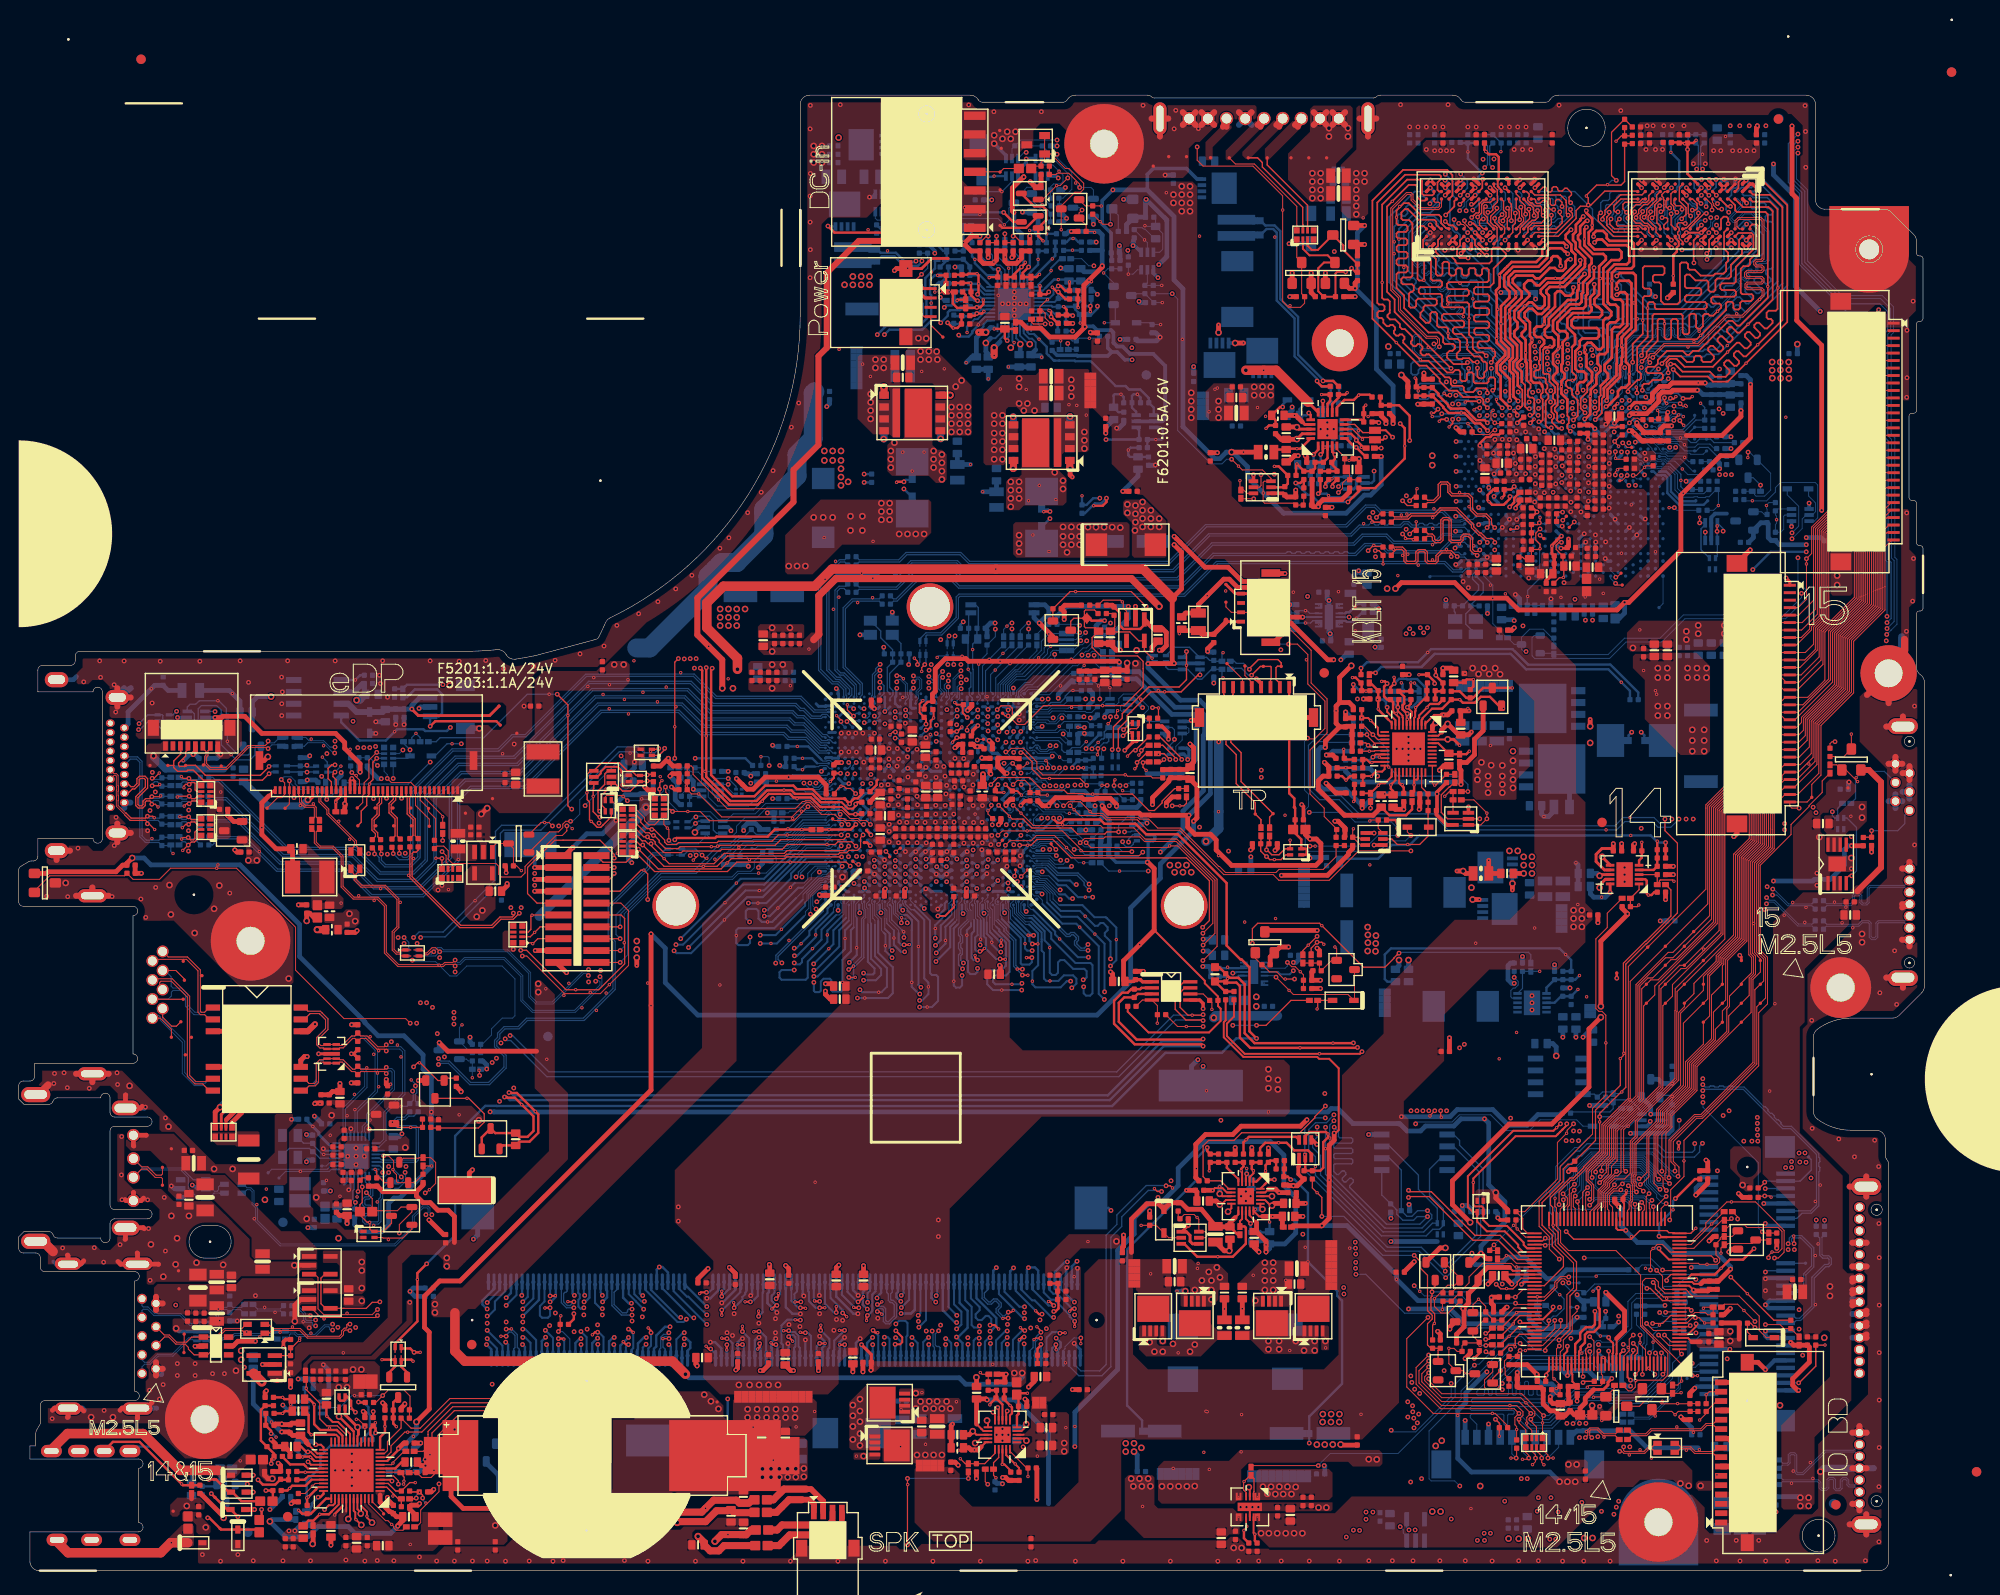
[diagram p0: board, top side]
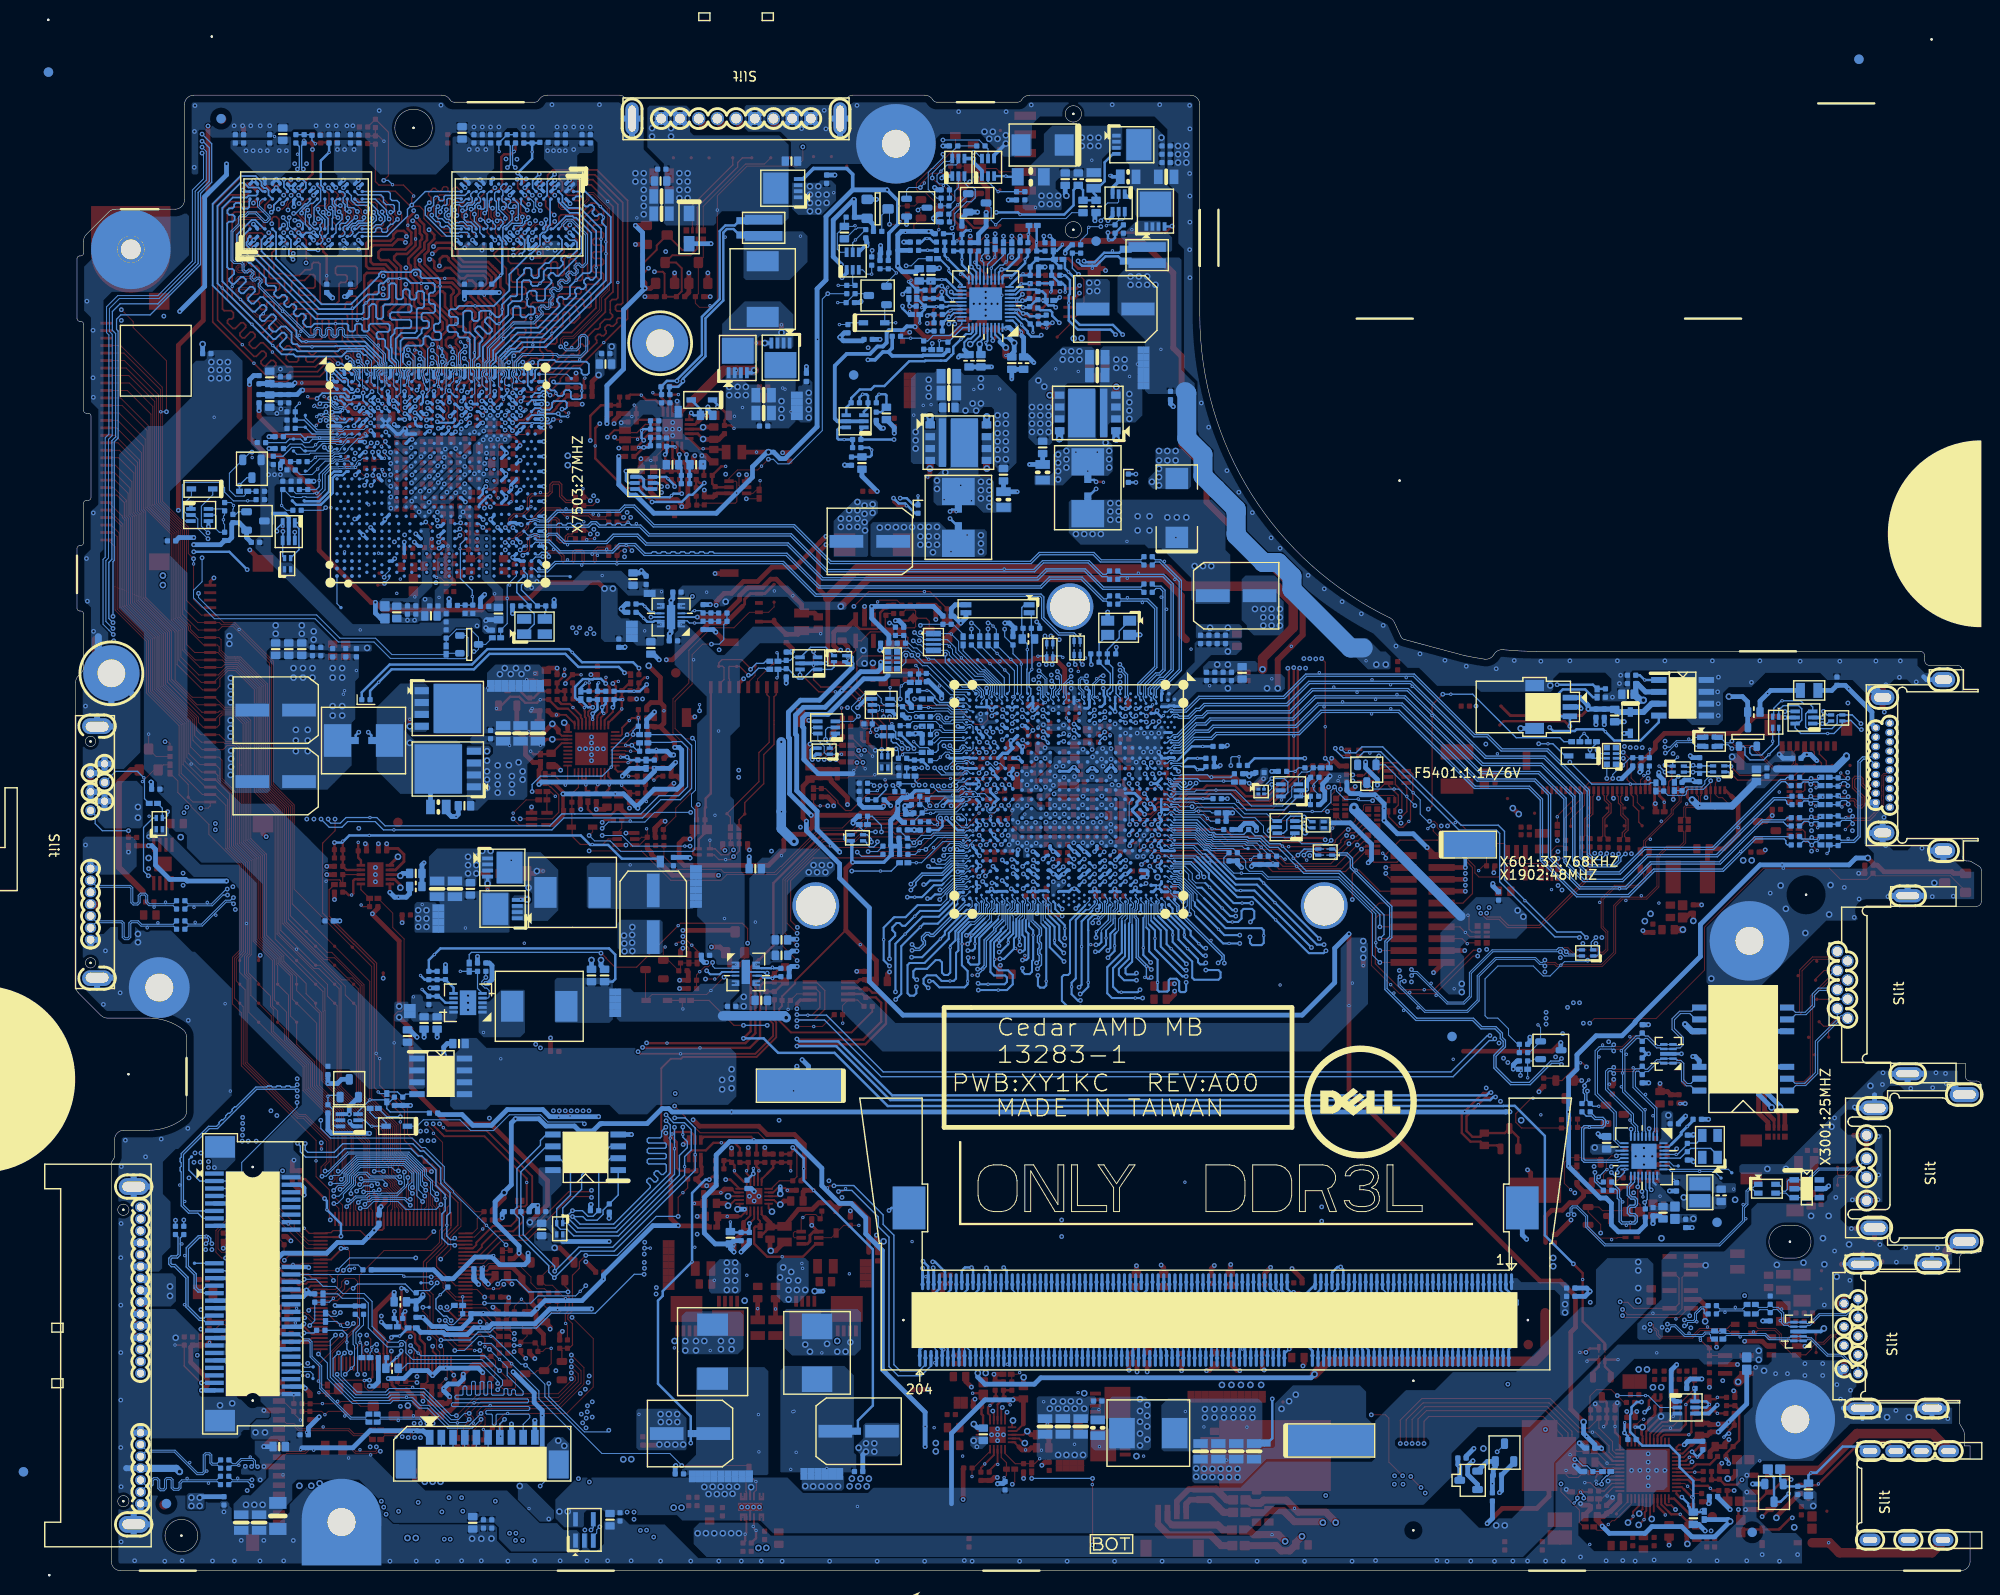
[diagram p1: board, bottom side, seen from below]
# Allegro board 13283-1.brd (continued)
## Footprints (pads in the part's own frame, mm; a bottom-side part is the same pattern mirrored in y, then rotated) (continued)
AFTE14P-75
  round 0.356 smd: 1(0,0)
ARES2H16
  rect 0.356x0.66 smd: 1(-0.325,-0.599) 2(0.325,-0.599) 3(0.325,0.599) 4(-0.325,0.599)
ARES2H18
  rect 0.356x0.66 smd: 1(-0.325,-0.599) 2(0.325,-0.599) 3(0.325,0.599) 4(-0.325,0.599)
ARES8-CN24-MUH20
  rect 0.61x0.66 smd: 1(-0.9,-0.486) 4(0.9,-0.486) 5(0.9,0.486) 8(-0.9,0.486)
  rect 0.305x0.66 smd: 2(-0.25,-0.486) 3(0.25,-0.486) 6(0.25,0.486) 7(-0.25,0.486)
ARES8-CN24H20
  rect 0.61x0.66 smd: 1(-0.9,-0.486) 4(0.9,-0.486) 5(0.9,0.486) 8(-0.9,0.486)
  rect 0.305x0.66 smd: 2(-0.25,-0.486) 3(0.25,-0.486) 6(0.25,0.486) 7(-0.25,0.486)
ARES8-CN24H22
  rect 0.61x0.66 smd: 1(-0.9,-0.486) 4(0.9,-0.486) 5(0.9,0.486) 8(-0.9,0.486)
  rect 0.305x0.66 smd: 2(-0.25,-0.486) 3(0.25,-0.486) 6(0.25,0.486) 7(-0.25,0.486)
BGA96D0914H48
  round 0.356 smd: A1(-3.2,6) A2(-2.4,6) A3(-1.6,6) A7(1.6,6) A8(2.4,6) A9(3.2,6) B1(-3.2,5.2) B2(-2.4,5.2) B3(-1.6,5.2) B7(1.6,5.2) B8(2.4,5.2) B9(3.2,5.2) C1(-3.2,4.4) C2(-2.4,4.4) C3(-1.6,4.4) C7(1.6,4.4) C8(2.4,4.4) C9(3.2,4.4) D1(-3.2,3.6) D2(-2.4,3.6) D3(-1.6,3.6) D7(1.6,3.6) D8(2.4,3.6) D9(3.2,3.6) E1(-3.2,2.8) E2(-2.4,2.8) E3(-1.6,2.8) E7(1.6,2.8) E8(2.4,2.8) E9(3.2,2.8) F1(-3.2,2) F2(-2.4,2) F3(-1.6,2) F7(1.6,2) F8(2.4,2) F9(3.2,2) G1(-3.2,1.2) G2(-2.4,1.2) G3(-1.6,1.2) G7(1.6,1.2) G8(2.4,1.2) G9(3.2,1.2) H1(-3.2,0.4) H2(-2.4,0.4) H3(-1.6,0.4) H7(1.6,0.4) H8(2.4,0.4) H9(3.2,0.4) J1(-3.2,-0.4) J2(-2.4,-0.4) J3(-1.6,-0.4) J7(1.6,-0.4) J8(2.4,-0.4) J9(3.2,-0.4) K1(-3.2,-1.2) K2(-2.4,-1.2) K3(-1.6,-1.2) K7(1.6,-1.2) K8(2.4,-1.2) K9(3.2,-1.2) L1(-3.2,-2) L2(-2.4,-2) L3(-1.6,-2) L7(1.6,-2) L8(2.4,-2) L9(3.2,-2) M1(-3.2,-2.8) M2(-2.4,-2.8) M3(-1.6,-2.8) M7(1.6,-2.8) M8(2.4,-2.8) M9(3.2,-2.8) N1(-3.2,-3.6) N2(-2.4,-3.6) N3(-1.6,-3.6) N7(1.6,-3.6) N8(2.4,-3.6) N9(3.2,-3.6) P1(-3.2,-4.4) P2(-2.4,-4.4) P3(-1.6,-4.4) P7(1.6,-4.4) P8(2.4,-4.4) P9(3.2,-4.4) R1(-3.2,-5.2) R2(-2.4,-5.2) R3(-1.6,-5.2) R7(1.6,-5.2) R8(2.4,-5.2) R9(3.2,-5.2) T1(-3.2,-6) T2(-2.4,-6) T3(-1.6,-6) T7(1.6,-6) T8(2.4,-6) T9(3.2,-6)
BGA631M23H82
  round 0.406 smd: A3(-10,10.8) A5(-9.2,10.8) A28(9.2,10.8) A30(10,10.8) A32(10.8,10.8) AH1(-10.8,-9.2) AH3(-10,-9.2) AH5(-9.2,-9.2) AH28(9.2,-9.2) AH30(10,-9.2) AH32(10.8,-9.2) AK1(-10.8,-10) AK3(-10,-10) AK5(-9.2,-10) AK28(9.2,-10) AK30(10,-10) AK32(10.8,-10) AM1(-10.8,-10.8) AM3(-10,-10.8) AM5(-9.2,-10.8) AM28(9.2,-10.8) AM30(10,-10.8) AM32(10.8,-10.8) C1(-10.8,10) C3(-10,10) C5(-9.2,10) C28(9.2,10) C30(10,10) C32(10.8,10) E1(-10.8,9.2) E3(-10,9.2) E5(-9.2,9.2) E28(9.2,9.2) E30(10,9.2) E32(10.8,9.2)
  round 0.356 smd: A7(-7.6,10.8) A9(-6,10.8) A11(-4.4,10.8) A13(-2.8,10.8) A15(-1.2,10.8) A17(0.4,10.8) A19(2,10.8) A21(3.6,10.8) A23(5.2,10.8) A25(6.8,10.8) A27(8.4,10.8) AA1(-10.8,-3.6) AA3(-10,-3.6) AA5(-9.2,-3.6) AA6(-8.4,-3.6) AA11(-4.4,-3.4) AA12(-3.4,-3.4) AA13(-2.4,-3.4) AA15(-1.4,-3.4) AA16(-0.4,-3.4) AA17(0.4,-3.4) AA18(1.4,-3.4) AA20(2.4,-3.4) AA21(3.4,-3.4) AA22(4.4,-3.4) AA27(8.4,-3.6) AA29(9.6,-3.6) AA31(10.4,-3.6) AB2(-10.4,-4.4) AB4(-9.6,-4.4) AB6(-8.4,-4.4) AB7(-7.6,-4.2) AB8(-6.8,-4.2) AB9(-6,-4.2) AB10(-5.2,-4.2) AB11(-4.4,-4.4) AB12(-3.4,-4.4) AB13(-2.4,-4.4) AB15(-1.4,-4.4) AB16(-0.4,-4.4) AB17(0.4,-4.4) AB18(1.4,-4.4) AB20(2.4,-4.4) AB21(3.4,-4.4) AB22(4.4,-4.4) AB23(5.2,-4.2) AB24(6,-4.2) AB25(6.8,-4.2) AB26(7.6,-4.2) AB27(8.4,-4.4) AB28(9.2,-4.4) AB30(10,-4.4) AB32(10.8,-4.4) AC1(-10.8,-5.2) AC3(-10,-5.2) AC5(-9.2,-5.2) AC6(-8.4,-5.2) AC7(-7.6,-5.2) AC8(-6.8,-5.2) AC9(-6,-5.2) AC10(-5.2,-5.2) AC11(-4.2,-5.2) AC13(-3,-5.2) AC14(-1.8,-5.2) AC16(-0.6,-5.2) AC17(0.6,-5.2) AC19(1.8,-5.2) AC20(3,-5.2) AC22(4.2,-5.2) AC23(5.2,-5.2) AC24(6,-5.2) AC25(6.8,-5.2) AC26(7.6,-5.2) AC27(8.4,-5.2) AC29(9.6,-5.2) AC31(10.4,-5.2) AD2(-10.4,-6) AD4(-9.6,-6) AD6(-8.4,-6) AD7(-7.6,-6) AD8(-6.8,-6) AD9(-6,-6) AD10(-5.2,-6) AD11(-4.2,-6) AD13(-3,-6) AD14(-1.8,-6) AD16(-0.6,-6) AD17(0.6,-6) AD19(1.8,-6) AD20(3,-6) AD22(4.2,-6) AD23(5.2,-6) AD24(6,-6) AD25(6.8,-6) AD26(7.6,-6) AD27(8.4,-6) AD28(9.2,-6) AD30(10,-6) AD32(10.8,-6) AE1(-10.8,-6.8) AE3(-10,-6.8) AE5(-9.2,-6.8) AE6(-8.4,-6.8) AE7(-7.6,-6.8) AE8(-6.8,-6.8) AE9(-6,-6.8) AE10(-5.2,-6.8) AE11(-4.2,-6.8) AE13(-3,-6.8) AE14(-1.8,-6.8) AE16(-0.6,-6.8) AE17(0.6,-6.8) AE19(1.8,-6.8) AE20(3,-6.8) AE22(4.2,-6.8) AE23(5.2,-6.8) AE24(6,-6.8) AE25(6.8,-6.8) AE26(7.6,-6.8) AE27(8.4,-6.8) AE29(9.6,-6.8) AE31(10.4,-6.8) AF2(-10.4,-7.6) AF4(-9.6,-7.6) AF6(-8.4,-7.6) AF7(-7.6,-7.6) AF8(-6.8,-7.6) AF9(-6,-7.6) AF10(-5.2,-7.6) AF11(-4.2,-7.6) AF13(-3,-7.6) AF14(-1.8,-7.6) AF16(-0.6,-7.6) AF17(0.6,-7.6) AF19(1.8,-7.6) AF20(3,-7.6) AF22(4.2,-7.6) AF23(5.2,-7.6) AF24(6,-7.6) AF25(6.8,-7.6) AF26(7.6,-7.6) AF27(8.4,-7.6) AF28(9.2,-7.6) AF30(10,-7.6) AF32(10.8,-7.6) AG1(-10.8,-8.4) AG3(-10,-8.4) AG5(-9.2,-8.4) AG6(-8.4,-8.4) AG7(-7.6,-8.4) AG8(-6.8,-8.4) AG9(-6,-8.4) AG10(-5.2,-8.4) AG11(-4.4,-8.4) AG12(-3.6,-8.4) AG13(-2.8,-8.4) AG14(-2,-8.4) AG15(-1.2,-8.4) AG16(-0.4,-8.4) AG17(0.4,-8.4) AG18(1.2,-8.4) AG19(2,-8.4) AG20(2.8,-8.4) AG21(3.6,-8.4) AG22(4.4,-8.4) AG23(5.2,-8.4) AG24(6,-8.4) AG25(6.8,-8.4) AG26(7.6,-8.4) AG27(8.4,-8.4) AG29(9.6,-8.4) AG31(10.4,-8.4) AH6(-8.4,-9.2) AH8(-6.8,-9.2) AH10(-5.2,-9.2) AH12(-3.6,-9.2) AH14(-2,-9.2) AH16(-0.4,-9.2) AH18(1.2,-9.2) AH20(2.8,-9.2) AH22(4.4,-9.2) AH24(6,-9.2) AH26(7.6,-9.2) AJ7(-7.6,-9.6) AJ9(-6,-9.6) AJ11(-4.4,-9.6) AJ13(-2.8,-9.6) AJ15(-1.2,-9.6) AJ17(0.4,-9.6) AJ19(2,-9.6) AJ21(3.6,-9.6) AJ23(5.2,-9.6) AJ25(6.8,-9.6) AJ27(8.4,-9.6) AK6(-8.4,-10) AK8(-6.8,-10) AK10(-5.2,-10) AK12(-3.6,-10) AK14(-2,-10) AK16(-0.4,-10) AK18(1.2,-10) AK20(2.8,-10) AK22(4.4,-10) AK24(6,-10) AK26(7.6,-10) AL7(-7.6,-10.4) AL9(-6,-10.4) AL11(-4.4,-10.4) AL13(-2.8,-10.4) AL15(-1.2,-10.4) AL17(0.4,-10.4) AL19(2,-10.4) AL21(3.6,-10.4) AL23(5.2,-10.4) AL25(6.8,-10.4) AL27(8.4,-10.4) AM6(-8.4,-10.8) AM8(-6.8,-10.8) AM10(-5.2,-10.8) AM12(-3.6,-10.8) AM14(-2,-10.8) AM16(-0.4,-10.8) AM18(1.2,-10.8) AM20(2.8,-10.8) AM22(4.4,-10.8) AM24(6,-10.8) AM26(7.6,-10.8) B6(-8.4,10.4) B8(-6.8,10.4) B10(-5.2,10.4) B12(-3.6,10.4) B14(-2,10.4) B16(-0.4,10.4) B18(1.2,10.4) B20(2.8,10.4) B22(4.4,10.4) B24(6,10.4) B26(7.6,10.4) C7(-7.6,10) C9(-6,10) C11(-4.4,10) C13(-2.8,10) C15(-1.2,10) C17(0.4,10) C19(2,10) C21(3.6,10) C23(5.2,10) C25(6.8,10) C27(8.4,10) D6(-8.4,9.6) D8(-6.8,9.6) D10(-5.2,9.6) D12(-3.6,9.6) D14(-2,9.6) D16(-0.4,9.6) D18(1.2,9.6) D20(2.8,9.6) D22(4.4,9.6) D24(6,9.6) D26(7.6,9.6) E7(-7.6,9.2) E9(-6,9.2) E11(-4.4,9.2) E13(-2.8,9.2) E15(-1.2,9.2) E17(0.4,9.2) E19(2,9.2) E21(3.6,9.2) E23(5.2,9.2) E25(6.8,9.2) E27(8.4,9.2) F2(-10.4,8.4) F4(-9.6,8.4) F6(-8.4,8.4) F7(-7.6,8.4) F8(-6.8,8.4) F9(-6,8.4) F10(-5.2,8.4) F11(-4.4,8.4) F12(-3.6,8.4) F13(-2.8,8.4) F14(-2,8.4) F15(-1.2,8.4) F16(-0.4,8.4) F17(0.4,8.4) F18(1.2,8.4) F19(2,8.4) F20(2.8,8.4) F21(3.6,8.4) F22(4.4,8.4) F23(5.2,8.4) F24(6,8.4) F25(6.8,8.4) F26(7.6,8.4) F27(8.4,8.4) F28(9.2,8.4) F30(10,8.4) F32(10.8,8.4) G1(-10.8,7.6) G3(-10,7.6) G5(-9.2,7.6) G6(-8.4,7.6) G7(-7.6,7.6) G8(-6.8,7.6) G9(-6,7.6) G10(-5.2,7.6) G11(-4.2,7.6) G13(-3,7.6) G14(-1.8,7.6) G16(-0.6,7.6) G17(0.6,7.6) G19(1.8,7.6) G20(3,7.6) G22(4.2,7.6) G23(5.2,7.6) G24(6,7.6) G25(6.8,7.6) G26(7.6,7.6) G27(8.4,7.6) G29(9.6,7.6) G31(10.4,7.6) H2(-10.4,6.8) H4(-9.6,6.8) H6(-8.4,6.8) H7(-7.6,6.8) H8(-6.8,6.8) H9(-6,6.8) H10(-5.2,6.8) H11(-4.2,6.8) H13(-3,6.8) H14(-1.8,6.8) H16(-0.6,6.8) H17(0.6,6.8) H19(1.8,6.8) H20(3,6.8) H22(4.2,6.8) H23(5.2,6.8) H24(6,6.8) H25(6.8,6.8) H26(7.6,6.8) H27(8.4,6.8) H28(9.2,6.8) H30(10,6.8) H32(10.8,6.8) J1(-10.8,6) J3(-10,6) J5(-9.2,6) J6(-8.4,6) J7(-7.6,6) J8(-6.8,6) J9(-6,6) J10(-5.2,6) J11(-4.2,6) J13(-3,6) J14(-1.8,6) J16(-0.6,6) J17(0.6,6) J19(1.8,6) J20(3,6) J22(4.2,6) J23(5.2,6) J24(6,6) J25(6.8,6) J26(7.6,6) J27(8.4,6) J29(9.6,6) J31(10.4,6) K2(-10.4,5.2) K4(-9.6,5.2) K6(-8.4,5.2) K7(-7.6,5.2) K8(-6.8,5.2) K9(-6,5.2) K10(-5.2,5.2) K11(-4.2,5.2) K13(-3,5.2) K14(-1.8,5.2) K16(-0.6,5.2) K17(0.6,5.2) K19(1.8,5.2) K20(3,5.2) K22(4.2,5.2) K23(5.2,5.2) K24(6,5.2) K25(6.8,5.2) K26(7.6,5.2) K27(8.4,5.2) K28(9.2,5.2) K30(10,5.2) K32(10.8,5.2) L1(-10.8,4.4) L3(-10,4.4) L5(-9.2,4.4) L6(-8.4,4.4) L7(-7.6,4.2) L8(-6.8,4.2) L9(-6,4.2) L10(-5.2,4.2) L11(-4.4,4.4) L12(-3.4,4.4) L13(-2.4,4.4) L15(-1.4,4.4) L16(-0.4,4.4) L17(0.4,4.4) L18(1.4,4.4) L20(2.4,4.4) L21(3.4,4.4) L22(4.4,4.4) L23(5.2,4.2) L24(6,4.2) L25(6.8,4.2) L26(7.6,4.2) L27(8.4,4.4) L29(9.6,4.4) L31(10.4,4.4) M2(-10.4,3.6) M4(-9.6,3.6) M6(-8.4,3.6) M11(-4.4,3.4) M12(-3.4,3.4) M13(-2.4,3.4) M15(-1.4,3.4) M16(-0.4,3.4) M17(0.4,3.4) M18(1.4,3.4) M20(2.4,3.4) M21(3.4,3.4) M22(4.4,3.4) M27(8.4,3.6) M28(9.2,3.6) M30(10,3.6) M32(10.8,3.6) N1(-10.8,2.8) N3(-10,2.8) N5(-9.2,2.8) N6(-8.4,2.8) N7(-7.6,3) N8(-6.8,3) N9(-6,3) N10(-5.2,3) N11(-4.4,2.4) N12(-3.4,2.4) N13(-2.4,2.4) N15(-1.4,2.4) N16(-0.4,2.4) N17(0.4,2.4) N18(1.4,2.4) N20(2.4,2.4) N21(3.4,2.4) N22(4.4,2.4) N23(5.2,3) N24(6,3) N25(6.8,3) N26(7.6,3) N27(8.4,2.8) N29(9.6,2.8) N31(10.4,2.8) P2(-10.4,2) P4(-9.6,2) P6(-8.4,2) P7(-7.6,1.8) P8(-6.8,1.8) P9(-6,1.8) P10(-5.2,1.8) P23(5.2,1.8) P24(6,1.8) P25(6.8,1.8) P26(7.6,1.8) P27(8.4,2) P28(9.2,2) P30(10,2) P32(10.8,2) R1(-10.8,1.2) R3(-10,1.2) R5(-9.2,1.2) R6(-8.4,1.2) R11(-4.4,1.4) R12(-3.4,1.4) R13(-2.4,1.4) R15(-1.4,1.4) R16(-0.4,1.4) R17(0.4,1.4) R18(1.4,1.4) R20(2.4,1.4) R21(3.4,1.4) R22(4.4,1.4) R27(8.4,1.2) R29(9.6,1.2) R31(10.4,1.2) T2(-10.4,0.4) T4(-9.6,0.4) T6(-8.4,0.4) T7(-7.6,0.6) T8(-6.8,0.6) T9(-6,0.6) T10(-5.2,0.6) T11(-4.4,0.4) T12(-3.4,0.4) T13(-2.4,0.4) T15(-1.4,0.4) T16(-0.4,0.4) T17(0.4,0.4) T18(1.4,0.4) T20(2.4,0.4) T21(3.4,0.4) T22(4.4,0.4) T23(5.2,0.6) T24(6,0.6) T25(6.8,0.6) T26(7.6,0.6) T27(8.4,0.4) T28(9.2,0.4) T30(10,0.4) T32(10.8,0.4) U1(-10.8,-0.4) U3(-10,-0.4) U5(-9.2,-0.4) U6(-8.4,-0.4) U7(-7.6,-0.6) U8(-6.8,-0.6) U9(-6,-0.6) U10(-5.2,-0.6) U11(-4.4,-0.4) U12(-3.4,-0.4) U13(-2.4,-0.4) U15(-1.4,-0.4) U16(-0.4,-0.4) U17(0.4,-0.4) U18(1.4,-0.4) U20(2.4,-0.4) U21(3.4,-0.4) U22(4.4,-0.4) U23(5.2,-0.6) U24(6,-0.6) U25(6.8,-0.6) U26(7.6,-0.6) U27(8.4,-0.4) U29(9.6,-0.4) U31(10.4,-0.4) V2(-10.4,-1.2) V4(-9.6,-1.2) V6(-8.4,-1.2) V11(-4.4,-1.4) V12(-3.4,-1.4) V13(-2.4,-1.4) V15(-1.4,-1.4) V16(-0.4,-1.4) V17(0.4,-1.4) V18(1.4,-1.4) V20(2.4,-1.4) V21(3.4,-1.4) V22(4.4,-1.4) V27(8.4,-1.2) V28(9.2,-1.2) V30(10,-1.2) V32(10.8,-1.2) W1(-10.8,-2) W3(-10,-2) W5(-9.2,-2) W6(-8.4,-2) W7(-7.6,-1.8) W8(-6.8,-1.8) W9(-6,-1.8) W10(-5.2,-1.8) W23(5.2,-1.8) W24(6,-1.8) W25(6.8,-1.8) W26(7.6,-1.8) W27(8.4,-2) W29(9.6,-2) W31(10.4,-2) Y2(-10.4,-2.8) Y4(-9.6,-2.8) Y6(-8.4,-2.8) Y7(-7.6,-3) Y8(-6.8,-3) Y9(-6,-3) Y10(-5.2,-3) Y11(-4.4,-2.4) Y12(-3.4,-2.4) Y13(-2.4,-2.4) Y15(-1.4,-2.4) Y16(-0.4,-2.4) Y17(0.4,-2.4) Y18(1.4,-2.4) Y20(2.4,-2.4) Y21(3.4,-2.4) Y22(4.4,-2.4) Y23(5.2,-3) Y24(6,-3) Y25(6.8,-3) Y26(7.6,-3) Y27(8.4,-2.8) Y28(9.2,-2.8) Y30(10,-2.8) Y32(10.8,-2.8)
BGA769M24D5H78
  round 0.4 smd: A2(-10.7,11.3) A3(-9.95,11.3) A39(9.95,11.3) A40(10.7,11.3) AA4(-9.2,0) AA5(-8.4,0) AA7(-7.6,0) AA8(-6.8,0) AA10(-6,0) AA11(-5,0) AA13(-4,0) AA15(-3,0) AA17(-2,0) AA19(-1,0) AA21(0,0) AA23(1,0) AA25(2,0) AA27(3,0) AA29(4,0) AA31(5,0) AA32(6,0) AA34(6.8,0) AA35(7.6,0) AA37(8.4,0) AA38(9.2,0) AC4(-9.2,-1.1) AC5(-8.4,-1.1) AC7(-7.6,-1.1) AC8(-6.8,-1.1) AC10(-6,-1.1) AC11(-5,-1) AC13(-4,-1) AC15(-3,-1) AC17(-2,-1) AC19(-1,-1) AC21(0,-1) AC23(1,-1) AC25(2,-1) AC27(3,-1) AC29(4,-1) AC31(5,-1) AC32(6,-1.1) AC34(6.8,-1.1) AC35(7.6,-1.1) AC37(8.4,-1.1) AC38(9.2,-1.1) AE4(-9.2,-2.2) AE5(-8.4,-2.2) AE7(-7.6,-2.2) AE8(-6.8,-2.2) AE10(-6,-2.2) AE11(-5,-2) AE13(-4,-2) AE15(-3,-2) AE17(-2,-2) AE19(-1,-2) AE21(0,-2) AE23(1,-2) AE25(2,-2) AE27(3,-2) AE29(4,-2) AE31(5,-2) AE32(6,-2.2) AE34(6.8,-2.2) AE35(7.6,-2.2) AE37(8.4,-2.2) AE38(9.2,-2.2) AG4(-9.2,-3.3) AG5(-8.4,-3.3) AG7(-7.6,-3.3) AG8(-6.8,-3.3) AG10(-6,-3.3) AG11(-5,-3) AG13(-4,-3) AG15(-3,-3) AG17(-2,-3) AG19(-1,-3) AG21(0,-3) AG23(1,-3) AG25(2,-3) AG27(3,-3) AG29(4,-3) AG31(5,-3) AG32(6,-3.3) AG34(6.8,-3.3) AG35(7.6,-3.3) AG37(8.4,-3.3) AG38(9.2,-3.3) AJ4(-9.2,-4.4) AJ5(-8.4,-4.4) AJ7(-7.6,-4.4) AJ8(-6.8,-4.4) AJ10(-6,-4.4) AJ11(-5,-4) AJ13(-4,-4) AJ15(-3,-4) AJ17(-2,-4) AJ19(-1,-4) AJ21(0,-4) AJ23(1,-4) AJ25(2,-4) AJ27(3,-4) AJ29(4,-4) AJ31(5,-4) AJ32(6,-4.4) AJ34(6.8,-4.4) AJ35(7.6,-4.4) AJ37(8.4,-4.4) AJ38(9.2,-4.4) AL4(-9.2,-5.5) AL5(-8.4,-5.5) AL7(-7.6,-5.5) AL8(-6.8,-5.5) AL10(-6,-5.5) AL11(-5,-5) AL13(-4,-5) AL15(-3,-5) AL17(-2,-5) AL19(-1,-5) AL21(0,-5) AL23(1,-5) AL25(2,-5) AL27(3,-5) AL29(4,-5) AL31(5,-5) AL32(6,-5.5) AL34(6.8,-5.5) AL35(7.6,-5.5) AL37(8.4,-5.5) AL38(9.2,-5.5) AM11(-5.5,-6) AM13(-4.4,-6) AM15(-3.3,-6) AM17(-2.2,-6) AM19(-1.1,-6) AM21(0,-6) AM23(1.1,-6) AM25(2.2,-6) AM27(3.3,-6) AM29(4.4,-6) AM31(5.5,-6) AN4(-9.2,-6.6) AN5(-8.4,-6.6) AN7(-7.6,-6.6) AN8(-6.8,-6.6) AN34(6.8,-6.6) AN35(7.6,-6.6) AN37(8.4,-6.6) AN38(9.2,-6.6) AP11(-5.5,-6.8) AP13(-4.4,-6.8) AP15(-3.3,-6.8) AP17(-2.2,-6.8) AP19(-1.1,-6.8) AP21(0,-6.8) AP23(1.1,-6.8) AP25(2.2,-6.8) AP27(3.3,-6.8) AP29(4.4,-6.8) AP31(5.5,-6.8) AR4(-9.2,-7.7) AR5(-8.4,-7.7) AR7(-7.6,-7.7) AR11(-5.5,-7.6) AR13(-4.4,-7.6) AR15(-3.3,-7.6) AR17(-2.2,-7.6) AR19(-1.1,-7.6) AR21(0,-7.6) AR23(1.1,-7.6) AR25(2.2,-7.6) AR27(3.3,-7.6) AR29(4.4,-7.6) AR31(5.5,-7.6) AR35(7.6,-7.7) AR37(8.4,-7.7) AR38(9.2,-7.7) AU4(-9.2,-8.8) AU7(-7.7,-8.4) AU9(-6.6,-8.4) AU11(-5.5,-8.4) AU13(-4.4,-8.4) AU15(-3.3,-8.4) AU17(-2.2,-8.4) AU19(-1.1,-8.4) AU21(0,-8.4) AU23(1.1,-8.4) AU25(2.2,-8.4) AU27(3.3,-8.4) AU29(4.4,-8.4) AU31(5.5,-8.4) AU33(6.6,-8.4) AU35(7.7,-8.4) AU38(9.2,-8.8) AV7(-7.7,-9.2) AV9(-6.6,-9.2) AV11(-5.5,-9.2) AV13(-4.4,-9.2) AV15(-3.3,-9.2) AV17(-2.2,-9.2) AV19(-1.1,-9.2) AV21(0,-9.2) AV23(1.1,-9.2) AV25(2.2,-9.2) AV27(3.3,-9.2) AV29(4.4,-9.2) AV31(5.5,-9.2) AV33(6.6,-9.2) AV35(7.7,-9.2) AW1(-11.3,-9.95) AW41(11.3,-9.95) AY1(-11.3,-10.7) AY2(-10.6,-10.6) AY40(10.6,-10.6) AY41(11.3,-10.7) B1(-11.3,10.7) B2(-10.6,10.6) B40(10.6,10.6) B41(11.3,10.7) BA2(-10.7,-11.3) BA3(-9.95,-11.3) BA39(9.95,-11.3) BA40(10.7,-11.3) C1(-11.3,9.95) C41(11.3,9.95) D7(-7.7,9.2) D9(-6.6,9.2) D11(-5.5,9.2) D13(-4.4,9.2) D15(-3.3,9.2) D17(-2.2,9.2) D19(-1.1,9.2) D21(0,9.2) D23(1.1,9.2) D25(2.2,9.2) D27(3.3,9.2) D29(4.4,9.2) D31(5.5,9.2) D33(6.6,9.2) D35(7.7,9.2) E4(-9.2,8.8) E7(-7.7,8.4) E9(-6.6,8.4) E11(-5.5,8.4) E13(-4.4,8.4) E15(-3.3,8.4) E17(-2.2,8.4) E19(-1.1,8.4) E21(0,8.4) E23(1.1,8.4) E25(2.2,8.4) E27(3.3,8.4) E29(4.4,8.4) E31(5.5,8.4) E33(6.6,8.4) E35(7.7,8.4) E38(9.2,8.8) G4(-9.2,7.7) G5(-8.4,7.7) G7(-7.6,7.7) G11(-5.5,7.6) G13(-4.4,7.6) G15(-3.3,7.6) G17(-2.2,7.6) G19(-1.1,7.6) G21(0,7.6) G23(1.1,7.6) G25(2.2,7.6) G27(3.3,7.6) G29(4.4,7.6) G31(5.5,7.6) G35(7.6,7.7) G37(8.4,7.7) G38(9.2,7.7) H11(-5.5,6.8) H13(-4.4,6.8) H15(-3.3,6.8) H17(-2.2,6.8) H19(-1.1,6.8) H21(0,6.8) H23(1.1,6.8) H25(2.2,6.8) H27(3.3,6.8) H29(4.4,6.8) H31(5.5,6.8) J4(-9.2,6.6) J5(-8.4,6.6) J7(-7.6,6.6) J8(-6.8,6.6) J34(6.8,6.6) J35(7.6,6.6) J37(8.4,6.6) J38(9.2,6.6) K11(-5.5,6) K13(-4.4,6) K15(-3.3,6) K17(-2.2,6) K19(-1.1,6) K21(0,6) K23(1.1,6) K25(2.2,6) K27(3.3,6) K29(4.4,6) K31(5.5,6) L4(-9.2,5.5) L5(-8.4,5.5) L7(-7.6,5.5) L8(-6.8,5.5) L10(-6,5.5) L11(-5,5) L13(-4,5) L15(-3,5) L17(-2,5) L19(-1,5) L21(0,5) L23(1,5) L25(2,5) L27(3,5) L29(4,5) L31(5,5) L32(6,5.5) L34(6.8,5.5) L35(7.6,5.5) L37(8.4,5.5) L38(9.2,5.5) N4(-9.2,4.4) N5(-8.4,4.4) N7(-7.6,4.4) N8(-6.8,4.4) N10(-6,4.4) N11(-5,4) N13(-4,4) N15(-3,4) N17(-2,4) N19(-1,4) N21(0,4) N23(1,4) N25(2,4) N27(3,4) N29(4,4) N31(5,4) N32(6,4.4) N34(6.8,4.4) N35(7.6,4.4) N37(8.4,4.4) N38(9.2,4.4) R4(-9.2,3.3) R5(-8.4,3.3) R7(-7.6,3.3) R8(-6.8,3.3) R10(-6,3.3) R11(-5,3) R13(-4,3) R15(-3,3) R17(-2,3) R19(-1,3) R21(0,3) R23(1,3) R25(2,3) R27(3,3) R29(4,3) R31(5,3) R32(6,3.3) R34(6.8,3.3) R35(7.6,3.3) R37(8.4,3.3) R38(9.2,3.3) U4(-9.2,2.2) U5(-8.4,2.2) U7(-7.6,2.2) U8(-6.8,2.2) U10(-6,2.2) U11(-5,2) U13(-4,2) U15(-3,2) U17(-2,2) U19(-1,2) U21(0,2) U23(1,2) U25(2,2) U27(3,2) U29(4,2) U31(5,2) U32(6,2.2) U34(6.8,2.2) U35(7.6,2.2) U37(8.4,2.2) U38(9.2,2.2) W4(-9.2,1.1) W5(-8.4,1.1) W7(-7.6,1.1) W8(-6.8,1.1) W10(-6,1.1) W11(-5,1) W13(-4,1) W15(-3,1) W17(-2,1) W19(-1,1) W21(0,1) W23(1,1) W25(2,1) W27(3,1) W29(4,1) W31(5,1) W32(6,1.1) W34(6.8,1.1) W35(7.6,1.1) W37(8.4,1.1) W38(9.2,1.1)
  round 0.3 smd: A4(-9.35,10.95) A5(-8.8,11.3) A6(-8.25,10.95) A7(-7.7,11.3) A8(-7.15,10.95) A9(-6.6,11.3) A10(-6.05,10.95) A11(-5.5,11.3) A12(-4.95,10.95) A13(-4.4,11.3) A14(-3.85,10.95) A15(-3.3,11.3) A16(-2.75,10.95) A17(-2.2,11.3) A18(-1.65,10.95) A19(-1.1,11.3) A20(-0.55,10.95) A21(0,11.3) A22(0.55,10.95) A23(1.1,11.3) A24(1.65,10.95) A25(2.2,11.3) A26(2.75,10.95) A27(3.3,11.3) A28(3.85,10.95) A29(4.4,11.3) A30(4.95,10.95) A31(5.5,11.3) A32(6.05,10.95) A33(6.6,11.3) A34(7.15,10.95) A35(7.7,11.3) A36(8.25,10.95) A37(8.8,11.3) A38(9.35,10.95) AA1(-11.3,0) AA2(-10.6,0) AA3(-9.9,0) AA39(9.9,0) AA40(10.6,0) AA41(11.3,0) AB1(-10.95,-0.55) AB2(-10.25,-0.55) AB40(10.25,-0.55) AB41(10.95,-0.55) AC1(-11.3,-1.1) AC2(-10.6,-1.1) AC3(-9.9,-1.1) AC39(9.9,-1.1) AC40(10.6,-1.1) AC41(11.3,-1.1) AD1(-10.95,-1.65) AD2(-10.25,-1.65) AD40(10.25,-1.65) AD41(10.95,-1.65) AE1(-11.3,-2.2) AE2(-10.6,-2.2) AE3(-9.9,-2.2) AE39(9.9,-2.2) AE40(10.6,-2.2) AE41(11.3,-2.2) AF1(-10.95,-2.75) AF2(-10.25,-2.75) AF40(10.25,-2.75) AF41(10.95,-2.75) AG1(-11.3,-3.3) AG2(-10.6,-3.3) AG3(-9.9,-3.3) AG39(9.9,-3.3) AG40(10.6,-3.3) AG41(11.3,-3.3) AH1(-10.95,-3.85) AH2(-10.25,-3.85) AH40(10.25,-3.85) AH41(10.95,-3.85) AJ1(-11.3,-4.4) AJ2(-10.6,-4.4) AJ3(-9.9,-4.4) AJ39(9.9,-4.4) AJ40(10.6,-4.4) AJ41(11.3,-4.4) AK1(-10.95,-4.95) AK2(-10.25,-4.95) AK40(10.25,-4.95) AK41(10.95,-4.95) AL1(-11.3,-5.5) AL2(-10.6,-5.5) AL3(-9.9,-5.5) AL39(9.9,-5.5) AL40(10.6,-5.5) AL41(11.3,-5.5) AM1(-10.95,-6.05) AM2(-10.25,-6.05) AM40(10.25,-6.05) AM41(10.95,-6.05) AN1(-11.3,-6.6) AN2(-10.6,-6.6) AN3(-9.9,-6.6) AN39(9.9,-6.6) AN40(10.6,-6.6) AN41(11.3,-6.6) AP1(-10.95,-7.15) AP2(-10.25,-7.15) AP40(10.25,-7.15) AP41(10.95,-7.15) AR1(-11.3,-7.7) AR2(-10.6,-7.7) AR3(-9.9,-7.7) AR39(9.9,-7.7) AR40(10.6,-7.7) AR41(11.3,-7.7) AT1(-10.95,-8.25) AT2(-10.25,-8.25) AT40(10.25,-8.25) AT41(10.95,-8.25) AU1(-11.3,-8.8) AU2(-10.6,-8.8) AU3(-9.9,-8.8) AU39(9.9,-8.8) AU40(10.6,-8.8) AU41(11.3,-8.8) AV1(-10.95,-9.35) AV2(-10.25,-9.35) AV40(10.25,-9.35) AV41(10.95,-9.35) AW2(-10.6,-9.9) AW3(-9.9,-9.9) AW5(-8.8,-9.9) AW7(-7.7,-9.9) AW9(-6.6,-9.9) AW11(-5.5,-9.9) AW13(-4.4,-9.9) AW15(-3.3,-9.9) AW17(-2.2,-9.9) AW19(-1.1,-9.9) AW21(0,-9.9) AW23(1.1,-9.9) AW25(2.2,-9.9) AW27(3.3,-9.9) AW29(4.4,-9.9) AW31(5.5,-9.9) AW33(6.6,-9.9) AW35(7.7,-9.9) AW37(8.8,-9.9) AW39(9.9,-9.9) AW40(10.6,-9.9) AY3(-9.9,-10.6) AY4(-9.35,-10.25) AY5(-8.8,-10.6) AY6(-8.25,-10.25) AY7(-7.7,-10.6) AY8(-7.15,-10.25) AY9(-6.6,-10.6) AY10(-6.05,-10.25) AY11(-5.5,-10.6) AY12(-4.95,-10.25) AY13(-4.4,-10.6) AY14(-3.85,-10.25) AY15(-3.3,-10.6) AY16(-2.75,-10.25) AY17(-2.2,-10.6) AY18(-1.65,-10.25) AY19(-1.1,-10.6) AY20(-0.55,-10.25) AY21(0,-10.6) AY22(0.55,-10.25) AY23(1.1,-10.6) AY24(1.65,-10.25) AY25(2.2,-10.6) AY26(2.75,-10.25) AY27(3.3,-10.6) AY28(3.85,-10.25) AY29(4.4,-10.6) AY30(4.95,-10.25) AY31(5.5,-10.6) AY32(6.05,-10.25) AY33(6.6,-10.6) AY34(7.15,-10.25) AY35(7.7,-10.6) AY36(8.25,-10.25) AY37(8.8,-10.6) AY38(9.35,-10.25) AY39(9.9,-10.6) B3(-9.9,10.6) B4(-9.35,10.25) B5(-8.8,10.6) B6(-8.25,10.25) B7(-7.7,10.6) B8(-7.15,10.25) B9(-6.6,10.6) B10(-6.05,10.25) B11(-5.5,10.6) B12(-4.95,10.25) B13(-4.4,10.6) B14(-3.85,10.25) B15(-3.3,10.6) B16(-2.75,10.25) B17(-2.2,10.6) B18(-1.65,10.25) B19(-1.1,10.6) B20(-0.55,10.25) B21(0,10.6) B22(0.55,10.25) B23(1.1,10.6) B24(1.65,10.25) B25(2.2,10.6) B26(2.75,10.25) B27(3.3,10.6) B28(3.85,10.25) B29(4.4,10.6) B30(4.95,10.25) B31(5.5,10.6) B32(6.05,10.25) B33(6.6,10.6) B34(7.15,10.25) B35(7.7,10.6) B36(8.25,10.25) B37(8.8,10.6) B38(9.35,10.25) B39(9.9,10.6) BA4(-9.35,-10.95) BA5(-8.8,-11.3) BA6(-8.25,-10.95) BA7(-7.7,-11.3) BA8(-7.15,-10.95) BA9(-6.6,-11.3) BA10(-6.05,-10.95) BA11(-5.5,-11.3) BA12(-4.95,-10.95) BA13(-4.4,-11.3) BA14(-3.85,-10.95) BA15(-3.3,-11.3) BA16(-2.75,-10.95) BA17(-2.2,-11.3) BA18(-1.65,-10.95) BA19(-1.1,-11.3) BA20(-0.55,-10.95) BA21(0,-11.3) BA22(0.55,-10.95) BA23(1.1,-11.3) BA24(1.65,-10.95) BA25(2.2,-11.3) BA26(2.75,-10.95) BA27(3.3,-11.3) BA28(3.85,-10.95) BA29(4.4,-11.3) BA30(4.95,-10.95) BA31(5.5,-11.3) BA32(6.05,-10.95) BA33(6.6,-11.3) BA34(7.15,-10.95) BA35(7.7,-11.3) BA36(8.25,-10.95) BA37(8.8,-11.3) BA38(9.35,-10.95) C2(-10.6,9.9) C3(-9.9,9.9) C5(-8.8,9.9) C7(-7.7,9.9) C9(-6.6,9.9) C11(-5.5,9.9) C13(-4.4,9.9) C15(-3.3,9.9) C17(-2.2,9.9) C19(-1.1,9.9) C21(0,9.9) C23(1.1,9.9) C25(2.2,9.9) C27(3.3,9.9) C29(4.4,9.9) C31(5.5,9.9) C33(6.6,9.9) C35(7.7,9.9) C37(8.8,9.9) C39(9.9,9.9) C40(10.6,9.9) D1(-10.95,9.35) D2(-10.25,9.35) D40(10.25,9.35) D41(10.95,9.35) E1(-11.3,8.8) E2(-10.6,8.8) E3(-9.9,8.8) E39(9.9,8.8) E40(10.6,8.8) E41(11.3,8.8) F1(-10.95,8.25) F2(-10.25,8.25) F40(10.25,8.25) F41(10.95,8.25) G1(-11.3,7.7) G2(-10.6,7.7) G3(-9.9,7.7) G39(9.9,7.7) G40(10.6,7.7) G41(11.3,7.7) H1(-10.95,7.15) H2(-10.25,7.15) H40(10.25,7.15) H41(10.95,7.15) J1(-11.3,6.6) J2(-10.6,6.6) J3(-9.9,6.6) J39(9.9,6.6) J40(10.6,6.6) J41(11.3,6.6) K1(-10.95,6.05) K2(-10.25,6.05) K40(10.25,6.05) K41(10.95,6.05) L1(-11.3,5.5) L2(-10.6,5.5) L3(-9.9,5.5) L39(9.9,5.5) L40(10.6,5.5) L41(11.3,5.5) M1(-10.95,4.95) M2(-10.25,4.95) M40(10.25,4.95) M41(10.95,4.95) N1(-11.3,4.4) N2(-10.6,4.4) N3(-9.9,4.4) N39(9.9,4.4) N40(10.6,4.4) N41(11.3,4.4) P1(-10.95,3.85) P2(-10.25,3.85) P40(10.25,3.85) P41(10.95,3.85) R1(-11.3,3.3) R2(-10.6,3.3) R3(-9.9,3.3) R39(9.9,3.3) R40(10.6,3.3) R41(11.3,3.3) T1(-10.95,2.75) T2(-10.25,2.75) T40(10.25,2.75) T41(10.95,2.75) U1(-11.3,2.2) U2(-10.6,2.2) U3(-9.9,2.2) U39(9.9,2.2) U40(10.6,2.2) U41(11.3,2.2) V1(-10.95,1.65) V2(-10.25,1.65) V40(10.25,1.65) V41(10.95,1.65) W1(-11.3,1.1) W2(-10.6,1.1) W3(-9.9,1.1) W39(9.9,1.1) W40(10.6,1.1) W41(11.3,1.1) Y1(-10.95,0.55) Y2(-10.25,0.55) Y40(10.25,0.55) Y41(10.95,0.55)
C100HR-10805-L
  round 1.27 hole 0.914: 1(-3.57,6.42) 2(-2.55,7.52) 3(-1.53,6.42) 4(-0.51,7.52) 5(0.51,6.42) 6(1.53,7.52) 7(2.55,6.42) 8(3.57,7.52)
  oval 1.422x3.124 hole 0.711x2.413: 9(-9.525,0) 10(9.525,0)
C144LC-109A7-L-U
  round 1.422 hole 1.016: 1(8,0) 2(6,0) 3(4,0) 4(2,0) 5(0,0) 6(-2,0) 7(-4,0) 8(-6,0) 9(-8,0)
  oval 1.422x3.48 hole 0.711x2.769: 10(11.125,0) 11(-11.125,0)
C185A1-11305-L-U
  round 0.254 hole 1.168 unplated: (-11.84,-0.7) (11.86,-0.7)
  round 1.118 hole 0.762: 1(-4.45,-0.7) 2(-5.45,0.8) 3(-6.45,-0.7) 4(-7.45,0.8) 5(-8.45,-0.7) 6(-9.45,0.8)
  oval 1.702x3.2 hole 1.016x2.413: 14(-13.43,0)
  oval 1.676x3.2 hole 1.016x2.413: 15(13.43,0)
  oval 1.067x1.219 hole 0.813: S1(9.38,-0.7) S2(8.11,-0.7) S3(6.84,-0.7) S4(5.57,-0.7) S5(4.3,-0.7) S6(3.03,-0.7) S7(1.76,-0.7)
C402H20
  custom 0.14x0.14 smd: 1(0,0.445) 2(0,-0.445)
C402H22
  custom 0.14x0.14 smd: 1(0,0.445) 2(0,-0.445)
C603
  custom 0.197x0.197 smd: 1(0,0.66) 2(0,-0.66)
C603H32
  custom 0.197x0.197 smd: 1(0,0.66) 2(0,-0.66)
C603H36
  custom 0.197x0.197 smd: 1(0,0.66) 2(0,-0.66)
C603H38
  custom 0.197x0.197 smd: 1(0,0.66) 2(0,-0.66)
C603H40
  custom 0.197x0.197 smd: 1(0,0.66) 2(0,-0.66)
C805H54
  rect 1.549x0.94 smd: 1(0,0.838) 2(0,-0.838)
C805H56
  rect 1.549x0.94 smd: 1(0,0.838) 2(0,-0.838)
C805H58
  rect 1.549x0.94 smd: 1(0,0.838) 2(0,-0.838)
C1206H71
  rect 1.854x1.27 smd: 1(0,1.397) 2(0,-1.397)
C1808H56
  rect 2.286x1.27 smd: 1(0,2.032) 2(0,-2.032)
CON2O-U
  custom 0.159x0.159 smd: 1(0,0.254) 2(0,-0.254)
CT7343H83
  rect 2.413x2.286 smd: 1(0,3.15) 2(0,-3.15)
D5436AKH97
  rect 2.286x2.032 smd: A(0,2.438) K(0,-2.438)
DFN10G3-G265175H32
  rect 0.305x0.914 smd: 1(1,1.549) 2(0.5,1.549) 3(0,1.549) 4(-0.5,1.549) 5(-1,1.549) 6(-1,-1.549) 7(-0.5,-1.549) 8(0,-1.549) 9(0.5,-1.549) 10(1,-1.549)
  rect 2.642x1.753 smd: 11(0,0)
DFN10G2510H26
  rect 0.305x0.787 smd: 1(1,0.494) 5(-1,0.494) 6(-1,-0.494) 10(1,-0.494)
  rect 0.254x0.787 smd: 2(0.521,0.494) 4(-0.521,0.494) 7(-0.521,-0.494) 9(0.521,-0.494)
  rect 0.025x0.025 smd: 3(0,0.494)
  rect 0.406x1.753 smd: 8(0,-0.494)
FILTER2013-4P-1H44
  rect 0.914x0.559 smd: 1(-0.924,0.473) 2(0.924,0.473) 3(0.924,-0.473) 4(-0.924,-0.473)
FL4S030HT6R300-DT
  rect 0.305x1.295 smd: 1(-11.6,5.65) 2(-10.8,5.65) 3(-10,5.65) 4(-9.2,5.65) 5(-8.4,5.65) 6(-7.6,5.65) 7(-6.8,5.65) 8(-6,5.65) 9(-5.2,5.65) 10(-4.4,5.65) 11(-3.6,5.65) 12(-2.8,5.65) 13(-2,5.65) 14(-1.2,5.65) 15(-0.4,5.65) 16(0.4,5.65) 17(1.2,5.65) 18(2,5.65) 19(2.8,5.65) 20(3.6,5.65) 21(4.4,5.65) 22(5.2,5.65) 23(6,5.65) 24(6.8,5.65) 25(7.6,5.65) 26(8.4,5.65) 27(9.2,5.65) 28(10,5.65) 29(10.8,5.65) 30(11.6,5.65)
  rect 1.803x2.21 smd: 31(-13.94,0) 32(13.94,0)
GAP-CLOSE-PWR-3
  rect 0.66x0.762 smd: 1(-0.305,0) 2(0.305,0)
HOLE197R166
  round 5.004 hole 4.216: 1(0,0)
HOLE256R115
  round 6.502 hole 2.921: 1(0,0)
HOLE335R115
  round 8.509 hole 2.921: 1(0,0)
HT85BE85R29-U-5
  round 8.509 hole 2.921: 1(0,0)
L402H22
  custom 0.14x0.14 smd: 1(0,0.445) 2(0,-0.445)
L402H24
  custom 0.14x0.14 smd: 1(0,0.445) 2(0,-0.445)
L2520-D820H41
  rect 2.261x1.422 smd: 1(0,0.907) 2(0,-0.907)
L7066-1830-UH158
  rect 3.505x2.921 smd: 1(0,2.78) 2(0,-2.78)
L686647H119
  rect 2.159x3.429 smd: 1(-3.111,0) 2(3.111,0)
L736630-MH119
  rect 3.302x2.388 smd: 1(0,2.894) 2(0,-2.894)
L736630H119
  rect 3.251x2.743 smd: 1(0,2.819) 2(0,-2.819)
LQFP128H63
  rect 0.203x1.524 smd: 1(6.2,7.747) 2(5.8,7.747) 3(5.4,7.747) 4(5,7.747) 5(4.6,7.747) 6(4.2,7.747) 7(3.8,7.747) 8(3.4,7.747) 9(3,7.747) 10(2.6,7.747) 11(2.2,7.747) 12(1.8,7.747) 13(1.4,7.747) 14(0.999,7.747) 15(0.599,7.747) 16(0.199,7.747) 17(-0.199,7.747) 18(-0.599,7.747) 19(-0.999,7.747) 20(-1.4,7.747) 21(-1.8,7.747) 22(-2.2,7.747) 23(-2.6,7.747) 24(-3,7.747) 25(-3.4,7.747) 26(-3.8,7.747) 27(-4.2,7.747) 28(-4.6,7.747) 29(-5,7.747) 30(-5.4,7.747) 31(-5.8,7.747) 32(-6.2,7.747) 65(-6.2,-7.747) 66(-5.8,-7.747) 67(-5.4,-7.747) 68(-5,-7.747) 69(-4.6,-7.747) 70(-4.2,-7.747) 71(-3.8,-7.747) 72(-3.4,-7.747) 73(-3,-7.747) 74(-2.6,-7.747) 75(-2.2,-7.747) 76(-1.8,-7.747) 77(-1.4,-7.747) 78(-0.999,-7.747) 79(-0.599,-7.747) 80(-0.199,-7.747) 81(0.199,-7.747) 82(0.599,-7.747) 83(0.999,-7.747) 84(1.4,-7.747) 85(1.8,-7.747) 86(2.2,-7.747) 87(2.6,-7.747) 88(3,-7.747) 89(3.4,-7.747) 90(3.8,-7.747) 91(4.2,-7.747) 92(4.6,-7.747) 93(5,-7.747) 94(5.4,-7.747) 95(5.8,-7.747) 96(6.2,-7.747)
  rect 1.524x0.203 smd: 33(-7.747,6.2) 34(-7.747,5.8) 35(-7.747,5.4) 36(-7.747,5) 37(-7.747,4.6) 38(-7.747,4.2) 39(-7.747,3.8) 40(-7.747,3.4) 41(-7.747,3) 42(-7.747,2.6) 43(-7.747,2.2) 44(-7.747,1.8) 45(-7.747,1.4) 46(-7.747,0.999) 47(-7.747,0.599) 48(-7.747,0.199) 49(-7.747,-0.199) 50(-7.747,-0.599) 51(-7.747,-0.999) 52(-7.747,-1.4) 53(-7.747,-1.8) 54(-7.747,-2.2) 55(-7.747,-2.6) 56(-7.747,-3) 57(-7.747,-3.4) 58(-7.747,-3.8) 59(-7.747,-4.2) 60(-7.747,-4.6) 61(-7.747,-5) 62(-7.747,-5.4) 63(-7.747,-5.8) 64(-7.747,-6.2) 97(7.747,-6.2) 98(7.747,-5.8) 99(7.747,-5.4) 100(7.747,-5) 101(7.747,-4.6) 102(7.747,-4.2) 103(7.747,-3.8) 104(7.747,-3.4) 105(7.747,-3) 106(7.747,-2.6) 107(7.747,-2.2) 108(7.747,-1.8) 109(7.747,-1.4) 110(7.747,-0.999) 111(7.747,-0.599) 112(7.747,-0.199) 113(7.747,0.199) 114(7.747,0.599) 115(7.747,0.999) 116(7.747,1.4) 117(7.747,1.8) 118(7.747,2.2) 119(7.747,2.6) 120(7.747,3) 121(7.747,3.4) 122(7.747,3.8) 123(7.747,4.2) 124(7.747,4.6) 125(7.747,5) 126(7.747,5.4) 127(7.747,5.8) 128(7.747,6.2)
MM60-52B1-KT-R550-DT
  round 0.254 hole 1.6 unplated: (-12.5,0)
  round 0.254 hole 1.016 unplated: (12.5,0)
  rect 0.457x2.007 smd: 1(-11.8,-4.1) 2(-11.4,4.1) 3(-11,-4.1) 4(-10.6,4.1) 5(-10.2,-4.1) 6(-9.8,4.1) 7(-9.4,-4.1) 8(-9,4.1) 9(-8.6,-4.1) 10(-8.2,4.1) 11(-7.8,-4.1) 12(-7.4,4.1) 13(-7,-4.1) 14(-6.6,4.1) 15(-6.2,-4.1) 16(-5.8,4.1) 17(-2.2,-4.1) 18(-1.8,4.1) 19(-1.4,-4.1) 20(-1,4.1) 21(-0.6,-4.1) 22(-0.2,4.1) 23(0.2,-4.1) 24(0.6,4.1) 25(1,-4.1) 26(1.4,4.1) 27(1.8,-4.1) 28(2.2,4.1) 29(2.6,-4.1) 30(3,4.1) 31(3.4,-4.1) 32(3.8,4.1) 33(4.2,-4.1) 34(4.6,4.1) 35(5,-4.1) 36(5.4,4.1) 37(5.8,-4.1) 38(6.2,4.1) 39(6.6,-4.1) 40(7,4.1) 41(7.4,-4.1) 42(7.8,4.1) 43(8.2,-4.1) 44(8.6,4.1) 45(9,-4.1) 46(9.4,4.1) 47(9.8,-4.1) 48(10.2,4.1) 49(10.6,-4.1) 50(11,4.1) 51(11.4,-4.1) 52(11.8,4.1)
  rect 2.311x3.2 smd: 53(-14.65,-3.5) 54(14.65,-3.5)
MSOP8-1G189157H43
  rect 0.356x1.524 smd: 1(-0.975,-2.059) 2(-0.325,-2.059) 3(0.325,-2.059) 4(0.975,-2.059) 5(0.975,2.059) 6(0.325,2.059) 7(-0.325,2.059) 8(-0.975,2.059)
  rect 1.88x1.575 smd: 9(0,0)
MSOP8-1H44
  rect 0.356x1.524 smd: 1(-0.975,-2.055) 2(-0.325,-2.055) 3(0.325,-2.055) 4(0.975,-2.055) 5(0.975,2.055) 6(0.325,2.055) 7(-0.325,2.055) 8(-0.975,2.055)
NTC-402H22-U
  custom 0.14x0.14 smd: 1(0,0.445) 2(0,-0.445)
NTC-603H38
  custom 0.216x0.216 smd: 1(0,0.762) 2(0,-0.762)
OSC-3225-4P-3H36
  rect 1.397x0.914 smd: 1(-1.171,-0.825) 2(1.171,-0.825) 3(1.171,0.825) 4(-1.171,0.825)
OSC-3225-4P-4H36
  rect 1.397x1.067 smd: 1(-1.171,-0.756) 2(1.171,-0.756) 3(1.171,0.756) 4(-1.171,0.756)
PAD-10P-177042
  rect 0.813x1.6 smd: 1(-5.625,2.899) 2(-4.375,2.899) 3(-3.125,2.899) 4(-1.875,2.899) 5(-0.625,2.899) 6(0.625,2.899) 7(1.875,2.899) 8(3.125,2.899) 9(4.375,2.899) 10(5.625,2.899)
  rect 2.134x2.997 smd: 11(-8.175,0) 12(8.175,0)
PAD-20P-127058
  rect 0.737x2.794 smd: 1(-5.715,-2.035) 2(-5.715,2.035) 3(-4.445,-2.035) 4(-4.445,2.035) 5(-3.175,-2.035) 6(-3.175,2.035) 7(-1.905,-2.035) 8(-1.905,2.035) 9(-0.635,-2.035) 10(-0.635,2.035) 11(0.635,-2.035) 12(0.635,2.035) 13(1.905,-2.035) 14(1.905,2.035) 15(3.175,-2.035) 16(3.175,2.035) 17(4.445,-2.035) 18(4.445,2.035) 19(5.715,-2.035) 20(5.715,2.035)
POLYSW-2114H30
  rect 1.6x0.965 smd: 1(0,0.94) 2(0,-0.94)
POLYSW-2114H50
  rect 1.6x0.965 smd: 1(0,0.94) 2(0,-0.94)
POLYSW-4633-UH43
  rect 3.505x1.626 smd: 1(0,1.834) 2(0,-1.834)
POLYSW-4633-UH63
  rect 3.505x1.626 smd: 1(0,1.834) 2(0,-1.834)
PPAK-5PH45
  rect 0.762x1.524 smd: 1(-1.905,-3.81) 2(-0.635,-3.81) 3(0.635,-3.81) 4(1.905,-3.81)
  rect 5.283x5.08 smd: 5(0,0)
  rect 0.025x0.025 smd: 6(0.635,2.032) 7(-0.635,2.032) 8(-1.905,2.032)
PPAK-8P-2H45
  rect 0.406x1.168 smd: 1(-0.975,-2.351) 2(-0.325,-2.351) 3(0.325,-2.351) 4(0.975,-2.351)
  rect 3.404x2.769 smd: 5(0,0)
  rect 0.025x0.025 smd: 6(1.029,0.902) 7(0.013,0.902) 8(-0.991,0.902)
PPAK-8P-3232H36
  rect 0.406x0.914 smd: 1(-0.975,-2.396) 2(-0.325,-2.396) 3(0.325,-2.396) 4(0.975,-2.396)
  rect 3.353x2.692 smd: 5(0,0)
  rect 0.025x0.025 smd: 6(0.65,0.838) 7(0,0.838) 8(-0.65,0.838)
PPAK-8P-G5324H44-COLAY
  rect 0.762x1.016 smd: 1(-1.905,-3.01) 2(-0.635,-3.01) 3(0.635,-3.01) 4(1.905,-3.01) 5(1.905,3.01) 6(0.635,3.01) 7(-0.635,3.01) 8(-1.905,3.01)
  rect 5.207x2.896 smd: 9(0,0.65)
  rect 5.207x0.787 smd: 10(0,-1.7)
QFN20-G1D75H32
  rect 0.203x0.914 smd: 1(0.8,1.551) 2(0.4,1.551) 3(0,1.551) 4(-0.4,1.551) 5(-0.8,1.551) 11(-0.8,-1.551) 12(-0.4,-1.551) 13(0,-1.551) 14(0.4,-1.551) 15(0.8,-1.551)
  rect 0.914x0.203 smd: 6(-1.551,0.8) 7(-1.551,0.4) 8(-1.551,0) 9(-1.551,-0.4) 10(-1.551,-0.8) 16(1.551,-0.8) 17(1.551,-0.4) 18(1.551,0) 19(1.551,0.4) 20(1.551,0.8)
  rect 1.753x1.753 smd: 21(0,0)
QFN20G3D5-G2D15H40
  rect 0.305x0.914 smd: 1(1,1.801) 5(-1,1.801) 11(-1,-1.801) 15(1,-1.801)
  rect 0.305x0.965 smd: 2(0.5,1.775) 3(0,1.775) 4(-0.5,1.775) 12(-0.5,-1.775) 13(0,-1.775) 14(0.5,-1.775)
  rect 0.914x0.305 smd: 6(-1.801,1) 10(-1.801,-1) 16(1.801,-1) 20(1.801,1)
  rect 0.965x0.305 smd: 7(-1.775,0.5) 8(-1.775,0) 9(-1.775,-0.5) 17(1.775,-0.5) 18(1.775,0) 19(1.775,0.5)
  rect 2.159x2.159 smd: 21(0,0)
QFN32J4-G2D9-U1H36
  rect 0.203x0.864 smd: 1(1.4,2.085) 2(1,2.085) 3(0.6,2.085) 4(0.2,2.085) 5(-0.2,2.085) 6(-0.6,2.085) 7(-1,2.085) 8(-1.4,2.085) 17(-1.4,-2.085) 18(-1,-2.085) 19(-0.6,-2.085) 20(-0.2,-2.085) 21(0.2,-2.085) 22(0.6,-2.085) 23(1,-2.085) 24(1.4,-2.085)
  rect 0.864x0.203 smd: 9(-2.085,1.4) 10(-2.085,1) 11(-2.085,0.6) 12(-2.085,0.2) 13(-2.085,-0.2) 14(-2.085,-0.6) 15(-2.085,-1) 16(-2.085,-1.4) 25(2.085,-1.4) 26(2.085,-1) 27(2.085,-0.6) 28(2.085,-0.2) 29(2.085,0.2) 30(2.085,0.6) 31(2.085,1) 32(2.085,1.4)
  rect 2.692x2.692 smd: 33(0,0)
QFN40-G3D5H32
  rect 0.203x0.914 smd: 1(1.8,2.553) 10(-1.8,2.553) 21(-1.8,-2.553) 30(1.8,-2.553)
  rect 0.203x0.965 smd: 2(1.4,2.527) 3(1,2.527) 4(0.6,2.527) 5(0.2,2.527) 6(-0.2,2.527) 7(-0.6,2.527) 8(-1,2.527) 9(-1.4,2.527) 22(-1.4,-2.527) 23(-1,-2.527) 24(-0.6,-2.527) 25(-0.2,-2.527) 26(0.2,-2.527) 27(0.6,-2.527) 28(1,-2.527) 29(1.4,-2.527)
  rect 0.914x0.203 smd: 11(-2.553,1.8) 20(-2.553,-1.8) 31(2.553,-1.8) 40(2.553,1.8)
  rect 0.965x0.203 smd: 12(-2.527,1.4) 13(-2.527,1) 14(-2.527,0.6) 15(-2.527,0.2) 16(-2.527,-0.2) 17(-2.527,-0.6) 18(-2.527,-1) 19(-2.527,-1.4) 32(2.527,-1.4) 33(2.527,-1) 34(2.527,-0.6) 35(2.527,-0.2) 36(2.527,0.2) 37(2.527,0.6) 38(2.527,1) 39(2.527,1.4)
  rect 3.505x3.505 smd: 41(0,0)
QFN48J6-G465H40
  rect 0.203x0.965 smd: 1(2.2,3.025) 2(1.8,3.025) 3(1.4,3.025) 4(1,3.025) 5(0.6,3.025) 6(0.2,3.025) 7(-0.2,3.025) 8(-0.6,3.025) 9(-1,3.025) 10(-1.4,3.025) 11(-1.8,3.025) 12(-2.2,3.025) 25(-2.2,-3.025) 26(-1.8,-3.025) 27(-1.4,-3.025) 28(-1,-3.025) 29(-0.6,-3.025) 30(-0.2,-3.025) 31(0.2,-3.025) 32(0.6,-3.025) 33(1,-3.025) 34(1.4,-3.025) 35(1.8,-3.025) 36(2.2,-3.025)
  rect 0.965x0.203 smd: 13(-3.025,2.2) 14(-3.025,1.8) 15(-3.025,1.4) 16(-3.025,1) 17(-3.025,0.6) 18(-3.025,0.2) 19(-3.025,-0.2) 20(-3.025,-0.6) 21(-3.025,-1) 22(-3.025,-1.4) 23(-3.025,-1.8) 24(-3.025,-2.2) 37(3.025,-2.2) 38(3.025,-1.8) 39(3.025,-1.4) 40(3.025,-1) 41(3.025,-0.6) 42(3.025,-0.2) 43(3.025,0.2) 44(3.025,0.6) 45(3.025,1) 46(3.025,1.4) 47(3.025,1.8) 48(3.025,2.2)
  rect 4.648x4.648 smd: 49(0,0)
R402H14
  custom 0.14x0.14 smd: 1(0,0.445) 2(0,-0.445)
R402H15
  custom 0.14x0.14 smd: 1(0,0.445) 2(0,-0.445)
R402H16
  custom 0.14x0.14 smd: 1(0,0.445) 2(0,-0.445)
R603H22
  custom 0.197x0.197 smd: 1(0,0.66) 2(0,-0.66)
R805H24
  rect 1.549x0.94 smd: 1(0,0.838) 2(0,-0.838)
R1206H28
  rect 1.854x1.27 smd: 1(0,1.397) 2(0,-1.397)
R3720H40
  rect 4.013x1.041 smd: 1(0,0.867) 2(0,-0.867)
SC70-5H44
  rect 0.406x1.219 smd: 1(0.65,0.826) 2(0,0.826) 3(-0.65,0.826) 4(-0.65,-0.826) 5(0.65,-0.826)
SC70-6H44
  rect 0.406x1.016 smd: 1(-0.65,-0.94) 2(0,-0.94) 3(0.65,-0.94) 4(0.65,0.94) 5(0,0.94) 6(-0.65,0.94)
SE341413H241
  rect 1.372x3.556 smd: 1(0,2.424) 2(0,-2.424)
SE361414H178
  rect 1.372x3.607 smd: 1(0,2.499) 2(0,-2.499)
SKT-HDMI23-188137
  oval 0.787x0.94 hole 0.533: 1(-4.5,5.75) 2(-4,7.25) 3(-3.5,5.75) 4(-3,7.25) 5(-2.5,5.75) 6(-2,7.25) 7(-1.5,5.75) 8(-1,7.25) 9(-0.5,5.75) 10(0,7.25) 11(0.5,5.75) 12(1,7.25) 13(1.5,5.75) 14(2,7.25) 15(2.5,5.75) 16(3,7.25) 17(3.5,5.75) 18(4,7.25) 19(4.5,5.75)
  oval 1.626x2.515 hole 0.914x1.803: 20(-7.25,6.5) 21(7.25,6.5) 22(-9.15,0) 23(9.15,0)
SKT-USB8-166140-2
  round 1.346 hole 0.94: 1(3.5,10.45) 2(1,10.45) 3(-1,10.45) 4(-3.5,10.45)
  oval 1.575x2.972 hole 0.914x2.311: 5(-6.4,9.6) 6(6.4,9.6)
  oval 1.626x3.124 hole 0.914x2.413: 7(-7.85,0) 8(7.85,0)
SKT-USB13-157164
  round 1.067 hole 0.711: 1(3.5,9.41) 2(1,9.41) 3(-1,9.41) 4(-3.5,9.41) 5(-4,7.91) 6(-2,7.91) 7(0,7.91) 8(2,7.91) 9(4,7.91)
  oval 1.321x3.2 hole 0.711x2.489: 10(7.7,7.43) 11(-7.7,7.43)
  oval 1.321x2.819 hole 0.711x2.108: 12(7.7,0) 13(-7.7,0)
SMD49-6914-0403H56
  rect 1.168x0.559 smd: 1(-3.38,-0.427) 2(3.38,-0.427) 3(3.38,0.427) 4(-3.38,0.427)
SMD-ARES4
  rect 0.356x0.66 smd: 1(-0.325,-0.599) 2(0.325,-0.599) 3(0.325,0.599) 4(-0.325,0.599)
SMD-ARES4-2H18-U
  rect 0.305x0.406 smd: 1(-0.25,-0.305) 2(0.25,-0.305) 3(0.25,0.305) 4(-0.25,0.305)
SMD-ARES4H18
  rect 0.356x0.66 smd: 1(-0.325,-0.599) 2(0.325,-0.599) 3(0.325,0.599) 4(-0.325,0.599)
SMD-ARES4H20
  rect 0.356x0.66 smd: 1(-0.325,-0.599) 2(0.325,-0.599) 3(0.325,0.599) 4(-0.325,0.599)
SMD-OSC12H36
  rect 1.524x1.016 smd: 1(-1.105,-0.81) 2(1.105,-0.81) 3(1.105,0.81) 4(-1.105,0.81)
SOD123FLAKH40
  rect 1.143x1.651 smd: A(0,1.622) K(0,-1.622)
SOD323AKH38
  rect 0.559x1.016 smd: A(0,1.143) K(0,-1.143)
SOD323AKH42
  rect 0.559x1.016 smd: A(0,1.143) K(0,-1.143)
SOD323AKH44
  rect 0.559x1.016 smd: A(0,1.143) K(0,-1.143)
SOD-323-1UH40
  rect 0.559x1.016 smd: 1(0,1.27) 2(0,-1.27)
SOD-523-4H28
  rect 0.559x0.864 smd: 1(0,0.778) 2(0,-0.778)
SOIC8-1H86
  rect 0.635x1.651 smd: 1(-1.905,-3.493) 2(-0.635,-3.493) 3(0.635,-3.493) 4(1.905,-3.493) 5(1.905,3.493) 6(0.635,3.493) 7(-0.635,3.493) 8(-1.905,3.493)
SOIC8H69
  rect 0.635x1.651 smd: 1(-1.905,-2.54) 2(-0.635,-2.54) 3(0.635,-2.54) 4(1.905,-2.54) 5(1.905,2.54) 6(0.635,2.54) 7(-0.635,2.54) 8(-1.905,2.54)
SON14J3020-G2610H34
  rect 0.025x0.025 smd: 1(1.2,1.105) 6(-0.8,1.105) 9(-0.8,-1.105) 14(1.2,-1.105)
  custom 0.151x0.151 smd: 2(0.8,1.105) 7(-1.2,1.105) 8(-1.2,-1.105) 13(0.8,-1.105)
  rect 0.203x0.813 smd: 3(0.4,1.105) 4(0,1.105) 5(-0.4,1.105) 10(-0.4,-1.105) 11(0,-1.105) 12(0.4,-1.105)
  rect 2.591x0.889 smd: 15(0,0)
SOT23-2D4-312H44
  custom 0.191x0.191 smd: 1(-0.984,-0.953) 2(0.984,-0.953) 3(0,0.953)
SOT23-2D4-312H48
  custom 0.191x0.191 smd: 1(-0.984,-0.953) 2(0.984,-0.953) 3(0,0.953)
SOT23-2D6-312H46
  custom 0.165x0.165 smd: 1(-0.95,-1.092) 2(0.95,-1.092) 3(0,1.092)
SOT23-2D8-123H52
  custom 0.254x0.254 smd: 1(0,1.118) 2(-1.016,-1.118) 3(1.016,-1.118)
SOT23-2D8-312H56
  custom 0.254x0.254 smd: 1(-1.016,-1.118) 2(1.016,-1.118) 3(0,1.118)
SOT23-2D8-321H56
  custom 0.254x0.254 smd: 1(1.016,-1.118) 2(-1.016,-1.118) 3(0,1.118)
SOT23CBE2D4H44
  custom 0.191x0.191 smd: B(-0.984,-0.953) C(0,0.953) E(0.984,-0.953)
SOT23CBE2D6H46
  custom 0.165x0.165 smd: B(-0.95,-1.092) C(0,1.092) E(0.95,-1.092)
SOT23DGS2D4H44
  custom 0.191x0.191 smd: D(0,0.953) G(-0.984,-0.953) S(0.984,-0.953)
SOT23DGS2D4H48
  custom 0.191x0.191 smd: D(0,0.953) G(-0.984,-0.953) S(0.984,-0.953)
SOT23DGS2D8H56
  custom 0.254x0.254 smd: D(0,1.118) G(-1.016,-1.118) S(1.016,-1.118)
SOT323CBE2D2H44
  custom 0.152x0.152 smd: B(-0.65,-0.902) C(0,0.902) E(0.65,-0.902)
SOT-6H58
  rect 0.584x1.016 smd: 1(-0.953,-1.346) 2(0,-1.346) 3(0.953,-1.346) 4(0.953,1.346) 5(0,1.346) 6(-0.953,1.346)
SOT-23-5H51
  rect 0.508x1.524 smd: 1(-0.95,-1.143) 2(0,-1.143) 3(0.95,-1.143) 4(0.95,1.143) 5(-0.95,1.143)
SOT-23-5H58
  rect 0.508x1.524 smd: 1(-0.95,-1.143) 2(0,-1.143) 3(0.95,-1.143) 4(0.95,1.143) 5(-0.95,1.143)
SOT-23-9H44
  custom 0.178x0.178 smd: 1(-0.95,-0.999) 2(0.95,-0.999) 3(0,0.999)
SOT-23-10H44
  rect 0.762x1.143 smd: 1(-0.984,-0.953) 2(0.984,-0.953) 3(0,0.953)
SOT-363H44
  rect 0.406x1.016 smd: 1(-0.65,-0.94) 2(0,-0.94) 3(0.65,-0.94) 4(0.65,0.94) 5(0,0.94) 6(-0.65,0.94)
SPR4527H308
  rect 8.992x3.404 smd: 1(-2.248,0)
SPR5930H154
  rect 5.588x2.692 smd: 1(-1.702,0)
SPR9537H308
  rect 9.195x3.404 smd: 1(-2.197,0)
STF237R117H83
  round 6.02 hole 2.972: 1(0,0)
TPAD14-OP
  round 0.356 smd: 1(0,0)
unnamed#2
  round 1.016 smd: (0,0)
XFORM12A127097H91
  rect 0.635x1.524 smd: 1(-4.445,-4.699) 2(-3.175,-4.699) 3(-1.905,-4.699) 4(1.905,-4.699) 5(3.175,-4.699) 6(4.445,-4.699) 7(4.445,4.699) 8(3.175,4.699) 9(1.905,4.699) 10(-1.905,4.699) 11(-3.175,4.699) 12(-4.445,4.699)

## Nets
0.95VGA_EN: C8314.2 R8301.1 R8309.2 U8302.3
1.8VGA_EN: C8313.2 R8301.2 R8310.2 U8302.5
3.3V_RUN_VGA_1: PQ8319.3 PR8350.1
3V5V_CT1: C3602.1 U3601.12
3V5V_CT2: C3601.1 U3601.10
3V5V_CT_105VC_2: C8302.1 U8302.12
3V5V_S0_ON: R3609.1 U3601.3 U3601.5
3V_5V_EN: D3602.1 PR4501.1 R3602.1 R3603.1
3V_5V_POK: PR4509.2 PR5010.1 PU4501.6 Q601.2 RN602.2(A)
5V_HDMI_S0: F5401.1 R5409.2
5V_HDMI_S0_R: C5401.1 F5401.2 HDMI1.18
5V_PWR: PC4525.1 PG4511.2 PG4512.2 PG4514.2 PG4524.2 PG4527.2 PG4528.2 PG4529.2 PG4531.2 PG4532.1 PG4535.2 PL4502.2 PT4502.1
5V_PWR_2: PC4515.1 PC4520.2 PR4514.2 PU4501.14 R2915.1
5V_S0: C2605.1 C2611.1 C3605.1 C5605.1 C5606.1 C5609.1 D5401.3 EC9718.1 EC9719.1 EC9720.1 EC9721.1 EC9722.1 EC9723.1 EC9724.1 F6201.1 FAN261.2 HDD1.P7 HDD1.P8 HDD1.P9 Q5403.G Q6201.1 R2702.1 R2703.2 R2704.1 R5230.1 R5409.1 R5413.1 R5801.1 R5807.1 R6205.1 U3601.13 U3601.14 U5601.2 U5601.3 U8302.4
5V_S5: C3504.1 C3505.1 C3510.1 EC9732.1 EC9733.1 EC9734.1 PC4829.1 PC4901.1 PG4511.1 PG4512.1 PG4514.1 PG4524.1 PG4527.1 PG4528.1 PG4529.1 PG4531.1 PG4535.1 PQ4601.2 PQ4601.5 PQ8201.G PR4203.1 PR4603.2 PR4604.2 PR4629.2 PR4636.2 PR4670.1 PR4672.1 PR8202.2 PR8203.2 PR8227.2 PR8230.2 PR8232.1 PR8238.1 PU4806.7 PU4901.12 Q6103.1 Q6104.1 U3503.5 U3504.5 U3505.5 U3601.1 U3601.2 U3601.4 U3603.4
+3V_1D5V_AVDD: C2715.1 HDA27.40 R2705.2
+3V_AVDD: C2701.1 HDA27.36 R2701.2 R2722.1 R2918.1
+5V_AVDD: C2710.1 C2711.1 HDA27.26 R2703.1
+5V_KB_BL: AFTP6248.1 C6204.1 F6201.2 KBLIT1.1 R6205.2
+5V_MINI_DEBUG: R5801.2 R5805.2 WLAN1.51
+5V_PVDD: C2706.1 C2707.1 C2708.1 C2709.1 HDA27.41 HDA27.46 R2702.2 R2704.2
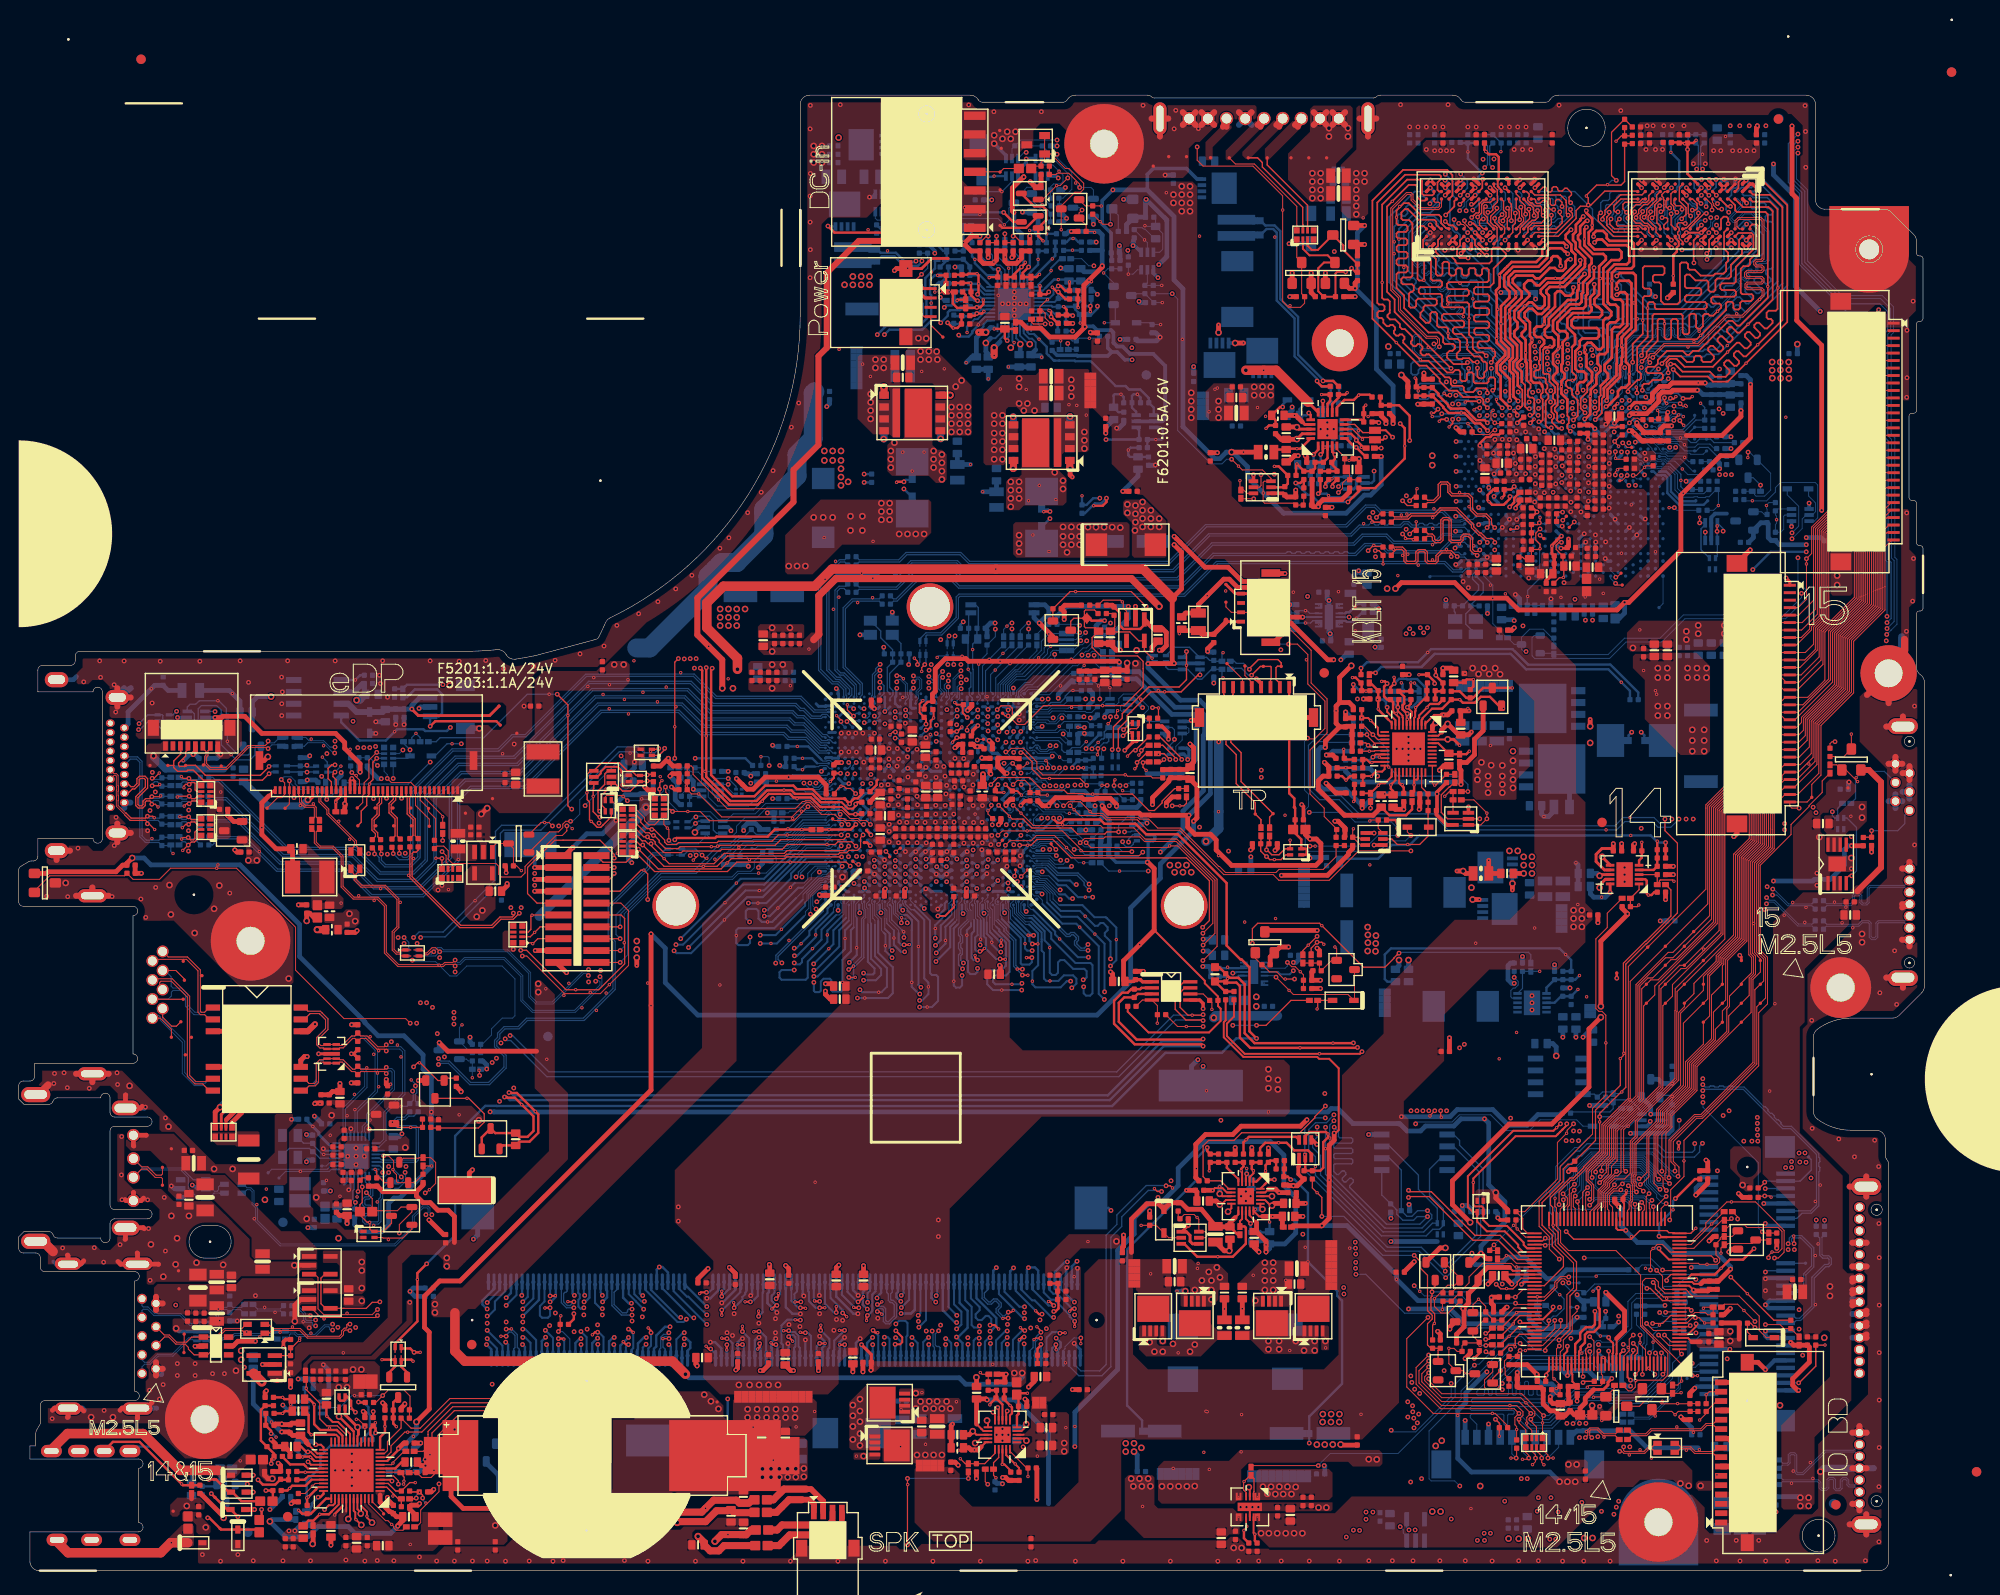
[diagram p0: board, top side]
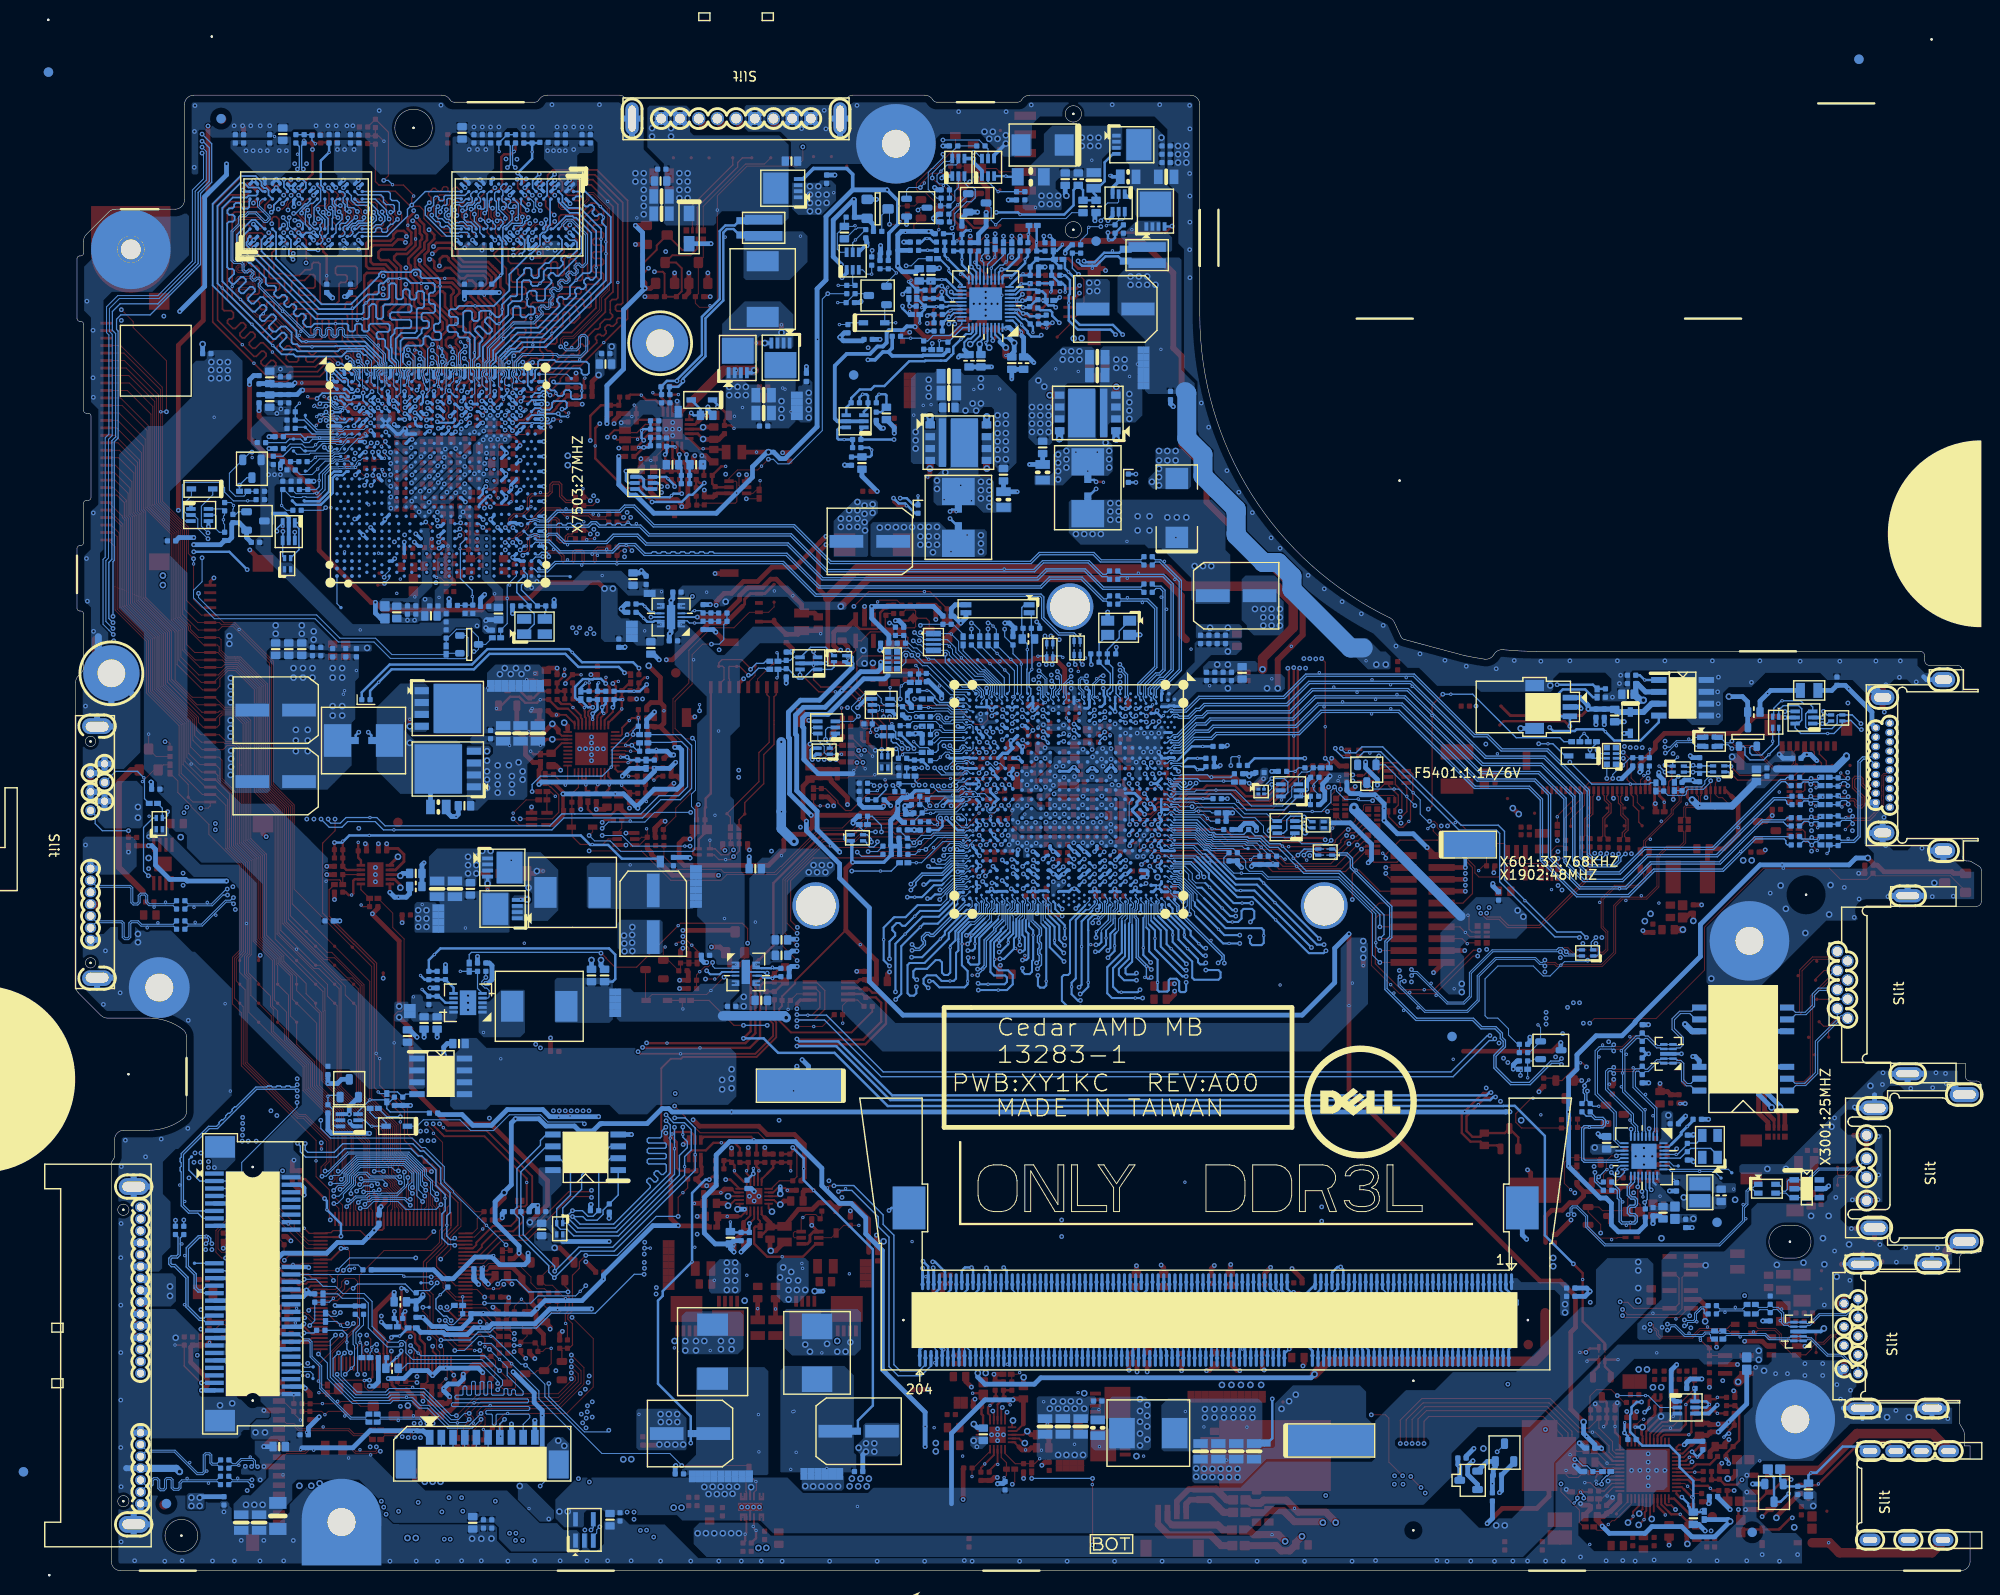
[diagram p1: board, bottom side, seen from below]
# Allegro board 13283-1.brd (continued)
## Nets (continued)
GND: AFTP2501.1 AFTP2803.1 AFTP3803.1 AFTP3806.1 AFTP3906.1 AFTP3909.1 AFTP3910.1 AFTP6201.1 AFTP6217.1 AFTP6235.1 AFTP6245.1 AFTP6802.1 BAT1.6 BAT1.8 BAT1.9 BAT1.10 BAT1.11 C1.1 C2.1 C3.1 C401.2 C402.2 C443.1 C501.2 C502.2 C601.1 C603.2 C604.2 C605.2 C701.2 C702.2 C703.2 C704.2 C705.2 C762.2 C1001.2 C1002.2 C1003.2 C1004.2 C1005.2 C1006.2 C1007.2 C1008.2 C1009.2 C1010.2 C1011.2 C1012.2 C1013.2 C1014.2 C1015.2 C1016.2 C1022.2 C1023.2 C1024.2 C1025.2 C1026.2 C1027.2 C1028.2 C1029.2 C1030.2 C1031.2 C1032.2 C1033.2 C1034.2 C1035.2 C1036.2 C1037.2 C1038.2 C1039.2 C1040.2 C1041.2 C1042.2 C1043.2 C1044.2 C1045.2 C1046.2 C1047.2 C1049.2 C1050.2 C1051.1 C1053.2 C1054.2 C1055.2 C1056.1 C1057.1 C1058.1 C1059.1 C1060.2 C1061.1 C1062.1 C1063.1 C1064.2 C1065.2 C1066.2 C1067.2 C1068.2 C1069.2 C1070.2 C1071.2 C1072.2 C1073.2 C1074.2 C1075.2 C1076.2 C1077.2 C1078.2 C1079.2 C1080.2 C1081.2 C1082.2 C1083.2 C1084.2 C1085.2 C1086.2 C1087.2 C1088.2 C1089.2 C1090.2 C1091.2 C1092.1 C1093.2 C1094.2 C1095.2 C1096.2 C1201.2 C1202.2 C1203.2 C1204.2 C1205.2 C1208.2 C1209.2 C1210.2 C1211.2 C1212.2 C1213.2 C1214.2 C1215.2 C1216.2 C1217.2 C1218.2 C1219.2 C1220.2 C1221.2 C1222.2 C1223.2 C1224.2 C1225.2 C1904.1 C1905.1 C2406.2 C2407.2 C2408.2 C2409.2 C2410.2 C2411.2 C2412.2 C2413.2 C2415.1 C2416.2 C2418.2 C2421.2 C2501.2 C2502.2 C2503.1 C2601.2 C2602.2 C2603.2 C2604.2 C2605.2 C2608.2 C2609.2 C2610.2 C2611.2 C2704.1 C2706.2 C2707.2 C2708.2 C2709.2 C2716.2 C2717.2 C2718.2 C2719.2 C2723.1 C2901.2 C3001.2 C3002.2 C3003.2 C3004.2 C3005.2 C3007.2 C3008.2 C3009.2 C3010.2 C3011.2 C3012.2 C3013.2 C3017.2 C3018.2 C3019.2 C3021.2 C3022.2 C3023.2 C3024.2 C3025.2 C3101.2 C3106.2 C3401.2 C3402.2 C3405.2 C3406.2 C3503.2 C3504.2 C3505.2 C3506.2 C3507.2 C3508.2 C3509.2 C3510.2 C3512.2 C3513.2 C3514.2 C3515.2 C3516.2 C3517.2 C3518.2 C3601.2 C3602.2 C3603.2 C3605.2 C3607.2 C3612.2 C3613.2 C3617.2 C3618.2 C3619.2 C3620.1 C3621.1 C3625.2 C3626.2 C5201.2 C5202.2 C5204.2 C5205.1 C5206.1 C5207.2 C5208.2 C5214.2 C5401.2 C5605.2 C5606.2 C5609.2 C5610.2 C5802.2 C5803.2 C5804.2 C5807.2 C6202.2 C6203.2 C6204.2 C6401.2 C6402.2 C7333.2 C7401.1 C7402.2 C7403.2 C7515.2 C7516.1 C7517.1 C7518.1 C7519.1 C7521.2 C7582.2 C7602.1 C7604.1 C7605.1 C7607.1 C7608.1 C7609.1 C7610.1 C7611.1 C7612.1 C7613.1 C7615.1 C7616.1 C7617.1 C7618.1 C7619.1 C7620.1 C7621.1 C7622.1 C7623.1 C7624.1 C7625.1 C7631.1 C7633.1 C7634.1 C7635.1 C7636.1 C7637.1 C7638.1 C7639.1 C7640.1 C7644.1 C7645.1 C7646.1 C7647.1 C7648.1 C7649.1 C7650.1 C7651.1 C7652.1 C7653.1 C7654.1 C7658.1 C7659.1 C7660.1 C7661.1 C7662.1 C7663.1 C7664.1 C7665.1 C7666.1 C7667.1 C7668.1 C7669.1 C7670.1 C7671.1 C7672.1 C7673.1 C7674.1 C7675.1 C7676.1 C7677.1 C7678.1 C7679.1 C7680.1 C7681.1 C7682.1 C7683.1 C7684.1 C7685.1 C7686.1 C7687.1 C7688.1 C7689.1 C7729.2 C7730.2 C7779.1 C7780.1 C7781.1 C7787.1 C7788.1 C7790.1 C7791.1 C7792.1 C7793.1 C7801.2 C7802.2 C7803.2 C7808.2 C7810.2 C7811.2 C7812.2 C7813.2 C7814.2 C7816.2 C7817.2 C7818.2 C7819.2 C8301.2 C8302.2 C8303.2 C8304.2 C8308.1 C8309.1 C8313.1 C8314.1 C8316.2 C8320.2 C8901.2 C8903.2 C8905.2 C8908.2 C8910.2 C8911.2 C8912.2 C8913.2 C8914.2 C8915.2 C8920.2 C8922.2 C8923.2 CCD1.8 CCD1.9 CCD1.10 CPU1.A8 CPU1.A13 CPU1.A15 CPU1.A31 CPU1.A35 CPU1.A39 CPU1.AA3 CPU1.AA7 CPU1.AA8 CPU1.AA11 CPU1.AA15 CPU1.AA19 CPU1.AA25 CPU1.AA29 CPU1.AA39 CPU1.AC3 CPU1.AC7 CPU1.AC11 CPU1.AC15 CPU1.AC19 CPU1.AC25 CPU1.AC29 CPU1.AC31 CPU1.AC39 CPU1.AC41 CPU1.AE3 CPU1.AE7 CPU1.AE25 CPU1.AE29 CPU1.AE32 CPU1.AE39 CPU1.AG3 CPU1.AG5 CPU1.AG10 CPU1.AG11 CPU1.AG13 CPU1.AG15 CPU1.AG19 CPU1.AG25 CPU1.AG29 CPU1.AG31 CPU1.AG39 CPU1.AG41 CPU1.AH1 CPU1.AH2 CPU1.AJ3 CPU1.AJ7 CPU1.AJ15 CPU1.AJ17 CPU1.AJ19 CPU1.AJ23 CPU1.AJ25 CPU1.AJ29 CPU1.AJ31 CPU1.AJ32 CPU1.AJ39 CPU1.AL3 CPU1.AL8 CPU1.AL15 CPU1.AL17 CPU1.AL19 CPU1.AL25 CPU1.AL29 CPU1.AL31 CPU1.AL39 CPU1.AL41 CPU1.AM11 CPU1.AM27 CPU1.AM29 CPU1.AM31 CPU1.AN3 CPU1.AN7 CPU1.AN39 CPU1.AP31 CPU1.AR3 CPU1.AR13 CPU1.AR17 CPU1.AR21 CPU1.AR25 CPU1.AR29 CPU1.AR39 CPU1.AR41 CPU1.AU1 CPU1.AU2 CPU1.AU3 CPU1.AU15 CPU1.AU19 CPU1.AU23 CPU1.AU27 CPU1.AU39 CPU1.AV9 CPU1.AW3 CPU1.AW7 CPU1.AW13 CPU1.AW15 CPU1.AW17 CPU1.AW19 CPU1.AW21 CPU1.AW23 CPU1.AW25 CPU1.AW27 CPU1.AW31 CPU1.AW33 CPU1.AW35 CPU1.AW37 CPU1.AW39 CPU1.AW41 CPU1.AY13 CPU1.AY15 CPU1.AY18 CPU1.AY30 CPU1.B8 CPU1.B13 CPU1.B23 CPU1.B31 CPU1.B39 CPU1.BA2 CPU1.BA7 CPU1.BA13 CPU1.BA15 CPU1.BA18 CPU1.BA21 CPU1.BA25 CPU1.BA31 CPU1.BA35 CPU1.BA39 CPU1.C1 CPU1.C2 CPU1.C5 CPU1.C7 CPU1.C9 CPU1.C11 CPU1.C13 CPU1.C15 CPU1.C17 CPU1.C19 CPU1.C21 CPU1.C23 CPU1.C25 CPU1.C27 CPU1.C29 CPU1.C31 CPU1.C33 CPU1.C35 CPU1.C37 CPU1.C39 CPU1.C41 CPU1.D9 CPU1.D11 CPU1.D13 CPU1.E3 CPU1.E4 CPU1.E9 CPU1.E11 CPU1.E13 CPU1.E27 CPU1.E31 CPU1.E35 CPU1.E38 CPU1.E39 CPU1.G3 CPU1.G7 CPU1.G11 CPU1.G13 CPU1.G15 CPU1.G17 CPU1.G21 CPU1.G25 CPU1.G29 CPU1.G35 CPU1.G37 CPU1.G39 CPU1.G41 CPU1.H11 CPU1.H13 CPU1.H23 CPU1.H31 CPU1.J3 CPU1.J7 CPU1.J8 CPU1.J39 CPU1.K11 CPU1.K13 CPU1.K17 CPU1.K19 CPU1.K21 CPU1.K23 CPU1.K25 CPU1.K27 CPU1.K29 CPU1.K31 CPU1.L3 CPU1.L7 CPU1.L8 CPU1.L10 CPU1.L11 CPU1.L15 CPU1.L19 CPU1.L31 CPU1.L39 CPU1.L41 CPU1.M1 CPU1.M2 CPU1.N3 CPU1.N7 CPU1.N15 CPU1.N19 CPU1.N25 CPU1.N29 CPU1.N31 CPU1.N39 CPU1.P1 CPU1.P2 CPU1.R3 CPU1.R7 CPU1.R15 CPU1.R19 CPU1.R25 CPU1.R29 CPU1.R39 CPU1.R41 CPU1.U1 CPU1.U2 CPU1.U3 CPU1.U7 CPU1.U8 CPU1.U11 CPU1.U15 CPU1.U19 CPU1.U25 CPU1.U29 CPU1.U31 CPU1.U39 CPU1.W3 CPU1.W5 CPU1.W11 CPU1.W15 CPU1.W19 CPU1.W25 CPU1.W29 CPU1.W39 CPU1.W41 CPU1.Y1 CPU1.Y2 D2601.A D4301.1 D4302.1 D4303.1 DB1.8 DB1.10 DB1.11 DB1.12 DCIN1.5 DCIN1.6 DCIN1.7 DM1.2 DM1.3 DM1.8 DM1.9 DM1.13 DM1.14 DM1.19 DM1.20 DM1.25 DM1.26 DM1.31 DM1.32 DM1.37 DM1.38 DM1.43 DM1.44 DM1.48 DM1.49 DM1.54 DM1.55 DM1.60 DM1.61 DM1.65 DM1.66 DM1.71 DM1.72 DM1.127 DM1.128 DM1.133 DM1.134 DM1.138 DM1.139 DM1.144 DM1.145 DM1.150 DM1.151 DM1.155 DM1.156 DM1.161 DM1.162 DM1.167 DM1.168 DM1.172 DM1.173 DM1.178 DM1.179 DM1.184 DM1.185 DM1.189 DM1.190 DM1.195 DM1.196 DM1.197 DM1.201 DM1.205 DM1.206 EC2501.2 EC2502.2 EC2503.2 EC2601.2 EC2602.2 EC2701.2 EC2703.2 EC2704.2 EC2705.2 EC2706.2 EC2707.2 EC2708.2 EC2709.2 EC2901.2 EC2902.2 EC2903.2 EC2904.2 EC3101.1 EC3102.1 EC3103.1 EC3104.1 EC3105.1 EC3106.1 EC3107.1 EC3108.1 EC4301.2 EC4302.2 EC4303.2 EC4304.2 EC4305.1 EC4401.2 EC4402.2 EC4601.2 EC5205.2 EC5206.2 EC5210.2 EC6103.2 EC6104.2 EC6105.2 EC6205.2 EC6206.2 EC6207.2 EC6208.2 EC9701.2 EC9703.2 EC9704.2 EC9705.2 EC9707.2 EC9708.2 EC9709.2 EC9710.2 EC9711.2 EC9712.2 EC9713.2 EC9714.2 EC9715.2 EC9716.2 EC9717.2 EC9718.2 EC9719.2 EC9720.2 EC9721.2 EC9722.2 EC9723.2 EC9724.2 EC9725.2 EC9726.2 EC9727.2 EC9728.2 EC9729.2 EC9730.2 EC9731.2 EC9732.2 EC9733.2 EC9734.2 EC9735.2 EC9736.2 EC9737.2 EC9738.2 EC9739.2 EC9740.2 EC9741.2 EC9742.2 EC9743.2 EC9744.2 EC9745.2 EC9747.2 EC9748.2 EC9749.2 ED2901.2 ED2902.2 ED2903.2 ED2904.2 ED2905.2 FAN1.2 FAN1.4 FAN1.5 FAN261.5 FAN261.6 FAN261.7 FAN261.8 G701.2 GPU1.A3 GPU1.A30 GPU1.AA11 GPU1.AA13 GPU1.AA16 GPU1.AA27 GPU1.AB6 GPU1.AB10 GPU1.AB15 GPU1.AB22 GPU1.AB24 GPU1.AB32 GPU1.AC9 GPU1.AC17 GPU1.AC24 GPU1.AC26 GPU1.AC27 GPU1.AD6 GPU1.AD8 GPU1.AD25 GPU1.AD32 GPU1.AE7 GPU1.AE14 GPU1.AE27 GPU1.AF32 GPU1.AG12 GPU1.AG27 GPU1.AH10 GPU1.AH28 GPU1.AH32 GPU1.B6 GPU1.B8 GPU1.B10 GPU1.B12 GPU1.B14 GPU1.B16 GPU1.B18 GPU1.B20 GPU1.B22 GPU1.B24 GPU1.B26 GPU1.C1 GPU1.C32 GPU1.E28 GPU1.F2 GPU1.F6 GPU1.F8 GPU1.F10 GPU1.F12 GPU1.F14 GPU1.F16 GPU1.F18 GPU1.F20 GPU1.F22 GPU1.F24 GPU1.F26 GPU1.G8 GPU1.G10 GPU1.G27 GPU1.G31 GPU1.H2 GPU1.H6 GPU1.H14 GPU1.H17 GPU1.H20 GPU1.J7 GPU1.J27 GPU1.J31 GPU1.K2 GPU1.K6 GPU1.K11 GPU1.K22 GPU1.K28 GPU1.K32 GPU1.L27 GPU1.M6 GPU1.M12 GPU1.M32 GPU1.N11 GPU1.N13 GPU1.N16 GPU1.N18 GPU1.N21 GPU1.N25 GPU1.N27 GPU1.P6 GPU1.P9 GPU1.P25 GPU1.P32 GPU1.R11 GPU1.R12 GPU1.R15 GPU1.R17 GPU1.R20 GPU1.R27 GPU1.T6 GPU1.T11 GPU1.T13 GPU1.T16 GPU1.T18 GPU1.T21 GPU1.T25 GPU1.T32 GPU1.U9 GPU1.U15 GPU1.U17 GPU1.U20 GPU1.U25 GPU1.U27 GPU1.V11 GPU1.V13 GPU1.V16 GPU1.V18 GPU1.V32 GPU1.W25 GPU1.W26 GPU1.W27 GPU1.Y10 GPU1.Y15 GPU1.Y17 GPU1.Y20 GPU1.Y25 GPU1.Y32 H1.1 H2.1 H3.1 H4.1 H5.1 H6.1 HDA27.4 HDA27.49 HDD1.23 HDD1.24 HDD1.P4 HDD1.P5 HDD1.P6 HDD1.P10 HDD1.P12 HDD1.S1 HDD1.S4 HDD1.S7 HDMI1.2 HDMI1.5 HDMI1.8 HDMI1.11 HDMI1.17 HDMI1.20 HDMI1.21 HDMI1.22 HDMI1.23 HDT1.3 HDT1.5 HDT1.7 HDT1.17 IOBD1.7 IOBD1.10 IOBD1.13 IOBD1.16 IOBD1.17 IOBD1.18 KB1.1 KB1.31 KB1.32 KB2.1 KB2.31 KB2.32 KBC24.5 KBC24.12 KBC24.18 KBC24.45 KBC24.78 KBC24.89 KBC24.116 KBLIT1.5 KBLIT1.6 LCD1.13 LCD1.16 LCD1.19 LCD1.23 LCD1.24 LCD1.25 LCD1.29 LCD1.36 LCD1.41 LCD1.42 LIDSW1.1 LOM30.33 ODD1.5 ODD1.6 ODD1.14 ODD1.15 ODD1.S1 ODD1.S4 ODD1.S7 PC4202.2 PC4203.2 PC4204.2 PC4205.2 PC4206.2 PC4209.2 PC4401.2 PC4406.2 PC4407.2 PC4408.2 PC4409.2 PC4415.2 PC4416.2 PC4417.2 PC4418.2 PC4419.2 PC4425.2 PC4426.2 PC4501.2 PC4502.2 PC4510.2 PC4511.2 PC4512.2 PC4514.2 PC4515.2 PC4516.2 PC4517.2 PC4518.2 PC4521.2 PC4523.2 PC4524.2 PC4525.2 PC4528.2 PC4601.2 PC4603.2 PC4604.2 PC4613.2 PC4617.2 PC4618.2 PC4620.2 PC4621.2 PC4622.2 PC4623.2 PC4625.2 PC4703.1 PC4704.1 PC4713.2 PC4715.2 PC4716.2 PC4717.2 PC4718.2 PC4719.2 PC4720.2 PC4721.2 PC4722.2 PC4742.2 PC4743.2 PC4827.2 PC4828.2 PC4829.2 PC4830.2 PC4831.2 PC4834.2 PC4838.2 PC4901.2 PC4902.2 PC4903.2 PC4904.2 PC4906.2 PC4909.2 PC4911.2 PC4912.2 PC4913.1 PC4914.2 PC4915.2 PC4916.2 PC4917.2 PC4918.2 PC4920.2 PC4921.2 PC4922.2 PC4923.2 PC4924.2 PC4925.2 PC4926.2 PC5005.2 PC5010.2 PC5011.2 PC5012.2 PC5013.2 PC5015.2 PC8202.2 PC8203.2 PC8205.2 PC8213.2 PC8214.2 PC8216.2 PC8217.2 PC8218.2 PC8219.2 PC8220.2 PC8221.2 PC8222.2 PC8224.2 PC8232.2 PC8236.1 PC8321.2 PC8322.2 PC8323.2 PD4201.A PD4203.1 PD4204.3 PD4302.A PG4411.2 PQ4202.E PQ4203.1 PQ4203.4 PQ4204.E PQ4206.1 PQ4206.4 PQ4208.S PQ4402.1 PQ4402.4 PQ4408.1 PQ4408.4 PQ4410.1 PQ4410.4 PQ4501.1 PQ4501.4 PQ4502.1 PQ4502.4 PQ8305.1 PQ8305.4 PQ8314.1 PQ8314.4 PQ8317.S PQ8319.1 PQ8319.4 PR4202.2 PR4208.2 PR4213.2 PR4216.2 PR4218.2 PR4405.2 PR4432.2 PR4433.2 PR4436.2 PR4464.2 PR4467.2 PR4470.1 PR4502.2 PR4507.2 PR4515.2 PR4516.2 PR4519.2 PR4521.2 PR4522.2 PR4631.1 PR4633.2 PR4638.1 PR4663.2 PR4669.2 PR4674.1 PR4675.2 PR4681.2 PR4817.1 PR4823.2 PR4824.2 PR4902.2 PR4906.2 PR4908.2 PR5013.2 PR8222.1 PR8228.2 PR8231.1 PR8234.2 PR8241.2 PR8256.2 PR8257.2 PR8347.1 PT4501.2 PT4502.2 PT4701.2 PT4702.2 PT4703.2 PT4704.2 PT4705.2 PT4803.2 PT8204.2 PT8205.2 PU4404.14 PU4406.1 PU4406.2 PU4406.3 PU4501.21 PU4503.1 PU4503.2 PU4503.3 PU4505.1 PU4505.2 PU4505.3 PU4601.41 PU4701.5 PU4701.6 PU4701.7 PU4702.5 PU4702.6 PU4702.7 PU4703.5 PU4703.6 PU4703.7 PU4704.5 PU4704.6 PU4704.7 PU4805.1 PU4805.2 PU4805.3 PU4806.11 PU4901.4 PU4901.7 PU4901.10 PU4901.21 PU4903.1 PU4903.2 PU4903.3 PU5002.11 PU8202.41 PU8205.1 PU8205.2 PU8205.3 Q601.1 Q601.4 Q603.1 Q603.4 Q701.S Q2401.S Q2403.S Q2404.C Q2505.S Q3001.S Q5403.S Q6203.S R401.2 R402.2 R405.2 R406.2 R407.2 R408.2 R410.2 R411.2 R412.1 R413.2 R415.2 R416.2 R419.2 R423.2 R425.2 R607.2 R620.2 R621.2 R629.2 R632.2 R633.2 R640.1 R641.1 R643.2 R644.2 R645.1 R646.1 R647.1 R702.2 R706.2 R1902.1 R1903.1 R1909.2 R1912.2 R1914.2 R1916.2 R1917.2 R1919.2 R1926.2 R1928.2 R2435.2 R2437.2 R2442.2 R2445.2 R2447.1 R2504.2 R2605.1 R2612.2 R2706.2 R2717.2 R3015.2 R3023.2 R3032.1 R3501.2 R3502.2 R3602.2 R3626.2 R5201.2 R5202.1 R5207.2 R5209.2 R5410.2 R5412.2 R5413.2 R5418.1 R5604.2 R6207.2 R6208.2 R7317.1 R7323.2 R7332.1 R7404.1 R7408.1 R7414.2 R7415.2 R7418.2 R7419.2 R7425.1 R7501.1 R7520.2 R7522.2 R7524.2 R7526.2 R7710.2 R7801.1 R7802.1 R7806.2 R8902.2 R8903.1 R8904.1 RJ45.9 RJ45.10 RN5203.1(A) RN5203.2(A) RN5203.3(A) RN6502.6(B) RN6502.7(B) RN6502.8(B) RTC1.2 S1.1 S2.1 SPI25.4 SPK1.5 SPK1.6 SPR2.1 SPR4.1 SPR5.1 SPR6.1 SW1.1 SW1.2 SW1.5 SW1.6 TC3501.2 TC3502.2 TC6301.2 THM26.5 TPAD1.4 TPAD1.9 TPAD1.10 U402.2 U701.2 U2901.1 U3101.3 U3101.8 U3102.3 U3102.8 U3401.2 U3402.3 U3402.8 U3403.2 U3503.2 U3504.2 U3505.2 U3601.11 U3601.15 U3602.2 U3603.11 U3603.15 U5201.2 U5601.1 U5601.9 U8201.3 U8302.11 U8302.15 USB1.4 USB1.7 USB1.10 USB1.11 USB1.12 USB1.13 USB2.4 USB2.5 USB2.6 USB2.7 USB2.8 VRAM1.A9 VRAM1.B1 VRAM1.B3 VRAM1.B9 VRAM1.D1 VRAM1.D8 VRAM1.E1 VRAM1.E2 VRAM1.E8 VRAM1.F9 VRAM1.G1 VRAM1.G8 VRAM1.G9 VRAM1.J2 VRAM1.J8 VRAM1.M1 VRAM1.M9 VRAM1.P1 VRAM1.P9 VRAM1.T1 VRAM1.T9 VRAM2.A9 VRAM2.B1 VRAM2.B3 VRAM2.B9 VRAM2.D1 VRAM2.D8 VRAM2.E1 VRAM2.E2 VRAM2.E8 VRAM2.F9 VRAM2.G1 VRAM2.G8 VRAM2.G9 VRAM2.J2 VRAM2.J8 VRAM2.M1 VRAM2.M9 VRAM2.P1 VRAM2.P9 VRAM2.T1 VRAM2.T9 VRAM3.A9 VRAM3.B1 VRAM3.B3 VRAM3.B9 VRAM3.D1 VRAM3.D8 VRAM3.E1 VRAM3.E2 VRAM3.E8 VRAM3.F9 VRAM3.G1 VRAM3.G8 VRAM3.G9 VRAM3.J2 VRAM3.J8 VRAM3.M1 VRAM3.M9 VRAM3.P1 VRAM3.P9 VRAM3.T1 VRAM3.T9 VRAM4.A9 VRAM4.B1 VRAM4.B3 VRAM4.B9 VRAM4.D1 VRAM4.D8 VRAM4.E1 VRAM4.E2 VRAM4.E8 VRAM4.F9 VRAM4.G1 VRAM4.G8 VRAM4.G9 VRAM4.J2 VRAM4.J8 VRAM4.M1 VRAM4.M9 VRAM4.P1 VRAM4.P9 VRAM4.T1 VRAM4.T9 WLAN1.4 WLAN1.9 WLAN1.15 WLAN1.18 WLAN1.21 WLAN1.26 WLAN1.27 WLAN1.29 WLAN1.34 WLAN1.35 WLAN1.37 WLAN1.40 WLAN1.43 WLAN1.50 WLAN1.53 WLAN1.54 X601.2 X601.3 X1902.2 X1902.4
V3D3_STB: HDA27.20 R2712.1
VBAT: C2404.1 C2405.1 KBC24.102 R2402.2 R2404.1 R2405.1 R2446.1
VDD10: C3012.1 C3018.1 C3019.1 C3021.1 C3022.1 C3023.1 C3024.1 C3025.1 L3001.2 LOM30.3 LOM30.8 LOM30.22 LOM30.30 R3001.2
VDD_095_FB_H: CPU1.AV33
VDD_095_FB_L: CPU1.AU33
VDD_CT: C7679.2 C7680.2 C7681.2 GPU1.AA20 GPU1.AA21 GPU1.AB20 GPU1.AB21 L7601.2
VDDIO_MEM_SENSE: CPU1.E25 R417.2
VDDR3: C7652.2 C7653.2 C7654.2 C7683.2 GPU1.AA17 GPU1.AA18 GPU1.AB17 GPU1.AB18 L7603.2
VDDREG: C3009.1 C3010.1 LOM30.23 R3006.2
VSS_MECH1: GPU1.A32 TP7703.1
VSS_MECH2: GPU1.AM1 TP7704.1
VSS_MECH3: GPU1.AM32 TP7705.1
0D95_S5_EN: KBC24.79 PR4819.1 R2437.1
0D95V_GFX_S0: C703.1 C704.1 C762.1 CPU1.AA10 CPU1.U10 CPU1.W10 R703.1
0D95V_PWR: PC4834.1 PG4824.2 PG4825.2 PG4826.2 PG4828.2 PG4830.2 PG4831.2 PG4832.2 PL4802.2 PT4803.1
0D95V_PWRGD: C3625.1 D3603.1 PR3622.2 R3604.1 R3605.1
0D95V_S0: C1039.1 C1040.1 C1041.1 C1042.1 C1043.1 C1044.1 C1045.1 C1046.1 C1047.1 C3620.2 CPU1.AG23 CPU1.AG27 CPU1.AJ21 CPU1.AJ27 CPU1.AL21 CPU1.AL23 CPU1.AL27 CPU1.AM23 CPU1.AM25 R301.1 R302.1 R703.2 R1904.1 U3603.13 U3603.14
0D95V_S0_EN: C3626.1 R3624.2 U3603.3
0D95V_S5: C1012.1 C1013.1 C1014.1 C1015.1 C1016.1 C1092.2 C1093.1 C1094.1 C1095.1 C1096.1 C3613.1 C8316.1 CPU1.AE11 CPU1.AE13 CPU1.AJ11 CPU1.AJ13 CPU1.AR5 CPU1.AU4 CPU1.AV7 CPU1.AW5 PG4824.1 PG4825.1 PG4826.1 PG4828.1 PG4830.1 PG4831.1 R1910.2 U3603.1 U3603.2 U8302.1 U8302.2
0D95V_S5_PWRGD: KBC24.106 PR4821.2
0D95V_VGA_OUT2: C8303.1 PG8317.1 PG8318.1 PG8319.1 U8302.13 U8302.14
0D95V_VGA_S0: C7604.2 C7605.2 C7615.2 C7616.2 C7617.2 C7633.2 C7634.2 C7639.2 C7640.2 C7682.2 C8309.2 GPU1.L23 GPU1.L24 GPU1.L25 GPU1.L26 GPU1.M22 GPU1.N22 GPU1.N23 GPU1.N24 GPU1.R21 GPU1.R22 GPU1.T22 GPU1.U21 GPU1.U22 GPU1.V22 L7705.1 L7706.1 PG8317.2 PG8318.2 PG8319.2 R7318.2 R7321.2
0D675V_S0: C1208.1 C1209.1 C1210.1 C1211.1 C1212.1 DM1.203 DM1.204 PG4901.1 PG4902.1
1D5V_S0: C1034.1 C1035.1 C1036.1 C1037.1 C1038.1 C2719.1 C3607.1 CPU1.AL10 CPU1.AL11 HDA27.9 R2705.1 U3602.5
1D5V_S0_EN: R3625.2 R3626.1 U3602.3
1D8V_PWR: PC5010.1 PC5012.1 PC5014.1 PG5010.1 PG5011.1 PG5012.1 PG5013.1 PL5002.2 PR5009.1
1D8V_S0: C443.2 C1025.1 C1026.1 C1027.1 C1028.1 C1029.1 C1030.1 C1031.1 C1032.1 C1033.1 C3621.2 CPU1.A2 CPU1.A3 CPU1.B3 CPU1.C3 HDT1.1 HDT1.19 PC4622.1 PR4648.1 PR4653.1 PR4654.1 PR4655.1 PR4656.1 R403.1 R420.2 R421.1 R422.2 R424.2 R434.1 RN404.5(B) RN404.6(B) RN404.7(B) RN404.8(B) RN407.2(A) RN407.3(A) RN407.4(A) RN408.1(A) RN408.2(A) U402.5 U3603.8 U3603.9
1D8V_S5: C1003.1 C1004.1 C1005.1 C1006.1 C1007.1 C1008.1 C1009.1 C1010.1 C1011.1 C3617.1 C8320.1 CPU1.B1 CPU1.B2 PG5010.2 PG5011.2 PG5012.2 PG5013.2 R627.2 R649.1 U3603.6 U3603.7 U8302.6 U8302.7
1D8V_S5_PWRGD: PR5011.2 PU5002.4
1D8V_VGA_S0: C7611.2 C7612.2 C7613.2 C7631.2 C8304.1 C8308.2 GPU1.AM30 L7504.1 L7601.1 L7703.1 L7704.1 L7707.1 PG8316.2 R7517.2 R7521.2 R7523.2 R7527.2
1D35V_ENABLE: PQ8314.3 PR8328.2 PR8347.2 PR8348.2
1D35V_ENABLE_RC: PC8322.1 PQ8318.4 PR8328.1
1D35V_PGOOD: PR4904.2 PU4901.20
1D35V_PWR: EC4601.1 PC4904.1 PC4920.1 PC4921.1 PC4923.1 PC4924.1 PC4925.1 PC4926.1 PG4907.2 PG4908.2 PG4909.2 PG4910.2 PG4911.2 PG4913.2 PG4914.2 PG4915.2 PG4916.2 PG4917.2 PG4918.2 PG4919.2 PL4902.2 PU4901.2
1D35V_S3: C1049.1 C1050.1 C1051.2 C1053.1 C1054.1 C1055.1 C1056.2 C1057.2 C1058.2 C1059.2 C1060.1 C1061.2 C1062.2 C1063.2 C1213.1 C1214.1 C1215.1 C1216.1 C1217.1 C1218.1 C1219.1 C1220.1 C1222.1 C1223.1 C1224.1 C1225.1 CPU1.AA31 CPU1.AA35 CPU1.AC32 CPU1.AC37 CPU1.AE31 CPU1.AE35 CPU1.AG32 CPU1.AG37 CPU1.AJ35 CPU1.AL32 CPU1.AL37 CPU1.AR35 CPU1.J35 CPU1.L32 CPU1.L37 CPU1.N35 CPU1.R31 CPU1.R37 CPU1.U32 CPU1.U35 CPU1.W31 CPU1.W32 CPU1.W37 DM1.75 DM1.76 DM1.81 DM1.82 DM1.87 DM1.88 DM1.93 DM1.94 DM1.99 DM1.100 DM1.105 DM1.106 DM1.111 DM1.112 DM1.117 DM1.118 DM1.123 DM1.124 PC8323.1 PG4908.1 PG4909.1 PG4910.1 PG4911.1 PG4913.1 PG4914.1 PG4915.1 PG4916.1 PG4917.1 PG4918.1 PG4919.1 PQ8318.5 PQ8318.6 PQ8318.7 PQ8318.8 R503.1 R504.1
1D35V_VGA_EN: PD8307.A PQ8314.2 PR8345.2
1D35V_VGA_EN#: PQ8314.5 PQ8314.6 PQ8317.G PR8341.2
1D35V_VGA_S0: C7602.2 C7607.2 C7608.2 C7609.2 C7610.2 C7623.2 C7624.2 C7625.2 C7801.1 C7808.1 C7810.1 C7811.1 C7812.1 C7813.1 C7814.1 C7816.1 C7817.1 C7818.1 C7819.1 C8905.1 C8908.1 C8910.1 C8911.1 C8912.1 C8913.1 C8914.1 C8915.1 C8920.1 C8922.1 C8923.1 EC9725.1 EC9726.1 EC9727.1 EC9728.1 EC9729.1 EC9730.1 EC9731.1 GPU1.H13 GPU1.H16 GPU1.H19 GPU1.J9 GPU1.J10 GPU1.J23 GPU1.J24 GPU1.K9 GPU1.K10 GPU1.K23 GPU1.K24 GPU1.L11 GPU1.L12 GPU1.L13 GPU1.L20 GPU1.L21 GPU1.L22 PC8321.1 PQ8318.1 PQ8318.2 PQ8318.3 PR8344.1 R7401.1 R7409.1 R7410.1 R7411.1 R7805.1 R8901.1 VRAM1.A1 VRAM1.A8 VRAM1.B2 VRAM1.C1 VRAM1.C9 VRAM1.D2 VRAM1.D9 VRAM1.E9 VRAM1.F1 VRAM1.G7 VRAM1.H2 VRAM1.H9 VRAM1.K2 VRAM1.K8 VRAM1.N1 VRAM1.N9 VRAM1.R1 VRAM1.R9 VRAM2.A1 VRAM2.A8 VRAM2.B2 VRAM2.C1 VRAM2.C9 VRAM2.D2 VRAM2.D9 VRAM2.E9 VRAM2.F1 VRAM2.G7 VRAM2.H2 VRAM2.H9 VRAM2.K2 VRAM2.K8 VRAM2.N1 VRAM2.N9 VRAM2.R1 VRAM2.R9 VRAM3.A1 VRAM3.A8 VRAM3.B2 VRAM3.C1 VRAM3.C9 VRAM3.D2 VRAM3.D9 VRAM3.E9 VRAM3.F1 VRAM3.G7 VRAM3.H2 VRAM3.H9 VRAM3.K2 VRAM3.K8 VRAM3.N1 VRAM3.N9 VRAM3.R1 VRAM3.R9 VRAM4.A1 VRAM4.A8 VRAM4.B2 VRAM4.C1 VRAM4.C9 VRAM4.D2 VRAM4.D9 VRAM4.E9 VRAM4.F1 VRAM4.G7 VRAM4.H2 VRAM4.H9 VRAM4.K2 VRAM4.K8 VRAM4.N1 VRAM4.N9 VRAM4.R1 VRAM4.R9
3D3V_AUX_KBC: D4301.2 D4302.2 D4303.2 PR4412.1 PR4415.1 PR4439.1 Q2402.D R2402.1 R2403.2 R2413.2 R2414.2 R2418.2 R2426.2 R2434.1 R2436.1 R2622.1 RN401.3(B) RN401.4(B) RN2401.1(A) RN2401.2(A)
3D3V_AUX_KBC_VCC: C2406.1 C2407.1 C2408.1 C2409.1 C2410.1 C2411.1 KBC24.19 KBC24.46 KBC24.76 KBC24.88 KBC24.115 R2403.1
3D3V_AUX_S5: C2417.2 D2501.1 KBC24.75 PR4417.1 PR4419.1 PR4434.1 PR4435.1 PR4438.2 PR4510.2 PR8313.1 PR8341.1 Q2402.S R2425.2 R2431.2 R2434.2 R2439.1 R2611.1 RN602.3(B) RN602.4(B)
3D3V_CAMERA_S0: AFTP5227.1 C5207.1 CCD1.1 EC5210.1 LCD1.32 R5229.2
3D3V_LAN_S5: C3003.1 C3004.1 C3005.1 C3007.1 C3008.1 C3017.1 LOM30.11 LOM30.32 Q3004.D R3006.1 RN3001.1(A) RN3001.2(A)
3D3V_PWR: PC4510.1 PG4153.1 PG4513.1 PG4522.1 PG4523.1 PG4525.1 PG4526.1 PG4530.1 PL4501.1 PT4501.1
3D3V_PWR_2: PC4516.1 PR4510.1 PU4501.15
3D3V_S0: C1022.1 C1023.1 C1024.1 C1201.1 C1202.1 C2412.1 C2413.1 C2601.1 C2602.1 C2716.1 C2717.1 C3603.1 C3612.1 C5204.1 C5802.1 C5803.1 C5804.1 CPU1.AM15 CPU1.AM17 DB1.1 DM1.199 EC9735.1 EC9736.1 EC9737.1 EC9738.1 HDA27.1 IOBD1.5 KBC24.4 PC8324.1 PQ8320.S PR3622.1 PR4651.1 PR4652.1 PR8351.1 PR8352.2 Q403.2 Q403.5 Q2601.2 Q2601.5 Q5401.C Q5402.2 Q5402.5 Q6202.2 Q6202.5 R428.2 R601.2 R603.2 R604.2 R635.2 R636.2 R637.2 R638.2 R639.2 R642.1 R2401.2 R2412.2 R2415.2 R2441.2 R2443.2 R2603.1 R2604.1 R2624.1 R2701.1 R2925.1 R3003.1 R3004.1 R3014.1 R3624.1 R3625.1 R5208.1 R5229.1 R5231.1 R5808.1 R6209.1 RN402.3(B) RN402.4(B) RN405.1(A) RN405.2(A) RN405.3(A) RN405.4(A) RN601.1(A) RN601.2(A) RN2602.1(A) RN2602.2(A) RN5601.1(A) RN5601.2(A) RN6201.3(B) RN6201.4(B) THM26.1 U3601.8 U3601.9 U3602.1 U5201.4 U5201.5 WLAN1.2 WLAN1.24 WLAN1.39 WLAN1.41 WLAN1.52
3D3V_S5: C1001.1 C1002.1 C2501.1 C2502.1 C3013.1 C3015.1 C6402.1 CPU1.AL13 CPU1.AM13 LIDSW1.2 PD4203.2 PG4513.2 PG4522.2 PG4523.2 PG4525.2 PG4526.2 PG4530.2 PG5009.1 PG5014.1 PR4204.1 PR4211.2 PR4473.2 PR4509.1 PR4835.1 PR4904.1 PR5011.1 Q3004.S R608.2 R617.2 R626.2 R630.2 R634.2 R648.1 R1911.1 R1913.1 R1915.1 R1918.2 R1920.1 R1927.2 R1929.2 R2421.2 R2429.2 R2501.2 R2712.2 R3021.1 R3033.2 R5610.2 RN603.3(B) RN603.4(B) RN604.1(A) RN604.2(A) RN604.3(A) RN604.4(A) RN1904.3(B) RN1904.4(B) RN2501.3(B) RN2501.4(B) SPI25.8 U3601.6 U3601.7
3D3V_VGA_OUT1: PG8316.1 U8302.8 U8302.9
3D3V_VGA_S0: L7603.1 PC8217.1 PQ8320.D PR8237.1 PR8246.1 PR8248.1 PR8250.1 PR8251.1 PR8252.1 PR8253.1 PR8254.1 PR8350.2 PR8351.2 Q7503.2 Q7503.5 Q7504.G R7301.2 R7304.2 R7305.2 R7311.2 R7314.2 R7315.2 R7322.2 R7324.2 R7325.2 R7327.1 R7424.2 R7510.2 R7533.1 RN7501.1(A) RN7501.2(A) U8201.5
32K_X1: C603.1 CPU1.AJ2 R623.1 X601.4
32K_X2: C604.1 CPU1.AJ1 R623.2 X601.1
48M_X1: C1904.2 CPU1.N2 R1905.1 X1902.3
48M_X2: C1905.2 CPU1.N1 R1905.2 X1902.1
8179A_EN/DEM_VGA: PC8213.1 PC8219.1 PD8201.A PQ8305.2 PR8246.2 PU8202.29
51123_PGOOD_2: Q601.5 Q601.6 RN602.1(A)
+0D675V_DDR_P: PC4915.1 PC4916.1 PC4917.1 PG4901.2 PG4902.2 PU4901.1 PU4901.3
+DC_IN: AFTP3801.1 AFTP3805.1 DCIN1.1 DCIN1.2 DCIN1.3 PC4201.1 PC4202.1 PD4201.K PQ4205.E PR4207.1 PR4212.1 PR4214.1 PU4201.1 PU4201.2 PU4201.3
+PWR_SRC_1D35V: PC4909.1 PC4911.1 PC4912.1 PC4913.2 PC4914.1 PG4903.1 PG4904.1 PG4905.1 PG4906.1 PU4902.5 PU4902.6 PU4902.7 PU4902.8
+RTC_VCC: AFTP2502.1 R2502.2 RTC1.1
A_BA0: GPU1.J16 VRAM1.M2 VRAM2.M2 VRAM3.M2 VRAM4.M2
A_BA1: GPU1.L15 VRAM1.N8 VRAM2.N8 VRAM3.N8 VRAM4.N8
A_BA2: GPU1.G11 VRAM1.M3 VRAM2.M3 VRAM3.M3 VRAM4.M3
AC_IN#: PC4401.1 PQ4408.5 PR4425.2 PR4433.1 PR4434.2 PU4404.5 R2413.1 R2430.1
AC_IN#_G: PQ4206.2 PR4212.2 PR4213.1
AC_IN_KBC#: KBC24.65 PQ4206.6 R2426.1
AC_PRESENT: CPU1.AP15 KBC24.84 R617.1
AD+: PC4203.1 PC4204.1 PC4205.1 PC4206.1 PR4404.1 PR4405.1 PR4407.1 PR4408.1 PR4469.1 PU4201.5 PU4201.6 PU4201.7 PU4201.8 PU4402.5 PU4402.6 PU4402.7 PU4402.8 PU4403.4
AD+_G_1: PQ4402.5 PQ4402.6 PR4401.1
AD+_G_2: PR4401.2 PR4403.2 PU4402.4
AD+_TO_SYS: PG4402.1 PR4402.1 PR4403.1 PU4402.1 PU4402.2 PU4402.3
AD_IA: C2414.2 KBC24.97 PR4422.2
AD_IA_HW: KBC24.105 PQ4407.5
AD_IA_HW2: KBC24.25 PQ4407.2
AD_OFF_L: PQ4204.C PQ4205.B
AD_OFF_R: PC4201.2 PC4208.1 PQ4205.C PR4207.2 PR4208.1 PU4201.4
ALERT#: R2603.2 THM26.6
ALL_SYS_PWRGD: KBC24.10 R3604.2
AMBER_LED_BAT: EC6105.1 Q6104.3 R6103.2
AMP_MUTE#: KBC24.30 R2708.1
APU_ALERT#: CPU1.B18 RN405.8(B)
APU_DBRDY: CPU1.B25 HDT1.14
APU_DBREQ#: CPU1.A25 HDT1.16 R434.2
APU_DIGON: CPU1.A17 R404.1
APU_LPC_AD0: CPU1.AT2 RN1901.5(B)
APU_LPC_AD1: CPU1.AT1 RN1901.6(B)
APU_LPC_AD2: CPU1.AR2 RN1901.7(B)
APU_LPC_AD3: CPU1.AR1 RN1901.8(B)
APU_PWROK: CPU1.B19 R414.2 R418.2 U402.3
APU_PWROK_C: C402.1 R414.1
APU_PWROK_HDT: HDT1.10 RN408.3(B) U402.4
APU_RST#: CPU1.B20 R409.2 R421.2 U402.1
APU_RST#_C: C401.1 R409.1
APU_RST_L_BUF: HDT1.12 RN408.4(B) U402.6
APU_SIC: CPU1.B22 Q403.1 RN405.5(B) RN2601.1(A)
APU_SID: CPU1.B21 Q403.4 RN405.7(B) RN2601.2(A)
APU_SPI_CLK: CPU1.AU7 R1925.1
APU_SPI_CS0#: CPU1.AW9 R1908.1
APU_SPI_HOLD#: CPU1.AU11 R1923.1
APU_SPI_SI_R: CPU1.AR11 R1921.1
APU_SPI_SO_R: CPU1.AR7 R1922.1
APU_SPI_WP#: CPU1.AU9 R1924.1
APU_SVC: CPU1.D27 PR4625.1 PR4655.2 PR4681.1 RN407.7(B)
APU_SVD: CPU1.E29 PR4628.1 PR4654.2 PR4663.1 RN407.6(B)
APU_SVT: CPU1.G31 PR4630.1 PR4653.2 RN407.5(B)
APU_TCK: CPU1.D35 HDT1.2 RN404.1(A)
APU_TDI: CPU1.D29 HDT1.6 RN404.4(A)
APU_TDO: CPU1.D31 HDT1.8
APU_TEST0: CPU1.AU13 R647.2
APU_TEST1: CPU1.AY10 R646.2
APU_TEST2: CPU1.AY6 R645.2
APU_TEST6_DIRECRACKMON: CPU1.D25 TP403.1
APU_TEST14_BP0: CPU1.A27 R410.1
APU_TEST15_BP1: CPU1.B27 TP404.1
APU_TEST16_BP2: CPU1.A26 R411.1
APU_TEST17_BP3: CPU1.B26 R413.1
APU_TEST18_PLLTEST1: CPU1.B28 HDT1.20 R415.1
APU_TEST19_PLLTEST0: CPU1.A28 HDT1.18 R416.1
APU_TEST28_H_PLLCHRZ: CPU1.AV35 TP410.1
APU_TEST28_L_PLLCHRZ: CPU1.AU35 TP411.1
APU_TEST31_M_TEST: CPU1.E33 TP409.1
APU_TEST36_FREE_2: CPU1.H21 R422.1 R423.1
APU_TEST37_FREE_2: CPU1.H25 R424.1 R425.1
APU_THERMDA: CPU1.H27 TP401.1
APU_THERMDC: CPU1.H29 TP402.1
APU_TMS: CPU1.D33 HDT1.4 RN404.2(A)
APU_TRST#: CPU1.G27 HDT1.9 RN404.3(A)
APU_VDD: C1077.1 C1078.1 C1079.1 C1080.1 C1081.1 C1082.1 C1083.1 C1084.1 C1085.1 C1086.1 C1087.1 C1088.1 C1089.1 C1090.1 C1091.1 CPU1.AA21 CPU1.AA23 CPU1.AA27 CPU1.AC21 CPU1.AC23 CPU1.AC27 CPU1.AE21 CPU1.AE23 CPU1.AE27 CPU1.L21 CPU1.L23 CPU1.L25 CPU1.L27 CPU1.L29 CPU1.N21 CPU1.N23 CPU1.N27 CPU1.R21 CPU1.R23 CPU1.R27 CPU1.U21 CPU1.U23 CPU1.U27 CPU1.W21 CPU1.W23 CPU1.W27 PG4702.2 PL4701.2 PR4627.2 PT4701.1 PT4702.1
APU_VDD_RUN_FB_H: CPU1.G23 PR4626.2 PR4627.1 TP434.1
APU_VDD_RUN_FB_L: CPU1.E23 PR4615.2 PR4632.2 PR4633.1
APU_VDDNB: C1064.1 C1065.1 C1066.1 C1067.1 C1068.1 C1069.1 C1070.1 C1071.1 C1072.1 C1073.1 C1074.1 C1075.1 C1076.1 CPU1.AA13 CPU1.AA17 CPU1.AC13 CPU1.AC17 CPU1.AE15 CPU1.AE17 CPU1.AE19 CPU1.AG17 CPU1.AG21 CPU1.L13 CPU1.L17 CPU1.N11 CPU1.N13 CPU1.N17 CPU1.R11 CPU1.R13 CPU1.R17 CPU1.U13 CPU1.U17 CPU1.W13 CPU1.W17 PG4719.2 PL4702.2 PR4612.1 PT4703.1 PT4704.1
APU_VDDNB_RUN_FB_H: CPU1.D23 PR4612.2 PR4613.2 TP433.1
ATI_RST#: D7301.3 PR8275.2 R7320.2 R7326.1 R7327.2 U8201.1
ATI_RST#_R: C7333.1 GPU1.AL27 R7320.1
AUD_AGND: AFTP2908.1 C2701.2 C2702.1 C2705.1 C2710.2 C2711.2 C2712.1 C2713.2 C2715.2 C2902.2 EC2703.1 EC2704.1 EC2705.1 EC2706.1 EC2707.1 EC2905.2 EC2906.2 EC2907.2 EC2908.2 EC9739.1 EC9743.1 EC9744.1 EC9745.1 HDA27.25 HDA27.38 HPMIC1.MS Q2901.S R2706.1 R2707.2 R2711.1 R2905.2 R2919.2 R2920.2 R2924.2 U2901.4
AUD_HP1_JACK_L: HDA27.32 R2908.1
AUD_HP1_JACK_L1: EC2907.1 R2907.2 R2908.2 R2912.2 R2919.1 R2922.2
AUD_HP1_JACK_R: HDA27.33 R2910.1
AUD_HP1_JACK_R1: EC2908.1 R2909.2 R2910.2 R2913.2 R2920.1 R2921.2
AUD_PC_BEEP: C2720.2 HDA27.12
AUD_PC_BEEP_C: C2720.1 D2701.3 R2717.1
AUD_PORTA_L_R_B: AFTP2906.1 ED2902.1 HPMIC1.1 R2907.1
AUD_PORTA_R_R_B: AFTP2907.1 ED2901.1 HPMIC1.2 R2909.1
AUD_SENSE: AFTP2909.1 ED2904.1 Q2901.D R2709.2 R2914.2
AUD_SENSE_A: HDA27.13 R2709.1 R2722.2
AUD_SPK_L+: EC2902.1 HDA27.42 R2902.2
AUD_SPK_L+_C: AFTP2902.1 R2902.1 SPK1.3
AUD_SPK_L-: EC2901.1 HDA27.43 R2901.2
AUD_SPK_L-_C: AFTP2901.1 R2901.1 SPK1.4
AUD_SPK_R+: EC2904.1 HDA27.45 R2904.2
AUD_SPK_R+_C: AFTP2904.1 R2904.1 SPK1.1
AUD_SPK_R-: EC2903.1 HDA27.44 R2903.2
AUD_SPK_R-_C: AFTP2903.1 R2903.1 SPK1.2
AUD_VREF: C2705.2 HDA27.28
BAT_ALERT: AFTP3901.1 BAT1.7
BAT_AMBER: IOBD1.14 R6103.1
BAT_IN#: D4302.3 EC4305.2 KBC24.80 PC4210.2 PQ4203.2 PR4215.2 PR4216.1 R2414.1 RN4301.1(A)
BAT_SCL: D4301.3 EC4301.1 KBC24.70 PG4407.2 PR4415.2 RN2401.3(B) RN4301.3(A)
BAT_SDA: D4303.3 EC4302.1 KBC24.69 PG4408.2 PR4412.2 RN2401.4(B) RN4301.2(A)
BAT_WHITE: IOBD1.15 R6101.1
BATT_WHITE_LED#: KBC24.62 R6105.2
BATT_WHITE_LED_R#: Q6103.2 R6105.1
BKLT_CTRL: D5202.K R5222.1 RN5201.7(B) RN5203.8(B)
BLINK: CPU1.AU17 R1928.1 R1929.1
BLON_OUT: KBC24.27 RN5201.6(B)
BLON_OUT_C: AFTP5205.1 LCD1.21 RN5201.3(A) RN5203.7(B)
BLUETOOTH_EN: CPU1.AP27 R635.1 R5805.1 R5806.2
BOOST_MODE#: KBC24.20 PR4418.1 PR4435.2 PR4439.2
BT+: AFTP3905.1 AFTP3907.1 AFTP3908.1 BAT1.1 BAT1.2 EC4303.1 EC4304.1 PC4415.1 PC4416.1 PC4417.1 PC4418.1 PC4419.1 PD4302.K PG4410.2 PR4416.2 PU4403.5 PU4403.6 PU4403.7 PU4403.8
BT+_R: PG4409.2 PL4401.2 PR4416.1
BT_ACT: R5806.1 WLAN1.5
BYPASSCLK_H: CPU1.B24 R419.1
BYPASSCLK_L: CPU1.A24 R420.1
CAM1_MIC_GND: CCD1.5 R5207.1
CAP_LED: KB1.4 KB2.4 R6201.2
CAP_LED#: KBC24.109 R6202.1
CAP_LED_Q: Q6201.3 R6201.1
CAP_LED_R#: Q6201.2 R6202.2
CARD_WLAN_OUT#: KBC24.83 TP2401.1
CARD_WPAN_OUT#: KBC24.100 TP2402.1
CASA0#: GPU1.G19 VRAM1.K3 VRAM2.K3
CASA1#: GPU1.G16 VRAM3.K3 VRAM4.K3
CBN: C2703.1 HDA27.35
CBP: C2703.2 HDA27.37
CEDAR_JANUS_ID: CPU1.AY21 R639.1 R640.2
CHARGER_SRC: EC4401.1 EC4402.1 PC4406.1 PC4408.1 PC4409.1 PC4426.1 PG4412.2 PG4413.2 PG4414.2 PG4415.2 PU4405.5 PU4405.6 PU4405.7 PU4405.8
CHG_AGND: PC4010.2 PC4403.2 PC4404.2 PC4412.2 PC4420.2 PC4422.2 PC4423.2 PG4411.1 PQ4407.1 PQ4407.4 PR4413.2 PR4423.2 PR4424.2 PR4431.2 PU4404.21
CHG_AMBER_LED#: KBC24.16 R6104.2
CHG_AMBER_LED_R#: Q6104.2 R6104.1
CKEA0: GPU1.K20 VRAM1.K9 VRAM2.K9
CKEA1: GPU1.J17 VRAM3.K9 VRAM4.K9
CLK_LAN_REQ0#_R: LOM30.12 Q3002.E R3004.2 R3005.2
CLK_LAN_REQ#_EN: Q3002.B R3003.2
CLK_MINI1#_R: CPU1.AE5 RN1902.4
CLK_MINI1_R: CPU1.AE4 RN1902.3
CLK_PCI_KBC: KBC24.2 R1906.2
CLK_PCI_LPC: DB1.9 R1907.2
CLK_PCIE_LAN_N0: LOM30.16 RN1903.1
CLK_PCIE_LAN_N0_R: CPU1.AC10 RN1903.4
CLK_PCIE_LAN_P0: LOM30.15 RN1903.2
CLK_PCIE_LAN_P0_R: CPU1.AC8 RN1903.3
CLK_PCIE_LAN_REQ0#: CPU1.AU29 Q3002.C R3005.1
CLK_PCIE_VGA: GPU1.AK30 RN1905.2
CLK_PCIE_VGA#: GPU1.AK32 RN1905.1
CLK_PCIE_WLAN_N1: RN1902.1 WLAN1.11
CLK_PCIE_WLAN_P1: RN1902.2 WLAN1.13
CLK_PCIE_WLAN_REQ1#: CPU1.AW29 R5808.2 WLAN1.7
CLKA0: GPU1.H26 R7803.1 VRAM1.J7 VRAM2.J7
CLKA0#: GPU1.H25 R7804.1 VRAM1.K7 VRAM2.K7
CLKA1: GPU1.G9 R8908.1 VRAM3.J7 VRAM4.J7
CLKA1#: GPU1.H9 R8907.1 VRAM3.K7 VRAM4.K7
CLKREQG#: CPU1.AY29 R610.2
CLKTESTA: C7406.1 GPU1.K8
CLKTESTA_C: C7406.2 R7419.1
CLKTESTB: C7407.1 GPU1.L7
CLKTESTB_C: C7407.2 R7418.1
CODEC_BITCLK_R: HDA27.6 R2720.2
CODEC_SDOUT_R: HDA27.5 R2719.2
COMBO-GPI: HDA27.48 TP2702.1
CPVEE: C2704.2 HDA27.34
CSA0#_0: GPU1.H22 VRAM1.L2 VRAM2.L2
CSA1#_0: GPU1.G13 VRAM3.L2 VRAM4.L2
DAC_BLUE: CPU1.B15 R408.1
DAC_GREEN: CPU1.A14 R406.1
DAC_HSYNC: CPU1.G19 R428.1
DAC_RED: CPU1.B14 R405.1
DAC_ZVSS: CPU1.A16 R407.1
DBC_EN: CPU1.AY28 R601.1 R2449.2
DBC_EN_R: LCD1.8 R2449.1
DBRDY1: HDT1.15 RN6502.1(A)
DBRDY2: HDT1.13 RN6502.2(A)
DBRDY3: HDT1.11 RN6502.3(A)
DC_IN_D: PQ4402.3 PR4404.2
DCBATOUT: EC9701.1 EC9703.1 EC9704.1 EC9705.1 EC9707.1 EC9708.1 EC9709.1 EC9710.1 EC9711.1 EC9712.1 EC9713.1 EC9714.1 EC9715.1 EC9716.1 EC9717.1 EC9740.1 EC9741.1 EC9742.1 EC9747.1 EC9748.1 EC9749.1 F5201.1 PC4517.1 PC4518.1 PD4505.2 PG4403.1 PG4412.1 PG4413.1 PG4414.1 PG4415.1 PG4502.2 PG4503.2 PG4504.2 PG4505.2 PG4515.2 PG4516.2 PG4517.2 PG4518.2 PG4519.2 PG4520.2 PG4521.2 PG4703.2 PG4704.2 PG4707.2 PG4708.2 PG4709.2 PG4710.2 PG4711.2 PG4712.2 PG4716.2 PG4717.2 PG4718.2 PG4827.2 PG4834.2 PG4837.2 PG4838.2 PG4903.2 PG4904.2 PG4905.2 PG4906.2 PG8203.2 PG8204.2 PG8205.2 PG8206.2 PG8207.2 PG8208.2 PG8209.2 PG8210.2 PR4402.2 PR4468.1 PR4511.1 PR4520.1 PR4666.2 PR4667.1 PR8205.2 PR8348.1 PT4705.1 PU4403.1 PU4403.2 PU4403.3 PU4501.11
DCBATOUT_LCD: AFTP5204.1 C5202.1 C5205.2 F5201.2 LCD1.1 LCD1.2
DDC_CLK_HDMI: HDMI1.15 Q5402.3 RN5401.2(A) RN5404.4(B)
DDC_CLK_PH1: D5401.2 RN5401.3(B)
DDC_DATA_HDMI: HDMI1.16 Q5402.6 RN5401.1(A) RN5404.3(B)
DDC_DATA_PH2: D5401.1 RN5401.4(B)
DDR3_DRAMRST#: C1221.1 CPU1.G38 DM1.30
DDR_VREF_S3: C501.1 C502.1 C1203.1 C1204.1 C1205.1 CPU1.AC38 CPU1.AD40 DM1.1 DM1.126 PR4911.2
DDR_VTT_PG_CTRL_R: PR4910.1 PU4901.17
DEBUG: R5807.2 WLAN1.49
DGPU_PRESENT#: CPU1.BA26 R642.2 R643.1
DGPU_PWR_EN#: PQ8305.5 PQ8305.6 PR8313.2
DGPU_PWROK: KBC24.63 PR8273.2 PR8345.1 R631.2 U8201.2
DGPU_PWROK_R: C605.1 CPU1.AP23 R631.1
DIS_1D35V_VGA_S0: PQ8317.D PR8344.2
DMIC_CLK: C2723.2 EC5206.1 R2716.1 RN5202.4(B) RN5204.3(B)
DMIC_CLK_C: AFTP5222.1 CCD1.3 RN5202.1(A)
DMIC_CLK_EDP: LCD1.27 RN5204.2(A)
DMIC_CLK_R: HDA27.3 R2716.2
DMIC_DATA: EC5205.1 R2714.1 RN5202.3(B) RN5204.4(B)
DMIC_DATA_C: AFTP5228.1 CCD1.4 RN5202.2(A)
DMIC_DATA_EDP: LCD1.28 RN5204.1(A)
DMIC_DATA_R: EC2701.1 HDA27.2 R2714.2
DP_2K_ZVSS: CPU1.A21 R402.1
DP_150_ZVSS: CPU1.B16 R401.1
DPEF_CALR: GPU1.AF17 R7710.1
DPLL_PVDD: C7787.2 C7788.2 C7792.2 GPU1.AF14 L7707.2
DPLL_VDDC: C7790.2 C7791.2 C7793.2 GPU1.AD14 L7706.2
DQMA0: GPU1.E32 VRAM1.E7
DQMA1: GPU1.E30 VRAM1.D3
DQMA2: GPU1.A21 VRAM2.D3
DQMA3: GPU1.C21 VRAM2.E7
DQMA4: GPU1.E13 VRAM3.E7
DQMA5: GPU1.D12 VRAM4.D3
DQMA6: GPU1.E3 VRAM3.D3
DQMA7: GPU1.F4 VRAM4.E7
DRAM_RST: GPU1.L10 R7404.2 R7420.1
DRAM_RST_R: C7401.2 R7402.1 R7420.2
E51_RX: TP5802.1 WLAN1.17
E51_TX: R5804.2 WLAN1.19
E51_TXD: KBC24.111 R5804.1
EAPD#: HDA27.47 R2708.2
EC_AGND: C2402.1 C2403.1 C2404.2 C2405.2 C2414.1 KBC24.103 R2406.2 R2407.2 R2435.1
EC_BRIGHTNESS: D5202.A KBC24.32
EC_SCI#: CPU1.AN5 R2408.1
EC_SMI#: CPU1.AL7 R2409.1
EC_SPI_CLK_C: KBC24.92 R2420.2
EC_SPI_CS#_C: KBC24.90 R2419.2
EC_SPI_DI_C: KBC24.87 R2422.2
EC_SPI_DO_C: KBC24.86 R2423.2
EC_SWI#: CPU1.BA9 R608.1 R2410.1
EC_VBKUP: KBC24.114 R2428.1
ECRST#: C2418.1 KBC24.85 Q2404.E R2418.1 R2424.2
ECSCI#_KBC: KBC24.29 R2408.2
ECSMI#_KBC: KBC24.6 R2409.2
ECSWI#_KBC: KBC24.123 R2410.2
EDP_AUX: AFTP5206.1 C5212.2 LCD1.11
EDP_AUX#: AFTP5208.1 C5209.2 LCD1.12
EDP_AUX_DN: C5209.1 CPU1.E15
EDP_AUX_DP: C5212.1 CPU1.D15
EDP_BKLT_CTRL: R5206.2 R5222.2
EDP_HPD: CPU1.H17 R5233.2 RN5203.6(B)
EDP_HPD_CONN: AFTP5201.1 LCD1.9 R5233.1
EDP_TX0: AFTP5210.1 C5210.2 LCD1.15
EDP_TX0#: AFTP5213.1 C5203.2 LCD1.14
EDP_TX0_DN: C5203.1 CPU1.B4
EDP_TX0_DP: C5210.1 CPU1.A4
EDP_TX1: AFTP5212.1 C5213.2 LCD1.18
EDP_TX1#: AFTP5211.1 C5211.2 LCD1.17
EDP_TX1_DN: C5211.1 CPU1.B5
EDP_TX1_DP: C5213.1 CPU1.A5
EDP_VDD_EN: D401.1 D5201.1 R404.2
FAN1_DAC_1: FAN261.4 KBC24.101
FAN_TACH1: EC2602.1 KBC24.31 R2415.1 R2606.1
FAN_TACH1_C: AFTP2802.1 FAN1.3 R2606.2
FAN_VCC1: AFTP2801.1 C2603.1 C2604.1 D2601.K EC2601.1 FAN1.1 FAN261.3
FCHGFX_CLKN_R: CPU1.U5 RN1905.4
FCHGFX_CLKP_R: CPU1.U4 RN1905.3
FON#: FAN261.1 R2605.2
GEVENT4#: CPU1.BA4 R620.1
GEVENT7#: CPU1.AR15 R621.1
GPIO5_AC_BATT: GPU1.T9 R7314.1
GPIO8_ROMSO: GPU1.P10 R7304.1
GPIO10_ROMSCK: GPU1.P2 TP7509.1
GPIO16_SSIN: GPU1.M4 TP7502.1
GPIO21_BB_EN: GPU1.P7 R7315.1
GPIO71: CPU1.AM21 R632.1
GPIO_17_THERMAL_INT: GPU1.R6 R7510.1 R7519.2
GPIO_19_CTF: GPU1.M2 R7501.2
GPIO_22_ROMCS#: GPU1.N8 TP7507.1
GPIO_VGA_03_DATA: GPU1.U8 Q7503.4 RN7501.4(B)
GPIO_VGA_04_CLK: GPU1.U7 Q7503.1 RN7501.3(B)
GPU_CLKA0_T: C7802.1 R7803.2 R7804.2
GPU_CLKA1_T: C8903.1 R8907.2 R8908.2
GPU_VGA_SVC: GPU1.P8 PR8270.2
GPU_VGA_SVD: GPU1.N1 PR8271.2
GPUTHER_ALERT#: KBC24.95 PR8274.2 R7519.1
GTXN0: C445.1 CPU1.G1
GTXN1: C457.1 CPU1.F1
GTXN2: C478.1 CPU1.E1
GTXN3: C448.1 CPU1.D1
GTXP0: C477.1 CPU1.G2
GTXP1: C447.1 CPU1.F2
GTXP2: C452.1 CPU1.E2
GTXP3: C441.1 CPU1.D2
H_A20GATE: CPU1.AR31 KBC24.121 R603.1
H_CPUPWRGD_REG: PR4624.1 PR4656.2 R418.1
H_PROCHOT#: C2421.1 CPU1.A22 PQ4203.3 PR4426.2 PR4466.2 PR4637.1 R2440.2 RN405.6(B)
H_PROCHOT#_EC: Q2401.D R2438.2 R2440.1
H_RCIN#: CPU1.AR23 KBC24.122 R2412.1
HDA_CODEC_BITCLK: EC2709.1 R616.2 R2720.1
HDA_CODEC_BITCLK_R: CPU1.AN2 R616.1
HDA_CODEC_RST#: HDA27.11 R614.1 R2917.2
HDA_CODEC_RST#_R: CPU1.AL1 R614.2
HDA_CODEC_SDIN0: HDA27.8 R2718.2
HDA_CODEC_SDOUT: EC2708.1 R612.1 R2719.1
HDA_CODEC_SDOUT_R: CPU1.AN1 R612.2
HDA_CODEC_SYNC: HDA27.10 R613.1
HDA_CODEC_SYNC_R: CPU1.AM2 R613.2
HDA_SDIN0: CPU1.AK2 R633.1 R2718.1
HDA_SPKR: CPU1.BA27 RN2701.2
HDA_SPKR_R: D2701.2 RN2701.3
HDMI_CLK: C5403.1 CPU1.A12
HDMI_CLK#: C5402.1 CPU1.B12
HDMI_CLK#_R: C5402.2 R5401.1 RN5403.7(B)
HDMI_CLK#_R_C: HDMI1.12 R5401.2 R5414.1
HDMI_CLK_R: C5403.2 R5402.1 RN5403.8(B)
HDMI_CLK_R_C: HDMI1.10 R5402.2 R5414.2
HDMI_DATA0: C5405.1 CPU1.A11
HDMI_DATA0#: C5404.1 CPU1.B11
HDMI_DATA0#_R: C5404.2 R5403.1 RN5403.5(B)
HDMI_DATA0#_R_C: HDMI1.9 R5403.2 R5416.1
HDMI_DATA0_R: C5405.2 R5404.1 RN5403.6(B)
HDMI_DATA0_R_C: HDMI1.7 R5404.2 R5416.2
HDMI_DATA1: C5406.1 CPU1.A10
HDMI_DATA1#: C5409.1 CPU1.B10
HDMI_DATA1#_R: C5409.2 R5407.1 RN5402.7(B)
HDMI_DATA1#_R_C: HDMI1.6 R5407.2 R5417.1
HDMI_DATA1_R: C5406.2 R5408.1 RN5402.8(B)
HDMI_DATA1_R_C: HDMI1.4 R5408.2 R5417.2
HDMI_DATA2: C5408.1 CPU1.A9
HDMI_DATA2#: C5407.1 CPU1.B9
HDMI_DATA2#_R: C5407.2 R5405.1 RN5402.5(B)
HDMI_DATA2#_R_C: HDMI1.3 R5405.2 R5415.1
HDMI_DATA2_R: C5408.2 R5406.1 RN5402.6(B)
HDMI_DATA2_R_C: HDMI1.1 R5406.2 R5415.2
HDMI_EN: CPU1.E21 R403.2
HDMI_HPD_B: Q5401.B R5411.2
HDMI_HPD_DET: GPU1.AC14 TP7501.1
HDMI_HPD_E: Q5401.E R5412.1 R5419.2
HDMI_PCH_DET: CPU1.H19 R5419.1
HDMI_PLL_GND: Q5403.D R5418.2 RN5402.1(A) RN5402.2(A) RN5402.3(A) RN5402.4(A) RN5403.1(A) RN5403.2(A) RN5403.3(A) RN5403.4(A)
HPD_HDMI_CON: HDMI1.19 R5410.1 R5411.1
IMVP_PWRGD: KBC24.107 PR4679.2 PR4680.2 Q2602.G
INT_SERIRQ: CPU1.AV29 KBC24.125 R2441.1
INT_TP#: AFTP6241.1 TPAD1.5
ISOLATE#: LOM30.20 R3014.2 R3015.1
JACK_PLUG: C2902.1 HPMIC1.5 Q2901.G R2905.1 R2914.1
JACK_PLUG_DET: HPMIC1.6 R2924.1 R2925.2
JDREF: HDA27.15 R2707.1
JTAG_TCK_VGA: GPU1.L3 R7323.1 TP7506.1
JTAG_TDI_VGA: GPU1.L5 R7325.1 TP7505.1
JTAG_TDO: GPU1.K4 TP7504.1
JTAG_TMS_VGA: GPU1.L1 R7324.1 TP7508.1
JTAG_TRST#_VGA: GPU1.L6 R7322.1 TP7503.1
KB_BL_CTRL: KBC24.22 Q6203.G R6208.1
KB_BL_CTRL#: AFTP6247.1 KBLIT1.4 Q6203.D
KB_DET#: AFTP6202.1 CPU1.BA28 KB1.30 KB2.30 R604.1
KB_LED_BL_DET: CPU1.AV21 R6206.1 R6207.1
KB_LED_DET_C: AFTP6246.1 C6203.1 KBLIT1.2 R6206.2
KBC_BEEP: KBC24.118 RN2701.1
KBC_BEEP_R: D2701.1 RN2701.4
KBC_ON#_GATE: C2417.1 Q2402.G Q2403.G R2433.2
KBC_ON#_GATE_L: R2431.1 R2432.2 R2433.1
KBC_PWRBTN#: R2427.1 R6102.1
KBC_PWRBTN#_C: AFTP6801.1 EC6104.1 R6102.2 SW1.4
KBC_VCORF: C2416.1 KBC24.44
KCOL0: AFTP6207.1 KB1.13 KB2.13 KBC24.53
KCOL1: AFTP6206.1 KB1.15 KB2.15 KBC24.52
KCOL2: AFTP6226.1 KB1.14 KB2.14 KBC24.51
KCOL3: AFTP6208.1 KB1.16 KB2.16 KBC24.50
KCOL4: AFTP6224.1 KB1.20 KB2.20 KBC24.49
KCOL5: AFTP6215.1 KB1.21 KB2.21 KBC24.48
KCOL6: AFTP6223.1 KB1.18 KB2.18 KBC24.47
KCOL7: AFTP6213.1 KB1.19 KB2.19 KBC24.43
KCOL8: AFTP6231.1 KB1.17 KB2.17 KBC24.42
KCOL9: AFTP6219.1 KB1.7 KB2.7 KBC24.41
KCOL10: AFTP6232.1 KB1.5 KB2.5 KBC24.40
KCOL11: AFTP6220.1 KB1.6 KB2.6 KBC24.39
KCOL12: AFTP6233.1 KB1.12 KB2.12 KBC24.38
KCOL13: AFTP6203.1 KB1.9 KB2.9 KBC24.37
KCOL14: AFTP6216.1 KB1.8 KB2.8 KBC24.36
KCOL15: AFTP6229.1 KB1.10 KB2.10 KBC24.35
KCOL16: AFTP6225.1 KB1.11 KB2.11 KBC24.34
KROW0: AFTP6228.1 KB1.22 KB2.22 KBC24.54
KROW1: AFTP6227.1 KB1.24 KB2.24 KBC24.55
KROW2: AFTP6218.1 KB1.26 KB2.26 KBC24.56
KROW3: AFTP6234.1 KB1.23 KB2.23 KBC24.57
KROW4: AFTP6230.1 KB1.27 KB2.27 KBC24.58
KROW5: AFTP6214.1 KB1.25 KB2.25 KBC24.59
KROW6: AFTP6222.1 KB1.28 KB2.28 KBC24.60
KROW7: AFTP6221.1 KB1.29 KB2.29 KBC24.61
L_BKLT_CTRL: CPU1.A18 R5206.1
L_BKLT_EN: CPU1.B17 R2444.1
L_BKLT_EN_EC: KBC24.9 R2444.2 R2445.1
LAN_ENABLE_R_C: Q3001.D R3021.2 R3022.1
LAN_MDI0N: EC3102.2 LOM30.2 U3101.2 U3101.9 XF3101.11
LAN_MDI0P: EC3101.2 LOM30.1 U3101.1 U3101.10 XF3101.12
LAN_MDI1N: EC3104.2 LOM30.5 U3101.5 U3101.6 XF3101.7
LAN_MDI1P: EC3103.2 LOM30.4 U3101.4 U3101.7 XF3101.8
LAN_MDI2N: EC3107.2 LOM30.7 U3102.2 U3102.9 XF3102.8
LAN_MDI2P: EC3108.2 LOM30.6 U3102.1 U3102.10 XF3102.7
LAN_MDI3N: EC3105.2 LOM30.10 U3102.5 U3102.6 XF3102.12
LAN_MDI3P: EC3106.2 LOM30.9 U3102.4 U3102.7 XF3102.11
LAN_TXN_C_PCH_RXN0: C3016.1 LOM30.18
LAN_TXP_C_PCH_RXP0: C3014.1 LOM30.17
LANXIN: C3001.1 LOM30.28 X3001.1
LANXOUT: C3011.1 LOM30.29 X3001.3
LCD_BRIGHTNESS: AFTP5203.1 LCD1.20 RN5201.2(A)
LCD_TST: R2417.2 RN5201.8(B)
LCD_TST_C: AFTP5207.1 LCD1.10 RN5201.1(A)
LCD_TST_EN: D5201.2 KBC24.28 R2417.1
LCDVDD: R5211.2 U5201.3
LCDVDD_EN: D5201.3 R5202.2 U5201.1
LCDVDD_LCD: AFTP5202.1 C5201.1 C5206.2 LCD1.4 LCD1.5 LCD1.6 LCD1.7 R5211.1
LDO1_CAP: C2702.2 HDA27.27 R2711.2
LDO2_CAP: C2712.2 HDA27.39
LDO3_CAP: C2718.1 HDA27.7
LDRQ0#: CPU1.AP1 TP1903.1
LED0: LOM30.27 TP3003.1
LED1: LOM30.26 TP3002.1
LED2: LOM30.25 TP3001.1
LID_CLOSE#: C6401.1 D2401.K KBC24.17 LIDSW1.3 R2421.1
LINE1-L_C: C2907.2 R2922.1
LINE1-L_R: C2908.2 R2921.1
LINE1_L: C2907.1 HDA27.22
LINE1_R: C2908.1 HDA27.21
LINE1_VREFO_L: HDA27.31 R2912.1
LINE1_VREFO_R: HDA27.30 R2913.1
LOM_TCT: C3106.1 XF3101.9 XF3101.10 XF3102.9 XF3102.10
LPC_AD0: KBC24.126 RN1901.4(A) RN6501.1(A)
LPC_AD1: KBC24.127 RN1901.3(A) RN6501.2(A)
LPC_AD2: KBC24.128 RN1901.2(A) RN6501.3(A)
LPC_AD3: KBC24.1 RN1901.1(A) RN6501.4(A)
LPC_FRAME#: KBC24.3 R1901.1 R1913.2 R1914.1 R6501.1
LPC_FRAME#_DEBUG: DB1.6 R6501.2
LPC_FRAME#_R: CPU1.AP2 R1901.2
LPC_LAD0_R: DB1.2 RN6501.8(B)
LPC_LAD1_R: DB1.3 RN6501.7(B)
LPC_LAD2_R: DB1.4 RN6501.6(B)
LPC_LAD3_R: DB1.5 RN6501.5(B)
LPC_PD#: CPU1.AV2 TP1901.1
LPC_RST#: R602.1 R2416.2 R6502.1
LPC_RST#_C: CPU1.AY4 R602.2
LPCCLK0: CPU1.AY2 R1906.1 R1911.2 R1919.1
LPCCLK1: CPU1.AW2 R1907.1 R1912.1 R1920.2
M_A_A0: CPU1.AG38 DM1.98
M_A_A1: CPU1.W35 DM1.97
M_A_A2: CPU1.W38 DM1.96
M_A_A3: CPU1.W34 DM1.95
M_A_A4: CPU1.U38 DM1.92
M_A_A5: CPU1.U37 DM1.91
M_A_A6: CPU1.U34 DM1.90
M_A_A7: CPU1.R35 DM1.86
M_A_A8: CPU1.R38 DM1.89
M_A_A9: CPU1.N38 DM1.85
M_A_A10: CPU1.AG34 DM1.107
M_A_A11: CPU1.R34 DM1.84
M_A_A12: CPU1.N37 DM1.83
M_A_A13: CPU1.AN34 DM1.119
M_A_A14: CPU1.L38 DM1.80
M_A_A15: CPU1.L35 DM1.78
M_A_BS0: CPU1.AJ38 DM1.109
M_A_BS1: CPU1.AG35 DM1.108
M_A_BS2: CPU1.N34 DM1.79
M_A_CAS#: CPU1.AL34 DM1.115
M_A_DM0: CPU1.B32 DM1.11
M_A_DM1: CPU1.B38 DM1.28
M_A_DM2: CPU1.G40 DM1.46
M_A_DM3: CPU1.N41 DM1.63
M_A_DM4: CPU1.AG40 DM1.136
M_A_DM5: CPU1.AN41 DM1.153
M_A_DM6: CPU1.AY40 DM1.170
M_A_DM7: CPU1.AY34 DM1.187
M_A_DQ<0>: CPU1.B30 DM1.5
M_A_DQ<1>: CPU1.A32 DM1.7
M_A_DQ<2>: CPU1.B35 DM1.15
M_A_DQ<3>: CPU1.A36 DM1.17
M_A_DQ<4>: CPU1.B29 DM1.4
M_A_DQ<5>: CPU1.A30 DM1.6
M_A_DQ<6>: CPU1.A34 DM1.16
M_A_DQ<7>: CPU1.B34 DM1.18
M_A_DQ<8>: CPU1.B37 DM1.21
M_A_DQ<9>: CPU1.A38 DM1.23
M_A_DQ<10>: CPU1.D40 DM1.33
M_A_DQ<11>: CPU1.D41 DM1.35
M_A_DQ<12>: CPU1.B36 DM1.22
M_A_DQ<13>: CPU1.A37 DM1.24
M_A_DQ<14>: CPU1.B41 DM1.34
M_A_DQ<15>: CPU1.C40 DM1.36
M_A_DQ<16>: CPU1.F40 DM1.39
M_A_DQ<17>: CPU1.F41 DM1.41
M_A_DQ<18>: CPU1.K40 DM1.51
M_A_DQ<19>: CPU1.K41 DM1.53
M_A_DQ<20>: CPU1.E40 DM1.40
M_A_DQ<21>: CPU1.E41 DM1.42
M_A_DQ<22>: CPU1.J40 DM1.50
M_A_DQ<23>: CPU1.J41 DM1.52
M_A_DQ<24>: CPU1.M41 DM1.57
M_A_DQ<25>: CPU1.N40 DM1.59
M_A_DQ<26>: CPU1.T41 DM1.67
M_A_DQ<27>: CPU1.U40 DM1.69
M_A_DQ<28>: CPU1.L40 DM1.56
M_A_DQ<29>: CPU1.M40 DM1.58
M_A_DQ<30>: CPU1.R40 DM1.68
M_A_DQ<31>: CPU1.T40 DM1.70
M_A_DQ<32>: CPU1.AF40 DM1.129
M_A_DQ<33>: CPU1.AF41 DM1.131
M_A_DQ<34>: CPU1.AK40 DM1.141
M_A_DQ<35>: CPU1.AK41 DM1.143
M_A_DQ<36>: CPU1.AE40 DM1.130
M_A_DQ<37>: CPU1.AE41 DM1.132
M_A_DQ<38>: CPU1.AJ40 DM1.140
M_A_DQ<39>: CPU1.AJ41 DM1.142
M_A_DQ<40>: CPU1.AM41 DM1.147
M_A_DQ<41>: CPU1.AN40 DM1.149
M_A_DQ<42>: CPU1.AT41 DM1.157
M_A_DQ<43>: CPU1.AU40 DM1.159
M_A_DQ<44>: CPU1.AL40 DM1.146
M_A_DQ<45>: CPU1.AM40 DM1.148
M_A_DQ<46>: CPU1.AR40 DM1.158
M_A_DQ<47>: CPU1.AT40 DM1.160
M_A_DQ<48>: CPU1.AV41 DM1.163
M_A_DQ<49>: CPU1.AW40 DM1.165
M_A_DQ<50>: CPU1.BA38 DM1.175
M_A_DQ<51>: CPU1.AY37 DM1.177
M_A_DQ<52>: CPU1.AU41 DM1.164
M_A_DQ<53>: CPU1.AV40 DM1.166
M_A_DQ<54>: CPU1.AY39 DM1.174
M_A_DQ<55>: CPU1.AY38 DM1.176
M_A_DQ<56>: CPU1.BA36 DM1.181
M_A_DQ<57>: CPU1.AY35 DM1.183
M_A_DQ<58>: CPU1.BA32 DM1.191
M_A_DQ<59>: CPU1.AY31 DM1.193
M_A_DQ<60>: CPU1.BA37 DM1.180
M_A_DQ<61>: CPU1.AY36 DM1.182
M_A_DQ<62>: CPU1.BA33 DM1.192
M_A_DQ<63>: CPU1.AY32 DM1.194
M_A_DQS_DN<0>: CPU1.A33 DM1.10
M_A_DQS_DN<1>: CPU1.A40 DM1.27
M_A_DQS_DN<2>: CPU1.H40 DM1.45
M_A_DQS_DN<3>: CPU1.P40 DM1.62
M_A_DQS_DN<4>: CPU1.AH40 DM1.135
M_A_DQS_DN<5>: CPU1.AP40 DM1.152
M_A_DQS_DN<6>: CPU1.AY41 DM1.169
M_A_DQS_DN<7>: CPU1.BA34 DM1.186
M_A_DQS_DP<0>: CPU1.B33 DM1.12
M_A_DQS_DP<1>: CPU1.B40 DM1.29
M_A_DQS_DP<2>: CPU1.H41 DM1.47
M_A_DQS_DP<3>: CPU1.P41 DM1.64
M_A_DQS_DP<4>: CPU1.AH41 DM1.137
M_A_DQS_DP<5>: CPU1.AP41 DM1.154
M_A_DQS_DP<6>: CPU1.BA40 DM1.171
M_A_DQS_DP<7>: CPU1.AY33 DM1.188
M_A_EVENT#: CPU1.AE34 DM1.198 R504.2
M_A_RAS#: CPU1.AJ37 DM1.110
M_A_WE#: CPU1.AL35 DM1.113
M_ANALOGIN: CPU1.R32 TP418.1
M_ANALOGOUT: CPU1.N32 TP420.1
M_B_DIM0_CKE0: CPU1.L34 DM1.73
M_B_DIM0_CKE1: CPU1.J38 DM1.74
M_B_DIM0_CLK_DDR0: CPU1.AC35 DM1.101
M_B_DIM0_CLK_DDR1: CPU1.AA34 DM1.102
M_B_DIM0_CLK_DDR#0: CPU1.AC34 DM1.103
M_B_DIM0_CLK_DDR#1: CPU1.AA32 DM1.104
M_B_DIM0_CS#0: CPU1.AJ34 DM1.114
M_B_DIM0_CS#1: CPU1.AR38 DM1.121
M_B_DIM0_ODT0: CPU1.AN38 DM1.116
M_B_DIM0_ODT1: CPU1.AU38 DM1.120
M_ZVDDIO: CPU1.AD41 R503.2
MAA0: GPU1.K17 VRAM1.N3 VRAM2.N3 VRAM3.N3 VRAM4.N3
MAA1: GPU1.J20 VRAM1.P7 VRAM2.P7 VRAM3.P7 VRAM4.P7
MAA2: GPU1.H23 VRAM1.P3 VRAM2.P3 VRAM3.P3 VRAM4.P3
MAA3: GPU1.G23 VRAM1.N2 VRAM2.N2 VRAM3.N2 VRAM4.N2
MAA4: GPU1.G24 VRAM1.P8 VRAM2.P8 VRAM3.P8 VRAM4.P8
MAA5: GPU1.H24 VRAM1.P2 VRAM2.P2 VRAM3.P2 VRAM4.P2
MAA6: GPU1.J19 VRAM1.R8 VRAM2.R8 VRAM3.R8 VRAM4.R8
MAA7: GPU1.K19 VRAM1.R2 VRAM2.R2 VRAM3.R2 VRAM4.R2
MAA8: GPU1.J14 VRAM1.T8 VRAM2.T8 VRAM3.T8 VRAM4.T8
MAA9: GPU1.K14 VRAM1.R3 VRAM2.R3 VRAM3.R3 VRAM4.R3
MAA10: GPU1.J11 VRAM1.L7 VRAM2.L7 VRAM3.L7 VRAM4.L7
MAA11: GPU1.J13 VRAM1.R7 VRAM2.R7 VRAM3.R7 VRAM4.R7
MAA12: GPU1.H11 VRAM1.N7 VRAM2.N7 VRAM3.N7 VRAM4.N7
MAA13: GPU1.G20 VRAM1.T3 VRAM2.T3 VRAM3.T3 VRAM4.T3
MAA14: GPU1.G14 VRAM1.T7 VRAM2.T7 VRAM3.T7 VRAM4.T7
MAA15: GPU1.L17 VRAM1.M7 VRAM2.M7 VRAM3.M7 VRAM4.M7
MCT: C3101.1 RN3101.5(B) RN3101.6(B) RN3101.7(B) RN3101.8(B)
MCT0: RN3101.1(A) XF3102.3
MCT1: RN3101.2(A) XF3102.4
MCT2: RN3101.3(A) XF3101.4
MCT3: RN3101.4(A) XF3101.3
MDA0: GPU1.K27 VRAM1.F8
MDA1: GPU1.J29 VRAM1.H8
MDA2: GPU1.H30 VRAM1.F7
MDA3: GPU1.H32 VRAM1.H7
MDA4: GPU1.G29 VRAM1.H3
MDA5: GPU1.F28 VRAM1.G2
MDA6: GPU1.F32 VRAM1.F2
MDA7: GPU1.F30 VRAM1.E3
MDA8: GPU1.C30 VRAM1.A7
MDA9: GPU1.F27 VRAM1.C8
MDA10: GPU1.A28 VRAM1.A3
MDA11: GPU1.C28 VRAM1.C3
MDA12: GPU1.E27 VRAM1.A2
MDA13: GPU1.G26 VRAM1.D7
MDA14: GPU1.D26 VRAM1.C2
MDA15: GPU1.F25 VRAM1.B8
MDA16: GPU1.A25 VRAM2.A3
MDA17: GPU1.C25 VRAM2.A2
MDA18: GPU1.E25 VRAM2.C2
MDA19: GPU1.D24 VRAM2.C3
MDA20: GPU1.E23 VRAM2.A7
MDA21: GPU1.F23 VRAM2.D7
MDA22: GPU1.D22 VRAM2.B8
MDA23: GPU1.F21 VRAM2.C8
MDA24: GPU1.E21 VRAM2.G2
MDA25: GPU1.D20 VRAM2.F2
MDA26: GPU1.F19 VRAM2.E3
MDA27: GPU1.A19 VRAM2.F7
MDA28: GPU1.D18 VRAM2.F8
MDA29: GPU1.F17 VRAM2.H3
MDA30: GPU1.A17 VRAM2.H8
MDA31: GPU1.C17 VRAM2.H7
MDA32: GPU1.E17 VRAM3.F8
MDA33: GPU1.D16 VRAM3.H7
MDA34: GPU1.F15 VRAM3.F7
MDA35: GPU1.A15 VRAM3.H8
MDA36: GPU1.D14 VRAM3.G2
MDA37: GPU1.F13 VRAM3.H3
MDA38: GPU1.A13 VRAM3.F2
MDA39: GPU1.C13 VRAM3.E3
MDA40: GPU1.E11 VRAM4.C3
MDA41: GPU1.A11 VRAM4.A3
MDA42: GPU1.C11 VRAM4.A2
MDA43: GPU1.F11 VRAM4.C2
MDA44: GPU1.A9 VRAM4.A7
MDA45: GPU1.C9 VRAM4.B8
MDA46: GPU1.F9 VRAM4.C8
MDA47: GPU1.D8 VRAM4.D7
MDA48: GPU1.E7 VRAM3.A7
MDA49: GPU1.A7 VRAM3.C8
MDA50: GPU1.C7 VRAM3.D7
MDA51: GPU1.F7 VRAM3.B8
MDA52: GPU1.A5 VRAM3.C3
MDA53: GPU1.E5 VRAM3.A2
MDA54: GPU1.C3 VRAM3.A3
MDA55: GPU1.E1 VRAM3.C2
MDA56: GPU1.G7 VRAM4.H3
MDA57: GPU1.G6 VRAM4.E3
MDA58: GPU1.G1 VRAM4.G2
MDA59: GPU1.G3 VRAM4.F2
MDA60: GPU1.J6 VRAM4.H8
MDA61: GPU1.J1 VRAM4.F8
MDA62: GPU1.J3 VRAM4.F7
MDA63: GPU1.J5 VRAM4.H7
MDO0+: AFTP3107.1 RJ45.1 XF3101.1
MDO0-: AFTP3102.1 RJ45.2 XF3101.2
MDO1+: AFTP3101.1 RJ45.3 XF3101.5
MDO1-: AFTP3106.1 RJ45.6 XF3101.6
MDO2+: AFTP3103.1 RJ45.4 XF3102.6
MDO2-: AFTP3104.1 RJ45.5 XF3102.5
MDO3+: AFTP3105.1 RJ45.7 XF3102.2
MDO3-: AFTP3108.1 RJ45.8 XF3102.1
MEM_1V5: CPU1.BA3 R644.1
MEM_CALRN0: GPU1.J25 R7409.2
MEM_CALRP0: GPU1.K25 R7408.2
MEM_RST: R7401.2 R7402.2 VRAM1.T2 VRAM2.T2 VRAM3.T2 VRAM4.T2
MIC2_VREFO: HDA27.29 RN2901.1(A) RN2901.2(A)
MIC_CAP: C2713.1 HDA27.19
MIC_GND: LCD1.26 R5201.1
MLPS_EN#: GPU1.R5 R7424.1 R7425.2
MODEL_ID_DET: C2403.2 KBC24.108 R2405.2 R2407.1 R2446.2
MPV18: C7779.2 C7780.2 C7781.2 GPU1.L8 L7704.2
MUTE_CTRL: C2901.1 R2917.1 R2918.2 U2901.2
MVREFDA: C7402.1 GPU1.K26 R7410.2 R7414.1
MVREFSA: C7403.1 GPU1.J26 R7411.2 R7415.1
NCT7718_DXN: C2606.2 C2607.2 Q2603.E THM26.3
NCT7718_DXP: C2606.1 C2607.1 Q2603.B Q2603.C THM26.2
ODD_PWR_5V: C5610.1 ODD1.2 ODD1.3 U5601.6 U5601.7 U5601.8
ODTA0: GPU1.L18 VRAM1.K1 VRAM2.K1
ODTA1: GPU1.K16 VRAM3.K1 VRAM4.K1
P2800_VGA_DXN: GPU1.T2 TP7518.1
P2800_VGA_DXP: GPU1.T4 TP7517.1
P_RX_ZVDD_095: CPU1.W7 R301.2
P_TX_ZVDD_095: CPU1.W8 R302.2
PANEL_SIZE_ID: CPU1.AY26 R5208.2 R5209.1 R5210.2
PANEL_SIZE_ID_CONN: LCD1.22 R5210.1
PBAT_PRES1#: AFTP3902.1 BAT1.5 RN4301.8(B)
PBAT_SMBCLK1: AFTP3904.1 BAT1.3 RN4301.6(B)
PBAT_SMBDAT1: AFTP3903.1 BAT1.4 RN4301.7(B)
PCB_VER_AD: C2402.2 KBC24.98 R2404.2 R2406.1
PCH_HDMI_CLK: CPU1.D17 Q5402.4 RN402.1(A) RN5404.1(A)
PCH_HDMI_DATA: CPU1.E17 Q5402.1 RN402.2(A) RN5404.2(A)
PCH_SUSCLK_KBC: KBC24.77 R609.2
PCIE_CALRN: GPU1.AA22 R7318.1
PCIE_CALRP: GPU1.Y22 R7321.1
PCIE_PRX_LANTX_N0: C3016.2 CPU1.R8
PCIE_PRX_LANTX_P0: C3014.2 CPU1.R10
PCIE_PRX_WLANTX_N1: CPU1.R4 WLAN1.23
PCIE_PRX_WLANTX_P1: CPU1.R5 WLAN1.25
PCIE_PTX_LANRX_N0: C306.1 CPU1.L1
PCIE_PTX_LANRX_N0_C: C306.2 LOM30.14
PCIE_PTX_LANRX_P0: C305.1 CPU1.L2
PCIE_PTX_LANRX_P0_C: C305.2 LOM30.13
PCIE_PTX_WLANRX_N1_C: C304.2 WLAN1.31
PCIE_PTX_WLANRX_P1_C: C303.2 WLAN1.33
PCIE_RST#_C: CPU1.AY9 R618.2
PCIE_TXN1_C: C304.1 CPU1.K1
PCIE_TXP1_C: C303.1 CPU1.K2
PCIE_WAKE#: KBC24.113 LOM30.21 R622.1 R3033.1
PCIE_WAKE#_R: CPU1.AW11 R622.2 R626.1
PD4403_A: PD4404.A PQ4409.B
PD4403_K: PD4404.K PR4468.2
PE_GPIO0: CPU1.AY27 D7301.2 R607.1 R637.1 R7326.2
PE_GPIO1: CPU1.AU21 PD8201.K PD8307.K PD8308.A PQ8319.2 R636.1 R8309.1 R8310.1
PEG_C_RXN0: C7302.1 GPU1.AG31
PEG_C_RXN1: C7304.1 GPU1.AF28
PEG_C_RXN2: C7306.1 GPU1.AF26
PEG_C_RXN3: C7308.1 GPU1.AD26
PEG_C_RXP0: C7301.1 GPU1.AH30
PEG_C_RXP1: C7303.1 GPU1.AG29
PEG_C_RXP2: C7305.1 GPU1.AF27
PEG_C_RXP3: C7307.1 GPU1.AD27
PEG_CLKREQ#: Q7504.D R610.1 R7518.1
PEG_RXN0: C7302.2 CPU1.L4
PEG_RXN1: C7304.2 CPU1.J4
PEG_RXN2: C7306.2 CPU1.G4
PEG_RXN3: C7308.2 CPU1.E7
PEG_RXP0: C7301.2 CPU1.L5
PEG_RXP1: C7303.2 CPU1.J5
PEG_RXP2: C7305.2 CPU1.G5
PEG_RXP3: C7307.2 CPU1.D7
PEG_TXN0: C445.2 GPU1.AE31
PEG_TXN1: C457.2 GPU1.AD28
PEG_TXN2: C478.2 GPU1.AC31
PEG_TXN3: C448.2 GPU1.AB28
PEG_TXP0: C477.2 GPU1.AF30
PEG_TXP1: C447.2 GPU1.AE29
PEG_TXP2: C452.2 GPU1.AD30
PEG_TXP3: C441.2 GPU1.AC29
PH_APU_VDD: PG4701.1 PR4705.1
PH_VDDNB: PG4720.1 PR4712.1
PLT_RST#: C601.2 D401.3 D7301.1 Q3003.E R618.1 R2448.2 R3016.1 WLAN1.22
PLT_RST#_DEBUG: DB1.7 R6502.2
PLT_RST#_EC: C2415.2 KBC24.7 R2416.1
PLT_RST#_LAN: LOM30.19 Q3003.C R3016.2 RN3001.4(B)
PM_CLKRUN#_EC: CPU1.AP25 KBC24.8 R2401.1
PM_LAN_ENABLE: KBC24.119 Q3001.G R3023.1
PM_LAN_ENABLE_R: C3015.2 Q3004.G R3022.2
PM_PWRBTN#: KBC24.117 R625.1
PM_PWRBTN#_R: CPU1.BA8 R625.2 R630.1
PM_RSMRST#: Q601.3 Q603.5 R628.1 R629.1
PM_RSMRST#_R: CPU1.AY5 Q603.6 R649.2
PM_SLP_S3#: CPU1.AY3 D3603.3 D3606.K KBC24.64 PD8308.K PR4910.2 R3609.2 U3603.5
PM_SLP_S5#: CPU1.BA5 KBC24.21 PR4907.1
PQ3802_1: PQ4202.B PR4202.1 PR4209.2
PQ3808D: PC4208.2 PQ4208.D
PQ3808G: PC4209.1 PQ4208.G PR4215.1
PQ3809_D: PQ4206.3 PR4214.2
PQ4008_2: PC4425.1 PQ4408.2 PR4437.2
PQ4008_6: PQ4408.6 PR4426.1
PQ4203_5: PC4210.1 PQ4203.5 PR4218.1
PQ4405_2: PQ4410.2 PR4475.2 PR4476.2
PQ4405_3: PQ4410.3 PR4466.1
PQ4405_5: PC4434.1 PQ4410.5 PR4470.2
PQ4405_6: PC4434.2 PQ4410.6 PR4473.1
PQ4408_C: PQ4409.C PR4464.1 PR4475.1
PQ4408_E: PQ4409.E PR4467.1 PR4469.2
PQ4502_2: PD4505.1 PQ4502.2 PR4522.1
PQ4502_5: PQ4502.5 PQ4502.6 PR4520.2 PR4521.1
PQ9302_G: PC8324.2 PQ8320.G PR8349.2
PR4601_1: PR4901.2 PR4906.1
PR4605_2: PC4919.1 PR4905.2
PR9319_1: PQ8319.5 PQ8319.6 PR8349.1 PR8352.1
PROCHOT_EC: KBC24.24 Q2401.G R2438.1 R2442.1
PS_0: C7517.2 GPU1.AC19 R7521.1 R7522.1
PS_1: C7519.2 GPU1.AD19 R7517.1 R7524.1
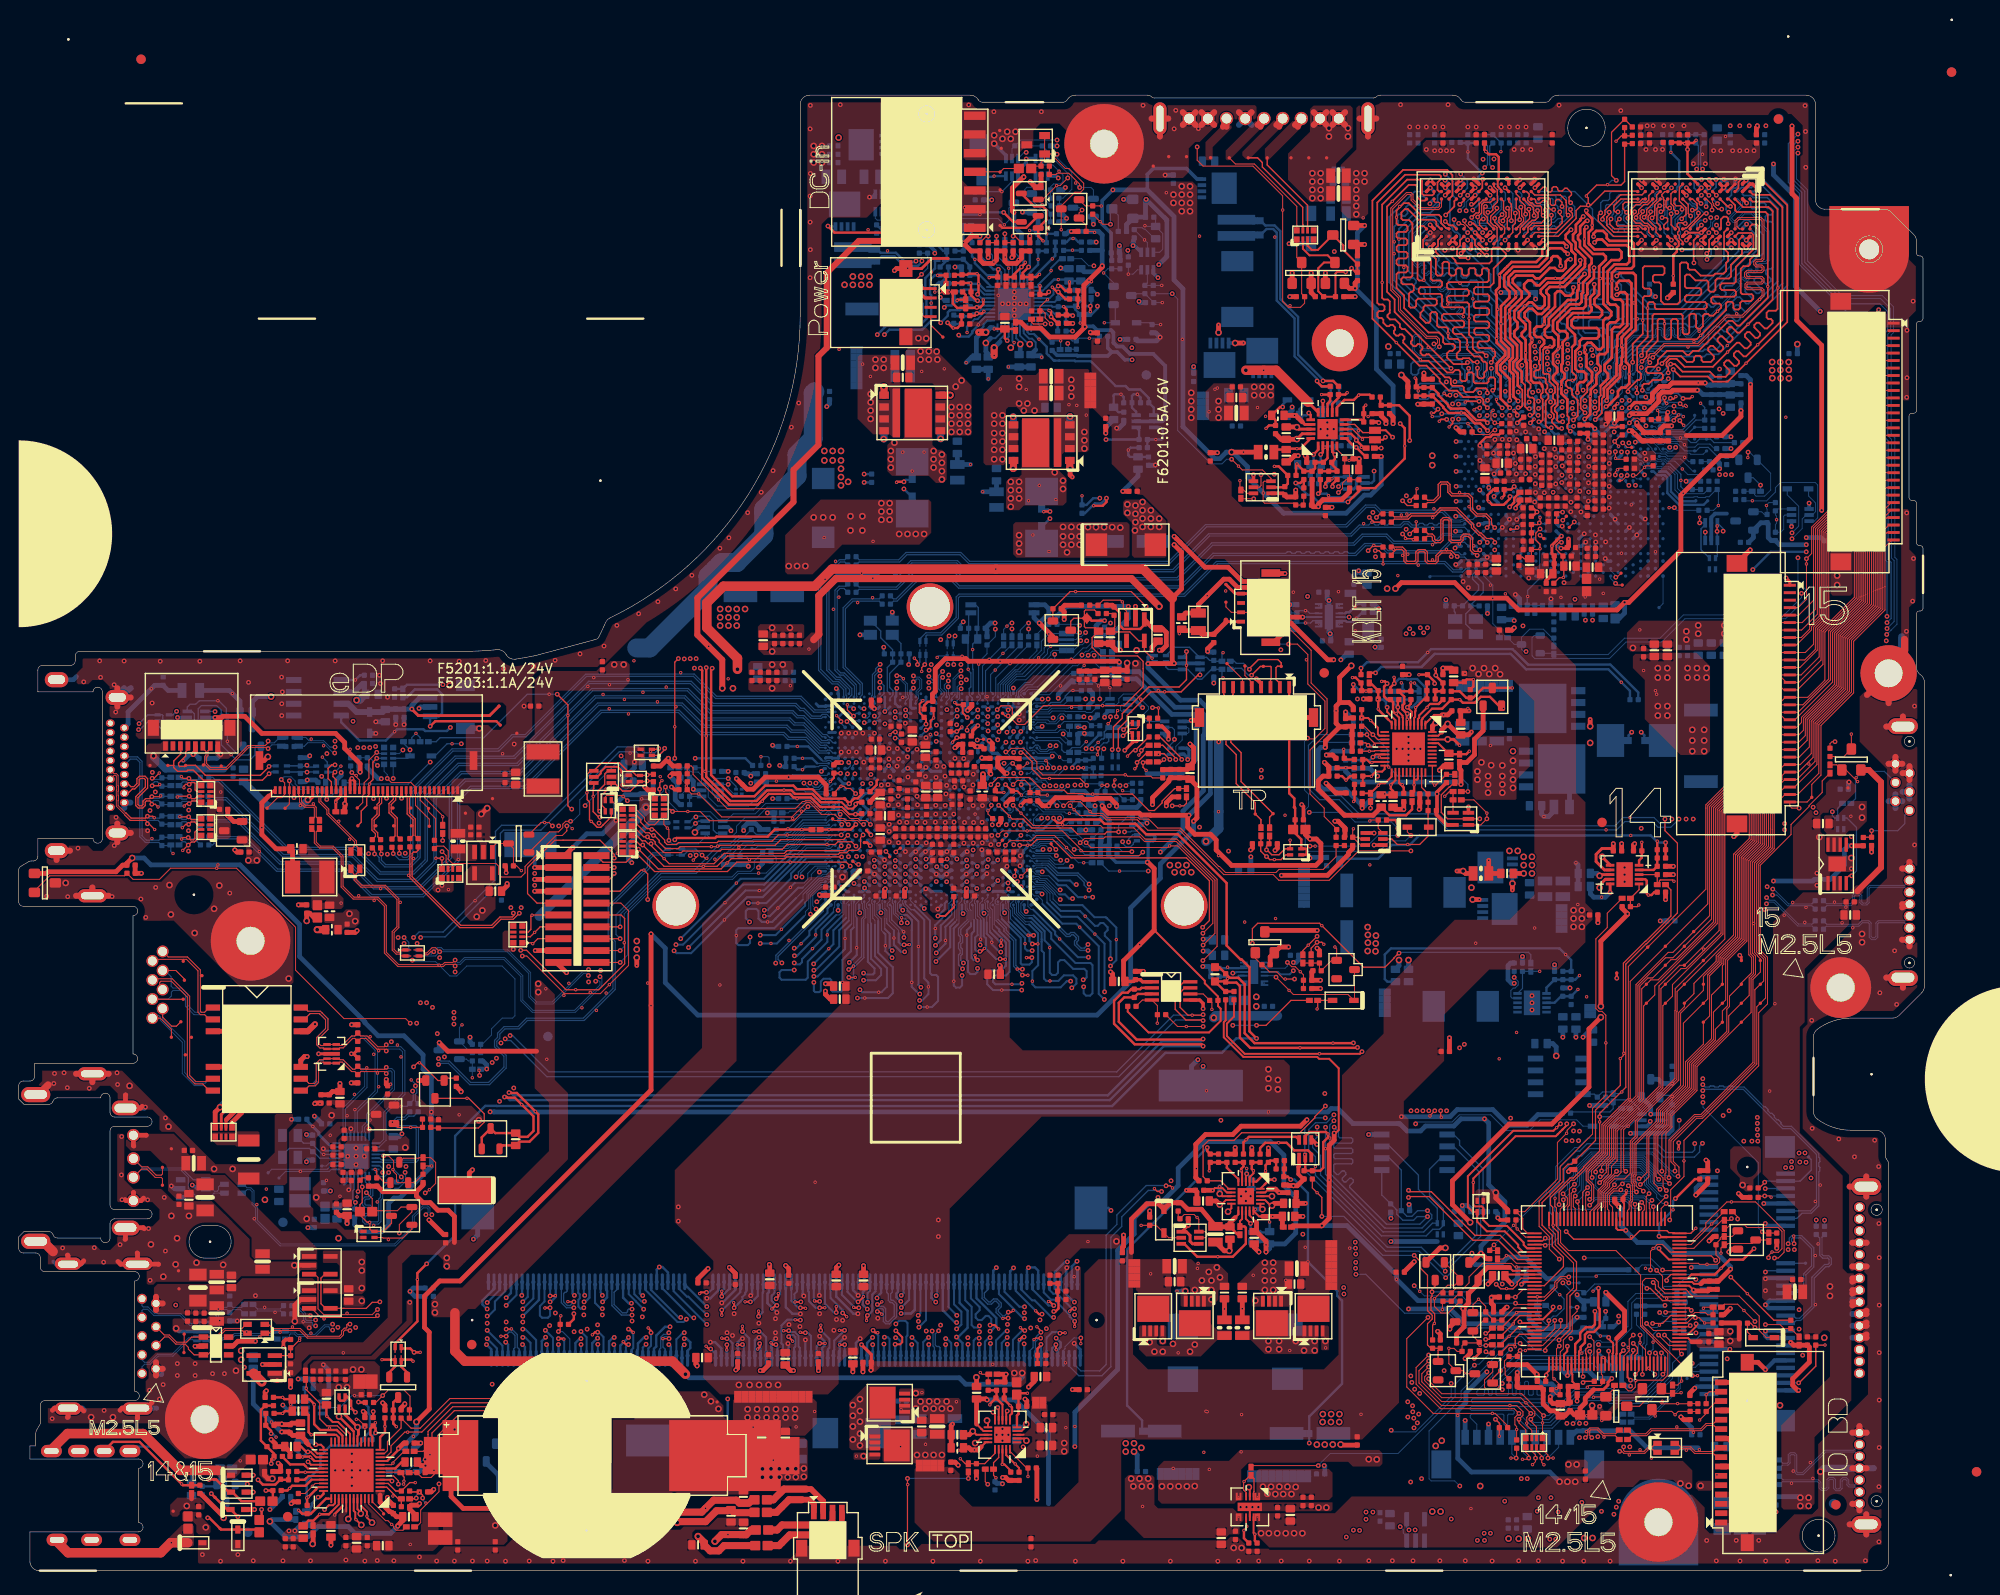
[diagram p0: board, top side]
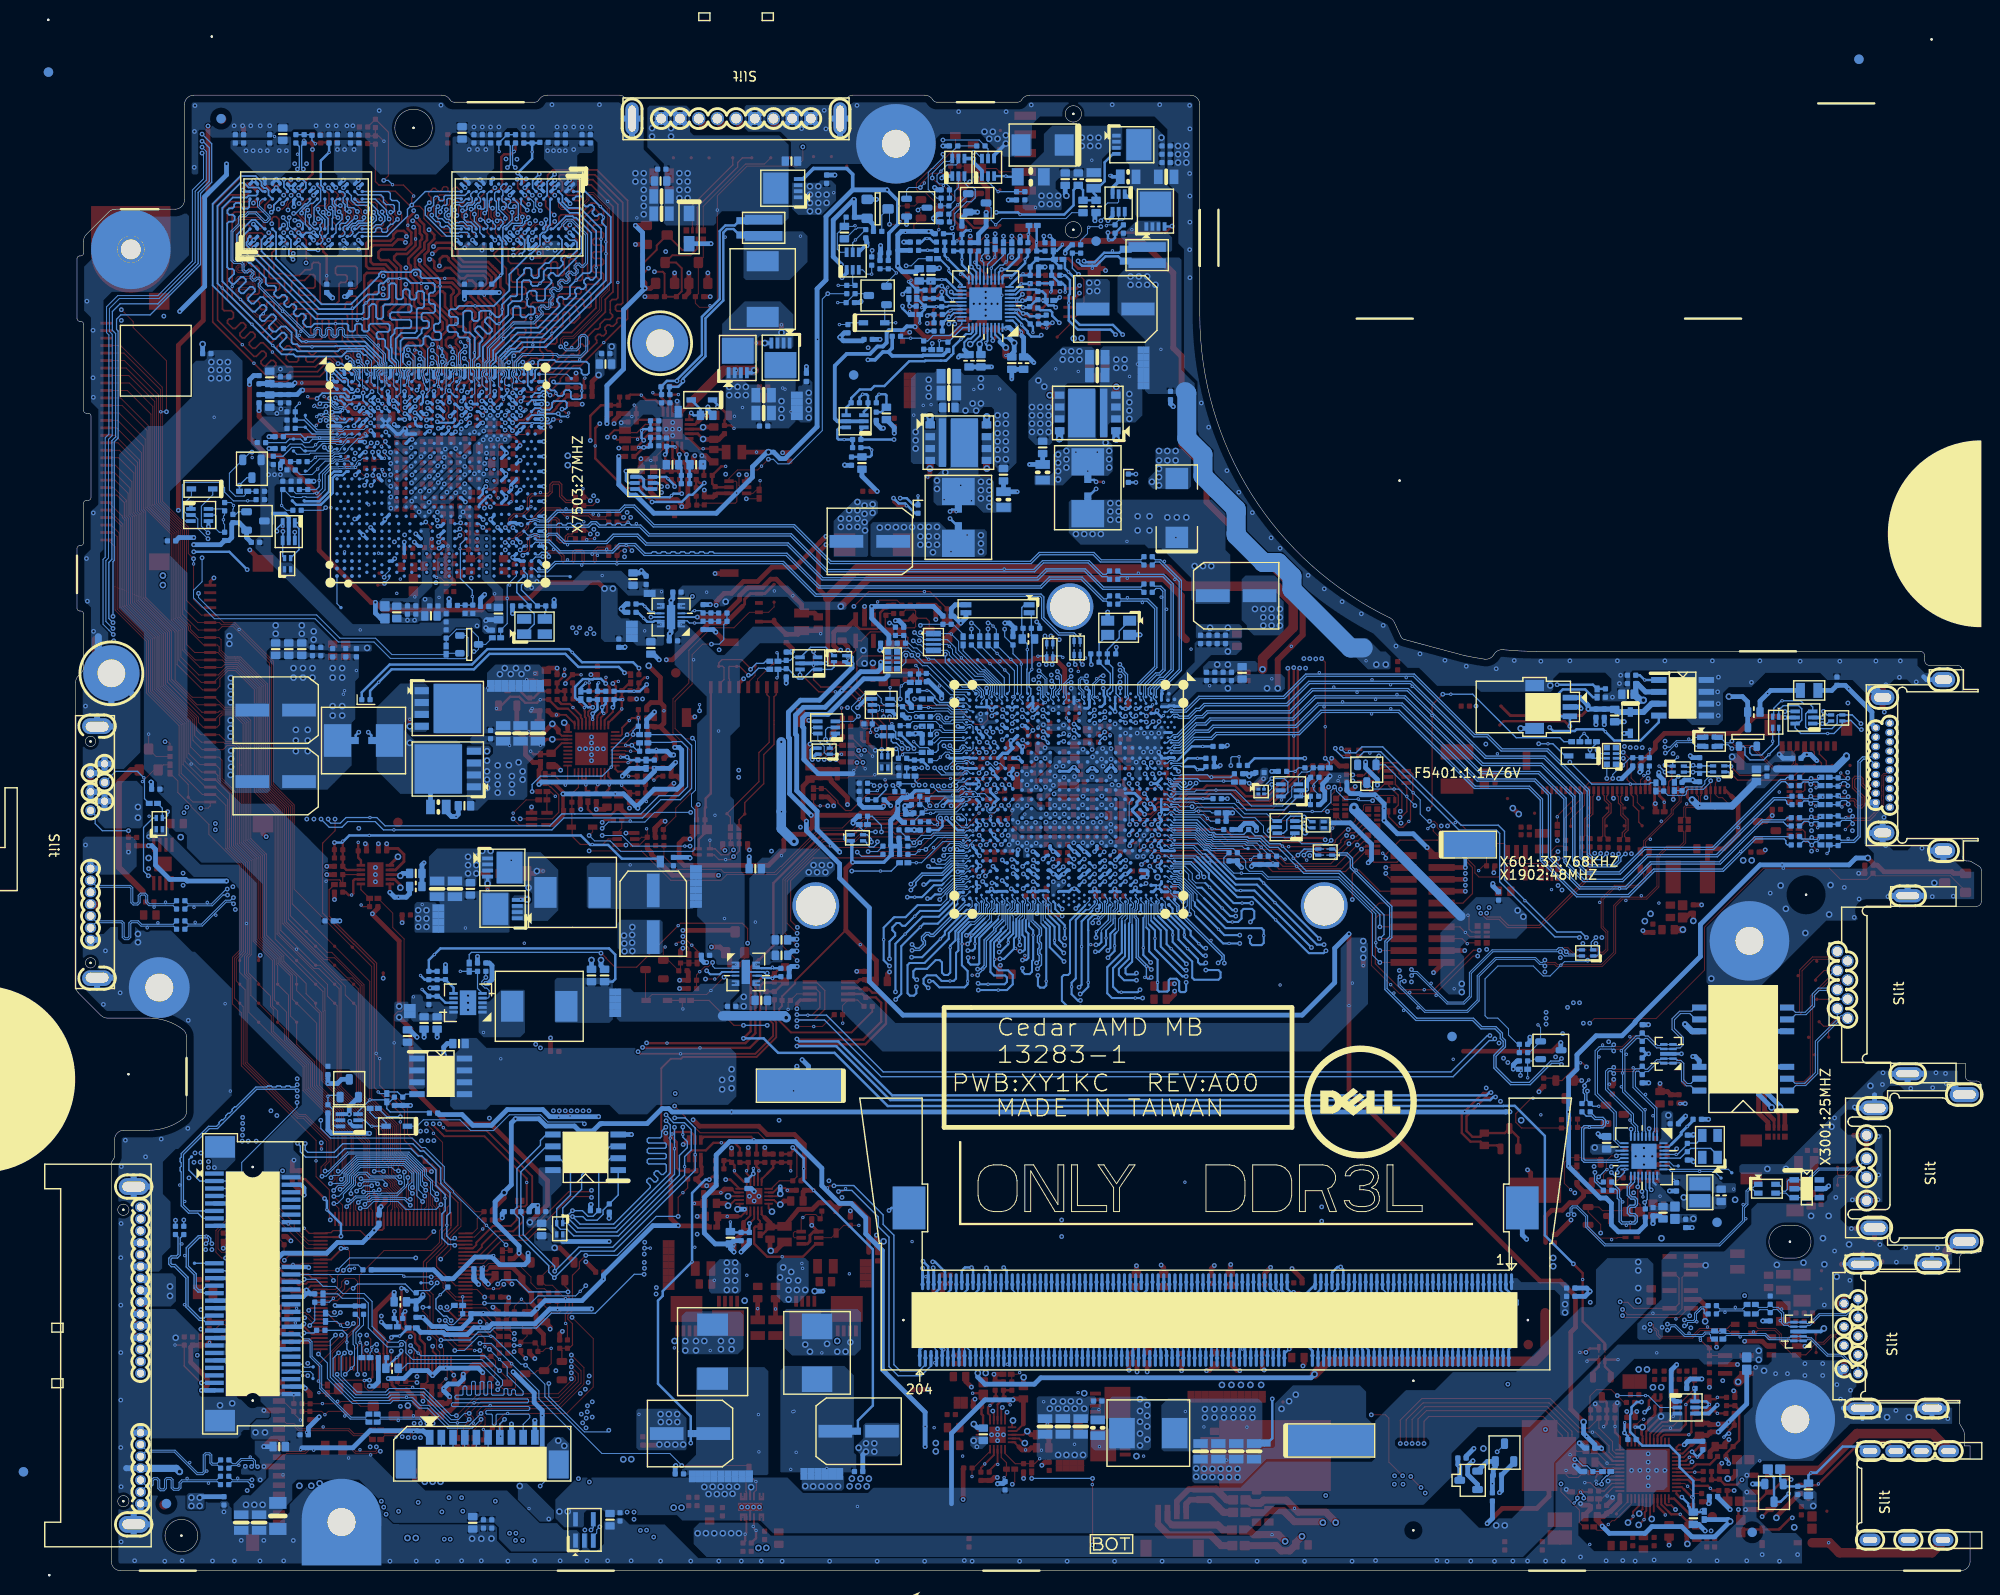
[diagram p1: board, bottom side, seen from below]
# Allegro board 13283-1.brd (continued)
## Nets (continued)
PS_2: C7518.2 GPU1.AE17 R7523.1 R7526.1
PS_3: C7516.2 GPU1.AE20 R7520.1 R7527.1
PS_ID: PQ4201.S PR4205.1
PS_ID_R: AFTP3802.1 DCIN1.4 PR4217.1
PS_ID_R2: PD4204.1 PD4204.2 PQ4201.D PR4209.1 PR4217.2
PSID_DISABLE#_R_C: PQ4201.G PQ4202.C PR4203.2
PSID_EC: KBC24.99 PD4203.3 PR4204.2 PR4205.2
PSL_IN1#: KBC24.73 R2430.2
PSL_IN2#: KBC24.93 R2425.1 R2427.2
PSL_OUT#: KBC24.74 R2432.1
PURE_HW_SHUTDOWN#: C2610.1 D3602.3 Q2404.B Q2602.D R2424.1 R2439.2 R2602.2
PWR_0D95V_BOOT: PR4820.1 PU4806.10
PWR_0D95V_BOOT_R: PC4833.2 PR4820.2
PWR_0D95V_CCM: PR4824.1 PU4806.5
PWR_0D95V_EN: PC4831.1 PR4819.2 PU4806.3
PWR_0D95V_FB: PC4832.2 PR4822.2 PR4823.1 PU4806.4
PWR_0D95V_LGATE: PU4805.4 PU4806.6
PWR_0D95V_PHASE: PC4833.1 PL4802.1 PR4837.1 PU4805.5 PU4805.6 PU4805.7 PU4805.8 PU4806.8 PU4808.1 PU4808.2 PU4808.3
PWR_0D95V_PWR: PC4832.1 PG4832.1 PR4822.1
PWR_0D95V_PWRGD: PR4821.1 PR4835.2 PU4806.1
PWR_0D95V_TRIP: PR4817.2 PU4806.2
PWR_0D95V_UGATE: PU4806.9 PU4808.4
PWR_1D05V_SNUB: PC4838.1 PR4837.2
PWR_1D8V_EN: PC5005.1 PR5010.2 PU5002.5
PWR_1D8V_FB: PC5014.2 PR5009.2 PR5013.1 PU5002.6
PWR_1D8V_PHASE: PL5002.1 PU5002.1 PU5002.2 PU5002.3
PWR_1D8V_PVDD: PC5011.1 PC5015.1 PG5009.2 PG5014.2 PR5012.1 PU5002.9 PU5002.10
PWR_1D8V_SVIN: PC5013.1 PR5012.2 PU5002.8
PWR_1D35V_DRVH: PU4901.14 PU4902.4
PWR_1D35V_DRVL: PU4901.11 PU4903.4
PWR_1D35V_EN: PC4906.1 PR4907.2 PU4901.16
PWR_1D35V_MODE: PR4908.1 PU4901.19
PWR_1D35V_REFIN: PC4902.1 PR4901.1 PR4903.2 PU4901.8
PWR_1D35V_SW: PC4919.2 PL4902.1 PR4912.1 PU4901.13 PU4902.1 PU4902.2 PU4902.3 PU4903.5 PU4903.6 PU4903.7 PU4903.8
PWR_1D35V_TRIP: PR4902.1 PU4901.18
PWR_1D35V_VBST: PR4905.1 PU4901.15
PWR_1D35V_VREF: PC4903.1 PR4903.1 PU4901.6
PWR_1D35V_VTTREF: PC4918.1 PR4911.1 PU4901.5
PWR_3D3V5V_ENTRIP: PQ4501.2 PQ4501.5 PR4501.2 PR4502.1
PWR_3D3V_BOOT2: PR4508.2 PU4501.7
PWR_3D3V_BOOT2_1: PC4513.2 PR4508.1
PWR_3D3V_ENTRIP2: PC4501.1 PR4503.1 PU4501.4
PWR_3D3V_ENTRIP2_L: PQ4501.6 PR4503.2
PWR_3D3V_FB2: PC4526.2 PR4506.2 PR4507.1 PU4501.5
PWR_3D3V_LGATE2: PU4501.10 PU4503.4
PWR_3D3V_PHASE2: PC4513.1 PL4501.2 PR4505.1 PU4501.9 PU4502.1 PU4502.2 PU4502.3 PU4503.5 PU4503.6 PU4503.7 PU4503.8
PWR_3D3V_SNUB: PC4514.1 PR4505.2
PWR_3D3V_UGATE2: PU4501.8 PU4502.4
PWR_3D3V_VOUT: PC4526.1 PG4153.2 PR4506.1
PWR_5V3D3V_ENLDO: PQ4502.3 PR4511.2 PU4501.12
PWR_5V3D3V_ENM/SECFB: PC4520.1 PR4514.1 PR4516.1 PU4501.13
PWR_5V3D3V_TON: PR4515.1 PU4501.3
PWR_5V_BOOT1: PR4513.1 PU4501.19
PWR_5V_BOOT1_1: PC4519.1 PR4513.2
PWR_5V_ENTRIP1: PC4502.1 PR4504.2 PU4501.2
PWR_5V_ENTRIP1_L: PQ4501.3 PR4504.1
PWR_5V_FB1: PC4527.2 PR4518.2 PR4519.1 PU4501.1
PWR_5V_LGATE1: PU4501.16 PU4505.4
PWR_5V_PHASE1: PC4519.2 PL4502.1 PR4517.1 PU4501.17 PU4504.1 PU4504.2 PU4504.3 PU4505.5 PU4505.6 PU4505.7 PU4505.8
PWR_5V_SNUB: PC4521.1 PR4517.2
PWR_5V_UGATE1: PU4501.18 PU4504.4
PWR_5V_VOUT: PC4527.1 PC4528.1 PG4532.2 PR4518.1 PU4501.20
PWR_APU_VDD_BOOT: PR4701.1 PU4601.1
PWR_APU_VDD_BOOT_1: PC4736.1 PR4701.2
PWR_APU_VDD_DCBATOUT: PC4713.1 PC4715.1 PC4719.1 PC4720.1 PG4703.1 PG4704.1 PG4707.1 PG4708.1 PG4709.1 PG4710.1 PU4701.2 PU4701.3 PU4701.4 PU4701.10 PU4702.2 PU4702.3 PU4702.4 PU4702.10
PWR_APU_VDD_ISEN1N: PR4707.1 PU4601.3
PWR_APU_VDD_ISEN1P: PC4701.1 PR4705.2 PR4706.1 PU4601.4
PWR_APU_VDD_LGATE: PU4601.38 PU4701.8 PU4702.8
PWR_APU_VDD_PGOOD: PR4651.2 PR4679.1 PU4601.31
PWR_APU_VDD_PHASE: PC4736.2 PG4701.2 PL4701.1 PR4709.1 PU4601.39 PU4701.9 PU4702.9
PWR_APU_VDD_SNUB: PC4742.1 PR4709.2
PWR_APU_VDD_UGATE: PU4601.40 PU4701.1 PU4702.1
PWR_APU_VDDNB_DCBATOUT: PC4716.1 PC4717.1 PC4718.1 PC4721.1 PC4722.1 PG4711.1 PG4712.1 PG4716.1 PG4717.1 PG4718.1 PU4703.2 PU4703.3 PU4703.4 PU4703.10 PU4704.2 PU4704.3 PU4704.4 PU4704.10
PWR_CHG_ACDET: PC4412.1 PR4407.2 PR4431.1 PU4404.6
PWR_CHG_ACN: PC4402.2 PC4403.1 PG4403.2 PR4406.1 PU4404.1
PWR_CHG_ACOK: PQ4402.2 PQ4408.3 PR4419.2 PR4428.2 PR4436.1 PR4476.1
PWR_CHG_ACP: PC4402.1 PC4404.1 PG4402.2 PR4406.2 PU4404.2
PWR_CHG_AD_OFF: KBC24.11 PQ4206.5 PR4210.1
PWR_CHG_AD_OFF_R: PQ4203.6 PQ4204.B PR4210.2 PR4211.1
PWR_CHG_BAT_SCL: PG4407.1 PU4404.9
PWR_CHG_BAT_SDA: PG4408.1 PU4404.8
PWR_CHG_BTST: PR4409.1 PU4404.17
PWR_CHG_BTST_R: PC4411.1 PD4401.K PR4409.2
PWR_CHG_CMPIN: PR4411.2 PR4413.1 PR4414.2 PR4427.2 PR4429.1 PU4404.4
PWR_CHG_CMPIN_R: PQ4407.3 PR4429.2
PWR_CHG_CMPIN_RR: PQ4407.6 PR4427.1
PWR_CHG_CMPOUT: PR4414.1 PR4430.2 PR4432.1 PR4437.1 PR4438.1 PU4404.3
PWR_CHG_CSON_1: PC4421.2 PC4423.1 PG4410.1 PR4420.2
PWR_CHG_CSOP_1: PC4420.1 PC4421.1 PG4409.1 PR4421.2
PWR_CHG_HIDRV: PC4413.2 PU4404.18 PU4405.4
PWR_CHG_IFAULT: PR4418.2 PU4404.11
PWR_CHG_ILIM: PR4417.2 PR4423.1 PU4404.10
PWR_CHG_IOUT: PC4422.1 PR4411.1 PR4422.1 PR4424.1 PU4404.7
PWR_CHG_LODRV: PU4404.15 PU4406.4
PWR_CHG_PHASE: PC4411.2 PC4413.1 PL4401.1 PU4404.19 PU4405.1 PU4405.2 PU4405.3 PU4406.5 PU4406.6 PU4406.7 PU4406.8
PWR_CHG_REGN: PC4407.1 PD4401.A PR4425.1 PR4428.1 PR4430.1 PU4404.16
PWR_CHG_SRN: PR4420.1 PU4404.12
PWR_CHG_SRP: PR4421.1 PU4404.13
PWR_CHG_VCC: PC4010.1 PR4408.2 PU4404.20
PWR_COMP: PC4609.1 PR4620.1 PU4601.7
PWR_COMP_1: PR4620.2 PR4621.1
PWR_COMPA: PC4606.2 PR4609.1 PU4601.24
PWR_COMPA_1: PR4609.2 PR4610.2
PWR_DCBATOUT_0D95V: PC4827.1 PC4828.1 PC4830.1 PG4827.1 PG4834.1 PG4837.1 PG4838.1 PU4808.5 PU4808.6 PU4808.7 PU4808.8
PWR_DCBATOUT_3D3V: PC4511.1 PC4512.1 PG4502.1 PG4503.1 PG4504.1 PG4505.1 PU4502.5 PU4502.6 PU4502.7 PU4502.8
PWR_DCBATOUT_5V: PC4523.1 PC4524.1 PG4515.1 PG4516.1 PG4517.1 PG4518.1 PG4519.1 PG4520.1 PG4521.1 PU4504.5 PU4504.6 PU4504.7 PU4504.8
PWR_FB: PC4609.2 PC4611.2 PR4621.2 PR4622.1 PU4601.6
PWR_FB_1: PR4622.2 PR4623.1
PWR_FBA: PC4605.1 PC4606.1 PR4608.2 PR4610.1 PU4601.25
PWR_FBA_1: PR4607.1 PR4608.1
PWR_IBIAS: PR4674.2 PU4601.23
PWR_IMON: PR4645.1 PU4601.9
PWR_IMON_1: PR4645.2 PR4664.1
PWR_IMON_2: PR4657.1 PR4659.1 PR4664.2
PWR_IMON_3: PR4657.2 PR4677.1
PWR_IMON_4: PR4661.2 PR4677.2
PWR_IMONA: PR4646.1 PU4601.11
PWR_IMONA_1: PR4646.2 PR4649.1
PWR_IMONA_2: PR4649.2 PR4658.1 PR4660.1
PWR_IMONA_3: PR4658.2 PR4678.1
PWR_IMONA_4: PR4662.2 PR4678.2
PWR_ISENA: PR8230.1 PU8202.27 PU8202.28
PWR_OCP_L: PR4637.2 PU4601.21
PWR_OFS: PC4617.1 PR4636.1 PR4638.2 PU4601.17
PWR_OFSA: PC4613.1 PR4629.1 PR4631.2 PU4601.18
PWR_PVCC: PC4603.1 PR4603.1 PU4601.37
PWR_RGND: PC4610.2 PC4612.2 PR4615.1 PR4632.1 PU4601.8
PWR_SET1: PR4634.1 PR4671.2 PU4601.19
PWR_SET1_1: PR4670.2 PR4671.1
PWR_SET1_2: PR4634.2 PR4669.1
PWR_SET2: PR4673.2 PR4676.1 PU4601.20
PWR_SET2_1: PR4672.2 PR4673.1
PWR_SET2_2: PR4675.1 PR4676.2
PWR_TONSET: PQ4601.1 PR4683.2 PU4601.2
PWR_TONSET_1: PC4625.1 PR4665.2 PR4666.1
PWR_TONSET_D: PQ4601.6 PR4665.1 PR4683.1
PWR_TONSETA: PQ4601.4 PR4682.1 PU4601.32
PWR_TONSETA_1: PC4623.1 PR4667.2 PR4668.1
PWR_TONSETA_D: PQ4601.3 PR4668.2 PR4682.2
PWR_VCC: PC4604.1 PR4604.1 PU4601.22
PWR_VCCCORE_ENABLE: PC4601.1 PR4639.1 PU4601.29
PWR_VCCCORE_SVC: PR4625.2 PU4601.14
PWR_VCCCORE_SVD: PR4628.2 PU4601.15
PWR_VCCCORE_SVT: PR4630.2 PU4601.16
PWR_VDDIO: PC4618.1 PR4648.2 PU4601.12
PWR_VDDNB_BOOTA: PR4702.1 PU4601.33
PWR_VDDNB_BOOTA_1: PC4734.1 PR4702.2
PWR_VDDNB_ISENA1N: PR4708.1 PU4601.27
PWR_VDDNB_ISENA1P: PC4702.1 PR4711.1 PR4712.2 PU4601.28
PWR_VDDNB_LGATEA: PU4601.36 PU4703.8 PU4704.8
PWR_VDDNB_PGOOD: PR4652.2 PR4680.1 PU4601.30
PWR_VDDNB_PHASEA: PC4734.2 PG4720.2 PL4702.1 PR4710.1 PU4601.35 PU4703.9 PU4704.9
PWR_VDDNB_SNUB: PC4743.1 PR4710.2
PWR_VDDNB_UGATEA: PU4601.34 PU4703.1 PU4704.1
PWR_VDDQ_SENSE_APU: PG4907.1 PU4901.9 R417.1
PWR_VGA_COMP: PC8208.1 PR8214.1 PU8202.7
PWR_VGA_COMP_1: PR8214.2 PR8215.1
PWR_VGA_CORE_BOOT1: PR8259.2 PU8202.1
PWR_VGA_CORE_BOOT1_1: PC8230.1 PR8259.1
PWR_VGA_CORE_DCBATOUT: PC8220.1 PC8221.1 PC8222.1 PC8224.1 PG8203.1 PG8204.1 PG8205.1 PG8206.1 PG8207.1 PG8208.1 PG8209.1 PG8210.1 PU8203.5 PU8203.6 PU8203.7 PU8203.8
PWR_VGA_CORE_ISEN1N: PR8265.1 PU8202.3
PWR_VGA_CORE_ISEN1P: PC8234.1 PR8201.1 PR8263.2 PU8202.4
PWR_VGA_CORE_LGATE1: PU8202.38 PU8205.4
PWR_VGA_CORE_PHASE1: PC8230.2 PG8219.2 PL8201.1 PR8260.1 PU8202.39 PU8203.1 PU8203.2 PU8203.3 PU8205.5 PU8205.6 PU8205.7 PU8205.8
PWR_VGA_CORE_UGATE1: PU8202.40 PU8203.4
PWR_VGA_FB: PC8208.2 PC8209.1 PR8215.2 PR8216.1 PU8202.6
PWR_VGA_FB_1: PR8216.2 PR8217.2
PWR_VGA_IBIAS: PR8231.2 PU8202.23
PWR_VGA_IMON: PR8229.1 PU8202.9
PWR_VGA_IMON1: PR8229.2 PR8235.1
PWR_VGA_IMON2: PR8235.2 PR8242.1 PR8245.1
PWR_VGA_IMON4: PR8242.2 PR8244.1
PWR_VGA_IMON5: PR8244.2 PR8255.2
PWR_VGA_OCP_L: PR8248.2 PR8274.1 PU8202.21
PWR_VGA_OFS: PC8214.1 PR8227.1 PR8228.1 PU8202.17
PWR_VGA_PGOOD: PR8250.2 PR8273.1 PU8202.31
PWR_VGA_PH1: PG8219.1 PR8263.1
PWR_VGA_PVCC: PC8202.1 PR8202.1 PU8202.37
PWR_VGA_PWROK: PR8254.2 PR8269.1 PU8202.13
PWR_VGA_RGND: PC8211.2 PR8222.2 PU8202.8
PWR_VGA_SET1: PC8215.1 PR8233.2 PU8202.19
PWR_VGA_SET1_1: PR8232.2 PR8233.1
PWR_VGA_SET1_2: PC8215.2 PR8234.1
PWR_VGA_SET2: PR8239.2 PR8240.1 PU8202.20
PWR_VGA_SET2_1: PR8238.2 PR8239.1
PWR_VGA_SET2_2: PR8240.2 PR8241.1
PWR_VGA_SNUB: PC8232.1 PR8260.2
PWR_VGA_SVC: PR8253.2 PR8256.1 PR8270.1 PU8202.14
PWR_VGA_SVD: PR8252.2 PR8257.1 PR8271.1 PU8202.15
PWR_VGA_SVT: PR8251.2 PU8202.16
PWR_VGA_TONSET: PQ8201.S PR8206.1 PU8202.2
PWR_VGA_TONSET_1: PC8205.1 PR8204.2 PR8205.1
PWR_VGA_TONSET_D: PQ8201.D PR8204.1 PR8206.2
PWR_VGA_VCC: PC8203.1 PR8203.1 PU8202.22
PWR_VGA_VDDIO: PC8216.1 PR8237.2 PU8202.12
PWR_VGA_VO1: PC8234.2 PC8236.2 PG8220.1 PR8201.2 PR8265.2
PWR_VGA_VREF: PC8218.1 PR8245.2 PR8255.1 PU8202.10
PWR_VGA_VSEN: PC8209.2 PC8211.1 PR8217.1 PR8220.2 PU8202.5
PWR_VREF: PC4620.1 PC4621.1 PR4659.2 PR4660.2 PR4661.1 PR4662.1 PU4601.10
PWR_VSEN: PC4611.1 PC4612.1 PR4623.2 PR4626.1 PU4601.5
PWR_VSENA: PC4605.2 PC4610.1 PR4607.2 PR4613.1 PU4601.26
PWRCNTL_2: GPU1.AK10 TP7514.1
PWRCNTL_3: GPU1.AM10 TP7515.1
PWRCNTL_4: GPU1.T8 TP7511.1
PWRGOOD: GPU1.N10 R7317.2
PWROK: PR4624.2 PU4601.13
PX_EN: GPU1.AB16 TP7510.1
Q402_1: Q3003.B RN3001.3(B)
Q603_2: Q603.2 Q603.3 R648.2
QSAN_0: GPU1.H27 VRAM1.G3
QSAN_1: GPU1.A27 VRAM1.B7
QSAN_2: GPU1.C23 VRAM2.B7
QSAN_3: GPU1.C19 VRAM2.G3
QSAN_4: GPU1.C15 VRAM3.G3
QSAN_5: GPU1.E9 VRAM4.B7
QSAN_6: GPU1.C5 VRAM3.B7
QSAN_7: GPU1.H4 VRAM4.G3
QSAP_0: GPU1.H28 VRAM1.F3
QSAP_1: GPU1.C27 VRAM1.C7
QSAP_2: GPU1.A23 VRAM2.C7
QSAP_3: GPU1.E19 VRAM2.F3
QSAP_4: GPU1.E15 VRAM3.F3
QSAP_5: GPU1.D10 VRAM4.C7
QSAP_6: GPU1.D6 VRAM3.C7
QSAP_7: GPU1.G5 VRAM4.F3
RASA0#: GPU1.G22 VRAM1.J3 VRAM2.J3
RASA1#: GPU1.G17 VRAM3.J3 VRAM4.J3
REGOUT: C3002.1 L3001.1 LOM30.24 R3001.1
RING2: EC2905.1 HDA27.17 R2906.2 RN2901.4(B)
RING2_R: ED2903.1 HPMIC1.3 R2906.1
RSET: LOM30.31 R3032.2
RSMRST#_KBC: KBC24.15 R628.2
RTC_1D5V_EN: R705.1 R706.1 U701.3
RTC_1D5V_PWR: C702.1 R701.1 R704.2 U701.5
RTC_1D5V_S5: C701.1 CPU1.AN4 G701.1 Q701.D R701.2
RTC_AUX_S5: C705.1 C2503.2 D2501.3 R704.1 R705.2 R2428.2 U701.1
RTC_CLK: CPU1.AV11 R609.1 R1917.1 R1918.1
RTC_DET#: CPU1.AV15 Q2505.D R634.1
RTC_PWR: D2501.2 Q2505.G R2502.1 R2504.1
RTCRST_ON: KBC24.120 Q701.G R702.1
RUNPWROK_D: D3606.A R3627.1
S0_PWR_GOOD_R: CPU1.AM19 R611.2 R627.1
S5_ENABLE: KBC24.14 Q2403.D R2436.2 R3603.2
SATA_LED#: CPU1.BA30 TP1902.1
SATA_ODD_DA#: CPU1.AN8 R5602.2 RN5601.3(B)
SATA_ODD_DA#_C: ODD1.4 R5602.1
SATA_ODD_PRSNT#: CPU1.AV1 ODD1.1 R5604.1 R5610.1
SATA_ODD_PWRGT: CPU1.AV31 RN5601.4(B) U5601.4
SATA_PRX_HDDTX_N0: C5616.1 CPU1.BA16
SATA_PRX_HDDTX_P0: C5615.1 CPU1.AY16
SATA_PRX_ODDTX_N1: C5607.2 CPU1.AY17
SATA_PRX_ODDTX_P1: C5608.2 CPU1.BA17
SATA_PTX_HDDRX_N0: C5603.2 CPU1.AY14
SATA_PTX_HDDRX_P0: C5602.2 CPU1.BA14
SATA_PTX_ODDRX_N1: C5611.2 CPU1.BA19
SATA_PTX_ODDRX_P1: C5612.2 CPU1.AY19
SATA_RXN0_R: C5616.2 HDD1.S5
SATA_RXN2_R: C5607.1 ODD1.S5
SATA_RXP0_R: C5615.2 HDD1.S6
SATA_RXP2_R: C5608.1 ODD1.S6
SATA_TXN0_R: C5603.1 HDD1.S3
SATA_TXN2_R: C5611.1 ODD1.S3
SATA_TXP0_R: C5602.1 HDD1.S2
SATA_TXP2_R: C5612.1 ODD1.S2
SATA_ZVDD_095: CPU1.AP19 R1904.2
SATA_ZVSS: CPU1.AR19 R1903.2
SLEEVE: EC2906.1 HDA27.18 R2911.2 RN2901.3(B) U2901.3
SLEEVE_CTRL: R2915.2 U2901.5 U2901.6
SLEEVE_R: ED2905.1 HPMIC1.4 R2911.1
SMB0_CLK: CPU1.AU25 DM1.202 RN601.4(B)
SMB0_DATA: CPU1.AV25 DM1.200 RN601.3(B)
SMB1_CLK: CPU1.AY11 Q6202.6 RN603.2(A)
SMB1_DATA: CPU1.BA11 Q6202.3 RN603.1(A)
SML1_CLK: KBC24.67 Q403.6 Q2601.3 Q7503.6 RN401.1(A)
SML1_DATA: KBC24.68 Q403.3 Q2601.6 Q7503.3 RN401.2(A)
SPI_CLK_R: EC2503.1 R1925.2 R2420.1 SPI25.6
SPI_CS0#_R: R1908.2 R2419.1 R2501.1 SPI25.1
SPI_CS2#: CPU1.AR4 TP1904.1
SPI_HOLD#: R1923.2 RN1904.1(A) RN2501.2(A) SPI25.7
SPI_SI_R: EC2501.1 R1921.2 R2422.1 SPI25.5
SPI_SO_R: EC2502.1 R1922.2 R2423.1 SPI25.2
SPI_SW: CPU1.AV17 R1915.2 R1916.1
SPI_WP#: R1924.2 RN1904.2(A) RN2501.1(A) SPI25.3
SPV10: C7687.2 C7688.2 C7689.2 GPU1.H8 L7705.2
SPV18: C7684.2 C7685.2 C7686.2 GPU1.H7 L7703.2
SYS_PWRGD: KBC24.26 R611.1 R3627.2
SYS_RESET#: CPU1.AY7 R1926.1 R1927.1
T_CRIT#: R2601.1 R2604.2 THM26.4
TEMPINRETURN: CPU1.A23 R412.2
TESTEN: GPU1.K7 R7311.1 R7332.2
THERM_SYS_SHDN#: Q2602.S R2601.2 R2607.2
THM_SML1_CLK: C2608.1 Q2601.4 RN2601.4(B) RN2602.4(B) THM26.8
THM_SML1_DATA: C2609.1 Q2601.1 RN2601.3(B) RN2602.3(B) THM26.7
TOUCH_PANEL_INTR#: D2401.A R2411.1 R2443.1 R5205.2
TOUCH_PANEL_INTR_KBC#: KBC24.124 R2411.2
TP41: CPU1.AP29 TP421.1
TP_RESET: AFTP5214.1 C5214.1 LCD1.38 R2448.1
TP_RS: AFTP5209.1 C5208.1 LCD1.37 R5205.1
TP_SMB1_CLK: EC6207.1 Q6202.1 R6212.1 RN6201.2(A)
TP_SMB1_CLK_R: AFTP6237.1 R6212.2 TPAD1.3
TP_SMB1_DATA: EC6206.1 Q6202.4 R6213.1 RN6201.1(A)
TP_SMB1_DATA_R: AFTP6240.1 R6213.2 TPAD1.2
TP_VDD: AFTP6239.1 C6202.1 R6209.2 RN6203.1(A) RN6203.2(A) TPAD1.1
TP_WAKE: AFTP6242.1 TPAD1.6
TPAN_VDD: F5203.2 LCD1.40 R5232.1
TPAN_VDD_F: F5203.1 R5230.2 R5231.2 R5232.2
TPCLK: EC6205.1 KBC24.72 R6210.1 RN6203.4(B)
TPCLK_C: AFTP6238.1 R6210.2 TPAD1.8
TPDATA: EC6208.1 KBC24.71 R6211.1 RN6203.3(B)
TPDATA_C: AFTP6236.1 R6211.2 TPAD1.7
TPS51216_PHS_SET: PC4922.1 PR4912.2
TS_A: GPU1.AE19 TP7522.1
TSVDD: C7515.1 C7521.1 C7582.1 GPU1.AD17 L7504.2
TX_PWRS_ENB: GPU1.U6 R7301.1
USB3_PRX_CTX_N0: CPU1.V1 R3411.2
USB3_PRX_CTX_N0_C: R3411.1 U3402.1 U3402.10 USB1.5
USB3_PRX_CTX_P0: CPU1.V2 R3410.2
USB3_PRX_CTX_P0_C: R3410.1 U3402.2 U3402.9 USB1.6
USB3_PTX_CRX_N0: C3403.1 CPU1.T1
USB3_PTX_CRX_N0_C: C3402.1 R3409.1 U3402.4 U3402.7 USB1.8
USB3_PTX_CRX_N0_R: C3403.2 R3409.2
USB3_PTX_CRX_P0: C3404.1 CPU1.T2
USB3_PTX_CRX_P0_C: C3401.1 R3408.1 U3402.5 U3402.6 USB1.9
USB3_PTX_CRX_P0_R: C3404.2 R3408.2
USB20_VCCA: AFTP6205.1 C3406.1 C3503.1 C3506.1 C3509.1 C3514.1 TC3502.1 U3401.5 U3503.1 USB2.1
USB20_VCCB: C3515.1 C3516.1 C3517.1 C3518.1 IOBD1.1 IOBD1.2 IOBD1.3 IOBD1.4 R3502.1 TC6301.1 U3505.1
USB30_VCCC: AFTP6210.1 C3405.1 C3507.1 C3508.1 C3512.1 C3513.1 R3501.1 TC3501.1 U3403.5 U3504.1 USB1.1
USB_ATEST0: CPU1.AJ10 TP416.1
USB_ATEST1: CPU1.AJ8 TP417.1
USB_CAMERA: AFTP5226.1 CCD1.7 R5221.1 TR5208.2
USB_CAMERA#: AFTP5225.1 CCD1.6 R5219.1 TR5208.3
USB_CAMERA_EDP: LCD1.31 TR5209.2
USB_CAMERA_EDP#: LCD1.30 TR5209.3
USB_OC#0: CPU1.AY8 RN604.5(B) U3503.3
USB_OC#1: CPU1.AW1 RN604.8(B) U3504.3
USB_OC#3: CPU1.AY1 RN604.6(B) U3505.3
USB_PN0: CPU1.AL5 TR3401.1
USB_PN0_R: AFTP6204.1 TR3401.2 U3401.1 USB2.2
USB_PN1: CPU1.AJ5 TR6301.4
USB_PN1_IOBD1: IOBD1.8 TR6301.3
USB_PN4: CPU1.AF2 R6303.2
USB_PN4_IOBD1: IOBD1.11 R6303.1
USB_PN5: CPU1.AE2 R5802.2
USB_PN5_R: R5802.1 WLAN1.36
USB_PN6: CPU1.AD2 R5203.2
USB_PN6_TPNL: LCD1.34 R5203.1
USB_PN7: CPU1.AC2 RN5205.4(B) RN5206.4
USB_PN7_CAM#: R5219.2 RN5205.1(A) TR5208.4
USB_PN7_EDP: RN5206.1 TR5209.4
USB_PN8: CPU1.AB2 TR3404.4
USB_PN8_C: AFTP6211.1 TR3404.3 U3403.1 USB1.2
USB_PP0: CPU1.AL4 TR3401.4
USB_PP0_R: AFTP6209.1 TR3401.3 U3401.3 USB2.3
USB_PP1: CPU1.AJ4 TR6301.1
USB_PP1_IOBD1: IOBD1.9 TR6301.2
USB_PP4: CPU1.AF1 R6304.1
USB_PP4_IOBD1: IOBD1.12 R6304.2
USB_PP5: CPU1.AE1 R5803.1
USB_PP5_R: R5803.2 WLAN1.38
USB_PP6: CPU1.AD1 R5204.2
USB_PP6_TPNL: LCD1.35 R5204.1
USB_PP7: CPU1.AC1 RN5205.3(B) RN5206.3
USB_PP7_CAM: R5221.2 RN5205.2(A) TR5208.1
USB_PP7_EDP: RN5206.2 TR5209.1
USB_PP8: CPU1.AB1 TR3404.1
USB_PP8_C: AFTP6212.1 TR3404.2 U3403.3 USB1.3
USB_PWR_EN#: KBC24.91 R2429.1 U3503.4 U3504.4 U3505.4
USB_RCOMP: CPU1.AG4 R1902.2
USB_SS_ZVDD_095: CPU1.AE8 R1910.1
USB_SS_ZVSS: CPU1.AE10 R1909.1
VCORE_EN: PR4639.2 R3605.2
VD1_EN#: KBC24.66 R2447.2
VD_IN1: C2615.1 C2616.1 KBC24.104 R2610.1 R2611.2 R2622.2
VD_IN1_C: C2615.2 C2616.2 R2610.2 R2612.1
VD_OUT1#: KBC24.110 R2602.1 R2607.1 R2624.2
VGA_CORE: C7618.2 C7619.2 C7620.2 C7621.2 C7622.2 C7635.2 C7636.2 C7637.2 C7638.2 C7644.2 C7645.2 C7646.2 C7647.2 C7648.2 C7649.2 C7650.2 C7651.2 C7658.2 C7659.2 C7660.2 C7661.2 C7662.2 C7663.2 C7664.2 C7665.2 C7666.2 C7667.2 C7668.2 C7669.2 C7670.2 C7671.2 C7672.2 C7673.2 C7674.2 C7675.2 C7676.2 C7677.2 C7678.2 GPU1.AA12 GPU1.AA15 GPU1.M11 GPU1.M13 GPU1.M15 GPU1.M16 GPU1.M17 GPU1.M18 GPU1.M20 GPU1.M21 GPU1.N12 GPU1.N15 GPU1.N17 GPU1.N20 GPU1.R13 GPU1.R16 GPU1.R18 GPU1.T12 GPU1.T15 GPU1.T17 GPU1.T20 GPU1.U11 GPU1.U13 GPU1.U16 GPU1.U18 GPU1.V15 GPU1.V17 GPU1.V20 GPU1.V21 GPU1.Y13 GPU1.Y16 GPU1.Y18 GPU1.Y21 PG8220.2 PL8201.2 PR8220.1 PR8316.1 PT8204.1 PT8205.1
VGA_CORE_DISCHG: PQ8305.3 PR8316.2
VGA_DIS: GPU1.P4 R7305.1
VGA_PEG_CLKREQ#: GPU1.N7 Q7504.S R7518.2 R7533.2
VGA_PWROK: PR8269.2 PR8275.1 U8201.4
VO_APU_VDD: PC4701.2 PC4704.2 PG4702.1 PR4706.2 PR4707.2
VO_VDDNB: PC4702.2 PC4703.2 PG4719.1 PR4708.2 PR4711.2
VRAM1_2_VREF: C7803.1 R7805.2 R7806.1 VRAM1.H1 VRAM1.M8 VRAM2.H1 VRAM2.M8
VRAM3_4_VREF: C8901.1 R8901.2 R8902.1 VRAM3.H1 VRAM3.M8 VRAM4.H1 VRAM4.M8
VRAM_SIZE1: CPU1.BA22 R638.1 R641.2
VRAM_ZQ1: R7801.2 VRAM2.L8
VRAM_ZQ2: R7802.2 VRAM1.L8
VRAM_ZQ3: R8903.2 VRAM4.L8
VRAM_ZQ4: R8904.2 VRAM3.L8
VTT_CT_0.95V: C3619.1 U3603.12
VTT_CT_1.8V: C3618.1 U3603.10
VTT_CT_3VC_1: C8301.1 U8302.10
WEA0#: GPU1.G25 VRAM1.L3 VRAM2.L3
WEA1#: GPU1.H10 VRAM3.L3 VRAM4.L3
WHITE_LED_BAT: EC6103.1 Q6103.3 R6101.2
WIFI_RF_EN: KBC24.82 WLAN1.20
WLAN_ACT: C5807.1 TP5801.1 WLAN1.3
XO_IN: GPU1.AC22 TP7516.1
XTALIN: C7730.1 GPU1.AM28 R7727.1 X7503.1
XTALOUT: C7729.1 GPU1.AK28 R7727.2 X7503.3
N209551934: TP5804.1 WLAN1.46
N209551965: TP5803.1 WLAN1.44

Pads without a net: CCD1 2; CPU1 A6 A7 A19 A20 A29 AA1 AA2 AA4 AA5 AA37 AA38 AA40 AA41 AB40 AB41 AC4 AC5 AC40 AE37 AE38 AG1 AG2 AG7 AG8 AK1 AL2 AL38 AM1 AN35 AN37 AP11 AP13 AP17 AP21 AR27 AR37 AU31 AV13 AV19 AV23 AV27 AY12 AY20 AY22 AY23 AY24 AY25 B6 B7 BA6 BA10 BA12 BA20 BA23 BA24 BA29 D19 D21 E19 H1 H2 H15 J1 J2 J34 J37 K15 N4 N5 N8 N10 R1 R2 U41 V40 V41 W1 W2 W4 W40 Y40 Y41; D401 2; D3602 2; D3603 2; DM1 77 122 125; GPU1 AA1 AA3 AA5 AA6 AA29 AA31 AB2 AB4 AB7 AB8 AB9 AB11 AB12 AB13 AB23 AB25 AB26 AB27 AB30 AC1 AC3 AC5 AC6 AC7 AC8 AC10 AC11 AC13 AC16 AC20 AC23 AC25 AD2 AD4 AD7 AD9 AD10 AD11 AD13 AD16 AD20 AD22 AD23 AD24 AE1 AE3 AE5 AE6 AE8 AE9 AE10 AE11 AE13 AE16 AE22 AE23 AE24 AE25 AE26 AF2 AF4 AF6 AF7 AF8 AF9 AF10 AF11 AF13 AF16 AF19 AF20 AF22 AF23 AF24 AF25 AG1 AG3 AG5 AG6 AG7 AG8 AG9 AG10 AG11 AG13 AG14 AG15 AG16 AG17 AG18 AG19 AG20 AG21 AG22 AG23 AG24 AG25 AG26 AH1 AH3 AH5 AH6 AH8 AH12 AH14 AH16 AH18 AH20 AH22 AH24 AH26 AJ7 AJ9 AJ11 AJ13 AJ15 AJ17 AJ19 AJ21 AJ23 AJ25 AJ27 AK1 AK3 AK5 AK6 AK8 AK12 AK14 AK16 AK18 AK20 AK22 AK24 AK26 AL7 AL9 AL11 AL13 AL15 AL17 AL19 AL21 AL23 AL25 AM3 AM5 AM6 AM8 AM12 AM14 AM16 AM18 AM20 AM22 AM24 AM26 J8 J22 K13 K30 L9 L16 L29 L31 M27 M28 M30 N3 N5 N6 N9 N26 N29 N31 P23 P24 P26 P27 P28 P30 R1 R3 R29 R31 T7 T10 T23 T24 T26 T27 T28 T30 U1 U3 U5 U10 U12 U23 U24 U26 U29 U31 V2 V4 V6 V12 V27 V28 V30 W1 W3 W5 W6 W7 W8 W9 W10 W23 W24 W29 W31 Y2 Y4 Y6 Y7 Y8 Y9 Y11 Y12 Y23 Y24 Y26 Y27 Y28 Y30; HDA27 14 16 23 24; HDD1 P1 P2 P3 P11 P13 P14 P15; HDMI1 13 14; IOBD1 6; KB1 2 3; KB2 2 3; KBC24 13 23 33 81 94 96 112; KBLIT1 3; LCD1 3 33 39; PU5002 7; PU8202 11 18 24 25 26 30 32 33 34 35 36; RN407 1 8; RN604 7; RN4301 4 5; RN5201 4 5; RN5203 4 5; RN6502 4 5; SW1 3; U701 4; U3401 4 6; U3403 4 6; U3602 4; U5601 5; VRAM1 J1 J9 L1 L9; VRAM2 J1 J9 L1 L9; VRAM3 J1 J9 L1 L9; VRAM4 J1 J9 L1 L9; WLAN1 1 6 8 10 12 14 16 28 30 32 42 45 47 48; X3001 2 4; X7503 2 4

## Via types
v1: diameter 0.356, hole 0.178, TOP to BOTTOM, 1169 vias
v2: diameter 0.508, hole 0.254, TOP to BOTTOM, 2837 vias
v3: diameter 0.711, hole 0.406, TOP to BOTTOM, 699 vias

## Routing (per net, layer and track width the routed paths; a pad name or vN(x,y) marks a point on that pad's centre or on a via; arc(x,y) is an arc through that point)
0.95VGA_EN: length 4.2
  BOTTOM w0.127: U8302.3 138.42,101.65 138.19,101.41 v1(137.64,101.41) 136.92,101.41 C8314.2 R8301.1 135.07,101.6 R8309.2
1.8VGA_EN: length 4.2
  BOTTOM w0.127: U8302.5 138.1,102.45 137.82,102.73 v1(137.64,102.73) 136.97,102.73 C8313.2 R8301.2 135.07,102.49 R8310.2
3.3V_RUN_VGA_1: length 13.7
  BOTTOM w0.102: PQ8319.3 192.08,112.32 192.43,112.67 192.43,116.2 192.17,116.45 188.47,116.45 187.91,115.89 187.91,115.64 187.91,115.43 186.96,114.48 185.46,114.48 v1(185.44,114.5) 185.37,114.5 185.35,114.48 184.68,114.48 PR8350.1
3V5V_CT1: length 2.9
  TOP w0.203: v1(132.23,3.9) 132.09,4.04 U3601.12
  TOP w0.254: v1(132.23,3.9) 132.23,3.2 C3602.1
3V5V_CT2: length 3.1
  TOP w0.203: U3601.10 131.29,4.54 v1(131.06,4.31)
  TOP w0.254: v1(131.06,4.31) 131.06,3.48 C3601.1
3V5V_CT_105VC_2: length 3.1
  BOTTOM w0.203: U8302.12 141.93,101.65 142.04,101.54
  BOTTOM w0.254: 142.04,101.54 142.69,101.54 v1(143.08,101.92) 143.71,102.56 C8302.1
3V5V_S0_ON: length 5.2
  TOP w0.127: U3601.5 131.29,8.37 131.02,8.64 131.02,9.48 v1(131.08,9.54) 131.73,10.19 R3609.1 132.13,9.88 132.13,8.46 132.09,8.42 U3601.3
3V_5V_EN: length 29.7
  TOP w0.127: PR4501.1 138.38,40.96 v1(138.88,40.46) 139.39,39.95 v2(139.39,37.91) ; v2(149.27,33.74) 149.96,33.05 149.96,32.35 150.7,31.61 150.7,27.83 151.2,27.32 151.2,26.93 150.7,26.43 150.7,24.16 151.05,23.8 R3603.1 R3602.1 151.83,23.56 D3602.1
  BOTTOM w0.127: v2(149.27,33.74) 145.9,33.74 141.73,37.91 v2(139.39,37.91)
3V_5V_POK: length 110.7
  TOP w0.127: v2(139.77,49.73) 138.63,48.58 138.63,48.46 137.04,46.87 130.82,46.87 129.99,46.04 127.27,46.04 126.69,45.46 126.69,42.17 PR4509.2 128.57,41.72 129.42,40.87 PU4501.6 ; v2(147.65,66.08) 147.46,65.89 147.42,65.89 147.1,65.57 147.1,65.54 146.15,64.58 143.84,64.58 v1(139.39,69.03) 139.14,69.28 132.53,69.28 131.96,68.71 v2(131.96,67.15)
  L3 w0.127: v2(139.77,49.73) 139.52,49.73 133.04,56.2 133.04,61.79 132.28,62.55 132.28,66.83 v2(131.96,67.15) 131.96,75.59 131.33,76.22 131.33,83.32 v2(132.92,84.9)
  L4 w0.127: v2(123.63,88.96) 126.95,88.96 131.01,84.9 v2(132.92,84.9)
  BOTTOM w0.127: RN602.2 123.17,88.36 123.52,88.71 123.52,88.86 v2(123.63,88.96) 123.63,89.98 123.37,90.24 Q601.2 ; PR5010.1 161.74,65.93 161.5,66.17 147.74,66.17 v2(147.65,66.08)
5V_HDMI_S0: length 6
  BOTTOM w0.508: F5401.1 22.53,94.2 v1(22.86,93.87) 23.67,93.06 R5409.2
5V_HDMI_S0_R: length 9
  BOTTOM w0.508: F5401.2 15.99,94.2 C5401.1 14.55,94.75 v1(14.18,94.37) 11.7,91.89 11.7,90.6 HDMI1.18
5V_PWR:
  vias: v1(130.81,16.71) v1(130.76,12.72)
5V_PWR_2: length 167.5
  TOP w0.203: PU4501.14 131.66,38.02 132.41,37.28
  TOP w0.508: v2(133.42,34.1) v1(133.42,34.87) 133.42,35.25 132.38,36.29 PC4515.1 132.41,36.54 132.41,37.28
  L3 w0.508: v2(29.89,20.52) 38.15,20.52 40.17,18.49 41.64,18.49 44.22,15.92 44.22,14.82 47.57,11.47 52.47,11.47 53.26,12.26 v3(53.26,13.07)
  L4 w0.508: v2(112.98,13.28) 112.98,12.64 111.72,11.38 105.02,11.38 105.01,11.37 103.8,11.37 102.94,10.51 86.66,10.51 82.04,15.13 75.61,15.13 71.71,19.04 62.41,19.04 61.86,18.48 57.15,18.48 53.26,14.6 v3(53.26,13.07)
  BOTTOM w0.508: PC4520.2 133.46,35.31 PR4514.2 ; PC4520.2 135.43,34.97 136.6,36.14 136.6,39.95 135.33,41.22 135.33,44.48 133.89,45.92 126.87,45.92 124.03,43.07 124.03,41.21 122.13,39.31 120.89,39.31 119.33,37.75 119.33,36.04 117.55,34.27 117.55,21.53 112.98,16.96 v1(112.98,15.44) v2(112.98,13.28) ; PC4520.2 133.8,34.49 v2(133.42,34.1) ; R2915.1 31.51,20.13 31.13,20.52 v2(29.89,20.52)
5V_S0: length 177.1
  TOP w0.508: R6205.1 124.81,102.48 F6201.1 126.18,103.39 v1(127.13,104.33) 128.9,106.11 129.49,106.11 130.38,105.22 131.93,105.22 132.06,105.09 132.09,105.09 132.81,104.36 132.81,103.9 134.66,102.05 v2(137.34,102.05) ; v3(30.81,69.54) EC9724.1 31.13,70.36 31.6,69.89 R5230.1
  TOP w0.635: 196.67,72.71 199.21,75.25 199.21,84.4 197.91,85.69 197.05,85.69 ; 196.14,30.02 HDD1.P8 196.14,29.67 ; 196.14,31.29 HDD1.P9 196.14,30.94 ; 196.14,28.4 HDD1.P7 196.14,28.75
  L3 w0.508: v2(137.34,102.05) 137.34,101.51 135.64,99.81 135.17,99.81 134.31,98.95 134.31,86.43 138.69,82.05 138.69,80.89 137.75,79.95 137.44,79.95 136.47,78.98 136.47,72.97 134.77,71.26 134.77,64.25 135.53,63.49 135.53,58.34 143.71,50.16 143.71,46.04 148.03,41.72 148.98,41.72 149.68,41.02 149.68,37.16 149.98,36.85 149.98,35.33 150.87,34.44 150.87,31.65 151.25,31.27 151.25,30.76 151.81,30.2 151.81,28.03 155.6,24.24 155.6,23.87 155.61,23.87 157.05,22.44 v2(157.05,21.28)
  BOTTOM w0.203: U8302.4 v2(137.34,102.05)
  BOTTOM w0.508: D5401.3 24.99,90.37 R5409.1 24.99,92.98 25.55,93.54 v3(27,93.54) ; v3(164.82,9.52) 163.78,10.56 155.39,10.56 153.94,12.02 v1(153.94,16.6) 153.94,17.14 154.8,18 154.8,19.03 v2(157.05,21.28) ; v3(190.57,7.82) 190.47,7.91 EC9721.1
  BOTTOM w0.559: 34.49,94.05 35.91,94.05 36.8,94.94 C2605.1 36.97,93.96 C2611.1
  BOTTOM w0.635: 196.14,30.02 HDD1.P8 196.14,29.67 ; 196.14,30.94 HDD1.P9 196.14,31.29 ; 196.14,28.75 HDD1.P7 196.14,29.09
  BOTTOM w0.762: C2611.1 36.5,93.16 v3(36.14,93.16)
  vias: v1(25.73,76.95) v1(34.72,23.31) v1(131.37,4.74) v1(155.34,6.65) v1(187.3,51.33) v3(23.8,23.54) v3(23.8,22.57) v3(24.56,76.01) v3(25.47,76.01) v3(50.98,4.84) v3(51.89,4.84) v3(132.89,4.01) v3(133.73,4.01) v3(134.62,4.01) v3(135.53,4.01) v3(136.42,4.01) v3(137.31,4.01) v3(165.66,9.52) v3(166.49,9.52) v3(177.75,9.34) v3(178.64,9.09) v3(190.57,6.93) v3(191.46,7.82) v3(191.46,6.93) v3(193.75,30.42) v3(193.75,29.41)
5V_S5: length 467.4
  TOP w0.203: v3(131.59,8.94) 131.69,8.84 U3601.4 ; PU4901.12 103.2,14.95 102.99,15.15 102.99,15.16 102.46,15.69
  TOP w0.254: PR8230.2 149.04,81.48 148.41,80.84 146.62,80.84 145.75,81.7 PR8203.2
  TOP w0.305: PC4829.1 170.32,77.28 169.36,77.28 168.73,76.66 168.73,75.89 169.63,74.99 PU4806.7
  TOP w0.508: v2(115.9,139.64) 115.9,139.51 v1(114.48,138.1) 113.94,137.56 113.94,133.21 v2(114.04,133.11) 114.04,133.08 112.99,132.02 110.28,132.02 109.33,132.97 107.83,132.97 107.2,133.61 PR4603.2 ; v2(192.86,113.48) 192.86,131.13 190.19,133.8 190.19,146.86 189.68,147.36 v2(189.68,154.6) ; v2(170.57,77.79) PC4829.1 ; v2(139.67,86.5) 140.14,86.03 PR8232.1 PR8238.1 139.52,85.03 139.01,84.52 139.01,83.63 141.81,80.84 144.88,80.84 PR8203.2 ; PR4203.1 v2(112.6,143.32) ; PQ8201.G 156.65,89.89 155.73,88.97 155.73,87.32 154.9,86.49 PR8202.2 154.12,85.8 154.28,85.65 v2(154.28,84.14) ; v2(107.52,149.14) 107.52,149.17 107.49,149.17 106.28,147.96 106.28,145.52 v2(106.45,145.36) ; v2(103.58,18.28) 103.48,18.38 PC4901.1 102.46,15.69
  L3 w0.508: v2(192.86,113.48) 192.86,108.23 192.5,107.88 192.19,107.56 192.19,83.43 192.71,82.91 192.71,81.56 192.89,81.38 192.89,80.13 191.41,78.66 188.06,78.66 187.53,79.19 180.67,79.19 180.21,78.73 175.79,78.73 174.44,80.08 172.67,80.08 170.57,77.98 v2(170.57,77.79) 168.79,79.57 158.95,79.57 157.3,81.22 155.9,81.22 155.69,81.01 154.59,81.01 154.28,81.32 v2(154.28,84.14) ; v2(139.67,86.5) 139.75,86.43 139.75,84.9 139.59,84.9 139.22,84.53 139.22,83.34 139.7,82.86 139.7,80.47 138.17,78.94 137.86,78.94 137.49,78.56 137.49,65.34 136.35,64.2 v2(136.34,64.2)
  L4 w0.508: v2(189.68,154.6) 188.19,156.1 173.01,156.1 169.73,152.82 169.69,152.76 169.34,152.41 169.28,152.37 168.74,151.83 166.32,151.83 162.33,155.82 147.82,155.82 144.75,152.75 138.61,152.75 137.87,153.48 126.61,153.48 126.4,153.28 120.55,153.28 117.63,156.19 112.89,156.19 112.09,155.39 110.48,155.39 107.13,152.05 107.13,149.93 107.52,149.55 v2(107.52,149.14) ; v3(151.21,6.33) v3(152.1,6.33) 154.22,6.33 155.77,7.88 156.59,7.88 158.63,9.92 158.63,12.65 160.3,14.32 162.69,14.32 165.07,16.71 168.38,16.71 169.11,17.43 v2(169.11,17.58) ; v3(136.6,8.96) 140.23,8.96 144.04,12.77 144.04,36.54 143.3,37.28 143.3,44.7 142.9,45.1 142.9,49.42 135.84,56.48 135.84,63.7 v2(136.34,64.2) ; v2(106.45,145.36) 106.45,145.41 107.16,146.12 109.79,146.12 111.82,144.09 111.83,144.09 v2(112.6,143.32)
  BOTTOM w0.203: v2(136.34,64.2) 135.96,63.82 134.95,63.82 134.69,64.08 U3603.4
  BOTTOM w0.406: PQ4601.2 PQ4601.5 122.35,123 122.64,123.29 122.64,128.94 121.36,130.22 118.87,130.22 118.08,131.01 117.5,131.01 117.09,131.41 117.09,132.51 116.85,132.76 115.34,132.76 114.93,133.16 114.09,133.16 v2(114.04,133.11)
  BOTTOM w0.508: v2(154.28,84.14) 154.02,84.4 143.08,84.4 141.93,85.54 PR8227.2 140.32,85.86 v2(139.67,86.5) ; PR4629.2 PR4636.2 107.26,143.04 106.45,143.85 v2(106.45,145.36) ; 110.16,7.16 110.16,14.7 106.58,18.28 v2(103.58,18.28) ; 115.9,141.29 v2(115.9,139.64) 115.9,139.51 115.39,139.01 113.94,139.01 PR4604.2 ; 115.9,141.29 PR4672.1 ; 115.9,141.29 115.9,142.94 115.52,143.32 v2(112.6,143.32) 112.34,143.32 112.09,143.07 PR4670.1
  vias: v3(36.7,33.04) v3(36.7,32.12) v3(36.7,30.24) v3(133.09,8.98) v3(133.58,8.22) v3(133.96,8.98) v3(134.41,8.2) v3(134.85,8.98) v3(135.25,8.2) v3(135.71,8.98) v3(136.14,8.2)
+3V_1D5V_AVDD: length 2.1
  TOP w0.203: 34.52,6.77 34.63,6.89 HDA27.40
  TOP w0.254: v1(33.81,5.96) 33.81,6.06 34.52,6.77
+3V_AVDD: length 22.2
  TOP w0.203: 32.61,8.22 HDA27.36
  TOP w0.254: 32.61,8.22 32.26,7.87 v2(32.03,7.87) ; R2918.1 36.4,18 v2(36.35,18.05)
  BOTTOM w0.254: R2701.2 29.72,6.27 C2701.1 ; C2701.1 31.19,6.66 31.19,6.76 31.35,6.92 31.35,7.19 v2(32.03,7.87) ; C2701.1 v1(30.8,7.79) 30.8,9.61 32.28,11.09 32.28,12.31 33.35,13.38 36.26,13.38 R2722.1 36.92,14.21 37.56,14.85 37.56,16.68 37.41,16.82 37.41,17.49 36.85,18.05 v2(36.35,18.05)
+5V_AVDD: length 13.5
  TOP w0.203: HDA27.26 31.93,12.54 30.99,13.48 30.99,13.5
  TOP w0.508: 30.99,13.5 30.76,13.73 30.76,13.87 C2711.1 29.3,14.48 C2710.1 28.92,14.85 v2(28.14,14.85)
  BOTTOM w0.508: v2(28.14,14.85) 28.09,14.85 v1(27.03,15.91) 25.09,17.85 R2703.1
+5V_KB_BL: length 7.4
  TOP w0.305: AFTP6248.1 129.31,101.56 KBLIT1.1
  TOP w0.508: AFTP6248.1 129.13,101.51 C6204.1 126.58,100.21 F6201.2 124.56,100.6 R6205.2
+5V_MINI_DEBUG: length 9.3
  TOP w0.508: v2(190.4,19.3) 190.3,19.3 189.76,19.84 189.76,20.54 191.54,22.32 191.54,23.93 R5801.2 R5805.2 189.85,24.13 189.56,24.43 v1(189.53,24.43)
  BOTTOM w0.457: WLAN1.51 v2(190.4,19.3)
+5V_PVDD: length 1.4
  TOP w0.203: 35.03,6.33 HDA27.41
  vias: v1(41.88,2.81)
GND: length 1413.1
  TOP w0.203: v2(171.65,23.56) 171.29,23.21 KBC24.116 ; v3(107.77,15.69) 107.77,15.45 107.26,14.95 PU4901.4 ; v2(105.74,17.09) 105.63,16.98 PU4901.7 ; U3601.11 U3601.15 ; KBC24.89 160.7,26.5 v2(160.58,26.62) ; KBC24.18 178.69,30.5 v2(179.15,30.03) ; v2(104.21,16.96) 104.43,16.74 PU4901.10 ; v2(39.93,9.59) 39.78,9.74 HDA27.4 ; v2(93.83,25.67) 94.51,24.99 94.51,24.45 94.28,24.22 v2(93.75,24.22) ; KBC24.5 178.58,25.3 179.42,26.14 v2(179.42,26.42) ; KBC24.12 178.67,28.1 v2(178.91,27.86) ; KBC24.78 161,30.9 v2(160.74,30.64) ; KBC24.45 171.29,38.76 171.18,38.87 v2(171.18,38.95) ; R7317.1 170.98,122.43 170.88,122.34 170.18,122.34
  TOP w0.254: v2(156.31,120.41) 156.31,120.67 156.96,121.31 157.4,121.31 157.67,121.58 158.35,121.58 C7624.1 ; v2(160.3,122.83) 160.92,123.45 C7609.1 ; AFTP6235.1 v2(170.94,63.4) ; v2(59.38,27.5) 59.38,26.93 C1221.2 ; C1211.2 C1210.2 108.98,23.75 109.35,24.13 v2(109.35,24.22) ; AFTP6201.1 184.27,65.68 v2(184.1,65.85) ; v2(110.72,27.74) 110.91,27.74 111.22,28.06 111.22,28.94 C1212.2 C1209.2 111.17,29.95 C1201.2 C1202.2 ; G701.2 114.75,101.67 v2(116.15,101.67)
  TOP w0.305: v2(40.95,82.66) LCD1.13 ; LCD1.19 37.95,82.62 v2(37.95,82.62) ; v2(96.47,137.53) 96.8,137.2 SW1.1 ; KB1.1 189.45,105.84 v2(189.05,106.24) ; 124.42,36.28 124.9,36.28 125.3,35.88 125.3,35.25 125.57,34.98 PQ4502.4 ; 124.42,36.28 PQ4502.1 ; 124.42,36.28 v2(125.11,36.96) ; LCD1.25 34.95,82.17 v2(34.87,82.08) ; AFTP6802.1 97.66,140.43 96.58,139.35 SW1.5 ; LCD1.29 v2(32.95,82.54) ; v2(96.47,136.72) 96.47,136.67 96.94,136.2 SW1.2 ; v2(39.35,82.66) 39.45,82.76 LCD1.16 ; LCD1.23 35.95,84.46 v2(35.63,84.78) 35.45,84.59 LCD1.24 ; 35.82,55.31 EC3106.1 ; 35.82,55.31 v2(35.58,55.31) ; 35.82,55.31 EC3107.1 ; v2(159.29,141.39) 159.39,141.49 VRAM1.M1 ; U3102.8 v2(32.08,55.31) ; PU4404.14 v2(139.5,125.16) ; LCD1.36 v2(29.45,82.73)
  TOP w0.356: v2(159.21,148.95) 159.39,148.76 VRAM1.M9 ; v2(160.59,148) 160.98,148.39 VRAM1.P9 ; VRAM3.F9 181.19,141.99 v2(181.59,142.4) 181.99,142.79 VRAM3.E8 ; v2(155.28,141.44) 155.39,141.55 VRAM1.G1 ; VRAM3.B3 184.4,146.79 v2(184.83,146.36) ; VRAM1.J2 156.99,142.79 v2(157.39,143.2) ; v2(175.17,142.37) 175.15,142.35 175.15,142.35 VRAM3.P9 ; v2(153.39,142.39) 152.99,141.99 VRAM1.D1 ; v2(153.39,142.39) 153.39,142.39 VRAM1.E1 ; v2(153.39,142.39) 153.79,142.79 VRAM1.E2 ; VRAM1.T1 162.69,141.99 v2(163.08,142.39) ; VRAM1.F9 154.59,148.39 v2(154.19,148) 153.79,147.59 VRAM1.E8 ; v2(182.39,148) 182.78,148.39 VRAM3.D1 ; v2(182.39,148) 181.99,148.39 VRAM3.E1 ; v2(182.39,148) 181.99,147.6 VRAM3.E2 ; v2(150.98,144.02) 151.39,143.61 VRAM1.B3 ; VRAM3.B1 184.39,148.41 v2(184.78,148.8) ; v2(152.59,147.2) 152.98,147.59 VRAM1.D8 ; v2(176.01,148.01) 176.39,148.38 VRAM3.M1 ; v2(173.59,142.39) 173.19,141.99 VRAM3.T9 ; VRAM3.G8 180.39,142.79 v2(179.99,142.39) 180.39,141.99 VRAM3.G9 ; VRAM3.P1 174.8,148.39 v2(175.2,147.99) ; THM26.5 126.33,61.07 126.69,60.7 v2(126.69,60.14) ; VRAM1.A9 150.7,148.5 150.7,148.52 v2(151,148.83) 151.39,148.44 VRAM1.B9 ; v2(162.19,148) 162.2,148 VRAM1.T9 ; VRAM3.M9 176.76,141.62 176.76,141.61 v2(176.8,141.58) ; v2(183.19,143.19) 182.79,142.79 VRAM3.D8 ; v2(151,141.59) 151.39,141.97 VRAM1.B1 ; v2(178.39,147.99) 178.79,147.59 VRAM3.J2 ; v2(180.79,147.99) 180.39,148.39 VRAM3.G1 ; v2(169.77,122.67) 170.03,122.93 C7610.1 ; VRAM3.T1 173.59,147.99 v2(173.59,147.99) ; VRAM1.G8 155.39,147.59 v2(155.79,148) 155.4,148.39 VRAM1.G9 ; R7419.2 176.31,123.88 v2(176.4,123.97) ; R1909.2 102.03,89.47 102.03,89.88 v2(102.59,90.43) ; VRAM1.J8 156.99,147.59 v2(157.39,147.2) ; v2(161.39,142.39) VRAM1.P1 ; v2(167.86,121.06) 167.86,121.68 C7608.1 C7607.1 ; VRAM3.B9 184.39,141.95 v2(184.78,141.56) 185.19,141.97 VRAM3.A9 ; VRAM3.J8 178.79,142.79 v2(178.39,142.39)
  TOP w0.381: PQ4408.4 v2(132.08,117.29) ; v2(137.23,81.98) 137.42,81.79 C6202.2 ; PC4425.2 135.26,115.29 PQ4408.1 ; v2(166.69,18.15) 166.71,18.16 R2435.2 ; v2(28.32,23.92) 28.32,24.5 28.56,24.74 R3626.2 ; R1928.2 107.66,82.38 v2(107.19,81.91) ; PQ8305.1 v2(144.98,77.65) ; R425.2 70.16,83.58 69.88,83.86 v2(69.82,83.86) ; R5202.1 52.14,75.32 v2(52.14,74.69) ; U8201.3 v2(155.08,81.73) ; v2(144.98,78.94) 144.97,78.95 PQ8305.4 ; v2(158.21,37.76) 158.44,37.53 R2447.1
  TOP w0.406: 137.48,41.91 137.4,41.91 136.88,42.43 136.88,43.21 136.96,43.29 PQ4501.1 ; TPAD1.4 132.9,94.94 v2(132.39,95.45) ; R621.2 106.65,86.9 106.56,86.99 105.16,86.99 105.11,86.94 C1001.2 ; R629.2 122.3,90.37 122.99,89.67 v2(122.99,88.98) ; PQ4501.4 138.38,46.09 v2(138.86,45.61)
  TOP w0.508: v2(180.82,35.3) 181.29,35.77 R2442.2 ; EC9749.2 141.47,13.44 v3(141.4,13.5) ; C1224.2 76.65,31.82 v2(76.02,32.45) ; EC6105.2 178.09,16.16 v2(177.8,16.45) ; v2(39.44,7.84) 39.44,7.62 C2717.2 ; v2(173.09,122.85) 173.09,122.63 173.81,121.91 C7779.1 C7781.1 C7780.1 175.59,122.12 175.98,122.51 v2(176.8,122.51) ; PR4824.2 172.73,77.67 v2(172.86,77.79) ; PR8241.2 140.89,83.23 v2(139.85,84.27) ; 3.6,17.16 3.84,17.4 USB1.13 ; v2(153.74,122.32) 154.2,121.86 R7408.1 ; R423.2 70.61,86.11 69.99,86.11 69.49,86.61 v2(69.49,86.94) 68.66,86.11 C2608.2 ; PC4425.2 135.65,114.9 136.56,114.9 PR4436.2 v2(136.6,115.64) ; R3023.2 47.32,51.31 v2(47.32,51.25) ; v2(176.35,136.21) 176.41,136.21 R8904.1 ; C2901.2 40.9,17.4 41.3,17.8 v2(41.3,17.86) ; C1213.2 72.44,22.09 72.57,21.96 v2(72.57,21.91) ; PC8219.2 PC8213.2 149.87,81.54 v2(149.81,81.48) ; v2(127.18,98.38) 127.18,98.66 C6204.2 ; v2(80.29,32.76) 80.34,32.71 C1219.2 ; v2(135.44,106.71) 133.98,106.71 KBLIT1.6 ; v2(151.97,85.67) 152.45,86.15 PC8202.2 ; PC4918.2 107.83,18.17 v2(107.64,18.36) ; C3625.2 139.14,66.36 v2(138.88,66.62) ; 14.27,18 13.67,17.4 USB1.11 ; ED2904.2 v2(25.22,6.55) ; C1062.1 92.59,72.87 v2(92.69,72.97) ; PC8205.2 153.26,96.59 v2(152.35,96.59) PC8236.1 ; EC3105.1 v2(35.61,58.42) ; SW1.5 93.89,139.35 v2(93.67,139.13) ; EC6208.2 134.63,77.32 v2(134.39,77.08) ; 11.38,35.45 11.42,35.49 USB2.5 13.33,36.7 13.43,36.59 ; EC9703.2 100.16,11.62 v2(100.49,11.28) ; CCD1.8 21.3,87.66 v2(21.61,87.34) ; v2(116.79,64.08) 117.02,63.85 C2601.2 ; v2(101.5,92.07) 101.7,92.27 101.94,92.51 R1902.1 ; C1053.2 105,64.71 v2(104.93,64.79) ; PR4633.2 91.07,82.3 92.05,83.28 C1077.2 ; C2609.2 67.3,83.55 66.98,83.86 v2(66.98,83.91) ; v2(125.3,88.46) 125.68,88.08 125.68,86.55 125.3,86.16 C1038.2 125.02,85.75 C1036.2 C1037.2 123.21,85.73 R647.1 ; HDT1.3 v2(55.19,75.25) ; v2(48.54,42.89) 48.2,42.55 SPR2.1 ; v2(88.01,86.48) 87.44,86.48 R401.2 ; v2(125.42,91) 126,91 TPAD1.10 ; EC9740.2 114.69,132.47 v2(114.63,132.53) ; 10.61,33.09 10.9,32.8 USB1.10 ; EC9724.2 v2(29.92,71.25) ; C1216.2 82.6,21.4 v2(82.88,21.4) ; C1225.2 76.91,21.68 v2(76.71,21.48) ; PR4823.2 v2(176.98,75.38) ; v2(39.32,52.57) 39.32,52.05 C3013.2 ; C1055.2 86.92,62.81 v2(86.31,62.81) ; v2(179.28,19.52) 178.76,19.01 EC6103.2 ; R6207.2 141.87,78.55 C6203.2 141.87,79.48 141.14,80.21 v2(140.79,80.21) ; v2(157.17,30.68) 157.66,31.16 C2411.2 ; v2(34.87,82.08) 34.94,82.02 R5201.2 ; U3602.2 v2(26.08,22.06) ; v2(38.94,17.96) 39.18,17.72 R2717.2 ; PR4519.2 v2(133.68,45.23) ; v3(152.61,34.54) 152.03,34.54 150.53,33.04 Q2403.S ; EC3108.1 v2(35.57,52.2) ; v2(154.72,22.7) 155.28,23.26 C2610.2 ; C2408.2 C2410.2 180.68,29.94 179.25,29.94 v2(179.15,30.03) ; v2(165.78,42.71) 166,42.93 R2437.2 ; LCD1.42 26.26,86.7 v3(26.66,87.1) ; PC4622.2 v2(108.15,142.82) ; EC9715.2 v2(148.73,95.89) ; 6.96,33.16 6.59,32.8 USB1.12 5.28,33.7 5.2,33.77 ; v2(104.82,79.82) 104.82,79.86 105.04,80.08 R632.2 ; v2(44.4,8.7) 44.12,8.43 C2723.1 ; PC8203.2 147.24,81.48 v2(148.16,81.48) PR8231.1 ; PR4202.2 109.36,148.34 PQ4204.E 108.79,148.04 v2(108.2,148.63) ; USB1.10 12.71,33.96 12.67,34 ; USB1.10 14.94,32.8 14.96,32.78 ; 12.67,16.32 12.71,16.36 USB1.11 ; v2(112.72,19.38) 113.41,19.38 EC9709.2 ; Q3001.S v2(42.75,52.46) ; 5.2,16.4 5.28,16.48 USB1.13 ; C1054.2 86.81,61.16 86.29,61.68 v2(86.29,62.02) ; v2(18.87,24.01) 19.73,24.01 U3403.2 ; v2(130.12,45.28) PC4501.2 PR4507.2 ; v2(52.25,73.52) 52.25,73.31 C5204.2 ; ED2901.2 v2(25.08,8.41) ; v2(105.26,9.97) 105.57,9.97 105.89,9.66 PR4902.2 PR4908.2 ; R6208.2 133.87,65.69 134.92,66.74 v2(135.84,66.74) ; Q701.S 110.63,99.95 v2(109.17,101.41) ; IOBD1.16 v2(183.17,20.15) ; EC9701.2 v2(116.28,121.73) ; C705.2 121.23,98.85 v2(121.23,98.49) ; v2(149.65,124.83) 150.3,124.83 C7402.2 R7414.2 ; PC4902.2 PC4903.2 105.48,20.9 v2(105.61,21.02) PR4906.2 ; USB1.11 11.08,17.4 10.84,17.16 ; PC4516.2 v2(137.36,37.91) ; C1222.2 v2(85.54,21.4) ; EC9735.2 36,68.31 v2(36.19,68.5) ; C701.2 C702.2 116.79,99.13 117.4,98.52 v2(117.83,98.52) ; v2(183.46,78.55) 183.8,78.89 KB1.32 ; EC2709.2 43.48,11.21 v2(43.51,11.24) 43.03,11.24 C2718.2 ; EC9710.2 118.06,34.58 118.18,34.71 118.18,35.91 v2(118.18,35.91) ; EC9711.2 v2(153.05,57.01) ; C1076.2 91.2,92.57 v2(91.53,92.24) ; U3503.2 v3(29.49,32.68) ; EC4301.2 143.2,141.52 D4301.1 v2(143.96,141.93) ; USB1.13 6.64,17.4 6.96,17.09 ; EC6205.2 131.96,77.32 v2(131.77,77.13) ; v2(150.31,128.16) R7415.2 C7403.2 ; v2(188.05,34.5) C2421.2 ; 12.29,40.48 12.27,40.46 USB2.4 ; C1214.2 72.65,31.25 v2(73.73,32.33) ; C6402.2 12.46,74.65 C6401.2 v2(13.12,74.63) ; C1215.2 v2(89.23,21.28) ; C1096.2 C1092.1 C1095.2 116.09,96.27 C1016.2 C1015.2 118.48,96.36 C1093.2 v3(118.56,97.14) ; v2(105.61,81.91) 105.61,82.08 106.08,82.55 R1903.1 ; PC4502.2 v2(131.9,45.28) ; v2(159.97,100.91) 159.71,100.65 EC9741.2 ; HDT1.17 v2(55.26,66.36) ; PR4522.2 v2(120.98,38.5) ; R5418.1 v2(22.36,80.81) 23,80.17 Q5403.S ; HDT1.7 v2(55.19,72.71) ; C1001.2 104.72,86.87 104.72,86.11 C1022.2 105.5,85.34 v2(105.71,85.34) ; v2(182.93,34.1) 183.23,34.4 Q2401.S ; v2(171.18,38.95) 171.13,39 171.13,39.05 170.72,39.45 C2416.2 ; EC9747.2 v2(128.22,119.64) ; v2(183.08,28.06) 182.4,27.38 R2445.2 ; C5804.2 180.67,41.47 v2(179.4,40.2) ; U3504.2 30.15,29.02 29.54,28.41 v3(29.54,26.69) ; C3019.2 34.33,38.02 C3012.2 v2(35.13,37.15) ; C1218.2 87.45,32.43 v2(87.73,32.71) ; PC8216.2 142,91.25 PC8217.2 v2(141.93,91.89) ; R5604.2 v2(198.19,76.9) ; v3(102.44,20.69) 102.46,20.67 PC4901.2 ; v2(108.02,19.65) 108.63,20.26 C1208.2 ; EC9742.2 v2(140.47,113.8) ; C2719.2 v2(43,13.66) ; C1059.1 101.36,72.94 v2(101.4,72.98) ; PC4517.2 128.95,34.23 v3(129.49,34.23) 129.56,34.31 PC4518.2 ; 13.21,49.7 13.01,49.5 USB2.6 11.42,50.89 11.45,50.92 ; D4302.1 v2(136.22,138.88) ; v2(132.66,34.1) 132.15,34.61 PC4515.2 ; IOBD1.10 182.84,14.15 v2(183.71,13.28) ; EC4305.1 v2(135.96,136.34) ; v2(90.31,21.28) C1205.2 ; C2716.2 42.4,6 41.82,6.58 EC2701.2 41.98,7.02 42.71,7.02 v2(42.87,7.18) ; v2(149.27,33.06) 148.22,32.01 EC9704.2 ; PC4703.1 v2(112.75,133.48) ; PR4432.2 137.78,119.16 v2(137.61,119.32) ; v2(106.25,140.53) 106.37,140.66 PR4663.2 ; D4303.1 v2(139.77,138.88) ; v2(139.88,87.29) 140.55,87.29 PR8234.2 ; v2(82.04,32.66) 82.37,32.33 C1223.2 ; EC9712.2 v2(168.92,69.35) ; v2(85.65,72.33) 85.71,72.27 C502.2 C501.2 ; PR4433.2 v2(143.38,118.99) 143.38,117.9 PC4401.2 ; v2(34.36,52.14) C3004.2 33.56,51.27 C3017.2 C3106.2 ; Q2404.C 153.09,26.07 v2(153.09,25.86) ; C3612.2 v2(29.08,19.63) ; USB2.4 13.09,39.6 13.36,39.87 ; USB2.4 11.49,39.6 11.38,39.72 ; PC8218.2 v2(143.84,93.29) ; R5413.2 23.34,76.9 v2(23.11,77.13) ; v2(29.16,7.18) 29.35,7.37 C2704.1 ; C1217.2 80.21,22.01 79.6,21.4 v2(79.32,21.4) ; R3602.2 152.06,25.33 v2(151.78,25.61) ; U701.2 v2(119.45,103.19) ; PC4829.2 v2(171.46,77.79) ; v2(100.15,88.07) 100.18,88.07 100.54,88.43 C1035.2 C1012.2 ; KB1.31 183.8,107.82 v2(185.21,109.24) ; EC4302.2 v2(142.95,136.34) ; v2(186.83,21.52) 186.05,22.3 IOBD1.18 ; v2(135.37,100.44) 134.34,99.41 133.93,99.41 KBLIT1.5 ; C1050.2 v2(89.28,74.23) ; v2(103.81,88.83) 104.15,88.49 C1034.2 ; PR4817.1 v2(176.16,71.82) ; PC4906.2 v2(102.44,9.87) ; v2(43.89,37.53) 45.45,35.97 EC9737.2 ; C1220.2 v2(90.37,32.63) ; v2(137.61,91.38) 137.7,91.3 TPAD1.9 ; v3(50.11,81.6) v3(49.48,80.97) ; v2(185.98,154.63) 185.98,154.52 185.87,154.42 C8912.2 ; C3626.2 v2(139.24,62.3) ; v2(94.85,72.97) 94.75,72.88 C1061.1 ; PC4528.2 135.74,41.28 135.8,41.22 136.32,41.22 v2(136.34,41.19) 136.76,41.19 PR4502.2 137.48,41.91 ; PC4838.2 v3(160.98,74.62) ; v2(111.83,101.8) 111.83,102.62 R702.2 111.9,103.32 R706.2 ; C2602.2 v2(120.29,64.14) ; EC9714.2 v2(118.11,115.51) ; HDT1.5 v2(55.19,73.98) ; PC4831.2 v2(176.98,74.49) ; PR4521.2 v2(125.11,36.96) ; v2(103.71,140.53) PR4681.2 ; ED2905.2 v2(25.08,10.22) ; v2(159.2,28.19) 159.14,28.19 C2418.2
  TOP w0.61: IOBD1.13 v2(183.7,17.15) ; IOBD1.7 v2(183.7,11.15)
  TOP w0.635: 196.14,35.1 HDD1.P12 197.66,35.1 ; HDD1.S7 197.66,14.78 ; HDD1.S7 196.14,14.78 ; HDD1.S7 196.9,15.47 ; 14.69,20.89 USB1.4 ; USB1.4 14.69,22.31 ; USB1.4 15.4,21.6 ; ODD1.6 201.49,86.35 ; ODD1.6 200.01,86.35 ; ODD1.6 200.75,85.61 ; ODD1.6 200.75,87.09 ; 201.46,71.33 ODD1.S4 201.46,70.97 ; 197.71,93.72 S1.1 200.02,92.84 ; 121.19,155.4 BAT1.11 ; BAT1.11 122.96,155.4 ; BAT1.11 122.07,153.48 ; 143.44,155.4 BAT1.10 ; BAT1.10 144.32,153.48 ; BAT1.10 145.21,155.4 ; RJ45.9 9.62,53.18 ; RJ45.9 6.14,53.18 ; RJ45.9 7.88,52.29 ; HDD1.24 197.63,42.19 ; HDD1.24 197.63,40.03 ; HDD1.24 195.85,41.11 ; 202.25,84.61 ODD1.5 ; ODD1.5 201.51,85.35 ; ODD1.5 202.25,86.09 ; RJ45.10 7.88,73.11 ; RJ45.10 6.14,72.23 ; RJ45.10 9.62,72.23 ; 124.52,154.72 BAT1.9 ; BAT1.9 125.88,154.72 ; BAT1.9 125.88,156.08 ; BAT1.9 124.52,156.08 ; 201.46,75.14 ODD1.S7 202.25,75.85 ; 196.14,7.16 HDD1.S1 196.9,6.46 ; 126.52,154.72 BAT1.8 ; BAT1.8 126.52,156.08 ; BAT1.8 127.88,156.08 ; BAT1.8 127.88,154.72 ; 197.66,26.55 HDD1.P5 197.66,26.21 ; 202.25,66.81 ODD1.S1 201.46,67.52 ; HDMI1.21 10.55,94.44 ; HDMI1.21 11.99,93.45 ; HDMI1.21 10.55,92.46 ; 201.55,62.39 ODD1.15 199.77,63.47 ; 195.85,4.96 HDD1.23 ; HDD1.23 197.63,6.04 ; HDD1.23 197.63,3.88 ; 10.55,77.96 HDMI1.20 ; HDMI1.20 10.55,79.94 ; HDMI1.20 11.99,78.95 ; 4.05,76.06 HDMI1.22 5.49,77.05 ; 196.14,32.56 HDD1.P10 197.66,32.56 ; 131.88,156.08 BAT1.6 130.52,156.08 ; 197.66,27.48 HDD1.P6 197.66,27.82 ; 197.66,25.28 HDD1.P4 197.66,24.94 ; 201.55,91.41 ODD1.14 199.77,90.33 ; 197.66,10.97 HDD1.S4 196.14,10.97
  TOP w0.762: 3.15,51.99 2.11,50.95 USB2.8 ; S1.1 201.72,97.73 201.72,99.66
  TOP w1.016: 3.68,34.15 2.59,35.25 USB2.7
  L3 w0.381: 11.4,50.66 11.42,50.65 USB2.6 13.23,49.5 13.23,49.5 ; 3.63,17.29 3.74,17.4 USB1.13 ; 13.23,36.7 USB2.5 11.42,35.54 11.4,35.53 ; USB1.7 13.19,25.63 13.49,25.93 ; USB1.7 14.08,25.1 ; USB1.7 13.19,24.59 13.38,24.4 ; 12.71,33.84 USB1.10 ; USB1.10 11.18,32.8 10.89,33.09 ; USB1.10 14.52,32.8 ; 13.22,39.6 USB2.4 ; USB2.4 11.15,39.6 v2(11.05,39.7) ; USB2.4 12.27,40.65 12.27,40.66 ; USB1.13 6.72,17.4 6.88,17.24 ; USB1.13 5.28,16.45 ; 3.68,32.99 3.87,32.8 USB1.12 ; 6.9,32.8 USB1.12 ; USB1.12 5.28,33.77
  L3 w0.508: v2(28.32,23.92) 29.08,23.16 v2(29.08,19.63) ; USB2.7 2.48,35.25 3.22,34.51 ; USB2.8 2.09,50.95 3.02,51.88
  L3 w0.635: 199.81,90.33 ODD1.14 201.55,91.41 ; 196.9,6.46 HDD1.S1 196.14,7.16 ; HDD1.23 197.63,6 ; HDD1.23 195.89,4.96 ; HDD1.23 197.63,3.91 ; 202.25,66.81 ODD1.S1 201.46,67.52 ; ODD1.6 200.75,87.09 ; ODD1.6 200.75,85.61 ; ODD1.6 200.01,86.35 ; ODD1.6 201.49,86.35 ; BAT1.8 127.88,154.72 ; BAT1.8 126.52,154.72 ; BAT1.8 126.52,156.08 ; BAT1.8 127.88,156.08 ; 14.69,20.89 USB1.4 ; USB1.4 15.4,21.6 ; USB1.4 14.69,22.31 ; 196.14,32.56 HDD1.P10 197.66,32.56 ; 5.49,77.05 HDMI1.22 4.05,76.06 ; 202.25,75.85 ODD1.S7 201.46,75.14 ; HDD1.S7 196.9,15.47 ; HDD1.S7 197.66,14.78 ; HDD1.S7 196.14,14.78 ; RJ45.10 9.62,72.23 ; RJ45.10 6.14,72.23 ; RJ45.10 7.88,73.11 ; HDD1.24 197.63,42.15 ; HDD1.24 195.89,41.11 ; HDD1.24 197.63,40.06 ; BAT1.6 131.88,156.08 ; BAT1.6 131.88,154.72 ; BAT1.6 130.52,156.08 ; BAT1.6 130.52,154.72 ; 143.44,155.4 BAT1.10 145.21,155.4 ; BAT1.9 125.88,154.72 ; BAT1.9 124.52,154.72 ; BAT1.9 125.88,156.08 ; BAT1.9 124.52,156.08 ; 197.66,26.21 HDD1.P5 196.14,26.21 ; HDMI1.20 10.55,79.94 ; HDMI1.20 11.99,78.95 ; HDMI1.20 10.55,77.96 ; HDMI1.21 11.99,93.45 ; HDMI1.21 10.55,94.44 ; HDMI1.21 10.55,92.46 ; 121.19,155.4 BAT1.11 ; BAT1.11 122.07,153.48 ; BAT1.11 122.96,155.4 ; 201.46,71.33 ODD1.S4 201.46,70.97 ; 201.55,62.39 ODD1.15 199.81,63.47 ; 7.88,52.29 RJ45.9 ; RJ45.9 9.62,53.18 ; RJ45.9 6.14,53.18 ; 196.14,10.97 HDD1.S4 197.66,10.97 ; S1.1 200.02,97.9 ; S1.1 201.89,96.03 ; S1.1 198.15,96.03 ; S1.1 200.02,94.16 ; 196.14,24.94 HDD1.P4 197.66,24.94 ; 197.66,27.48 HDD1.P6 196.14,27.48 ; ODD1.5 202.25,86.09 ; ODD1.5 201.51,85.35 ; ODD1.5 202.25,84.61 ; 196.14,35.1 HDD1.P12 197.66,35.1
  L3 w1.016: HDMI1.23 6,95.35 6.02,95.37
  L4 w0.508: USB1.12 5.28,33.87 5.31,33.9 ; USB1.12 6.75,32.8 6.93,32.99 ; USB1.12 4.02,32.8 3.68,33.14 ; 10.84,33.14 11.18,32.8 USB1.10 ; 5.26,16.32 5.28,16.35 USB1.13 ; USB1.11 12.71,16.34 12.72,16.32 ; USB1.11 11.06,17.4 10.84,17.19 ; USB1.11 14.71,17.4 14.76,17.44 ; 13.28,36.59 13.18,36.7 USB2.5 11.42,35.54 11.4,35.53 ; USB1.13 3.84,17.4 3.63,17.19 ; USB1.13 6.67,17.4 6.93,17.14 ; USB2.4 12.27,40.55 12.27,40.56 ; USB2.4 11.39,39.6 11.3,39.69 ; USB2.4 13.29,39.6 13.33,39.64 ; v2(13.55,49.61) 13.44,49.5 USB2.6 11.42,50.78 11.45,50.82 ; 12.67,34 12.71,33.96 USB1.10 ; 13.33,25.87 13.19,25.73 USB1.7 ; USB1.10 14.48,32.8 14.55,32.73 ; USB1.7 14.03,25.1 14.04,25.11 ; USB1.7 13.19,24.54 13.43,24.3
  L4 w0.635: BAT1.8 127.88,154.72 ; BAT1.8 126.52,156.08 ; BAT1.8 126.52,154.72 ; BAT1.8 127.88,156.08 ; 201.89,96.03 S1.1 200.02,94.16 ; 122.96,155.4 BAT1.11 121.19,155.4 ; HDMI1.20 10.55,79.94 ; HDMI1.20 10.55,77.96 ; HDMI1.20 11.99,78.95 ; USB1.4 14.69,22.31 ; USB1.4 15.4,21.6 ; USB1.4 14.69,20.89 ; HDMI1.21 11.99,93.45 ; HDMI1.21 10.55,92.46 ; HDMI1.21 10.55,94.44 ; 201.46,67.52 ODD1.S1 202.25,66.81 ; RJ45.9 9.62,53.18 ; RJ45.9 7.88,52.29 ; RJ45.9 6.14,53.18 ; BAT1.9 125.88,154.72 ; BAT1.9 124.52,154.72 ; BAT1.9 125.88,156.08 ; BAT1.9 124.52,156.08 ; 201.55,62.39 ODD1.15 199.81,63.47 ; 200.75,85.61 ODD1.6 ; ODD1.6 200.01,86.35 ; ODD1.6 201.49,86.35 ; ODD1.6 200.75,87.09 ; 130.52,154.72 BAT1.6 ; BAT1.6 131.88,156.08 ; BAT1.6 131.88,154.72 ; BAT1.6 130.52,156.08 ; 201.55,91.41 ODD1.14 199.81,90.33 ; 143.44,155.4 BAT1.10 145.21,155.4 ; 5.49,77.05 HDMI1.22 4.05,76.06 ; RJ45.10 7.88,73.11 ; RJ45.10 9.62,72.23 ; RJ45.10 6.14,72.23 ; 202.25,86.09 ODD1.5 201.51,85.35
  L4 w0.762: 3.07,51.88 2.14,50.95 USB2.8 ; USB2.7 2.53,35.25 3.38,34.41
  L4 w1.016: 6.07,95.47 5.95,95.35 HDMI1.23
  BOTTOM w0.203: v2(174.04,125.59) 174.37,125.26 174.85,125.26 175.23,125.64 GPU1.F2 ; GPU1.B8 171.89,128.64 v2(171.79,128.75) ; v2(160.79,129) 160.69,128.9 GPU1.B22 ; GPU1.B26 157.49,128.64 v2(157.52,128.67) ; v2(173.57,128.76) 173.48,128.67 173.48,127.65 GPU1.B6 ; U8302.11 v2(142.31,102.05) ; U3603.15 U3603.11 130.25,64.08 130.12,63.95 v2(129.87,63.95) ; GPU1.B12 v2(168.69,128.59)
  BOTTOM w0.229: GPU1.H2 175.56,123.97 v2(176.4,123.97)
  BOTTOM w0.254: C603.2 100.72,101.22 v2(101.04,101.54) ; v2(65.54,28.62) 65.25,28.62 64.65,29.22 DM1.49 ; v2(52.1,24.45) 52.35,24.2 DM1.8 ; v2(50.04,24.2) 50.55,23.69 DM1.2 ; DM1.155 98.85,27.86 100.15,26.56 v2(100.33,26.56) ; CPU1.L3 91.89,92.24 v2(91.53,92.24) 91.21,92.24 CPU1.J3 ; DM1.195 110.85,31.98 111.92,33.05 v2(112.17,33.05) ; CPU1.C23 87.73,81.48 87.73,82.52 CPU1.C21 ; C1905.1 92.53,98.18 v2(92.53,98.82) ; v2(110.97,24.88) 110.98,24.88 111.45,24.41 111.45,23.95 111.15,23.65 DM1.196 ; CPU1.G3 90.11,92.24 v2(90.42,92.24) ; DM1.20 55.95,24.58 56.36,24.98 v2(56.36,24.98) ; v2(88.08,73.15) 88.28,73.35 CPU1.E38 ; CPU1.L41 92.1,70.53 v2(92.23,70.4) ; v2(107.77,70.55) 107.55,70.77 CPU1.AW41 ; CPU1.E3 89.11,92.45 v2(89.31,92.24) ; VRAM1.G1 155.47,142.07 155.47,142.71 VRAM2.G8 ; DM1.150 v2(97.35,24.2) ; v2(61.92,24.88) 61.89,24.88 61.35,24.34 DM1.38 ; DM1.156 v2(99.15,24.2) ; v2(69.67,26.1) 69.14,26.1 68.2,25.16 68.2,23.99 67.95,23.75 DM1.60 ; DM1.44 63.15,24.54 63.57,24.96 v2(63.7,24.96) ; v2(53.92,27.25) 55.65,28.97 DM1.19 ; CPU1.M1 CPU1.M2 v2(92.65,91.94) 92.69,91.94 CPU1.N3 ; DM1.138 v2(93.75,24.22) ; CPU1.BA15 108.87,85.88 108.24,85.88 108.2,85.85 CPU1.AY15 ; DM1.13 53.85,29.49 53.82,29.49 v2(53.82,29.46) ; v2(59.44,29.46) 59.25,29.65 DM1.31 ; CPU1.B31 86.97,77.02 86.33,77.02 CPU1.A31 ; R1926.2 114.17,88.07 v2(114.17,87.98) ; DM1.48 64.35,24.09 v2(65.22,24.96) ; DM1.145 95.85,27.92 95.45,27.53 v2(94.38,27.53) ; v2(52.14,29.21) 52.65,29.71 DM1.9 ; DM1.72 71.55,23.54 71.84,23.83 71.84,24.44 71.45,24.83 v2(71.19,24.83) ; DM1.167 102.45,29.16 104.57,27.04 104.57,26.22 103.97,25.63 v2(103.9,25.63) ; v2(85.65,74.76) 85.74,74.85 CPU1.A35 ; v2(116.84,38.55) 116.57,38.82 DM1.206 ; CPU1.C41 v2(87.65,70.67) ; v2(85.65,72.33) 85.92,72.6 86.17,72.6 ; DM1.139 94.05,29.82 93.9,29.67 93.9,29.25 94.33,28.82 v2(94.36,28.82) ; DM1.178 v2(105.75,24.24) ; v2(50.11,28.01) 50.08,28.01 49.6,28.49 49.6,28.91 50.84,30.14 50.85,30.14 DM1.3 ; DM1.144 95.55,24.17 v2(95.53,24.2) ; DM1.151 97.65,29.66 97.63,29.64 97.63,29.22 97.65,29.2 97.65,29.19 v2(98.09,28.74) ; v2(106.41,32.4) 106.05,32.04 DM1.179 ; v2(109.46,72.41) 109.28,72.6 109.28,72.6 CPU1.BA39 ; v2(103.26,70.35) 103.1,70.51 CPU1.AL41 ; CPU1.R3 94.1,92.45 CPU1.P2 CPU1.P1 93.87,93.62 93.87,94.37 v2(93.93,94.43) ; CPU1.BA31 108.9,77.05 109.44,77.05 v2(109.57,77.18) ; DM1.128 90.75,24.37 v2(91.34,24.96) ; v2(73.61,28.26) 71.25,30.62 DM1.71 ; v2(105.45,70.39) 105.3,70.55 CPU1.AR41 ; C1904.1 95.26,97.03 v2(95.2,96.97) ; DM1.184 v2(107.55,24.27) ; C601.1 114.75,86.75 R1917.2 113.36,86.75 R646.1 112.7,86.09 v2(112.7,85.92) ; DM1.37 61.05,29.22 60.6,28.77 v2(60.48,28.77) ; v2(98.31,70.8) 98.31,70.84 98.7,71.23 CPU1.AC41 ; DM1.32 59.55,24.36 60.02,24.83 v2(60.14,24.83) ; v2(96.86,70.86) 96.85,70.86 96.5,71.21 CPU1.W41 ; v2(91.81,29.18) 91.83,29.2 91.83,29.32 92.25,29.74 DM1.133 ; R402.2 v2(80.64,82.62) ; v2(113.21,33.11) 112.65,32.56 DM1.201 ; CPU1.AU1 v2(106.4,94.45) ; v2(94.56,70.68) 94.32,70.93 94.32,71.2 94.31,71.21 94.31,71.24 CPU1.R41 ; DM1.55 66.45,29.68 66.69,29.44 v2(66.75,29.44) ; v2(69.54,24.2) 69.75,23.99 DM1.66 ; DM1.161 100.65,28.65 101.5,27.8 101.5,26 100.5,25 v2(100.31,25) 100.95,24.36 DM1.162 ; DM1.54 66.15,23.61 66.24,23.7 66.24,24.33 66.88,24.96 v2(67.13,24.96) ; DM1.43 62.85,30.03 62.94,29.94 62.94,29.25 62.64,28.95 62.63,28.95 v2(62.46,28.77) ; DM1.189 109.05,32.11 108.71,32.45 108.04,32.45 v2(108.02,32.43) 107.85,32.26 DM1.185 ; CPU1.E4 88.45,91.75 v2(88.15,92.04) 88.15,91.8 CPU1.C5 ; v2(112.93,28.74) 112.88,28.74 111.45,30.17 DM1.197 ; CPU1.G41 89.9,70.49 89.97,70.42 v2(89.97,70.39) ; DM1.172 v2(103.95,24.31) ; DM1.190 v2(109.35,24.22) ; DM1.14 54.15,23.94 v2(53.9,24.2) ; DM1.168 v2(102.75,24.25) ; CPU1.AG41 100.9,70.43 v2(101.02,70.32) ; DM1.61 68.25,32.22 v2(68.53,32.5) 68.86,32.5 69.45,31.91 DM1.65 ; CPU1.AU2 CPU1.AU3 106.43,92.42 107.47,92.42 CPU1.AW3 ; DM1.26 57.75,24.2 v2(57.73,24.2) ; v2(56.84,28.77) 56.93,28.77 57.45,29.29 DM1.25 ; v2(90.77,27.99) 90.29,28.47 90.29,29.24 90.3,29.25 90.3,29.83 90.45,29.98 DM1.127 ; v2(104.57,32.43) 104.25,32.11 DM1.173 ; DM1.134 v2(92.55,24.25)
  BOTTOM w0.305: CPU1.AW15 CPU1.AY15 ; GPU1.AB24 159.09,112.88 v2(159.46,112.51) ; CPU1.A13 86.37,87.02 86.93,87.02 CPU1.B13 CPU1.C13 87.7,87.14 87.98,87.42 v2(87.98,87.6) ; v2(104.82,79.82) 105.2,80.2 CPU1.AR25 ; 90.48,72.98 90.48,72.89 90.23,72.65 CPU1.G39 ; 90.48,72.98 90.81,72.65 CPU1.J39 ; 90.48,72.98 v2(90.48,73.06) ; CPU1.AU27 106,79.12 v2(105.61,78.73) 105.61,78.56 CPU1.AR29 ; CPU1.AL3 103.4,92.45 v2(103.68,92.17) 103.97,92.45 CPU1.AN3 ; CPU1.AU23 105.61,81.84 v2(105.61,81.91) 105.61,82.14 CPU1.AR21 106,83.35 CPU1.AU19 ; v2(172.84,119.7) 173.03,119.7 GPU1.P6 ; v2(107.15,76.5) 107.5,76.85 CPU1.AW31 107.85,77.4 CPU1.AY30 ; CPU1.AE39 99.9,72.75 100.8,72.75 CPU1.AG39 101.16,72.65 101.4,72.89 101.4,72.97 ; CPU1.BA18 CPU1.AY18 107.32,84.2 v2(107.24,84.12) ; 88.22,84.23 CPU1.C17 ; 88.22,84.23 v2(88.8,84.23) ; 88.22,84.23 87.7,83.7 CPU1.C19 ; CPU1.AW21 107.19,82.24 v2(107.19,81.91) 107.5,81.59 CPU1.AW23 ; v2(109.49,74.79) 109.43,74.85 CPU1.BA35 ; CPU1.AW27 107.5,79.44 v2(107.14,79.79) 107.5,80.15 CPU1.AW25 ; 86.17,72.6 CPU1.A39 ; CPU1.BA25 109.24,80.35 v2(109.42,80.54) ; CPU1.AW33 107.5,75.81 v2(107.11,75.42) 107.5,75.03 CPU1.AW35 ; 35.82,55.31 EC3107.1 ; 35.82,55.31 v2(35.58,55.31) ; 35.82,55.31 EC3106.1 ; 101.4,72.97 v2(101.4,72.98) ; 101.4,72.97 101.71,72.65 CPU1.AJ39 ; CPU1.BA7 109.36,90.25 v2(109.47,90.36) ; v2(88.08,73.15) 87.7,73.52 CPU1.C37 ; v2(88.08,73.15) 87.7,72.77 CPU1.C39 CPU1.B39 ; v2(88.08,73.15) 88.57,72.65 CPU1.E39 ; CPU1.AW7 107.5,90.11 v2(107.2,89.81) ; CPU1.W39 96.82,72.97 v2(97.02,72.97) 97.28,72.97 CPU1.AA39 97.65,72.7 98.65,72.7 CPU1.AC39 ; v2(109.48,93.28) 109.45,93.25 CPU1.BA2 ; CPU1.AG3 101.28,92.07 v2(101.5,92.07) 101.45,92.11 CPU1.AH2 ; 91.58,83.2 90.57,83.2 90,82.63 CPU1.G21 90.32,82.23 90.32,81.93 CPU1.H23 90.8,81.29 90,80.49 CPU1.G25 ; CPU1.AH2 CPU1.AH1 ; CPU1.AH2 101.6,92.8 101.95,92.45 CPU1.AJ3 ; v2(94.85,72.97) 94.85,72.94 ; 94.85,72.94 94.56,72.65 CPU1.R39 ; 94.85,72.94 94.85,72.92 95.11,72.65 CPU1.U39 ; CPU1.AC15 CPU1.AA15 ; v2(107.24,84.12) 107.24,84.49 CPU1.AW17 ; v2(107.24,84.12) 107.24,83.91 CPU1.AW19 ; v2(85.86,85.55) 86.17,85.85 CPU1.A15 ; v2(103.76,72.97) 103.67,72.97 103.36,72.65 CPU1.AL39 ; v2(95.7,94.45) 95.4,94.15 CPU1.U1 95.46,93.79 95.46,93.21 CPU1.U2 CPU1.U3 95.55,92.3 95.93,92.3 ; v2(87.46,94.4) 87.65,94.21 CPU1.C1 87.7,93.8 CPU1.C2 ; CPU1.L39 92.43,72.65 92.69,72.91 v2(92.69,72.97) 93.01,72.65 CPU1.N39 ; CPU1.BA15 108.96,85.91 v2(109.43,85.91) ; CPU1.B31 CPU1.C31 87.7,77.3 87.97,77.56 v2(87.98,77.56) 87.98,77.87 CPU1.C29 ; CPU1.B23 CPU1.C23 87.7,81.13 87.88,80.95 v2(87.88,80.95) 87.88,80.94 87.88,80.53 CPU1.C25 87.7,80.23 88.03,79.9 v2(88.03,79.85) 88.03,79.58 CPU1.C27 ; CPU1.AW13 CPU1.AY13 108.26,87.01 108.84,87.01 CPU1.BA13 110.35,86.95 v2(110.56,87.16) ; CPU1.AE32 99.96,76.55 v2(100.36,76.16) ; CPU1.C33 87.7,75.76 v2(88.08,75.38) 87.7,74.99 CPU1.C35 ; CPU1.AU39 106.11,72.65 105.89,72.87 v2(105.89,72.95) 105.86,72.95 105.56,72.65 CPU1.AR39 105.25,72.7 104.25,72.7 CPU1.AN39 ; CPU1.A8 CPU1.B8 ; CPU1.BA21 109.06,82.39 110.54,82.39 v2(111.07,81.86) ; CPU1.AU3 106.18,92.45 v2(105.84,92.11) 105.5,92.45 CPU1.AR3 ; GPU1.AE27 156.67,110.44 v2(156.28,110.05) ; CPU1.Y2 CPU1.Y1 ; U3102.8 v2(32.08,55.31) ; v2(160.25,112.49) 160.6,112.84 GPU1.AB22 ; CPU1.AW37 107.5,73.46 v2(107.22,73.18) 107.5,72.91 CPU1.AW39
  BOTTOM w0.356: VRAM3.M1 176.01,148.01 v2(176.01,148.01) ; GPU1.N25 157.76,119.71 v2(157.76,119.6) 157.76,119.57 GPU1.P25 ; v2(174.04,125.59) 173.99,125.64 GPU1.F6 ; v2(153.74,122.32) 154.17,122.32 GPU1.K32 ; GPU1.AB6 173.79,112.54 v2(173.99,112.54) ; v2(156.31,118.81) 156.32,118.81 GPU1.R27 ; GPU1.AA27 156.3,113.64 v2(156.16,113.78) ; v2(169.71,108.31) 169.98,108.04 GPU1.AH10 ; VRAM4.G8 180.52,147.72 180.52,147.72 v2(180.79,147.99) ; GPU1.W27 156.29,115.64 v2(156.29,115.65) ; GPU1.F20 162.29,125.42 v2(162.56,125.15) ; VRAM2.B3 150.95,146.35 v2(150.95,146.29) ; VRAM3.B1 184.78,148.78 v2(184.78,148.8) VRAM4.A9 ; VRAM1.G1 155.39,141.55 v2(155.28,141.44) 155.14,141.44 VRAM2.F9 ; v2(176.8,122.51) 176.8,122.5 175.55,122.5 GPU1.K2 ; GPU1.H20 162.49,123.64 v2(162.53,123.64) ; v2(159.01,126.21) 159.01,125.72 GPU1.F24 ; Q601.4 125.31,90.89 v2(125.42,91) ; VRAM3.P1 174.8,148.39 v2(175.2,147.99) ; GPU1.M32 v2(153.76,120.84) ; GPU1.AG27 156.69,108.83 v2(157.08,108.44) 156.84,108.2 156.45,108.2 156.29,108.04 GPU1.AH28 ; v2(116.66,81.86) 117.29,82.49 R1916.2 ; GPU1.T6 173.54,117.64 v2(173.91,117.26) ; v2(170.15,128.78) 170.15,127.78 GPU1.B10 ; GPU1.N27 156.32,120.41 v2(156.31,120.41) ; GPU1.U25 157.82,117.11 v2(157.82,117.37) 157.82,117.37 GPU1.T25 ; GPU1.B18 163.75,127.78 163.75,128.45 v2(163.68,128.52) ; v2(159.46,112.51) 159.46,112.41 GPU1.AC24 ; v2(175.4,128.6) 175.09,128.29 GPU1.A3 ; GPU1.P9 171.45,119.4 v2(171.45,119.73) ; CPU1.AA15 97.18,85.97 v2(97.03,85.97) ; VRAM3.B9 184.78,141.6 v2(184.78,141.56) ; VRAM3.M9 176.39,141.99 v2(176.8,141.58) ; GPU1.G10 170.29,124.89 170.39,124.99 170.39,125.43 170.29,125.53 GPU1.F10 170.45,125.8 v2(170.45,126.18) ; v2(158.7,111.65) 158.29,111.24 GPU1.AD25 ; v2(153.72,107.67) 153.92,107.67 GPU1.AH32 ; v2(167.53,125.21) 167.53,125.21 167.52,125.21 GPU1.F14 ; v2(159.29,141.39) 159.38,141.48 159.38,141.98 VRAM1.M1 ; v2(172.29,111.64) GPU1.AD8 ; VRAM3.E8 181.76,142.56 181.76,142.56 v2(181.59,142.4) 181.99,142 VRAM4.E1 ; GPU1.Y25 157.81,114.72 157.81,114.96 v2(157.81,114.96) GPU1.W25 ; v2(162.19,148) 162.34,148.15 162.35,148.15 VRAM1.T9 ; v2(166.33,123.77) 166.62,123.77 GPU1.H14 ; CPU1.U15 95.28,85.87 v2(95.1,85.87) 94.92,85.87 CPU1.R15 ; v2(165.1,111.78) 164.75,111.78 GPU1.AC17 ; VRAM3.E2 182.39,147.99 v2(182.39,148) 182.73,147.66 182.73,147.65 VRAM4.D8 ; v2(156.17,111.94) 156.27,112.04 GPU1.AC27 156.81,112.16 157.37,112.16 GPU1.AC26 ; VRAM1.B1 151,141.6 v2(151,141.59) 150.99,141.59 VRAM2.A9 ; GPU1.K6 173.09,122.84 v2(173.09,122.85) 172.93,123 172.93,123 GPU1.J7 ; GPU1.U27 156.69,116.76 157.25,116.2 v2(157.25,115.92) 157.25,115.68 GPU1.W26 ; GPU1.C1 176.13,127.24 v2(176.45,127.56) ; GPU1.AC9 170.76,112.37 v2(170.76,112.52) 170.29,113 GPU1.AB10 ; v2(153.74,119.24) GPU1.P32 ; GPU1.H17 164.93,124.48 v2(165.1,124.48) ; GPU1.B24 158.98,127.75 v2(158.98,128.73) ; v2(153.64,109.44) 153.84,109.64 GPU1.AF32 ; v2(151,148.83) 151.39,148.44 VRAM1.B9 ; v2(165.56,128.58) 165.56,127.71 GPU1.B16 ; VRAM1.J8 157.14,147.44 157.15,147.44 v2(157.39,147.2) ; GPU1.AG12 v2(168.69,110.08) ; GPU1.Y20 162.62,114.84 v2(162.15,114.37) ; GPU1.K22 160.5,122.83 v2(160.3,122.83) ; VRAM1.T1 162.69,141.99 v2(163.08,142.39) ; v2(172.92,120.77) 172.99,120.84 GPU1.M6 ; GPU1.B20 162.21,127.72 v2(162.21,128.9) ; GPU1.AD6 v2(173.09,110.84) GPU1.AE7 ; GPU1.L27 156.29,122.04 v2(156.29,122.05) 156.28,122.05 GPU1.K28 ; VRAM3.J8 178.79,142.79 v2(178.39,142.39) ; v2(153.76,116.04) GPU1.V32 ; v2(171.42,117.21) 171.42,116.97 GPU1.U9 ; v2(155.79,148) 155.4,148.39 VRAM1.G9 ; VRAM4.B3 184.45,143.65 184.45,143.73 v2(184.83,144.1) ; v2(160.4,126.14) 160.4,126.09 160.69,125.8 GPU1.F22 ; VRAM3.T1 173.59,147.99 v2(173.59,147.99) ; v2(156.29,126.04) GPU1.E28 ; GPU1.F16 165.52,125.67 v2(165.52,126.2) ; CPU1.AU15 105.71,85.56 v2(105.71,85.34) 105.2,84.82 CPU1.AR17 ; VRAM4.D1 182.79,141.98 v2(183.2,141.56) ; v2(168.66,126.2) 168.66,125.67 GPU1.F12 ; v2(153.76,117.64) GPU1.T32 ; CPU1.AJ7 102.28,90.43 v2(102.59,90.43) ; VRAM3.T9 173.19,141.99 v2(173.59,142.39) ; GPU1.F18 163.89,125.1 v2(163.85,125.06) ; R645.1 v2(113.94,91.38) ; v2(167.46,110.96) 166.94,110.44 GPU1.AE14 ; VRAM3.J2 178.39,147.99 v2(178.39,147.99) ; GPU1.M12 168.07,121.06 v2(167.86,121.06) ; GPU1.F26 157.49,125.63 v2(157.11,125.25) 157.1,125.24 157.09,125.24 GPU1.G27 ; CPU1.AV9 106.8,89.3 107.2,89.7 v2(107.2,89.81) ; VRAM3.G9 180.3,142.08 180.3,142.08 v2(179.99,142.39) ; GPU1.K11 169.54,122.44 v2(169.77,122.67) ; v2(180.79,147.99) 181.1,148.3 181.1,148.3 VRAM4.F9 ; v2(180.79,147.99) 180.52,148.26 180.52,148.26 VRAM3.G1 ; GPU1.F8 172.29,125.24 v2(172.29,125.24) GPU1.G8 ; v2(157.08,123.63) GPU1.J27 ; CPU1.AR13 104.68,87.47 104.18,87.47 CPU1.AM11 103.81,88.26 v2(103.81,88.83) ; v2(155.09,128.68) GPU1.A30 ; VRAM1.E2 153.79,142.79 v2(153.39,142.39) 153.39,142.39 VRAM2.D8 ; v2(161.39,142.39) VRAM1.P1 ; GPU1.B14 167.15,127.7 167.15,128.92 v2(167.09,128.98) ; v2(157.39,143.2) 157.39,143.19 VRAM1.J2 ; v2(159.21,148.95) 159.39,148.76 VRAM1.M9 ; GPU1.H6 173.49,124.04 v2(173.08,124.44) ; VRAM1.P9 160.75,148.15 160.74,148.15 v2(160.59,148) ; v2(153.7,111.24) GPU1.AD32 ; GPU1.C32 153.63,127.24 v2(153.63,127.24) ; VRAM3.P9 174.8,141.99 v2(175.17,142.37) ; VRAM2.E1 153.8,148.39 v2(154.19,148) 153.79,147.59 VRAM1.E8 ; v2(154.01,124.85) 154.02,124.85 154.03,124.84 GPU1.G31 ; v2(153.76,114.44) GPU1.Y32 ; VRAM2.D1 v2(152.58,148.8) ; v2(153.72,112.84) GPU1.AB32 ; CPU1.L15 92.6,85.69 v2(93.06,86.15) 93.6,85.61 CPU1.N15 ; v2(154.02,123.24) 154.02,123.24 GPU1.J31
  BOTTOM w0.381: v3(16.84,25.93) 17.17,25.6 U3402.3 U3402.8 ; PQ4402.4 92.93,144.96 v2(93.42,144.47) ; 12.67,33.85 12.71,33.81 USB1.10 ; v2(121.87,138.37) 121.37,138.86 PQ4410.1 ; v2(171.14,26.61) 170.63,26.1 R2612.2 ; 14.7,32.83 14.67,32.8 USB1.10 ; v2(55.19,75.25) 55.19,77.69 SPR5.1 ; v2(103.81,88.83) 103.62,88.83 CPU1.AL8 ; PQ4402.1 91.31,146.99 v2(91.01,146.99) ; CPU1.G35 89.3,74.95 CPU1.E35 89.18,74.83 89.18,74.33 v2(89.28,74.23) 89.82,74.23 CPU1.G37 ; v2(111.2,149.04) 111,149.24 PQ4203.1 ; PQ4203.4 107.82,151.12 v2(107.77,151.07) 107.77,150.69 106.9,149.82 PQ4206.1 ; 10.84,33.04 11.08,32.8 USB1.10 ; v2(97.03,85.97) 96.95,85.89 96.94,85.89 CPU1.W15 ; PQ4410.4 119.36,141.8 v2(119.2,141.8) ; 3.68,33.09 3.97,32.8 USB1.12 ; USB1.12 6.75,32.8 6.98,33.04 ; USB1.12 5.28,33.83 5.26,33.85 ; v2(81.4,86.17) 81.53,86.05 R408.2 R406.2 ; v2(18.57,41.27) 18.9,41.08 19.1,40.87 U3401.2 ; v3(104.34,152.72) 105.6,151.47 PQ4206.4 ; v2(104.72,90.52) 104.35,90.15 CPU1.AN7
  BOTTOM w0.406: v2(186.84,31.24) 186.9,31.3 WLAN1.21 ; v2(174.57,48.85) PQ8314.4 ; Q603.4 116.58,92 116.15,91.57 v2(116.15,91.33) ; PQ8314.1 174.16,47.55 174.52,47.91 v2(174.52,48.09) ; Q603.1 119.28,93.3 v2(120.22,92.36) ; v2(72.16,83.63) 72.29,83.51 U402.2 ; R405.2 80.77,88.21 v2(80.64,88.33) ; PQ8319.4 v2(189.63,111.74) ; v2(97.99,140.99) 97.99,141.24 97.34,141.89 EC6104.2 ; PQ8319.1 v2(191.51,114.24) ; Q601.1 122.58,89.4 122.99,88.99 v2(122.99,88.98)
  BOTTOM w0.457: WLAN1.37 187.05,24.9 186.84,25.11 v2(186.84,25.65) 186.89,25.7 WLAN1.35 ; v2(178.91,32.44) 178.96,32.5 WLAN1.18 ; v2(179.15,30.03) 179.15,29.64 179.49,29.3 WLAN1.26 ; WLAN1.50 179.48,19.7 179.3,19.52 v2(179.28,19.52) ; WLAN1.43 187.82,22.5 v2(186.83,21.52) ; WLAN1.4 179.74,41.3 179.4,40.96 v2(179.4,40.2) ; WLAN1.27 187.3,28.9 v2(186.84,28.45) 187.19,28.1 WLAN1.29 ; v2(186.67,39.29) 186.68,39.3 WLAN1.9 ; v2(183.04,23.7) 183.04,23.7 WLAN1.40 ; WLAN1.15 187.09,36.9 186.84,37.15 v2(186.83,37.15) ; WLAN1.34 179.75,26.1 v2(179.42,26.42)
  BOTTOM w0.508: v2(141.42,97.48) 142.03,98.09 C8303.2 ; v2(179.15,30.03) 178.75,29.62 C2415.1 ; v2(159.97,100.91) 159.71,100.65 EC9741.2 ; v2(116.15,101.67) 115.77,101.67 115.26,101.16 R1912.2 ; R643.2 114.12,79.25 v2(114.15,79.28) R607.2 ; EC9727.2 192.79,110.56 v2(191.21,110.56) ; PC4904.2 107.41,15.33 v3(107.77,15.69) ; v2(126.69,53.98) 126.69,53.15 SPR4.1 125.45,53.99 v2(126.13,54.68) ; PR4669.2 109.04,144.71 PQ4208.S v2(107.37,145.39) ; USB1.13 6.82,17.4 7.03,17.19 ; USB1.13 5.28,16.4 5.26,16.37 ; USB1.13 3.84,17.4 3.63,17.19 ; X1902.2 v2(93.45,102.58) ; EC9748.2 v2(125.68,128.85) ; 12.72,16.27 12.71,16.29 USB1.11 ; C7730.2 v2(157.11,102.44) ; v2(181.94,117.92) 181.94,118.5 R7418.2 ; v2(145.36,85.03) 144.54,85.86 PC8214.2 PR8228.2 ; v2(86.43,124.58) 86.73,124.88 EC9717.2 ; R5412.2 49.64,54.55 50.06,54.13 v2(50.06,53.69) ; EC9731.2 v2(175.59,69.54) ; PC8323.2 164.11,56.41 164.47,56.05 v3(164.47,55.09) ; v3(147.65,65.35) 147.65,64.74 PC5012.2 ; v2(31.13,87.2) 30.94,87.01 EC5205.2 ; R5209.2 37.28,85.92 38.45,84.75 v2(38.78,84.75) ; v2(132.66,34.1) 131.77,34.99 PR4516.2 ; PC4834.2 138.19,76.33 v2(138.12,76.27) ; v2(119.2,141.8) 119.2,142.12 PR4470.1 ; v2(21.61,87.34) 21.21,86.94 R5207.2 ; C1046.2 v2(131.8,76.4) ; v2(54.28,13.07) 55.1,12.25 C2503.1 ; v2(135.88,142.01) PD4302.A ; v2(131.26,40.58) 131.58,40.9 PR4515.2 ; v2(148.72,39.19) 148.72,39.18 148.78,39.12 EC2502.2 ; 11.4,50.92 11.42,50.9 USB2.6 13.44,49.5 v2(13.55,49.61) ; R1919.2 112.66,95.25 111.2,93.79 v2(111.2,93.36) ; v2(127.18,98.38) 127.23,98.38 127.3,98.3 EC6206.2 ; C5802.2 178.95,15.3 v2(177.8,16.45) ; DM1.205 49.1,35.94 v2(48.64,35.48) ; v2(72.16,83.63) 72.16,84.48 C401.2 ; v2(154.72,16.08) 154.72,16.07 DB1.10 ; v2(171.18,38.95) 171.35,38.78 171.35,38.28 171.39,38.24 C2409.2 ; v2(75.89,85.54) C402.2 ; v2(160.74,30.64) 161.24,31.14 C2406.2 C2407.2 ; C3001.2 30.97,43.95 v2(30.78,43.76) ; C8302.2 145.11,102.56 v2(145.49,102.94) 144.98,103.45 C8301.2 ; v2(158.54,136.78) R7801.1 C7810.2 C7818.2 v2(162.25,136.09) ; R641.1 114.31,80.97 C1024.2 115.07,81.35 115.14,81.41 v2(115.14,81.86) 114.56,81.86 R640.1 ; U2901.1 32.75,18.12 33.17,18.53 33.17,21.45 v2(32.59,22.04) ; EC3108.1 v2(35.57,52.2) ; v2(116.28,121.73) 116.28,122.34 PC4623.2 ; C2604.2 v2(38.2,90.85) ; PR4213.2 v2(104.09,146.69) ; v2(111.45,139.41) 111.53,139.34 PC4604.2 ; C3618.2 C3619.2 127.32,64.66 v2(126.67,64.66) ; C3005.2 40.69,46.45 v2(40.99,46.75) ; PC4620.2 PC4621.2 v2(100.15,139.51) ; USB2.7 2.64,35.25 3.38,34.51 ; v2(43.51,11.24) 42.87,10.61 EC2708.2 ; C1204.2 42.39,29.35 v2(41.86,29.89) 42.21,30.24 C1203.2 ; X601.2 109.76,103.37 110.18,102.94 R1914.2 109.92,102.17 v2(109.17,101.41) 108.61,101.97 X601.3 ; C3607.2 42.47,13.12 v2(43,13.66) ; R7323.2 v2(183.16,121.35) ; C3613.2 136.92,65.38 136.62,65.09 v2(136.34,65.09) ; EC9733.2 104.62,9.34 105.18,9.34 v2(105.23,9.29) ; R644.2 114.82,93.92 114.88,93.92 v2(114.88,93.29) 114.88,93.08 114.44,92.63 R620.2 ; C1047.2 127.73,67.58 v2(126.7,67.58) ; v2(118.11,115.51) 119.73,117.14 PC4625.2 ; C8309.1 145.12,98.81 v2(145.08,98.85) ; v2(34.49,85.41) 34.49,85.11 33.98,84.6 C5208.2 ; C5803.2 183.7,13.28 v2(183.71,13.28) ; EC9705.2 v2(122.63,149.36) ; C8320.2 139.96,104.02 v2(140.15,103.83) U8302.15 140.15,100.4 v2(140.28,100.27) 140.35,100.21 C8316.2 ; C605.2 120.16,80.74 120.67,80.23 120.67,80.01 v2(120.68,80) ; PC8321.2 168.12,57.88 v2(167.33,57.09) ; v2(51.53,8.35) 51.32,8.56 R2504.2 50.02,11.53 Q2505.S ; C8314.1 135.65,100.72 v2(135.37,100.44) ; SPI25.4 144.45,46.68 144.45,46.68 v2(144.4,46.68) ; PR4218.2 111.71,147.77 v2(111.96,148.02) ; PQ8317.S 174.57,49.69 v2(174.57,48.85) ; v2(52.25,73.52) 52.25,73.26 EC9736.2 ; v2(30.78,46.68) 30.85,46.61 C3011.2 ; EC9745.2 29.09,7.24 v2(29.16,7.18) ; EC5206.2 30.69,84.43 v2(30.87,84.61) 31.77,84.61 C5214.2 ; v2(117.74,141.8) PR4405.2 117.8,140.97 PR4467.2 ; v2(139.65,11.24) 139.71,11.18 PC4525.2 ; C3002.2 v2(33.35,40.63) ; HDMI1.23 5.85,95.35 6.17,95.67 ; v2(80.08,81.09) R412.1 R419.2 ; FAN1.5 v3(49.27,90.13) ; C8914.2 174.89,136.34 v2(175.08,136.34) ; v2(168.03,49.79) PC8322.2 PR8347.1 ; v3(97.86,147.13) 97.99,147.26 PC4202.2 ; USB1.11 14.75,17.4 14.76,17.39 ; USB1.11 11.06,17.4 10.84,17.19 ; C3003.2 v2(30.93,36.71) ; R7425.1 v2(178.36,116.59) ; EC3105.1 v2(35.61,58.42) ; EC9713.2 v2(117.8,131.77) ; R415.2 R416.2 79.58,75.7 v2(79.13,75.25) ; v2(42.82,92.27) 42.98,92.43 FAN1.2 ; R5410.2 48.28,56.58 v2(48.28,57.09) ; PD4203.1 v2(118.18,146.75) ; PR4208.2 94.82,145.2 v2(94.82,144.47) ; EC2501.2 158.21,38.21 v2(158.21,37.76) ; R633.2 103.58,100.66 C604.2 103.95,101.41 v2(104.44,101.41) ; v2(176.35,136.21) 176.41,136.21 R8904.1 ; C8308.1 142.82,106.49 v2(143.33,107) 143.56,106.77 C8304.2 ; v2(159.97,101.67) 159.87,101.77 C7679.1 ; D2601.A v2(38.2,89.6) ; v2(35.13,37.15) 35.11,37.17 C3009.2 34.37,37.97 C3010.2 ; v3(119.3,12.74) 119.64,12.4 PC4510.2 ; C1002.2 117.74,98.61 v2(117.83,98.52) ; C2603.2 v2(40.33,90.54) ; X1902.4 v2(89.99,100.15) ; C2502.2 154.44,39.04 154.42,39.06 v2(154.42,39.08) 154.96,39.08 155.33,38.71 EC2503.2 ; v2(141.93,91.89) 142.76,91.06 PR8256.2 ; R407.2 78.56,85.29 v2(78.31,85.03) 78.05,85.29 77.73,85.29 C443.1 ; C3620.1 127.23,66.31 v2(126.69,66.31) ; PC5010.2 v3(148.66,65.35) ; PC5013.2 v2(165.94,62.36) ; v2(136.22,124.53) 136.22,124.17 PC4407.2 ; PC4209.2 111.71,144.34 v2(112.09,144.72) 111.64,145.17 PR4216.2 ; PR4464.2 119.96,135.7 v2(119.83,135.83) ; R3032.1 v2(29.18,48.31) ; v2(195.78,84.4) 195.72,84.33 EC9725.2 ; EC9730.2 v3(190.26,131.26) ; C8313.1 v2(135.96,103.38) ; R411.2 R413.2 R410.2 77.86,75.57 v2(78.05,75.38) ; PC5005.2 v2(160.86,65.73) ; v2(31.63,48.65) 32.4,47.88 C3008.2 ; v2(139.88,87.29) 140.18,87.29 140.59,87.7 PR8257.2 ; PC5011.2 v2(165.17,57.09) ; C7729.2 v2(152.66,103.9) ; DB1.8 v2(157.22,15.69) ; C3402.2 v2(23.38,26.73) ; EC2601.2 v2(41.22,90.54) ; PQ4202.E v2(114.96,144.09) ; PC5015.2 v2(166.57,57.09) ; PR4675.2 v2(115.26,142.18) ; PR5013.2 v2(164.28,64.84) ; v2(183.16,120.08) R7501.1 ; EC6207.2 v2(127.84,94.99)
  BOTTOM w0.635: 201.55,91.41 ODD1.14 199.77,90.33 ; RJ45.9 9.62,53.18 ; RJ45.9 7.88,52.29 ; RJ45.9 6.14,53.18 ; 6.14,72.23 RJ45.10 ; RJ45.10 9.62,72.23 ; RJ45.10 7.88,73.11 ; 130.52,156.08 BAT1.6 ; BAT1.6 130.52,154.72 ; BAT1.6 131.88,156.08 ; BAT1.6 131.88,154.72 ; 196.14,35.1 HDD1.P12 197.66,35.1 ; 196.14,26.21 HDD1.P5 197.66,26.21 ; 124.52,156.08 BAT1.9 ; BAT1.9 125.88,154.72 ; BAT1.9 125.88,156.08 ; BAT1.9 124.52,154.72 ; BAT1.11 122.96,155.4 ; BAT1.11 122.07,153.48 ; BAT1.11 121.19,155.4 ; HDD1.S7 197.66,14.78 ; HDD1.S7 196.14,14.78 ; HDD1.S7 196.9,15.47 ; 202.25,86.09 ODD1.5 201.51,85.35 ; BAT1.8 127.88,156.08 ; BAT1.8 126.52,154.72 ; BAT1.8 126.52,156.08 ; BAT1.8 127.88,154.72 ; 200.75,85.61 ODD1.6 ; ODD1.6 200.01,86.35 ; ODD1.6 200.75,87.09 ; ODD1.6 201.49,86.35 ; 10.55,77.96 HDMI1.20 ; HDMI1.20 11.99,78.95 ; HDMI1.20 10.55,79.94 ; 143.44,155.4 BAT1.10 ; BAT1.10 144.32,153.48 ; BAT1.10 145.21,155.4 ; 202.25,75.85 ODD1.S7 201.46,75.14 ; 15.24,21.05 USB1.4 15.4,21.6 ; 11.95,82.2 HDMI1.2 11.3,81.63 ; HDD1.S4 198.42,10.97 198.42,10.96 ; 195.85,4.96 HDD1.23 ; HDD1.23 197.63,3.88 ; HDD1.23 197.63,6.04 ; 196.14,7.16 HDD1.S1 196.9,6.46 ; 4.05,76.06 HDMI1.22 5.49,77.05 ; 200.02,92.84 S1.1 197.71,93.72 ; 199.77,63.47 ODD1.15 201.55,62.39 ; 197.66,27.48 HDD1.P6 196.14,27.48 ; 197.66,32.56 HDD1.P10 196.14,32.56 ; 196.14,24.94 HDD1.P4 197.66,24.94 ; 197.63,40.03 HDD1.24 ; HDD1.24 195.85,41.11 ; HDD1.24 197.63,42.19 ; 201.46,67.52 ODD1.S1 202.25,66.81 ; 11.27,94.44 HDMI1.21 11.99,94.44
  BOTTOM w0.762: USB2.8 2.14,50.95 3.02,51.83 ; 201.42,99.94 201.42,97.43 S1.1 ; v3(192.72,10.59) 193.08,10.95 196.88,10.95 HDD1.S4
  vias: v1(45.97,72.89) v1(51.76,87.42) v1(80.72,11.83) v1(96.59,128.34) v1(99.01,128.62) v1(100.3,18.08) v1(104.77,136.49) v1(105,126.46) v1(107.77,126.41) v1(112.01,15.31) v1(126.08,32.35) v1(126.16,32.88) v1(132.05,31.61) v1(132.51,124.48) v1(133.37,123.54) v1(135.53,31.08) v1(143.58,16.73) v1(143.81,144.77) v1(157.43,88.31) v1(171.45,108.88) v1(172.49,114.06) v1(173.4,100.68) v1(186.36,100.73) v1(187.86,60.67) v2(2.99,72.18) v2(3.58,16.27) v2(3.83,53.22) v2(3.76,52.14) v2(4.7,34.54) v2(4.85,53.28) v2(5.24,72.13) v2(5.2,51.69) v2(6.34,77.32) v2(6.96,95.11) v2(7.55,51.62) v2(8.08,34.56) v2(8.66,97.36) v2(8.76,95.6) v2(9.08,33.02) v2(9.14,17.14) v2(9.99,72.14) v2(10.21,94.81) v2(10.22,77.6) v2(10.38,91.89) v2(10.41,80.62) v2(10.51,53.28) v2(10.58,52.03) v2(10.84,34.89) v2(11.01,46.46) v2(10.99,42.35) v2(11.28,97.35) v2(13.07,71.88) v2(13.59,69.91) v2(13.79,79.19) v2(13.79,39.69) v2(13.89,36.61) v2(14.04,81.35) v2(13.99,19.31) v2(14.05,31.07) v2(14.27,92.85) v2(14.3,85.43) v2(14.61,83.34) v2(14.65,73.12) v2(15.14,97.32) v2(15.06,18.36) v2(15.45,19.91) v2(15.57,39.95) v2(15.69,48.46) v2(15.69,34.21) v2(16.79,28.42) v2(16.97,22.16) v2(16.97,20.89) v2(18.18,81.4) v2(18.16,79.19) v2(18.16,77) v2(18.26,83.52) v2(18.87,22.16) v2(18.87,20.89) v2(19.38,97.32) v2(19.65,1.72) v2(20.73,21.08) v2(21.59,1.02) v2(22,21.08) v2(22.58,72.51) v2(23.44,1.72) v2(23.69,97.37) v2(24.14,21.76) v2(24.58,95.06) v2(25.09,1.06) v2(28.12,95.62) v2(28.14,92.78) v2(28.14,91.51) v2(28.2,94.05) v2(28.27,1.06) v2(28.77,97.37) v2(31.07,25.99) v2(31.19,27.28) v2(31.21,1.06) v2(32.97,87.44) v2(33.85,97.37) v2(33.83,88.77) v2(33.86,10.74) v2(34.14,26.04) v2(34.74,10.74) v2(35,1.14) v2(35.2,44.35) v2(35.63,12.51) v2(35.63,11.63) v2(35.63,10.74) v2(35.63,9.97) v2(35.63,9.09) v2(36.04,26.03) v2(36.08,45.23) v2(36.08,44.35) v2(36.08,43.46) v2(36.27,88.08) v2(36.52,10.74) v2(36.97,44.35) v2(37.03,1.03) v2(37.43,76.73) v2(37.41,10.74) v2(38.17,88.21) v2(38.35,1.08) v2(38.58,95.83) v2(38.71,94.94) v2(38.93,97.37) v2(39.43,76.67) v2(39.46,93.48) v2(39.57,43.25) v2(39.86,56.61) v2(40.13,1.06) v2(40.59,67.76) v2(41.35,76.78) v2(41.43,43.25) v2(42.62,67.12) v2(42.57,58.59) v2(42.87,1.47) v2(44.01,97.37) v2(44.71,1.03) v2(44.85,72.84) v2(45.03,65.6) v2(45.27,73.33) v2(45.54,54.98) v2(46.63,15.11) v2(46.61,1.03) v2(46.68,64.08) v2(47.11,97.32) v2(48.54,1.03) v2(49.96,97.4) v2(50.11,26.48) v2(50.11,1.03) v2(50.65,19.96) v2(51.44,50.23) v2(51.59,56.47) v2(51.89,96.52) v2(52.14,26.61) v2(52.07,1.02) v2(52.65,70.96) v2(52.91,66.49) v2(53,88.46) v2(52.96,51.66) v2(53.75,70.96) v2(53.92,26.61) v2(54.05,92.52) v2(54.61,1.03) v2(55.09,96.79) v2(55.19,74.62) v2(55.19,73.35) v2(56.79,26.23) v2(57.15,1.02) v2(57.38,97.43) v2(57.4,27.58) v2(58.24,1.08) v2(59.41,25.57) v2(60.04,98.11) v2(60.45,27.37) v2(60.81,25.85) v2(60.96,63.01) v2(61.92,26.31) v2(62.08,80) v2(62.25,64.23) v2(62.43,27.37) v2(62.61,98.95) v2(63.98,101.16) v2(64.79,1.08) v2(65.61,26.72) v2(66.32,102.4) v2(66.71,27.16) v2(67.31,1.02) v2(68.37,103.7) v2(70.28,105.07) v2(71.83,76.53) v2(72.01,106.52) v2(72.39,1.02) v2(75,109.42) v2(75.97,110.53) v2(77.47,1.02) v2(77.98,113.23) v2(79.42,115.41) v2(80.69,117.72) v2(82.65,122.37) v2(82.55,1.02) v2(83.44,124.96) v2(84.68,156.81) v2(84.66,154.3) v2(84.68,149.52) v2(84.66,147.11) v2(84.66,144.31) v2(84.68,141.37) v2(84.66,138.37) v2(87.63,1.02) v2(87.88,156.88) v2(87.98,89.63) v2(88.77,89.63) v2(88.8,87.62) v2(89.53,89.63) v2(89.61,87.6) v2(89.56,78.68) v2(89.62,76.44) v2(90.29,89.63) v2(90.27,76.42) v2(90.4,86.52) v2(91.54,89.63) v2(92.28,84.07) v2(92.66,90.62) v2(92.71,1.02) v2(92.96,156.88) v2(92.99,84.12) v2(93.12,77.99) v2(94.08,82.9) v2(94.11,80.87) v2(94.11,77.91) v2(94.84,90.7) v2(95.11,77.91) v2(96.09,87.9) v2(96.09,82.87) v2(96.11,80.87) v2(96.09,77.9) v2(96.24,26.69) v2(97.08,77.89) v2(97.08,25.65) v2(97.36,94.43) v2(97.79,1.02) v2(98.09,80.97) v2(98.17,90.49) v2(98.63,99.64) v2(98.61,26.28) v2(99.08,80.97) v2(99.18,83.13) v2(99.29,92.14) v2(100.02,80.97) v2(100.33,90.53) v2(101.1,83.86) v2(101.11,77.86) v2(101.52,24.94) v2(101.62,156.86) v2(102.11,85.23) v2(102.08,84.09) v2(102.11,77.87) v2(102.09,77.12) v2(102.77,25.56) v2(102.87,1.02) v2(103.07,77.89) v2(103.99,77.69) v2(104.09,78.68) v2(104.31,156.13) v2(104.59,14.55) v2(105.23,135.58) v2(105.23,15.18) v2(105.23,14.55) v2(105.23,13.91) v2(105.76,26.36) v2(105.86,135.58) v2(105.86,14.55) v2(106.5,136.85) v2(106.5,136.21) v2(106.5,135.58) v2(106.5,134.94) v2(106.5,134.31) v2(107.13,135.58) v2(107.57,27.6) v2(107.77,135.58) v2(107.95,1.02) v2(108.25,25.98) v2(108.79,1.08) v2(109.24,26.84) v2(109.39,156.13) v2(109.93,25.9) v2(110.94,83.99) v2(112.98,84.08) v2(112.95,27.37) v2(113.03,1.02) v2(118.11,1.02) v2(120.27,156.81) v2(121.87,39.95) v2(123.19,1.02) v2(123.26,41.72) v2(123.59,154.3) v2(123.77,156.28) v2(126.18,154.32) v2(126.31,79.57) v2(128.27,1.02) v2(128.6,48.2) v2(129.41,77) v2(130.5,1.03) v2(130.7,6.8) v2(130.76,40.07) v2(131.26,39.57) v2(131.33,6.8) v2(131.77,40.07) v2(131.97,6.8) v2(132.6,6.8) v2(132.64,1.03) v2(134.31,117.34) v2(135.05,1.03) v2(137.36,36.01) v2(138.05,1.03) v2(140.73,141.17) v2(141.27,1.03) v2(144.42,1.06) v2(144.85,113.25) v2(145.13,108.5) v2(146.94,1.06) v2(147.39,87.95) v2(147.81,156.88) v2(148.03,87.95) v2(148.44,115.03) v2(148.41,111.45) v2(148.58,18.07) v2(148.59,16.44) v2(148.66,89.22) v2(148.66,88.59) v2(148.66,87.95) v2(148.66,87.32) v2(148.66,86.68) v2(148.79,154.5) v2(148.79,100.8) v2(148.93,49.22) v2(148.91,20.84) v2(149.15,1.06) v2(149.25,15.28) v2(149.3,87.95) v2(149.68,154.5) v2(149.76,16.76) v2(149.93,87.95) v2(149.86,18.97) v2(150.29,100.37) v2(150.57,154.5) v2(150.84,49.22) v2(151.46,154.5) v2(152.02,1.06) v2(152.35,154.5) v2(152.74,49.22) v2(152.89,156.88) v2(153.24,5.53) v2(154.73,1.06) v2(155.01,154.5) v2(155.9,154.5) v2(156.64,151.05) v2(157.6,1.03) v2(157.81,151.07) v2(157.88,109.24) v2(158.57,154.5) v2(159.46,154.5) v2(159.59,48.43) v2(160.35,154.5) v2(160.45,1.06) v2(161.24,154.5) v2(161.53,106.23) v2(161.87,61.54) v2(161.87,60.77) v2(161.87,60.01) v2(162.24,119.22) v2(162.22,118.17) v2(162.22,117.31) v2(162.56,1.06) v2(164.13,115.41) v2(164.77,156.84) v2(165.11,118.23) v2(165.05,116.45) v2(165.15,1.02) v2(165.3,105.73) v2(165.61,15.77) v2(165.91,119.22) v2(166.01,117.1) v2(166.01,115.55) v2(166.02,113.32) v2(166.47,103.95) v2(166.95,14.24) v2(167.11,113.3) v2(167.41,1.03) v2(167.59,101.72) v2(167.64,15.77) v2(167.93,119.2) v2(167.87,117.26) v2(167.92,115.43) v2(168.35,101.72) v2(168.65,110.84) v2(168.91,14.34) v2(169.75,110.1) v2(170.14,118.49) v2(170.13,117.29) v2(170.13,116.05) v2(170.14,114.9) v2(170.13,113.71) v2(170.15,119.68) v2(170.23,1.02) v2(171.37,156.25) v2(171.78,75.25) v2(171.78,74.49) v2(171.78,73.73) v2(172.34,13.25) v2(174.19,154.63) v2(174.83,154.63) v2(175.97,154.63) v2(176.6,120.22) v2(176.86,154.63) v2(178.13,154.63) v2(179.14,150.56) v2(180.14,52.65) v2(180.14,50.74) v2(180.41,150.56) v2(180.56,3.23) v2(181.59,1.05) v2(181.94,128.59) v2(181.89,124.32) v2(182.32,123.84) v2(183.08,154.63) v2(183.72,3.24) v2(184.1,154.63) v2(184.1,9.72) v2(184.12,1.04) v2(185.11,154.63) v2(185.49,8.58) v2(185.7,11.17) v2(186.13,3.24) v2(186.76,70.76) v2(186.84,29.97) v2(186.89,154.63) v2(186.86,1.04) v2(187.03,73.2) v2(187.98,6.29) v2(189,43.13) v2(189.2,1.04) v2(189.27,34.36) v2(189.94,34.36) v2(190.45,27.93) v2(190.45,25.85) v2(191.08,156.79) v2(191.13,154.02) v2(191.16,150.18) v2(191.79,58.89) v2(191.84,47.34) v2(192.35,74.65) v2(192.35,73.35) v2(192.45,1.07) v2(194.31,1.02) v2(194.41,134.26) v2(194.69,46.19) v2(196.03,75.13) v2(196.37,44.29) v2(197.53,1.07) v2(198.52,46.07) v2(198.96,133.8) v2(198.96,43.25) v2(198.98,37.15) v2(199.01,33.5) v2(199.01,28.42) v2(199.01,23.34) v2(199.01,18.26) v2(199.01,13.18) v2(198.98,8.98) v2(198.98,3.09) v2(199.08,61.84) v2(200.66,66.34) v2(200.88,60.6) v2(201.93,100.53) v2(201.98,132.74) v2(201.98,127.66) v2(201.95,125.57) v2(201.95,113.2) v2(202.64,135.86) v2(202.59,103.75) v2(202.68,108.32) v2(202.79,92.52) v2(202.79,77.67) v3(5.03,73.6) v3(7.74,16.43) v3(10.08,16.43) v3(11.86,51.88) v3(14.15,34.92) v3(15.47,31.46) v3(16.03,47.52) v3(16.13,73.37) v3(16.28,70.22) v3(16.33,37.96) v3(16.79,32.78) v3(16.94,35.58) v3(18.21,37.96) v3(18.82,68.24) v3(19.02,32.96) v3(20.9,70.83) v3(20.9,42.99) v3(21.46,73.32) v3(21.87,32.73) v3(22.88,42.99) v3(23.24,21.4) v3(26.34,39.69) v3(28.88,63.36) v3(34.21,35.58) v3(35.76,21.53) v3(36.7,28.87) v3(36.65,21.53) v3(46.11,94.73) v3(73.33,18.84) v3(74.04,18.13) v3(74.85,17.31) v3(75.03,102.91) v3(75.03,102.02) v3(75.03,101.13) v3(75.92,102.91) v3(75.92,102.02) v3(75.92,101.13) v3(76.81,102.91) v3(76.81,102.02) v3(76.81,101.13) v3(77.7,102.91) v3(79.56,10.89) v3(79.56,10) v3(80.47,10.9) v3(80.47,10.01) v3(80.59,100.91) v3(80.59,96.97) v3(81.36,10.9) v3(81.36,10.01) v3(81.73,96.97) v3(82.25,10.9) v3(82.25,10.01) v3(82.5,100.91) v3(83.12,10.91) v3(83.12,10.02) v3(83.99,10.94) v3(83.99,10.05) v3(85.04,152.47) v3(85.04,151.58) v3(85.04,150.69) v3(85.93,152.47) v3(85.93,151.58) v3(85.93,150.69) v3(86.18,119.83) v3(86.18,118.81) v3(87.07,119.83) v3(87.07,118.81) v3(87.96,119.83) v3(87.96,118.81) v3(87.96,117.92) v3(87.96,117.04) v3(87.96,116.15) v3(88.72,116.53) v3(94.56,137.84) v3(94.56,136.95) v3(95.43,137.81) v3(95.4,136.92) v3(95.96,17.34) v3(96.24,131.89) v3(96.47,130.5) v3(96.47,129.61) v3(96.47,18.1) v3(96.97,17.34) v3(97.08,131.87) v3(97.36,130.5) v3(97.36,129.61) v3(97.39,18.13) v3(97.86,17.34) v3(98.19,130.47) v3(98.24,18.11) v3(98.27,129.61) v3(98.75,17.34) v3(99.26,18.11) v3(99.64,17.34) v3(99.77,124.53) v3(99.77,123.64) v3(99.77,122.75) v3(99.77,121.86) v3(100.23,126.71) v3(100.66,124.53) v3(100.66,123.64) v3(100.66,122.75) v3(100.66,121.86) v3(100.86,127.37) v3(101.55,124.53) v3(101.55,123.64) v3(101.55,122.75) v3(101.55,121.86) v3(104.34,153.61) v3(104.34,123.64) v3(104.34,122.75) v3(104.34,121.73) v3(104.34,120.85) v3(104.34,119.96) v3(104.34,118.94) v3(105.23,153.23) v3(105.23,123.64) v3(105.23,122.75) v3(105.23,121.73) v3(105.23,120.85) v3(105.23,119.96) v3(105.23,118.94) v3(105.74,153.99) v3(106.12,153.23) v3(106.63,153.99) v3(107.01,127.58) v3(107.01,126.69) v3(107.01,124.91) v3(107.52,124.15) v3(107.9,124.91) v3(108.66,124.15) v3(111.83,13.66) v3(111.83,12.77) v3(118.41,13.63) v3(118.41,12.74) v3(118.59,114.11) v3(118.59,113.2) v3(119.3,13.63) v3(119.4,111.32) v3(119.45,113.99) v3(119.45,113.1) v3(119.45,112.21) v3(120.09,13.15) v3(120.22,114.37) v3(120.22,113.48) v3(120.22,112.59) v3(120.22,111.7) v3(121.1,113.48) v3(121.1,112.59) v3(121.1,111.7) v3(121.99,112.59) v3(121.99,111.7) v3(125.8,30.04) v3(126.57,31.06) v3(126.69,30.04) v3(127.3,31.97) v3(127.58,31.06) v3(127.58,30.04) v3(127.58,29.02) v3(128.17,32.45) v3(128.5,31.39) v3(129.96,2.44) v3(130.81,2.43) v3(132.15,126.69) v3(132.15,125.8) v3(132.38,61.41) v3(132.38,60.39) v3(133.04,126.69) v3(133.04,125.8) v3(133.3,32.96) v3(133.3,32.07) v3(133.3,31.06) v3(133.3,30.04) v3(133.93,126.69) v3(133.93,125.8) v3(134.19,32.96) v3(134.19,32.07) v3(134.19,31.06) v3(134.19,30.04) v3(138.86,13.5) v3(139.04,6.75) v3(139.5,16.76) v3(139.48,15.91) v3(139.7,13.5) v3(139.88,6.75) v3(140.39,16.76) v3(140.36,15.91) v3(140.57,13.5) v3(141.28,16.76) v3(141.25,15.91) v3(143.08,149.55) v3(143.08,148.66) v3(143.08,147.77) v3(143.08,146.88) v3(143.08,146.04) v3(143.08,145.15) v3(143.96,149.55) v3(143.96,148.66) v3(144.3,68.88) v3(144.32,68.04) v3(144.32,67.2) v3(144.3,66.31) v3(145.13,66.29) v3(145.18,67.96) v3(145.16,67.12) v3(146.5,131.01) v3(151.57,13.35) v3(152.22,13.91) v3(156.03,85.54) v3(156.03,84.65) v3(156.33,9.06) v3(156.46,86.5) v3(157.17,85.03) v3(157.17,84.14) v3(157.17,83.25) v3(157.5,86.2) v3(158.7,86.17) v3(158.7,85.03) v3(158.7,84.14) v3(158.7,83.25) v3(159.37,3.43) v3(159.46,77.03) v3(159.84,86.68) v3(159.84,85.54) v3(159.84,84.65) v3(159.84,83.76) v3(160.35,77.03) v3(160.45,3.42) v3(160.98,76.4) v3(160.98,75.51) v3(161.44,3.43) v3(161.87,76.4) v3(161.87,75.51) v3(161.87,74.62) v3(165.77,11.37) v3(166.65,11.37) v3(172.67,98.75) v3(178.38,100.53) v3(178.38,99.64) v3(179.65,101.16) v3(179.65,100.27) v3(182.45,101.16) v3(182.45,100.27) v3(183.07,25.62) v3(184.4,41.27) v3(187.1,17.91) v3(187.25,95.52) v3(187.25,94.63) v3(187.25,93.79) v3(187.22,87.75) v3(187.22,86.89) v3(187.22,86.02) v3(187.27,92.93) v3(187.27,91) v3(187.27,90.14) v3(187.27,89.27) v3(187.27,85.16) v3(187.4,100.02) v3(187.4,99.18) v3(188.4,17.7) v3(192.61,78.5) v3(193.14,24.93) v3(194.51,106.49) v3(194.51,105.48) v3(196.03,76.27) v3(197.18,68.14) v3(197.18,67.25)
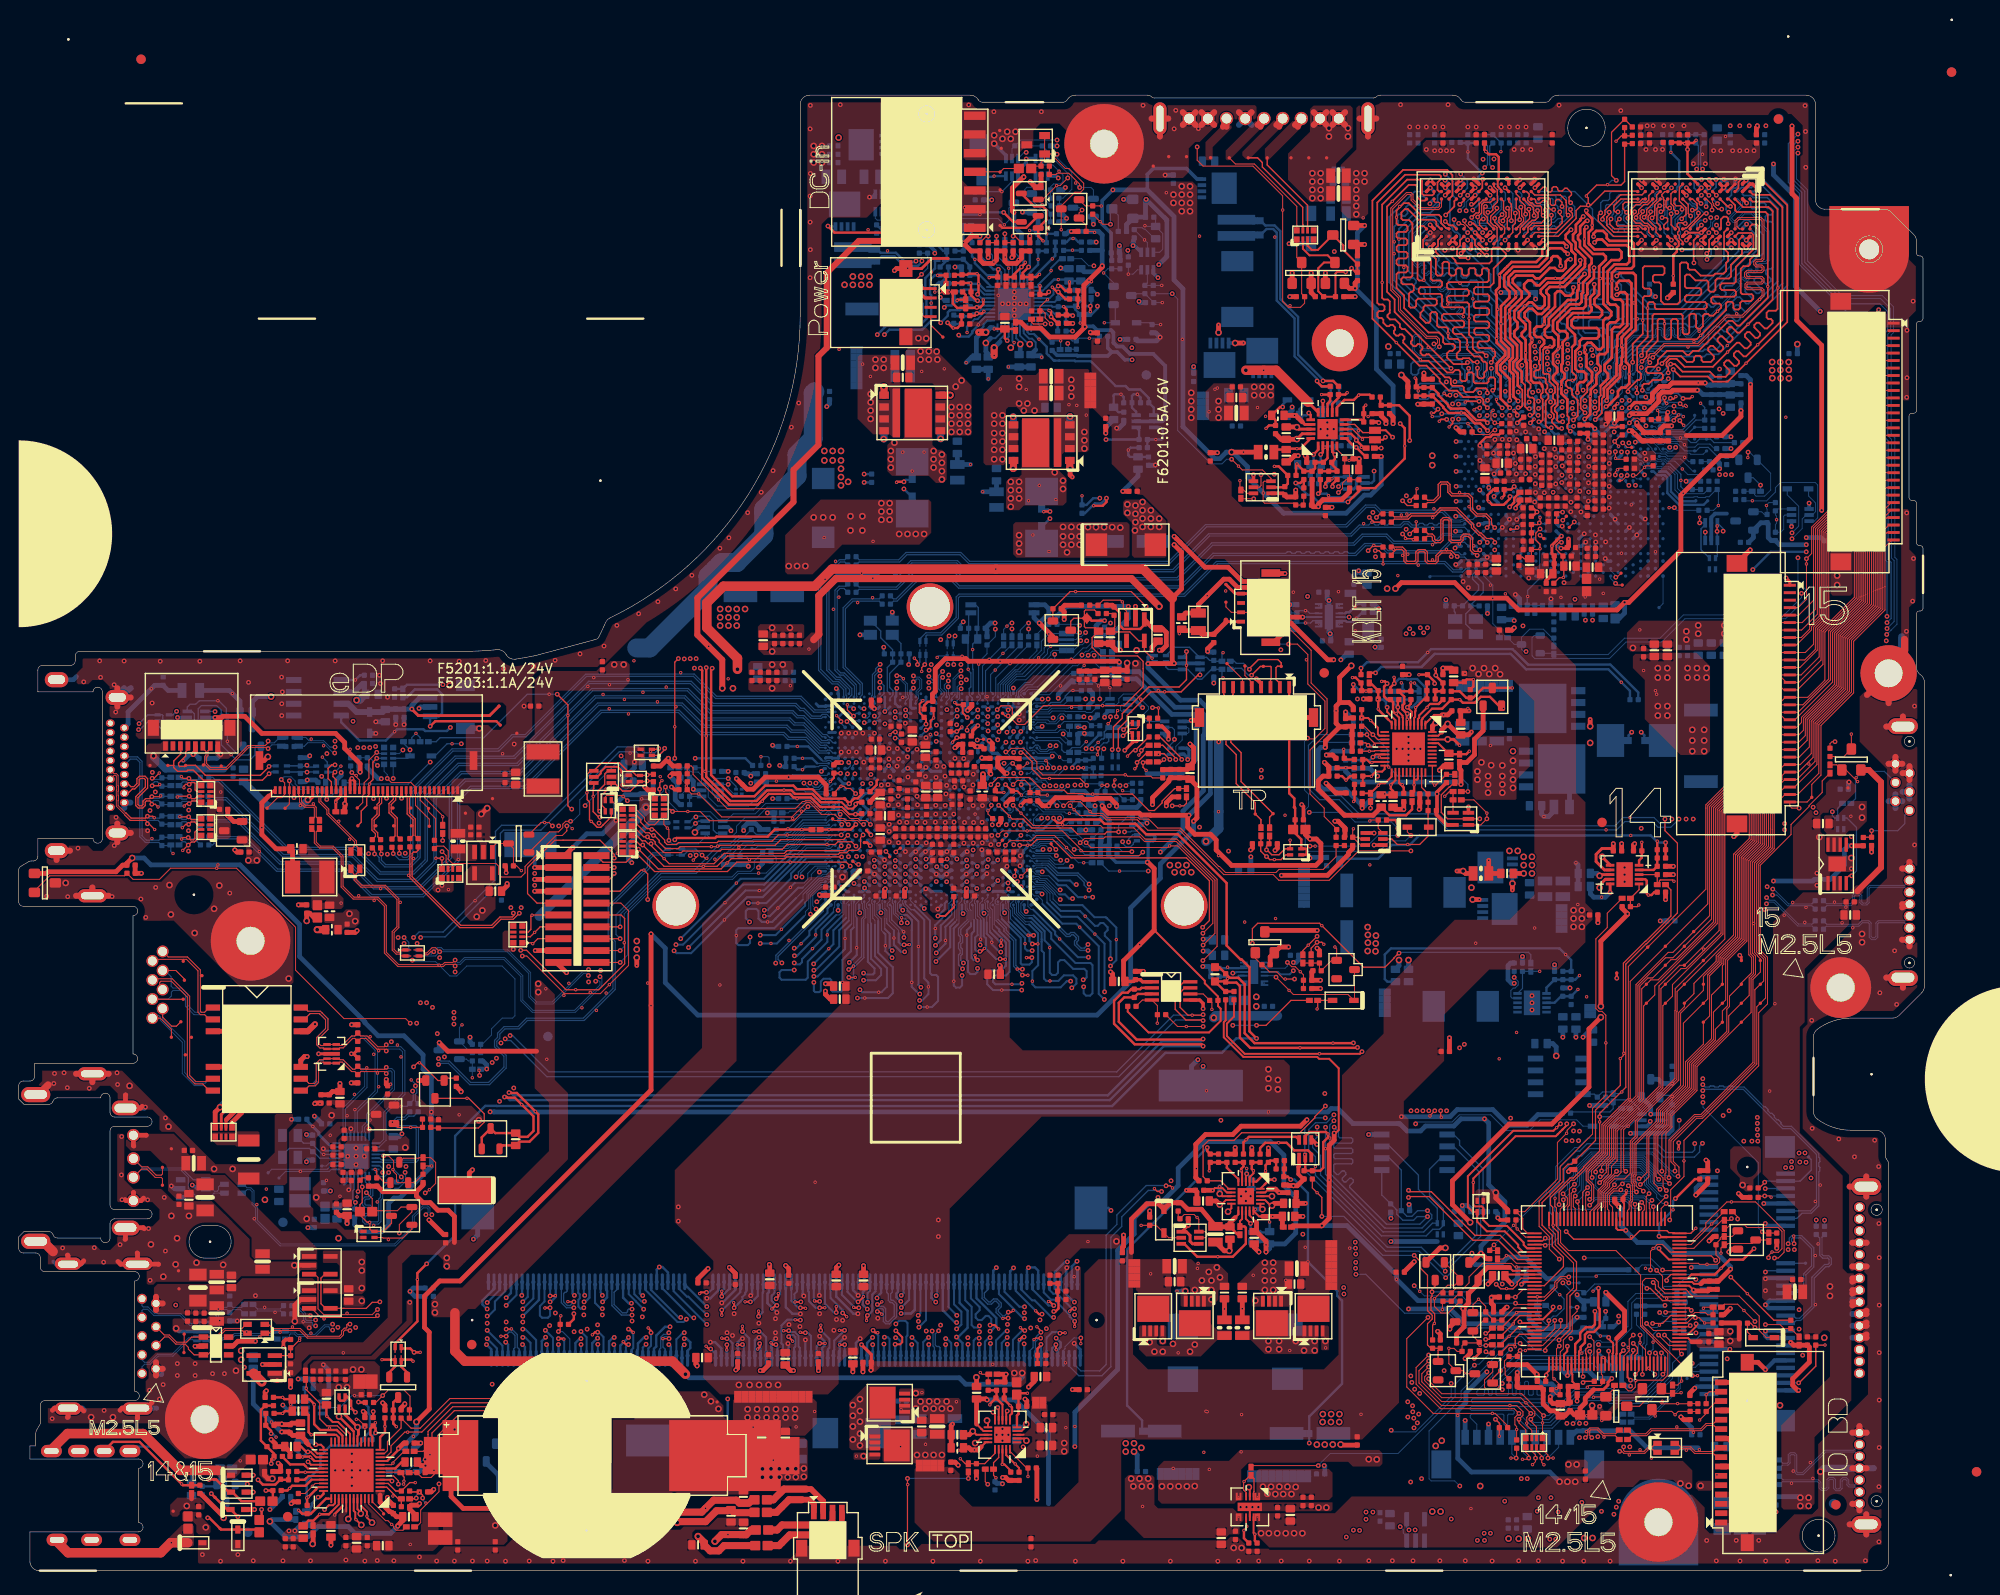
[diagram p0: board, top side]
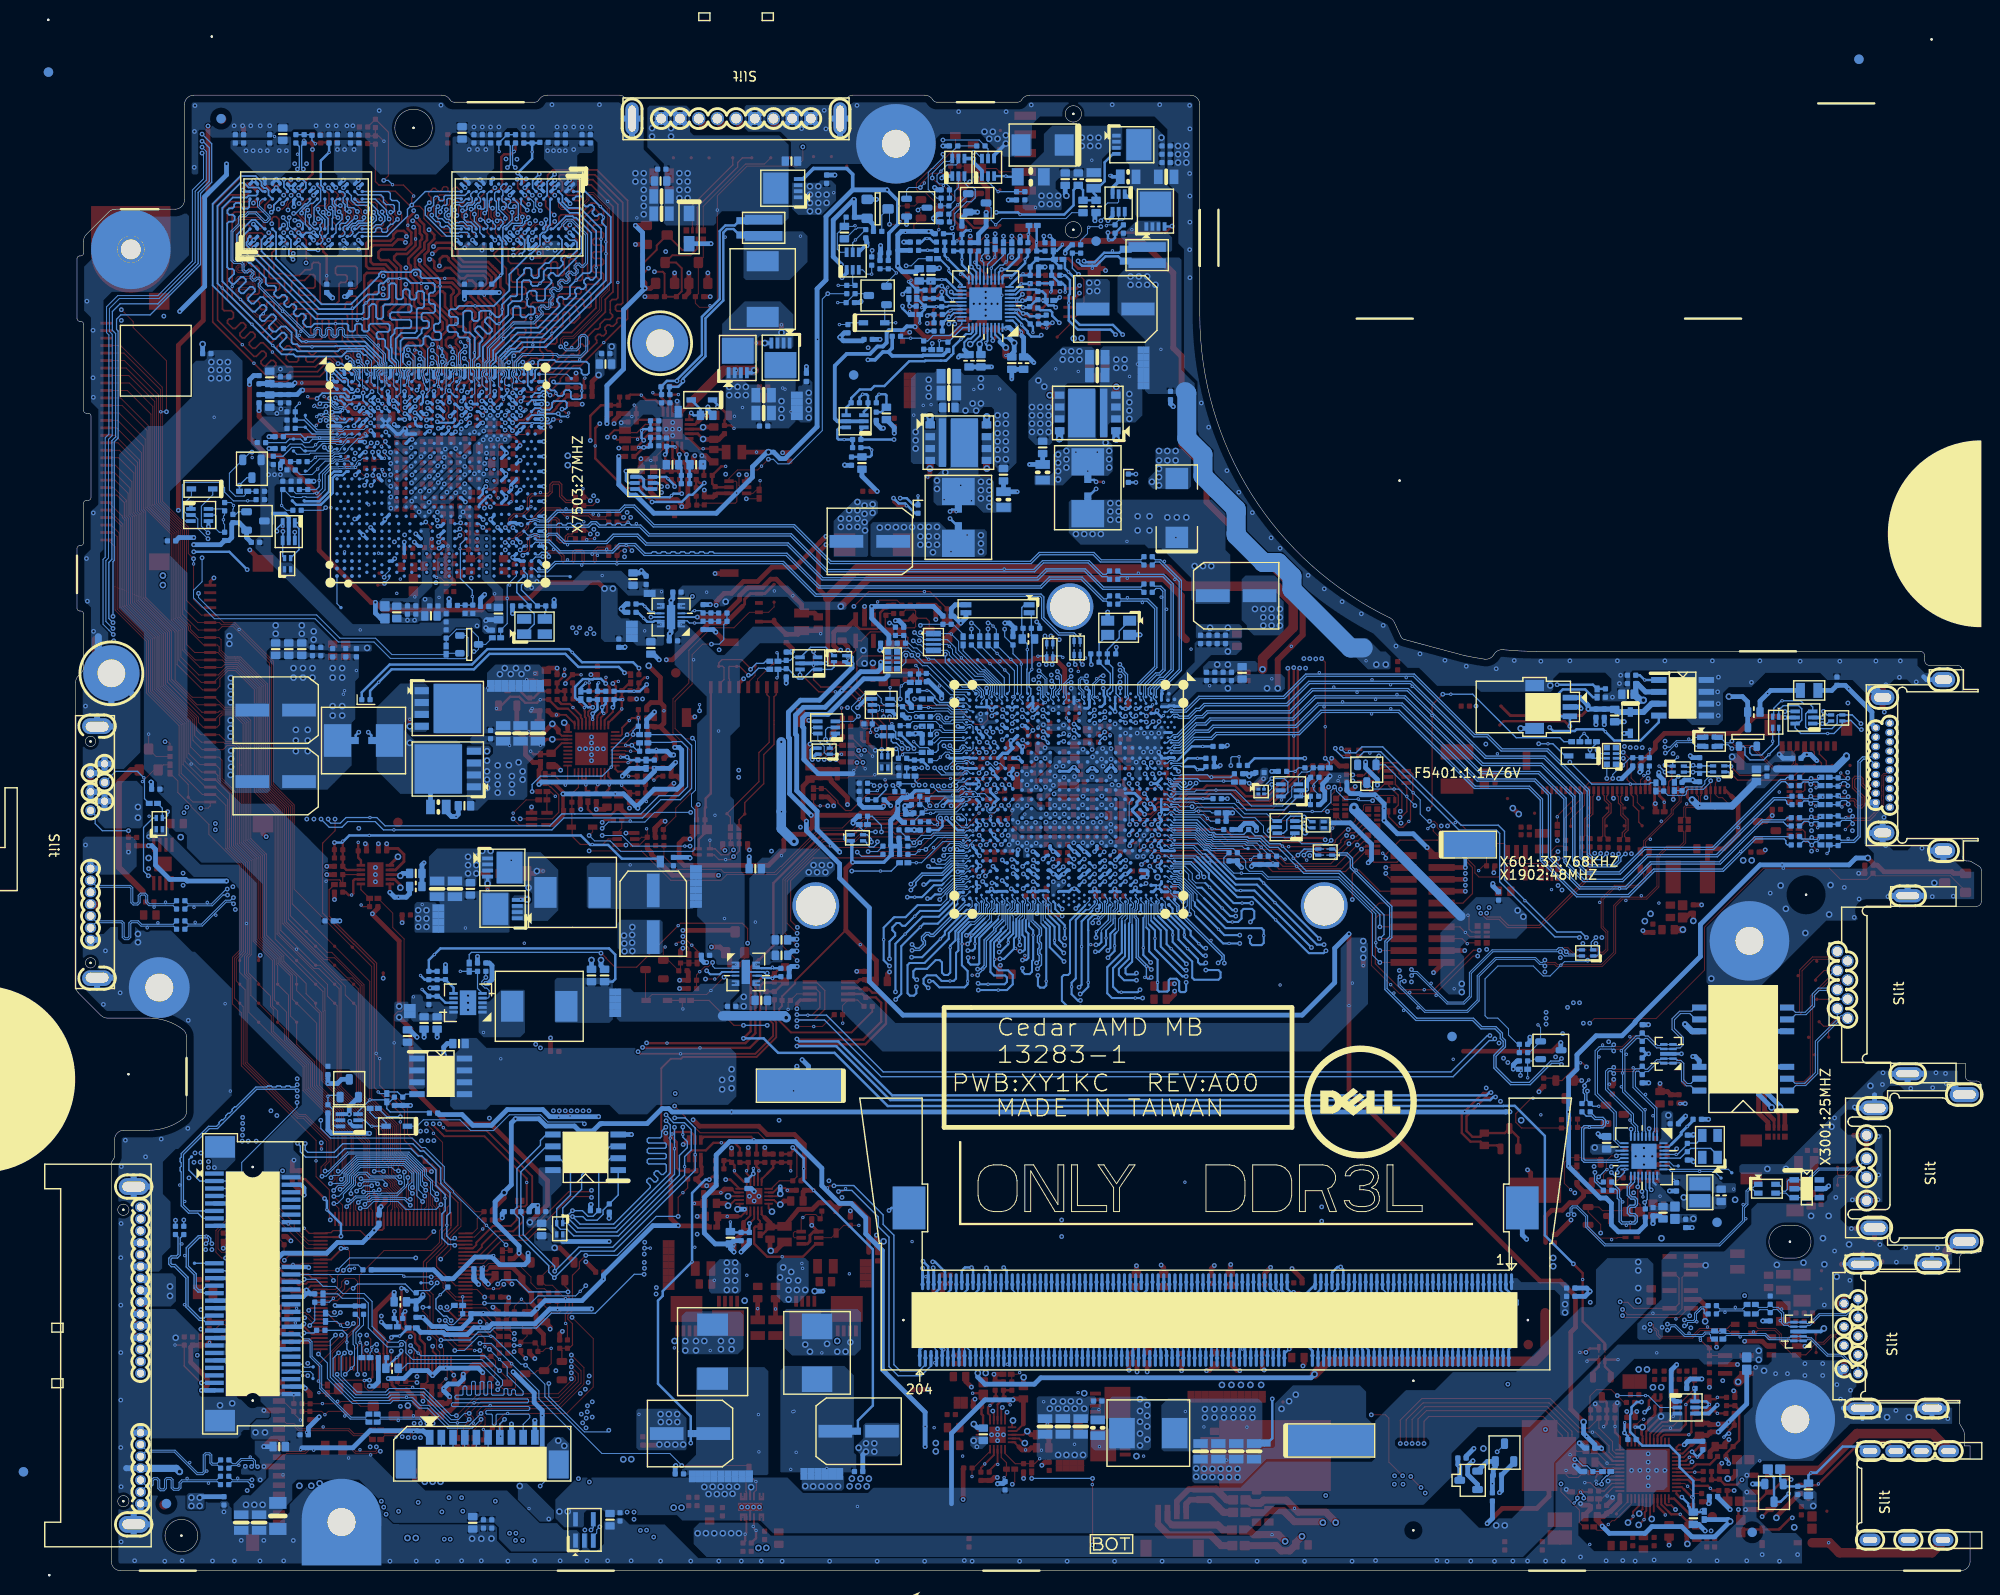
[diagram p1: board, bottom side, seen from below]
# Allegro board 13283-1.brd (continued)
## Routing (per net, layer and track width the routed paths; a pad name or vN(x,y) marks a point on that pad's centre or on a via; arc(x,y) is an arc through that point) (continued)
V3D3_STB: length 9.2
  TOP w0.127: R2712.1 30.76,20.39 v1(30.76,19.52) 30.76,19.37 32.2,17.92 32.2,16.25 32.95,15.5 34.08,15.5 35.03,14.54 HDA27.20
VBAT: length 29.2
  TOP w0.203: KBC24.102 165.69,20.92 v2(165.66,20.89)
  TOP w0.305: v2(170.41,20.57) 170,20.16 170,19.88 169.52,19.4 169.05,19.4 169.02,19.37 168.48,19.37
  TOP w0.508: 168.48,19.37 168.22,19.12 168.22,19.12 167.89,18.79 167.89,18.79 167.57,18.46 167.57,17.95 167.01,17.39 R2402.2 166.41,16.68 C2404.1 165.39,16.56 C2405.1 164.36,17.11 163.81,17.11 163.07,17.85 163.07,19.36 R2404.1 162.86,19.59 160.43,19.59 R2446.1 R2405.1 v2(160.29,21.21)
  BOTTOM w0.508: v2(160.29,21.21) 160.77,21.68 v1(164.26,21.68) 164.87,21.68 v2(165.66,20.89) 165.67,20.89 166.19,21.41 167.89,21.41 168.73,20.57 v2(170.41,20.57)
VDD10: length 4.8
  BOTTOM w0.203: LOM30.3 35.48,47.16 35.53,47.21 v2(35.53,47.3) ; LOM30.22 35.48,40.94 v2(35.3,40.76) ; LOM30.8 37.48,47.13 37.47,47.15 v2(37.47,47.25) ; LOM30.30 32.79,44.95 v2(32.59,45.15)
  vias: v1(32.92,41.77) v1(33.32,46.6) v3(31.82,39.95)
VDD_CT: length 1.6
  TOP w0.254: C7680.2 161.97,113.73 v2(162.41,113.3) 161.95,112.84 C7681.2
  vias: v1(159.03,104.54)
VDDIO_MEM_SENSE: length 4.7
  TOP w0.254: v2(89.55,79.85) 89.01,79.32 86.7,79.32 v1(86.68,79.3) 86.67,79.32 R417.2
  BOTTOM w0.254: v2(89.55,79.85) 89.55,80 CPU1.E25
VDDR3: length 1.5
  TOP w0.127: C7653.2 C7683.2 164.68,113.28 v2(165.15,113.28)
  vias: v1(164.97,104.16)
VDDREG: length 1.1
  BOTTOM w0.203: LOM30.23 35.08,41.57 34.81,41.3
  vias: v1(34.36,40.07)
VSS_MECH1: length 3.7
  BOTTOM w0.102: GPU1.A32 151.29,128.04 TP7703.1
VSS_MECH2: length 3.6
  BOTTOM w0.102: TP7704.1 175.89,103.49 GPU1.AM1
VSS_MECH3: length 3.4
  BOTTOM w0.102: TP7705.1 151.02,106.44 GPU1.AM32
0D95_S5_EN: length 52
  TOP w0.127: PR4819.1 176.73,72.85 176.73,70.05 174.03,67.35 173.99,67.35 171.65,65.01 171.65,55.14 v1(171.32,54.81) 171.32,51.93 168.67,49.28 168.67,46.04 R2437.1 166.13,43.5 165.73,43.5 165.21,42.99 165.21,41.65 162.95,39.39 162.95,36.98 164.04,35.89 164.04,34.74 165.24,33.55 165.24,32.54 163.19,30.5 KBC24.79
0D95V_GFX_S0: length 9.1
  TOP w0.635: R703.1 103.15,84.12 v2(103.15,85.23)
  L3 w0.635: v2(103.15,85.23) 102.33,86.05 99.95,86.05 98.89,87.11 98.8,87.11 97.05,88.86 v2(97.05,89.15)
  vias: v1(97.52,89.49) v2(95.11,87.88)
0D95V_PWR:
  vias: v1(144.52,75.53)
0D95V_PWRGD: length 6.3
  TOP w0.102: v1(140.79,66.74) 140.98,66.55 D3603.1 140.44,65.31 PR3622.2 139.14,64.39 C3625.1 R3605.1 R3604.1
0D95V_S0: length 53.9
  TOP w0.254: R301.1 96.85,92.59 97.23,92.97 R302.1
  TOP w0.508: R302.1 97.74,93.02 97.74,93.79 98.04,94.1 98.04,96.5 98.24,96.71 98.24,96.72 99.12,97.6 101.32,97.6 101.6,97.32 v1(104.98,97.32) 117.63,97.32 v2(117.73,97.22)
  BOTTOM w0.508: v2(117.73,97.22) 117.73,96.54 118.06,96.21 119.86,96.21 v1(121.89,94.18) 123.67,92.4 126,92.4 126.85,91.55 126.85,89.51 126.71,89.38 126.71,83.46 124.53,81.28 124.53,79.32 v2(122.12,76.9)
  vias: v1(102.31,80.97) v1(128.34,76.52) v1(131.14,69.41) v2(101.17,80.08) v2(102.09,81.87) v2(102.14,80.07) v2(103.09,81.87) v2(103.06,80.09) v3(123.14,75.51) v3(123.64,74.74) v3(124.03,75.51) v3(124.53,74.74) v3(124.91,75.51) v3(125.42,74.74)
0D95V_S0_EN: length 6.7
  TOP w0.102: v2(135.71,65.09) 136.17,64.63 136.55,64.63 v1(137.08,64.1) 137.42,63.76 R3624.2 C3626.1
  BOTTOM w0.102: U3603.3 135.47,64.48 135.71,64.71 v2(135.71,65.09)
0D95V_S5: length 1.4
  L3 w0.762: v3(119.58,98.49) 119.58,97.22 v3(119.45,97.1)
  vias: v1(103.58,93.54) v1(111.45,94.68) v1(124.15,100.27) v1(134.44,69.79) v1(135.07,89.86) v1(135.46,80.84) v1(137.74,97.48) v2(100.15,86.94) v2(101.09,86.91) v2(107.03,91.69) v2(107.03,91.03)
0D95V_S5_PWRGD: length 59.7
  TOP w0.102: v2(167.33,20.77) 167.29,20.81 KBC24.106 ; v2(164.79,33.34) 163.72,34.41 163.72,35.76 162.63,36.85 162.63,39.52 164.89,41.78 164.89,43.27 168.35,46.73 168.35,49.47 169.77,50.89 v1(169.77,56.48) 169.77,59.45 169.36,59.86 169.02,59.86 168.7,60.17 168.7,67.61 169.92,68.83 169.92,70.36 PR4821.2
  L4 w0.102: v2(167.33,20.77) 167.33,21.48 166.19,22.62 166.19,24.1 165.61,24.68 165.61,26.41 165.68,26.49 165.68,27.1 165.33,27.46 165.33,29 164.36,29.96 164.36,32.91 v2(164.79,33.34)
0D95V_VGA_OUT2:
  vias: v1(142.97,100.58)
0D95V_VGA_S0: length 60.4
  TOP w0.508: v2(185.24,126.94) 185.24,121.23 183.33,119.32 182.02,119.32 177.8,115.1 177.8,109.18 172.24,103.62 v2(171.78,103.62) 170.97,102.81 160.43,102.81 159.16,104.08 155.27,104.08 153.62,105.73 147.9,105.73 v3(147.27,105.1)
  BOTTOM w0.508: v2(171.78,103.62) 171.78,102.48 171.19,101.9 L7706.1 ; v2(185.24,126.94) 185.24,127.45 184.8,127.89 L7705.1
  vias: v1(159.84,116.58) v2(157.91,121.05) v2(158.7,121.07) v2(159.46,121.05) v2(159.89,119.6) v2(160.09,118.48) v2(160.25,121.02) v2(160.2,117.37) v2(161.19,117.39) v3(146.38,105.1) v3(151.2,119.32) v3(151.2,118.31)
0D675V_S0: length 3.3
  BOTTOM w0.305: v2(112.9,24.33) 113.55,23.68 DM1.204 ; DM1.203 v2(113.25,32.37)
  vias: v1(111.96,22.24) v1(112.9,31.46)
1D5V_S0: length 230.8
  TOP w0.203: HDA27.9 39.42,11.74 39.43,11.75
  TOP w0.254: v2(40.61,13.07) 40.61,12.93 39.43,11.75
  TOP w0.508: v2(125.68,80.21) 126.03,80.56 126.03,83.96 C1038.1 125.14,84.86 C1036.1 C1037.1 123.04,84.66 123.04,84.48 121.28,82.72 v2(121.28,81.98) ; v3(31.44,2.86) 31.49,2.91 R2705.1 ; v2(67.64,68.14) v1(67.64,60.47) 67.64,51.43 47.22,31.01 45.03,31.01 43.41,29.38 43.41,26.03 43.91,25.52 43.91,17.29 v3(42.54,15.92) ; C2719.1 41.2,13.66 v2(40.61,13.07) ; C1035.1 102.1,88.43 102.35,88.18 v2(102.54,88.18) 103.03,88.18 C1034.1
  TOP w1.016: v3(26.01,20.2) 25.12,21.1 U3602.5
  L4 w0.254: v2(102.54,88.18) 102.54,88.18 103.71,87.02 103.71,86.62 105.71,84.62 108.15,84.62 109.37,83.41 113.56,83.41 114.09,82.87 120.77,82.87 121.28,82.36 v2(121.28,81.98)
  L4 w1.016: v3(26.01,20.2) 28.74,22.93 36.65,22.93 37.92,21.66 37.92,21.01 39.82,19.11 39.82,13.86 v2(40.61,13.07) 40.61,11.9 38.81,10.1 38.81,8.83 37.79,7.82 35.74,7.82 33.58,5.65 33.58,3.81 34.36,3.03 34.36,2.23 33.86,1.72 32.1,1.72 31.44,2.38 v3(31.44,2.86)
  BOTTOM w0.381: CPU1.AL10 102.73,88.18 v2(102.54,88.18) 102.6,88.12 CPU1.AL11
  BOTTOM w0.508: v3(42.54,15.92) 42.54,14.7 v1(42.22,14.37) 41.34,13.49 C3607.1 40.66,13.12 v2(40.61,13.07) ; v2(67.64,68.14) 69.16,66.62 69.16,62.93 72.64,59.45 115.35,59.45 118.95,63.05 118.95,70.93 122.12,74.11 122.12,75.63 125.68,79.19 v2(125.68,80.21)
1D5V_S0_EN: length 3.8
  TOP w0.127: v1(30.05,24.66) 30,24.66 29.2,23.86 R3626.1 R3625.2 29.08,23.01 U3602.3
1D8V_PWR: length 26.7
  BOTTOM w0.254: PC5014.1 PR5009.1 166.06,65.35 v1(165.47,65.94) 164.82,66.59 146.78,66.59 146.12,65.93 146.12,63.31 146.4,63.03 PC5012.1
1D8V_S0: length 154.5
  TOP w0.508: R424.2 R422.2 69.92,85.29 v2(69.67,85.03) ; HDT1.1 58.4,76.52 59.26,77.38 v2(59.28,77.38) ; v2(76.78,84.75) 77.39,84.14 77.41,84.14 77.92,83.63 78.57,83.63 79.85,84.92 v1(82.34,84.92) 85.53,84.92 86.37,84.08 R403.1 ; v2(102.82,142.82) 101.93,142.82 101.11,142 101.89,141.23 PR4656.1 102.82,140.28 103.2,139.9 104.21,139.9 104.59,140.28 PR4655.1 PR4654.1 105.48,140.15 105.74,139.9 106.71,139.9 107.26,140.45 PR4653.1 PC4622.1 ; HDT1.19 57.73,64.87 v2(58.6,64) ; v1(66.11,64.76) v3(66.11,65.6)
  TOP w0.635: 101.11,142 96.4,142 96.1,142.31 89.86,142.31 86.43,138.88 86.43,130.86 85.54,129.97 85.54,120.46 82.88,117.8 82.88,114.37 72.59,104.08 72.59,100.14 v1(73.81,98.92) 75.26,97.48 v3(75.26,94.43)
  L3 w0.508: v3(66.11,65.6) 64.97,64.46 63.45,64.46 62.94,64.97 59.56,64.97 v2(58.6,64) ; v2(77.54,79.2) 76.92,79.2
  L4 w0.508: v2(59.28,77.38) 58.6,76.7 v2(58.6,64) ; v2(76.78,84.75) 76.78,84.13 76.16,83.51 75.51,83.51 73.99,85.03 v2(69.67,85.03)
  BOTTOM w0.305: CPU1.C3 CPU1.B3 86.9,92.55 86.35,92.55 CPU1.A3 85.57,92.5 85.29,92.78
  BOTTOM w0.508: 67.86,84.38 67.86,83.5 67.51,83.15 66.46,83.15 66.34,83.04 64.85,83.04 63.88,82.07 v1(63.88,81.58) v2(63.88,80.29) 62.45,78.86 60.76,78.86 v2(59.28,77.38) ; R420.2 R434.1 79.26,79.51 78.79,79.98 77.95,79.98 77.54,79.57 v2(77.54,79.2) ; PR4648.1 v2(102.82,142.82) ; v2(69.67,85.03) 70.02,84.68 70.02,84.63 70.45,84.2 70.45,83.6 70.23,83.37 70.23,82.49 70.74,81.98 R421.1
  vias: v1(67.28,62.88) v1(68.63,84.98) v1(75.89,95.45) v1(82.55,94.71) v3(66.11,67.38) v3(66.11,66.49) v3(76.4,94.43) v3(80.59,94.43)
1D8V_S5: length 123
  TOP w0.508: v2(122.76,81.85) 122.76,82.18 123.38,82.81 R627.2
  TOP w0.762: 85.04,99.64 85.58,100.18 85.58,104.34 87.42,106.17 119.02,106.17 v3(121.99,103.19)
  L3 w1.016: v3(134.31,103.7) 133.68,103.7 128.72,98.75 128.72,91.63 128.36,91.27 v2(128.36,88.7) ; v3(127,78.05) 127,76.09 128.09,75 128.09,59.43 v3(127.84,59.17)
  L4 w0.508: v2(128.36,88.7) 127.33,89.73 120.4,89.73 118.12,92.02 115.39,92.02 v2(114.63,91.25) ; v2(122.76,81.85) 122.76,81.48 126.18,78.05 v3(127,78.05)
  BOTTOM w0.508: R649.1 115.07,91.25 v2(114.63,91.25)
  BOTTOM w1.016: v2(128.36,88.7) 128.36,81.24 ; 128.36,81.24 v1(128.34,81.22) ; 128.36,81.24 128.36,79.41 v3(127,78.05) ; v3(127.84,59.17) 128.04,59.38 134.64,59.38
  vias: v1(84.53,98.62) v1(129.11,104.84) v1(136.34,104.72) v3(80.59,98.37)
1D8V_S5_PWRGD: length 70
  TOP w0.102: v1(138.68,77.54) v2(138.12,77.54)
  L3 w0.102: v2(159.97,63.49) 160.42,63.95 169.24,63.95 171.52,66.24 171.52,70.68 171.78,70.93 173.68,70.93 175.08,72.33 175.08,77.92 v2(173.56,79.44)
  L4 w0.102: v2(147.52,78.68) 148.03,79.19 173.3,79.19 v2(173.56,79.44)
  BOTTOM w0.102: v2(147.52,78.68) 145.4,78.68 144.26,77.54 v2(138.12,77.54) ; PR5011.2 v2(159.97,63.49) 160.4,63.06 160.4,62.68 160.07,62.35 159.87,62.35 159.61,62.09 159.61,61.41 159.75,61.27 PU5002.4
1D8V_VGA_S0: length 10.3
  TOP w0.508: v2(184.22,124.15) 184.22,123.51 182.19,121.48 178.38,121.48
  BOTTOM w0.508: v2(163.9,104) 163.89,103.99 R7527.2 ; v2(160.09,104.46) 160.54,104.02 L7601.1 ; L7703.1 v2(184.22,124.15)
  vias: v1(147.52,106.49) v1(157.43,105.48) v1(169.49,104.59) v1(175.08,109.03) v1(177.75,121.23) v2(154.51,105.86) v2(155.06,105.2)
1D35V_ENABLE: length 10.5
  BOTTOM w0.127: PQ8314.3 173.63,49.12 v1(172.36,50.39) 170.77,50.39 PR8328.2 ; PR8328.2 170.25,50.17 PR8347.2 ; PR8328.2 170.56,49.45 170.2,49.09 166.13,49.09 PR8348.2
1D35V_ENABLE_RC: length 4.7
  BOTTOM w0.127: v1(171.48,51.23) 171.31,51.06 PR8328.1 170.38,51.23 169.41,51.23 PC8322.1 168.54,51 PQ8318.4
1D35V_PGOOD: length 3.8
  TOP w0.102: PU4901.20 106.03,12.78 107.82,10.99 PR4904.2 v1(107.96,10.08)
1D35V_PWR: length 1.1
  TOP w0.203: PU4901.2 107.55,14.15 v3(107.79,13.91)
  vias: v1(78.56,15.36) v1(83.16,15.38) v1(85.14,17.04) v2(107.44,13.25) v3(77.97,17.28) v3(77.97,16.39) v3(78.98,17.28) v3(78.98,16.39) v3(80,17.28) v3(80,16.39) v3(81.01,17.28) v3(81.01,16.39) v3(82.03,17.28) v3(82.03,16.39) v3(83.05,17.28) v3(83.05,16.39)
1D35V_S3: length 62.9
  BOTTOM w0.254: v2(90.01,24.83) 89.55,24.37 DM1.124 ; v2(75.21,28.66) 75.28,28.66 76.65,30.04 DM1.81 ; DM1.88 78.75,24.67 79.04,24.96 v2(79.19,24.96) ; v2(77.42,24.83) 77.29,24.83 76.91,24.45 76.91,23.82 76.95,23.78 DM1.82 ; v2(80.97,24.83) 80.92,24.83 80.49,24.4 80.49,23.9 80.55,23.84 DM1.94 ; DM1.118 87.75,23.38 87.81,23.44 87.81,24.43 v2(88.34,24.96) ; v2(81.1,27.63) 80.1,28.63 80.1,29.65 80.25,29.8 DM1.93 ; v2(85.67,25.09) 86.18,24.58 86.18,24.07 85.95,23.84 DM1.112 ; v2(85.64,29.46) 85.64,29.53 85.65,29.54 DM1.111 ; DM1.100 82.35,24.24 v2(82.29,24.31) ; DM1.123 89.25,30.02 89.79,29.48 v2(89.79,29.46) ; DM1.87 78.45,29.58 v2(78.3,29.43) ; DM1.105 83.85,29.58 84.02,29.41 84.02,29.39 83.98,29.39 v2(83.98,29.4) ; v2(89.77,27.5) 89.28,27.5 87.45,29.33 DM1.117 ; DM1.99 82.05,28.2 82.75,27.5 83.6,27.5 v2(83.62,27.48) ; DM1.106 v2(84.15,24.7) ; DM1.75 74.85,30.01 73.99,29.15 v2(73.61,29.15) ; v2(73.99,24.45) 74.5,24.45 75.15,23.8 DM1.76
  BOTTOM w0.305: CPU1.AR35 105.3,74.97 v2(105.71,75.38)
  BOTTOM w0.356: CPU1.R31 94.6,77.2 v2(94.85,76.95) ; CPU1.AA31 97.6,77.5 97.05,76.95 v2(97,76.95)
  BOTTOM w0.381: CPU1.U35 95.44,74.95 95.84,74.55 v2(95.95,74.55) 96.05,74.55 96.45,74.15 CPU1.W37 ; CPU1.W32 96.9,76.95 v2(97,76.95) ; CPU1.R37 94.26,74.15 93.86,74.55 v2(93.75,74.55) 93.58,74.55 93.2,74.93 CPU1.N35 ; CPU1.AL32 103.1,77.07 v2(103.02,77.15) ; CPU1.W31 96.55,77.55 v2(95.95,76.95) 95.8,76.95 CPU1.U32 ; CPU1.L32 92.12,76.55 v2(92.61,76.06) ; CPU1.AJ35 101.85,74.95 101.45,74.55 v2(101.37,74.55) 101.3,74.55 CPU1.AG37 ; v2(101.45,76.95) 101.3,76.95 CPU1.AG32 ; CPU1.AA35 97.75,74.95 v2(98.15,74.55) 98.19,74.51 98.34,74.51 CPU1.AC37 98.7,74.15 99.1,74.55 v2(99.25,74.55) 99.65,74.95 CPU1.AE35 ; CPU1.AE31 99.6,77.33 99.29,77.02 v2(99.29,76.95) 99.1,76.95 CPU1.AC32 ; CPU1.J35 91.4,74.55 v2(91.55,74.55) 91.68,74.55 92.08,74.15 CPU1.L37 ; CPU1.AL37 103.1,74.23 103.45,74.58 v2(103.56,74.58)
  vias: v1(85.19,41.57) v1(127.05,51.35) v1(158.37,54.78) v2(70.56,38.93) v2(70.56,37.41) v2(75.77,25.47) v2(76.35,25.16) v2(76.53,27.5) v2(79.17,26.48) v2(80.95,26.97) v2(80.95,25.47) v2(82.4,26.33) v2(83.56,26.13) v2(85.67,27.5) v2(87.2,25.72) v2(87.48,26.89) v2(88.14,26.79) v2(91.89,27.02) v2(98.37,37.53) v2(98.37,35.76) v3(77.04,19.88) v3(78.18,19.88) v3(79.19,19.88) v3(80.21,19.88) v3(81.23,19.88) v3(133.68,53.66) v3(133.68,52.65) v3(133.68,51.63) v3(134.69,52.52) v3(134.69,51.5)
1D35V_VGA_EN: length 6.2
  BOTTOM w0.127: PQ8314.2 172.92,48.2 172.29,47.57 v1(172.16,47.57) PD8307.A 170.63,47.95 171.14,48.46 171.78,48.46 172.35,49.03 PR8345.2
1D35V_VGA_EN#: length 6.3
  BOTTOM w0.127: 176.3,48.2 176.3,47.74 176.11,47.55 PQ8314.6 ; 176.3,48.2 176.3,49.31 PR8341.2 v1(176.86,50.77) 176.76,50.87 175.75,50.87 PQ8317.G ; 176.3,48.2 PQ8314.5
1D35V_VGA_S0: length 52.5
  TOP w0.203: v2(178.39,143.19) v2(179.99,143.19)
  TOP w0.254: VRAM3.D2 VRAM3.C1
  TOP w0.356: VRAM3.G7 180.39,143.59 v2(179.99,143.19) ; VRAM3.K8 177.99,142.79 v2(178.39,143.19) ; VRAM1.R1 161.8,141.99 v2(162.23,141.56) ; v2(184.79,142.39) 185.19,142.78 VRAM3.A8 ; v2(156.59,142.4) 156.58,142.4 VRAM1.H2 155.79,143.19 v2(155.79,143.2) ; VRAM1.H9 156.19,148.4 v2(155.65,148.94) ; VRAM3.B2 VRAM3.A1 185.47,148.39 185.93,147.93 v2(185.93,147.74) ; v2(157.39,142.4) 157.79,142.79 VRAM1.K2 ; VRAM1.N1 160.19,141.51 v2(160.39,141.32) ; v2(170.69,122.79) 171.35,123.45 C7610.2 ; v2(162.15,148.93) 162.15,148.75 VRAM1.R9 ; v2(157.39,148) 157.79,147.59 VRAM1.K8 ; v2(154.28,140.97) 154.59,141.28 VRAM1.F1 ; v2(154.23,148.83) 153.79,148.39 VRAM1.E9 ; v2(179.99,147.99) 179.59,147.59 VRAM3.H2 ; v2(175.21,148.82) 175.59,148.44 VRAM3.N1 ; VRAM3.D9 182.79,141.99 v2(183.19,142.39) 183.58,141.99 VRAM3.C9 ; v2(151,147.99) 150.98,147.99 150.59,147.6 VRAM1.A8 ; VRAM3.F1 180.82,148.76 v2(180.82,148.89) ; v2(155.79,147.2) 155.39,146.79 VRAM1.G7 ; VRAM3.K2 177.99,147.59 v2(178.39,147.19) ; v2(173.61,148.79) 173.99,148.4 VRAM3.R1 ; VRAM1.N9 160.19,148.48 v2(160.58,148.87) ; VRAM1.C9 152.2,148.39 v2(152.6,147.99) 152.6,148.01 152.98,148.39 VRAM1.D9 ; C7607.2 C7608.2 168.21,122.61 v2(168.6,122.22)
  TOP w0.508: v3(147.9,127.96) 148.6,127.26 R7411.1 R7410.1
  BOTTOM w0.203: v2(178.39,143.19) 179.19,143.19 VRAM4.H2
  BOTTOM w0.254: v2(185.93,147.74) 185.77,147.59 VRAM4.A8
  BOTTOM w0.356: v2(173.61,148.79) 173.99,148.4 VRAM3.R1 ; v2(157.39,148) 157.79,147.59 VRAM1.K8 ; v2(155.79,143.2) 155.4,143.59 VRAM2.G7 ; VRAM3.N1 175.59,148.44 v2(175.21,148.82) ; v2(157.39,142.4) 157.79,142.79 VRAM1.K2 ; v2(170.69,122.79) 170.69,122.84 GPU1.J9 ; v2(170.69,122.79) 170.34,122.44 GPU1.K10 GPU1.L11 169.18,121.64 v2(168.6,122.22) 168.49,122.1 GPU1.L12 GPU1.L13 ; v2(170.69,122.79) 170.29,123.19 GPU1.J10 ; v2(170.69,122.79) 171.04,122.44 GPU1.K9 ; VRAM1.N9 160.19,148.48 v2(160.58,148.87) ; VRAM4.D9 182.79,148.52 v2(182.4,148.91) 181.99,148.51 VRAM4.E9 ; v2(179.99,143.19) 179.59,142.79 VRAM4.H2 ; VRAM2.H2 156.19,147.59 v2(155.79,147.2) ; v2(180.5,145.98) 180.52,146 180.52,146.66 VRAM4.G7 ; v2(156.59,142.4) 156.19,142 VRAM2.H9 ; VRAM4.B2 184.39,142.79 v2(184.79,142.39) 185.19,141.99 VRAM4.A1 ; GPU1.H16 166.04,124.4 v2(166.18,124.4) ; VRAM3.K2 177.99,147.59 v2(178.39,147.19) ; VRAM2.B2 151.39,147.59 v2(151,147.99) 150.59,148.39 VRAM2.A1 ; v2(183.65,148.94) 183.59,148.88 VRAM3.C1 ; GPU1.H19 163.29,124.04 v2(163.78,123.55) ; VRAM2.F1 154.59,148.46 v2(154.23,148.83) ; VRAM1.C9 152.2,148.39 v2(152.6,147.99) 152.99,147.6 VRAM2.D2 ; v2(162.15,148.93) 161.79,148.56 VRAM1.R9 ; v2(179.99,147.99) 179.59,148.39 VRAM4.H9 ; v2(167.52,124.58) 167.67,124.58 168.09,124.15 GPU1.H13 ; v2(178.39,143.19) 177.99,142.79 VRAM3.K8 ; VRAM4.D2 182.79,142.78 v2(183.19,142.39) 183.58,141.99 VRAM3.C9 ; VRAM2.A8 v2(150.99,143.19)
  vias: v1(171.7,55.36) v1(180.21,66.51) v1(182.57,153.48) v1(189.02,123.44) v1(191.49,86.33) v2(150.57,152.09) v2(151.46,151.96) v2(152.09,151.96) v2(152.55,141.3) v2(152.73,151.96) v2(153.36,151.96) v2(153.37,141.51) v2(159.5,123.64) v2(159.97,152.09) v2(160.2,121.96) v2(160.86,152.09) v2(161.19,121.86) v2(161.74,152.09) v2(162.58,122.18) v2(173.55,141.41) v2(174.06,152.09) v2(175.08,152.09) v2(175.08,141.5) v2(175.84,152.09) v2(179.98,141.58) v2(181.3,151.96) v2(181.55,141.56) v2(182.06,151.96) v2(183.33,151.96) v2(184.1,151.96) v2(184.86,151.96) v2(185.62,151.96) v3(187.56,129.34) v3(187.56,128.46) v3(187.58,127.62) v3(188.42,129.33) v3(188.44,128.49) v3(188.47,127.61) v3(189.33,129.34) v3(189.34,128.5) v3(189.35,127.6)
3D3V_AUX_KBC: length 470.5
  TOP w0.203: R2622.1 129.99,59.3 129.23,58.54 129.23,57.22 131.14,55.31 v1(139.14,55.31) 143.46,55.31 v2(143.69,55.54)
  TOP w0.508: R2414.2 157.57,29.28 v2(157.52,29.22) 157.52,28.63 157.76,28.39 R2418.2 ; R2426.2 159.27,38.61 158,39.88 v3(158,40.46) ; v2(147.01,122.75) 147.01,123.45 PR4439.1 ; R2413.2 157.01,33.38 v2(156.41,33.98) 155.42,32.99 Q2402.D ; v2(138.25,138.88) D4302.2 138.25,136.78 PR4412.1 ; v3(168.3,17.67) 168.3,16.7 R2402.1 ; D4301.2 v2(143.96,143.96) ; D4303.2 142.34,137.23 v2(142.95,137.23) 142.95,137.8 PR4415.1
  L3 w0.508: v2(143.69,55.54) 143.69,55.52 149.22,49.98 155.17,49.98 v2(156.79,48.35) 157.5,49.06 164.93,49.06 168.04,52.18 176.64,52.18 177.31,51.51 179.58,49.24 180.36,49.24 181.23,50.11 183.16,50.11 183.64,50.59 183.64,59.5 193.75,69.61 193.75,79.85 194.64,80.74 194.64,81.88 192.82,83.7 192.82,107.29 193.49,107.97 193.49,114.06 192.71,114.85 v2(192.71,134.76) ; v2(166.7,29.53) 166.7,31.45 166.07,32.07 165.16,32.07 163.26,33.98 v2(156.41,33.98) 156.41,30.33 v2(157.52,29.22) ; v2(65.58,75.76) 65.58,75.6 56.77,66.79 56.77,61.54 54.81,59.58 54.81,55.26 50.45,50.9 50.45,49.13 v2(50.43,49.11) ; v2(143.96,143.96) 143.96,147.31 147.98,151.33 155.91,151.33 156.29,151.71 159.45,151.71 159.7,151.45 163.27,151.45 165.56,149.17 169.75,149.17 173.53,152.95 186.03,152.95 186.99,151.99 186.99,151.25 v2(187.7,150.54)
  L4 w0.508: v2(142.95,137.23) 139.9,137.23 v2(138.25,138.88) ; v2(166.7,29.53) 166.7,29.08 167.38,28.4 167.38,23.24 168.3,22.32 v3(168.3,17.67)
  BOTTOM w0.508: 69.49,80.03 67.5,80.03 65.22,77.75 65.22,76.12 v2(65.58,75.76) ; v2(187.7,150.54) 187.7,149.38 190.04,147.04 190.04,137.43 v2(192.71,134.76) ; R2436.1 167.43,28.84 R2434.1 ; R2436.1 167.19,28.85 166.7,29.35 v2(166.7,29.53) ; R2436.1 168.37,28.85 R2403.2 ; v2(156.41,33.98) 156.41,34.74 158.98,37.3 158.98,39.49 v3(158,40.46) 158,40.53 157.24,41.29 157.24,47.9 v2(156.79,48.35) 154.28,48.35 153.51,47.59 150.49,47.59 149.96,47.06 148.51,47.06 147.75,47.82 147.59,47.82 147.56,47.85 142.72,47.85 141.11,49.45 140.4,49.45 140.04,49.09 v1(133.68,49.09) 50.86,49.09 50.85,49.11 v2(50.43,49.11) ; v2(143.96,143.96) 143.2,143.2 143.2,137.48 v2(142.95,137.23) 142.96,137.23 145.23,134.95 145.23,128.59 147.01,126.81 v2(147.01,122.75)
3D3V_AUX_KBC_VCC: length 60.6
  TOP w0.203: KBC24.88 163.05,26.9 164.13,27.98 v2(164.13,28.22) ; C2411.1 159.11,31.7 KBC24.76 ; 179.94,30.7 179.2,30.7 179,30.9 KBC24.19 ; 170.93,24.85 170.93,23.22 170.89,23.18 KBC24.115 ; v2(171.9,36.42) 171.87,36.45 171.07,36.45 170.89,36.63 KBC24.46
  TOP w0.508: v2(183.11,32.28) 181.82,30.99 C2408.1 C2410.1 180.23,30.99 179.94,30.7 ; C2411.1 158.98,31.41 v2(159.71,30.68) ; v2(169.77,29.79) 171.78,27.78 171.78,25.7 170.93,24.85
  L3 w0.508: v2(159.71,30.68) 162.17,28.22 v2(164.13,28.22) 164.13,28.4 164.63,28.9 168.88,28.9 v2(169.77,29.79)
  L4 w0.508: v2(171.9,36.42) 171.9,35.81 170.76,34.66 170.76,32.71 169.77,31.72 v2(169.77,29.79)
  BOTTOM w0.508: v2(159.71,30.68) 159.98,30.94 159.98,30.96 160.35,31.33 C2406.1 C2407.1 ; C2409.1 171.39,36.93 v2(171.9,36.42) 171.9,36.36 v1(172.51,35.76) 173.15,35.12 175.84,35.12 176.98,33.98 181.66,33.98 183.11,32.53 v2(183.11,32.28) ; v2(169.77,29.79) R2403.1
3D3V_AUX_S5: length 392.9
  TOP w0.203: v2(140.71,46.83) 140.87,46.83 141.2,47.16 141.2,53.76 140.18,54.78 139.1,54.78 138.89,54.98 131,54.98 128.9,57.08 128.9,58.69 129.11,58.89 R2611.1 ; KBC24.75 160.29,32.1 160.29,32.09 159.82,32.09 159.46,32.45
  TOP w0.508: 159.46,32.45 157.1,32.45 156.1,31.45 Q2402.S 156.1,30.69 R2431.2 C2417.2 155.08,28.63 v2(154.49,28.04) 154.6,27.93 154.6,26.1 153.81,25.3 R2439.1 ; v2(135.33,103.32) 135.33,103.7 135.05,103.98 135.05,104.01 134.47,104.59 133.68,104.59 132.41,105.86 130.88,105.86 129.36,107.38 126.9,107.38 124.23,110.05 124.23,110.06 123.86,110.43 123.85,110.43 v2(123.59,110.69) ; PR4438.2 138.35,114.1 PR4419.1 138.47,113.86 v2(139.01,113.86) 139.01,114.11 139.11,114.21 139.11,114.22 139.51,114.62 141.53,114.62 142.36,115.46 PR4434.1 ; PR4510.2 136.28,36.9 139.37,36.9 v2(139.39,36.92) 140.18,37.71 v1(140.18,41.8) 140.18,45.53 140.71,46.07 v2(140.71,46.83) ; PR4417.1 145.73,123.82 PR4435.1 145.74,123.58 146.25,123.07 v2(146.25,122.75) ; v2(135.07,74.41) 140,74.41 142.25,76.66 142.25,76.84 142.69,77.28 PR8313.1
  L3 w0.508: v2(125.04,86.81) 127.73,86.81 129.49,88.56 129.49,91.14 130.05,91.69 130.05,98.31 134.47,102.73 134.74,102.73 v2(135.33,103.32) ; v2(140.71,46.83) 140.98,46.83 141.45,47.31 141.45,48.95 140.04,50.36 139.51,50.36 133.55,56.32 133.55,62.3 132.81,63.04 132.81,77.37 133.21,77.77 134.6,77.77 135.07,77.29 v2(135.07,74.41)
  L4 w0.508: v2(125.04,86.81) 126.18,86.81 135.07,77.92 v2(135.07,74.41) ; v2(146.25,122.75) 146.25,123 145.62,123.64 144.47,123.64 141.68,120.85 141.68,119.19 138.38,115.89 138.38,114.99 139.01,114.36 v2(139.01,113.86) 136.73,113.86 135.23,115.36 130.86,115.36 126.18,110.69 v2(123.59,110.69) ; v2(54.38,11.75) 54.38,11.84 56.26,13.72 56.26,14.53 59.45,17.72 62.17,17.72 62.72,18.27 71.39,18.27 75.3,14.37 81.72,14.37 86.85,9.24 102.75,9.24 104.12,10.61 116.85,10.61 117.29,11.05 137.92,11.05 138.75,11.88 140.82,11.88 142.39,13.45 142.39,30.6 139.39,33.6 v2(139.39,36.92) ; v2(166.7,27.12) 166.7,27.22 166.06,27.86 166.06,29.8 166.8,30.53 166.8,31.8 168.09,33.1 168.09,37.66 167.36,38.39 167.36,39.76 167.18,39.95 167.18,42.06 171.92,46.8 v2(172.41,46.8)
  BOTTOM w0.356: RN602.4 124.64,87.37 125.04,86.97 v2(125.04,86.81) 125.17,86.94 125.17,87.83 125.09,87.9 125.06,87.9 124.94,88.02 RN602.3
  BOTTOM w0.508: v2(172.41,46.8) 176.48,46.8 176.86,47.19 PR8341.1 ; R2434.2 166.7,27.11 v2(166.7,27.12) 165.71,26.13 164.27,26.13 164.04,25.9 162.58,25.9 161.55,26.93 R2425.2 157.95,27.47 155.1,27.44 v2(154.49,28.04) 153.64,28.9 149.68,28.9 v1(147.39,31.19) 147.39,31.63 142.09,36.92 v2(139.39,36.92) ; v2(54.38,11.75) 54.94,11.19 54.94,10.28 53.88,9.22 D2501.1
3D3V_CAMERA_S0: length 33
  TOP w0.305: v3(30.93,82.49) 31.14,82.49 31.45,82.8 LCD1.32
  TOP w0.762: R5229.2 v3(31.93,68.6)
  L4 w0.762: v3(31.93,68.6) 31.9,68.63 31.9,81.2 30.93,82.16 v3(30.93,82.49)
  BOTTOM w0.762: v3(14.42,87.19) 14.42,87.06 15.69,85.79 21.92,85.79 ; v3(30.93,82.49) 30.28,81.84 26.66,81.84 C5207.1
3D3V_LAN_S5: length 0.9
  BOTTOM w0.203: LOM30.11 39.06,44.95
  vias: v1(30.12,42.74) v1(35.96,49.34) v3(30.81,37.66) v3(33.47,48.73) v3(41.35,45.28)
3D3V_PWR:
  vias: v1(126.77,12.67) v1(127.12,17.01)
3D3V_PWR_2: length 4.5
  TOP w0.203: PU4501.15 132.67,37.91 133.04,37.91
  TOP w0.508: 133.04,37.91 v1(134.15,37.91) PC4516.1 135.18,36.86 PR4510.1
3D3V_S0: length 624.3
  TOP w0.203: Q2601.5 61.9,84.95 62.26,85.31 62.26,85.5 62.79,86.03 64.08,86.03 64.46,85.65 64.46,85.41 ; 121.46,68.55 126.87,63.13 126.87,62.86 128.28,61.45 R2603.1 128.29,61.02 128.29,60.42 128.57,60.14 128.57,58.84 127.33,57.6 120.85,57.6 118.63,59.82 R2604.1 ; 178.97,24.5 178.57,24.9 KBC24.4
  TOP w0.356: THM26.1 120.22,63.02 119.98,63.25 C2602.1 119.26,63.06 C2601.1
  TOP w0.508: v2(183.97,40.35) 184.38,39.95 R5808.1 ; 55.4,55.59 45.9,55.59 v2(44.98,56.51) ; PR3622.1 138.31,64.08 R3624.1 v2(139.24,63.19) ; v2(40.55,4.76) 40.55,4.83 40.8,5.08 40.81,5.08 41.08,5.35 C2716.1 40.41,5.77 C2717.1 39.96,6.21 39.71,6.32 39.67,6.32 38.66,7.33 38.66,8.09 ; R2401.2 184.01,26.51 R2443.2 184.03,24.77 ; 42.54,40.56 38.96,40.56 38.37,41.15 R3003.1 R3014.1 ; 42.54,40.56 42.54,40.1 43.25,39.39 44.02,39.39 44.83,38.57 45.95,38.57 46.61,37.91 46.61,35.12 ; 42.54,40.56 43.25,41.27 R3004.1 ; v2(115.9,81.86) 116.02,81.73 116.02,81.59 116.55,81.07 119.87,81.07 120.07,80.87 121.06,80.87 121.08,80.84 v2(125.17,80.84) 125.04,80.71 125.04,79.57 125.8,78.81 127.48,78.81 128.09,78.2 128.09,77.13 129.74,75.48 138.76,75.48 139.29,76.01 139.29,77.82 138.81,78.3 v2(138.12,78.3) 137.64,78.78 R6209.1 ; C2601.1 118.18,63.21 118.18,65.27 v1(119.92,67) 121.46,68.55 121.46,75.13 120.78,75.81 v2(120.72,75.81) ; C1023.1 C1022.1 103.9,85.35 v2(103.99,85.26) ; v2(123.59,109.8) 123.59,109.79 124.38,109 124.38,105.07 123.39,104.08 123.39,97.3 v2(123.59,97.1) 123.57,97.07 v2(120.8,97.07) ; v2(21,91.3) 21.71,91.3 21.84,91.43 24.18,91.43 26.01,89.6 33.9,89.6 34.87,88.63 34.87,88 36.52,86.35 v2(36.52,85.46) ; v2(180.49,43.93) 180.67,43.75 C5804.1 179.83,42.81 R2415.2 ; v3(21.92,5.66) 21.92,5.78 19.44,8.26 R2925.1 ; 179.89,24.5 178.97,24.5
  TOP w1.016: 123.39,104.08 120.29,107.19 v1(104.52,107.19) 87,107.19 85.16,105.35 75.38,105.35 73.61,103.57 73.61,100.91 76.88,97.63 v3(76.88,96.46)
  L3 w0.254: 73.35,86.89 73.3,86.94 v2(72.36,86.94)
  L3 w0.508: v2(64.6,84.08) 64.7,84.08 v3(67.1,81.68) ; v2(172.41,19.75) 173.28,18.89 183.61,18.89 v3(184.22,19.5) ; v2(176.1,28.39) 176.32,28.39 176.8,27.91 176.8,27.16 179.38,24.58 v3(183.07,24.58) ; v2(139.24,63.19) 139.24,64.36 138.25,65.35 138.25,70.17 138.76,70.68 138.76,77.8 138.26,78.3 v2(138.12,78.3) ; v2(27.66,20.34) 27.66,18.97 25.22,16.53 25.22,14.04 21.92,10.74 v3(21.92,5.66) 22.55,5.02 26.62,5.02 v3(26.87,5.28)
  L3 w1.016: v3(117.42,35.25) 117.42,10.61 ; v3(76.88,96.46) 75.51,96.46 73.35,94.3 73.35,79.67 72.7,79.02 v3(72.34,79.02)
  L3 w1.524: 165.39,4.55 162.34,4.55 161.74,5.15 154.63,5.15 153.87,4.39 151.36,4.39 149.9,5.85 147.33,5.85 145.23,7.94 142.57,7.94 141.17,9.34 139.14,9.34 137.49,10.99 122.76,10.99
  L4 w0.254: v2(103.99,85.26) 103.48,84.75 103.48,83.91 104,83.38 107.9,83.38 108.25,83.02 113.18,83.02 113.84,82.36 115.39,82.36 v2(115.9,81.86)
  L4 w0.381: v2(115.9,81.86) 115.9,81.81 115.37,81.28 112.08,81.28 v2(111.33,80.54)
  L4 w0.406: v3(72.34,79.02) 76.03,79.02 v2(76.19,79.19)
  L4 w0.508: v2(191.21,109.8) 192.79,109.8 195.63,106.96 195.63,104.56 195.03,103.96 195.03,89.59 195.3,89.32 195.3,84.81 195.15,84.66 195.15,80.86 196.03,79.97 v2(196.03,78.55) ; v2(119.1,129.58) 119.67,129.58 122.37,126.88 122.37,122.01 122.88,121.51 122.88,110.42 123.51,109.8 v2(123.59,109.8) ; v3(35.38,70.3) 36.52,71.44 v2(36.52,85.46) ; v2(21,91.3) v2(16.99,91.3)
  BOTTOM w0.254: R642.1 111.54,79.25 111.12,79.67 111.12,80.25 111.2,80.32 111.2,80.41 v2(111.33,80.54) ; v2(72.36,86.94) 77.73,86.94 R428.2
  BOTTOM w0.305: v2(112.11,32.42) 112.05,32.35 DM1.199
  BOTTOM w0.356: RN6201.4 120.97,97.93 120.8,97.76 v2(120.8,97.07) 121.31,97.07 RN6201.3 ; R603.2 116.6,76.59 117.38,75.81 v2(120.72,75.81) 120.72,75.84 120.82,75.93 RN601.2 121.35,78.11 121.54,78.3 121.54,78.57 121.35,78.76 RN601.1 ; v2(123.59,97.1) Q6202.2
  BOTTOM w0.381: CPU1.AM15 103.6,85.64 v2(103.99,85.26) 103.6,84.87 CPU1.AM17 ; 116.91,130.42 117.5,130.42 118.34,129.58 v2(119.1,129.58) ; 116.91,130.42 116.49,130.84 PR4652.1 ; 116.91,130.42 116.49,130 113.26,130 113.19,130.07 111.06,130.07 PR4651.1 ; Q5402.5 v2(21,91.3) ; v2(176.1,28.39) 176.03,28.33 R2441.2 R2412.2 ; Q5402.2 v2(16.99,91.3) ; R639.2 114.44,83.06 114.03,83.47 112.8,83.47 R636.2
  BOTTOM w0.406: Q403.5 75.89,79.57 76.15,79.32 76.15,79.23 v2(76.19,79.19) ; v3(72.34,79.02) 72.34,79.09 72.82,79.57 Q403.2 ; Q6202.2 Q6202.5
  BOTTOM w0.508: v2(40.55,4.76) 39.78,4 35.96,4 35.24,4.72 32.04,4.72 30.95,3.62 28.52,3.62 v3(26.87,5.28) 27.06,5.47 R2701.1 ; v2(65.86,86.54) 65.86,85.92 64.6,84.66 v2(64.6,84.08) ; DB1.1 166.65,14.95 167.29,14.95 167.31,14.98 172.36,14.98 174.19,13.15 179.65,13.15 ; R637.2 115.77,78.01 115.71,77.94 R604.2 ; v2(191.21,109.8) 188.35,109.8 PR8352.2 187.46,110.24 187.14,110.56 187.14,112.02 PC8324.1 186.35,112.15 PQ8320.S 185.56,110.56 PR8351.1 ; R603.2 R635.2 ; R635.2 R604.2 ; R635.2 116.66,77.6 116.66,80.27 C1024.1 ; C1024.1 115.96,80.65 115.39,80.08 R638.2 ; C1024.1 115.96,81.18 115.9,81.25 v2(115.9,81.86) 115.9,82.24 115.42,82.72 114.9,82.72 114.75,82.87 R639.2 ; R604.2 R601.2 ; R2624.1 171.46,20.2 171.9,19.75 v2(172.41,19.75) ; v2(36.52,85.46) 36.4,85.59 R5208.1 ; Q5401.C 44.98,55.72 v2(44.98,56.51) ; v2(120.8,97.07) 120.8,96.64 124.28,93.16 126.32,93.16 127.61,91.87 127.61,89.2 127.47,89.06 127.47,83.14 v2(125.17,80.84)
  BOTTOM w1.016: 55.68,70.05 67.1,81.46 v3(67.1,81.68)
  vias: v1(48.82,71.7) v1(56.39,62.27) v1(56.49,54.73) v1(66.65,82.59) v1(114.37,35.22) v1(120.22,6.88) v1(185.57,69.26) v3(35.99,69.51) v3(45.79,33.47) v3(45.79,32.58) v3(48.99,69.98) v3(49.6,70.65) v3(55.57,62.81) v3(55.57,61.92) v3(119,9.85) v3(119.23,9.03) v3(119.89,9.85) v3(120.14,9.03) v3(120.81,9.85) v3(121.05,9.03) v3(167.46,3.5) v3(168.35,3.5) v3(179.91,9.09) v3(183.59,14.8) v3(184.6,14.8)
3D3V_S5: length 617.9
  TOP w0.305: RN1904.4 119.78,88.91 119.58,88.71 119.23,88.71 119.13,88.61 ; 119.13,88.61 RN1904.3 ; 119.13,88.61 v2(118.31,87.79)
  TOP w0.508: v2(103.02,86.99) 103.07,86.94 C1001.1 ; v3(155.26,37.28) 153.36,39.17 153.36,41.72 159.43,47.79 164,47.79 164.66,48.46 164.67,48.46 167.97,51.76 167.97,57.98 167.99,57.98 v3(169.24,59.22) ; v3(12.14,76.27) 11.57,75.7 C6402.1 11.12,75.51 10.41,74.79 3.13,74.79 2.95,74.62 LIDSW1.2 ; PR4509.1 125.91,42.07 125.91,45.63 126.95,46.68 129.87,46.68 130.76,47.57 137.11,47.57 v2(137.79,48.25) ; PR4904.1 108.91,10.93 v2(108.91,7.62) ; R5610.2 v2(196.04,77.58) ; R1929.2 109.54,81.86 110.11,81.86 110.14,81.89 v2(110.18,81.86) 110.18,81.98 110.92,82.72 113.74,82.72 113.92,82.54 115.11,82.54 115.23,82.66 116.76,82.66 117.43,81.98 v2(117.43,81.81) ; PR4835.1 171.51,70.88 v2(172.1,70.3) 172.1,70.24 169.24,67.38 v3(169.24,60.39)
  L3 w0.381: 42.75,28.77 41.9,28.77 41.85,28.72 v2(41.83,28.72)
  L3 w0.508: v2(137.87,104.26) 137.54,104.59 131.01,104.59 126.18,99.76 126.18,97.39 122.88,94.09 122.88,92.27 118.41,87.79 v2(118.31,87.79) 118.31,88.07 116.78,89.6 v2(113.99,89.6) ; v3(169.24,60.39) 166.63,63 161.25,63 161.11,62.86 v2(159.97,62.86) ; v2(143.2,93.29) 142.76,92.84 142.76,80.57 142.31,80.13 142.31,79.57 141.3,78.56 141.3,56.2 146.94,50.56 146.94,48.12 155.26,39.81 v3(155.26,37.28) ; v2(172.1,70.3) 176.98,70.3 180.67,73.98 187.53,73.98 v2(187.7,73.8) ; v2(137.79,48.25) 137.79,47.36 138.54,46.61 139.03,46.61 141.22,44.42 141.22,43.27 v2(146.78,37.71) ; v2(118.69,103.19) 118.69,103.33 124.66,109.3 124.66,117.54 121.23,120.97 121.23,139.04 v2(121.96,139.77)
  L3 w1.016: 122.44,7.62 v2(108.91,7.62) 89.42,7.62 84.86,12.18 74.21,12.18 67.78,18.61 49.71,18.61 42.75,25.57 42.75,33.2 45.97,36.43 45.97,44.95 v3(49.22,48.2)
  L4 w0.254: v2(103.02,86.99) 103.02,86 102.64,85.62 102.64,84.07 103.71,83 107.13,83 107.54,82.59
  L4 w0.381: v2(110.18,81.86) 108.28,81.86 107.54,82.59
  L4 w0.508: v3(155.26,37.28) 155.45,37.09 v2(155.45,33.98) ; v3(144.41,11.93) 144.43,11.91 v3(145.27,11.91) 147.67,14.32 149.26,14.32 150.44,15.5 150.44,17.47 149.31,18.61 148.96,18.61 148.67,18.9 148.04,18.9 146.78,20.16 v2(146.78,35.23) v2(146.78,37.71) ; v2(120.6,146.75) 118.06,149.29 114.63,149.29 111.45,152.47 v2(111.07,152.47) ; v2(137.87,104.26) 138.46,103.66 138.46,98.08 143.2,93.34 v2(143.2,93.29)
  BOTTOM w0.356: CPU1.AL13 102.6,86.57 v2(103.02,86.99) 103.06,86.95 CPU1.AM13
  BOTTOM w0.508: 116.91,95.83 117.29,95.45 119.55,95.45 123.36,91.64 125.69,91.64 126.08,91.24 126.08,90.31 125.95,90.18 125.95,86.82 124.42,85.29 120.7,85.29 ; R608.2 R630.2 113.42,89.6 v2(113.99,89.6) 114.06,89.54 R1927.2 ; v2(187.7,73.8) 191.91,73.8 192.09,73.98 193.77,73.98 195.3,75.51 195.3,77.18 195.69,77.58 v2(196.04,77.58) ; R2501.2 146.76,37.74 v2(146.78,37.71) ; R1913.1 112.07,103.17 112.1,103.17 112.12,103.19 v2(118.69,103.19) 118.69,101.92 116.85,100.08 C1002.1 ; PR4211.2 v2(111.07,152.47) ; v2(117.43,81.81) 117.56,81.68 119.61,81.68 119.99,82.06 119.99,82.48 ; R2421.2 165.55,32.2 164.6,31.25 R2429.2 163.46,31.25 161.14,33.57 159.3,33.57 158.48,32.75 155.82,32.75 155.45,33.12 v2(155.45,33.98) ; PR5011.1 159.59,65.03 159.31,64.75 159.31,63.25 159.7,62.86 v2(159.97,62.86) ; PR4204.1 118.5,144.05 119.3,144.85 PR4473.2 120.53,146.69 v2(120.6,146.75) 122.81,144.54 122.81,140.62 v2(121.96,139.77) ; 151.74,35.23 v2(146.78,35.23) ; v3(12.14,76.27) 13.41,76.27 14.15,75.53 v1(21.31,75.53) 23.67,75.53 30.05,69.16 30.05,65.73 37.03,58.74 37.03,58.65 38.44,57.24 41.21,57.24 43.25,55.2 43.25,53.66 44.14,52.77 v2(44.14,49.09) 44.14,43.26 40.76,39.88 40.14,39.88 39.57,39.32 39.57,37.01 38.82,36.26 36.68,36.26 35.94,37.01 R3033.2
  vias: v1(47.11,48.79) v1(123.49,10.94) v1(127.35,10.84) v3(122.29,9.03) v3(123.18,9.03) v3(124.07,9.03) v3(124.96,9.03) v3(125.8,9.05)
3D3V_VGA_OUT1:
  vias: v1(141.17,104.77)
3D3V_VGA_S0: length 71.2
  TOP w0.381: U8201.5 152.74,79.81 151.65,80.9 PR8246.1 151.71,81.41 v2(151.71,83.13) 151.71,83.32 PR8250.1
  TOP w0.508: 141.3,92.91 140.92,92.52 v1(140.92,92.02) 140.92,90.68 141.3,90.3 ; 141.3,92.91 141.3,95.6 v3(142.54,96.84) ; 141.3,92.91 142.31,92.91 142.76,92.46 PR8237.1 ; PR8248.1 v2(143.71,81.6) ; PR8251.1 PR8252.1 PR8253.1 142.63,90.24 PR8254.1 142,90.37 PC8217.1 141.3,90.3 ; 141.3,90.3 139.77,88.78 139.77,88.13 v2(139.75,88.1)
  L3 w0.508: v3(142.54,96.84) 143.91,98.21 149.53,98.21 151.71,100.4 151.71,102.43 152.47,103.19 161.24,103.19 v2(160.91,101.11)
  BOTTOM w0.406: 182.73,113.12 181.46,113.12 181.05,112.72 Q7503.2 Q7503.5
  BOTTOM w0.508: v2(151.71,83.13) v1(146.12,83.13) 145.23,83.13 143.96,81.87 143.96,81.86 v2(143.71,81.6) 143.71,81.87 141.94,83.63 139.52,83.63 139.01,84.14 139.01,87.83 139.29,88.1 v2(139.75,88.1)
  vias: v2(173.94,119.6) v2(174.06,118.95) v2(181.94,117.29) v2(182.57,117.29) v2(183.21,117.29)
32K_X1: length 10
  BOTTOM w0.14: CPU1.AJ2 102,93.4 101.74,93.65 arc(101.69,93.73) 101.67,93.82 101.67,94.4 101.85,94.58 101.85,96.07 101.56,96.36 v1(101.56,96.46) 101.55,96.48 101.55,99.43 R623.1 101.61,100.05 C603.1 101.61,102.27 X601.4
32K_X2: length 10.5
  BOTTOM w0.14: X601.1 102.34,103.37 102.64,103.07 102.64,100.99 C604.1 102.5,99.8 R623.2 102.04,99.16 v1(102.04,98.57) 102.04,96.51 102.09,96.46 102.09,93.94 CPU1.AJ1
48M_X1: length 8.2
  BOTTOM w0.14: X1902.3 94.37,99.23 C1904.2 R1905.1 93.16,96.02 93.16,94.51 93.52,94.16 93.52,93.79 arc(93.51,93.72) 93.47,93.66 93.2,93.4 CPU1.N2
48M_X2: length 9.2
  BOTTOM w0.14: CPU1.N1 92.91,94.14 92.91,96.65 R1905.2 C1905.2 93.48,98.56 92.21,99.83 92.21,100.56 X1902.1
8179A_EN/DEM_VGA: length 12.6
  TOP w0.127: PQ8305.2 146.89,78.3 147.47,77.72 v1(148.59,77.72) 149.86,77.72 150.73,78.59 150.73,79.48 PD8201.A 150.76,79.63 PR8246.2 PC8213.1 PC8219.1 150.06,83.82 PU8202.29
51123_PGOOD_2: length 6.2
  BOTTOM w0.102: Q601.5 125.04,90.24 125.17,90.11 125.17,89.73 125.03,89.59 Q601.6 124.46,88.89 123.77,88.21 123.77,87.57 123.57,87.37 RN602.1 v1(121.92,87.37)
+0D675V_DDR_P: length 0.7
  TOP w0.203: PU4901.3 107.49,14.55
  vias: v1(108.96,12.26)
+DC_IN: length 4.7
  TOP w0.254: PQ4205.E 107.77,143.71 105.23,143.71 AFTP3805.1
  vias: v1(95.15,150.94) v1(101.17,145.89) v3(94.43,153.36) v3(94.43,152.47) v3(95.32,153.36) v3(95.32,152.47) v3(96.21,153.36) v3(96.21,152.47) v3(98.75,147.13) v3(98.8,146.25) v3(99.64,147.13) v3(99.64,146.25) v3(100.53,147.13) v3(100.53,146.25)
+PWR_SRC_1D35V:
  vias: v1(97,13.53) v1(100.53,12.9) v3(96.09,12.39) v3(96.97,12.39) v3(97.86,12.39) v3(98.75,12.39)
+RTC_VCC: length 14.8
  TOP w0.508: v2(52.86,5.05) 51.24,6.66 AFTP2502.1 46.25,7.95 RTC1.1
  BOTTOM w0.508: v2(52.86,5.05) 52.3,5.61 R2502.2
A_BA0: length 59.8
  TOP w0.14: v2(160.09,145.28) 160.09,144.19 159.81,143.91 159.81,143.21 VRAM1.M2 ; VRAM3.M2 176.38,147.58 176.07,147.58 175.77,147.27 175.77,147.11 175.94,146.93 175.94,146.75 175.97,146.72 175.97,145.57 175.83,145.43 v2(175.66,145.43)
  TOP w0.178: 166.16,130.95 166.16,128.29 166.57,127.88 166.57,127.58 166.39,127.4 v1(166.19,127.4) 165.68,127.4 165.5,127.22 165.5,126.84 165.78,126.56 165.98,126.56 166.16,126.38 166.16,125.85 166.77,125.24 166.77,123.59 166.5,123.31 166.48,123.31 v2(166.3,123.14)
  TOP w0.279: 166.16,130.95 166.47,131.26 166.47,132.26 165.66,133.08 165.66,133.99 166.25,134.59 167.97,134.59 168.25,134.87 168.25,135.18 168.09,135.34 168.09,136.26 168.53,136.7 v2(168.53,137.66)
  L3 w0.127: v2(175.66,145.43) 175.37,145.14 175.37,144.62 175.46,144.53 175.46,143.83 174.33,142.7 174.33,140.44 173.68,139.79 173.37,139.79 173.24,139.92 173.09,140.07 172.91,140.07 172.71,139.86 172.71,139.68 172.95,139.44 172.97,139.41 172.97,139.06 172.47,138.56 172.14,138.56 171.98,138.72 171.74,138.72 171,137.98 170.48,137.98 170.36,138.1 169.87,138.1 169.75,137.98 169.29,137.98 169.16,138.1 168.66,138.1 168.53,137.98 v2(168.53,137.66) 168.02,137.66 167.69,137.99 162.99,137.99 160.81,140.18 160.81,141.88 160.63,142.05 160.63,142.79 160.32,143.1 160.32,144.14 160.09,144.37 v2(160.09,145.28)
  BOTTOM w0.14: v2(175.66,145.43) 175.34,145.11 175.34,144.64 176,143.98 176,143.18 VRAM4.M2 ; VRAM2.M2 159.6,147.59 159.83,147.36 159.83,145.55 v2(160.09,145.28)
  BOTTOM w0.279: GPU1.J16 166.2,123.24 v2(166.3,123.14)
A_BA1: length 59.4
  TOP w0.14: v2(174.57,145.43) 174.57,145.22 174.29,144.95 174.29,144.6 175.14,143.75 175.14,143.24 VRAM3.N8 ; VRAM1.N8 160.19,147.32 160.56,146.95 160.56,146.65 161.11,146.1 161.11,145.25 v2(161.19,145.17)
  TOP w0.178: v2(165.98,121.94) 165.66,122.27 165.66,122.65 165.81,122.8 165.81,123.44 165.66,123.59 165.66,124.35
  TOP w0.279: v2(168.51,139.43) 168.49,139.42 168.49,138.36 167.79,137.66 167.79,137.15 167.79,136.77 167.79,136.77 167.79,136.6 167.64,136.45 167.64,135.35 167.36,135.07 166.09,135.07 164.58,133.57 164.58,132.89 164.82,132.66 165.38,132.66 165.66,132.38 165.66,131.97 165.15,131.46 165.15,129.19 165.02,129.05 165.02,128.43 165.36,128.09 165.36,127.63 165.02,127.29 v1(165.02,126.71) 165.02,125.98 165.66,125.34 165.66,124.35
  L3 w0.127: v2(174.57,145.43) 174.57,145.21 174.3,144.95 174.3,144.2 172.74,142.65 172.74,142.15 170.74,140.14 170.74,139.55 170.55,139.36 170.36,139.36 170.23,139.49 170.23,139.92 170.1,140.05 169.85,140.05 169.72,139.92 169.72,139.23 169.59,139.11 169.34,139.11 169.21,139.23 169.21,139.95 169.11,140.05 168.61,140.05 168.51,139.95 v2(168.51,139.43) 167.33,139.43 167,139.1 163.28,139.1 161.81,140.58 161.81,141.74 162.14,142.07 162.14,142.8 161.31,143.63 161.31,145.05 v2(161.19,145.17)
  BOTTOM w0.14: VRAM2.N8 160.61,143.21 160.61,143.81 161.19,144.4 v2(161.19,145.17) ; v2(174.57,145.43) 174.89,145.43 175.03,145.57 175.03,145.89 175.03,145.89 175.03,146.19 175.23,146.4 175.23,146.9 175.03,147.11 175.03,147.34 175.26,147.57 175.37,147.57 175.4,147.59 VRAM4.N8
  BOTTOM w0.279: GPU1.L15 166.19,121.94 v2(165.98,121.94)
A_BA2: length 61.6
  TOP w0.14: VRAM3.M3 176.21,146.61 176.21,145.96 176.35,145.82 v2(176.6,145.82) ; VRAM1.M3 159.23,143.75 159.23,144.7 159.41,144.88 159.41,145.66 v2(159.26,145.81)
  TOP w0.279: v2(169.86,125.21) 169.86,125.39 169.95,125.49 169.95,126.4 171.29,127.74 171.29,128.95 171.46,129.13 171.46,129.79 171.54,129.86 171.54,130.87 171.46,130.94 171.46,132 172.51,133.05 172.51,137.76 172.24,138.04 171.22,138.04 170.94,137.76 v2(170.94,137.2)
  L3 w0.127: v2(176.6,145.82) 176.23,145.82 176.08,145.67 176.08,145.12 176.3,144.9 176.3,143.5 175.71,142.92 175.71,141.21 175.59,141.08 175.11,141.08 174.99,140.97 174.99,140.67 175.11,140.56 175.56,140.56 175.69,140.43 175.69,140.15 175.56,140.02 174.87,140.02 173.76,138.91 173.76,137 173.63,136.87 173.38,136.87 173.25,137 173.25,137.94 173.12,138.07 172.92,138.07 172.74,137.89 172.74,137 172.62,136.87 172.36,136.87 172.24,137 172.24,137.79 172.12,137.9 171.86,137.9 171.68,137.72 171.68,137.02 171.55,136.9 171.25,136.9 v2(170.94,137.2) 170.63,136.89 163.16,136.89 159.71,140.34 159.71,141.85 159.81,141.95 159.81,142.64 159.1,143.35 159.1,144.06 159.25,144.21 159.25,145.81 v2(159.26,145.81)
  BOTTOM w0.14: v2(159.26,145.81) 159.45,145.81 159.59,145.95 159.59,146.59 VRAM2.M3 ; VRAM4.M3 176.39,144.71 176.33,144.77 176.33,145.55 v2(176.6,145.82)
  BOTTOM w0.279: GPU1.G11 169.66,125.21 v2(169.86,125.21)
AC_IN#: length 161.6
  TOP w0.102: v2(132.89,117.29) 132.89,116.12 132.71,115.94 PQ4408.5 ; v2(141.17,115.38) 141.6,115.82 141.6,116.37 141.97,116.74 PR4434.2 ; v2(157.81,34.87) 157.35,34.41 R2413.1 158.16,34.27 R2430.1 ; PU4404.5 141,120 141.84,119.16 PR4433.1 141.84,118.01 PC4401.1 142.36,117.49 PR4434.2 ; PR4425.2 PR4434.2
  L3 w0.102: v2(132.89,117.29) 133.27,116.91 138.27,116.91 139.8,115.38 v2(141.17,115.38)
  L4 w0.102: v2(141.17,115.38) 145.95,115.38 146.53,115.97 148.76,115.97 149.81,114.91 149.81,110.47 153.79,106.49 159.97,106.49 161.06,105.4 165.02,105.4 165.2,105.22 174.38,105.22 175.12,104.49 184.21,104.49 186.21,102.49 186.21,78.29 188.54,75.96 188.54,71.35 186.48,69.28 185.28,69.28 181.84,65.84 181.84,51.17 179.96,49.29 178.71,49.29 v2(177.62,48.2)
  BOTTOM w0.102: v2(177.62,48.2) 177.62,47.34 176.58,46.3 167.84,46.3 166.82,45.28 166.44,45.28 164.41,43.25 164.41,41.6 163.42,40.61 163.42,40.48 v1(159.9,36.96) v2(157.81,34.87)
AC_IN#_G: length 5
  BOTTOM w0.127: PQ4206.2 106.25,148.66 v1(105.17,147.58) PR4213.1 PR4212.2
AC_IN_KBC#: length 254.9
  TOP w0.102: v2(166.32,47.82) 165.63,47.13 165.63,46.87 v1(165.57,46.81) 164.59,45.82 164.59,41.91 161.1,38.42 R2426.1 160.89,37.69 160.89,36.61 161.4,36.1 KBC24.65
  L3 w0.102: v2(166.32,47.82) 166.44,47.95 170.46,47.95 171.79,49.28 175.9,49.28 177.92,47.26 180.38,47.26 182.11,45.53 189.6,45.53 v2(190.44,44.69)
  L4 w0.102: v2(107.77,151.78) 108.23,151.78 111.4,154.96 112.52,154.96 113.32,155.76 117.3,155.76 120.22,152.85 137.89,152.85 138.43,152.32 144.93,152.32 148,155.39 162.15,155.39 166.14,151.4 169.07,151.4 173.34,155.67 187.75,155.67 189.62,153.8 189.62,150.69 191.36,148.95 191.36,144.21 200.12,135.45 200.12,110.26 197.58,107.72 197.58,99.67 196.65,98.74 196.65,94.64 197.04,94.25 197.04,85.45 198.51,83.97 198.51,80.65 199.31,79.85 199.31,71.63 189.25,61.58 189.25,50.64 189.43,50.46 189.43,45.7 v2(190.44,44.69)
  BOTTOM w0.102: v2(107.77,151.78) 107.56,151.78 PQ4206.6
AC_PRESENT: length 100.1
  TOP w0.102: KBC24.84 160.24,28.5 v2(160.11,28.63)
  L3 w0.102: v2(118.44,84.02) 124.84,84.02 130.6,78.25 130.6,66.78 131.34,66.04 131.34,56.71 133.86,54.2 133.9,54.2 135.23,52.87 135.23,52.82 138.46,49.59 138.46,47.3 138.72,47.04 139.21,47.04 147.39,38.86 147.39,36.74 148.31,35.82 148.31,32.87 149.2,31.98 149.2,30.57 v2(149.27,30.5)
  L4 w0.102: v2(118.44,84.02) 117.26,85.2 108.82,85.2 108.15,85.87 105.94,85.87 v2(105.4,86.4)
  BOTTOM w0.102: R617.1 118.69,84.27 v2(118.44,84.02) ; v2(160.11,28.63) 155.16,28.63 154.38,29.41 150.37,29.41 v1(149.87,29.9) v2(149.27,30.5) ; CPU1.AP15 104.95,86.4 v2(105.4,86.4)
AD+: length 114.5
  TOP w0.508: PR4408.1 v1(131.01,119.7) v3(129.74,119.7) ; PR4407.1 v2(145.74,119.24)
  L4 w0.508: v2(117.04,147.77) 114.88,147.77 112.98,149.67 110.56,149.67 108.84,147.95 105.18,147.95 103.45,149.67 91.39,149.67 v3(87.7,153.36)
  BOTTOM w0.381: PR4469.1 116.91,140.97 PR4405.1 116.85,143.13 115.9,144.09 115.9,146.63 v2(117.04,147.77) ; 120.72,147.77 120.72,149.43 121.35,150.06 124.91,150.06 126.05,148.92 PU4403.4
  BOTTOM w0.508: v2(145.74,119.24) 145.74,116.23 144.62,115.1 143.94,115.1 142,113.16 135.31,113.16 v1(133.14,115.33) 131.44,117.03 131.44,118.14 129.88,119.7 v3(129.74,119.7) 129.18,119.7 128.48,119 127.95,119 124.53,122.42 124.53,137.18 123.58,138.13 123.58,144.91 120.72,147.77 v2(117.04,147.77)
AD+_G_1: length 4
  BOTTOM w0.102: PQ4402.5 92.28,144.53 ; 92.28,144.53 92.66,144.15 PR4401.1 93.5,144.02 v1(93.59,143.93) ; 92.28,144.53 91.83,144.53 91.63,144.74 PQ4402.6
AD+_G_2: length 11.3
  TOP w0.254: v2(86.56,143.89) 87.26,143.2 v2(93.42,143.2)
  BOTTOM w0.254: PR4403.2 PR4401.2 92.66,142.66 92.91,142.4 v1(93.31,142.4) 93.41,142.5 93.42,142.54 v2(93.42,143.2) ; v2(86.56,143.89) 86.61,143.85 PU4402.4
AD+_TO_SYS:
  vias: v1(90.86,143.5)
AD_IA: length 160.3
  TOP w0.203: v2(163.4,20.92) 163.4,21.11 163.69,21.4 KBC24.97
  TOP w0.254: C2414.2 163.33,20.86 v2(163.4,20.92) ; v2(177.57,45.79) 177.57,45.15 v1(177.54,45.13) ; PR4422.2 v2(145.74,120.13)
  L3 w0.254: v2(177.57,45.79) 168.25,45.79 167.51,46.52 165.95,46.52 165.52,46.1 v2(165.52,46.02)
  L4 w0.254: v2(163.4,20.92) 163.4,22.74 162.78,23.35 162.78,23.77 163.29,24.29 163.29,25.11 162.71,25.69 162.71,32.65 166.27,36.2 166.27,37.99 165.69,38.57 164.66,38.57 164.26,38.97 164.26,40.11 165.28,41.12 165.28,45.77 v2(165.52,46.02) ; v2(177.57,45.79) 177.57,46.05 178.62,47.1 179.24,47.72 179.89,47.72 182.9,50.73 182.9,65.4 185.72,68.22 186.93,68.22 189.61,70.9 189.61,76.4 187.3,78.72 187.3,83.6 188.39,84.69 188.39,101.82 184.65,105.55 177.32,105.55 175.24,107.64 156.35,107.64 154.48,109.51 154.48,109.79 153.99,110.28 153.98,110.28 150.88,113.38 150.88,115.35 146.1,120.13 v2(145.74,120.13)
AD_IA_HW: length 149.1
  TOP w0.203: 167.08,23.64 166.89,23.45 KBC24.105
  TOP w0.254: 167.08,23.64 167.08,23.94 167.54,24.4 167.54,25.25 167.83,25.54 168.51,25.54 169.11,26.15 169.11,28.01 168.98,28.14 v2(168.98,30.23)
  L4 w0.254: v2(168.98,30.23) 168.98,31.65 170.25,32.92 170.25,35.21 171.27,36.22 171.27,36.5 172.18,37.41 174.03,37.41 175.06,38.45 175.36,38.74 175.36,39.7 175.11,39.95 174.93,40.13 174.93,44.48 179.28,48.84 179.93,48.84 182.14,51.05 182.14,65.71 185.41,68.98 186.6,68.98 188.85,71.22 188.85,76.09 186.52,78.42 186.52,102.61 184.34,104.79 176.65,104.79 174.65,106.8 153.91,106.8 150.12,110.59 150.12,115.04 148.88,116.27 144.9,116.27 144.65,116.02 v2(141.17,116.02)
  BOTTOM w0.254: v1(168.4,29.91) 168.72,30.23 v2(168.98,30.23) ; v2(141.17,116.02) 141.55,116.4 PQ4407.5
AD_IA_HW2: length 132.6
  TOP w0.203: v2(175.46,34.49) 175.46,34.36 176.52,33.3 KBC24.25
  L4 w0.254: v2(175.46,34.49) 178,37.03 178,39.55 177.95,39.6 177.95,40.8 178,40.85 178,42.65 177.06,43.59 177.06,46.08 178.24,47.26 179.08,48.1 179.4,48.1 179.73,48.1 182.52,50.89 182.52,65.55 185.57,68.6 186.77,68.6 189.23,71.06 189.23,76.25 186.92,78.56 186.92,83.76 188.01,84.85 188.01,101.66 184.5,105.17 177.08,105.17 175.06,107.19 156.3,107.19 154.12,109.36 154.12,109.64 153.84,109.92 153.8,109.92 150.5,113.22 150.5,115.2 148.03,117.67 v2(144.98,117.67)
  BOTTOM w0.254: v2(144.98,117.67) 144.98,116.65 144.73,116.4 PQ4407.2 ; v2(175.46,34.49) v1(174.83,34.49)
AD_OFF_L: length 7.3
  TOP w0.254: v1(109.57,142.31) 109.05,142.83 PQ4205.B 109.93,144.57 109.93,145.61 109.55,145.99 108.65,145.99 PQ4204.C
AD_OFF_R: length 23.2
  TOP w0.254: PQ4205.C 106.37,144.34 v2(105.36,145.36)
  BOTTOM w0.254: PU4201.4 92.87,151.62 93.77,150.72 93.77,148.68 94.51,147.95 PC4201.2 94.94,147.41 94.69,147.16 PR4208.1 PC4208.1 96.09,147.74 PR4207.2 97.1,147.74 97.1,146.12 98.09,145.13 v1(102.82,145.13) 103.05,145.36 v2(105.36,145.36)
ALERT#: length 3.4
  TOP w0.102: THM26.6 126.7,61.72 R2603.2 127.63,60.79 v1(127.63,60.06)
ALL_SYS_PWRGD: length 72
  TOP w0.127: KBC24.10 176.68,27.3 175.84,26.46 v2(174.78,26.46) ; v2(138.88,67.89) v1(137.94,66.94) 137.36,66.36 R3604.2
  L3 w0.127: v2(174.78,26.46) 174.23,25.91 164.75,25.91 164.69,25.85 164.05,25.85 164.03,25.84 163.27,25.84 163.25,25.85 159.43,25.85 154.7,30.59 154.7,32.79 154.58,32.91 154.58,36.82 154.46,36.95 154.46,37.61 152.14,39.92 152.14,41.59 146.14,47.59 146.14,49.87 140.03,55.98 140.03,66.74 v2(138.88,67.89)
AMBER_LED_BAT: length 5.3
  TOP w0.102: Q6104.3 174.89,17.05 176.82,17.05 v1(177.18,16.69) 177.18,16.71 177.52,17.05 EC6105.1 178.8,17.04 R6103.2
AMP_MUTE#: length 191
  TOP w0.102: v2(187.81,33.46) 188.22,33.46 188.84,34.08 188.84,36.41 185.78,39.46 v1(183.21,39.46) 182.73,39.46 180.46,37.2 180.46,36.8 178.97,35.3 KBC24.30 ; v2(44.96,9.29) 44.96,8.45 43,6.49 43,5.15 42.54,4.69 R2708.1
  L3 w0.102: v2(59.48,8.31) 59.47,8.3 67.03,8.3 69.35,5.99 75.7,5.99 80.17,1.52 129.11,1.52 129.19,1.59 146.55,1.59 146.77,1.81 162.85,1.81 v2(164.41,3.37)
  L4 w0.102: v2(59.48,8.31) 59.07,7.89 46.35,7.89 v2(44.96,9.29) ; v2(187.81,33.46) 187.58,33.23 187.58,24.6 183.66,20.68 183.09,20.68 181.3,18.9 181.3,14.8 171.07,4.56 165.61,4.56 v2(164.41,3.37)
APU_ALERT#: length 23.4
  TOP w0.127: RN405.8 68.58,83.06 68.58,83.53 68.55,83.55 v2(68.55,83.63) 68.55,83.64 68.55,83.94 68.58,83.97 68.58,84.32 v1(68.81,84.55)
  L4 w0.127: v2(84,84.28) 79.46,84.28 78.06,82.88 75.25,82.88 73.81,84.33 68.69,84.33 68.55,84.19 v2(68.55,83.63)
  BOTTOM w0.127: CPU1.B18 87.1,84.2 86.78,83.88 86.52,83.88 86.44,83.97 86,83.97 85.64,83.6 84.68,83.6 v2(84,84.28)
APU_DBRDY: length 30.8
  TOP w0.127: HDT1.14 v2(64.34,68.9)
  BOTTOM w0.127: CPU1.B25 86.75,80.35 86.42,80.02 83.94,80.02 82.65,78.73 82.18,78.73 81.97,78.52 78.47,78.52 78.32,78.36 77.1,78.36 76.14,77.41 75.22,77.41 74.1,76.29 74.1,76.25 v1(73.23,75.37) 73.22,75.37 72.46,74.62 68.72,74.62 64.34,70.24 v2(64.34,68.9)
APU_DBREQ#: length 32.4
  TOP w0.127: HDT1.16 v2(64.34,67.63)
  BOTTOM w0.127: CPU1.A25 83.87,80.35 82.53,79.01 82.07,79.01 81.85,78.8 78.89,78.8 R434.2 77.7,78.64 76.98,78.64 76.13,77.79 75,77.79 v1(74.75,77.54) 73.67,76.46 73.67,76.34 72.22,74.9 68.6,74.9 63.89,70.19 63.89,68.08 v2(64.34,67.63)
APU_DIGON: length 6.6
  BOTTOM w0.127: R404.1 80,84.5 v1(81.05,84.5) 83.58,84.5 83.83,84.75 CPU1.A17
APU_LPC_AD0: length 9.4
  BOTTOM w0.102: CPU1.AT2 105.85,93.07 106.15,93.37 106.15,93.67 106.07,93.75 106.07,94.14 105.97,94.24 105.97,94.63 106.67,95.34 107.74,95.34 110.39,97.99 110.39,98.25 110.64,98.5 111,98.5 111.02,98.48 RN1901.5
APU_LPC_AD1: length 9.2
  BOTTOM w0.102: RN1901.6 110.59,99.13 v1(110.39,98.92) 110.05,98.59 110.05,98.14 107.62,95.71 106.76,95.71 105.77,94.72 105.77,94.13 105.85,94.04 CPU1.AT1
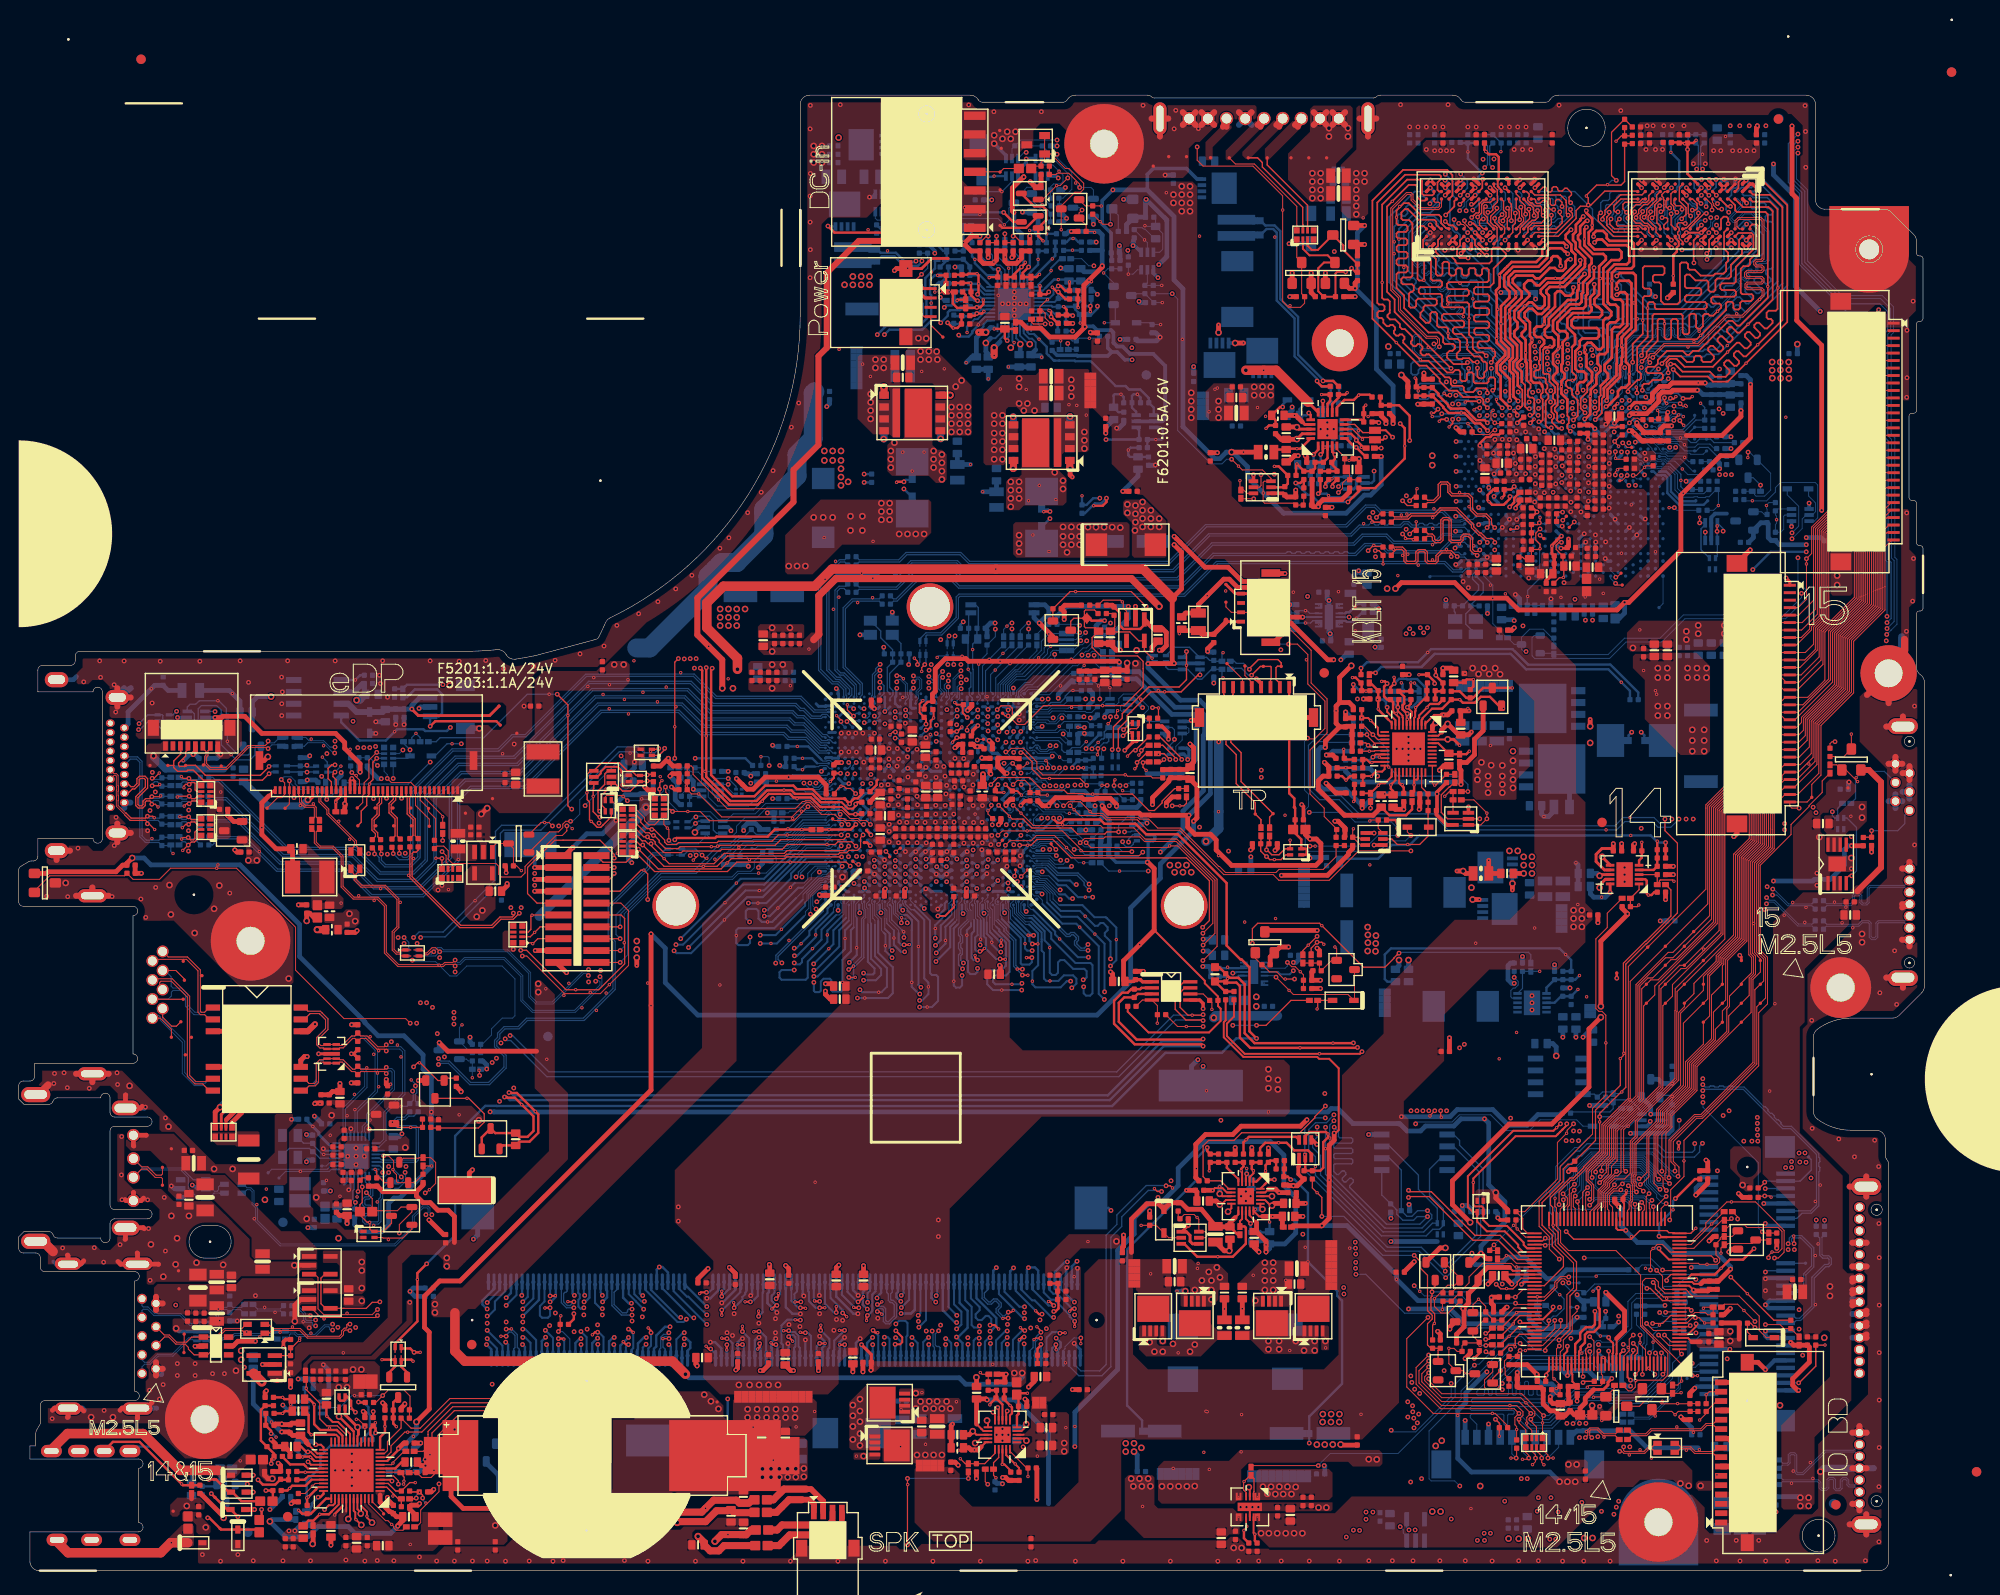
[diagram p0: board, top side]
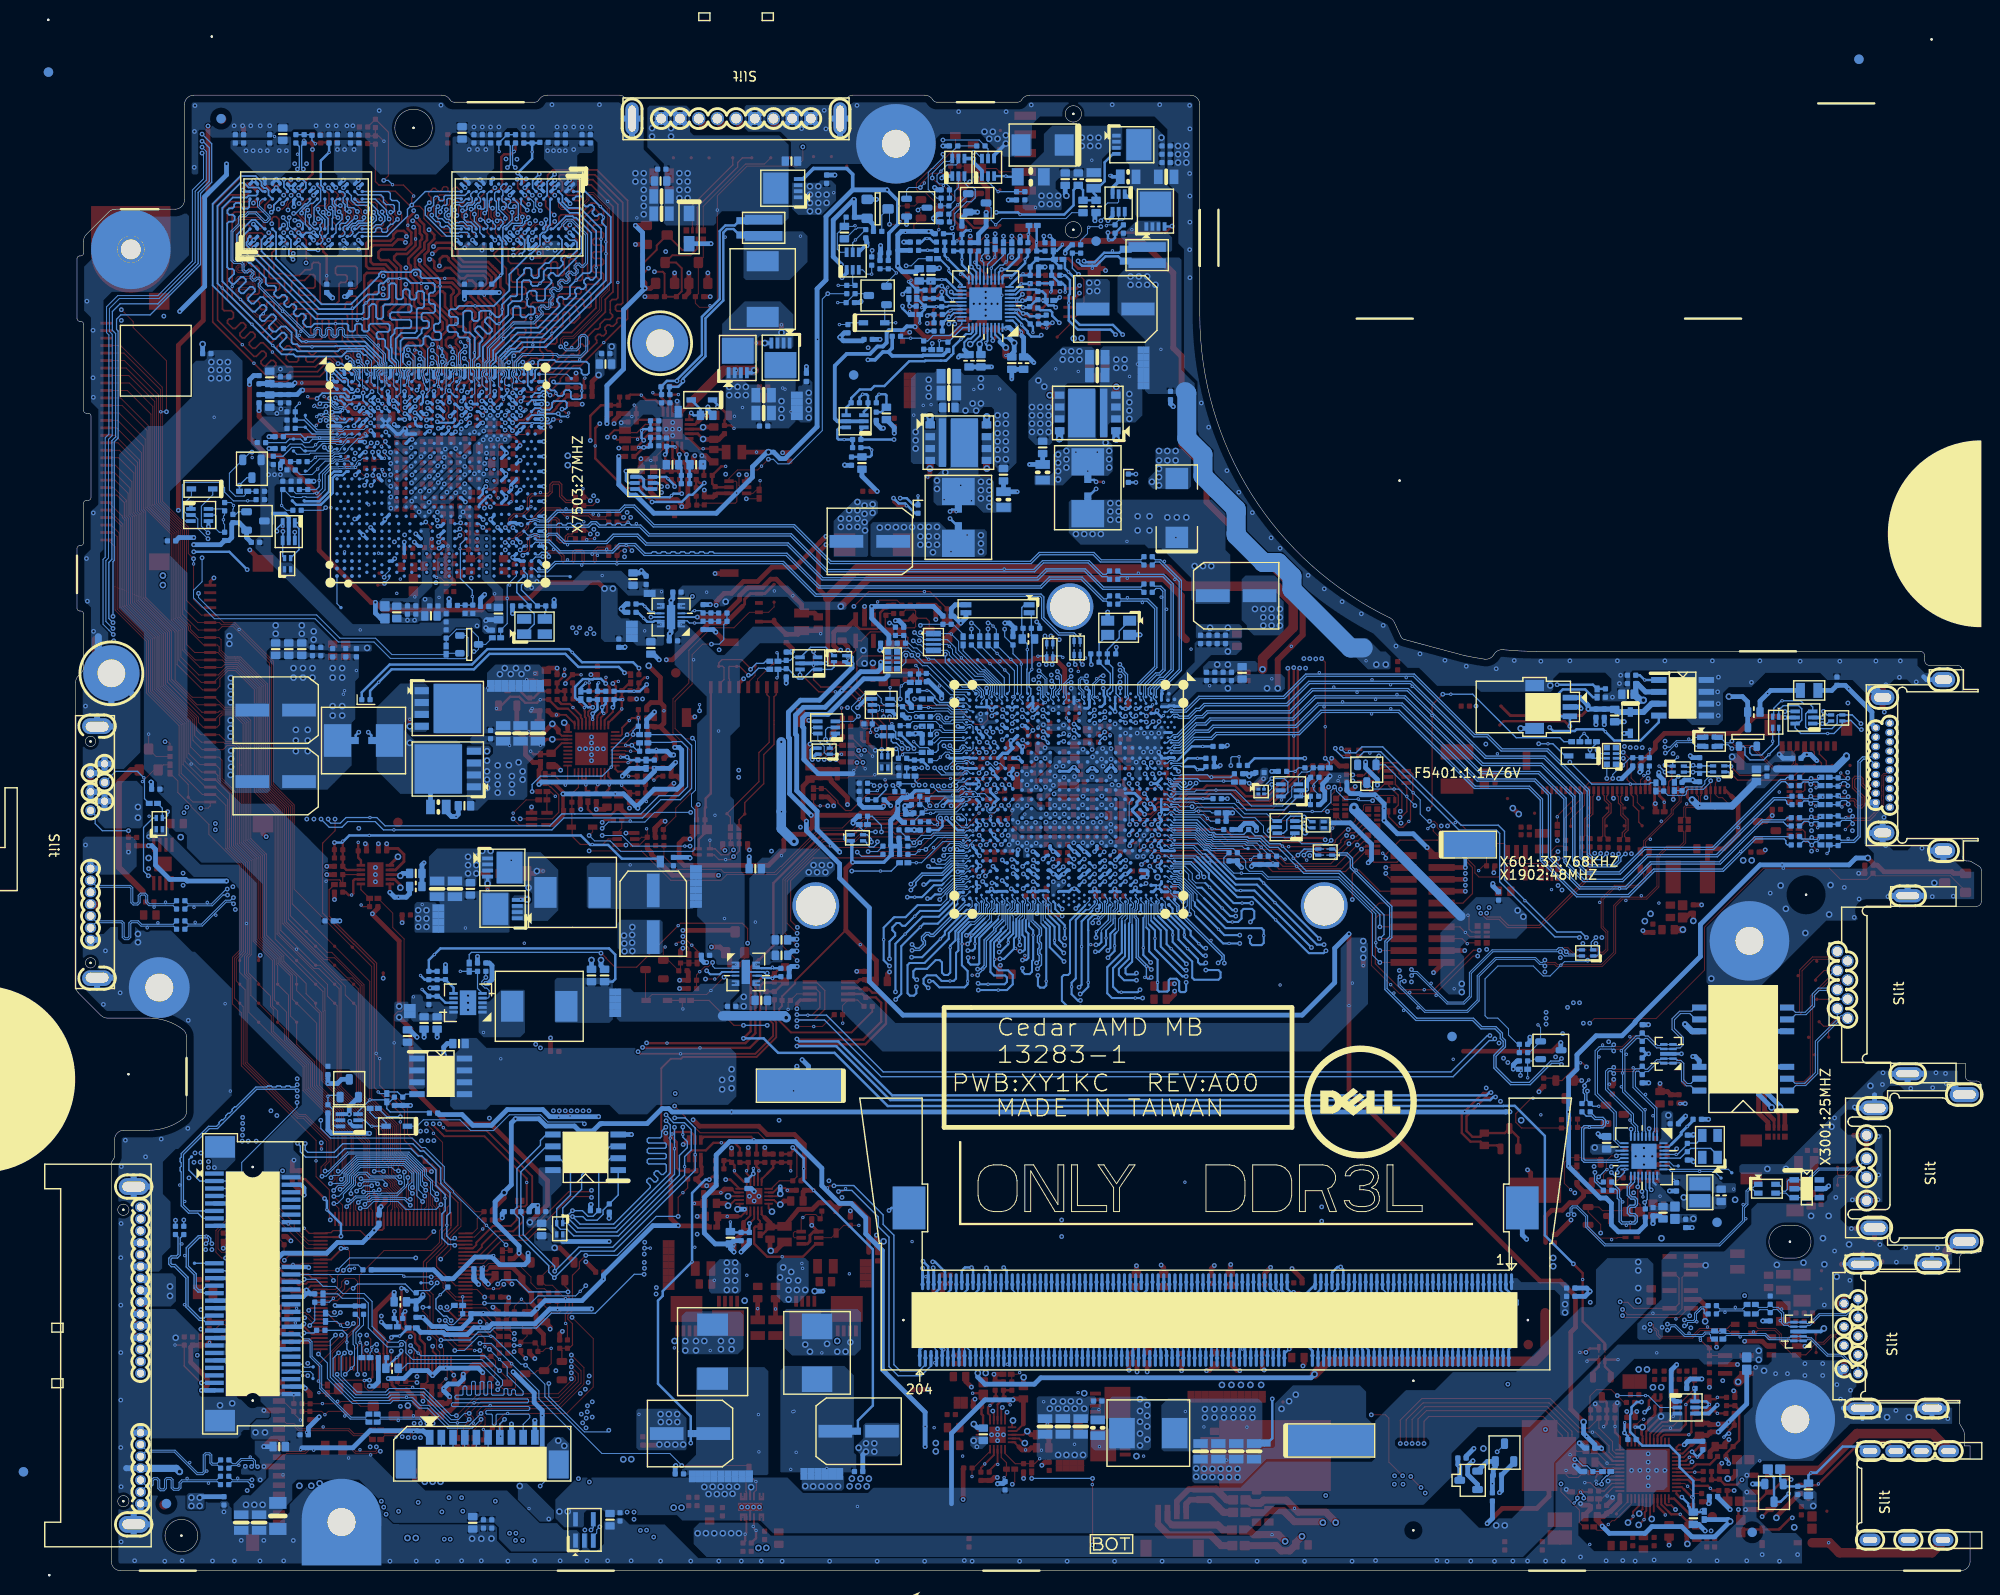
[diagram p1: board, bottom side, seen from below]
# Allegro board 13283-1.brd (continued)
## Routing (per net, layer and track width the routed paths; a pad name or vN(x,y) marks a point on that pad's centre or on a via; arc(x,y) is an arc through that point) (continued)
APU_LPC_AD2: length 10.1
  BOTTOM w0.102: CPU1.AR2 105.3,93.42 105.6,93.72 105.6,93.98 105.56,94.02 105.56,94.8 106.71,95.95 107.36,95.95 v1(109.09,97.69) 109.69,98.28 109.69,98.74 110.59,99.63 RN1901.7
APU_LPC_AD3: length 10.1
  BOTTOM w0.102: CPU1.AR1 105.3,94.83 106.67,96.19 107.1,96.19 109.39,98.48 109.39,99.45 v1(110.18,100.25) 110.22,100.28 RN1901.8
APU_PWROK: length 20.2
  BOTTOM w0.102: CPU1.B19 86.86,83.51 86.6,83.51 86.44,83.35 84.16,83.35 83.97,83.53 v1(81.86,83.53) 79.77,83.53 78.07,81.83 74.74,81.83 73.76,82.81 73.76,83.86 73.46,84.16 U402.3 73.05,85.11 72.69,85.46 72.69,85.46 72.04,85.46 71.99,85.51 71.88,85.51 71.47,85.92 R414.2 R418.2
APU_PWROK_C: length 2.1
  BOTTOM w0.127: R414.1 73.02,85.92 v1(73.4,85.54) C402.1
APU_PWROK_HDT: length 64.7
  TOP w0.102: HDT1.10 64.41,71.44 65.24,70.62 65.24,65.12 65.24,64.77 v1(63.18,62.72) 62.22,61.75 58.38,61.75 54.35,65.78 v2(53.87,65.78)
  L4 w0.102: v2(53.87,65.78) 54.71,66.62 54.71,79.3 61.05,85.64 74.39,85.64 v2(75.89,84.14)
  BOTTOM w0.102: RN408.3 76.48,83.13 75.89,83.72 v2(75.89,84.14) 74.94,84.14 U402.4
APU_RST#: length 18.1
  BOTTOM w0.127: CPU1.B20 87.1,83.1 86.78,82.78 86.51,82.78 86.18,83.11 80.31,83.11 v1(79.54,82.34) 78.61,81.41 74.56,81.41 73.12,82.86 U402.1 71.78,82.86 R409.2 R421.2
APU_RST#_C: length 2.5
  BOTTOM w0.102: C401.1 70.85,84.74 71.42,84.17 v1(71.42,83.96) 71.42,83.58 70.88,83.04 R409.1
APU_RST_L_BUF: length 65.6
  TOP w0.127: HDT1.12 64.44,70.17 64.82,69.79 64.82,64.95 62.04,62.17 v1(59.59,62.17) 58.55,62.17 54.33,66.39 v2(53.7,66.39)
  L4 w0.127: v2(75.89,84.78) 74.61,86.06 61.23,86.06 60.88,86.06 54.29,79.47 54.29,66.98 v2(53.7,66.39)
  BOTTOM w0.127: RN408.4 76.73,83.94 v2(75.89,84.78) 74.57,84.78 74.18,84.39 74.18,83.28 74.6,82.86 U402.6
APU_SIC: length 31.5
  TOP w0.102: RN2601.1 63.88,81.97 65.99,81.97 66.09,81.86 66.09,81.43 66.96,80.56 66.96,80.26 67.39,79.82 68.02,79.82 68.32,80.13 68.32,80.14 RN405.5 69.01,79.85 69.39,79.47 v1(69.39,79.47) 69.55,79.31 v2(69.55,78.15)
  BOTTOM w0.102: CPU1.B22 87.1,82 86.79,81.7 86.52,81.7 86.47,81.75 86.17,81.75 85.75,81.33 84.25,81.33 83.88,81.7 80.07,81.7 78.95,80.59 77.7,80.59 76.78,79.67 76.78,79.04 76.22,78.48 73.87,78.48 Q403.1 73.43,78.53 72.69,77.79 69.91,77.79 v2(69.55,78.15)
APU_SID: length 31.3
  TOP w0.102: v2(65.11,82.4) v1(64.65,82.86) 64.55,82.96 62.9,82.96 62.74,82.81 RN2601.2 ; v2(69.18,83.87) 69.18,83.84 69.22,83.81 69.22,83.31 69.52,83.01 69.52,82.11 69.39,81.98 RN405.7
  BOTTOM w0.102: CPU1.B21 86.81,82.36 86.56,82.36 86.44,82.25 84.24,82.25 84.1,82.11 79.9,82.11 78.78,80.99 76.43,80.99 75.65,80.22 Q403.4 74.99,80.22 73.99,81.22 70.58,81.22 69.57,82.23 69.57,83.48 v2(69.18,83.87) 68.98,83.67 68.98,83.46 68.07,82.54 66.71,82.54 66.57,82.4 v2(65.11,82.4)
APU_SPI_CLK: length 18.8
  TOP w0.14: v1(118.6,87.17) 119.23,87.8 v2(119.45,87.8) 120.88,89.22 R1925.1
  L4 w0.127: v2(105.71,89.73) 106.23,90.25 108.02,90.25 109.04,89.23 110.96,89.23 111.65,88.54 114.25,88.54 114.37,88.42 118.83,88.42 v2(119.45,87.8)
  BOTTOM w0.14: CPU1.AU7 106,90.02 v2(105.71,89.73)
APU_SPI_CS0#: length 16.4
  TOP w0.14: R1908.1 120.34,86.56 v2(120.27,86.48) 120.27,85.97 v1(120.6,85.64)
  L4 w0.127: v2(107.16,88.66) 107.93,88.66 108.99,87.61 110.75,87.61 111.01,87.35 111.22,87.14 113.28,87.14 113.65,86.77 118.71,86.77 118.88,86.94 119.72,86.94 119.74,86.92 119.83,86.92 120.08,86.67 120.08,86.67 v2(120.27,86.48)
  BOTTOM w0.14: CPU1.AW9 107.5,89 v2(107.16,88.66)
APU_SPI_HOLD#: length 13.9
  TOP w0.14: v2(115.44,87.98) 115.44,87.37 v1(115.39,87.32)
  L4 w0.127: v2(106.35,88.64) 106.82,89.11 108.02,89.11 109.29,87.84 110.84,87.84 111.16,87.52 113.44,87.52 113.81,87.15 114.63,87.15 115.44,87.96 115.44,87.98 v2(115.44,87.98)
  BOTTOM w0.14: v2(115.44,87.98) 116.05,88.59 116.41,88.59 116.6,88.78 R1923.1 ; CPU1.AU11 106,88.29 v2(106.35,88.64)
APU_SPI_SI_R: length 18.3
  TOP w0.14: R1921.1 120.57,87.44 119.63,86.5 119.63,86.49 v2(119.63,86.49) 119.63,86.06 v1(119.39,85.82)
  L4 w0.127: v2(119.63,86.49) 119.62,86.49 119.52,86.39 113.49,86.39 113.12,86.76 111.55,86.76 111.51,86.72 109.26,86.72 107.99,87.99 106.67,87.99 106.47,88.19 106.06,88.19 v2(105.6,88.66)
  BOTTOM w0.14: v2(105.6,88.66) 105.2,88.26 CPU1.AR11
APU_SPI_SO_R: length 18.9
  TOP w0.14: R1922.1 120.65,88.33 v2(120.09,87.77) 120.09,87.56 v1(119.82,87.29)
  L4 w0.127: v2(120.09,87.77) 120.09,87.79 119.08,88.8 114.69,88.8 114.57,88.92 111.72,88.92 111.05,89.59 109.17,89.59 108.28,90.48 105.83,90.48 105.13,89.77 v2(104.86,89.77)
  BOTTOM w0.14: CPU1.AR7 104.92,89.77 v2(104.86,89.77)
APU_SPI_WP#: length 13.5
  L4 w0.127: v2(106.42,89.81) 106.87,89.36 108.37,89.36 108.79,88.95 110.92,88.95 111.97,87.9 113.6,87.9 113.97,87.53 114.39,87.53 v2(114.81,87.95)
  BOTTOM w0.14: v2(114.81,87.95) 114.81,87.98 v1(115.46,88.64) 115.83,89.01 116.02,89.01 116.12,89.1 116.12,89.76 R1924.1 ; v2(106.42,89.81) 106.42,89.57 CPU1.AU9
APU_SVC: length 119.5
  TOP w0.127: RN407.7 66.09,80.84 66.54,80.39 66.54,80.08 67.21,79.4 67.63,79.4 67.71,79.32 v2(67.72,79.32) 67.72,79.32 67.97,79.32 69.1,78.18 69.1,77.97 69.36,77.71 70.37,77.71 70.57,77.91 74.7,77.91 74.85,78.06 80.58,78.06 81.25,78.73 v1(82.22,78.73) v2(87.98,78.73) ; v2(104.59,142.82) PR4655.2 PR4681.1
  L3 w0.127: v2(71.19,97.57) 71.19,97.56 63.12,89.48 63.12,82.55 66.27,79.39 67.64,79.39 67.71,79.32 v2(67.72,79.32)
  L4 w0.127: v2(71.19,97.57) 71.2,97.57 71.2,97.63 71.73,98.17 71.73,103.97 78.41,110.65 78.41,111.74 83.14,116.48 83.14,121.05 83.93,121.84 85.01,122.92 85.01,129.07 85.41,129.47 85.41,137.23 86.04,137.86 86.04,138.37 86.04,139.21 88.73,141.9 94.26,141.9 94.61,142.26 104.03,142.26 v2(104.59,142.82)
  BOTTOM w0.127: v2(87.98,78.73) 87.98,78.75 88.4,79.16 CPU1.D27 ; PR4655.2 v2(104.59,142.82)
APU_SVD: length 122.1
  TOP w0.127: v2(105.48,143.07) PR4654.2 PR4663.1 ; RN407.6 65.98,80.34 66.11,80.21 66.11,79.9 67.04,78.97 67.44,78.97 67.73,78.68 v2(67.89,78.68) 67.9,78.67 68,78.67 68.51,78.16 68.51,77.95 69.18,77.28 70.55,77.28 70.75,77.48 v1(74.09,77.48) 74.88,77.48 75.03,77.63 80.91,77.63 81.52,78.24 88.22,78.24 v2(88.69,78.71)
  L3 w0.127: v2(71.83,97.6) 71.83,97.38 63.55,89.1 63.55,82.72 66.45,79.82 67.87,79.82 68.16,79.53 68.16,78.95 v2(67.89,78.68)
  L4 w0.127: v2(71.83,97.6) 71.83,97.61 71.83,97.66 72.16,97.99 72.16,103.79 78.84,110.47 78.84,111.56 83.58,116.3 83.58,120.87 84.36,121.66 84.36,121.66 85.49,122.78 85.49,128.93 85.84,129.29 85.84,137.05 86.47,137.68 86.47,138.55 86.47,139.03 88.91,141.47 94.44,141.47 94.79,141.82 104.49,141.82 105.48,142.82 v2(105.48,143.07)
  BOTTOM w0.127: PR4628.1 v2(105.48,143.07) ; v2(88.69,78.71) 88.75,78.66 88.75,78.6 CPU1.E29
APU_SVT: length 124.3
  TOP w0.127: v2(106.37,142.82) 106.56,142.82 PR4653.2 ; RN407.5 65.71,79.69 66.86,78.54 67.25,78.54 v2(67.26,78.53) 67.55,78.24 67.82,78.24 68.08,77.98 68.08,77.77 69,76.85 70.88,76.85 71.05,77.02 75.03,77.02 75.21,77.2 81.67,77.2 82.19,77.72 v1(86.46,77.72) 87.34,77.72 87.63,78.01 89.09,78.01 v2(89.56,77.54)
  L3 w0.127: v2(67.26,78.53) 67.55,78.24 68.08,78.24 68.59,78.76 68.59,79.71 68.05,80.26 66.63,80.26 63.98,82.9 63.98,88.92 72.46,97.4 v2(72.46,97.6)
  L4 w0.127: v2(72.46,97.6) 72.46,97.68 72.59,97.81 72.59,103.61 79.27,110.29 79.27,111.38 84.01,116.12 84.01,120.69 84.8,121.48 84.8,121.48 85.92,122.6 85.92,128.75 86.27,129.11 86.27,136.87 86.9,137.5 86.9,138.85 89.09,141.04 94.62,141.04 94.97,141.39 96.37,141.39 97.21,140.54 98.18,140.54 99.02,141.39 104.95,141.39 v2(106.37,142.82)
  BOTTOM w0.127: PR4630.1 v2(106.37,142.82) ; v2(89.56,77.54) 90,77.1 CPU1.G31
APU_TCK: length 30.4
  TOP w0.127: v2(88.95,75.4) 88.52,75.82 v1(82.52,75.82) 76.82,75.82 75.81,74.82 68.02,74.82 65.95,76.89 RN404.1 65.58,76.44 64.96,75.81 62.51,75.81 HDT1.2
  BOTTOM w0.127: CPU1.D35 88.9,75.35 88.9,75.35 v2(88.95,75.4)
APU_TDI: length 33.6
  TOP w0.127: v2(63.7,74.62) 63.7,74.49 63.19,73.98 HDT1.6 ; v2(88.78,77.53) 88.31,77.06 82.19,77.06 82.1,76.97 81.89,76.76 75.47,76.76 74.37,75.66 69.58,75.66 v1(69.04,76.2) 67.64,77.6 v2(67.64,77.79) 67.63,77.81 67.31,77.81 67.01,78.1 66.71,78.1 66.71,78.11 66.68,78.11 66.09,78.69 RN404.4
  L4 w0.127: v2(67.64,77.79) 66.48,76.64 65.72,76.64 v2(63.7,74.62)
  BOTTOM w0.127: v2(88.78,77.53) 88.78,77.77 CPU1.D29
APU_TDO: length 33.7
  TOP w0.127: v2(67.28,71.82) 67.28,74.57 v1(66.88,74.97) 66.57,74.97 64.31,72.71 HDT1.8
  L4 w0.127: v2(88.76,76.41) 88.23,75.89 82.8,75.89 80.74,73.83 68.96,73.83 67.28,72.15 v2(67.28,71.82)
  BOTTOM w0.127: CPU1.D31 88.76,76.69 v2(88.76,76.41)
APU_TEST0: length 19.6
  TOP w0.102: R647.2 121.28,84.84 121.1,85.02 118.6,85.02 118.45,85.17 v1(118.36,85.17) 118.34,85.16 109.55,85.16 108.91,85.79 108.91,86.56 107.47,88 106.17,88 105.79,87.62 v2(105.59,87.62)
  BOTTOM w0.102: v2(105.59,87.62) 106,87.21 CPU1.AU13
APU_TEST1: length 5.9
  BOTTOM w0.102: R646.2 111.72,86.68 v1(111.34,87.06) 110.81,87.6 110.38,87.6 110.24,87.45 109.02,87.45 108.68,87.8 108.42,87.8 108.37,87.75 108.07,87.75 107.85,87.97 CPU1.AY10
APU_TEST2: length 5.4
  BOTTOM w0.102: CPU1.AY6 107.95,90.9 108.21,90.9 108.42,91.1 108.69,91.1 108.74,91.05 110.1,91.05 110.31,90.84 110.83,90.84 111.16,91.16 111.16,91.43 111.41,91.69 111.78,91.69 112.09,91.38 R645.2
APU_TEST6_DIRECRACKMON: length 2.6
  TOP w0.102: v2(88.75,79.85) 88.64,79.85 88.21,80.29 87.24,80.29 TP403.1
  BOTTOM w0.102: CPU1.D25 88.4,80.19 88.74,79.85 v2(88.75,79.85)
APU_TEST14_BP0: length 11.7
  BOTTOM w0.102: v1(78.17,76.09) 77.8,76.46 R410.1 77.16,76.9 77.9,77.64 78.62,77.64 78.77,77.79 82.23,77.79 82.47,78.03 82.83,78.03 84.05,79.25 CPU1.A27
APU_TEST15_BP1: length 9.4
  BOTTOM w0.102: CPU1.B27 86.73,79.25 86.43,78.95 84.03,78.95 82.92,77.83 82.56,77.83 82.26,77.54 79.07,77.54 78.81,77.28 TP404.1
APU_TEST16_BP2: length 13.7
  BOTTOM w0.102: v1(74.47,76.14) 74.6,76.14 74.92,76.46 R411.1 75.96,77.03 76.14,77.03 77.21,78.1 78.43,78.1 78.58,78.25 82.08,78.25 82.29,78.46 82.69,78.46 83.98,79.76 86.61,79.76 CPU1.A26
APU_TEST17_BP3: length 12.6
  BOTTOM w0.102: CPU1.B26 87.11,79.8 86.81,79.5 86.52,79.5 86.47,79.55 84.06,79.55 82.75,78.24 82.39,78.24 82.17,78.02 78.68,78.02 78.53,77.87 77.48,77.87 77.04,77.42 v1(77.04,77.41) 77.02,77.41 76.27,76.66 R413.1
APU_TEST18_PLLTEST1: length 35.3
  TOP w0.102: HDT1.20 v2(64.34,65.09)
  BOTTOM w0.102: CPU1.B28 87.08,78.7 86.78,78.4 86.48,78.4 86.43,78.45 84.13,78.45 83.1,77.42 82.72,77.42 82.36,77.06 80.68,77.06 R415.1 81.02,76.28 81.02,75.72 79.95,74.65 v1(79.14,74.65) 79.11,74.61 76.99,74.61 76.36,73.98 68.78,73.98 65.12,70.32 65.12,65.88 v2(64.34,65.09)
APU_TEST19_PLLTEST0: length 32.4
  TOP w0.102: HDT1.18 v2(64.34,66.36)
  BOTTOM w0.102: CPU1.A28 84.09,78.7 83.02,77.63 82.64,77.63 82.3,77.28 80.02,77.28 R416.1 78.69,75.95 78.69,75.22 78.3,74.84 76.9,74.84 76.29,74.24 68.71,74.24 64.77,70.29 v1(64.77,67.2) 64.77,66.79 v2(64.34,66.36)
APU_TEST28_H_PLLCHRZ: length 1.7
  TOP w0.102: v2(107.24,74.28) 107.9,74.94 TP410.1
  BOTTOM w0.102: CPU1.AV35 106.8,74.72 v2(107.24,74.28)
APU_TEST28_L_PLLCHRZ: length 1.4
  TOP w0.102: v2(106.53,74.33) 106.63,74.44 TP411.1
  BOTTOM w0.102: CPU1.AU35 106.01,74.85 v2(106.53,74.33)
APU_TEST31_M_TEST: length 1.5
  TOP w0.102: v2(89.83,75.57) 89.56,75.57 TP409.1
  BOTTOM w0.102: CPU1.E33 89.46,75.95 v2(89.83,75.57)
APU_TEST36_FREE_2: length 27
  TOP w0.102: R422.1 R423.1 71.93,86.12 72.13,85.92 72.13,85.21 v1(74.86,82.49) 75.8,81.55 83.08,81.55 83.84,82.31 84.07,82.31 84.16,82.4 84.7,82.4 85.75,81.35 87.67,81.35 87.7,81.38 88.06,81.38 88.95,80.49 89.81,80.49 90.01,80.29 90.67,80.29 91.1,79.85 v2(91.11,79.85)
  BOTTOM w0.102: v2(91.11,79.85) 91.15,79.9 91.15,82.2 CPU1.H21
APU_TEST37_FREE_2: length 23.2
  TOP w0.102: v2(90.37,79.85) 90.16,79.85 89.72,80.29 88.5,80.29 88.3,80.49 87.75,80.49 87.72,80.52 87.7,80.52 87.27,80.94 85.86,80.94 84.61,82.2 84.25,82.2 82.72,80.66 75.21,80.66 v1(72.74,83.13) 71.97,83.13 R425.1 R424.1
  BOTTOM w0.102: CPU1.H25 90.8,80.28 v2(90.37,79.85)
APU_THERMDA: length 1.4
  TOP w0.254: TP401.1 90.7,79.19 v2(91.16,78.73)
  BOTTOM w0.254: CPU1.H27 91.16,78.89 v2(91.16,78.73)
APU_THERMDC: length 1.5
  TOP w0.254: v2(91.09,77.58) 90.75,77.92 TP402.1
  BOTTOM w0.254: v2(91.09,77.58) 91.09,77.86 CPU1.H29
APU_TMS: length 29.9
  TOP w0.127: RN404.2 65.76,77.54 65.85,77.45 66.07,77.45 66.3,77.22 v2(66.3,77.21) 68.41,75.1 75.13,75.1 v1(75.77,75.74) 76.24,76.2 81.98,76.2 82.17,76.39 v2(88.02,76.39) ; HDT1.4 v2(63.7,75.25)
  L4 w0.127: v2(66.3,77.21) 65.66,77.21 v2(63.7,75.25)
  BOTTOM w0.127: v2(88.02,76.39) 88.4,76.01 CPU1.D33
APU_TRST#: length 50.8
  TOP w0.127: v2(63.7,76.26) 63.7,76.65 62.18,78.17 58.24,78.17 58.23,78.17 57.34,78.17 54.43,75.26 54.43,72.46 55.45,71.44 HDT1.9 ; v2(90.32,78.73) 90.05,78.47 90.05,77.4 89.73,77.08 88.8,77.08 88.55,76.83 87.83,76.83 87.67,76.67 82.12,76.67 81.94,76.48 75.8,76.48 74.7,75.38 69.03,75.38 v2(66.75,77.66) 66.46,77.66 66.08,78.04 RN404.3
  L4 w0.127: v2(66.75,77.66) 65.11,77.66 v2(63.7,76.26)
  BOTTOM w0.127: v1(64.03,76.78) 63.7,76.45 v2(63.7,76.26) ; v2(90.32,78.73) 90.32,78.93 CPU1.G27
APU_VDD:
  vias: v1(86.15,110.56) v1(91.39,110.15) v2(93.04,81.93) v2(93.11,79.87) v2(93.11,79.11) v2(94.09,81.97) v2(94.22,80.11) v2(94.99,80.08) v2(96.14,81.96) v2(96.09,80.1) v2(96.95,80.08) v2(98.09,81.91) v2(98.06,80.1) v2(99.11,81.91) v2(99.11,80.08) v2(100.06,80.1) v3(82.37,107.51) v3(83.26,107.51) v3(84.15,107.51) v3(85.04,112.72) v3(86.05,112.72) v3(87.07,112.72) v3(88.97,112.84) v3(88.97,111.32) v3(90.24,112.84) v3(90.24,111.32) v3(92.28,114.24) v3(92.28,113.35) v3(92.28,112.46) v3(93.16,114.24) v3(93.16,113.35) v3(93.16,112.46) v3(94.18,110.94) v3(95.07,110.94) v3(95.96,110.94) v3(96.85,110.94)
APU_VDD_RUN_FB_H: length 88.2
  TOP w0.203: TP434.1 88.07,81.73 88.85,80.95 v2(89.51,80.95)
  TOP w0.254: v2(89.51,80.95) 90.11,80.95 PR4627.1 ; TP434.1 85.76,81.73 84.75,82.75 82.88,82.75 82.5,83.13 80.22,83.13 79.07,81.98 75.97,81.98 73.11,84.85 73.11,96.34 72.91,96.54 v2(72.91,96.59) ; PR4626.2 99.14,136.9 v2(98.55,136.9)
  L4 w0.254: v2(72.91,96.59) 72.91,96.78 73.16,97.03 73.16,103.48 79.77,110.09 79.77,111.13 84.5,115.87 84.5,120.49 85.29,121.27 85.29,121.28 86.94,122.93 86.94,132.83 89.81,135.7 91.94,135.7 92.27,136.03 92.28,136.03 92.45,136.21 97.81,136.21 98.37,136.78 98.42,136.78 v2(98.55,136.9)
  BOTTOM w0.254: v2(89.51,80.95) 89.61,81.05 89.61,81.06 CPU1.G23
APU_VDD_RUN_FB_L: length 106.4
  TOP w0.203: v2(89.53,82.04) 89.53,81.86 89.23,81.55 88.71,81.55 88.03,82.23 87.57,82.23
  TOP w0.254: v2(73.55,96.64) 73.54,96.63 v1(73.54,89.32) 73.54,84.95 76.13,82.36 78.92,82.36 80.06,83.51 82.65,83.51 83.04,83.13 84.9,83.13 85.8,82.23 87.57,82.23 ; PR4633.1 89.73,82.24 v2(89.53,82.04)
  L4 w0.254: v2(73.55,96.64) 73.54,96.64 73.54,103.32 80.15,109.93 80.15,110.97 84.88,115.71 84.88,120.33 85.67,121.12 85.67,121.12 87.32,122.77 87.32,132.67 89.97,135.32 92.1,135.32 92.61,135.83 98.14,135.83 v2(98.58,136.27) 98.64,136.27 100.87,138.5 111.96,138.5 113.42,137.04 114.94,137.04 v2(115.38,136.59)
  BOTTOM w0.254: v2(115.38,136.59) 114.94,137.04 PR4615.2 ; v2(98.58,136.27) 98.92,135.93 PR4632.2 ; v2(89.53,82.04) 89.53,81.86 89.2,81.52 CPU1.E23
APU_VDDNB: length 1.6
  TOP w0.254: PR4612.1 91.77,84.08 91.77,84.52 91.89,84.65
  vias: v1(94.56,93.46) v1(108.48,110.84) v1(110.21,109.06) v2(92.12,95.72) v2(93.09,87.98) v2(93.09,86.86) v2(93.2,84.98) v2(93.99,87.98) v2(93.96,86.09) v2(94.1,86.86) v2(95.07,87.09) v2(95.12,84.93) v2(97,84.98) v2(97.38,96.36) v2(97.61,96.97) v2(98.12,84.9) v2(98.22,86.1) v2(98.96,86.05) v2(99.09,85.02) v2(99.26,84.04) v2(99.48,95.85) v2(100.1,83.86) v2(100.78,96.97) v2(101.37,95.34) v3(107.01,110.81) v3(107.01,109.92) v3(107.01,109.03) v3(111.71,111.7) v3(111.71,110.69) v3(111.71,109.8) v3(112.14,108.98) v3(112.6,111.7) v3(112.6,110.69) v3(112.6,109.8) v3(113.48,111.7) v3(113.48,110.69) v3(113.48,109.8) v3(114.37,111.68) v3(115.24,111.68) v3(116.1,111.68) v3(116.96,111.68) v3(117.83,111.62)
APU_VDDNB_RUN_FB_H: length 105.5
  TOP w0.254: v2(74.18,96.58) 74.06,96.46 74.06,85.15 76.34,82.87 78.71,82.87 79.85,84.02 82.87,84.02 83.25,83.63 84.9,83.63 85.92,82.62 TP433.1 88.65,82.31 88.65,82.29 v2(88.88,82.06) 88.88,82.15 89.39,82.65 89.74,82.65 90.18,83.1 PR4612.2
  L4 w0.254: v2(115.39,135.32) 114.88,135.83 113.91,135.83 113.13,136.61 111.75,137.99 101.08,137.99 98.42,135.32 92.82,135.32 92.31,134.82 90.18,134.82 87.83,132.46 87.83,122.56 86.18,120.91 85.39,120.12 85.39,115.5 80.73,110.84 80.73,109.79 74.05,103.11 74.05,96.85 74.05,96.85 74.05,96.7 v2(74.18,96.58)
  BOTTOM w0.254: v2(88.88,82.06) 88.8,82.06 88.8,82.06 88.77,82.06 88.4,81.69 CPU1.D23 ; v2(115.39,135.32) 115.39,135.07 114.75,134.43 PR4613.2
ATI_RST#: length 55.1
  TOP w0.102: U8201.1 156.4,79.81 v2(157.05,80.46) v1(157.05,81.07) 157.05,81.09 155.65,82.49 PR8275.2
  L3 w0.102: v2(157.05,80.46) 156.61,80.03 156.1,80.03 155.8,80.33 153.41,80.33 152.85,80.89 147.72,80.89 146.51,82.11 146.51,85.75 146.12,86.13 146.12,92.04 145.95,92.22 145.95,93.11 146.63,93.79 148.28,93.79 152.22,97.73 160.6,97.73 v2(161.24,98.37)
  BOTTOM w0.102: v2(161.24,98.37) 161,98.37 160.75,98.62 D7301.3 ; R7326.1 R7327.2 164.04,99.8 163.09,100.75 161.62,100.75 160.75,99.88 D7301.3 ; R7320.2 159.98,99.13 D7301.3
ATI_RST#_R: length 7.7
  BOTTOM w0.102: GPU1.AL27 156.69,106.47 157.68,105.48 v1(157.68,104.06) 157.68,101.35 C7333.1 R7320.1
AUD_AGND: length 23.7
  TOP w0.203: HDA27.38 33.83,7.2 33.63,7 33.17,7 v2(32.71,6.55) ; v2(31.77,13.48) 32.33,13.48 32.61,13.2 HDA27.25
  TOP w0.508: EC2906.2 27.95,10.61 EC2907.2 28.01,11.24 v2(27.76,11.5) ; C2715.2 v2(33.4,2.74) ; v2(26.49,19.25) 26.36,19.12 R2920.2 ; C2711.2 30.13,15.79 29.2,15.79 C2710.2 28.21,15.63 v2(28.15,15.69) 27.45,15.69 R2919.2 ; v2(36.85,17.04) 37.03,16.86 R2707.2 ; v2(27,14.04) 27.44,13.59 EC2908.2 28.45,13.28 C2702.1 29.02,12.72 C2705.1 ; R2924.2 18.49,7.69
  BOTTOM w0.406: v2(28.25,17.72) 29.16,16.82 U2901.4
  BOTTOM w0.508: EC9745.1 28.2,7.88 v2(26.87,6.55) ; C2701.2 30.23,4.95 v2(29.54,4.26) ; v2(31.77,13.48) 31.4,13.85 R2711.1 ; Q2901.S v2(24.46,9.28)
  vias: v2(28.9,4.26) v3(17.98,6.93) v3(34.24,19.63) v3(35.13,19.63)
AUD_HP1_JACK_L: length 3
  TOP w0.203: HDA27.32 31,10.14 30.76,9.9
  TOP w0.254: R2908.1 30.59,9.73 30.76,9.9
AUD_HP1_JACK_L1: length 17.8
  TOP w0.254: v2(25.6,9.72) 26.11,9.21 27.44,9.21 EC2907.1 28.07,9.73 R2908.2 R2912.2 ; R2922.2 R2919.1 26.43,15.54 27,14.97 v2(27,14.67) ; v2(25.98,6.55) 25.98,5.68 R2907.2
  L3 w0.254: v2(27,14.67) 26.91,14.67 26.47,14.23 26.47,12.24 25.6,11.37 v2(25.6,9.72) 25.6,6.93 v2(25.98,6.55)
  BOTTOM w0.254: v1(27.53,14.29) 27.15,14.67 v2(27,14.67)
AUD_HP1_JACK_R: length 5
  TOP w0.203: 31.33,9.74 HDA27.33
  TOP w0.254: 31.33,9.74 30.68,9.09 29.25,9.09 v1(28.98,8.81) 28.74,8.58 R2910.1
AUD_HP1_JACK_R1: length 13.8
  TOP w0.254: v2(26.44,8.58) R2910.2 27.19,7.47 R2909.2 ; R2921.2 R2920.1 25.91,17.2 25.91,13.92 EC2908.1 27.32,12.51 R2913.2 27.01,11.91 v2(27.01,11.46)
  L3 w0.254: v2(27.01,11.46) 26.24,10.69 26.24,8.78 v2(26.44,8.58)
  BOTTOM w0.254: v1(27.3,11.96) 27.01,11.66 v2(27.01,11.46)
AUD_PC_BEEP: length 3.6
  TOP w0.203: HDA27.12 38.66,13.23
  TOP w0.254: C2720.2 v1(39.18,15.44) 39.18,14.81 38.66,14.29 38.66,13.23
AUD_PC_BEEP_C: length 3.5
  TOP w0.254: D2701.3 40.07,18.01 R2717.1 C2720.1 40.07,15.74 v1(40.4,15.41)
AUD_PORTA_L_R_B: length 15.9
  TOP w0.254: v2(20.22,5.66) 20.39,5.66 AFTP2906.1 21.65,4.4 ED2902.1 25.43,4.4 R2907.1
  L3 w0.254: v2(20.22,5.66) 20.21,5.65 19.02,5.65 16.32,2.94 12.01,2.94 11.9,3.06 HPMIC1.1
AUD_PORTA_R_R_B: length 23
  TOP w0.254: v2(20.34,9.76) AFTP2907.1 21.12,9.76 22.47,8.41 ED2901.1 22.85,8.41 23.82,7.43 R2909.1
  L3 w0.254: HPMIC1.2 6.4,13.1 7.49,14.19 13.23,14.19 17.66,9.76 v2(20.34,9.76)
AUD_SENSE: length 33.4
  TOP w0.254: v2(23.44,5.78) 22.68,6.55 ED2904.1 22.29,6.55 AFTP2909.1 20.65,8.19 20.65,8.2 v2(20.6,8.24) ; v2(37.92,17.04) R2709.2
  L3 w0.254: v2(37.92,17.04) 37.41,17.54 29.07,17.54 25.96,14.44 25.96,12.5 23.44,9.97 v2(23.44,5.78)
  BOTTOM w0.254: R2914.2 22.83,10.61 22.17,9.95 Q2901.D 21.47,7.37 v2(20.6,8.24)
AUD_SENSE_A: length 4.8
  TOP w0.203: HDA27.13 37.83,14.33 37.62,14.55
  TOP w0.254: 37.62,14.55 37.62,15.19 R2709.1 38.17,15.24 v2(38.17,14.75)
  BOTTOM w0.254: v1(38.15,15.84) 38.15,14.77 v2(38.17,14.75) 37.81,14.38 R2722.2
AUD_SPK_L+: length 50.2
  TOP w0.203: HDA27.42 35.43,5.71 v3(35.25,5.53)
  TOP w0.762: v3(74.47,3.14) 75.19,3.86 v1(75.87,3.86) EC2902.1 77.83,3.86 78.32,4.35 R2902.2
  L4 w1.016: v3(74.47,3.14) 73.3,1.97 64.39,1.97 64.06,1.64 64.06,1.63 64,1.57 59.01,1.57 58.43,2.15 50.16,2.15 48.66,3.65 46.26,3.65 45.22,2.61 37.02,2.61 35.25,4.37 v3(35.25,5.53)
AUD_SPK_L+_C: length 8.2
  TOP w0.61: 86.57,4.89 87.05,5.37 SPK1.3
  TOP w0.762: 86.57,4.89 AFTP2902.1 81.12,4.35 R2902.1
AUD_SPK_L-: length 48.5
  TOP w0.203: v3(36.65,4.89) v1(36.08,5.46) 36.01,5.54 36.01,6.24 35.83,6.41 HDA27.43
  TOP w0.762: v3(72.67,3.67) 73.33,3.01 EC2901.1 73.96,2.13 74.89,2.13 75.45,2.68 R2901.2
  L4 w1.016: v3(36.65,4.89) 36.65,4.77 37.54,3.88 44.69,3.88 45.74,4.92 49.19,4.92 50.69,3.42 58.96,3.42 59.54,2.84 63.45,2.84 63.86,3.24 72.24,3.24 v3(72.67,3.67)
AUD_SPK_L-_C: length 10.2
  TOP w0.61: SPK1.4 88.05,4.94
  TOP w0.762: R2901.1 81.33,2.68 AFTP2901.1 82.47,3.83 86.94,3.83 88.05,4.94
AUD_SPK_R+: length 47.2
  TOP w0.203: v3(37.79,5.15) 37.25,5.69 v1(37.25,5.83) 37.25,6.32 36.63,6.93 HDA27.45
  TOP w0.762: v3(70.43,5.15) 70.53,5.25 73.48,5.25 74.65,6.42 75.83,6.42 75.94,6.53 EC2904.1 76.52,6.21 78.68,6.21 R2904.2
  L3 w1.016: v3(37.79,5.15) 39.34,5.15 39.84,5.65 41.05,5.65 41.68,5.02 44.12,5.02 45.11,6.01 66.37,6.01 68.51,3.88 69.59,3.88 70.43,4.72 v3(70.43,5.15)
AUD_SPK_R+_C: length 6.7
  TOP w0.61: 83.76,7.6 84.62,7.6 85.05,7.17 85.05,6.82 SPK1.1
  TOP w0.762: R2904.1 81.05,6.24 AFTP2904.1 82.41,7.6 83.76,7.6
AUD_SPK_R-: length 47.1
  TOP w0.203: HDA27.44 36.23,6.58 36.59,6.22 v3(36.59,6.11)
  TOP w0.762: v3(69.06,5.15) 69.06,5.21 70.11,6.27 73.06,6.27 v1(73.47,6.68) 74.34,7.55 76.77,7.55 77.09,7.23 EC2903.1 78.1,7.23 78.46,7.59 R2903.2
  L3 w1.016: v3(69.06,5.15) 69.04,5.17 69.01,5.17 66.9,7.28 44.59,7.28 43.6,6.29 42.21,6.29 41.57,6.92 39.31,6.92 38.81,6.42 36.9,6.42 v3(36.59,6.11)
AUD_SPK_R-_C: length 8.2
  TOP w0.61: 84.22,8.73 84.76,8.73 86.05,7.44 SPK1.2
  TOP w0.762: 84.22,8.73 AFTP2903.1 80.72,7.59 R2903.1
AUD_VREF: length 2.9
  TOP w0.203: 31.58,11.78 31.63,11.74 HDA27.28
  TOP w0.254: 31.58,11.78 v1(31.23,12.13) 31.16,12.21 29.93,12.21 C2705.2
BAT_ALERT: length 1.9
  TOP w0.635: 128.82,154.52 BAT1.7 129.2,154.51
BAT_AMBER: length 3.3
  TOP w0.102: IOBD1.14 181.62,18.15 R6103.1 180.51,16.83 v1(179.8,16.12)
BAT_IN#: length 306.3
  TOP w0.102: R2414.1 v2(160.09,29.28) 160.91,30.1 KBC24.80 ; RN4301.1 136.71,140.52 D4302.3 137.23,136.66 EC4305.2 137.55,135.64 137.11,135.2 135.84,135.2 135.2,135.83 v1(135.2,145.61) 135.2,147.13 132.03,150.31 126.69,150.31 126.06,150.94 v2(126.06,152.37)
  L3 w0.102: v2(166.32,47.06) 166.72,47.46 170.86,47.46 171.52,48.12 173.53,48.12 174.85,46.8 180.52,46.8 182.01,45.31 189.22,45.31 190.52,44 v2(190.52,43.73)
  L4 w0.102: v2(166.32,47.06) 166.22,46.96 165.41,46.96 164.59,46.13 164.59,42.13 159.28,36.82 159.28,30.09 v2(160.09,29.28) ; v2(190.52,43.73) 189.2,45.05 189.2,50.36 189.02,50.54 189.02,61.67 199.08,71.73 199.08,79.76 198.28,80.56 198.28,83.88 196.81,85.35 196.81,94.16 196.43,94.54 196.43,98.83 197.36,99.76 197.36,107.82 199.9,110.36 199.9,134.99 191.13,143.76 191.13,148.76 189.39,150.5 189.39,153.71 187.68,155.41 173.41,155.41 169.17,151.17 166.04,151.17 162.16,155.06 148.13,155.06 145.16,152.09 138.33,152.09 138.05,152.37 v2(126.06,152.37) 120.19,152.37 117.02,155.53 113.42,155.53 112.62,154.73 112.09,154.73 110.64,153.28 110.64,152.01 v2(111.07,151.58)
  BOTTOM w0.102: PQ4203.2 109.42,148.02 109.8,147.64 109.8,146.65 110.4,146.05 PR4215.2 PR4216.1 111.33,146.82 PC4210.2 111.71,146.88 112.65,147.82 112.65,149.62 111.07,151.2 v2(111.07,151.58)
BAT_SCL: length 190.7
  TOP w0.203: v2(164.92,47.82) 164.88,47.79 164.88,47.79 164.51,47.42 ; PG4407.2 146.23,122.04 v2(146.96,121.3) ; v2(142.57,139.39) 142.95,139.01 143.19,139.01 143.25,138.94 PR4415.2 EC4301.1 141.69,141.34 141.69,141.81 D4301.3 138.97,141.35 138.31,141.35 137.87,141.8 RN4301.3 ; KBC24.70 160.92,34.1 160.4,34.62 160.4,34.88 158.96,36.31 157.05,36.31 156.01,37.35 RN2401.3 155.99,38.4 155.53,38.4 155.01,38.92 155.01,42.22 159.87,47.08 164.17,47.08 164.51,47.42 ; 164.51,47.42 v1(164.51,47.41)
  L3 w0.203: v2(182.95,49.22) 182.75,49.42 182.01,49.42 181.28,48.68 179.34,48.68 176.75,51.28 176.41,51.62 168.27,51.62 164.92,48.27 v2(164.92,47.82)
  L4 w0.203: v2(142.57,139.39) 144.17,137.79 144.17,130.99 146.89,128.28 146.89,125.54 148.84,123.59 148.84,122.31 148.14,121.61 147.27,121.61 v2(146.96,121.3) 146.96,120.72 151.9,115.78 151.9,114.02 153.63,112.28 154.13,112.28 155.25,111.17 159.04,111.17 161.32,108.89 168.82,108.89 169.28,109.35 175.02,109.35 177.67,106.7 184.95,106.7 189.41,102.24 189.41,84.27 188.31,83.18 188.31,79.14 189.21,78.24 190.67,76.78 190.67,70.52 183.92,63.77 183.92,50.25 182.95,49.28 v2(182.95,49.22)
BAT_SDA: length 192.7
  TOP w0.203: v2(141.93,139.01) 141.04,139.01 140.85,138.82 EC4302.1 PR4412.2 139.01,136.91 139.01,139.39 139.62,140 D4303.3 140.02,140.76 138.07,140.76 137.36,141.47 RN4301.2 ; v2(165.59,47.82) 165.59,47.67 165.13,47.2 165.12,47.2 164.88,46.96 164.88,46.96 164.62,46.69 164.61,46.69 164.41,46.49 160.11,46.49 155.59,41.97 v1(155.59,41.55) 155.59,39.16 155.77,38.98 156.51,38.98 156.66,38.83 RN2401.4 156.66,37.52 157.29,36.9 159.2,36.9 160.98,35.12 160.98,34.86 161.34,34.5 KBC24.69 ; v2(146.2,121.3) 145.92,121.02 PG4408.2
  L3 w0.203: v2(182.32,48.71) 182.13,48.71 181.52,48.1 179.1,48.1 178.76,48.44 176.17,51.04 168.52,51.04 165.59,48.11 v2(165.59,47.82)
  L4 w0.203: v2(141.93,139.01) 142.12,139.01 143.58,137.54 143.58,130.75 146.3,128.03 146.3,125.3 148.26,123.35 148.26,122.55 147.9,122.19 147.02,122.19 146.2,121.37 v2(146.2,121.3) 146.2,120.65 151.31,115.54 151.31,113.77 153.39,111.7 153.89,111.7 155,110.58 158.8,110.58 161.08,108.3 169.06,108.3 169.52,108.76 174.78,108.76 177.43,106.11 184.71,106.11 188.82,102 188.82,84.51 187.73,83.42 187.73,78.89 190.08,76.54 190.08,70.76 183.33,64.01 183.33,50.49 182.32,49.47 v2(182.32,48.71)
BAT_WHITE: length 2.7
  TOP w0.102: IOBD1.15 180.83,19.15 v1(180.5,18.83) R6101.1
BATT_WHITE_LED#: length 32.9
  TOP w0.102: R6105.2 172.17,19.25 172.52,19.25 172.92,19.65 172.92,20.13 173.17,20.39 175.86,20.39 176.4,20.93 176.4,23.26 173.49,26.17 173.49,31.61 170.85,34.26 165.78,34.26 164.93,35.11 164.93,36.39 164.49,36.83 KBC24.62 164.49,38.82 164.31,39.01 164.31,39.82 v1(164.34,39.84)
BATT_WHITE_LED_R#: length 2.9
  TOP w0.102: v1(168.45,18.56) 168.5,18.61 Q6103.2 170.7,19.54 R6105.1
BKLT_CTRL: length 18.5
  TOP w0.14: RN5203.8 45.27,76.22 v2(45.27,76.22) 45.25,76.24 v1(44.63,76.24)
  L4 w0.127: v2(45.27,76.22) 45.27,76.34 44.5,77.11 44.5,82.73 41.86,85.37 v2(41.86,87.85)
  BOTTOM w0.14: RN5201.7 41.61,86.94 D5202.K v2(41.86,87.85) 41.16,88.55 R5222.1
BLINK: length 5.7
  TOP w0.102: v2(106.37,84.12) 106.83,84.57 107.64,84.57 108.18,84.04 R1928.1 R1929.1 109.28,83 v1(110.03,83)
  BOTTOM w0.102: v2(106.37,84.12) 106,84.49 CPU1.AU17
BLON_OUT: length 246.7
  TOP w0.102: KBC24.27 176.64,34.1 175.82,34.92 175.28,34.92 174.55,34.18 v2(174.55,32.18)
  L3 w0.102: v2(62.79,9.25) 62.79,9.52 62.33,9.97 62.33,10.43 60.6,12.16 59.37,12.16 57.13,14.39 46.41,14.39 45.46,15.34 45.46,16.48 45.04,16.91 42.21,19.74 40.68,19.74 37.92,22.5 37.92,25.57 37.16,26.33 37.16,28.49 37.39,28.72 37.39,37.2 41.32,41.14 41.32,41.34 42.11,42.13 42.11,48.73 44.8,51.43 44.8,53.34 44.22,53.92 44.22,57.1 44.12,57.2 44.12,57.75 44.22,57.85 44.22,60.24 v2(44.26,60.28)
  L4 w0.102: v2(41.09,87.83) 41.09,85.54 43.97,82.67 43.97,61.05 44.07,60.95 44.07,60.48 v2(44.26,60.28) ; v2(174.55,32.18) 174.42,32.18 173.21,30.97 173.21,26.04 173.86,25.39 173.86,24.91 173.14,24.18 173.14,23.14 171.39,21.4 171.39,14.89 171.39,14.49 168.94,12.03 165.53,12.03 164.64,11.14 163.7,11.14 158.7,6.14 156.45,6.14 153.74,3.42 153.1,2.79 131.89,2.79 131.22,3.45 129.54,3.45 129.32,3.23 95.92,3.23 95.72,3.42 94.71,3.42 94.16,2.86 77.35,2.86 69.92,10.29 63.98,10.29 62.94,9.25 v2(62.79,9.25)
  BOTTOM w0.102: v1(174.01,32.36) 174.36,32.36 v2(174.55,32.18) ; v2(41.09,87.83) 40.71,87.44 RN5201.6
BLON_OUT_C: length 26.5
  TOP w0.102: AFTP5205.1 36.8,82.21 36.8,82.98 36.95,83.13 LCD1.21 36.95,84.32 37.46,84.83 37.46,86.74 v2(38.3,87.57) ; RN5203.7 45.92,75.6 45.72,75.81 45.72,76.52 v2(45.29,76.95)
  L4 w0.102: v2(38.3,87.57) 39.01,88.28 42.04,88.28 43.25,87.06 43.25,85.79 44.92,84.13 44.92,77.32 v2(45.29,76.95)
  BOTTOM w0.102: v2(38.3,87.57) 38.43,87.44 38.55,87.44 38.56,87.44 RN5201.3
BLUETOOTH_EN: length 157.7
  TOP w0.102: v2(186.84,26.33) 188.41,26.33 188.83,25.91 R5806.2 R5805.1 ; v2(104.75,78.7) 105.21,79.16 v1(107.87,79.16) 111.65,79.16 113.86,76.95 v2(119.07,76.95)
  L3 w0.102: v2(164.67,6.29) 164.09,6.29 164.08,6.28 163.22,6.28 162.7,6.8 160.2,6.8 159.13,7.87 158.77,7.87 157.93,7.03 153.05,7.03 152.65,7.42 148.04,7.42 145.89,9.57 144.22,9.57 142.58,11.21 142.58,29.84 142.16,30.25 142.16,30.47 141.3,31.34 141.3,36.83 136.78,41.35 136.78,41.75 136.24,42.28 135.3,42.28 133.29,44.29 132.53,45.04 132.53,45.26 123.95,53.84 123.95,65.78 119.07,70.65 v2(119.07,76.95)
  L4 w0.102: v2(164.67,6.29) 165.58,5.38 171.24,5.38 180.82,14.96 180.82,19.06 182.9,21.14 183.47,21.14 184.69,22.36 184.69,24.19 v2(186.84,26.33)
  BOTTOM w0.102: CPU1.AP27 104.75,78.9 v2(104.75,78.7) ; v2(119.07,76.95) 118.07,76.95 R635.1
BOOST_MODE#: length 149.9
  TOP w0.203: 178.93,31.69 178.53,31.3 KBC24.20
  TOP w0.254: 178.93,31.69 181.43,31.69 v1(182.1,32.36) 183.03,33.29 184.46,33.29 v2(185.62,34.46) ; PR4418.1 145.63,124.83 PR4435.2 PR4439.2 147.66,124.72 148.79,123.59 v2(148.79,120.95)
  L4 w0.254: v2(185.62,34.46) 187.34,36.17 187.34,41.72 187.27,41.78 187.17,41.88 187.17,49.52 186.99,49.7 186.99,62.53 194.84,70.38 194.84,78.2 193.49,79.54 193.49,81.56 194.64,82.7 194.64,88.35 194.79,88.5 194.79,88.92 194.52,89.19 194.52,104.27 195.12,104.87 195.12,106.75 192.83,109.03 v2(191.21,109.03) ; v2(185.49,107.13) 178.13,107.13 174.95,110.3 170.89,110.3 169.75,111.45 167.08,111.45 166.9,111.27 164.51,111.27 163.5,110.25 162.02,110.25 161.12,111.15 159.87,111.15 155.84,115.19 153.08,115.19 152.33,115.93 152.33,115.96 148.84,119.45 148.84,120.9 v2(148.79,120.95)
  BOTTOM w0.254: v2(191.21,109.03) 187.4,109.03 v2(185.49,107.13)
BT+: length 15.4
  TOP w0.635: 138.52,156.08 BAT1.2 ; BAT1.2 139.88,154.72 ; BAT1.2 138.52,154.72 ; BAT1.2 139.88,156.08 ; 140.52,154.72 BAT1.1 ; BAT1.1 141.88,154.72 ; BAT1.1 140.52,156.08 ; BAT1.1 141.88,156.08
  BOTTOM w0.635: 138.52,156.08 BAT1.2 ; BAT1.2 138.52,154.72 ; BAT1.2 139.88,154.72 ; BAT1.2 139.88,156.08 ; BAT1.1 141.88,154.72 ; BAT1.1 140.52,156.08 ; BAT1.1 141.88,156.08 ; BAT1.1 140.52,154.72
  vias: v3(138.38,149.55) v3(138.38,148.66) v3(138.38,147.77) v3(138.38,146.88) v3(139.27,149.55) v3(139.27,148.66) v3(139.27,147.77) v3(139.27,146.88) v3(140.15,154.37) v3(140.15,153.48) v3(142.19,154.37) v3(142.19,153.48)
BT+_R:
  vias: v1(126.31,142.82)
BT_ACT: length 21.5
  TOP w0.14: R5806.1 187.75,26.8 v1(184.9,29.65) v2(183.14,31.41)
  L4 w0.127: v2(186.82,40.88) 186.79,40.88 185.72,39.8 185.72,36.91 184.54,35.73 184.54,34.39 183.67,33.51 183.67,31.94 v2(183.14,31.41)
  BOTTOM w0.14: v2(186.82,40.88) 186.84,40.9 WLAN1.5
BYPASSCLK_H: length 6.2
  BOTTOM w0.102: CPU1.B24 87.08,80.9 86.78,81.2 86.48,81.2 86.18,80.9 83.19,80.9 82.8,80.51 v1(82.78,80.51) 82.75,80.51 82.45,80.21 R419.1
BYPASSCLK_L: length 6.3
  BOTTOM w0.102: R420.1 81.86,79.32 81.94,79.39 v1(82.28,79.39) 82.29,79.4 82.33,79.4 83.58,80.65 86.4,80.65 CPU1.A24
CAM1_MIC_GND: length 3.1
  TOP w0.508: CCD1.5 18.9,87.63 18.65,87.38 v2(18.67,87.34)
  BOTTOM w0.508: R5207.1 18.88,87.34 v2(18.67,87.34) 18.26,87.34 v1(17.6,86.68)
CAP_LED: length 56.6
  TOP w0.102: KB1.4 190.34,103.06 191.23,103.95 v2(191.23,108.29) 191.79,108.85 191.79,111.68 194.57,114.46 194.57,126.65 199.02,131.1 KB2.4 ; v2(194.28,88.71) 193.96,88.71 193.75,88.5 R6201.2
  L4 w0.102: v2(191.23,108.29) 191.23,108.01 194.08,105.16 194.08,88.92 v2(194.28,88.71)
  BOTTOM w0.102: v2(191.23,108.29) v1(191.23,107.73)
CAP_LED#: length 75
  TOP w0.102: v2(168.04,25.04) 168.49,24.59 KBC24.109 ; v2(176.6,37.53) 176.71,37.63 176.71,40.76 178.13,42.18 v1(178.13,43.86) 178.13,46.04 186.12,54.03 186.12,59.7 187.06,60.65 187.06,65.64 186.28,66.42 186.28,75.48 189.58,78.78 189.58,79.85 191.51,81.78 191.51,81.88 192.91,83.28 192.91,84.51 R6202.1
  L4 w0.102: v2(168.04,25.04) 170.2,27.2 170.2,31.54 171.19,32.53 171.19,32.67 176.06,37.53 v2(176.6,37.53)
CAP_LED_Q: length 4.2
  TOP w0.102: v1(196.03,89.53) Q6201.3 195.23,87.13 R6201.1
CAP_LED_R#: length 3.7
  TOP w0.102: R6202.2 194.47,86.24 Q6201.2 195.45,85.69 v1(196.7,84.45)
CARD_WLAN_OUT#: length 6.2
  TOP w0.102: v2(165.81,30.8) 165.38,31.23 164.99,31.23 164.54,30.78 164.54,30.29 163.14,28.9 KBC24.83
  BOTTOM w0.102: v2(165.81,30.8) TP2401.1
CARD_WPAN_OUT#: length 7.4
  TOP w0.102: KBC24.100 164.89,23.41 165.22,23.74 165.22,24.68 166.18,25.63 166.18,27.23 166.7,27.75 v2(166.7,28.19)
  BOTTOM w0.102: v2(166.7,28.19) TP2402.1
CASA0#: length 35.1
  TOP w0.14: VRAM1.K3 157.09,144.29 157.09,144.82 156.73,145.19 156.73,145.8 v2(156.9,145.98)
  L4 w0.165: 161.93,144.48 161.66,144.75 161.66,145.21 161.98,145.52 161.98,145.88 161.08,146.78 157.71,146.78 157.08,146.15 v2(156.9,145.98)
  L4 w0.267: 161.93,144.48 164.01,142.41 164.01,141.43 164.22,141.21 164.22,132.28 164.13,132.2 164.13,129.16 164.17,129.12 164.17,127.7 163.05,126.59 163.05,124.86 v2(162.57,124.38)
  BOTTOM w0.14: v2(156.9,145.98) 157.09,145.79 157.44,145.79 157.55,145.9 157.55,146.17 157.33,146.4 157.33,146.65 157.45,146.77 157.56,146.77 157.58,146.79 VRAM2.K3
  BOTTOM w0.279: v2(162.57,124.38) 162.74,124.38 163.2,124.84 GPU1.G19
CASA1#: length 39.2
  TOP w0.14: v2(178.84,144.97) 178.59,145.23 178.59,146.19 VRAM3.K3
  L4 w0.267: v2(166.22,125.03) 166.24,125.05 166.24,126.51 166.85,127.12 166.85,128.16 166.24,128.77 166.24,131.69 165.76,132.17 165.76,132.94 166.04,133.21 166.62,133.21 166.9,133.49 166.9,134.21 166.62,134.48 166.06,134.48 165.78,134.76 165.78,135.46 166.06,135.74 169.52,135.74 169.8,136.02 169.8,138.7 172.01,140.91 173.77,140.91 174.08,141.22 174.08,142.4 176.27,144.59 176.27,144.99 176.27,145 176.27,145.46 176.11,145.62 176.11,146.03 176.4,146.31 177.99,146.31 178.5,145.8 178.5,145.32 v2(178.84,144.97)
  BOTTOM w0.14: VRAM4.K3 178.19,143.59 178.21,143.61 178.32,143.61 178.84,144.14 v2(178.84,144.97)
  BOTTOM w0.279: v2(166.22,125.03) 165.88,125.03 GPU1.G16
CBN: length 3
  TOP w0.203: 31.81,8.72 32.03,8.94 HDA27.35
  TOP w0.254: 31.81,8.72 31.8,8.7 v1(30.98,7.89) 30.86,7.77 C2703.1
CBP: length 4.3
  TOP w0.203: HDA27.37 33.12,7.71
  TOP w0.254: 33.12,7.71 32.86,7.71 31.25,6.1 C2703.2 30.31,6.1 v1(29.94,6.47)
CEDAR_JANUS_ID: length 6.9
  BOTTOM w0.102: CPU1.AY21 108.41,82.34 108.64,82.34 108.92,82.06 109.22,82.06 109.85,81.42 112.8,81.42 113.36,81.98 R640.2 R639.1
CHARGER_SRC:
  vias: v1(127.33,124.02) v1(127.96,126.43) v1(128.22,126.56) v3(128.34,125.16) v3(128.34,124.27) v3(128.34,123.39)
CHG_AGND: length 5.2
  TOP w0.381: PR4423.2 145.41,122.93 v2(145.49,122.85)
  TOP w0.508: v2(136.85,119.32) 136.47,119.32 135.81,118.66 PC4010.2
  BOTTOM w0.305: PQ4407.1 143.35,117.05 143.08,116.78 143.08,116.02 142.81,115.75 PQ4407.4
  vias: v1(142.31,118.81) v1(144.35,123.51) v2(139.27,122.17) v2(139.98,122.88) v2(140,122.17) v2(139.98,121.48) v2(140.66,122.17)
CHG_AMBER_LED#: length 18.6
  TOP w0.102: KBC24.16 176.08,29.7 175.38,30.4 175.38,30.9 175.01,31.28 174.02,31.28 173.7,30.96 173.7,26.25 177.88,22.07 v1(177.88,20.29) 177.45,19.87 R6104.2
CHG_AMBER_LED_R#: length 2.3
  TOP w0.102: v1(177.82,19.05) 177.75,18.98 R6104.1 176.21,18.98 Q6104.2
CKEA0: length 38.8
  TOP w0.14: v2(157.15,145.36) 157.43,145.36 157.69,145.62 157.69,145.99 158.17,146.47 158.17,147.76 157.81,148.11 157.81,148.17 157.79,148.2 VRAM1.K9
  TOP w0.279: v1(162.1,123.23) v2(161.69,122.83)
  L4 w0.165: 161.06,144.68 160.53,145.21 160.53,145.46 160.25,145.74 160.25,145.82 159.55,146.52 157.82,146.52 157.34,146.04 157.34,145.55 v2(157.15,145.36) ; 161.66,126.52 161.51,126.38 161.51,125.92 162.09,125.34 162.09,123.22 v2(161.69,122.83)
  L4 w0.267: 161.06,144.68 162.54,143.2 162.54,142.23 163.75,141.02 163.75,132.48 163.01,131.74 163.01,128.4 161.66,127.04 161.66,126.52
  BOTTOM w0.14: VRAM2.K9 157.79,142.19 157.91,142.31 157.91,142.32 158.14,142.55 158.14,143.73 157.93,143.94 157.78,143.94 157.15,144.57 v2(157.15,145.36)
  BOTTOM w0.279: GPU1.K20 162.09,122.45 161.71,122.83 v2(161.69,122.83)
CKEA1: length 41.3
  TOP w0.14: VRAM3.K9 177.99,142.22 177.64,142.57 177.64,142.83 177.45,143.02 177.45,143.24 177.64,143.42 177.64,143.63 177.45,143.82 177.39,143.88 177.39,144.11 177.53,144.25 177.92,144.25 178,144.17 v2(178.27,144.17)
  L4 w0.165: 169.37,125.01 169.35,124.99 169.35,122.86 169.06,122.57 169.06,122.05 168.78,121.78 166.72,121.78 166.44,121.5 165.8,121.5 165.54,121.76 165.54,122.12 165.59,122.17 165.59,123.14 165.33,123.39 165.33,123.39 v2(165.13,123.59)
  L4 w0.267: v2(178.27,144.17) 177.29,143.18 177.29,140.93 175.27,138.92 175.09,138.92 170.74,134.57 170.74,130.5 169.55,129.31 169.55,128.54 170.1,127.98 170.1,127.55 169.55,126.99 169.55,125.6 169.37,125.42 169.37,125.01
  BOTTOM w0.14: v2(178.27,144.17) 178.34,144.24 178.34,145.86 177.64,146.57 177.64,147.84 177.99,148.19 VRAM4.K9
  BOTTOM w0.279: GPU1.J17 164.84,123.59 v2(165.13,123.59)
CLK_LAN_REQ0#_R: length 9.6
  TOP w0.102: v1(44.17,43.31) R3005.2 R3004.2 42.35,41.52 Q3002.E 40.54,41.52 40.41,41.65 40.41,42.38 40.1,42.69 40.1,43.86 39.57,44.39 v2(39.04,44.39)
  BOTTOM w0.102: LOM30.12 38.88,44.55 v2(39.04,44.39)
CLK_LAN_REQ#_EN: length 2.7
  TOP w0.127: Q3002.B 39.14,41.52 38.62,42.04 R3003.2 38.3,42.77 v1(38.12,42.94)
CLK_MINI1#_R: length 8.8
  L4 w0.114: v2(99.39,96.97) 99.57,96.79 99.57,96.39 99.92,96.03 99.92,91.89 v2(100.38,91.43)
  BOTTOM w0.127: v2(99.39,96.97) 99.32,97.04 RN1902.4 98.41,97.89 v1(98.24,97.73) ; CPU1.AE5 100.28,91.43 v2(100.38,91.43)
CLK_MINI1_R: length 7.8
  L4 w0.114: v2(100.02,96.97) 99.79,96.74 99.79,96.48 100.15,96.13 100.15,92.35 v2(100.38,92.13)
  BOTTOM w0.127: CPU1.AE4 100,91.75 v2(100.38,92.13) ; v2(100.02,96.97) 99.97,97.02 RN1902.3 100.88,97.89 v1(100.91,97.86)
CLK_PCI_KBC: length 281.9
  TOP w0.102: KBC24.2 176.52,24.1 175.59,25.03 175.59,25.03 v2(175.41,25.21)
  L3 w0.102: v2(186,46.6) 186,46.6 185.24,47.36 185.24,48.81 185.8,49.37 185.8,59.91 194.97,69.08 194.97,79.34 195.86,80.23 195.86,82.39 194.36,83.89 194.36,87.75 195.3,88.69 195.3,134.41 190.55,139.16 190.55,147.39 189.27,148.67 189.27,150.94 188.44,151.76 188.44,152.35 186.62,154.17 173.02,154.17 169.24,150.39 166.06,150.39 163.14,153.31 148.18,153.31 145.75,150.87 142.53,150.87 141.76,150.09 141.76,142.14 143.3,140.59 143.3,138.73 142.52,137.94 142.52,133.77 144.47,131.82 144.47,130.93 145.57,129.84 145.57,126.15 149.22,122.49 149.22,114.32 146,111.09 143.76,111.09 141.17,108.5 132.56,108.5 123.49,99.43 117.93,99.43 117.47,98.98 117.29,98.98 116.79,98.47 116.79,97.35 115.64,96.21 v2(115.64,93.29)
  L4 w0.102: v2(175.41,25.21) 175.41,26.43 174.79,27.05 174.79,28.45 178.47,32.13 178.47,33.56 183.21,38.3 183.21,44.03 184.96,45.79 184.96,46.14 185.42,46.6 v2(186,46.6)
  BOTTOM w0.102: R1906.2 115.14,95.06 v1(115.52,94.68) 115.64,94.56 v2(115.64,93.29)
CLK_PCI_LPC: length 282.7
  L3 w0.102: v2(135.01,98.55) 135.22,98.55 135.38,98.39 135.38,97.48 135.01,97.11 135.01,90.03 135.11,89.93 136.1,89.93 136.22,89.81 136.22,89.64 136.1,89.52 135.11,89.52 135.01,89.42 135.01,89.22 135.11,89.12 136.23,89.12 136.34,89 136.34,88.83 136.23,88.71 135.11,88.71 135.01,88.61 135.01,88.41 135.11,88.3 135.74,88.3 135.84,88.2 135.84,88 135.74,87.9 135.11,87.9 135.01,87.8 135.01,86.83 135.23,86.62 135.37,86.62 137.15,88.4 137.3,88.4 137.44,88.25 137.44,88.11 135.66,86.33 135.66,86.18 135.8,86.04 135.94,86.04 137.73,87.82 137.87,87.82 138.01,87.68 138.01,87.54 136.23,85.75 136.23,85.61 136.38,85.47 136.52,85.47 138.3,87.25 138.45,87.25 138.59,87.1 138.59,86.96 136.81,85.18 136.81,85.03 136.95,84.89 137.09,84.89 138.88,86.67 139.02,86.67 139.16,86.53 139.16,86.39 137.38,84.6 137.38,84.46 139.2,82.64 139.2,80.68 137.96,79.44 137.65,79.44 136.98,78.77 136.98,72.76 135.28,71.05 135.28,70.75 135.38,70.65 136.88,70.65 136.98,70.55 136.98,70.34 136.88,70.24 135.38,70.24 135.28,70.14 135.28,69.94 135.38,69.83 136.88,69.83 136.98,69.73 136.98,69.53 136.88,69.43 135.38,69.43 135.28,69.33 135.28,69.12 135.38,69.02 136.88,69.02 136.98,68.92 136.98,68.72 136.88,68.62 135.38,68.62 135.28,68.51 135.28,68.31 135.38,68.21 136.88,68.21 136.98,68.11 136.98,67.9 136.88,67.8 135.38,67.8 135.28,67.7 135.28,64.55 136.04,63.79 136.04,62.25 136.14,62.15 137.01,62.15 137.11,62.04 137.11,61.84 137.01,61.74 136.14,61.74 136.04,61.64 136.04,61.43 136.14,61.33 137.24,61.33 137.36,61.21 137.36,61.05 137.24,60.93 136.14,60.93 136.04,60.83 136.04,60.62 136.14,60.52 137.24,60.52 137.36,60.4 137.36,60.23 137.24,60.11 136.14,60.11 136.04,60.01 136.04,59.81 136.14,59.71 137.24,59.71 137.36,59.59 137.36,59.42 137.24,59.3 136.14,59.3 136.04,59.2 136.04,58.55 136.57,58.02 136.71,58.02 137.01,58.32 137.15,58.32 137.29,58.17 137.29,58.03 137.13,57.87 137.13,57.68 145.34,49.47 145.34,48.95 145.24,48.84 144.32,48.84 144.22,48.74 144.22,48.54 144.32,48.44 145.24,48.44 145.34,48.34 145.34,48.13 145.24,48.03 144.32,48.03 144.22,47.93 144.22,47.73 144.32,47.63 145.24,47.63 145.34,47.52 145.34,46.72 145.55,46.5 145.55,46.36 144.99,45.8 144.99,45.65 145.13,45.51 145.28,45.51 145.84,46.07 145.99,46.07 146.13,45.93 146.13,45.79 145.56,45.22 145.56,45.08 145.71,44.93 145.85,44.93 146.42,45.5 146.56,45.5 146.7,45.35 146.7,45.21 146.14,44.65 146.14,44.5 146.28,44.36 146.43,44.36 146.99,44.92 147.14,44.92 147.28,44.78 147.28,44.64 146.71,44.07 146.71,43.93 146.86,43.78 147,43.78 147.57,44.35 147.71,44.35 147.85,44.2 147.85,44.06 147.29,43.5 147.29,43.35 147.43,43.21 147.58,43.21 148.14,43.77 148.29,43.77 148.43,43.63 148.43,43.49 147.86,42.92 147.86,42.78 148.01,42.63 148.15,42.63 148.72,43.2 148.86,43.2 150.82,41.24 150.82,39.43 151.52,38.73 151.52,38.59 151.14,38.21 151.14,38.06 151.28,37.92 151.42,37.92 151.81,38.3 151.95,38.3 152.09,38.16 152.09,38.01 151.71,37.63 151.71,37.49 151.86,37.35 152,37.35 152.38,37.73 152.52,37.73 153.25,37 153.25,36.7 153.15,36.6 152.44,36.6 152.33,36.49 152.33,36.29 152.44,36.19 153.15,36.19 153.25,36.09 153.25,35.88 153.15,35.78 152.44,35.78 152.33,35.68 152.33,35.48 152.44,35.38 153.15,35.38 153.25,35.27 153.25,33.11 153.9,32.46 153.9,29.88 158.3,25.48 158.3,25.33 157.76,24.79 157.76,24.63 157.88,24.51 158.05,24.51 158.58,25.04 158.75,25.04 158.87,24.92 158.87,24.75 157.38,23.27 157.38,23.1 157.6,22.88 157.74,22.88 158.48,23.62 158.64,23.62 158.76,23.5 158.76,23.33 158.03,22.59 158.03,22.45 158.32,22.16 158.93,22.16 159.03,22.06 159.03,21.25 159.13,21.15 159.33,21.15 159.43,21.25 159.43,22.06 159.54,22.16 160.16,22.16 160.26,22.06 160.26,21.76 160.36,21.66 160.56,21.66 160.67,21.76 160.67,22.06 160.77,22.16 160.97,22.16 161.07,22.06 161.07,21.27 161.19,21.15 161.36,21.15 161.48,21.27 161.48,22.06 161.58,22.16 161.78,22.16 161.89,22.06 161.89,21.65 162,21.53 162.17,21.53 162.29,21.65 162.29,22.06 162.39,22.16 162.6,22.16 162.7,22.06 162.7,21.52 162.82,21.4 162.99,21.4 163.1,21.52 163.1,22.06 163.21,22.16 163.51,22.16 163.61,22.06 163.61,21.4 163.73,21.28 163.9,21.28 164.02,21.4 164.02,22.93 163.89,23.06 163.27,23.06 163.17,22.95 163.17,22.67 163.07,22.57 162.76,22.57 162.66,22.67 162.66,24.48 162.56,24.58 162.35,24.58 162.25,24.48 162.25,22.67 162.15,22.57 161.95,22.57 161.85,22.67 161.85,24.48 161.74,24.58 161.54,24.58 161.44,24.48 161.44,22.67 161.34,22.57 160.6,22.57 160.5,22.67 160.5,22.95 160.4,23.06 160.2,23.06 160.09,22.95 160.09,22.67 159.99,22.57 159.69,22.57 159.59,22.67 v2(159.59,23.69)
  L4 w0.102: v2(135.01,98.55) 135.01,97.86 134.88,97.73 134.51,97.73 133.89,98.35 133.89,98.49 133.98,98.58 133.98,98.72 133.84,98.87 133.69,98.87 133.61,98.78 133.46,98.78 133.32,98.92 133.32,99.07 133.41,99.16 133.41,99.3 133.26,99.44 133.12,99.44 133.03,99.36 132.89,99.36 132.74,99.5 132.74,99.64 132.83,99.73 132.83,99.87 132.69,100.02 132.54,100.02 132.46,99.93 132.31,99.93 132.17,100.07 132.17,100.22 132.26,100.31 132.26,100.45 132.11,100.59 131.97,100.59 131.88,100.51 131.74,100.51 131.59,100.65 131.59,100.79 131.68,100.88 131.68,101.02 131.54,101.17 131.39,101.17 131.31,101.08 131.16,101.08 130.94,101.3 116.9,101.3 v2(116.79,101.41)
  BOTTOM w0.102: DB1.9 155.97,14.27 155.97,15.66 155.27,16.37 155.27,16.62 155.39,16.75 158.76,16.75 158.87,16.65 158.87,15.68 158.99,15.56 159.15,15.56 159.27,15.68 159.27,16.65 159.37,16.75 159.87,16.75 159.97,16.85 159.97,17.05 159.87,17.16 155.39,17.16 155.27,17.28 155.27,17.44 155.39,17.56 163.53,17.56 163.65,17.68 163.65,17.85 163.53,17.97 155.51,17.97 155.39,18.09 155.39,18.26 155.51,18.38 163.15,18.38 163.27,18.49 163.27,18.66 163.15,18.78 162.51,18.78 162.41,18.88 162.41,19.63 162.29,19.75 162.12,19.75 162,19.63 162,18.88 161.9,18.78 161.6,18.78 161.49,18.88 161.49,20.16 161.39,20.26 161.19,20.26 161.09,20.16 161.09,18.88 160.99,18.78 160.68,18.78 160.58,18.88 160.58,20.16 160.48,20.26 160.28,20.26 160.17,20.16 160.17,18.88 160.07,18.78 159.87,18.78 159.77,18.88 159.77,20.16 159.67,20.26 159.46,20.26 159.36,20.16 159.36,18.88 159.26,18.78 158.12,18.78 158.02,18.88 158.02,19.38 157.9,19.5 157.73,19.5 157.61,19.38 157.61,18.88 157.51,18.78 157.31,18.78 157.21,18.88 157.21,19.27 157.11,19.37 156.9,19.37 156.8,19.27 156.8,18.88 156.7,18.78 156.07,18.78 155.97,18.88 155.97,19.19 157.68,20.9 157.68,21.79 v1(158.5,22.61) v2(159.59,23.69) ; R1907.2 116.6,101.41 v2(116.79,101.41)
CLK_PCIE_LAN_N0: length 63.6
  L4 w0.114: v2(39.57,42.61) 38.55,43.63 38.55,49.34 42.23,53.01 42.73,53.01 44.14,54.42 44.65,54.42 v2(44.9,54.17)
  BOTTOM w0.127: LOM30.16 38.17,42.61 38.61,42.17 39.13,42.17 v2(39.57,42.61) ; v1(61.8,59.96) 61.68,60.08 ; 61.68,60.08 60.49,58.88 54.42,58.88 53.52,57.98 52.02,57.98 51.46,57.42 51.46,56.97 51.14,56.65 51.14,56.16 52.14,55.15 52.14,53.79 50.37,52.01 48.25,52.01 45.96,54.3 45.03,54.3 v2(44.9,54.17) ; 61.68,60.08 63.8,62.2 63.8,67.36 63.29,67.87 63.29,71 67.5,75.2 67.5,76.14 67.94,76.58 RN1903.1
CLK_PCIE_LAN_N0_R: length 36.8
  TOP w0.127: v2(72.46,76.57) 72.46,76.34 v1(72.16,76.04)
  L4 w0.114: v2(72.46,76.57) 72.9,76.13 77,76.13 77.52,76.66 80.67,76.66 83.2,79.19 91.69,79.19 92.24,79.74 92.24,80.24 93.31,81.3 94.37,81.3 94.99,81.93 94.99,82.9 95.83,83.74 95.83,86.01 98.15,88.32 v2(98.15,88.75)
  BOTTOM w0.127: RN1903.4 71.15,76.58 71.55,76.98 72.05,76.98 v2(72.46,76.57) ; v2(98.15,88.75) 98.5,88.75 CPU1.AC10
CLK_PCIE_LAN_P0: length 63.3
  L4 w0.114: v2(44.9,54.81) 44.75,54.65 44.05,54.65 42.64,53.24 42.14,53.24 38.33,49.43 38.33,43.53 38.94,42.92 v2(38.94,42.61)
  BOTTOM w0.127: v2(44.9,54.81) 45.17,54.54 46.06,54.54 48.35,52.25 50.27,52.25 51.9,53.89 51.9,55.05 50.9,56.06 50.9,56.75 51.22,57.07 51.22,57.52 51.92,58.22 53.42,58.22 54.32,59.12 60.39,59.12 62.96,61.69 ; 62.96,61.69 v1(62.84,61.82) ; 62.96,61.69 63.56,62.3 63.56,67.26 63.05,67.77 63.05,71.1 67.26,75.3 67.26,76.24 67.84,76.82 68.87,76.82 69,76.95 69,77.02 69.21,77.23 RN1903.2 ; v2(38.94,42.61) 38.94,43.01 38.6,43.35 LOM30.15
CLK_PCIE_LAN_P0_R: length 37.2
  TOP w0.127: v1(73.61,76.24) 73.43,76.24 v2(73.1,76.57)
  L4 w0.114: v2(73.1,76.57) 73.31,76.36 76.91,76.36 77.43,76.88 80.57,76.88 83.11,79.42 91.6,79.42 92.02,79.84 92.02,80.33 93.22,81.53 94.27,81.53 94.77,82.02 94.77,82.99 95.6,83.83 95.6,86.1 97.71,88.21 97.71,89.14 v2(98.14,89.58)
  BOTTOM w0.127: v2(98.14,89.58) 98.37,89.35 CPU1.AC8 ; v2(73.1,76.57) 73.09,76.57 72.44,77.23 70.78,77.23 RN1903.3
CLK_PCIE_LAN_REQ0#: length 234.3
  TOP w0.102: v2(43.48,40.43) 43.59,40.43 v1(43.93,40.77) 44.6,41.44 44.6,43.68 44.08,44.2 R3005.1 42.84,44.2 42.78,44.14 41.15,44.14 Q3002.C
  L4 w0.102: v2(43.48,40.43) 42.47,39.41 42.47,25.17 43.69,23.95 43.69,21.26 51.57,13.38 51.85,13.38 52.3,12.93 52.3,12.72 53.92,11.09 54.63,11.09 56.97,13.43 56.97,14.23 59.75,17.01 62.47,17.01 63.02,17.56 71.05,17.56 80.08,8.53 104.67,8.53 104.84,8.35 105.62,8.35 106.57,9.3 113.69,9.3 114.5,8.49 129.14,8.49 130.67,10.02 139.97,10.02 143.1,13.15 143.1,30.89 140.12,33.88 140.12,40.93 137.88,43.17 128.88,52.18 128.88,61.32 128.42,61.78 128.42,73.94 124.95,77.41 116.02,77.41 114.75,78.68 107.83,78.68 107.38,79.13 107.02,79.13 106.77,78.88 106.77,78.01 v2(106.44,77.68)
  BOTTOM w0.102: CPU1.AU29 106.44,77.71 v2(106.44,77.68)
CLK_PCIE_VGA: length 63.9
  BOTTOM w0.127: RN1905.2 97.05,100.03 97.14,100.13 98.72,100.13 100.52,101.92 100.52,104.11 100.68,104.27 124.72,104.27 128.22,107.76 149.71,107.76 ; 149.71,107.76 152.47,107.76 153.37,106.87 154.44,106.87 154.81,107.24 GPU1.AK30 ; 149.71,107.76 v1(149.71,107.61)
CLK_PCIE_VGA#: length 63.6
  BOTTOM w0.127: v1(151.23,108.17) 151.23,108.01 ; 151.23,108.01 128.12,108.01 124.62,104.51 100.58,104.51 100.28,104.21 100.28,102.02 98.62,100.37 97.04,100.37 96.4,99.72 RN1905.1 ; 151.23,108.01 152.57,108.01 153.47,107.11 154.16,107.11 GPU1.AK32
CLK_PCIE_WLAN_N1: length 176.3
  L4 w0.114: v2(99.52,100.03) 99.69,100.2 99.69,101.84 100.07,102.22 100.07,104.29 100.4,104.62 114.64,104.62 115.37,105.34 115.53,105.5 132.83,105.5 133.14,105.2 144.37,105.2 147.27,102.3 147.27,100.14 148.38,99.03 150.8,99.03 152.04,100.27 152.04,102.76 152.39,103.11 157.47,103.11 159.2,101.38 159.2,100.91 160.83,99.28 162.58,99.28 163.38,98.48 170.5,98.48 174.01,101.99 182.95,101.99 183.72,101.23 183.72,79.82 182.97,79.08 182.97,69.51 180.81,67.35 180.81,52.04 v2(180.14,51.38)
  BOTTOM w0.127: 192.31,39.51 192.31,44.54 189.53,47.31 188.67,47.31 184.47,51.52 180.28,51.52 v2(180.14,51.38) ; 192.31,39.51 v1(192.17,39.51) ; 192.31,39.51 192.31,39.14 191.67,38.5 WLAN1.11 ; v2(99.52,100.03) 99.32,99.83 RN1902.1
CLK_PCIE_WLAN_P1: length 177.2
  L4 w0.114: v2(180.14,52.01) 180.17,51.99 180.43,51.99 180.58,52.14 180.58,53.88 180.47,54 180.47,54.34 180.58,54.45 180.58,54.79 180.47,54.91 180.47,55.25 180.58,55.36 180.58,60.44 180.47,60.55 180.47,60.9 180.58,61.01 180.58,61.35 180.47,61.46 180.47,61.8 180.58,61.92 180.58,67.45 182.74,69.61 182.74,79.18 183.49,79.92 183.49,101.14 182.86,101.76 174.1,101.76 170.59,98.25 163.29,98.25 162.49,99.05 160.74,99.05 158.98,100.81 158.98,101.28 157.38,102.88 152.49,102.88 152.27,102.67 152.27,100.18 150.89,98.8 148.29,98.8 147.04,100.05 147.04,102.21 144.28,104.97 133.04,104.97 132.74,105.27 115.62,105.27 114.74,104.39 100.5,104.39 100.3,104.19 100.3,102.12 99.92,101.74 99.92,100.26 v2(100.16,100.03)
  BOTTOM w0.127: WLAN1.13 190.2,37.7 190.76,38.26 191.77,38.26 192.55,39.04 192.55,41.27 ; v2(100.16,100.03) 99.97,99.84 RN1902.2 ; v2(180.14,52.01) 180.4,51.76 180.83,51.76 180.94,51.87 181.32,51.87 181.43,51.76 181.81,51.76 181.93,51.87 182.31,51.87 182.42,51.76 182.8,51.76 182.91,51.87 183.29,51.87 183.4,51.76 184.57,51.76 186.68,49.64 186.84,49.64 187.11,49.37 187.11,49.22 187.38,48.95 187.53,48.95 187.8,48.68 187.8,48.52 188.07,48.25 188.23,48.25 188.5,47.98 188.5,47.82 188.77,47.55 189.63,47.55 192.55,44.64 192.55,44.25 192.66,44.14 192.66,43.76 192.55,43.65 192.55,43.27 192.66,43.16 192.66,42.78 192.55,42.66 192.55,41.27 ; 192.55,41.27 v1(192.71,41.27)
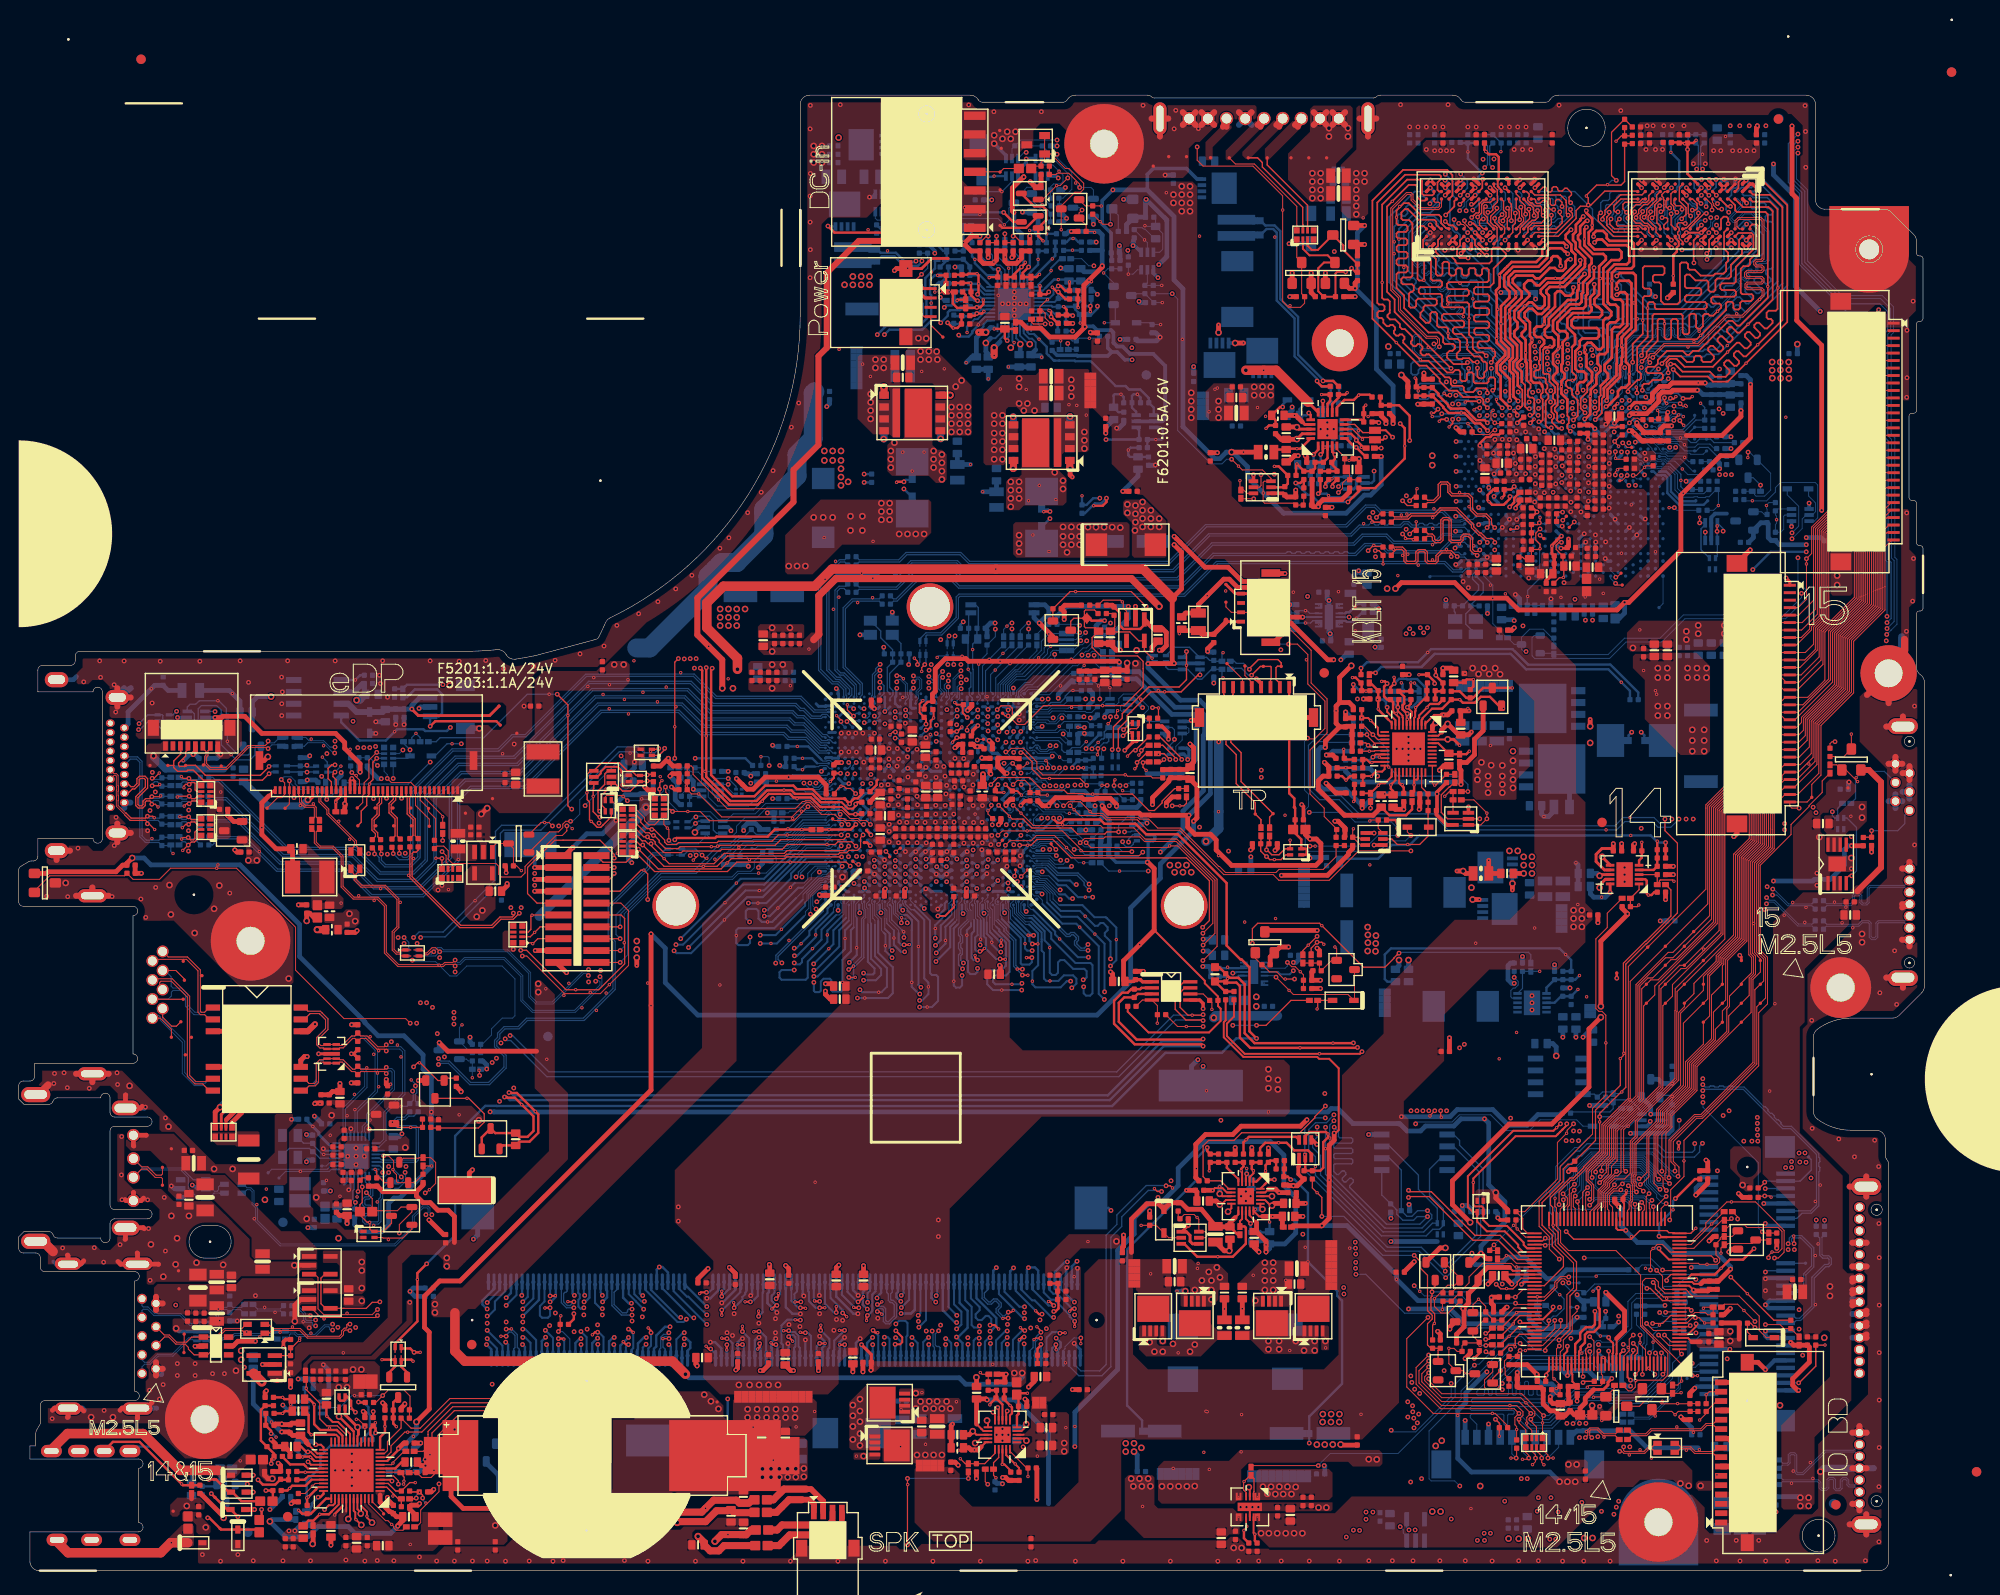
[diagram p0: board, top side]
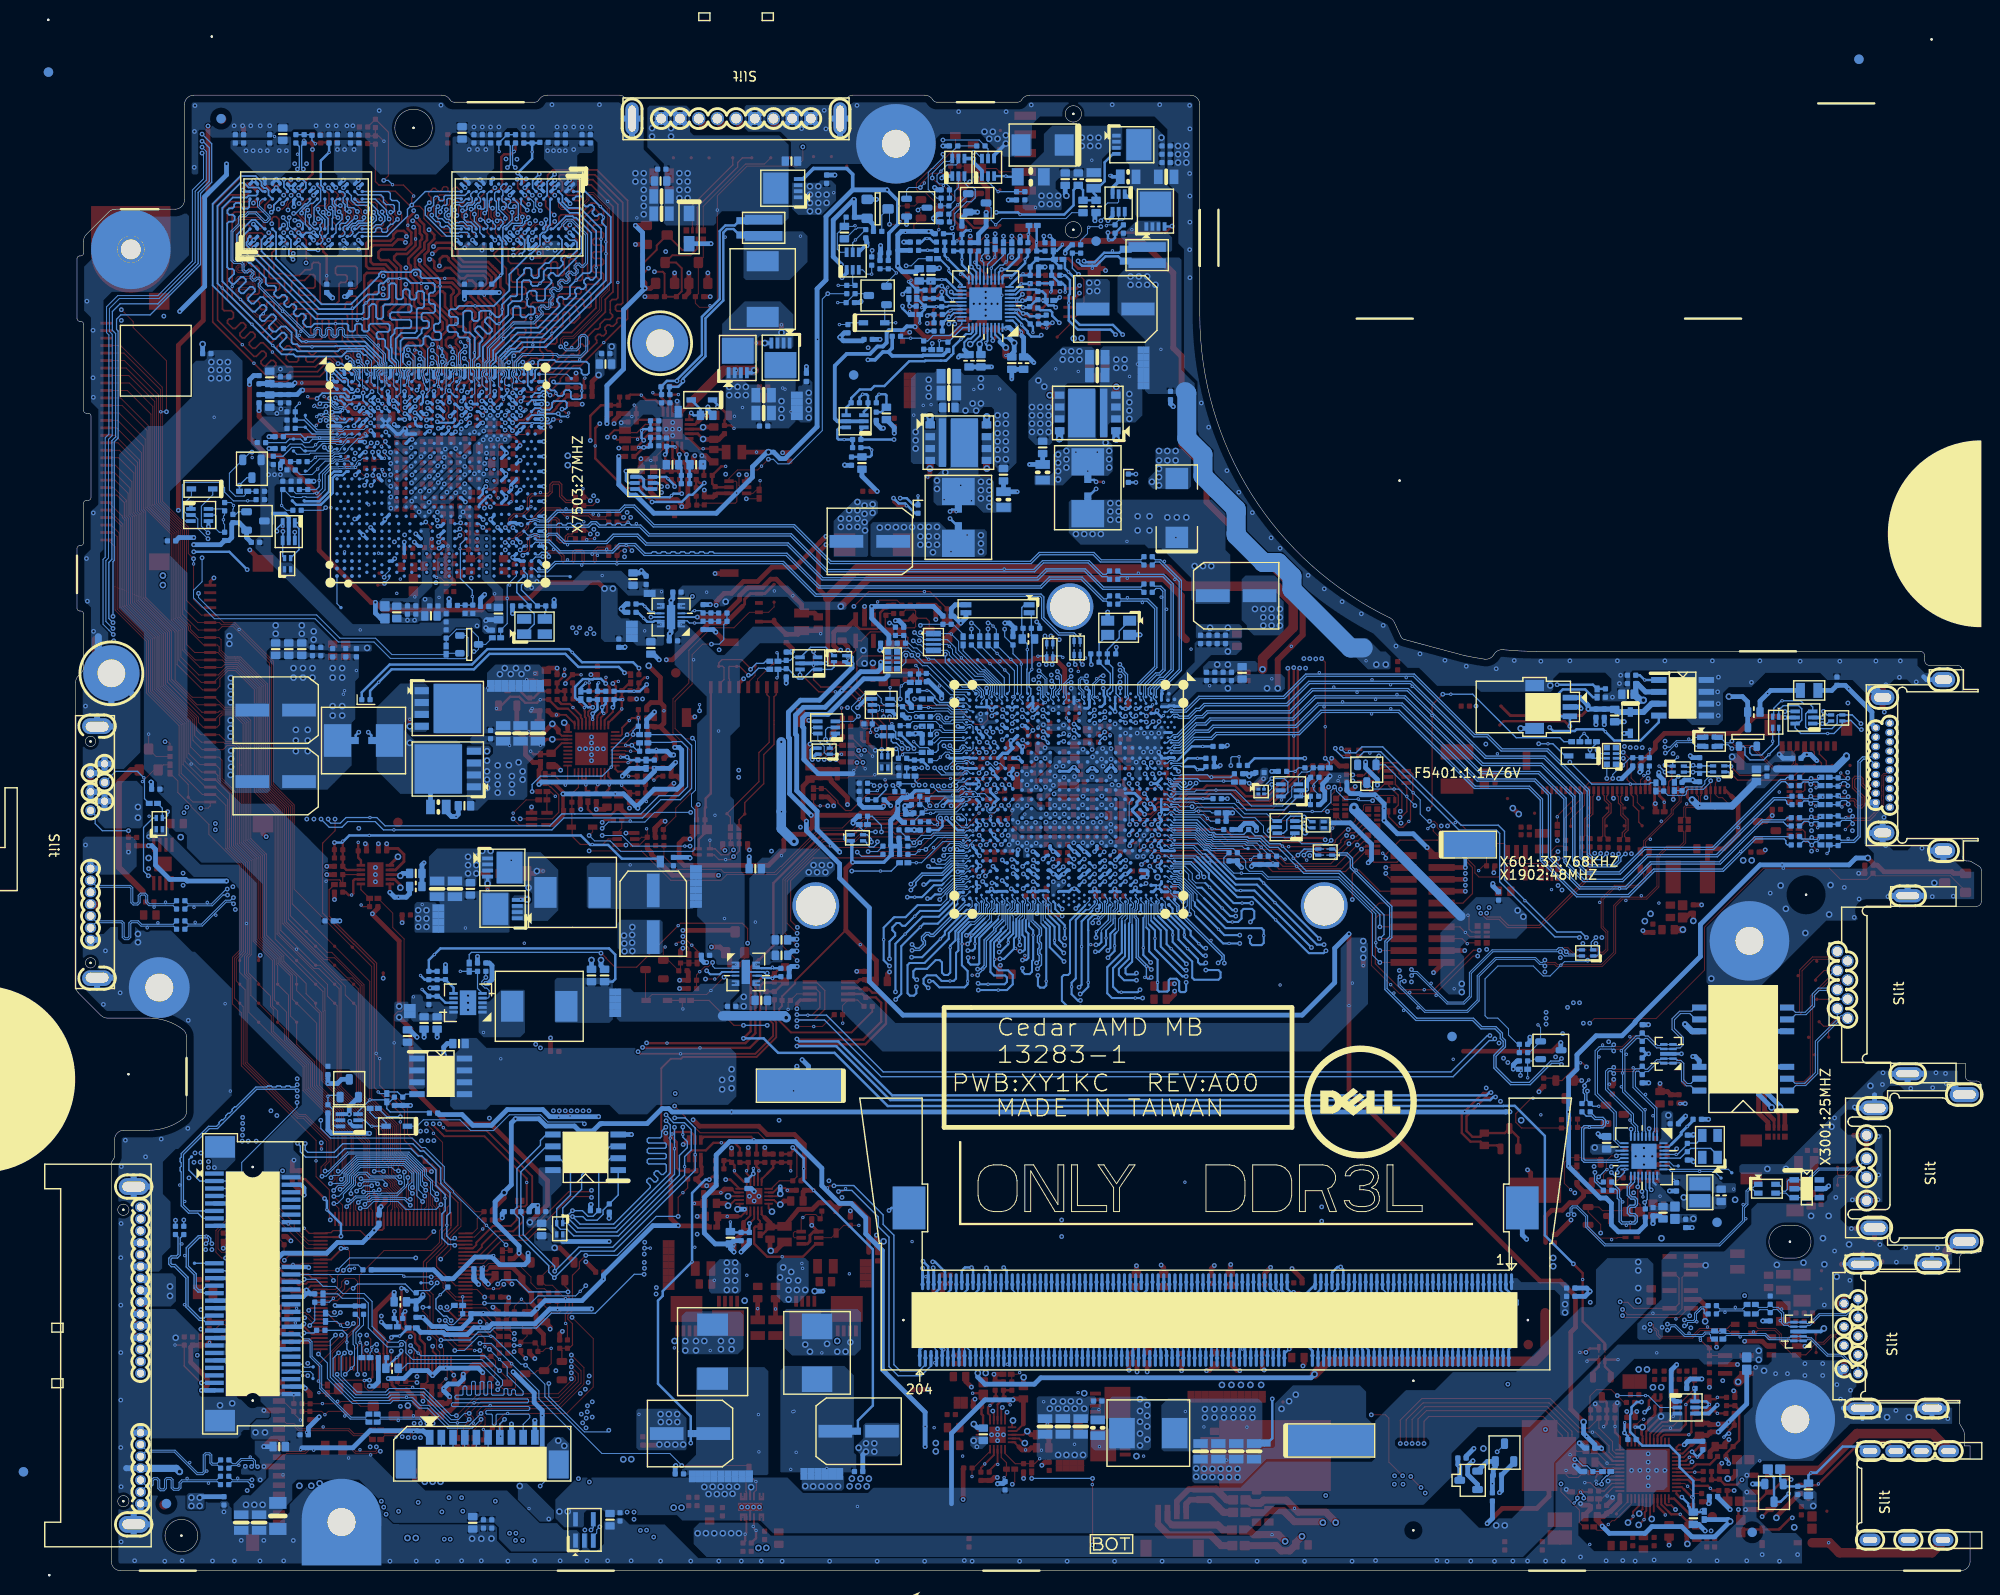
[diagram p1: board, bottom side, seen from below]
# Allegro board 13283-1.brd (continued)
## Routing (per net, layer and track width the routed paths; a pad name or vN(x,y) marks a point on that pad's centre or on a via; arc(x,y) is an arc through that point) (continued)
CLK_PCIE_WLAN_REQ1#: length 166.6
  TOP w0.102: R5808.2 186.19,40.07 186.74,40.07 v2(186.76,40.1) 187.32,40.1 v1(187.45,39.97)
  L3 w0.102: v2(110.28,77.18) 110.72,77.61 113.19,77.61 113.33,77.47 116.54,77.47 117.52,78.45 118.83,78.45 118.88,78.41 118.89,78.41 119.15,78.16 119.15,78.14 119.73,77.56 119.73,70.86 124.61,65.98 124.61,53.9 133.04,45.47 133.04,45.25 135.51,42.79 136.45,42.79 137.28,41.96 137.28,41.57 141.81,37.04 141.81,31.55 142.67,30.68 142.67,30.46 143.08,30.05 143.08,11.42 144.43,10.08 146.11,10.08 148.25,7.93 152.87,7.93 153.26,7.54 157.45,7.54 158.28,8.37 159.36,8.37 160.43,7.31 162.91,7.31 163.42,6.8 164.82,6.8 165.85,5.77 170.37,5.77 v2(170.63,6.04)
  L4 w0.102: v2(186.76,40.1) 186.75,40.1 186.24,39.59 186.24,36.69 185.06,35.52 185.06,34.17 184.62,33.73 184.62,30.59 180.41,26.38 180.41,25.83 178.51,23.93 178.01,23.93 177.44,23.36 177.44,22.45 177.55,22.34 177.55,16.91 176.74,16.11 176.74,12.83 172.22,8.31 171.41,8.31 170.46,7.36 170.46,6.21 v2(170.63,6.04)
  BOTTOM w0.102: CPU1.AW29 107.73,78.15 108.23,77.65 108.23,77.5 108.42,77.3 108.7,77.3 108.84,77.44 109.19,77.44 109.37,77.61 109.85,77.61 v2(110.28,77.18) ; WLAN1.7 v2(186.76,40.1)
CLKA0: length 46.8
  TOP w0.14: VRAM1.J7 156.88,146.68 156.64,146.68 156.25,146.28 156.25,146.26 156.24,146.26 156.24,145.39 156.14,145.3 155.88,145.3 155.63,145.05 155.63,145.03 v2(155.43,144.82)
  L4 w0.127: v2(156.82,150.16) 157.1,149.88 157.1,148.71 156.49,148.1 156.49,146.64 155.96,146.11 155.96,145.41 155.64,145.09 155.64,145.03 v2(155.43,144.82) 155.73,144.52 155.73,144.06 156.08,143.7 157.48,143.7 157.86,143.32 157.86,140.7 157.46,140.3 157.46,139.76 157.89,139.34 157.89,139.06 157.74,138.9 157.59,138.9 157.33,138.64 157.33,138.04 157.58,137.79 157.99,137.79 158.11,137.66 158.11,137.3 157.96,137.15 157.69,137.15 157.43,136.89 157.43,136.3 157.69,136.03 159.13,136.03 159.26,135.91 159.26,135.51 159.13,135.39 157.79,135.39 157.53,135.12 157.53,134.55 157.79,134.29 159.1,134.29 159.23,134.17 159.23,133.79 159.1,133.66 157.59,133.66 157.33,133.4 157.33,130.32 158.22,129.43 158.22,126.27 157.76,125.8 157.76,125.37 158.04,125.09 158.04,123.79 v2(157.89,123.64)
  BOTTOM w0.14: R7803.1 157.11,152.47 157.11,151.88 ; v2(157.89,123.64) 157.5,124.04 GPU1.H26 ; v2(156.82,150.16) 157.11,150.45 157.11,151.88 ; 157.11,151.88 v1(156.92,151.88) ; v2(155.43,144.82) 155.43,144.62 155.55,144.49 155.67,144.49 155.8,144.37 155.8,144.19 156.04,143.95 156.9,143.95 156.99,143.86 VRAM2.J7
CLKA0#: length 46.8
  TOP w0.14: VRAM1.K7 157.44,146.44 156.74,146.44 156.49,146.18 156.49,146.16 156.48,146.16 156.48,145.29 v2(156.06,144.87)
  L4 w0.127: v2(157.66,150.16) 157.33,149.83 157.33,148.62 156.72,148.01 156.72,146.54 156.18,146.01 156.18,145.31 156.06,145.19 v2(156.06,144.87) 155.95,144.76 155.95,144.16 156.18,143.93 157.58,143.93 158.09,143.42 158.09,140.6 157.69,140.21 157.69,139.86 158.12,139.43 158.12,138.96 157.83,138.68 157.68,138.68 157.55,138.55 157.55,138.14 157.67,138.02 158.08,138.02 158.34,137.75 158.34,137.21 158.06,136.92 157.78,136.92 157.66,136.8 157.66,136.39 157.78,136.26 159.22,136.26 159.48,136 159.48,135.42 159.22,135.16 157.88,135.16 157.76,135.03 157.76,134.65 157.88,134.52 159.2,134.52 159.46,134.26 159.46,133.69 159.2,133.43 157.68,133.43 157.55,133.3 157.55,130.42 158.31,129.66 158.45,129.53 158.45,126.17 157.99,125.71 157.99,125.46 158.27,125.18 158.27,124.06 v2(158.68,123.64)
  BOTTOM w0.14: R7804.1 157.35,152.46 157.35,150.47 v2(157.66,150.16) ; GPU1.H25 158.29,124.03 v2(158.68,123.64) ; VRAM2.K7 157.68,143.7 157.68,143.7 157.19,144.19 156.14,144.19 156.06,144.27 v2(156.06,144.87)
CLKA1: length 47.8
  TOP w0.14: v2(180.53,145.25) 180.3,145.25 178.79,143.74 VRAM3.J7
  L4 w0.127: v2(171.5,125.24) 171.27,125.24 171.02,125.49 171.02,125.8 171.31,126.09 171.31,129.02 172.14,129.86 172.14,132.49 172.39,132.74 172.57,132.74 172.99,132.32 173.45,132.32 173.85,132.72 173.85,133.09 172.64,134.3 172.64,134.48 172.91,134.75 173.09,134.75 174.3,133.54 174.67,133.54 175.07,133.94 175.07,134.31 173.86,135.53 173.86,135.71 174.13,135.97 174.31,135.97 175.52,134.76 175.89,134.76 178.61,137.48 178.61,140 179.11,140.5 179.11,143.39 179.27,143.55 179.27,144.47 179.64,144.84 180.12,144.84 v2(180.53,145.25) 180.39,145.25 179.53,146.11 179.53,146.54 179.22,146.85 179.22,148.73 179.91,149.42 179.91,149.79 180.09,149.97 180.09,149.97 v2(180.12,149.99)
  BOTTOM w0.14: VRAM4.J7 178.79,146.58 179.11,146.27 179.29,146.27 179.68,145.88 179.68,145.88 180.31,145.25 v2(180.53,145.25) ; GPU1.G9 171.49,125.24 v2(171.5,125.24) ; v1(180.11,151.58) 179.91,151.58 ; 179.91,151.58 179.91,150.2 v2(180.12,149.99) ; 179.91,151.58 179.91,152.41 R8908.1
CLKA1#: length 47.5
  TOP w0.14: VRAM3.K7 178.16,143.59 178.28,143.71 178.41,143.71 179.67,144.97 v2(179.67,145.29)
  L4 w0.127: v2(179.49,149.99) 179.68,149.8 179.68,149.51 178.99,148.83 178.99,146.76 179.3,146.45 179.3,146.02 179.67,145.65 v2(179.67,145.29) 179.67,145.2 179.04,144.57 179.04,143.65 178.88,143.48 178.88,140.6 178.38,140.1 178.38,137.58 175.8,134.99 175.62,134.99 174.41,136.2 174.04,136.2 173.63,135.8 173.63,135.43 174.84,134.22 174.84,134.04 174.57,133.77 174.4,133.77 173.18,134.98 172.81,134.98 172.41,134.58 172.41,134.21 173.62,133 173.62,132.82 173.35,132.55 173.08,132.55 172.67,132.97 172.3,132.97 171.92,132.58 171.92,129.95 171.08,129.12 171.08,126.19 170.79,125.89 170.79,125.4 171.07,125.12 171.07,124.87 v2(171.49,124.44)
  BOTTOM w0.14: v2(179.67,145.29) 179.67,145.55 179.44,145.78 179.44,145.78 179.19,146.03 179.01,146.03 178.71,146.32 178.46,146.32 VRAM4.K7 ; R8907.1 179.67,152.51 179.67,150.18 v2(179.49,149.99) ; v2(171.49,124.44) GPU1.H9
CLKREQG#: length 7.8
  BOTTOM w0.102: CPU1.AY29 108.47,78.15 108.77,77.85 109.03,77.85 109.2,78.02 111.1,78.02 113.36,75.76 v1(113.92,75.76) R610.2
CLKTESTA: length 2.3
  TOP w0.102: C7406.1 173.36,123.18 173.2,123.33 172.79,123.33 v2(172.29,122.83)
  BOTTOM w0.102: v2(172.29,122.83) 172.28,122.83 GPU1.K8
CLKTESTA_C: length 1.8
  TOP w0.102: v1(175.31,124.17) 175.31,124.07 175.42,123.96 R7419.1 175.35,123.18 C7406.2
CLKTESTB: length 7.6
  BOTTOM w0.102: C7407.1 178.66,118.69 v1(178.2,119.14) 178.07,119.28 176.37,119.28 176.14,119.5 175.69,119.5 175.61,119.59 175.08,119.59 174.71,119.96 174.71,120.09 173.63,121.17 173.34,121.17 173.19,121.32 172.81,121.32 GPU1.L7
CLKTESTB_C: length 0.9
  BOTTOM w0.102: C7407.2 R7418.1
CODEC_BITCLK_R: length 3.3
  TOP w0.114: v1(41.21,9.57) 41.23,9.6 41.23,10.01 41.11,10.13 41.11,10.25 R2720.2 40.83,10.54 HDA27.6
CODEC_SDOUT_R: length 4.9
  TOP w0.114: v2(40.61,9.26) 40.61,9.62 40.09,10.14 HDA27.5
  BOTTOM w0.114: R2719.2 39.63,10.49 39.98,10.15 40.1,10.15 40.61,9.63 v2(40.61,9.26) v1(41.17,9.26)
COMBO-GPI: length 2.1
  TOP w0.102: TP2702.1 39.03,6.17 37.83,7.37 HDA27.48
CPVEE: length 3.1
  TOP w0.102: C2704.2 30.64,8.26 30.64,8.26 v1(31.41,9.03) 31.72,9.34 HDA27.34
CSA0#_0: length 36.5
  TOP w0.14: VRAM1.L2 158.94,143.14 158.94,143.73 158.65,144.02 158.58,144.02 158.33,144.27 158.33,144.79 v2(158.67,145.13)
  TOP w0.279: v1(159.95,124.14) 160.3,123.8 v2(160.3,123.64)
  L4 w0.165: v2(158.67,145.13) 158.32,144.78 158.32,144.18 158.81,143.69 ; 159.93,125.72 159.93,124.01 v2(160.3,123.64)
  L4 w0.267: 159.93,125.72 159.91,125.74 159.91,130.73 159.63,131.01 159.04,131.01 158.76,131.28 158.76,131.82 159.04,132.1 159.94,132.1 161.16,133.32 161.82,133.32 162.1,133.6 162.1,134.33 161.82,134.61 160.94,134.61 160.66,134.89 160.66,135.35 161.49,136.19 161.49,138.52 162.18,139.21 162.18,139.69 161.9,139.97 160.18,139.97 159.9,140.25 159.9,142.61 158.81,143.69
  BOTTOM w0.14: v2(158.67,145.13) 158.83,145.29 158.83,145.91 158.83,145.91 158.83,146.48 159.03,146.68 159.03,147.41 158.85,147.59 VRAM2.L2
  BOTTOM w0.279: GPU1.H22 160.7,124.04 v2(160.3,123.64)
CSA1#_0: length 39.2
  TOP w0.14: v2(177.37,145.37) 177.03,145.71 177.03,146 176.74,146.29 176.74,147.35 176.98,147.59 VRAM3.L2
  L4 w0.267: v2(168.6,124.45) 168.55,124.45 168.02,124.98 168.02,128.15 167.7,128.47 167.7,130.73 167.22,131.21 167.18,131.21 166.9,131.49 166.9,132.69 167.18,132.97 168.97,132.97 169.47,133.47 169.47,133.75 169.19,134.03 167.66,134.03 167.38,134.31 167.38,134.84 167.66,135.12 169.82,135.12 170.3,135.59 170.3,137.74 170.58,138.02 171.02,138.02 171.03,138.03 171.16,138.03 171.46,138.34 171.46,139.5 172.29,140.33 174.82,140.33 175.66,141.17 175.66,143.17 177.35,144.86 177.35,145.34 177.37,145.36 v2(177.37,145.37)
  BOTTOM w0.14: VRAM4.L2 176.84,143.14 176.84,144.69 177.18,145.03 177.18,145.18 v2(177.37,145.37)
  BOTTOM w0.279: v2(168.6,124.45) 168.52,124.45 168.14,124.84 GPU1.G13
DAC_BLUE: length 4.5
  BOTTOM w0.114: 85.16,86.05 85.27,86.05 85.27,86.04 85.56,86.04 85.68,86.16 86.43,86.16 86.74,85.85 CPU1.B15
  BOTTOM w0.254: R408.1 83.25,85.74 83.82,85.74 v1(83.84,85.72) 84.17,86.05 85.16,86.05
DAC_GREEN: length 3.9
  BOTTOM w0.114: CPU1.A14 85.42,86.4
  BOTTOM w0.254: 85.42,86.4 84.88,86.94 v1(83.84,86.94) R406.1
DAC_HSYNC: length 14.8
  L4 w0.102: v2(80.27,86.16) 80.69,85.74 84.06,85.74 84.16,85.64 85.16,85.64 86.84,83.96 88.05,83.96 88.42,83.59 89.77,83.59 90.27,84.09 v2(90.27,84.22)
  BOTTOM w0.114: CPU1.G19 90,83.82 90.27,84.09 v2(90.27,84.22) ; v2(80.27,86.16) 80.27,86.97 80.13,87.11 v1(79.4,87.11) 79.39,87.1 R428.1
DAC_RED: length 6
  BOTTOM w0.114: CPU1.B14 87.09,86.4 86.78,86.71 86.5,86.71 86.43,86.64 86.02,86.64 85.88,86.78
  BOTTOM w0.254: R405.1 v1(83.28,88.21) 84.45,88.21 85.88,86.78
DAC_ZVSS: length 7.1
  BOTTOM w0.114: CPU1.A16 86.46,85.11 85.68,85.11 85.62,85.18 82.77,85.18 82.52,84.92 v1(82.37,84.92) 80.26,84.92 R407.1
DBC_EN: length 206.7
  TOP w0.102: R2449.2 v2(45.35,78.12)
  L3 w0.102: v2(45.35,78.12) 48.28,78.12 51.05,80.89 58.98,80.89 59.55,80.32 59.55,79.96 58.72,79.14 58.47,79.14 56.18,76.85 56.18,64.81 54.76,63.39 54.76,60.27 54.3,59.81 54.3,55.49 49.91,51.1 49.91,45.71 48.11,43.91 48.11,36.26 48.46,35.91 49.32,35.91 49.73,35.5 49.73,30.22 49.35,29.84 49.35,27.68 49.66,27.37 49.66,25.9 49.33,25.57 49.33,24.3 49.94,23.69 70.3,23.69 70.7,23.29 112.61,23.29 114.26,24.95 114.26,27.89 114.48,28.11 114.48,36.68 115.29,37.49 115.29,40.5 114.35,41.44 114.35,61.59 114.72,61.96 114.72,64.32 113.79,65.24 113.79,76.29 v2(112.9,77.18)
  BOTTOM w0.102: R601.1 114.03,76.65 v1(113.63,77.06) 113.5,77.18 v2(112.9,77.18) 111.63,78.45 108.73,78.45 108.68,78.4 108.38,78.4 108.08,78.7 CPU1.AY28
DBC_EN_R: length 4.5
  TOP w0.102: R2449.1 v1(45.35,80.68) 45.35,80.77 43.45,82.68 LCD1.8
DBRDY1: length 4.1
  TOP w0.127: RN6502.1 54.9,67.19 v1(54.99,67.1) 55.52,67.63 HDT1.15
DBRDY2: length 4.3
  TOP w0.127: RN6502.2 54.72,67.84 v1(55.18,68.3) 55.78,68.9 HDT1.13
DBRDY3: length 5.4
  TOP w0.127: HDT1.11 54.94,70.17 v1(54.91,70.15) 54.79,70.02 54.79,68.62 54.5,68.34 RN6502.3
DC_IN_D: length 3.4
  BOTTOM w0.381: PQ4402.3 92.93,148.01 92.1,148.84 PR4404.2 92.95,149.17 93.08,149.29 v1(93.2,149.29)
DCBATOUT: length 81.7
  TOP w0.203: 130.12,37.79 130.46,38.13 PU4501.11
  TOP w0.254: PR4511.1 130.41,35.95 130.25,36.11 130.25,36.11 130.1,36.26 130.1,36.26 PC4518.1
  TOP w0.508: 119.02,34.05 119.02,37.62 120.66,39.26 121.92,39.26 PD4505.2 123.2,39.37 PR4520.1 124.34,39.37 125.04,38.68 126.52,38.68 PC4517.1 128.06,36.8 PC4518.1 129.56,37.23 130.12,37.79
  BOTTOM w0.508: EC9713.1 119.67,131.61 121.71,131.61 v2(122.1,132) 121.63,132.47 PR4468.1 ; PR8348.1 164.96,48.81 162.51,48.81 161.35,47.65 159.37,47.65 157.68,49.34 153.87,49.34 153.11,48.58 v2(147.9,48.58) ; v2(121.59,118.33) 121.55,118.29 PR4666.2 ; PR4667.1 118.21,122.78 117.7,122.27 v2(117.45,122.27)
  BOTTOM w2.032: 66.11,98.75 67.48,98.75 73.73,105.01 73.73,106.42 75.21,107.89 76.81,107.89 76.92,108.02 79.7,110.8 79.7,111.03 79.7,111.04 79.7,113.22 79.7,113.23 79.7,113.61 81.86,115.76 81.86,115.77 83.26,117.16 83.26,119.45 84.99,121.18 84.99,126 85.16,126.18
  vias: v1(60.88,94.63) v1(65.81,97.38) v1(87.75,130.7) v1(122.76,147.46) v1(124.48,131.77) v1(127,17.06) v1(154.71,96.03) v1(155.85,67.15) v1(166.77,71.29) v3(63.7,96.97) v3(64.72,96.97) v3(88.34,137.61) v3(89.23,138.5) v3(89.23,137.61) v3(90.12,138.5) v3(90.12,137.61) v3(91.01,138.5) v3(91.01,137.61) v3(123.52,147.26) v3(123.52,146.37) v3(124.41,148.15) v3(124.41,147.26) v3(124.41,146.37) v3(124.41,145.48) v3(125.3,148.15) v3(125.3,147.26) v3(125.3,146.37) v3(125.3,145.48) v3(125.42,126.05) v3(125.42,125.16) v3(125.42,124.27) v3(125.42,123.39) v3(155.52,96.59) v3(156.16,95.95) v3(156.74,96.59) v3(157.3,95.95) v3(157.93,96.59) v3(158.46,95.93) v3(166.32,70.68) v3(166.32,69.79) v3(166.32,68.9) v3(167.21,70.68) v3(167.21,69.79) v3(167.21,68.9)
DDC_CLK_HDMI: length 20.7
  L3 w0.127: v2(12.88,90.64) 12.34,90.64 12.05,90.94 10.98,90.94 10.56,90.52 10.56,89.46 HDMI1.15
  BOTTOM w0.14: RN5401.2 22.21,91.5 22.21,92.28 21.39,93.1 v1(21.31,93.1) 19.31,93.1 18.95,92.73 18.34,92.73 18.03,92.42 Q5402.3 18.52,91.96 18.79,91.69 18.79,90.29 18.62,90.11 15.97,90.11 15.42,90.67 15.42,91.51 15.32,91.61 14.89,91.61 RN5404.4 13.81,91.58 v2(12.88,90.64)
DDC_CLK_PH1: length 6.1
  BOTTOM w0.14: RN5401.3 v1(22.32,88.76) 22.32,88.47 23.49,87.29 24.53,87.29 24.76,87.52 24.76,88.08 24.61,88.23 24.02,88.23 D5401.2
DDC_DATA_HDMI: length 16.5
  L3 w0.127: v2(12.82,90.01) 12.02,89.2 HDMI1.16
  BOTTOM w0.14: v2(12.82,90.01) 12.98,90.01 13.96,90.99 14.24,90.99 14.31,90.93 RN5404.3 14.87,90.48 15.76,89.59 v1(16.43,89.59) 19.31,89.59 19.91,90.19 Q5402.6 19.78,90.79 19.44,90.79 19.21,91.02 19.21,92.24 19.54,92.57 21.17,92.57 21.67,92.08 RN5401.1
DDC_DATA_PH2: length 7.8
  BOTTOM w0.14: D5401.1 25.43,88.22 25.28,88.08 25.28,87.3 24.75,86.77 23.28,86.77 v1(22.72,87.33) 21.67,88.38 RN5401.4
DDR3_DRAMRST#: length 69
  TOP w0.114: v1(57.99,27.27) 57.92,27.21 C1221.1 57.92,25.79 v2(57.73,25.6)
  L3 w0.102: v2(57.73,25.6) 57.86,25.78 57.86,34.1 82.37,58.62 82.37,69.67 86.38,73.68 89.22,73.68 v2(89.35,73.55)
  BOTTOM w0.114: v2(57.73,25.6) 58.16,25.6 58.95,24.8 DM1.30 ; CPU1.G38 89.55,73.35 v2(89.35,73.55)
DDR_VREF_S3: length 71.7
  TOP w0.33: C1205.1 91.2,23.14 v2(90.15,24.19)
  TOP w0.508: C1205.1 91.2,21.49 v2(91.16,21.45)
  TOP w1.016: v3(71.32,21.02) 69.92,22.42 47.72,22.42 46.66,23.49 46.66,27.6
  BOTTOM w0.33: DM1.126 v2(90.15,24.19)
  BOTTOM w0.508: v3(71.32,21.02) 71.7,20.64 100.61,20.64 101.29,19.96 106.58,19.96 107.34,20.72 v3(107.34,21.15)
  vias: v1(75,62.68) v1(104.19,22.09) v2(98.15,73.75) v2(99.26,73.73) v3(44.52,28.52) v3(44.52,27.63) v3(88.12,74.23) v3(106.5,21.15)
DDR_VTT_PG_CTRL_R: length 3.4
  TOP w0.127: v1(104.53,9.95) 104.28,10.2 PR4910.1 104.28,11.56 104.83,12.11 PU4901.17
DEBUG: length 7.2
  TOP w0.14: v1(193.22,24.15) 193.2,24.13 R5807.2 192.22,21.89 190.44,20.1 v2(190.4,20.1)
  BOTTOM w0.14: v2(190.4,20.1) 189.86,20.1 WLAN1.49
DGPU_PRESENT#: length 7.1
  BOTTOM w0.102: CPU1.BA26 108.55,80.43 109.09,80.97 111.5,80.97 111.76,80.71 111.76,80.36 111.56,80.15 111.56,79.94 v1(111.67,79.82) 112.04,79.82 112.35,80.14 R642.2 R643.1
DGPU_PWR_EN#: length 4.1
  TOP w0.102: PQ8305.6 143.54,77.65 PR8313.2 ; PR8313.2 143.33,78.49 143.52,78.3 PQ8305.5 ; PR8313.2 142.69,79.32 v1(142.77,79.39)
DGPU_PWROK: length 183.2
  TOP w0.127: PR8273.2 153.54,84.33 153.09,83.88 153.02,83.88 152.17,83.02 152.17,81.14 152.85,80.46 U8201.2 v2(156.28,80.46) ; v2(176.1,80.43) 176.1,79.19 177.43,77.86 177.43,70.39 174.13,67.09 174.09,67.09 171.9,64.91 171.9,51.73 169.11,48.94 v2(169.11,48.58) v1(169.11,48.02) 169.11,44.91 167.4,43.2 167.4,43.13 166.29,42.02 165.94,42.02 163.85,39.93 163.85,39.13 164.09,38.89 KBC24.63 164.09,36.78 164.67,36.2 164.67,35.01 166.63,33.05 166.63,30.1 165.94,29.41 165.94,25.85 v2(164.77,24.68)
  L4 w0.127: v2(176.1,80.43) 173.15,80.43 172.53,79.81 156.93,79.81 v2(156.28,80.46) ; v2(143.04,31.72) 143.01,31.72 140.64,34.09 140.64,41.15 129.4,52.39 129.4,61.53 128.94,61.99 128.94,74.16 124.24,78.86 120.16,78.86 119.96,79.06 v2(118.29,79.06)
  BOTTOM w0.127: v2(164.77,24.68) 161.64,24.68 160.78,25.54 159.51,25.54 159.08,25.98 154.53,25.98 152.96,27.55 148.26,27.55 144.09,31.72 v2(143.04,31.72) ; PR8345.1 170.57,48.58 v2(169.11,48.58) ; R631.2 120.03,79.63 119.54,79.15 119.02,79.15 118.93,79.06 v2(118.29,79.06)
DGPU_PWROK_R: length 18.3
  TOP w0.127: v2(117.65,79.06) 116.41,79.06 116.18,78.83 113.25,78.83 112.6,79.48 108.37,79.48 107.41,80.43 106.27,80.43 v1(105.97,80.74) 105.97,80.76 v2(104.82,81.91)
  BOTTOM w0.127: R631.1 C605.1 118.64,80.74 117.65,79.75 v2(117.65,79.06) ; CPU1.AP23 104.82,81.87 v2(104.82,81.91)
DIS_1D35V_VGA_S0: length 3.4
  BOTTOM w0.508: PR8344.2 v1(176.86,52.14) 175.84,52.14 175.4,52.58 PQ8317.D
DMIC_CLK: length 102
  TOP w0.14: v2(43.21,7.77) 43.21,8.07 C2723.2 41.92,8.43 R2716.1
  L4 w0.127: v2(30.84,85.45) 30.42,85.04 30.42,84.27 30.81,83.89 31.42,83.89 32.27,83.04 32.27,82.54 33.23,81.57 33.23,67.88 38.5,62.61 38.5,51.68 33.75,46.93 33.75,44.04 30.2,40.48 30.2,35.34 28.65,33.79 28.65,26.27 30.66,24.26 37.56,24.26 39.25,22.57 39.25,21.56 42.36,18.45 42.36,17.09 41.79,16.51 41.79,15.5 41.91,15.38 42.39,14.9 42.39,10.46 43.03,9.81 43.03,7.95 v2(43.21,7.77)
  BOTTOM w0.14: RN5204.3 31.79,85.48 30.86,85.48 v2(30.84,85.45) 30.79,85.5 30.31,85.5 EC5206.1 29.97,85.48 RN5202.4 ; v2(43.21,7.77) 43.21,7.58 v1(43.56,7.23)
DMIC_CLK_C: length 15.2
  TOP w0.14: 16.58,86.17 16.58,86.64 17.33,87.4 17.33,87.69 17.3,87.73 CCD1.3 ; 16.58,86.17 16.58,85.96 17,85.54 17.96,85.54 18.08,85.67 18.68,85.67 19.75,84.6 26.07,84.6 26.76,85.29 v2(26.78,85.29) ; 16.58,86.17 AFTP5222.1
  BOTTOM w0.14: RN5202.1 27.04,85.48 26.85,85.29 v2(26.78,85.29)
DMIC_CLK_EDP: length 3.9
  TOP w0.14: LCD1.27 33.95,84.65 33.62,84.98 33.62,85.24 v2(33.83,85.46)
  BOTTOM w0.14: RN5204.2 v2(33.83,85.46) 33.83,85.46 v1(34.47,86.1)
DMIC_CLK_R: length 4.5
  TOP w0.14: HDA27.3 39.52,9.34 40.33,8.53 R2716.2 41.83,9.42 v1(42.42,9.42)
DMIC_DATA: length 101.9
  TOP w0.14: R2714.1 42.45,7.69 v2(42.52,7.77)
  L4 w0.127: v2(42.52,7.77) 42.52,9.6 41.88,10.25 41.88,14.69 41.29,15.29 41.29,16.73 41.86,17.3 41.86,18.24 38.75,21.35 38.75,22.36 37.35,23.75 30.45,23.75 28.14,26.06 28.14,34 29.69,35.55 29.69,40.69 33.25,44.25 33.25,47.14 38,51.89 38,62.4 32.72,67.67 32.72,81.36 31.76,82.33 31.76,82.83 31.21,83.38 30.6,83.38 29.92,84.06 29.92,85.25 30.4,85.73 30.4,85.77 v2(30.83,86.19)
  BOTTOM w0.14: RN5204.4 31.7,86 31.02,86 v2(30.83,86.19) 30.7,86.07 30.17,86.07 EC5205.1 30.12,86.13 RN5202.3 ; v2(42.52,7.77) 42.52,8.05 v1(42.87,8.4)
DMIC_DATA_C: length 13.9
  TOP w0.14: CCD1.4 18.1,87.88 17.85,87.63 17.85,87.18 17.1,86.43 17.1,86.17 17.21,86.06 17.74,86.06 AFTP5228.1 17.87,86.19 18.9,86.19 19.96,85.12 25.86,85.12 26.78,86.04 v2(26.78,86.07)
  BOTTOM w0.14: v2(26.78,86.07) 26.8,86.07 26.85,86.13 RN5202.2
DMIC_DATA_EDP: length 5.4
  TOP w0.14: v2(33.83,86.23) 33.48,86.23 33.1,85.85 33.1,84.77 33.45,84.41 LCD1.28
  BOTTOM w0.14: v2(33.83,86.23) 33.71,86.11 RN5204.1 33.01,86.54 v1(32.48,87.06)
DMIC_DATA_R: length 3.8
  TOP w0.14: HDA27.2 39.36,8.94 40.17,8.13 ; 40.17,8.13 40.61,7.69 R2714.2 EC2701.1 ; 40.17,8.13 v1(40.03,7.99)
DP_2K_ZVSS: length 4.1
  BOTTOM w0.203: R402.1 v1(83.26,82.62) 86.23,82.62 CPU1.A21
DP_150_ZVSS: length 2.3
  TOP w0.203: v2(87.91,85.34) 87.21,85.34 R401.1 87.2,84.84 v1(86.82,84.46)
  BOTTOM w0.203: CPU1.B16 87.87,85.3 v2(87.91,85.34)
DPEF_CALR: length 2.2
  TOP w0.305: v2(164.97,109.41) 165.54,109.41 R7710.1
  TOP w0.508: v1(165.78,110.41) 165.78,109.63 R7710.1
  BOTTOM w0.356: GPU1.AF17 164.64,109.64 164.86,109.41 v2(164.97,109.41)
DPLL_PVDD: length 0.9
  BOTTOM w0.356: GPU1.AF14 167.18,109.64 v2(167.61,110.08)
  vias: v1(169.11,106.11)
DPLL_VDDC:
  vias: v1(167.56,104.21)
DQMA0: length 44.7
  TOP w0.178: VRAM1.E7 153.56,146.56 153.56,145.99 v2(152.65,145.08)
  L4 w0.165: v2(152.65,145.08) 152.3,145.08 152.12,144.9 152.12,144.26 151.94,144.09 151.61,144.09 151.43,144.26 151.43,144.67 151.2,144.9 150.47,144.9 150.29,145.08 150.29,145.4 150.06,145.64 149.78,145.64 149.6,145.46 149.6,144.31 149.78,144.14 150.34,144.14 150.52,143.96 150.52,143.63 150.34,143.45 149.78,143.45 149.6,143.27 149.6,142.92 149.78,142.74 150.62,142.74 150.8,142.56 150.8,142.28 150.62,142.1 149.78,142.1 149.6,141.93 149.6,135.65 150.11,135.15 151.15,135.15 151.33,134.97 151.33,134.59 151.15,134.41 150.6,134.41 150.42,134.23 150.42,133.76 150.59,133.6 151.18,133.6 151.34,133.43 151.34,133.1 151.18,132.94 150.59,132.94 150.42,132.77 150.42,130.73 150.95,130.2 151.27,130.2 152.44,129.04 152.44,128.54 152.61,128.36 152.83,128.36 153.01,128.19 153.01,127.88 152.72,127.6 v2(152.72,127.22)
  BOTTOM w0.178: v2(152.72,127.22) 152.54,127.04 149.88,127.04 149.71,126.86 v1(149.71,126.26) 149.71,125.54 149.88,125.37 150.7,125.37 150.87,125.54 150.87,126.15 151.05,126.33 151.43,126.33 151.61,126.15 151.61,125.9 151.79,125.72 152.25,125.72 152.42,125.9 152.42,126.13 152.6,126.31 152.98,126.31 153.34,126.66 154.07,126.66 GPU1.E32
DQMA1: length 41.2
  TOP w0.178: VRAM1.D3 152.9,143.68 152.68,143.68 152.16,144.21 152.16,144.86 151.92,145.1 149.93,145.1 148.69,146.35 148.17,146.35 147.38,145.56 v1(147.38,144.85) 147.38,144.19 147.56,144.01 148.38,144.01 148.56,143.83 148.56,143.45 148.38,143.27 147.56,143.27 147.38,143.1 147.38,142.74 147.56,142.56 148.36,142.56 148.54,142.38 148.54,142.03 148.36,141.85 147.57,141.85 147.39,141.67 147.39,141.32 147.57,141.14 148.38,141.14 148.56,140.96 148.56,140.61 148.38,140.43 147.56,140.43 147.38,140.25 147.38,139.87 147.56,139.69 148.38,139.69 148.56,139.51 148.56,139.11 148.38,138.93 147.56,138.93 147.38,138.75 147.38,137.28 148.19,136.47 148.19,135.12 150.81,132.5 151.92,132.5 152.37,132.05 152.37,131.46 152.55,131.28 153.44,131.28 153.62,131.11 153.62,130.8 153.36,130.55 153.06,130.55 152.78,130.26 152.78,129.84 153.49,129.13 154.79,129.13 v2(154.97,129.3)
  BOTTOM w0.178: v2(154.97,129.3) 155.36,129.3 155.53,129.13 155.53,128.34 155.48,128.29 155.48,126.83 GPU1.E30
DQMA2: length 29.7
  BOTTOM w0.102: 161.69,129.77 161.6,129.68 161.6,128.15 GPU1.A21
  BOTTOM w0.178: 161.69,129.77 161.69,131.77 161.89,131.97 162.76,131.97 162.94,132.15 162.94,132.38 163.12,132.55 163.88,132.55 164.06,132.73 164.06,133.11 163.88,133.29 163.12,133.29 162.94,133.47 162.94,134 163.12,134.18 163.73,134.18 163.9,134.36 163.9,134.82 163.73,134.99 163.17,134.99 162.81,135.35 v1(161.11,135.35) 159.1,135.35 157.45,137 157.45,138.73 155.23,140.95 155.11,140.95 154.18,141.88 154.18,142.92 153.89,143.21 153.65,143.21 153.37,143.49 153.37,143.75 153.09,144.03 153.09,146.69 VRAM2.D3
DQMA3: length 42.7
  L3 w0.165: v2(162.28,129.74) 162.65,130.12 162.65,131.15 162.33,131.47 160.93,131.47 160.47,131.01 159.37,131.01 158.22,132.15 157.06,132.15 156.82,132.4 156.82,134.05 156.33,134.54 154.56,134.54 154.38,134.72 154.38,134.99 154.2,135.17 153.69,135.17 153.51,134.99 153.51,134.03 153.28,133.79 151.74,133.79 150.09,135.44 150.09,140.16 150.26,140.32 151.33,140.32 151.51,140.5 151.51,140.81 151.33,140.98 150.26,140.98 150.09,141.15 150.09,141.85 150.27,142.02 151.33,142.02 151.51,142.2 151.51,142.54 151.33,142.71 150.27,142.71 150.09,142.89 150.09,143.31 150.47,143.69 150.47,144.14 150.09,144.52 150.09,144.77 150.27,144.95 151.92,144.95 152.09,144.77 152.09,143.98 152.27,143.81 153.37,143.81 153.54,143.98 v2(153.54,144.59)
  BOTTOM w0.102: v2(162.28,129.74) 161.8,129.27 161.8,128.19 161.82,128.18 161.82,127.57 GPU1.C21
  BOTTOM w0.178: v2(153.54,144.59) 153.54,144.03 153.79,143.79 VRAM2.E7
DQMA4: length 45.5
  TOP w0.178: v2(182.86,144.15) 182.86,144.71 182.67,144.9 182.38,144.9 182.09,144.61 182.09,143.69 VRAM3.E7
  L3 w0.165: v2(168.19,129.24) 167.82,129.62 167.82,130.93 167.99,131.11 170.05,131.11 170.23,130.93 170.23,129.43 170.41,129.25 171.95,129.25 172.36,129.66 172.36,130.93 172.54,131.11 178.28,131.11 180.15,132.98 181.4,132.98 185.67,137.25 185.67,142.66 185.49,142.84 183.82,142.84 183.64,143.02 183.64,143.4 183.82,143.58 185.49,143.58 185.67,143.76 185.67,144.19 185.32,144.54 184.61,144.54 184.17,144.98 183.13,144.98 182.86,144.7 v2(182.86,144.15)
  BOTTOM w0.102: GPU1.E13 168.22,126.77 168.22,127.3 168.21,127.37 168.2,127.39 arc(168.17,127.43) 168.16,127.49 168.16,127.75 arc(168.16,127.8) 168.18,127.84 168.19,127.87 168.22,127.95 168.22,128.19 168.08,128.33 168.08,129.13 v2(168.19,129.24)
DQMA5: length 42.2
  BOTTOM w0.102: 168.83,129.4 168.83,129.3 168.28,128.75 168.28,128.42 168.42,128.28 168.42,127.91 168.38,127.79 168.37,127.78 168.36,127.73 168.36,127.53 168.38,127.49 168.38,127.48 168.4,127.46 arc(168.42,127.42) 168.43,127.37 168.43,127.1 GPU1.D12
  BOTTOM w0.178: VRAM4.D3 182.41,143.21 182.41,140.39 177.54,135.53 174.39,135.53 171.41,138.51 171.41,138.74 171.14,139.02 170.75,139.02 170.69,138.96 167.97,138.96 167.69,139.24 167.13,139.24 166.95,139.06 166.95,138.5 166.77,138.32 165.05,138.32 164.87,138.14 v1(164.87,137.48) 164.87,133.62 165.05,133.44 165.34,133.44 165.52,133.27 165.52,132.73 165.34,132.55 164.92,132.55 164.74,132.38 164.74,131.9 164.92,131.73 165.71,131.73 166.08,132.1 166.44,132.1 166.65,131.89 166.65,131.28 166.82,131.1 168.44,131.1 168.7,130.84 168.7,130.35 168.83,130.22 168.83,129.41 168.83,129.4
DQMA6: length 38.7
  TOP w0.178: v2(173.68,126.32) 173.68,126.84 173.86,127.02 174.37,127.02 174.78,127.42 175.69,127.42 175.87,127.6 175.87,127.98 175.69,128.16 174.27,128.16 174.09,128.33 174.09,128.66 174.27,128.84 175.01,128.84 175.33,129.16 175.33,129.55 176.31,130.54 177.99,130.54 178.41,130.12 178.67,130.12 179.09,130.54 179.69,130.54 182.9,133.75 183.31,133.75 183.82,133.24 184.1,133.24 187.09,136.24 v1(187.09,137.43) 187.09,145.15 186.84,145.41 183.79,145.41 183.61,145.58 183.61,146.11 182.93,146.79 VRAM3.D3
  BOTTOM w0.178: v2(173.68,126.32) 173.84,126.32 174.11,126.05 174.47,126.05 174.86,126.44 GPU1.E3
DQMA7: length 46.1
  TOP w0.178: v2(178.03,125.44) 178.79,125.44 178.99,125.65 v1(179.02,125.65)
  L4 w0.165: v2(178.03,125.44) 178.03,125.67 183.78,131.42 183.78,133.11 183.95,133.28 185.27,133.28 185.45,133.46 185.45,135.65 185.63,135.83 186.74,135.83 186.92,136.01 186.92,136.36 186.74,136.54 184.81,136.54 184.64,136.71 184.64,137.06 184.81,137.23 186.74,137.23 186.92,137.41 186.92,137.72 186.74,137.9 184.81,137.9 184.64,138.07 184.64,138.41 184.81,138.58 186.62,138.58 186.92,138.88 186.92,142.51 186.74,142.69 186.26,142.69 186.08,142.51 186.08,141.85 185.9,141.67 185.49,141.67 185.32,141.85 185.32,142.64 185.14,142.82 184.98,142.82 184.97,142.82 184.86,142.82 184.68,143 184.68,143.49 184.86,143.66 185.16,143.66 185.34,143.84 185.34,144.54 185.16,144.72 184.63,144.72 184.45,144.9 184.45,145.2 184.27,145.37 v2(182.91,145.37)
  BOTTOM w0.178: VRAM4.E7 182.64,146.14 182.64,145.65 v2(182.91,145.37) ; v2(178.03,125.44) 177.46,126.01 175.06,126.01 GPU1.F4
DRAM_RST: length 68.7
  TOP w0.127: R7404.2 R7420.1 170.38,153.93 170.38,149.29 v2(170.89,148.79)
  L4 w0.127: v2(170.89,148.79) 173.23,151.12 184.24,151.12 189.25,146.12 189.25,132.44 178.82,122.02 178.54,122.02 178.32,121.8 178.32,121.8 174.18,121.8 173.58,122.41 171.21,122.41 v2(170.66,121.86)
  BOTTOM w0.127: v2(170.66,121.86) 170.29,121.49 GPU1.L10 ; v2(170.89,148.79) 170.41,148.79 v1(169.95,148.33)
DRAM_RST_R: length 2.9
  TOP w0.127: R7402.1 R7420.2 ; R7402.1 172.54,153.55 C7401.2 ; R7402.1 171.44,153.55 v1(170.86,152.98)
E51_RX: length 2.1
  BOTTOM w0.14: WLAN1.17 191.13,32.9 TP5802.1
E51_TX: length 32.8
  TOP w0.14: v2(167.33,20.13) 167.46,20.26 R5804.2 ; v1(179.58,20.87) v2(179.02,20.87)
  L3 w0.127: v2(179.02,20.87) 178.43,21.46 170.5,21.46 169.81,20.77 167.97,20.77 v2(167.33,20.13)
  L4 w0.127: v2(186.84,31.96) 186.33,31.45 186.33,28.06 184.05,25.77 184.05,22.63 183.2,21.79 179.93,21.79 v2(179.02,20.87)
  BOTTOM w0.14: WLAN1.19 186.98,32.1 v2(186.84,31.96)
E51_TXD: length 4
  TOP w0.102: KBC24.111 169.29,21.03 169.43,20.9 R5804.1 169.43,20.02 169.21,19.8 167.97,19.8 v1(167.79,19.63)
EAPD#: length 6
  TOP w0.102: HDA27.47 37.43,7.16 39.24,5.35 39.49,5.35 v1(39.9,4.94) 40.1,4.74 40.1,4.6 40.37,4.33 41.1,4.33 R2708.2
EC_AGND: length 16.5
  TOP w0.203: KBC24.103 166.09,21.11 166.19,21.01 166.19,20.24 R2435.1
  TOP w0.508: v2(163.83,18.61) 163.83,18.17 164.12,17.88 C2405.2 165.15,17.88 165.16,17.89 165.83,17.89 C2404.2 165.81,18.16 165.81,18.78 C2402.1 R2406.2 166.7,19.72 R2435.1 ; R2407.2 C2403.1 161.36,22.04 v2(162.38,21.02) 162.44,20.96 C2414.1
  BOTTOM w0.508: v2(163.83,18.61) 164.46,19.24 v1(164.46,19.5) 163.98,19.98 162.91,19.98 162.38,20.52 v2(162.38,21.02)
EC_BRIGHTNESS: length 242.7
  TOP w0.14: v2(165.53,36.29) 166.34,35.48 172.49,35.48 173.4,36.39 176.3,36.39 176.52,36.17 177.06,36.17 177.13,36.1 KBC24.32 178.85,36.1 v1(179.4,36.64)
  L3 w0.127: v2(46.56,58.49) 47.76,57.28 47.76,51.06 47.51,50.81 47.51,48.91 44.26,45.66 44.26,39.74 43.11,38.6 43.11,36.28 40.4,33.56 40.4,24.6 42.11,22.88 43.01,22.88 49.08,16.81 63.55,16.81 64.83,15.52 67.38,15.52 72.65,10.25 76.62,10.25 78.83,8.04 81.09,5.78 96.47,5.78 96.67,5.58 128.2,5.58 128.53,5.91 129.34,5.91 129.62,6.19 141.04,6.19 141.36,5.87 143.75,5.87 v2(144.12,5.5)
  L4 w0.127: v2(47.34,88.49) 47.34,67.63 47.69,67.29 47.69,63.43 47,62.74 47,58.93 v2(46.56,58.49) ; v2(144.12,5.5) 144.24,5.38 145.22,5.38 146.24,6.39 148.63,6.39 150.82,8.59 152.38,8.59 159.99,16.2 159.99,17.11 162.82,19.94 162.82,22.61 162.29,23.15 162.29,23.98 162.8,24.49 162.8,24.91 162.21,25.49 162.21,33.11 163.09,33.99 163.09,33.99 165.39,36.29 v2(165.53,36.29)
  BOTTOM w0.14: v2(47.34,88.49) v1(46.35,88.49) 45.83,88.49 44.52,87.19 D5202.A
EC_SCI#: length 272.4
  TOP w0.102: v2(117.42,91.38) 117.42,91.91 v1(117.55,92.04) ; v2(183.87,37.63) 183.87,37.87 R2408.1
  L3 w0.102: v2(185.39,45.97) 184.71,46.65 184.71,49.03 185.19,49.52 185.19,60.06 194.43,69.31 194.43,79.57 195.32,80.45 195.32,82.17 193.75,83.74 193.75,107.25 194.18,107.68 194.18,114.35 193.57,114.96 193.57,135.38 190.02,138.94 190.02,147.17 188.73,148.45 188.73,150.72 187.91,151.54 187.91,152.13 186.4,153.64 173.24,153.64 169.46,149.85 165.84,149.85 162.92,152.77 148.41,152.77 145.97,150.33 142.75,150.33 142.29,149.87 142.29,142.36 143.84,140.81 143.84,133.23 145.06,132.01 145.06,131.1 146.1,130.06 146.1,129.36 146.1,126.37 149.76,122.71 149.76,114.09 145.51,109.85 144.06,109.85 141.85,107.64 132.79,107.64 117.42,92.27 v2(117.42,91.38)
  L4 w0.102: v2(185.39,45.97) 185.39,45.79 183.52,43.91 183.52,37.99 v2(183.87,37.63) ; v2(104.72,91.41) 105.09,91.04 106.02,91.04 106.27,91.29 106.27,91.54 106.85,92.12 107.21,92.12 107.77,91.56 107.77,91.45 109.29,89.93 111.2,89.93 111.94,90.67 114.17,90.67 114.25,90.59 116.63,90.59 v2(117.42,91.38)
  BOTTOM w0.102: CPU1.AN5 104.66,91.41 v2(104.72,91.41)
EC_SMI#: length 291.6
  TOP w0.102: v1(116.53,90.64) 116.79,90.9 v2(116.79,91.38)
  L3 w0.102: v2(116.79,91.38) 116.79,91.89 117.19,92.3 117.19,92.36 132.69,107.87 140.97,107.87 143.89,110.79 146.12,110.79 149.53,114.19 149.53,122.62 145.87,126.28 145.87,129.46 145.87,129.96 144.83,131 144.83,131.92 143.61,133.14 143.61,140.72 142.06,142.27 142.06,149.97 142.65,150.56 145.87,150.56 148.31,153 163.02,153 165.94,150.08 169.36,150.08 173.15,153.87 186.49,153.87 188.14,152.22 188.14,151.64 188.96,150.81 188.96,148.54 190.24,147.26 190.24,139.03 194.84,134.44 194.84,108.02 193.98,107.16 193.98,105.26 194.71,104.52 194.71,88.54 194.05,87.87 194.05,83.76 195.55,82.26 195.55,80.36 194.66,79.47 194.66,69.21 185.49,60.04 185.49,49.5 184.94,48.94 184.94,47.06 186.03,45.97 v2(186.03,45.97)
  L4 w0.102: v2(175.53,27.62) 175.53,28.43 176.5,29.41 176.8,29.41 180.24,32.84 180.24,33.81 180.97,34.54 181.54,34.54 184.49,37.48 184.49,40.48 184.94,40.93 184.94,41.53 183.74,42.72 183.74,43.68 186.03,45.96 v2(186.03,45.97) ; v2(103.7,89.86) 104.24,90.41 104.24,92.32 104.49,92.57 108.35,92.57 110.11,90.82 111.77,90.82 111.84,90.9 114.37,90.9 114.45,90.82 116.25,90.82 116.79,91.35 v2(116.79,91.38)
  BOTTOM w0.102: v2(103.7,89.86) 103.41,90.15 CPU1.AL7 ; v2(175.53,27.62) 175.93,27.22 176.58,27.22 176.92,27.56 R2409.1
EC_SPI_CLK_C: length 5.1
  TOP w0.14: R2420.2 159.37,24.14 159.9,24.14 v1(160.08,23.96) 160.08,24.85 160.52,25.3 KBC24.92
EC_SPI_CS#_C: length 4.4
  TOP w0.14: KBC24.90 160.44,26.1 v1(159.43,25.09) R2419.2
EC_SPI_DI_C: length 4.7
  TOP w0.14: KBC24.87 160.55,27.3 159.98,26.73 159.98,26.53 v1(159.85,26.4) R2422.2
EC_SPI_DO_C: length 4.4
  TOP w0.14: KBC24.86 161.43,27.7 161.41,27.72 160.34,27.72 v1(160.24,27.62) 158.58,25.96 R2423.2
EC_SWI#: length 293.3
  L3 w0.102: v2(185.98,48.51) 186.46,48.99 186.46,59.58 195.5,68.62 195.5,79.12 196.52,80.14 196.52,84.8 195.88,85.44 195.88,107.08 196.03,107.23 196.03,134.61 191.08,139.56 191.08,148.96 189.8,150.25 189.8,151.16 188.97,151.99 188.97,152.57 187.63,153.92 187.63,154.82 187.16,155.29 173.33,155.29 169.18,151.14 168.96,150.92 166.34,150.92 166.13,151.14 166.12,151.14 163.42,153.84 147.96,153.84 145.52,151.4 142.31,151.4 141.22,150.32 141.22,141.92 141.46,141.68 141.46,138.66 139.32,136.52 139.32,130.45 144.34,125.43 145.06,124.71 145.06,122.57 145.64,121.99 147.8,121.99 147.93,121.86 147.93,117.01 140.31,109.39 131.82,109.39 122.6,100.17 117.91,100.17 117.38,99.64 117.2,99.64 116.25,98.69 116.25,98.5 114.91,97.15 114.91,95.03 113.28,93.41 113.28,92.33 111.73,90.78 v2(111.73,89.55)
  L4 w0.102: v2(185.98,48.51) 185.71,48.51 179.99,42.79 179.99,37.08 176.01,33.09 174.17,33.09 173.63,32.56 173,31.92 173,31.78 172.34,31.12 172.34,26.08 171.64,25.39 v2(171.64,24.22)
  BOTTOM w0.102: v2(111.73,89.55) 111.73,89.54 111.73,89.37 112.41,88.7 R608.1 111.96,88.59 111.4,89.15 CPU1.BA9 ; R2410.1 172.35,23.33 172.16,23.52 v1(172.16,23.89) 172.16,23.94 171.88,24.22 v2(171.64,24.22)
EC_VBKUP: length 5.2
  TOP w0.203: v2(170.07,24.96) 170.12,24.91 170.12,24.77 170.55,24.33 170.55,23.3 170.49,23.24 KBC24.114
  BOTTOM w0.254: v2(170.07,24.96) 169.92,25.11 v1(169.19,25.11) 169.15,25.11 R2428.1
ECRST#: length 9.5
  TOP w0.102: KBC24.85 161.6,28.1 161.58,28.12 159.96,28.12 C2418.1 R2418.1 156.92,27.65 R2424.2 156.92,28.29 v1(156.16,29.05) 155.55,28.45 Q2404.E
ECSCI#_KBC: length 6.2
  TOP w0.102: R2408.2 v1(181.1,37.1) 178.9,34.9 KBC24.29
ECSMI#_KBC: length 7.3
  TOP w0.102: KBC24.6 174.89,25.7 v2(174.13,26.46)
  BOTTOM w0.102: R2409.2 175.91,26.67 v1(175.51,26.28) 175.26,26.03 174.56,26.03 v2(174.13,26.46)
ECSWI#_KBC: length 5.8
  TOP w0.102: KBC24.123 174.09,22.93 174.01,23.01 174.01,23.64 173.43,24.22 v2(173.43,25.21)
  BOTTOM w0.102: R2410.2 173.24,24.24 v1(173.43,24.43) v2(173.43,25.21)
EDP_AUX: length 5.8
  TOP w0.127: LCD1.11 41.95,82.95 41.79,82.8 41.79,81.62 ; AFTP5206.1 41.79,81.62 ; 41.79,81.62 41.79,81.08 42.42,80.45 42.42,78.66 C5212.2
EDP_AUX#: length 5.8
  TOP w0.127: 42.18,79.71 42.18,80.35 41.55,80.98 41.55,82.85 41.45,82.95 LCD1.12 ; 42.18,79.71 AFTP5208.1 ; 42.18,79.71 42.18,78.68 C5209.2
EDP_AUX_DN: length 70.6
  TOP w0.127: C5209.1 41.84,74.41 ; 41.84,74.41 41.84,74.17 47.19,68.82 50.69,68.82 51.59,69.71 52.91,69.71 v2(53.55,70.36) ; 41.84,74.41 v1(41.7,74.41)
  L4 w0.114: v2(89.59,86.5) 89.34,86.25 89.34,86.03 89.12,85.81 87.73,85.81 87.6,85.95 84.42,89.13 84.42,89.37 83.98,89.81 63.89,89.81 53.76,79.69 53.76,71.66 53.31,71.21 53.31,70.59 v2(53.55,70.36)
  BOTTOM w0.127: CPU1.E15 89.2,86.11 v2(89.59,86.5)
EDP_AUX_DP: length 70.6
  TOP w0.127: 42.08,76.22 42.08,76.75 42.24,76.9 42.52,76.9 42.73,77.11 C5212.1 ; 42.08,76.22 v1(42.24,76.22) ; 42.08,76.22 42.08,74.27 47.29,69.06 50.59,69.06 51.49,69.96 52.81,69.96 52.96,70.11 52.96,70.32 v2(52.91,70.37)
  L4 w0.114: v2(52.91,70.37) 53.08,70.54 53.08,71.31 53.53,71.76 53.53,79.78 63.79,90.04 84.07,90.04 84.65,89.46 84.65,89.22 87.76,86.11 87.83,86.04 89.03,86.04 89.11,86.13 89.11,86.29 88.9,86.5 v2(88.79,86.5)
  BOTTOM w0.127: CPU1.D15 88.68,85.85 88.96,86.13 88.96,86.32 v2(88.79,86.5)
EDP_BKLT_CTRL: length 2.1
  BOTTOM w0.14: R5206.2 42.94,89.16 v1(42.49,89.6) 42.05,89.16 R5222.2
EDP_HPD: length 57.8
  TOP w0.102: 46.43,75.65 45.95,76.13 45.95,77.06 45.46,77.54 44.74,77.54 R5233.2 ; 46.43,75.65 RN5203.6 ; 46.43,75.65 46.45,75.68 51.05,75.68 51.34,75.39 51.34,74.53 51.64,74.24 53.73,74.24 54.16,74.67 54.16,75.37 57.48,78.68 58.16,78.68 58.62,79.15 58.62,79.19 58.63,79.2 v2(58.63,79.7)
  L4 w0.102: v2(58.63,79.7) 59.44,79.7 61.66,81.93 66.27,81.93 66.79,82.44 67.48,82.44 68.01,81.91 74.17,81.91 74.65,81.42 79.02,81.42 79.78,82.19 80.82,82.19 81.36,82.72 89.7,82.72 90.7,83.72 90.7,84.75 v2(91.16,85.21)
  BOTTOM w0.102: v1(59.21,79.42) 58.92,79.7 v2(58.63,79.7) ; v2(91.16,85.21) 91.16,85.11 CPU1.H17
EDP_HPD_CONN: length 6.1
  TOP w0.102: R5233.1 44.6,78.28 44.6,80.49 43.84,81.24 AFTP5201.1 42.95,82.46 LCD1.9
EDP_TX0: length 6
  TOP w0.127: 40.26,79.71 40.26,80.45 39.61,81.1 39.61,82.09 40.08,82.56 40.08,82.89 39.95,83.02 LCD1.15 ; 40.26,79.71 40.26,78.62 C5210.2 ; 40.26,79.71 AFTP5210.1
EDP_TX0#: length 6.1
  TOP w0.127: 39.85,81.62 39.85,81.99 40.32,82.46 40.32,82.91 40.45,83.04 LCD1.14 ; 39.85,81.62 AFTP5213.1 ; 39.85,81.62 39.85,81.2 40.5,80.55 40.5,78.61 C5203.2
EDP_TX0_DN: length 61.5
  TOP w0.127: v2(40.71,76.76) 40.71,77.3 C5203.1
  BOTTOM w0.102: 86.4,92.12 86.44,92.12 86.52,92.2 86.78,92.2 87.08,91.9 CPU1.B4
  BOTTOM w0.127: 70.81,95.95 72.26,95.95 74.64,93.58 83.7,93.58 85.16,92.12 86.4,92.12 ; 70.81,95.95 v1(70.81,96.11) ; 70.81,95.95 60.65,95.95 54.18,89.48 52.78,89.48 51.25,87.95 46.35,87.95 41.92,83.52 41.92,76.72 41.53,76.33 41.14,76.33 v2(40.71,76.76)
EDP_TX0_DP: length 61.4
  TOP w0.127: C5210.1 40.07,77.27 v2(40.07,76.74)
  BOTTOM w0.127: v1(61.52,95.57) 61.52,95.71 ; 61.52,95.71 60.75,95.71 54.28,89.23 52.88,89.23 51.35,87.71 46.45,87.71 42.16,83.42 42.16,76.62 41.63,76.09 40.71,76.09 v2(40.07,76.74) ; 61.52,95.71 72.16,95.71 74.54,93.34 83.6,93.34 85.06,91.87 86.5,91.87 86.53,91.9 CPU1.A4
EDP_TX1: length 6.2
  TOP w0.127: 38.33,81.62 AFTP5212.1 ; 38.33,81.62 38.33,82 38.58,82.25 38.58,82.82 38.45,82.95 LCD1.18 ; 38.33,81.62 38.33,80.97 37.78,80.42 37.78,79.25 38.16,78.87 38.16,78.57 C5213.2
EDP_TX1#: length 6.1
  TOP w0.127: 38.02,79.71 38.02,79.35 38.4,78.97 38.4,78.55 C5211.2 ; 38.02,79.71 38.02,80.32 38.57,80.87 38.57,81.9 38.82,82.15 38.82,82.82 38.95,82.95 LCD1.17 ; 38.02,79.71 AFTP5211.1
EDP_TX1_DN: length 63.8
  TOP w0.127: C5211.1 38.71,76.79 v2(38.8,76.7)
  BOTTOM w0.102: CPU1.B5 86.73,91.35 86.43,91.65 85.98,91.65 85.92,91.59
  BOTTOM w0.127: 65.17,95.18 60.97,95.18 52.97,87.18 46.67,87.18 42.7,83.2 42.7,76.4 41.85,75.56 39.27,75.56 38.8,76.03 v2(38.8,76.7) ; 65.17,95.18 71.94,95.18 74.32,92.8 83.15,92.8 83.67,92.28 84.02,92.28 84.86,91.45 85.77,91.45 85.92,91.59 ; 65.17,95.18 v1(65.17,95.34)
EDP_TX1_DP: length 63.6
  TOP w0.127: C5213.1 38.06,77.11 v2(38.06,76.7)
  BOTTOM w0.127: 63.19,94.94 61.07,94.94 53.07,86.94 46.77,86.94 42.94,83.1 42.94,76.3 41.95,75.32 39.17,75.32 38.55,75.93 38.55,76.31 38.17,76.7 v2(38.06,76.7) ; 63.19,94.94 v1(63.19,94.81) ; 63.19,94.94 71.84,94.94 74.22,92.56 83.05,92.56 83.57,92.04 83.92,92.04 84.75,91.21 85.87,91.21 86.02,91.35 CPU1.A5
EDP_VDD_EN: length 32.1
  TOP w0.102: D5201.1 56.77,79.06 57.74,79.06 58.2,79.52 58.2,79.88 58.51,80.2 v2(59.03,80.2)
  L4 w0.102: v2(64.44,87.19) 65.83,87.19 66.54,86.48 76.1,86.48 v2(78.31,84.27)
  BOTTOM w0.102: R404.2 78.43,84.4 v2(78.31,84.27) ; v2(59.03,80.2) 59.25,80.2 60.02,80.97 60.02,82.49 v1(60.78,83.25) 63.76,86.24 D401.1 64.75,86.88 v2(64.44,87.19)
FAN1_DAC_1: length 234.2
  TOP w0.203: KBC24.101 165.29,23.12 165.64,23.47 165.64,24.01 v2(165.66,24.02)
  L3 w0.254: v2(149.38,4.36) 149.38,4.28 148.93,3.83 144.75,3.83 143.2,5.38 141.16,5.38 140.84,5.69 129.82,5.69 129.54,5.41 128.73,5.41 128.41,5.08 96.47,5.08 96.27,5.29 80.88,5.29 76.41,9.76 72.3,9.76 67.03,15.03 62.74,15.03 61.45,16.31 48.88,16.31 42.8,22.39 41.91,22.39 39.9,24.39 39.9,33.77 42.62,36.48 42.62,39.06 42.97,39.41 42.97,40.66 43.76,41.44 43.76,45.92 46.67,48.82 46.67,52.07 47.17,52.57 47.17,57.05 46.05,58.17 46.05,58.7 46.35,59 46.43,59 v2(46.56,59.12)
  L4 w0.254: v2(46.56,59.12) 46.42,59.12 46,59.55 46,71.54 46.17,71.72 v2(46.17,90.24) ; v2(149.38,4.36) 149.38,5.36 150.96,6.94 153.93,6.94 155.56,8.57 155.56,9.24 157.87,11.55 157.87,12.97 159.76,14.86 159.99,15.09 162.33,15.09 164.41,17.17 164.41,22.78 v2(165.66,24.02)
  BOTTOM w0.254: v2(46.17,90.24) 45.79,89.86 43.48,89.86 43.3,90.03 40.46,90.03 v1(40.21,89.78) 39.27,88.84 36.45,88.84 34.49,90.8 34.49,91.51
FAN_TACH1: length 260
  TOP w0.203: 176.28,35.7 KBC24.31
  TOP w0.254: v2(175.46,35.79) 175.55,35.7 176.28,35.7 ; v2(177.21,39.82) 179.3,41.91 R2415.1
  L3 w0.254: v2(46.56,59.76) 46.39,59.76 45.54,58.91 45.54,57.96 46.66,56.84 46.66,53.2 46.16,52.71 46.16,49.08 43.25,46.17 43.25,41.66 42.47,40.87 42.47,39.62 42.11,39.27 42.11,36.69 39.39,33.98 39.39,24.6 39.39,24.18 41.7,21.88 42.59,21.88 48.67,15.8 61.24,15.8 62.53,14.52 66.82,14.52 72.09,9.25 76.2,9.25 80.67,4.78 96.05,4.78 96.26,4.58 128.62,4.58 128.94,4.9 129.75,4.9 130.04,5.19 140.63,5.19 140.95,4.87 142.96,4.87 143.43,4.39 v2(143.43,4.31)
  L4 w0.254: v2(45.38,94.81) 45.38,94.6 46.68,93.29 46.68,67.59 47.19,67.08 47.19,63.87 46.51,63.18 46.51,59.76 v2(46.56,59.76) ; v2(143.43,4.31) 143.43,4.12 143.74,3.81 147.41,3.81 152.8,3.81 156.23,7.24 156.85,7.24 159.27,9.66 159.27,12.39 160.56,13.68 162.94,13.68 164.32,15.05 167.65,15.05 169.74,17.15 169.74,17.85 169.03,18.56 169.03,21.7 169.56,22.23 169.56,25.92 170.63,26.99 170.63,31.36 171.63,32.35 171.63,32.49 174.92,35.79 v2(175.46,35.79)
  BOTTOM w0.254: v2(45.38,94.81) 45.37,94.81 41.54,94.81 R2606.1 EC2602.1 ; v2(177.21,39.82) 176.96,39.57 v1(176.96,38.62) 175.46,37.12 v2(175.46,35.79)
FAN_TACH1_C: length 17.2
  TOP w0.254: AFTP2802.1 51.1,90.91 44.56,90.91 v2(44.02,90.37)
  BOTTOM w0.254: R2606.2 41.54,93.48 42.36,94.3 44.78,94.3 45.29,93.79 45.29,91.76 44.95,91.43 FAN1.3 44,90.38 v2(44.02,90.37)
FAN_VCC1: length 20.8
  TOP w0.305: AFTP2801.1 50.37,91.51 42.75,91.51 v2(42.05,92.21)
  BOTTOM w0.508: FAN1.1 42.89,93.43 42.17,92.71 42.17,92.7 42.06,92.59 42.06,92.22 v2(42.05,92.21) EC2601.1
  BOTTOM w0.559: C2604.1 39.25,92.21 C2603.1 EC2601.1
  BOTTOM w0.635: 34.49,92.78 35.25,92.78 36.14,91.89 D2601.K 38.94,91.89 C2604.1
FCHGFX_CLKN_R: length 9.4
  TOP w0.127: v2(96.14,96.97) 96.14,97.32 v1(95.81,97.65)
  L4 w0.114: v2(96.14,96.97) 95.61,96.44 95.36,96.44 94.97,96.05 94.97,93.39 94.43,92.85 94.43,91.92 v2(94.87,91.48)
  BOTTOM w0.127: v2(94.87,91.48) CPU1.U5 ; v2(96.14,96.97) 96.4,97.22 RN1905.4
FCHGFX_CLKP_R: length 9.1
  TOP w0.127: v2(96.92,96.97) 96.59,96.64 v1(96.59,96.23)
  L4 w0.114: v2(94.87,92.12) 94.66,92.33 94.66,92.75 95.2,93.29 95.2,95.95 95.45,96.21 95.7,96.21 96.03,96.53 96.48,96.53 v2(96.92,96.97)
  BOTTOM w0.127: v2(94.87,92.12) 95.23,91.75 CPU1.U4 ; v2(96.92,96.97) 97.05,97.1 RN1905.3
FON#: length 2.7
  BOTTOM w0.254: R2605.2 36.52,95.83 v1(36.01,95.32) 34.49,95.32
GEVENT4#: length 5.2
  BOTTOM w0.102: CPU1.BA4 110.13,91.9 110.52,92.3 112.27,92.3 112.34,92.37 v1(112.62,92.37) 113.52,92.37 R620.1
GEVENT7#: length 3.3
  TOP w0.102: v1(107.9,86.43) 107.48,86.01 R621.1 106.72,86.01 v2(106.32,86.4)
  BOTTOM w0.102: v2(106.32,86.4) 106.01,86.4 105.46,85.85 CPU1.AR15
GPIO5_AC_BATT: length 2.3
  TOP w0.102: v2(170.79,117.26) 170.79,117.59 v1(171.02,117.82) 171.17,117.97 R7314.1
  BOTTOM w0.102: v2(170.79,117.26) 171.09,117.57 GPU1.T9
GPIO8_ROMSO: length 2.8
  TOP w0.102: R7304.1 170.91,118.94 v1(170.81,119.04) 170.79,119.07 v2(170.79,119.75)
  BOTTOM w0.102: GPU1.P10 170.29,119.08 170.79,119.58 v2(170.79,119.75)
GPIO10_ROMSCK: length 4.4
  BOTTOM w0.102: GPU1.P2 176.12,119.24 176.38,118.98 176.56,118.98 176.57,118.97 177.77,118.97 179.07,117.67 TP7509.1
GPIO16_SSIN: length 6.6
  BOTTOM w0.089: 178.76,119.58 178.74,119.59 176.33,119.59 176.21,119.72 175.76,119.72 175.48,119.99 175.48,120.11 174.75,120.84 GPU1.M4
  BOTTOM w0.102: TP7502.1 180.19,119.47 178.86,119.47 178.76,119.58
GPIO21_BB_EN: length 10.9
  BOTTOM w0.089: GPU1.P7 173.14,119.04 173.36,118.83 173.56,118.83 173.82,118.57 173.82,118.45 174.16,118.12 174.42,118.12 174.46,118.15 174.92,118.15 174.96,118.12 175.24,118.12 175.28,118.15 175.72,118.15 175.76,118.12 176.49,118.12
  BOTTOM w0.102: R7315.1 180.7,115.7 180.26,115.26 178.38,115.26 178.33,115.31 v1(178.05,115.31) 177.95,115.31 177.44,115.82 177.44,117.34 176.66,118.12 176.49,118.12
GPIO71: length 2.6
  TOP w0.102: R632.1 103.68,80.98 v1(103.68,81.32) 104.04,81.68 v2(104.04,81.91)
  BOTTOM w0.102: CPU1.AM21 104.04,82.11 v2(104.04,81.91)
GPIO_17_THERMAL_INT: length 14.3
  BOTTOM w0.089: 176.44,117.91 175.69,117.91 175.63,117.96 175.36,117.96 175.32,117.93 174.87,117.93 174.84,117.96 174.54,117.96 174.5,117.93 174,117.93 GPU1.R6
  BOTTOM w0.102: R7519.2 181.3,113.48 v1(181.81,113.99) 181.81,115.57 R7510.1 181.59,115.7 180.82,114.93 180.49,114.93 180.41,114.85 179.65,114.85 179.58,114.93 179.22,114.93 179.17,114.88 177.95,114.88 177.16,115.66 177.16,117.29 176.54,117.91 176.44,117.91
GPIO_19_CTF: length 6.7
  BOTTOM w0.102: R7501.2 181.38,120.08 180.9,120.57 179.63,120.57 179.3,120.24 178.43,120.24 v1(178.18,120.49) 177.82,120.85 175.5,120.85 GPU1.M2
GPIO_22_ROMCS#: length 1.8
  TOP w0.102: v2(171.57,120.69) 172.06,120.21 TP7507.1
  BOTTOM w0.102: GPU1.N8 171.89,120.4 171.59,120.69 v2(171.57,120.69)
GPIO_VGA_03_DATA: length 16
  TOP w0.14: v2(181.67,111.22) 181.67,111.79 v1(181.68,111.8)
  L3 w0.127: v2(181.67,111.22) 181.27,111.62 176.09,111.62 172.34,115.37 172.34,115.9 172.34,116.04 v2(172.24,116.15)
  BOTTOM w0.14: RN7501.4 181.7,108.56 Q7503.4 181.67,110.28 v2(181.67,111.22) ; v2(172.24,116.15) 171.89,116.49 GPU1.U8
GPIO_VGA_04_CLK: length 15.1
  TOP w0.14: v2(179.8,112.13) v1(179.8,112.74)
  L3 w0.127: v2(172.94,116.15) 172.85,116.06 172.85,115.58 176.3,112.13 v2(179.8,112.13)
  BOTTOM w0.14: v2(172.94,116.15) 172.94,116.16 172.69,116.41 GPU1.U7 ; v2(179.8,112.13) Q7503.1 180.4,111.94 179.96,111.5 179.96,109.26 RN7501.3
GPU_CLKA0_T: length 3.1
  BOTTOM w0.14: v1(158.54,151.86) 158.57,151.88 C7802.1 R7804.2 R7803.2
GPU_CLKA1_T: length 2.8
  BOTTOM w0.14: v1(178.2,152.7) 178.57,153.06 C8903.1 178.64,153.67 R8907.2 R8908.2
GPU_VGA_SVC: length 114.9
  L3 w0.127: v2(177.59,80.43) 178.04,79.99 179.98,79.99 180.23,80.24 188.61,80.24 v2(188.9,79.95)
  L4 w0.127: v2(172.08,119.7) 176.2,115.59 176.2,113.18 181.75,107.62 185.63,107.62 186.95,106.3 186.95,106.05 190.15,102.84 190.15,84.45 189.29,83.59 189.29,83.58 188.68,82.97 188.68,82.82 188.68,80.17 v2(188.9,79.95)
  BOTTOM w0.127: PR8270.2 139.11,89.48 137.96,88.32 137.96,83.71 139.16,82.51 141.25,82.51 143.2,80.56 151.61,80.56 152.89,79.28 v1(169.8,79.28) 170.92,79.28 171.81,80.17 174.74,80.17 175.35,79.56 176.72,79.56 v2(177.59,80.43) ; GPU1.P8 172.08,119.23 v2(172.08,119.7)
GPU_VGA_SVD: length 114.3
  L3 w0.127: v2(176.83,80.43) 177.71,79.56 180.16,79.56 180.41,79.81 188.38,79.81 v2(188.9,79.29)
  L4 w0.127: v2(188.9,79.29) 189.34,79.74 189.34,80.22 189.11,80.45 189.11,82.79 189.72,83.4 189.72,83.41 190.59,84.27 190.59,103.02 187.38,106.23 187.38,106.48 185.76,108.1 181.89,108.1 176.65,113.33 176.65,119.63 v2(177.24,120.21)
  BOTTOM w0.127: v2(176.83,80.43) 176.83,80.28 176.54,79.99 175.53,79.99 174.92,80.6 v1(172.36,80.6) 171.63,80.6 170.74,79.71 153.12,79.71 151.84,80.99 150.8,80.99 150.8,80.99 150.44,80.99 150.44,80.99 143.38,80.99 141.43,82.94 139.33,82.94 138.39,83.88 138.39,88.08 139.03,88.73 140.01,88.73 140.09,88.64 142.63,88.64 PR8271.2 ; v2(177.24,120.21) 176.83,119.8 176.43,119.8 176.19,120.04 GPU1.N1
GPUTHER_ALERT#: length 190.6
  TOP w0.102: KBC24.95 163.02,24.1 164.95,26.03 v2(164.95,26.8) ; PR8274.2 v2(144.6,81.6) ; v2(177.1,113.76) v1(176.54,113.76)
  L3 w0.102: v2(171.14,27.25) 170.58,26.69 165.05,26.69 v2(164.95,26.8) 164.94,26.8 164.49,26.35 163.85,26.35 163.83,26.33 163.47,26.33 163.45,26.35 161.52,26.35 160.61,27.26 158.73,27.26 155.98,30.01 155.98,39.62 155.69,39.91 155.69,39.99 147.37,48.3 147.37,50.79 142.09,56.07 142.09,78.73 142.75,79.39 142.75,79.75 v2(144.6,81.6)
  L4 w0.102: v2(177.1,113.76) 177.1,113.48 182.06,108.52 185.94,108.52 187.98,106.47 187.98,106.25 191.01,103.22 191.01,84.1 190.14,83.23 190.14,83.22 189.53,82.62 189.53,80.62 189.79,80.36 189.79,78.16 191.02,76.93 191.02,70.35 184.27,63.6 184.27,49.93 181.76,47.41 179.37,47.41 178.14,46.19 178.14,42.98 178.31,42.82 178.31,40.72 178.25,40.67 178.25,39.73 178.31,39.68 178.31,36.72 175.62,34.03 173.78,34.03 172.06,32.31 172.06,32.17 171.4,31.51 171.4,27.5 v2(171.14,27.25)
  BOTTOM w0.102: R7519.1 177.38,113.48 v2(177.1,113.76)
GTXN0: length 14.8
  BOTTOM w0.127: 91.34,104 89.14,104 88.19,103.04 88.19,96.65 90,94.84 90,93.95 CPU1.G1 ; 91.34,104 92.04,104 C445.1 ; 91.34,104 v1(91.34,104.13)
GTXN1: length 14.3
  BOTTOM w0.102: 89.31,94.74 89.39,94.66 89.39,93.54 CPU1.F1
  BOTTOM w0.127: 87.31,102.89 87.31,104.92 87.75,105.36 88.45,105.36 C457.1 ; 87.31,102.89 87.31,96.35 87.82,95.84 88.21,95.84 89.31,94.74 ; 87.31,102.89 v1(87.15,102.89)
GTXN2: length 19.7
  BOTTOM w0.127: C478.1 92,106.62 90.17,106.62 ; 90.17,106.62 v1(90.17,106.75) ; 90.17,106.62 87.46,106.62 86.43,105.6 86.43,96.35 87.42,95.37 87.81,95.37 88.87,94.3 88.87,93.92 CPU1.E1
GTXN3: length 18.3
  BOTTOM w0.127: v1(87.37,108.02) 87.5,107.9 ; 87.5,107.9 85.56,105.96 85.56,96.35 87.01,94.9 87.62,94.9 88.24,94.27 88.24,93.51 CPU1.D1 ; 87.5,107.9 87.79,108.19 88.36,108.19 C448.1
GTXP0: length 15.2
  BOTTOM w0.127: 89.74,103.76 92.04,103.76 C477.1 ; 89.74,103.76 89.24,103.76 88.43,102.94 88.43,96.75 90.24,94.94 90.24,93.74 90.01,93.52 90.01,93.26 CPU1.G2 ; 89.74,103.76 v1(89.74,103.6)
GTXP1: length 14.8
  BOTTOM w0.102: CPU1.F2 89.64,93.39 arc(89.66,93.47) 89.67,93.54 arc(89.66,93.61) 89.63,93.66 arc(89.6,93.74) 89.6,93.81 89.6,94.8 89.48,94.91
  BOTTOM w0.127: 87.55,104.18 87.55,96.45 87.92,96.08 88.31,96.08 89.48,94.91 ; 87.55,104.18 v1(87.73,104.18) ; 87.55,104.18 87.55,104.82 87.85,105.12 88.27,105.12 C447.1
GTXP2: length 20.1
  BOTTOM w0.127: 91.36,106.38 92.08,106.38 C452.1 ; 91.36,106.38 v1(91.36,106.21) ; 91.36,106.38 87.56,106.38 86.68,105.5 86.68,96.45 87.52,95.61 87.91,95.61 89.12,94.4 89.12,93.72 88.8,93.4 CPU1.E2
GTXP3: length 18.7
  BOTTOM w0.127: v1(86.26,106.09) 86.14,106.2 ; 86.14,106.2 87.89,107.95 88.36,107.95 C441.1 ; 86.14,106.2 85.8,105.86 85.8,96.45 87.11,95.14 87.72,95.14 88.48,94.37 88.48,93.71 88.57,93.63 88.57,93.37 88.25,93.05 CPU1.D2
H_A20GATE: length 138.9
  TOP w0.102: v2(120.24,76.9) 119.87,76.52 112.95,76.52 v1(112.08,77.39) 110.79,78.68 108.86,78.68 108.3,78.12 106.04,78.12 v2(105.55,77.63) ; KBC24.121 173.29,21.37 v2(172.92,21)
  L3 w0.102: v2(120.24,76.9) 120.24,71.14 125.22,66.16 125.22,54.35 136.27,43.3 136.67,43.3 137.79,42.17 137.79,41.78 142.31,37.25 142.31,31.76 143.18,30.89 143.18,30.83 143.59,30.41 143.59,11.63 144.64,10.58 146.32,10.58 148.46,8.44 153.08,8.44 153.47,8.04 157.23,8.04 158.07,8.88 159.57,8.88 160.64,7.82 v2(162.56,7.82)
  L4 w0.102: v2(162.56,7.82) 162.86,8.12 162.86,8.25 163.57,8.96 168.41,8.96 170.88,11.43 171.85,11.43 173.35,12.94 173.35,20.57 v2(172.92,21)
  BOTTOM w0.102: v2(105.55,77.63) 105.55,77.4 CPU1.AR31 ; R603.1 117.69,76.45 119.79,76.45 v2(120.24,76.9)
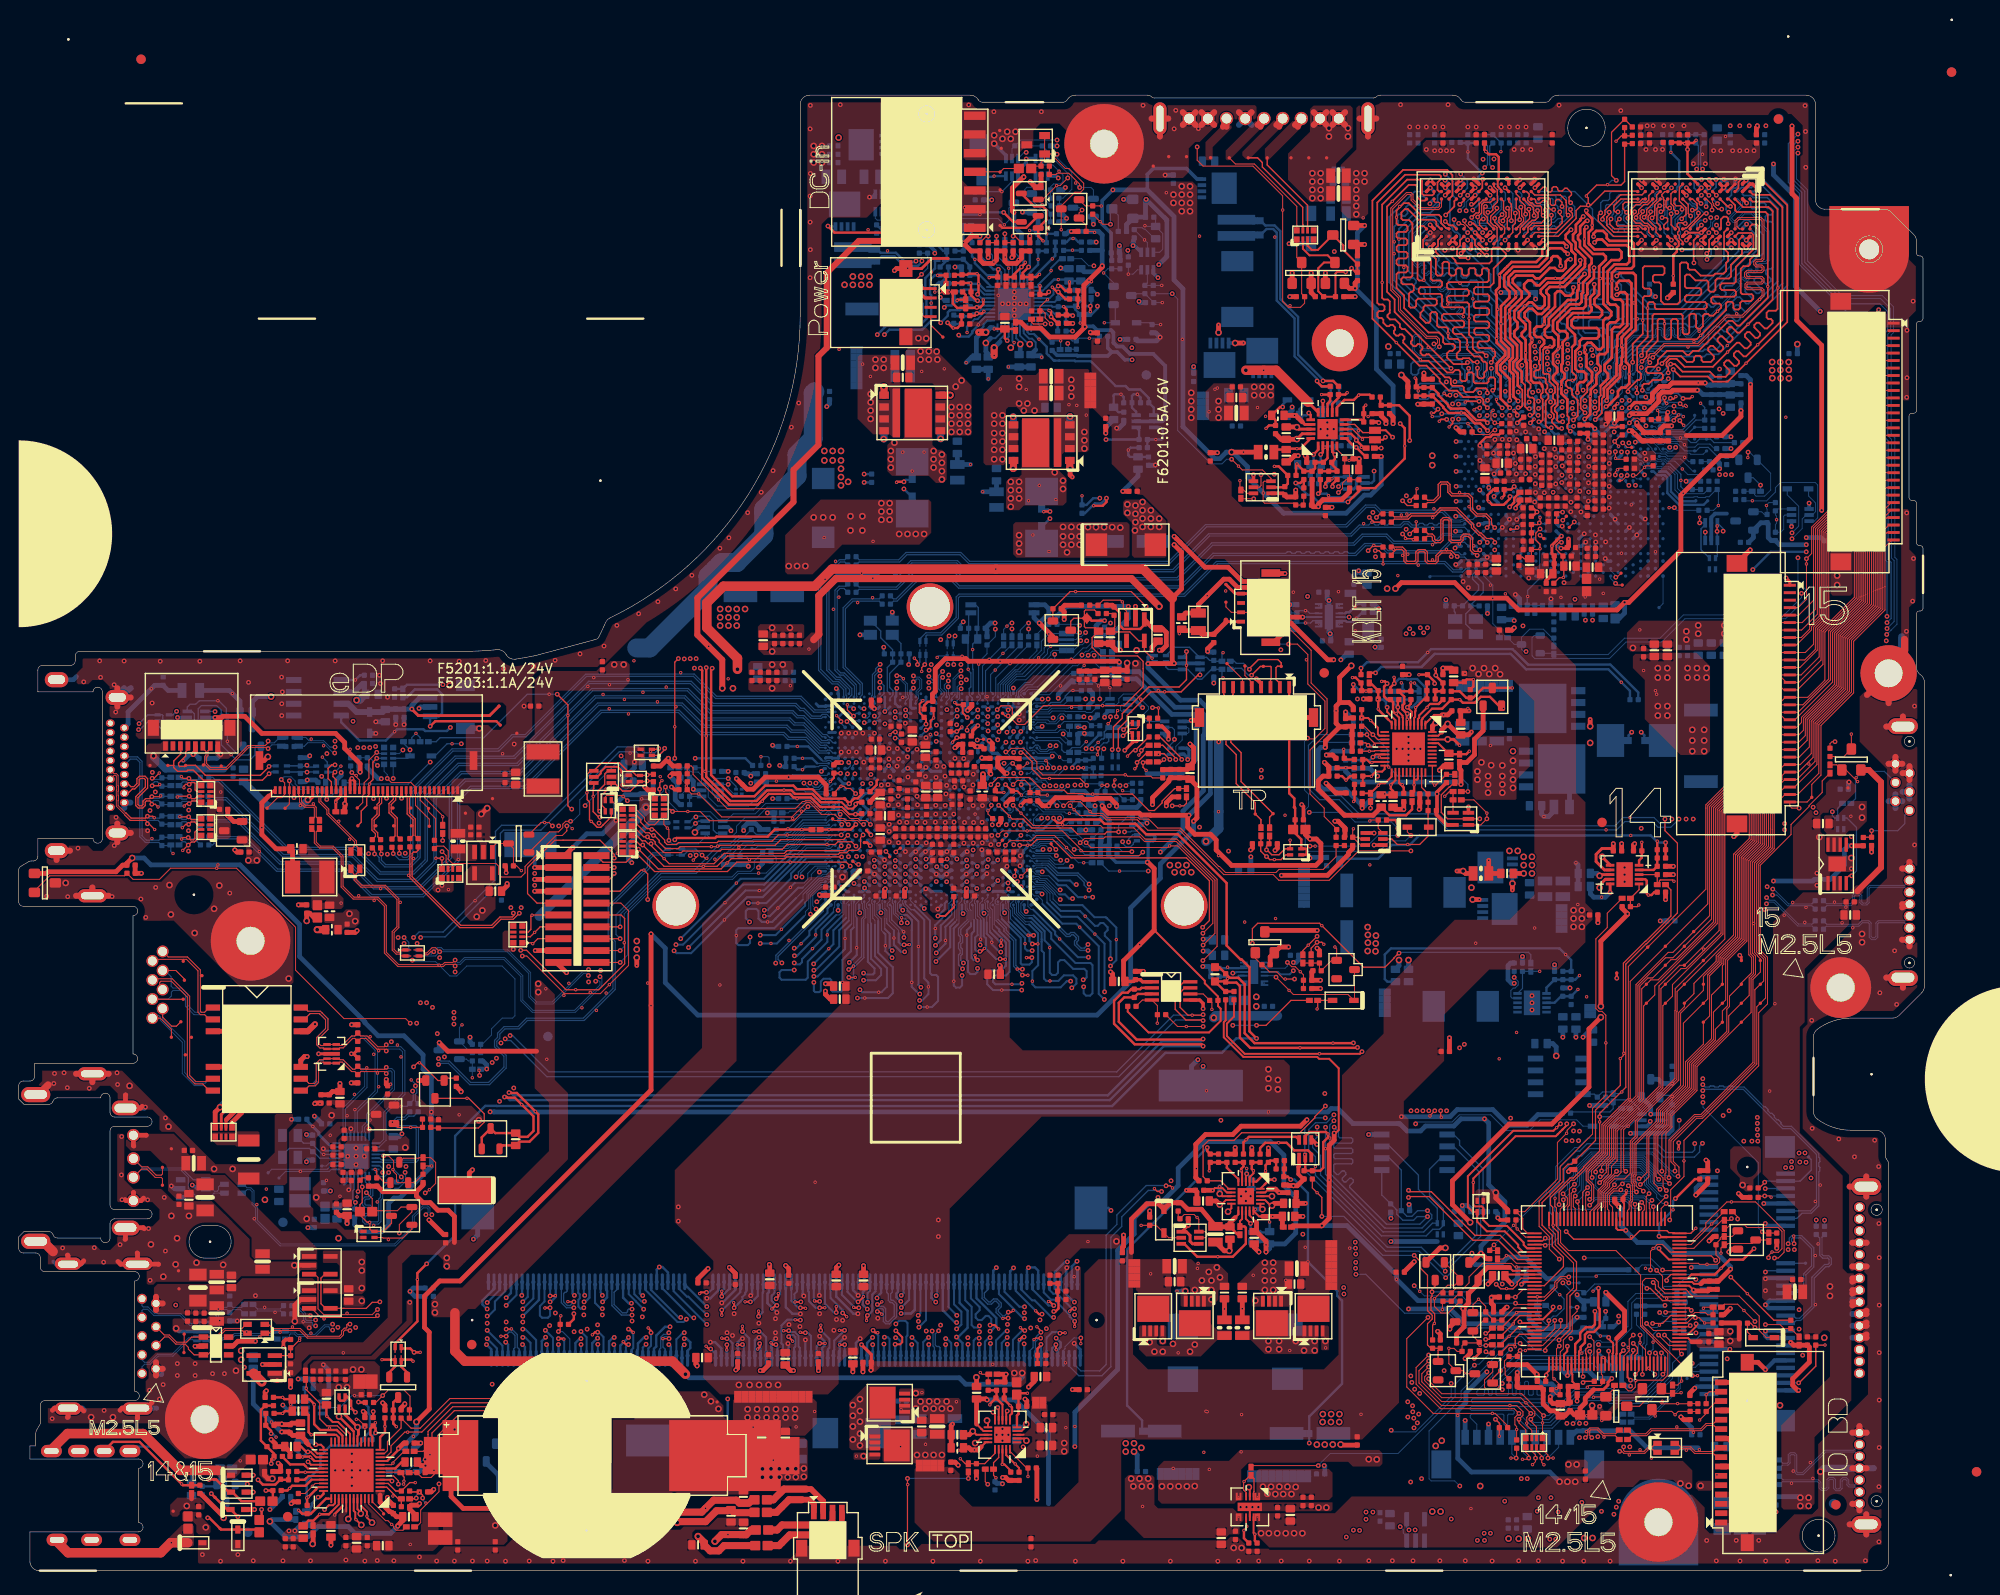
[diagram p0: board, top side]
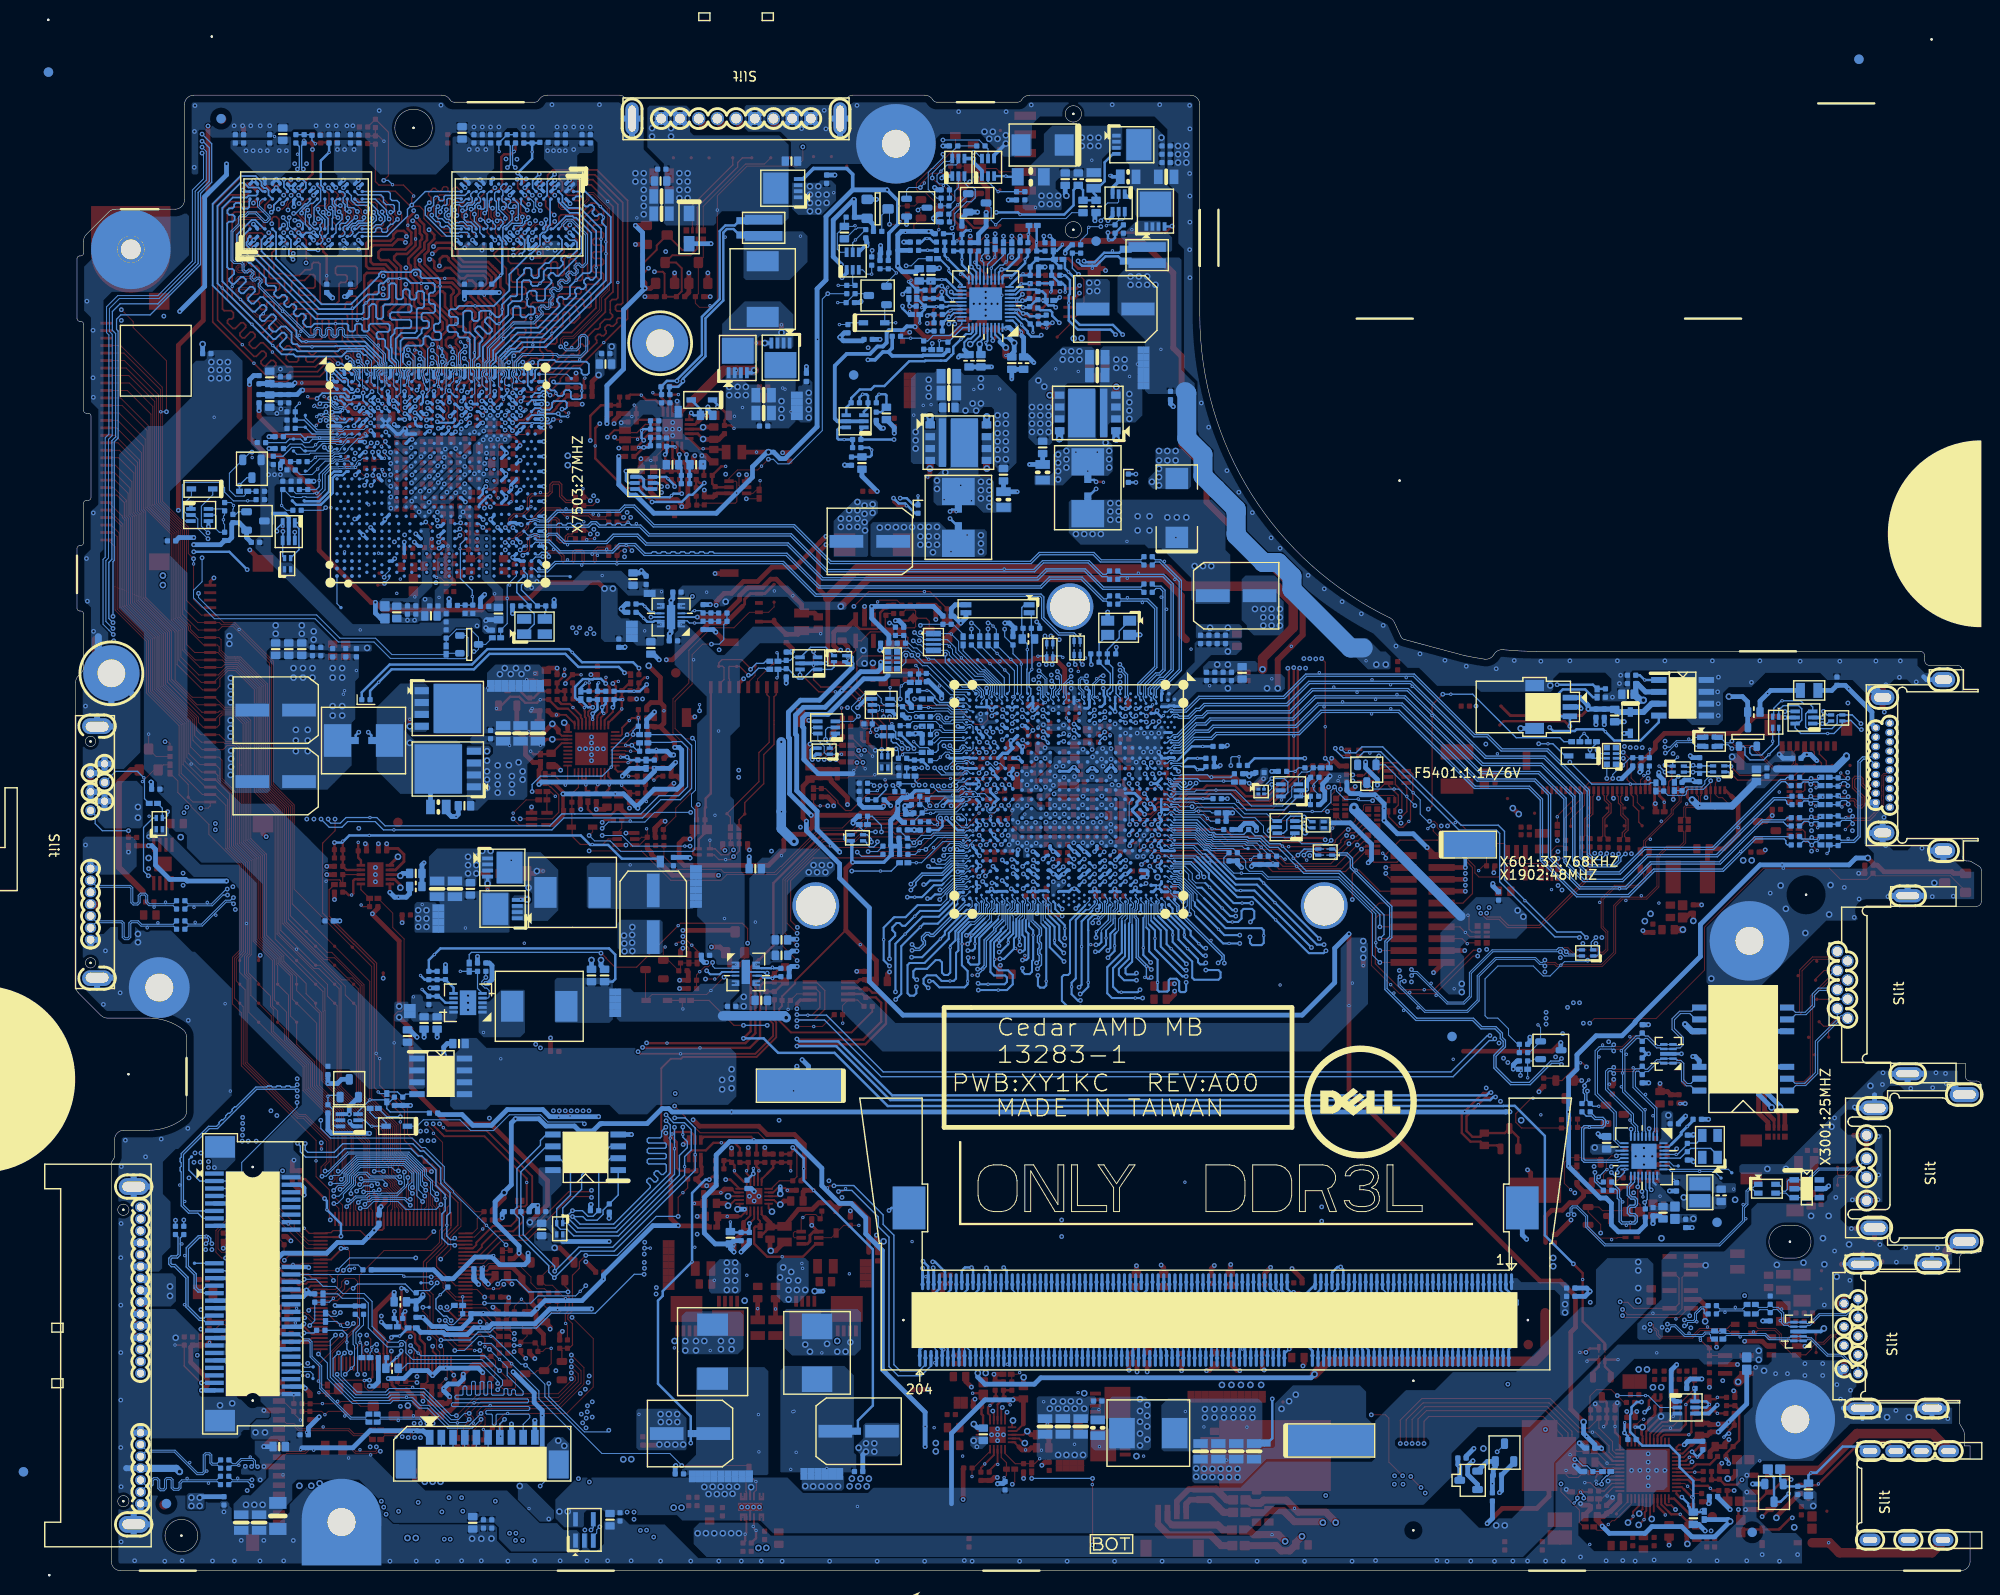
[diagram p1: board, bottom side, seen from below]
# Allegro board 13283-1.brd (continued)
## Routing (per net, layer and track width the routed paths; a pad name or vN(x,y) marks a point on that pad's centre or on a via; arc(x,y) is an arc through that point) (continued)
H_CPUPWRGD_REG: length 83.1
  TOP w0.127: v2(70.18,86.94) v1(70.18,90.31) 70.18,97.23 v2(70.56,97.61) ; v2(103.71,142.82) 103.52,142.82 PR4656.2
  L4 w0.127: v2(70.56,97.61) 71.3,98.34 71.3,104.15 77.98,110.83 77.98,111.92 82.71,116.66 82.71,121.23 83.5,122.02 83.5,122.02 84.58,123.1 84.58,129.25 84.98,129.65 84.98,137.41 85.58,138.01 85.58,139.36 88.55,142.33 94.08,142.33 96.59,144.85 101.67,144.85 v2(103.71,142.82)
  BOTTOM w0.127: R418.1 69.73,86.49 v2(70.18,86.94) ; PR4624.1 v2(103.71,142.82)
H_PROCHOT#: length 313.3
  TOP w0.102: v2(186.51,36.26) 186.64,36.13 R2440.2 C2421.1 ; RN405.6 69.71,81.48 v2(69.94,81.25) v1(71.57,81.25) 72.9,81.25 73.89,80.26 82.92,80.26 v2(84.43,81.76) ; v2(132.1,114.71) 130.78,114.71 PR4426.2
  L3 w0.102: v2(72.28,96.59) 66.75,91.06 66.75,87.58 67.87,86.47 67.87,83.32 v2(69.94,81.25) ; v2(118.64,141.29) 119.02,140.91 121.42,140.91 122.88,139.45 122.88,122.9 131.08,114.71 v2(132.1,114.71)
  L4 w0.102: v2(72.28,96.59) 70.4,96.59 70.05,96.94 70.05,97.73 70.81,98.49 70.81,104.26 77.56,111 77.56,112.09 82.29,116.83 82.29,121.4 83.08,122.19 83.08,122.19 84.16,123.27 84.16,129.42 84.56,129.82 84.56,137.58 85.16,138.19 85.16,139.54 88.38,142.75 93.91,142.75 96.42,145.27 101.85,145.27 102.52,144.59 109.19,144.59 v2(110.11,143.68) 114.15,139.64 v2(115.01,139.64) 116.69,141.32 118.62,141.32 v2(118.64,141.29) ; v2(180.16,50.11) 181.43,51.38 181.43,66.01 185.11,69.69 186.31,69.69 188.14,71.52 188.14,75.79 185.81,78.12 185.81,102.32 184.04,104.08 174.95,104.08 174.22,104.82 164.58,104.82 164.4,105 160.89,105 159.59,106.29 153.41,106.29 149.41,110.3 149.41,114.74 148.59,115.56 148.03,115.56 147.34,114.88 142.08,114.88 141.42,114.22 141.42,114.14 140.54,113.25 133.56,113.25 v2(132.1,114.71)
  BOTTOM w0.102: CPU1.A22 85.92,82 85.68,81.76 v2(84.43,81.76) ; v2(115.01,139.64) 114.46,139.64 113.7,140.4 PR4637.1 ; PR4466.2 118.69,141.24 v2(118.64,141.29) ; v2(186.51,36.26) 186.08,36.69 186.08,43.68 180.16,49.6 v2(180.16,50.11) ; PQ4203.3 108.77,148.52 108.3,148.05 107.86,148.05 107.62,147.81 107.62,146.9 108.02,146.5 108.53,146.5 109.8,145.23 109.8,144.01 110.11,143.71 v2(110.11,143.68)
H_PROCHOT#_EC: length 6.1
  TOP w0.102: v1(182.09,33.98) 182.09,34.53 R2438.2 182.7,34.88 182.84,35.01 185.42,35.01 Q2401.D 187.06,35.39 R2440.1
H_RCIN#: length 144.5
  TOP w0.102: KBC24.122 173.69,21.44 173.68,21.43 173.68,21 v2(173.68,21) ; v2(126.67,65.3) 128.19,66.81 128.19,73.99 123.88,78.3 120.48,78.3 119.29,79.49 117.21,79.49 115.97,79.49 115.71,79.75 108.53,79.75 v1(107.21,81.07) v2(106.37,81.91)
  L3 w0.102: v2(126.67,65.3) 126.24,64.86 126.24,57.96 127.89,56.31 127.89,53.41 138.73,42.56 138.73,42.17 145.3,35.6 145.3,35.02 145.3,34.27 146.02,33.55 146.02,31.92 146.37,31.57 146.37,14.85 150.2,11.03 153.84,11.03 154.31,10.56 161.54,10.56 162.86,9.24 163.15,9.24 163.55,8.83 164.64,8.83 166.17,7.31 v2(167.21,7.31)
  L4 w0.102: v2(167.21,7.31) 171.1,11.21 172.01,11.21 172.5,11.21 173.68,12.39 v2(173.68,21)
  BOTTOM w0.102: CPU1.AR23 105.55,81.1 106.15,81.1 106.37,81.32 v2(106.37,81.91) ; v2(173.68,21) 173.68,24.18 173.86,24.36 173.86,25.49 173.05,26.31 R2412.1
HDA_CODEC_BITCLK: length 253.9
  TOP w0.114: v2(59.61,13.61) 59.61,15.99 59.1,16.5 46.86,16.5 44.83,14.47 44.83,12.06 44.42,11.65 v1(44.42,10.74) 44.42,10.28 44.12,9.98 43.11,9.98 EC2709.1 41.78,10.5 R2720.1
  L4 w0.102: v2(108.02,100.78) 108.43,100.37 112.29,100.37 112.88,100.96 112.88,101.41 113.35,101.89 115.7,101.89 115.91,102.1 120.67,102.1 120.85,101.92 131.65,101.92 134.21,99.36 135.01,99.36 135.89,98.48 135.89,96.79 140.89,91.78 140.89,91.46 142.57,89.78 142.57,84.24 144.14,82.67 144.14,81.35 143.76,80.97 143.76,66.06 144.17,65.65 144.17,59.4 149.19,54.38 152.14,54.38 155.71,50.81 155.71,47.88 152.35,44.52 152.35,36.57 152.08,36.3 152.08,31.3 152.7,30.68 152.7,27.06 152.66,27.02 152.66,25.68 152.91,25.43 152.91,20.97 152.55,20.62 152.55,15.23 149.96,12.64 148.77,12.64 146.26,10.13 144.14,10.13 140.22,6.21 138.82,6.21 138.66,6.37 97.1,6.37 96.93,6.55 86.94,6.55 86.56,6.16 78.54,6.16 70.69,14.01 63.83,14.01 62.76,15.08 60.81,15.08 59.61,13.89 v2(59.61,13.61)
  BOTTOM w0.114: R616.2 v2(108.02,100.78)
HDA_CODEC_BITCLK_R: length 7.5
  BOTTOM w0.114: CPU1.AN2 104.2,93.41 104.51,93.72 104.51,95.54 v1(106.04,97.07) 106.35,97.38 106.35,97.39 R616.1
HDA_CODEC_RST#: length 267.2
  TOP w0.114: v2(62.15,13.61) 62.15,16.11 59.84,18.42 46.12,18.42 42.95,15.25 41.98,15.25 R2917.2 40.9,15.27 39.44,13.81 39.44,12.86 39.12,12.54 HDA27.11
  L4 w0.102: v2(62.15,13.61) 63.17,12.59 70.1,12.59 78.08,4.61 93.76,4.61 94.27,5.12 96.34,5.12 96.51,4.95 138.07,4.95 138.23,4.79 140.81,4.79 144.73,8.71 146.85,8.71 149.28,11.14 151.35,11.14 155.15,14.94 155.15,22.94 155.33,23.12 155.33,32.66 153.97,34.01 153.97,43.16 157.83,47.02 157.83,50.7 152.73,55.8 149.78,55.8 146.58,59 146.58,68.49 145.18,69.89 145.18,76.48 146.45,77.75 146.45,88.6 137.45,97.61 137.45,99.9 135.5,101.85 134.17,101.85 131.88,104.13 115.93,104.13 115.16,103.37 108.19,103.37 v2(106.25,101.42)
  BOTTOM w0.114: v2(106.25,101.42) 106.19,101.37 106,101.37 v1(105.71,101.08) 105.36,100.73 R614.1
HDA_CODEC_RST#_R: length 6.2
  BOTTOM w0.114: CPU1.AL1 103.1,96.82 v1(103.81,97.53) 104.08,97.8 104.08,97.81 105.33,99.06 R614.2
HDA_CODEC_SDIN0: length 3.4
  TOP w0.114: R2718.2 41.22,12.77 40.04,11.59 v1(40.04,11.51) 39.86,11.34 HDA27.8
HDA_CODEC_SDOUT: length 258.1
  TOP w0.114: v2(60.25,13.61) 60.25,16.23 59.35,17.12 46.6,17.12 44.21,14.73 44.21,12.63 v1(43.99,12.41) v2(43.48,11.9)
  L4 w0.102: v2(108.02,101.41) 108.28,101.41 108.71,100.98 112.04,100.98 112.27,101.21 112.27,101.67 113.1,102.5 115.44,102.5 115.66,102.71 120.93,102.71 121.1,102.53 131.9,102.53 132.13,102.3 132.15,102.3 134.47,99.99 136.2,99.99 136.63,99.56 136.63,96.9 141.5,92.03 141.5,91.71 143.28,89.93 143.28,84.4 145.03,82.64 145.03,81.37 144.37,80.71 144.37,69.55 145.77,68.16 145.77,59 145.77,59 145.77,58.66 149.44,54.99 152.39,54.99 156.32,51.06 156.32,47.63 153.16,44.46 153.16,33.68 153.78,33.06 153.78,14.72 151.09,12.03 149.02,12.03 146.51,9.52 144.39,9.52 140.48,5.61 138.56,5.61 138.41,5.76 96.85,5.76 96.67,5.94 87.19,5.94 86.81,5.55 78.29,5.55 70.44,13.4 63.58,13.4 62.51,14.47 61.11,14.47 v2(60.25,13.61)
  BOTTOM w0.114: v2(108.02,101.41) 107.9,101.41 107.13,100.65 R612.1 ; v2(43.48,11.9) 43.3,11.9 42.62,11.23 42.17,11.23 41.56,10.61 EC2708.1 R2719.1
HDA_CODEC_SDOUT_R: length 6.6
  BOTTOM w0.114: CPU1.AN1 103.96,94.09 103.96,95.89 v1(104.46,96.39) R612.2
HDA_CODEC_SYNC: length 263
  TOP w0.114: v2(61.52,13.61) 61.52,16.15 59.7,17.96 46.25,17.96 43.12,14.83 41.61,14.83 v1(41.6,14.83) 41.29,14.83 39.82,13.36 39.82,12.69 39.27,12.14 HDA27.10
  L4 w0.102: v2(61.52,13.61) 61.97,14.06 62.34,14.06 62.51,13.89 63.41,13 70.27,13 78.12,5.15 86.98,5.15 87.36,5.53 96.5,5.53 96.68,5.35 138.24,5.35 138.4,5.2 140.64,5.2 144.56,9.11 146.68,9.11 149.11,11.54 151.18,11.54 154.19,14.55 154.19,22.8 154.92,23.53 154.92,32.49 153.57,33.84 153.57,43.32 157.43,47.19 157.43,50.53 152.56,55.4 149.61,55.4 146.17,58.83 146.17,68.33 144.78,69.72 144.78,76.65 146.05,77.92 146.05,82.6 143.69,84.96 143.69,90.79 137.04,97.44 137.04,99.73 135.33,101.44 133.8,101.44 131.52,103.73 116.1,103.73 115.27,102.9 108.37,102.9 v2(106.25,100.79)
  BOTTOM w0.114: R613.1 106.25,99.96 v2(106.25,100.79)
HDA_CODEC_SYNC_R: length 7.6
  BOTTOM w0.114: CPU1.AM2 103.65,93.06 103.34,93.37 103.34,93.63 103.42,93.71 103.42,96.3 104.8,97.68 v1(105.28,98.16) 105.64,98.52 106.18,99.06 R613.2
HDA_SDIN0: length 272.7
  TOP w0.114: R2718.1 43.25,12.77 43.79,13.3 43.79,14.56 43.79,14.91 46.43,17.54 59.53,17.54 60.88,16.19 v2(60.88,13.61)
  L4 w0.102: v2(104.47,100.76) 104.94,100.76 107.95,103.77 114.99,103.77 115.76,104.54 132.05,104.54 134.34,102.25 135.67,102.25 137.85,100.07 137.85,97.77 146.86,88.77 146.86,77.58 145.59,76.31 145.59,70.06 146.99,68.66 146.99,59.17 149.95,56.21 152.9,56.21 158.24,50.87 158.24,46.85 154.85,43.46 154.85,38.13 154.38,37.66 154.38,34.18 156.22,32.34 156.22,20.73 155.56,20.08 155.56,14.77 151.52,10.73 149.44,10.73 147.01,8.3 144.89,8.3 140.98,4.39 138.06,4.39 137.9,4.54 96.34,4.54 96.17,4.72 94.43,4.72 93.93,4.21 77.77,4.21 69.8,12.18 62.3,12.18 60.88,13.6 v2(60.88,13.61)
  BOTTOM w0.114: CPU1.AK2 102.55,93.04 102.86,93.35 102.86,93.64 102.68,93.81 102.68,97.01 v1(102.69,97.02) 102.69,97.24 103.58,98.13 R633.1 104.47,99.95 v2(104.47,100.76)
HDA_SPKR: length 157.6
  TOP w0.254: v2(110.69,80.54) 110.69,80.45 111.12,80.03 111.54,80.03 111.89,80.38 115.69,80.38 116.15,79.93 117.03,79.93 119.47,79.93 119.6,79.8 119.61,79.8 120.6,78.81 123.98,78.81 129.21,73.58 129.21,66.9 130.68,65.42 130.8,65.42 131.65,64.57 131.65,57.73 v2(132.41,56.96) ; v2(43.63,32.83) 42.64,31.84 v1(42.64,31.16) 42.64,26.68 40.26,24.3 RN2701.2
  BOTTOM w0.254: v2(132.41,56.96) 130.25,56.96 128.7,55.41 122.66,55.41 116.97,49.73 51.13,49.73 51.11,49.74 49.9,49.74 46.68,46.52 46.68,35.88 v2(43.63,32.83) ; v2(110.69,80.54) 110.69,80.45 109.49,79.25 CPU1.BA27
HDA_SPKR_R: length 3.5
  TOP w0.254: D2701.2 39.64,21.22 40.26,21.84 RN2701.3 v1(38.86,22.58)
HDMI_CLK: length 83.2
  BOTTOM w0.127: CPU1.A12 86.64,87.49 85.6,87.49 84.15,88.94 82.29,88.94 81.77,89.46 72.93,89.46 70.56,91.84 65.22,91.84 ; 65.22,91.84 v1(65.22,91.69) ; 65.22,91.84 62.36,91.84 54.23,83.71 48.42,83.71 47.18,82.47 47.18,76 43.29,72.12 37.68,72.12 34.95,74.85 27.59,74.85 24.12,78.31 21.09,78.31 20.9,78.12 20.9,77.82 20.75,77.67 C5403.1
HDMI_CLK#: length 83.7
  BOTTOM w0.127: 63.17,92.08 62.26,92.08 54.13,83.95 48.32,83.95 46.94,82.57 46.94,76.1 43.19,72.36 37.78,72.36 35.05,75.09 27.69,75.09 24.22,78.55 C5402.1 ; 63.17,92.08 v1(63.17,92.24) ; 63.17,92.08 70.66,92.08 73.03,89.7 81.87,89.7 82.39,89.18 84.25,89.18 85.7,87.73 86.43,87.73 86.51,87.82 86.78,87.82 87.1,87.5 CPU1.B12
HDMI_CLK#_R: length 5.8
  TOP w0.127: v1(17.43,78.29) 17.59,78.46 v2(18.14,78.46) 18.37,78.22 18.7,78.22 18.84,78.36 18.84,79.04 19.13,79.32 RN5403.7
  BOTTOM w0.127: C5402.2 19.19,78.3 18.29,78.3 v2(18.14,78.46) 17.93,78.25 17.46,78.25 R5401.1
HDMI_CLK#_R_C: length 13.7
  BOTTOM w0.127: 14.25,78.17 v1(14.25,78.35) ; 14.25,78.17 13.66,78.17 13.2,78.64 13.2,86.6 12.71,87.09 11.41,87.09 HDMI1.12 ; 14.25,78.17 15,78.17 R5414.1 16.2,78.49 R5401.2
HDMI_CLK_R: length 5.5
  TOP w0.127: v1(17.55,77.08) 18.12,77.65 v2(18.14,77.65) 18.46,77.98 18.8,77.98 19.49,78.67 RN5403.8
  BOTTOM w0.127: C5403.2 19.05,78.06 18.55,78.06 v2(18.14,77.65) 17.78,78.01 17.5,78.01 R5402.1
HDMI_CLK_R_C: length 14.8
  BOTTOM w0.127: HDMI1.10 11.95,86.85 12.61,86.85 12.96,86.5 12.96,78.54 13.56,77.93 14.98,77.93 R5414.2 16.2,77.6 R5402.2 16.27,76.99 v1(16.51,76.75)
HDMI_DATA0: length 83.2
  BOTTOM w0.127: C5405.1 20.75,79.7 21.17,80.12 23.41,80.12 27.91,75.62 35.31,75.62 37.97,72.95 42.99,72.95 46.31,76.27 46.31,82.99 47.8,84.48 53.91,84.48 62.04,92.61 70.3,92.61 ; v1(70.3,92.45) 70.3,92.61 ; 70.3,92.61 70.88,92.61 73.25,90.24 82.09,90.24 82.61,89.72 84.04,89.72 85.68,88.08 86.27,88.08 CPU1.A11
HDMI_DATA0#: length 84
  BOTTOM w0.102: 86.75,88.05 86.73,88.05 86.43,88.35 86.17,88.35 86.14,88.32 86.12,88.32
  BOTTOM w0.127: 68.32,92.85 70.98,92.85 73.35,90.48 82.19,90.48 82.71,89.96 84.14,89.96 85.78,88.32 86.12,88.32 ; 68.32,92.85 61.94,92.85 53.81,84.73 47.7,84.73 46.07,83.09 46.07,76.37 42.89,73.19 38.07,73.19 35.41,75.86 28.01,75.86 23.51,80.36 20.98,80.36 20.75,80.59 C5404.1 ; 68.32,92.85 v1(68.32,92.98) ; 86.75,88.05 CPU1.B11
HDMI_DATA0#_R: length 5.2
  TOP w0.127: v1(17.24,80.7) 17.27,80.67 v2(18.18,80.67) 18.48,80.37 19.43,80.37 RN5403.5
  BOTTOM w0.127: C5404.2 19.29,80.43 18.42,80.43 v2(18.18,80.67) 17.9,80.39 17.48,80.39 R5403.1
HDMI_DATA0#_R_C: length 11.6
  TOP w0.089: 11.5,81.06 11.48,81.08 11.45,81.08 10.63,81.89 10.63,82.41 10.67,82.45 10.67,82.94 10.63,82.98 10.63,83.43 10.68,83.47 10.68,83.95 10.63,84 10.63,85.12 10.43,85.32 10.18,85.32 HDMI1.9
  TOP w0.127: 11.5,81.06 12.03,80.54 13.57,80.54 v2(13.77,80.73) 14.34,80.73 v1(14.5,80.58)
  BOTTOM w0.127: R5403.2 16.2,80.78 R5416.1 15.07,80.54 13.97,80.54 v2(13.77,80.73)
HDMI_DATA0_R: length 5.3
  TOP w0.127: RN5403.6 19.13,79.82 18.82,80.13 18.44,80.13 v2(18.18,79.87) 17.86,79.87 v1(17.51,79.51)
  BOTTOM w0.127: C5405.2 18.95,80.19 18.51,80.19 v2(18.18,79.87) 17.9,80.15 17.48,80.15 R5404.1
HDMI_DATA0_R_C: length 12.3
  TOP w0.089: HDMI1.7 10.23,85.13 10.35,85.13 10.44,85.04 10.44,83.92 10.49,83.87 10.49,83.55 10.44,83.51 10.44,82.9 10.48,82.86 10.48,82.53 10.44,82.49 10.44,81.81 11.31,80.94 11.31,80.91 11.33,80.89
  TOP w0.127: v1(14.54,79.32) 13.93,79.93 v2(13.77,79.93) 13.77,80.1 13.57,80.29 11.93,80.29 11.33,80.89
  BOTTOM w0.127: v2(13.77,79.93) 13.77,80.08 13.98,80.29 14.91,80.29 R5416.2 16.2,79.89 R5404.2
HDMI_DATA1: length 84.6
  BOTTOM w0.127: CPU1.A10 86.64,88.59 85.83,88.59 83.93,90.49 82.93,90.49 82.41,91.01 73.58,91.01 71.2,93.39 64.79,93.39 ; 64.79,93.39 61.72,93.39 53.61,85.29 47.37,85.29 44.65,82.57 44.65,75.81 42.58,73.74 38.33,73.74 35.68,76.4 28.23,76.4 22.13,82.49 20.98,82.49 20.83,82.34 20.83,82.14 20.67,81.98 C5406.1 ; 64.79,93.39 v1(64.79,93.24)
HDMI_DATA1#: length 85.2
  BOTTOM w0.127: 62.51,93.63 71.3,93.63 73.68,91.25 82.51,91.25 83.03,90.73 84.03,90.73 85.93,88.83 86.43,88.83 86.51,88.92 86.78,88.92 87.1,88.6 CPU1.B10 ; 62.51,93.63 61.62,93.63 53.51,85.53 47.27,85.53 44.41,82.67 44.41,75.91 42.48,73.98 38.43,73.98 35.78,76.64 28.33,76.64 22.23,82.73 20.39,82.73 C5409.1 ; 62.51,93.63 v1(62.51,93.77)
HDMI_DATA1#_R: length 5.5
  TOP w0.127: RN5402.7 19.1,82.88 18.86,82.63 18.84,82.62 18.5,82.62 v2(18.24,82.88) 17.05,82.88 v1(16.97,82.8)
  BOTTOM w0.127: R5407.1 17.46,82.57 17.92,82.57 v2(18.24,82.88) 18.5,82.62 19.11,82.62 C5409.2
HDMI_DATA1#_R_C: length 12.1
  TOP w0.127: HDMI1.6 11.7,84.2 12,83.9 12.32,83.9 12.65,84.23 12.65,84.75 12.92,85.02 13.52,85.02 13.79,84.75 13.79,83.76 12.76,82.73 12.76,81.98 12.89,81.86 13.17,81.86 13.29,81.98 13.29,82.35 13.56,82.62 14.03,82.62 v2(14.24,82.83) 15.09,82.83 v1(15.18,82.92)
  BOTTOM w0.127: v2(14.24,82.83) 14.41,82.66 15.03,82.66 R5417.1 15.38,82.87 R5407.2
HDMI_DATA1_R: length 4.8
  TOP w0.127: v1(17.71,81.83) 17.96,82.08 v2(18.24,82.08) 18.54,82.38 18.97,82.38 19.12,82.23 RN5402.8
  BOTTOM w0.127: C5406.2 18.97,82.38 18.54,82.38 v2(18.24,82.08) 17.99,82.33 17.5,82.33 R5408.1
HDMI_DATA1_R_C: length 12.3
  TOP w0.127: HDMI1.4 11.7,83.2 12.16,83.66 12.42,83.66 12.89,84.13 12.89,84.65 13.02,84.78 13.42,84.78 13.55,84.65 13.55,83.86 12.52,82.83 12.52,81.88 12.79,81.61 13.27,81.61 13.54,81.88 13.54,82.25 13.66,82.38 14.03,82.38 14.24,82.17 v2(14.24,82.02) 14.62,82.02 v1(14.91,81.73)
  BOTTOM w0.127: R5408.2 15.38,81.98 R5417.2 14.95,82.41 14.45,82.41 14.24,82.2 v2(14.24,82.02)
HDMI_DATA2: length 84.6
  BOTTOM w0.127: 66.77,94.16 71.52,94.16 73.9,91.79 82.73,91.79 83.25,91.27 83.92,91.27 85.95,89.24 86.21,89.24 CPU1.A9 ; 66.77,94.16 v1(66.77,94) ; 66.77,94.16 61.4,94.16 53.39,86.16 47.09,86.16 43.71,82.78 43.71,75.98 43.13,75.4 42.27,74.54 38.63,74.54 36,77.17 28.65,77.17 21.39,84.43 20.97,84.43 20.55,84.02 C5408.1
HDMI_DATA2#: length 85.3
  BOTTOM w0.127: 69.26,94.4 71.62,94.4 74,92.03 82.83,92.03 83.35,91.51 84.02,91.51 86.05,89.48 86.42,89.48 86.75,89.15 CPU1.B9 ; 69.26,94.4 61.3,94.4 53.29,86.4 46.99,86.4 43.47,82.88 43.47,76.08 43.03,75.64 42.17,74.78 38.73,74.78 36.1,77.41 28.75,77.41 21.49,84.68 20.98,84.68 20.75,84.9 C5407.1 ; 69.26,94.4 v1(69.26,94.56)
HDMI_DATA2#_R: length 5.1
  TOP w0.127: RN5402.5 18.98,84.57 18.42,84.57 v2(18.21,84.79) 17.6,84.79 v1(17.41,84.98)
  BOTTOM w0.127: C5407.2 19.19,84.65 18.34,84.65 v2(18.21,84.79) 18.07,84.65 17.41,84.65 R5405.1
HDMI_DATA2#_R_C: length 11.8
  TOP w0.127: v1(15.03,85.36) 14.47,84.8 v2(14.27,84.8)
  L4 w0.114: HDMI1.3 10.27,82.23 10.72,81.78 10.72,81.37 11.23,80.85 11.96,80.85 12.65,81.54 12.65,84.27 13.05,84.68 14.15,84.68 v2(14.27,84.8)
  BOTTOM w0.127: v2(14.27,84.8) 14.4,84.68 15.15,84.68 R5415.1 16.2,84.84 R5405.2
HDMI_DATA2_R: length 5.8
  TOP w0.127: v1(17.68,83.79) 17.68,83.97 17.85,84.15 v2(18.24,84.15) 18.42,84.33 18.79,84.33 18.87,84.26 18.87,83.56 19.05,83.38 RN5402.6
  BOTTOM w0.127: R5406.1 17.55,84.41 17.96,84.41 18.22,84.15 v2(18.24,84.15) 18.26,84.15 18.51,84.41 19.05,84.41 C5408.2
HDMI_DATA2_R_C: length 12.2
  TOP w0.127: v1(15.09,84.14) 14.94,83.99 v2(14.27,83.99)
  L4 w0.114: v2(14.27,83.99) 14.27,84.18 14.01,84.45 13.15,84.45 12.88,84.17 12.88,81.45 12.05,80.62 11.14,80.62 10.62,81.14 10.49,81.27 10.49,81.69 10.27,81.9 10,81.9 HDMI1.1
  BOTTOM w0.127: v2(14.27,83.99) 14.27,84.17 14.54,84.43 14.83,84.43 R5415.2 16.2,83.95 R5406.2
HDMI_EN: length 3.8
  TOP w0.127: v2(89.52,83.16) 88.97,83.71 88.52,83.71 88.28,83.95 v1(87.96,83.95) 87.91,83.95 87.26,83.29 R403.2
  BOTTOM w0.127: CPU1.E21 89.2,82.83 v2(89.52,83.16)
HDMI_HPD_B: length 3.8
  BOTTOM w0.102: R5411.2 48.34,55.44 Q5401.B 47.14,58.13 v1(47.42,58.41)
HDMI_HPD_DET: length 1.4
  TOP w0.127: v2(166.39,112.23) 165.86,111.7 TP7501.1
  BOTTOM w0.127: GPU1.AC14 166.63,112.04 166.44,112.23 v2(166.39,112.23)
HDMI_HPD_E: length 3.3
  BOTTOM w0.102: Q5401.E 47.9,54.74 48.1,54.55 R5412.1 R5419.2 v1(48.52,52.75)
HDMI_PCH_DET: length 68.1
  TOP w0.102: v2(49.3,53) 49.3,53.5 v1(49.24,53.56)
  L4 w0.102: v2(49.3,53) 49.35,53.05 49.35,53.7 51.65,56 51.91,56 57.05,61.14 57.05,77.2 58.68,78.83 58.89,78.83 61.75,81.7 66.37,81.7 66.88,82.21 67.38,82.21 67.92,81.68 72.03,81.68 73.05,80.66 80.82,80.66 82.63,82.47 83.99,82.47 84.04,82.52 89.78,82.52 91.16,83.89 v2(91.16,84.24)
  BOTTOM w0.102: v2(49.3,53) 49.3,53.55 R5419.1 ; CPU1.H19 91.16,84.01 v2(91.16,84.24)
HDMI_PLL_GND:
  vias: v1(21.61,83.33)
HPD_HDMI_CON: length 78.3
  L3 w0.102: HDMI1.19 10.44,91.34 12.33,91.34 13.38,92.4 23.7,92.4 25.02,91.08 35.58,91.08 v2(35.76,90.9)
  L4 w0.102: v2(35.76,90.9) 35.76,87.06 36.98,85.84 36.98,72.76 41.81,67.94 41.81,67.4 42.11,67.1 v2(42.11,65.34)
  BOTTOM w0.102: R5411.1 R5410.1 49.58,56.33 50.57,57.32 50.57,57.98 51.72,59.13 52.83,59.13 53.08,59.39 53.08,63.33 51.7,64.71 47.93,64.71 46.86,63.64 46.12,63.64 v1(44.97,64.8) 44.6,65.17 42.39,65.17 42.22,65.34 v2(42.11,65.34)
IMVP_PWRGD: length 266.9
  TOP w0.127: KBC24.107 167.69,23.16 167.61,23.24 167.61,23.69 v2(168.02,24.1) ; Q2602.G 157.67,20.58 v2(158.49,21.4)
  L3 w0.127: v2(168.02,24.1) 169.33,25.4 171.89,25.4 172.52,24.77 174.94,24.77 177.52,22.19 v2(179.02,22.19) ; v2(119.07,130.88) 112.67,130.88 v2(112.21,131.34)
  L4 w0.127: v2(179.02,22.19) 179.02,22.7 182.77,26.45 182.82,26.45 185.65,29.28 185.65,33.14 188.16,35.65 188.16,42.06 188,42.23 188,49.86 187.82,50.04 187.82,62.18 196.58,70.94 196.58,80.05 196.38,80.25 196.38,84.44 195.76,85.06 195.76,93.86 195.47,94.15 195.47,99.23 196.07,99.83 196.07,107.14 195.88,107.33 195.88,135.09 189.94,141.04 189.94,148.21 188.21,149.94 188.21,150.72 185.67,153.26 172.92,153.26 169.66,149.99 165.49,149.99 162.61,152.87 147.98,152.87 145.84,150.74 126.23,150.74 122.97,147.49 122.97,142.83 124.09,141.71 124.09,134.76 120.21,130.88 v2(119.07,130.88)
  BOTTOM w0.127: v2(112.21,131.34) 112.28,131.27 PR4679.2 112.32,130.71 PR4680.2 ; v2(168.02,24.1) v1(167.21,23.28) 166.93,23.01 160.1,23.01 v2(158.49,21.4)
INT_SERIRQ: length 148.7
  TOP w0.102: v2(175.01,21.01) 174.89,21.12 KBC24.125
  L3 w0.102: v2(141.73,30.29) 141.32,29.89 141.32,29.41 142.02,28.71 142.02,10.98 143.85,9.14 144.04,8.96 145.71,8.96 147.81,6.86 152.42,6.86 152.92,6.37 v2(162.43,6.37)
  L4 w0.102: v2(162.43,6.37) 163.17,7.1 163.17,8.12 163.7,8.65 164.97,8.65 166.85,6.77 167.28,6.77 171.41,10.9 172.62,10.9 174.25,12.52 174.25,18.03 175.01,18.79 v2(175.01,21.01) ; v2(141.73,30.29) 141.73,30.47 138.88,33.32 138.88,41.44 128.27,52.05 128.27,56.74 128.37,56.84 128.37,61.11 127.91,61.56 127.91,73.73 125.25,76.4 116.63,76.4 116.43,76.6 114.24,76.6 112.66,78.17 107.73,78.17 v2(107.2,78.7)
  BOTTOM w0.102: v2(175.01,21.01) v1(174.35,21.67) 174.01,22 174.01,24.08 174.17,24.23 174.17,25.62 173.48,26.31 173.48,26.98 R2441.1 ; CPU1.AV29 106.8,78.3 v2(107.2,78.7)
INT_TP#: length 2.6
  TOP w0.102: AFTP6241.1 131.16,95.8 131.75,95.22 131.75,94.71 131.9,94.56 TPAD1.5
ISOLATE#: length 4.6
  TOP w0.102: R3014.2 36.78,42.04 R3015.1 36.3,41.57 v2(36.3,40.58)
  BOTTOM w0.102: LOM30.20 36.28,40.6 v2(36.3,40.58) 36.19,40.47 v1(36.19,40)
JACK_PLUG: length 13.7
  BOTTOM w0.254: HPMIC1.5 11.9,13.11 12.06,13.28 14.83,13.28 17.63,10.48 18.21,10.48 v1(18.23,10.46) 18.49,10.2 C2902.1 18.83,9.02 R2905.1 20.93,9.02 Q2901.G 21.51,9.6 R2914.1
JACK_PLUG_DET: length 12.6
  TOP w0.254: R2925.2 R2924.1 17.56,9.15 v1(17.42,9.29) 12.93,13.78 10.08,13.78 9.15,12.85 HPMIC1.6
JDREF: length 2.9
  TOP w0.102: v1(36.12,16.2) 36.33,16.2 R2707.1 37.03,15.5 HDA27.15
JTAG_TCK_VGA: length 7.1
  BOTTOM w0.089: GPU1.L3 175.43,121.64 175.76,121.32 176.17,121.32
  BOTTOM w0.127: 176.17,121.32 179.05,121.32 TP7506.1 179.78,121.61 181.37,121.61 R7323.1
JTAG_TDI_VGA: length 9.9
  BOTTOM w0.089: GPU1.L5 174.63,121.64 174.98,121.29 175.5,121.29 175.72,121.07 176.22,121.07
  BOTTOM w0.127: R7325.1 181.35,120.72 180.97,121.1 TP7505.1 179.79,121.1 179.42,120.73 178.86,120.73 178.51,121.09 176.24,121.09 176.22,121.07
JTAG_TDO: length 5.5
  BOTTOM w0.089: GPU1.K4 175.03,122.44 175.36,122.12 175.62,122.12 175.66,122.15 176.59,122.15 176.65,122.09 177.97,122.09 178.04,122.15
  BOTTOM w0.127: TP7504.1 179.27,123.39 178.04,122.15
JTAG_TMS_VGA: length 4.8
  BOTTOM w0.127: R7324.1 180.22,122.37 TP7508.1 178.53,121.63 175.9,121.63 GPU1.L1
JTAG_TRST#_VGA: length 10.7
  BOTTOM w0.089: 177.2,120.63 176.05,120.63 175.94,120.52 175.36,120.52 175.17,120.71 175.17,120.82 174.76,121.23 174.13,121.23 173.72,121.64 GPU1.L6
  BOTTOM w0.127: R7322.1 181.67,119.26 180.72,120.21 179.81,120.21 179.43,119.83 TP7503.1 178.23,119.83 177.43,120.63 177.2,120.63
KB_BL_CTRL: length 81.6
  TOP w0.102: Q6203.G 132.28,65.54 R6208.1 133.04,64.84 133.8,64.08 134.57,64.08 135.33,63.31 v1(135.48,63.31) v2(136.47,63.31) ; v2(175.84,32.18) 175.92,32.1 KBC24.22
  L3 w0.102: v2(136.47,63.31) 137.74,62.04 137.74,57.56 145.64,49.66 145.64,47.39 151.31,41.72 151.31,39.54 153.79,37.05 153.79,32.99 154.2,32.59 154.2,30.38 159.37,25.21 165.68,25.21 v2(166.04,24.86)
  L4 w0.102: v2(166.04,24.86) 165.99,24.91 165.99,27.23 165.63,27.58 165.63,29.46 164.67,30.42 164.67,31.44 166.7,33.47 v2(167.46,33.47)
  BOTTOM w0.102: v2(167.46,33.47) 174.54,33.47 v2(175.84,32.18)
KB_BL_CTRL#: length 55.1
  TOP w0.305: AFTP6247.1 130.12,104.56 KBLIT1.4 131.67,104.56 132.28,103.95 132.28,103.45 132.53,103.19
  TOP w0.508: v2(138.88,68.52) 133.45,68.52 Q6203.D ; 132.53,103.19 134.31,101.41 136.09,101.41 140.03,97.48 v2(140.66,97.48)
  L3 w0.508: v2(138.88,68.52) 139.65,69.28 139.65,78.16 141.42,79.94 141.42,87.57 139.01,89.99 138.11,89.99 136.47,91.63 136.47,93.29 v2(140.66,97.48)
KB_DET#: length 236.4
  TOP w0.102: v2(113.55,77.9) 114,78.36 116.05,78.36 116.21,78.53 119.93,78.53 120.43,78.03 123.82,78.03 127.96,73.9 127.96,68.21 v2(126.69,66.95) ; KB2.30 200.37,110.3 199.63,109.56 199.63,105.31 199.63,102.81 196.28,99.46 196.28,93.94 192.78,90.45 192.78,85.13 191.8,84.15 AFTP6202.1 191.3,82.26 KB1.30 189.45,81.84 189.68,81.6 v2(190.45,81.6)
  L3 w0.102: v2(161.36,9.85) 160.88,10.33 154.21,10.33 153.74,10.8 150.1,10.8 146.14,14.76 146.14,31.47 145.79,31.82 145.79,33.45 145.07,34.18 145.07,35.51 138.5,42.07 138.5,42.47 127.66,53.31 127.66,54.56 126.01,56.21 126.01,66.26 v2(126.69,66.95)
  L4 w0.102: v2(161.36,9.85) 161.1,10.11 161.1,12.23 161.37,12.5 163.48,12.5 163.55,12.56 168.79,12.56 170.91,14.69 170.91,18.33 170.84,18.41 170.84,21.53 171.21,21.89 171.21,25.28 172.11,26.18 172.11,31.22 172.77,31.88 172.77,32.02 174.07,33.32 175.91,33.32 179.02,36.42 179.02,39.97 178.97,40.02 178.97,40.38 179.02,40.43 179.02,43.19 178.85,43.36 178.85,45.89 179.64,46.68 182.05,46.68 184.99,49.61 184.99,63.3 191.74,70.05 191.74,77.22 190.57,78.39 190.57,81.48 v2(190.45,81.6)
  BOTTOM w0.102: R604.1 114.74,77.46 113.99,77.46 v2(113.55,77.9) 113.1,78.35 112.35,78.35 112,78.7 CPU1.BA28
KB_LED_BL_DET: length 40.8
  TOP w0.102: R6207.1 R6206.1 140.92,76.42 139.55,75.05 134.81,75.05 134.48,74.72 129.08,74.72 128.45,75.35 128.37,75.35 124.26,79.47 121.84,79.47 120.88,80.43 119.89,80.43 119.74,80.59 116.42,80.59 115.96,81.04 114.81,81.04 v1(114.6,81.25) 113.56,82.29 112.29,82.29 111.86,81.86 v2(111.75,81.86)
  BOTTOM w0.102: CPU1.AV21 107.1,82.85 107.67,82.85 107.72,82.8 108.02,82.8 108.07,82.85 108.33,82.85 108.38,82.8 108.72,82.8 108.77,82.86 109.03,82.86 109.19,82.69 110.92,82.69 v2(111.75,81.86)
KB_LED_DET_C: length 34.2
  TOP w0.102: R6206.2 140.92,79.25 C6203.1 140.98,79.38 139.65,80.71 139.65,81.6 138.12,83.13 138.12,87.83 139.95,89.65 139.95,93.29 138.25,95 138.25,98.49 135.84,100.91 133.42,100.91 131.77,102.56 KBLIT1.2 129.71,102.56 129.13,103.14 AFTP6246.1
KBC_BEEP: length 163.3
  TOP w0.203: KBC24.118 172.09,20.71 v2(172.41,20.39)
  TOP w0.254: v1(42.94,23.37) v2(42.3,23.37) 41.88,23.78 RN2701.1
  L3 w0.254: v2(62.76,10.15) 66.11,10.15 69.62,6.65 75.97,6.65 80.44,2.18 128.84,2.18 129.71,3.05 131.05,3.05 131.85,2.25 146.28,2.25 146.5,2.48 156.75,2.48 157.43,3.16 v2(157.43,4.01)
  L4 w0.254: v2(62.76,10.15) 62.76,10.25 62.15,10.86 59.21,10.86 57.78,9.44 53.31,9.44 52.6,10.15 47.29,10.15 45.57,11.88 45.57,17.93 42.3,21.2 v2(42.3,23.37) ; v2(172.41,20.39) 172.5,20.39 172.92,19.96 172.92,13.12 171.67,11.87 170.7,11.87 168.99,10.15 168.35,10.15 164.02,10.15 157.87,4.01 v2(157.43,4.01)
  BOTTOM w0.254: v1(172.97,20.36) 172.95,20.36 172.92,20.39 v2(172.41,20.39)
KBC_BEEP_R: length 3.5
  TOP w0.254: v1(42.18,22.41) 42.01,22.58 RN2701.4 40.91,21.84 41.54,21.22 D2701.1
KBC_ON#_GATE: length 10.7
  TOP w0.102: C2417.1 152.92,27.58 152.14,27.58 151.43,28.29 v1(151.43,29.1) 152.05,29.72 R2433.2 152.35,30.04 152.85,30.55 153.6,30.55 Q2402.G 154.14,31.36 Q2403.G
KBC_ON#_GATE_L: length 3.1
  TOP w0.102: R2431.1 154.06,29.66 R2432.2 R2433.1 152.29,28.78 v1(152.29,27.93)
KBC_PWRBTN#: length 275
  L3 w0.102: v2(166.85,46.02) 167.59,45.28 179.82,45.28 180.4,44.7 188.72,44.7 v2(189.63,43.78)
  L4 w0.102: v2(164.82,28.19) 164.82,29.08 164.06,29.84 164.06,33.24 166.8,35.98 166.8,38.27 165.96,39.11 165.96,41.87 166.85,42.77 v2(166.85,46.02) ; v2(94.18,143.83) 93.44,143.83 92.99,144.29 92.99,145.12 96.14,148.28 102.25,148.28 103.14,147.39 113.74,147.39 114.81,146.32 120.78,146.32 121.46,147.01 121.46,149.12 123.89,151.55 145.46,151.55 147.65,153.74 162.83,153.74 165.85,150.72 169.36,150.72 172.66,154.02 187.74,154.02 188.94,152.82 188.94,150.24 190.68,148.5 190.68,142.97 196.8,136.85 196.8,99.53 196.2,98.93 196.2,94.45 196.58,94.06 196.58,85.26 198.05,83.78 198.05,80.47 198.85,79.67 198.85,71.82 189.39,62.36 188.8,61.77 188.8,50.45 188.97,50.27 188.97,44.44 v2(189.63,43.78)
  BOTTOM w0.102: R2427.1 163.95,27.77 164.4,27.77 v2(164.82,28.19) ; R6102.1 96.34,142.36 95.6,143.09 95.6,143.63 v1(95.48,143.76) 95.4,143.83 v2(94.18,143.83)
KBC_PWRBTN#_C: length 12
  TOP w0.127: v2(96.57,138.73) 96,138.16 96,135.06 96.85,134.2 SW1.4 97.55,133.32 AFTP6801.1
  BOTTOM w0.127: v2(96.57,138.73) 97.23,139.39 EC6104.1 R6102.2
KBC_VCORF: length 3.2
  TOP w0.203: KBC24.44 171.69,38.77 171.73,38.8 171.73,39.31 171.61,39.43 C2416.1
  TOP w0.254: C2416.1 171.61,40 171.96,40.35 v1(171.96,40.66)
KCOL0: length 104.4
  TOP w0.102: KB2.13 200.55,123.9 199.22,123.9 196.4,121.09 196.4,113.7 193.62,110.92 193.62,101.72 192.59,100.7 192.59,97.79 190.66,95.86 KB1.13 188.57,95.86 187.69,96.74 186.93,96.74 186.6,96.74 184.33,94.47 184.33,83.51 182.09,81.28 182.09,68.21 178.32,64.43 177.82,64.43 AFTP6207.1 175.66,62.28 175.66,51.75 170.98,47.06 170.98,43.87 170.38,43.27 170.38,42.47 169.57,41.66 169.57,41.34 168.94,40.72 168.94,39.27 168.09,38.42 KBC24.53
KCOL1: length 104.8
  TOP w0.102: KB2.15 200.55,122.3 199.46,122.3 196.81,119.65 196.81,113.53 196.56,113.28 196.56,104.09 193,100.53 193,96.99 190.27,94.26 KB1.15 188.8,94.26 188.41,94.65 188.41,95.45 187.53,96.33 186.76,96.33 184.73,94.3 184.73,83.34 182.5,81.11 182.5,67.59 AFTP6206.1 177.19,62.28 177.19,59.94 177.16,59.91 177.16,52.67 171.68,47.19 171.68,42.97 v2(171.9,42.74) ; v2(170.91,42.74) 170.91,42.72 169.77,41.57 169.77,41.26 169.14,40.63 169.14,39.18 168.49,38.53 KBC24.52
  BOTTOM w0.102: v2(171.9,42.74) v2(170.91,42.74)
KCOL2: length 103.7
  TOP w0.102: KB2.14 200.55,123.1 199.34,123.1 196.61,120.37 196.61,113.62 196.35,113.37 196.35,104.17 192.79,100.61 192.79,97.45 190.4,95.06 KB1.14 189.09,95.06 187.61,96.54 186.68,96.54 184.53,94.39 184.53,83.42 182.3,81.19 182.3,68.12 176.89,62.72 176.89,61.48 AFTP6226.1 175.87,60.45 175.87,51.67 171.4,47.19 171.4,42.61 171.04,42.26 170.74,42.26 169.97,41.49 169.97,41.17 169.35,40.55 169.35,39.1 168.89,38.65 KBC24.51
KCOL3: length 100.2
  TOP w0.102: KB2.16 200.55,121.5 199.64,121.5 197.01,118.88 197.01,113.45 196.76,113.2 196.76,104 193.2,100.44 193.2,95.3 191.36,93.46 KB1.16 188.97,93.46 187.91,92.4 186.51,92.4 185.11,91 185.11,78.34 183.46,76.69 183.46,76.69 183.44,76.66 183.44,68.02 AFTP6208.1 177.39,61.98 177.39,59.86 177.36,59.83 177.36,52.59 172.92,48.14 172.92,46.5 172.39,45.96 172.39,42.54 171.78,41.93 170.7,41.93 170.18,41.4 170.18,41.09 169.55,40.46 169.55,39.45 169.55,39.02 169.29,38.76 KBC24.50
KCOL4: length 99.6
  TOP w0.102: v2(173.33,41.95) 173.5,41.95 174.17,42.61 174.17,46.51 175.62,47.96 175.62,49.2 178.3,51.88 178.3,54.45 180.2,56.36 AFTP6224.1 180.87,59.36 180.87,63.67 182.19,64.98 182.19,65.57 184.25,67.63 184.25,76.32 184.27,76.35 184.27,76.36 185.93,78.01 185.93,90.6 186.91,91.58 188.16,91.58 188.44,91.3 188.44,90.54 188.72,90.26 KB1.20 190.19,90.26 190.7,90.77 190.7,91.32 194.22,94.83 194.22,100.31 197.57,103.66 197.57,104.46 197.57,112.86 197.83,113.11 197.83,116.54 199.59,118.3 200.55,118.3 KB2.20 ; KBC24.49 169.69,38.87 169.75,38.93 169.75,39.36 169.75,40.33 170.66,41.23 170.66,41.26 v2(170.69,41.3)
  BOTTOM w0.102: v2(173.33,41.95) 173.2,41.83 170.99,41.83 170.69,41.53 v2(170.69,41.3)
KCOL5: length 96.6
  TOP w0.102: v2(171.55,41.39) 171.4,41.39 170.87,40.86 170.59,40.86 169.96,40.23 169.96,38.69 170.09,38.56 KBC24.48 ; KB2.21 200.55,117.5 199.68,117.5 198.03,115.85 198.03,113.03 197.77,112.77 197.77,104.54 197.78,104.54 197.78,103.58 194.42,100.23 194.42,94.75 190.9,91.23 190.9,89.93 190.43,89.46 KB1.21 188.48,89.46 187.73,88.71 186.61,88.71 186.13,88.23 186.13,86.23 186.13,86.22 186.13,77.93 184.48,76.27 184.48,76.27 184.45,76.24 184.45,67.55 182.39,65.48 182.39,64.9 182.24,64.74 AFTP6215.1 181.07,61.6 181.07,56.94 178.5,54.37 178.5,51.8 175.82,49.12 175.82,47.88 174.37,46.42 174.37,42.14 173.59,41.37 173.5,41.37 v2(173.46,41.33)
  BOTTOM w0.102: v2(173.46,41.33) 173.45,41.33 173.42,41.37 173.3,41.37 173.05,41.62 171.75,41.62 171.55,41.42 v2(171.55,41.39)
KCOL6: length 100
  TOP w0.102: KBC24.47 170.49,38.89 170.16,39.22 170.16,40.15 170.64,40.63 171.25,40.63 v2(171.38,40.75) ; KB2.18 200.55,119.9 199.16,119.9 197.42,118.17 197.42,113.28 197.17,113.03 197.17,104.29 197.17,103.83 193.81,100.48 193.81,95.34 190.33,91.86 KB1.18 188.59,91.86 188.46,91.99 186.74,91.99 185.52,90.77 185.52,78.18 183.87,76.52 183.87,76.52 183.84,76.49 183.84,67.8 181.78,65.74 181.78,65.15 180.2,63.57 AFTP6223.1 180.2,62.09 177.77,59.66 177.77,51.93 175.21,49.37 175.21,48.13 172.79,45.71 172.79,42.37 172.69,42.27 172.69,41.57 172.81,41.45 172.81,40.77 v2(173.05,40.53)
  BOTTOM w0.102: v2(171.38,40.75) 171.42,40.71 171.54,40.71 171.67,40.58 172.97,40.58 173.02,40.53 v2(173.05,40.53)
KCOL7: length 99.7
  TOP w0.102: v2(173.78,40.62) 173.5,40.9 173.28,40.9 173.01,41.17 173.01,41.54 172.9,41.66 172.9,42.18 173,42.28 173,45.63 175.42,48.05 175.42,49.29 178.06,51.93 178.06,58.58 AFTP6213.1 180.67,61.19 180.67,63.75 181.98,65.07 181.98,65.65 184.05,67.72 184.05,76.41 184.07,76.43 184.07,76.44 185.72,78.09 185.72,90.69 186.82,91.79 188.26,91.79 188.99,91.06 KB1.19 189.99,91.06 194.01,95.09 194.01,100.4 197.37,103.75 197.37,104.37 197.37,112.94 197.62,113.2 197.62,117.48 199.25,119.1 200.55,119.1 KB2.19 ; v2(172.18,41.19) 172.41,40.96 172.41,39.62 172.26,39.47 172.26,38.72 172.09,38.55 KBC24.43
  BOTTOM w0.102: v2(173.78,40.62) 173.5,40.9 173.28,40.9 172.99,41.19 v2(172.18,41.19)
KCOL8: length 97.7
  TOP w0.102: KB2.17 200.55,120.7 199.32,120.7 197.22,118.6 197.22,113.37 196.96,113.11 196.96,104.21 196.96,103.92 193.61,100.56 193.61,95.42 190.85,92.66 KB1.17 188.46,92.66 187.99,92.19 186.65,92.19 185.32,90.86 185.32,78.26 183.67,76.61 183.67,76.6 183.64,76.58 183.64,67.88 181.58,65.82 181.58,65.23 179.19,62.85 179.19,61.75 AFTP6231.1 178.17,60.35 177.57,59.74 177.57,52.5 173.12,48.06 173.12,46.41 172.59,45.88 172.59,42.45 172.49,42.35 172.49,41.49 172.61,41.37 172.61,39.53 172.46,39.39 172.46,39.03 172.49,39 KBC24.42
KCOL9: length 114.7
  TOP w0.102: KB2.7 200.55,128.7 198.43,128.7 195.18,125.46 195.18,114.21 192.4,111.42 192.4,102.35 190.71,100.66 KB1.7 188.54,100.66 188.17,101.03 187.01,101.03 183.11,97.13 183.11,84.02 180.88,81.78 180.88,70.1 AFTP6219.1 176.95,66.17 176.44,66.17 173,62.73 173,50.81 169.76,47.57 169.76,44.64 168.04,42.93 168.04,42.86 167.87,42.69 167.87,41.88 168.48,41.27 168.48,39.54 v2(168.04,39.11) ; v2(172.9,39.21) 172.9,38.53 172.89,38.53 KBC24.41
  BOTTOM w0.102: v2(168.04,39.11) 168.25,39.31 168.28,39.31 168.68,39.71 172.1,39.71 172.33,39.49 172.62,39.49 v2(172.9,39.21)
KCOL10: length 119.6
  TOP w0.102: v2(173.4,38.79) 173.4,38.78 173.29,38.67 KBC24.40 ; KB2.5 199.16,130.3 199.16,130.3 198.67,130.3 194.78,126.41 194.78,114.38 191.99,111.59 191.99,103.85 190.4,102.26 KB1.5 188.8,102.26 187.98,101.44 186.8,101.44 182.7,97.34 182.7,84.18 180.47,81.95 180.47,81.62 180.47,72.93 174.39,66.85 174.37,66.85 AFTP6232.1 172.18,64.66 172.18,50.56 169.35,47.74 169.35,44.81 167.64,43.1 167.64,43.03 166.39,41.78 166.04,41.78 164.77,40.51 v2(164.77,39.18)
  BOTTOM w0.102: v2(173.4,38.79) 173.39,38.78 172.69,38.78 171.96,39.51 169.36,39.51 168.52,38.67 165.28,38.67 v2(164.77,39.18)
KCOL11: length 114.8
  TOP w0.102: v2(173.61,39.41) 173.61,39.37 173.89,39.09 173.89,38.63 173.69,38.43 KBC24.39 ; KB2.6 199.14,129.5 199.13,129.5 198.64,129.5 194.98,125.85 194.98,114.29 192.19,111.51 192.19,102.88 190.77,101.46 KB1.6 188.46,101.46 188.24,101.24 186.89,101.24 182.9,97.25 182.9,84.1 180.67,81.87 180.67,71.35 AFTP6220.1 172.38,63.06 172.38,50.48 169.56,47.65 169.56,44.73 167.84,43.01 167.84,42.94 167.67,42.77 167.67,41.79 168.25,41.21 168.25,39.95 v2(168.04,39.74)
  BOTTOM w0.102: v2(168.04,39.74) 168.43,39.74 168.6,39.92 172.19,39.92 172.41,39.69 173.29,39.69 173.57,39.41 v2(173.61,39.41)
KCOL12: length 110.3
  TOP w0.102: KB2.12 200.55,124.7 198.88,124.7 196.2,122.03 196.2,113.79 193.41,111 193.41,101.81 192.39,100.78 192.39,98.51 190.54,96.66 KB1.12 188.22,96.66 187.91,96.97 186.54,96.97 184.12,94.56 184.12,83.59 181.89,81.36 181.89,68.51 AFTP6233.1 177.67,64.79 175.46,62.58 175.46,51.83 170.77,47.15 170.77,44.15 170.03,43.4 170.03,42.4 169.35,41.72 169.31,41.72 v2(169.11,41.52) ; KBC24.38 174.09,40.05 v2(174.39,40.35)
  BOTTOM w0.102: v2(174.39,40.35) 174.39,40.8 173.92,41.28 173.92,42.03 173.52,42.44 172.82,42.44 172.41,42.03 169.65,42.03 169.35,41.72 169.31,41.72 v2(169.11,41.52)
KCOL13: length 111.7
  TOP w0.102: v2(174.7,39.64) 174.42,39.36 174.42,38.78 174.49,38.7 KBC24.37 ; v2(168.68,42.67) 168.68,42.92 170.17,44.4 170.17,47.4 173.41,50.64 173.41,62.56 174.28,63.43 174.78,63.43 AFTP6203.1 176.74,65.39 177.24,65.39 181.28,69.43 181.28,81.62 183.51,83.85 183.51,94.81 186.28,97.58 186.79,97.58 187.66,97.58 188.49,98.41 188.49,98.87 188.68,99.06 KB1.9 190.16,99.06 191.78,100.68 191.78,101.03 192.8,102.06 192.8,111.25 195.59,114.04 195.59,124.59 198.1,127.1 200.55,127.1 KB2.9
  BOTTOM w0.102: v2(174.7,39.64) 174.38,39.64 173.92,40.1 172.82,40.1 172.54,40.38 171.61,40.38 171.56,40.32 171.2,40.32 171.12,40.4 169.46,40.4 168.68,41.18 168.68,41.84 168.74,41.9 168.74,42.61 v2(168.68,42.67)
KCOL14: length 112.8
  TOP w0.102: KB2.8 200.55,127.9 198.17,127.9 195.39,125.12 195.39,114.12 192.6,111.34 192.6,102.14 191.57,101.12 191.57,100.76 190.67,99.86 KB1.8 188.51,99.86 188.29,99.64 188.29,98.49 187.58,97.78 186.87,97.78 186.54,97.78 186.2,97.78 183.31,94.89 183.31,83.93 181.08,81.7 181.08,69.73 AFTP6216.1 176.94,65.59 176.15,65.59 173.2,62.64 173.2,50.73 169.96,47.49 169.96,44.56 168.25,42.85 168.25,42.21 168.3,42.15 v2(168.3,42.08) ; KBC24.36 174.89,38.91 v2(174.85,38.96)
  BOTTOM w0.102: v2(174.85,38.96) 174.6,39.21 174.52,39.21 173.83,39.9 172.67,39.9 172.44,40.12 169.45,40.12 168.45,41.12 168.45,41.27 168.3,41.42 v2(168.3,42.08)
KCOL15: length 112.1
  TOP w0.102: v2(169.31,42.78) 169.31,43.27 170.37,44.32 170.37,47.32 173.61,50.56 173.61,62.26 AFTP6229.1 174.58,63.23 175.37,63.23 181.48,69.34 181.48,81.53 183.72,83.76 183.72,94.72 186.37,97.38 186.7,97.38 186.7,97.38 187.75,97.38 188.63,98.26 KB1.10 191.1,98.26 191.98,99.14 191.98,100.95 193.01,101.98 193.01,111.17 195.79,113.96 195.79,123.78 198.32,126.3 200.55,126.3 KB2.10 ; KBC24.35 175.29,39.12 v2(176.22,40.05)
  BOTTOM w0.102: v2(169.31,42.78) 169.37,42.84 169.72,42.84 170.05,43.17 173.36,43.17 174.33,42.2 174.33,41.45 174.88,40.9 174.88,40.89 175.69,40.07 176.2,40.07 v2(176.22,40.05)
KCOL16: length 111
  TOP w0.102: v2(169.17,42.16) 169.34,42.16 169.82,42.64 169.82,43.49 170.57,44.24 170.57,47.23 173.81,50.47 173.81,60.43 AFTP6225.1 175,61.62 175,62.56 181.69,69.24 181.69,81.45 183.92,83.68 183.92,94.64 186.45,97.17 187.87,97.17 188.16,97.46 KB1.11 191.05,97.46 192.18,98.59 192.18,100.86 193.21,101.89 193.21,111.09 196,113.87 196,122.46 199.04,125.5 200.55,125.5 KB2.11 ; v2(176.22,39.29) 175.69,38.76 KBC24.34
  BOTTOM w0.102: v2(169.17,42.16) 169.24,42.23 172.26,42.23 172.67,42.64 173.6,42.64 174.12,42.12 174.12,41.36 174.67,40.81 174.67,40.8 175.21,40.27 175.21,39.92 175.84,39.29 v2(176.22,39.29)
KROW0: length 104.2
  TOP w0.102: KB2.22 199.64,116.7 199.64,116.7 198.23,115.3 198.23,112.94 197.98,112.69 197.98,104.63 197.98,104.63 197.98,103.5 194.62,100.14 194.62,94.67 191.11,91.15 191.11,89.37 190.4,88.66 KB1.22 188.03,88.66 187.88,88.51 186.71,88.51 186.33,88.13 186.33,86.39 186.34,86.38 186.34,77.84 184.66,76.16 184.66,67.46 182.59,65.4 182.59,61.08 AFTP6228.1 181.28,59.77 181.28,56.85 178.71,54.28 178.71,51.71 176.03,49.03 176.03,47.79 174.93,46.7 174.93,41.45 v2(175.56,40.81) ; KBC24.54 167.69,38.52 167.61,38.6 167.61,40.17 v2(167.82,40.37)
  BOTTOM w0.102: v2(175.56,40.81) 175.46,40.91 175.22,40.91 174.53,41.6 174.53,42.29 173.44,43.38 168.78,43.38 167.87,42.47 167.87,41.56 168.24,41.19 168.24,40.81 167.82,40.39 v2(167.82,40.37)
KROW1: length 103.1
  TOP w0.102: KB2.24 200.55,115.1 199.44,115.1 198.64,114.3 198.64,112.78 198.38,112.52 198.38,104.8 198.38,103.33 195.03,99.97 195.03,94.5 191.54,91.01 191.54,88.16 190.44,87.06 KB1.24 188.51,87.06 188.19,86.73 188.19,84.8 186.76,83.38 186.76,77.69 185.06,75.99 185.06,65.91 185.37,65.6 185.37,64 184.27,62.89 AFTP6227.1 183,61.49 183,60.38 182.71,60.09 182.71,57.71 179.11,54.11 179.11,51.54 176.43,48.87 176.43,47.63 175.33,46.53 175.33,42.57 175.6,42.31 175.62,42.31 175.89,42.03 175.89,41.09 175.99,40.99 175.99,40.94 v2(176.24,40.69) ; v2(167.81,41.01) 167.29,40.49 KBC24.55
  BOTTOM w0.102: v2(176.24,40.69) 176.05,40.89 176.05,40.94 175.74,41.24 175.17,41.24 174.73,41.68 174.73,42.37 173.52,43.58 168.69,43.58 167.67,42.55 167.67,41.15 v2(167.81,41.01)
KROW2: length 100
  TOP w0.102: KB2.26 200.55,113.5 200.3,113.5 198.79,111.99 198.79,104.96 198.79,104.96 198.79,103.16 195.44,99.8 195.44,94.33 191.95,90.84 191.95,87.04 190.37,85.46 KB1.26 189,85.46 188.62,85.09 188.62,84.66 187.17,83.21 187.17,77.52 185.47,75.82 185.47,66.08 185.78,65.77 185.78,63.83 185.31,63.36 185.31,59.73 AFTP6218.1 179.52,53.94 179.52,51.38 176.84,48.7 176.84,47.46 176.2,46.82 176.2,42.57 176.1,42.47 176.1,41.88 176.35,41.62 176.39,41.62 v2(176.59,41.42) ; KBC24.56 166.89,38.74 166.88,38.76 166.88,39.1 166.73,39.24 v2(166.73,39.5)
  BOTTOM w0.102: v2(176.59,41.42) 176.08,41.42 176.05,41.45 175.25,41.45 174.94,41.77 174.94,42.46 173.61,43.78 168.61,43.78 167.35,42.52 167.35,40.12 v2(166.73,39.5)
KROW3: length 103.1
  TOP w0.102: v2(175.43,41.88) 175.13,42.18 175.13,46.61 176.23,47.71 176.23,48.95 178.91,51.63 178.91,54.2 181.48,56.77 181.48,57.94 AFTP6234.1 182.24,59.91 182.8,60.46 182.8,65.31 184.86,67.38 184.86,76.07 186.56,77.77 186.56,88 186.87,88.31 187.63,88.31 188.08,87.86 KB1.23 190.29,87.86 191.31,88.88 191.31,91.06 194.83,94.58 194.83,100.06 198.18,103.41 198.18,104.71 198.18,112.61 198.44,112.86 198.44,114.39 198.44,114.39 198.44,114.56 199.78,115.9 200.55,115.9 KB2.23 ; v2(166.5,40.09) 166.29,39.88 166.29,38.96 166.49,38.75 KBC24.57
  BOTTOM w0.102: v2(166.5,40.09) 167.14,40.74 167.14,42.6 168.52,43.98 173.69,43.98 175.14,42.54 175.14,42.17 v2(175.43,41.88)
KROW4: length 99.2
  TOP w0.102: KB2.27 199.85,112.7 198.99,111.84 198.99,105.05 198.99,103.07 195.64,99.72 195.64,94.2 192.15,90.71 192.15,86.61 190.2,84.66 KB1.27 188.91,84.66 187.37,83.13 187.37,79.4 187.37,77.44 185.67,75.73 185.67,66.17 185.98,65.86 185.98,65.79 186.3,65.47 AFTP6230.1 186.3,64.06 185.51,63.27 185.51,54.39 179.95,48.82 179.26,48.82 176.53,46.09 v2(176.53,42.05) ; KBC24.58 166.09,38.67 166.06,38.7 166.06,40.39 v2(166.39,40.72)
  BOTTOM w0.102: v2(176.53,42.05) 176.27,42.31 175.6,42.31 175.34,42.56 175.34,42.62 173.78,44.19 168.44,44.19 166.94,42.69 166.94,41.26 166.44,40.76 166.43,40.76 v2(166.39,40.72)
KROW5: length 99.2
  TOP w0.102: KBC24.59 165.69,38.92 165.86,39.09 165.86,40.84 166.37,41.35 v2(166.42,41.35) ; v2(175.77,42.75) 175.77,46.67 176.64,47.54 176.64,48.78 179.32,51.46 179.32,54.03 182.92,57.63 182.92,59.37 AFTP6214.1 185.1,61.56 185.1,63.44 185.58,63.92 185.58,65.69 185.27,66 185.27,75.9 186.97,77.6 186.97,83.29 188.42,84.75 188.42,85.8 188.88,86.26 KB1.25 190.56,86.26 191.74,87.44 191.74,90.92 195.23,94.41 195.23,99.89 198.59,103.24 198.59,104.88 198.59,112.44 198.84,112.69 198.84,112.84 200.3,114.3 200.55,114.3 KB2.25
  BOTTOM w0.102: v2(166.42,41.35) 166.74,41.67 166.74,42.77 168.36,44.39 173.86,44.39 175.5,42.75 v2(175.77,42.75)
KROW6: length 99.7
  TOP w0.102: v2(165.2,40.33) 165.66,39.87 165.66,39.17 165.29,38.81 KBC24.60 ; KB2.28 200.04,111.9 199.2,111.05 199.2,105.13 199.2,105.13 199.2,102.99 195.84,99.64 195.84,94.12 192.35,90.63 192.35,86.26 189.95,83.86 KB1.28 188.92,83.86 187.58,82.52 187.58,79.32 187.58,77.35 185.87,75.65 185.87,66.25 186.19,65.94 186.19,65.92 186.66,65.45 186.66,63.11 AFTP6222.1 185.71,62.17 185.71,54.3 180.03,48.62 179.34,48.62 176.73,46.01 176.73,43.77 177.16,43.33 v2(177.16,42.77)
  BOTTOM w0.102: v2(177.16,42.77) 176.79,42.77 174.76,44.8 168.19,44.8 166.33,42.94 166.33,42.36 165.68,41.71 165.68,40.81 v2(165.2,40.33)
KROW7: length 99.7
  TOP w0.102: v2(165.22,39.69) 165.22,39.03 164.89,38.7 KBC24.61 ; v2(177.49,42.21) 177.59,42.31 177.59,43.19 176.98,43.8 176.98,45.92 179.49,48.42 180.11,48.42 185.92,54.22 185.92,60.34 AFTP6221.1 186.86,61.28 186.86,65.53 186.39,66 186.39,66.02 186.08,66.34 186.08,75.56 187.78,77.27 187.78,81.91 188.93,83.06 KB1.29 190.28,83.06 192.56,85.34 192.56,90.54 196.05,94.03 196.05,99.55 199.4,102.91 199.4,105.22 199.4,110.65 199.85,111.1 KB2.29
  BOTTOM w0.102: v2(177.49,42.21) 177.06,42.21 174.67,44.59 168.27,44.59 166.54,42.86 166.54,42.27 165.89,41.62 165.89,40.35 v2(165.22,39.69)
L_BKLT_CTRL: length 59
  TOP w0.14: v2(59.15,81.5) 59.13,81.53 59.08,81.53 58.75,81.86 v1(58.75,91.51) 58.75,92.65 v2(57.6,93.79)
  L4 w0.127: v2(84.63,84.28) 84.63,84.02 84.26,83.65 81.08,83.65 81.07,83.66 79.72,83.66 78.32,82.26 75,82.26 74.26,83 68.11,83 67.83,83.28 65.71,83.28 65.54,83.44 61.1,83.44 v2(59.15,81.5)
  BOTTOM w0.14: R5206.1 44.65,88.71 45.08,89.15 49.76,89.15 54.4,93.79 v1(56.74,93.79) v2(57.6,93.79) ; CPU1.A18 86.54,84.2 85.91,84.2 85.54,83.83 85.08,83.83 84.71,84.21 84.71,84.21 v2(84.63,84.28)
L_BKLT_EN: length 283.1
  TOP w0.102: R2444.1 182.45,28.52 183.87,28.52 v1(184.54,27.84) v2(185.72,26.66)
  L3 w0.102: v2(57.77,79.7) 57.33,80.13 56.92,80.13 54.51,77.72 54.51,65.35 53.85,64.69 53.85,60.53 53.79,60.48 53.79,59.59 53.34,59.13 51.69,59.13 50.96,59.87 47.9,59.87 47.87,59.83 47.51,59.83 46.92,60.42 46.11,60.42 44.45,58.75 44.45,57.75 44.35,57.65 44.35,57.29 44.45,57.19 44.45,54.02 45.03,53.43 45.03,51.33 42.34,48.64 42.34,42.03 41.55,41.25 41.55,40 41.2,39.65 41.2,38.45 37.62,34.87 37.62,28.62 37.39,28.4 37.39,26.43 38.15,25.66 38.15,22.6 40.78,19.97 42.3,19.97 42.44,19.83 45.79,16.48 45.79,15.33 46.5,14.62 57.23,14.62 59.46,12.39 64.49,12.39 69.8,7.08 76.36,7.08 80.25,3.19 95.63,3.19 96.21,2.61 128.66,2.61 129.53,3.48 131.23,3.48 132.03,2.68 146.1,2.68 146.35,2.94 155.73,2.94 v2(156.03,3.24)
  L4 w0.102: v2(57.77,79.7) 58.7,80.64 59.97,80.64 62.17,82.83 65.29,82.83 65.45,82.67 67.57,82.67 67.85,82.39 74.01,82.39 74.74,81.65 78.58,81.65 79.97,83.05 80.82,83.05 80.83,83.04 84.22,83.04 85.27,84.08 v2(85.27,84.28) ; v2(185.72,26.66) 184.47,25.4 184.47,22.46 183.37,21.37 182.8,21.37 180.59,19.16 180.59,15.05 171.14,5.61 166.09,5.61 164.97,6.72 164.42,6.72 161.91,4.21 159.37,4.21 157.97,2.81 156.46,2.81 v2(156.03,3.24)
  BOTTOM w0.102: v2(85.27,84.28) 85.5,84.28 85.64,84.42 86.4,84.42 86.73,84.75 CPU1.B17
L_BKLT_EN_EC: length 5.9
  TOP w0.102: KBC24.9 178.39,26.9 178.92,27.43 179.09,27.43 179.29,27.63 180.41,27.63 180.66,27.38 R2445.1 R2444.2 180.33,28.2 v1(180.21,28.08)
LAN_ENABLE_R_C: length 12.9
  TOP w0.127: Q3001.D v1(47.95,50.55) 48.14,50.55 49.79,48.9 49.79,48 49.17,47.38 R3021.2 44.14,47.38 R3022.1
LAN_MDI0N: length 18.4
  BOTTOM w0.102: LOM30.2 35.08,46.93 34.96,47.05 34.96,48.68 ; 34.96,48.68 v1(35.13,48.68) ; 34.96,48.68 34.96,49.41 37.26,51.71 37.26,53.44 36.98,53.71 36.54,53.71 EC3102.2 35.95,53.66 35.74,53.66 34.72,54.68 34.36,54.68 34.25,54.79 U3101.9 U3101.2 32.71,54.79 32.56,54.64 32.51,54.64 32.47,54.6 32.12,54.6 31.82,54.3 31.82,52.52 31.44,52.14 31.06,52.14 30.55,52.65 30.17,52.65
LAN_MDI0P: length 18
  BOTTOM w0.102: v1(35.91,50.97) 36.03,50.85 ; 36.03,50.85 34.7,49.52 34.7,47.06 34.68,47.04 LOM30.1 ; 36.03,50.85 37,51.82 37,53.33 36.87,53.46 36.64,53.46 EC3101.2 35.95,53.41 35.64,53.41 34.62,54.43 34.36,54.43 34.25,54.31 U3101.10 U3101.1 32.66,54.31 32.63,54.35 32.23,54.35 32.08,54.2 32.08,52.42 31.54,51.88 31.06,51.88 30.55,51.38 30.17,51.38
LAN_MDI1N: length 24.6
  BOTTOM w0.102: 38.37,51.78 v1(38.5,51.78) ; 38.37,51.78 38.37,51.25 36.22,49.09 36.22,47 36.28,46.93 LOM30.5 ; 38.37,51.78 38.37,55.8 36.93,57.24 36.56,57.24 EC3104.2 35.95,57.22 35.64,57.22 34.62,56.2 34.36,56.2 34.25,56.31 U3101.6 U3101.5 32.71,56.31 32.59,56.19 32.32,56.19 32.13,56.38 32.13,56.97 33.08,57.91 33.08,59.06 32.27,59.87 30.95,59.87 30.55,60.27 30.17,60.27
LAN_MDI1P: length 24.3
  BOTTOM w0.102: 30.17,59 30.55,59 31.18,59.62 32.17,59.62 32.83,58.96 32.83,58.02 31.88,57.07 31.88,56.27 32.22,55.94 32.59,55.94 32.69,55.83 U3101.4 U3101.7 34.24,55.83 34.35,55.95 34.73,55.95 35.74,56.96 35.95,56.96 EC3103.2 36.61,56.99 36.83,56.99 38.12,55.69 38.12,55.26 ; v1(37.97,55.26) 38.12,55.26 ; 38.12,55.26 38.12,51.35 35.96,49.2 35.96,47.06 35.88,46.98 LOM30.4
LAN_MDI2N: length 22.1
  TOP w0.102: v2(39.32,53.87) 39.11,53.66 37.23,53.66 ; 30.17,52.65 30.55,52.65 31.06,52.14 31.62,52.14 31.82,52.34 31.82,54.3 32.2,54.68 32.6,54.68 32.71,54.79 U3102.9 U3102.2 34.25,54.79 34.36,54.68 34.7,54.68 35.72,53.66 35.95,53.66 EC3107.2 36.59,53.66 37.23,53.66 ; 37.23,53.66 v1(37.23,53.81)
  BOTTOM w0.102: 37.46,48.22 37.46,47.9 37,47.45 37,47.01 37.08,46.93 LOM30.7 ; 37.46,48.22 v1(37.58,48.22) ; 37.46,48.22 37.46,48.75 40.19,51.49 40.19,53.45 39.9,53.74 39.44,53.74 v2(39.32,53.87)
LAN_MDI2P: length 21.8
  TOP w0.102: v1(38.38,53.26) 38.38,53.41 ; 38.38,53.41 36.59,53.41 EC3108.2 35.95,53.41 35.61,53.41 34.59,54.43 34.36,54.43 34.25,54.31 U3102.1 U3102.10 32.71,54.31 32.6,54.42 32.31,54.42 32.08,54.2 32.08,52.23 31.73,51.88 31.06,51.88 30.55,51.38 30.17,51.38 ; 38.38,53.41 39.11,53.41 v2(39.32,53.2)
  BOTTOM w0.102: v2(39.32,53.2) 39.6,53.48 39.8,53.48 39.94,53.34 39.94,52.06 ; LOM30.6 36.68,46.97 36.75,47.03 36.75,47.55 37.2,48 37.2,48.85 39.94,51.59 39.94,52.06 ; 39.94,52.06 v1(39.77,52.06)
LAN_MDI3N: length 29.5
  TOP w0.102: 37.46,57.02 38.42,56.06 39.1,56.06 v2(39.32,56.28) ; 37.46,57.02 37.26,57.22 36.59,57.22 EC3105.2 35.95,57.22 35.61,57.22 34.6,56.2 34.36,56.2 34.25,56.31 U3102.5 U3102.6 32.71,56.31 32.59,56.19 32.32,56.19 32.13,56.38 32.13,56.97 33.08,57.91 33.08,59.06 32.46,59.68 32.27,59.87 30.95,59.87 30.55,60.27 30.17,60.27 ; 37.46,57.02 v1(37.59,57.14)
  BOTTOM w0.102: 40.51,56.08 40.87,56.08 41.31,55.63 41.31,50.98 39.3,48.97 39.3,46.05 38.59,45.35 LOM30.10 ; 40.51,56.08 39.52,56.08 v2(39.32,56.28) ; 40.51,56.08 v1(40.51,56.25)
LAN_MDI3P: length 28.7
  TOP w0.102: 30.17,59 30.55,59 31.18,59.62 31.23,59.62 32.17,59.62 32.2,59.58 32.83,58.96 32.83,58.02 31.88,57.07 31.88,56.27 32.22,55.94 32.59,55.94 32.69,55.83 U3102.7 U3102.4 34.24,55.83 34.35,55.95 34.7,55.95 35.72,56.96 35.95,56.96 EC3106.2 36.59,56.96 37.16,56.96 38.31,55.81 38.5,55.81 ; 38.5,55.81 39.12,55.81 v2(39.32,55.62) ; 38.5,55.81 v1(38.5,55.64)
  BOTTOM w0.102: LOM30.9 38.63,45.75 39.05,46.16 39.05,49.07 41.06,51.08 41.06,54.98 ; 41.06,54.98 41.06,55.53 40.76,55.82 39.52,55.82 v2(39.32,55.62) ; 41.06,54.98 v1(40.89,54.98)
LAN_TXN_C_PCH_RXN0: length 13.3
  BOTTOM w0.127: LOM30.18 37.08,41.6 37.63,41.06 37.63,40.26 37.37,40 37.05,40 36.78,39.74 36.78,39.15 37.05,38.88 37.49,38.88 37.62,38.75 37.62,38.35 37.49,38.22 37.06,38.22 36.79,37.95 36.79,37.36 37.06,37.09 37.97,37.09 ; v1(37.97,36.95) 37.97,37.09 ; 37.97,37.09 38.48,37.09 38.75,37.36 38.75,39.66 38.94,39.85 38.94,40.66 39.11,40.84 39.41,40.84 C3016.1
LAN_TXP_C_PCH_RXP0: length 13
  BOTTOM w0.127: 38.5,39.46 38.5,39.76 38.69,39.95 38.69,40.76 C3014.1 ; 38.5,39.46 v1(38.35,39.46) ; 38.5,39.46 38.5,37.46 38.38,37.33 37.16,37.33 37.03,37.46 37.03,37.85 37.16,37.98 37.59,37.98 37.86,38.25 37.86,38.85 37.59,39.12 37.15,39.12 37.02,39.25 37.02,39.64 37.15,39.76 37.47,39.76 37.88,40.16 37.88,41.16 37.48,41.55 LOM30.17
LANXIN: length 6.8
  BOTTOM w0.14: X3001.1 28.2,44.46 28.94,45.19 31.09,45.19 C3001.1 31.52,44.84 32.21,44.15 LOM30.28
LANXOUT: length 5.2
  BOTTOM w0.14: LOM30.29 v1(32.64,44.55) 32.51,44.55 31.44,45.61 C3011.1 31.41,45.76 30.46,45.76 29.85,46.36 X3001.3
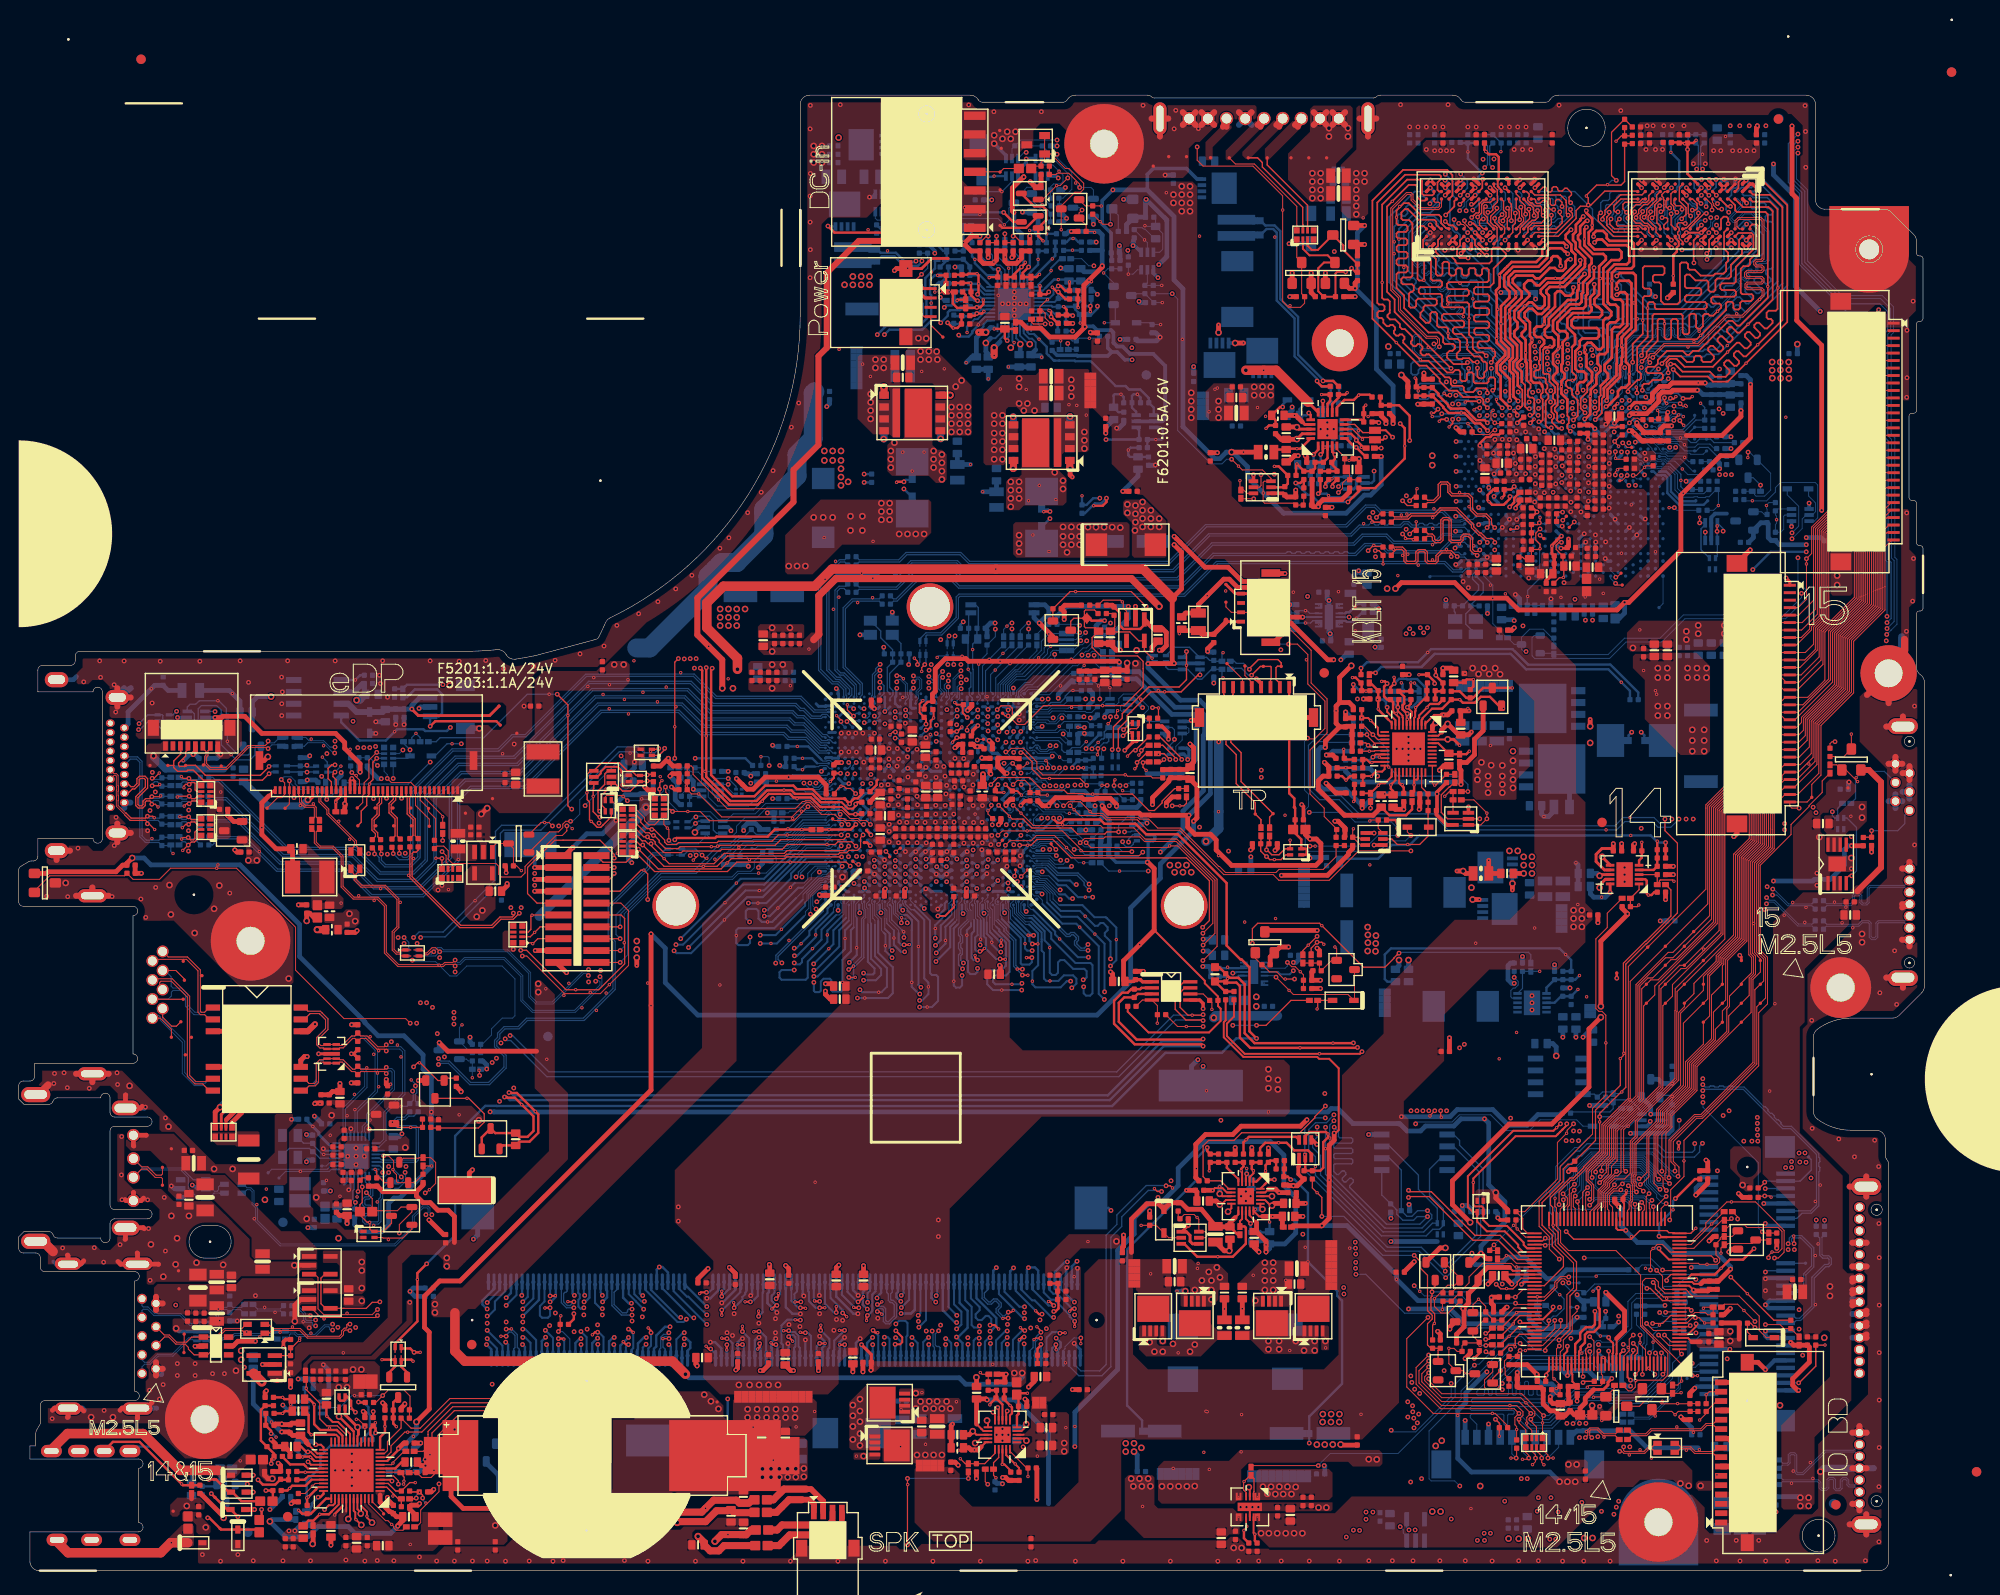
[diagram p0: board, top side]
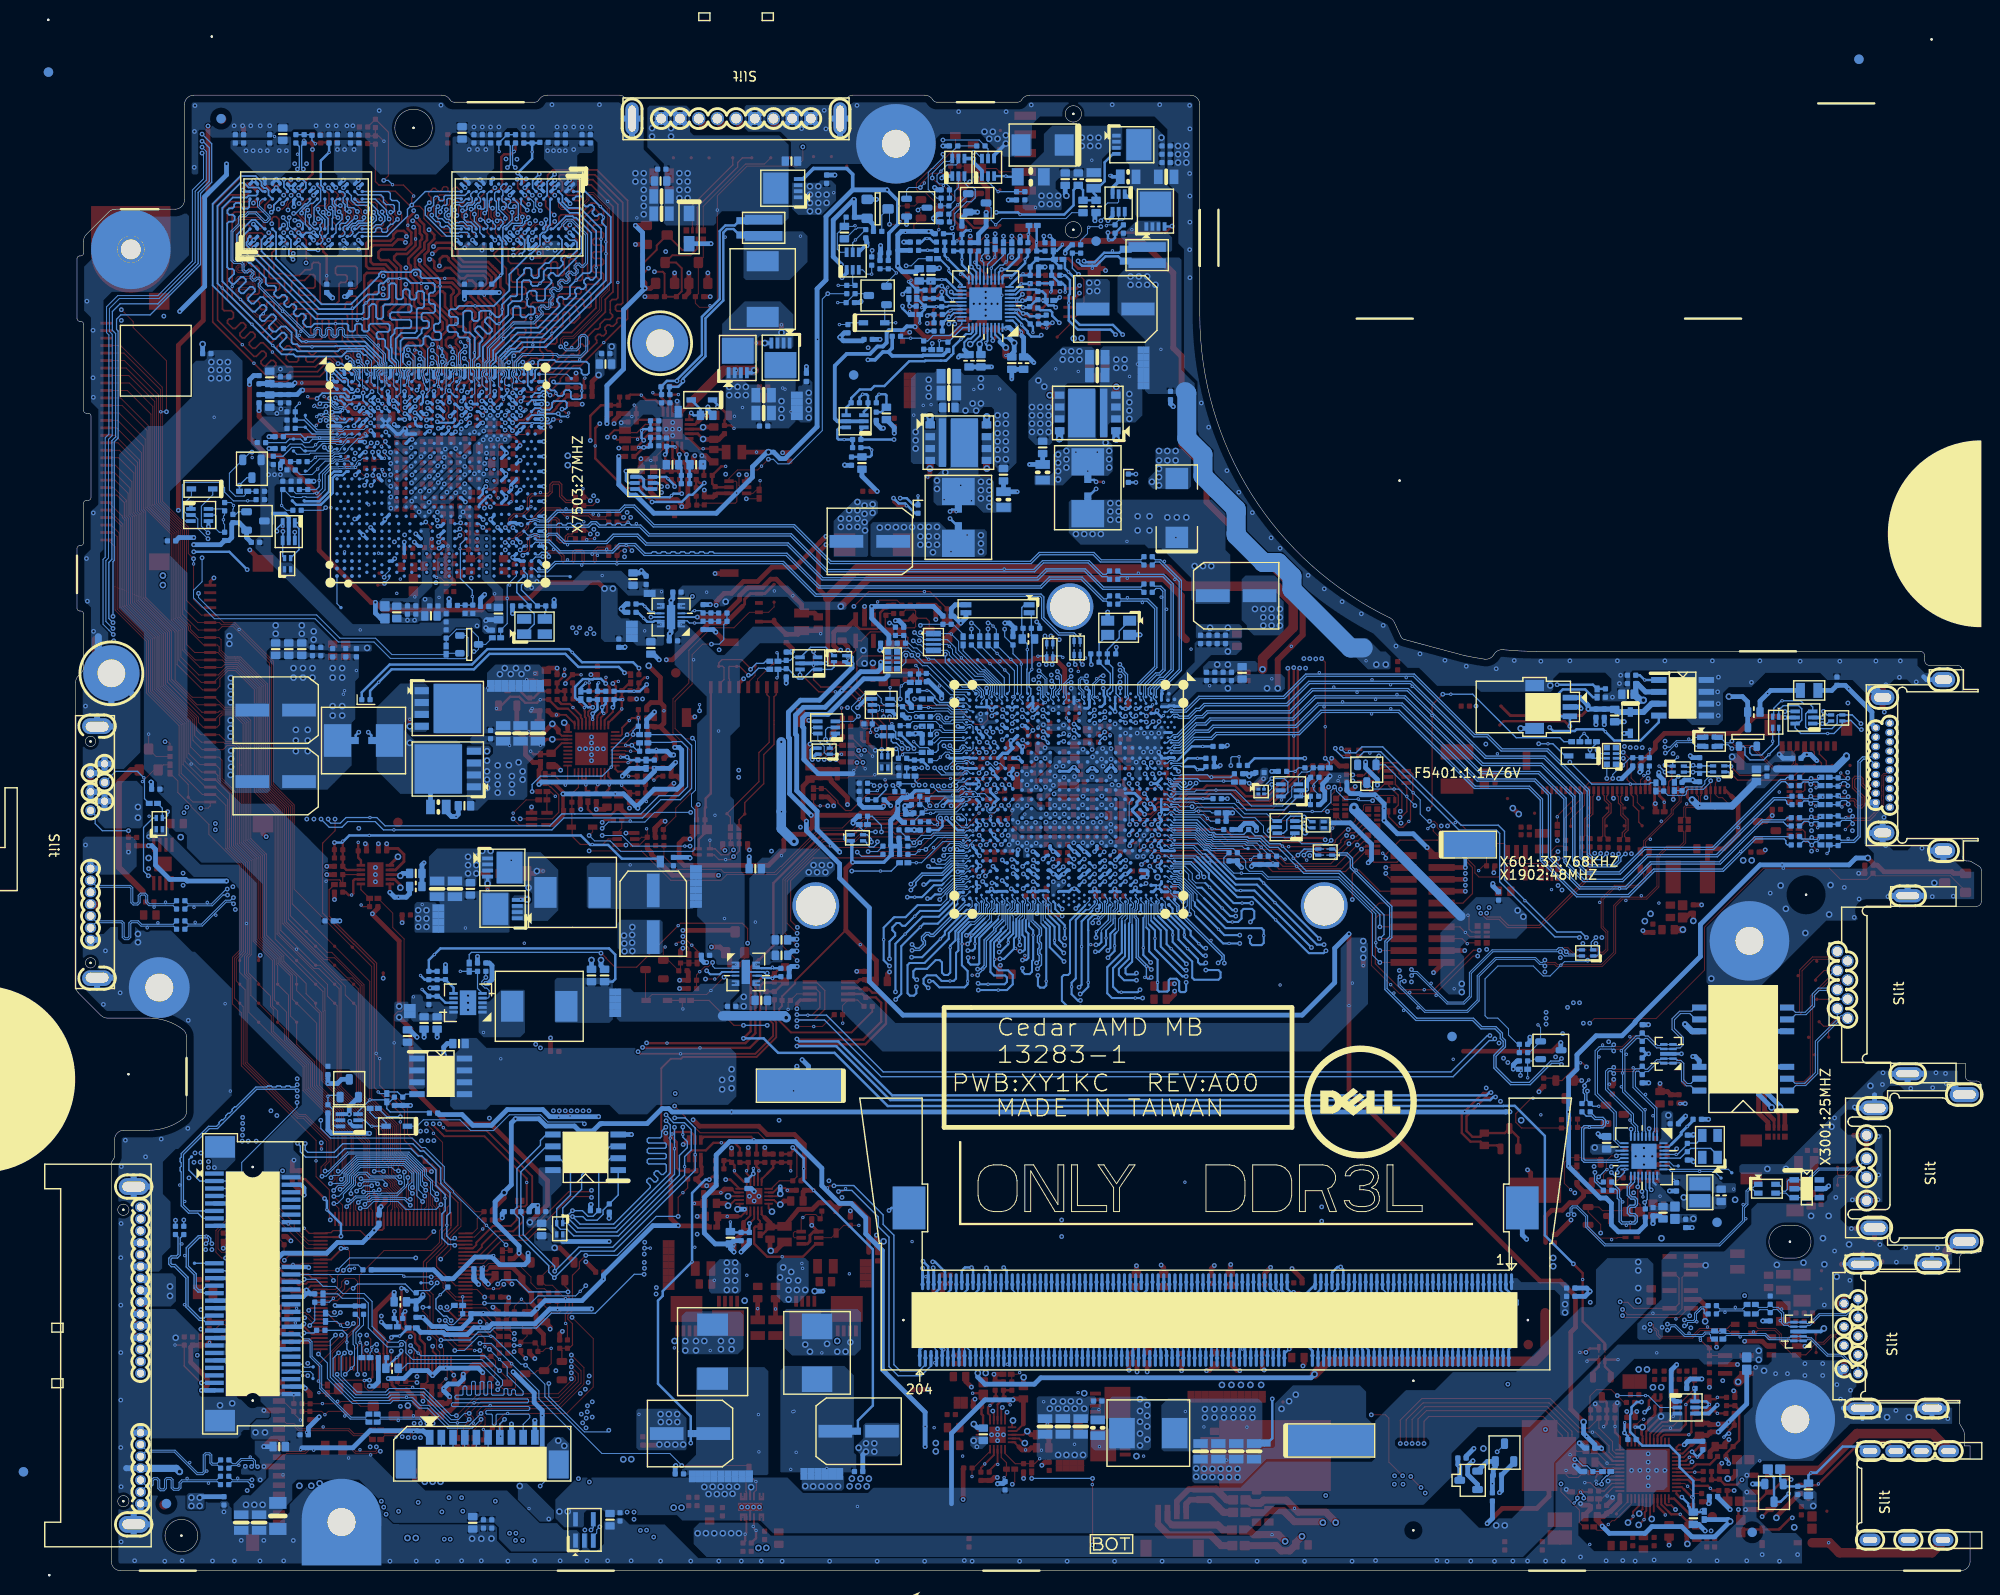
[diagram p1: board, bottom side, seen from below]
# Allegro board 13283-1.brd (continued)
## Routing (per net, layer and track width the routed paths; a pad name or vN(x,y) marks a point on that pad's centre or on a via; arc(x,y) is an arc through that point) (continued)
LCD_BRIGHTNESS: length 8.8
  TOP w0.14: AFTP5203.1 36.28,79.74 36.64,80.1 36.64,81.3 37.22,81.88 37.22,82.8 37.45,83.03 LCD1.20 37.45,84.21 37.89,84.65 37.89,86.53 v2(38.3,86.94)
  BOTTOM w0.14: RN5201.2 v2(38.3,86.94)
LCD_TST: length 261
  TOP w0.102: R2417.2 182.67,36.61 183.08,37.03 184.58,37.03 184.89,36.72 188.2,36.72 188.61,36.31 188.61,34.45 188.23,34.07 187.58,34.07 v1(187.55,34.1) 187.17,33.72 v2(187.17,33.49)
  L3 w0.102: v2(163.78,3.37) 162.45,2.04 146.68,2.04 146.46,1.82 129.09,1.82 129.02,1.74 80.26,1.74 75.79,6.21 69.44,6.21 66.84,8.82 62.61,8.82 62.35,9.07 62.35,9.42 62.05,9.72 61.72,9.72 61.47,9.97 61.47,10.65 60.41,11.7 59.14,11.7 56.9,13.94 46.22,13.94 45.51,14.65 45.01,15.15 45.01,16.29 42.02,19.28 40.5,19.28 36.7,23.08 36.7,26.68 36.21,27.17 35.56,27.82 35.56,33.99 36.9,35.33 36.9,37.36 40.49,40.95 40.49,48.17 43.69,51.38 43.69,56.98 43.66,57.01 43.66,57.94 43.69,57.96 43.69,59.92 43.6,60.01 43.6,60.15 v2(42.97,60.77)
  L4 w0.102: v2(40.06,84.78) 43.49,81.34 43.49,61.29 v2(42.97,60.77) ; v2(163.78,3.37) 165.24,4.83 171.01,4.83 181.05,14.87 181.05,18.97 182.99,20.91 183.56,20.91 187.27,24.62 187.27,33.39 v2(187.17,33.49)
  BOTTOM w0.102: RN5201.8 40.06,84.78 v2(40.06,84.78)
LCD_TST_C: length 9.9
  TOP w0.102: v2(39.42,84.78) 39.86,84.35 41.95,84.35 42.45,83.85 LCD1.10 42.45,81.89 43.91,80.43 AFTP5207.1
  BOTTOM w0.102: v2(39.42,84.78) 39.42,85.2 39.08,85.54 RN5201.1
LCD_TST_EN: length 263.6
  TOP w0.102: KBC24.28 179.18,34.5 182.19,37.5 R2417.1 183.02,37.5 v2(183.2,37.68) ; v2(57.1,79.7) 56.74,80.06 v1(56.27,80.06) 55.86,80.06 D5201.2
  L3 w0.102: v2(57.1,79.7) 55.7,78.3 55.7,65.98 54.33,64.61 54.33,60.69 54.05,60.41 54.05,59.52 53.43,58.9 51.6,58.9 50.86,59.64 47.99,59.64 47.96,59.61 47.41,59.61 46.83,60.19 46.21,60.19 45.11,59.09 45.11,57.78 46.23,56.66 46.23,53.75 45.73,53.26 45.73,49.25 42.82,46.35 42.82,41.83 42.41,41.42 42.03,41.05 42.03,39.8 41.68,39.45 41.68,38.17 38.1,34.59 38.1,28.42 37.87,28.2 37.87,26.63 38.63,25.86 38.63,22.8 40.98,20.45 42.5,20.45 47.85,15.1 57.43,15.1 59.66,12.87 64.69,12.87 69.7,7.87 69.7,7.86 69.87,7.69 70,7.56 76.56,7.56 80.45,3.67 95.83,3.67 96.16,3.34 128.71,3.34 129.33,3.96 131.43,3.96 132.23,3.17 145.9,3.17 146.17,3.44 154.34,3.44 154.9,4.01 v2(156.75,4.01)
  L4 w0.102: v2(156.75,4.01) 157.18,3.57 158.05,3.57 159.87,5.39 162.06,5.39 163.47,6.8 163.47,7.99 163.83,8.35 164.59,8.35 166.47,6.47 167.41,6.47 171.54,10.6 172.75,10.6 174.55,12.4 174.55,15.72 176.3,17.47 176.3,21.8 176.2,21.91 176.2,24.37 176.48,24.65 176.48,25.8 175.1,27.18 175.1,28.32 176.41,29.63 176.71,29.63 180.01,32.93 180.01,33.9 180.87,34.76 180.9,34.76 183.2,37.07 v2(183.2,37.68)
LCDVDD:
  vias: v1(47.01,76.12)
LCDVDD_EN: length 6.1
  TOP w0.102: U5201.1 50.66,77.41 51.08,77.82 D5201.3 52.92,77.29 R5202.2 53.26,75.43 v1(53.77,74.92)
LDO1_CAP: length 5.1
  TOP w0.203: HDA27.27 31.82,12.14 31.24,12.72 31.14,12.72
  TOP w0.254: 31.14,12.72 v2(30.93,12.72) 30.76,12.72 30.2,13.28 C2702.2
  BOTTOM w0.254: v2(30.93,12.72) v1(30.38,12.16) 29.79,12.74 R2711.2
LDO2_CAP: length 5.4
  TOP w0.203: HDA27.39 34.23,7.09 33.47,6.33
  TOP w0.254: 33.47,6.33 33.18,6.04 v1(32.2,6.04) 31.52,5.35 30.99,5.35 C2712.2
LDO3_CAP: length 2.9
  TOP w0.203: 39.32,10.94 HDA27.7
  TOP w0.254: C2718.1 40.97,11.63 40.28,10.94 39.32,10.94
LDRQ0#: length 5.1
  BOTTOM w0.102: CPU1.AP1 104.75,94.86 TP1903.1
LED0: length 1.8
  BOTTOM w0.102: TP3003.1 32.91,43.31 33.34,43.75 LOM30.27
LED1: length 7.6
  BOTTOM w0.102: TP3002.1 27.06,42.96 33.01,42.96 33.4,43.35 LOM30.26
LED2: length 6.5
  BOTTOM w0.102: LOM30.25 33.44,42.95 33.22,42.73 28.55,42.73 TP3001.1
LID_CLOSE#: length 282.4
  TOP w0.102: v2(175.2,32.14) 175.84,31.51 175.84,30.32 176.06,30.1 KBC24.17 178.36,30.1 178.59,29.86 178.59,29.8 179.01,29.38 184.04,29.38 186.18,27.24 186.18,25.71 186.95,24.93 187.8,24.93 D2401.K ; v2(41.88,58.59) 41.39,59.08 34.8,59.08 32.55,61.33 29.61,64.26 29.61,68.85 23.29,75.18 v1(21.18,75.18) 16.25,75.18 15.06,73.98 12.23,73.98 C6401.1 11.31,74.36 3.31,74.36 1.68,72.73 LIDSW1.3
  L3 w0.102: v2(41.88,58.59) 43.43,57.04 43.43,56.91 43.46,56.88 43.46,51.47 40.18,48.19 40.18,40.97 36.67,37.46 36.67,35.42 35.33,34.09 35.33,27.73 36.47,26.59 36.47,22.98 40.4,19.05 41.92,19.05 44.78,16.2 44.78,15.05 46.12,13.71 56.79,13.71 60.21,10.29 60.21,10.29 60.85,9.65 61.46,9.65 v2(61.86,9.25)
  L4 w0.102: v2(175.2,32.14) 175.12,32.14 174.73,31.75 174.32,31.75 173.44,30.87 173.44,26.16 174.09,25.51 174.09,24.81 173.37,24.09 173.37,23.05 171.62,21.3 171.62,14.98 171.62,14.98 171.62,14.39 168.07,10.84 163.73,10.84 158.81,5.91 156.55,5.91 153.97,3.33 153.09,2.46 131.9,2.46 131.13,3.23 129.64,3.23 129.41,3 95.82,3 95.63,3.19 94.87,3.19 94.31,2.63 77.25,2.63 69.82,10.06 64.18,10.06 63.22,9.1 63.22,9.07 62.97,8.82 62.29,8.82 v2(61.86,9.25)
  BOTTOM w0.102: v2(175.2,32.14) 174.63,32.72 173.63,32.72 R2421.1
LINE1-L_C: length 2
  TOP w0.254: C2907.2 28.48,17.08 v1(28.23,16.83) R2922.1
LINE1-L_R: length 2.1
  TOP w0.254: C2908.2 28.42,18.36 v1(28.23,18.55) R2921.1
LINE1_L: length 6.4
  TOP w0.203: 33.76,14.55 33.96,14.55 34.23,14.27 HDA27.22
  TOP w0.254: 33.76,14.55 v1(31.29,14.55) 31.01,14.82 31.01,16.65 C2907.1
LINE1_R: length 7.6
  TOP w0.203: HDA27.21 34.63,14.45
  TOP w0.254: C2908.1 31.09,18.36 31.6,17.84 v1(31.6,17.77) 31.6,15.68 32.23,15.05 34.03,15.05 34.63,14.45
LINE1_VREFO_L: length 2.9
  TOP w0.203: R2912.1 29.83,10.54 v1(30.65,10.54) HDA27.31
LINE1_VREFO_R: length 4.9
  TOP w0.203: HDA27.30 30.94,10.94 30.68,11.19
  TOP w0.254: 30.68,11.19 30.5,11.37 29.03,11.37 28.21,12.2 R2913.1
LOM_TCT: length 17.2
  TOP w0.508: C3106.1 31.74,50.04 v2(31.67,49.98) ; 30.17,53.92 30.17,54.63 30.56,55.02 v2(30.85,55.02)
  TOP w0.635: 30.17,57.73 30.93,57.73 v2(31.7,58.49)
  L4 w0.508: v2(31.67,49.98) 31.7,50 31.7,54.18 v2(30.85,55.02) 30.85,57.64 v2(31.7,58.49)
  BOTTOM w0.305: v1(32.23,49.98) v2(31.67,49.98)
  BOTTOM w0.508: v2(30.85,55.02) 30.61,55.02 30.17,54.58 30.17,53.92
  BOTTOM w0.635: v2(31.7,58.49) 30.93,57.73 30.17,57.73
LPC_AD0: length 146.2
  TOP w0.102: v2(175.08,23.29) 175.08,23.27 175.29,23.06 KBC24.126 ; v2(150.82,20.54) 150.82,20.34 152.23,18.94 160.77,18.94 v2(163.11,16.6) 163,16.48 v1(163,15.82) RN6501.1
  L4 w0.102: v2(114.25,99.51) 114.43,99.51 114.49,99.57 123.44,99.57 123.64,99.78 130.31,99.78 139.05,91.04 139.05,90.71 140.31,89.45 140.31,83.2 141.51,81.99 141.51,81.1 141.93,80.68 141.93,65.3 142.31,64.92 142.31,58.6 148.36,52.55 151.38,52.55 153.88,50.05 153.88,48.64 149.86,44.61 149.86,38.71 149.71,38.56 149.71,26.65 149.47,26.42 149.47,21.89 v2(150.82,20.54)
  BOTTOM w0.102: v2(163.11,16.6) 163.67,16.6 166.57,19.5 170.31,19.5 170.69,19.12 173.73,19.12 175.44,20.83 175.44,22.93 v2(175.08,23.29) ; RN1901.4 112.84,98.48 113.45,99.09 113.78,99.09 114.2,99.51 v2(114.25,99.51)
LPC_AD1: length 149.4
  TOP w0.102: v2(150.82,21.17) 150.39,20.74 150.39,20.34 152.21,18.52 160.67,18.52 v1(161.22,17.96) 162.18,17.01 162.18,16.63 v2(161.74,16.2) 161.74,15.99 162.35,15.38 RN6501.2 ; v2(175.71,23.31) 175.69,23.29 KBC24.127
  L4 w0.102: v2(150.82,21.17) 149.78,22.22 149.78,26.3 150.01,26.53 150.01,38.43 150.16,38.59 150.16,44.49 154.19,48.51 154.19,50.18 151.51,52.86 148.49,52.86 142.64,58.7 142.64,65.02 142.24,65.43 142.24,80.81 141.82,81.23 141.82,82.12 140.64,83.3 140.64,89.56 139.35,90.84 139.35,91.16 130.44,100.08 123.24,100.08 123.1,99.94 114.02,99.94 v2(113.6,99.53)
  BOTTOM w0.102: v2(175.71,23.31) 176.3,22.72 176.3,20.83 173.98,18.51 170.43,18.51 170.13,18.81 166.74,18.81 163.79,15.86 162.08,15.86 v2(161.74,16.2) ; RN1901.3 113.01,99.13 113.4,99.53 v2(113.6,99.53)
LPC_AD2: length 146.7
  TOP w0.102: KBC24.128 176.09,21.24 v2(175.87,21.02) ; RN6501.3 161.85,15.02 161.31,15.56 v1(161.31,15.79) 161.31,16.4 v2(161.74,16.83) 160.48,18.1 152.2,18.1 150.09,20.21 150.09,21.07 v2(150.82,21.81)
  L4 w0.102: v2(114.12,100.4) 114.4,100.4 114.43,100.37 117.22,100.37 117.23,100.39 130.56,100.39 139.66,91.29 139.66,90.96 140.94,89.68 140.94,83.43 141.93,82.43 142.12,82.25 142.12,81.35 142.54,80.93 142.54,65.55 142.95,65.15 142.95,58.89 148.68,53.16 151.64,53.16 154.49,50.3 154.49,48.39 151.13,45.02 151.13,38.07 151.13,38.07 151.13,37.71 150.31,36.9 150.31,26.4 150.08,26.17 150.08,22.55 v2(150.82,21.81)
  BOTTOM w0.102: v2(114.12,100.4) 114.11,100.4 113.66,99.96 113.4,99.96 113.08,99.63 RN1901.2 ; v2(175.87,21.02) 175.87,20.83 173.86,18.81 170.56,18.81 170.26,19.11 166.62,19.11 163.66,16.16 162.92,16.16 162.25,16.83 v2(161.74,16.83)
LPC_AD3: length 152.2
  TOP w0.102: v2(177.87,23.18) 177.64,23.42 KBC24.1 ; RN6501.4 161.2,15.09 160.47,15.82 v2(160.47,16.2) 160.91,16.63 160.91,17.01 160.24,17.68 v1(159.51,17.68) 152.19,17.68 149.78,20.09 149.78,21.4 v2(150.82,22.44)
  L4 w0.102: v2(113.48,100.39) 113.93,100.83 114.4,100.83 114.55,100.68 117.09,100.68 117.11,100.69 130.69,100.69 139.97,91.41 139.97,91.09 141.25,89.81 141.25,83.55 142.31,82.48 142.43,82.37 142.43,81.48 142.85,81.06 142.85,65.68 143.25,65.27 143.25,59.02 148.81,53.47 151.76,53.47 154.8,50.43 154.8,48.26 151.43,44.9 151.43,36.95 151.15,36.67 151.15,30.93 151.64,30.45 151.64,27.29 150.39,26.04 150.39,22.9 150.82,22.47 v2(150.82,22.44)
  BOTTOM w0.102: v2(177.87,23.18) 176.91,22.22 176.91,20.58 174.24,17.9 170.18,17.9 169.88,18.2 167.91,18.2 167.1,17.39 166.19,17.39 164.04,15.25 161.42,15.25 v2(160.47,16.2) ; v2(113.48,100.39) 113.38,100.28 RN1901.1
LPC_FRAME#: length 159.5
  TOP w0.102: KBC24.3 176.76,24.5 v2(176.05,25.21) ; R6501.1 v1(160.23,15.1) 160.23,15.43 160.04,15.61 160.04,16.4 v2(160.47,16.83) 159.96,17.34 159.68,17.34 159.66,17.32 159.36,17.32 159.34,17.34 152.1,17.34 149.48,19.96 149.48,21.74 v2(150.82,23.08)
  L4 w0.102: v2(113.48,101.16) 113.6,101.28 114.38,101.28 114.68,100.98 116.97,100.98 116.98,100.99 130.82,100.99 131.04,100.78 140.28,91.53 140.28,91.21 141.57,89.92 141.57,83.66 142.73,82.5 142.73,81.61 143.15,81.18 143.15,65.8 143.56,65.4 143.56,59.15 148.94,53.77 151.89,53.77 155.1,50.56 155.1,48.13 151.74,44.77 151.74,36.82 151.47,36.55 151.47,33.64 151.46,33.63 151.46,31.06 151.94,30.57 151.94,27.16 150.82,26.05 v2(150.82,23.08)
  BOTTOM w0.102: v2(176.05,25.21) 176.61,24.65 176.61,20.7 174.11,18.2 170.31,18.2 170.01,18.5 167.78,18.5 166.97,17.7 166.06,17.7 163.92,15.55 161.75,15.55 v2(160.47,16.83) ; R1901.1 108.91,100.22 109.97,101.28 R1914.1 R1913.2 113.37,101.28 v2(113.48,101.16)
LPC_FRAME#_DEBUG: length 4
  TOP w0.102: R6501.2 160.23,12.1 v2(160.18,12.05) v1(159.62,12.05)
  BOTTOM w0.102: v2(160.18,12.05) 159.72,12.51 159.72,14.27 DB1.6
LPC_FRAME#_R: length 8.2
  BOTTOM w0.102: CPU1.AP2 104.75,93.07 105.05,93.37 105.05,93.67 105,93.72 105,94.81 106.58,96.4 106.87,96.4 108.91,98.44 R1901.2
LPC_LAD0_R: length 4.6
  TOP w0.102: RN6501.8 163,12.96 163.58,12.38 v2(163.58,12.05) v1(164.14,12.05)
  BOTTOM w0.102: DB1.2 164.72,13.2 v2(163.58,12.05)
LPC_LAD1_R: length 4.7
  TOP w0.102: RN6501.7 162.35,12.85 162.46,12.74 162.46,12.73 162.48,12.7 162.49,12.7 162.7,12.5 162.91,12.29 v2(162.91,12.05) 162.91,11.57 v1(163.15,11.34)
  BOTTOM w0.102: DB1.3 163.47,14.27 163.47,12.61 v2(162.91,12.05)
LPC_LAD2_R: length 4.4
  TOP w0.102: v1(161.93,11.35) 162.25,11.67 v2(162.25,12.05) 162.25,12.39 161.85,12.79 RN6501.6
  BOTTOM w0.102: DB1.4 162.22,14.27 162.22,12.07 v2(162.25,12.05)
LPC_LAD3_R: length 4.5
  TOP w0.102: v1(160.85,11.92) 161.4,11.92 v2(161.53,12.05) 161.53,12.35 161.2,12.68 RN6501.5
  BOTTOM w0.102: v2(161.53,12.05) 160.97,12.6 160.97,14.27 DB1.5
LPC_PD#: length 6.7
  BOTTOM w0.102: CPU1.AV2 106.95,93.05 106.65,93.36 106.65,93.64 106.73,93.73 106.73,94.16 107.64,95.06 108.15,95.06 110.44,97.35 TP1901.1
LPC_RST#: length 153.3
  TOP w0.102: R6502.1 159.27,15.5 158.14,16.63 158.14,16.63 157.93,16.83 v1(157.63,16.83) 151.3,16.83 148.48,19.66 148.48,24.84 v2(150.75,27.11)
  L3 w0.102: v2(168.98,24.2) 169.45,23.73 169.45,23.34 168.15,22.04 165.99,22.04 163.12,19.17 159.1,19.17 158.88,18.94 158.52,18.94 158.29,19.17 152.7,19.17 152.52,19.35 152.52,20.31 153.16,20.95 153.16,23.59 151.92,24.83 151.84,24.83 150.75,25.93 v2(150.75,27.11) 150.44,27.41 150.44,30.93 150.06,31.31 150.06,34.1 149.17,34.99 149.17,36.52 148.66,37.03 148.66,38.61 141.96,45.32 141.96,49.34 140.24,51.06 v2(139.71,51.06)
  L4 w0.102: v2(139.71,51.06) 139.71,51.62 135.25,56.08 135.25,62.53 134.92,62.86 134.92,63.7 134.44,64.18 134.44,72 135.51,73.07 135.51,78.97 133.35,81.13 133.35,86.61 133.09,86.86 131.98,86.86 126.6,92.23 122.03,92.23 121.41,92.85 114.55,92.85 v2(114.12,93.29)
  BOTTOM w0.102: v2(168.98,24.2) 169.24,23.94 170.51,23.94 172.54,25.98 172.54,28.64 173.05,29.15 175.33,29.15 175.8,29.62 R2416.2 ; R602.1 v2(114.12,93.29)
LPC_RST#_C: length 5.2
  BOTTOM w0.102: R602.2 111.77,92.65 110.56,92.65 110.06,92.15 108.73,92.15 108.68,92.2 108.38,92.2 108.19,92.02 107.97,92.02 CPU1.AY4
LPCCLK0: length 8.6
  BOTTOM w0.102: v1(113.97,96.87) 113.68,96.58 R1911.2 ; CPU1.AY2 108.79,93.74 110.26,93.74 112.53,96.02 R1919.1 112.91,95.95 R1911.2 ; R1911.2 R1906.1
LPCCLK1: length 12.8
  BOTTOM w0.102: CPU1.AW2 107.5,93.38 107.21,93.67 107.2,93.68 107.2,94 107.43,94.23 107.57,94.23 107.9,94.56 108.99,94.56 111.97,97.54 v1(112.6,97.54) 112.66,97.54 113.86,98.75 114.22,98.75 114.73,99.26 R1920.2 115.07,99.89 R1912.1 R1907.1
M_A_A0: length 62.6
  TOP w0.216: v1(83.06,26.85) 83.09,26.81 v2(83.61,26.81)
  L3 w0.216: v2(83.61,26.81) 83.64,26.81 84.47,27.64 84.47,30.39 85.06,30.99 85.06,35.35 96.58,46.87 96.58,48.49 101.75,53.66 101.75,62.68 101.47,62.96 101.47,64.74 101.62,64.89 101.62,65.52 101,66.15 101,69.47 100.53,69.94 100.53,72.84 v2(101.42,73.73)
  BOTTOM w0.216: v2(101.42,73.73) 101.28,73.73 CPU1.AG38 ; v2(83.61,26.81) 83.56,26.87 82.22,26.87 81.59,26.23 81.59,24.33 81.75,24.17 DM1.98
M_A_A1: length 63.5
  TOP w0.216: v1(81.25,29.66) 81.25,29.33 v2(81.02,29.1)
  L3 w0.216: v2(81.02,29.1) 80.99,29.13 80.99,37.96 81.36,38.33 81.36,38.75 81.02,39.09 81.02,39.41 81.32,39.71 81.64,39.71 82.04,39.31 82.34,39.31 82.77,39.73 82.77,40.04 82.5,40.31 82.5,40.63 82.73,40.86 83.49,40.86 83.72,41.09 83.72,41.85 84.01,42.14 84.33,42.14 84.6,41.87 84.91,41.87 85.21,42.18 85.21,42.48 84.59,43.1 84.59,43.41 84.9,43.72 85.2,43.72 85.82,43.09 86.13,43.09 86.43,43.4 86.43,43.7 85.81,44.33 85.81,44.63 86.12,44.94 86.42,44.94 87.04,44.32 87.35,44.32 87.77,44.73 87.77,46.46 95.12,53.81 95.12,62.83 95.76,63.47 95.76,68.39 95.96,68.6 95.96,73.07 96.44,73.55 96.44,74.75 95.95,75.24 v2(95.95,75.35)
  BOTTOM w0.216: DM1.97 81.45,29.58 81.02,29.15 v2(81.02,29.1) ; CPU1.W35 96.1,75.35 v2(95.95,75.35)
M_A_A2: length 59.6
  TOP w0.216: v1(80.47,24.39) 80.67,24.19 v2(81,24.19)
  L3 w0.216: v2(95.95,73.75) 95.54,73.34 95.54,68.83 95.32,68.62 95.32,64.33 94.38,63.39 94.38,53.94 80.44,40 80.44,35.2 79.8,34.55 79.8,32.56 80.36,32 80.36,24.75 80.92,24.19 v2(81,24.19)
  BOTTOM w0.216: DM1.96 81.15,24.04 v2(81,24.19) ; CPU1.W38 96.1,73.75 v2(95.95,73.75)
M_A_A3: length 62.9
  TOP w0.216: v2(81.1,28.39) 80.95,28.39 v1(80.57,28.01)
  L3 w0.216: v2(95.95,76.15) 96.47,75.63 96.47,75.24 96.76,74.95 96.76,73.4 96.38,73.02 96.38,70.66 96.48,70.56 96.48,69.43 96.7,69.21 97.22,69.21 97.43,69 97.43,68.56 97.22,68.35 96.7,68.35 96.48,68.13 96.48,67.7 96.7,67.49 97.22,67.49 97.43,67.27 97.43,66.84 97.22,66.62 96.7,66.62 96.48,66.41 96.48,66.07 96.7,65.86 97.06,65.86 97.28,65.64 97.28,65.21 97.06,64.99 96.7,64.99 96.48,64.78 96.48,63.28 95.88,62.68 95.88,53.63 88.39,46.14 88.39,44.4 81.75,37.76 81.75,33.91 81.51,33.68 81.51,28.8 v2(81.1,28.39)
  BOTTOM w0.216: CPU1.W34 96.1,76.15 v2(95.95,76.15) ; DM1.95 80.85,29.74 80.53,29.42 80.53,28.9 81.04,28.39 v2(81.1,28.39)
M_A_A4: length 59.9
  TOP w0.216: v1(78.64,25.57) 78.67,25.6 v2(79.19,25.6)
  L3 w0.102: v2(94.85,73.75) 94.85,73.59 94.42,73.15 94.42,71.23 94.36,71.17
  L3 w0.216: 94.36,71.17 93.92,70.73 93.92,69.09 94.21,68.81 94.21,67.97 94.2,67.96 94.2,67.56 94.21,67.55 94.21,64.99 93.75,64.53 93.75,54.17 79.6,40.02 79.6,35.63 79.28,35.3 79.28,32.35 79.49,32.14 79.49,30.97 79.84,30.62 79.84,26.24 v2(79.19,25.6)
  BOTTOM w0.216: CPU1.U38 95,73.75 v2(94.85,73.75) ; v2(79.19,25.6) 79.32,25.6 79.95,24.97 DM1.92
M_A_A5: length 63
  TOP w0.216: v1(79.14,27.78) v2(79.14,27.22)
  L3 w0.102: v2(94.85,74.55) 94.39,74.08 94.39,73.41 94.21,73.24 94.21,71.69 93.78,71.26
  L3 w0.216: 93.78,71.26 93.55,71.03 93.55,68.04 92.93,67.42 92.93,65.3 93.14,65.09 93.14,54.47 92.77,54.11 92.47,54.11 92.28,54.3 91.97,54.3 91.66,53.99 91.66,53.68 91.85,53.49 91.85,53.19 91.55,52.88 91.24,52.88 91.05,53.07 90.75,53.07 90.44,52.77 90.44,52.46 90.63,52.27 90.63,51.97 90.33,51.66 90.02,51.66 89.83,51.85 89.53,51.85 89.22,51.55 89.22,51.24 89.41,51.05 89.41,50.75 83.06,44.39 82.62,44.39 78.76,40.52 78.76,39.93 79.04,39.64 79.04,38.5 78.76,38.21 78.76,37.67 79.02,37.41 79.02,36.26 78.76,36 78.76,32.13 78.97,31.92 78.97,30.19 79.32,29.84 79.32,27.39 v2(79.14,27.22)
  BOTTOM w0.216: v2(79.14,27.22) 79.58,27.65 79.58,29.79 79.65,29.86 DM1.91 ; v2(94.85,74.55) 95,74.55 CPU1.U37
M_A_A6: length 62
  TOP w0.216: v1(79.04,23.72) 79.26,23.93 v2(79.26,24.3)
  L3 w0.102: 93.72,71.72 94,72.01 94,73.39 94.18,73.57 94.18,74.68 v2(94.85,75.35)
  L3 w0.216: 93.72,71.72 93.16,71.17 93.16,68.8 92.5,68.14 92.5,55.95 88.5,51.95 88.5,50.8 82.95,45.25 82.55,45.25 78.24,40.94 78.24,31.89 78.32,31.8 78.32,31.77 78.33,31.77 78.33,30.09 78.79,29.63 78.79,28.11 78.32,27.65 78.32,25.14 79.17,24.3 v2(79.26,24.3)
  BOTTOM w0.216: DM1.90 79.35,24.2 v2(79.26,24.3) ; v2(94.85,75.35) 95,75.35 CPU1.U34
M_A_A7: length 61.4
  TOP w0.216: v1(77.42,26.15) v2(77.42,25.6)
  L3 w0.102: 93.32,72.38 93.32,73.56 93.32,73.57 93.32,74.92 v2(93.75,75.35)
  L3 w0.216: 93.32,72.38 93.32,72.24 91.74,70.65 91.74,68.85 91.38,68.49 91.38,62.65 91.23,62.5 91.23,57.47 83.08,49.32 83.08,47.49 77.07,41.48 77.07,31.55 77.29,31.34 77.29,28.85 77.54,28.6 77.54,25.72 v2(77.42,25.6)
  BOTTOM w0.216: CPU1.R35 93.9,75.35 v2(93.75,75.35) ; v2(77.42,25.6) 78.15,24.86 DM1.86
M_A_A8: length 62.6
  TOP w0.216: v1(77.7,28.77) v2(78.27,28.77)
  L3 w0.216: v2(93.75,73.75) 93.72,73.72 93.72,72.18 92.78,71.25 92.78,69.11 91.9,68.22 91.9,57.2 91.48,56.78 91.48,56.47 91.6,56.36 91.6,56.05 91.29,55.75 90.98,55.75 90.87,55.86 90.57,55.86 90.26,55.56 90.26,55.25 90.37,55.14 90.37,54.83 90.07,54.53 89.76,54.53 89.65,54.64 89.34,54.64 89.04,54.34 89.04,54.03 89.15,53.92 89.15,53.61 88.85,53.31 88.54,53.31 88.43,53.42 88.12,53.42 87.82,53.11 87.82,52.81 87.93,52.69 87.93,52.39 87.62,52.08 87.32,52.08 87.21,52.2 86.9,52.2 86.59,51.89 86.59,51.59 87.21,50.97 87.21,50.65 86.92,50.36 86.6,50.36 85.98,50.98 85.68,50.98 85.37,50.67 85.37,50.37 85.96,49.78 85.96,49.45 85.67,49.17 85.35,49.17 84.76,49.75 84.46,49.75 83.74,49.04 83.74,47.29 77.65,41.19 77.65,31.72 77.81,31.55 77.81,29.23 v2(78.27,28.77)
  BOTTOM w0.216: DM1.89 79.05,29.39 78.43,28.77 v2(78.27,28.77) ; CPU1.R38 93.9,73.75 v2(93.75,73.75)
M_A_A9: length 62.7
  TOP w0.216: v1(76.48,28.69) 76.53,28.64 v2(76.53,28.14)
  L3 w0.102: v2(92.65,73.75) 92.65,73.54 92.26,73.15 92.26,72.11 90.88,70.73 90.88,70.43
  L3 w0.216: 90.88,70.43 90.88,69.64 89.86,68.62 89.86,63.64 89.23,63.01 89.23,57.12 81.86,49.75 81.86,48.1 80.99,47.23 80.69,47.23 80.57,47.35 80.25,47.35 79.96,47.06 79.96,46.74 80.08,46.62 80.08,46.31 79.77,46.01 79.46,46.01 79.08,46.39 78.78,46.39 78.47,46.08 78.47,45.78 78.85,45.4 78.85,45.09 78.55,44.79 78.24,44.79 77.86,45.17 77.56,45.17 77.25,44.86 77.25,44.56 77.63,44.17 77.63,43.87 77.33,43.56 77.02,43.56 76.64,43.94 76.34,43.94 76.03,43.64 76.03,43.33 76.41,42.95 76.41,42.65 75.53,41.77 75.53,31.62 76.25,30.91 76.25,28.42 v2(76.53,28.14)
  BOTTOM w0.216: DM1.85 77.85,29.94 77.71,29.74 77.71,29.6 77.42,29.3 77.42,29.02 v2(76.53,28.14) ; CPU1.N38 92.8,73.75 v2(92.65,73.75)
M_A_A10: length 62.7
  TOP w0.216: v1(86.23,28.14) v2(85.67,28.14)
  L3 w0.102: v2(101.4,76.06) 101.45,76.12 101.9,76.12 102.03,75.99 102.03,74.13 102.92,73.24 102.92,72.64 102.49,72.2
  L3 w0.216: v2(85.67,28.14) 85.74,28.14 86.65,29.04 86.65,34.27 103.85,51.47 103.85,63.85 103.39,64.32 103.39,65.54 103.88,66.03 103.88,68.39 103.66,68.62 103.2,68.62 102.97,68.85 102.97,69.79 102.49,70.27 102.49,72.2
  BOTTOM w0.216: CPU1.AG34 101.09,75.75 v2(101.4,76.06) ; DM1.107 84.45,29.89 84.53,29.81 84.53,28.85 85.24,28.14 v2(85.67,28.14)
M_A_A11: length 62.2
  TOP w0.216: v1(76.86,24.17) 76.93,24.17 76.93,24.17 77.39,24.17 v2(77.42,24.2)
  L3 w0.102: 92.78,72.37 93.12,72.71 93.12,73.48 93.12,73.49 93.12,75.34 v2(93.77,76)
  L3 w0.216: 92.78,72.37 92.78,72.15 91.26,70.62 91.26,69.13 90.86,68.73 90.86,62.86 90.68,62.68 90.68,57.75 82.45,49.52 82.45,47.82 76.55,41.93 76.55,31.34 76.77,31.12 76.77,28.63 77.02,28.38 77.02,27.25 76.9,27.13 76.9,24.66 77.21,24.34 77.27,24.34 v2(77.42,24.2)
  BOTTOM w0.216: DM1.84 77.55,24.06 v2(77.42,24.2) ; CPU1.R34 94.05,76 v2(93.77,76)
M_A_A12: length 63.1
  TOP w0.216: v2(75.21,27.9) 75.21,27.51 75.21,27.47 v1(75.21,27.34)
  L3 w0.102: v2(92.65,74.55) 92.18,74.08 92.18,73.42 92.02,73.26 92.02,72.21 91.52,71.7 90.5,70.68
  L3 w0.216: v2(75.21,27.9) 75.21,27.97 75.73,28.49 75.73,30.69 75.01,31.41 75.01,43.81 83.26,52.06 83.26,52.37 83.08,52.55 83.08,52.85 83.39,53.16 83.7,53.16 83.87,52.98 84.18,52.98 84.48,53.29 84.48,53.59 84.31,53.77 84.31,54.07 84.61,54.38 84.92,54.38 85.09,54.2 85.4,54.2 85.7,54.51 85.7,54.81 85.53,54.99 85.53,55.3 85.83,55.6 86.14,55.6 86.32,55.42 86.62,55.42 86.93,55.73 86.93,56.03 86.75,56.21 86.75,56.52 87.05,56.82 87.36,56.82 87.54,56.65 87.84,56.65 88.29,57.09 88.29,67.86 90.5,70.07 90.5,70.68
  BOTTOM w0.216: CPU1.N37 92.8,74.55 v2(92.65,74.55) ; v2(75.21,27.9) 75.28,27.9 77.19,29.81 77.19,30.7 77.25,30.76 DM1.83
M_A_A13: length 67
  TOP w0.216: v1(89.31,28.19) 89.37,28.14 v2(89.87,28.14)
  L3 w0.216: v2(89.87,28.14) 90.26,27.75 90.26,27.15 90.58,26.83 90.99,26.83 91.29,27.13 91.29,29.41 92.53,30.65 92.53,33.52 110.41,51.4 110.41,69.79 107.95,72.25 107.39,72.25 106.33,73.31 106.33,73.79 104.72,75.39 v2(104.72,76.06)
  BOTTOM w0.216: v2(89.87,28.14) 89.44,28.14 88.05,29.53 DM1.119 ; CPU1.AN34 104.42,75.75 v2(104.72,76.06)
M_A_A14: length 61.4
  TOP w0.216: v1(75.21,24.89) 75.27,24.83 v2(75.77,24.83)
  L3 w0.102: 90.56,71.89 91.55,72.88 v2(91.55,73.75)
  L3 w0.216: 90.56,71.89 90.05,71.38 89.81,71.38 87.12,68.69 87.12,59.38 77.75,50 77.75,48.73 73.24,44.23 73.24,31.54 74.64,30.15 74.64,25.91 75.56,24.98 75.62,24.98 v2(75.77,24.83)
  BOTTOM w0.216: DM1.80 76.35,24.35 75.87,24.83 v2(75.77,24.83) ; v2(91.55,73.75) 91.7,73.75 CPU1.L38
M_A_A15: length 63.2
  TOP w0.216: v1(75.74,23.62) 75.74,24.1 75.75,24.11 v2(75.75,24.18)
  L3 w0.102: 90.08,71.86 90.48,72.26 90.57,72.26 91.11,72.8 91.11,74.91 v2(91.55,75.35)
  L3 w0.216: 90.08,71.86 89.84,71.86 85.8,67.82 85.8,58.84 77.12,50.17 77.12,48.92 72.72,44.52 72.72,31.32 74.11,29.93 74.11,25.69 75.63,24.18 v2(75.75,24.18)
  BOTTOM w0.216: CPU1.L35 91.7,75.35 v2(91.55,75.35) ; DM1.78 v2(75.75,24.18)
M_A_BS0: length 63.9
  TOP w0.216: v1(85.12,28.87) 85.17,28.82 v2(85.67,28.82)
  L3 w0.216: v2(102.49,73) 102.49,72.94 102,72.46 102,70.2 102.39,69.82 102.39,68.29 103.55,67.12 103.55,66.21 103.07,65.73 103.07,63.73 103.27,63.53 103.27,51.81 102.91,51.44 102.6,51.44 102.07,51.97 101.76,51.97 101.46,51.67 101.46,51.36 101.99,50.83 101.99,50.52 101.68,50.22 101.38,50.22 100.85,50.75 100.54,50.75 100.23,50.44 100.23,50.14 100.77,49.61 100.77,49.3 100.46,49 100.16,49 99.62,49.53 99.32,49.53 99.01,49.22 99.01,48.92 99.55,48.38 99.55,48.08 99.24,47.77 98.93,47.77 98.4,48.31 98.1,48.31 97.79,48 97.79,47.7 98.32,47.16 98.32,46.86 86.13,34.66 86.13,29.26 85.84,28.97 85.82,28.97 v2(85.67,28.82)
  BOTTOM w0.216: v2(85.67,28.82) 85.29,28.82 85.05,29.06 DM1.109 ; CPU1.AJ38 102.13,73.35 v2(102.49,73)
M_A_BS1: length 62.7
  TOP w0.216: v2(84.15,25.47) 83.67,25.47 83.61,25.52 v1(83.59,25.52)
  L3 w0.102: v2(101.45,75.39) 101.8,75.03 101.8,73.96 101.85,73.91 101.85,72.71 101.67,72.53
  L3 w0.216: v2(84.15,25.47) 84.15,26.05 85.15,27.06 85.15,30.34 85.58,30.77 85.58,34.93 97.1,46.45 97.1,48.28 102.51,53.69 102.51,63.09 102.07,63.53 102.07,65.69 101.78,65.98 101.78,69.54 101.5,69.81 101.5,72.37 101.67,72.53
  BOTTOM w0.216: v2(84.15,25.47) 84.4,25.47 84.75,25.12 DM1.108 ; v2(101.45,75.39) 101.01,74.95 CPU1.AG35
M_A_BS2: length 63.7
  TOP w0.216: v2(75.21,29.35) 75.21,29.79 75.21,29.81 v1(75.21,29.91)
  L3 w0.102: v2(92.65,75.35) 91.98,74.68 91.98,73.51 91.82,73.35 91.82,72.45 91.31,71.95 90.75,71.38
  L3 w0.216: v2(75.21,29.35) 75.21,30.31 74.49,31.03 74.49,44.49 78.66,48.66 78.66,50.18 79.03,50.55 79.34,50.55 79.94,49.94 80.25,49.94 80.56,50.25 80.56,50.55 79.95,51.16 79.95,51.47 80.25,51.77 80.56,51.77 81.17,51.16 81.47,51.16 81.78,51.47 81.78,51.77 81.17,52.38 81.17,52.69 81.61,53.13 81.92,53.13 82.06,52.99 82.36,52.99 82.67,53.3 82.67,53.6 82.53,53.74 82.53,54.05 82.83,54.35 83.14,54.35 83.28,54.21 83.58,54.21 83.89,54.52 83.89,54.83 83.75,54.96 83.75,55.27 84.05,55.58 84.36,55.58 84.5,55.44 84.8,55.44 85.11,55.74 85.11,56.05 84.97,56.19 84.97,56.49 87.73,59.25 87.73,68.85 89.94,71.06 90.43,71.06 90.75,71.38
  BOTTOM w0.216: v2(75.21,29.35) 75.35,29.5 75.35,29.52 76.05,30.22 DM1.79 ; CPU1.N34 93.05,75.75 v2(92.65,75.35)
M_A_CAS#: length 63.4
  TOP w0.216: v2(88.14,27.58) 88.16,27.58 v1(88.57,27.17)
  L3 w0.102: 104.47,72.46 104.47,73.22 104.03,73.66 104.03,75.78 v2(103.71,76.11)
  L3 w0.216: 104.47,72.46 107.16,69.77 107.16,65.52 106.86,65.22 106.86,64.48 106.37,64 106.37,50.06 91.01,34.69 90.45,34.69 89.79,34.03 89.79,31.54 88.78,30.53 88.78,28.19 88.16,27.58 v2(88.14,27.58)
  BOTTOM w0.216: v2(103.71,76.11) 103.46,76.11 CPU1.AL34 ; DM1.115 86.85,29.17 88.14,27.88 v2(88.14,27.58)
M_A_DM0: length 81.7
  L4 w0.216: v2(52.14,28.39) 52.04,28.29 51.78,28.29 51.55,28.52 51.55,29.72 51.77,29.94 51.87,29.94 52.08,30.16 52.08,30.59 51.87,30.8 51.77,30.8 51.55,31.02 51.55,31.45 51.77,31.67 51.87,31.67 52.08,31.88 52.08,32.31 51.87,32.53 51.77,32.53 51.55,32.75 51.55,33.18 51.77,33.39 51.87,33.39 52.08,33.61 52.08,34.04 51.87,34.26 51.77,34.26 51.55,34.47 51.55,34.91 51.77,35.12 51.87,35.12 52.08,35.34 52.08,35.77 51.87,35.98 51.77,35.98 51.55,36.2 51.55,36.63 51.77,36.85 51.87,36.85 52.08,37.06 52.08,37.5 51.87,37.71 51.77,37.71 51.55,37.93 51.55,38.36 51.77,38.58 51.87,38.58 52.08,38.79 52.08,39.22 51.87,39.44 51.77,39.44 51.55,39.66 51.55,40.09 51.77,40.3 51.87,40.3 52.08,40.52 52.08,40.95 51.87,41.17 51.77,41.17 51.55,41.38 51.55,41.81 51.77,42.03 51.87,42.03 52.08,42.25 52.08,42.68 51.87,42.89 51.77,42.89 51.55,43.11 51.55,44.65 52.09,45.19 52.4,45.19 52.42,45.17 52.73,45.17 53.03,45.47 53.03,45.78 53.01,45.8 53.01,46.11 53.31,46.41 53.62,46.41 53.65,46.39 53.95,46.39 54.26,46.69 54.26,47 54.23,47.03 54.23,47.33 56.86,49.96 57.17,49.96 57.27,49.86 57.57,49.86 57.88,50.17 57.88,50.47 57.78,50.57 57.78,50.88 58.08,51.19 58.39,51.19 58.49,51.09 58.8,51.09 59.1,51.39 59.1,51.7 59,51.8 59,52.1 59.31,52.41 59.61,52.41 59.71,52.31 60.02,52.31 60.32,52.61 60.32,52.92 60.22,53.02 60.22,53.32 60.53,53.63 60.83,53.63 60.93,53.53 61.24,53.53 61.54,53.83 61.54,54.14 61.44,54.24 61.44,54.55 61.75,54.85 62.05,54.85 62.16,54.75 62.46,54.75 62.77,55.06 62.77,55.36 62.67,55.46 62.67,55.77 62.97,56.07 63.28,56.07 63.38,55.97 63.68,55.97 63.99,56.28 63.99,56.58 63.89,56.68 63.89,56.99 64.19,57.29 64.5,57.29 64.6,57.19 64.9,57.19 65.21,57.5 65.21,57.8 65.11,57.91 65.11,58.21 65.41,58.52 65.72,58.52 65.82,58.42 66.13,58.42 66.43,58.72 66.43,59.03 66.33,59.13 66.33,59.43 66.64,59.74 66.94,59.74 67.04,59.64 67.35,59.64 67.65,59.94 67.65,60.25 67.55,60.35 67.55,60.65 67.86,60.96 68.16,60.96 68.26,60.86 68.57,60.86 68.87,61.16 68.87,61.47 68.77,61.57 68.77,61.88 73.04,66.14 73.04,67.43 77.05,71.44 v2(78.05,71.44)
  BOTTOM w0.102: 84.15,76.14 84.26,76.25 86.43,76.25 86.48,76.2 86.8,76.2 87.1,76.5 CPU1.B32
  BOTTOM w0.216: 84.15,76.14 82.62,74.62 82.62,74.09 79.97,71.44 v1(79.07,71.44) v2(78.05,71.44) ; v2(52.14,28.39) 53.25,29.49 DM1.11
M_A_DM1: length 66.3
  TOP w0.216: v2(57.73,24.84) 58.26,24.84 v1(58.32,24.78)
  L4 w0.216: v2(57.73,24.84) 57.24,25.33 57.24,25.94 58.09,26.79 58.09,40.68 73.78,56.38 73.78,58.15 80.35,64.72 80.35,65.38 80.69,65.73 81.28,65.73 82.79,67.24 84.38,67.24 85.82,68.68 85.82,71.13 v2(85.37,71.59)
  BOTTOM w0.102: v2(85.37,71.59) 85.4,71.62 85.57,71.62 86.15,72.2 86.4,72.2 86.7,72.5 86.7,72.78 87.12,73.2 CPU1.B38
  BOTTOM w0.216: DM1.28 58.35,24.6 58.11,24.84 v2(57.73,24.84)
M_A_DM2: length 62.9
  L4 w0.216: v2(88.85,65.09) 88.85,65.7 88.69,65.85 87.7,65.85 87.45,65.6 87.45,65.16 88.09,64.52 88.09,61.37 77.46,50.73 77.46,47.98 65.05,35.57 65.05,28.55 64.91,28.42 64.91,26.6 64.46,26.15 64.46,25 v2(63.66,24.2)
  BOTTOM w0.102: 89.64,69.86 89.53,69.96 89.53,71.34 89.9,71.7 CPU1.G40
  BOTTOM w0.216: DM1.46 63.75,24.11 v2(63.66,24.2) ; v2(88.85,65.09) 89.64,65.88 v1(89.64,66.67) 89.64,69.86
M_A_DM3: length 69.2
  L4 w0.216: v2(94.69,67.76) 95.53,66.92 95.53,65.07 94.7,64.23 94.7,58.69 84.02,48.01 84.02,40.55 83.58,40.11 83.27,40.11 82.89,40.49 82.59,40.49 82.28,40.19 82.28,39.88 82.66,39.5 82.66,39.19 82.36,38.89 82.05,38.89 81.67,39.27 81.37,39.27 81.06,38.97 81.06,38.66 81.44,38.28 81.44,37.97 81.14,37.67 80.83,37.67 80.45,38.05 80.14,38.05 79.84,37.74 79.84,37.44 80.22,37.06 80.22,36.75 79.92,36.45 79.61,36.45 79.23,36.83 78.92,36.83 78.62,36.52 78.62,36.22 79,35.83 79,35.53 78.69,35.22 78.39,35.22 78.28,35.34 77.99,35.34 77.67,35.01 77.67,34.73 77.78,34.61 77.78,34.31 76.56,33.09 75.77,33.09 75.49,32.81 75.49,32.61 75.28,32.4 74.62,32.4 74.42,32.61 74.42,32.88 74.22,33.09 73.53,33.09 72.22,31.77 v2(72.22,27.06)
  BOTTOM w0.14: 94.47,68.56 93.37,69.66 93.37,71.08 CPU1.N41
  BOTTOM w0.216: v2(72.22,27.06) 72.01,27.06 68.85,30.22 DM1.63 ; 94.47,68.56 94.66,68.37 v1(94.66,68.37) 94.66,68.36 94.69,68.34 v2(94.69,67.76)
M_A_DM4: length 60.3
  L4 w0.216: v2(92.61,24.99) 92.56,24.93 92.24,24.93 92.01,25.16 92.01,26.21 91.32,26.9 91.32,29.9 90.59,30.64 90.59,31.84 90.33,32.1 89.72,32.1 89.46,32.35 89.46,36.52 90.59,37.65 90.59,45.29 101.35,56.05 101.35,62.54 100.91,62.97 v2(100.91,63.7)
  BOTTOM w0.102: CPU1.AG40 100.86,71.91 100.86,71.67 100.58,71.4 100.58,69.29 100.43,69.13
  BOTTOM w0.216: DM1.136 93.15,24.8 92.96,24.99 v2(92.61,24.99) ; 100.43,69.13 100.02,68.73 v1(100.02,63.09) 100.02,62.63 100.25,62.4 100.68,62.4 100.91,62.63 v2(100.91,63.7)
M_A_DM5: length 60.4
  L4 w0.216: v2(107.31,62.86) 107.52,62.86 107.91,62.46 107.91,53.33 98.14,43.56 98.14,41.59 97.92,41.38 97.37,41.38 97.15,41.16 97.15,40.73 97.37,40.51 97.92,40.51 98.14,40.3 98.14,39.86 97.92,39.65 97.37,39.65 97.15,39.43 97.15,39 97.37,38.78 97.92,38.78 98.14,38.57 98.14,38.14 97.92,37.92 97.37,37.92 97.15,37.71 97.15,37.27 97.37,37.06 97.92,37.06 98.14,36.84 98.14,36.41 97.92,36.19 97.37,36.19 97.15,35.98 97.15,35.55 97.37,35.33 97.92,35.33 98.14,35.11 98.14,34.68 97.92,34.47 97.37,34.47 97.15,34.25 97.15,33.82 97.37,33.6 97.92,33.6 98.14,33.39 v2(98.14,29.43)
  BOTTOM w0.102: CPU1.AN41 104.34,71.11 104.34,69.15 104.59,68.9
  BOTTOM w0.216: 104.59,68.9 104.89,68.61 104.89,68.43 105.99,67.33 105.99,64.08 105.61,63.7 104.43,63.7 104.23,63.49 104.23,63.01 104.48,62.76 v1(106.25,62.76) 107.21,62.76 v2(107.31,62.86) ; v2(98.14,29.43) 98.25,29.54 DM1.153
M_A_DM6: length 60.3
  L4 w0.216: v2(103.91,24.94) 104.01,24.94 104.49,24.46 104.85,24.46 105.1,24.72 105.1,26.8 104.73,27.18 104.73,31.89 105.06,32.22 105.06,32.77 104.71,33.13 104.71,40.81 114.54,50.64 114.54,63.92 115.2,64.58 115.2,65.51 115.01,65.7 114.47,65.7 v2(114.42,65.65)
  BOTTOM w0.102: 108.51,70.76 108.3,70.76 107.95,71.1 107.95,71.7 CPU1.AY40
  BOTTOM w0.216: DM1.170 103.35,24.5 103.78,24.93 103.9,24.93 v2(103.91,24.94) ; 108.51,70.76 110.87,68.4 110.87,68.08 v1(111.35,67.6) 113.3,65.65 v2(114.42,65.65)
M_A_DM7: length 78
  TOP w0.216: v2(110.72,28.38) 110.3,28.8 v1(110.16,28.8)
  L4 w0.216: v2(113.13,73.42) 112.32,73.42 112.06,73.17 112.06,72.83 112.35,72.54 113.08,72.54 113.35,72.28 113.35,70.24 113.88,69.7 116.44,69.7 121.42,64.73 121.42,51.58 121.2,51.37 120.7,51.37 120.48,51.15 120.48,50.72 120.7,50.5 121.2,50.5 121.42,50.29 121.42,49.86 121.2,49.64 120.7,49.64 120.48,49.42 120.48,48.99 120.7,48.78 121.2,48.78 121.42,48.56 121.42,47.94 121.1,47.62 120.78,47.62 120.51,47.89 120.19,47.89 119.87,47.57 119.87,47.24 120.14,46.97 120.14,46.66 119.84,46.36 119.53,46.36 119.23,46.66 118.96,46.66 118.62,46.32 118.62,46.05 118.92,45.75 118.92,45.44 118.61,45.14 118.31,45.14 118.04,45.41 117.71,45.41 117.42,45.12 117.42,44.8 117.7,44.52 117.7,44.22 117.39,43.91 117.09,43.91 116.8,44.2 116.5,44.2 116.19,43.89 116.19,43.59 116.48,43.3 116.48,43 116.17,42.69 115.87,42.69 115.58,42.97 115.28,42.97 111.62,39.31 111.62,38.49 111.4,38.27 110.87,38.27 110.65,38.06 110.65,37.63 110.87,37.41 111.4,37.41 111.62,37.19 111.62,36.76 111.4,36.55 110.89,36.55 110.65,36.3 110.65,35.93 110.89,35.68 111.4,35.68 111.62,35.47 111.62,30.38 110.72,29.47 v2(110.72,28.38)
  BOTTOM w0.102: CPU1.AY34 108.08,75.4 108.38,75.1 108.72,75.1 108.85,75.23 109.83,75.23
  BOTTOM w0.216: v2(110.72,28.38) 110.16,28.38 108.45,30.09 DM1.187 ; 109.83,75.23 111.2,73.86 112.46,73.86 112.89,73.42 v2(113.13,73.42)
M_A_DQ<0>: length 81.5
  L4 w0.216: v2(50.11,28.7) 49.97,28.84 49.97,35.96 49.75,36.18 48.75,36.18 48.54,36.4 48.54,36.83 48.75,37.04 49.75,37.04 49.97,37.26 49.97,37.69 49.75,37.91 48.75,37.91 48.54,38.12 48.54,38.56 48.75,38.77 49.75,38.77 49.97,38.99 49.97,39.42 49.75,39.63 48.75,39.63 48.54,39.85 48.54,40.3 48.77,40.53 49.74,40.53 49.97,40.76 49.97,41.19 49.74,41.42 48.77,41.42 48.54,41.65 48.54,42.05 48.79,42.31 49.73,42.31 49.97,42.54 49.97,43.17 49.78,43.35 48.94,43.35 48.71,43.58 48.71,44.06 48.99,44.34 49.71,44.34 49.97,44.6 49.97,45.31 71.35,66.69 v2(71.65,66.69)
  BOTTOM w0.102: 83.34,76.4 84.29,77.35 86.43,77.35 86.48,77.3 86.81,77.3 87.12,77.6 CPU1.B30
  BOTTOM w0.216: v2(50.11,28.7) 51.45,30.04 DM1.5 ; 83.34,76.4 79.73,72.79 v1(79.22,72.79) 77.75,72.79 v2(71.65,66.69)
M_A_DQ<1>: length 82.5
  L4 w0.216: v2(70.1,66.34) 70.11,66.34 47.91,44.14 47.91,34.97 48.13,34.76 49.08,34.76 49.3,34.54 49.3,34.11 49.08,33.89 48.13,33.89 47.91,33.68 47.91,33.25 48.13,33.03 49.08,33.03 49.3,32.82 49.3,32.38 49.08,32.17 48.13,32.17 47.91,31.95 47.91,30.97 48.13,30.76 49.11,30.76 49.32,30.54 49.32,30.11 49.11,29.89 48.13,29.89 47.91,29.68 47.91,28.48 48.23,28.16 49.4,28.16 49.58,27.98 49.58,27.42 49.76,27.25 v2(50.11,27.25)
  BOTTOM w0.102: 83.87,76.37 84,76.5 CPU1.A32
  BOTTOM w0.216: v2(70.1,66.34) 70.36,66.08 71.92,66.08 v1(75.48,69.64) 77.92,72.08 79.58,72.08 83.87,76.37 ; DM1.7 52.05,29.91 50.94,28.8 50.94,27.94 50.24,27.25 v2(50.11,27.25)
M_A_DQ<2>: length 81.7
  L4 w0.216: v2(53.92,28.77) 54.31,29.15 54.31,29.94 53.95,30.29 53.95,30.91 54.31,31.27 54.31,31.78 53.95,32.13 53.95,32.64 54.31,33 54.31,33.5 53.95,33.86 53.95,34.37 54.31,34.72 54.31,35.23 53.95,35.59 53.95,36.1 54.31,36.45 54.31,36.96 53.95,37.31 53.95,37.82 54.31,38.18 54.31,38.69 53.95,39.04 53.95,39.55 54.31,39.91 54.31,40.41 53.95,40.77 53.95,41.28 54.31,41.63 54.31,42.14 53.95,42.5 53.95,43.6 54.39,44.04 54.7,44.04 55.25,43.49 55.56,43.49 55.86,43.79 55.86,44.1 55.31,44.65 55.31,44.96 55.61,45.26 55.92,45.26 56.47,44.71 56.78,44.71 57.08,45.01 57.08,45.32 56.53,45.87 56.53,46.18 56.83,46.48 57.14,46.48 57.69,45.93 58,45.93 58.3,46.23 58.3,46.54 57.75,47.09 57.75,47.4 58.06,47.7 58.36,47.7 58.92,47.15 59.22,47.15 59.53,47.46 59.53,47.76 58.97,48.32 58.97,48.62 59.28,48.93 59.58,48.93 60.14,48.37 60.44,48.37 60.75,48.68 60.75,48.98 60.19,49.54 60.19,49.84 74.91,64.56 74.91,66.66 75.22,66.97 75.56,66.97 75.77,66.77 75.77,66.24 76.02,65.98 76.33,65.98 76.6,66.25 76.6,68.36 77.67,69.42 v2(78.18,69.42)
  BOTTOM w0.102: 83.17,71.99 85.5,74.33 85.83,74.33 86.02,74.52 86.42,74.52 86.74,74.85 CPU1.B35
  BOTTOM w0.216: DM1.15 54.45,29.3 v2(53.92,28.77) ; 83.17,71.99 80.96,69.79 80.96,69.79 80.6,69.42 v1(80.11,69.42) 79.5,69.42 79.13,69.79 79.13,70.6 78.92,70.82 78,70.82 77.77,70.59 77.77,69.83 v2(78.18,69.42)
M_A_DQ<3>: length 81.8
  L4 w0.216: v2(53.92,28.01) 53.95,28.01 53.95,27.98 54.48,27.45 54.73,27.45 54.93,27.64 54.93,41.98 61.01,48.06 61.64,48.69 61.64,49.01 61.1,49.56 61.1,49.87 61.54,50.31 61.85,50.31 62.4,49.75 62.71,49.75 63.01,50.06 63.01,50.37 62.46,50.92 62.46,51.23 62.76,51.53 63.07,51.53 63.62,50.98 63.93,50.98 64.23,51.28 64.23,51.59 63.68,52.14 63.68,52.45 63.98,52.75 64.29,52.75 64.84,52.2 65.15,52.2 65.45,52.5 65.45,52.81 64.9,53.36 64.9,53.67 65.21,53.97 65.51,53.97 66.07,53.42 66.37,53.42 66.68,53.73 66.68,54.03 66.12,54.59 66.12,54.89 77.23,66 77.23,68.1 77.93,68.8 78.59,68.8 78.78,68.61 78.78,68.36 v2(78.23,67.81)
  BOTTOM w0.102: CPU1.A36 86.09,74.3 85.89,74.1 85.63,74.1 83.89,72.36 83.89,71.82 83.83,71.76
  BOTTOM w0.216: v2(53.92,28.01) 55.05,29.14 DM1.17 ; v2(78.23,67.81) 78.23,67.17 78,66.95 76.99,66.95 76.76,67.17 v1(76.76,67.96) 76.76,68.53 76.99,68.76 80.83,68.76 83.83,71.76
M_A_DQ<4>: length 79.3
  L4 w0.216: v2(50.11,24.83) 47.89,24.83 46.67,26.06 46.67,44.65 69.63,67.62 70.8,67.62 v2(70.81,67.63)
  BOTTOM w0.102: 83.13,77.16 83.82,77.85 86.43,77.85 86.74,78.15 CPU1.B29
  BOTTOM w0.216: DM1.4 51.15,23.8 v2(50.11,24.83) ; 83.13,77.16 82.83,77.16 79.72,74.05 77.23,74.05 v1(76.77,73.59) v2(70.81,67.63)
M_A_DQ<5>: length 78
  L4 w0.216: v2(70.3,67) 69.89,67 47.29,44.39 47.29,26.32 48,25.61 50,25.61 v2(50.11,25.72)
  BOTTOM w0.102: 83.03,76.7 83.29,76.7 84.19,77.6 CPU1.A30
  BOTTOM w0.216: DM1.6 51.75,24.08 v2(50.11,25.72) ; v2(70.3,67) 71.06,67 v1(75.55,71.49) 77.48,73.42 79.75,73.42 83.03,76.7
M_A_DQ<6>: length 77.3
  L4 w0.216: v2(79.75,70.68) 80.54,70.68 80.77,70.91 80.77,71.3 80.54,71.52 79,71.52 78.28,70.81 77.3,70.81 73.66,67.18 73.66,65.38 73.1,64.81 72.59,64.81 72.29,64.51 72.29,64.2 72.39,64.1 72.39,63.8 72.08,63.49 71.78,63.49 71.68,63.59 71.37,63.59 71.06,63.29 71.06,62.98 71.17,62.88 71.17,62.57 70.86,62.27 70.55,62.27 70.45,62.37 70.15,62.37 69.84,62.06 69.84,61.76 69.94,61.66 69.94,61.35 52.71,44.11 52.71,28.07 52.3,27.66 52.3,27.15 52.71,26.74 52.71,26.19 52.73,26.16 52.73,24.6 52.96,24.38 53.34,24.38 v2(53.92,24.96)
  BOTTOM w0.102: CPU1.A34 86.65,75.4 85.18,75.4 84.4,74.62 84.4,73.98 84.02,73.6 83.01,73.6
  BOTTOM w0.216: DM1.16 54.75,24.39 54.18,24.96 v2(53.92,24.96) ; v2(79.75,70.68) 80.09,70.68 v1(82.55,73.13) 83.01,73.6
M_A_DQ<7>: length 77.5
  L4 w0.216: v2(79.75,70.05) 80.85,70.05 81.48,70.68 81.81,70.68 82.12,70.37 82.12,70.05 81.3,69.23 79.04,69.23 78.81,69.46 78.81,69.96 78.59,70.18 77.55,70.18 74.29,66.92 74.29,64.82 53.33,43.86 53.33,26.44 53.35,26.42 53.35,26.12 53.62,25.85 v2(53.92,25.85)
  BOTTOM w0.102: CPU1.B34 87.09,75.4 86.79,75.1 86.5,75.1 86.42,75.17 86.4,75.19 85.47,75.19 84.78,74.51 84.78,74.01 83.87,73.09
  BOTTOM w0.216: v2(79.75,70.05) 80.34,70.05 v1(81.21,70.92) 83.39,73.09 83.87,73.09 ; v2(53.92,25.85) 54.18,25.85 55.35,24.68 DM1.18
M_A_DQ<8>: length 69.6
  TOP w0.216: v2(56.84,28.14) 56.31,28.14 v1(56.28,28.11)
  L4 w0.216: v2(56.84,28.14) 57.33,28.14 57.47,28.28 57.47,40.99 73.16,56.69 73.16,58.41 79.73,64.98 79.73,65.64 80.44,66.35 81.02,66.35 81.46,66.79 81.46,67.37 81.95,67.86 84.12,67.86 84.35,68.09 84.35,68.5 84.12,68.72 83.56,68.72 83.37,68.91 83.37,69.33 83.6,69.56 85.01,69.56 85.24,69.79 85.24,70.03 85.01,70.26 v2(84.7,70.26)
  BOTTOM w0.102: CPU1.B37 86.76,73.75 86.45,73.43 85.85,73.43 84.72,72.3 84.72,70.28 v2(84.7,70.26)
  BOTTOM w0.216: v2(56.84,28.14) 56.84,27.3 56.61,27.07 55.98,27.07 55.75,27.3 55.75,28.31 56.25,28.81 DM1.21
M_A_DQ<9>: length 69.7
  TOP w0.216: v2(56.84,29.41) 57.38,29.41 v1(57.4,29.43)
  L4 w0.216: v2(85.29,70.81) 85.2,70.9 84.65,70.9 84.1,70.35 83.82,70.35 83.59,70.58 83.59,71.42 83.36,71.65 82.57,71.65 82.34,71.42 82.34,71.03 82.75,70.62 82.75,68.71 82.52,68.48 81.69,68.48 81.47,68.26 81,68.26 80.65,68.61 80.3,68.61 80.03,68.34 80.03,68.02 80.39,67.66 80.39,67.3 79.11,66.02 79.11,65.23 72.54,58.67 72.54,57.9 72.31,57.68 71.55,57.68 71.23,57.36 71.23,57.06 71.79,56.5 71.79,56.2 71.48,55.89 71.18,55.89 70.62,56.44 70.32,56.44 70.01,56.14 70.01,55.83 70.57,55.28 70.57,54.97 70.26,54.67 69.95,54.67 69.4,55.22 69.09,55.22 68.65,54.78 68.65,54.42 69.11,53.97 69.11,53.52 56.79,41.2 56.79,29.45 v2(56.84,29.41)
  BOTTOM w0.102: CPU1.A38 85.9,73.2 84.94,72.23 84.94,71.16 v2(85.29,70.81)
  BOTTOM w0.216: DM1.23 56.85,29.41 v2(56.84,29.41)
M_A_DQ<10>: length 68.9
  L4 w0.216: v2(60.45,28.14) 60.32,28.14 59.98,28.48 59.98,30.05 59.68,30.36 59.68,30.92 59.98,31.22 59.98,31.78 59.68,32.08 59.68,32.64 59.98,32.95 59.98,33.51 59.68,33.81 59.68,34.37 59.98,34.68 59.98,35.23 59.68,35.54 59.68,36.1 59.98,36.4 59.98,36.96 59.68,37.27 59.68,37.83 59.98,38.13 59.98,38.69 59.68,38.99 59.68,39.55 59.98,39.86 59.98,40.3 60.42,40.74 60.73,40.74 61.17,40.3 61.47,40.3 61.78,40.61 61.78,40.91 61.34,41.35 61.34,41.66 61.64,41.96 61.95,41.96 62.39,41.52 62.69,41.52 63,41.83 63,42.13 62.56,42.57 62.56,42.88 62.86,43.19 63.17,43.19 63.61,42.74 63.92,42.74 64.22,43.05 64.22,43.36 63.78,43.8 63.78,44.1 64.09,44.41 64.39,44.41 64.83,43.97 65.14,43.97 65.44,44.27 65.44,44.58 65,45.02 65,45.32 82.33,62.65 82.33,63.48 82.03,63.78 82.03,64.48 82.6,65.04 v2(82.96,65.04)
  BOTTOM w0.102: CPU1.D40 88.25,72.03 87.95,71.73 87.95,71.47 88.08,71.34 88.08,70.49 87.76,70.17 87.45,70.17
  BOTTOM w0.216: 84.91,66.57 83.79,65.45 83.79,65.12 83.56,64.89 83.11,64.89 v2(82.96,65.04) ; 84.91,66.57 v1(84.91,66.57) ; 84.91,66.57 85.88,67.54 85.88,68.6 87.45,70.17 ; v2(60.45,28.14) 60.35,28.03 60.1,28.03 59.87,28.26 59.87,29 60.02,29.14 60.02,29.57 59.85,29.74 DM1.33
M_A_DQ<11>: length 69.2
  L4 w0.216: v2(60.54,29.46) 60.6,29.52 60.6,38.55 66.48,44.42 66.48,44.73 66.05,45.16 66.05,45.47 66.35,45.77 66.66,45.77 67.09,45.34 67.39,45.34 67.7,45.65 67.7,45.95 67.27,46.38 67.27,46.69 67.57,46.99 67.88,46.99 68.31,46.56 68.62,46.56 68.92,46.87 68.92,47.17 68.49,47.6 68.49,47.91 68.8,48.22 69.1,48.22 69.53,47.78 69.84,47.78 70.14,48.09 70.14,48.4 69.71,48.83 69.71,49.13 70.02,49.44 70.32,49.44 70.75,49.01 71.06,49.01 71.36,49.31 71.36,49.62 70.93,50.05 70.93,50.35 71.24,50.66 71.54,50.66 71.98,50.23 72.28,50.23 72.73,50.68 72.73,50.98 72.34,51.38 72.34,51.55 72.57,51.78 72.87,51.78 73.1,52.01 73.1,52.54 82.96,62.4 v2(82.96,64.28)
  BOTTOM w0.102: CPU1.D41 88.25,71.46 88.29,71.42 88.29,70.28 88.05,70.05
  BOTTOM w0.216: 88.05,70.05 86.5,68.49 v1(86.5,68.04) 86.5,67.28 84.41,65.19 84.41,63.47 84.18,63.24 81.61,63.24 81.38,63.47 81.38,64.05 81.61,64.28 v2(82.96,64.28) ; v2(60.54,29.46) 60.54,29.59 60.45,29.68 DM1.35
M_A_DQ<12>: length 66.9
  L4 w0.216: v2(79.32,68.01) 79.32,67.99 77.85,66.52 77.85,65.74 67.41,55.3 67.41,53.58 55.55,41.72 55.55,25.1 56.45,24.2 v2(56.46,24.2)
  BOTTOM w0.102: CPU1.B36 87.12,74.3 86.82,74 86.52,74 86.45,74.05 86.14,74.05 85.98,73.89 85.71,73.89 84.32,72.5 84.32,71.71 84.12,71.51
  BOTTOM w0.216: DM1.22 56.55,24.11 v2(56.46,24.2) ; v2(79.32,68.01) 80.96,68.01 v1(81.59,68.64) 84.12,71.17 84.12,71.51
M_A_DQ<13>: length 65.2
  L4 w0.216: v2(56.33,25.72) 56.17,25.88 56.17,41.46 68.03,53.32 68.03,55.04 78.48,65.49 78.48,66.28 79.32,67.11 v2(79.32,67.12)
  BOTTOM w0.102: CPU1.A37 86.2,73.65 85.78,73.65 84.52,72.39 84.52,70.89 84.15,70.51 84.15,70.17 84,70.02
  BOTTOM w0.216: v2(79.32,67.12) v1(80.46,67.12) 81.1,67.12 84,70.02 ; v2(56.33,25.72) 57.15,24.91 DM1.24
M_A_DQ<14>: length 66
  L4 w0.216: v2(60.15,24.2) 60.15,24.17 60.38,23.94 61.11,23.94 61.34,24.17 61.34,26.54 61.48,26.69 61.85,27.05 61.85,38 74.34,50.5 74.34,52.02 84.2,61.88 84.2,65.5 84.43,65.73 85.95,65.73 86.18,65.96 86.18,66.39 85.95,66.62 v2(82.95,66.62)
  BOTTOM w0.216: 83.69,67.11 84.58,68 84.58,68.47 86.51,70.4 86.51,70.86 CPU1.B41 ; 83.69,67.11 83.19,66.62 v2(82.95,66.62) ; 83.69,67.11 v1(83.69,67.1) ; DM1.34 v2(60.15,24.2)
M_A_DQ<15>: length 65.5
  L4 w0.216: v2(82.98,65.8) 83.34,65.8 83.58,65.56 83.58,62.14 73.72,52.28 73.72,50.75 61.22,38.26 61.22,27.31 60.6,26.69 59,26.69 58.77,26.46 58.77,25.16 59,24.93 59.55,24.93 60.14,25.52 v2(60.14,25.6)
  BOTTOM w0.102: CPU1.C40 87.29,71.54 87.29,71.02 87.15,70.89 87.15,70.49
  BOTTOM w0.216: 87.15,70.49 85.25,68.6 v1(85.25,68.04) 85.25,67.8 83.26,65.8 v2(82.98,65.8) ; DM1.36 60.75,24.99 v2(60.14,25.6)
M_A_DQ<16>: length 65.7
  L4 w0.216: v2(85.06,63.59) 85.42,63.59 85.68,63.33 85.68,61.59 75.59,51.5 75.59,48.75 74.72,47.89 74.42,47.89 74.12,48.19 73.82,48.18 73.51,47.88 73.51,47.57 73.81,47.28 73.81,46.97 73.5,46.67 73.2,46.67 72.9,46.96 72.6,46.96 72.29,46.66 72.29,46.35 72.59,46.06 72.59,45.75 72.28,45.45 71.98,45.45 71.68,45.74 71.38,45.74 71.07,45.44 71.07,45.13 71.36,44.84 71.36,44.53 71.06,44.23 70.75,44.23 70.46,44.52 70.15,44.52 69.85,44.21 69.85,43.91 70.14,43.61 70.14,43.31 69.84,43 69.53,43 69.24,43.3 68.93,43.3 68.63,42.99 68.63,42.69 68.92,42.39 68.92,42.09 63.18,36.35 63.18,29.33 62.95,29.09 62.95,28.55 v2(62.43,28.04)
  BOTTOM w0.102: CPU1.F40 89.35,72.03 89.05,71.73 89.05,71.43 89.1,71.38 89.1,69.23 89,69.13
  BOTTOM w0.216: v2(62.43,28.04) 62.28,28.04 61.65,28.66 DM1.39 ; v2(85.06,63.59) 85.45,63.59 88.39,66.53 v1(88.39,67.66) 88.39,68.52 89,69.13
M_A_DQ<17>: length 65.8
  L4 w0.216: v2(62.43,29.46) 62.56,29.58 62.56,37.83 63,38.27 63.3,38.27 63.61,37.96 63.92,37.96 64.22,38.27 64.22,38.57 63.91,38.88 63.91,39.19 64.22,39.49 64.53,39.49 64.83,39.19 65.14,39.19 65.44,39.49 65.44,39.8 65.14,40.1 65.14,40.41 65.44,40.71 65.75,40.71 66.05,40.41 66.36,40.41 66.67,40.71 66.67,41.02 66.36,41.33 66.36,41.63 66.66,41.94 66.97,41.94 67.28,41.63 67.58,41.63 67.89,41.93 67.89,42.24 67.58,42.55 67.58,42.85 74.97,50.24 74.97,51.77 85.06,61.86 v2(85.06,62.96)
  BOTTOM w0.102: CPU1.F41 89.35,71.44 89.33,71.42 89.33,68.85 89.32,68.84
  BOTTOM w0.216: 89.32,68.84 89.01,68.54 89.01,66.28 88.11,65.37 v1(88.11,62.96) 88.11,62.12 87.96,61.97 87.07,61.97 86.92,62.12 86.92,63.19 86.76,63.35 86.08,63.35 85.8,63.06 85.8,62.07 85.65,61.92 85.21,61.92 85.06,62.07 v2(85.06,62.96) ; DM1.41 62.25,29.77 62.43,29.59 v2(62.43,29.46)
M_A_DQ<18>: length 66
  L4 w0.216: v2(89.99,62.17) 90.34,61.82 90.34,60.49 79.66,49.82 79.66,47.07 79.02,46.42 79.02,45.97 79.4,45.58 79.4,45.23 78.38,44.21 78.07,44.21 77.6,44.68 77.28,44.68 76.99,44.39 76.99,44.07 77.46,43.6 77.46,43.29 77.16,42.99 76.85,42.99 76.38,43.46 76.06,43.46 75.77,43.17 75.77,42.85 76.24,42.38 76.24,42.07 75.94,41.77 75.4,41.77 75.02,41.38 75.02,40.85 67.42,33.25 67.42,30.35 67.86,29.9 67.86,28.9 66.95,27.98 v2(66.85,27.98)
  BOTTOM w0.102: 91.59,69.14 91.59,69.58 91.36,69.82 91.36,71.32 91.25,71.43 91.25,71.75 91.55,72.05 CPU1.K40
  BOTTOM w0.216: v2(89.99,62.17) 89.99,62.15 90.23,61.9 v1(92,61.9) 92.29,61.9 92.87,62.49 92.87,64.48 91.59,65.76 91.59,69.14 ; v2(66.85,27.98) 66.03,28.81 66.03,28.82 65.25,29.6 DM1.51
M_A_DQ<19>: length 66
  L4 w0.216: v2(66.93,28.82) 66.92,28.83 67.24,29.15 67.24,29.64 66.79,30.09 66.79,33.51 69.95,36.67 69.95,37.25 69.62,37.58 69.62,37.9 70.14,38.42 70.46,38.42 70.93,37.95 71.23,37.95 71.54,38.25 71.54,38.56 71.06,39.04 71.06,39.34 71.37,39.65 71.67,39.65 72.15,39.17 72.46,39.17 72.76,39.47 72.76,39.78 72.28,40.26 72.28,40.56 72.59,40.87 72.89,40.87 73.37,40.39 73.68,40.39 73.98,40.69 73.98,41 73.5,41.48 73.5,41.78 73.81,42.09 74.11,42.09 74.32,41.89 74.64,41.89 74.93,42.17 74.93,42.5 74.73,42.7 74.73,43.01 79.04,47.32 79.04,50.07 89.72,60.75 v2(89.72,61.28)
  BOTTOM w0.102: CPU1.K41 91.56,71.59 91.56,70.12 91.94,69.75 91.94,69.54
  BOTTOM w0.216: v2(66.93,28.82) 66.62,28.82 65.85,29.59 DM1.53 ; v2(89.72,61.28) v1(90.5,61.28) 92.99,61.28 93.5,61.79 93.5,64.58 91.94,66.14 91.94,69.54
M_A_DQ<20>: length 63.4
  L4 w0.216: v2(85.03,64.93) 86.8,64.93 87.47,64.26 87.47,61.62 76.83,50.99 76.83,48.24 64.42,35.83 64.42,28.81 64.29,28.68 64.29,27.84 63.82,27.36 63.82,26.08 62.07,24.34 62.07,24.34 v2(61.95,24.22)
  BOTTOM w0.102: 88.49,69.86 88.49,71.37 88.8,71.68 CPU1.E40
  BOTTOM w0.216: DM1.40 v2(61.95,24.22) ; 88.49,69.86 87.15,68.52 87.15,67.05 v1(86.65,66.56) v2(85.03,64.93)
M_A_DQ<21>: length 63
  TOP w0.216: v2(61.92,25.52) 61.64,25.52 v1(61.36,25.24)
  L4 w0.216: v2(85.06,64.26) 85.09,64.22 86.37,64.22 86.84,63.74 86.84,61.88 76.21,51.25 76.21,48.5 63.8,36.09 63.8,29.07 63.57,28.83 63.57,28.3 63.19,27.92 63.19,26.79 v2(61.92,25.52)
  BOTTOM w0.14: CPU1.E41 88.8,69.57 88.77,69.54
  BOTTOM w0.216: DM1.42 62.55,25.02 62.05,25.52 v2(61.92,25.52) ; 88.77,69.54 87.77,68.54 87.77,66.79 85.29,64.31 85.11,64.31 v2(85.06,64.26)
M_A_DQ<22>: length 63.4
  TOP w0.216: v1(64.67,24.5) 64.97,24.2 v2(65.22,24.2)
  L4 w0.216: v2(90.37,63.95) 90.53,63.95 91.58,62.9 91.58,59.97 80.91,49.3 80.91,44.89 69.1,33.08 69.1,28.38 68.49,27.76 68.49,27.37 65.31,24.2 v2(65.22,24.2)
  BOTTOM w0.102: 90.83,69.13 90.83,70.87 90.7,71 90.7,71.38 91,71.69 CPU1.J40
  BOTTOM w0.216: v2(65.22,24.2) 64.95,23.92 DM1.50 ; v2(90.37,63.95) 90.51,63.81 91.4,63.81 91.54,63.95 91.54,64.46 90.83,65.16 90.83,69.13
M_A_DQ<23>: length 63.3
  TOP w0.216: v1(65.73,25.49) 65.38,25.85 v2(65.22,25.85)
  L4 w0.216: v2(65.22,25.85) 66.08,25.85 67.87,27.63 67.87,28.02 68.48,28.64 68.48,30.16 68.04,30.6 68.04,32.89 80.29,45.14 80.29,49.56 90.96,60.23 90.96,62.6 v2(90.37,63.19)
  BOTTOM w0.14: CPU1.J41 91.08,71.17 91.08,69.36 91.18,69.27
  BOTTOM w0.216: v2(90.37,63.19) 91.69,63.19 92.25,63.75 92.25,64.41 91.18,65.48 91.18,69.27 ; v2(65.22,25.85) 65.73,25.34 65.73,23.82 65.55,23.64 DM1.52
M_A_DQ<24>: length 69
  L4 w0.216: v2(94.77,66.24) 94.55,66.02 94.55,64.88 94.07,64.4 94.07,58.94 83.4,48.27 83.4,41.61 82.96,41.18 81.97,41.18 81.76,41.39 81.45,41.39 81.15,41.09 81.15,40.78 81.36,40.57 81.36,40.26 81.06,39.95 80.75,39.95 80.54,40.17 80.23,40.17 79.93,39.86 79.93,39.56 80.14,39.34 80.14,39.04 79.84,38.73 79.53,38.73 79.31,38.95 79.01,38.95 78.7,38.64 78.7,38.34 78.99,38.05 78.99,37.76 78.67,37.44 78.38,37.44 78.09,37.73 77.79,37.73 77.48,37.42 77.48,37.12 77.91,36.69 77.91,36.4 77.59,36.08 77.04,36.08 76.81,35.85 76.81,34.22 76.44,33.85 73.43,33.85 73.29,33.71 73.27,33.71 71.59,32.03 71.59,27.09 v2(71.42,26.92)
  BOTTOM w0.102: 92.86,69.71 92.86,70.66 92.65,70.88 CPU1.M41
  BOTTOM w0.14: 93.62,68.51 92.86,69.27 92.86,69.71
  BOTTOM w0.216: 93.62,68.51 v1(93.62,67.71) 93.62,66.99 94.37,66.24 v2(94.77,66.24) ; v2(71.42,26.92) 71.12,26.61 70.47,26.61 67.05,30.03 DM1.57
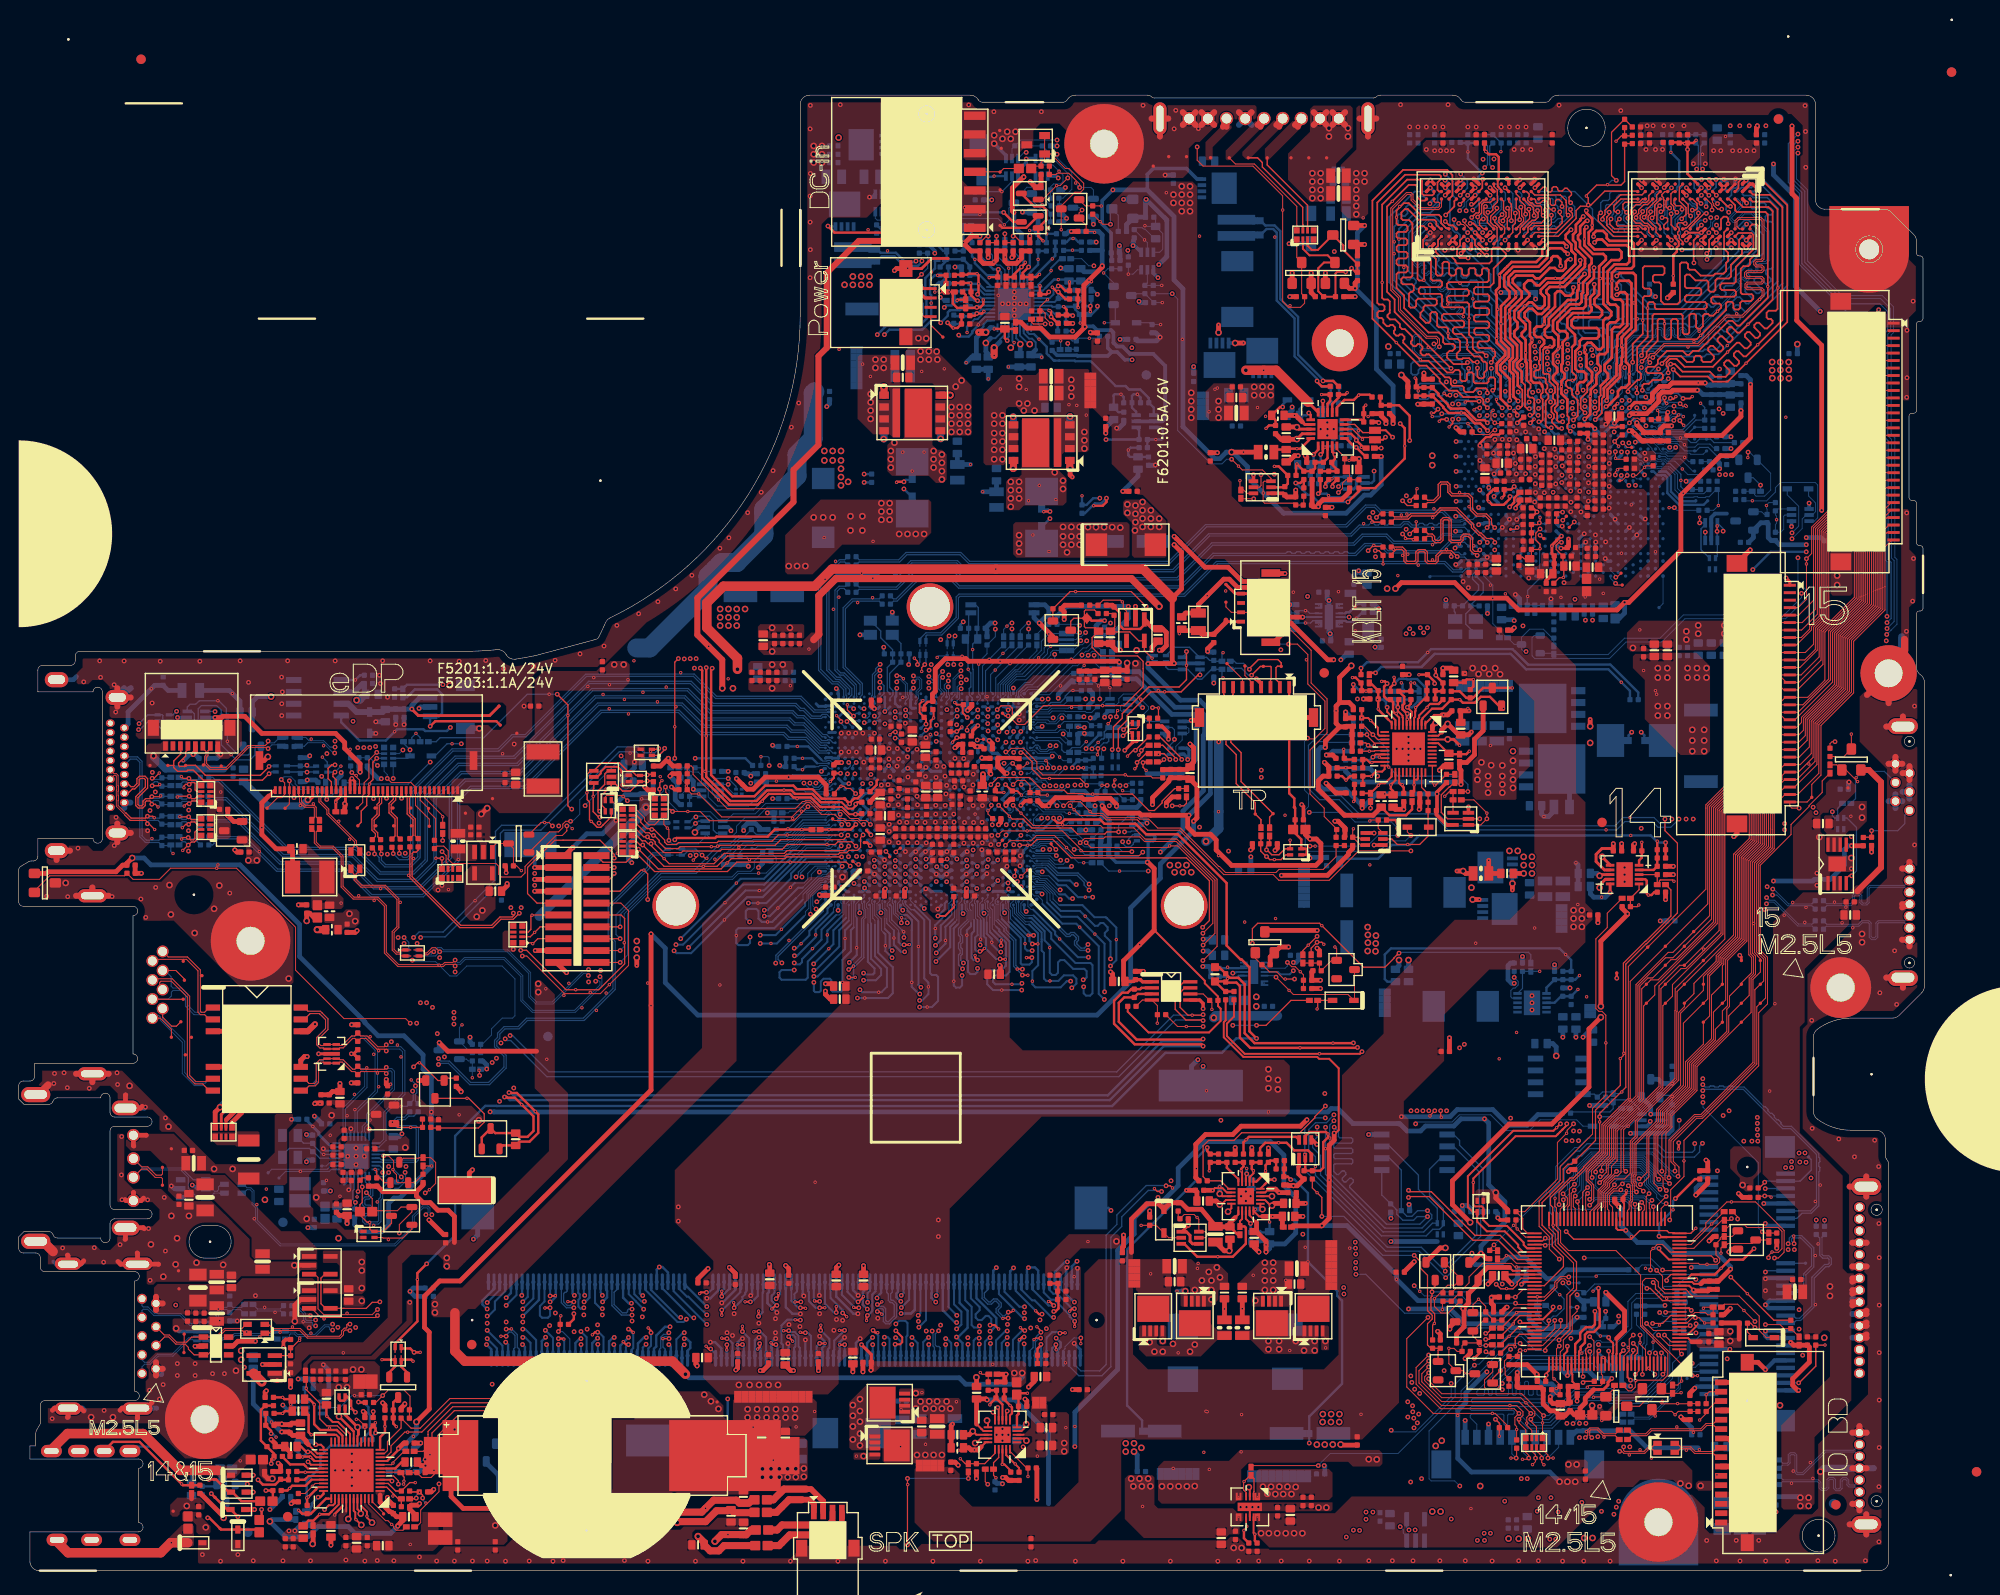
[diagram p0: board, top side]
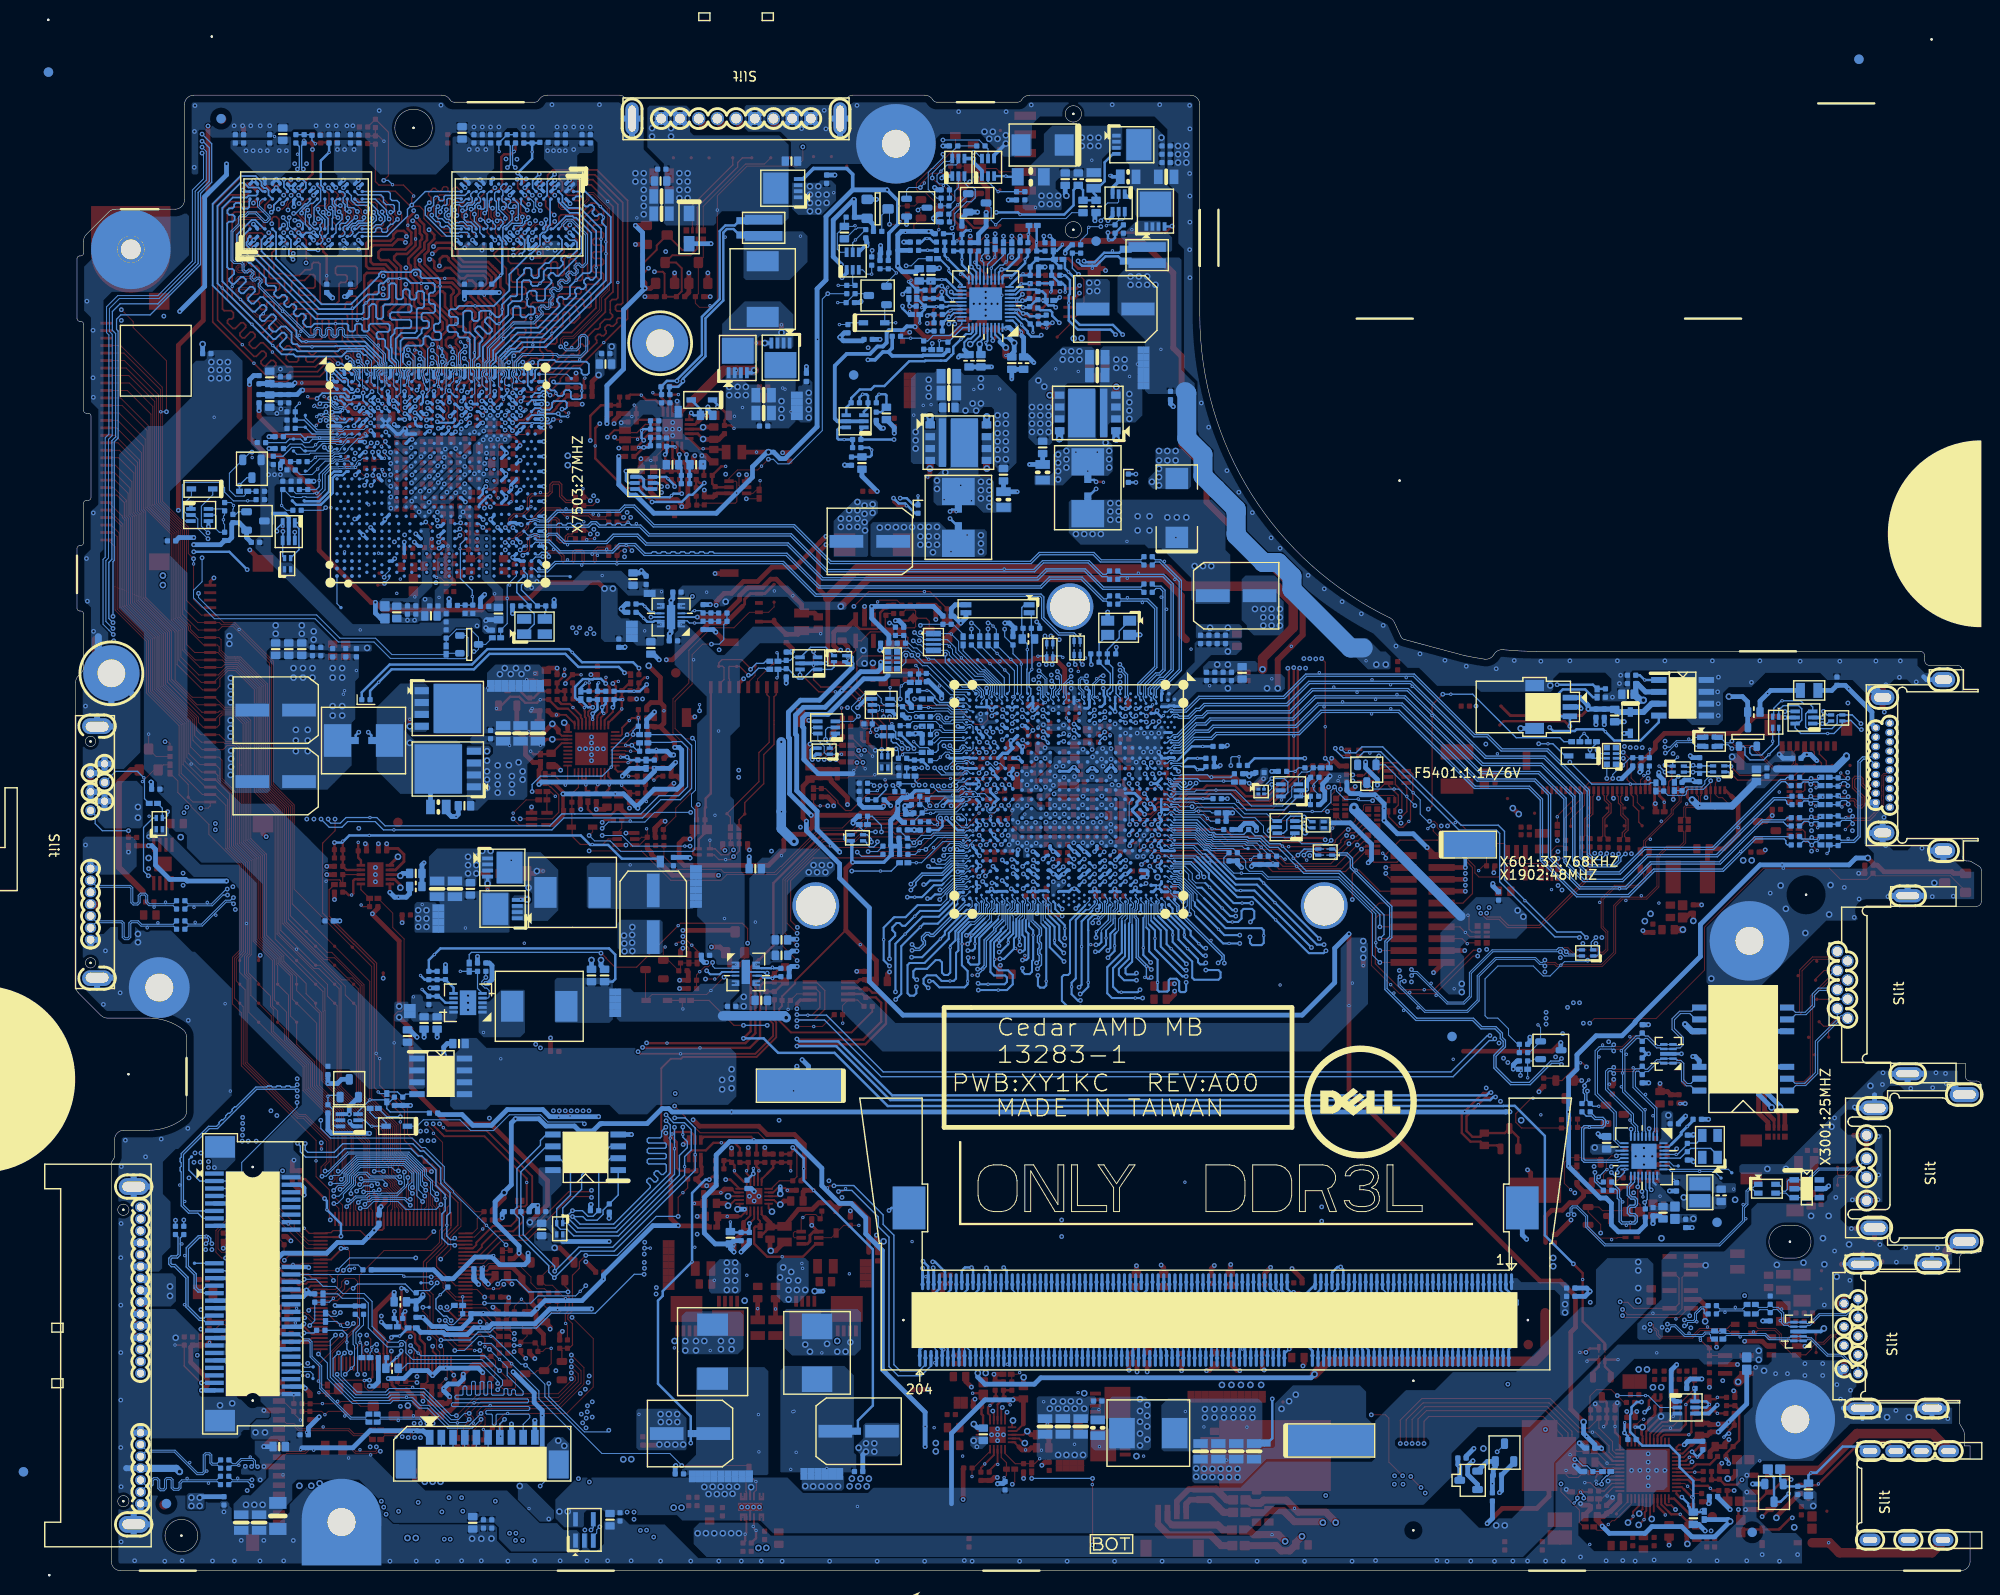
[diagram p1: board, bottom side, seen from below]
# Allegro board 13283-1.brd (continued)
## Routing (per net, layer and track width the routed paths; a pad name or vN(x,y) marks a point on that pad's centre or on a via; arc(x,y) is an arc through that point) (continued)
M_A_DQ<25>: length 69.4
  TOP w0.216: v2(94.7,66.98) 95.24,66.98 v1(95.26,67)
  L4 w0.216: v2(94.7,66.98) 94.7,67.02 94.5,67.23 94.13,67.23 93.93,67.02 93.93,65.19 93.45,64.72 93.45,59.2 82.78,48.53 82.78,44.11 82.29,43.63 82.29,43.15 82.77,42.67 82.77,42.35 82.48,42.06 82.16,42.06 81.66,42.56 81.23,42.56 80.9,42.23 80.9,41.72 80.55,41.37 80.03,41.37 79.78,41.12 79.78,40.6 79.55,40.37 79.03,40.37 78.65,39.99 78.65,39.47 78.26,39.08 77.75,39.08 77.33,38.67 77.33,38.15 76.89,37.71 76.38,37.71 76,37.33 76,37.03 76.4,36.63 76.4,36.32 76.1,36.02 75.79,36.02 75.39,36.42 75.08,36.42 74.78,36.11 74.78,35.81 75.56,35.02 75.56,34.74 75.3,34.47 74.89,34.47 74.17,35.2 73.86,35.2 70.97,32.31 70.97,27.61 70.82,27.45 v2(70.82,27.1)
  BOTTOM w0.102: 94.13,68.27 94.13,68.52 93.12,69.53 93.12,70.91 92.9,71.12 92.9,71.38 93.2,71.68 CPU1.N40
  BOTTOM w0.216: v2(94.7,66.98) 94.4,66.98 94.13,67.26 94.13,68.27 ; DM1.59 67.65,30.03 70.57,27.1 v2(70.82,27.1)
M_A_DQ<26>: length 69.3
  L4 w0.216: v2(96.37,61.03) 96.54,61.03 96.92,60.64 96.92,57.79 86.23,47.09 86.23,39.64 84.75,38.16 84.75,36.43 84.24,35.92 84.24,35.61 84.44,35.4 84.44,35.1 84.14,34.79 83.83,34.79 83.62,35 83.32,35 83.01,34.7 83.01,34.39 83.22,34.18 83.22,33.88 82.92,33.57 82.61,33.57 82.4,33.78 82.1,33.78 81.1,32.79 81.1,32.48 81.31,32.27 81.31,31.97 81.01,31.66 80.7,31.66 80.49,31.87 80.19,31.87 79.88,31.57 79.88,31.26 80.09,31.05 80.09,30.75 79.79,30.44 79.48,30.44 78.92,31.01 77.92,31.01 77.54,30.62 77.54,29.89 77.34,29.68 76.17,29.68 75.94,29.46 75.94,27.53 75.72,27.3 74.67,27.3 73.73,26.36 v2(73.61,26.36)
  BOTTOM w0.14: 95.77,70.74 95.46,70.74 94.85,71.35 CPU1.T41
  BOTTOM w0.216: v2(96.37,61.03) 96.37,61.02 96.64,61.02 97.31,61.69 v1(97.31,62.48) 97.31,62.93 96.86,63.38 96.86,69.65 95.77,70.74 ; DM1.67 70.05,29.91 v2(73.61,26.36)
M_A_DQ<27>: length 69
  L4 w0.216: v2(73.61,27.37) 74.37,28.14 74.37,30.37 74.75,30.75 76.68,30.75 78,32.07 78.43,32.07 78.75,31.75 79.15,31.75 79.46,32.06 79.46,32.36 79.04,32.78 79.04,33.06 80.12,34.14 80.4,34.14 80.77,33.77 81.07,33.77 81.38,34.08 81.38,34.38 80.98,34.79 80.98,35.07 81.3,35.4 81.59,35.4 81.99,34.99 82.3,34.99 82.6,35.3 82.6,35.61 82.12,36.08 82.12,36.37 82.45,36.69 82.73,36.69 83.21,36.22 83.52,36.22 83.82,36.52 83.82,36.83 83.62,37.03 83.62,37.9 85.61,39.89 85.61,47.35 96.28,58.03 96.28,60.23 v2(96.37,60.32)
  BOTTOM w0.102: 95.86,71.23 95.4,71.69 CPU1.U40
  BOTTOM w0.216: v2(73.61,27.37) 73.59,27.37 71.63,29.33 71.47,29.33 70.65,30.15 DM1.69 ; 95.86,71.23 95.86,71.18 97.48,69.55 97.48,63.95 97.69,63.75 98.14,63.75 98.35,63.54 98.35,60.98 97.69,60.32 v1(97.18,60.32) v2(96.37,60.32)
M_A_DQ<28>: length 66
  L4 w0.216: v2(93.42,65.6) 92.25,66.77 91.92,66.77 91.64,66.49 91.64,65.88 92.83,64.69 92.83,59.46 82.15,48.78 82.15,44.37 70.35,32.56 70.35,27.86 69.73,27.25 69.73,26.86 68.91,26.03 68.91,24.17 68.59,23.86 67.48,23.86 v2(67.11,24.23)
  BOTTOM w0.102: CPU1.L40 92.1,71.68 91.8,71.38 91.8,70.22 92.28,69.74 92.28,68.53 92.52,68.29
  BOTTOM w0.216: 92.52,68.29 92.71,68.1 v1(92.71,66.87) 92.71,66.31 v2(93.42,65.6) ; v2(67.11,24.23) 66.75,23.88 DM1.56
M_A_DQ<29>: length 66.3
  TOP w0.216: v1(67.33,25.98) 67.64,25.67 v2(67.64,25.47)
  L4 w0.216: v2(93.43,66.36) 93.43,67.04 92.56,67.91 91.79,67.91 91.11,67.23 91.11,65.45 92.21,64.35 92.21,59.72 81.53,49.04 81.53,44.63 69.73,32.82 69.73,28.12 69.11,27.51 69.11,27.12 68.29,26.29 68.29,25.66 68.1,25.47 v2(67.64,25.47)
  BOTTOM w0.102: CPU1.M40 92.65,72.03 92.35,71.73 92.35,71.43 92.4,71.38 92.4,70.84 92.66,70.58 92.66,69.82 92.64,69.8 92.64,68.69
  BOTTOM w0.216: DM1.58 67.35,23.78 67.64,24.07 v2(67.64,25.47) ; v2(93.43,66.36) 93.16,66.63 93.16,68.16 92.64,68.69
M_A_DQ<30>: length 65.4
  L4 w0.216: v2(71.19,25.47) 73.26,25.47 73.53,25.73 74.46,25.73 75.31,26.58 76.81,26.58 85.37,35.15 85.37,37.9 86.85,39.38 86.85,46.84 97.58,57.57 97.58,60.86 96.73,61.71 v2(96.39,61.71)
  BOTTOM w0.102: CPU1.R40 94.3,71.7 94,71.39 94,70.61 94.43,70.17 94.69,70.17
  BOTTOM w0.216: v2(96.39,61.71) 96.29,61.71 95.53,62.48 v1(95.53,62.96) 95.53,68.54 95.54,68.55 95.54,69.62 94.99,70.17 94.69,70.17 ; v2(71.19,25.47) 71.07,25.47 70.35,24.75 DM1.68
M_A_DQ<31>: length 65.1
  L4 w0.216: v2(71.19,24.18) 72.85,24.18 73.78,25.11 74.72,25.11 75.56,25.96 77.06,25.96 86,34.89 86,37.46 87.48,38.94 87.48,46.58 98.21,57.31 98.21,61.14 96.91,62.43 v2(96.51,62.43)
  BOTTOM w0.102: CPU1.T40 94.85,72.03 94.55,71.73 94.55,71.43 94.6,71.38 94.6,71.27 95.07,70.81 95.07,70.65
  BOTTOM w0.216: v2(96.51,62.43) 96.24,62.7 v1(96.24,66.79) 96.24,69.48 95.07,70.65 ; DM1.70 70.95,23.94 v2(71.19,24.18)
M_A_DQ<32>: length 61.9
  L4 w0.216: v2(98.14,66.11) 98.56,66.52 98.56,67.3 98.81,67.56 99.22,67.56 99.47,67.3 99.47,66.72 99.7,66.49 100.2,66.49 100.43,66.72 100.43,67.84 100.66,68.06 101.14,68.06 101.37,67.84 101.37,65.98 101.04,65.65 100.63,65.65 100.43,65.45 100.43,64.09 100.29,63.95 100.29,62.71 100.72,62.28 100.72,56.31 89.96,45.55 89.96,37.91 88.84,36.78 88.84,31.95 89.32,31.46 89.75,31.46 89.96,31.25 89.96,30.38 90.29,30.05 90.29,29.23 v2(90.8,28.72)
  BOTTOM w0.102: 99.9,69.66 100.1,69.87 100.1,71.38 100.05,71.43 100.05,71.73 100.35,72.03 CPU1.AF40
  BOTTOM w0.216: v2(90.8,28.72) 90.8,29.71 91.05,29.96 DM1.129 ; 99.9,69.66 99.13,68.9 v1(99.13,67.45) 99.13,67.1 v2(98.14,66.11)
M_A_DQ<33>: length 61.9
  TOP w0.216: v2(90.78,27.32) 90.69,27.23 v1(90.69,26.76)
  L4 w0.216: v2(98.12,65.19) 99.41,65.19 99.67,64.94 99.67,64.53 99.41,64.28 98.73,64.28 98.48,64.03 98.48,63.65 98.73,63.39 99.41,63.39 99.62,63.19 99.62,62.51 100.1,62.02 100.1,56.57 89.34,45.81 89.34,38.16 88.22,37.04 88.22,31.08 88.45,30.84 89.08,30.84 89.33,30.59 89.33,30.09 89.08,29.84 88.47,29.84 88.22,29.58 88.22,29.11 89.26,28.07 89.26,27.32 89.56,27.01 90.48,27.01 v2(90.78,27.32)
  BOTTOM w0.102: CPU1.AF41 100.35,69.61 100.15,69.41
  BOTTOM w0.216: DM1.131 91.65,29.9 91.31,29.56 91.31,27.78 90.85,27.32 v2(90.78,27.32) ; v2(98.12,65.19) 99.64,66.72 99.64,68.9 100.15,69.41
M_A_DQ<34>: length 61.9
  TOP w0.216: v2(102.82,66.28) 102.99,66.28 v1(103.3,66.59)
  L4 w0.216: v2(102.82,66.28) 103.14,66.28 103.33,66.47 103.33,67.29 103.22,67.4 103.22,68.95 104.16,69.89 105.51,69.89 105.76,69.64 105.76,69.23 105.51,68.98 104.37,68.98 104.14,68.75 104.14,68.5 104.39,68.24 104.39,68.01 104.14,67.76 104.14,65.9 103.91,65.68 103.91,64.36 104.18,64.09 104.18,54.88 93.42,44.12 93.42,31.84 94.41,30.85 v2(94.41,29.46)
  BOTTOM w0.102: CPU1.AK40 102.55,72.06 102.25,71.76 102.25,71.43 102.35,71.33 102.35,69.83 102.57,69.6
  BOTTOM w0.216: v2(94.41,29.46) 94.41,29.46 94.65,29.7 DM1.141 ; v2(102.82,66.28) 102.49,66.28 102.31,66.46 102.31,67.76 102.57,68.02 102.57,69.6
M_A_DQ<35>: length 62.6
  L4 w0.216: v2(94.41,28.16) 95.03,28.78 95.03,31.11 94.04,32.1 94.04,43.86 104.8,54.62 104.8,64.14 104.41,64.53 104.41,65.62 104.57,65.77 104.57,67.55 106.08,69.07 106.08,70.46 105.66,70.88 105.25,70.88 104.52,70.88 102.77,69.13 102.77,67.04 v2(102.84,66.96)
  BOTTOM w0.102: 102.9,69.59 102.89,69.59 102.89,69.74 102.55,70.08 CPU1.AK41
  BOTTOM w0.216: v2(102.84,66.96) 102.9,67.02 v1(102.9,67.58) 102.9,69.59 ; DM1.143 95.25,29 v2(94.41,28.16)
M_A_DQ<36>: length 59.5
  L4 w0.216: v2(91.35,24.19) 91.35,24.19 90.22,25.32 89.43,25.32 88.54,26.21 87.42,26.21 86.38,27.25 86.38,34.36 86.62,34.59 86.62,37.2 88.1,38.68 88.1,46.32 98.83,57.05 98.83,61.53 96.97,63.39 96.97,66.62 v2(98.04,67.68)
  BOTTOM w0.102: 99.5,70.65 99.5,71.39 99.8,71.69 CPU1.AE40
  BOTTOM w0.14: 98.75,69.79 99.5,70.54 99.5,70.65
  BOTTOM w0.216: DM1.130 v2(91.35,24.19) ; v2(98.04,67.68) v1(98.04,68.72) 98.04,69.08 98.75,69.79
M_A_DQ<37>: length 58.9
  TOP w0.216: v1(91.89,25.47) 91.64,25.47 v2(91.39,25.72)
  L4 w0.216: v2(98.07,66.92) 97.6,66.45 97.6,63.65 99.48,61.76 99.48,56.82 88.72,46.06 88.72,38.42 87.24,36.94 87.24,34.34 87.01,34.1 87.01,29.44 88.64,27.81 88.64,27.06 89.75,25.94 91.16,25.94 v2(91.39,25.72)
  BOTTOM w0.14: 99.64,70.05 99.8,70.2 CPU1.AE41
  BOTTOM w0.216: 99.64,70.05 98.63,69.03 98.63,67.48 v2(98.07,66.92) ; v2(91.39,25.72) 91.95,25.16 DM1.132
M_A_DQ<38>: length 58
  L4 w0.216: v2(102.56,64.46) 102.56,63.57 102.93,63.2 102.93,55.39 92.17,44.63 92.17,31.32 93.16,30.34 93.16,27.75 92.91,27.5 92.66,27.5 92.4,27.25 92.4,26.7 93.16,25.94 93.16,25.57 v2(93.8,24.93)
  BOTTOM w0.102: CPU1.AJ40 102,71.68 101.7,71.38 101.7,70.84 101.87,70.67 101.87,69.28
  BOTTOM w0.216: DM1.140 94.35,24.53 93.95,24.93 v2(93.8,24.93) ; 101.87,69.28 101.87,68.97 101.42,68.52 v1(101.42,68.01) 101.42,65.36 101.54,65.24 101.54,64.1 101.8,63.85 102.31,63.85 102.56,64.1 v2(102.56,64.46)
M_A_DQ<39>: length 58.6
  TOP w0.216: v1(102.3,65.84) 102.3,65.61 v2(102.56,65.35)
  L4 w0.216: v2(102.56,65.35) 102.56,65.6 102.72,65.75 103.32,65.75 103.56,65.52 103.56,55.13 92.8,44.37 92.8,31.58 93.78,30.6 93.78,27.43 94.36,26.86 94.36,26.59 94.17,26.41 v2(93.83,26.41)
  BOTTOM w0.102: 102.2,69.61 102.07,69.73 102.07,71.18 CPU1.AJ41
  BOTTOM w0.216: v2(93.83,26.41) 94.16,26.74 94.84,26.74 95.07,26.51 95.07,25.17 94.95,25.05 DM1.142 ; 102.2,69.61 102.2,68.44 101.93,68.17 101.93,65.57 102.16,65.35 v2(102.56,65.35)
M_A_DQ<40>: length 61.8
  TOP w0.216: v2(105.08,66.89) 105.1,66.91 v1(105.1,67.48)
  L4 w0.216: v2(96.21,27.32) 96.9,28 96.9,31.88 95.91,32.87 95.91,43.09 106.67,53.84 106.67,64.75 106.92,65 107.44,65 107.67,65.23 107.67,67.45 107.44,67.68 107.01,67.68 106.78,67.45 106.78,66.24 106.55,66.01 106.14,66.01 105.92,66.24 105.92,67.48 105.69,67.71 105.33,67.71 105.08,67.45 v2(105.08,66.89)
  BOTTOM w0.102: CPU1.AM41 103.65,70.91 103.9,70.67 103.9,69.95
  BOTTOM w0.14: 103.9,68.36 103.9,69.95
  BOTTOM w0.216: v2(96.21,27.32) 96.45,27.56 DM1.147 ; v2(105.08,66.89) 105.08,67.17 103.9,68.36
M_A_DQ<41>: length 62
  L4 w0.216: v2(96.29,26.05) 96.44,26.2 96.44,26.2 96.89,26.64 96.89,27.11 97.52,27.74 97.52,32.14 96.53,33.13 96.53,42.83 107.29,53.59 107.29,62.13 v2(107.29,62.13)
  BOTTOM w0.102: 104.33,68.51 104.14,68.7 104.14,70.73 103.9,70.97 103.9,71.38 104.2,71.68 CPU1.AN40
  BOTTOM w0.216: DM1.149 97.05,26.81 96.29,26.05 v2(96.29,26.05) ; v2(107.29,62.13) v1(105.15,62.13) 104.33,62.13 104.33,62.13 104.22,62.13 103.6,62.75 103.6,63.75 104.11,64.25 105.1,64.25 105.61,64.76 105.61,67.23 104.33,68.51
M_A_DQ<42>: length 60.9
  TOP w0.216: v1(109.01,67.07) 109.01,67.07 v2(108.43,67.07)
  L4 w0.216: v2(108.43,67.07) 109.55,67.07 109.8,66.81 109.8,65.22 110.05,64.97 110.49,64.97 110.72,65.19 110.72,66.36 110.94,66.59 111.55,66.59 111.81,66.34 111.81,64.59 111.55,64.33 111.05,64.33 110.74,64.03 110.74,52.16 100.97,42.38 100.97,30.94 100.97,28.73 100.97,28.73 100.97,27.95 100.35,27.33 v2(100.35,27.32)
  BOTTOM w0.102: CPU1.AT41 105.85,70.9 106.09,70.66 106.09,69.77 106.5,69.36
  BOTTOM w0.216: v2(108.43,67.07) 108.12,67.38 108.12,67.74 106.5,69.36 ; DM1.157 99.45,28.22 v2(100.35,27.32)
M_A_DQ<43>: length 61.8
  TOP w0.216: v1(107.97,68.01) 108,67.99 v2(108.56,67.99)
  L4 w0.216: v2(100.33,25.87) 100.35,25.87 100.35,25.89 100.84,26.38 100.84,26.93 101.59,27.69 101.59,28.47 101.59,42.13 111.37,51.9 111.37,63.07 112.44,64.14 112.44,66.96 112.19,67.21 110.68,67.21 109.9,67.99 v2(108.56,67.99)
  BOTTOM w0.102: CPU1.AU40 106.4,71.68 106.1,71.38 106.1,71.07 106.32,70.85 106.32,70.09 106.63,69.79
  BOTTOM w0.216: 106.63,69.79 108.43,67.99 v2(108.56,67.99) ; DM1.159 100.05,28.5 100.84,27.71 100.84,26.34 100.42,25.92 100.37,25.92 v2(100.33,25.87)
M_A_DQ<44>: length 56.8
  TOP w0.216: v2(104.98,65.47) 105.01,65.44 v1(105.53,65.44)
  L4 w0.216: v2(104.98,65.47) 104.98,65.43 105.42,64.99 105.42,54.36 94.66,43.6 94.66,32.36 95.65,31.37 95.65,28.52 95.1,27.97 95.1,25.41 v2(95.55,24.96)
  BOTTOM w0.102: CPU1.AL40 103.1,71.68 102.8,71.38 102.8,70.17 103.23,69.75
  BOTTOM w0.216: v2(104.98,65.47) 104.54,65.47 103.47,66.54 103.47,67.65 103.23,67.9 103.23,69.75 ; v2(95.55,24.96) 96.15,24.36 DM1.146
M_A_DQ<45>: length 57.4
  L4 w0.216: v2(105.05,66.2) 106.05,65.21 106.05,54.1 95.29,43.34 95.29,32.61 96.27,31.63 96.27,28.26 95.72,27.71 95.72,25.93 96.69,24.96 v2(97.33,24.96)
  BOTTOM w0.102: CPU1.AM40 103.65,72.03 103.35,71.73 103.35,71.47 103.4,71.42 103.4,70.82 103.69,70.53 103.69,70.17 103.55,70.03 103.55,69.4
  BOTTOM w0.216: 103.55,69.4 103.55,68.16 104.09,67.63 v1(104.09,67.25) 104.09,67.04 104.93,66.2 v2(105.05,66.2) ; v2(97.33,24.96) 97.25,24.96 96.75,24.46 DM1.148
M_A_DQ<46>: length 58.4
  TOP w0.216: v1(107.8,65.6) 108.36,65.6 v2(108.37,65.61)
  L4 w0.216: v2(108.37,65.61) 108.5,65.48 108.5,64.12 109.5,63.12 109.5,52.67 99.73,42.9 99.73,28.47 99.11,27.84 99.11,24.89 v2(99.16,24.83)
  BOTTOM w0.102: CPU1.AR40 105.3,71.71 105,71.41 105,70.18 105.15,70.02 105.15,69.74
  BOTTOM w0.216: 105.15,69.74 107.18,67.71 107.18,64.99 107.31,64.86 108.12,64.86 108.37,65.12 v2(108.37,65.61) ; DM1.158 99.75,24.37 99.29,24.83 v2(99.16,24.83)
M_A_DQ<47>: length 56.5
  L4 w0.216: v2(100.32,24.23) 99.73,24.82 99.73,27.59 100.35,28.21 100.35,42.64 110.12,52.41 110.12,63.38 109.12,64.38 109.12,65.64 v2(108.41,66.35)
  BOTTOM w0.102: 105.89,69.46 105.89,70.57 105.6,70.86 105.6,71.38 105.55,71.43 105.55,71.73 105.85,72.03 CPU1.AT40
  BOTTOM w0.216: v2(108.41,66.35) 107.88,66.35 107.65,66.59 v1(107.65,67.1) 107.65,67.71 105.89,69.46 ; v2(100.32,24.23) 100.35,24.23 DM1.160
M_A_DQ<48>: length 64.2
  L4 w0.216: v2(113.87,63.24) 113.52,63.24 113.27,62.98 113.27,51.13 103.46,41.32 103.46,32.89 103.46,31.97 103.46,31.97 103.46,26.91 102.77,26.22 v2(102.77,26.19)
  BOTTOM w0.102: CPU1.AV41 106.95,70.47 107.58,69.84 108.1,69.84
  BOTTOM w0.216: 108.1,69.84 108.33,69.84 109.74,68.43 109.74,67.45 110.29,66.9 v1(110.29,66.67) 110.29,64 110.54,63.75 110.92,63.75 111.17,64 111.17,65.09 111.43,65.35 111.84,65.35 112.78,64.41 113.98,64.41 114.23,64.15 114.23,63.49 113.98,63.24 v2(113.87,63.24) ; v2(102.77,26.19) 102.6,26.03 102.19,26.03 101.93,26.28 101.93,28.25 101.25,28.93 DM1.163
M_A_DQ<49>: length 65.5
  TOP w0.216: v2(103.91,26.28) 104.4,26.28 v1(104.82,25.86)
  L4 w0.216: v2(113.92,62.49) 113.92,50.9 104.08,41.07 104.08,32.63 104.08,32.22 104.11,32.2 104.11,26.48 v2(103.91,26.28)
  BOTTOM w0.102: CPU1.AW40 107.5,71.71 107.2,71.41 107.2,70.51 107.59,70.12 108.56,70.12
  BOTTOM w0.216: DM1.165 101.85,29.14 102.79,28.2 102.79,27.88 102.36,27.45 102.36,27.09 102.64,26.82 103,26.82 103.44,27.27 103.73,27.27 104.04,26.96 104.04,26.41 v2(103.91,26.28) ; 108.56,70.12 110.45,68.23 110.45,67.62 113.04,65.03 114.64,65.03 114.86,64.81 114.86,61.79 114.6,61.54 114.17,61.54 113.92,61.79 v2(113.92,62.49)
M_A_DQ<50>: length 64.4
  L4 w0.216: v2(107.59,26.97) 107.65,26.97 108.21,27.53 108.21,30.49 109.13,31.41 109.13,33.59 108.16,34.56 108.16,39.38 117.99,49.21 117.99,52.18 118.93,53.12 118.93,58.17 117.99,59.1 117.99,64.52 117.04,65.47 v2(116.79,65.47)
  BOTTOM w0.102: 110.53,71.53 110.31,71.75 110.31,72.47 109.58,73.2 CPU1.BA38
  BOTTOM w0.216: v2(116.79,65.47) 116.79,67.33 116.18,67.94 116.18,68.25 116.48,68.55 116.48,68.85 116.02,69.31 115.72,69.31 115.42,69.01 115.11,69.01 v1(114.08,70.04) 113.52,70.6 111.46,70.6 110.53,71.53 ; DM1.175 104.85,29.61 107.49,26.97 v2(107.59,26.97)
M_A_DQ<51>: length 64.2
  L4 w0.216: v2(107.59,28.24) 107.59,30.75 108.51,31.66 108.51,33.33 107.54,34.3 107.54,39.64 117.37,49.47 117.37,52.44 118.31,53.38 118.31,57.91 117.37,58.84 117.37,62.35 117.12,62.6 116.33,62.6 116.13,62.8 116.13,63.26 116.33,63.46 117.16,63.46 117.37,63.67 117.37,64.26 116.92,64.71 v2(116.79,64.71)
  BOTTOM w0.102: 111.41,71.23 111.29,71.23 110.64,71.87 110.64,72.43 109.66,73.4 108.79,73.4 108.44,73.75 CPU1.AY37
  BOTTOM w0.216: v2(116.79,64.71) 117.41,65.33 v1(117.41,67.53) 117.41,68.81 116.39,69.83 116.38,69.83 116.28,69.93 115.07,69.93 113.78,71.23 111.41,71.23 ; DM1.177 105.45,29.85 107.06,28.24 v2(107.59,28.24)
M_A_DQ<52>: length 60.1
  L4 w0.216: v2(101.55,24.22) 101.04,24.73 101.04,25.7 101.46,26.12 101.46,26.67 102.22,27.43 102.22,28.21 102.22,28.21 102.22,31.45 102.22,31.45 102.22,41.84 111.99,51.61 111.99,62.81 112.27,63.09 v2(112.52,63.09)
  BOTTOM w0.102: 108.07,69.14 107.71,69.14 106.53,70.32 106.53,70.93 106.4,71.06 CPU1.AU41
  BOTTOM w0.216: 108.07,69.14 108.09,69.14 109.05,68.19 109.05,64.79 108.43,64.18 v1(108.43,63.09) 108.43,62.76 108.76,62.43 111.45,62.43 112.12,63.09 v2(112.52,63.09) ; DM1.164 101.55,24.22 v2(101.55,24.22)
M_A_DQ<53>: length 60.5
  L4 w0.216: v2(112.65,62.37) 112.65,51.39 102.84,41.58 102.84,33.91 102.84,31.71 102.84,27.17 102.14,26.48 102.14,25.48 v2(102.74,24.88)
  BOTTOM w0.102: CPU1.AV40 106.95,72.05 106.65,71.75 106.65,71.47 106.73,71.39 106.73,70.41 107.7,69.44 108.28,69.44
  BOTTOM w0.216: DM1.166 102.15,24.63 102.4,24.88 v2(102.74,24.88) ; v2(112.65,62.37) 112.74,62.47 112.78,62.47 113.14,62.83 113.14,63.35 112.78,63.71 111.81,63.71 111.21,63.11 v1(110.31,63.11) 109.92,63.11 109.67,63.36 109.67,66.12 109.42,66.37 109.42,67.32 109.42,67.32 109.42,67.58 109.42,68.3 108.28,69.44
M_A_DQ<54>: length 60.5
  L4 w0.216: v2(105.74,25.65) 105.74,25.65 106.35,26.25 106.35,31.27 106.91,31.82 106.91,33.17 106.29,33.79 106.29,40.15 116.13,49.98 116.13,52.96 117.06,53.89 117.06,57.39 116.13,58.33 v2(116.13,61.13)
  BOTTOM w0.102: 109.5,71.37 109.5,71.75 109.03,72.21 108.64,72.21 CPU1.AY39
  BOTTOM w0.216: DM1.174 104.55,24.65 105.54,25.65 v2(105.74,25.65) ; v2(116.13,61.13) 115.53,61.73 115.53,66.83 v1(113.5,68.87) 113.12,69.24 111.62,69.24 109.5,71.37
M_A_DQ<55>: length 62.3
  L4 w0.216: v2(105.74,24.96) 105.8,25.02 106,25.02 106.97,25.99 106.97,31.01 107.53,31.57 107.53,32.92 107.53,32.92 107.53,33.43 106.92,34.05 106.92,39.89 116.75,49.73 116.75,52.7 117.68,53.63 117.68,57.65 116.75,58.59 116.75,61.35 v2(116.15,61.94)
  BOTTOM w0.102: 109.99,71.51 109.99,72.5 109.54,72.95 108.73,72.95 108.68,72.9 108.42,72.9 108.12,73.2 CPU1.AY38
  BOTTOM w0.216: v2(105.74,24.96) 105.15,24.37 DM1.176 ; v2(116.15,61.94) 116.15,67.09 v1(115.12,68.13) 113.26,69.98 111.52,69.98 109.99,71.51
M_A_DQ<56>: length 77.7
  TOP w0.216: v2(109.46,27.45) 109.14,27.45 v1(108.79,27.8)
  L4 w0.216: v2(111.4,72.86) 111.4,72.61 112.1,71.91 112.1,70.81 111.88,70.59 111.12,70.59 110.87,70.85 110.87,71.52 110.46,71.92 107.49,71.92 107.24,71.67 107.24,71.31 107.49,71.06 108,71.06 108.26,70.8 108.26,70.27 108.51,70.02 108.89,70.02 109.14,70.27 109.14,70.76 109.39,71.01 109.75,71.01 110.01,70.76 110.01,69.61 111.16,68.46 115.82,68.46 119.24,65.04 119.24,59.62 120.17,58.68 120.17,52.6 119.24,51.67 119.24,48.69 109.41,38.86 109.41,35.08 110.37,34.11 110.37,30.89 109.46,29.98 v2(109.46,27.45)
  BOTTOM w0.102: v2(111.4,72.86) 111.18,72.86 109.98,74.06 109.31,74.06 109.07,74.3 CPU1.BA36
  BOTTOM w0.216: DM1.181 106.65,29.94 109.14,27.45 v2(109.46,27.45)
M_A_DQ<57>: length 77.1
  L4 w0.216: v2(114.88,72.08) 114.22,72.08 113.97,71.82 113.97,70.58 114.22,70.33 114.75,70.33 115.01,70.58 115.01,70.88 115.26,71.14 115.64,71.14 115.9,70.88 115.9,70.58 116.15,70.33 116.7,70.33 122.04,64.99 122.04,47.68 116.02,41.66 115.71,41.66 115.43,41.94 115.12,41.94 114.82,41.64 114.82,41.33 115.1,41.05 115.1,40.74 114.8,40.44 114.49,40.44 114.21,40.72 113.9,40.72 113.6,40.41 113.6,40.11 114.64,39.07 114.64,38.75 114.35,38.46 114.03,38.46 112.99,39.5 112.68,39.5 112.24,39.06 112.24,38.4 112.49,38.14 113.1,38.14 113.36,37.89 113.36,37.51 113.1,37.25 112.49,37.25 112.24,37 112.24,33.68 112.66,33.26 112.66,32.21 112.24,31.79 112.24,30.12 111.34,29.22 111.34,27.58 110.87,27.11 v2(110.7,27.11)
  BOTTOM w0.102: 111.01,73.54 110.18,74.36 109.31,74.36 109.13,74.55 108.77,74.55 108.47,74.85 CPU1.AY35
  BOTTOM w0.216: v2(110.7,27.11) 110.49,27.11 108.68,28.92 108.4,28.92 107.25,30.08 DM1.183 ; v2(114.88,72.08) v1(114.09,72.08) 113.31,72.08 112.04,73.35 111.2,73.35 111.01,73.54
M_A_DQ<58>: length 77.6
  TOP w0.216: v1(112.95,26.13) v2(112.95,26.69)
  L4 w0.216: v2(112.95,26.69) 112.96,26.69 113.53,27.26 113.53,27.75 115.34,29.57 115.34,36.32 117.43,38.41 117.43,38.72 116.97,39.18 116.97,39.48 117.27,39.79 117.58,39.79 118.04,39.33 118.34,39.33 118.65,39.63 118.65,39.94 118.19,40.4 118.19,40.7 118.49,41.01 118.8,41.01 119.26,40.55 119.57,40.55 119.87,40.86 119.87,41.16 119.41,41.62 119.41,41.93 119.72,42.23 120.02,42.23 120.48,41.77 120.79,41.77 121.09,42.08 121.09,42.38 120.63,42.84 120.63,43.15 120.94,43.45 121.24,43.45 121.7,42.99 122.01,42.99 122.31,43.3 122.31,43.6 121.85,44.06 121.85,44.37 124.25,46.77 124.25,65.9 115.36,74.79 112.27,74.79 111.45,75.61 v2(111.45,76.03)
  BOTTOM w0.102: CPU1.BA32 110.33,76.5 110.8,76.03 v2(111.45,76.03)
  BOTTOM w0.216: DM1.191 109.65,29.77 110.42,29 110.79,29 112.43,27.36 112.43,27.21 112.92,26.71 112.93,26.71 v2(112.95,26.69)
M_A_DQ<59>: length 77.9
  TOP w0.216: v2(112.93,28.03) 112.68,28.03 v1(112.42,27.77)
  L4 w0.216: v2(112.93,28.03) 114.72,29.82 114.72,36.58 116.35,38.21 116.35,39.74 123.63,47.03 123.63,65.64 115.11,74.17 111.12,74.17 110.87,74.42 110.87,74.94 110.63,75.18 110.29,75.18 110.06,74.94 110.06,74.42 109.8,74.17 108.18,74.17 107.92,74.42 107.92,74.79 108.18,75.05 108.79,75.05 109.04,75.3 109.04,75.68 108.79,75.94 108.2,75.94 107.95,76.19 107.95,76.6 108.2,76.85 109.21,76.85 109.54,76.52 v2(110.99,76.52)
  BOTTOM w0.102: v2(110.99,76.52) 110.77,76.74 108.76,76.74 108.59,76.91 108.34,76.91 CPU1.AY31
  BOTTOM w0.216: DM1.193 110.25,30.05 110.67,29.63 111.08,29.63 112.68,28.03 v2(112.93,28.03)
M_A_DQ<60>: length 74.2
  TOP w0.216: v2(107.62,25.7) 107.46,25.7 v1(107.15,26.01)
  L4 w0.216: v2(111.41,71.82) 110.31,72.93 109,72.93 108.71,72.64 107.36,72.64 106.63,71.9 106.63,70.66 108.1,69.18 109.55,69.18 110.89,67.84 115.56,67.84 118.62,64.78 118.62,59.36 119.55,58.43 119.55,52.86 118.62,51.93 118.62,48.95 108.78,39.12 108.78,34.82 109.75,33.85 109.75,31.15 108.84,30.23 108.84,27.27 107.62,26.05 v2(107.62,25.7)
  BOTTOM w0.102: v2(111.41,71.82) 110.84,72.39 110.84,72.51 109.7,73.65 109,73.65 CPU1.BA37
  BOTTOM w0.216: v2(107.62,25.7) 107.34,25.7 106.35,24.71 DM1.180
M_A_DQ<61>: length 73.6
  TOP w0.216: v1(107.03,24.71) 107.34,25.01 v2(107.54,25.01)
  L4 w0.216: v2(107.54,25.01) 108.02,25.01 109.21,26.2 109.47,26.2 110.08,26.81 110.08,29.72 111,30.63 111,34.37 110.03,35.33 110.03,38.6 119.86,48.44 119.86,51.41 120.8,52.34 120.8,60.29 120.58,60.51 120.08,60.51 119.86,60.73 119.86,61.16 120.08,61.37 120.58,61.37 120.8,61.59 120.8,62.02 120.58,62.24 120.08,62.24 119.86,62.45 119.86,62.88 120.08,63.1 120.58,63.1 120.8,63.32 120.8,64.36 116.07,69.08 111.33,69.08 111.07,69.34 111.07,69.71 111.33,69.97 112.47,69.97 112.72,70.22 v2(112.72,71.92)
  BOTTOM w0.102: 111.34,72.37 111.28,72.37 109.8,73.85 109.22,73.85 109.03,74.05 108.77,74.05 108.72,74 108.39,74 108.09,74.3 CPU1.AY36
  BOTTOM w0.216: v2(107.54,25.01) 106.95,24.42 DM1.182 ; v2(112.72,71.92) 112.37,71.92 111.92,72.37 111.34,72.37
M_A_DQ<62>: length 73.8
  TOP w0.216: v2(111.38,25.42) 111.4,25.44 111.81,25.44 111.82,25.45 v1(111.93,25.45)
  L4 w0.216: v2(112.62,75.38) 112.65,75.41 115.62,75.41 124.88,66.16 124.88,46.51 124.11,45.74 124.11,45.44 124.57,44.98 124.57,44.67 124.27,44.37 123.96,44.37 123.5,44.83 123.19,44.83 122.89,44.52 122.89,44.22 123.35,43.76 123.35,43.45 115.96,36.06 115.96,29.31 114.15,27.5 114.15,27 113.2,26.05 112.77,26.05 112.14,25.42 v2(111.38,25.42)
  BOTTOM w0.102: CPU1.BA33 110.22,75.95 110.97,75.21 111.24,75.21
  BOTTOM w0.216: v2(112.62,75.38) 112.45,75.21 111.24,75.21 ; v2(111.38,25.42) 111.27,25.53 110.54,25.53 109.95,24.93 DM1.192
M_A_DQ<63>: length 74.5
  TOP w0.216: v2(110.94,24.2) 110.94,23.67 v1(110.97,23.64)
  L4 w0.216: v2(112.14,76.01) 112.16,76.03 115.88,76.03 125.5,66.41 125.5,44.72 116.58,35.81 116.58,26.66 115.35,25.43 113.31,25.43 112.08,24.2 v2(110.94,24.2)
  BOTTOM w0.102: CPU1.AY32 108.08,76.5 108.38,76.2 108.68,76.2 108.73,76.25 110.21,76.25 110.86,75.6 111.72,75.6 v2(112.14,76.01)
  BOTTOM w0.216: v2(110.94,24.2) 110.55,23.8 DM1.194
M_A_DQS_DN<0>: length 77.7
  TOP w0.14: v2(52.14,25.09) v1(51.59,25.09)
  L4 w0.127: v2(83.15,74.24) 83.46,73.92 83.46,73.58 83.8,73.25 84.23,73.25 84.43,73.05 84.43,72.63 84.23,72.43 76.76,72.43 72.13,67.81 72.13,66.52 50.65,45.03 50.65,26.03 51.16,25.52 51.71,25.52 v2(52.14,25.09)
  BOTTOM w0.14: v2(83.15,74.24) 83.4,74.49 83.4,74.76 84.51,75.87 86.22,75.87 CPU1.A33 ; v2(52.14,25.09) 52.14,25.21 52.46,25.53 52.73,25.53 53.09,25.17 53.09,23.87 52.95,23.73 DM1.10
M_A_DQS_DN<1>: length 68.8
  L4 w0.127: v2(80.97,65.02) 81.07,64.91 81.07,62.71 80.63,62.26 80.45,62.26 79.83,62.87 79.46,62.87 79.06,62.47 79.06,62.1 79.67,61.49 79.67,61.31 79.4,61.04 79.22,61.04 78.61,61.65 78.24,61.65 77.84,61.24 77.84,60.88 78.45,60.26 78.45,60.08 78.18,59.82 78,59.82 77.39,60.43 77.02,60.43 76.62,60.02 76.62,59.65 77.23,59.04 77.23,58.86 76.96,58.59 76.78,58.59 76.17,59.21 75.8,59.21 75.39,58.8 75.39,58.43 76.01,57.82 76.01,57.64 75.74,57.37 75.56,57.37 75.24,57.69 74.9,57.69 74.46,57.25 74.46,56.92 74.78,56.6 74.78,56.42 58.77,40.4 58.77,29.86 58.77,29.86 58.77,28.75 v2(59.38,28.14)
  BOTTOM w0.14: DM1.27 58.05,28.67 58.58,28.14 v2(59.38,28.14) ; v2(80.97,65.02) 80.99,65.03 80.99,65.85 82.49,67.35 ; CPU1.A40 86.3,71.65 85.81,71.16 85.81,70.67 82.49,67.35 ; 82.49,67.35 v1(82.4,67.45)
M_A_DQS_DN<2>: length 65.9
  TOP w0.14: v2(88.78,64.34) 88.94,64.34 v1(89.29,64.7)
  L4 w0.127: v2(88.78,64.34) 88.79,64.33 89.38,64.33 89.74,63.97 89.74,62.76 89.4,62.43 89.09,62.43 89,62.33 89,60.99 78.36,50.35 78.36,47.6 68.58,37.82 68.58,37.64 69.02,37.2 69.02,36.79 68.66,36.42 68.25,36.42 67.81,36.87 67.63,36.87 67.36,36.6 67.36,36.42 67.79,35.99 67.79,35.58 67.42,35.21 67.02,35.21 66.58,35.65 66.4,35.65 65.96,35.2 65.96,29.28 66.21,29.03 66.21,27.96 v2(65.61,27.35)
  BOTTOM w0.102: CPU1.H40 90.45,72.07 90.15,71.76 90.15,71.47 90.25,71.38 90.25,71.37 90.25,70.8 90.41,70.64 90.41,70 90.16,69.75 90.16,69.66
  BOTTOM w0.14: v2(65.61,27.35) 64.47,27.35 63.45,28.37 DM1.45 ; 90.16,69.66 90.16,65.72 v2(88.78,64.34)
M_A_DQS_DN<3>: length 65.1
  TOP w0.14: v2(94.41,69.33) 94.44,69.36 v1(94.44,69.88)
  L4 w0.127: v2(69.54,25.47) 69.91,25.47 70.82,26.38 72.51,26.38 72.9,26.76 72.9,30.19 74.43,31.72 76.15,31.72 84.7,40.27 84.7,47.73 95.37,58.4 95.37,63.77 95.98,64.38 95.98,67.3 94.61,68.67 94.61,69.13 v2(94.41,69.33)
  BOTTOM w0.102: CPU1.P40 93.45,71.73 93.45,71.47 93.59,71.33 93.59,70.3 94.41,69.48 v2(94.41,69.33)
  BOTTOM w0.14: v2(69.54,25.47) 69.37,25.29 68.98,25.29 68.68,24.99 68.68,23.82 68.55,23.69 DM1.62
M_A_DQS_DN<4>: length 63.2
  TOP w0.14: v1(92.33,28.77) 92.05,28.49 v2(91.84,28.49)
  L4 w0.127: v2(100.96,64.4) 101.12,64.56 101.55,64.56 101.65,64.46 101.65,63.19 102.03,62.82 102.03,55.77 91.27,45.01 91.27,36.25 91.14,36.12 90.38,36.12 90.14,35.89 90.14,35.27 90.38,35.03 91.18,35.03 91.27,34.95 91.27,34.48 91.18,34.4 90.35,34.4 90.14,34.19 90.14,33.51 90.35,33.3 91.18,33.3 91.27,33.22 91.27,30.95 92.25,29.96 92.25,28.62 92.12,28.49 v2(91.84,28.49)
  BOTTOM w0.102: CPU1.AH40 101.45,72.06 101.15,71.76 101.15,71.47 101.25,71.38 101.25,70.72 101.45,70.52 101.45,69.63 101.21,69.39 101.19,69.39
  BOTTOM w0.14: v2(91.84,28.49) 92.05,28.28 92.49,28.28 92.73,28.03 92.73,26.77 92.86,26.65 93.04,26.65 93.66,27.27 93.66,28.47 93.43,28.69 93.24,28.69 93.03,28.91 93.03,29.6 92.85,29.77 DM1.135 ; v2(100.96,64.4) 100.96,64.41 100.53,64.84 100.53,65.9 100.7,66.07 100.7,66.41 100.53,66.58 100.53,67.15 100.72,67.34 100.72,67.81 100.53,68 100.53,68.74 101.19,69.39
M_A_DQS_DN<5>: length 56.8
  TOP w0.14: v1(107.95,63.72) 107.38,63.72 v2(107.36,63.74)
  L4 w0.127: v2(97.71,25.65) 97.71,26.76 98.2,27.25 98.2,28.22 98.82,28.84 98.82,43.28 108.59,53.05 108.59,62.75 107.66,63.68 107.6,63.74 v2(107.36,63.74)
  BOTTOM w0.102: CPU1.AP40 104.75,72.03 104.45,71.73 104.45,71.43 104.55,71.33 104.55,69.56 104.57,69.54
  BOTTOM w0.14: v2(97.71,25.65) 97.8,25.56 97.8,24.05 97.95,23.9 DM1.152 ; v2(107.36,63.74) 107.36,63.74 106.42,64.67 106.42,67.4 105.4,68.43 105.4,68.71 104.9,69.21 104.57,69.54
M_A_DQS_DN<6>: length 64.6
  TOP w0.14: v1(105.28,26.99) 105.32,27.03 v2(105.84,27.03)
  L4 w0.127: v2(105.84,27.03) 105.41,27.46 105.41,31.61 105.74,31.94 105.74,33.06 105.39,33.41 105.39,40.53 115.22,50.36 115.22,54.21 115.48,54.47 116.03,54.47 116.15,54.59 116.15,54.99 116.03,55.11 115.48,55.11 115.22,55.37 115.22,55.94 115.48,56.2 116.03,56.2 116.15,56.32 116.15,56.71 116.03,56.83 115.48,56.83 115.22,57.1 115.22,63.64 115.88,64.3 115.88,66.13 115.62,66.38 v2(114.38,66.38)
  BOTTOM w0.14: v2(105.84,27.03) 105.15,27.03 104.55,27.63 104.55,28.03 104.87,28.34 104.87,28.52 104.55,28.84 104.37,28.84 104.05,28.52 103.66,28.52 103.05,29.13 DM1.169 ; CPU1.AY41 108.67,71.25 112.05,67.87 112.44,67.87 112.63,68.05 112.81,68.05 113.12,67.74 113.12,67.56 112.94,67.38 112.94,66.98 113.54,66.38 v2(114.38,66.38)
M_A_DQS_DN<7>: length 73
  TOP w0.14: v1(108.91,26.1) 109.34,25.67 v2(109.34,25.52)
  L4 w0.127: v2(114.5,72.84) 114.7,73.04 114.94,73.04 122.72,65.26 122.72,47.4 115.44,40.12 115.44,38.58 113.81,36.96 113.81,36.61 113.71,36.51 113.25,36.51 112.93,36.19 112.93,35.73 113.25,35.41 113.68,35.41 113.81,35.29 113.81,34.91 113.68,34.78 113.2,34.78 112.92,34.5 112.92,33.96 113.2,33.69 113.68,33.69 113.81,33.56 113.81,31.94 113.69,31.82 113.27,31.82 112.93,31.48 112.93,30.99 113.27,30.65 113.6,30.65 113.79,30.46 113.79,30.18 113.6,29.99 113.08,29.99 112.02,28.93 112.02,27.3 109.93,25.21 109.66,25.21 v2(109.34,25.52)
  BOTTOM w0.102: 110.12,75.38 109.99,75.51 109.55,75.51 109.48,75.43 108.58,75.43 CPU1.BA34
  BOTTOM w0.14: 110.12,75.38 111.08,74.41 113.22,74.41 113.97,73.67 113.97,73.37 114.5,72.84 v2(114.5,72.84) ; v2(109.34,25.52) 109.32,25.52 108.87,25.07 108.87,24.94 108.51,24.58 108.51,23.88 108.15,23.52 DM1.186
M_A_DQS_DP<0>: length 77.7
  TOP w0.14: v1(52.7,25.88) 52.68,25.85 v2(52.14,25.85)
  L4 w0.127: v2(83.78,74.24) 83.69,74.14 83.69,73.68 83.89,73.47 84.33,73.47 84.66,73.14 84.66,72.53 84.33,72.2 76.85,72.2 72.36,67.72 72.36,66.43 50.87,44.94 50.87,26.13 51.25,25.75 52.04,25.75 v2(52.14,25.85)
  BOTTOM w0.102: CPU1.B33 86.75,75.95 86.43,75.64
  BOTTOM w0.14: v2(52.14,25.85) 52.22,25.77 52.83,25.77 53.33,25.27 53.33,23.91 53.55,23.69 DM1.12 ; 86.43,75.64 86.42,75.63 84.61,75.63 83.64,74.66 83.64,74.38 v2(83.78,74.24)
M_A_DQS_DP<1>: length 69.4
  TOP w0.14: v1(58.75,28.8) 58.77,28.77 v2(59.38,28.77)
  L4 w0.127: v2(59.38,28.77) 59.07,28.77 59,28.85 59,29.84 59,40.31 75.01,56.32 75.01,56.69 74.69,57.02 74.69,57.16 75,57.46 75.14,57.46 75.46,57.14 75.83,57.14 76.24,57.55 76.24,57.92 75.62,58.53 75.62,58.71 75.89,58.98 76.07,58.98 76.68,58.36 77.05,58.36 77.46,58.77 77.46,59.14 76.85,59.75 76.85,59.93 77.12,60.2 77.29,60.2 77.91,59.59 78.28,59.59 78.68,59.99 78.68,60.36 78.07,60.97 78.07,61.15 78.34,61.42 78.52,61.42 79.13,60.81 79.5,60.81 79.9,61.21 79.9,61.58 79.29,62.19 79.29,62.37 79.56,62.64 79.74,62.64 80.35,62.03 80.72,62.03 81.3,62.61 81.3,64.71 v2(81.63,65.04)
  BOTTOM w0.14: v2(59.38,28.77) 59.2,28.59 59.2,28.59 58.99,28.38 58.68,28.38 58.29,28.77 58.29,29.66 58.42,29.79 58.53,29.79 58.66,29.91 58.66,30.91 DM1.29 ; v2(81.63,65.04) 81.61,65.04 81.23,65.42 81.23,65.75 86.06,70.57 86.06,71.06 86.94,71.95 CPU1.B40
M_A_DQS_DP<2>: length 66
  TOP w0.14: v1(89.48,63.49) v2(88.8,63.49)
  L4 w0.127: v2(65.61,27.99) 65.69,27.91 65.84,27.91 65.98,28.05 65.98,28.94 65.73,29.19 65.73,35.29 66.31,35.87 66.68,35.87 67.11,35.44 67.33,35.44 67.56,35.68 67.56,35.89 67.13,36.32 67.13,36.69 67.53,37.1 67.9,37.1 68.35,36.65 68.56,36.65 68.8,36.89 68.8,37.1 68.35,37.55 68.35,37.92 78.13,47.7 78.13,50.45 88.77,61.08 88.77,62.43 89,62.65 89.31,62.65 89.51,62.86 89.51,63.88 89.31,64.08 89.16,64.08 88.8,63.72 v2(88.8,63.49)
  BOTTOM w0.102: CPU1.H41 90.46,71.59 90.46,70.88 90.62,70.72 90.62,69.92 90.4,69.7 90.4,69.56
  BOTTOM w0.14: DM1.47 64.05,30.15 63.69,29.79 63.69,28.47 64.57,27.6 65,27.6 65.12,27.72 65.12,27.86 65.25,27.99 v2(65.61,27.99) ; 90.4,69.56 90.4,65.62 89.3,64.52 89.3,63.47 89.18,63.34 88.92,63.34 88.8,63.47 v2(88.8,63.49)
M_A_DQS_DP<3>: length 65.2
  TOP w0.14: v1(68.91,24.83) v2(69.57,24.83)
  L4 w0.127: v2(95.05,69.33) 94.84,69.12 94.84,68.77 96.21,67.4 96.21,64.29 95.6,63.68 95.6,58.31 84.93,47.63 84.93,40.18 76.24,31.49 74.52,31.49 73.12,30.09 73.12,26.67 72.61,26.15 70.91,26.15 70,25.24 70,24.96 69.88,24.83 v2(69.57,24.83)
  BOTTOM w0.102: v2(95.05,69.33) 95.05,69.59 94.87,69.77 94.41,69.77 93.79,70.38 93.79,71.56 CPU1.P41
  BOTTOM w0.14: DM1.64 69.15,23.7 68.92,23.93 68.92,24.89 69.08,25.05 69.35,25.05 v2(69.57,24.83)
M_A_DQS_DP<4>: length 63.1
  TOP w0.14: v2(91.84,27.73) 92.05,27.73 v1(92.33,27.45)
  L4 w0.127: v2(101.06,65.03) 101.3,64.79 101.65,64.79 101.88,64.55 101.88,63.28 102.25,62.91 102.25,55.67 91.49,44.91 91.49,36.16 91.23,35.89 90.47,35.89 90.37,35.79 90.37,35.36 90.47,35.26 91.28,35.26 91.49,35.04 91.49,34.38 91.28,34.17 90.45,34.17 90.37,34.09 90.37,33.61 90.45,33.53 91.27,33.53 91.49,33.31 91.49,31.04 92.48,30.06 92.48,28.37 v2(91.84,27.73)
  BOTTOM w0.102: 101.36,69.22 101.65,69.51 101.65,70.6 101.45,70.8 CPU1.AH41
  BOTTOM w0.14: DM1.137 93.45,29.82 93.27,29.63 93.27,29.01 93.34,28.94 93.53,28.94 93.9,28.57 93.9,27.17 93.14,26.41 92.76,26.41 92.49,26.67 92.49,27.93 92.39,28.04 91.95,28.04 91.84,27.93 v2(91.84,27.73) ; v2(101.06,65.03) 100.77,65.32 100.77,65.8 100.94,65.97 100.94,66.51 100.77,66.68 100.77,67.05 100.96,67.24 100.96,67.91 100.77,68.1 100.77,68.64 101.36,69.22
M_A_DQS_DP<5>: length 56.7
  TOP w0.14: v1(106.8,64.38) 107.35,64.38 v2(107.36,64.37)
  L4 w0.127: v2(107.36,64.37) 107.68,64.37 107.82,64.23 107.82,63.84 108.82,62.84 108.82,52.95 99.05,43.18 99.05,28.75 98.91,28.61 98.43,28.13 98.43,27.15 97.94,26.67 97.94,26.05 98.31,25.67 v2(98.4,25.67)
  BOTTOM w0.102: 104.77,69.7 104.75,69.72 104.75,71.33 CPU1.AP41
  BOTTOM w0.14: v2(98.4,25.67) 98.37,25.67 98.04,25.34 98.04,24.15 98.19,23.99 98.42,23.99 98.55,23.87 DM1.154 ; 104.77,69.7 104.77,69.68 105.64,68.81 105.64,68.53 106.67,67.5 106.67,64.78 107.08,64.36 107.35,64.36 v2(107.36,64.37)
M_A_DQS_DP<6>: length 64.6
  TOP w0.14: v2(105.85,27.66) 106.19,27.66 v1(106.38,27.85)
  L4 w0.127: v2(105.85,27.66) 105.64,27.88 105.64,31.52 105.97,31.85 105.97,33.15 105.61,33.51 105.61,40.43 115.45,50.27 115.45,54.12 115.57,54.24 116.13,54.24 116.38,54.5 116.38,55.08 116.13,55.34 115.57,55.34 115.45,55.46 115.45,55.84 115.57,55.97 116.13,55.97 116.38,56.23 116.38,56.81 116.13,57.06 115.57,57.06 115.45,57.19 115.45,63.54 116.11,64.2 116.11,66.22 115.72,66.61 114.86,66.61 114.73,66.74 114.73,66.92 114.64,67.02 v2(114.38,67.02)
  BOTTOM w0.14: CPU1.BA40 108.86,71.85 108.74,71.72 108.74,71.53 112.15,68.11 112.34,68.11 112.53,68.3 112.91,68.3 113.36,67.84 113.36,67.46 113.18,67.28 113.18,67.08 113.64,66.62 113.98,66.62 v2(114.38,67.02) ; v2(105.85,27.66) 105.83,27.66 105.44,27.27 105.25,27.27 104.79,27.73 104.79,27.93 105.11,28.24 105.11,28.62 104.65,29.08 104.27,29.08 103.95,28.76 103.76,28.76 103.29,29.23 103.29,29.71 103.65,30.07 DM1.171
M_A_DQS_DP<7>: length 73
  TOP w0.14: v1(108.61,24.73) 108.76,24.88 v2(109.32,24.88)
  L4 w0.127: v2(109.32,24.88) 109.42,24.98 110.02,24.98 112.25,27.2 112.25,28.83 113.17,29.76 113.69,29.76 114.02,30.09 114.02,30.55 113.69,30.88 113.36,30.88 113.15,31.09 113.15,31.38 113.36,31.59 113.78,31.59 114.04,31.84 114.04,33.65 113.78,33.91 113.29,33.91 113.15,34.06 113.15,34.41 113.29,34.55 113.78,34.55 114.04,34.81 114.04,35.38 113.78,35.64 113.34,35.64 113.15,35.83 113.15,36.09 113.34,36.28 113.8,36.28 114.04,36.51 114.04,36.86 115.67,38.49 115.67,40.02 122.95,47.31 122.95,65.36 115.04,73.27 114.7,73.27 v2(114.5,73.47)
  BOTTOM w0.102: CPU1.AY33 108.43,75.95 108.74,75.64 109.39,75.64 109.47,75.71 110.13,75.71 110.22,75.62
  BOTTOM w0.14: 110.22,75.62 111.18,74.66 113.32,74.66 v2(114.5,73.47) ; DM1.188 108.75,24.48 109.15,24.88 v2(109.32,24.88)
M_A_EVENT#: length 71.1
  TOP w0.114: R504.2 99.17,76.01 v2(99.31,76.16) ; v1(113.61,24.3) v2(113.61,24.91)
  L3 w0.102: v2(113.61,24.91) 114.03,25.33 114.03,27.99 114.25,28.2 114.25,36.77 114.91,37.43 114.91,40.53 114.12,41.32 114.12,61.76 114.35,61.99 114.35,64.3 113.56,65.09 113.56,73.7 113.36,73.91 112.44,73.91 110.82,75.53 108.05,75.53 107.67,75.91 106.86,75.91 106.23,76.54 101.67,76.54 101.65,76.52 101.25,76.52 101.19,76.59 99.75,76.59 v2(99.31,76.16)
  BOTTOM w0.114: v2(113.61,24.91) 112.87,24.91 111.92,23.96 111.92,23.75 111.75,23.58 DM1.198 ; v2(99.31,76.16) 99.72,75.75 CPU1.AE34
M_A_RAS#: length 62.4
  TOP w0.216: v1(86.26,24.33) v2(85.67,24.33)
  L3 w0.102: 103.2,71.57 103.12,71.64 103.12,73.33 102.46,73.99 v2(102.46,74.56)
  L3 w0.216: v2(85.67,24.33) 85.23,24.77 85.18,24.81 85.18,26.32 86.16,27.3 86.16,27.79 87.18,28.81 87.18,32.97 87.87,33.66 87.87,34.55 104.47,51.15 104.47,64.13 104.16,64.43 104.16,65.57 104.37,65.79 104.37,69.11 103.75,69.73 103.75,71.02 103.2,71.57
  BOTTOM w0.216: v2(102.46,74.56) 102.41,74.56 CPU1.AJ37 ; DM1.110 85.35,24 v2(85.67,24.33)
M_A_WE#: length 63.2
  TOP w0.216: v1(87.45,28.26) v2(87.45,27.63)
  L3 w0.102: 104.21,71.82 104.21,71.83 104.21,73.2 103.12,74.28 103.12,74.86 v2(103.6,75.33)
  L3 w0.216: v2(87.45,27.63) 87.45,27.61 88.24,28.39 88.24,30.85 89.13,31.74 89.13,34.1 105.74,50.72 105.74,64.13 106.27,64.66 106.27,67.61 106.55,67.89 106.55,69.23 106.3,69.49 105.19,69.49 104.97,69.71 104.97,71.07 104.21,71.82
  BOTTOM w0.216: CPU1.AL35 103.22,74.95 v2(103.6,75.33) ; v2(87.45,27.63) 87.2,27.63 86.25,28.57 DM1.113
M_ANALOGIN: length 1.3
  TOP w0.102: v2(93.82,76.92) 94.22,77.32 TP418.1
  BOTTOM w0.102: CPU1.R32 93.93,76.92 v2(93.82,76.92)
M_ANALOGOUT: length 1.4
  TOP w0.102: TP420.1 93.16,76.57 v2(92.76,76.97)
  BOTTOM w0.102: v2(92.76,76.97) 92.78,76.97 CPU1.N32
M_B_DIM0_CKE0: length 62.7
  TOP w0.216: v1(72.84,29.66) 72.97,29.79 v2(73.57,29.79)
  L3 w0.102: v2(91.52,76.03) 90.91,75.42 90.91,72.88 90.6,72.57 90.35,72.57
  L3 w0.216: v2(73.57,29.79) 73.52,29.79 71.91,31.4 71.91,43.81 72.18,44.09 72.18,45.97 72.57,46.35 72.88,46.35 73.11,46.13 73.41,46.13 73.72,46.43 73.72,46.74 73.49,46.96 73.49,47.27 73.79,47.58 74.1,47.58 74.33,47.35 74.63,47.35 74.94,47.65 74.94,47.96 74.71,48.19 74.71,48.49 85.28,59.06 85.28,60.26 85.06,60.47 84.91,60.47 84.68,60.7 84.68,61.11 84.91,61.34 85.06,61.34 85.28,61.55 85.28,61.99 85.06,62.2 84.72,62.2 84.5,62.42 84.5,67.34 86.92,69.75 86.92,70.63 88.86,72.57 90.35,72.57
  BOTTOM w0.216: v2(73.57,29.79) 73.84,29.79 74.25,30.2 DM1.73 ; v2(91.52,76.03) 91.82,76.03 CPU1.L34
M_B_DIM0_CKE1: length 62.2
  TOP w0.216: v2(74.02,23.73) 73.82,23.73 v1(73.53,24.02)
  L3 w0.216: v2(90.45,73.75) 89.67,72.97 88.72,72.97 83.87,68.11 83.87,58.56 71.66,46.36 71.66,44.38 71.3,44.01 71.3,30.95 72.71,29.54 72.71,25.04 73.99,23.76 73.99,23.76 v2(74.02,23.73)
  BOTTOM w0.216: DM1.74 74.55,23.2 v2(74.02,23.73) ; CPU1.J38 90.6,73.75 v2(90.45,73.75)
M_B_DIM0_CLK_DDR0: length 68.3
  TOP w0.203: v2(83.61,28.13) 84.12,28.13 v1(84.17,28.08)
  L3 w0.102: 98.57,72.97 98.58,72.98 98.58,74.79 98.44,74.93 98.44,75.1 v2(98.2,75.33)
  L3 w0.178: 98.57,72.97 98.57,72.88 98.89,72.56 98.89,70 99.9,68.99 99.9,62.94 99.72,62.76 99.24,62.76 98.91,62.43 98.91,61.6 99.24,61.27 99.51,61.27 99.67,61.11 99.67,60.17 99.51,60.02 98.73,60.02 98.4,59.69 98.4,58.85 98.73,58.52 99.72,58.52 100.25,57.99 100.25,54.68 95.37,49.79 95.37,47.58 94.74,46.96 94.49,46.96 93.75,47.7 93.24,47.7 92.69,47.14 92.69,46.64 93.43,45.9 93.43,45.64 93.05,45.27 92.8,45.27 92.06,46.01 91.55,46.01 91,45.45 91,44.95 91.74,44.21 91.74,43.95 83.85,36.07 83.85,31.49 83.19,30.83 83.19,28.56 83.61,28.14 v2(83.61,28.13)
  BOTTOM w0.203: v2(98.2,75.33) 98.58,74.95 CPU1.AC35 ; v2(83.61,28.13) 83.61,28.14 83.39,28.14 82.65,28.87 DM1.101
M_B_DIM0_CLK_DDR1: length 64.1
  TOP w0.203: v2(82.36,25.05) 82.36,25.01 82.78,24.59 82.78,24.57 v1(82.78,24.56)
  L3 w0.102: 97.37,74.62 97.37,74.67 97.56,74.86 97.56,75.51 97.44,75.63 97.18,75.63 97.05,75.51 v2(97.05,75.35)
  L3 w0.178: v2(82.36,25.05) 82.34,25.05 81.6,25.79 81.6,27.2 82.29,27.9 82.29,31.84 82.66,32.21 82.66,36.68 89.48,43.5 89.48,45.71 97.1,53.33 97.1,62.32 97.91,63.14 97.91,64.28 98.85,65.22 98.85,68.43 97.49,69.79 97.49,73.17 97.37,73.29 97.37,74.62
  BOTTOM w0.203: DM1.102 82.95,23.86 83.09,23.99 83.09,25.01 82.88,25.21 82.5,25.21 82.36,25.08 v2(82.36,25.05) ; v2(97.05,75.35) 97.05,75.47 97.33,75.75 CPU1.AA34
M_B_DIM0_CLK_DDR#0: length 68.4
  TOP w0.203: v1(83.04,28.75) 83.05,28.75 83.06,28.74 83.64,28.74 v2(83.66,28.77)
  L3 w0.102: v2(99.23,75.35) 99.23,75.56 99.1,75.68 98.77,75.68 98.64,75.56 98.64,75.01 98.79,74.87 98.79,73.18 98.87,73.09 98.87,73.02
  L3 w0.178: v2(83.66,28.77) 83.67,28.77 83.67,28.77 83.57,28.77 83.49,28.85 83.49,30.7 84.15,31.36 84.15,35.94 92.04,43.83 92.04,44.33 91.3,45.07 91.3,45.32 91.68,45.7 91.93,45.7 92.67,44.96 93.18,44.96 93.73,45.52 93.73,46.02 92.99,46.76 92.99,47.01 93.37,47.39 93.62,47.39 94.36,46.65 94.87,46.65 95.67,47.46 95.67,49.67 100.56,54.55 100.56,58.12 99.85,58.83 98.85,58.83 98.7,58.98 98.7,59.56 98.85,59.72 99.64,59.72 99.97,60.05 99.97,61.24 99.64,61.57 99.36,61.57 99.21,61.72 99.21,62.31 99.36,62.46 99.85,62.46 100.2,62.82 100.2,69.12 99.2,70.13 99.2,72.69 98.87,73.01 98.87,73.02
  BOTTOM w0.203: DM1.103 83.25,29.88 82.98,29.61 82.98,29.01 83.24,28.74 83.64,28.74 v2(83.66,28.77) ; v2(99.23,75.35) 98.95,75.35 98.7,75.6 CPU1.AC34
M_B_DIM0_CLK_DDR#1: length 64
  TOP w0.203: v1(81.81,25.67) 81.82,25.68 v2(82.37,25.68)
  L3 w0.102: 97.68,74.62 97.68,74.69 97.77,74.78 97.77,75.59 97.52,75.84 97.36,75.84 v2(97.05,76.15)
  L3 w0.178: 97.68,74.62 97.68,73.41 97.8,73.29 97.8,69.92 99.16,68.55 99.16,65.09 98.22,64.15 98.22,63.01 97.41,62.2 97.41,53.21 89.79,45.59 89.79,43.38 82.96,36.55 82.96,32.08 82.6,31.72 82.6,27.77 81.9,27.07 81.9,25.92 82.14,25.68 v2(82.37,25.68)
  BOTTOM w0.203: DM1.104 83.55,23.86 83.42,23.99 83.42,25.14 83.02,25.54 82.51,25.54 v2(82.37,25.68) ; CPU1.AA32 97.2,76.15 v2(97.05,76.15)
M_B_DIM0_CS#0: length 63.9
  TOP w0.216: v1(85.8,26.27) 85.78,26.25 v2(85.78,25.71)
  L3 w0.102: v2(102.54,75.37) 102.9,75.02 102.9,73.84 103.33,73.41 103.33,72.12 103.79,71.66
  L3 w0.216: v2(85.78,25.71) 86.84,26.77 86.84,27.73 87.7,28.6 87.7,31.92 88.52,32.73 88.52,34.46 105.1,51.05 105.1,64.2 105.61,64.71 105.61,68.5 104.47,69.64 104.47,70.98 103.79,71.66
  BOTTOM w0.216: DM1.114 86.55,23.68 86.72,23.85 86.72,24.8 85.9,25.63 85.87,25.63 v2(85.78,25.71) ; CPU1.AJ34 102.16,75.75 v2(102.54,75.37)
M_B_DIM0_CS#1: length 62.9
  TOP w0.216: v1(90.36,29.33) 90.36,29.29 89.84,28.77 v2(89.79,28.77)
  L3 w0.216: v2(89.79,28.77) 89.93,28.92 89.97,28.92 91.79,30.74 91.79,33.67 109.8,51.68 109.8,62.82 109.59,63.03 109.15,63.03 108.94,63.25 108.94,63.68 109.15,63.9 109.59,63.9 109.8,64.11 109.8,64.63 109.5,64.94 109.5,68.43 109.28,68.65 108.66,68.65 108.43,68.88 108.43,69.33 108.66,69.56 109.27,69.56 109.5,69.79 109.5,70.05 108.05,71.49 107.39,71.49 106.42,72.47 105.69,72.47 105.4,72.75 105.4,73.18 v2(105.83,73.6)
  BOTTOM w0.216: DM1.121 88.65,29.83 89.71,28.77 v2(89.79,28.77) ; CPU1.AR38 105.55,73.6 v2(105.83,73.6)
M_B_DIM0_ODT0: length 62.6
  TOP w0.216: v1(87.78,25.72) v2(88.34,25.72)
  L3 w0.216: v2(104.74,73.86) 104.74,72.89 107.88,69.74 107.88,64.83 108.25,64.46 108.25,50.97 90.88,33.6 90.88,31.23 89.3,29.65 89.3,27.95 88.92,27.58 88.92,26.31 v2(88.34,25.72)
  BOTTOM w0.216: DM1.116 87.15,23.54 87.24,23.63 87.24,24.63 88.12,25.5 88.12,25.5 v2(88.34,25.72) ; CPU1.AN38 104.45,73.6 104.48,73.6 v2(104.74,73.86)
M_B_DIM0_ODT1: length 64.7
  TOP w0.216: v2(88.35,24.19) 88.34,24.17 87.93,24.17 87.93,24.17 v1(87.79,24.17)
  L3 w0.216: v2(106.82,73.75) 106.83,73.74 107.42,73.74 111.02,70.15 111.02,51.1 93.14,33.22 93.14,30.4 92.78,30.04 92.78,26.79 92.25,26.26 90.5,26.26 88.43,24.19 v2(88.35,24.19)
  BOTTOM w0.216: DM1.120 v2(88.35,24.19) ; v2(106.82,73.75) 106.42,73.35 CPU1.AU38
M_ZVDDIO: length 5.2
  TOP w0.203: v2(98.32,70.06) 99.1,70.06 100.02,70.98 v1(100.02,71.24) R503.2
  BOTTOM w0.203: v2(98.32,70.06) 99.05,70.8 99.05,71.4 CPU1.AD41
MAA0: length 57.3
  TOP w0.14: VRAM3.N3 175.59,146.74 174.99,146.14 174.99,145.05 v2(174.72,144.77) ; v2(160.69,145.92) 160.69,145.91 160.77,145.82 160.77,144.99 160.97,144.79 160.97,144.4 160.72,144.15 160.71,144.15 160.37,143.81 160.37,143.77 VRAM1.N3
  TOP w0.178: 163.24,130.85 163.07,130.68 163.07,128.21 163.2,128.08 163.61,128.08 163.73,127.95 163.73,127.26 164.34,126.66 164.34,126.1 164.12,125.89 164.12,125.45 164.34,125.24 164.34,124.92 163.95,124.53 163.95,124.01 164.22,123.73 164.22,123.37 164.01,123.15 164.01,122.9 164.67,122.24 v2(165.05,122.24)
  TOP w0.279: v2(167.49,138.77) 166.88,138.15 v1(166.88,137.76) 166.88,137.14 166.72,136.99 166.72,136.16 166.55,135.98 166.09,135.98 165.71,135.98 163.67,133.95 163.67,133.26 163.24,132.83 163.24,132.25 163.52,131.97 163.96,131.97 164.24,131.69 164.24,131.13 164.03,130.92 163.32,130.92 163.25,130.85 163.24,130.85
  L3 w0.127: v2(160.69,145.92) 160.69,145.04 160.98,144.75 160.98,143.48 161.81,142.64 161.81,142.22 161.47,141.87 161.47,140.45 163.15,138.77 v2(167.49,138.77) 167.49,138.96 167.62,139.08 168.09,139.08 168.4,138.77 170.43,138.77 171.07,139.41 171.07,140 171.3,140.24 171.48,140.24 171.71,140 171.89,140 172.07,140.18 172.07,140.36 171.84,140.6 171.84,140.78 172.02,140.96 172.2,140.96 172.43,140.72 172.61,140.72 172.79,140.9 172.79,141.08 172.56,141.32 172.56,141.5 173.07,142.01 173.07,142.51 174.72,144.15 v2(174.72,144.77)
  BOTTOM w0.14: v2(174.72,144.77) 174.72,144.45 174.98,144.19 175.45,144.19 175.59,144.05 VRAM4.N3 ; v2(160.69,145.92) 160.47,145.71 160.21,145.71 160.07,145.85 160.07,146.67 VRAM2.N3
  BOTTOM w0.279: GPU1.K17 164.69,122.24 v2(165.05,122.24)
MAA1: length 54.4
  TOP w0.14: VRAM3.P7 174.61,143.77 174.61,143.81 174.23,144.18 173.93,144.18 173.44,144.67 173.44,145.02 173.71,145.28 v2(173.71,145.46) ; VRAM1.P7 161.17,146.61 161.17,146.57 161.62,146.13 161.75,146.13 162.04,145.84 162.04,145.37 162.1,145.31 v2(162.1,145.02)
  TOP w0.178: 161.32,127.38 161.72,126.98 161.72,126.56 161.44,126.28 161.44,125.72 161.62,125.54 161.94,125.54 162.12,125.37 162.12,124.97 162.13,124.95 162.13,123.9 161.9,123.66 v2(161.65,123.66)
  TOP w0.279: 161.32,127.38 161.32,129.23 161.19,129.36 v1(161.19,130.34) 161.19,130.35 161.19,131.71 160.78,132.12 160.78,132.45 161.19,132.87 161.19,133.36 160.45,134.1 160.45,134.63 161.56,135.74 161.87,135.74 162.51,135.09 162.87,135.09 163.23,135.44 163.23,136.28 163.06,136.45 162.81,136.7 162.81,137.06 163.48,137.73 163.48,137.73 163.59,137.84 165.18,137.84 167.07,139.74 167.07,140.18 v2(167.03,140.23)
  L3 w0.127: v2(162.1,145.02) 162.1,144.32 162,144.21 162,143.93 162.77,143.16 162.77,142.99 162.95,142.82 163.33,142.82 163.5,142.64 163.5,141.6 163.31,141.4 163.31,141.2 163.17,141.06 163.17,140.69 163.5,140.36 163.5,140.23 163.65,140.07 165.42,140.07 165.6,139.9 166.17,139.9 166.5,140.23 v2(167.03,140.23) 167.03,140.61 167.13,140.71 167.48,140.71 167.82,140.38 168.01,140.38 168.34,140.71 170.37,140.71 172.16,142.5 172.16,143 173.45,144.29 173.45,144.96 173.28,145.13 173.28,145.33 173.4,145.46 v2(173.71,145.46)
  BOTTOM w0.14: v2(173.71,145.46) 174.11,145.85 174.65,145.85 174.79,145.99 VRAM4.P7 ; v2(162.1,145.02) 162.28,144.85 162.28,144.59 162.01,144.33 161.55,144.33 160.99,143.76 VRAM2.P7
  BOTTOM w0.279: GPU1.J20 162.08,123.24 v2(161.65,123.66)
MAA2: length 53
  TOP w0.14: VRAM1.P3 161.2,143.8 161.2,143.83 161.88,144.52 162.2,144.52 162.53,144.85 162.53,145.2 162.46,145.26 v2(162.46,145.55) ; VRAM3.P3 174.79,146.75 174.23,146.19 173.84,146.19 173.28,145.63 173.28,145.26 173.28,145.25 173.28,145.25 173.01,144.98 v2(173.01,144.81)
  TOP w0.178: v2(160.4,124.48) 160.65,124.48 160.84,124.66 160.84,126.35 160.55,126.64
  TOP w0.279: 160.55,126.64 160.35,126.84 160.35,128.08 159.86,128.57 159.86,129.31 160.28,129.73 160.28,131.16 159.54,131.91 159.54,133.99 159.47,134.05 v1(159.47,134.48) 159.47,134.94 160.77,136.24 160.77,136.87 159.82,137.82 159.82,138.22 160.2,138.6 161.96,138.6 162.26,138.3 162.67,138.3 163.78,139.41 164.31,139.41 164.62,139.11 165.15,139.11 165.48,139.44 165.48,140.1 165.72,140.34 v2(165.99,140.34)
  L3 w0.127: v2(173.01,144.81) 173.01,144.31 171.83,143.13 171.83,142.63 170.24,141.04 166.69,141.04 v2(165.99,140.34) 165.62,140.34 165.4,140.56 165.17,140.56 165.02,140.4 163.93,140.4 163.64,140.7 163.64,141.27 163.86,141.49 163.86,142.81 163.45,143.22 163.18,143.22 162.46,143.95 162.46,144.62 162.65,144.81 162.65,145.37 v2(162.46,145.55)
  BOTTOM w0.14: v2(173.01,144.81) 173.01,144.57 173.12,144.45 173.67,144.45 173.94,144.18 174.23,144.18 174.58,143.83 174.58,143.8 VRAM4.P3 ; v2(162.46,145.55) 162.11,145.55 161.97,145.69 161.97,146 161.83,146.14 161.41,146.14 161.17,146.38 161.17,146.61 VRAM2.P3
  BOTTOM w0.279: GPU1.H23 159.89,124.15 160.22,124.48 v2(160.4,124.48)
MAA3: length 58.7
  TOP w0.14: v2(173.87,144.84) 174.05,145.03 174.05,145.05 174.14,145.14 174.14,145.65 175.2,146.71 175.2,147.2 VRAM3.N2 ; VRAM1.N2 160.62,143.22 160.62,143.71 160.85,143.94 160.86,143.94 161.62,144.7 161.62,145.34 161.54,145.42 v2(161.54,145.7)
  TOP w0.279: v2(164.93,139.63) 164.89,139.67 164.89,140.35 164.58,140.67 164.15,140.67 163.95,140.47 163.95,140.24 162.76,139.06 160.01,139.06 159.63,138.68 159.36,138.41 159.36,137.64 160.14,136.85 v1(160.14,136.49) 160.14,136.26 159.01,135.13 159.01,131.79 159.82,130.97 159.82,129.81 159.48,129.47 159.48,128.41 159.89,128 159.89,125.67 v2(160.39,125.17)
  L3 w0.127: v2(161.54,145.7) 161.68,145.56 161.68,144.85 161.77,144.76 161.77,144.39 161.64,144.26 161.64,143.81 162.48,142.97 162.48,142.1 162.61,141.98 162.99,141.98 163.12,141.85 163.12,141.7 162.96,141.55 162.96,141.27 162.84,141.14 162.33,141.14 162.2,141.02 162.2,140.73 162.35,140.58 162.81,140.58 163.17,140.23 163.17,139.69 163.42,139.43 163.65,139.43 163.95,139.74 164.18,139.74 164.49,139.43 164.74,139.43 v2(164.93,139.63) 165.4,139.63 165.46,139.56 167,139.56 167.23,139.8 167.89,139.8 168.48,140.38 170.51,140.38 172.46,142.33 172.46,142.83 173.87,144.24 v2(173.87,144.84)
  BOTTOM w0.14: v2(173.87,144.84) 173.87,144.84 173.92,144.8 173.94,144.8 174.31,144.42 174.33,144.42 174.82,143.94 175.05,143.94 175.23,143.76 175.23,143.44 175.05,143.27 175.05,143.02 175.28,142.79 175.35,142.79 VRAM4.N2 ; v2(161.54,145.7) 161.28,145.7 161.14,145.84 161.14,146.08 160.84,146.38 160.67,146.38 160.54,146.51 160.54,146.83 160.78,147.07 160.78,147.31 160.52,147.57 160.41,147.57 160.39,147.59 VRAM2.N2
  BOTTOM w0.279: GPU1.G23 160.22,125.17 v2(160.39,125.17)
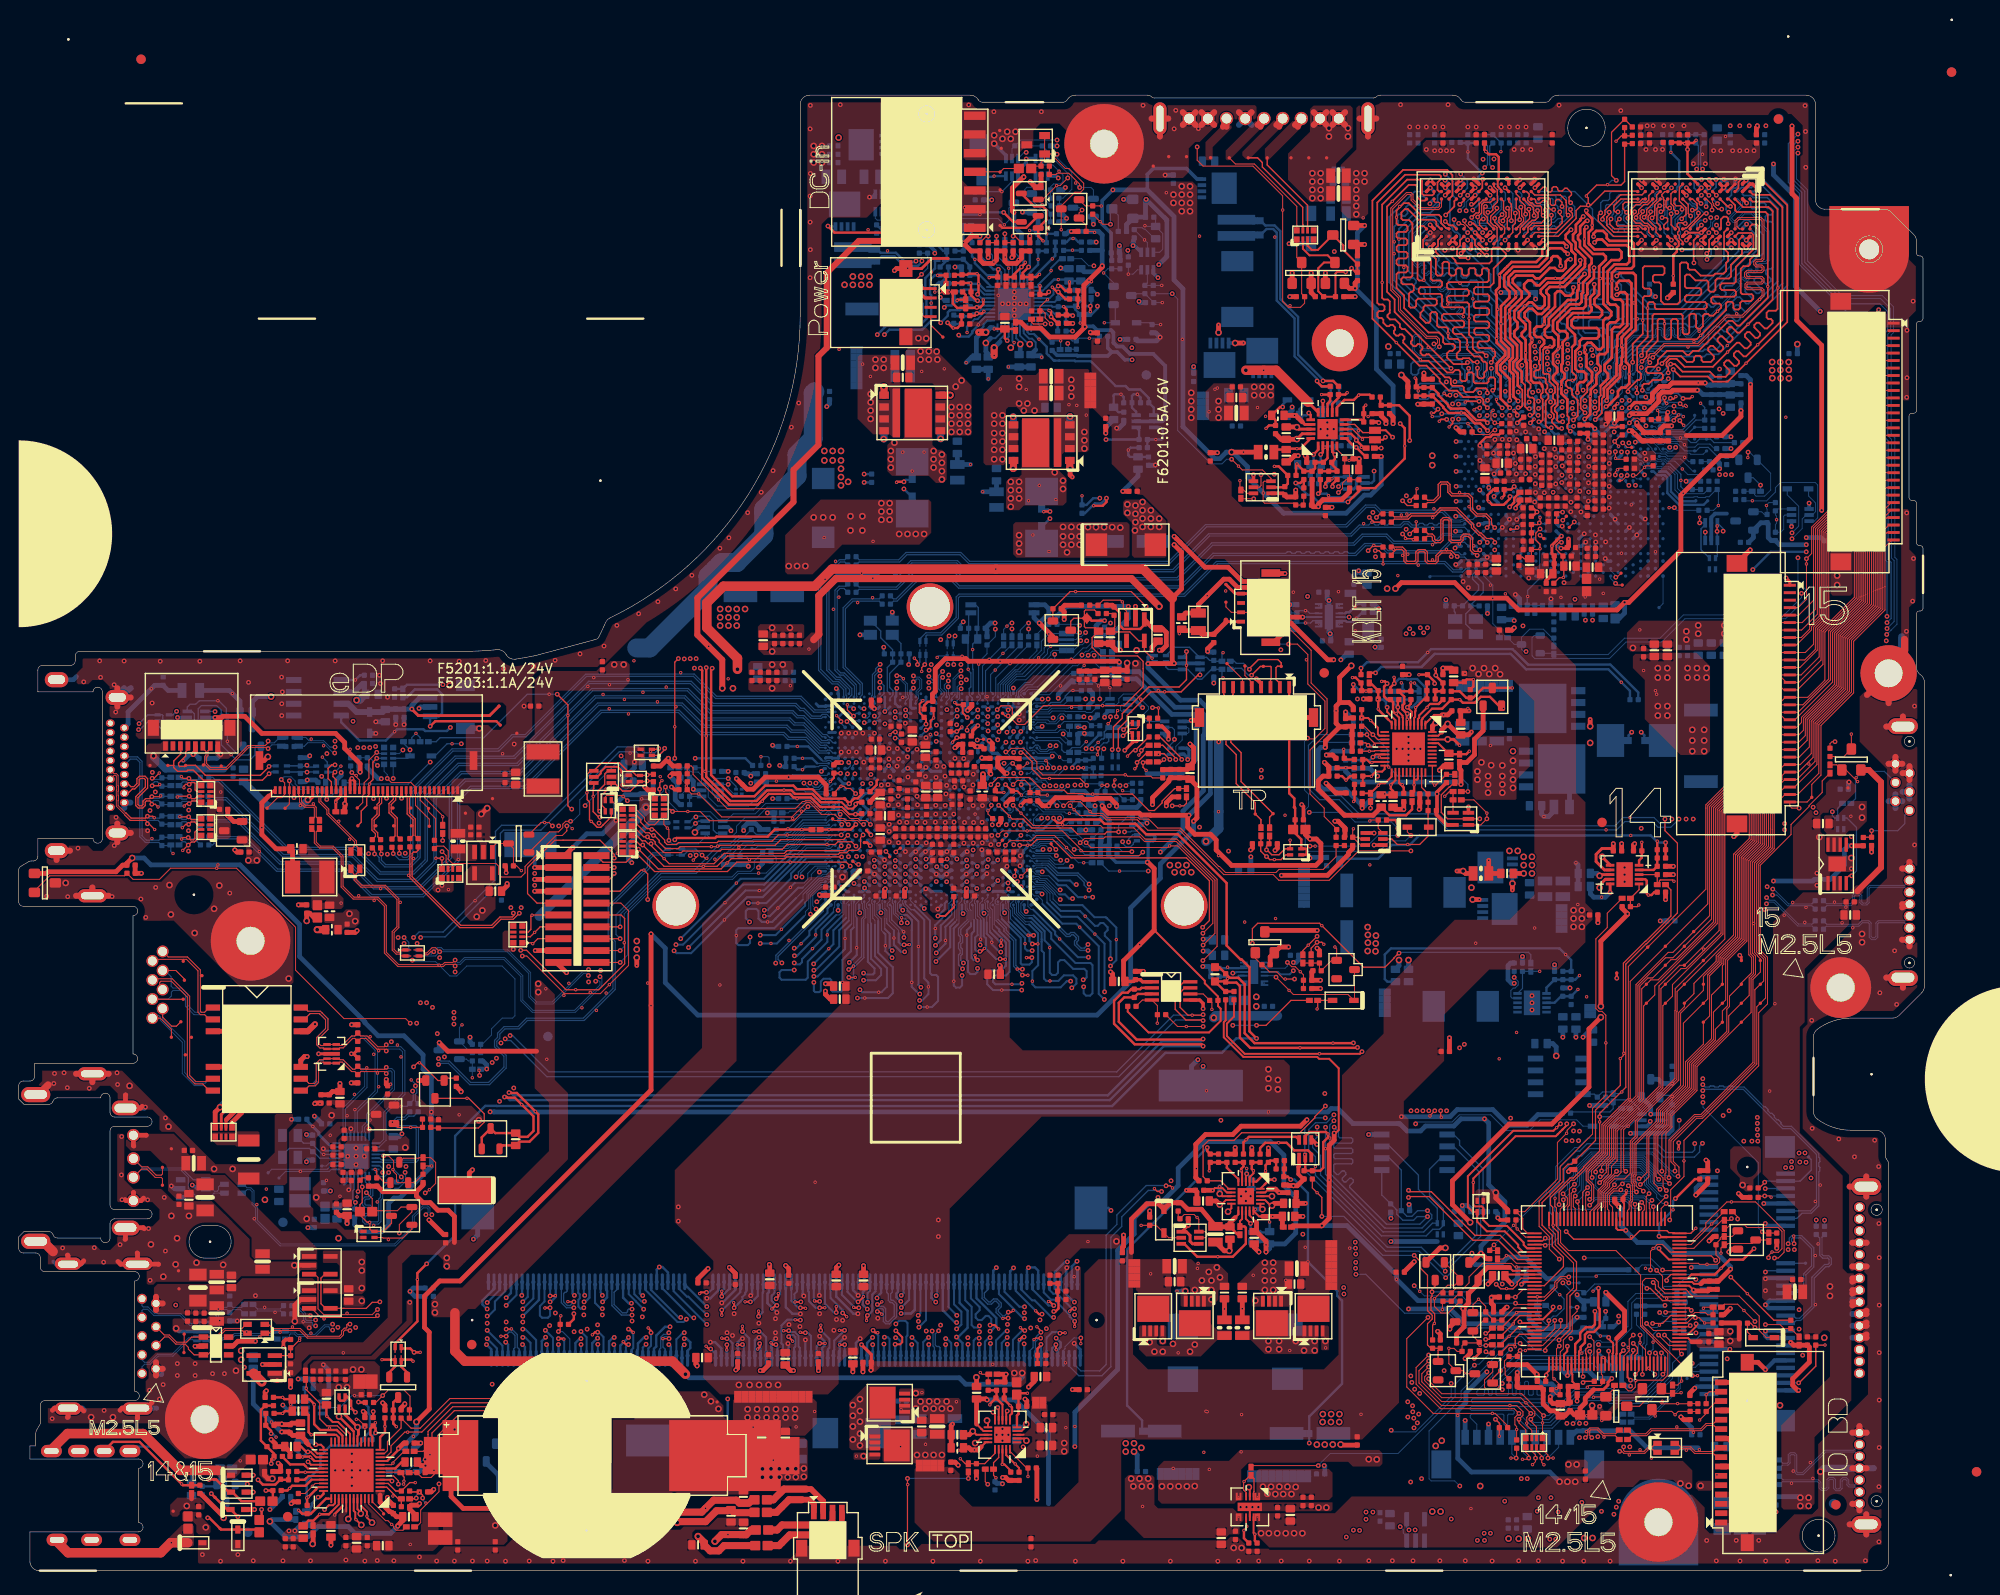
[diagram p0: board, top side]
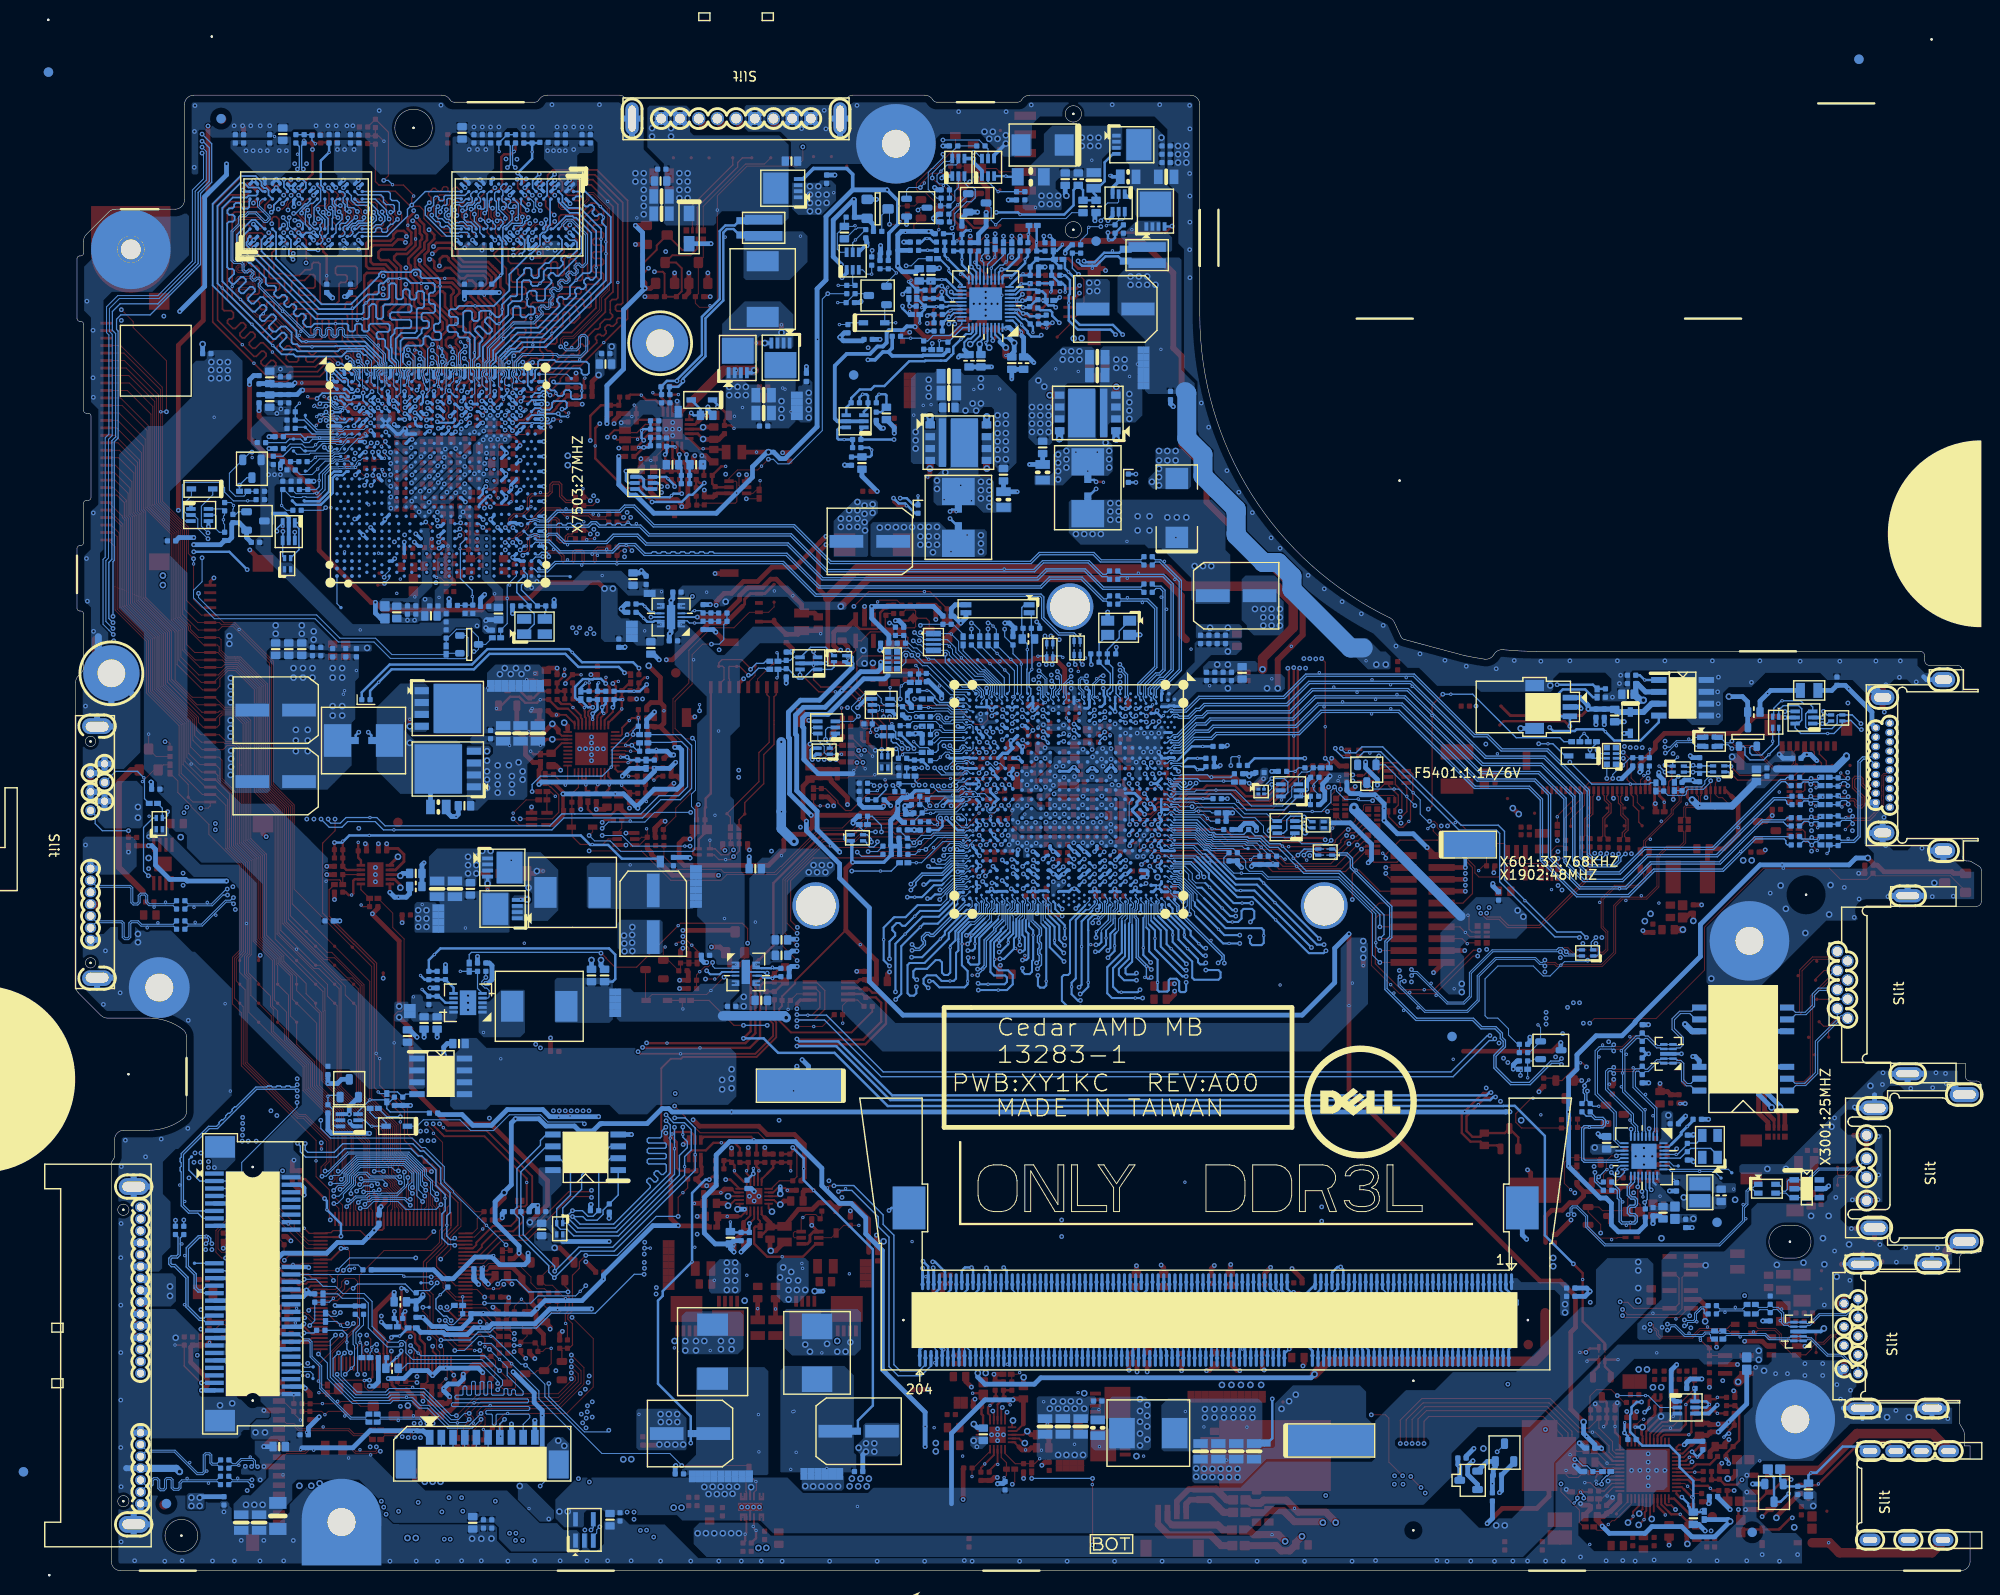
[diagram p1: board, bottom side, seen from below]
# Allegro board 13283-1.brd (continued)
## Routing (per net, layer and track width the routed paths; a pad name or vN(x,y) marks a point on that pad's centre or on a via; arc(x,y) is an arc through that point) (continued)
MAA4: length 59.2
  TOP w0.14: VRAM1.P8 161.3,147.59 161.57,147.32 161.57,147.06 161.42,146.91 161.42,146.67 161.72,146.37 161.85,146.37 162.16,146.06 162.74,146.06 162.89,145.91 162.89,145.21 v2(163.07,145.03) ; VRAM3.P8 174.36,143.22 174.36,143.71 174.13,143.94 173.71,143.94 173.44,144.21 173,144.21 172.58,144.63 172.58,144.98 172.85,145.25 v2(172.85,145.42)
  TOP w0.279: v2(159.48,125.24) 159.5,125.26 159.5,127.51 158.49,128.53 158.49,129.02 159.38,129.91 159.38,130.77 158.55,131.6 v1(158.55,133.44) 158.55,135.32 159.46,136.22 159.46,136.89 158.9,137.45 158.9,138.6 159.17,138.87 159.17,138.87 159.44,139.13 159.44,139.13 159.84,139.54 162.56,139.54 163.49,140.47 163.49,141.21 163.8,141.52 165.01,141.52 165.35,141.18 165.43,141.18 v2(165.69,140.92)
  L3 w0.127: v2(172.85,145.42) 172.59,145.16 172.59,144.36 171.5,143.27 171.5,142.77 170.1,141.37 166.52,141.37 166.08,140.92 v2(165.69,140.92) 165.69,141.11 165.56,141.24 165.14,141.24 165.01,141.11 165.01,140.86 164.88,140.73 164.07,140.73 163.97,140.83 163.97,141.13 164.08,141.24 164.44,141.24 164.56,141.37 164.56,141.54 164.21,141.89 164.21,142.93 163.58,143.55 163.29,143.55 162.74,144.11 162.74,144.31 162.86,144.44 163.14,144.44 163.27,144.57 163.27,144.83 v2(163.07,145.03)
  BOTTOM w0.14: v2(172.85,145.42) 172.58,145.42 172.44,145.56 172.44,145.89 172.67,146.12 173.81,146.12 174.34,146.65 174.34,147.14 VRAM4.P8 ; v2(163.07,145.03) 163.29,144.8 163.29,144.39 163.17,144.26 162.85,144.26 162.75,144.37 162.39,144.37 161.96,143.94 161.58,143.94 161.44,143.8 161.44,143.36 161.3,143.22 161.13,143.22 160.99,143.08 VRAM2.P8
  BOTTOM w0.279: v2(159.48,125.24) GPU1.G24
MAA5: length 58.5
  TOP w0.14: VRAM3.P2 174.36,147.16 174.36,146.67 174.13,146.43 173.67,146.43 173.43,146.2 173.03,146.2 172.43,145.6 172.43,145.18 172.13,144.89 v2(172.13,144.73) ; VRAM1.P2 161.44,143.24 161.44,143.73 161.92,144.21 162.85,144.21 163.49,144.86 163.49,145.44 v2(163.32,145.62)
  TOP w0.279: v2(159.49,124.45) 158.51,125.43 158.51,127.81 158.1,128.23 158.1,128.92 158.11,128.93 158.11,129.18 159,130.07 159,130.5 158.1,131.4 v1(158.1,131.87) 158.1,136.5 158.02,136.57 158.02,137 158.41,137.39 158.41,138.76 158.98,139.32 159.25,139.59 159.7,140.05 162.33,140.05 162.97,140.68 162.97,141.42 163.65,142.1 165.25,142.1 165.57,141.79 v2(165.57,141.7)
  L3 w0.127: v2(163.32,145.62) 163.5,145.43 163.5,144.87 163.6,144.77 163.6,144.44 163.35,144.19 163.35,144.01 163.47,143.88 163.88,143.88 164.01,143.76 164.01,143.6 164.54,143.07 164.54,142.03 164.67,141.9 164.92,141.9 165.05,142.03 165.05,142.51 165.17,142.64 165.35,142.64 165.76,142.23 165.76,141.89 v2(165.57,141.7) 169.96,141.7 171.17,142.91 171.17,143.41 171.99,144.23 171.99,144.59 v2(172.13,144.73)
  BOTTOM w0.14: VRAM2.P2 161.3,147.59 161.59,147.29 161.59,147.09 161.42,146.91 161.42,146.51 161.54,146.38 161.93,146.38 162.21,146.1 162.21,146.1 162.34,145.97 162.61,145.97 162.81,146.17 163.19,146.17 163.32,146.04 v2(163.32,145.62) ; v2(172.13,144.73) 172.13,144.54 172.39,144.28 172.54,144.28 172.61,144.21 173.57,144.21 173.84,143.94 174.13,143.94 174.34,143.73 174.34,143.45 174.19,143.3 174.19,143.08 174.34,142.93 174.34,142.93 174.48,142.79 VRAM4.P2
  BOTTOM w0.279: GPU1.H24 159.09,124.05 v2(159.49,124.45)
MAA6: length 60
  TOP w0.14: VRAM3.R8 173.54,143.24 170.61,143.24 169.87,143.97 169.87,144.46 169.87,144.46 169.87,144.84 169.87,144.84 169.87,144.86 170.13,145.12 v2(170.13,145.38) ; v2(165.75,145.06) 165.54,145.27 165.54,146.41 165.52,146.44 165.52,146.61 164.91,147.22 162.16,147.22 VRAM1.R8
  TOP w0.178: v2(165.15,122.95) 164.72,122.95 164.56,123.11 164.56,123.87 164.31,124.12 164.31,124.43 164.62,124.73 164.62,126.97
  TOP w0.279: v2(167.79,144.46) 167.64,144.46 167.02,143.84 167.02,143.1 166.8,142.87 166.8,142.5 167,142.3 167,141.66 168.25,140.42 168.25,139.9 167.99,139.65 167.99,139.21 168.02,139.19 168.02,138.55 167.33,137.86 167.33,136.79 167.18,136.64 167.18,135.78 166.93,135.53 165.9,135.53 164.13,133.76 164.13,132.7 164.7,132.13 164.7,130.78 v1(164.67,130.75) 164.67,130.74 164.13,130.2 164.13,129.15 164.56,128.72 164.56,128.29 164.13,127.86 164.13,127.45 164.62,126.97
  L3 w0.127: v2(165.75,145.06) 165.86,144.95 166.22,144.95 166.37,145.1 166.37,145.43 166.52,145.58 166.71,145.58 166.9,145.39 166.9,144.73 167.32,144.31 167.65,144.31 v2(167.79,144.46) 168,144.67 168.72,144.67 169.21,144.17 169.6,144.17 169.87,144.45 169.87,144.79 169.73,144.93 169.73,145.24 169.87,145.38 v2(170.13,145.38)
  BOTTOM w0.14: v2(165.75,145.06) 165.75,144.83 165.29,144.38 164.98,144.38 164.84,144.24 164.84,143.93 164.69,143.78 164.41,143.78 164.28,143.91 164.07,143.91 163.78,143.62 163.78,143.26 163.65,143.13 162.9,143.13 162.81,143.22 161.95,143.22 161.79,143.06 VRAM2.R8 ; v2(170.13,145.38) 169.89,145.38 169.75,145.52 169.75,146.05 169.89,146.19 170.63,146.19 170.91,146.47 170.91,146.96 171.19,147.24 173.64,147.24 VRAM4.R8
  BOTTOM w0.229: GPU1.J19 163.29,123.06 163.5,122.85 165.04,122.85 v2(165.15,122.95)
MAA7: length 60.8
  TOP w0.14: VRAM1.R2 162.21,143.21 164.53,143.21 166.2,144.88 166.2,145.25 165.99,145.46 v2(165.99,145.67) ; VRAM3.R2 173.64,147.24 171.36,147.24 169.68,145.57 169.68,145.14 169.55,145 169.42,144.87 v2(169.42,144.62)
  TOP w0.178: 162.94,126.74 163.02,126.66 163.02,126.08 162.81,125.87 162.81,125.55 163.02,125.34 163.02,123.13 162.84,122.95 v2(162.61,122.95)
  TOP w0.279: v2(167.35,144.91) 167.05,144.62 167.05,144.52 166.57,144.03 166.57,143.29 166.26,142.98 166.26,142.39 166.55,142.11 166.55,141.45 166.57,141.43 166.57,141.42 166.81,141.18 167.55,140.44 167.55,139.85 167.53,139.84 167.53,139.55 165.37,137.38 163.78,137.38 163.42,137.02 163.42,136.74 163.69,136.47 163.69,135.25 162.92,134.48 162.47,134.48 161.91,135.05 161.52,135.05 161.08,134.62 161.08,134.15 161.65,133.59 161.65,132.1 161.87,131.88 v1(161.87,131.69) 161.87,131.46 161.65,131.24 161.65,129.52 161.71,129.46 161.71,128.7 161.77,128.64 161.77,127.4 162.05,127.12 162.71,127.12 162.94,126.89 162.94,126.74
  L3 w0.127: v2(165.99,145.67) 166.38,146.06 166.9,146.06 167.1,145.86 167.1,145.65 167.24,145.52 167.24,145.36 167.35,145.25 v2(167.35,144.91) 167.77,144.91 168.19,145.33 168.51,145.33 168.84,145 168.85,145 168.98,144.87 169.17,144.87 v2(169.42,144.62)
  BOTTOM w0.14: VRAM4.R2 173.56,143.22 171.89,143.22 171.75,143.36 171.75,143.55 171.57,143.73 171.26,143.73 171.12,143.59 171.12,143.36 170.98,143.22 170.63,143.22 170.48,143.37 170.48,143.76 170.15,144.09 169.95,144.09 v2(169.42,144.62) ; v2(165.99,145.67) 165.56,146.11 165.56,146.93 165.4,147.08 165.12,147.08 165,146.96 165,146.73 164.87,146.6 164.56,146.6 164.44,146.73 164.44,147.04 164.31,147.17 162.21,147.17 VRAM2.R2
  BOTTOM w0.279: GPU1.K19 163.12,122.44 v2(162.61,122.95)
MAA8: length 60.5
  TOP w0.14: VRAM3.T8 170.61,142.79 168.97,144.43 168.97,145.06 v2(169.22,145.31) ; v2(166.01,146.39) 165.83,146.57 165.83,146.98 166.09,147.24 166.09,147.46 165.61,147.94 165.4,147.94 165.1,147.64 164.77,147.64 164.62,147.79 164.62,147.95 164.46,148.1 164.17,148.1 164.02,147.95 164.02,147.69 163.86,147.54 163.61,147.54 163.46,147.69 163.46,147.91 163.32,148.05 163.05,148.05 VRAM1.T8
  TOP w0.178: 167.79,126.84 167.79,126.15 167.08,125.45 167.08,124.38 v2(167.55,123.91)
  TOP w0.279: 167.79,126.84 168.29,127.35 168.29,128.25 167.7,128.85 167.7,130.14 167.5,130.34 167.5,131.1 167.81,131.4 168.2,131.4 168.46,131.15 168.91,130.7 169.21,130.7 169.49,130.98 169.49,133.77 169.77,134.05 170.08,134.05 170.36,134.33 170.36,134.72 169.51,135.57 169.51,139.39 170.37,140.25 171.19,140.25 171.45,140.5 171.45,141.11 171.17,141.39 168.56,141.39 168.06,141.9 168.04,141.93 167.94,142.03 167.94,143.22 168.31,143.59 v1(168.31,143.98) 168.31,144.69 167.68,145.32 v2(167.68,145.54)
  L3 w0.127: v2(169.22,145.31) 169.22,145.61 168.94,145.89 168.27,145.89 167.92,145.54 v2(167.68,145.54) 167.43,145.79 167.43,146.09 167.13,146.39 v2(166.01,146.39)
  BOTTOM w0.14: VRAM4.T8 170.38,147.59 170.18,147.39 170.18,146.8 170,146.63 169.47,146.63 169.22,146.38 v2(169.22,145.31) ; v2(166.01,146.39) 166.44,145.96 166.44,145.07 164.18,142.81 162.91,142.81 162.89,142.79 VRAM2.T8
  BOTTOM w0.279: GPU1.J14 166.89,123.34 167.47,123.91 v2(167.55,123.91)
MAA9: length 55.3
  TOP w0.14: VRAM1.R3 162.14,143.94 163.78,143.94 163.94,144.1 v2(163.94,145.06) ; v2(171.98,145.37) 171.6,145.74 171.6,146.22 171.82,146.44 173.33,146.44 173.68,146.79 VRAM3.R3
  TOP w0.279: v2(168.56,142.15) 168.67,142.25 168.67,142.25 168.88,142.46 169.37,142.46 169.98,141.85 172.01,141.85 172.29,141.57 172.29,140.07 172.01,139.79 170.7,139.79 169.96,139.06 169.96,135.75 170.24,135.48 170.81,135.48 171.09,135.2 171.09,133.88 170.81,133.6 170.23,133.6 169.95,133.32 169.95,130.47 169.67,130.19 169.11,130.19 168.89,129.97 168.89,129.16 169.19,128.87 169.19,128.38 168.76,127.95 168.76,126.99 168.17,126.4 168.17,125.91 168.09,125.84 v1(168.09,125.67) 168.09,123.76 167.59,123.26 v2(167.51,123.26)
  L3 w0.127: v2(171.98,145.37) 171.63,145.37 171.5,145.24 171.5,144.99 171.66,144.83 171.66,144.46 171.55,144.35 171.55,144.26 170.84,143.54 170.84,143.04 170.65,142.85 170.09,142.85 169.97,142.74 169.97,142.18 169.83,142.03 168.68,142.03 v2(168.56,142.15) 166.31,142.15 165.41,143.05 165.03,143.05 164.34,143.74 164.34,144.27 164.06,144.55 164.06,144.94 v2(163.94,145.06)
  BOTTOM w0.14: v2(163.94,145.06) 163.74,145.26 163.74,146 163.31,146.44 162.44,146.44 162.09,146.79 VRAM2.R3 ; v2(171.98,145.37) 171.98,145.24 171.68,144.94 171.68,144.54 172.26,143.96 173.4,143.96 173.77,143.59 VRAM4.R3
  BOTTOM w0.279: v2(167.51,123.26) 167.51,122.7 167.29,122.48 167.02,122.48 166.98,122.44 GPU1.K14
MAA10: length 60.8
  TOP w0.14: VRAM1.L7 158.82,146.56 158.82,145.6 159.1,145.33 159.1,144.95 158.76,144.61 v2(158.76,144.45) ; VRAM3.L7 176.76,144.02 v2(176.76,145.2)
  TOP w0.178: v2(168.65,123.18) 169.35,123.88 169.35,125.43 169.57,125.65
  TOP w0.279: v2(170.94,136.54) 171.08,136.68 171.16,136.68 171.3,136.82 171.78,136.82 172.06,136.54 172.06,133.24 171.01,132.19 171.01,131.07 170.94,131.01 170.94,129.14 170.91,129.11 170.91,127.9 169.57,126.56 169.57,125.65
  L3 w0.127: v2(158.76,144.45) 158.76,143.24 159.41,142.58 159.41,142.22 158.87,141.68 158.87,140.71 163.04,136.54 v2(170.94,136.54) 173.96,136.54 174.18,136.76 174.18,137.38 174.31,137.51 175.21,137.51 175.33,137.63 175.33,137.94 175.21,138.07 174.31,138.07 174.18,138.19 174.18,138.52 174.31,138.65 175.99,138.65 176.12,138.78 176.12,139.03 175.99,139.16 174.98,139.16 174.85,139.29 174.85,139.54 175.01,139.69 175.92,139.69 176.12,139.9 176.12,142.46 176.76,143.1 v2(176.76,145.2)
  BOTTOM w0.14: VRAM4.L7 177.19,145.79 176.76,145.36 v2(176.76,145.2) ; VRAM2.L7 158.38,143.8 158.38,143.89 158.14,144.14 158.14,144.38 158.35,144.59 158.61,144.59 v2(158.76,144.45)
  BOTTOM w0.279: GPU1.J11 168.7,123.24 v2(168.65,123.18)
MAA11: length 56.2
  TOP w0.14: VRAM1.R7 162.14,146.79 162.25,146.68 162.25,146.45 162.4,146.3 162.72,146.3 163.04,146.63 163.35,146.63 163.5,146.47 163.5,146.04 163.88,145.66 v2(164.19,145.66) ; VRAM3.R7 173.68,143.59 173.33,143.94 173.05,143.94 173.01,143.91 171.05,143.91 170.91,144.05 170.91,144.34 v2(171.22,144.64)
  TOP w0.178: 169.21,126.79 169.21,125.77 169.06,125.62 169.06,124.25 v2(168.62,123.82)
  TOP w0.279: 169.21,126.79 170,127.58 170,128.08 169.64,128.44 169.64,129.05 170.42,129.83 170.42,132.81 170.7,133.09 171.26,133.09 171.6,133.43 171.6,135.77 171.35,136.02 170.73,136.02 170.42,136.33 v1(170.42,138.02) 170.42,138.87 170.89,139.34 172.49,139.34 172.77,139.62 172.77,142.03 172.49,142.31 170.17,142.31 169.87,142.6 169.87,142.98 169.47,143.37 168.74,143.37 168.46,143.09 v2(168.46,142.77)
  L3 w0.127: v2(164.19,145.66) 164.39,145.46 164.39,144.69 164.67,144.41 164.67,143.87 165.16,143.38 165.54,143.38 166.15,142.77 v2(168.46,142.77) 168.46,143.07 168.57,143.18 169,143.18 169.11,143.07 169.11,142.49 169.23,142.36 169.52,142.36 169.64,142.49 169.64,143.06 169.77,143.18 170.01,143.18 171.22,144.39 v2(171.22,144.64)
  BOTTOM w0.14: v2(164.19,145.66) 164.19,145.44 164.39,145.24 164.39,144.87 164.13,144.61 163.86,144.61 163.2,143.94 162.45,143.94 162.1,143.59 VRAM2.R7 ; VRAM4.R7 173.64,146.44 172.41,146.44 171.52,145.56 171.52,145.23 171.38,145.09 171.38,145.09 171.22,144.92 v2(171.22,144.64)
  BOTTOM w0.279: v2(168.62,123.82) 168.46,123.82 168.09,123.45 GPU1.J13
MAA12: length 57.7
  TOP w0.14: v2(160.55,144.58) 160.52,144.6 160.52,145.46 160.19,145.78 VRAM1.N7 ; VRAM3.N7 175.59,143.88 175.23,144.24 175.23,145.78 v2(175.53,146.08)
  TOP w0.279: v2(170.94,138.55) 171.27,138.88 172.69,138.88 172.97,138.6 172.97,132.86 171.92,131.81 171.92,129.34 172.28,128.98 v1(172.28,128.06) 172.28,127.02 171.87,126.61 171.45,126.61 171.07,126.23 171.07,125.72 169.92,124.58 v2(169.79,124.58)
  L3 w0.127: v2(175.53,146.08) 175.21,146.4 174.44,146.4 174.32,146.27 174.32,145.98 174.44,145.85 174.74,145.85 175.14,145.45 175.14,144.09 174.01,142.96 174.01,141.97 173.86,141.83 173.38,141.83 173.12,141.57 173.12,141.22 173.39,140.95 173.89,140.95 174,140.84 174,140.62 173.6,140.21 173.42,140.21 173.09,140.54 172.91,140.54 172.22,139.86 172.22,139.68 172.58,139.32 172.58,139.15 172.38,138.96 172.21,138.96 171.78,139.39 171.51,139.39 171.32,139.2 171.32,138.93 v2(170.94,138.55) 170.67,138.55 170.56,138.44 167.9,138.44 167.79,138.33 163.12,138.33 161.14,140.32 161.14,142.03 160.97,142.19 160.97,142.98 160.66,143.29 160.66,144.46 v2(160.55,144.57)
  BOTTOM w0.14: v2(160.55,144.57) 160.23,144.57 160.09,144.44 160.09,144.29 159.76,143.96 159.76,143.73 159.9,143.59 VRAM2.N7 ; VRAM4.N7 175.9,146.79 176.15,146.54 176.15,146.31 175.91,146.08 v2(175.53,146.08)
  BOTTOM w0.279: v2(169.79,124.58) 169.29,124.08 GPU1.H11
MAA13: length 54.6
  TOP w0.14: v2(164.84,145.41) 164.84,145.4 164.84,145.32 164.84,145.14 165.1,144.89 165.1,144.24 164.45,143.59 VRAM1.T3 ; v2(171.07,145.41) 170.77,145.41 170.63,145.55 170.63,146.04 171.38,146.79 VRAM3.T3
  TOP w0.178: 160.78,127.22 161.13,126.87 161.13,124.59 161.36,124.35 v2(161.59,124.35)
  TOP w0.279: 160.78,127.22 160.78,128.31 160.29,128.79 160.29,129.2 160.74,129.65 160.74,131.35 159.99,132.1 159.99,132.63 160.32,132.96 160.32,133.58 159.99,133.91 159.99,134.82 161.59,136.42 161.59,136.69 161.03,137.26 161.03,137.65 161.45,138.07 161.84,138.07 162.35,137.56 162.66,137.56 163.4,138.29 v1(164.36,138.29) 164.99,138.29 166.51,139.82 166.51,140.84 166.21,141.13 166.11,141.23 166.11,141.24 166.09,141.26 166.09,141.92 165.48,142.53 165.48,142.95 166.03,143.5 v2(166.05,143.5)
  L3 w0.127: v2(164.84,145.41) 164.72,145.28 164.72,144.82 164.84,144.7 165.02,144.7 165.17,144.54 165.17,144.34 165,144.16 165,144.01 165.24,143.77 165.39,143.77 165.91,144.29 166.41,144.29 166.82,143.88 166.82,143.73 166.7,143.6 166.15,143.6 v2(166.05,143.5) 166.44,143.1 167.44,143.1 167.67,143.33 168.09,143.33 168.27,143.51 169.87,143.51 170.77,144.42 170.77,145.12 v2(171.07,145.41)
  BOTTOM w0.14: v2(171.07,145.41) 171.07,145.22 170.77,144.92 170.77,144.46 171.18,144.05 171.7,144.05 172.16,143.59 VRAM4.T3 ; VRAM2.T3 162.65,146.85 163.17,146.85 163.32,146.7 163.6,146.7 163.75,146.85 164.01,146.85 164.12,146.74 164.12,146.26 164.26,146.12 164.5,146.12 164.64,145.98 164.64,145.8 164.84,145.6 v2(164.84,145.41)
  BOTTOM w0.279: GPU1.G20 162.09,124.62 161.93,124.46 161.92,124.46 161.81,124.35 v2(161.59,124.35)
MAA14: length 54.8
  TOP w0.14: VRAM3.T7 170.71,143.59 170.2,144.09 170.2,144.54 v2(170.32,144.65) ; v2(165.09,145.99) 165.09,146.43 164.77,146.75 164.54,146.75 164.39,146.59 164.39,146.25 164.25,146.11 163.97,146.11 163.83,146.25 163.83,146.75 163.68,146.91 162.71,146.91 VRAM1.T7
  TOP w0.279: v2(166.73,126.07) 166.73,126.92 167.01,127.2 167.38,127.2 167.66,127.47 167.66,128.06 167.38,128.34 166.79,128.34 166.51,128.62 166.51,130.5 166.98,130.97 166.98,131.59 167.26,131.87 168.81,131.87 169.03,132.1 169.03,132.76 168.81,132.99 166.39,132.99 166.11,133.27 166.11,133.8 166.44,134.13 169.09,134.13 169.36,134.41 169.36,134.84 168.96,135.25 168.83,135.25 168.55,135.53 168.55,136.07 169.05,136.57 169.05,139.58 169.77,140.3 169.77,140.63 169.49,140.91 168.4,140.91 167.48,141.83 v1(167.48,142.51) 167.48,143.56 v2(167.69,143.78)
  L3 w0.127: v2(165.09,145.99) 165.3,145.78 165.3,144.88 165.56,144.62 166.55,144.62 167.39,143.78 v2(167.69,143.78) 168.07,143.78 168.2,143.9 168.2,144.14 168.31,144.25 168.67,144.25 168.78,144.14 168.78,143.96 168.9,143.84 169.74,143.84 170.32,144.43 v2(170.32,144.65)
  BOTTOM w0.14: VRAM4.T7 171.81,146.79 170.58,145.57 170.58,145.19 170.45,145.06 170.45,144.79 v2(170.32,144.65) ; VRAM2.T7 163.3,143.59 164,144.29 164.26,144.29 164.67,144.69 165.03,144.69 165.3,144.96 165.3,145.78 v2(165.09,145.99)
  BOTTOM w0.229: v2(166.73,126.07) 166.7,126.04 166.7,125.03 GPU1.G14
MAA15: length 61.8
  TOP w0.14: VRAM3.M7 176.11,143.59 175.97,143.73 175.97,143.98 176.38,144.39 176.38,144.67 176.25,144.8 v2(175.79,144.8) ; v2(159.67,144.47) 159.67,145.62 159.68,145.64 159.68,145.99 159.67,146 159.67,146.22 159.39,146.5 VRAM1.M7
  TOP w0.178: v2(163.94,122.31) 163.58,122.31 163.33,122.56 163.33,125.17 163.62,125.46 163.62,125.85 163.33,126.14 163.33,126.36 163.52,126.55 163.52,126.92 163.33,127.11 163.33,127.5 163.16,127.68 162.28,127.68 162.1,127.86 162.1,128.29 162.27,128.46 162.39,128.46 162.4,128.47 162.55,128.47 162.73,128.64 162.73,129.02 162.61,129.15 162.61,129.45 162.73,129.57 162.73,130.88 162.86,131.01
  TOP w0.279: 162.86,131.01 163.17,131.32 163.17,131.68 162.83,132.02 162.38,132.02 162.11,132.29 162.11,132.87 162.38,133.14 162.89,133.14 v1(163.17,133.42) 163.21,133.46 163.21,133.76 163.21,134.14 164.34,135.26 164.34,136.64 164.62,136.92 164.97,136.92 165.45,136.44 165.96,136.44 166.27,136.75 166.27,137.18 166.3,137.21 v2(166.3,137.33)
  L3 w0.127: v2(175.79,144.8) 175.79,143.57 174.66,142.45 174.66,140.28 172.61,138.23 171.72,138.23 171.14,137.65 170.33,137.65 170.2,137.52 170.2,137.33 170.09,137.22 169.76,137.22 169.64,137.33 169.64,137.52 169.52,137.65 169.15,137.65 168.71,137.22 168,137.22 167.88,137.33 v2(166.3,137.33) 166.3,137.53 166.17,137.66 165.87,137.66 165.75,137.53 165.75,137.34 165.62,137.22 165.36,137.22 165.24,137.34 165.24,137.53 165.11,137.66 164.86,137.66 164.73,137.53 164.73,137.34 164.6,137.22 164.35,137.22 164.22,137.34 164.22,137.53 164.09,137.66 163.84,137.66 163.71,137.53 163.71,137.34 163.59,137.22 163.33,137.22 163.21,137.34 163.21,137.53 163.08,137.66 162.86,137.66 160.47,140.04 160.47,140.76 160.35,140.89 160.09,140.89 159.97,141.01 159.97,141.49 160.27,141.8 160.27,142.66 160.06,142.88 160.06,143.22 159.93,143.35 159.56,143.35 159.43,143.48 159.43,143.73 159.56,143.86 159.84,143.86 159.97,143.98 159.97,144.17 v2(159.67,144.47)
  BOTTOM w0.14: v2(159.67,144.47) 159.32,144.47 159.18,144.33 159.18,144.22 158.94,143.97 158.94,143.69 159.04,143.59 VRAM2.M7 ; v2(175.79,144.8) 176.09,145.1 176.09,145.91 176.39,146.21 VRAM4.M7
  BOTTOM w0.279: v2(163.94,122.31) 163.94,121.99 164.28,121.64 GPU1.L17
MCT0: length 13.2
  TOP w0.508: XF3102.3 22.81,57.73 23.83,56.7 23.83,48.99 22.82,47.97 RN3101.1
MCT1: length 9
  TOP w0.305: RN3101.2 22.17,48.22 22.22,48.28
  TOP w0.508: XF3102.4 22.55,53.92 23.18,53.28 23.18,49.24 22.22,48.28
MCT2: length 13.7
  TOP w0.305: v3(22.43,49.57) 21.67,48.81 RN3101.3
  BOTTOM w0.508: v3(22.43,49.57) 23.82,50.97 23.82,56.71 22.81,57.73 XF3101.4
MCT3: length 9.4
  TOP w0.508: v3(21.54,49.6) 21.02,49.08 RN3101.4
  BOTTOM w0.508: XF3101.3 22.55,53.92 23.19,53.28 23.19,51.38 21.54,49.73 v3(21.54,49.6)
MDA0: length 46.3
  TOP w0.178: v2(154.19,147.2) 154.59,147.59 VRAM1.F8 ; v2(152.75,123.21) 152.15,123.21 v1(151.95,123.01)
  L4 w0.165: v2(154.19,147.2) 154.69,147.69 155.19,147.69 155.35,147.86 155.35,148.22 155.19,148.38 154.84,148.38 154.67,148.55 154.67,148.89 154.84,149.06 155.14,149.06 155.32,149.24 155.32,149.52 154.92,149.92 150.27,149.92 147,146.65 147,135.37 148.36,134.01 148.36,129.2 149.66,127.9 149.66,125.51 150.19,124.99 150.19,124.32 151.31,123.21 v2(152.75,123.21)
  BOTTOM w0.178: v2(152.75,123.21) 153.19,122.77 154.09,122.77 154.14,122.81 156.32,122.81 GPU1.K27
MDA1: length 45.6
  TOP w0.178: v1(153.01,122.39) 153.38,122.77 v2(153.38,123.21) ; VRAM1.H8 156.56,147.96 156.56,148.86 v2(156.61,148.91)
  L4 w0.165: v2(153.38,123.21) 153.22,123.05 153.22,123.04 152.91,122.74 151.09,122.74 149.19,124.64 149.19,127.7 147.89,129 147.89,133.81 146.53,135.17 146.53,146.85 150.08,150.39 155.11,150.39 156.38,149.13 156.4,149.13 v2(156.61,148.91)
  BOTTOM w0.178: GPU1.J29 155.07,123.66 154.14,123.66 154.13,123.68 153.83,123.68 153.39,123.24 153.39,123.22 v2(153.38,123.21)
MDA2: length 45.3
  TOP w0.178: v1(151.11,123.89) 151.41,123.89 v2(151.82,124.3) ; v2(154.15,146.21) 154.59,146.65 VRAM1.F7
  L4 w0.165: v2(151.82,124.3) 151.54,124.3 151.13,124.71 151.13,125.37 150.6,125.9 150.6,126.97 150.78,127.14 151.07,127.14 151.25,127.32 151.25,128.66 150.81,129.09 149.93,129.09 149.3,129.73 149.3,134.4 147.94,135.76 147.94,136.16 148.15,136.37 148.15,136.88 147.94,137.09 147.94,137.55 148.11,137.71 148.28,137.71 148.46,137.89 148.46,138.19 148.28,138.37 148.11,138.37 147.94,138.54 147.94,138.87 148.11,139.03 148.33,139.03 148.5,139.2 148.5,139.53 148.33,139.69 148.11,139.69 147.94,139.86 147.94,140.19 148.11,140.35 148.33,140.35 148.5,140.52 148.5,140.85 148.33,141.01 148.11,141.01 147.94,141.18 147.94,141.51 148.11,141.67 148.33,141.67 148.5,141.84 148.5,142.17 148.33,142.33 148.11,142.33 147.94,142.5 147.94,142.83 148.11,142.99 148.33,142.99 148.5,143.16 148.5,143.49 148.33,143.65 148.11,143.65 147.94,143.82 147.94,144.15 148.11,144.31 148.33,144.31 148.5,144.48 148.5,144.81 148.33,144.98 148.11,144.98 147.94,145.14 147.94,146.26 149.85,148.18 150.37,148.18 150.54,148 150.54,147.77 150.9,147.41 151.53,147.41 151.71,147.24 151.71,146.39 151.89,146.21 v2(154.15,146.21)
  BOTTOM w0.178: v2(151.82,124.3) 151.48,124.3 151.31,124.48 151.31,124.99 151.48,125.16 152.7,125.16 152.88,124.99 152.88,124.5 153.14,124.24 153.97,124.24 154.14,124.41 154.72,124.41 GPU1.H30
MDA3: length 44.9
  TOP w0.178: VRAM1.H7 155.62,146.22 v2(155.39,146.22)
  L4 w0.165: v2(155.39,146.22) 154.86,146.76 153.92,146.76 153.74,146.94 153.74,147.9 153.57,148.07 153.24,148.07 153.06,147.9 153.06,146.94 152.88,146.76 152.38,146.76 152.14,146.99 152.14,149.32 152,149.45 150.47,149.45 147.47,146.46 147.47,135.56 148.83,134.2 148.83,129.39 149.6,128.62 150.62,128.62 150.78,128.47 150.78,127.76 150.62,127.6 150.31,127.6 150.13,127.42 150.13,125.71 150.66,125.18 150.66,124.52 151.37,123.81 v2(152.22,123.81)
  BOTTOM w0.178: GPU1.H32 154.21,123.96 153.72,123.96 153.57,123.81 v2(152.22,123.81) 152.22,123.77 151.97,123.51 v1(151.2,123.51)
MDA4: length 43.9
  TOP w0.178: VRAM1.H3 155.6,144.18 v2(155.26,144.18)
  L4 w0.165: v2(155.26,144.18) 154.98,144.18 154.53,143.73 154.53,142.14 154.71,141.96 155.29,141.96 155.47,142.14 155.47,142.51 155.65,142.69 155.97,142.69 156.15,142.51 156.15,142.21 156.41,141.96 156.42,141.96 156.6,141.78 156.6,141.41 156.44,141.25 155.88,141.25 155.7,141.07 155.7,140.09 155.52,139.91 152.93,139.91 152.75,139.73 152.75,138.37 152.93,138.19 153.26,138.19 153.44,138.37 153.44,138.9 153.62,139.08 153.95,139.08 154.13,138.9 154.13,137.66 153.95,137.48 153.08,137.48 152.91,137.3 152.91,136.97 153.08,136.8 153.95,136.8 154.13,136.62 154.13,131.13 154.3,130.95 154.79,130.95 154.99,131.16 154.99,131.36 155.17,131.54 155.83,131.54 156,131.36 156,131.11 155.73,130.83 155.73,130.62 156,130.34 156,129.96 155.53,129.49 155.53,127.94 155.71,127.77 157,127.77 157.17,127.59 157.17,127.26 157,127.08 155.65,127.08 155.39,126.83 155.39,124.55 155.22,124.38 154.71,124.38 154.53,124.55 154.53,125.17 154.35,125.34 153.86,125.34 v2(153.38,124.86)
  BOTTOM w0.178: v2(153.38,124.86) 153.81,125.29 154.12,125.29 154.14,125.27 155.06,125.27 GPU1.G29
MDA5: length 45.3
  TOP w0.178: v1(154.73,125.06) 154.81,125.14 v2(156.22,125.14) ; VRAM1.G2 155.77,142.41 155.77,141.89 156.41,141.25 156.42,141.25 156.89,140.78 v2(157.02,140.78)
  L4 w0.165: v2(156.22,125.14) 156.22,125.49 155.85,125.86 155.85,126.43 156.03,126.61 157.35,126.61 157.66,126.91 157.66,128.06 157.48,128.23 157.34,128.23 157.34,128.24 156.64,128.24 156.48,128.4 156.48,128.71 156.64,128.87 156.87,128.87 157.05,129.05 157.05,129.33 156.49,129.89 156.49,131.84 156.31,132.02 154.76,132.02 154.6,132.18 154.6,132.57 154.76,132.73 156.41,132.73 156.59,132.91 156.59,133.24 156.41,133.42 154.84,133.42 154.66,133.6 154.66,133.93 154.84,134.1 156.46,134.1 156.64,134.28 156.64,134.6 156.46,134.78 154.79,134.78 154.61,134.96 154.61,135.26 154.79,135.44 156.51,135.44 156.69,135.62 156.69,135.92 156.51,136.1 154.76,136.1 154.6,136.26 154.6,136.6 154.76,136.76 156.36,136.76 156.54,136.94 156.54,137.24 156.36,137.42 154.76,137.42 154.6,137.58 154.6,137.92 154.76,138.08 156.39,138.08 156.56,138.26 156.56,138.56 156.39,138.74 154.79,138.74 154.61,138.92 154.61,139.22 154.79,139.4 156.32,139.4 156.49,139.57 156.49,140.25 v2(157.02,140.78)
  BOTTOM w0.178: GPU1.F28 155.89,125.47 v2(156.22,125.14)
MDA6: length 43.4
  TOP w0.178: VRAM1.F2 154.17,142.37 154.17,141.83 153.87,141.53 153.87,141.17 153.84,141.14 153.84,140.79 154.15,140.48 v2(155.04,140.48)
  L4 w0.165: v2(155.04,140.48) 154.94,140.38 153.11,140.38 152.93,140.56 152.93,140.89 153.11,141.07 153.76,141.07 154.05,141.36 154.05,142.94 153.87,143.12 153.11,143.12 152.93,142.94 152.93,141.92 152.75,141.74 152.37,141.74 152.12,141.49 152.12,140.51 152.28,140.34 152.28,138.18 152.4,138.06 152.4,137.02 152.12,136.74 152.12,136.39 152.29,136.21 153.48,136.21 153.66,136.03 153.66,135.64 153.49,135.48 152.45,135.48 152.28,135.31 152.28,134.98 152.45,134.82 153.49,134.82 153.66,134.65 153.66,134.32 153.49,134.15 152.45,134.15 152.28,133.99 152.28,133.66 152.45,133.49 153.49,133.49 153.66,133.33 153.66,132.86 153.48,132.68 152.25,132.68 151.92,132.34 151.92,131.79 152.09,131.61 152.55,131.61 152.91,131.97 153.48,131.97 153.66,131.79 153.66,130.77 153.52,130.62 153.13,130.62 152.8,130.3 152.8,130 153.01,129.79 154.36,129.79 154.53,129.62 154.53,128.21 154.71,128.03 154.89,128.03 155.06,127.86 155.06,127.47 154.89,127.3 154.23,127.3 154.05,127.12 154.05,126.74 154.23,126.56 154.76,126.56 154.94,126.38 154.94,126.05 154.76,125.87 153.82,125.87 v2(153.73,125.78)
  BOTTOM w0.178: GPU1.F32 154.19,125.74 153.77,125.74 v2(153.73,125.78)
MDA7: length 44.4
  TOP w0.178: v1(152.47,126) 152.73,125.75 153.04,125.75 v2(153.09,125.8) ; VRAM1.E3 153.41,143.97 153.02,143.97 v2(152.6,144.39)
  L4 w0.165: v2(153.09,125.8) 152.52,125.8 152.35,125.98 152.35,126.36 152.52,126.53 153.01,126.53 153.19,126.71 153.19,127.42 153.65,127.88 153.65,128.85 153.39,129.11 153.03,129.11 151.47,130.67 151.34,130.67 150.92,131.09 150.92,132.28 151.11,132.47 151.37,132.47 151.81,132.91 151.81,136.03 151.55,136.29 151.15,136.29 150.98,136.11 150.98,135.81 150.8,135.63 150.3,135.63 150.07,135.85 150.07,136.86 150.24,137.02 151.74,137.02 151.93,137.21 151.93,137.54 151.79,137.68 150.24,137.68 150.07,137.85 150.07,138.18 150.24,138.34 151.66,138.34 151.81,138.49 151.81,138.85 151.66,139 150.24,139 150.07,139.17 150.07,139.5 150.24,139.66 151.64,139.66 151.81,139.84 151.81,140.15 151.64,140.32 150.24,140.32 150.07,140.49 150.07,140.82 150.24,140.98 151.47,140.98 151.64,141.15 151.64,142.05 151.81,142.23 152.32,142.23 152.5,142.41 152.5,142.74 152.32,142.92 151.58,142.92 151.43,143.07 151.43,143.45 151.58,143.6 153.41,143.6 153.59,143.78 153.59,143.97 153.41,144.15 153.36,144.15 153.12,144.39 v2(152.6,144.39)
  BOTTOM w0.178: v2(153.09,125.8) 153.1,125.8 153.55,126.25 153.9,126.25 154.13,126.02 154.71,126.02 GPU1.F30
MDA8: length 40.7
  TOP w0.178: VRAM1.A7 150.43,146.63 149.96,146.63 149.58,147.01 149.58,148.12 149.4,148.3 148.69,148.3 v1(146.93,146.54) 146.37,145.98 146.37,136.86 147.18,136.05 147.18,134.7 v2(153.21,128.67)
  BOTTOM w0.178: v2(153.21,128.67) 149.91,128.67 149.73,128.49 149.73,128.16 149.55,127.98 149.12,127.98 148.94,128.16 148.94,129.13 149.2,129.38 152.45,129.38 152.63,129.56 154.2,129.56 154.38,129.38 154.38,128.76 154.7,128.44 154.7,127.63 GPU1.C30
MDA9: length 41.9
  TOP w0.178: VRAM1.C8 151.94,147.59 151.76,147.77 151.76,148.56 152.12,148.91 152.12,149.24 151.97,149.39 148.3,149.39 145.32,146.41 145.32,135.68 145.5,135.5 145.92,135.5 146.1,135.32 146.1,134.97 145.92,134.79 145.5,134.79 145.32,134.61 145.32,134.23 145.5,134.05 145.79,134.05 145.97,133.88 145.97,133.55 146.34,133.18 146.59,133.18 146.72,133.31 146.97,133.31 147.22,133.05 147.22,132.8 147.09,132.67 147.09,132.42 147.35,132.17 147.6,132.17 147.73,132.3 147.98,132.3 148.23,132.05 148.23,131.8 148.1,131.67 148.1,131.42 v1(149.93,129.58) 150.04,129.48 150.8,129.48 152.58,127.7 153.01,127.7 153.18,127.53 153.18,127.06 153.19,127.06 153.19,126.98 153.36,126.8 154.4,126.8 154.58,126.62 154.58,126.31 154.76,126.13 155.57,126.13 155.98,126.53 156.92,126.53 157.1,126.36 v2(157.1,126.04)
  BOTTOM w0.178: GPU1.F27 156.69,125.82 156.91,126.04 v2(157.1,126.04)
MDA10: length 40.8
  TOP w0.178: VRAM1.A3 150.27,143.91 149.88,143.91 149.63,143.65 149.63,138.24 149.81,138.07 150.16,138.07 150.34,138.24 150.34,140.2 150.51,140.36 150.86,140.36 151.06,140.16 151.06,138.24 151.24,138.07 152.07,138.07 152.25,137.89 152.25,137.53 152.07,137.36 149.93,137.36 149.76,137.18 149.76,136.82 149.93,136.64 152.07,136.64 152.25,136.47 152.25,135.38 152.42,135.2 154.46,135.2 154.62,135.04 154.62,134.65 154.46,134.48 152.42,134.48 152.25,134.31 152.25,133.95 152.42,133.77 154.44,133.77 154.62,133.6 154.62,133.24 154.44,133.06 153.59,133.06 153.41,132.88 153.41,132.53 153.59,132.35 154.32,132.35 154.94,131.73 v1(154.94,131.18) 154.94,130.7 155.7,129.94 156.31,129.94 156.49,129.76 156.49,129.56 156.66,129.38 156.87,129.38 157.05,129.2 157.05,128.49 156.77,128.21 156.77,127.78 156.59,127.6 156.22,127.6 156.04,127.78 v2(156.04,128.7)
  BOTTOM w0.178: GPU1.A28 155.89,128.55 v2(156.04,128.7)
MDA11: length 41.2
  TOP w0.178: VRAM1.C3 152.08,143.59 151.64,144.04 151.64,144.37 151.43,144.57 149.73,144.57 148.59,145.71 148.27,145.71 147.9,145.34 147.9,144.7 148.07,144.53 148.73,144.53 149.08,144.17 149.08,144.05 149.08,138.57 148.91,138.4 148.05,138.4 147.9,138.24 147.9,137.81 148.05,137.66 149.04,137.66 149.22,137.48 149.22,137.02 149.04,136.85 148.89,136.85 148.71,136.67 148.71,135.34 148.89,135.17 149.3,135.17 149.48,135.35 149.48,135.92 149.68,136.12 151.51,136.12 151.69,135.95 151.69,135.58 151.51,135.4 150.44,135.4 150.26,135.22 150.26,134.92 149.93,134.59 149.93,134.12 150.51,133.55 150.82,133.55 151,133.72 151,134.51 151.18,134.69 151.55,134.69 151.72,134.51 151.72,133.24 151.9,133.06 152.73,133.06 152.89,132.9 v1(152.89,132.43) 152.89,131.96 153.03,131.82 153.92,131.82 154.18,131.56 154.18,130.6 153.82,130.24 153.82,129.84 154,129.66 154.4,129.66 154.49,129.75 155.16,129.75 155.57,129.33 v2(156.01,129.33)
  BOTTOM w0.102: v2(156.01,129.33) 156.25,129.33 156.44,129.14 156.44,128.53 156.25,128.33 156.25,127.99 156.46,127.78 156.46,127.48 156.22,127.24 GPU1.C28
MDA12: length 41.6
  TOP w0.178: v2(156.98,130.02) 156.63,130.37 155.95,130.37 155.55,130.78 155.55,130.9 155.53,130.92 155.53,131.87 155.14,132.26 v1(155.14,134.03) 155.14,135.53 154.94,135.72 152.96,135.72 152.78,135.9 152.78,136.26 152.96,136.43 154.94,136.43 155.12,136.61 155.12,136.97 154.94,137.15 152.96,137.15 152.78,137.32 152.78,137.71 152.96,137.89 157.07,137.89 157.25,138.07 157.25,139.2 157.07,139.37 156.66,139.37 156.53,139.25 156.53,138.78 156.35,138.6 156,138.6 155.82,138.78 155.82,139.25 155.69,139.37 155.23,139.37 155.11,139.25 155.11,138.78 154.93,138.6 154.57,138.6 154.4,138.78 154.4,139.25 154.27,139.37 153.9,139.37 153.72,139.2 153.72,138.78 153.54,138.6 153.19,138.6 153.01,138.78 153.01,139.9 152.83,140.07 152.47,140.07 152.3,139.9 152.3,138.78 152.12,138.6 151.76,138.6 151.58,138.78 151.58,140.38 151.07,140.89 150.4,140.89 150.22,141.06 150.22,142.42 VRAM1.A2
  BOTTOM w0.102: GPU1.E27 156.97,126.44 157.15,126.62 157.15,127.02 157.02,127.14 157.02,127.61 157.09,127.68 157.18,127.81 157.22,127.94 157.22,128.01 157.22,128.16 157.19,128.25 157.14,128.35 157.08,128.42 157.08,129.45 157.17,129.54 157.17,129.83 v2(156.98,130.02)
MDA13: length 42.7
  TOP w0.178: VRAM1.D7 153.36,147.16 153.36,149.35 152.8,149.91 148.08,149.91 144.8,146.63 144.8,133.98 v1(147.35,131.43) 149.82,128.96 150.58,128.96 151.99,127.55 151.99,127.29 152.99,126.28 153.86,126.28 154.17,125.97 154.17,125.95 154.53,125.6 156.39,125.6 156.67,125.32 156.67,124.88 157.09,124.46 v2(157.09,124.45)
  BOTTOM w0.178: GPU1.G26 157.49,124.84 v2(157.09,124.45)
MDA14: length 41.6
  TOP w0.178: VRAM1.C2 151.82,142.42 151.82,141.78 151.58,141.55 151.58,141.11 152.04,140.66 153.23,140.66 153.68,140.21 153.68,140.07 153.86,139.9 157.3,139.9 157.55,140.15 157.55,141.42 157.73,141.6 158.44,141.6 159.08,140.95 159.08,140.66 157.77,139.35 157.77,137.8 157.33,137.36 155.85,137.36 155.67,137.18 155.67,136.77 155.85,136.59 157.12,136.59 157.3,136.42 157.3,136 157.12,135.82 155.83,135.82 155.66,135.65 155.66,135.27 155.83,135.11 157.12,135.11 157.3,134.93 157.3,134.57 157.12,134.4 155.85,134.4 155.67,134.22 155.67,133.86 155.85,133.68 157.12,133.68 157.3,133.51 157.3,133.15 157.12,132.97 155.88,132.97 155.7,132.8 155.7,132.44 155.88,132.26 157.12,132.26 157.3,132.08 157.3,131.73 157.12,131.55 156.23,131.55 156.06,131.37 156.06,131.02 156.23,130.84 157.5,130.84 v1(157.72,130.62) 157.93,130.41 157.93,129.99 157.68,129.74 157.68,129.48 v2(157.51,129.31)
  BOTTOM w0.102: GPU1.D26 157.81,126.84 157.96,126.99 157.96,127.53 157.82,127.67 157.82,127.74 157.76,127.89 157.76,128.26 157.93,128.44 157.93,129.18 157.8,129.31 v2(157.51,129.31)
MDA15: length 42.7
  TOP w0.178: v2(157.67,126.31) 157.76,126.31 157.93,126.49 157.93,127.53 157.76,127.7 157.4,127.7 157.22,127.53 157.22,127.25 157.05,127.07 155.8,127.07 155.62,127.25 155.62,128.06 155.45,128.23 155.08,128.23 154.91,128.06 154.91,127.47 154.73,127.3 154.38,127.3 154.2,127.47 154.2,128.31 154.02,128.49 153.66,128.49 153.39,128.22 152.79,128.22 150.83,130.18 150.58,130.18 150.45,130.05 150.2,130.05 149.95,130.3 149.95,130.55 150.16,130.76 150.16,130.99 149.88,131.26 149.65,131.26 149.42,131.03 149.22,131.03 148.92,131.33 148.92,131.54 149.07,131.69 149.07,132.07 148.28,132.86 147.98,132.86 147.74,133.09 147.74,133.4 147.24,133.9 146.68,133.9 146.41,134.17 146.41,134.37 146.66,134.61 146.66,134.92 146.66,135.83 146.45,136.03 146.02,136.03 145.84,136.21 v1(145.84,137.86) 145.84,146.19 148.52,148.87 149.95,148.87 150.11,148.71 150.11,147.36 150.29,147.18 151.21,147.18 151.39,147.36 VRAM1.B8
  BOTTOM w0.178: v2(157.67,126.31) 157.67,125.98 158.01,125.64 GPU1.F25
MDA16: length 29
  BOTTOM w0.102: 158.34,129.69 158.34,128.09 GPU1.A25
  BOTTOM w0.178: VRAM2.A3 150.31,147.07 149.74,147.07 149.58,146.91 149.58,146.27 149.3,145.99 149.05,145.99 148.88,146.16 148.63,146.16 148.38,145.91 148.38,145.66 148.56,145.48 148.56,145.25 148.29,144.98 148.06,144.98 147.88,145.16 147.63,145.16 147.38,144.9 147.38,144.65 147.54,144.48 147.54,144.23 147.12,143.81 v1(147.12,140.94) 147.12,138.08 153.75,131.45 156.12,131.45 156.83,130.74 157.29,130.74 158.34,129.69
MDA17: length 29.6
  BOTTOM w0.102: 157.96,129.68 158.13,129.5 158.13,128.35 157.96,128.18 157.96,128.01 arc(157.98,127.91) 158.03,127.83 158.06,127.8 158.29,127.57 GPU1.C25
  BOTTOM w0.178: 157.96,129.68 157.17,130.46 156.38,130.46 155.91,130.93 153.54,130.93 146.6,137.87 146.6,144.87 v1(147.72,145.99) 149.32,147.59 VRAM2.A2
MDA18: length 29.9
  BOTTOM w0.102: 158.44,129.98 158.58,129.85 158.58,128.22 158.62,128.18 158.62,126.77 GPU1.E25
  BOTTOM w0.178: VRAM2.C2 151.77,147.17 151.77,146.48 151.12,145.83 149.88,145.83 147.64,143.6 v1(147.64,142.49) 147.64,138.3 153.97,131.97 156.34,131.97 157.29,131.02 157.4,131.02 158.44,129.98
MDA19: length 29.9
  BOTTOM w0.102: 159.2,129.13 159.39,128.94 159.39,128.57 159.36,128.53 159.36,127.84 159.37,127.83 arc(159.41,127.77) 159.42,127.7 159.42,127.6 arc(159.4,127.51) 159.35,127.43 159.31,127.39 159.09,127.17 GPU1.D24
  BOTTOM w0.178: VRAM2.C3 152.19,146.5 151,145.31 150.09,145.31 148.16,143.38 v1(148.16,139.46) 148.16,138.52 148.53,138.15 148.78,138.15 148.97,138.33 149.22,138.33 149.47,138.08 149.47,137.83 149.29,137.64 149.29,137.39 149.54,137.14 149.79,137.14 149.95,137.3 150.2,137.3 150.45,137.04 150.45,136.79 150.29,136.64 150.29,136.39 154.18,132.5 156.55,132.5 158.9,130.15 158.9,129.43 159.2,129.13
MDA20: length 30.2
  BOTTOM w0.102: 160.28,129.42 160.28,128.42 160.42,128.28 160.42,127.84 160.36,127.78 160.36,126.91 GPU1.E23
  BOTTOM w0.178: 160.28,129.42 160.28,130.94 157.05,134.18 157.05,135.12 156.87,135.3 156.44,135.3 156.26,135.12 156.26,134.31 156.08,134.13 155.7,134.13 155.39,134.43 154.91,134.43 154.73,134.61 154.73,135.09 154.91,135.27 155.37,135.27 155.55,135.45 v1(155.55,136.11) 155.55,136.69 155.27,136.97 154.71,136.97 154.53,136.8 154.53,136.03 154.4,135.9 153.82,135.9 153.63,136.1 153.63,137.14 152.95,137.82 152.95,138.07 153.26,138.38 153.26,138.63 153.01,138.88 152.75,138.88 152.45,138.57 152.19,138.57 149.7,141.07 149.7,142.7 VRAM2.A7
MDA21: length 30.6
  BOTTOM w0.102: GPU1.F23 159.51,126.02 159.51,127.31 arc(159.59,127.43) 159.62,127.58 159.62,127.77 arc(159.61,127.85) 159.56,127.92 159.56,128.45 159.59,128.48 159.59,129.2 159.26,129.53
  BOTTOM w0.178: 159.26,129.53 159.18,129.61 159.18,130.61 156.77,133.02 154.4,133.02 152.09,135.32 152.09,135.58 152.34,135.82 152.34,136.08 152.09,136.33 151.84,136.33 151.59,136.08 151.34,136.08 150.97,136.45 150.97,137.44 v1(150.31,138.09) 149.56,138.85 148.89,138.85 148.68,139.06 148.68,143.16 150.31,144.79 150.53,144.79 150.69,144.95 151.41,144.95 152.77,143.59 VRAM2.D7
MDA22: length 30.3
  BOTTOM w0.102: 160.91,129.69 161.19,129.41 161.19,128.78 160.96,128.54 160.96,127.84 arc(161,127.77) 161.02,127.69 161.02,127.58 arc(161.01,127.51) 160.97,127.45 160.69,127.17 GPU1.D22
  BOTTOM w0.178: 160.91,129.69 160.64,129.97 160.64,131.33 160.33,131.63 160.33,131.88 161.1,132.65 161.1,132.9 160.84,133.15 160.59,133.15 159.83,132.39 159.58,132.39 159.32,132.64 159.32,132.89 160.05,133.62 160.05,133.87 159.8,134.12 159.55,134.12 158.82,133.39 158.57,133.39 157.57,134.39 157.57,135.41 157.12,135.86 156.28,135.86 156.11,136.03 156.11,137.91 155.93,138.09 155.32,138.09 155.14,137.91 155.14,137.67 154.96,137.49 154.44,137.49 v1(154.17,137.77) 153.78,138.16 153.78,139.02 153.4,139.4 152.1,139.4 151.72,139.79 151.72,140.04 151.9,140.22 151.9,140.47 151.65,140.72 151.39,140.72 151.21,140.54 150.96,140.54 150.22,141.28 150.22,142.14 150.45,142.37 150.97,142.37 VRAM2.B8
MDA23: length 30.8
  BOTTOM w0.102: 161.16,129.84 161.4,129.6 161.4,128.63 161.16,128.39 161.16,127.92 arc(161.21,127.85) 161.22,127.77 161.22,127.5 arc(161.21,127.43) 161.17,127.36 161.16,127.36 161.16,125.97 GPU1.F21
  BOTTOM w0.178: 161.16,129.84 161.16,131.97 161.69,132.51 162.2,132.51 162.38,132.68 162.38,134.65 162.2,134.83 161.62,134.83 161.44,134.65 161.44,133.93 161.26,133.75 160.86,133.75 160.68,133.93 160.68,134.65 160.5,134.83 159.52,134.83 158.84,134.14 158.56,134.14 158.21,134.48 v1(158.21,134.99) 158.21,135.5 157.34,136.38 156.77,136.38 156.63,136.52 156.63,138.13 155.88,138.88 155.88,139.23 155.7,139.41 155.27,139.41 155.09,139.23 155.09,138.6 154.84,138.35 154.48,138.35 154.3,138.52 154.3,139.24 153.61,139.92 153.25,139.92 151.82,141.35 151.82,142.42 VRAM2.C8
MDA24: length 42.8
  L3 w0.165: v2(161.95,126.1) 161.21,126.1 160.51,126.8 155.71,126.8 152.63,129.88 152.1,129.88 147.52,134.46 147.52,146.62 151.27,150.37 154,150.37 154.99,149.39 v2(154.99,147.19)
  BOTTOM w0.178: v2(154.99,147.19) VRAM2.G2 ; v2(161.95,126.1) 161.83,126.1 GPU1.E21
MDA25: length 43.1
  L3 w0.165: v2(162.56,126.25) 161.99,126.83 161.22,126.83 160.65,127.4 156.06,127.4 155.88,127.58 155.88,128.08 156.06,128.26 156.33,128.26 156.64,128.57 156.64,129.43 156.22,129.85 154.34,129.85 152.44,131.75 150.9,131.75 150.32,132.33 147.99,134.65 147.99,146.43 150.56,149 150.56,149.01 150.82,149.26 150.83,149.26 151.46,149.9 153.81,149.9 v2(154.25,149.46)
  BOTTOM w0.178: v2(162.56,126.25) 162.29,126.52 GPU1.D20 ; v2(154.25,149.46) 154.96,148.75 154.96,147.96 VRAM2.F2
MDA26: length 43.8
  L3 w0.165: v2(163.89,126.28) 164.36,126.28 164.54,126.46 164.54,127.17 164.36,127.35 161.44,127.35 160.81,127.98 159.08,127.98 158.27,128.8 158.27,129.76 157.57,130.46 156.79,130.46 156.74,130.41 154.45,130.41 152.64,132.22 151.09,132.22 148.46,134.85 148.46,146.23 149.78,147.55 151.84,147.55 152.02,147.73 152.02,148.25 151.56,148.71 151.56,149.12 151.74,149.29 152.46,149.29 v2(152.61,149.44)
  BOTTOM w0.178: GPU1.F19 163.25,125.64 v2(163.89,126.28) ; VRAM2.E3 153.41,147.17 153.41,148.63 v2(152.61,149.44)
MDA27: length 43.4
  L3 w0.165: v2(163.53,130.43) 163.14,130.81 163.14,131.32 162.52,131.94 159.1,131.94 158.41,132.62 157.8,132.62 157.29,133.13 157.29,134.97 156.54,135.73 155.85,135.73 155.67,135.55 155.67,135.19 155.5,135.01 155.02,135.01 154.33,135.7 153.08,135.7 152.91,135.53 152.91,134.48 152.73,134.31 152.4,134.31 152.22,134.48 152.22,136.16 152.04,136.34 151.53,136.34 151.36,136.16 151.36,135.55 151.18,135.37 150.83,135.37 150.59,135.61 150.59,136.97 150.77,137.14 151.58,137.14 151.76,137.32 151.76,137.63 151.58,137.8 150.75,137.8 150.57,137.98 150.57,138.29 150.75,138.46 151.78,138.46 151.94,138.63 151.94,138.96 151.78,139.12 150.72,139.12 150.56,139.28 150.56,139.69 150.72,139.85 151.89,139.85 152.07,140.03 152.07,141.57 152.25,141.75 152.75,141.75 152.93,141.93 152.93,142.28 152.75,142.46 152.25,142.46 152.07,142.64 152.07,143.01 152.25,143.19 153.52,143.19 153.69,143.01 153.69,142.71 153.97,142.44 154.18,142.44 154.35,142.61 154.35,143.01 154.53,143.19 v2(154.99,143.19)
  BOTTOM w0.102: v2(163.53,130.43) 163.09,129.99 163.09,129.02 163.07,129 163.07,128.27 163.09,128.25 GPU1.A19
  BOTTOM w0.178: VRAM2.F7 154.59,143.59 v2(154.99,143.19) ; v1(163.81,131.04) 163.8,131.03 163.76,131.03 163.53,130.8 v2(163.53,130.43)
MDA28: length 42.9
  L3 w0.165: v2(154.99,142.4) 154.99,142.05 154.81,141.88 154.07,141.88 153.9,141.7 153.9,141.21 153.55,140.86 152.73,140.86 152.55,140.68 152.55,140.29 152.72,140.12 153.85,140.12 154.02,139.94 154.02,139.64 153.85,139.46 152.72,139.46 152.55,139.3 152.55,138.96 152.72,138.8 153.87,138.8 154.05,138.62 154.05,138.32 153.87,138.14 152.72,138.14 152.55,137.97 152.55,136.5 152.76,136.29 153.13,136.29 153.31,136.47 153.31,137.25 153.49,137.43 153.85,137.43 154.02,137.25 154.02,136.45 154.2,136.27 154.58,136.27 154.76,136.45 154.76,139.59 154.94,139.77 155.29,139.77 155.47,139.59 155.47,137.86 155.65,137.69 156.18,137.69 156.36,137.51 156.36,137.18 156.18,137 155.65,137 155.47,136.82 155.47,136.45 155.65,136.27 156.67,136.27 157.76,135.17 157.76,133.33 158,133.09 158.61,133.09 159.29,132.41 162.72,132.41 163.76,131.36 163.76,130.94 163.96,130.74 163.96,129.62 163.51,129.17 v2(163.51,129.13)
  BOTTOM w0.102: v2(163.51,129.13) 163.28,128.9 163.28,128.35 163.42,128.21 163.42,127.31 GPU1.D18
  BOTTOM w0.178: v2(154.99,142.4) 154.6,142.79 VRAM2.F8
MDA29: length 44
  L3 w0.165: v2(163.51,129.79) 163.24,129.79 163.07,129.61 163.07,128.36 162.89,128.19 161.87,128.19 161.69,128.36 161.69,129.26 161.52,129.44 159.35,129.44 157.86,130.93 154.59,130.93 152.83,132.69 151.29,132.69 148.93,135.04 148.93,145.79 149.87,146.72 151.13,146.72 151.21,146.65 152.75,146.65 153.24,147.13 153.57,147.13 154.05,146.65 154.34,146.65 155.39,145.6 v2(155.54,145.6)
  BOTTOM w0.102: GPU1.F17 164.29,126.04 164.29,126.45 164.22,126.52 164.22,127.7 arc(164.2,127.78) 164.16,127.85 164.16,128.96 164.01,129.11 164.01,129.28 v2(163.51,129.79)
  BOTTOM w0.178: VRAM2.H3 156.19,146.25 v2(155.54,145.6)
MDA30: length 42.5
  L3 w0.165: v2(164.62,129.36) 165.1,129.36 165.28,129.54 165.28,129.97 164.7,130.54 164.7,131.75 164.34,132.12 164.34,132.45 164.5,132.61 164.5,133.27 164.68,133.44 165.91,133.44 166.09,133.62 166.09,134 165.91,134.18 164.69,134.18 164.51,134.36 164.51,134.71 164.69,134.89 165.83,134.89 166.01,135.07 166.01,135.65 165.83,135.83 164.72,135.83 164.41,135.53 163.85,135.53 163.5,135.88 162.99,135.88 162.63,135.53 161.8,135.53 161.62,135.7 161.62,136.8 161.44,136.97 161.03,136.97 160.86,136.8 160.86,135.84 160.68,135.67 160.07,135.67 159.89,135.84 159.89,136.67 159.71,136.85 159.31,136.85 159.13,136.67 159.13,135.73 158.95,135.55 158.71,135.55 158.34,135.92 158.34,136.33 158.05,136.62 157.65,136.62 157.45,136.81 157.45,137.14 157.63,137.32 157.97,137.32 158.15,137.49 158.15,138.13 158.15,138.13 158.15,138.22 158.33,138.4 158.72,138.4 158.9,138.22 158.9,137.79 159.08,137.61 159.48,137.61 159.66,137.79 159.66,139.01 159.48,139.18 158.54,139.18 158.37,139.36 158.37,140.66 158.19,140.83 157.81,140.83 157.63,140.66 157.63,139.16 157.45,138.98 157.03,138.98 156.86,139.16 156.86,140.19 v2(156.23,140.81)
  BOTTOM w0.114: GPU1.A17 164.69,129.29 v2(164.62,129.36)
  BOTTOM w0.178: VRAM2.H8 155.82,142.42 155.82,141.22 v2(156.23,140.81)
MDA31: length 44
  L3 w0.165: v2(164.62,129.99) 164.23,130.39 164.23,130.93 164.23,130.94 164.23,131.56 163.65,132.14 163.65,132.43 164.03,132.81 164.03,134.82 163.85,134.99 163.35,134.99 163.17,134.82 163.17,133.06 162.99,132.88 162.91,132.88 162.53,132.88 162.35,133.06 162.35,134.89 162.19,135.06 161.73,135.06 161.57,134.89 161.57,133.06 161.39,132.88 161.01,132.88 160.83,133.06 160.83,134.99 160.65,135.17 160.27,135.17 160.09,134.99 160.09,133.06 159.92,132.88 159.49,132.88 159.28,133.09 159.28,133.39 159.1,133.57 158.41,133.57 158.23,133.75 158.23,134.15 158.41,134.33 159.23,134.33 159.41,134.51 159.41,134.82 159.23,134.99 158.41,134.99 158.23,135.17 158.23,135.37 156.83,136.77 156.83,137.61 157.01,137.79 157.5,137.79 157.68,137.96 157.68,138.32 157.5,138.5 156.12,138.5 155.94,138.68 155.94,139.2 156.39,139.64 156.39,139.99 156.2,140.17 155.68,140.17 155.5,140.35 155.5,140.67 155.5,140.67 155.5,141.04 155.76,141.29 156.39,141.29 156.56,141.47 156.56,141.83 156.39,142 155.73,142 155.55,142.18 155.55,142.54 155.73,142.71 156.29,142.71 156.59,143.02 v2(156.59,143.19)
  BOTTOM w0.102: GPU1.C17 164.42,127.51 164.42,127.79 arc(164.41,127.86) 164.37,127.92 164.36,127.93 164.36,129.05 164.22,129.19 164.22,129.59 v2(164.62,129.99)
  BOTTOM w0.178: v1(165.02,130.95) 164.62,130.56 v2(164.62,129.99) ; v2(156.59,143.19) 156.59,143.19 VRAM2.H7
MDA32: length 46
  TOP w0.178: VRAM3.F8 180.82,142.42 180.82,141.22 v2(180.57,140.96)
  L3 w0.165: v2(165.7,130.6) 166.14,131.05 166.14,131.41 167.4,132.67 177.6,132.67 178.05,133.11 178.05,133.35 177.6,133.8 177.6,134.82 177.77,134.99 178.23,134.99 178.41,134.82 178.41,134.18 178.59,134 178.93,134 179.14,134.21 179.14,134.74 179.32,134.92 180.38,134.92 180.55,135.09 180.55,135.51 180.39,135.68 178.51,135.68 178.37,135.82 178.37,136.2 178.51,136.34 180.39,136.34 180.55,136.5 180.55,136.83 180.39,137 178.53,137 178.37,137.16 178.37,137.49 178.53,137.66 180.39,137.66 180.55,137.82 180.55,138.16 180.39,138.32 178.53,138.32 178.37,138.49 178.37,138.82 178.53,138.98 180.39,138.98 180.55,139.15 180.55,139.62 180.38,139.79 179.91,139.79 179.73,139.97 179.73,140.78 179.91,140.96 v2(180.57,140.96)
  BOTTOM w0.102: GPU1.E17 165.02,126.77 165.02,127.36 165.01,127.39 164.99,127.4 164.96,127.55 164.96,127.56 164.96,127.83 164.98,127.86 165.02,127.96 165.02,128.18 164.95,128.24 164.95,129.11 165.03,129.19 165.03,129.93 v2(165.7,130.6)
MDA33: length 45.5
  TOP w0.178: VRAM3.H7 179.59,143.6 v2(179.99,144)
  L3 w0.165: v2(179.99,144) 179.64,144 179.42,143.78 179.42,143.6 179.25,143.43 179.01,143.43 178.83,143.25 178.83,142.85 178.99,142.69 179.26,142.69 179.42,142.52 179.42,142.1 179.25,141.93 178.56,141.93 178.38,141.75 178.38,141.39 178.56,141.22 178.99,141.22 179.17,141.04 179.17,140.59 179,140.43 176.96,140.43 176.77,140.24 176.77,139.84 176.95,139.67 177.25,139.67 177.43,139.49 177.43,139.02 177.26,138.85 176.87,138.85 176.71,138.69 176.71,138.36 176.87,138.19 177.26,138.19 177.43,138.03 177.43,137.7 177.26,137.53 175.99,137.53 175.82,137.36 175.82,137.05 175.99,136.87 177.26,136.87 177.43,136.71 177.43,135.98 177.11,135.65 172.54,135.65 172.38,135.49 172.38,133.77 172.21,133.61 171.88,133.61 171.72,133.77 171.72,135.49 171.55,135.65 168.78,135.65 168.6,135.48 168.6,133.8 168.43,133.62 168.07,133.62 167.89,133.8 167.89,135.4 167.71,135.58 167.26,135.58 167.08,135.4 167.08,133.67 165.21,131.8 165.21,130.47 165.72,129.96 v2(165.72,129.84)
  BOTTOM w0.102: GPU1.D16 165.25,127.08 165.22,127.14 165.22,127.41 165.18,127.5 165.16,127.59 165.16,127.77 165.22,127.9 165.23,127.94 165.23,128.25 165.16,128.33 165.16,129.03 165.23,129.11 165.23,129.36 v2(165.72,129.84)
MDA34: length 46
  TOP w0.178: VRAM3.F7 181.59,143.19 v2(181.59,143.19)
  L3 w0.165: v2(165.72,129.21) 166.57,130.06 166.57,130.89 166.61,130.94 166.61,131.21 167.6,132.2 177.79,132.2 179.73,134.14 181,134.14 181.99,135.13 181.99,135.5 181.81,135.68 181.28,135.68 181.1,135.86 181.1,136.32 181.3,136.52 182.17,136.52 182.5,136.19 183.05,136.19 183.67,136.8 183.67,137.1 183.49,137.28 181.2,137.28 181.02,137.46 181.02,137.86 181.2,138.04 184.39,138.04 184.57,138.22 184.57,138.57 184.39,138.75 181.2,138.75 181.02,138.93 181.02,139.39 181.2,139.56 181.93,139.56 182.11,139.74 182.11,140.23 181.93,140.4 181.29,140.4 181.11,140.58 181.11,142.71 v2(181.59,143.19)
  BOTTOM w0.102: 166.29,125.96 165.96,126.29 165.96,128.18 165.99,128.2 165.99,128.54 165.97,128.56 165.97,128.95 v2(165.72,129.21)
  BOTTOM w0.114: 166.29,125.96 GPU1.F15
MDA35: length 45.3
  TOP w0.178: VRAM3.H8 179.19,142.39 179.16,142.36 179.16,139.99 v2(179.19,139.96)
  L3 w0.165: v2(165.68,131.24) 165.68,131.6 167.21,133.14 168.94,133.14 169.1,133.3 169.1,135.02 169.27,135.18 169.6,135.18 169.76,135.02 169.76,133.3 169.93,133.14 170.26,133.14 170.42,133.3 170.42,135.02 170.59,135.18 170.92,135.18 171.08,135.02 171.08,133.3 171.25,133.14 172.85,133.14 173.01,133.3 173.01,134.94 173.19,135.12 173.49,135.12 173.67,134.94 173.67,133.3 173.84,133.14 174.17,133.14 174.33,133.3 174.33,135.02 174.5,135.18 174.83,135.18 174.99,135.02 174.99,133.3 175.16,133.14 175.49,133.14 175.65,133.3 175.65,134.99 175.83,135.17 176.14,135.17 176.31,134.99 176.31,133.3 176.48,133.14 176.95,133.14 177.13,133.31 177.13,135.01 177.9,135.78 177.9,139.41 178.44,139.96 v2(179.19,139.96)
  BOTTOM w0.102: v2(165.68,131.24) 166.2,130.71 166.2,128.13 GPU1.A15
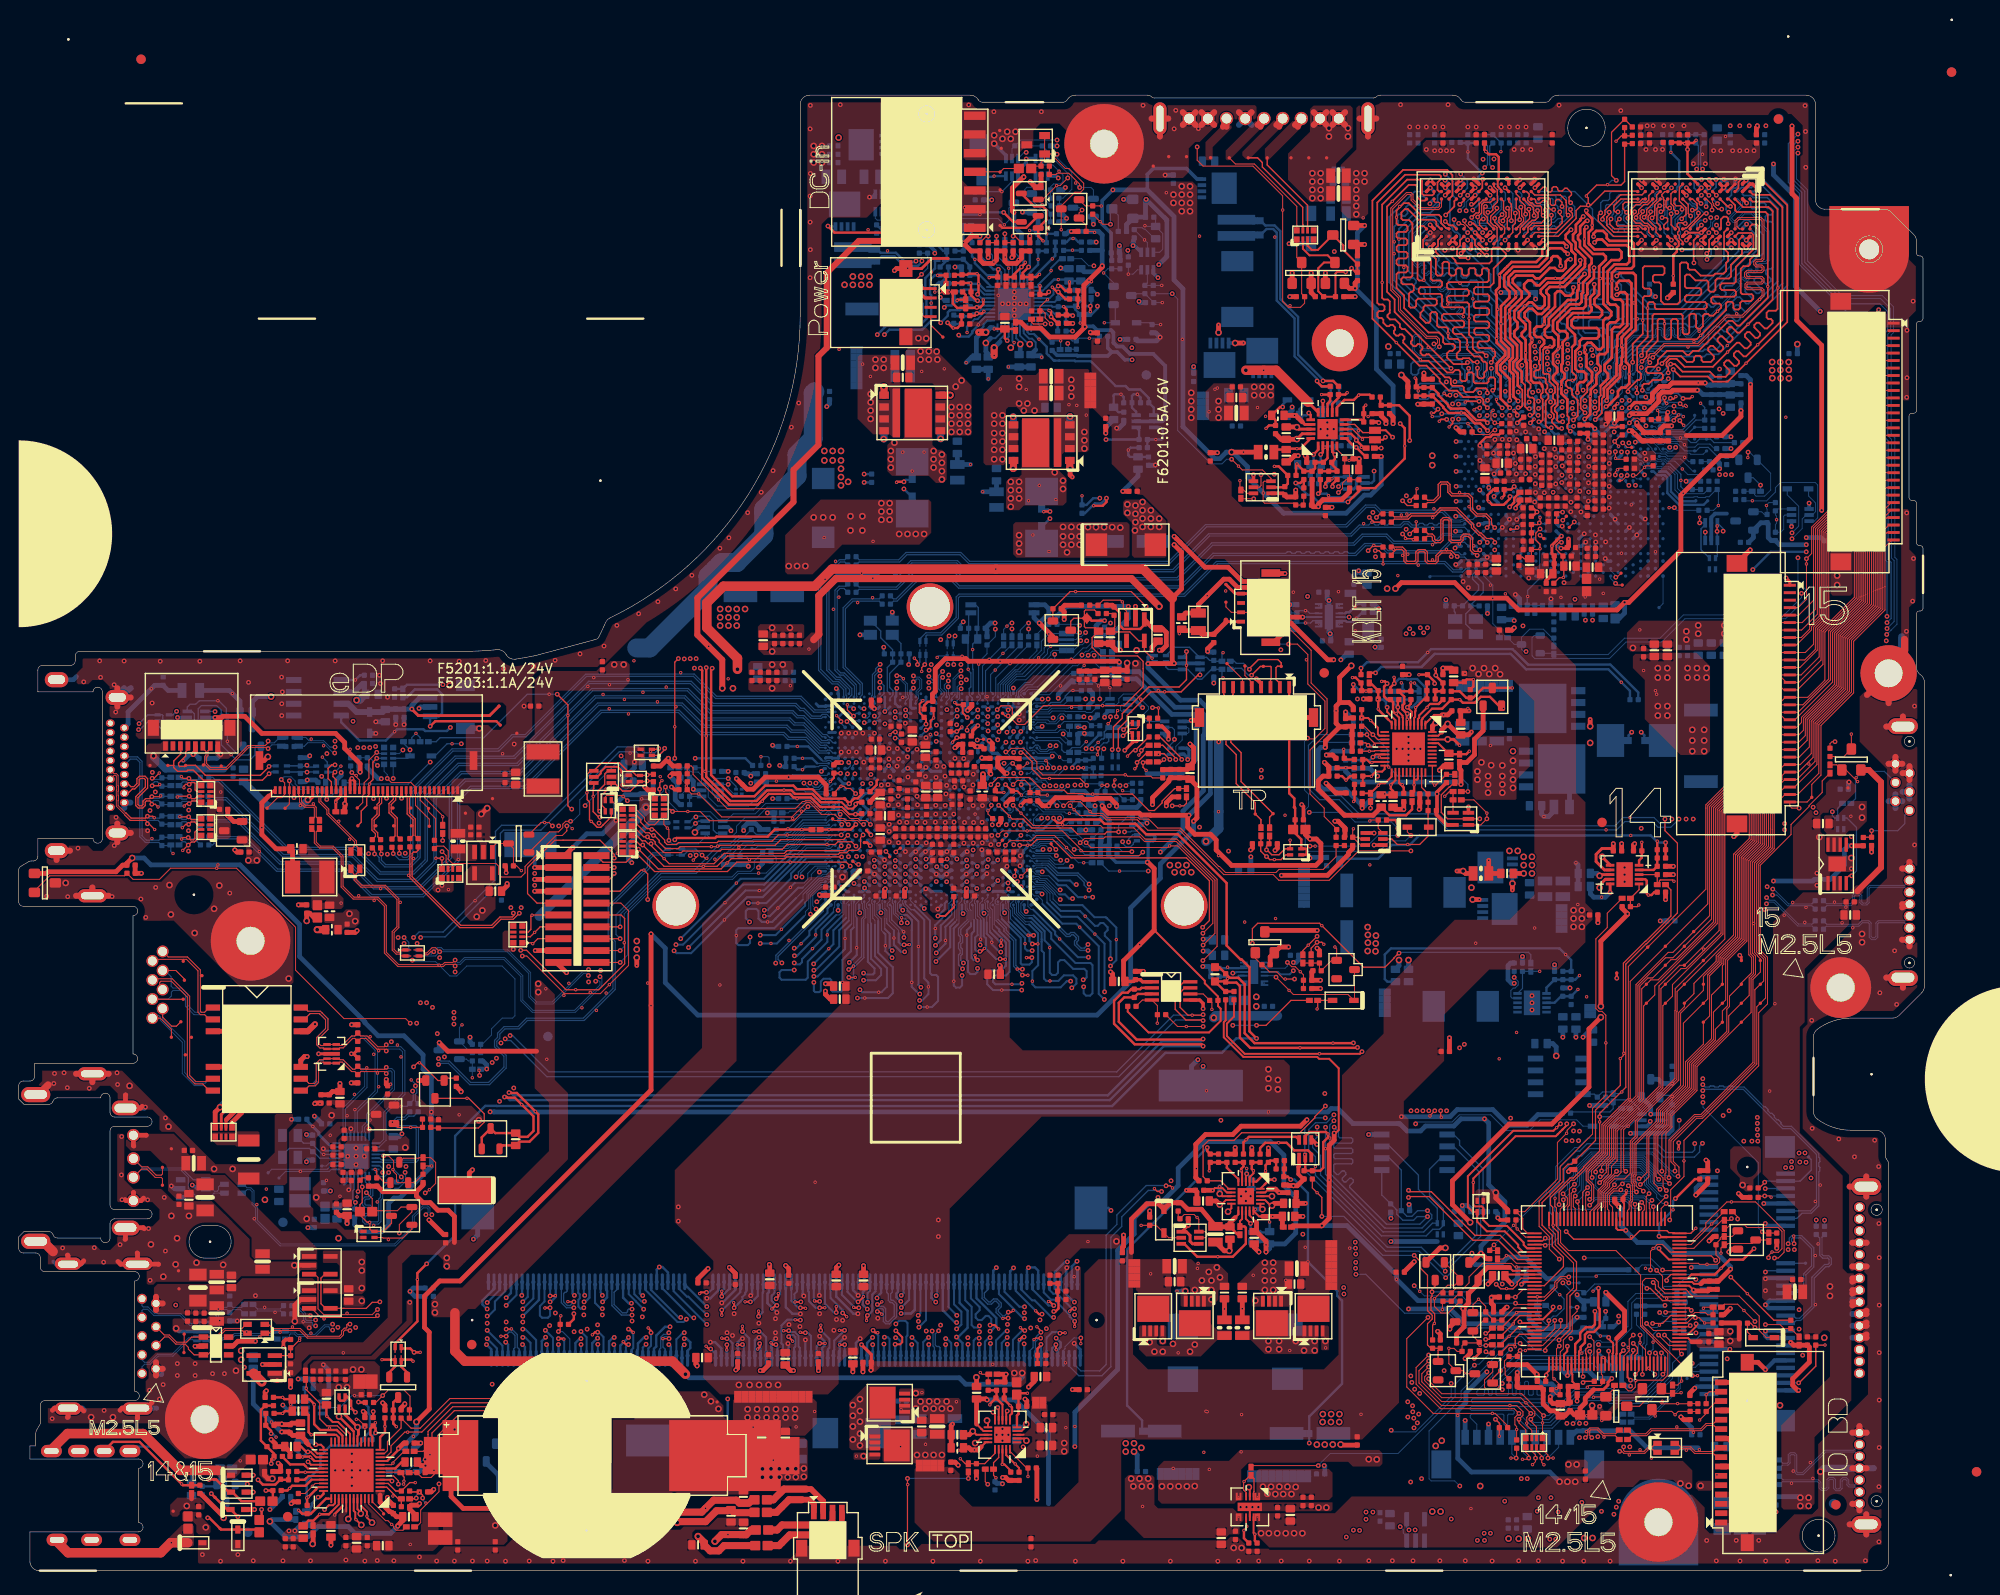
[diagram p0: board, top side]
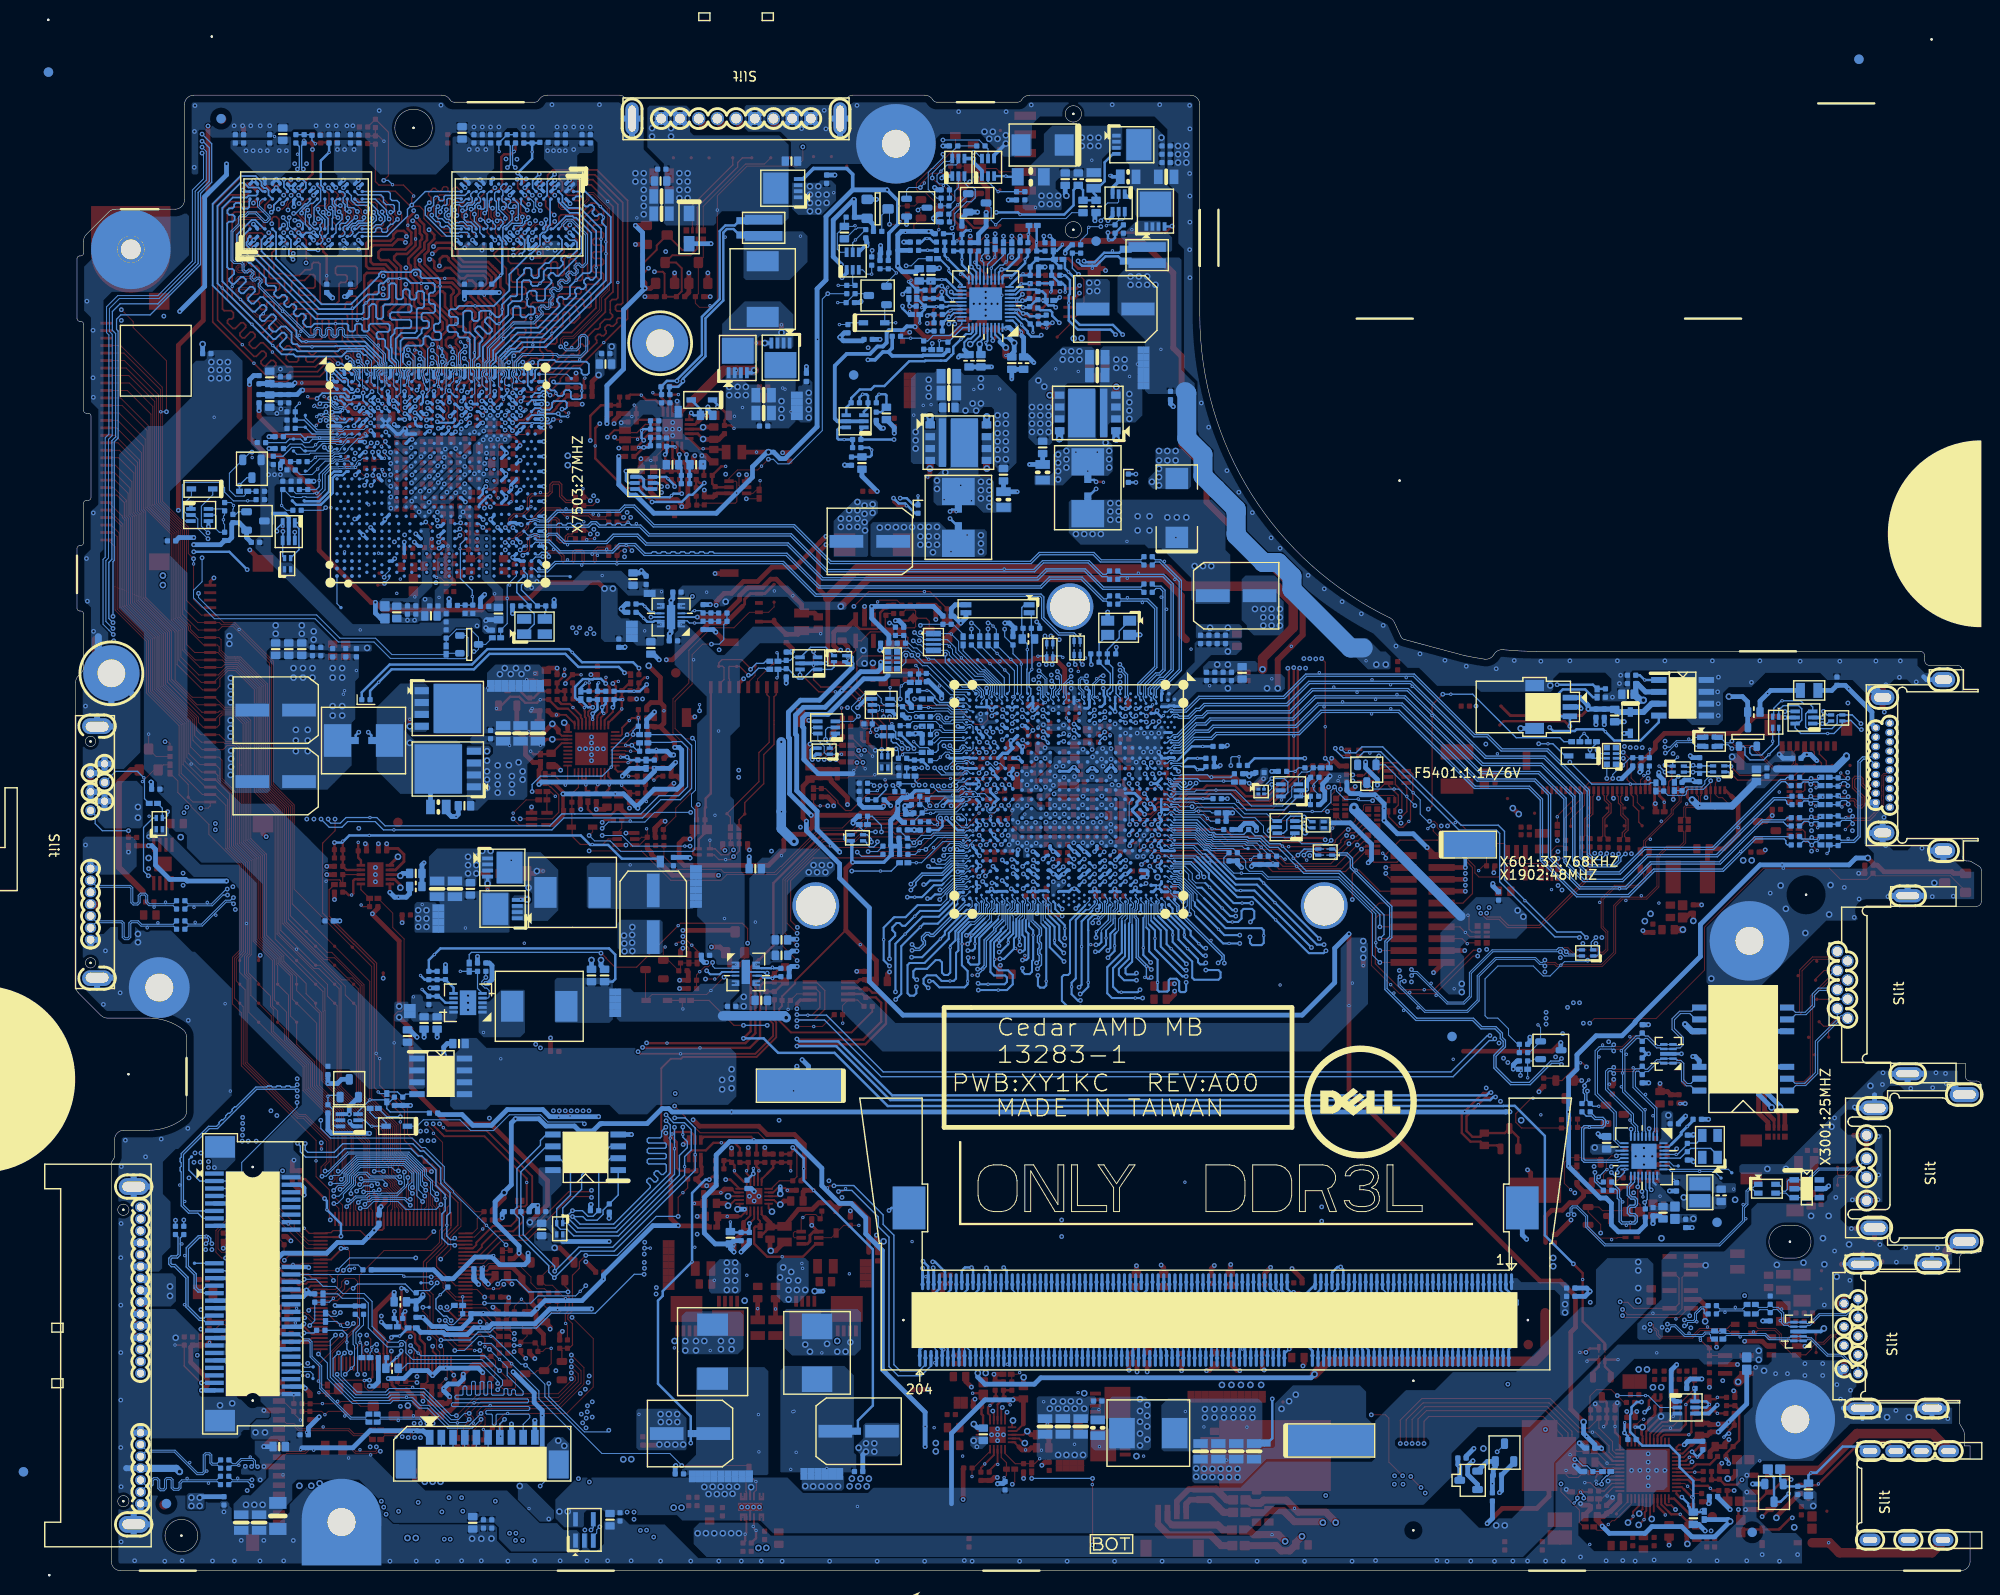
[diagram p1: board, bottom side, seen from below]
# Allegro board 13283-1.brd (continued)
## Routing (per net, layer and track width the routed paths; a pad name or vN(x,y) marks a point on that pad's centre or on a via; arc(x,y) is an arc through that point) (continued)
MDA36: length 44.8
  TOP w0.178: v2(180.8,147.19) 180.79,147.19 VRAM3.G2
  L3 w0.165: v2(180.8,147.19) 181.24,147.64 182.13,147.64 182.21,147.56 182.57,147.56 182.93,147.92 184.3,147.92 187.08,145.14 187.08,136.66 178.15,127.73 177.59,127.73 177.41,127.91 177.41,129.38 177.24,129.56 176.89,129.56 176.89,129.56 176.52,129.56 176.52,129.56 176.44,129.56 176.27,129.38 176.27,128.65 175.92,128.3 175.92,127.42 175.74,127.25 168.4,127.25 167.49,126.34 v2(167.34,126.34)
  BOTTOM w0.178: v2(167.34,126.34) 167.09,126.59 GPU1.D14
MDA37: length 45.5
  TOP w0.178: v2(179.95,146.31) 179.59,146.67 VRAM3.H3
  L3 w0.165: v2(168.61,125.09) 170.27,126.75 177.84,126.75 187.55,136.47 187.55,145.33 184.45,148.43 179.82,148.43 179.55,148.17 179.55,146.71 v2(179.95,146.31)
  BOTTOM w0.178: GPU1.F13 168.44,125.09 v2(168.61,125.09)
MDA38: length 44.5
  TOP w0.178: VRAM3.F2 181.2,147.59 v2(181.59,147.2)
  L3 w0.165: v2(181.59,147.2) 181.59,147.18 181.77,147.01 183.03,147.01 183.31,147.29 184.05,147.29 184.39,146.94 184.39,146.05 184.74,145.71 185.85,145.71 186.61,144.94 186.61,136.86 178.3,128.54 178.04,128.54 177.87,128.72 177.87,129.86 177.69,130.04 175.51,130.04 175.33,129.86 175.33,129.15 174.95,128.77 174.95,128.01 174.78,127.83 169.31,127.83 169.14,128.01 169.14,129.86 168.96,130.03 v2(168.39,130.03)
  BOTTOM w0.102: GPU1.A13 167.75,128.18 167.75,129.5 168.28,130.03 v2(168.39,130.03)
MDA39: length 45.1
  TOP w0.178: VRAM3.E3 182.79,145.99 v2(183.1,145.99)
  L3 w0.165: v2(183.1,145.99) 183.84,145.99 184.66,145.18 185.71,145.18 186.14,144.75 186.14,137.05 181.21,132.12 180.98,132.12 180.59,132.51 180.34,132.51 180.12,132.29 180.12,132.04 180.51,131.65 180.51,131.42 180.28,131.19 180.04,131.19 179.66,131.57 179.41,131.57 179.19,131.36 179.19,131.1 179.58,130.72 179.58,130.48 178.75,129.66 178.48,129.66 178.31,129.84 178.31,130.4 178.13,130.57 173.31,130.57 173.13,130.4 173.13,128.57 172.87,128.31 169.89,128.31 169.71,128.49 169.71,130.48 169.53,130.65 v2(168.26,130.65)
  BOTTOM w0.102: v2(168.26,130.65) 167.53,129.93 167.53,127.6 GPU1.C13
MDA40: length 42
  BOTTOM w0.102: 170,129.23 169.74,128.98 169.74,128.61 169.82,128.53 169.82,126.77 GPU1.E11
  BOTTOM w0.178: VRAM4.C3 183.68,143.59 184.63,144.55 185.01,144.55 186.6,142.96 186.6,140.95 186.38,140.73 186.08,140.73 185.28,139.93 185.1,139.93 183.5,138.33 183.5,137.72 183.29,137.51 182.6,137.51 182.42,137.33 182.42,136.97 182.61,136.78 182.61,136.58 182.25,136.22 182.05,136.22 181.75,136.53 181.49,136.53 181.24,136.28 181.24,136.03 181.53,135.74 181.53,135.49 181.27,135.24 181.02,135.24 180.74,135.52 180.49,135.52 180.24,135.27 180.24,135.02 180.52,134.74 180.52,134.49 180.27,134.24 180.02,134.24 179.73,134.52 179.48,134.52 179.23,134.27 179.23,134.02 179.51,133.73 179.51,133.48 179.15,133.11 178.63,133.11 178.3,133.44 v1(176.05,133.44) 174.85,133.44 174.67,133.27 174.67,132.79 174.5,132.62 174.14,132.62 173.96,132.79 173.96,133.27 173.78,133.44 173.38,133.44 173.2,133.27 173.2,132.79 173.02,132.62 172.89,132.62 172.64,132.62 172.46,132.79 172.46,133.27 172.29,133.44 170.43,133.44 170.25,133.27 170.25,132.76 170.43,132.58 171.47,132.58 171.65,132.4 171.65,132 171.47,131.82 170.91,131.82 170.73,131.64 170.73,130.99 170.32,130.58 170.32,129.56 170,129.23
MDA41: length 41.3
  BOTTOM w0.102: 169.62,129.33 169.54,129.25 169.54,128.09 GPU1.A11
  BOTTOM w0.178: VRAM4.A3 186.08,142.7 186.08,141.47 185.27,140.66 184.89,140.66 178.19,133.96 v1(173.15,133.96) 172.62,133.96 172.44,134.14 172.44,135.27 172.17,135.54 171.87,135.54 171.7,135.37 171.7,134.15 171.52,133.98 171.12,133.98 170.94,134.15 170.94,135.34 170.76,135.51 168.09,135.51 167.92,135.34 167.92,134.84 168.09,134.66 170.03,134.66 170.2,134.48 170.2,134.05 170.03,133.88 168.12,133.88 167.94,133.7 167.94,133.15 168.12,132.97 169.56,132.97 169.73,132.8 169.73,132.43 170.13,132.03 170.13,131.18 170.13,131.18 170.13,130.92 170.04,130.82 170.04,129.75 169.62,129.33
MDA42: length 42
  BOTTOM w0.102: 169.61,129.73 169.3,129.42 169.3,128.32 169.16,128.18 169.16,127.94 169.18,127.88 169.21,127.85 arc(169.25,127.79) 169.27,127.71 169.27,127.46 GPU1.C11
  BOTTOM w0.178: VRAM4.A2 185.42,142.56 185.42,142.28 185.56,142.14 185.56,141.84 185.22,141.5 185.22,141.38 184.96,141.12 184.61,141.12 177.98,134.48 173.23,134.48 173.05,134.66 173.05,135.4 v1(172.78,135.67) 172.39,136.06 170.47,136.06 170.29,136.24 170.29,137.58 170.12,137.76 169.76,137.76 169.58,137.58 169.58,136.24 169.41,136.06 169.01,136.06 168.83,136.24 168.83,136.95 168.65,137.13 168.3,137.13 168.12,136.95 168.12,136.21 167.94,136.03 167.56,136.03 167.38,136.21 167.38,136.75 167.21,136.92 166.75,136.92 166.57,136.75 166.57,135.32 166.75,135.15 167.18,135.15 167.36,134.97 167.36,132.66 167.56,132.45 169.01,132.45 169.21,132.25 169.21,132.21 169.61,131.81 169.61,129.73
MDA43: length 42.3
  BOTTOM w0.102: 169.1,130.42 169.1,128.42 168.96,128.28 168.96,127.86 168.97,127.82 169,127.79 169.01,127.76 169.03,127.75 169.07,127.65 169.07,126.06 GPU1.F11
  BOTTOM w0.178: 169.1,130.42 169.09,130.43 169.09,131.6 168.76,131.93 167.35,131.93 166.84,132.44 166.84,132.81 166.69,132.96 166.22,132.96 166.04,133.14 166.04,133.57 166.22,133.75 166.66,133.75 166.84,133.93 166.84,134.43 166.66,134.61 165.57,134.61 165.39,134.79 165.39,135.4 165.57,135.58 165.87,135.58 166.05,135.75 166.05,136.59 165.87,136.77 165.61,136.77 165.43,136.95 165.43,137.62 165.61,137.8 168,137.8 168.33,138.13 168.34,138.13 168.49,138.28 v1(169.19,138.28) 170.4,138.28 170.93,137.76 171.24,137.76 171.42,137.58 171.42,136.76 171.6,136.58 172.6,136.58 174.18,135.01 177.76,135.01 183.96,141.2 183.96,142.42 VRAM4.C2
MDA44: length 40.7
  BOTTOM w0.102: GPU1.A9 170.97,128.16 170.97,129.09 171.1,129.22 171.1,129.71 171.2,129.81
  BOTTOM w0.178: 171.2,129.81 172.92,131.53 v1(179.19,131.53) 179.69,131.53 180.22,132.06 180.22,132.72 183.79,136.29 184.09,136.29 184.78,135.6 185.03,135.6 185.38,135.95 185.38,136.2 184.68,136.9 184.68,137.15 184.93,137.4 185.18,137.4 185.88,136.7 186.13,136.7 186.39,136.95 186.39,137.2 185.65,137.94 185.65,138.18 185.91,138.44 186.15,138.44 186.88,137.72 187.13,137.72 187.41,138 187.41,138.26 186.89,138.78 186.89,139.13 187.07,139.31 187.45,139.31 187.63,139.49 187.63,144.19 187.45,144.37 187.02,144.37 186.84,144.54 186.84,144.92 187.02,145.1 187.42,145.1 187.6,145.28 187.6,145.61 187.42,145.79 187.07,145.79 186.89,145.97 186.89,146.19 186.71,146.37 186.31,146.37 186.13,146.19 186.13,145.94 185.95,145.76 185.45,145.76 185.27,145.94 185.27,146.54 185.19,146.63 VRAM4.A7
MDA45: length 41.1
  BOTTOM w0.102: 171.78,129.99 171.32,129.54 171.32,129.15 171.18,129 171.18,128.42 171.42,128.18 171.42,127.93 171.36,127.85 171.32,127.74 171.32,127.47 GPU1.C9
  BOTTOM w0.178: 171.78,129.99 172.83,131.05 176.06,131.05 176.1,131.01 179.91,131.01 180.16,131.26 180.57,131.26 180.74,131.44 180.74,132.5 181.38,133.14 181.87,133.14 182,133.01 182.01,133.01 182.41,132.61 182.78,132.61 183.14,132.97 183.14,133.23 182.43,133.94 182.43,134.19 182.68,134.44 182.93,134.44 183.65,133.73 183.9,133.73 184.15,133.98 184.15,134.23 183.44,134.94 183.44,135.2 183.69,135.45 183.94,135.45 184.65,134.73 184.9,134.73 v1(186.21,136.04) 188.15,137.98 188.15,145.84 187.03,146.95 185.55,146.95 185.34,147.16 184.53,147.16 184.39,147.3 VRAM4.B8
MDA46: length 41.9
  BOTTOM w0.102: GPU1.F9 171.52,126.07 171.52,127.67 arc(171.54,127.74) 171.58,127.79 arc(171.61,127.85) 171.62,127.91 171.62,128.34 171.38,128.58 171.38,128.92 171.52,129.06 171.52,129.26 172.02,129.76
  BOTTOM w0.178: 172.02,129.76 173.04,130.77 175.52,130.77 175.8,130.49 180.12,130.49 180.32,130.69 181.6,130.69 181.96,131.06 181.96,131.31 181.29,131.98 181.29,132.23 181.54,132.49 181.79,132.49 182.47,131.81 182.72,131.81 v1(188.18,137.27) 188.67,137.76 188.67,146.05 186.22,148.51 185.83,148.51 185.34,148.02 184.28,148.02 183.85,147.59 VRAM4.C8
MDA47: length 41.5
  BOTTOM w0.102: GPU1.D8 172.22,127.17 172.22,127.78 arc(172.17,127.85) 172.16,127.93 172.16,128.26 172.19,128.3 172.19,129.49 172.8,130.1
  BOTTOM w0.178: 172.8,130.1 173.01,130.1 173.4,130.49 174.83,130.49 175.38,129.94 180.31,129.94 180.54,130.17 181.81,130.17 v1(182.76,131.11) 189.19,137.55 189.19,146.27 186.21,149.25 184.59,149.25 183.96,148.61 183.96,148.24 183.68,147.96 183.44,147.96 183.21,147.73 183.21,147.21 VRAM4.D7
MDA48: length 39.6
  TOP w0.178: VRAM3.A7 185.19,143.84 185.42,144.06 185.9,144.06 186.08,143.88 186.08,140.92 185.9,140.74 185.62,140.74 185.19,140.31 185.19,139.78 185.01,139.61 184.49,139.61 184.2,139.32 184.2,136.78 184.38,136.6 185.37,136.6 185.54,136.42 185.54,136.13 185.28,135.86 184.33,135.86 184.15,135.68 184.15,135.15 183.97,134.97 183.59,134.97 183.41,135.15 183.41,135.62 183.23,135.79 182.8,135.79 182.62,135.62 182.62,134.91 v1(179.92,132.2) 179.5,131.78 177.65,131.78 177.47,131.96 177.47,133.77 177.29,133.95 176.93,133.95 176.76,133.77 176.76,131.96 176.58,131.78 176.22,131.78 176.05,131.96 176.05,133.8 175.88,133.96 175.47,133.96 175.31,133.8 175.31,131.61 174.14,130.44 174.14,129.91 v2(173.64,129.41)
  BOTTOM w0.102: v2(173.64,129.41) 173.3,129.08 173.3,129.07 173.16,128.92 173.16,127.78 173.16,127.78 173.16,126.91 GPU1.E7
MDA49: length 38.5
  TOP w0.178: v2(173.58,130.05) 173.71,130.17 173.71,130.75 174.77,131.81 174.77,134.31 174.94,134.48 177.81,134.48 177.99,134.31 177.99,132.5 178.17,132.33 178.52,132.33 178.7,132.5 178.7,134.33 178.88,134.51 179.25,134.51 179.42,134.33 179.42,133.09 179.6,132.91 179.89,132.91 180.16,133.18 180.16,134.31 180.34,134.48 180.72,134.48 180.9,134.31 181.25,134.31 v1(181.73,134.78) 182.1,135.16 182.1,135.42 181.93,135.6 181.23,135.6 181.05,135.78 181.05,136.16 181.23,136.34 183.5,136.34 183.68,136.52 183.68,136.87 183.5,137.05 182.19,137.05 182.01,137.23 182.01,137.58 182.19,137.76 183.5,137.76 183.68,137.94 183.68,139.53 185.56,141.41 185.56,142.94 185.34,143.16 183.96,143.16 VRAM3.C8
  BOTTOM w0.102: 173.33,129.79 173.33,129.68 173.23,129.58 173.23,129.31 172.92,129 172.92,128.27 GPU1.A7
  BOTTOM w0.114: v2(173.58,130.05) 173.33,129.79
MDA50: length 39.2
  TOP w0.178: v2(172.64,129.32) 172.64,131.28 173.72,132.37 v1(173.72,133.8) 173.72,136.21 173.9,136.39 174.44,136.39 174.62,136.57 174.62,137.02 174.44,137.2 173.9,137.2 173.72,137.38 173.72,139.41 173.9,139.59 175.87,139.59 176.05,139.41 176.05,138.85 175.87,138.68 174.98,138.68 174.8,138.5 174.8,138.04 174.98,137.86 175.49,137.86 175.66,137.69 175.66,135.88 176.02,135.53 177.42,135.53 177.7,135.81 177.7,139.82 177.87,140 178.38,140 178.56,139.82 178.56,139.4 178.74,139.22 179.28,139.22 179.91,138.6 181.27,138.6 181.48,138.8 182.37,138.8 182.64,139.07 182.64,139.96 182.85,140.18 182.85,141.04 182.42,141.47 182.42,143.22 VRAM3.D7
  BOTTOM w0.102: GPU1.C7 172.57,127.36 172.57,127.69 172.41,127.85 172.36,127.97 172.36,128.18 172.64,128.46 v2(172.64,129.32)
MDA51: length 39.7
  TOP w0.178: v2(172.14,126.18) 172.14,126.42 173.15,127.42 173.35,127.42 173.53,127.6 173.53,128.08 173.35,128.26 173.3,128.26 173.12,128.44 173.12,130.9 174.25,132.02 v1(174.25,135.12) 174.25,135.58 174.42,135.75 174.83,135.75 175,135.58 175,135.18 175.18,135.01 178.64,135.01 178.66,135.03 180.39,135.03 180.57,135.21 180.57,135.58 180.39,135.75 178.41,135.75 178.23,135.93 178.23,136.31 178.41,136.49 179.8,136.49 179.98,136.67 179.98,137.08 179.8,137.25 178.41,137.25 178.23,137.43 178.23,138.52 178.41,138.7 178.74,138.7 179.36,138.08 180.57,138.08 180.74,137.9 180.74,137.05 180.92,136.87 181.32,136.87 181.49,137.05 181.49,138.08 181.69,138.28 182.94,138.28 183.16,138.5 183.16,139.75 184.33,140.92 184.33,141.34 184.02,141.65 184.02,142.42 VRAM3.B8
  BOTTOM w0.178: GPU1.F7 172.15,126.18 v2(172.14,126.18)
MDA52: length 38.1
  TOP w0.178: v2(175.78,129.18) 175.78,129.22 176.52,129.96 177.82,129.96 178.43,129.36 179.04,129.36 179.22,129.53 179.22,129.84 179.4,130.01 179.83,130.01 180.01,129.84 180.01,129.53 180.18,129.36 181,129.36 181.32,129.67 181.32,129.98 180.72,130.58 180.72,130.83 180.97,131.08 181.22,131.08 181.82,130.48 182.07,130.48 182.32,130.73 182.32,130.98 181.73,131.58 181.73,131.83 181.98,132.08 182.23,132.08 182.83,131.49 183.08,131.49 183.33,131.74 183.33,131.99 182.73,132.59 182.73,132.84 182.98,133.09 183.23,133.09 183.83,132.49 184.08,132.49 v1(184.98,133.39) 187.62,136.02 187.62,145.48 187.17,145.93 185.28,145.93 185.27,145.91 184.47,145.91 VRAM3.C3
  BOTTOM w0.178: GPU1.A5 174.94,128.69 174.94,128.77 175.35,129.18 v2(175.78,129.18)
MDA53: length 38.9
  TOP w0.178: VRAM3.A2 185.51,147.27 185.71,147.27 185.75,147.24 187.33,147.24 188.66,145.91 188.66,133.84 v1(186.02,131.2) 184.77,129.95 184.52,129.95 183.97,130.5 183.72,130.5 183.46,130.25 183.46,129.99 184.01,129.45 184.01,129.19 183.76,128.94 183.51,128.94 182.94,129.52 182.68,129.52 182.43,129.27 182.43,129.01 183.01,128.44 183.01,128.19 182.59,127.77 181.44,127.77 180.89,128.31 177.97,128.31 177.16,129.12 v2(176.7,129.12)
  BOTTOM w0.178: v2(176.7,129.12) 175.48,127.9 175.48,127.88 175.25,127.65 174.94,127.65 174.7,127.4 174.7,126.85 GPU1.E5
MDA54: length 38.2
  TOP w0.178: v2(176.45,128.19) 176.45,128.75 176.26,128.94 176.26,129.31 176.64,129.68 177.34,129.68 178.19,128.84 181.22,128.84 v1(182.79,130.41) 183.79,131.41 184.04,131.41 184.64,130.81 184.89,130.81 185.26,131.18 185.26,131.43 184.65,132.04 184.65,132.29 184.9,132.55 185.15,132.55 185.77,131.93 186.02,131.93 186.27,132.19 186.27,132.44 185.66,133.05 185.66,133.3 185.91,133.55 186.16,133.55 186.77,132.94 187.02,132.94 187.6,133.52 187.6,133.77 187.43,133.95 187.14,133.95 186.97,134.13 186.97,134.61 187.2,134.84 187.96,134.84 188.14,135.02 188.14,145.7 187.32,146.51 185.47,146.51 VRAM3.A3
  BOTTOM w0.178: v2(176.45,128.19) 176.27,128.19 175.32,127.24 GPU1.C3
MDA55: length 38.4
  TOP w0.178: VRAM3.C2 183.96,147.96 183.96,148.61 184.59,149.25 186.06,149.25 189.18,146.13 189.18,133.62 v1(184.77,129.22) 182.8,127.25 181.22,127.25 180.67,127.79 177.73,127.79 v2(176.98,128.54)
  BOTTOM w0.178: v2(176.98,128.54) 176.98,127.45 175.96,126.44 GPU1.E1
MDA56: length 46.1
  TOP w0.178: v1(173.02,126.66) 173.09,126.59 v2(173.09,126.03)
  L4 w0.165: v2(180.4,144.51) 179.88,144.51 179.54,144.17 179.54,141.4 179.76,141.18 179.76,140.16 179.68,140.08 179.68,139.79 179.4,139.51 179.4,137 178.1,135.7 178.1,135.22 178.75,134.57 178.75,134.32 178.41,133.98 178.16,133.98 177.32,134.82 177.07,134.82 176.83,134.59 176.83,134.34 177.66,133.51 177.66,133.26 177.45,133.04 177.2,133.04 176.33,133.91 176.08,133.91 175.86,133.69 175.86,133.44 176.74,132.56 176.74,132.31 176.53,132.09 176.27,132.09 175.42,132.95 175.17,132.95 174.95,132.73 174.95,132.48 176.29,131.15 176.29,130.01 176.11,129.84 175.74,129.84 175.56,130.01 175.56,130.94 174.42,132.08 174.17,132.08 173.96,131.86 173.96,131.61 174.84,130.73 174.84,130.49 174.61,130.26 174.37,130.26 173.45,131.18 173.2,131.18 172.86,130.84 172.86,130.59 173.09,130.35 173.09,128.97 172.91,128.8 172.39,128.8 172.21,128.62 172.21,128.24 172.39,128.06 173.17,128.06 173.35,127.88 173.35,127.53 173.17,127.35 172.21,127.35 172.03,127.17 172.03,126.81 172.21,126.64 172.91,126.64 173.09,126.46 v2(173.09,126.03)
  BOTTOM w0.178: v2(173.09,126.03) 173.09,125.24 GPU1.G7 ; VRAM4.H3 179.53,143.65 179.53,144.19 179.85,144.51 v2(180.4,144.51)
MDA57: length 44.8
  L4 w0.165: v2(181.61,144) 182.39,144 182.73,143.66 182.73,143.25 182.55,143.07 182.21,143.07 182.03,142.89 182.03,142.51 182.21,142.33 182.62,142.33 182.75,142.2 182.75,141.8 182.58,141.62 182.21,141.62 182.03,141.44 182.03,141.06 182.21,140.89 183.08,140.89 183.26,140.71 183.26,140.38 183.08,140.2 182.19,140.2 182.03,140.04 182.03,139.68 182.19,139.51 183.08,139.51 183.26,139.34 183.26,139.01 183.08,138.83 182.21,138.83 182.03,138.65 182.03,138.32 182.21,138.14 183.33,138.14 183.51,137.96 183.51,137.63 183.33,137.46 182.21,137.46 182.03,137.28 182.03,136.9 182.21,136.72 183.36,136.72 183.53,136.55 183.53,136.19 183.35,136.01 182.21,136.01 182.03,135.83 182.03,133.75 182.21,133.57 182.5,133.57 182.67,133.39 182.67,132.07 182.5,131.89 181.96,131.89 181.78,131.72 181.78,130.99 179.93,129.14 179.41,129.14 179.06,128.78 179.06,128.26 177.58,126.79 177.29,126.79 177.12,126.61 177.12,125.29 176.86,125.03 176.84,125.03 176.54,124.73 175.99,124.73 175.82,124.55 175.82,123.44 175.99,123.26 176.2,123.26 176.38,123.08 176.38,122.67 176.2,122.5 174.7,122.5 174.52,122.67 174.52,122.83 174.34,123 173.55,123 173.27,123.29 173.02,123.29 172.84,123.46 172.84,123.77 173.02,123.94 173.72,123.94 173.9,124.12 v2(173.9,124.44)
  BOTTOM w0.178: GPU1.G6 173.5,124.84 v2(173.9,124.44) ; VRAM4.E3 181.99,143.62 v2(181.61,144)
MDA58: length 44.7
  TOP w0.178: v1(177.26,125.65) 177.01,125.4 176.75,125.4 v2(176.68,125.47)
  L4 w0.165: v2(176.68,125.47) 176.68,127.09 176.86,127.27 177.41,127.27 177.63,127.48 177.63,127.74 177.42,127.94 177.42,128.19 177.64,128.41 177.89,128.41 178.08,128.22 178.3,128.22 178.54,128.46 178.54,128.93 178.77,129.16 178.77,129.69 178.95,129.86 179.19,129.86 179.45,129.61 179.69,129.61 180.01,129.93 180.01,130.17 179.69,130.49 179.69,130.76 179.97,131.04 180.22,131.04 180.47,130.79 180.86,130.79 181.31,131.23 181.31,131.56 181.13,131.73 179.86,131.73 179.69,131.9 179.69,132.23 179.86,132.39 182.04,132.39 182.2,132.56 182.2,132.89 182.04,133.05 179.86,133.05 179.68,133.23 179.68,133.54 179.86,133.71 181.35,133.71 181.56,133.92 181.56,134.23 181.3,134.48 181.3,134.87 181.56,135.12 181.56,135.58 181.38,135.75 180.57,135.75 180.39,135.58 180.39,134.59 180.21,134.41 179.86,134.41 179.69,134.59 179.69,135.03 179.4,135.32 179.4,135.67 180.17,136.44 181.38,136.44 181.56,136.62 181.56,136.97 181.38,137.15 180.52,137.15 180.34,137.33 180.34,137.63 180.52,137.81 181.38,137.81 181.56,137.99 181.56,138.32 181.38,138.5 180.52,138.5 180.34,138.68 180.34,139.01 180.52,139.18 181.38,139.18 181.56,139.36 181.56,139.64 181.25,139.95 181.25,140.35 181.56,140.66 181.56,140.94 181.38,141.11 181.05,141.11 180.76,141.4 180.59,141.4 180.42,141.57 180.42,142 180.6,142.18 180.98,142.18 181.15,142.36 181.15,143.01 180.98,143.19 v2(180.79,143.19)
  BOTTOM w0.178: VRAM4.G2 180.39,142.79 v2(180.79,143.19) ; v2(176.68,125.47) 176.27,125.06 176.11,125.06 GPU1.G1
MDA59: length 45.4
  TOP w0.178: v2(176.05,125.52) 176.05,125.14 v1(176.28,124.91)
  L4 w0.165: v2(176.05,125.52) 176.05,125.82 175.87,126 175.49,126 175.31,125.82 175.31,123.72 175.13,123.54 174.7,123.54 174.52,123.72 174.52,124.44 174.19,124.77 174.19,125.09 174.52,125.42 174.52,125.87 174.19,126.2 174.19,126.51 174.37,126.69 176.02,126.69 176.2,126.86 176.2,127.2 176.02,127.37 174.01,127.37 173.84,127.55 173.84,128.4 174.13,128.69 174.6,128.69 174.78,128.52 174.78,128.24 174.95,128.06 175.83,128.06 176.01,128.24 176.01,128.79 176.27,129.05 176.27,129.3 176.52,129.56 176.68,129.56 176.86,129.74 176.86,130.45 177.04,130.62 177.39,130.62 177.57,130.45 177.57,129.38 177.75,129.2 178.1,129.2 178.28,129.38 178.28,130.37 178.46,130.55 179.04,130.55 179.22,130.73 179.22,131.21 179.04,131.39 177.04,131.39 176.86,131.56 176.86,131.76 177.21,132.12 177.21,132.35 177.36,132.5 177.62,132.5 178.03,132.1 179.04,132.1 179.22,132.28 179.22,132.61 179.04,132.78 178.33,132.78 178.15,132.96 178.15,133.29 178.33,133.47 179.04,133.47 179.22,133.65 179.22,134.84 178.71,135.34 178.71,135.65 179.87,136.8 179.87,139.31 180.15,139.59 180.15,139.89 v2(180.59,140.33)
  BOTTOM w0.178: v2(180.59,140.33) 180.61,140.33 181.04,140.75 181.04,141.36 180.82,141.58 180.82,142.42 VRAM4.F2 ; v2(176.05,125.52) 175.75,125.22 175.47,125.22 GPU1.G3
MDA60: length 45.8
  L4 w0.165: v2(180.01,148.89) 180.5,149.38 184.97,149.38 188.8,145.55 188.8,132.63 178.22,122.05 174.53,122.05 v2(174.06,122.52)
  BOTTOM w0.178: VRAM4.H8 179.22,147.96 179.22,148.54 179.57,148.89 v2(180.01,148.89) ; v2(174.06,122.52) 174.06,122.66 173.49,123.23 GPU1.J6
MDA61: length 45.7
  TOP w0.178: v2(177.68,123.08) 177.68,122.99 v1(178.1,122.57)
  L4 w0.165: v2(177.68,123.08) 177.68,122.87 177.91,122.65 178.15,122.65 186.56,131.06 186.56,132.43 187.05,132.92 187.75,132.92 188.33,133.5 188.33,144.01 188.15,144.19 187.02,144.19 186.84,144.37 186.84,144.7 187.02,144.87 187.63,144.87 187.81,145.05 187.81,145.43 187.63,145.61 186.41,145.61 186.23,145.79 186.23,146.17 186.41,146.35 186.59,146.35 186.76,146.52 186.76,146.92 186.53,147.16 185.75,147.16 185.49,147.41 184.81,147.41 184.63,147.59 184.63,148.25 184.45,148.43 184.15,148.43 183.97,148.25 183.97,147.79 183.79,147.62 183.46,147.62 183.28,147.79 183.28,148.51 183.11,148.68 182.83,148.68 182.6,148.45 181.81,148.45 181.56,148.71 v2(181.56,148.89)
  BOTTOM w0.102: GPU1.J1 175.99,123.34 176.71,123.34 176.88,123.51 177.26,123.51 v2(177.68,123.08)
  BOTTOM w0.178: VRAM4.F8 181.19,147.68 181.56,148.05 v2(181.56,148.89)
MDA62: length 46.1
  L4 w0.165: v2(177.06,123.99) 177.28,124.22 178.1,124.22 178.28,124.39 178.28,124.99 178.46,125.17 179.34,125.17 180.02,125.85 180.02,126.35 180.29,126.62 180.79,126.62 181.05,126.88 181.05,127.17 180.76,127.46 180.76,127.71 181.24,128.18 181.49,128.18 181.8,127.87 182.04,127.87 182.56,128.39 182.56,128.63 182.21,128.97 182.21,129.19 182.56,129.54 182.78,129.54 183.13,129.19 183.36,129.19 183.59,129.42 183.59,129.66 183.25,130 183.25,130.23 183.49,130.47 183.72,130.47 184.06,130.13 184.3,130.13 184.66,130.49 184.66,130.73 184.25,131.14 184.25,131.23 184.25,132.66 184.4,132.81 184.76,132.81 184.94,132.64 184.94,131.36 185.11,131.18 185.35,131.18 185.62,131.45 185.62,132.82 185.92,133.12 185.92,135.22 186.05,135.35 187.21,135.35 187.39,135.53 187.39,143.04 187.21,143.22 186.08,143.22 185.9,143.4 185.9,144.7 184.78,145.81 183.77,145.81 183.59,145.99 183.59,146.25 183.41,146.43 182.73,146.43 182.55,146.61 182.55,146.91 182.37,147.08 182.09,147.08 181.71,146.7 v2(181.71,146.29)
  BOTTOM w0.102: GPU1.J3 175.41,123.24 175.75,123.58 176.14,123.58 176.16,123.56 176.62,123.56 v2(177.06,123.99)
  BOTTOM w0.178: v1(178.06,123.51) 177.82,123.75 177.31,123.75 v2(177.06,123.99) ; v2(181.71,146.29) 181.22,146.79 VRAM4.F7
MDA63: length 46.3
  TOP w0.178: v1(177.57,123.69) 177.54,123.69 177.05,123.2 v2(177.05,123.09)
  L4 w0.165: v2(177.05,123.09) 177.05,123.36 177.41,123.73 178.56,123.73 178.74,123.91 178.74,124.48 178.92,124.66 179.49,124.66 181.52,126.68 181.52,127.06 181.76,127.3 182.13,127.3 186.09,131.26 186.09,132.63 186.39,132.93 186.39,133.21 186.57,133.39 187.55,133.39 187.73,133.57 187.73,133.98 187.55,134.15 186.57,134.15 186.39,134.33 186.39,134.71 186.56,134.88 187.68,134.88 187.86,135.06 187.86,143.53 187.68,143.71 186.55,143.71 186.37,143.88 186.37,144.95 185.3,146.02 185.3,146.51 184.9,146.91 183.08,146.91 182.9,147.08 182.9,147.36 182.73,147.54 181.87,147.54 181.43,147.98 181.43,148.25 181.25,148.43 179.81,148.43 179.55,148.17 179.55,147.63 v2(179.99,147.2)
  BOTTOM w0.178: GPU1.J5 174.57,123.24 174.94,122.87 176.04,122.87 176.26,123.09 v2(177.05,123.09) ; v2(179.99,147.2) 179.59,146.8 VRAM4.H7
MDO0+: length 15.5
  TOP w0.102: AFTP3107.1 16.33,57.94 15.14,59.13 RJ45.1
  BOTTOM w0.102: XF3101.1 20.39,51.38 19.86,51.91 18.79,51.91 17.5,53.2 17.5,56.56 15.15,58.91 15.15,59.25 14.97,59.43 14.6,59.43 RJ45.1
MDO0-: length 15
  TOP w0.102: AFTP3102.1 16.88,58.28 16.36,58.28 15.43,59.2 15.4,59.23 RJ45.2
  BOTTOM w0.102: RJ45.2 15.4,59.02 17.75,56.66 17.75,53.31 18.9,52.16 19.94,52.16 20.42,52.65 XF3101.2
MDO1+: length 12.4
  TOP w0.102: AFTP3101.1 14.31,61.16 RJ45.3
  BOTTOM w0.102: RJ45.3 16,61.17 16.33,61.5 16.33,61.92 16.51,62.09 17.34,62.09 17.65,61.79 17.83,61.61 17.83,60.42 17.9,60.34 18.74,59.5 19.89,59.5 20.39,59 XF3101.5
MDO1-: length 11.6
  TOP w0.102: AFTP3106.1 17.73,63.31 16.81,64.23 RJ45.6
  BOTTOM w0.102: RJ45.6 15.64,64.23 16.3,63.57 16.3,62.55 16.51,62.35 17.45,62.35 18.08,61.71 18.08,60.52 18.85,59.76 19.89,59.76 20.39,60.27 XF3101.6
MDO2+: length 16.7
  TOP w0.102: AFTP3103.1 18.04,55.21 ; 18.04,55.21 18.04,52.89 18.85,52.09 19.68,52.09 20.39,51.38 XF3102.6 ; 18.04,55.21 18.04,61.37 16.33,63.09 15.21,63.09 15.09,62.96 15.09,62.5 RJ45.4
MDO2-: length 16.4
  TOP w0.102: 18.29,57.08 18.29,61.48 16.43,63.34 14.43,63.34 RJ45.5 ; 18.29,57.08 18.29,53 18.95,52.34 19.99,52.34 20.29,52.65 XF3102.5 ; 18.29,57.08 AFTP3104.1
MDO3+: length 12
  TOP w0.102: RJ45.7 14.47,65.42 17.6,65.42 ; 17.6,65.42 17.95,65.42 19.17,64.2 19.17,59.76 19.43,59.5 19.89,59.5 20.39,59 XF3102.2 ; 17.6,65.42 AFTP3105.1
MDO3-: length 11.1
  TOP w0.102: RJ45.8 15.99,65.68 18.05,65.68 19.43,64.3 19.43,63.68 ; XF3102.1 20.39,60.27 19.89,59.76 19.54,59.76 19.43,59.87 19.43,63.68 ; 19.43,63.68 AFTP3108.1
MEM_1V5: length 5.6
  BOTTOM w0.14: R644.1 112.79,94.18 v1(112.77,94.2) 112.75,94.18 112.52,94.18 111.94,93.59 111.94,93.42 111.43,92.91 110.4,92.91 109.99,92.5 CPU1.BA3
MEM_CALRN0: length 3
  TOP w0.102: v1(157.71,124.18) 157.49,123.96 157.49,123.24 v2(157.89,122.84) 157.98,122.75 R7409.2
  BOTTOM w0.102: GPU1.J25 158.29,123.24 v2(157.89,122.84)
MEM_CALRP0: length 4.4
  TOP w0.102: v1(155.01,122.76) 155.46,122.31 R7408.2 155.73,121.59 157.29,121.59 157.76,122.07 v2(157.91,122.07)
  BOTTOM w0.102: GPU1.K25 157.92,122.07 v2(157.91,122.07)
MEM_RST: length 36.8
  TOP w0.14: VRAM1.T2 162.83,142.79 162.85,142.81 164.69,142.81 166.59,144.71 166.59,145.55 167.05,146.02 167.76,146.02 v2(167.89,146.14) ; v2(167.89,146.14) 168.17,146.14 169.66,147.63 173.15,147.63 VRAM3.T2 ; v2(167.89,146.14) 167.89,146.91 v1(167.69,147.11) 167.69,147.18 168.78,148.28 171.4,148.28 171.78,148.66 R7402.2 171.84,152.72 R7401.2
  BOTTOM w0.14: VRAM4.T2 170.51,142.79 168.35,144.95 168.35,145.69 v2(167.89,146.14) 166.45,147.59 VRAM2.T2
MIC2_VREFO: length 16.4
  TOP w0.203: HDA27.29 31.26,11.34 v2(30.95,11.65)
  TOP w0.254: v2(36.01,16.96) 35.56,17.42 35.56,18.18 35.09,18.65 RN2901.1 34.92,18.3 34.81,18.19 34.39,18.19 34.27,18.32 RN2901.2
  L3 w0.254: v2(36.01,16.96) 37.13,15.84 37.13,14.52 36.13,13.52 32.82,13.52 v2(30.95,11.65)
  BOTTOM w0.254: v1(35.51,17.42) 35.96,16.96 v2(36.01,16.96)
MIC_CAP: length 5.4
  TOP w0.203: HDA27.19 35.43,14.65 34.16,15.92 33.58,15.92 v1(32.97,16.53)
  TOP w0.254: C2713.1 32.92,16.58 v1(32.97,16.53)
MIC_GND: length 2.5
  TOP w0.305: R5201.1 v1(33.92,82.24) 33.92,82.42 34.45,82.95 LCD1.26
MLPS_EN#: length 7.8
  BOTTOM w0.089: 176.44,118.5 176.29,118.5 176.02,118.76 175.74,118.76 175.7,118.73 175.26,118.73 175.22,118.76 174.61,118.76 GPU1.R5
  BOTTOM w0.127: 176.44,118.5 176.64,118.5 177.8,117.34 v1(177.8,116.68) 177.8,116.01 178.1,115.7 R7425.2 R7424.1
MODEL_ID_DET: length 16.2
  TOP w0.102: R2446.2 R2405.2 159,20.95 159,21.66 158.93,21.74 158.93,22.44 R2407.1 C2403.2 160.3,23.26 v2(160.6,23.56) ; v2(168.06,23.46) 168.09,23.42 KBC24.108
  L3 w0.102: v2(160.6,23.56) 161.03,23.99 161.03,24.76 161.24,24.96 163.27,24.96 164.77,23.46 v2(168.06,23.46)
  BOTTOM w0.102: v1(161.16,23.56) v2(160.6,23.56)
MPV18: length 5.4
  TOP w0.508: v2(172.27,121.99) 172.54,121.99 v1(172.87,121.66) 172.89,121.66 173.64,120.91 C7779.2 C7781.2 C7780.2 L7704.2
  BOTTOM w0.356: GPU1.L8 171.89,121.61 v2(172.27,121.99)
MUTE_CTRL: length 14.1
  TOP w0.102: R2918.2 38.2,18 v2(38.94,18.74) 39.57,19.37 41.17,19.37 41.86,18.69 41.86,17.57 41.79,17.5 C2901.1 R2917.1
  BOTTOM w0.102: U2901.2 34.36,17.47 35.63,18.74 v1(35.91,18.74) v2(38.94,18.74)
MVREFDA: length 9.9
  TOP w0.254: v2(157.12,122) 156.35,122.77 155.76,122.77 154.64,123.89 v1(154.3,123.89) 152.94,123.89 152.39,124.45 152.39,124.55 R7414.1 C7402.1 149.55,125.73 R7410.2
  BOTTOM w0.254: v2(157.12,122) 157.12,122.07 GPU1.K26
MVREFSA: length 10.9
  TOP w0.254: v1(149.38,127.63) 149.49,127.51 R7411.2 149.55,126.62 R7415.1 C7403.1 151.87,125.96 151.87,125.79 152.89,124.76 152.89,124.66 153.18,124.38 153.22,124.38 153.23,124.36 154.67,124.36 155.91,123.13 156.81,123.13 v2(157.1,122.84)
  BOTTOM w0.254: v2(157.1,122.84) 157.1,122.85 GPU1.J26
NCT7718_DXN: length 103.6
  TOP w0.254: v2(126.69,56.89) 126.64,56.84 119.58,56.84 117.68,58.74 117.68,60.77 118.25,61.35 C2607.2 119.7,61.72 THM26.3 ; Q2603.E 51.8,45.51 C2606.2 53.57,45.92 54.64,45.92 55.57,46.85 55.57,48.84 v1(55.27,49.14) 53.29,51.12 52.67,51.12 52.63,51.17 v2(52.45,51.17)
  BOTTOM w0.254: v2(126.69,56.89) 126.44,56.64 122.27,56.64 116.5,50.87 52.92,50.87 52.63,51.17 v2(52.45,51.17)
NCT7718_DXP: length 108.2
  TOP w0.254: Q2603.B 49.53,46.37 Q2603.C 50.97,46.83 C2606.1 53.57,46.42 54.43,46.42 55.06,47.06 55.06,48.63 v1(53.81,49.88) 53.08,50.61 52.28,50.61 52.2,50.69 v2(51.97,50.69) ; v2(126.69,56.13) 126.69,56.18 126.54,56.33 119.37,56.33 117.17,58.53 117.17,60.98 118.04,61.85 118.63,61.85 119.01,62.23 C2607.1 119.96,62.23 120.1,62.37 THM26.2
  BOTTOM w0.254: v2(51.97,50.69) 52.2,50.69 52.53,50.36 116.71,50.36 122.48,56.13 v2(126.69,56.13)
ODD_PWR_5V: length 5.2
  BOTTOM w0.635: ODD1.2 201.49,82.35 ; ODD1.2 200.75,83.09 ; ODD1.2 200.01,82.35 ; ODD1.2 200.75,81.61 ; 202.25,82.61 ODD1.3 ; ODD1.3 202.25,84.09 ; ODD1.3 201.51,83.35
  vias: v1(195.98,80.74) v3(197.18,81.73) v3(197.18,80.59)
ODTA0: length 38.3
  TOP w0.14: VRAM1.K1 158.14,142.34 158.14,143.73 157.93,143.94 157.78,143.94 157.45,144.27 157.45,144.95 158.11,145.61 v2(158.11,145.81)
  L4 w0.165: v2(158.11,145.81) 158.61,145.81 159.2,145.21 159.2,144.04
  L4 w0.267: 159.2,144.04 160.87,142.37 160.87,141.45 161.82,140.5 162.17,140.5 162.81,139.87 162.81,133.57 161.23,131.99 161.23,131.99 160.53,131.29 160.53,130.08 160.3,129.85 160.3,128.8 160.91,128.19 160.91,122.92 162.14,121.69 163.02,121.69 v2(163.21,121.88)
  BOTTOM w0.14: v2(158.11,145.81) 157.92,145.81 157.8,145.94 157.8,146.3 157.97,146.47 158.1,146.47 158.24,146.61 158.24,147.08 158.14,147.18 158.14,147.64 158.37,147.87 158.37,148.12 158.1,148.39 VRAM2.K1
  BOTTOM w0.279: GPU1.L18 163.61,121.64 163.6,121.65 163.44,121.65 v2(163.21,121.88)
ODTA1: length 41.9
  TOP w0.14: VRAM3.K1 177.64,148.04 177.64,146.57 178.34,145.86 178.34,145.13 v2(177.88,144.67)
  L4 w0.165: v2(166.32,122.48) 167.29,122.48 167.55,122.74 168.83,122.74 169.08,123 169.08,124.84 169.05,124.88 169.05,125.97 169.15,126.07 169.15,126.43
  L4 w0.267: v2(177.88,144.67) 177.88,144.66 176.22,143 176.22,140.73 175.77,140.28 175.77,140.26 175.36,139.86 173.77,139.86 171.93,138.01 171.93,136.42 170.27,134.76 170.27,132.54 169.99,132.26 168.1,132.26 167.84,132.01 167.84,131.46 168.12,131.18 169.71,131.18 169.99,130.9 169.99,130.51 169.18,129.7 169.18,126.46 169.15,126.43
  BOTTOM w0.14: v2(177.88,144.67) 177.61,144.67 177.47,144.53 177.47,144.26 177.7,144.04 177.7,143.83 177.57,143.71 177.57,143.48 177.75,143.3 177.75,143.04 177.54,142.83 177.54,142.65 177.42,142.52 177.42,142.26 177.68,141.99 VRAM4.K1
  BOTTOM w0.279: v2(166.32,122.48) 166.3,122.45 165.77,122.45 165.76,122.44 GPU1.K16
P2800_VGA_DXN: length 6.2
  BOTTOM w0.254: GPU1.T2 175.56,117.64 175.57,117.63 176.22,117.63 176.73,117.11 176.73,115.49 177.77,114.44 179.35,114.44 TP7518.1
P2800_VGA_DXP: length 8.6
  BOTTOM w0.254: GPU1.T4 174.88,117.64 175.29,117.23 175.71,117.23 175.72,117.25 176.06,117.25 176.35,116.95 176.35,115.33 177.61,114.06 180.24,114.06 TP7517.1
P_RX_ZVDD_095: length 3.7
  TOP w0.203: v1(96.72,93.11) 96.37,92.75 96.37,91.83 96.85,91.35 R301.2 97.05,91.11 v2(97.05,90.59)
  BOTTOM w0.203: v2(97.05,90.59) 96.94,90.59 CPU1.W7
P_TX_ZVDD_095: length 3.5
  TOP w0.203: v2(97.05,89.96) 97.2,89.96 97.55,90.3 97.55,90.94 v1(97.86,91.25) 97.86,92.08 R302.2
  BOTTOM w0.203: CPU1.W8 97.05,89.9 v2(97.05,89.96)
PANEL_SIZE_ID: length 295.1
  TOP w0.102: v2(61.9,10.15) 63.37,11.63 63.37,16.32 63.73,16.68 v2(65.25,16.68)
  L3 w0.102: v2(61.9,10.15) 61.9,10.54 60.51,11.93 59.23,11.93 57,14.17 46.31,14.17 45.6,14.87 45.24,15.24 45.24,16.39 42.11,19.51 40.59,19.51 36.93,23.17 36.93,26.78 36.31,27.4 35.79,27.92 35.79,33.9 37.16,35.27 37.16,37.3 41.09,41.23 41.09,41.44 41.88,42.22 41.88,48.99 44.57,51.68 44.57,53.24 43.99,53.83 43.99,57 43.89,57.1 43.89,57.84 43.91,57.87 43.91,60.02 43.83,60.1 43.83,60.58 v2(43.63,60.77)
  L4 w0.102: v2(38.37,86.17) 39.27,86.17 43.72,81.72 43.72,60.86 v2(43.63,60.77) ; v2(65.25,16.68) 71.21,16.68 79.87,8.02 104.46,8.02 104.63,7.84 105.83,7.84 106.78,8.79 113.48,8.79 114.29,7.98 129.35,7.98 130.88,9.52 140.18,9.52 143.61,12.94 143.61,33.01 143.18,33.44 142.85,33.44 141.36,34.93 141.36,41.45 130.8,52.02 130.8,59.54 130.39,59.94 130.39,64.39 129.72,65.07 129.72,74.64 128.34,76.01 128.34,78.28 124.11,82.51 122.42,82.51 120.81,80.9 112.31,80.9 111.5,80.1 110.49,80.1 v2(110.06,80.54)
  BOTTOM w0.102: CPU1.AY26 108.12,79.8 108.42,79.5 108.68,79.5 108.75,79.57 109.09,79.57 v2(110.06,80.54) ; v1(35.46,87.9) 35.46,87.05 R5210.2 R5208.2 R5209.1 37.55,87 v2(38.37,86.17)
PANEL_SIZE_ID_CONN: length 3.6
  TOP w0.102: LCD1.22 36.45,84.61 35.65,85.41 v2(35.63,85.41)
  BOTTOM w0.102: R5210.1 35.51,85.54 v2(35.63,85.41) 35.95,85.09 v1(36.1,85.09)
PBAT_PRES1#: length 13.9
  TOP w0.102: AFTP3902.1 130.15,150.54 132.18,150.54 136.71,146 RN4301.8
  TOP w0.635: 132.52,154.72 BAT1.5 132.82,154.52
PBAT_SMBCLK1: length 12.5
  TOP w0.14: 136.6,154.63 137.2,155.23 BAT1.3 ; AFTP3904.1 133.55,150.43 137.87,146.12 RN4301.6
  TOP w0.635: 136.52,154.72 BAT1.3 136.82,154.52
PBAT_SMBDAT1: length 12.7
  TOP w0.14: RN4301.7 137.36,144.05 137.34,144.07 137.34,145.9 133.03,150.22 133.03,150.69 132.52,151.2 AFTP3903.1
  TOP w0.635: 134.52,154.72 BAT1.4 134.82,154.52
PCB_VER_AD: length 4.8
  TOP w0.102: R2404.2 164.51,18.83 C2402.2 R2406.1 164.87,19.89 v1(164.23,20.52) 164.09,20.66 KBC24.98
PCH_HDMI_CLK: length 109.4
  TOP w0.14: v2(69.1,88) 69.1,87.88 68.47,87.25 RN402.1
  L3 w0.127: v2(37.55,88.08) 37.55,88.42 35.42,90.56 22.41,90.56 21.6,91.37 21.03,91.94 v2(21,91.94) 20.98,91.97 v2(16.89,91.97)
  L4 w0.127: v2(37.55,88.08) 37.42,87.95 37.42,86.77 37.93,86.26 37.93,84.96 38.87,84.02 39.34,84.02 40.46,82.89 40.46,82.36 42.99,79.83 v2(42.99,67.76) ; v2(69.1,88) 69.14,87.96 80.38,87.96 80.46,87.89 85.16,87.89 87.45,85.6 87.45,85.16 87.72,84.89 88.09,84.89 88.47,85.27 v2(88.65,85.27)
  BOTTOM w0.14: v2(21,91.94) 20.99,91.96 Q5402.4 ; CPU1.D17 88.4,85.02 88.63,85.25 88.63,85.25 v2(88.65,85.27) ; RN5404.1 16.5,91.58 v2(16.89,91.97) ; v2(42.99,67.76) 43.06,67.83 45.62,67.83 51.52,73.73 51.52,78.9 51.87,79.25 55.86,79.25 64.25,87.64 65.4,87.64 ; 65.4,87.64 66.03,87.64 66.67,87.01 68.27,87.01 69.1,87.84 v2(69.1,88) ; 65.4,87.64 v1(65.4,87.49)
PCH_HDMI_DATA: length 109.4
  TOP w0.14: v2(68.46,87.98) 68.38,87.9 RN402.2
  L3 w0.127: v2(16.99,90.64) 17.32,90.97 20.71,90.97 20.82,90.86 21.39,90.86 22.2,90.05 35.21,90.05 36.92,88.34 v2(36.92,88.08)
  L4 w0.127: v2(36.92,88.08) 36.92,86.56 37.42,86.05 37.42,84.75 38.66,83.51 39.13,83.51 39.95,82.68 39.95,82.15 42.49,79.62 42.49,68.01 v2(42.24,67.76) ; v2(68.46,87.98) 68.46,87.89 68.9,87.46 80.17,87.46 80.25,87.38 84.95,87.38 86.94,85.39 86.94,84.95 87.51,84.38 88.3,84.38 88.67,84.75 88.93,84.75 v2(89.45,85.27)
  BOTTOM w0.14: v1(67.59,87.67) 67.59,87.53 ; 67.59,87.53 68.05,87.53 68.46,87.94 v2(68.46,87.98) ; 67.59,87.53 66.88,87.53 66.25,88.16 64.03,88.16 55.64,79.77 51.66,79.77 51,79.12 51,73.95 45.4,68.35 42.83,68.35 v2(42.24,67.76) ; Q5402.1 17,90.65 v2(16.99,90.64) 16.51,90.64 16.22,90.93 RN5404.2 ; v2(89.45,85.27) 89.43,85.26 89.43,85.25 89.2,85.02 CPU1.E17
PCH_SUSCLK_KBC: length 127
  TOP w0.14: KBC24.77 160.72,31.3 160.29,30.87 160.29,30.62 159.84,30.17 159.18,30.17 v1(159.15,30.19) 159.13,30.17 158.53,30.17 158.05,30.65 v2(158.04,30.65)
  L3 w0.14: v2(143.02,33.88) 143.02,33.82 144.1,32.75 144.1,31.12 144.45,30.77 144.45,14.01 148.89,9.57 v2(148.89,9.49)
  L4 w0.14: v2(158.04,30.65) 158.04,29.11 157.87,28.94 157.87,20.96 155.99,19.07 155.99,14.6 151.69,10.3 149.73,10.3 148.92,9.49 v2(148.89,9.49) ; v2(113.61,84.06) 113.61,84.04 114.14,83.51 122.71,83.51 123.26,82.95 124.2,82.95 128.85,78.3 128.85,76.04 130.29,74.59 130.29,65.05 130.76,64.58 130.76,60.1 131.17,59.69 131.17,52.17 141.74,41.61 141.74,35.13 142.99,33.88 v2(143.02,33.88)
  BOTTOM w0.14: R609.2 114.06,84.51 v2(113.61,84.06)
PCIE_CALRN: length 6.6
  TOP w0.254: R7318.1 157.72,115.7 157.12,115.1 157.12,114.55 v1(157.27,114.39) 157.6,114.06 158.85,114.06 159.51,114.72 v2(159.51,114.95)
  BOTTOM w0.254: GPU1.AA22 160.69,114.05 159.79,114.95 v2(159.51,114.95)
PCIE_CALRP: length 3.7
  TOP w0.254: v1(158.65,114.8) 158.9,115.05 R7321.1 159.65,115.7 v2(159.97,116.02)
  BOTTOM w0.254: v2(159.97,116.02) 160.3,115.69 160.3,115.23 GPU1.Y22
PCIE_PRX_LANTX_N0: length 94.7
  TOP w0.127: v1(93.19,89.45) 93.5,89.76 v2(93.77,89.76)
  L4 w0.114: v2(93.77,89.76) 93.62,89.6 92.99,89.6 91.7,88.31 87.72,88.31 84.23,91.8 63.35,91.8 63.16,91.8 51.14,79.77 51.14,59.17 47.67,55.7 47.67,53.75 41.93,48.01 41.93,43.09 41.46,42.62 v2(41.33,42.62)
  BOTTOM w0.127: CPU1.R8 94.18,89.35 v2(93.77,89.76) ; C3016.2 41.37,41.66 41.37,42.58 v2(41.33,42.62)
PCIE_PRX_LANTX_P0: length 95.5
  L4 w0.114: v2(40.93,42.14) 41.46,42.14 41.77,42.44 41.77,42.61 42.16,42.99 42.16,47.92 47.9,53.66 47.9,55.6 51.36,59.07 51.36,75.74 51.48,75.86 51.48,76.2 51.36,76.31 51.36,76.65 51.48,76.77 51.48,77.11 51.36,77.23 51.36,77.57 51.48,77.69 51.48,78.02 51.36,78.14 51.36,78.48 51.48,78.6 51.48,78.94 51.36,79.06 51.36,79.68 63.26,91.57 84.14,91.57 87.63,88.08 91.79,88.08 93.09,89.37 93.47,89.37 v2(93.75,89.1)
  BOTTOM w0.127: CPU1.R10 94.3,88.83 94.04,89.1 v2(93.75,89.1) ; v1(40.04,42.92) 40.14,42.92 v2(40.93,42.14) 41.13,41.93 41.13,41.76 40.79,41.42 40.59,41.42 40.42,41.58 C3014.2
PCIE_PRX_WLANTX_N1: length 157.9
  TOP w0.127: v1(189.86,35.81) 189.91,35.76 v2(189.91,34.99)
  L3 w0.114: v2(150.2,49.22) 150.06,49.08 150.06,48.46 151.76,46.75 162.17,46.75 165.47,43.45 171.04,43.45 171.17,43.58 171.49,43.58 171.63,43.45 171.95,43.45 172.08,43.58 172.41,43.58 172.54,43.45 172.87,43.45 173,43.58 173.32,43.58 173.46,43.45 173.78,43.45 173.91,43.58 174.24,43.58 174.37,43.45 174.69,43.45 174.83,43.58 175.15,43.58 175.28,43.45 175.61,43.45 175.74,43.58 176.07,43.58 176.2,43.45 176.52,43.45 176.66,43.58 176.98,43.58 177.11,43.45 177.44,43.45 177.57,43.58 177.89,43.58 178.03,43.45 179.02,43.45 184.65,37.82 188.82,37.82 189.51,37.13 189.51,35.39 v2(189.91,34.99)
  L4 w0.114: v2(150.2,49.22) 149.93,49.48 149.93,49.98 149.58,50.33 147.02,50.33 139.91,57.45 139.91,57.97 139.91,57.97 139.91,64.24 139.75,64.4 139.75,79.27 139.33,79.7 139.33,80.95 137.04,83.25 137.04,83.39 137.04,83.39 137.04,83.9 137.04,83.9 137.04,88.06 128.55,96.54 108.26,96.54 106.92,97.89 95.17,97.89 94.4,97.12 94.4,93.63 93.96,93.18 93.96,92.15 v2(93.75,91.94)
  BOTTOM w0.127: CPU1.R4 93.94,91.75 v2(93.75,91.94) ; WLAN1.23 189.81,30.5 190.26,30.05 190.65,30.05 190.94,30.34 190.94,31.76 191.78,32.61 191.78,34.45 190.62,35.61 189.76,35.61 189.63,35.48 189.63,35.27 v2(189.91,34.99)
PCIE_PRX_WLANTX_P1: length 157.2
  L3 w0.114: v2(189.27,34.99) 189.28,35 189.28,37.04 188.73,37.59 184.56,37.59 178.93,43.22 165.38,43.22 162.08,46.52 151.67,46.52 149.83,48.36 149.83,48.95 v2(149.57,49.22)
  L4 w0.114: v2(93.75,91.3) 94.19,91.74 94.19,93.09 94.63,93.53 94.63,97.02 95.27,97.66 106.82,97.66 108.17,96.32 128.45,96.32 136.81,87.96 136.81,84 136.81,83.15 139.11,80.86 139.11,79.6 139.53,79.18 139.53,64.3 139.68,64.15 139.68,58.06 139.68,57.36 146.93,50.11 149.48,50.11 149.71,49.88 149.71,49.36 v2(149.57,49.22)
  BOTTOM w0.127: 192.02,33.72 192.02,32.51 191.18,31.66 191.18,30.24 190.75,29.81 190.23,29.81 190.12,29.7 WLAN1.25 ; 192.02,33.72 192.02,34.55 190.72,35.85 189.66,35.85 189.39,35.58 189.39,35.11 v2(189.27,34.99) ; 192.02,33.72 v1(192.17,33.72) ; v2(93.75,91.3) 94.1,90.95 CPU1.R5
PCIE_PTX_LANRX_N0: length 93.3
  L4 w0.114: v2(42.44,51.88) 42.44,51.68 42.57,51.55 43.08,51.55 45.98,54.45 45.98,57.02 46.82,57.86 47.63,58.67 47.63,59.56 49.38,61.31 49.38,67.51 48.23,68.65 48.23,71.46 49.38,72.61 49.38,79.22 48.71,79.89 48.71,81.29 50.44,83.02 50.44,83.2 50.67,83.43 50.86,83.43 51.09,83.67 51.09,83.85 51.32,84.08 51.5,84.08 51.74,84.31 51.74,84.5 51.97,84.73 52.15,84.73 52.38,84.96 52.38,85.14 52.61,85.37 52.8,85.37 53.03,85.61 53.03,85.79 53.26,86.02 53.44,86.02 53.68,86.25 53.68,86.44 53.91,86.67 54.09,86.67 54.32,86.9 54.32,87.08 54.55,87.31 54.74,87.31 54.97,87.55 54.97,87.73 55.2,87.96 55.38,87.96 55.62,88.19 55.62,88.38 55.85,88.61 56.03,88.61 56.26,88.84 56.26,89.02 56.49,89.25 56.68,89.25 56.91,89.49 56.91,89.67 57.14,89.9 57.32,89.9 57.56,90.13 57.56,90.32 57.79,90.55 57.97,90.55 58.2,90.78 58.2,90.96 58.43,91.19 58.62,91.19 58.85,91.43 58.85,91.61 59.08,91.84 59.26,91.84 59.5,92.07 59.5,92.26 59.73,92.49 59.91,92.49 60.91,93.49 84.62,93.49 87.82,90.3 91.72,90.3 91.98,90.55 91.98,94.33 v2(92.1,94.45)
  BOTTOM w0.127: v2(92.1,94.45) 92.1,94.45 CPU1.L1 ; C306.1 42.43,50.28 42.43,50.99 42.58,51.14 42.58,51.51 42.44,51.65 v2(42.44,51.88) 42.44,52.06 v1(41.98,52.52)
PCIE_PTX_LANRX_N0_C: length 13.7
  BOTTOM w0.127: LOM30.14 38.65,43.75 38.66,43.74 38.76,43.74 38.81,43.7 42.49,43.7 42.76,43.97 42.76,47.36 42.49,47.63 40.56,47.63 40.43,47.76 40.43,48.15 40.56,48.28 41.35,48.28 41.72,48.65 42.26,48.65 C306.2
PCIE_PTX_LANRX_P0: length 94.4
  L4 w0.114: v2(42.14,51.33) 43.18,51.33 46.21,54.36 46.21,56.93 46.91,57.63 46.91,57.63 47.86,58.58 47.86,59.47 49.6,61.21 49.6,67.6 48.45,68.75 48.45,71.37 49.6,72.52 49.6,79.32 48.94,79.98 48.94,81.19 61.01,93.26 84.53,93.26 87.72,90.07 91.82,90.07 92.21,90.46 92.21,93.94 92.54,94.27 92.54,94.73 92.17,95.09 v2(92.12,95.09)
  BOTTOM w0.127: CPU1.L2 92.1,93.4 92.56,93.85 92.56,94.71 92.17,95.09 v2(92.12,95.09) ; v2(42.14,51.33) 42.19,51.27 42.19,50.35 C305.1 41.54,49.7 v1(40.92,49.7)
PCIE_PTX_LANRX_P0_C: length 13
  BOTTOM w0.127: v1(39.98,48) 40.19,48 ; 40.19,48 40.19,48.25 40.46,48.52 41.25,48.52 C305.2 ; 40.19,48 40.19,47.66 40.46,47.39 42.39,47.39 42.52,47.26 42.52,44.07 42.39,43.94 38.91,43.94 38.86,43.98 38.76,43.98 38.59,44.15 LOM30.13
PCIE_PTX_WLANRX_N1_C: length 13.2
  BOTTOM w0.127: 192.65,34.97 192.65,35.59 C304.2 ; 192.65,34.97 v1(192.48,34.97) ; 192.65,34.97 192.65,33.75 192.95,33.46 193.52,33.46 193.65,33.33 193.65,32.9 193.52,32.77 193.18,32.77 191.81,31.4 191.81,28.32 190.51,27.02 190.12,27.02 189.83,27.3 WLAN1.31
PCIE_PTX_WLANRX_P1_C: length 13.5
  BOTTOM w0.127: C303.2 192.89,35.7 192.89,33.85 193.05,33.7 193.62,33.7 193.89,33.43 193.89,32.8 193.62,32.53 193.28,32.53 192.05,31.3 192.05,28.47 ; 192.05,28.47 192.05,28.22 190.61,26.78 190.14,26.78 189.86,26.5 WLAN1.33 ; 192.05,28.47 v1(192.2,28.47)
PCIE_RST#_C: length 7.6
  BOTTOM w0.127: v1(114.2,88.71) 114.19,88.71 113.55,88.08 112.67,88.08 112.41,87.81 R618.2 111.83,87.57 111.58,87.83 111.58,88.46 111.21,88.83 108.77,88.83 108.45,89.15 CPU1.AY9
PCIE_TXN1_C: length 151.8
  TOP w0.127: v2(151.47,49.22) 150.96,48.7 v1(150.96,48.66)
  L3 w0.114: v2(192.28,37.53) 192.63,37.53 192.73,37.63 192.73,38.21 192.34,38.6 191.44,38.6 191.32,38.47 190.99,38.47 190.86,38.6 190.53,38.6 190.4,38.47 190.07,38.47 189.95,38.6 189.62,38.6 189.49,38.47 189.16,38.47 189.03,38.6 188.7,38.6 188.57,38.47 188.24,38.47 188.12,38.6 187.79,38.6 187.66,38.47 187.33,38.47 187.2,38.6 186.87,38.6 186.75,38.47 186.42,38.47 186.29,38.6 185.96,38.6 185.83,38.47 185.5,38.47 185.37,38.6 184.75,38.6 179.14,44.21 170.03,44.21 169.9,44.07 169.57,44.07 169.44,44.21 169.12,44.21 168.98,44.07 168.66,44.07 168.53,44.21 168.2,44.21 168.07,44.07 167.75,44.07 167.61,44.21 167.29,44.21 167.16,44.07 166.83,44.07 166.7,44.21 166.08,44.21 165.54,44.74 165.35,44.74 165.12,44.98 165.12,45.16 164.89,45.39 164.71,45.39 164.48,45.62 164.48,45.81 164.25,46.04 164.06,46.04 163.83,46.27 163.83,46.45 163.6,46.68 163.41,46.68 163.18,46.92 163.18,47.1 162.74,47.54 161.19,47.54 161.06,47.41 160.73,47.41 160.6,47.54 160.27,47.54 160.15,47.41 159.82,47.41 159.69,47.54 159.36,47.54 159.23,47.41 158.9,47.41 158.78,47.54 152.68,47.54 151.74,48.49 151.74,48.95 v2(151.47,49.22)
  L4 w0.114: v2(151.47,49.22) 151.74,49.48 151.74,49.88 150.63,51 147.24,51 140.53,57.71 140.53,64.5 140.38,64.65 140.38,79.53 139.96,79.95 139.96,81.35 137.66,83.65 137.66,88.31 128.3,97.68 122.85,97.68 122.63,97.46 121.32,97.46 121.1,97.68 116.8,97.68 116.42,97.29 108.4,97.29 107.18,98.51 94.89,98.51 92.94,96.56 92.33,96.56 v2(92.12,96.36)
  BOTTOM w0.127: v2(92.12,96.36) 91.56,95.8 91.56,93.51 CPU1.K1 ; C304.1 v2(192.28,37.53)
PCIE_TXP1_C: length 151.4
  TOP w0.127: v2(152.11,49.22) 152.11,48.59 v1(152.17,48.53)
  L3 w0.114: v2(193.16,37.51) 192.96,37.72 192.96,38.31 192.43,38.83 184.85,38.83 179.24,44.44 166.17,44.44 162.84,47.77 152.78,47.77 151.97,48.58 151.97,49.08 v2(152.11,49.22)
  L4 w0.114: v2(152.11,49.22) 151.97,49.36 151.97,49.98 150.72,51.22 147.34,51.22 140.76,57.8 140.76,64.6 140.61,64.75 140.61,79.63 140.47,79.76 140.19,80.05 140.19,81.44 137.89,83.74 137.89,88.41 128.39,97.9 122.75,97.9 122.53,97.69 121.42,97.69 121.2,97.9 116.71,97.9 116.32,97.52 108.49,97.52 107.27,98.74 94.79,98.74 92.84,96.79 92.35,96.79 v2(92.15,96.99)
  BOTTOM w0.127: v2(92.15,96.99) 92.13,96.99 91.68,96.54 91.68,96.26 91.32,95.9 91.32,93.72 91.23,93.63 91.23,93.37 91.55,93.05 CPU1.K2 ; C303.1 v2(193.16,37.51)
PCIE_WAKE#: length 301.5
  TOP w0.127: v2(59.93,8.9) 61.03,9.99 v2(61.03,10.08) ; v2(170.07,23.5) 170.09,23.48 KBC24.113 ; v2(116.43,84.04) v1(115.87,84.04)
  L3 w0.127: v2(116.43,84.04) 117.08,84.69 124.06,84.69 124.13,84.61 124.91,84.61 131.07,78.45 131.07,66.97 131.81,66.23 131.81,56.9 134.05,54.67 134.09,54.67 135.19,53.57 135.29,53.57 140.22,48.65 140.22,47.65 140.23,47.64 140.23,47.27 140.18,47.22 140.18,46.74 148.24,38.67 148.24,36.55 148.78,36.02 148.78,34.87 149.72,33.93 149.72,31.13 150.07,30.78 150.07,26.69 150.51,26.26 150.51,25.83 152.92,23.41 152.92,21.05 152.28,20.41 152.28,20.21 152.28,19.25 152.6,18.93 158.19,18.93 158.42,18.7 158.98,18.7 159.2,18.93 163.52,18.93 163.65,19.05 164.83,19.05 167.34,21.56 168.13,21.56 v2(170.07,23.5)
  L4 w0.127: v2(170.07,23.5) 170.07,22.11 169.48,21.52 169.48,18.74 170.19,18.03 170.19,14.99 168.65,13.45 163.4,13.45 163.17,13.22 160.73,13.22 159.71,12.21 159.71,9.48 157.03,6.8 156.41,6.8 153.24,3.63 152.98,3.37 148.33,3.37 142.87,3.37 142.19,4.04 141.82,4.04 141.34,3.56 140,3.56 139.49,3.05 131.96,3.05 131.32,3.7 129.44,3.7 129.22,3.47 96.02,3.47 95.82,3.66 94.61,3.66 94.27,3.32 77.36,3.32 70.14,10.53 63.88,10.53 63.04,9.69 61.41,9.69 v2(61.03,10.08) ; v2(36.01,39.41) 35.99,39.44 35.18,39.44 30.18,34.44 30.18,26.75 30.18,25.78 30.67,25.29 30.67,25.28 31.31,24.64 37.72,24.64 39.63,22.73 39.63,21.72 44.14,17.21 44.14,11.45 46.75,8.84 52.06,8.84 52.77,8.13 58.68,8.13 59.04,8.49 59.04,8.49 59.3,8.75 59.31,8.75 59.45,8.9 v2(59.93,8.9)
  BOTTOM w0.127: v2(116.43,84.04) 116.22,83.82 R622.1 ; LOM30.21 35.88,40.79 35.74,40.64 35.74,39.72 36.01,39.44 v2(36.01,39.41) 35.94,39.34 R3033.1
PCIE_WAKE#_R: length 12.2
  TOP w0.127: v2(114.25,84.04) 114.25,84.06 113.53,84.78 v1(110.26,84.78) 109.4,84.78 108.4,85.77 108.4,86.56 107.41,87.55 v2(107.19,87.55)
  BOTTOM w0.127: v2(114.25,84.04) 114.41,84.21 R626.1 115.77,83.82 R622.2 ; CPU1.AW11 107.5,87.86 v2(107.19,87.55)
PD4403_A: length 3.2
  BOTTOM w0.102: PQ4409.B 117.29,135.29 PD4404.A v1(116.13,133.55)
PD4403_K: length 2.6
  BOTTOM w0.102: PD4404.K 121.04,133.55 PR4468.2 v1(122.15,133.35)
PE_GPIO0: length 256.8
  TOP w0.102: v2(126.67,68.22) 127.73,69.28 127.73,73.8 123.97,77.56 v1(123.11,77.56) 122.93,77.39 114.7,77.39 v2(114.18,77.9)
  L3 w0.102: v2(126.67,68.22) 125.78,67.33 125.78,56.11 127.43,54.46 127.43,53.22 138.28,42.37 138.28,41.98 144.84,35.41 144.84,34.08 145.56,33.36 145.56,31.73 145.92,31.38 145.92,14.66 150.01,10.57 153.65,10.57 154.12,10.1 160.47,10.1 v2(160.73,9.85)
  L4 w0.102: v2(190.7,104.59) 191.49,103.8 191.49,83.9 190.62,83.03 190.62,83.02 190.02,82.41 190.02,80.84 190.35,80.51 190.35,78.29 191.51,77.13 191.51,70.15 184.76,63.4 184.76,49.71 181.98,46.93 179.57,46.93 178.62,45.99 178.62,43.26 178.79,43.1 178.79,40.52 178.74,40.47 178.74,39.93 178.79,39.88 178.79,36.52 175.82,33.55 173.98,33.55 172.54,32.11 172.54,31.97 171.88,31.31 171.88,26.27 170.76,25.15 170.76,21.9 169.97,21.12 169.97,18.95 170.68,18.24 170.68,14.78 168.74,12.84 163.5,12.84 163.38,12.73 161.27,12.73 160.87,12.32 160.87,9.99 v2(160.73,9.85)
  BOTTOM w0.102: v2(190.7,104.59) 190.7,104.15 188.83,102.28 178.06,102.28 175.57,99.79 171.76,99.79 170.01,98.04 164.25,98.04 R7326.2 164.1,98.18 D7301.2 ; R637.1 R607.1 114.71,78.21 114.6,78.21 114.3,77.9 v2(114.18,77.9) 113.39,78.69 112.36,78.69 112.1,78.95 108.76,78.95 108.52,79.19 108.26,79.19 CPU1.AY27
PE_GPIO1: length 235.3
  TOP w0.102: v2(148.92,77.03) 143.33,77.03 140.18,73.88 134.8,73.88 134.19,74.49 128.91,74.49 124.16,79.24 120.77,79.24 119.78,80.23 119.77,80.23 119.65,80.36 116.85,80.36 116.33,80.36 115.87,80.81 113.51,80.81 v1(112.89,81.43) v2(112.47,81.86) ; v2(148.92,78.68) 148.54,79.06 PD8201.K ; v2(135.84,99.15) 136.78,99.15 137.89,98.04 137.89,94.89 139.72,93.06 139.72,90.14 138.61,89.02 137.95,89.02 v2(137.87,89.1)
  L3 w0.102: v2(179.12,80.43) 179.35,80.66 191.79,80.66 v2(192.25,81.12) ; v2(148.92,78.68) v2(148.92,77.03) 148.54,76.65 143.84,76.65 142.31,75.13 142.31,56.17 147.9,50.58 147.9,49.34 v2(149.43,47.82)
  L4 w0.102: v2(189.68,110.43) 189.68,108.08 193.04,104.73 193.04,83.23 192.38,82.57 192.38,81.25 v2(192.25,81.12) ; v2(148.92,78.68) 149.04,78.81 177.49,78.81 v2(179.12,80.43)
  BOTTOM w0.102: v2(148.92,78.68) 148.33,78.1 146.66,78.1 145.54,76.98 137.84,76.98 137.61,77.21 137.61,81.42 137.97,81.78 137.97,83.1 137.54,83.53 137.54,88.76 v2(137.87,89.1) ; R8310.1 R8309.1 134.52,101.25 134.52,99.64 135,99.15 v2(135.84,99.15) ; v2(149.43,47.82) 149.62,48.02 153.33,48.02 154.1,48.79 157.45,48.79 159.14,47.1 161.58,47.1 162.74,48.25 166.65,48.25 167.33,47.57 PD8307.K ; PD8308.A 191.46,115 192.2,114.27 192.2,113.33 191.84,112.97 PQ8319.2 191.2,112.97 190.78,112.55 190.78,111.52 v2(189.68,110.43) ; v2(112.47,81.86) 112.72,82.11 R636.1 112.33,82.9 109.27,82.9 109.11,83.06 109.02,83.06 108.68,83.4 108.38,83.4 108.33,83.35 108.03,83.35 107.98,83.4 107.68,83.4 107.43,83.15 106.6,83.15 CPU1.AU21
PEG_C_RXN0: length 13.2
  TOP w0.127: C7302.1 146.82,108.77 147.36,109.3 147.93,109.3 148.17,109.06 148.17,108.65 ; v2(153.24,108.53) 153.24,108.82 153.15,108.91 152.22,108.91 151.84,108.53 151.84,108.04 151.57,107.78 150.71,107.78 150.44,108.04 150.44,108.91 150.31,109.03 149.81,109.03 149.68,108.91 149.68,108.04 149.41,107.78 148.44,107.78 148.17,108.04 148.17,108.65 ; 148.17,108.65 v1(148.03,108.65)
  BOTTOM w0.127: v2(153.24,108.53) 153.24,108.81 153.41,108.98 154.02,108.98 154.29,108.72 154.57,108.72 GPU1.AG31
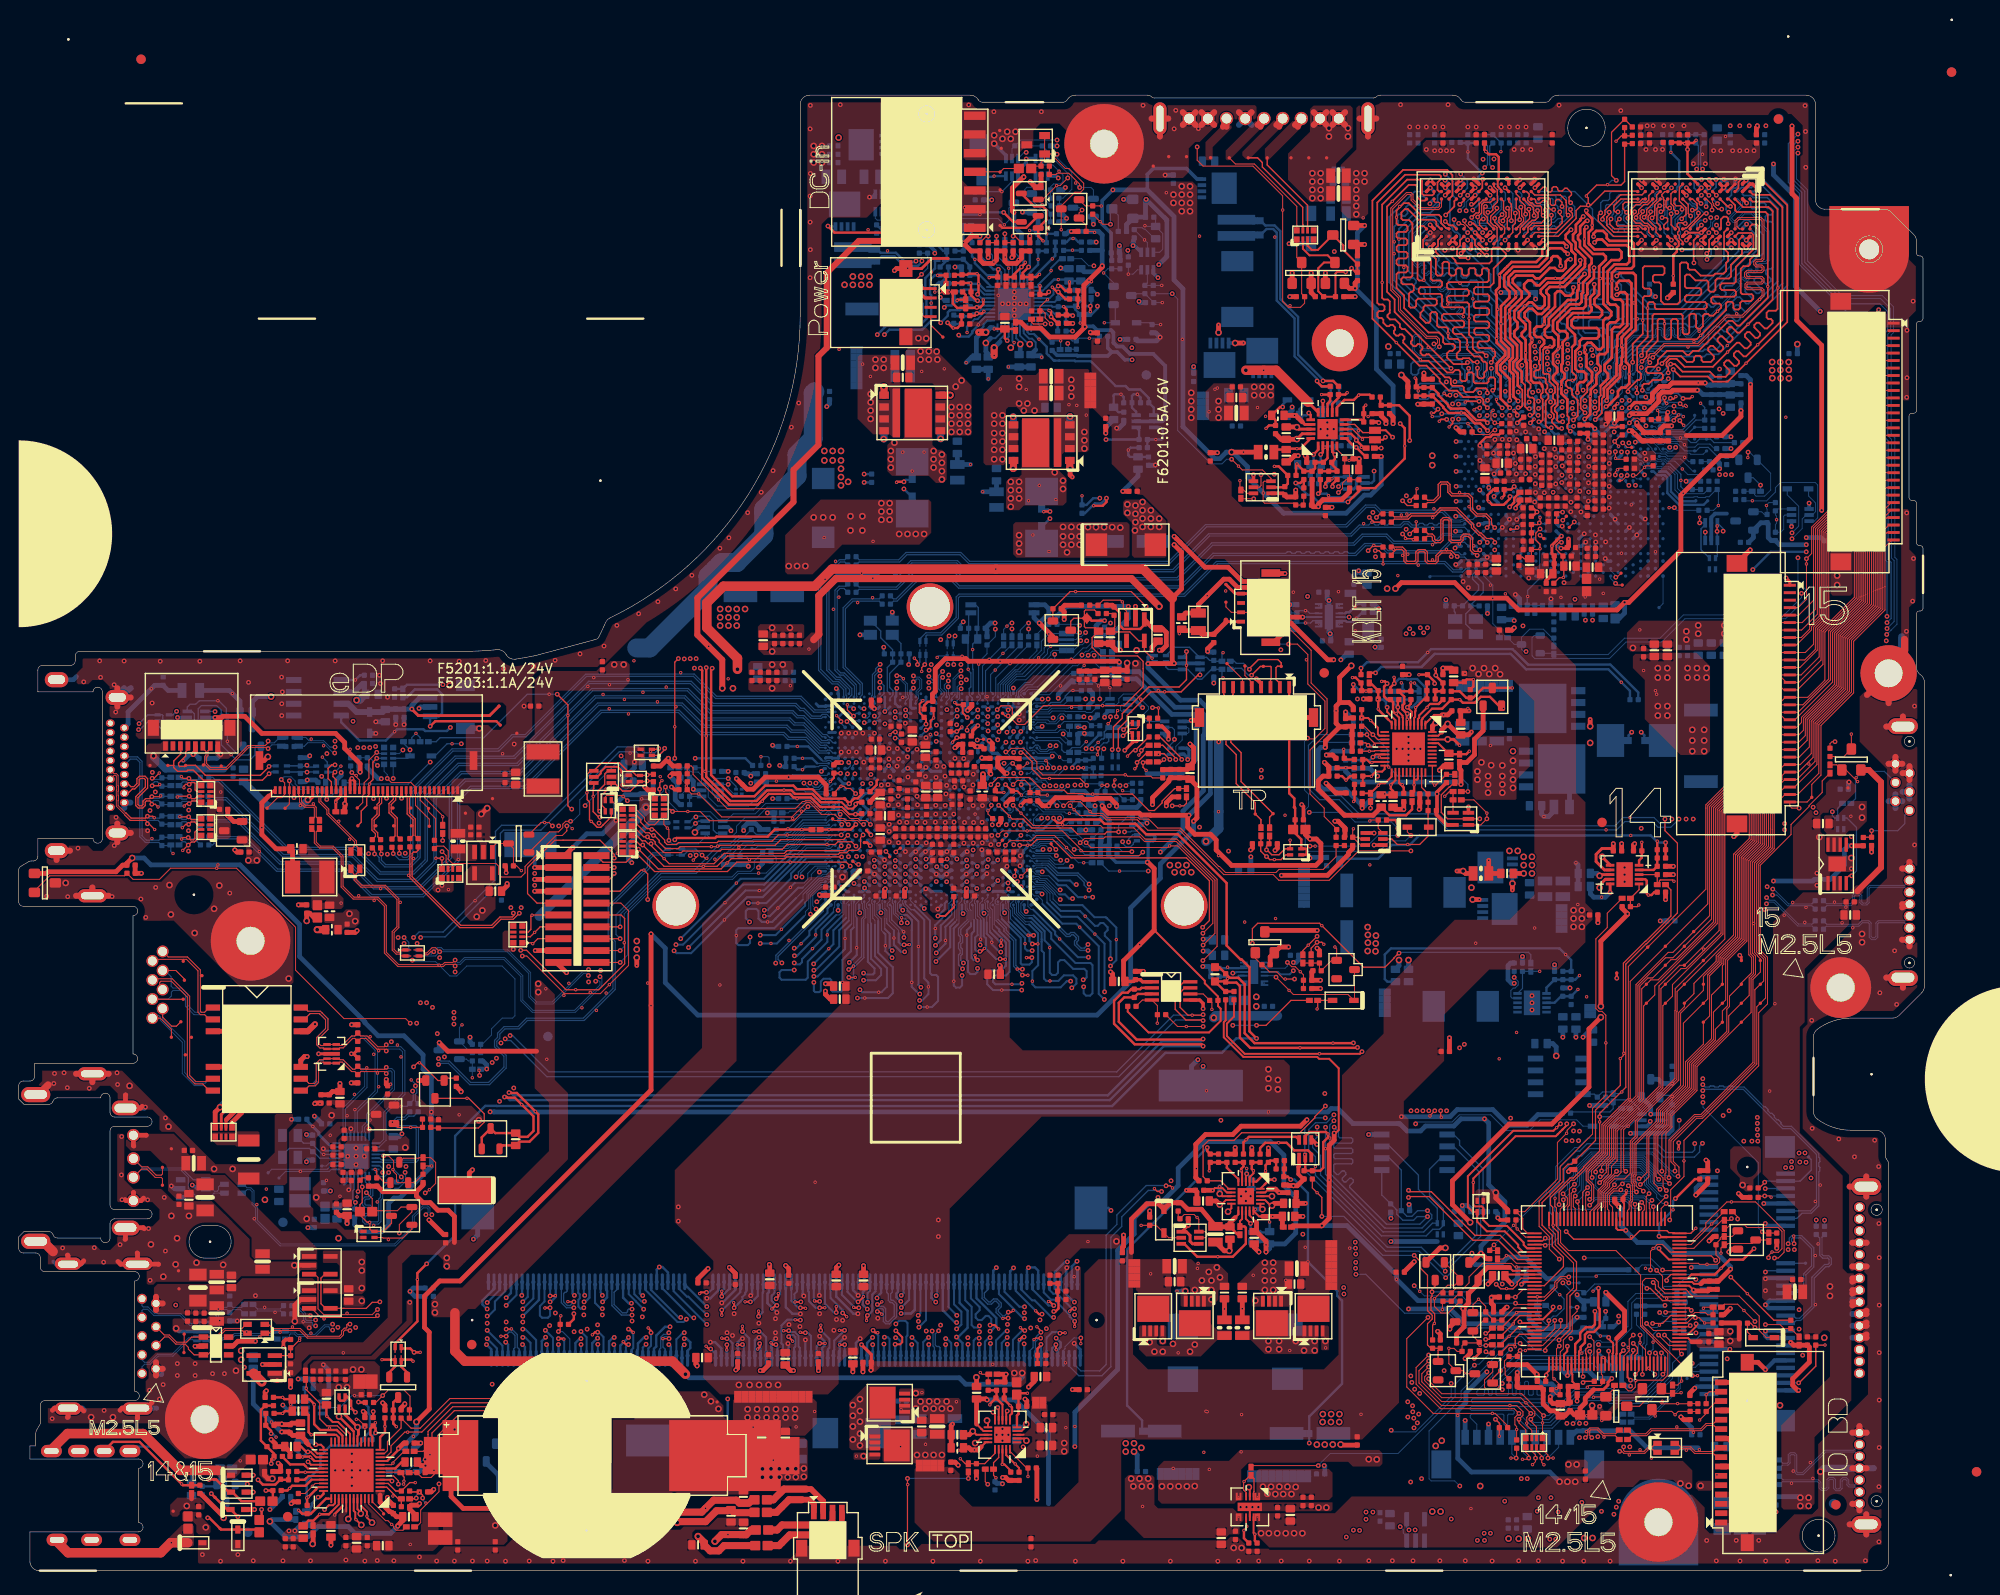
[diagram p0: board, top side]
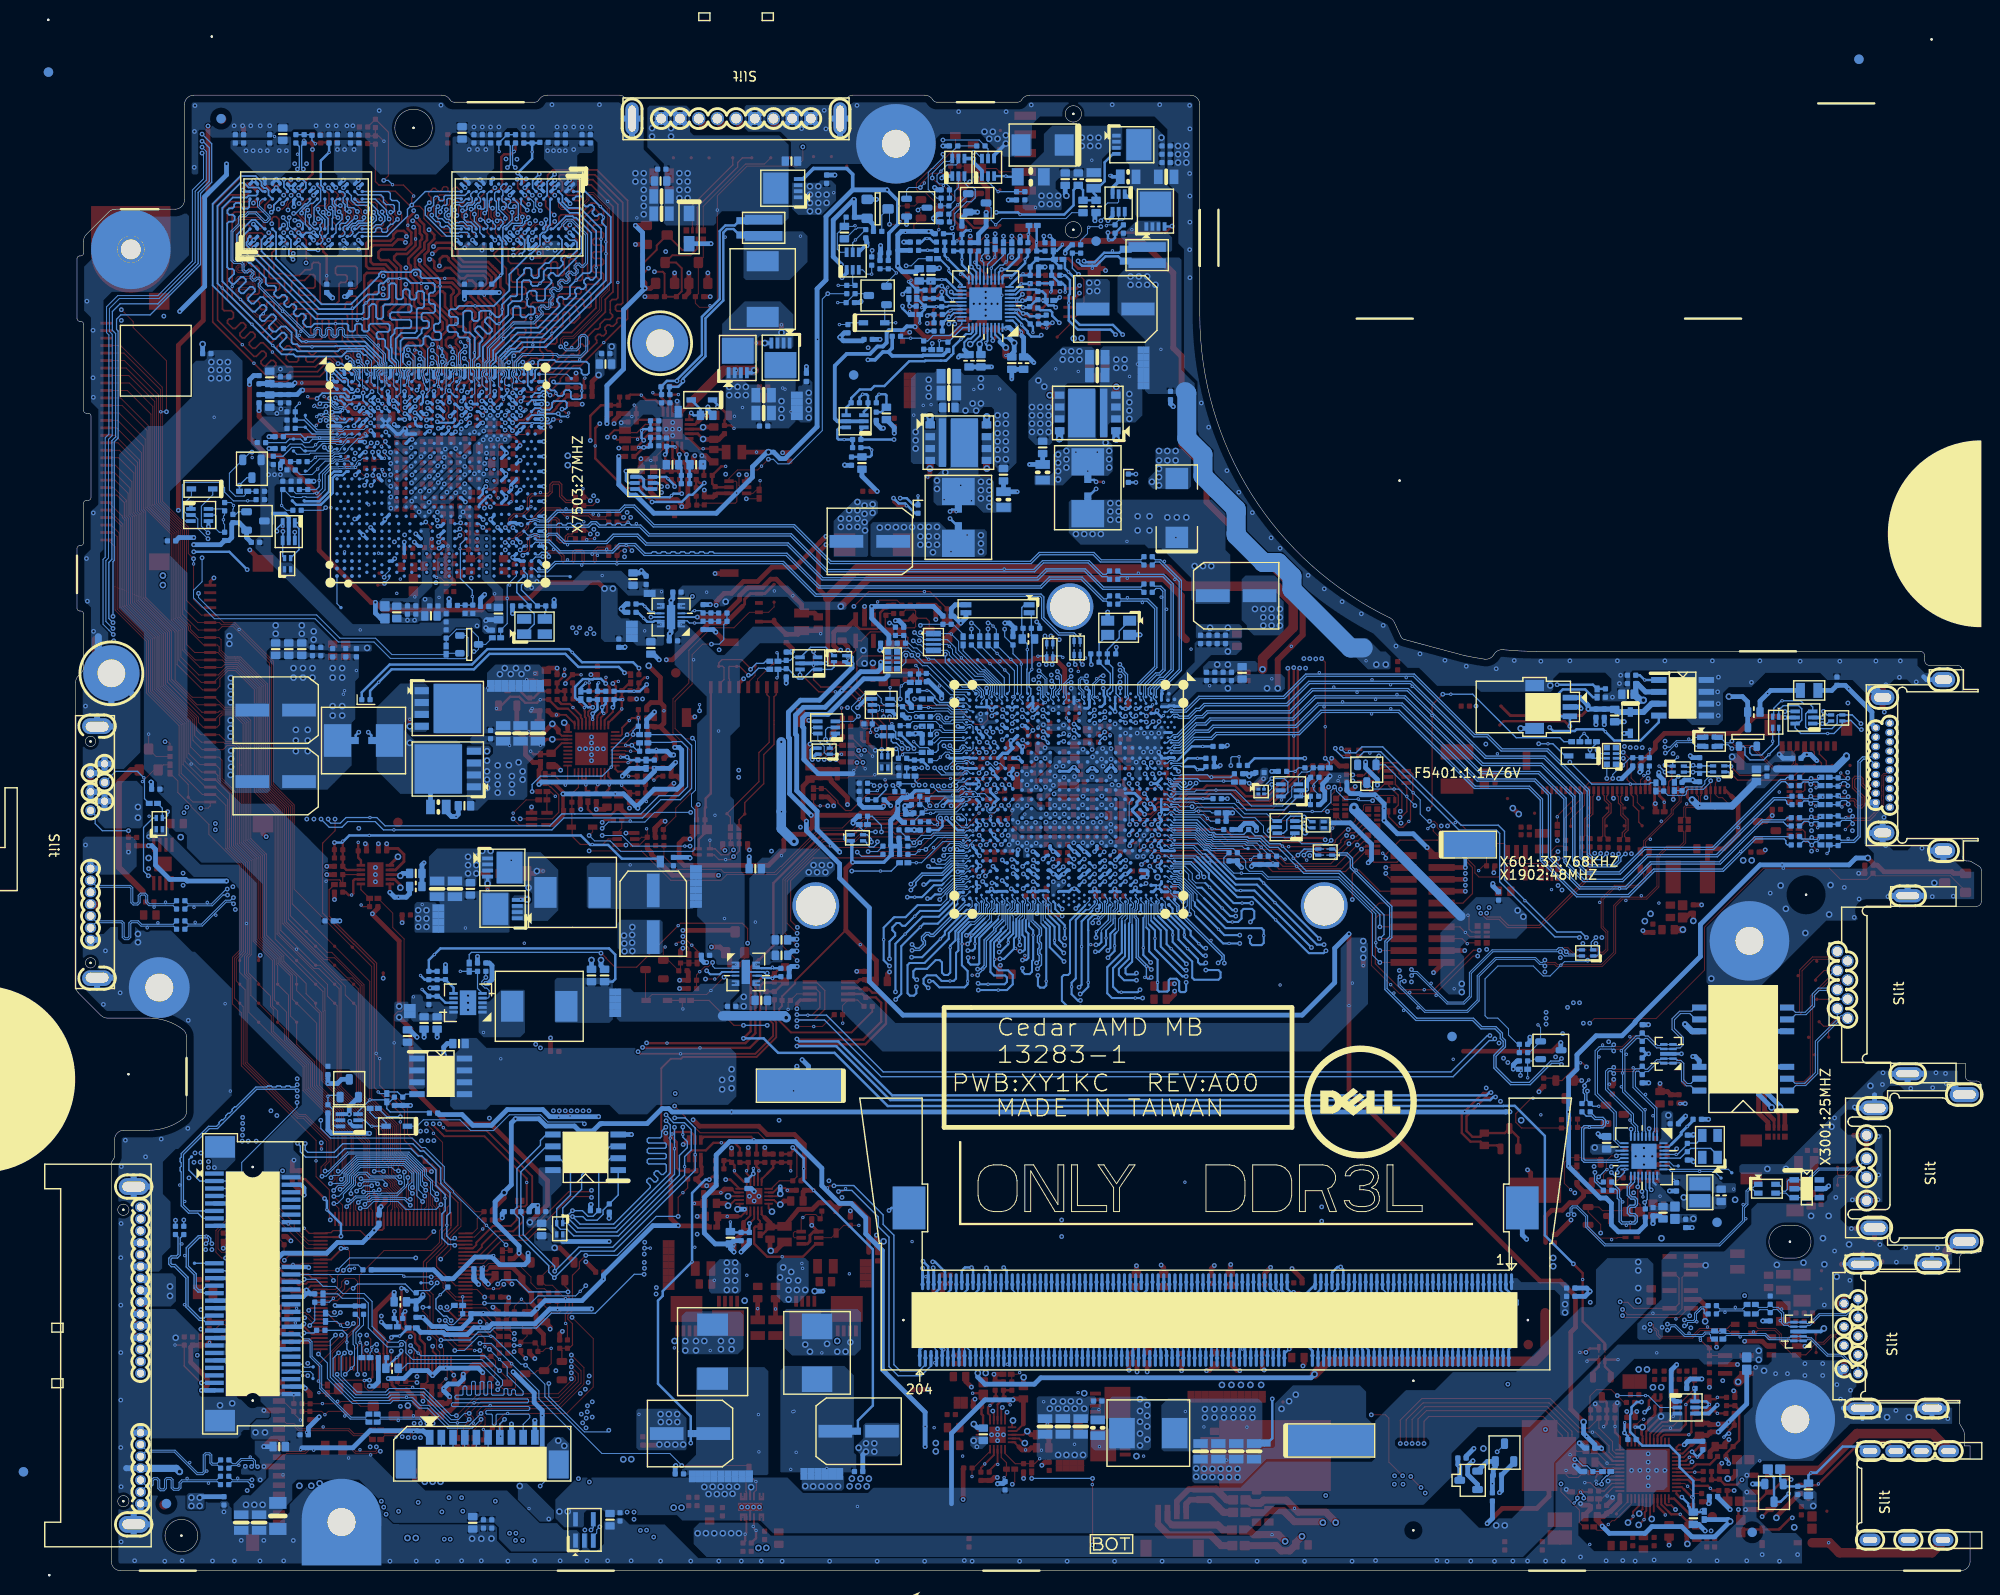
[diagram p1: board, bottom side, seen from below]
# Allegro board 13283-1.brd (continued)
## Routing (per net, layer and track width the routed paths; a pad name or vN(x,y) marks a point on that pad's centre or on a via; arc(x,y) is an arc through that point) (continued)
PEG_C_RXN1: length 13.7
  TOP w0.127: v2(156.29,109.23) 156.14,109.08 155.73,109.08 155.52,109.29 155.52,109.67 ; v1(155.65,109.67) 155.52,109.67 ; 155.52,109.67 155.52,110.56 155.15,110.93 154.53,110.93 154.26,110.66 154.26,110.38 154.14,110.25 153.36,110.25 153.24,110.38 153.24,112.44 152.97,112.7 152.39,112.7 152.12,112.44 152.12,110.38 151.99,110.25 151.6,110.25 151.46,110.39 151.46,110.69 151.2,110.94 150.76,110.94 C7304.1
  BOTTOM w0.127: v2(156.29,109.23) 155.89,109.63 GPU1.AF28
PEG_C_RXN2: length 14.2
  TOP w0.127: v1(147.9,112.97) 147.9,112.77 ; 147.9,112.77 147.15,112.77 C7306.1 ; 147.9,112.77 148.54,112.77 148.88,113.11 151.42,113.11 152.04,113.73 153.87,113.73 155.64,111.97 155.64,111.71 156.3,111.05 156.42,111.05 157.02,110.45 157.64,110.45 157.9,110.2 v2(157.9,110.04)
  BOTTOM w0.127: GPU1.AF26 157.49,109.8 157.73,110.04 v2(157.9,110.04)
PEG_C_RXN3: length 13.4
  TOP w0.127: 154.12,115.26 155.1,115.26 155.52,114.84 155.52,113.59 156.02,113.09 157.01,113.09 157.54,112.56 157.54,111.97 v2(157.88,111.62) ; 154.12,115.26 153.36,115.26 153.11,115.51 153.11,116.25 152.84,116.51 152.11,116.51 151.84,116.25 151.84,115.06 151.33,114.55 150.7,114.55 C7308.1 ; 154.12,115.26 v1(154.12,115.38)
  BOTTOM w0.127: GPU1.AD26 157.87,111.62 v2(157.88,111.62)
PEG_C_RXP0: length 12.9
  TOP w0.127: 152.73,109.15 153.25,109.15 v2(153.87,108.53) ; 152.73,109.15 152.12,109.15 151.6,108.63 151.6,108.15 151.47,108.02 150.81,108.02 150.68,108.15 150.68,109.01 150.41,109.28 149.71,109.28 149.44,109.01 149.44,108.15 149.31,108.02 148.54,108.02 148.41,108.15 148.41,109.16 148.03,109.54 C7301.1 ; 152.73,109.15 v1(152.73,109.29)
  BOTTOM w0.127: GPU1.AH30 154.65,108.48 153.92,108.48 v2(153.87,108.53)
PEG_C_RXP1: length 13.4
  TOP w0.127: C7303.1 150.65,110.7 151.1,110.7 151.22,110.58 151.22,110.29 151.5,110.01 152.09,110.01 152.36,110.28 152.36,112.34 152.49,112.46 152.87,112.46 152.99,112.34 152.99,110.28 153.26,110.01 154.1,110.01 ; v2(156.01,108.66) 155.83,108.84 155.63,108.84 155.28,109.19 155.28,110.46 155.05,110.69 154.63,110.69 154.51,110.56 154.51,110.28 154.24,110.01 154.1,110.01 ; 154.1,110.01 v1(154.1,109.87)
  BOTTOM w0.127: GPU1.AG29 155.83,108.84 v2(156.01,108.66)
PEG_C_RXP2: length 13.1
  TOP w0.127: C7305.1 147.15,112.53 148.64,112.53 148.98,112.87 151.25,112.87 ; 151.25,112.87 151.52,112.87 152.14,113.49 153.77,113.49 155.39,111.87 155.39,111.61 156.2,110.81 156.32,110.81 v2(157.09,110.04) ; 151.25,112.87 v1(151.25,112.69)
  BOTTOM w0.127: GPU1.AF27 156.7,109.64 v2(157.09,110.04)
PEG_C_RXP3: length 12.9
  TOP w0.127: v2(157.07,111.62) 157.3,111.85 157.3,112.46 156.91,112.85 155.92,112.85 155.28,113.49 155.28,113.86 ; 155.28,113.86 155.28,114.74 155,115.02 153.26,115.02 152.87,115.41 152.87,116.15 152.74,116.27 152.21,116.27 152.08,116.15 152.08,114.96 151.43,114.31 150.7,114.31 C7307.1 ; 155.28,113.86 v1(155.14,113.86)
  BOTTOM w0.127: v2(157.07,111.62) 157.07,111.62 GPU1.AD27
PEG_CLKREQ#: length 244.7
  L3 w0.127: v2(158.95,7.43) 158.3,6.79 152.95,6.79 152.55,7.18 147.94,7.18 145.85,9.28 144.17,9.28 142.33,11.11 142.33,29.03 v2(141.76,29.61)
  L4 w0.127: v2(186.32,116.17) 184.81,116.17 179.96,111.33 179.96,110.96 182.16,108.76 186.04,108.76 188.22,106.57 188.22,106.35 191.25,103.32 191.25,84 190.38,83.13 190.38,83.12 189.77,82.51 189.77,80.74 189.8,80.71 189.8,80.69 190.1,80.39 190.1,78.19 191.27,77.03 191.27,70.25 184.52,63.5 184.52,49.81 181.88,47.17 179.47,47.17 178.38,46.09 178.38,43.08 178.55,42.92 178.55,40.62 178.5,40.57 178.5,39.83 178.55,39.78 178.55,36.62 175.72,33.79 174.08,33.79 173.88,33.79 172.3,32.21 172.3,32.07 171.64,31.41 171.64,26.37 170.51,25.25 170.51,22 169.73,21.22 169.73,18.85 170.44,18.14 170.44,14.88 168.71,13.15 163.47,13.15 163.41,13.09 163.4,13.09 163.28,12.97 161.17,12.97 160.63,12.42 160.63,10.71 160.09,10.18 160.09,8.58 v2(158.95,7.43) ; v2(141.76,29.61) 141.29,30.08 141.29,30.47 138.57,33.19 138.57,41.3 127.29,52.58 127.29,73.9 125.14,76.05 122.01,76.05 v2(120.83,74.87)
  BOTTOM w0.127: Q7504.D 185.52,116.97 v2(186.32,116.17) R7518.1 ; R610.1 116.6,74.87 v1(117.75,74.87) v2(120.83,74.87)
PEG_RXN0: length 75.9
  TOP w0.127: v1(145.95,107.74) 145.95,108.64 C7302.2 145.93,108.73 145.5,109.16 v2(145.11,109.16)
  L4 w0.114: v2(91.53,91.46) 91.42,91.35 91.23,91.35 91.09,91.49 91.09,94.16 88.55,96.7 88.55,103.02 91.35,105.82 100.44,105.82 101.02,105.24 114.39,105.24 115.27,106.13 133.28,106.13 133.42,105.99 139.77,105.99 142.38,108.59 144.54,108.59 v2(145.11,109.16)
  BOTTOM w0.127: v2(91.53,91.46) 91.53,91.38 91.65,91.25 91.89,91.25 92.1,91.47 CPU1.L4
PEG_RXN1: length 80.9
  TOP w0.127: v1(149.49,112.25) C7304.2 149.17,111.32 v2(148.79,110.94)
  L4 w0.114: v2(148.79,110.94) 148.11,110.26 142.52,110.26 139.52,107.26 133.04,107.26 132.76,106.98 114.92,106.98 114.03,106.09 101.38,106.09 100.79,106.67 90.99,106.67 87.7,103.38 87.7,96.41 89.98,94.13 89.98,91.54 90.13,91.39 90.33,91.39 v2(90.42,91.48)
  BOTTOM w0.127: CPU1.J4 91,91.47 90.79,91.25 90.55,91.25 90.42,91.38 v2(90.42,91.48)
PEG_RXN2: length 79.1
  TOP w0.127: v2(145.23,112.72) 145.62,113.1 C7306.2 ; v2(89.3,91.45) 88.64,92.12 v1(88.64,92.66)
  L4 w0.114: v2(89.3,91.45) 89,91.45 88.82,91.64 88.82,94.4 86.85,96.37 86.85,103.73 90.64,107.52 101.15,107.52 101.73,106.94 113.68,106.94 114.57,107.83 132.4,107.83 132.69,108.11 138.72,108.11 142.29,111.68 144.2,111.68 v2(145.23,112.72)
  BOTTOM w0.127: v2(89.3,91.45) 89.6,91.75 CPU1.G4
PEG_RXN3: length 84.6
  TOP w0.127: v2(148.79,114.5) 149.17,114.88 C7308.2 149.49,115.7 v1(149.58,115.79)
  L4 w0.114: v2(148.79,114.5) 148.09,113.79 142.88,113.79 138.05,108.96 132.33,108.96 132.05,108.68 114.21,108.68 113.85,108.31 113.33,107.79 102.08,107.79 101.5,108.37 90.29,108.37 86,104.08 86,95.19 87.65,93.53 87.65,91.81 v2(88.59,90.87)
  BOTTOM w0.127: v2(88.59,90.87) 88.59,90.86 CPU1.E7
PEG_RXP0: length 75.4
  TOP w0.127: C7301.2 145.87,109.61 144.96,109.61 ; v1(144.96,109.72) 144.96,109.61 ; 144.96,109.61 144.79,109.61 v2(144.35,109.16)
  L4 w0.114: v2(91.54,90.73) 91.53,90.73 90.86,91.4 90.86,94.07 88.32,96.61 88.32,103.12 91.25,106.05 100.54,106.05 101.12,105.47 114.29,105.47 115.18,106.35 133.38,106.35 133.52,106.21 139.68,106.21 142.28,108.82 144,108.82 v2(144.35,109.16)
  BOTTOM w0.127: v2(91.54,90.73) 91.76,90.95 CPU1.L5
PEG_RXP1: length 80.5
  TOP w0.127: v1(148.33,110.46) 148.42,110.55 ; 148.42,110.55 v2(148.03,110.94) ; 148.42,110.55 148.54,110.43 C7303.2
  L4 w0.114: v2(90.45,90.75) 89.75,91.45 89.75,94.04 87.47,96.32 87.47,103.47 90.9,106.9 100.89,106.9 101.47,106.32 113.94,106.32 114.83,107.21 132.66,107.21 132.94,107.48 139.43,107.48 142.43,110.49 147.58,110.49 v2(148.03,110.94)
  BOTTOM w0.127: CPU1.J5 90.8,90.75 v2(90.45,90.75)
PEG_RXP2: length 78.9
  TOP w0.127: 144.87,112.32 144.98,112.21 C7305.2 ; 144.87,112.32 v2(144.47,112.72) ; 144.87,112.32 v1(144.75,112.21)
  L4 w0.114: v2(144.47,112.72) 144.47,112.28 144.11,111.91 142.2,111.91 138.63,108.34 132.59,108.34 132.31,108.06 114.47,108.06 113.59,107.17 101.82,107.17 101.24,107.75 90.55,107.75 86.62,103.82 86.62,96.28 86.75,96.14 88.59,94.3 88.59,91.54 v2(89.32,90.82)
  BOTTOM w0.127: v2(89.32,90.82) 89.45,90.95 CPU1.G5
PEG_RXP3: length 84.9
  TOP w0.127: v1(87.49,91.51) 87.96,91.04 v2(87.96,90.87) ; C7307.2 148.54,113.99 v2(148.03,114.5)
  L4 w0.114: v2(87.96,90.87) 87.96,91.18 87.43,91.72 87.43,93.44 85.9,94.96 85.77,95.1 85.77,104.18 90.19,108.6 101.59,108.6 102.18,108.02 113.23,108.02 113.62,108.41 113.62,108.41 114.12,108.91 131.96,108.91 132.24,109.19 137.96,109.19 142.78,114.02 147.99,114.02 148.12,114.15 148.12,114.4 v2(148.03,114.5)
  BOTTOM w0.127: CPU1.D7 87.96,90.69 v2(87.96,90.87)
PEG_TXN0: length 66.7
  BOTTOM w0.127: v1(147.04,109.31) 147.04,109.15 ; 147.04,109.15 146.48,109.15 145.7,109.92 143.96,109.92 142.92,108.88 142.29,108.88 142.14,109.03 141.78,109.03 141.63,108.88 141.27,108.88 141.12,109.03 140.76,109.03 140.61,108.88 140.26,108.88 140.1,109.03 139.75,109.03 139.6,108.88 139.24,108.88 139.09,109.03 138.73,109.03 138.58,108.88 138.22,108.88 138.07,109.03 137.72,109.03 137.56,108.88 137.21,108.88 137.06,109.03 136.7,109.03 136.55,108.88 136.19,108.88 136.04,109.03 135.68,109.03 135.53,108.88 127.75,108.88 124.26,105.39 100.64,105.39 99.69,106.34 96.19,106.34 93.86,104 93.58,104 C445.2 ; 147.04,109.15 152.02,109.15 153.17,110.3 154.55,110.3 GPU1.AE31
PEG_TXN1: length 70.7
  BOTTOM w0.102: 152.35,111.02 153.27,111.02 153.46,110.83 154.2,110.83 154.54,110.98 154.8,110.98 155.15,110.82 155.47,110.82 GPU1.AD28
  BOTTOM w0.127: C457.2 89.9,105.26 93.88,105.26 95.83,107.21 100.06,107.21 101,106.27 123.9,106.27 127.62,109.99 142.76,109.99 143.7,110.93 146.35,110.93 147.11,110.16 149.17,110.16 ; 152.35,111.02 151.5,110.16 149.17,110.16 ; 149.17,110.16 v1(149.17,110.33)
PEG_TXN2: length 66
  BOTTOM w0.127: GPU1.AC31 154.55,111.9 152.41,111.9 152.23,112.08 151.9,112.08 151.72,111.9 151.39,111.9 151.21,112.08 150.89,112.08 150.7,111.9 150.38,111.9 150.2,112.08 149.87,112.08 149.69,111.9 149.05,111.9 148.69,112.26 148.13,112.26 147.77,111.9 147.13,111.9 146.95,112.08 146.62,112.08 146.44,111.9 146.12,111.9 145.93,112.08 145.61,112.08 145.43,111.9 145.1,111.9 144.92,112.08 144.59,112.08 144.41,111.9 143.86,111.9 ; 143.86,111.9 143.4,111.9 142.47,110.96 127.28,110.96 123.46,107.14 101.37,107.14 100.42,108.09 95.43,108.09 93.97,106.62 93.62,106.62 C478.2 ; 143.86,111.9 v1(143.86,112.06)
PEG_TXN3: length 70.7
  BOTTOM w0.102: GPU1.AB28 155.54,112.49 155.02,112.49 154.82,112.58 154.57,112.58 154.19,112.43 153.43,112.43 153.37,112.49
  BOTTOM w0.127: 151.38,113.49 145.68,113.49 145.14,114.04 144.06,114.04 141.96,111.94 126.95,111.94 123.02,108.02 101.73,108.02 100.78,108.96 94.91,108.96 94.13,108.18 89.9,108.18 C448.2 ; 151.38,113.49 v1(151.38,113.63) ; 151.38,113.49 152.37,113.49 153.37,112.49
PEG_TXP0: length 66.3
  BOTTOM w0.127: C477.2 93.58,103.76 93.96,103.76 96.29,106.09 99.59,106.09 100.54,105.15 124.36,105.15 127.85,108.64 143.02,108.64 144.06,109.68 145.6,109.68 146.38,108.91 148.59,108.91 ; 148.59,108.91 152.12,108.91 153.27,110.06 154.67,110.06 GPU1.AF30 ; 148.59,108.91 v1(148.59,108.78)
PEG_TXP1: length 70.2
  BOTTOM w0.102: 152.45,110.78 152.49,110.82 153.19,110.82 153.37,110.63 154.24,110.63 154.58,110.77 154.76,110.77 155.1,110.62 155.31,110.62 GPU1.AE29
  BOTTOM w0.127: 152.45,110.78 151.6,109.92 151.23,109.92 ; 151.23,109.92 147.01,109.92 146.25,110.69 143.8,110.69 142.86,109.75 127.72,109.75 124,106.02 100.9,106.02 99.96,106.97 95.93,106.97 93.98,105.02 89.89,105.02 C447.2 ; 151.23,109.92 v1(151.23,109.8)
PEG_TXP2: length 65.5
  BOTTOM w0.127: 151.25,111.66 148.95,111.66 148.59,112.02 148.23,112.02 147.87,111.66 143.5,111.66 142.57,110.72 127.38,110.72 123.56,106.9 101.27,106.9 100.32,107.85 95.53,107.85 94.07,106.38 93.53,106.38 C452.2 ; 151.25,111.66 v1(151.25,111.52) ; 151.25,111.66 154.67,111.66 GPU1.AD30
PEG_TXP3: length 70.2
  BOTTOM w0.102: GPU1.AC29 155.24,112.29 154.97,112.29 154.78,112.37 154.61,112.37 154.23,112.23 153.29,112.23 153.2,112.32
  BOTTOM w0.127: v1(148.49,113.07) 148.49,113.25 ; 148.49,113.25 152.27,113.25 153.2,112.32 ; 148.49,113.25 145.58,113.25 145.04,113.8 144.16,113.8 142.06,111.7 127.05,111.7 123.12,107.78 101.63,107.78 100.68,108.72 95.01,108.72 94.23,107.94 89.89,107.94 C441.2
PH_APU_VDD: length 34.2
  TOP w0.254: v1(93.9,116.48) 93.95,116.53 v2(94.69,116.53)
  L3 w0.254: v2(98.63,133.55) 90.75,133.55 89.35,132.15 89.35,120.85 91.58,118.62 91.58,117.23 92.53,116.27 94.43,116.27 v2(94.69,116.53)
  BOTTOM w0.254: PG4701.1 94.89,116.73 v2(94.69,116.53) ; PR4705.1 100.67,134.89 99.62,134.89 99.55,134.83 99.39,134.67 99.39,134.31 v2(98.63,133.55)
PH_VDDNB: length 29
  TOP w0.254: v1(109.65,113.33) 109.67,113.35 v2(110.31,113.35)
  L4 w0.254: v2(110.31,113.35) 110.56,113.1 111.88,113.1 118.9,120.12 118.9,126.48 v2(112.72,132.66)
  BOTTOM w0.254: PG4720.1 110.11,113.56 v2(110.31,113.35) ; PR4712.1 v2(112.72,132.66)
PLT_RST#: length 507.3
  TOP w0.102: v2(40.71,36.14) 40.71,37.04 42.06,38.39 Q3003.E 40.9,38.91 40.51,38.52 37.92,38.52 R3016.1 37.82,39.82 v2(37.19,40.45)
  L3 w0.102: v2(60.59,81.87) 60.22,82.24 57.53,82.24 53.46,86.3 44.4,86.3 44.19,86.1 43.84,86.1 43.63,86.3 39.11,86.3 38.55,85.74 38.19,85.74 37.64,86.3 35.51,86.3 34.92,85.72 34.92,85.23 34.67,84.98 34.31,84.98 34.28,85.01 v2(32.41,85.01) ; v2(142.97,35.15) 142.97,35.15 144.18,33.95 144.18,33.81 144.9,33.08 144.9,31.45 145.26,31.1 145.26,14.39 145.91,13.74 149.8,9.85 v2(150.06,9.85)
  L4 w0.102: v2(40.71,36.14) 40.56,35.98 40.56,25.09 41.78,23.87 42.48,23.87 42.78,23.57 42.78,21.45 46.05,18.18 46.05,12.08 47.49,10.63 52.8,10.63 53.51,9.92 57.58,9.92 59,11.35 69.92,11.35 77.47,3.8 94.16,3.8 94.44,4.08 96,4.08 96.19,3.89 129.05,3.89 129.27,4.12 131.49,4.12 132.14,3.47 139.32,3.47 139.82,3.98 141.15,3.98 145.04,7.87 147.89,7.87 149.8,9.77 149.98,9.77 v2(150.06,9.85) 151.84,9.85 156.79,14.8 156.79,17.47 v2(158.7,19.37) ; v2(190.32,108.4) 190.32,108.02 193.44,104.89 193.44,82.51 193.02,82.09 192.78,81.85 192.78,79.12 194.05,77.85 194.05,70.59 186.28,62.82 186.28,49.4 186.46,49.23 186.46,42.45 185.77,41.77 185.77,41.19 184.89,40.31 184.89,37.31 181.71,34.13 181.13,34.13 180.64,33.64 180.64,32.43 v2(179.4,31.18) ; v2(142.97,35.15) 142.97,35.2 142.54,35.62 142.54,43.17 137.89,47.82 137.61,47.82 137.36,48.07 137.36,48.35 134.74,50.97 134.47,50.97 134.35,51.1 133.46,51.1 133.14,51.41 133.14,52.24 131.98,53.41 131.98,60.02 131.57,60.43 131.57,65.68 131.1,66.15 131.1,74.93 130.41,75.61 130.41,77.88 124.53,83.76 123.6,83.76 120.01,87.34 119.91,87.34 119.89,87.36 116.67,87.36 v2(116.08,87.95) ; v2(37.19,40.45) 37.19,41.25 34.76,43.67 34.76,47.35 38.87,51.46 38.87,62.76 33.6,68.04 33.6,83.82 v2(32.41,85.01)
  BOTTOM w0.102: v2(116.08,87.95) 115.83,87.71 C601.2 115.25,87.52 114.02,87.52 113.97,87.57 R618.1 ; v2(190.32,108.4) 190.32,105.83 191.23,104.92 191.23,104.11 189,101.87 178.23,101.87 175.74,99.38 171.93,99.38 170.18,97.63 164.08,97.63 164.06,97.6 162.18,97.6 161.87,97.91 161.87,99.84 162.11,100.08 D7301.1 ; v2(60.59,81.87) 60.54,81.87 62.32,83.65 v1(62.81,83.65) 65.05,83.65 D401.3 ; v2(32.41,85.01) 32.83,84.59 R2448.2 ; WLAN1.22 179.68,30.9 v2(179.4,31.18) 178.13,31.18 177.37,30.42 176.03,30.42 175.27,29.66 172.98,29.66 172.13,28.81 172.13,26.14 170.44,24.45 169.34,24.45 169.16,24.63 168.8,24.63 168.63,24.45 168.6,24.45 168.53,24.38 168.53,23.32 167.8,22.59 160.39,22.59 158.19,20.39 158.19,19.88 v2(158.7,19.37)
PLT_RST#_DEBUG: length 4.1
  TOP w0.127: v2(157.97,16.2) 158.38,15.78 R6502.2 v1(158.38,14.39)
  BOTTOM w0.127: v2(157.97,16.2) 158.47,15.69 DB1.7
PLT_RST#_EC: length 6.1
  TOP w0.102: v2(178.8,26.23) 178.67,26.1 KBC24.7
  BOTTOM w0.102: v2(178.8,26.23) 178.27,26.76 C2415.2 177.38,28.73 R2416.1 176.69,28.73 v1(176.27,29.15)
PLT_RST#_LAN: length 10
  TOP w0.127: Q3003.C 39.88,37.18 39.01,36.31 RN3001.4 37.8,36.31 37.56,36.54 37.56,37.25 v1(37.54,37.28) 37.28,37.28 36.5,38.07 R3016.2 36.5,39.16 36.74,39.41 36.74,41.07 v2(36.75,41.07)
  BOTTOM w0.127: v2(36.75,41.07) 36.68,41.14 LOM30.19
PM_CLKRUN#_EC: length 157.8
  TOP w0.102: KBC24.8 178.46,26.5 179.03,27.07 v2(179.35,27.07) 179.75,27.07 180.31,26.51 v1(180.34,26.51) R2401.1
  L3 w0.102: v2(163.9,7.82) 163.7,8.02 163.32,8.02 162.84,8.5 160.75,8.5 159.88,9.36 157.87,9.36 157.03,8.53 153.67,8.53 153.28,8.92 148.85,8.92 145.8,11.97 145.8,12.13 144.07,13.86 144.07,30.61 143.72,30.97 143.72,32.29 v2(143.02,33)
  L4 w0.102: v2(104.14,79.82) 104.21,79.82 105.35,80.96 108.36,80.96 109.42,79.9 111.59,79.9 111.63,79.94 111.96,79.94 112.7,80.67 120.91,80.67 122.51,82.28 123.85,82.28 124.15,81.98 124.15,81.05 124.93,80.28 126.25,78.96 127.2,78.96 128.12,78.04 128.12,75.86 129.44,74.54 129.44,62.2 130.16,61.47 130.16,59.85 130.57,59.44 130.57,51.92 141.13,41.36 141.13,34.84 142.97,33 v2(143.02,33) ; v2(163.9,7.82) 164.3,7.42 165.16,7.42 166.39,6.19 167.46,6.19 171.63,10.37 172.84,10.37 174.78,12.3 174.78,15.63 176.53,17.38 176.53,21.9 176.43,22 176.43,23.96 177.37,24.9 177.37,25.41 179.03,27.07 v2(179.35,27.07)
  BOTTOM w0.102: CPU1.AP25 104.14,80.09 v2(104.14,79.82)
PM_LAN_ENABLE: length 212.5
  TOP w0.127: KBC24.119 172.49,23.1 172.71,23.31 v2(172.71,23.59) ; v2(42.24,53.92) 42.67,54.35 v1(42.87,54.35) 42.95,54.35 44.84,52.46 Q3001.G 45.76,52.71 R3023.1
  L3 w0.127: v2(70.13,8.04) 70.64,8.55 75.91,8.55 80.55,3.92 95.93,3.92 96.17,3.67 128.7,3.67 129.23,4.2 131.53,4.2 132.33,3.41 141.82,3.41 v2(142.01,3.6)
  L4 w0.127: v2(142.01,3.6) 142.49,3.12 147.12,3.12 147.12,3.12 148.43,3.12 148.43,3.12 153.09,3.12 153.5,3.52 156.35,6.38 158.6,6.38 163.6,11.38 164.54,11.38 165.48,12.32 168.89,12.32 171.15,14.59 171.15,18.43 171.08,18.51 171.08,21.43 172.71,23.05 v2(172.71,23.59) ; v2(42.24,53.92) 41.92,53.92 37.02,49.01 37.02,46.43 37.63,45.82 37.63,40.23 35.93,38.53 34.65,38.53 30.43,34.31 30.43,25.88 31.42,24.9 38.31,24.9 39.89,23.32 39.89,21.83 44.42,17.29 44.42,11.53 46.85,9.1 52.16,9.1 52.87,8.39 58.43,8.39 59.39,9.34 60.12,9.34 61.77,7.69 69.77,7.69 v2(70.13,8.04)
PM_LAN_ENABLE_R: length 4.1
  TOP w0.127: C3015.2 R3022.2 v1(41.93,47.44) 40.56,47.44 Q3004.G
PM_PWRBTN#: length 287.7
  TOP w0.102: v1(113.31,90.26) 113.33,90.24 v2(113.99,90.24) ; KBC24.117 171.69,22.96 172.27,23.54 172.27,24.78 v2(172.71,25.21)
  L3 w0.102: v2(185.98,47.24) 185.98,47.26 185.54,47.69 185.54,48.68 186.15,49.29 186.15,59.6 195.27,68.72 195.27,79.22 196.16,80.11 196.16,83.25 194.92,84.5 194.92,87.88 195.6,88.56 195.6,134.71 190.85,139.46 190.85,148.87 189.57,150.15 189.57,151.07 188.75,151.89 188.75,152.48 187.4,153.82 187.4,154.73 187.07,155.06 173.48,155.06 169.11,150.69 166.19,150.69 163.27,153.61 148.06,153.61 145.62,151.17 142.4,151.17 141.45,150.22 141.45,142.01 143,140.46 143,138.85 142.19,138.04 142.19,133.67 143.79,132.07 143.79,131.18 145.26,129.71 145.26,126.02 148.21,123.08 148.21,116.78 147.23,115.8 147.23,114.1 144.52,111.4 144.14,111.4 142.95,111.4 140.36,108.81 132.43,108.81 123.37,99.74 117.81,99.74 117.45,99.38 117.27,99.38 116.48,98.6 116.48,98.4 115.34,97.26 115.34,95.14 113.51,93.31 113.51,90.72 v2(113.99,90.24)
  L4 w0.102: v2(172.71,25.21) 172.82,25.33 172.82,30.92 173.48,31.58 173.48,31.72 174.37,32.61 176.21,32.61 180.48,36.88 180.48,42.53 185.18,47.24 v2(185.98,47.24)
  BOTTOM w0.102: R625.1 113.87,90.37 v2(113.99,90.24)
PM_PWRBTN#_R: length 5.1
  BOTTOM w0.102: CPU1.BA8 111.13,89.7 111.4,89.98 111.9,89.98 R630.1 R625.2
PM_RSMRST#: length 11.2
  TOP w0.102: R629.1 R628.1 120.32,91.23 v2(120.11,91.43)
  BOTTOM w0.102: Q601.3 120.66,90.89 v2(120.11,91.43) 120.85,92.16 120.85,92.45 v1(120.03,93.27) 119.49,93.81 118.16,93.81 117.68,93.32 117.68,92.92 117.41,92.65 Q603.5
PM_RSMRST#_R: length 10.7
  BOTTOM w0.102: v1(116.72,94.5) 116.72,94.44 116.74,94.43 Q603.6 116.42,93.3 115.58,92.46 R649.2 114.77,91.84 114.21,91.84 114.1,91.94 111.96,91.94 111.91,91.99 110.54,91.99 110.23,91.68 108.81,91.68 108.47,91.35 CPU1.AY5
PM_SLP_S3#: length 306.1
  TOP w0.102: D3603.3 142.89,61.09 D3606.K 142.19,61.66 136.35,61.66 135.91,62.09 v1(135.89,62.09) 135.89,62.12 v2(134.49,63.52) ; R3609.2 131.98,11.24 v2(139.01,11.24) ; KBC24.64 163.69,36.69 164.36,36.02 164.36,34.88 166.32,32.91 166.32,30.25 165.61,29.54 165.61,26.13 163.29,23.81 v2(163.29,23.56) ; PR4910.2 103.39,9.51 v2(103.66,9.25)
  L3 w0.102: v2(155.72,21.99) 155.27,22.44 155.27,22.95 151.31,26.91 151.31,29.1 150.75,29.66 150.75,30.55 150.75,30.55 150.75,31.06 150.37,31.44 150.37,34.23 149.48,35.12 149.48,36.64 149.15,36.97 149.15,40.84 148.84,41.14 147.89,41.14 143.2,45.83 143.2,49.95 135,58.15 135,62.93 134.49,63.44 v2(134.49,63.52) 134.26,63.75 134.26,71.52 135.96,73.22 135.96,79.19 137.23,80.46 137.36,80.46 v2(138.05,81.15) 136.72,81.15 133.73,84.14 133.73,85.16 133.22,85.67 v2(132.92,85.67) ; v2(191.95,81.7) 191.21,80.97 178.89,80.97 v2(178.36,80.43)
  L4 w0.102: v2(178.36,80.43) 177.87,79.95 173.12,79.95 172.66,79.49 147.57,79.49 v2(147.52,79.44) ; v2(103.66,9.25) 103.87,9.03 104.88,9.03 105.05,8.86 105.41,8.86 106.36,9.81 116.83,9.81 117.55,10.53 138.3,10.53 v2(139.01,11.24) ; v2(110.12,93.29) 110.88,92.52 119.44,92.52 120.04,91.93 125.85,91.93 132.11,85.67 v2(132.92,85.67) ; v2(191.95,81.7) 191.95,82.57 192.73,83.36 192.73,104.6 188.95,108.38 188.95,110.33 v2(189.68,111.07)
  BOTTOM w0.102: v2(147.52,79.44) 146.85,80.12 142.95,80.12 141.91,81.15 v2(138.05,81.15) ; v2(139.01,11.24) 139.01,11.27 140.28,12.54 147.55,12.54 153.65,18.65 153.65,19.96 155.72,22.03 v2(155.72,21.99) 155.83,22.1 156.21,22.1 159.21,25.09 160.73,25.09 162.25,23.56 v2(163.29,23.56) ; CPU1.AY3 108.6,92.85 109.28,92.85 109.28,92.85 109.68,92.85 v2(110.12,93.29) ; v2(134.49,63.52) 134.33,63.68 U3603.5 ; PD8308.K 189.18,115.13 190.4,113.91 190.4,111.78 v2(189.68,111.07)
PM_SLP_S5#: length 413
  TOP w0.127: v2(95.07,9.87) 95.07,9.24 v1(95.1,9.21) 95.07,9.19 v2(95.07,2.76) ; v2(176.27,31.06) 176.27,31.23 176.74,31.7 KBC24.21 ; PR4907.1 v2(101.58,9.87)
  L3 w0.127: v2(110.66,91.27) 110.66,91.58 112.4,93.33 112.66,93.59 112.66,93.66 113.29,94.3 113.29,98.17 113.55,98.43 113.8,98.43 116.25,100.88 116.88,100.88 117.29,101.29 117.48,101.48 117.48,101.48 117.57,101.57 122.26,101.57 131.31,110.62 131.34,110.62 131.36,110.65 131.63,110.65 132.13,110.65 132.13,110.65 139.1,110.65 144.17,115.72 144.17,121.13 143.83,121.47 143.83,124.19 138.08,129.94 138.08,137.08 138.95,137.95 138.95,144.84 137.39,146.4 137.39,150.13 139.89,152.63 144.89,152.63 148.19,155.94 165.44,155.94 166.29,156.79 187.43,156.79 188.87,155.35 188.87,154.42 v2(190.32,152.98) ; v2(191.72,42.03) 182.67,42.03 181.91,42.79 v2(181.71,42.79)
  L4 w0.127: v2(181.71,42.79) 180.97,42.05 180.97,36.64 178.1,33.77 178.1,32.68 176.48,31.06 v2(176.27,31.06) 176.27,30.59 173.68,28 173.68,26.26 174.33,25.61 174.33,24.46 173.61,23.74 173.61,22.95 171.86,21.2 171.86,15.08 171.86,15.08 171.86,14.29 168.17,10.6 163.83,10.6 158.91,5.67 156.65,5.67 154.21,3.23 153.19,2.21 152.99,2.21 131.8,2.21 131.03,2.98 129.74,2.98 129.51,2.76 v2(95.07,2.76) ; v2(199.84,101.46) 200.57,100.73 200.57,99.25 198.37,97.05 198.37,97.04 198.14,96.81 198.14,95.25 198.52,94.87 198.52,86.1 200,84.62 200,81.27 200.8,80.47 200.8,68.8 196.73,64.74 194.59,64.74 190.75,60.9 190.75,51.27 190.95,51.07 190.95,46.9 192.56,45.3 192.56,42.87 v2(191.72,42.03)
  BOTTOM w0.127: v2(101.58,9.87) v2(95.07,9.87) ; v2(199.84,101.46) 200.29,101.9 200.29,107.9 199.96,108.23 199.96,120.93 199.57,121.32 199.57,132.4 199.91,132.75 199.91,134.75 199.08,135.58 195.04,135.58 190.74,139.88 190.74,147.49 189.55,148.68 189.55,152.27 190.25,152.98 v2(190.32,152.98) ; v2(110.66,91.27) 110.57,91.35 CPU1.BA5
PQ3802_1: length 8.2
  TOP w0.102: v2(113.48,148.02) 113.48,148.38 112.32,149.55 111.07,149.55 110.94,149.42 PR4202.1 PR4209.2
  BOTTOM w0.102: v1(113.05,148.51) 113.05,148.45 v2(113.48,148.02) 114.7,148.02 114.96,147.77 PQ4202.B
PQ3808D: length 12.7
  BOTTOM w0.102: PQ4208.D 105.92,145.83 105.92,144.52 v1(105.43,144.03) 104.76,144.7 97.91,144.7 97.28,145.33 PC4208.2
PQ3808G: length 3.9
  BOTTOM w0.102: PC4209.1 110.37,145.1 PR4215.1 110.44,145.23 v1(109.5,146.17) 108.37,147.3 PQ4208.G
PQ3809_D: length 2.6
  BOTTOM w0.254: PR4214.2 104.19,149.17 104.26,149.24 v1(104.34,149.24) PQ4206.3
PQ4008_2: length 4.7
  TOP w0.254: PQ4408.2 135.37,115.94 PC4425.1 135.75,116.32 PR4437.2 134.78,118.18 v1(134.31,118.18)
PQ4008_6: length 2.5
  TOP w0.102: PQ4408.6 131.39,115.29 131.01,115.65 PR4426.1 130.63,115.75 v1(130.63,116.65)
PQ4203_5: length 6.7
  BOTTOM w0.102: PC4210.1 PR4218.1 110.37,148.09 110.69,148.4 111.45,148.4 111.71,148.66 111.71,149.34 v1(111.28,149.77) 110.61,150.44 109.67,150.44 109.42,150.69 PQ4203.5
PQ4405_2: length 3.6
  BOTTOM w0.102: v1(122.27,137.55) PR4476.2 PR4475.2 120.72,137.8 PQ4410.2
PQ4405_3: length 2.5
  BOTTOM w0.102: PQ4410.3 119.66,139.21 119.2,138.75 v1(118.69,138.75) PR4466.1
PQ4405_5: length 5.9
  BOTTOM w0.102: PC4434.1 121.51,142.54 120.47,143.58 120.32,143.58 120.2,143.71 119.52,143.71 PR4470.2 v1(120.43,142.41) 120.72,142.12 PQ4410.5
PQ4405_6: length 6.1
  BOTTOM w0.102: PC4434.2 121.61,144.66 PR4473.1 ; PC4434.2 120.7,143.86 120.62,143.93 v1(120.47,143.93) ; PC4434.2 122.37,143.1 122.37,141.42 122.04,141.09 PQ4410.6
PQ4408_C: length 3.8
  BOTTOM w0.102: PQ4409.C 119.2,136.66 PR4475.1 PR4464.1 v1(122.32,135.7)
PQ4408_E: length 3.8
  BOTTOM w0.102: PR4467.1 PR4469.2 116.5,139.32 v1(116.05,138.88) 117.1,137.82 PQ4409.E
PQ4502_2: length 4.9
  TOP w0.102: PQ4502.2 123.01,35.63 PD4505.1 121.68,36.96 PR4522.1 120.08,36.96 v1(120.06,36.95)
PQ4502_5: length 6.8
  TOP w0.102: PQ4502.5 126.95,35.63 127.07,35.76 127.07,36.14 126.93,36.28 PQ4502.6 126.24,37.61 v1(126.05,37.79) 125.73,38.12 124.67,38.12 PR4521.1 124.03,37.85 PR4520.2
PQ9302_G: length 3.7
  BOTTOM w0.102: PQ8320.G 186.44,113.32 186.73,113.03 PC8324.2 187.02,113.61 186.95,113.67 v1(186.95,113.99) 186.95,114.05 187.21,114.3 PR8349.2
PR4601_1: length 1.8
  TOP w0.102: PR4901.2 103.71,20.96 PR4906.1 103.04,21.02 v1(102.86,21.2)
PR4605_2: length 2.6
  TOP w0.508: v1(99.9,15.69) 99.74,15.54 PC4919.1 PR4905.2
PR9319_1: length 7.5
  BOTTOM w0.102: PQ8319.6 188.11,113.62 PR8349.1 187.91,112.97 188.03,112.84 v1(188.03,112.46) 188.03,112.08 187.91,111.96 PR8352.1 188.48,111.13 188.8,111.45 188.8,112.84 188.92,112.97 PQ8319.5
PROCHOT_EC: length 9.6
  TOP w0.102: Q2401.G 183.29,35.77 R2438.1 182.18,35.77 182.01,35.6 182.01,35.45 181.55,34.99 R2442.1 181.55,33.79 181.95,33.39 181.95,33.04 181.7,32.78 v1(180.59,32.78) 179.78,32.78 179.66,32.9 KBC24.24
PS_0: length 4
  TOP w0.127: 161.81,111.94 162.47,111.94 v2(162.66,112.13) 162.74,112.21 v1(162.74,112.69) ; 161.81,111.94 C7517.2 ; 161.81,111.94 R7522.1 R7521.1
  BOTTOM w0.127: v2(162.66,112.13) 162.75,112.04 GPU1.AC19
PS_1: length 6.4
  TOP w0.127: R7524.1 160.87,108.46 161.03,108.3 C7519.2 161.81,108.49 R7517.1 162.68,109.29 v1(162.74,109.36) 162.74,109.85 162.28,110.3 162.28,111.03 v2(162.74,111.49)
  BOTTOM w0.127: v2(162.74,111.49) 162.98,111.24 GPU1.AD19
PS_2: length 6.5
  TOP w0.127: v2(165.02,110.05) 164.77,110.05 164.46,109.75 164.46,109.3 R7526.1 165.19,107.6 C7518.2 165.28,106.34 v1(165.22,106.29) 165.19,106.26 164.8,106.26 R7523.1
  BOTTOM w0.127: GPU1.AE17 164.63,110.44 v2(165.02,110.05)
PS_3: length 9.6
  BOTTOM w0.127: R7527.1 162.21,103.29 C7516.2 R7520.1 161.36,104.21 v1(161.41,104.26) 161.41,104.92 162.68,106.19 162.68,109.85 GPU1.AE20
PS_ID: length 2.7
  TOP w0.102: PQ4201.S 114.09,146.05 PR4205.1 115.76,146.05 115.77,146.04 v1(115.8,146.04)
PS_ID_R: length 4.9
  TOP w0.102: PR4217.1 105.36,150.06 AFTP3802.1 104.95,149.7 DCIN1.4
PS_ID_R2: length 16.4
  TOP w0.102: PD4204.1 109.74,151.08 109.36,150.7 PR4209.1 108.56,150.31 PR4217.2 ; PD4204.1 110.41,151.61 111.96,150.06 112.34,150.06 113.92,148.48 113.92,147.84 113.59,147.52 112.98,147.52 111.52,146.05 PQ4201.D v1(111.52,143.5) ; PD4204.1 PD4204.2
PSID_DISABLE#_R_C: length 4.7
  TOP w0.102: v2(113.74,145.61) 113.42,145.29 PQ4201.G 114.18,143.99 PR4203.2 114.98,143.32 v1(115.09,143.22)
  BOTTOM w0.102: PQ4202.C 113.48,145.86 v2(113.74,145.61)
PSID_EC: length 257.3
  TOP w0.102: v2(164.79,24.05) 164.49,23.75 KBC24.99 ; PR4205.2 v1(115.68,144.37) 115.96,144.09 v2(116.79,144.09)
  L3 w0.102: v2(189.63,43.15) 188.31,44.47 180.31,44.47 179.72,45.05 167.12,45.05 v2(166.16,46.02)
  L4 w0.102: v2(116.79,144.09) 118.86,144.09 121.69,146.91 121.69,149.03 123.96,151.3 145.57,151.3 147.72,153.46 162.79,153.46 165.76,150.49 169.45,150.49 172.73,153.76 187.25,153.76 188.57,152.44 188.57,151.91 188.71,151.77 188.71,150.15 190.45,148.41 190.45,141.5 196.57,135.37 196.57,99.62 195.97,99.02 195.97,94.35 196.35,93.97 196.35,85.16 197.76,83.75 197.76,80.43 198.63,79.57 198.63,77.95 197.76,77.08 197.76,76.72 197.99,76.5 197.99,71.29 188.57,61.87 188.57,50.35 188.75,50.17 188.75,44.04 v2(189.63,43.15) ; v2(164.79,24.05) 164.79,24.1 165.27,24.57 165.27,26.51 165.38,26.62 165.38,26.97 164.8,27.55 164.19,27.55 163.7,28.04 163.7,33.21 166.57,36.08 166.57,38.17 165.73,39.02 165.73,42.05 166.22,42.54 166.22,43.81 166.16,43.86 v2(166.16,46.02)
  BOTTOM w0.102: PR4204.2 117.61,145.06 PD4203.3 116.79,145.58 v2(116.79,144.09)
PSL_IN1#: length 4.5
  TOP w0.102: KBC24.73 160.2,32.9 159.37,33.72 v1(159.13,33.72) 158.76,33.35 R2430.2
PSL_IN2#: length 7.9
  TOP w0.102: KBC24.93 163.33,24.9 164.31,25.87 v2(164.31,26.78)
  BOTTOM w0.102: v2(164.31,26.78) 163.86,26.33 163.42,26.33 162.44,27.31 R2425.1 R2427.2 v1(162.44,29.3)
PSL_OUT#: length 10.8
  TOP w0.102: R2432.1 153.68,30.17 154.51,30.17 155.14,30.8 155.14,31.44 156.59,32.88 159.66,32.88 160.05,32.5 v1(160.22,32.5) KBC24.74
PURE_HW_SHUTDOWN#: length 12.4
  TOP w0.102: R2424.1 156.71,26.81 Q2404.B 155.55,25.12 R2602.2 156.17,24.38 R2439.2 154.39,24.07 C2610.1 153.87,23.46 153.54,23.79 v1(152.98,23.79) 152.98,22.16 D3602.3 154.48,21.4 154.81,21.07 Q2602.D
PWR_0D95V_BOOT: length 4.2
  TOP w0.305: PU4806.10 v2(170.23,72.59)
  BOTTOM w0.508: PR4820.1 168.12,72.43 168.48,72.07 v1(169.31,72.07) 169.72,72.07 v2(170.23,72.59)
PWR_0D95V_BOOT_R: length 2.6
  BOTTOM w0.508: v1(166.57,75.76) 166.8,75.53 PC4833.2 PR4820.2
PWR_0D95V_CCM: length 2.6
  TOP w0.254: PU4806.5 173.33,76.01 173.62,76.31 PR4824.1 v1(173.62,77.94)
PWR_0D95V_EN: length 5.2
  TOP w0.127: PU4806.3 PC4831.1 PR4819.2 175.5,73.65 175.5,73.78 175.51,73.79 175.51,73.83 175.6,73.92 176.92,73.92 v1(177.06,73.78)
PWR_0D95V_FB: length 4.8
  TOP w0.254: v1(175.27,78.07) PC4832.2 PR4822.2 PR4823.1 174.88,74.99 PU4806.4
PWR_0D95V_LGATE: length 13.5
  TOP w0.305: v3(169.36,76.4) 170.23,75.53 PU4806.6
  TOP w0.508: v3(159.78,73.54) v1(159.78,72.84)
  L4 w1.016: v3(169.36,76.4) 165.17,76.4 162.32,73.54 v3(159.78,73.54)
  BOTTOM w0.381: PU4805.4 v3(159.78,73.54)
PWR_0D95V_PHASE: length 19.9
  TOP w0.305: PU4806.8 169.24,74.49 v3(169.11,74.36)
  TOP w0.508: PR4837.1 154.76,74.62 v3(154.51,74.87) v1(153.85,74.87)
  L4 w1.016: v3(155.39,73.09) 156.92,73.09 158.82,71.19 163.01,71.19 166.19,74.36 v3(169.11,74.36)
  BOTTOM w0.508: PC4833.1 168.86,74.62 v3(169.11,74.36)
PWR_0D95V_PWR: length 37.9
  TOP w0.254: v2(176.16,77.92) PC4832.1 PR4822.1
  BOTTOM w0.254: PG4832.1 145.41,76.19 146.89,77.67 148.79,77.67 149.81,78.68 v1(172.44,78.68) 174.57,78.68 175.33,77.92 v2(176.16,77.92)
PWR_0D95V_PWRGD: length 3.8
  TOP w0.127: v1(173.3,71.24) 173.12,71.06 PR4835.2 PR4821.1 173.33,72.88 PU4806.1
PWR_0D95V_TRIP: length 3.6
  TOP w0.254: PU4806.2 173.99,73.99 174.15,73.84 174.15,72.48 v1(174.32,72.31) 174.65,72.31 174.95,72.61 PR4817.2
PWR_0D95V_UGATE: length 19.2
  TOP w0.305: v3(169.11,73.09) 169.11,73.38 169.72,73.99 PU4806.9
  TOP w0.508: v3(155.52,71.82) v1(156.23,71.82)
  L4 w1.016: v3(169.11,73.09) 166.72,73.09 163.54,69.92 158.19,69.92 156.28,71.82 v3(155.52,71.82)
  BOTTOM w0.381: PU4808.4 155.56,71.78 v3(155.52,71.82)
PWR_1D05V_SNUB: length 2.7
  TOP w0.508: PC4838.1 PR4837.2 v1(157.25,76.03)
PWR_1D8V_EN: length 4.4
  BOTTOM w0.127: v1(162.7,64.14) PR5010.2 PC5005.1 160.86,62.31 PU5002.5
PWR_1D8V_FB: length 4.7
  BOTTOM w0.254: PU5002.6 163.42,62.39 PR5013.1 PC5014.2 PR5009.2 166.51,63.25 v1(166.95,63.7)
PWR_1D8V_PHASE:
  vias: v1(160.22,57.6)
PWR_1D8V_PVDD:
  vias: v1(167.71,61.41)
PWR_1D8V_SVIN: length 4
  BOTTOM w0.254: PU5002.8 164.28,60.77 164.98,61.47 PC5013.1 PR5012.2 166.06,61.48 v1(166.79,62.2)
PWR_1D35V_DRVH: length 14.1
  TOP w0.203: v3(102.31,13.66) 102.44,13.66 102.92,14.15 PU4901.14
  L3 w1.016: v3(102.31,13.66) 93.37,13.66 91.97,12.26 v3(90.37,12.26)
  vias: v1(89.61,12.26)
PWR_1D35V_DRVL: length 9.7
  TOP w0.203: v3(103.58,16.07) 103.68,15.97 PU4901.11
  L3 w1.016: v3(103.58,16.07) 100.53,19.12 96.09,19.12 v3(95.96,18.99)
  vias: v1(96.62,19.06)
PWR_1D35V_EN: length 4.8
  TOP w0.127: v1(100.72,11.98) 101.26,11.45 PR4907.2 PC4906.1 103.33,11.45 104.43,12.55 PU4901.16
PWR_1D35V_MODE: length 3
  TOP w0.203: PU4901.19 105.63,12.37 106.58,11.42 v1(106.6,11.42) 106.6,11.4 107.01,10.99 PR4908.1
PWR_1D35V_REFIN: length 5.4
  TOP w0.203: 105.23,17.78 PU4901.8
  TOP w0.254: PR4903.2 104.59,18.55 PC4902.1 PR4901.1 ; PR4903.2 103.88,17.84 v1(103.88,17.75) ; PR4903.2 105.23,17.78
PWR_1D35V_SW: length 15.1
  TOP w0.203: PU4901.13 102.44,14.55 v3(102.05,14.93)
  TOP w0.508: v3(102.05,14.93) 101.67,14.55 PC4919.2
  L3 w1.016: v3(89.99,14.67) 92.59,14.67 92.84,14.93 v3(102.05,14.93)
  vias: v1(94.33,13.28) v3(89.23,17.72) v3(89.23,16.58) v3(89.23,15.44) v3(89.23,14.04) v3(89.99,18.36) v3(89.99,17.09) v3(89.99,15.94) v3(89.99,13.4)
PWR_1D35V_TRIP: length 3
  TOP w0.203: PR4902.1 106.12,10.7 105.45,11.37 v1(105.21,11.37) 105.23,11.39 PU4901.18
PWR_1D35V_VBST: length 3.1
  TOP w0.203: PU4901.15 103.44,13.75 102.96,13.26
  TOP w0.508: PR4905.1 101.65,13.15 101.88,12.92 v1(102.23,12.92) 102.61,12.92 102.96,13.26
PWR_1D35V_VREF: length 3.7
  TOP w0.203: PU4901.6 106.03,16.62 106.25,16.83
  TOP w0.254: 106.25,16.83 106.25,17.47 v1(106.04,17.68) 106.04,17.69 105.42,18.31 PR4903.1 105.42,19.25 PC4903.1
PWR_1D35V_VTTREF: length 4.8
  TOP w0.203: 106.78,15.69 PU4901.5
  TOP w0.254: 106.78,15.69 106.78,16.6 106.94,16.77 PC4918.1 106.94,18.65 PR4911.1 106.91,18.99 v1(107.9,18.99)
PWR_3D3V5V_ENTRIP: length 10.6
  TOP w0.254: PQ4501.2 137.61,42.93 PR4502.1 PR4501.2 139.23,42.8 139.55,43.12 139.55,45.86 140.05,46.37 v1(140.05,46.73) 139.84,46.94 138.05,46.94 137.61,46.51 PQ4501.5
PWR_3D3V_BOOT2: length 3.2
  TOP w0.203: v1(127.71,40.71) 127.94,40.94 128.77,40.94 129.23,40.47 PU4501.7
  TOP w0.508: PR4508.2 v1(127.71,40.71)
PWR_3D3V_BOOT2_1: length 2.2
  TOP w0.508: v1(124.91,40.71) PR4508.1 126.03,40.54 PC4513.2
PWR_3D3V_ENTRIP2: length 3.1
  TOP w0.203: v1(130.76,42.79) 130.86,42.68 PU4501.4
  TOP w0.254: PC4501.1 PR4503.1 131.01,43.25 130.76,42.99 v1(130.76,42.79)
PWR_3D3V_ENTRIP2_L: length 7.6
  TOP w0.254: PR4503.2 131.01,45.84 v1(131.29,46.12) 131.6,46.42 136.63,46.42 PQ4501.6
PWR_3D3V_FB2: length 5.3
  TOP w0.203: 129.87,42.49 130.46,41.89 PU4501.5
  TOP w0.254: v1(127.35,42.79) 127.35,43.59 PC4526.2 PR4506.2 PR4507.1 129.23,43.12 129.87,42.49
PWR_3D3V_LGATE2: length 12.3
  TOP w0.203: PU4501.10 129.71,38.78 v3(129.36,38.42)
  L3 w0.762: v3(129.36,38.42) 129.36,35.63 124.79,31.06 v3(124.79,29.91)
  BOTTOM w0.508: v3(124.79,29.91) v1(123.9,29.91)
PWR_3D3V_PHASE2: length 20.3
  TOP w0.203: PU4501.9 129.14,39.67 128.65,39.18 v3(128.47,39.18)
  TOP w0.508: v3(128.47,39.18) 128.09,39.57 PC4513.1
  L3 w0.762: v3(123.47,24.27) 123.47,25.01 122.76,25.72 122.76,32.03 127.33,36.6 127.33,38.04 v3(128.47,39.18)
  vias: v1(124.03,23.31) v3(120.98,24.45) v3(121.49,23.44) v3(122.37,23.44) v3(125.3,23.44) v3(125.8,24.2)
PWR_3D3V_SNUB: length 2.3
  TOP w0.508: PC4514.1 v1(128.98,28.01) PR4505.2
PWR_3D3V_UGATE2: length 21.1
  TOP w0.203: PU4501.8 128.72,40.07 v3(128.47,40.33)
  L3 w0.762: v3(122.37,24.58) 121.74,25.21 121.74,32.45 126.31,37.03 126.31,38.46 128.18,40.33 v3(128.47,40.33)
  BOTTOM w0.508: v3(128.47,40.33) v1(128.47,41.09)
PWR_3D3V_VOUT: length 36.3
  TOP w0.254: PR4506.1 PC4526.1 127.14,44.9 v2(127.14,45.28)
  BOTTOM w0.254: v2(127.14,45.28) 125.97,44.11 v1(125.97,43.03) 125.97,41.79 118.56,34.38 118.56,17.67 120.17,16.07 PG4153.2
PWR_5V3D3V_ENLDO: length 12.2
  TOP w0.203: PR4511.2 130.63,37.41 130.86,37.64 PU4501.12
  TOP w0.254: PR4511.2 131.13,36.83 131.26,36.69 131.26,34.99 129.87,33.6 v1(128.27,33.6) 126.06,33.6 124.68,34.98 PQ4502.3
PWR_5V3D3V_ENM/SECFB: length 5.6
  TOP w0.203: PU4501.13 131.26,37.66 v2(131.77,37.15)
  BOTTOM w0.254: v2(131.77,37.15) PR4516.1 PR4514.1 133.72,36.2 PC4520.1 v1(133.8,37.32)
PWR_5V3D3V_TON: length 2.4
  TOP w0.203: PU4501.3 131.26,42.38 v2(131.35,42.47)
  BOTTOM w0.254: PR4515.1 132.03,41.8 131.36,42.47 v2(131.35,42.47) v1(131.35,43.04)
PWR_5V_BOOT1: length 3.3
  TOP w0.203: 133.7,40.84 133.34,40.47 PU4501.19
  TOP w0.508: 133.7,40.84 134.44,40.84 v1(134.82,40.45) PR4513.1
PWR_5V_BOOT1_1: length 2.2
  TOP w0.508: PR4513.2 136.66,40.03 136.62,40 PC4519.1 v1(137.65,39.31)
PWR_5V_ENTRIP1: length 3.2
  TOP w0.203: PU4501.2 131.66,42.1 131.73,42.17 131.73,42.18 132.08,42.52 v1(132.08,42.79)
  TOP w0.254: v1(132.08,42.79) 132.08,42.82 131.9,42.99 PC4502.1 PR4504.2
PWR_5V_ENTRIP1_L: length 7.3
  TOP w0.254: PR4504.1 132.79,45.23 133.35,45.79 v1(134.77,45.79) 135.62,45.79 136.44,44.98 137.92,44.98 138.27,44.63 PQ4501.3
PWR_5V_FB1: length 4.7
  TOP w0.203: PU4501.1 132.38,41.62
  TOP w0.254: PR4518.2 PC4527.2 133.87,43.88 PR4519.1 133.37,43.39 v1(133.37,42.79) 133.37,42.62 132.38,41.62
PWR_5V_LGATE1: length 12
  TOP w0.203: PU4501.16 132.82,38.9 v3(133.04,38.68)
  L3 w0.762: v3(133.04,38.68) 133.04,36.01 131.77,34.74 131.77,29.41 v3(132.28,28.9)
  BOTTOM w0.508: v3(133.04,38.68) v1(132.28,38.68)
PWR_5V_PHASE1: length 19.2
  TOP w0.203: v3(134.06,39.06) 133.93,39.06 133.32,39.67 PU4501.17
  TOP w0.508: PC4519.2 134.31,39.31 v3(134.06,39.06)
  L3 w0.762: v3(138.63,24.58) 138.63,26.36 135.2,29.79 135.2,37.91 v3(134.06,39.06)
  vias: v1(135.96,23.56) v3(133.68,24.58) v3(133.68,23.69) v3(134.82,24.58) v3(134.82,23.69) v3(136.6,24.58) v3(137.49,24.58) v3(137.49,23.56) v3(138.63,23.56)
PWR_5V_SNUB: length 2.3
  TOP w0.508: PC4521.1 v1(130.88,28.03) PR4517.2
PWR_5V_UGATE1: length 19.4
  TOP w0.203: PU4501.18 v3(134.06,40.07)
  L3 w0.762: v3(134.06,40.07) 134.52,40.07 136.22,38.37 136.22,30.21 139.77,26.65 v3(139.77,24.58)
  vias: v1(139.8,23.84)
PWR_5V_VOUT: length 71.7
  TOP w0.203: 133.29,41.34 PU4501.20
  TOP w0.254: 133.29,41.34 133.79,41.85 v2(134.31,41.85) ; v2(136.07,41.85) 135.75,42.17 PC4528.1 135.33,42.93 PR4518.1 PC4527.1
  L4 w0.508: v2(134.31,41.85) 135.2,42.74 136.32,42.74 138,41.07 138,32.95 140.66,30.28 140.66,29.66 141.55,28.77 141.55,20.01 138.05,16.5 v2(138.05,13.66)
  BOTTOM w0.254: v2(138.05,13.66) PG4532.2 138.05,16.5 141.55,20.01 141.55,28.9 141.04,29.41 141.04,29.91 v1(137.91,33.05) 137.91,40.42 136.47,41.85 v2(136.07,41.85)
PWR_APU_VDD_BOOT: length 6.1
  BOTTOM w0.203: 102.64,132.15 102.64,132.58 103.2,133.14 103.2,133.36 103.62,133.78 PU4601.1
  BOTTOM w0.508: 102.64,132.15 102.44,131.94 PR4701.1 101.95,129.89 v1(101.34,129.28)
PWR_APU_VDD_BOOT_1: length 2.3
  BOTTOM w0.508: v1(103.71,127.54) PC4736.1 PR4701.2
PWR_APU_VDD_DCBATOUT:
  vias: v1(90.27,129.13) v1(91.11,127.8) v3(91.13,125.93) v3(91.13,125.04) v3(91.13,124.15) v3(91.13,123.26) v3(91.64,129.61) v3(91.64,128.72) v3(92.53,129.61) v3(92.53,128.72)
PWR_APU_VDD_ISEN1N: length 3.8
  BOTTOM w0.203: PU4601.3 103.21,134.58 102.56,133.93 102.25,133.93 PR4707.1
  BOTTOM w0.254: v1(101.45,132.5) 101.45,133.13 PR4707.1
PWR_APU_VDD_ISEN1P: length 6
  TOP w0.254: PC4701.1 102.26,134.31 v2(102.49,134.54) 103.02,134.54 v1(103.25,134.76)
  BOTTOM w0.203: v2(102.49,134.54) 102.54,134.54 102.98,134.98 PU4601.4
  BOTTOM w0.254: v2(102.49,134.54) 102.05,134.54 101.76,134.24 PR4705.2 100.15,134.24 PR4706.1
PWR_APU_VDD_LGATE: length 18.3
  TOP w0.762: PU4702.8 v3(99.64,125.8) ; v3(104.34,130.88) v1(104.34,130.04)
  L4 w0.762: v3(104.34,130.88) 104.34,129.23 100.91,125.8 v3(99.64,125.8) 98.63,124.78 v3(98.63,121.12)
  BOTTOM w0.203: PU4601.38 105.5,132.29 104.98,131.77 104.98,131.51
  BOTTOM w0.508: v3(104.34,130.88) 104.98,131.51
  BOTTOM w0.762: PU4701.8 98.59,121.16 v3(98.63,121.12)
PWR_APU_VDD_PGOOD: length 4.8
  BOTTOM w0.127: PR4679.1 111.45,130.74 v1(111.45,131.61) 110.68,131.61 PR4651.2 110.48,131.47 108.93,133.02 PU4601.31
PWR_APU_VDD_PHASE: length 21.9
  L3 w0.762: v3(93.67,120.72) 93.55,120.85 93.55,126.27 94.98,127.7 99.77,127.7 v3(103.45,131.39)
  BOTTOM w0.203: PU4601.39 105.1,132.53 104.47,131.89 103.96,131.89
  BOTTOM w0.508: PC4736.2 103.71,130.18 103.45,130.48 v3(103.45,131.39) 103.96,131.89
  vias: v1(94.56,119.7) v1(95.58,117.67) v1(96.85,119.7) v3(93.29,119.83) v3(93.29,118.94) v3(93.29,118.05) v3(97.86,119.83) v3(97.86,118.94) v3(97.86,118.05) v3(98.75,119.45) v3(98.75,118.56) v3(98.75,117.67) v3(98.75,116.78)
PWR_APU_VDD_SNUB: length 2.6
  BOTTOM w0.508: PC4742.1 PR4709.2 v1(101.81,118.38)
PWR_APU_VDD_UGATE: length 23
  TOP w0.762: PU4702.1 92.57,126.65 v3(92.53,126.69) ; v3(103.45,132.53) v1(102.69,132.53)
  L3 w0.762: v3(92.53,121.1) v3(92.53,126.69) 94.56,128.72 99.35,128.72 103.16,132.53 v3(103.45,132.53)
  BOTTOM w0.203: 104.24,133.02 PU4601.40
  BOTTOM w0.508: v3(103.45,132.53) 103.95,133.02 104.24,133.02
  BOTTOM w0.762: v3(92.53,121.1) 92.57,121.14 PU4701.1
PWR_APU_VDDNB_DCBATOUT:
  vias: v1(112.34,124.78) v1(113.18,124.71) v1(114.2,123.66) v3(112.6,127.45) v3(112.6,126.56) v3(112.6,125.67) v3(113.99,121.86) v3(113.99,120.97) v3(113.99,120.08)
PWR_CHG_ACDET: length 5.4
  TOP w0.254: PU4404.6 141.99,121.17 142.95,120.21 v2(143.08,120.21) 144.04,119.24 PR4407.2
  BOTTOM w0.254: v1(143.63,120.21) v2(143.08,120.21) 142.53,120.21 PC4412.1 PR4431.1
PWR_CHG_ACN: length 77
  TOP w0.254: v2(138.5,119.45) 139,119.95 PU4404.1
  L3 w0.254: v2(138.5,119.45) 138.5,119.23 137.58,118.31 128.63,118.31 124.15,122.78 124.15,134.43 124.28,134.56 124.28,141.07 122.28,143.07 115.15,143.07 114.01,144.21 110.83,144.21 110.48,144.57 100.05,144.57 96.61,141.13 v2(96.61,140.16)
  BOTTOM w0.254: PG4403.2 92.33,140.66 93.67,140.66 94.69,139.64 95.1,139.64 ; v1(95.1,139.39) 95.1,139.64 ; 95.1,139.64 96.19,139.64 96.61,140.07 v2(96.61,140.16) ; PR4406.1 PC4402.2 138.16,118.32 PC4403.1 138.5,118.74 v2(138.5,119.45)
PWR_CHG_ACOK: length 81.7
  TOP w0.102: PR4428.2 137.46,114.1 PR4419.2 136.61,114.04 PR4436.1 136.41,114.24 133.27,114.24 133.12,114.4 133.12,116.47 133.24,116.59 PQ4408.3 133.96,116.88 133.04,117.8 130.88,117.8 v1(130.48,118.2) v2(129.74,118.94)
  L4 w0.102: v2(94.18,144.47) 94.18,145.99 96.24,148.05 102.16,148.05 103.08,147.12 113.68,147.12 115.61,145.19 115.61,144.33 116.51,143.43 120.88,143.43 123.39,140.92 v2(123.39,136.66)
  BOTTOM w0.102: v2(94.18,144.47) 93.79,144.86 93.79,146.03 93.44,146.37 92.4,146.37 92.28,146.5 PQ4402.2 ; v2(129.74,118.94) 129.21,118.94 128.71,118.44 127.54,118.44 123.97,122.01 123.97,136.07 v2(123.39,136.66) PR4476.1
PWR_CHG_ACP: length 77.8
  TOP w0.254: PU4404.2 139.5,119.68 v2(139.27,119.45)
  L3 w0.254: v2(139.27,119.45) 137.74,117.92 128.47,117.92 123.77,122.62 123.77,134.59 123.9,134.72 123.9,140.91 122.12,142.69 114.99,142.69 113.85,143.83 110.67,143.83 110.32,144.19 100.21,144.19 97.12,141.1 97.12,139.95 96.83,139.65 96.4,139.65 95.98,140.08 v2(95.98,140.15)
  BOTTOM w0.254: v2(139.27,119.45) 139.27,118.43 PC4404.1 139.05,118.06 PC4402.1 PR4406.2 ; 92.94,141.04 92.2,141.04 PG4402.2 ; 92.94,141.04 93.83,141.04 94.85,140.02 95.85,140.02 v2(95.98,140.15) ; 92.94,141.04 v1(92.94,141.24)
PWR_CHG_AD_OFF: length 238.2
  TOP w0.102: v2(176.16,27.65) 176.21,27.7 KBC24.11 ; v2(194.13,124.02) 194.13,129.48 197.69,133.04 197.69,133.67 v2(198.96,134.94)
  L4 w0.102: v2(111.07,153.1) 111.31,153.1 112.75,154.54 117.38,154.54 120.06,151.86 145.36,151.86 147.47,153.97 162.93,153.97 165.95,150.95 169.26,150.95 173.5,155.19 187.44,155.19 189.16,153.46 189.16,150.34 190.9,148.6 190.9,143.37 198.96,135.32 v2(198.96,134.94) ; v2(176.16,27.65) 177.05,28.54 180.32,28.54 181.05,29.27 181.05,33.47 181.3,33.72 181.94,33.72 182.75,34.54 185.3,37.08 185.3,40.14 186.18,41.02 186.18,41.6 186.87,42.28 186.87,49.4 186.69,49.57 186.69,62.65 194.54,70.5 194.54,77.94 193.19,79.29 193.19,81.69 193.85,82.35 193.85,105.06 190.78,108.14 190.78,115 194.13,118.36 v2(194.13,124.02)
  BOTTOM w0.102: v2(194.13,124.02) v1(194.74,124.02) ; PQ4206.5 106.25,152.15 PR4210.1 107.2,153.1 v2(111.07,153.1)
PWR_CHG_AD_OFF_R: length 11
  TOP w0.102: PQ4204.B 109.53,146.74 v1(111.02,148.23) 111.4,148.23 v2(112.21,149.04)
  BOTTOM w0.102: PR4210.2 PR4211.1 110.07,151.88 PQ4203.6 110.38,150.82 110.94,150.82 112.21,149.55 v2(112.21,149.04)
PWR_CHG_BAT_SCL: length 3.5
  TOP w0.14: PU4404.9 142.91,122.67 143.78,121.79 144.53,121.79 PG4407.1
PWR_CHG_BAT_SDA: length 3.7
  TOP w0.14: v1(143.74,121.07) 143.74,121.27 ; 143.74,121.27 143.56,121.27 142.67,122.17 PU4404.8 ; 143.74,121.27 144.53,121.27 PG4408.1
PWR_CHG_BTST: length 3.3
  TOP w0.305: 137.3,122.94 137.57,122.67 PU4404.17
  TOP w0.508: PR4409.1 v1(136.47,123.64) 136.6,123.64 137.3,122.94
PWR_CHG_BTST_R: length 4.9
  TOP w0.254: v2(135.2,124.53) 134.92,124.53 PR4409.2 134.44,123.11 PC4411.1 133.74,122.56 v1(133.42,122.24)
  BOTTOM w0.254: v2(135.2,124.53) 135.2,124.78 PD4401.K
PWR_CHG_CMPIN: length 6.9
  TOP w0.254: PR4429.1 PR4427.2 PR4411.2 141.02,117.85 140.45,118.42 PR4414.2 140.79,118.95 v2(140.79,119.45) 140.5,119.74 PU4404.4
  BOTTOM w0.254: v2(140.79,119.45) 140.64,119.6 PR4413.1 139.81,120.32 v1(139.72,120.24)
PWR_CHG_CMPIN_R: length 7.1
  TOP w0.254: v2(139.01,115.26) 139.24,115.49 PR4429.2
  BOTTOM w0.254: v2(139.01,115.26) 139.9,115.26 v1(140.1,115.05) 140.28,114.88 142.81,114.88 143.69,115.75 PQ4407.3
PWR_CHG_CMPIN_RR: length 3.8
  TOP w0.254: v2(139.77,116.02) 139.77,116.41 PR4427.1
  BOTTOM w0.254: PQ4407.6 140.68,117.05 v1(140.48,116.85) 139.77,116.15 v2(139.77,116.02)
PWR_CHG_CMPOUT: length 7.2
  TOP w0.254: PU4404.3 140,119.05 PR4414.1 PR4432.1 138.67,117.97 PR4438.1 PR4430.2 137.46,117.7 v1(136.73,118.43) 136.64,118.34 PR4437.1
PWR_CHG_CSON_1: length 25.4
  TOP w0.254: v2(139.52,127.32) 140.6,127.32 PR4420.2
  BOTTOM w0.254: PG4410.1 133.35,143.96 134.34,143.96 134.95,143.36 134.95,136.09 135.82,135.21 ; 135.82,135.21 v1(135.99,135.37) ; 135.82,135.21 136.85,134.18 136.85,130.12 139.52,127.45 v2(139.52,127.32) 140.6,127.32 PC4421.2 141.23,125.93 PC4423.1
PWR_CHG_CSOP_1: length 24.3
  TOP w0.254: v2(138.88,127.31) 138.88,127.24 139.37,126.75 PR4421.2
  BOTTOM w0.254: 134.57,142.71 134.57,135.93 136.47,134.02 136.47,129.96 138.88,127.55 v2(138.88,127.31) 138.88,127.2 139.39,126.69 PC4421.1 140.35,125.93 PC4420.1 ; 134.57,142.71 134.57,143.2 134.19,143.58 133.47,143.58 PG4409.1 ; 134.57,142.71 v1(134.36,142.71)
PWR_CHG_HIDRV: length 19.9
  TOP w0.305: v3(136.73,122.37) 136.93,122.17 PU4404.18
  TOP w0.508: v3(136.73,122.37) 136.7,122.39 PC4413.2 ; v3(130.12,131.37) 131,131.37 v1(131.01,131.39)
  L3 w1.016: v3(130.12,131.37) 128.98,130.23 128.98,127.85 130.88,125.94 130.88,123.26 131.77,122.37 v3(136.73,122.37)
  BOTTOM w0.381: PU4405.4 v3(130.12,131.37)
PWR_CHG_IFAULT: length 5
  TOP w0.254: PU4404.11 141,124.49 141.81,125.29 142.82,125.29 v1(143.33,125.8) 143.38,125.85 144.51,125.85 PR4418.2
PWR_CHG_ILIM: length 4.1
  TOP w0.254: v1(144.09,124.73) 143.88,124.52 PR4417.2 PR4423.1 143.64,123.17 PU4404.10
PWR_CHG_IOUT: length 13
  TOP w0.254: PR4422.1 143.91,120.13 v2(143.08,120.97) 143.08,121.1 142.51,121.67 PU4404.7 ; v2(140.54,116.02) 140.54,116.29 PR4411.1
  L4 w0.254: v2(143.08,120.97) 142.31,120.21 142.31,117.88 140.66,116.23 140.66,116.15 v2(140.54,116.02)
  BOTTOM w0.254: PR4424.1 PC4422.1 143.13,122.17 v1(143.3,121.99) 143.3,121.2 v2(143.08,120.97)
PWR_CHG_LODRV: length 10.5
  TOP w0.305: 137.93,125.04 PU4404.15
  TOP w1.016: v3(131.26,128.47) v1(133.17,128.47) 134.5,128.47 137.93,125.04
  BOTTOM w0.381: v3(131.26,128.47) 131.26,128.45 131.52,128.2 PU4406.4
PWR_CHG_PHASE: length 23.7
  TOP w0.305: PU4404.19 137.29,121.67 v3(136.73,121.1)
  TOP w0.508: v3(136.73,121.1) 136.7,121.07 PC4413.1 135.04,121.07 PC4411.2 ; v3(128.34,132.5) v1(128.34,133.32)
  L3 w1.016: v3(128.34,132.5) 127.71,131.87 127.71,127.32 129.61,125.42 129.61,122.73 131.25,121.1 v3(136.73,121.1)
PWR_CHG_REGN: length 35.1
  TOP w0.254: v2(147.77,122.75) 148.26,122.27 v1(148.26,120.36) 148.26,119.02 145.09,115.85 PR4425.1 143.36,115.54 v2(142.19,114.37) ; v2(136.6,116.4) 137.09,116.4 PR4430.1 PR4428.1 ; PU4404.16 138.2,123.69 v2(138,123.89)
  L4 w0.254: v2(147.77,122.75) 146.15,124.38 138.48,124.38 v2(138,123.89)
  BOTTOM w0.254: v2(142.19,114.37) 139.01,114.37 138.25,115.13 137.87,115.13 v2(136.6,116.4) ; v2(138,123.89) 137.74,123.64 PC4407.1 137.01,124.3 PD4401.A
PWR_CHG_SRN: length 3.2
  TOP w0.254: PU4404.12 140.5,124.84 141.17,125.51 PR4420.1 141.9,125.86 v1(142.1,126.06)
PWR_CHG_SRP: length 3
  TOP w0.254: v1(139.37,125.86) PR4421.1 140.28,125.16 140,124.88 PU4404.13
PWR_CHG_VCC: length 4.5
  TOP w0.254: PU4404.20 137.11,120.07 v1(136.73,120.07) 135.67,120.07 PC4010.1 134.54,119.98 PR4408.2
PWR_COMP: length 6.4
  TOP w0.254: PR4620.1 100.15,138.69 PC4609.1 101.47,138.69 101.58,138.8 v1(102.51,138.8) 102.66,138.64 102.66,136.69 v2(102.56,136.59)
  BOTTOM w0.203: v2(102.56,136.59) 102.98,136.18 PU4601.7
PWR_COMP_1: length 1.8
  TOP w0.254: PR4621.1 PR4620.2 v1(98.3,138.63)
PWR_COMPA: length 6.4
  TOP w0.254: v2(111.2,137.48) 111.45,137.48 111.96,136.97 PR4609.1 112.41,137.9 v1(112.39,137.91)
  BOTTOM w0.203: v2(111.2,137.48) 111.15,137.48 110.69,137.02 110.69,136.59 110.27,136.18 PU4601.24
  BOTTOM w0.254: PC4606.2 111.64,137.48 v2(111.2,137.48)
PWR_COMPA_1: length 1.8
  TOP w0.254: PR4609.2 PR4610.2 113.29,135.21 v1(113.33,135.17)
PWR_DCBATOUT_0D95V:
  vias: v1(162.15,68.78)
PWR_DCBATOUT_3D3V:
  vias: v1(121.08,31.77)
PWR_DCBATOUT_5V:
  vias: v1(137.61,34.61)
PWR_FB: length 6.3
  TOP w0.254: PR4621.2 100.15,137.8 PC4609.2 101.81,137.8 v1(101.83,137.79) 101.86,137.75 PR4622.1 101.86,136.5 102.46,135.91 v2(102.56,135.91)
  BOTTOM w0.203: PU4601.6 102.69,135.78 v2(102.56,135.91)
  BOTTOM w0.254: v2(102.56,135.91) 102.23,135.91 101.99,136.15 PC4611.2
PWR_FB_1: length 1.9
  TOP w0.254: v1(100.38,135.93) 100.47,136.02 PR4623.1 101.29,136.53 PR4622.2
PWR_FBA: length 7.2
  TOP w0.254: v1(110.56,137.36) 111.07,136.85 v2(111.2,136.85) 111.96,136.09 PR4610.1
  BOTTOM w0.203: PU4601.25 110.82,135.78 111.19,136.15 PC4605.1
  BOTTOM w0.254: PR4608.2 PC4606.1 PC4605.1 v2(111.2,136.85)
PWR_FBA_1: length 2.2
  BOTTOM w0.254: PR4608.1 PR4607.1 113.87,137.05 v1(114.75,137.94)
PWR_IBIAS: length 3.2
  TOP w0.254: v1(109.24,137.51) 109.23,137.49 PR4674.2 109.93,136.59 v2(110.18,136.85)
  BOTTOM w0.203: PU4601.23 109.91,136.58 v2(110.18,136.85)
PWR_IMON: length 2.5
  BOTTOM w0.203: PU4601.9 103.43,136.98 103.25,137.15
  BOTTOM w0.254: PR4645.1 101.76,137.71 v1(102.7,137.71) 103.25,137.15
PWR_IMON_1: length 2.4
  BOTTOM w0.254: PR4645.2 100.82,137.76 PR4664.1 99.45,136.94 v1(99.54,136.85)
PWR_IMON_2: length 3.5
  BOTTOM w0.254: v1(98,136.82) 98,137.49 98.24,137.74 PR4664.2 98.56,137.75 99.43,138.63 PR4657.1 PR4659.1
PWR_IMON_3: length 29.9
  L4 w0.254: v2(90.43,117.35) 90.26,117.35 89.61,118.01 89.61,131.28 90.09,131.77 92.1,131.77 v2(92.61,132.28)
  BOTTOM w0.254: PR4657.2 97.99,138.63 97.49,138.12 97.49,136.61 97.61,136.49 v1(97.61,135.65) 97.61,133.77 96.64,132.81 93.14,132.81 v2(92.61,132.28) ; PR4677.1 v2(90.43,117.35)
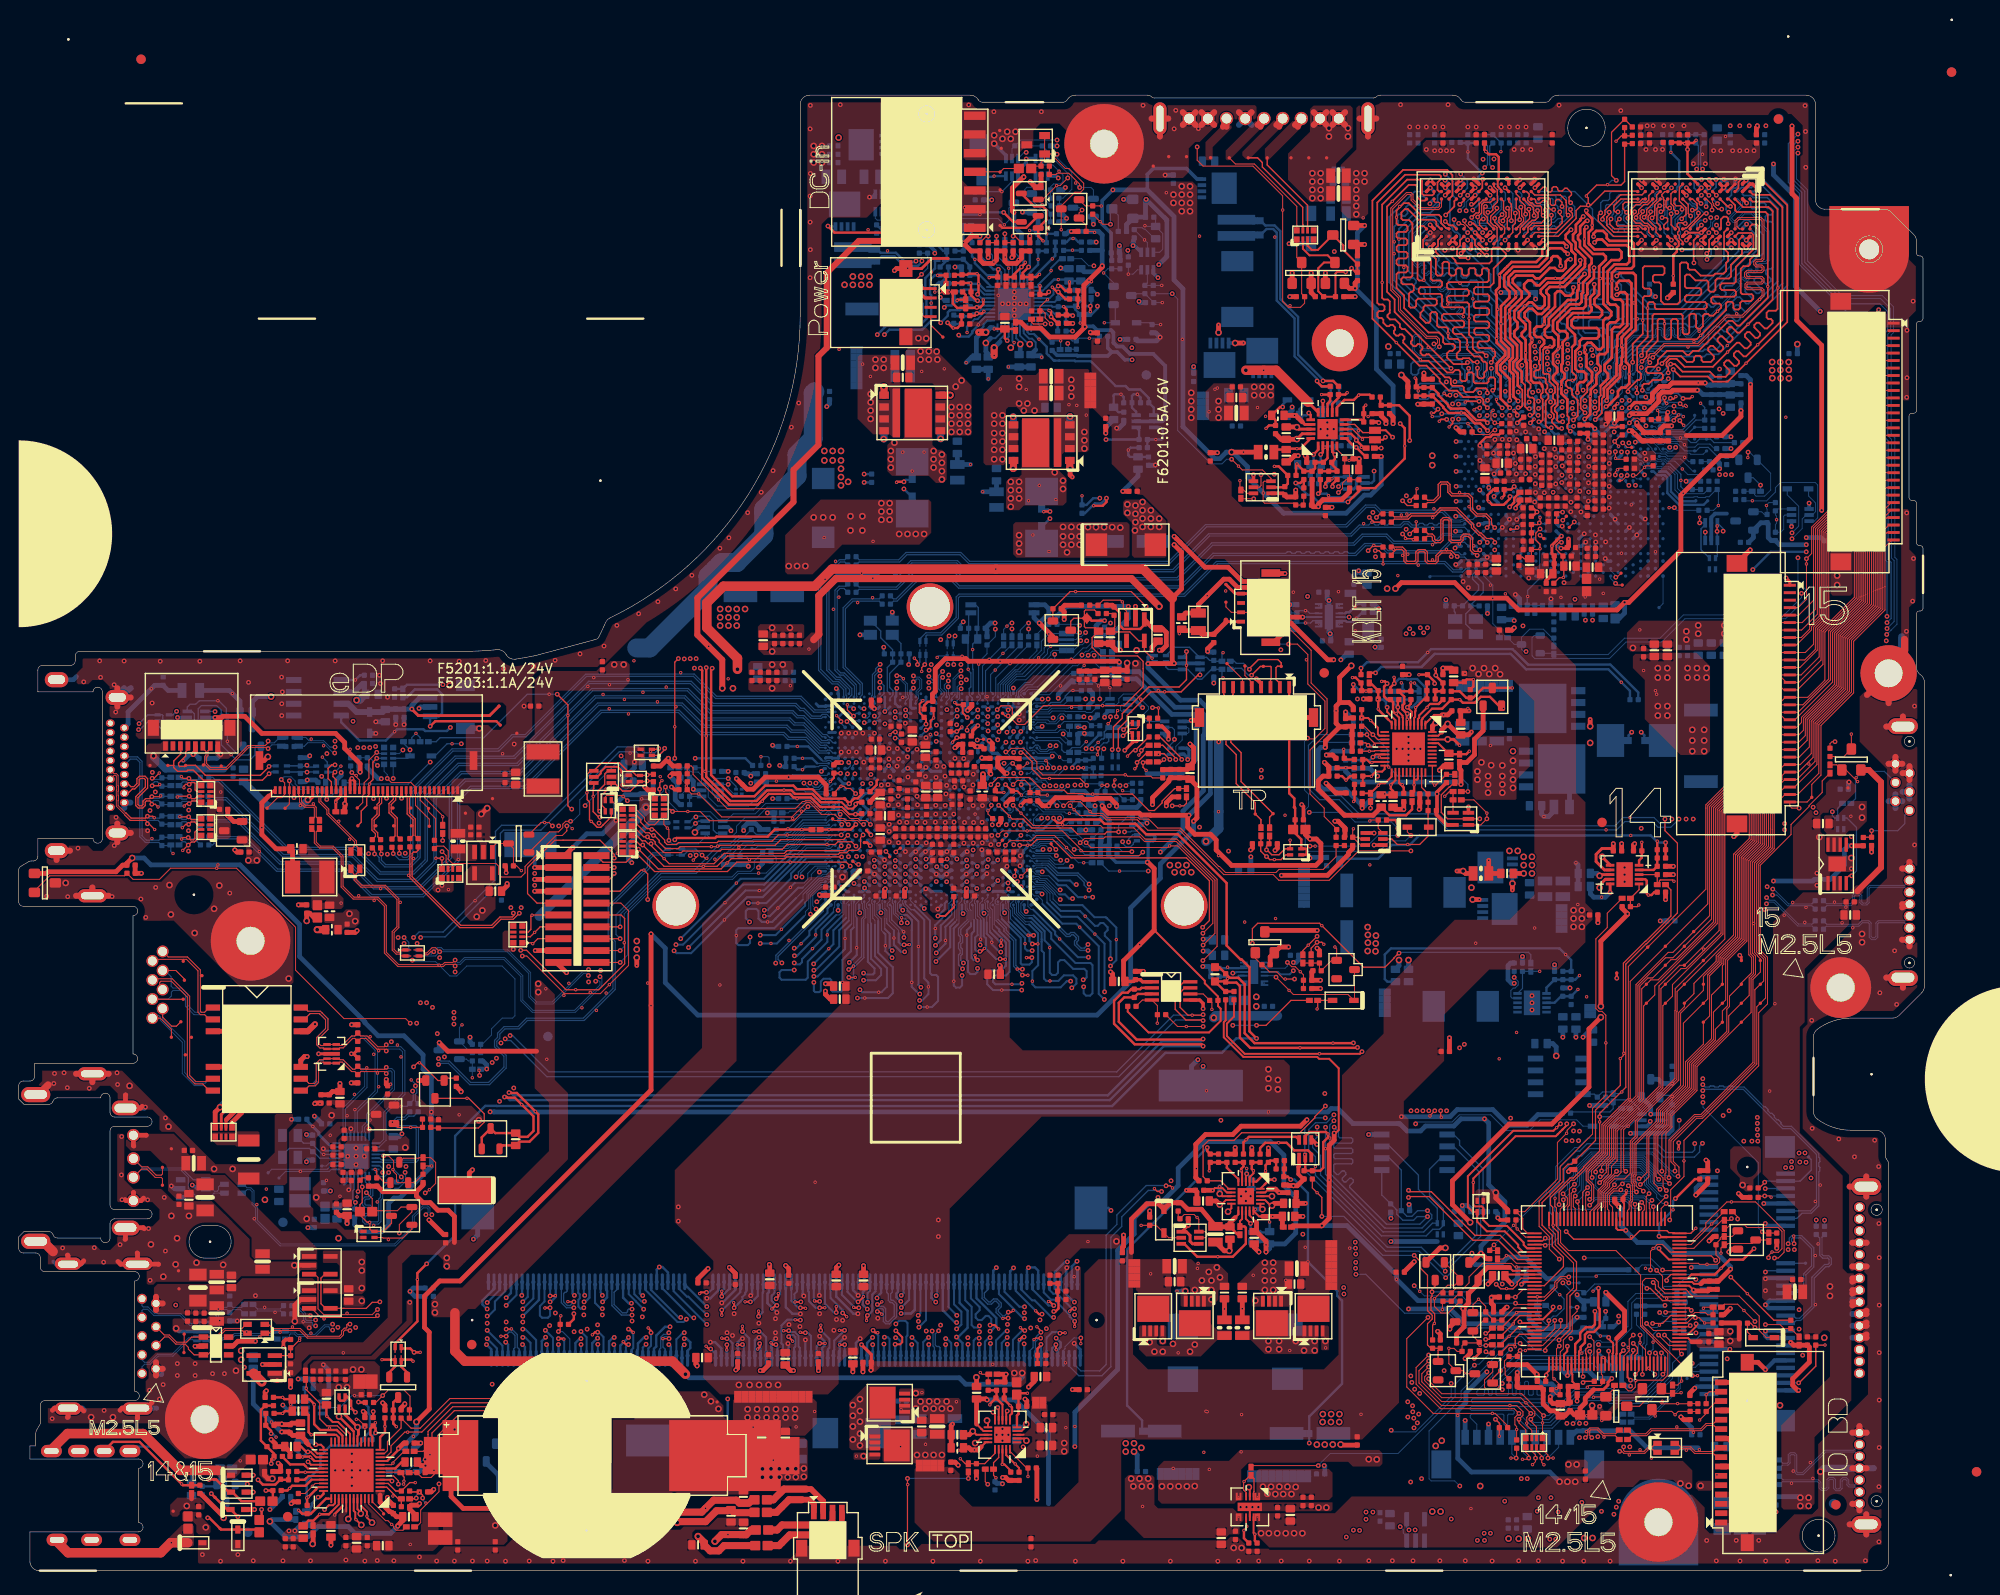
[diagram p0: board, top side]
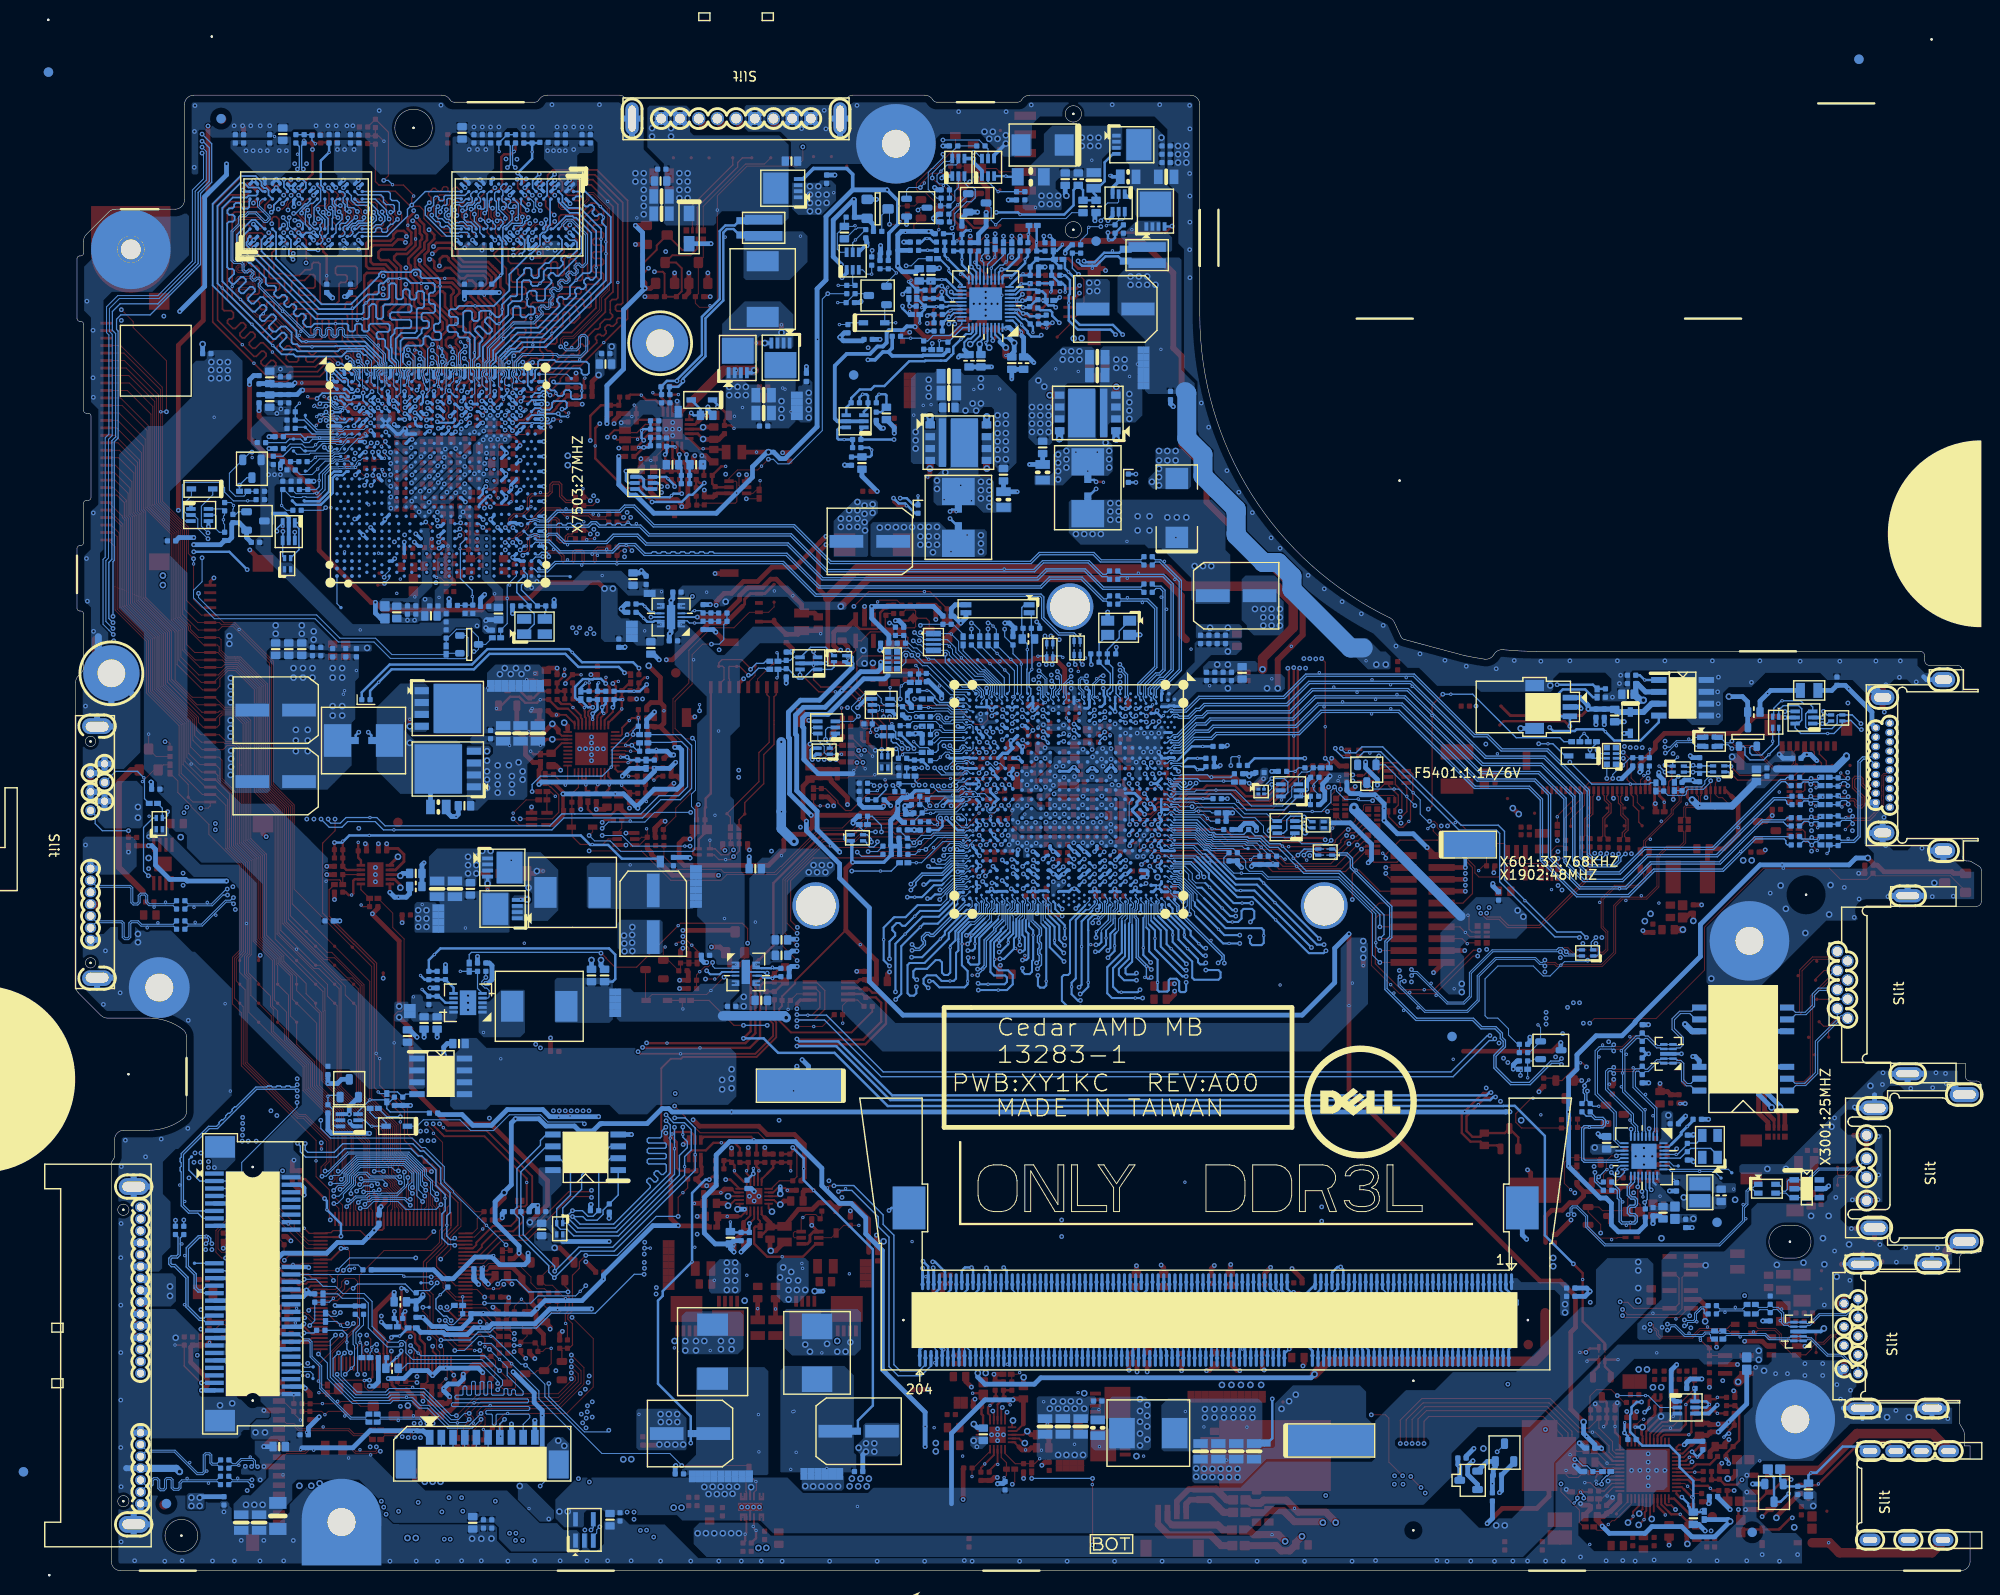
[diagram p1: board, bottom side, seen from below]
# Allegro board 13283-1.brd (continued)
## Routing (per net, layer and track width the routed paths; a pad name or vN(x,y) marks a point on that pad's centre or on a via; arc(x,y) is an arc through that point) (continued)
PWR_IMON_4: length 32.3
  L4 w0.254: v2(91.84,132.28) 89.88,132.28 89.1,131.5 89.1,117.8 v2(90.43,116.46)
  BOTTOM w0.254: v1(97.64,138.98) 97.63,138.98 ; 97.63,138.98 98.02,139.38 98.02,140.12 PR4661.2 ; 97.63,138.98 96.98,138.33 96.98,136.4 97.1,136.28 97.1,133.98 96.43,133.32 92.89,133.32 v2(91.84,132.28) ; PR4677.2 v2(90.43,116.46)
PWR_IMONA: length 4.8
  BOTTOM w0.203: PU4601.11 104.7,138.46 104.53,138.63
  BOTTOM w0.254: 104.53,138.63 103.58,138.63 102.28,139.92 v1(102.28,140.33) 101.98,140.64 PR4646.1
PWR_IMONA_1: length 1.9
  BOTTOM w0.254: PR4646.2 101.95,142.14 v1(101.95,143.02) 101.86,143.11 PR4649.1
PWR_IMONA_2: length 3.7
  BOTTOM w0.254: PR4658.1 PR4660.1 101.06,141.25 v1(101.06,142.13) 101.06,142.28 101.04,142.31 101.04,143.9 PR4649.2
PWR_IMONA_3: length 50.6
  L3 w0.254: v2(100.28,142.82) 100.7,142.82 101.84,141.67 106.12,141.67 106.75,141.04 116.79,141.04 118.82,139.01 118.82,132.73 119.96,131.59 119.96,119.09 116.15,115.28 116.14,115.28 115.85,114.99 115.85,114.98 v2(115.64,114.77)
  BOTTOM w0.254: v1(113.74,115.03) PR4678.1 114.22,114.05 114.95,114.77 v2(115.64,114.77) ; v2(100.28,142.82) 100.28,142.24 PR4658.2
PWR_IMONA_4: length 54.4
  TOP w0.254: v1(114.98,113.96) 115.95,113.96 116.36,114.37 v2(116.36,114.77)
  L3 w0.254: v2(99.64,142.82) 99.64,142.9 100.07,143.32 100.91,143.32 102.05,142.18 106.33,142.18 106.96,141.55 117,141.55 119.33,139.22 119.33,132.94 120.47,131.8 120.47,118.88 116.36,114.77 v2(116.36,114.77)
  BOTTOM w0.254: v2(116.36,114.77) 116.15,114.57 116.15,114.56 115.85,114.27 115.85,114.27 115.8,114.22 115.11,114.22 114.05,113.16 PR4678.2 ; v2(99.64,142.82) 99.26,142.44 PR4662.2
PWR_ISENA: length 3.4
  TOP w0.203: 149.26,84.65 PU8202.27 ; 149.26,84.65 149.26,84.4 ; 149.26,84.65 149.55,84.65 149.66,84.76 PU8202.28
  TOP w0.254: PR8230.1 149.26,83.41 v1(149.26,84.09) 149.26,84.4
PWR_OCP_L: length 4.2
  BOTTOM w0.203: PU4601.21 109.05,137.62 110.44,139.01 v1(110.44,139.13) 110.44,139.41 111.43,140.4 PR4637.2
PWR_OFS: length 6.3
  TOP w0.254: v1(107.67,140.02) 107.67,139.92 v2(107.26,139.51) 106.5,138.75 PC4617.1 PR4638.2
  BOTTOM w0.203: PU4601.17 107.1,139.35 v2(107.26,139.51)
  BOTTOM w0.254: v2(107.26,139.51) 107.47,139.72 107.47,141.03 PR4636.1
PWR_OFSA: length 6.7
  TOP w0.254: v2(108.02,139.51) 107.39,138.88 PC4613.1 PR4631.2 108.87,138.43 109.17,138.73 v1(109.19,138.73)
  BOTTOM w0.203: PU4601.18 107.5,138.99 v2(108.02,139.51)
  BOTTOM w0.254: v2(108.02,139.51) 108.15,139.64 PR4629.1
PWR_PVCC: length 5.2
  TOP w0.254: PC4603.1 v1(104.34,132.88) ; PC4603.1 105.48,131.89 v2(105.74,131.64) ; PC4603.1 106.46,132.88 PR4603.1
  BOTTOM w0.203: PU4601.37 105.9,132.06 105.74,131.89 v2(105.74,131.64)
PWR_RGND: length 26
  TOP w0.254: v2(114.63,135.32) v1(114.63,134.74)
  L4 w0.254: v2(99.01,135.2) 101.17,137.36 108.96,137.36 110.99,135.32 v2(114.63,135.32)
  BOTTOM w0.203: 102.59,137.1 102.77,137.1 103.29,136.58 PU4601.8
  BOTTOM w0.254: PR4615.1 114.72,135.41 v2(114.63,135.32) PC4610.2 ; v2(99.01,135.2) 99.21,135.4 99.8,135.4 100.11,135.71 PR4632.1 100.11,136.58 100.44,136.91 PC4612.2 101.1,137.1 102.59,137.1
PWR_SET1: length 4.5
  BOTTOM w0.203: PU4601.19 107.9,138.63 108.28,139.01
  BOTTOM w0.254: 108.28,139.01 109.04,139.77 v1(109.04,140.33) PR4634.1 PR4671.2
PWR_SET1_1: length 2
  BOTTOM w0.254: PR4671.1 109.93,143.04 v1(109.95,143.07) PR4670.2
PWR_SET1_2: length 2
  BOTTOM w0.254: PR4634.2 PR4669.1 108.79,143.26 108.78,143.26 108.61,143.43 v1(108.14,143.43)
PWR_SET2: length 5.1
  BOTTOM w0.203: PU4601.20 108.78,138.61
  BOTTOM w0.254: 108.78,138.61 109.21,139.03 109.21,139.04 110.54,140.38 v1(110.56,140.38) 110.56,140.4 110.88,140.72 PR4673.2 PR4676.1
PWR_SET2_1: length 1.9
  BOTTOM w0.254: PR4673.1 112.7,141.29 v1(112.72,141.32) 112.75,141.29 PR4672.2
PWR_SET2_2: length 2.2
  BOTTOM w0.254: PR4675.1 113.36,142.18 112.98,142.56 v1(112.78,142.56) 112.47,142.56 112.09,142.18 PR4676.2
PWR_TONSET: length 34.4
  L4 w0.254: v2(116.3,121.05) 116.15,121.05 115.72,121.48 115.72,126.56 108.51,133.77 106.17,133.77 105.92,134.03 102.36,134.03 v2(100.56,132.22)
  BOTTOM w0.203: v1(102.64,133.32) 102.64,133.44 103.37,134.18 PU4601.2
  BOTTOM w0.254: v1(102.64,133.32) 102.64,133.26 102,132.63 102,132.45 101.62,132.07 100.71,132.07 v2(100.56,132.22) ; PQ4601.1 119.85,122.04 PR4683.2 v2(116.3,121.05)
PWR_TONSET_1: length 4.1
  BOTTOM w0.254: PR4666.1 120.84,119.19 PC4625.1 118.87,119.19 118.69,119.37 v1(118.69,119.93) 118.95,120.18 PR4665.2
PWR_TONSET_D: length 4.5
  BOTTOM w0.254: PR4665.1 PR4683.1 v1(121.64,121.05) 122.24,121.05 122.36,121.18 122.36,122.1 122.11,122.35 PQ4601.6
PWR_TONSETA: length 18.9
  BOTTOM w0.203: PU4601.32 107.9,132.54 108.1,132.34 108.6,132.34
  BOTTOM w0.254: PQ4601.4 121.41,124.46 PR4682.1 120.89,125.48 119.97,126.4 118.77,126.4 118.4,126.78 117.33,126.78 114.68,129.43 113.02,129.43 112.96,129.49 111.3,129.49 110.73,129.49 110.16,130.07 110.15,130.07 109.97,130.25 109.97,130.97 v1(109.14,131.79) 108.6,132.34
PWR_TONSETA_1: length 4.5
  BOTTOM w0.254: PR4668.1 118.2,125.61 v1(117.9,125.9) 117.24,125.9 117.12,125.77 PC4623.1 117.64,123.98 PR4667.2
PWR_TONSETA_D: length 4
  BOTTOM w0.254: PQ4601.3 119.53,124.02 119.09,124.46 PR4668.2 119.09,125.73 119.25,125.9 v1(119.66,125.9) 120,125.55 PR4682.2
PWR_VCC: length 5.1
  BOTTOM w0.203: 109.85,137.28 109.55,136.98 PU4601.22
  BOTTOM w0.254: 109.85,137.28 110.74,138.17 v1(111.2,138.17) 112.19,138.17 PC4604.1 PR4604.1
PWR_VCCCORE_ENABLE: length 6.3
  TOP w0.102: v1(110.05,136) 109.98,136 109.23,135.26 PC4601.1 ; PR4639.1 PC4601.1 ; PC4601.1 109.55,134.82 109.8,134.56 109.8,134.05 v2(110.44,133.42)
  BOTTOM w0.102: PU4601.29 109.68,134.18 v2(110.44,133.42)
PWR_VCCCORE_SVC: length 3.7
  BOTTOM w0.127: PU4601.14 v1(105.9,139.39) 105.9,139.48 104.59,140.78 PR4625.2
PWR_VCCCORE_SVD: length 3.7
  BOTTOM w0.127: PU4601.15 106.3,139.81 v1(105.53,140.58) 105.48,140.62 PR4628.2
PWR_VCCCORE_SVT: length 3.5
  BOTTOM w0.127: PU4601.16 106.7,139.97 106.93,140.2 v1(106.93,140.3) 106.93,140.67 PR4630.2
PWR_VDDIO: length 6.2
  TOP w0.254: v2(104.79,139.26) 104.72,139.2 PC4618.1 103.87,138.43 v1(103.81,138.37)
  BOTTOM w0.203: PU4601.12 105.1,138.95 v2(104.79,139.26)
  BOTTOM w0.254: v2(104.79,139.26) 104.26,139.26 102.94,140.57 102.94,141.1 PR4648.2
PWR_VDDNB_BOOTA: length 5.1
  BOTTOM w0.203: PU4601.33 107.5,132.43 108.09,131.84 108.39,131.84 108.79,131.45 108.79,130.65
  BOTTOM w0.508: 108.79,130.65 PR4702.1 108.4,130.01 109.27,130.01 v1(109.42,129.86)
PWR_VDDNB_BOOTA_1: length 2.4
  BOTTOM w0.508: v1(105.86,128.82) PC4734.1 PR4702.2
PWR_VDDNB_ISENA1N: length 2.3
  BOTTOM w0.203: PR4708.1 110.87,134.43 110.55,134.75 110.32,134.75 v1(110.21,134.87) 110.1,134.98 PU4601.27
PWR_VDDNB_ISENA1P: length 5.2
  TOP w0.254: PC4702.1 111.14,133.48 v2(110.44,134.18) 110.44,134.71 v1(110.33,134.82)
  BOTTOM w0.203: PU4601.28 109.91,134.58 110.31,134.18 v2(110.44,134.18)
  BOTTOM w0.254: PR4712.2 PR4711.1 111.07,133.55 v2(110.44,134.18)
PWR_VDDNB_LGATEA: length 17.2
  TOP w0.762: PU4704.8 106.41,117.99 v3(106.37,117.95)
  L3 w0.762: v3(106.37,117.95) v3(106.37,123.49)
  L4 w0.762: v3(106.37,123.49) 106.12,123.74 v3(106.12,130.88)
  BOTTOM w0.203: v3(106.12,130.88) 106.48,131.24 v1(106.48,131.43) 106.3,131.61 PU4601.36
  BOTTOM w0.762: PU4703.8 106.41,123.45 v3(106.37,123.49)
PWR_VDDNB_PGOOD: length 7.9
  BOTTOM w0.127: PR4652.2 115.4,131.89 v1(114.53,131.89) 113.42,131.89 PR4680.1 112.7,131.6 112.11,132.19 110.27,132.19 109.05,133.41 PU4601.30
PWR_VDDNB_PHASEA: length 18.9
  L3 w0.762: v3(107.13,131.26) 107.13,130.75 107.9,129.99 107.9,126.77 111.45,123.22 111.45,118.18 v3(110.82,117.54)
  BOTTOM w0.203: PU4601.35 106.7,131.89 107.13,131.45 v3(107.13,131.26)
  BOTTOM w0.508: PC4734.2 107.13,130.27 v3(107.13,131.26)
  vias: v1(108.02,114.5) v1(109.17,116.15) v1(110.94,114.62) v3(106.12,116.53) v3(106.12,115.64) v3(106.12,114.75) v3(106.12,113.86) v3(107.01,116.53) v3(107.01,115.64) v3(107.01,114.75) v3(111.71,116.65) v3(111.71,115.77)
PWR_VDDNB_SNUB: length 2.6
  BOTTOM w0.508: PC4743.1 PR4710.2 v1(103.12,115.46)
PWR_VDDNB_UGATEA: length 20.2
  TOP w0.508: v3(112.47,117.95) 112.47,117.26 v1(112.7,117.04)
  TOP w0.762: v3(112.47,117.95) 112.43,117.99 PU4704.1
  L3 w0.762: v3(108.15,131.26) 108.91,130.5 108.91,127.2 112.47,123.64 v3(112.47,123.51)
  L4 w0.762: v3(112.47,117.95) v3(112.47,123.51)
  BOTTOM w0.203: PU4601.34 107.1,132.18 108.02,131.26 v3(108.15,131.26)
  BOTTOM w0.762: PU4703.1 112.43,123.47 v3(112.47,123.51)
PWR_VDDQ_SENSE_APU: length 155.8
  TOP w0.203: v2(104.72,17.47) 104.83,17.36 PU4901.9
  TOP w0.254: R417.1 v1(83.77,79.32) 80.87,79.32 80.11,78.55 74.64,78.55 74.5,78.41 70.37,78.41 v2(70.18,78.22)
  L4 w0.254: v2(104.72,17.47) 104.72,17.86 102.57,20.01 102.18,20.01 101.42,20.77 85.32,20.77 83.13,18.58 76.05,18.58 v2(75.84,18.38) 74.55,19.68 62.15,19.68 61.59,19.12 53.98,19.12 51.82,21.28 45.28,21.28 44.28,22.28 44.28,24.19 43.05,25.41 43.05,39.09 44.52,40.56 44.52,45.79 51.24,52.51 51.86,52.51 60.32,60.97 60.32,69.74 67.87,77.28 69.92,77.28 70.18,77.54 v2(70.18,78.22)
  BOTTOM w0.254: PG4907.1 75.84,14.17 v2(75.84,18.38)
PWR_VGA_COMP: length 4.7
  TOP w0.203: v2(147.52,92.4) 147.52,92 148.03,91.49 148.03,91.3 148.06,91.26 PU8202.7
  TOP w0.254: v2(147.52,92.4) 147.52,93.12 PC8208.1
  BOTTOM w0.254: PR8214.1 147.14,92.78 v2(147.52,92.4) 147.52,91.91 v1(147.34,91.74)
PWR_VGA_COMP_1: length 1.8
  BOTTOM w0.254: v1(147.9,95.01) 148.03,94.89 PR8215.1 PR8214.2
PWR_VGA_CORE_BOOT1: length 3.5
  TOP w0.203: 152.25,91.58 151.41,91.58 150.46,90.64 PU8202.1
  TOP w0.508: 152.25,91.58 v1(152.42,91.58) 152.87,91.58 PR8259.2
PWR_VGA_CORE_BOOT1_1: length 2.2
  TOP w0.508: v1(155.14,92.02) PR8259.1 154.25,91.95 PC8230.1
PWR_VGA_CORE_DCBATOUT:
  vias: v1(155.01,92.27) v1(158.82,92.27)
PWR_VGA_CORE_ISEN1N: length 4.4
  TOP w0.203: PU8202.3 149.66,91.15 149.81,91.29 149.81,91.53 v1(150.65,92.37) 150.67,92.4 150.67,92.46 150.97,92.75 151.03,92.75
  TOP w0.254: PR8265.1 152.04,92.92 152.04,92.9 151.89,92.75 151.03,92.75
PWR_VGA_CORE_ISEN1P: length 5.3
  TOP w0.203: PU8202.4 149.26,91.25 149.38,91.36 149.38,91.83 149.38,91.97 149.43,92.02 v1(149.43,92.36) 150.32,93.26 150.61,93.26 PC8234.1
  TOP w0.254: PC8234.1 PR8201.1 150.63,94.94 PR8263.2
PWR_VGA_CORE_LGATE1: length 10.7
  TOP w0.203: PU8202.38 152.84,88.95 v3(152.85,88.97)
  TOP w0.305: v3(152.85,88.97) 153.49,88.97 v1(154.12,88.33)
  L4 w1.016: v3(152.85,88.97) 154.12,87.7 v3(159.84,87.7)
PWR_VGA_CORE_PHASE1: length 26
  TOP w0.203: 152.22,89.73 151.84,89.35 PU8202.39
  TOP w0.508: v1(155.39,89.76) 155.09,89.45 PC8230.2 154.02,89.45 v3(152.85,90.62) 152.22,89.98 152.22,89.73
  L4 w1.016: v3(152.85,90.62) 164.92,90.62 166.95,88.59 v3(168.09,88.59)
  BOTTOM w0.508: PR8260.1 165.89,84.95 PU8205.5
PWR_VGA_CORE_UGATE1: length 19.8
  TOP w0.203: 151.22,90 PU8202.40
  TOP w0.508: v3(151.58,90.75) 151.22,90.38 151.22,90 ; v3(168.09,90.37) v1(168.09,91.1)
  L4 w1.016: v3(151.58,90.75) 151.59,90.75 151.59,91.25 152.22,91.89 165.55,91.89 167.08,90.37 v3(168.09,90.37)
PWR_VGA_FB: length 9.7
  TOP w0.203: PU8202.6 148.46,91.64 v2(148.54,91.71)
  TOP w0.254: v2(148.54,91.71) 148.5,91.71 148.03,92.19 148.03,92.61 148.21,92.79 148.21,93.53 PC8208.2 PC8209.1 v1(148.92,95.01)
  BOTTOM w0.254: v1(148.54,91.1) v2(148.54,91.71) 148.49,91.71 148.03,92.17 PR8215.2 PR8216.1
PWR_VGA_FB_1: length 2
  BOTTOM w0.254: v1(149.3,94.99) 149.81,94.48 PR8217.2 PR8216.2
PWR_VGA_IBIAS: length 2.5
  TOP w0.203: 147.66,84.3 PU8202.23
  TOP w0.254: PR8231.2 148.16,83.81 147.99,83.98 v1(147.99,84.11) 147.86,84.11 147.66,84.3
PWR_VGA_IMON: length 4.1
  TOP w0.203: v2(146.38,92.4) 146.38,91.91 147.26,91.02 PU8202.9
  BOTTOM w0.254: v2(146.38,92.4) 146.25,92.52 PR8229.1 v1(145.34,93.22)
PWR_VGA_IMON1: length 4.5
  TOP w0.254: PR8235.1 v2(142.76,94.84)
  BOTTOM w0.254: PR8229.2 v1(144.12,94.11) 143.48,94.11 v2(142.76,94.84)
PWR_VGA_IMON2: length 2.9
  TOP w0.254: PR8245.1 PR8235.2 143.65,94.94 PR8242.1 143.01,95.57 v1(142.67,95.57)
PWR_VGA_IMON4: length 33.9
  TOP w0.254: v2(143.58,96.59) PR8242.2
  BOTTOM w0.254: PR8244.1 173.24,93.98 170.25,96.97 161.45,96.97 159.8,98.62 151.08,98.62 v1(150.72,98.26) 149.68,97.22 144.22,97.22 v2(143.58,96.59)
PWR_VGA_IMON5: length 31.4
  TOP w0.254: PR8255.2 144.66,96.08 v2(145.13,96.08)
  BOTTOM w0.254: PR8244.2 172.35,94.16 v1(171.42,95.08) 170.04,96.46 161.24,96.46 159.59,98.11 151.46,98.11 150.06,96.72 145.74,96.72 145.13,96.11 v2(145.13,96.08)
PWR_VGA_OCP_L: length 4.3
  TOP w0.203: PU8202.21 146.86,84.98 146.15,84.27 145.68,84.27 145.46,84.05 v1(145.44,84.05) 145.44,84.03 PR8274.1 PR8248.2
PWR_VGA_OFS: length 5.1
  TOP w0.203: v2(144.85,87.06) 145.14,87.35 PU8202.17
  BOTTOM w0.254: v1(145.54,87.06) v2(144.85,87.06) 144.54,86.75 PC8214.1 PR8228.1 PR8227.1
PWR_VGA_PGOOD: length 4.9
  TOP w0.127: PU8202.31 151.22,84.26 151.41,84.07 v1(151.46,84.07) 151.57,84.07 PR8250.2 PR8273.1
PWR_VGA_PH1: length 31.9
  TOP w0.254: v2(151.46,94.94) 151.46,95.13 PR8263.1 149.79,95.89 v1(149.78,95.88)
  L4 w0.254: v2(172.54,89.73) 172.67,89.86 172.67,92.06 168.52,96.21 161.11,96.21 158.95,98.37 154.34,98.37 153.62,97.65 153.62,95.87 152.81,95.06 151.58,95.06 v2(151.46,94.94)
  BOTTOM w0.254: PG8219.1 172.21,89.4 v2(172.54,89.73)
PWR_VGA_PVCC: length 4.6
  TOP w0.203: PU8202.37 151.85,88.55 152.93,87.47 PC8202.1
  TOP w0.254: PC8202.1 153.07,87.38 PR8202.1 154.85,87.38 v1(155.17,87.7)
PWR_VGA_PWROK: length 17.9
  TOP w0.127: PR8254.2 143.96,90.37 144.66,89.66 144.66,89.66 v2(144.85,89.47) 144.85,89.46 145.36,88.95 PU8202.13 ; PR8269.1 v2(155.01,83.38)
  BOTTOM w0.127: v2(155.01,83.38) 155.01,84.14 154.12,85.03 147.51,85.03 v1(146.55,86) 146.45,86.09 146.45,87.87 v2(144.85,89.47)
PWR_VGA_RGND: length 49.3
  TOP w0.203: 147.14,91.82 147.66,91.29 PU8202.8
  TOP w0.254: v1(145.79,95.17) 146.15,95.17 v2(146.38,94.94) 146.05,94.61 146.05,93.57 146.39,93.22 PC8211.2 147.01,92.94 147.01,91.94 147.14,91.82 ; v2(160.12,113.71) 160.12,113.86 160.59,114.33 PR8222.2
  L3 w0.254: v2(160.12,113.71) 160.12,113.88 159.68,114.32 158.01,114.32 156.92,113.23 155.78,113.23 155.04,112.48 155.04,107.31 156.97,105.38 160.02,105.38 162.89,102.51 162.89,101.58 160.43,99.13 151.63,99.13 149.88,97.38 147.55,97.38 146.5,96.33 146.5,95.06 v2(146.38,94.94)
PWR_VGA_SET1: length 3.4
  TOP w0.203: PR8233.2 PC8215.1 144.19,86.81 144.52,86.48 v1(144.75,86.48) 144.83,86.55 PU8202.19
PWR_VGA_SET1_1: length 1.9
  TOP w0.254: PR8233.1 v1(141.96,85.92) PR8232.2
PWR_VGA_SET1_2: length 2.1
  TOP w0.254: v1(141.73,87.9) 141.73,87 PR8234.1 141.92,86.81 PC8215.2
PWR_VGA_SET2: length 3.9
  TOP w0.203: PU8202.20 146.11,85.78 145.84,85.51 145.16,85.51 144.88,85.23 144.88,85.21 v1(144.69,85.02) 144.69,85.02 144.68,85.03 PR8239.2 PR8240.1
PWR_VGA_SET2_1: length 2.2
  TOP w0.254: PR8239.1 142.42,85.03 v1(141.98,84.6) 141.55,85.03 PR8238.2
PWR_VGA_SET2_2: length 1.9
  TOP w0.254: PR8240.2 PR8241.1 142.89,82.4 v1(142.8,82.31)
PWR_VGA_SNUB: length 3
  BOTTOM w0.508: PC8232.1 162.91,80.95 v1(163.15,80.71) 163.65,80.71 164.21,81.27 PR8260.2
PWR_VGA_SVC: length 6.1
  TOP w0.127: PU8202.14 145.02,88.55 144.22,89.35 v2(144.22,89.48) PR8253.2
  BOTTOM w0.127: PR8256.1 143.71,90.37 144.22,89.86 v2(144.22,89.48) ; PR8256.1 143.52,90.24 PR8253.2 ; PR8256.1 143.65,91.27 v1(143.66,91.28)
PWR_VGA_SVD: length 5.4
  TOP w0.127: PU8202.15 144.53,88.15 v2(144.35,88.33) 144.09,88.59 PR8252.2
  BOTTOM w0.127: v1(145.01,88.33) v2(144.35,88.33) 143.71,87.7 PR8257.1 PR8252.2
PWR_VGA_SVT: length 2.6
  TOP w0.127: PU8202.16 145.06,87.75 145.01,87.7 v1(144.47,87.7) PR8251.2
PWR_VGA_TONSET: length 10.9
  TOP w0.203: PU8202.2 150.06,91.05 150.16,91.15 150.16,91.23 151.18,92.24
  TOP w0.254: 151.18,92.24 152.26,92.24 PR8206.1 154.14,93.22 v1(154.15,93.21) 154.48,92.88 155.76,92.88 156.39,93.51 157.38,93.51 158.33,92.56 PQ8201.S
PWR_VGA_TONSET_1: length 3.5
  TOP w0.254: PC8205.1 154.54,95.04 PR8205.1 154.87,95.37 v1(155.6,95.37) 155.6,94.62 PR8204.2
PWR_VGA_TONSET_D: length 7.3
  TOP w0.254: v1(159.76,94.47) PQ8201.D 156.63,94.47 155.56,93.4 PR8204.1 154.85,93.4 154.14,94.11 PR8206.2
PWR_VGA_VCC: length 4
  TOP w0.203: PU8202.22 147.26,84.58 146.9,84.22
  TOP w0.254: 146.9,84.22 v1(146.77,84.09) 146.77,83.67 147.01,83.43 PC8203.1 PR8203.1
PWR_VGA_VDDIO: length 4.6
  TOP w0.203: PR8237.2 PC8216.1 144.35,91.25 v1(144.63,90.97) 145.39,90.21 145.39,89.51 145.55,89.35 PU8202.12
PWR_VGA_VO1: length 35
  TOP w0.254: PC8234.2 PR8201.2 151.58,94.11 PR8265.2 PC8236.2 151.58,95.76 v2(151.58,95.83) 151.58,96.43 v1(151.53,96.48)
  L4 w0.254: v2(173.56,89.73) 173.17,90.11 173.17,92.27 168.73,96.72 161.36,96.72 159.2,98.87 154.12,98.87 153.11,97.86 153.11,96.08 152.6,95.57 151.84,95.57 v2(151.58,95.83)
  BOTTOM w0.254: PG8220.1 173.89,89.4 v2(173.56,89.73)
PWR_VGA_VREF: length 5.6
  TOP w0.203: PU8202.10 146.86,90.72 146.48,91.1
  TOP w0.254: PR8255.1 144.6,95 PR8245.2 PC8218.1 v1(145.43,92.22) 145.43,92.16 146.48,91.1
PWR_VGA_VSEN: length 54.6
  TOP w0.203: PU8202.5 148.86,91.36 149.02,91.51 149.02,91.91 v2(148.54,92.4)
  TOP w0.254: v2(148.54,92.4) 148.92,92.78 PC8209.2 ; v1(147.12,95.6) 147.14,95.57 v2(147.14,94.94) 146.73,94.53 PC8211.1 ; v2(159.48,113.83) 159.97,114.32 159.97,114.79 PR8220.2
  L3 w0.254: v2(159.48,113.83) 158.29,113.83 157.17,112.72 155.9,112.72 155.53,112.34 155.53,107.54 157.18,105.89 160.23,105.89 163.4,102.72 163.4,101.37 160.65,98.62 151.84,98.62 150.06,96.84 147.77,96.84 147.01,96.08 147.01,95.06 v2(147.14,94.94)
  BOTTOM w0.254: v2(148.54,92.4) 149.04,92.4 149.81,93.16 PR8217.1 150.2,93.22 150.42,93.44 150.42,94.59 149.59,95.42 148.98,95.42 148.94,95.38 148.52,95.38 148.45,95.45 147.65,95.45 v2(147.14,94.94)
PWR_VREF: length 10.1
  BOTTOM w0.203: PU4601.10 103.95,137.49 103.68,137.76
  BOTTOM w0.254: PR4659.2 99.12,140.07 PR4661.1 ; PR4661.1 99.26,140.47 PR4662.1 98.89,141.23 98.3,141.83 v1(98.3,141.95) ; PR4661.1 99.51,140.34 PR4660.2 101.74,139.64 PC4621.1 PC4620.1 102.82,138.63 103.68,137.76
PWR_VSEN: length 8.9
  TOP w0.254: PR4626.1 99.92,136.68 99.92,135.6 100.39,135.13 PR4623.2 102.42,135.13 v2(102.49,135.2) 102.87,135.2 103.18,135.51 v1(103.18,135.98)
  BOTTOM w0.203: PU4601.5 102.67,135.38
  BOTTOM w0.254: 102.67,135.38 v2(102.49,135.2) 101.86,135.2 PC4611.1 101.04,136.02 PC4612.1
PWR_VSENA: length 7.3
  BOTTOM w0.203: PC4605.2 110.58,135.26 110.46,135.38 PU4601.26
  BOTTOM w0.254: PC4610.1 112.98,135.26 PC4605.2 ; PC4610.1 113.04,134.94 PR4613.1 v1(113.55,133.52) ; PC4610.1 PR4607.2
PWRCNTL_2: length 1.9
  TOP w0.102: v2(170.84,106.32) 170.97,106.32 TP7514.1
  BOTTOM w0.102: GPU1.AK10 170.29,107.02 170.84,106.47 v2(170.84,106.32)
PWRCNTL_3: length 1.8
  TOP w0.102: TP7515.1 170.99,105.48 v2(170.81,105.66)
  BOTTOM w0.102: GPU1.AM10 170.29,106.18 v2(170.81,105.66)
PWRCNTL_4: length 1.7
  TOP w0.102: v2(172.06,117.21) 171.5,116.65 TP7511.1
  BOTTOM w0.102: v2(172.06,117.21) 172.06,117.52 171.89,117.69 GPU1.T8
PWRGOOD: length 2.6
  TOP w0.127: R7317.2 171.41,121.54 v2(170.71,120.85) 170.71,120.77 v1(171.14,120.34)
  BOTTOM w0.127: v2(170.71,120.85) 170.71,120.66 GPU1.N10
PWROK: length 4.1
  BOTTOM w0.127: PR4624.2 104.16,140.77 104.16,140.2 v1(104.32,140.05) 104.64,139.72 104.97,139.72 105.5,139.19 PU4601.13
PX_EN: length 1.1
  TOP w0.102: v2(165.17,112.42) 165.55,112.8 TP7510.1
  BOTTOM w0.102: v2(165.17,112.42) 165.49,112.74 GPU1.AB16
Q402_1: length 5
  TOP w0.102: 39.55,35.59 38.98,35.59 38.92,35.66 RN3001.3 ; 39.55,35.59 v1(39.55,35.42) ; 39.55,35.59 41.07,35.59 42.06,36.58 Q3003.B
Q603_2: length 4.4
  BOTTOM w0.102: Q603.2 117.98,92.65 117.85,92.52 117.85,92.09 117.96,91.99 118.61,91.99 Q603.3 118.63,91.99 R648.2 118.63,90.33 118.82,90.14 v1(118.82,89.7)
QSAN_0: length 44.3
  TOP w0.102: VRAM1.G3 155.28,143.59 154.92,143.95 154.92,143.96 154.65,144.23 v2(154.65,144.47)
  L4 w0.102: v2(154.65,144.47) 154.65,144.63 154.58,144.7 154.14,145.14 153.97,145.14 153.37,145.74 150.9,145.74 150.52,146.12 150.52,147.2 150.28,147.44 149.77,147.44 149.53,147.2 149.53,146.32 149.42,146.22 149.22,146.22 149.08,146.36 148.73,146.36 148.38,146.01 148.38,145.55 148.94,144.99 148.94,135.38 149.76,134.56 149.76,130.22 150.44,129.53 151,129.53 151.69,128.84 151.69,127.14 151.69,126.91 151.57,126.79 151.34,126.79 151.1,126.55 151.1,126.02 151.57,125.56 151.57,125.11 151.87,124.8 152.55,124.8 152.65,124.7 152.65,123.92 152.93,123.64 154.31,123.64 154.43,123.52 154.43,122.15 154.67,121.91 155.64,121.91 155.88,122.15 155.88,122.64 155.64,122.88 155.36,122.88 155.27,122.97 155.27,123.52 155.39,123.64 155.82,123.64 155.85,123.61 v2(156.25,123.61)
  BOTTOM w0.102: v2(156.25,123.61) 156.26,123.61 GPU1.H27
QSAN_1: length 41.2
  TOP w0.102: VRAM1.B7 151.39,146.55 151.49,146.45 151.89,146.45 151.99,146.35 151.99,146.04 151.81,145.86 150.03,145.86 149.15,146.75 149.15,147.29 148.94,147.49 148.45,147.49 146.77,145.81 146.77,137.03 147.58,136.22 147.58,134.87 150.56,131.89 151.58,131.89 151.76,131.72 151.76,131.41 151.64,131.28 v2(151.38,131.28)
  BOTTOM w0.102: 150.77,130.75 151.35,130.75 151.53,130.94 151.53,131.13 v2(151.38,131.28) ; 150.77,130.75 150.32,130.75 150.04,131.04 150.04,132.02 149.75,132.3 149.35,132.3 149.07,132.02 149.07,130.51 149.72,129.86 152.25,129.86 152.42,130.04 155.98,130.04 156.67,129.35 156.67,128.23 156.69,128.22 GPU1.A27 ; 150.77,130.75 v1(150.77,130.9)
QSAN_2: length 30.1
  BOTTOM w0.102: GPU1.C23 159.89,127.57 160.13,127.82 arc(160.2,127.91) 160.22,128.03 160.22,128.2 160.08,128.34 160.08,129.29 159.77,129.59 159.77,130.88 157.02,133.63 154.88,133.63 154.42,134.09 ; v1(154.53,134.21) 154.42,134.09 ; 154.42,134.09 154.04,134.47 154.04,134.61 154.3,134.87 154.3,135.21 154.06,135.44 153.73,135.44 153.47,135.19 153.32,135.19 153.22,135.28 153.22,136.06 152.89,136.39 152.89,136.54 153.12,136.77 153.12,137.08 152.85,137.34 152.54,137.34 152.31,137.11 152.17,137.11 152.02,137.26 152.02,137.4 152.25,137.63 152.25,137.94 151.99,138.2 151.68,138.2 151.45,137.97 151.3,137.97 151.16,138.12 151.16,138.26 151.39,138.49 151.39,138.8 151.13,139.07 150.81,139.07 150.58,138.84 150.44,138.84 150.3,138.98 150.3,139.12 150.53,139.35 150.53,139.67 150.26,139.93 149.95,139.93 149.72,139.7 149.58,139.7 149.29,139.98 149.29,142.91 150.81,144.43 151.24,144.43 151.65,144.01 151.65,143.85 VRAM2.B7
QSAN_3: length 44
  L3 w0.102: v2(162.15,131.03) 161.32,131.03 160.76,130.47 159.27,130.47 158.03,131.72 156.58,131.72 156.39,131.91 156.39,133.87 156.15,134.1 155.63,134.1 155.39,133.87 155.39,131.69 155.29,131.59 154.96,131.59 154.86,131.69 154.86,133.84 154.63,134.08 154.18,134.08 153.97,133.87 153.97,133.16 153.85,133.04 153.45,133.04 153.14,133.35 151.56,133.35 149.65,135.26 149.65,145.31 149.85,145.51 152.8,145.51 153.18,145.14 154.44,145.14 v2(154.83,145.53)
  BOTTOM w0.102: v2(154.83,145.53) 154.83,146.46 155.16,146.79 VRAM2.G3 ; GPU1.C19 162.82,127.51 162.82,127.83 162.79,127.88 162.76,127.92 162.76,128.37 162.83,128.44 162.83,129.05 162.89,129.1 162.89,130.29 162.61,130.57 162.61,130.6 162.18,131.03 v2(162.15,131.03) 162.61,131.5 v1(162.67,131.5)
QSAN_4: length 46
  TOP w0.102: v2(181.13,145.62) 181.13,146.02 181.1,146.04 181.1,146.21 180.52,146.79 VRAM3.G3
  L3 w0.102: v2(181.13,145.62) 181.13,145.36 181.23,145.25 182.03,145.25 182.15,145.13 182.15,141.04 182.46,140.73 184.88,140.73 184.99,140.63 184.99,140.16 184.88,140.05 182.78,140.05 182.55,139.82 182.55,139.43 182.78,139.19 184.9,139.19 185,139.09 185,137.52 181.18,133.7 179.91,133.7 177.97,131.76 172,131.76 171.65,131.41 171.65,130.17 171.55,130.07 171.12,130.07 171.02,130.17 171.02,131.44 170.7,131.76 167.78,131.76 167.23,131.2 167.23,130.52 v2(167,130.3)
  BOTTOM w0.102: v1(167.59,130.62) 167.33,130.62 v2(167,130.3) 167,130.21 166.48,129.68 166.48,128.52 166.62,128.38 166.62,127.92 166.52,127.72 166.41,127.49 GPU1.C15
QSAN_5: length 41.8
  BOTTOM w0.102: v1(179.75,132.63) 179.64,132.74 ; 179.64,132.74 184.31,137.42 184.31,137.73 184.11,137.93 184.11,138.07 184.25,138.22 184.4,138.22 184.6,138.02 184.91,138.02 185.17,138.28 185.17,138.59 184.97,138.79 184.97,138.94 185.12,139.08 185.26,139.08 185.46,138.88 185.77,138.88 186.04,139.14 186.04,139.74 186.19,139.9 186.19,139.9 186.93,139.9 187.22,140.19 187.22,143.36 186.43,144.15 186.43,144.86 186.18,145.11 185.72,145.11 185.42,145.41 184.53,145.41 183.61,144.49 183.47,144.49 183.25,144.7 183.25,144.85 184.39,145.99 VRAM4.B7 ; 179.64,132.74 178.9,132.01 178.36,132.01 178.14,132.23 178.14,132.73 178.04,132.83 177.84,132.83 177.74,132.73 177.74,132.23 177.52,132.01 177.15,132.01 176.92,132.23 176.92,132.73 176.82,132.83 176.62,132.83 176.52,132.73 176.52,132.23 176.3,132.01 175.93,132.01 175.71,132.23 175.71,132.73 175.6,132.83 175.4,132.83 175.3,132.73 175.3,132.23 175.08,132.01 172.81,132.01 170.9,130.1 170.9,129.31 170.76,129.17 170.76,128.18 170.76,128.18 170.76,127.92 170.77,127.89 170.82,127.77 170.82,127.44 170.8,127.42 arc(170.77,127.37) 170.76,127.32 170.76,126.77 GPU1.E9
QSAN_6: length 38.4
  TOP w0.102: 183.77,134.36 184.35,134.36 186.49,136.49 186.49,136.98 186.38,137.08 184.88,137.08 184.66,137.3 184.66,137.69 184.87,137.9 186.38,137.9 186.49,138 186.49,138.2 186.38,138.3 184.8,138.3 184.6,138.5 184.6,138.9 184.82,139.11 186.38,139.11 186.49,139.22 186.49,139.42 186.38,139.52 185.83,139.52 185.6,139.76 185.6,140.1 185.83,140.33 186.38,140.33 186.49,140.44 186.49,144.43 186.32,144.59 184,144.59 183.79,144.38 183.79,143.85 184.06,143.59 VRAM3.B7 ; 183.77,134.36 v1(183.77,134.51) ; 183.77,134.36 182.65,134.36 179.6,131.31 175.99,131.31 174.92,130.24 174.52,130.24 174.39,130.11 174.39,129.82 174.27,129.7 174.27,129.49 v2(174.48,129.28)
  BOTTOM w0.102: v2(174.48,129.28) 174.18,128.98 174.18,128.5 173.93,128.26 173.93,128.02 arc(173.94,127.94) 173.97,127.87 173.98,127.87 174.02,127.75 174.02,127.35 174.13,127.24 GPU1.C5
QSAN_7: length 46.5
  L4 w0.102: v2(181,144.8) 181.39,144.41 181.81,144.41 181.99,144.58 182.82,144.58 182.96,144.72 183.59,144.72 183.87,144.44 183.87,141.16 184.1,140.92 186.15,140.92 186.25,140.82 186.25,140.62 186.15,140.52 183.94,140.52 183.69,140.26 183.69,139.9 183.94,139.65 186.15,139.65 186.25,139.55 186.25,139.35 186.15,139.25 184.28,139.25 183.97,138.93 183.97,136.09 184.28,135.77 184.69,135.77 184.78,135.69 184.78,135.49 184.66,135.37 182.72,135.37 182.47,135.12 182.47,134.69 182.72,134.43 184.64,134.43 184.78,134.29 184.78,134.09 184.64,133.95 183.42,133.95 183.11,133.65 183.11,131.7 180.08,128.67 179.81,128.67 179.49,128.35 179.49,128.08 177.39,125.98 177.39,125.21 177.06,124.88 v2(177.06,124.63)
  BOTTOM w0.102: v1(178.28,124.71) 178,124.43 177.37,124.43 177.16,124.63 v2(177.06,124.63) 176.47,124.63 176.15,124.31 175.7,124.31 175.57,124.37 175.37,124.37 175.34,124.35 175.31,124.34 175.22,124.31 174.96,124.31 GPU1.H4 ; v2(181,144.8) 181,144.79 181,144.25 180.99,144.24 180.99,143.9 180.68,143.59 VRAM4.G3
QSAP_0: length 44.6
  TOP w0.102: VRAM1.F3 154.72,143.72 154.72,143.88 154.53,144.06 154.35,144.06 154.23,144.18 v2(154.03,144.18) ; v2(156.28,124.44) 155.89,124.44 v1(155.67,124.22)
  L4 w0.102: v2(154.03,144.18) 154.24,144.39 154.24,144.71 154.05,144.91 153.87,144.91 153.27,145.51 150.8,145.51 150.29,146.02 150.29,147.11 150.19,147.21 149.86,147.21 149.76,147.11 149.76,146.23 149.52,145.99 149.13,145.99 148.99,146.13 148.82,146.13 148.61,145.91 148.61,145.65 149.17,145.09 149.17,135.47 149.92,134.72 149.98,134.65 149.98,130.31 150.54,129.76 151.09,129.76 151.92,128.94 151.92,127.05 151.92,126.81 151.66,126.56 151.43,126.56 151.33,126.46 151.33,126.11 151.79,125.65 151.79,125.2 151.96,125.03 152.64,125.03 152.88,124.8 152.88,124.02 153.03,123.87 154.4,123.87 154.66,123.61 154.66,122.24 154.76,122.14 155.55,122.14 155.65,122.24 155.65,122.55 155.55,122.65 155.27,122.65 155.04,122.88 155.04,123.61 155.3,123.87 155.7,123.87 155.8,123.97 155.8,124.34 155.9,124.44 v2(156.28,124.44)
  BOTTOM w0.102: v2(156.28,124.44) 156.28,124.17 156.15,124.04 GPU1.H28
QSAP_1: length 41.5
  TOP w0.102: v1(147.14,142.21) 146.97,142.21 ; 146.97,142.21 146.97,145.73 148.54,147.29 148.86,147.29 148.94,147.2 148.94,146.67 149.95,145.66 151.89,145.66 152.19,145.96 VRAM1.C7 ; 146.97,142.21 146.97,137.11 147.79,136.3 147.79,134.95 150.64,132.1 151.67,132.1 151.97,131.8 v2(151.97,130.98)
  BOTTOM w0.102: GPU1.C27 156.69,127.57 156.93,127.81 156.99,127.9 157.02,127.97 157.02,128.02 157.02,128.13 157,128.17 156.98,128.23 156.88,128.33 156.88,129.43 156.06,130.24 152.34,130.24 152.16,130.07 149.81,130.07 149.27,130.6 149.27,131.93 149.44,132.1 149.67,132.1 149.83,131.93 149.83,130.95 150.24,130.55 151.43,130.55 151.86,130.98 v2(151.97,130.98)
QSAP_2: length 29.8
  BOTTOM w0.102: 153.02,135.55 153.02,135.2 153.24,134.98 153.55,134.98 153.81,135.24 153.98,135.24 154.1,135.12 154.1,134.95 153.84,134.69 153.84,134.38 154.8,133.42 156.94,133.42 159.57,130.79 159.57,129.51 159.87,129.2 159.87,128.06 GPU1.A23 ; 153.02,135.55 v1(152.85,135.55) ; 153.02,135.55 153.02,135.97 152.68,136.31 152.68,136.62 152.91,136.85 152.91,136.99 152.77,137.14 152.62,137.14 152.39,136.91 152.08,136.91 151.82,137.17 151.82,137.48 152.05,137.71 152.05,137.86 151.9,138 151.76,138 151.53,137.77 151.22,137.77 150.96,138.03 150.96,138.35 151.19,138.58 151.19,138.72 151.04,138.86 150.9,138.86 150.67,138.63 150.36,138.63 150.09,138.9 150.09,139.21 150.32,139.44 150.32,139.58 150.18,139.73 150.04,139.73 149.81,139.5 149.49,139.5 149.09,139.9 149.09,143 150.73,144.63 151.32,144.63 151.85,144.1 151.85,143.93 VRAM2.C7
QSAP_3: length 43.6
  L3 w0.102: v2(162.21,130.4) 161.98,130.63 161.98,130.63 161.8,130.8 161.41,130.8 160.85,130.24 159.18,130.24 157.93,131.49 156.49,131.49 156.16,131.82 156.16,133.77 156.06,133.88 155.73,133.88 155.62,133.77 155.62,131.6 155.39,131.36 154.87,131.36 154.63,131.6 154.63,133.75 154.53,133.85 154.28,133.85 154.18,133.75 154.18,133.04 153.94,132.81 153.36,132.81 153.04,133.13 151.47,133.13 149.43,135.17 149.43,145.41 149.76,145.74 152.9,145.74 153.27,145.36 153.96,145.36 v2(154.14,145.54)
  BOTTOM w0.102: GPU1.E19 163.09,126.77 162.76,127.1 162.76,127.28 162.62,127.42 162.62,127.76 162.59,127.81 162.56,127.86 162.56,128.45 162.63,128.53 162.63,129.13 162.68,129.19 162.68,130.21 162.49,130.4 v2(162.21,130.4) ; v2(154.14,145.54) 154.63,146.04 154.63,146.75 VRAM2.F3
QSAP_4: length 45.7
  TOP w0.102: v2(182.17,145.71) 181.72,145.71 181.31,146.12 181.31,146.29 181.19,146.41 VRAM3.F3
  L3 w0.102: v2(167.04,129.66) 167.45,130.08 167.45,131.11 167.88,131.53 170.6,131.53 170.79,131.34 170.79,130.07 171.02,129.84 171.64,129.84 171.88,130.07 171.88,131.32 172.09,131.53 178.07,131.53 180.01,133.47 181.28,133.47 185.23,137.43 185.23,139.18 185,139.42 182.88,139.42 182.78,139.52 182.78,139.72 182.88,139.83 184.98,139.83 185.21,140.06 185.21,140.73 184.98,140.96 182.56,140.96 182.38,141.14 182.38,145.19 182.17,145.4 v2(182.17,145.71)
  BOTTOM w0.102: v2(167.04,129.66) 166.91,129.66 166.68,129.44 166.68,128.6 166.82,128.46 166.82,127.88 166.72,127.66 166.68,127.37 166.6,127.08 GPU1.E15
QSAP_5: length 41.8
  BOTTOM w0.102: v1(171.47,131.16) 171.57,131.06 ; 171.57,131.06 170.7,130.19 170.7,129.39 170.59,129.29 170.56,129.25 170.56,128.26 170.56,127.88 170.62,127.73 170.62,127.52 arc(170.57,127.45) 170.56,127.37 170.56,127.11 GPU1.D10 ; 171.57,131.06 172.72,132.21 174.99,132.21 175.1,132.31 175.1,132.82 175.32,133.04 175.69,133.04 175.91,132.82 175.91,132.31 176.01,132.21 176.21,132.21 176.32,132.31 176.32,132.82 176.54,133.04 176.91,133.04 177.13,132.82 177.13,132.31 177.23,132.21 177.43,132.21 177.53,132.31 177.53,132.82 177.75,133.04 178.13,133.04 178.35,132.82 178.35,132.31 178.45,132.21 178.82,132.21 184.11,137.5 184.11,137.65 183.91,137.85 183.91,138.16 184.17,138.42 184.48,138.42 184.68,138.22 184.83,138.22 184.97,138.36 184.97,138.51 184.77,138.71 184.77,139.02 185.03,139.29 185.34,139.29 185.55,139.08 185.69,139.08 185.83,139.23 185.83,139.83 185.99,139.98 185.99,139.98 186.11,140.1 186.84,140.1 187.02,140.28 187.02,143.27 186.23,144.06 186.23,144.77 186.1,144.9 185.64,144.9 185.34,145.2 184.61,145.2 183.69,144.28 183.38,144.28 183.05,144.62 183.05,144.93 184.19,146.07 184.19,146.49 183.88,146.79 VRAM4.C7
QSAP_6: length 39
  TOP w0.102: 178.56,131.11 176.07,131.11 v2(174.8,129.83) ; 178.56,131.11 v1(178.56,130.95) ; 178.56,131.11 179.69,131.11 182.73,134.15 184.44,134.15 186.69,136.41 186.69,137.07 186.47,137.29 184.96,137.29 184.86,137.39 184.86,137.6 184.95,137.69 186.47,137.69 186.69,137.91 186.69,138.28 186.47,138.51 184.89,138.51 184.81,138.58 184.81,138.82 184.9,138.91 186.47,138.91 186.69,139.13 186.69,139.5 186.47,139.72 185.92,139.72 185.8,139.84 185.8,140.01 185.92,140.13 186.47,140.13 186.69,140.35 186.69,144.52 186.41,144.8 183.92,144.8 183.59,144.47 VRAM3.C7
  BOTTOM w0.102: v2(174.8,129.83) 174.45,129.83 174.07,129.45 174.07,129.16 173.97,129.07 173.97,128.59 173.73,128.34 173.73,128.02 arc(173.75,127.89) 173.8,127.77 173.82,127.71 173.82,127.5 173.49,127.17 GPU1.D6
QSAP_7: length 46.1
  TOP w0.102: v2(177.72,124.88) 178,124.61 v1(178.37,124.61)
  L4 w0.102: v2(181.64,144.81) 182.73,144.81 182.86,144.95 183.68,144.95 184.1,144.54 184.1,141.25 184.2,141.15 186.24,141.15 186.48,140.92 186.48,140.52 186.24,140.29 184.04,140.29 183.92,140.17 183.92,140 184.04,139.88 186.24,139.88 186.48,139.65 186.48,139.25 186.24,139.02 184.38,139.02 184.2,138.84 184.2,136.18 184.38,136 184.79,136 185.01,135.78 185.01,135.4 184.75,135.14 182.81,135.14 182.7,135.02 182.7,134.78 182.81,134.66 184.74,134.66 185.01,134.39 185.01,134 184.74,133.72 183.51,133.72 183.34,133.55 183.34,131.61 180.18,128.44 179.91,128.44 179.72,128.26 179.72,127.99 177.62,125.88 177.62,124.99 v2(177.72,124.88)
  BOTTOM w0.102: v2(181.64,144.81) 181.64,144.73 181.2,144.29 181.2,144.17 181.19,144.15 VRAM4.F3 ; v2(177.72,124.88) 177.57,125.04 176.59,125.04 176.06,124.51 175.75,124.51 175.61,124.58 175.29,124.58 175.24,124.53 175.18,124.51 174.95,124.51 174.62,124.84 GPU1.G5
RASA0#: length 33.6
  TOP w0.14: v2(156.67,144.65) 156.44,144.65 156.26,144.47 156.26,144.02 156.66,143.62 156.77,143.62 156.8,143.59 VRAM1.J3
  L4 w0.165: v2(156.67,144.65) 157.06,144.65 157.67,145.26 157.67,145.99 157.93,146.25 159.44,146.25 159.69,145.99 159.69,145.63 159.65,145.59 159.65,145.1 159.91,144.84 160.11,144.65 160.11,144.37 160.49,144 ; v2(161.57,125.06) 161.24,125.39 161.24,126.78 161.28,126.81
  L4 w0.267: 161.28,126.81 161.28,129.2 161.08,129.39 161.08,131.18 161.42,131.52 162.13,131.52 163.28,132.67 163.28,140.06 162.36,140.98 162,140.98 161.72,141.26 161.72,141.76 161.88,141.93 161.88,142.6 160.49,144
  BOTTOM w0.14: v2(156.67,144.65) 156.49,144.83 156.49,145.05 156.48,145.05 156.48,146.28 VRAM2.J3
  BOTTOM w0.279: GPU1.G22 161.35,124.84 161.57,125.06 v2(161.57,125.06)
RASA1#: length 37.4
  TOP w0.14: v2(179.02,145.6) 179.38,145.6 179.55,145.77 179.55,146.11 179.53,146.13 179.53,146.32 179.06,146.79 VRAM3.J3
  L4 w0.267: v2(165.11,125.12) 165.11,125.91 165.03,126 165.03,128.74 165.16,128.87 165.16,135.56 166.14,136.54 169.05,136.54 169.33,136.82 169.33,138.9 173.67,143.24 173.88,143.24 175.21,144.57 175.21,145.19 175.06,145.34 175.06,145.63 175.04,145.65 175.04,146.5 175.32,146.78 178.11,146.78 179.02,145.87 v2(179.02,145.6)
  BOTTOM w0.14: VRAM4.J3 179.27,144.07 179.27,145.09 179.25,145.11 179.25,145.37 v2(179.02,145.6)
  BOTTOM w0.279: GPU1.G17 164.77,125.12 v2(165.11,125.12)
REGOUT:
  vias: v1(26.49,40.84)
RING2: length 30.1
  TOP w0.203: 36.34,14.62 36.34,14.53 36.23,14.42 HDA27.17
  TOP w0.305: 36.34,14.62 36.34,15.24 36.24,15.33 v3(36.24,15.36) 34.92,16.68 RN2901.4
  L3 w1.016: v3(36.24,15.36) 36.12,15.23 32.19,15.23 29.92,12.96 29.92,10.48 27.89,8.45 27.89,4.64 27.12,3.88 20.77,3.88 v3(20.01,4.64)
  BOTTOM w0.305: v1(37.03,15.36) v3(36.24,15.36)
RING2_R: length 15.1
  TOP w1.016: HPMIC1.3 4.1,3.1 5.28,1.92 15.19,1.92 16.25,2.99 v1(16.33,2.99) ED2903.1
RSET: length 4.6
  BOTTOM w0.203: LOM30.31 33.43,45.35 33.16,45.62
  BOTTOM w0.305: R3032.2 30.83,48.16 31.45,47.54 v1(31.47,47.54) 31.47,47.52 32.1,46.89 32.1,46.68 33.16,45.62
RSMRST#_KBC: length 267.4
  TOP w0.127: KBC24.15 175.93,29.3 175.08,30.15 175.08,30.6 v2(174.83,30.85) ; v2(121.28,92.36) 121.88,92.36 v1(121.92,92.32) 121.92,91.32 R628.2
  L3 w0.127: v2(184.53,45.97) 184.12,46.37 184.12,59.36 194.19,69.43 194.19,79.67 195.08,80.55 195.08,82.07 193.27,83.88 193.27,107.11 193.94,107.78 193.94,114.25 193.3,114.88 193.3,135.14 189.76,138.68 189.76,147.08 188.43,148.41 188.43,150.68 187.67,151.44 187.67,152.03 186.3,153.4 173.34,153.4 170.05,150.1 170.05,150.1 169.56,149.61 165.74,149.61 162.82,152.53 148.51,152.53 146.07,150.09 142.85,150.09 142.53,149.77 142.53,142.46 143.8,141.19 144.08,140.91 144.08,133.33 145.3,132.11 145.3,131.2 146.61,129.89 146.61,126.2 150,122.81 150,113.99 145.61,109.61 144.16,109.61 140.31,105.76 131.55,105.76 121.28,95.49 v2(121.28,92.36)
  L4 w0.127: v2(184.53,45.97) 184.26,45.97 180.72,42.43 180.72,36.75 177.85,33.88 177.85,33.49 175.28,30.93 174.91,30.93 v2(174.83,30.85)
RTC_1D5V_EN: length 5.9
  TOP w0.102: R706.1 R705.1 115.99,103.86 117.87,103.86 v1(118.06,103.67) 118.16,103.57 118.16,103.01 118.5,102.67 U701.3
RTC_1D5V_PWR: length 9.1
  TOP w0.127: R701.1 116.98,102.43 R704.2 117.24,102.16 117.24,101.01 C702.1 116.88,100.46 118.86,100.46 119.81,99.51 U701.5 120.4,98.48 v1(121.23,97.65)
RTC_1D5V_S5: length 38
  TOP w0.127: G701.1 112.85,101.92 112.53,101.6 Q701.D ; G701.1 113.99,101.03 114.12,100.91 115.16,100.91 C701.1 114.82,99.85 114.82,98.82 115.74,97.9 119.69,97.9 120.28,97.3 120.28,96.53 120.28,94.61 118.25,92.58 115.95,92.58 v1(115.95,92.57) 115.95,92.58 109.62,92.58 107.6,90.56 106.8,90.56 106.29,91.08 106.29,92.29 106.02,92.55 105.08,92.55 v2(104.67,92.14) ; G701.1 113.99,102.68 114.12,102.81 115.07,102.81 R701.2
  BOTTOM w0.127: CPU1.AN4 104.28,91.75 v2(104.67,92.14)
RTC_AUX_S5: length 246.8
  TOP w0.254: R704.1 117.78,102.52 117.78,101.15 118.14,100.78 119.96,100.78 120.4,101.22 U701.1
  TOP w0.508: U701.1 121.39,100.8 C705.1 122.35,100.8 122.76,100.4 122.76,98.99 122.27,98.51 v2(122.01,98.51) ; R705.2 116.98,103.32 R704.1
  L4 w0.508: v2(122.01,98.51) 122.25,98.75 124.27,98.75 124.54,99.01 129.99,99.01 133.17,95.84 133.17,94.81 138.71,89.27 138.71,84.08 141,81.78 141,80.89 141.42,80.47 141.42,65.09 141.58,64.94 141.58,58.62 148.15,52.04 151.17,52.04 153.38,49.84 153.38,48.85 149.35,44.82 149.35,38.93 148.64,38.21 148.64,28.03 v2(148.66,28.01) 148.71,27.96 148.71,21.93 150.06,20.58 150.06,20.39 151.08,19.37 151.08,15.23 149.53,13.68 148.13,13.68 145.62,11.17 143.71,11.17 140.25,7.71 138.64,7.71 138.38,7.46 133.17,7.46 132.96,7.67 130.34,7.67 130.09,7.41 114.25,7.41 113.3,8.36 106.96,8.36 106.01,7.41 104.45,7.41 104.28,7.59 79.42,7.59 71.6,15.41 64.64,15.41 63.83,16.22 59.97,16.22 57.68,13.94 57.68,13.02 v2(55.8,11.14)
  BOTTOM w0.508: v2(148.66,28.01) 153.13,28.01 154.72,26.42 159.26,26.42 159.7,25.99 v1(160.55,25.99) 161.24,25.99 161.96,25.26 164.3,25.26 164.53,25.49 165.97,25.49 165.99,25.51 166.93,25.51 R2428.2 ; C2503.2 55.99,11.33 v2(55.8,11.14) 55.79,11.13 D2501.3
RTC_CLK: length 11.3
  TOP w0.14: v2(113.33,85.92) v1(113.89,85.92)
  L4 w0.14: v2(106.43,87.57) 106.52,87.57 107,87.09 108.25,87.09 108.97,86.37 112.88,86.37 113.33,85.92 v2(113.33,85.92)
  BOTTOM w0.14: v2(113.33,85.92) 113.4,85.86 R1917.1 114.18,85.92 R1918.1 R609.1 ; CPU1.AV11 106.8,87.94 v2(106.43,87.57)
RTC_DET#: length 214.9
  L3 w0.102: v2(117.8,84.02) 118.23,84.45 123.96,84.45 124.03,84.37 124.81,84.37 130.83,78.35 130.83,66.87 131.57,66.13 131.57,56.8 133.95,54.42 133.99,54.42 135.46,52.96 135.46,52.92 137.75,50.62 137.81,50.62 139.33,49.1 139.33,47.24 148,38.57 148,36.45 148.54,35.92 148.54,32.96 149.43,32.07 149.43,31.08 149.83,30.68 149.83,26.59 150.26,26.16 150.26,25.73 152.47,23.52 v2(152.47,21.4)
  L4 w0.102: v2(107.21,85.36) 108.37,85.36 108.79,84.94 116.88,84.94 v2(117.8,84.02) ; v2(51.79,12.72) 51.79,12.72 51.79,12.51 53.91,10.39 57.47,10.39 58.8,11.71 58.8,13.93 60.55,15.69 63.01,15.69 63.93,14.77 70.99,14.77 78.99,6.77 86.07,6.77 86.45,7.15 97.18,7.15 97.35,6.98 130.27,6.98 130.52,7.23 132.78,7.23 132.99,7.03 138.56,7.03 138.82,7.28 140.43,7.28 143.88,10.74 145.92,10.74 148.44,13.25 149.71,13.25 151.79,15.33 151.79,20.72 v2(152.47,21.4)
  BOTTOM w0.102: CPU1.AV15 107.21,85.44 v2(107.21,85.36) ; R634.1 118.16,83.4 v1(118.08,83.48) 117.8,83.76 v2(117.8,84.02) ; v2(51.79,12.72) 51,13.5 Q2505.D
RTC_PWR: length 5.8
  BOTTOM w0.508: D2501.2 52.85,11.69 Q2505.G 51.99,11.06 52.21,10.84 R2504.1 52.3,10.14 v1(52.3,9.31) R2502.1
RTCRST_ON: length 299.5
  TOP w0.127: v2(120.6,103.19) 119.01,104.78 v1(113.05,104.78) 112.47,104.78 R702.1 Q701.G ; KBC24.120 172.89,23.05 173.15,23.31 173.15,23.88 v2(172.71,24.33)
  L3 w0.127: v2(190.32,153.74) 189.92,153.74 189.22,154.44 189.22,155.36 187.56,157.02 187.56,157.02 187.54,157.04 166.04,157.04 165.2,156.2 148.1,156.2 144.79,152.89 143.62,152.89 143.62,152.89 141.69,152.89 139.78,152.89 137.13,150.24 137.13,146.29 138.69,144.73 138.69,138.31 137.83,137.44 137.83,129.83 143.46,124.2 143.46,121.48 143.92,121.02 143.92,117.01 141.09,114.19 141.09,113.38 138.62,110.9 132.24,110.9 132.24,110.9 131.73,110.9 131.26,110.9 131.23,110.88 131.21,110.88 130.99,110.66 129.16,110.66 122.83,104.34 121.74,104.34 v2(120.6,103.19) ; v2(191.07,44.71) 187.91,47.87 v2(185.98,47.87)
  L4 w0.127: v2(172.71,24.33) 172.71,24.41 172.26,24.86 172.26,25.67 172.58,25.98 172.58,31.02 173.24,31.68 173.24,31.82 174.27,32.85 176.11,32.85 180.24,36.98 180.24,42.65 185.46,47.87 v2(185.98,47.87) ; v2(199.84,102.13) 199.82,102.13 198.14,100.45 198.14,99.89 196.9,98.64 196.9,94.74 197.28,94.35 197.28,85.55 198.75,84.07 198.75,80.75 199.55,79.95 199.55,71.53 189.49,61.48 189.49,50.74 189.67,50.56 189.67,46.11 v2(191.07,44.71)
  BOTTOM w0.127: v2(190.32,153.74) 189.29,152.71 189.29,148.57 190.48,147.38 190.48,139.78 195.87,134.39 199,134.39 199.47,133.93 199.47,132.83 199.3,132.66 199.3,121.21 199.71,120.8 199.71,108.12 199.84,107.99 v2(199.84,102.13)
RUNPWROK_D: length 2.5
  TOP w0.127: D3606.A R3627.1 138.95,60.18 v1(138.88,60.11)
S0_PWR_GOOD_R: length 24.4
  TOP w0.127: R611.2 R627.1 123.64,83.7 122.31,82.37 122.31,82.17 121.49,81.35 120.89,81.35 119.13,83.1 v1(114.88,83.1) 113.99,83.1 113.92,83.16 112.19,83.16 111.83,83.53 109.48,83.53 108.13,84.88 104.75,84.88 v2(103.99,84.12)
  BOTTOM w0.127: v2(103.99,84.12) 103.6,83.73 CPU1.AM19
S5_ENABLE: length 35.9
  TOP w0.127: Q2403.D 151.52,30.48 151.18,30.14 v2(151.18,29.84) 151.18,29.37 151.06,29.25 151.06,27.89 151.46,27.5 151.46,26.48 v1(151.43,26.46) 151.24,26.27 R3603.2 ; v2(174.16,30.21) 174.53,30.21 175.84,28.9 KBC24.14
  L3 w0.127: v2(165.17,30.8) 161.49,30.8 161.17,31.12 159.14,31.12 v2(158.7,30.68)
  BOTTOM w0.127: v2(151.18,29.84) 155.39,29.84 156.68,31.12 158.25,31.12 v2(158.7,30.68) ; v2(174.16,30.21) 173.7,30.68 168.58,30.68 167.64,29.74 R2436.2 167.18,29.98 166,29.98 v2(165.17,30.8)
SATA_LED#: length 3.6
  TOP w0.102: TP1902.1 110.44,77.69 v2(110.94,77.18)
  BOTTOM w0.102: v2(110.94,77.18) 110.31,77.82 109.28,77.82 109.11,77.64 108.76,77.64 108.71,77.6 CPU1.BA30
SATA_ODD_DA#: length 220.3
  L3 w0.127: v2(142.99,34.52) 143.02,34.52 143.76,33.77 143.76,33.63 144.48,32.91 144.48,31.28 144.84,30.93 144.84,14.22 149.65,9.4 151.76,9.4 151.97,9.61 159.98,9.61 160.85,8.74 162.94,8.74 163.42,8.26 164.51,8.26 166.16,6.61 168.47,6.61 169.36,7.5 171.08,7.5 v2(171.14,7.43)
  L4 w0.127: v2(142.99,34.52) 142.97,34.52 142.12,35.37 142.12,43 137.72,47.4 137.44,47.4 136.94,47.9 136.94,48.18 134.57,50.55 134.3,50.55 134.17,50.68 133.28,50.68 132.73,51.24 132.73,52.07 131.56,53.23 131.56,59.85 131.15,60.26 131.15,65.5 130.68,65.97 130.68,74.75 129.99,75.44 129.99,77.7 124.36,83.34 123.42,83.34 121.33,85.44 109.01,85.44 107.88,86.57 106.9,86.57 106.58,86.9 105.68,86.9 104.72,87.86 v2(104.72,88.92) ; v2(171.14,7.43) 172.09,7.43 178.28,13.63 178.28,22.68 182.56,26.95 182.6,26.95 185.14,29.49 185.14,33.35 187.65,35.86 187.65,41.85 187.49,42.02 187.49,49.65 187.31,49.83 187.31,62.39 195.1,70.17 195.1,70.18 195.16,70.24 195.16,78.59 194,79.75 v2(194,81.22)
  BOTTOM w0.127: R5602.2 194.57,81.59 RN5601.3 194.26,80.55 194,80.8 v2(194,81.22) ; v2(104.72,88.92) 104.29,89.35 CPU1.AN8 ; v2(142.99,34.52) v1(142.37,34.52)
SATA_ODD_DA#_C: length 8
  BOTTOM w0.127: R5602.1 196.48,82.62 196.48,84.79 v1(196.54,84.85) 197.23,85.54 199.56,85.54 ODD1.4
SATA_ODD_PRSNT#: length 215.8
  TOP w0.127: R5610.1 197.34,78.49 R5604.1 v2(198.19,79.19)
  L3 w0.127: v2(137.11,92.02) 137.61,92.02 141.87,87.76 141.87,79.76 140.85,78.74 140.85,55.88 146.49,50.25 146.49,47.6 152.4,41.69 152.4,41.63 152.8,41.22 152.8,39.62 154.71,37.71 154.71,37.05 154.84,36.93 154.84,33.01 154.95,32.9 154.95,30.69 159.54,26.11 163.35,26.11 163.37,26.09 163.93,26.09 163.95,26.11 164.59,26.11 164.65,26.17 171.59,26.17 172.32,26.9 174.96,26.9 175.39,26.47 176.1,26.47 178.9,23.68 179.42,23.15 190.73,23.15 v2(190.83,23.06)
  L4 w0.127: v2(198.19,79.19) 198.19,77.86 197.52,77.18 197.52,76.62 197.75,76.4 197.75,71.39 188.33,61.97 188.33,50.25 188.5,50.07 188.5,42.44 188.67,42.27 188.67,35.44 188.5,35.27 188.5,34.32 188.36,34.19 188.36,25.52 v2(190.83,23.06) ; v2(137.11,92.02) 133.61,95.51 133.61,96.02 130.18,99.46 123.77,99.46 123.57,99.26 114.62,99.26 114.11,98.75 111.5,98.75 v2(110.82,98.07)
  BOTTOM w0.127: v2(110.82,98.07) 110.82,97.21 108.42,94.81 107.71,94.81 106.95,94.05 CPU1.AV1 ; v2(198.19,79.19) 200.99,79.19 201.75,79.95 201.75,80.85 ODD1.1 ; v2(137.11,92.02) v1(137.11,92.68)
SATA_ODD_PWRGT: length 209.8
  TOP w0.127: v2(107.07,77.64) v1(107.92,77.64) 108.29,77.64 108.91,78.26 110.6,78.26 112.58,76.28 124.91,76.28 127.36,73.83 127.36,69.57 v2(126.64,68.85) ; U5601.4 195.49,74.07 195.78,74.36 v2(196.06,74.36)
  L3 w0.127: v2(170.89,6.8) 171.14,6.8 171.59,7.25 171.59,7.62 171.33,7.88 169.38,7.88 168.36,6.86 166.27,6.86 164.62,8.51 163.53,8.51 163.05,9 160.95,9 160.09,9.86 154.02,9.86 153.55,10.33 149.91,10.33 145.67,14.56 145.67,31.28 145.32,31.63 145.32,33.26 144.6,33.98 144.6,35.31 138.03,41.88 138.03,42.27 136.77,43.54 136.37,43.54 127.19,52.72 127.19,54.36 125.54,56.01 125.54,67.75 v2(126.64,68.85)
  L4 w0.127: v2(170.89,6.8) 171.81,6.8 178.53,13.52 178.53,22.57 182.66,26.7 182.71,26.7 185.39,29.38 185.39,33.24 187.91,35.76 187.91,41.96 187.74,42.12 187.74,49.76 187.56,49.94 187.56,62.28 196.06,70.78 v2(196.06,74.36)
  BOTTOM w0.127: v2(196.06,74.36) 196.58,74.88 196.58,79.53 195.56,80.55 RN5601.4 ; v2(107.07,77.64) 107.07,77.32 CPU1.AV31
SATA_PRX_HDDTX_N0: length 143.2
  L3 w0.102: v2(111.97,85.91) 111.94,85.91 111.49,85.46 111.08,85.05 110.79,85.05 110.65,84.91 110.18,84.91 109.82,84.55 109.62,84.55 109.24,84.17 109.24,83.81 109.67,83.38 124.76,83.38 130.1,78.04 130.1,66.08 130.53,65.64 130.53,53.28 140.51,43.3 140.51,42.9 147.8,35.61 147.8,32.65 148.15,32.3 148.15,15.77 151.18,12.74 164.69,12.74 165.3,12.13 183.7,12.13 184.28,11.55 184.61,11.55 v2(185.02,11.14)
  BOTTOM w0.102: v2(185.02,11.14) 184.81,11.36 184.81,11.67 184.94,11.8 186.08,11.8 186.5,11.38 ; v2(111.97,85.91) 111.21,85.16 108.88,85.16 108.73,85.3 CPU1.BA16 ; v1(186.38,11.27) 186.5,11.38 ; 186.5,11.38 186.64,11.24 187.17,11.24 C5616.1
SATA_PRX_HDDTX_P0: length 143
  L3 w0.102: v2(184.39,11.12) 183.6,11.9 165.21,11.9 164.59,12.52 151.08,12.52 147.92,15.68 147.92,32.21 147.57,32.56 147.57,35.52 140.28,42.81 140.28,43.2 130.3,53.19 130.3,65.55 129.87,65.98 129.87,77.94 124.66,83.15 109.58,83.15 109.01,83.72 109.01,84.26 109.53,84.78 109.72,84.78 110.08,85.14 110.56,85.14 v2(111.33,85.91)
  BOTTOM w0.102: 185.16,12.01 186.16,12.01 186.72,11.45 187.04,11.45 C5615.1 ; 185.16,12.01 v1(185.16,12.16) ; 185.16,12.01 184.86,12.01 184.6,11.75 184.6,11.34 v2(184.39,11.12) ; CPU1.AY16 108.12,85.3 108.42,85.6 108.72,85.6 108.96,85.36 110.77,85.36 v2(111.33,85.91)
SATA_PRX_ODDTX_N1: length 137.9
  L3 w0.102: v2(109.67,83.99) 110.35,84.67 111.02,84.67 111.52,85.17 111.94,85.17 112.25,85.47 113.67,85.47 114.67,86.47 118.1,86.47 118.78,87.15 121.02,87.15 121.99,86.17 124.06,86.17 124.67,86.17 124.75,86.1 128.34,86.1 131.54,89.3 131.54,94.56 130.86,95.24 130.86,98.11 134.77,102.02 135.3,102.02 136.85,103.57 139.59,103.57 140.36,102.81 142.76,102.81 143.07,102.51 149.6,102.51 150.44,101.67 150.44,101.15 v2(150.69,100.91)
  L4 w0.102: v2(150.69,100.91) 150.44,101.15 150.44,103.76 151.81,105.12 153.72,105.12 154.38,104.46 158.98,104.46 159.65,103.79 161.58,103.79 165.22,100.14 170.2,100.14 173.4,103.34 183.52,103.34 185.07,101.79 185.07,74.03 186.57,72.53 187.37,72.53 v2(187.6,72.31)
  BOTTOM w0.102: 191.18,71.15 189.23,71.15 188.08,72.31 v2(187.6,72.31) ; 191.18,71.15 191.82,71.15 C5607.2 ; 191.18,71.15 v1(191.18,70.98) ; v2(109.67,83.99) 109.67,84.14 109.42,84.4 108.79,84.4 108.43,84.75 CPU1.AY17
SATA_PRX_ODDTX_P1: length 137.9
  L3 w0.102: v2(149.93,100.91) 150.21,101.19 150.21,101.57 149.51,102.28 148.87,102.28 148.77,102.18 148.46,102.18 148.36,102.28 148.05,102.28 147.95,102.18 147.65,102.18 147.55,102.28 147.24,102.28 147.14,102.18 146.84,102.18 146.73,102.28 146.43,102.28 146.33,102.18 146.02,102.18 145.92,102.28 145.62,102.28 145.51,102.18 145.21,102.18 145.11,102.28 144.8,102.28 144.7,102.18 144.4,102.18 144.3,102.28 143.99,102.28 143.89,102.18 143.58,102.18 143.48,102.28 142.97,102.28 142.67,102.58 140.26,102.58 139.5,103.34 136.95,103.34 135.4,101.79 134.86,101.79 131.09,98.02 131.09,95.34 131.77,94.65 131.77,89.2 128.44,85.87 124.65,85.87 124.58,85.95 124.16,85.95 121.9,85.95 120.92,86.92 118.88,86.92 118.19,86.24 114.76,86.24 113.77,85.25 112.34,85.25 112.04,84.94 111.62,84.94 111.11,84.44 110.76,84.44 v2(110.31,83.99)
  L4 w0.102: v2(187.63,72.94) 187.45,72.76 186.66,72.76 185.3,74.13 185.3,101.88 183.61,103.57 173.31,103.57 170.11,100.37 165.31,100.37 161.67,104.01 159.75,104.01 159.07,104.69 154.47,104.69 153.81,105.35 151.71,105.35 150.21,103.85 150.21,101.19 v2(149.93,100.91)
  BOTTOM w0.102: C5608.2 191.82,71.35 189.76,71.35 ; v1(189.76,71.52) 189.76,71.35 ; 189.76,71.35 189.32,71.35 187.73,72.94 v2(187.63,72.94) ; CPU1.BA17 109.05,84.6 109.83,84.6 v2(110.31,83.99)
SATA_PTX_HDDRX_N0: length 143.4
  L3 w0.102: v2(184.99,9.72) 184.74,9.47 184.48,9.47 184.27,9.26 183.22,9.26 182.53,9.96 181.2,11.28 167.38,11.28 166.88,10.79 165.38,10.79 164.67,11.5 154.79,11.5 154.42,11.87 154.28,12.01 150.87,12.01 147.85,15.03 147.41,15.47 147.41,32 147.06,32.35 147.06,33.98 146.34,34.7 146.34,36.03 139.77,42.6 139.77,42.99 129.36,53.41 129.36,75.73 128.66,76.44 128.66,78.44 124.76,82.34 124.45,82.64 109.42,82.64 108.68,83.38 108.68,84.6 109.26,85.18 109.65,85.18 109.95,85.48 110.24,85.48 110.67,85.91 v2(110.7,85.91)
  BOTTOM w0.102: v2(110.7,85.91) 110,86.6 108.77,86.6 108.68,86.7 108.42,86.7 108.12,86.4 CPU1.AY14 ; 186.51,9.72 v2(184.99,9.72) ; 186.51,9.72 v1(186.51,9.9) ; 186.51,9.72 187.08,9.72 C5603.2
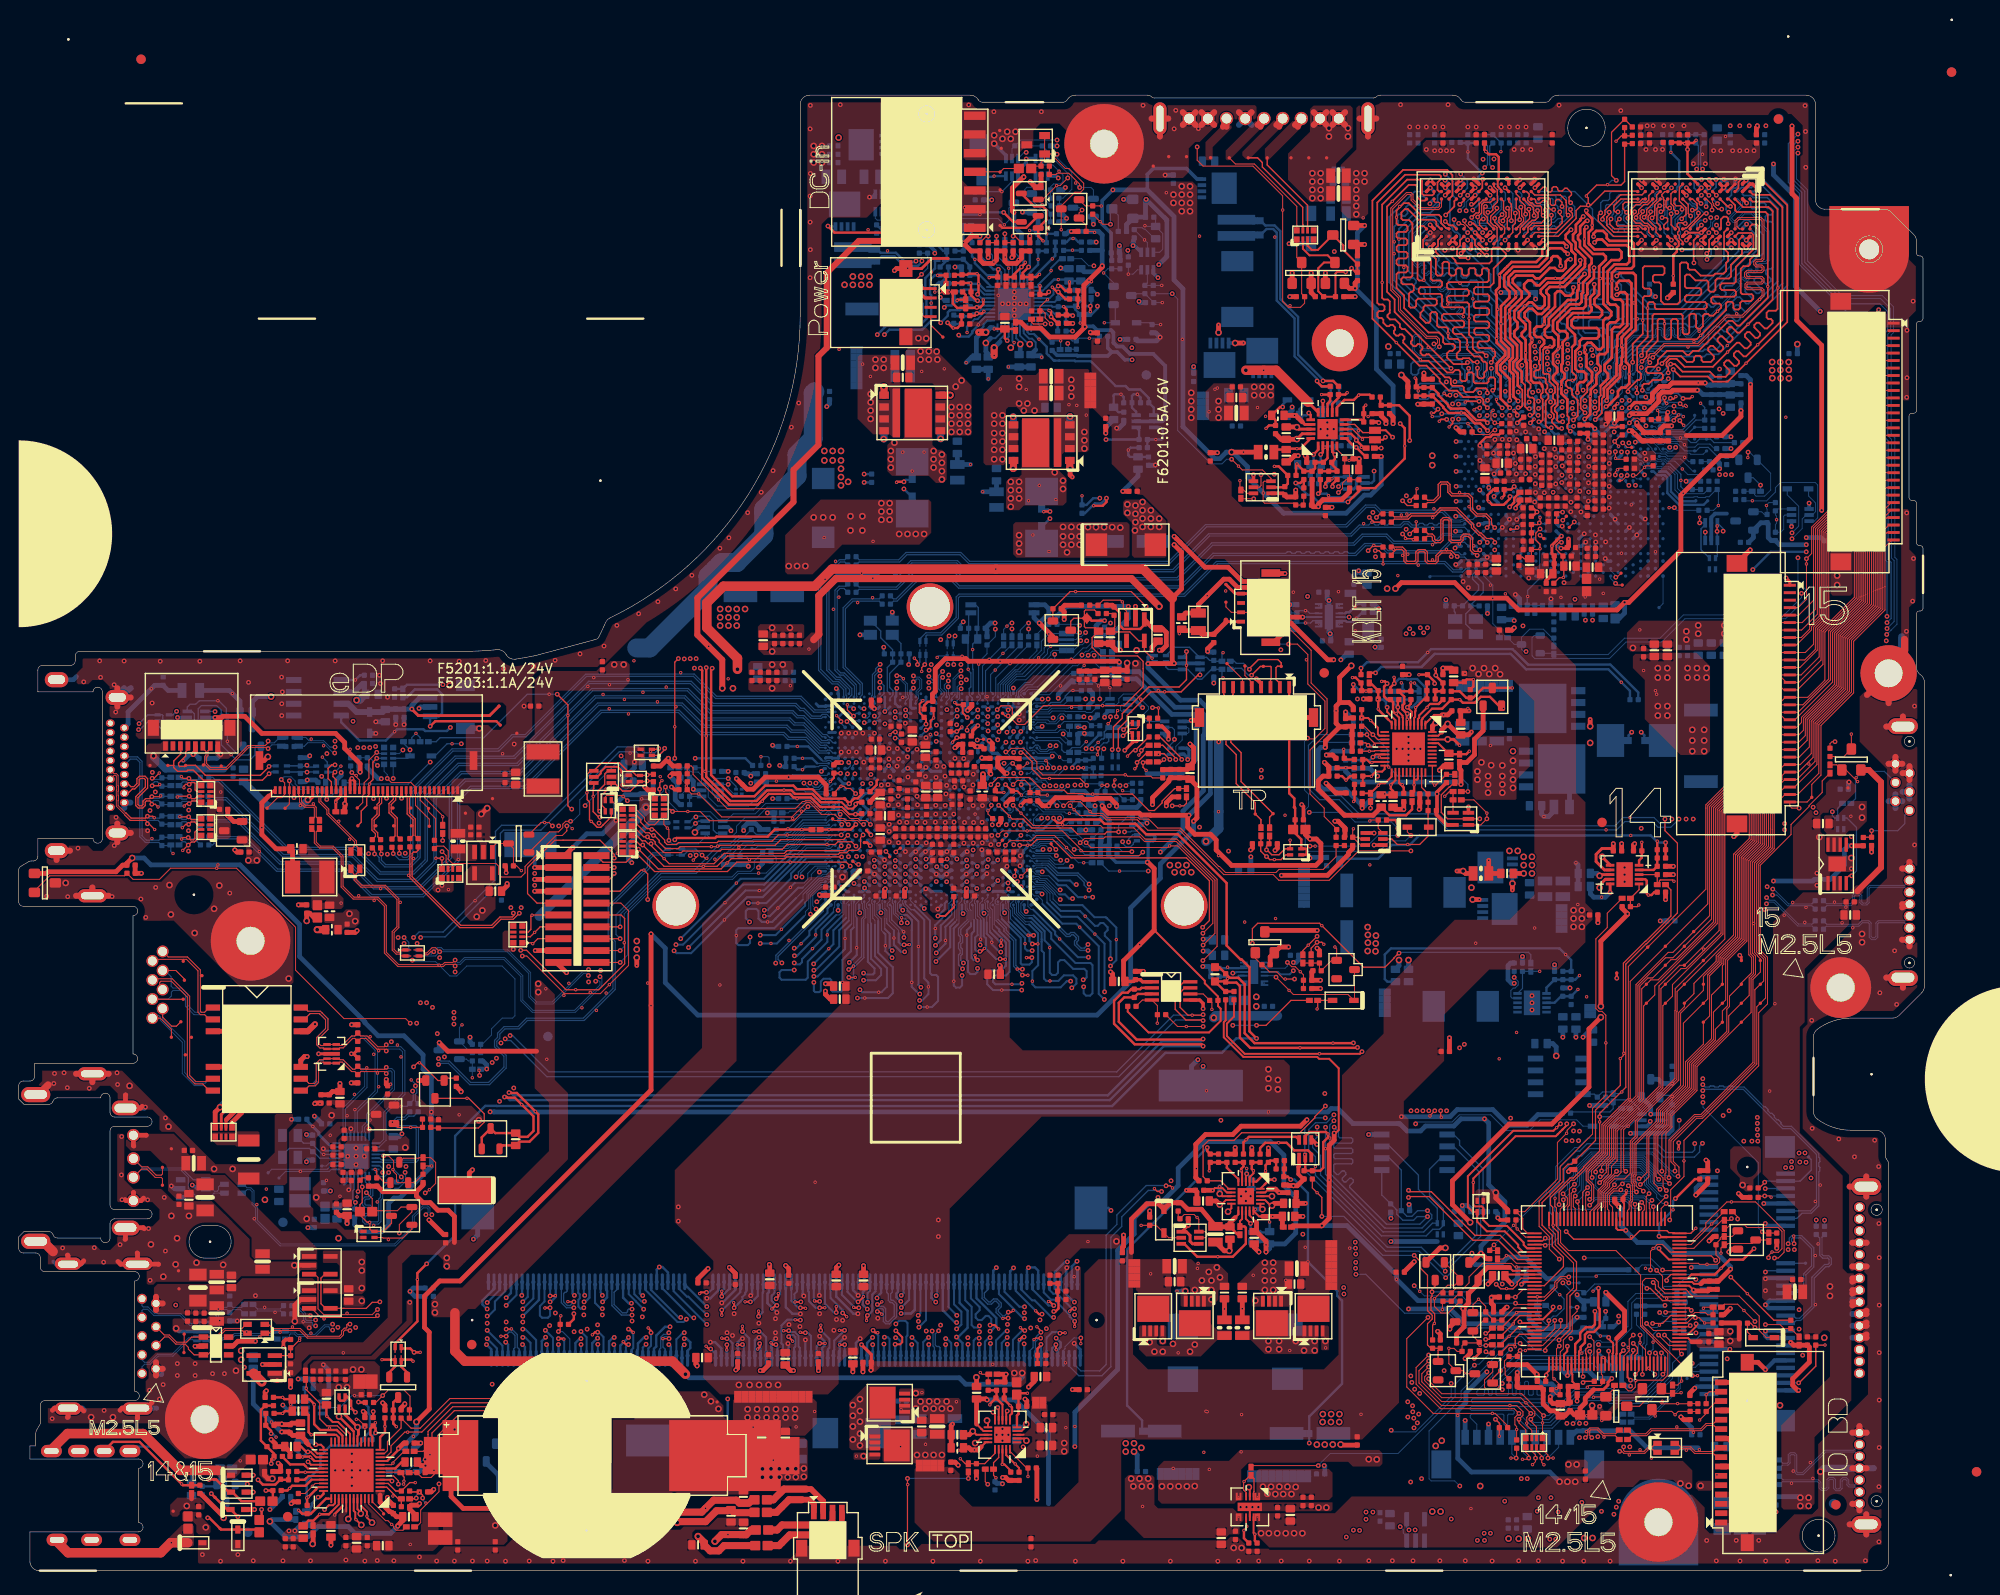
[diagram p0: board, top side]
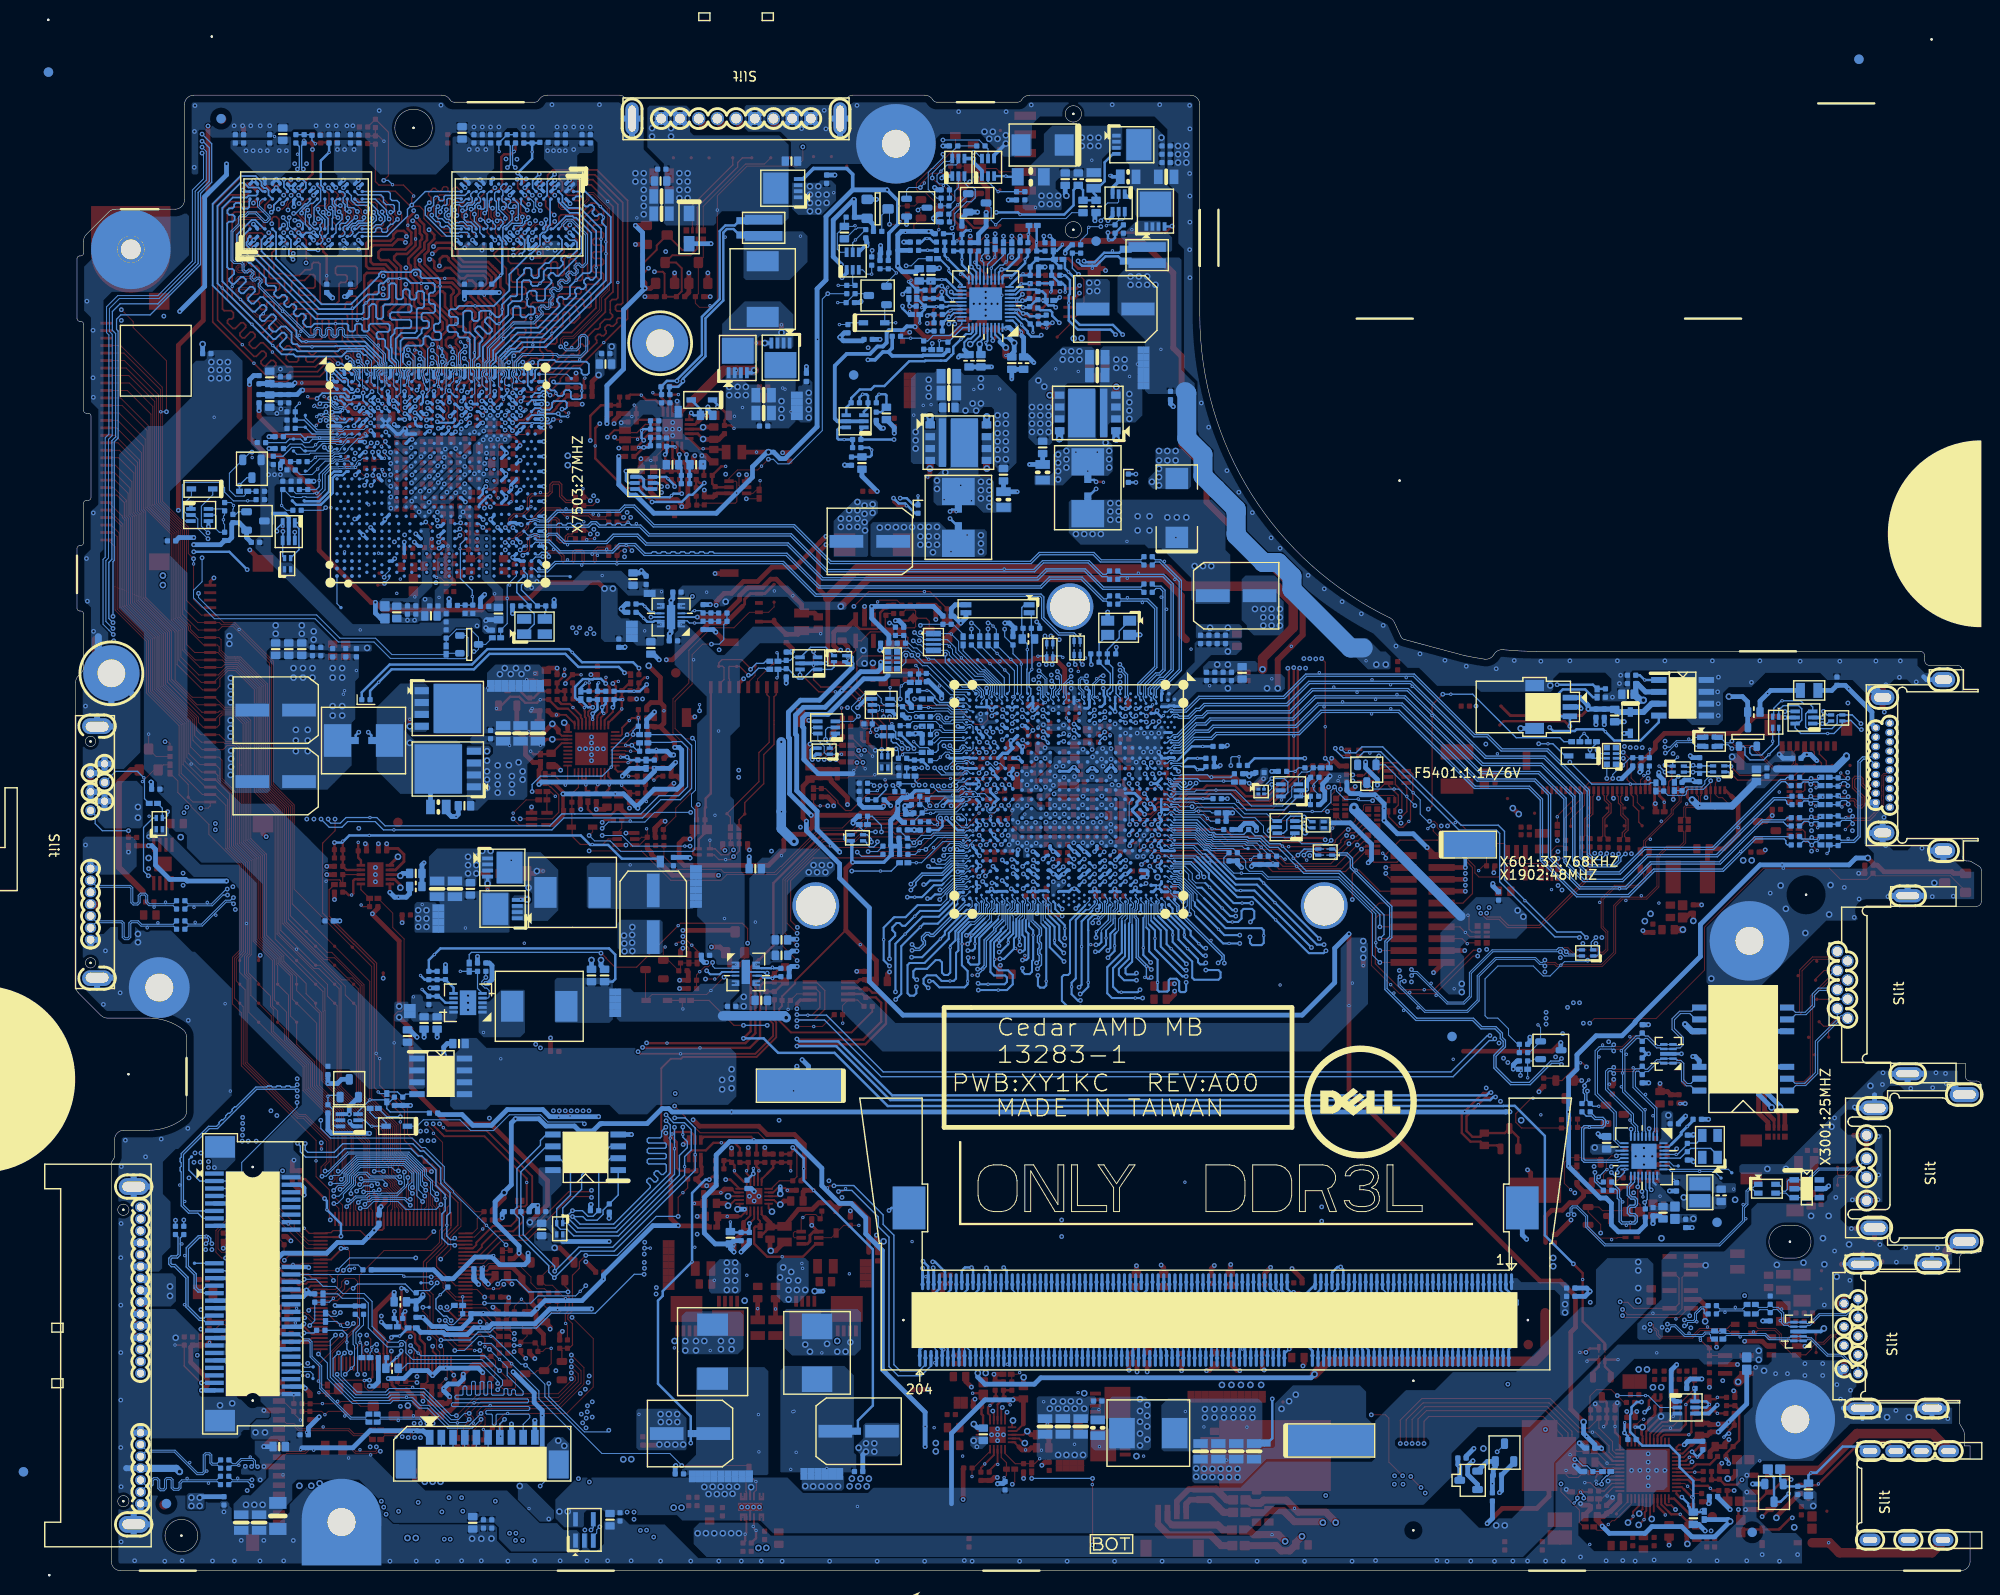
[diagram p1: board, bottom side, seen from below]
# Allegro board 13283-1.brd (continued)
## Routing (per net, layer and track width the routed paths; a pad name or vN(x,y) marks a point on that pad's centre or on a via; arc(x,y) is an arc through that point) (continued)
SATA_PTX_HDDRX_P0: length 144
  TOP w0.102: v1(109.88,86.68) 110.06,86.5 v2(110.06,85.91)
  L3 w0.102: v2(110.06,85.91) 109.55,85.41 109.17,85.41 108.46,84.7 108.46,83.28 109.32,82.41 124.36,82.41 128.43,78.34 128.43,76.34 129.13,75.64 129.13,53.31 139.55,42.9 139.55,42.5 146.11,35.94 146.11,34.61 146.83,33.88 146.83,32.25 147.19,31.9 147.19,15.37 147.32,15.24 150.78,11.78 154.19,11.78 154.7,11.27 155.21,11.27 155.36,11.12 155.61,11.12 155.76,11.27 156.02,11.27 156.17,11.12 156.42,11.12 156.58,11.27 156.83,11.27 156.98,11.12 157.24,11.12 157.39,11.27 157.64,11.27 157.8,11.12 158.05,11.12 158.2,11.27 158.46,11.27 158.61,11.12 158.86,11.12 159.02,11.27 159.27,11.27 159.42,11.12 159.68,11.12 159.83,11.27 160.08,11.27 160.23,11.12 160.49,11.12 160.64,11.27 160.9,11.27 161.05,11.12 161.3,11.12 161.45,11.27 161.71,11.27 161.86,11.12 162.11,11.12 162.27,11.27 162.52,11.27 162.67,11.12 162.93,11.12 163.08,11.27 163.33,11.27 163.49,11.12 163.74,11.12 163.89,11.27 164.57,11.27 165.28,10.56 166.98,10.56 167.47,11.05 181.11,11.05 183.13,9.03 184.37,9.03 184.58,9.24 184.83,9.24 v2(184.99,9.09)
  BOTTOM w0.102: C5602.2 187.16,9.52 185.42,9.52 v2(184.99,9.09) ; CPU1.BA14 109.57,86.4 v2(110.06,85.91)
SATA_PTX_ODDRX_N1: length 138.6
  L3 w0.102: v2(149.17,100.27) 149.02,100.13 149.02,99.54 148.76,99.28 148.25,99.28 148.15,99.18 147.84,99.18 147.74,99.28 147.44,99.28 147.34,99.18 147.03,99.18 146.93,99.28 146.63,99.28 146.52,99.18 146.22,99.18 146.12,99.28 144.12,99.28 142.35,101.06 139.55,101.06 138.03,102.58 137.23,102.58 135.7,101.06 135.23,101.06 133.14,98.98 133.14,98.47 133.25,98.37 133.25,98.06 133.14,97.96 133.14,97.65 133.25,97.55 133.25,97.25 133.14,97.15 133.14,96.84 133.25,96.74 133.25,96.44 133.14,96.33 133.14,96.03 133.25,95.93 133.25,95.62 133.14,95.52 133.14,95.22 133.25,95.11 133.25,94.81 133.14,94.71 133.14,94.4 133.25,94.3 133.25,94 133.14,93.9 133.14,93.59 133.25,93.49 133.25,93.18 133.14,93.08 133.14,92.78 133.25,92.68 133.25,92.37 133.14,92.27 133.14,91.97 133.25,91.86 133.25,91.56 133.14,91.46 133.14,91.15 133.25,91.05 133.25,90.75 133.14,90.64 133.14,89.53 128.74,85.13 124.35,85.13 124.27,85.21 114.77,85.21 114.07,84.51 112.65,84.51 112.21,84.08 v2(112.22,84)
  L4 w0.102: v2(186.97,72.03) 186.94,72.03 186.66,71.75 186.31,71.75 184.56,73.49 184.56,101.58 183.3,102.84 173.61,102.84 170.22,99.44 164.22,99.44 160.52,103.14 159.13,103.14 158.32,103.95 154.07,103.95 153.43,104.59 152.22,104.59 151.2,103.57 151.2,100.65 150.49,99.94 149.25,99.94 149.15,100.04 149.15,100.25 v2(149.17,100.27)
  BOTTOM w0.102: 191.06,69.19 190.38,69.19 187.83,71.75 187.27,71.75 186.99,72.03 v2(186.97,72.03) ; 191.06,69.19 191.82,69.19 C5611.2 ; 191.06,69.19 v1(191.06,69.38) ; v2(112.22,84) 111.57,83.35 109.41,83.35 109.12,83.65 CPU1.BA19
SATA_PTX_ODDRX_P1: length 138.7
  L3 w0.102: v2(111.58,83.97) 112.04,84.43 112.25,84.43 112.55,84.74 113.98,84.74 114.68,85.44 124.37,85.44 124.44,85.36 124.44,85.36 128.65,85.36 132.92,89.63 132.92,99.07 135.13,101.29 135.61,101.29 137.13,102.81 138.12,102.81 139.65,101.29 142.44,101.29 144.22,99.51 148.66,99.51 148.79,99.64 148.79,99.88 v2(148.4,100.27)
  L4 w0.102: v2(148.4,100.27) 148.96,99.71 150.59,99.71 151.43,100.55 151.43,103.47 152.31,104.36 153.34,104.36 153.97,103.73 158.22,103.73 159.03,102.91 160.43,102.91 164.13,99.21 170.31,99.21 173.71,102.61 183.21,102.61 184.33,101.48 184.33,73.4 186.21,71.52 186.8,71.52 v2(186.95,71.37)
  BOTTOM w0.102: C5612.2 191.82,68.99 190.3,68.99 188.99,70.29 ; 188.99,70.29 187.74,71.54 187.13,71.54 v2(186.95,71.37) ; 188.99,70.29 v1(188.85,70.15) ; v2(111.58,83.97) 111.16,83.56 109.5,83.56 109.1,83.95 108.73,83.95 108.43,83.65 CPU1.AY19
SATA_RXN0_R: length 12.9
  BOTTOM w0.102: HDD1.S5 196.44,12.69 193.29,12.69 190.88,10.28 190.22,10.28 189.99,10.51 189.99,10.66 ; v1(189.81,10.66) 189.99,10.66 ; 189.99,10.66 189.99,12.31 189.89,12.41 189.58,12.41 189.48,12.31 189.48,11.52 189.26,11.29 188.67,11.29 C5616.2
SATA_RXN2_R: length 13.1
  BOTTOM w0.102: ODD1.S5 201.72,73.13 198.06,73.13 197.94,73 197.94,71.48 197.69,71.24 197.2,71.24 196.95,71.48 196.95,72.18 196.82,72.31 196.47,72.31 196.34,72.18 196.34,71.49 196.02,71.17 195.45,71.17 ; 195.45,71.17 v1(195.45,71.01) ; 195.45,71.17 193.41,71.17 C5607.1
SATA_RXP0_R: length 13
  BOTTOM w0.102: 191.76,11.45 190.79,10.48 190.3,10.48 190.19,10.59 190.19,12.4 189.97,12.62 189.5,12.62 189.28,12.4 189.28,11.6 189.18,11.5 188.69,11.5 C5615.2 ; 191.76,11.45 193.21,12.9 196.29,12.9 HDD1.S6 ; 191.76,11.45 v1(191.64,11.57)
SATA_RXP2_R: length 13.1
  BOTTOM w0.102: ODD1.S6 201.71,73.33 197.98,73.33 197.73,73.09 197.73,71.57 197.61,71.44 197.28,71.44 197.15,71.57 197.15,72.26 196.91,72.51 196.38,72.51 196.14,72.26 196.14,71.58 195.93,71.37 194.23,71.37 ; 194.23,71.37 193.37,71.37 C5608.1 ; 194.23,71.37 v1(194.23,71.54)
SATA_TXN0_R: length 13.3
  BOTTOM w0.102: 191.92,9.72 188.73,9.72 C5603.1 ; 191.92,9.72 v1(191.92,9.87) ; 191.92,9.72 192.5,9.72 192.78,9.44 192.78,8.93 192.91,8.81 193.3,8.81 193.42,8.93 193.42,9.75 193.64,9.97 194.12,9.97 194.34,9.75 194.34,8.88 194.47,8.75 194.72,8.75 194.85,8.88 194.85,9.7 195.09,9.95 195.51,9.95 195.76,9.7 195.76,9.27 195.86,9.17 196.37,9.17 HDD1.S3
SATA_TXN2_R: length 13.1
  BOTTOM w0.102: 195.04,69.18 v1(195.04,69.33) ; 195.04,69.18 196.77,69.18 197.14,69.54 197.93,69.54 198.15,69.32 198.15,67.86 198.28,67.73 198.53,67.73 198.66,67.86 198.66,69.32 198.88,69.54 201.73,69.54 ODD1.S3 ; 195.04,69.18 193.41,69.18 C5611.1
SATA_TXP0_R: length 13.3
  BOTTOM w0.102: C5602.1 188.66,9.52 189.63,9.52 ; 189.63,9.52 192.42,9.52 192.58,9.36 192.58,8.85 192.82,8.6 193.38,8.6 193.63,8.85 193.63,9.67 193.73,9.77 194.03,9.77 194.14,9.67 194.14,8.8 194.38,8.55 194.8,8.55 195.05,8.8 195.05,9.62 195.18,9.75 195.43,9.75 195.56,9.62 195.56,9.18 195.78,8.96 196.36,8.96 HDD1.S2 ; 189.63,9.52 v1(189.63,9.36)
SATA_TXP2_R: length 13.1
  BOTTOM w0.102: C5612.1 193.37,68.97 196.19,68.97 ; ODD1.S2 201.7,69.34 198.96,69.34 198.86,69.24 198.86,67.78 198.61,67.53 198.19,67.53 197.94,67.78 197.94,69.24 197.84,69.34 197.22,69.34 196.85,68.97 196.19,68.97 ; 196.19,68.97 v1(196.19,68.8)
SATA_ZVDD_095: length 2.4
  TOP w0.203: v1(105.38,83.28) 104.66,83.28 R1904.2 104.47,83.84 v2(104.75,84.12)
  BOTTOM w0.203: CPU1.AP19 104.4,83.77 v2(104.75,84.12)
SATA_ZVSS: length 2.8
  TOP w0.203: v2(105.56,84.12) 106.23,83.44 R1903.2 106.82,83.44 v1(107.26,83)
  BOTTOM w0.203: CPU1.AR19 105.2,83.76 v2(105.56,84.12)
SLEEVE: length 17
  TOP w0.203: HDA27.18 35.83,14.91 35.81,14.93
  TOP w0.254: 35.81,14.93 35.63,15.11 35.63,15.13 v3(34.26,16.5)
  TOP w0.305: RN2901.3 34.27,16.51 v3(34.26,16.5)
  TOP w0.508: v3(27.12,9.85) 26.67,9.85 26.3,10.22 EC2906.1
  L3 w1.016: v3(27.12,9.85) 27.37,9.85 28.65,11.13 28.65,13.48 31.67,16.5 v3(34.26,16.5)
  vias: v1(33.25,15.26)
SLEEVE_CTRL: length 4.8
  BOTTOM w0.254: R2915.2 30.63,19.49 U2901.6 29.4,18.12 v1(29.08,17.8) 29.41,17.47 U2901.5
SLEEVE_R: length 20.4
  TOP w1.016: HPMIC1.4 3.5,12.95 5.22,14.67 13.29,14.67 17.23,10.74 21.39,10.74
  vias: v1(23.7,11.75)
SMB0_CLK: length 84.4
  TOP w0.14: v2(122.73,41.19) 123.19,41.19 v1(123.42,40.96)
  L3 w0.127: v2(118.72,77.98) 118.72,77.51 118.54,77.33 118.54,70.33 122.3,66.57 122.3,41.62 v2(122.73,41.19)
  L4 w0.127: v2(118.72,77.98) 118.72,78.09 118.29,78.52 117.16,78.52 115.45,80.23 112.79,80.23 112.13,79.57 109.06,79.57 107.89,80.75 106.66,80.75 105.74,79.82 v2(105.64,79.82)
  BOTTOM w0.14: v2(122.73,41.19) 122.71,41.22 120.61,41.22 117.47,38.07 117.47,37.05 116.32,35.91 116.32,22.05 115.65,21.38 113.62,21.38 112.95,22.05 DM1.202 ; v2(105.64,79.82) 106,80.19 CPU1.AU25 ; v2(118.72,77.98) 118.72,78.3 119.18,78.76 RN601.4
SMB0_DATA: length 84.4
  TOP w0.14: v1(121.49,40.89) 121.79,40.58 v2(122.25,40.58)
  L3 w0.127: v2(122.25,40.58) 121.79,41.04 121.79,66.36 118.03,70.12 118.03,77.55 118.08,77.59 v2(118.08,78.01)
  L4 w0.127: v2(118.08,78.01) 116.95,78.01 115.24,79.72 113,79.72 112.34,79.06 108.85,79.06 107.68,80.24 106.87,80.24 v2(106.44,79.81)
  BOTTOM w0.14: CPU1.AV25 106.8,80.17 v2(106.44,79.81) ; v2(118.08,78.01) 118.08,77.84 118.46,77.46 118.93,77.46 119.24,77.76 119.24,77.9 119.44,78.11 RN601.3 ; v2(122.25,40.58) 122.13,40.7 120.82,40.7 117.99,37.86 117.99,36.84 116.84,35.69 116.84,21.84 115.86,20.86 113.4,20.86 112.35,21.91 DM1.200
SMB1_CLK: length 26
  TOP w0.14: v2(126.36,95.86) 126.16,95.86 124.35,94.05 v1(122.58,94.05) 121.1,94.05 118.56,91.51 118.56,91.02 117.62,90.08 v2(117.62,87.87)
  L3 w0.127: v2(110.33,88.29) 110.33,88.19 111.53,86.99 116.81,86.99 117.3,87.48 117.32,87.48 117.62,87.78 v2(117.62,87.87)
  BOTTOM w0.102: v2(110.33,88.29) 109.9,87.86 109.36,87.86 109.24,87.98 109.24,88.13 109.03,88.35 108.75,88.35 108.45,88.05 CPU1.AY11
  BOTTOM w0.14: v2(117.62,87.87) RN603.2 ; Q6202.6 v2(126.36,95.86)
SMB1_DATA: length 26.2
  TOP w0.14: v2(116.97,87.87) 117.1,88 117.1,90.29 118.04,91.24 118.04,91.72 120.89,94.57 124.13,94.57 124.91,95.35 v1(124.91,96.89) v2(124.91,98.37)
  L3 w0.127: v2(110.96,88.28) 111.75,87.49 116.6,87.49 v2(116.97,87.87)
  BOTTOM w0.102: CPU1.BA11 108.9,88.03 109.28,87.66 110.02,87.66 110.22,87.86 110.55,87.86 v2(110.96,88.28)
  BOTTOM w0.14: v2(124.91,98.37) 124.91,98.18 Q6202.3 ; v2(116.97,87.87) RN603.1
SML1_CLK: length 346.6
  TOP w0.14: v2(62.15,81.27) 61.97,81.44 61.97,83.43 62.68,84.15 62.68,85.27 63.01,85.6 Q2601.3 ; KBC24.67 163.01,35.3 163.24,35.53 163.24,35.54 v2(163.29,35.58)
  L3 w0.127: v2(51.1,54.84) 51.32,54.63 51.32,53.07 48.4,50.14 48.4,48.54 45.15,45.29 45.15,36.85 41.35,33.05 41.35,25.8 49.45,17.7 66.47,17.7 73.02,11.14 76.99,11.14 79.19,8.93 81.38,6.75 97.2,6.75 97.41,6.55 127.91,6.55 128.16,6.79 128.97,6.79 129.93,7.76 133,7.76 133.1,7.65 138.27,7.65 138.42,7.8 140.69,7.8 141.7,6.8 144.32,6.8 v2(144.85,6.27)
  L4 w0.127: v2(179.28,45.71) 179.83,46.26 182.15,46.26 185.41,49.51 185.41,63.19 186.38,64.16 192.85,70.63 192.85,76.63 190.99,78.49 190.99,82.88 191.86,83.74 191.86,104.06 185.27,110.65 181.13,110.65 180.64,111.14 v2(180.41,111.14) ; v2(51.1,54.84) 51.3,54.84 57.48,61.02 57.48,77.11 58.84,78.46 59.04,78.46 61.84,81.27 v2(62.15,81.27) 62.17,81.24 64.99,81.24 65.11,81.13 68.63,81.13 69.1,80.66 72.42,80.66 72.42,80.66 v2(72.44,80.66) ; v2(144.85,6.27) 145.87,7.28 148.26,7.28 150.45,9.48 152.02,9.48 158.92,16.38 158.92,17.29 161.29,19.66 161.29,33.81 162.8,35.32 163.03,35.32 v2(163.29,35.58)
  BOTTOM w0.14: v2(163.29,35.58) 163.44,35.43 163.76,35.43 164.14,35.81 v1(164.14,36.97) 164.14,37.97 163.8,38.31 163.8,40.45 164.79,41.44 164.79,43.09 166.6,44.91 166.98,44.91 167.77,45.69 175.27,45.69 176.19,44.77 179.02,44.77 179.28,45.04 v2(179.28,45.71) ; v2(180.41,111.14) 180.4,111.13 Q7503.6 ; Q403.6 74.64,78.92 74.3,79.26 74.3,80.34 73.9,80.74 72.51,80.74 72.44,80.67 v2(72.44,80.66) 72.28,80.66 71.77,80.15 RN401.1
SML1_DATA: length 342.7
  TOP w0.14: v2(62.18,80.63) 62.1,80.71 61.97,80.71 61.45,81.23 v1(61.45,82.87) 61.45,83.65 61.51,83.71 Q2601.6 ; v2(163.29,34.82) 163.21,34.9 KBC24.68
  L3 w0.127: v2(50.65,54.38) 50.81,54.22 50.81,53.28 47.89,50.35 47.89,48.75 44.64,45.5 44.64,37.06 40.84,33.26 40.84,25.59 49.24,17.19 66.26,17.19 72.81,10.63 76.77,10.63 78.98,8.42 81.17,6.24 96.99,6.24 97.2,6.04 128.12,6.04 128.37,6.29 129.18,6.29 130.14,7.25 132.79,7.25 132.89,7.14 138.48,7.14 138.63,7.29 140.48,7.29 141.49,6.29 144.09,6.29 v2(144.12,6.27)
  L4 w0.127: v2(182.32,111.24) 182.41,111.15 185.48,111.15 192.36,104.27 192.36,83.53 191.5,82.67 191.5,78.7 193.36,76.84 193.36,70.42 186.6,63.66 185.91,62.97 185.91,49.3 182.36,45.75 180.12,45.75 v2(180.11,45.74) ; v2(144.12,6.27) 144.63,5.76 145.06,5.76 146.08,6.77 148.47,6.77 150.67,8.97 152.23,8.97 159.43,16.17 159.43,17.08 161.8,19.45 161.8,33.6 163.01,34.82 v2(163.29,34.82) ; v2(50.65,54.38) 50.69,54.33 51.2,54.33 51.52,54.33 57.99,60.8 57.99,76.9 59.05,77.96 59.25,77.96 61.93,80.63 v2(62.18,80.63) 62.28,80.74 64.78,80.74 64.89,80.62 68.42,80.62 68.89,80.15 72.21,80.15 v2(72.39,79.97)
  BOTTOM w0.14: Q403.3 72.74,80.22 72.55,80.04 72.54,80.04 72.47,79.97 v2(72.39,79.97) 71.92,79.5 RN401.2 ; v2(180.11,45.74) 179.8,45.43 179.8,44.82 179.23,44.25 175.97,44.25 175.05,45.17 167.98,45.17 167.2,44.38 166.82,44.38 165.31,42.88 165.31,41.23 164.32,40.24 164.32,38.53 164.66,38.18 164.66,35.6 163.98,34.91 163.39,34.91 v2(163.29,34.82) ; v2(182.32,111.24) 182.32,111.51 Q7503.3
SPI_CLK_R: length 104.2
  TOP w0.14: R2420.1 157.1,23.28 v2(156.94,23.44) ; v2(124.41,86.81) 124.41,86.89 122.08,89.22 R1925.2
  L3 w0.127: v2(156.94,23.44) 156.46,23.92 156.46,24.37 152.39,28.45 152.39,30.76 152.09,31.06 152.09,31.54 v2(152.6,32.05)
  L4 w0.127: v2(124.41,86.81) 125.05,86.17 125.93,86.17 133.93,78.17 133.93,63.33 134.88,62.37 134.88,55.92 138.76,52.05 138.76,51.38 139.58,50.55 140.12,50.55 140.69,49.98 v2(140.69,48.78)
  BOTTOM w0.14: SPI25.6 153.49,45.41 156.22,42.68 EC2503.1 156.22,38.13 155.96,37.87 155.96,35.95 152.6,32.59 152.6,32.05 v2(152.6,32.05) 150.03,34.61 146.4,34.61 138.71,42.31 v1(138.71,43.25) 138.71,44.31 137.99,45.03 137.99,47.21 138.72,47.94 139.89,47.94 140.21,48.27 140.21,48.31 140.69,48.78 v2(140.69,48.78)
SPI_CS0#_R: length 106.9
  TOP w0.14: R1908.2 122.25,86.56 v2(122.5,86.81) ; v2(156.94,24.1) 157.01,24.17 R2419.1
  L3 w0.127: v2(150.7,37.89) 151.97,36.62 151.97,33.87 153.53,32.31 153.53,29.72 157.36,25.89 157.36,24.53 v2(156.94,24.1)
  L4 w0.127: v2(122.5,86.81) 122.51,86.81 124.38,84.94 125.46,84.94 126.62,83.78 132.27,78.14 132.27,75.92 132.79,75.4 132.79,62.85 133.69,61.95 133.69,55.5 137.61,51.58 137.61,50.59 139.32,48.89 139.32,48.22 139.58,47.96 139.91,47.96 140.4,47.47 v2(140.71,47.47)
  BOTTOM w0.14: v2(140.71,47.47) 140.9,47.28 140.9,47.28 141.17,47.01 141.17,46.46 141.31,46.32 142.56,46.32 142.69,46.18 142.69,45.9 142.56,45.76 140.79,45.76 140.66,45.64 140.66,45.33 140.79,45.2 142.56,45.2 142.69,45.06 142.69,44.79 142.56,44.65 140.79,44.65 140.66,44.52 140.66,44.21 140.79,44.09 142.56,44.09 142.69,43.95 142.69,43.67 142.56,43.53 140.79,43.53 140.66,43.4 140.66,42.72 140.99,42.4 141.18,42.4 141.57,42.78 141.77,42.78 141.96,42.58 141.96,42.39 141.58,42 141.58,41.8 141.78,41.61 141.97,41.61 142.36,41.99 142.56,41.99 142.75,41.79 142.75,41.6 142.37,41.21 142.37,41.01 146.3,37.09 149.89,37.09 v2(150.7,37.89) 149.59,37.89 149.21,37.51 148.06,37.51 147.43,38.14 147.43,38.58 R2501.1 145.81,40.2 SPI25.1 ; v1(156.32,24.1) v2(156.94,24.1)
SPI_CS2#: length 1.4
  TOP w0.14: v2(105.84,91.47) 105.52,91.47 TP1904.1
  BOTTOM w0.14: v2(105.84,91.47) 105.56,91.75 CPU1.AR4
SPI_HOLD#: length 85.8
  TOP w0.14: v2(118.13,89.35) 118.17,89.35 118.93,90.11 119.58,90.11 119.78,90.31 RN1904.1
  L4 w0.127: v2(138.9,47.48) 138.56,47.81 138.56,48.57 136.85,50.28 136.85,51.26 132.93,55.18 132.93,56.81 132.93,61.64 132.03,62.54 132.03,66.26 131.52,66.77 131.52,75.1 130.83,75.79 130.83,78.5 126.45,82.88 125.15,84.18 123.96,84.18 120.53,87.61 120.53,87.96 119.14,89.35 v2(118.13,89.35)
  BOTTOM w0.14: v2(138.9,47.48) v1(138.9,46.68) 138.9,46.4 138.41,45.92 138.41,45.28 139.26,44.43 139.26,42.35 145.77,35.83 150.56,35.83 151.26,36.53 151.99,36.53 152.39,36.94 RN2501.2 152.39,38.74 150.91,40.22 150.91,42.96 152.09,44.14 SPI25.7 ; R1923.2 v2(118.13,89.35)
SPI_SI_R: length 103.2
  TOP w0.14: v2(123.14,86.81) 122.51,87.44 R1921.2 ; R2422.1 157.32,24.76 v2(156.92,24.76)
  L3 w0.127: v2(156.92,24.76) 156.61,24.76 152.77,28.6 152.77,31.22 v2(152.64,31.35)
  L4 w0.127: v2(139.76,48.46) 139.76,48.99 138,50.75 138,51.73 134.07,55.66 134.07,62.11 133.17,63.01 133.17,75.56 132.65,76.08 132.65,78.31 125.55,85.41 124.54,85.41 123.14,86.81 v2(123.14,86.81)
  BOTTOM w0.14: SPI25.5 153.49,46.68 154.12,46.04 154.12,45.52 156.64,43.01 156.64,38.89 EC2501.1 156.38,37.69 156.38,35.78 153.24,32.64 153.24,31.95 v2(152.64,31.35) 149.8,34.19 146.23,34.19 137.57,42.85 v1(137.57,44.52) 137.57,47.38 138.64,48.46 v2(139.76,48.46)
SPI_SO_R: length 97.3
  TOP w0.14: v2(156.92,25.39) 157.06,25.39 R2423.1 ; R1922.2 122.37,88.33 123.77,86.94 v2(123.77,86.81)
  L3 w0.127: v2(156.92,25.39) 155.37,26.94 154.96,26.94 153.15,28.76 153.15,32.15 151.45,33.85 151.45,34.68 150.56,35.57 150.56,37.09 150.25,37.39 150.25,38.08 150.7,38.52 v2(150.7,38.53)
  L4 w0.127: v2(140.69,48.15) 140.66,48.18 140.63,48.18 140.24,48.56 140.24,49.88 139.96,50.17 139.43,50.17 138.38,51.22 138.38,51.89 134.45,55.82 134.45,62.27 133.55,63.17 133.55,75.72 133.03,76.24 133.03,78.47 125.71,85.79 124.79,85.79 v2(123.77,86.81)
  BOTTOM w0.14: SPI25.2 146.63,44.14 147.89,42.88 EC2502.1 148.5,37.92 149.03,37.92 149.63,38.53 v2(150.7,38.53) 150.88,38.34 150.88,38.34 151.15,38.08 151.15,37.71 150.11,36.67 146.12,36.67 140.24,42.55 v1(140.24,46.3) 140.24,47.7 v2(140.69,48.15)
SPI_SW: length 15.6
  TOP w0.14: v2(117.17,84.02) 117.17,84.54 v1(117.26,84.63)
  L4 w0.127: v2(117.17,84.02) 116.61,84.57 108.85,84.57 108.51,84.92 106.84,84.92 v2(106.42,85.34)
  BOTTOM w0.14: v2(106.42,85.34) 106.8,84.96 CPU1.AV17 ; R1915.2 119.11,82.49 R1916.1 117.17,83.57 v2(117.17,84.02)
SPI_WP#: length 86
  TOP w0.14: v2(118.18,90) 118.89,90.71 RN1904.2
  L4 w0.127: v2(139.79,47.45) 139.55,47.45 138.94,48.06 138.94,48.73 137.23,50.44 137.23,51.42 133.31,55.34 133.31,56.65 133.31,61.79 132.41,62.7 132.41,74.75 131.21,75.95 131.21,78.65 126.52,83.35 125.31,84.56 124.12,84.56 120.91,87.77 120.91,88.12 119.03,90 v2(118.18,90)
  BOTTOM w0.14: v2(118.18,90) 117.95,90.24 R1924.2 ; v2(139.79,47.45) v1(139.79,45.15) 139.79,42.41 145.95,36.25 150.28,36.25 151.22,37.19 RN2501.1 151.74,38.8 149.72,40.81 149.72,42.34 146.65,45.41 SPI25.3
SPV10: length 14.2
  TOP w0.356: 174.5,125.06 174.44,125.01 172.87,125.01 v2(172.3,124.44)
  TOP w0.508: 174.5,125.06 174.75,125.32 174.75,125.95 175.49,126.69 175.49,126.69 175.54,126.74 176.49,126.74 176.87,127.11 v1(179.65,127.11) v2(180.39,127.11)
  BOTTOM w0.356: v2(172.3,124.44) 171.9,124.04 GPU1.H8
  BOTTOM w0.508: v2(180.39,127.11) 180.62,126.88 C7689.2 C7688.2 182.92,126.88 C7687.2 184.19,127.04 L7705.2
SPV18: length 14.2
  TOP w0.508: v2(172.28,123.64) 172.46,123.82 v1(173,123.82) 174.14,123.82 175.44,125.12 175.44,125.77 175.8,126.13 176.75,126.13 176.95,126.33 v2(179.56,126.33)
  BOTTOM w0.356: GPU1.H7 172.69,124.04 v2(172.28,123.64)
  BOTTOM w0.508: v2(179.56,126.33) 179.69,126.33 180.16,125.86 C7686.2 C7685.2 183.04,125.86 C7684.2 183.12,125.86 L7703.2
SYS_PWRGD: length 156.1
  TOP w0.127: v2(132.41,58.36) 133.42,58.36 136.09,61.03 R3627.2 ; v2(123.39,81.85) v1(124.2,81.85) 124.63,81.85 124.91,82.14 R611.1 ; v2(181.52,33.22) 181.04,33.7 KBC24.26
  L3 w0.127: v2(143,32.36) 143.02,32.36 143.48,31.9 143.48,30.87 143.83,30.51 143.83,11.73 144.74,10.82 146.42,10.82 148.56,8.68 153.18,8.68 153.57,8.28 157.13,8.28 157.97,9.12 159.67,9.12 160.54,8.26 162.74,8.26 163.68,7.32 165.03,7.32 166,6.35 v2(169.3,6.35)
  L4 w0.127: v2(143,32.36) 140.89,34.47 140.89,41.26 130.31,51.84 130.31,57.92 v2(129.87,58.36) 129.87,61.42 129.19,62.1 129.19,74.26 127.87,75.58 127.87,77.94 127.1,78.72 126.15,78.72 123.39,81.48 v2(123.39,81.85) ; v2(169.3,6.35) 169.3,7.3 171.09,9.09 171.9,9.09 175.97,13.15 175.97,16.43 176.77,17.24 176.77,22 176.67,22.1 176.67,23.68 178.68,25.7 179.01,25.7 179.29,25.98 179.61,25.98 179.87,26.24 179.87,26.57 181.52,28.22 v2(181.52,33.22)
  BOTTOM w0.127: v2(132.41,58.36) v2(129.87,58.36)
SYS_RESET#: length 8.2
  BOTTOM w0.102: CPU1.AY7 108.43,90.25 108.75,89.93 110.87,89.93 v1(111.3,90.35) 111.82,90.87 114.31,90.87 R1927.1 R1926.1
T_CRIT#: length 4.7
  TOP w0.102: v1(121.79,58.59) 121.8,58.6 R2601.1 121.8,60.47 THM26.4 120.19,61.07 R2604.2
TEMPINRETURN: length 4.9
  BOTTOM w0.102: CPU1.A23 86.12,81.27 85.98,81.27 85.84,81.13 84.16,81.13 84.01,81.28 v1(83.73,81.28) 82.5,81.28 82.31,81.09 R412.2
TESTEN: length 10.4
  BOTTOM w0.089: GPU1.K7 173.01,122.12 175.09,122.12 175.28,121.93 175.72,121.93 175.76,121.96 176.35,121.96 176.45,121.86 176.66,121.86
  BOTTOM w0.127: 176.66,121.86 178.13,121.86 179.4,123.13 R7311.1 R7332.2 180.35,124.49 v1(179.91,124.93)
THERM_SYS_SHDN#: length 87.9
  TOP w0.102: R2601.2 123.96,58.23 v1(124.89,58.23) v2(126.69,58.23) ; Q2602.S 157.67,21.29 156.79,20.41 156.79,19.63 156.92,19.5 158.16,19.5 v2(158.7,20.03)
  L3 w0.102: v2(146.81,15.03) 146.68,15.16 146.68,31.69 146.33,32.04 146.33,33.67 145.88,34.12 145.6,34.4 145.6,34.89 145.6,35.73 139.04,42.29 139.04,42.69 128.22,53.51 128.22,56.71 v2(126.69,58.23) ; v2(158.7,20.03) 153.24,20.03 153.23,20.03 v2(153.23,20.03)
  BOTTOM w0.102: R2607.2 168.86,21.66 168.33,22.19 160.56,22.19 158.7,20.33 v2(158.7,20.03) ; v2(146.81,15.03) 146.99,14.85 149.43,14.85 153.23,18.65 v2(153.23,20.03)
THM_SML1_CLK: length 141.4
  TOP w0.14: RN2601.4 63.39,80.68 62.49,79.78 62.49,79.78 62.26,79.55 61.89,79.55 61.26,80.18 v1(61.24,80.18) 61.06,80.36 61.06,82.26 60.81,82.51 60.81,85.23 61.14,85.56 61.48,85.56 Q2601.4 62.37,86.45 64.26,86.45 65.1,85.61 65.56,85.61 66.07,85.1 RN2602.4 67.18,85.1 v2(67.23,85.16) 67.3,85.22 C2608.1 ; THM26.8 124.65,63.02 123.71,62.09 123.71,60.07 124.86,58.93 126.64,58.93 v2(126.69,58.87)
  L4 w0.127: v2(67.23,85.16) 67.17,85.1 61.04,85.1 55.97,80.03 55.97,65.85 54.05,63.94 54.05,59.68 52.04,57.67 v2(52.04,56.91)
  BOTTOM w0.14: v2(126.69,58.87) 126.64,58.93 123.74,58.93 117.67,52.86 56.5,52.86 52.63,56.74 52.22,56.74 v2(52.04,56.91)
THM_SML1_DATA: length 129.9
  TOP w0.14: C2609.1 67.8,84.52 v2(67.23,84.52) 67.16,84.45 RN2602.3 66.45,84.45 65.43,83.44 64.58,83.44 63.72,84.3 Q2601.1 63.39,84.01 62.37,82.99 62.37,81.92 62.74,81.55 RN2601.3 ; v2(126.69,59.5) 126.64,59.45 v1(125.52,59.45) 125.07,59.45 124.23,60.29 124.23,61.87 124.73,62.37 THM26.7
  L4 w0.127: v2(52.57,57.27) 52.57,57.48 54.56,59.47 54.56,63.73 56.47,65.64 56.47,79.82 61.25,84.59 67.16,84.59 v2(67.23,84.52)
  BOTTOM w0.14: v2(52.57,57.27) 52.58,57.26 52.84,57.26 56.72,53.38 117.46,53.38 123.52,59.45 126.64,59.45 v2(126.69,59.5)
TOUCH_PANEL_INTR#: length 257.3
  TOP w0.127: D2401.A 184.92,25.55 R2443.1 185.27,26.48 v2(185.72,26.03)
  L3 w0.127: v2(179.41,25.44) 180.14,26.17 185.56,26.17 185.7,26.03 v2(185.72,26.03) ; v2(44.78,57.47) 45.98,56.27 45.98,53.85 45.48,53.34 45.48,49.63 42.58,46.74 42.58,41.93 42.31,41.66 41.79,41.15 41.79,39.9 41.44,39.55 41.44,38.35 41.12,38.03 41.12,38.03 37.86,34.77 37.86,28.52 37.63,28.3 37.63,26.53 38.39,25.76 38.39,22.7 40.88,20.21 42.4,20.21 47.75,14.86 57.33,14.86 59.56,12.63 64.59,12.63 69.9,7.32 76.46,7.32 80.35,3.43 95.73,3.43 96.06,3.1 128.81,3.1 129.43,3.72 131.33,3.72 132.13,2.93 146,2.93 146.25,3.18 154.42,3.18 154.99,3.75 156.28,3.75 v2(156.79,3.24)
  L4 w0.127: v2(156.79,3.24) 158.06,3.24 159.97,5.15 162.25,5.15 164.07,6.96 165.16,6.96 166.22,5.91 169.49,5.91 169.91,6.34 169.91,7.55 171.19,8.83 172.01,8.83 176.22,13.04 176.22,16.32 177.03,17.13 177.03,22.12 176.92,22.23 176.92,23.58 177.8,24.45 178.13,24.45 179.12,25.44 v2(179.41,25.44) ; v2(44.02,86.53) 45.8,84.75 45.8,71.79 45.51,71.51 45.51,58.21 v2(44.78,57.47)
  BOTTOM w0.127: R2411.1 178.34,25.44 v2(179.41,25.44) ; v2(44.02,86.53) 41.67,84.18 v1(37.54,84.18) 35.53,84.18 35.39,84.32 R5205.2
TOUCH_PANEL_INTR_KBC#: length 5.8
  TOP w0.127: v2(174.45,23.31) 174.49,23.26 KBC24.124
  BOTTOM w0.127: v2(174.45,23.31) 174.83,23.69 v1(174.83,24.45) 174.83,25.26 175.29,25.72 R2411.2
TP41: length 1.2
  TOP w0.102: v2(104.82,77.71) 105.23,78.13 TP421.1
  BOTTOM w0.102: CPU1.AP29 104.4,78.13 v2(104.82,77.71)
TP_RESET: length 9.9
  TOP w0.102: v2(28.09,84.67) 28.45,84.3 LCD1.38 28.45,83.07 28.11,82.73 27.69,82.73 AFTP5214.1
  BOTTOM w0.102: v2(28.09,84.67) 28.38,84.96 29.13,84.96 29.57,84.52 29.57,84.2 29.9,83.87 31.62,83.87 C5214.1 32.02,83.48 R2448.1
TP_RS: length 10
  TOP w0.102: AFTP5209.1 28.95,82.05 LCD1.37 v2(28.95,84.53)
  BOTTOM w0.102: v2(28.95,84.53) 28.95,84.4 29.73,83.62 31.33,83.62 31.56,83.39 31.56,83.13 31.72,82.97 33.52,82.97 C5208.1 33.98,83.43 R5205.1
TP_SMB1_CLK: length 8.6
  BOTTOM w0.14: RN6201.2 122.72,96.7 122.97,96.45 Q6202.1 125.06,96.45 126.09,95.41 126.55,95.41 127.65,96.51 127.65,96.52 127.65,96.52 EC6207.1 127.9,96.46 R6212.1 128.71,95.66 v1(128.83,95.55)
TP_SMB1_CLK_R: length 7.3
  TOP w0.14: v2(131.87,95.83) 132.82,96.77 AFTP6237.1 133.9,96.77 133.97,96.7 133.97,95.47 133.9,95.4 TPAD1.3
  BOTTOM w0.14: v2(131.87,95.83) 131.55,95.83 130.8,96.58 130.14,96.58 130.02,96.46 R6212.2
TP_SMB1_DATA: length 7.9
  BOTTOM w0.14: v1(128.83,98.24) 128.71,98.12 R6213.1 127.92,97.32 EC6206.1 127.39,97.41 127.06,97.75 Q6202.4 126.3,97.75 125.23,98.82 123.61,98.82 RN6201.1
TP_SMB1_DATA_R: length 9.7
  TOP w0.14: TPAD1.2 134.9,94.96 134.49,95.37 134.49,96.64 134.64,96.79 135.03,96.79 AFTP6240.1 135.05,97.15 134.69,97.5 132.6,97.5 131.65,96.55 v2(131.65,96.46)
  BOTTOM w0.14: R6213.2 130.02,97.32 130.25,97.1 131.01,97.1 v2(131.65,96.46)
TP_VDD: length 19.7
  TOP w0.254: RN6203.1 137.66,76.6 137.78,76.73 137.78,77.16 137.69,77.25 RN6203.2 137.2,78.26 136.32,79.14 R6209.2 136.54,79.53 C6202.1 136.54,81.61 AFTP6239.1 136.45,82.64 135.9,83.19 TPAD1.1
TP_WAKE: length 3.2
  TOP w0.102: TPAD1.6 130.9,95.42 AFTP6242.1
TPAN_VDD: length 12.2
  TOP w0.305: LCD1.40 27.37,83.53 26.76,82.91
  TOP w0.508: 26.76,82.91 26.01,82.16 v1(26.01,79.52) 26.01,78.78 27.54,77.25 R5232.1 29.29,77.06 F5203.2
TPAN_VDD_F:
  vias: v1(34.49,71.44)
TPCLK: length 65
  TOP w0.14: R6210.1 132.88,77.82 EC6205.1 132.85,77.02 133.45,76.42 v2(133.47,76.42) 133.5,76.42 133.82,76.1 v1(134.31,76.1) 135.03,76.1 135.54,76.6 RN6203.4 ; v2(148.66,39.95) 148.75,40.03 150.89,40.03 155.56,35.36 158.26,35.36 160.33,33.3 KBC24.72
  L3 w0.127: v2(148.66,39.95) 148.41,40.2 147.59,40.2 142.33,45.47 142.33,49.59 134.12,57.79 134.12,62.54 133.79,62.87 133.39,63.27 133.39,76.12 133.47,76.21 v2(133.47,76.42)
TPCLK_C: length 16.7
  TOP w0.14: R6210.2 132.88,80.37 AFTP6238.1 132.27,82.19 130.24,84.22 130.24,87.33 129.14,88.43 129.14,90.53 129.14,93.51 128.9,93.75 TPAD1.8
TPDATA: length 65.2
  TOP w0.14: v2(148.66,40.71) 148.82,40.56 151.1,40.56 155.78,35.88 158.48,35.88 160.66,33.7 KBC24.71 ; R6211.1 133.8,77.86 EC6208.1 133.47,77.53 v2(133.47,77.13) 133.52,77.13 134.04,76.62 134.81,76.62 135.45,77.25 RN6203.3 v1(136,78.17)
  L3 w0.127: v2(133.47,77.13) 133.68,76.93 133.69,76.93 133.98,76.63 133.98,76.21 133.98,76.21 133.98,75.79 133.89,75.7 133.89,63.49 134,63.38 134.63,62.75 134.63,58 142.83,49.8 142.83,45.68 147.81,40.71 v2(148.66,40.71)
TPDATA_C: length 17.2
  TOP w0.14: R6211.2 133.8,80.64 AFTP6236.1 130.76,84.44 130.76,87.55 129.66,88.64 129.66,93.51 129.9,93.75 TPAD1.7
TPS51216_PHS_SET:
  vias: v1(94.38,17.24)
TS_A: length 1.3
  TOP w0.127: TP7522.1 163.09,110.46 v2(162.74,110.81)
  BOTTOM w0.127: v2(162.74,110.81) 163.11,110.44 GPU1.AE19
TSVDD: length 6.8
  TOP w0.305: C7515.1 164.01,108.84 v1(164.01,109.64) 164.01,109.74 164.51,110.25 164.51,110.26 164.96,110.71 v2(165.02,110.71)
  TOP w0.381: C7515.1 C7521.1 164.25,106.84 C7582.1 163.4,105.99 L7504.2
  BOTTOM w0.356: v2(165.02,110.71) 164.44,111.24 GPU1.AD17
TX_PWRS_ENB: length 3.5
  TOP w0.102: R7301.1 174.08,118.24 v1(173.91,118.08) 173.05,117.21 v2(172.69,117.21)
  BOTTOM w0.102: GPU1.U6 173.07,116.84 v2(172.69,117.21)
USB3_PRX_CTX_N0: length 129.8
  L4 w0.102: v2(33.58,25.75) 33.58,25.79 33.37,26 33.1,26 32.81,26.29 32.81,26.7 33.22,27.11 33.22,32.99 36.24,36 38.18,36 40.73,38.55 40.73,40.05 42.77,42.09 42.77,46.9 44.8,48.93 44.8,49.69 48.51,53.4 48.51,55.35 51.98,58.82 51.98,59.33 51.98,59.33 51.98,71.6 52.69,72.31 52.69,80.13 52.78,80.22 63.51,90.96 84.32,90.96 87.55,87.72 87.55,87.42 87.8,87.16 90.11,87.16 90.12,87.18 91.35,87.18 92.81,88.64 93.91,88.64 95.3,90.03 95.3,92.11 96.14,92.95 96.14,95.22 96.01,95.34 95.83,95.34 95.7,95.22 v2(95.7,95.12)
  BOTTOM w0.102: 30.07,25.06 v1(30.07,24.89) ; 30.07,25.06 29.76,25.06 29.49,25.33 29.07,25.33 28.97,25.23 28.97,24.91 28.85,24.79 R3411.2 ; 30.07,25.06 31.75,25.06 32.79,26.1 33.17,26.1 33.24,26.03 33.24,25.84 33.33,25.75 v2(33.58,25.75) ; CPU1.V1 95.99,93.54 95.99,94.11 96.38,94.5 96.38,95.28 96.24,95.42 96.05,95.42 95.97,95.34 95.97,95.2 95.9,95.12 v2(95.7,95.12)
USB3_PRX_CTX_N0_C: length 17
  BOTTOM w0.102: USB1.5 13.19,21.81 13.47,22.1 14.06,22.1 14.93,22.96 16.5,22.96 18.25,24.72 18.61,24.72 18.74,24.6 U3402.1 U3402.10 20.38,24.6 20.5,24.71 22.69,24.71 23.15,25.17 25.8,25.17 ; v1(25.8,25.02) 25.8,25.17 ; 25.8,25.17 27.26,25.17 R3411.1
USB3_PRX_CTX_P0: length 130
  L4 w0.102: v2(95.7,95.76) 95.89,95.57 96.1,95.57 96.37,95.31 96.37,92.85 95.53,92.02 95.53,89.94 94,88.41 92.91,88.41 91.45,86.95 90.22,86.95 90.2,86.94 87.71,86.94 87.32,87.32 87.32,87.63 84.22,90.73 63.61,90.73 53.01,80.13 53.01,80.13 52.92,80.04 52.92,72.22 52.21,71.51 52.21,59.42 52.21,58.72 48.74,55.25 48.74,53.31 45.03,49.6 45.03,48.84 43,46.8 43,41.99 40.96,39.95 40.96,38.46 38.28,35.77 36.33,35.77 33.45,32.89 33.45,27.01 33.04,26.6 33.04,26.39 33.2,26.23 33.42,26.23 v2(33.58,26.38)
  BOTTOM w0.102: 31.27,25.27 v1(31.26,25.42) ; 31.27,25.27 31.67,25.27 32.71,26.31 33.5,26.31 v2(33.58,26.38) ; 31.27,25.27 29.84,25.27 29.57,25.54 28.65,25.54 R3410.2 ; CPU1.V2 95.95,93.07 96.25,93.37 96.25,93.66 96.2,93.71 96.2,94.02 96.59,94.41 96.59,95.36 96.33,95.62 95.84,95.62 v2(95.7,95.76)
USB3_PRX_CTX_P0_C: length 16.8
  BOTTOM w0.102: 24.38,25.38 27.37,25.38 R3410.1 ; 24.38,25.38 v1(24.38,25.54) ; 24.38,25.38 23.06,25.38 22.6,24.92 20.52,24.92 20.37,25.07 U3402.9 U3402.2 18.76,25.07 18.61,24.93 18.17,24.93 16.41,23.17 14.85,23.17 13.98,22.3 13.45,22.3 13.19,22.56 USB1.6
USB3_PTX_CRX_N0: length 125
  L4 w0.102: v2(93.93,95.11) 93.93,95.22 93.77,95.37 93.5,95.37 93.31,95.18 93.31,90.9 93.32,90.89 93.32,90.34 91.94,88.97 87.71,88.97 84.26,92.42 63.61,92.42 63.61,92.42 62.91,92.42 50.52,80.03 50.52,60.93 48.7,59.12 48.7,58.23 47.26,56.79 47.26,56.79 47.05,56.58 47.05,54.01 40.31,47.26 40.31,41.7 36.28,37.68 35.01,37.68 32.35,35.02 32.35,27.1 32.19,26.94 32.19,26.63 v2(31.76,26.2)
  BOTTOM w0.102: C3403.1 29.54,27.47 29.65,27.58 29.65,27.94 29.73,28.02 29.92,28.02 30.46,27.48 30.46,26.83 30.54,26.75 ; 30.54,26.75 30.73,26.57 31.37,26.57 31.44,26.49 31.44,26.29 31.54,26.2 v2(31.76,26.2) ; 30.54,26.75 v1(30.43,26.64) ; v2(93.93,95.11) 93.93,95.22 94.08,95.37 94.3,95.37 94.85,94.82 CPU1.T1
USB3_PTX_CRX_N0_C: length 14.5
  BOTTOM w0.102: 21.38,26.76 21.38,26.52 21.11,26.26 20.68,26.26 20.54,26.12 U3402.7 U3402.4 18.73,26.12 18.62,26.23 18.33,26.23 17.26,27.3 14.47,27.3 13.79,27.98 13.32,27.98 13.19,27.85 USB1.8 ; 21.38,26.76 v1(21.51,26.76) ; 21.38,26.76 21.38,27.5 21.82,27.94 22.25,27.94 C3402.1 22.9,27.93 23.71,27.93 R3409.1
USB3_PTX_CRX_N0_R: length 3.7
  BOTTOM w0.102: R3409.2 25.38,27.8 27.42,27.8 ; 27.42,27.8 v1(27.42,27.65) ; 27.42,27.8 28.01,27.8 C3403.2
USB3_PTX_CRX_P0: length 125.7
  TOP w0.102: v2(93.93,95.78) 94.32,95.78 v1(94.64,95.46)
  L4 w0.102: v2(93.93,95.78) 93.75,95.6 93.4,95.6 93.08,95.28 93.08,90.8 93.09,90.8 93.09,90.44 91.85,89.2 87.8,89.2 84.36,92.64 63.7,92.64 62.81,92.64 50.29,80.12 50.29,61.03 48.47,59.21 48.47,58.32 47.17,57.01 46.82,56.67 46.82,54.1 40.08,47.36 40.08,41.79 36.19,37.91 34.92,37.91 32.12,35.11 32.12,27.2 v2(31.76,26.83)
  BOTTOM w0.102: CPU1.T2 94.85,93.07 95.15,93.37 95.15,93.67 95.05,93.77 95.05,94.9 94.18,95.78 v2(93.93,95.78) ; C3404.1 29.36,28.22 30,28.22 30.67,27.56 30.67,26.91 30.81,26.77 31.69,26.77 v2(31.76,26.83)
USB3_PTX_CRX_P0_C: length 14.4
  BOTTOM w0.102: 21.45,27.91 21.72,28.18 22.25,28.18 C3401.1 22.91,28.17 23.85,28.17 R3408.1 ; 21.45,27.91 v1(21.36,28) ; 21.45,27.91 21.14,27.6 21.14,26.63 21.01,26.5 20.7,26.5 20.6,26.6 U3402.6 U3402.5 18.78,26.6 18.62,26.43 18.41,26.43 17.35,27.5 14.55,27.5 13.83,28.22 13.32,28.22 13.19,28.35 USB1.9
USB3_PTX_CRX_P0_R: length 3.8
  BOTTOM w0.102: R3408.2 25.54,28 26.31,28 ; 26.31,28 27.97,28 28.33,28.36 C3404.2 ; 26.31,28 v1(26.31,28.19)
USB20_VCCA: length 3.7
  TOP w0.508: 13.64,46.6 13.64,46.6 USB2.1 12.27,45.48 12.32,45.43
  BOTTOM w0.508: v2(16.33,41.17) 16.69,40.87 U3401.5
USB20_VCCB:
  vias: v1(174.65,12.06) v1(181.66,10.25) v3(183.84,7.05) v3(184.73,7.05) v3(185.62,7.05)
USB30_VCCC: length 10.1
  TOP w0.508: U3403.5 22.93,24.05 23.44,24.55 v2(25.32,24.55)
  TOP w0.635: USB1.1 15.4,28.6 ; USB1.1 14.69,27.89 ; USB1.1 14.69,29.31
  L3 w0.508: v2(25.32,24.55) v2(25.32,29.43)
USB_ATEST0: length 1.4
  TOP w0.102: TP416.1 102.61,88.97 v2(102.54,88.89)
  BOTTOM w0.102: CPU1.AJ10 102.2,88.55 v2(102.54,88.89)
USB_ATEST1: length 1.9
  TOP w0.102: v2(101.45,89.93) 101.45,90.31 TP417.1
  BOTTOM w0.102: CPU1.AJ8 101.45,89.9 v2(101.45,89.93)
USB_CAMERA: length 12.5
  TOP w0.102: 21.66,85.95 20.53,85.95 20.1,86.38 20.1,87.07 20.24,87.21 20.24,87.75 20.5,88.01 CCD1.7 ; 21.66,85.95 AFTP5226.1 ; 21.66,85.95 22.17,85.95 24.53,88.31 26.39,88.31 26.68,88.61 v2(26.68,88.78)
  BOTTOM w0.102: R5221.1 28.54,89.18 TR5208.2 27.92,89.18 27.33,88.59 26.87,88.59 v2(26.68,88.78)
USB_CAMERA#: length 12.5
  TOP w0.102: v2(26.68,87.97) 26.54,88.11 24.62,88.11 22.26,85.75 20.44,85.75 19.9,86.29 ; 19.9,86.29 19.83,86.29 AFTP5225.1 ; 19.9,86.29 19.9,87.15 20.04,87.29 20.04,87.67 19.7,88.01 CCD1.6
  BOTTOM w0.102: R5219.1 28.54,88.23 TR5208.3 27.94,88.38 27.09,88.38 v2(26.68,87.97)
USB_CAMERA_EDP: length 8.5
  TOP w0.102: TR5209.2 35.54,77.19 35.92,77.57 35.92,78.01 35.53,78.4 ; 35.53,78.4 v1(35.41,78.27) ; 35.53,78.4 32.97,80.96 32.97,81.42 32.12,82.27 32.12,82.79 31.95,82.95 LCD1.31
USB_CAMERA_EDP#: length 8.5
  TOP w0.102: 34.12,80.09 36.12,78.09 36.12,77.56 36.48,77.2 TR5209.3 ; 34.12,80.09 33.17,81.04 33.17,81.5 32.32,82.35 32.32,82.83 32.45,82.96 LCD1.30 ; 34.12,80.09 v1(34.24,80.21)
USB_OC#0: length 487.7
  TOP w0.102: 35.13,27.4 37.82,27.4 v2(38.38,27.96) ; 35.13,27.4 32.64,27.4 32.01,28.02 32.01,31.37 31.66,31.73 U3503.3 ; 35.13,27.4 v1(35.13,27.55)
  L3 w0.102: v2(199.77,99.51) 196.45,102.82 196.45,134.8 191.39,139.87 191.39,149.09 190.1,150.37 190.1,151.29 189.28,152.11 189.28,152.7 187.93,154.04 187.93,154.95 187.29,155.59 173.2,155.59 168.83,151.22 166.47,151.22 166.25,151.44 162.76,154.93 148.61,154.93 145.39,151.71 142.18,151.71 140.92,150.44 140.92,141.79 141.16,141.55 141.16,138.79 139.15,136.78 139.01,136.64 139.01,130.32 144.21,125.12 144.75,124.58 144.75,122.44 145.18,122.01 145.18,121.15 145.49,120.85 145.74,120.85 146.17,120.41 146.17,116.06 139.84,109.72 131.75,109.72 131.72,109.69 131.7,109.69 122.53,100.53 117.84,100.53 117.25,99.94 117.02,99.94 v2(115.03,97.96) 115.03,97.95 114.6,97.52 114.6,95.16 112.98,93.53 112.98,93.46 112.7,93.18 111.59,92.07 v2(111.59,91.25)
  L4 w0.102: v2(199.77,99.51) 197.52,97.26 197.52,94.99 197.9,94.61 197.9,85.84 199.38,84.37 199.38,81.01 200.18,80.21 200.18,69.06 196.47,65.36 194.33,65.36 190.13,61.16 190.13,50.98 190.29,50.82 190.29,46.63 191.81,45.11 191.81,43.44 190.98,42.61 190.98,31.56 191.26,31.28 191.26,19.4 186.9,15.04 186.9,7.32 184.35,4.77 182.95,4.77 180.08,1.9 153.32,1.9 129.64,1.9 129.21,2.33 77.09,2.33 70.28,9.14 66.9,9.14 66.08,8.31 62.03,8.31 60.38,9.97 59.13,9.97 58.17,9.01 53.13,9.01 52.42,9.72 47.11,9.72 45.04,11.79 45.04,17.55 40.51,22.09 40.51,23.58 38.81,25.28 38.81,27.53 v2(38.38,27.96)
  BOTTOM w0.102: CPU1.AY8 107.85,90.33 108.07,90.55 108.37,90.55 108.42,90.5 108.68,90.5 108.97,90.79 109.84,90.79 110,90.63 110.97,90.63 v2(111.59,91.25) ; RN604.5 115.73,96.53 115.03,97.22 v2(115.03,97.96)
USB_OC#1: length 486.2
  TOP w0.102: v1(32.66,26.94) 32.66,27.09 ; 32.66,27.09 38.17,27.09 v2(38.38,27.3) ; 32.66,27.09 32.31,27.09 31.33,28.07 U3504.3
  L3 w0.102: v2(113.74,97.99) 113.87,98.11 113.93,98.11 116.37,100.55 117,100.55 117.61,101.16 122.3,101.16 131.44,110.3 131.47,110.3 131.49,110.33 132,110.33 139.59,110.33 145.49,116.23 145.49,117.92 144.49,118.93 144.49,121.26 144.14,121.6 144.14,124.33 143.96,124.51 138.4,130.07 138.4,136.9 138.54,137.03 140.21,138.7 140.21,139.51 139.99,139.73 139.99,150.38 141.93,152.32 145.13,152.32 148.36,155.54 163.01,155.54 166.72,151.83 168.58,151.83 172.95,156.2 187.54,156.2 188.54,155.2 188.54,154.3 189.89,152.95 189.89,152.77 v2(190.32,152.34)
  L4 w0.102: v2(38.38,27.3) 38.38,25.28 40.21,23.45 40.21,21.96 44.74,17.42 44.74,11.66 46.98,9.42 52.29,9.42 53,8.7 58.3,8.7 59.26,9.66 60.25,9.66 61.91,8.01 66.2,8.01 67.03,8.83 70.01,8.83 73.96,4.88 76.82,2.02 129.08,2.02 129.51,1.59 152.73,1.59 180.21,1.59 183,4.39 184.48,4.39 187.25,7.15 187.25,14.95 191.56,19.27 191.56,31.41 191.29,31.69 191.29,42.49 192.11,43.32 192.11,45.24 190.6,46.75 190.6,50.98 190.43,51.14 190.43,61.03 194.46,65.05 196.6,65.05 200.48,68.94 200.48,80.34 199.68,81.14 199.68,84.49 198.21,85.97 198.21,94.74 197.82,95.12 197.82,96.94 198.05,97.17 198.05,97.18 200.25,99.38 200.25,100.42 v2(199.85,100.82)
  BOTTOM w0.102: v2(199.85,100.82) 200.61,101.58 200.61,108.09 200.32,108.38 200.32,121.08 199.93,121.47 199.93,132.31 200.23,132.61 200.23,133.21 200.23,133.53 200.23,135.06 199.15,136.15 194.92,136.15 191.05,140.01 191.05,147.62 189.86,148.81 189.86,151.88 v2(190.32,152.34) ; CPU1.AW1 108,94.3 109.57,94.3 112.41,97.15 113.08,97.15 113.74,97.81 v2(113.74,97.99) 114.15,98.39 114.37,98.39 114.73,98.75 115.58,98.75 RN604.8
USB_OC#3: length 356.1
  L3 w0.102: v2(191.18,43.71) 190.78,43.3 190.34,43.3 190.09,43.55 190.09,44 189.09,45 181.89,45 180.41,46.47 174.75,46.47 173.4,47.82 171.65,47.82 170.86,47.03 v2(166.95,47.03) ; v2(190.32,151.71) 189.58,152.44 189.58,152.82 188.24,154.17 188.24,155.08 187.42,155.9 173.07,155.9 168.71,151.53 166.6,151.53 162.89,155.24 148.49,155.24 145.26,152.01 142.05,152.01 140.29,150.25 140.29,139.86 140.51,139.64 140.51,138.57 138.84,136.91 138.71,136.77 138.71,130.19 144.08,124.82 144.45,124.45 144.45,122.32 144.88,121.89 144.88,119.04 145.79,118.13 145.79,116.11 139.71,110.02 131.62,110.02 131.6,110 131.57,110 122.4,100.83 117.71,100.83 117.13,100.25 116.69,100.25 v2(114.4,97.96)
  L4 w0.102: v2(147.77,4.7) 147.8,4.7 150.67,7.57 153.43,7.57 154.15,8.3 v2(154.15,9.06) ; v2(191.18,43.71) 191.18,44.2 191.51,44.53 191.51,44.88 189.99,46.4 189.99,50.69 189.81,50.87 189.81,61.34 194.14,65.68 196.36,65.68 199.87,69.19 199.87,80.09 199.07,80.89 199.07,84.21 197.6,85.68 197.6,94.48 197.21,94.87 197.21,97.58 v2(199.82,100.19) ; v2(166.95,47.03) 166.55,46.63 165.52,46.63 164.89,46 164.89,41.28 160.31,36.7 160.31,29.95 160.54,29.72 160.54,28.32 160.14,27.92 160.14,25.7 160.6,25.24 v2(160.6,24.33)
  BOTTOM w0.102: 157.2,22.15 159.38,24.33 v2(160.6,24.33) ; 157.2,22.15 154.29,19.24 154.29,18.38 150.86,14.95 150.86,9.84 151.09,9.61 153.6,9.61 v2(154.15,9.06) ; 157.2,22.15 v1(157.2,22.14) ; RN604.6 115.59,97.18 115.47,97.3 115.47,98.14 115.21,98.39 114.83,98.39 v2(114.4,97.96) 114.37,97.96 113.26,96.84 112.72,96.84 109.9,94.02 108.47,94.02 CPU1.AY1 ; U3505.3 148.47,3.66 148.11,4.03 148.11,4.37 v2(147.77,4.7) ; v2(190.32,151.71) 190.17,151.55 190.17,148.94 191.36,147.75 191.36,140.14 195.05,136.45 199.34,136.45 200.54,135.25 200.54,132.49 200.29,132.24 200.29,121.62 200.68,121.23 200.68,108.45 200.91,108.22 200.91,101.28 200.28,100.65 200.28,100.64 200.03,100.39 200.02,100.39 v2(199.82,100.19)
USB_PN0: length 121.4
  L4 w0.102: v2(103.66,90.64) 103.53,90.77 103.38,90.77 103.25,90.64 103.25,90.16 102.86,89.77 102.81,89.77 100.4,87.37 98.88,87.37 97.69,86.18 97.69,82.59 97.61,82.52 97.61,79.8 96.26,78.45 92.96,78.45 91.38,76.87 82.97,76.87 80.55,74.45 68.7,74.45 63.83,69.58 63.83,63.18 52.24,51.59 51.62,51.59 45.49,45.46 45.49,40.23 44.02,38.76 44.02,38.27 v2(44.19,38.09)
  BOTTOM w0.102: TR3401.1 24.05,41.35 24.42,40.98 24.83,40.98 25.17,40.64 25.17,39.27 25.36,39.07 ; 25.36,39.07 25.55,38.89 25.55,37.46 28.05,34.96 40.22,34.96 42.11,36.86 42.11,37.95 43.19,39.03 43.76,39.03 43.99,38.8 43.99,38.29 v2(44.19,38.09) ; 25.36,39.07 v1(25.47,39.18) ; v2(103.66,90.64) 103.66,90.8 103.43,91.03 103.18,91.03 CPU1.AL5
USB_PN0_R: length 16.8
  TOP w0.102: AFTP6204.1 15.38,42.45 15.25,42.33 14.7,42.33 13.81,43.22 13.15,43.22 USB2.2
  BOTTOM w0.102: TR3401.2 21.65,41.35 21.37,41.06 21.37,40.76 21.22,40.61 20.94,40.61 20.75,40.8 20.75,41.68 20.6,41.83 U3401.1 18.68,41.83 18.35,42.16 17.42,43.08 13.29,43.08 USB2.2
USB_PN1: length 143.2
  TOP w0.102: 172.29,12.56 173.94,12.56 174.39,13.02 174.7,13.02 175.04,12.68 TR6301.4 ; 172.29,12.56 171.68,12.56 171.47,12.78 v2(171.25,12.78) ; 172.29,12.56 v1(172.29,12.39)
  L3 w0.102: v2(171.25,12.78) 171.25,12.91 170.89,13.28 169.49,13.28 168.96,12.74 165.55,12.74 164.94,13.35 153.85,13.35 151.32,15.89 149.69,15.89 149.62,15.82 v2(149.61,15.82)
  L4 w0.102: v2(149.61,15.82) 149.57,15.78 147.76,15.78 144.88,18.66 144.88,36.86 144.84,36.89 144.12,37.62 144.12,45.03 143.71,45.44 143.71,49.76 136.9,56.56 136.9,65.14 136.29,65.75 136.29,79.35 134.17,81.47 134.17,87.03 127.76,93.44 125.25,93.44 124.89,93.79 104.7,93.79 103.07,92.17 103.07,91.86 v2(102.59,91.37)
  BOTTOM w0.102: v2(102.59,91.37) 102.42,91.37 CPU1.AJ5
USB_PN1_IOBD1: length 5.6
  TOP w0.102: 178.38,13.05 177.75,13.05 177.38,12.68 TR6301.3 ; 178.38,13.05 v1(178.38,12.9) ; 178.38,13.05 178.76,13.05 179.26,12.55 181.27,12.55 181.67,12.15 IOBD1.8
USB_PN4: length 141.7
  TOP w0.102: 169.57,14.44 170.8,14.44 R6303.2 ; 169.57,14.44 169.48,14.44 168.86,15.07 168.15,15.07 168.04,14.97 168.04,14.47 v2(168.27,14.25) ; 169.57,14.44 v1(169.57,14.29)
  L3 w0.102: v2(168.27,14.25) 167.6,13.58 165.9,13.58 165.29,14.19 154.21,14.19 151.16,17.24 149.36,17.24 v2(149.12,17)
  L4 w0.102: v2(149.12,17) 149.11,17 148.89,17.22 148.08,17.22 145.72,19.58 145.72,37.23 144.96,37.99 144.96,49.7 137.74,56.91 137.74,65.49 137.21,66.03 137.21,79.87 135.01,82.07 135.01,87.38 128.06,94.33 125.54,94.33 125.24,94.63 107.06,94.63 106.8,94.89 102.99,94.89 102.48,94.38 v2(100.81,94.38)
  BOTTOM w0.102: CPU1.AF2 100.35,93.07 100.65,93.37 100.65,93.67 100.6,93.72 100.6,94.17 v2(100.81,94.38)
USB_PN4_IOBD1: length 11
  TOP w0.102: R6303.1 172.5,14.44 174.12,14.44 174.66,14.98 179.14,14.98 ; IOBD1.11 181.71,15.15 181.33,15.54 180.57,15.54 180.01,14.98 179.14,14.98 ; 179.14,14.98 v1(179.14,14.8)
USB_PN5: length 142.4
  L3 w0.102: v2(149.32,19.42) 149.25,19.42 149.11,19.28 149.11,19 149.58,18.53 151.46,18.53 154.73,15.26 166.12,15.26 166.32,15.46 166.32,15.69 v2(166.27,15.74)
  L4 w0.102: v2(100.81,95.67) 101.22,96.08 106.94,96.08 107.55,95.47 125.58,95.47 125.85,95.2 127.44,95.2 127.66,95.42 128.15,95.42 135.96,87.61 135.96,82.31 138.26,80.01 138.26,79.25 138.68,78.83 138.68,72.3 138.15,71.77 138.15,66.46 138.15,66.27 138.58,65.84 138.58,57.26 146,49.84 146,46.48 147.6,44.88 147.6,20.52 148.41,19.71 149.01,19.71 149.3,19.42 v2(149.32,19.42)
  BOTTOM w0.102: v2(100.81,95.67) 100.7,95.78 100.55,95.78 100.15,95.38 100.15,93.73 99.8,93.38 CPU1.AE2 ; v1(167.71,16.58) 167.71,16.43 ; 167.71,16.43 166.95,16.43 v2(166.27,15.74) ; 167.71,16.43 171.26,16.43 R5802.2
USB_PN5_R: length 14.6
  BOTTOM w0.102: 175.95,18 177.52,19.57 177.52,21.92 178.56,22.96 178.56,24.5 178.86,24.81 179.5,24.81 179.99,25.3 WLAN1.36 ; 175.95,18 v1(175.82,18.13) ; 175.95,18 174.38,16.43 172.81,16.43 R5802.1
USB_PN6: length 114.6
  TOP w0.102: 36.37,72.08 38.43,72.08 39.32,71.19 39.32,66.18 40.65,64.85 45.32,64.85 45.57,65.09 46.43,65.09 v2(46.68,65.35) ; 36.37,72.08 v1(36.37,72.23) ; 36.37,72.08 35.86,72.08 34.69,73.25 34.69,76.48 33.63,77.54 32.26,77.54 31.82,77.97 31.82,79.07 R5203.2
  L4 w0.102: v2(99.44,94.58) 99.18,94.84 99.05,94.84 98.85,94.64 98.85,88.16 97.1,86.4 96.85,86.4 96.54,86.1 96.54,84.83 96.57,84.8 96.82,84.55 96.82,81.68 96.44,81.3 95.83,81.3 95.65,81.12 95.65,79.77 95.2,79.32 93.98,79.32 93.55,79.75 93.55,80.05 93.27,80.33 92.96,80.33 92.68,80.05 92.68,79.14 91.56,78.02 83.18,78.02 80.97,75.81 77.87,75.81 77.35,75.29 68.35,75.29 62.99,69.93 62.99,64.03 62.61,63.65 62.61,63.39 62.3,63.08 v2(61.72,63.08)
  BOTTOM w0.102: v2(61.72,63.08) 61.77,63.14 62.05,63.14 62.18,63.01 62.18,62.68 61.26,61.76 ; v1(61.14,61.89) 61.26,61.76 ; 61.26,61.76 59.46,59.96 55.02,59.96 53.92,61.06 53.92,63.67 51.97,65.63 47.69,65.63 47.16,65.09 46.94,65.09 v2(46.68,65.35) ; CPU1.AD2 99.25,93.03 99.55,93.33 99.55,93.67 99.45,93.77 99.45,94.57 v2(99.44,94.58)
USB_PN6_TPNL: length 4.8
  TOP w0.102: LCD1.34 30.45,83.03 30.25,82.83 30.25,82.31 30.65,81.9 31.52,81.9 ; 31.52,81.9 31.62,81.9 31.82,81.7 31.82,80.66 R5203.1 ; 31.52,81.9 v1(31.52,82.06)
USB_PN7: length 89.2
  TOP w0.102: v2(45.03,66.24) 44.6,66.67 44.22,66.67 43.66,66.11 43.45,66.11 43.13,66.43 RN5206.4
  L4 w0.102: v2(98.84,95.6) 98.84,95.61 98.71,95.74 98.56,95.74 98.08,95.26 98.08,92.27 96.62,90.81 96.62,88.84 96.75,88.71 96.75,87.63 95.45,86.33 94.94,86.33 94.65,86.04 94.65,84.72 92.58,82.65 92.58,81.47 91.4,80.29 84.83,80.29 84.71,80.17 82.91,80.17 80.24,77.5 77.17,77.5 76.68,77 71.55,77 70.71,76.17 68.04,76.17 62.15,70.27 62.15,64.84 61.01,63.7 v2(60.93,63.7)
  BOTTOM w0.102: v1(58.32,61.56) 58.19,61.68 ; 58.19,61.68 57.16,60.65 55.32,60.65 54.56,61.41 54.56,63.92 52.24,66.24 v2(45.03,66.24) 44.58,65.78 RN5205.4 ; 58.19,61.68 60.43,63.92 60.7,63.92 v2(60.93,63.7) ; CPU1.AC2 98.7,93.42 99,93.72 99,94.03 98.61,94.43 98.61,95.37 v2(98.84,95.6)
USB_PN7_CAM#: length 34.5
  L4 w0.102: v2(33.8,87.5) 33.89,87.6 34.16,87.6 34.92,86.83 34.92,85.02 34.21,84.31 34.21,69.5 36.97,66.74 40.53,66.74 40.91,67.13 41.22,67.13 v2(41.22,67.12)
  BOTTOM w0.102: 32.74,88.41 33.64,87.5 v2(33.8,87.5) ; 32.74,88.41 32.54,88.61 30.93,88.61 30.55,88.23 TR5208.4 29.5,88.23 R5219.2 ; 32.74,88.41 v1(32.61,88.28) ; RN5205.1 41.12,65.78 40.97,65.93 40.97,66.87 v2(41.22,67.12)
USB_PN7_EDP: length 14.1
  TOP w0.102: 40.66,71.52 40.66,68.82 40.16,68.31 40.16,66.5 40.47,66.18 40.79,66.18 41.04,66.43 RN5206.1 ; 40.66,71.52 40.66,71.91 39.22,73.35 36.71,73.35 36.09,73.97 36.09,74.57 36.48,74.96 TR5209.4 ; 40.66,71.52 v1(40.82,71.52)
USB_PN8: length 127.8
  TOP w0.102: 29.28,25.91 27.17,25.91 26.73,26.36 TR3404.4 ; 29.28,25.91 v1(29.28,26.08) ; 29.28,25.91 30.13,25.91 30.96,25.09 34.3,25.09 34.54,25.32 34.54,25.67 34.83,25.95 35.02,25.95 35.1,26.04 35.1,26.32 35.17,26.38 v2(35.43,26.38)
  L4 w0.102: v2(35.43,26.38) 35.43,26.24 35.3,26.11 35.01,26.11 34.77,26.35 34.77,32.61 36.92,34.76 38.45,34.76 41.8,38.11 41.8,39.61 43.21,41.02 43.84,41.65 43.84,46.18 51.14,53.48 51.87,53.48 59.64,61.25 59.64,75.06 64.35,79.77 68.07,79.77 69.11,78.73 70.38,78.73 71.27,77.84 76.33,77.84 76.83,78.34 77.33,78.34 77.33,78.34 79.81,78.34 82.58,81.1 86.51,81.1 86.78,81.38 87.75,81.38 91.17,81.38 91.84,82.05 91.84,86.23 92.94,87.32 94.26,87.32 94.68,87.74 94.68,88.07 96.09,89.48 96.09,91.43 96.91,92.25 96.91,94.93 97.11,95.13 97.29,95.13 v2(97.36,95.06)
  BOTTOM w0.102: v2(97.36,95.06) 97.7,95.06 97.9,94.86 97.9,93.72 97.85,93.67 97.85,93.33 98.15,93.03 CPU1.AB2
USB_PN8_C: length 13.5
  TOP w0.102: TR3404.3 24.32,26.36 23.89,25.93 23.85,25.93 22.02,25.93 21.4,25.3 21.4,24.59 21.03,24.23 20.85,24.23 20.7,24.38 20.7,24.89 20.59,25 U3403.1 18.5,25 17.95,24.45 17.69,24.45 ; 17.69,24.45 16.9,24.45 16.13,25.22 15.57,25.22 USB1.2 ; 17.69,24.45 17.7,24.46 AFTP6211.1
USB_PP0: length 121.5
  L4 w0.102: v2(43.56,38.09) 43.79,38.32 43.79,38.85 45.26,40.32 45.26,45.56 51.52,51.82 52.15,51.82 63.6,63.27 63.6,69.67 68.61,74.68 80.46,74.68 82.88,77.1 91.29,77.1 92.87,78.68 96.16,78.68 97.38,79.9 97.38,82.61 97.46,82.69 97.46,86.27 98.78,87.6 100.31,87.6 102.71,90 102.77,90 103.02,90.25 103.02,90.74 103.66,91.38 v2(103.66,91.41)
  BOTTOM w0.102: 25.35,37.66 25.35,38.8 24.97,39.18 24.97,40.56 24.75,40.77 24.42,40.77 24.05,40.4 TR3401.4 ; 25.35,37.66 25.35,37.38 27.97,34.76 40.3,34.76 42.31,36.77 42.31,37.86 43.28,38.83 43.68,38.83 43.79,38.72 43.79,38.32 v2(43.56,38.09) ; 25.35,37.66 v1(25.19,37.66) ; CPU1.AL4 103.44,91.41 v2(103.66,91.41)
USB_PP0_R: length 16.8
  TOP w0.102: AFTP6209.1 15.38,41.96 15.25,42.09 14.6,42.09 13.71,42.98 13.15,42.98 USB2.3
  BOTTOM w0.102: USB2.3 13.05,42.88 17.34,42.88 18.13,42.09 18.13,40.92 19.14,39.92 U3401.3 20.41,39.92 20.89,40.4 TR3401.3
USB_PP1: length 143.1
  TOP w0.102: 173.43,12.77 173.85,12.77 174.31,13.23 174.7,13.23 175.1,13.62 TR6301.1 ; 173.43,12.77 171.77,12.77 171.68,12.86 v2(171.68,13.25) ; 173.43,12.77 v1(173.43,12.95)
  L3 w0.102: v2(149.23,16.32) 149.31,16.25 149.79,16.25 149.92,16.11 151.41,16.11 153.94,13.58 165.04,13.58 165.65,12.97 168.86,12.97 169.4,13.5 170.98,13.5 171.23,13.25 v2(171.68,13.25)
  L4 w0.102: v2(102.59,92.12) 102.7,92.12 104.61,94.02 124.98,94.02 125.34,93.67 127.86,93.67 134.4,87.12 134.4,81.57 136.52,79.45 136.52,65.85 137.13,65.24 137.13,56.66 143.94,49.85 143.94,45.53 144.35,45.13 144.35,37.71 144.93,37.12 144.93,37.12 145.11,36.95 145.11,18.76 147.86,16.01 148.91,16.01 v2(149.23,16.32)
  BOTTOM w0.102: v2(102.59,92.12) 102.55,92.12 102.18,91.75 CPU1.AJ4
USB_PP1_IOBD1: length 5.7
  TOP w0.102: 179.78,12.75 v1(179.78,12.95) ; 179.78,12.75 179.35,12.75 178.85,13.25 177.77,13.25 177.4,13.62 TR6301.2 ; 179.78,12.75 181.29,12.75 181.68,13.15 IOBD1.9
USB_PP4: length 141.6
  TOP w0.102: 167.84,14.88 167.84,15.05 168.06,15.27 168.94,15.27 169.57,14.65 170.8,14.65 R6304.1 ; 167.84,14.88 167.84,14.5 v2(167.59,14.24) ; 167.84,14.88 v1(167.69,14.88)
  L3 w0.102: v2(149.1,17.64) 149.27,17.47 151.25,17.47 154.3,14.42 165.38,14.42 166,13.81 167.51,13.81 167.67,13.98 167.67,14.15 v2(167.59,14.24)
  L4 w0.102: v2(149.1,17.64) 149.1,17.64 148.91,17.45 148.17,17.45 145.95,19.68 145.95,37.32 145.18,38.09 145.18,49.79 137.97,57.01 137.97,65.59 137.44,66.12 137.44,79.97 135.24,82.16 135.24,87.47 128.16,94.56 125.64,94.56 125.33,94.86 107.15,94.86 106.9,95.11 102.89,95.11 102.39,94.61 101.22,94.61 v2(100.81,95.01)
  BOTTOM w0.102: CPU1.AF1 100.38,93.53 100.38,94.58 v2(100.81,95.01)
USB_PP4_IOBD1: length 11
  TOP w0.102: R6304.2 172.5,14.65 174.04,14.65 174.57,15.18 177.37,15.18 ; 177.37,15.18 179.92,15.18 180.48,15.74 181.28,15.74 181.69,16.15 IOBD1.12 ; 177.37,15.18 v1(177.37,15.38)
USB_PP5: length 142.6
  L3 w0.102: v2(149.02,20.15) 148.88,20.01 148.88,18.9 149.48,18.31 151.36,18.31 154.64,15.03 166.22,15.03 v2(166.95,15.77)
  L4 w0.102: v2(149.02,20.15) 148.82,19.94 148.5,19.94 147.83,20.62 147.83,44.98 146.23,46.58 146.23,49.94 138.81,57.36 138.81,65.93 138.38,66.37 138.38,71.67 138.91,72.21 138.91,78.92 138.49,79.35 138.49,80.1 136.19,82.4 136.19,87.71 128.25,95.65 127.56,95.65 127.34,95.43 125.95,95.43 125.68,95.7 107.64,95.7 107.03,96.31 v2(100.79,96.31)
  BOTTOM w0.102: v2(166.95,15.77) 166.84,15.88 166.84,16.03 167.04,16.22 169.34,16.22 ; v2(100.79,96.31) 99.95,95.46 99.95,94 CPU1.AE1 ; R5803.1 171.26,16.22 169.34,16.22 ; 169.34,16.22 v1(169.34,16.07)
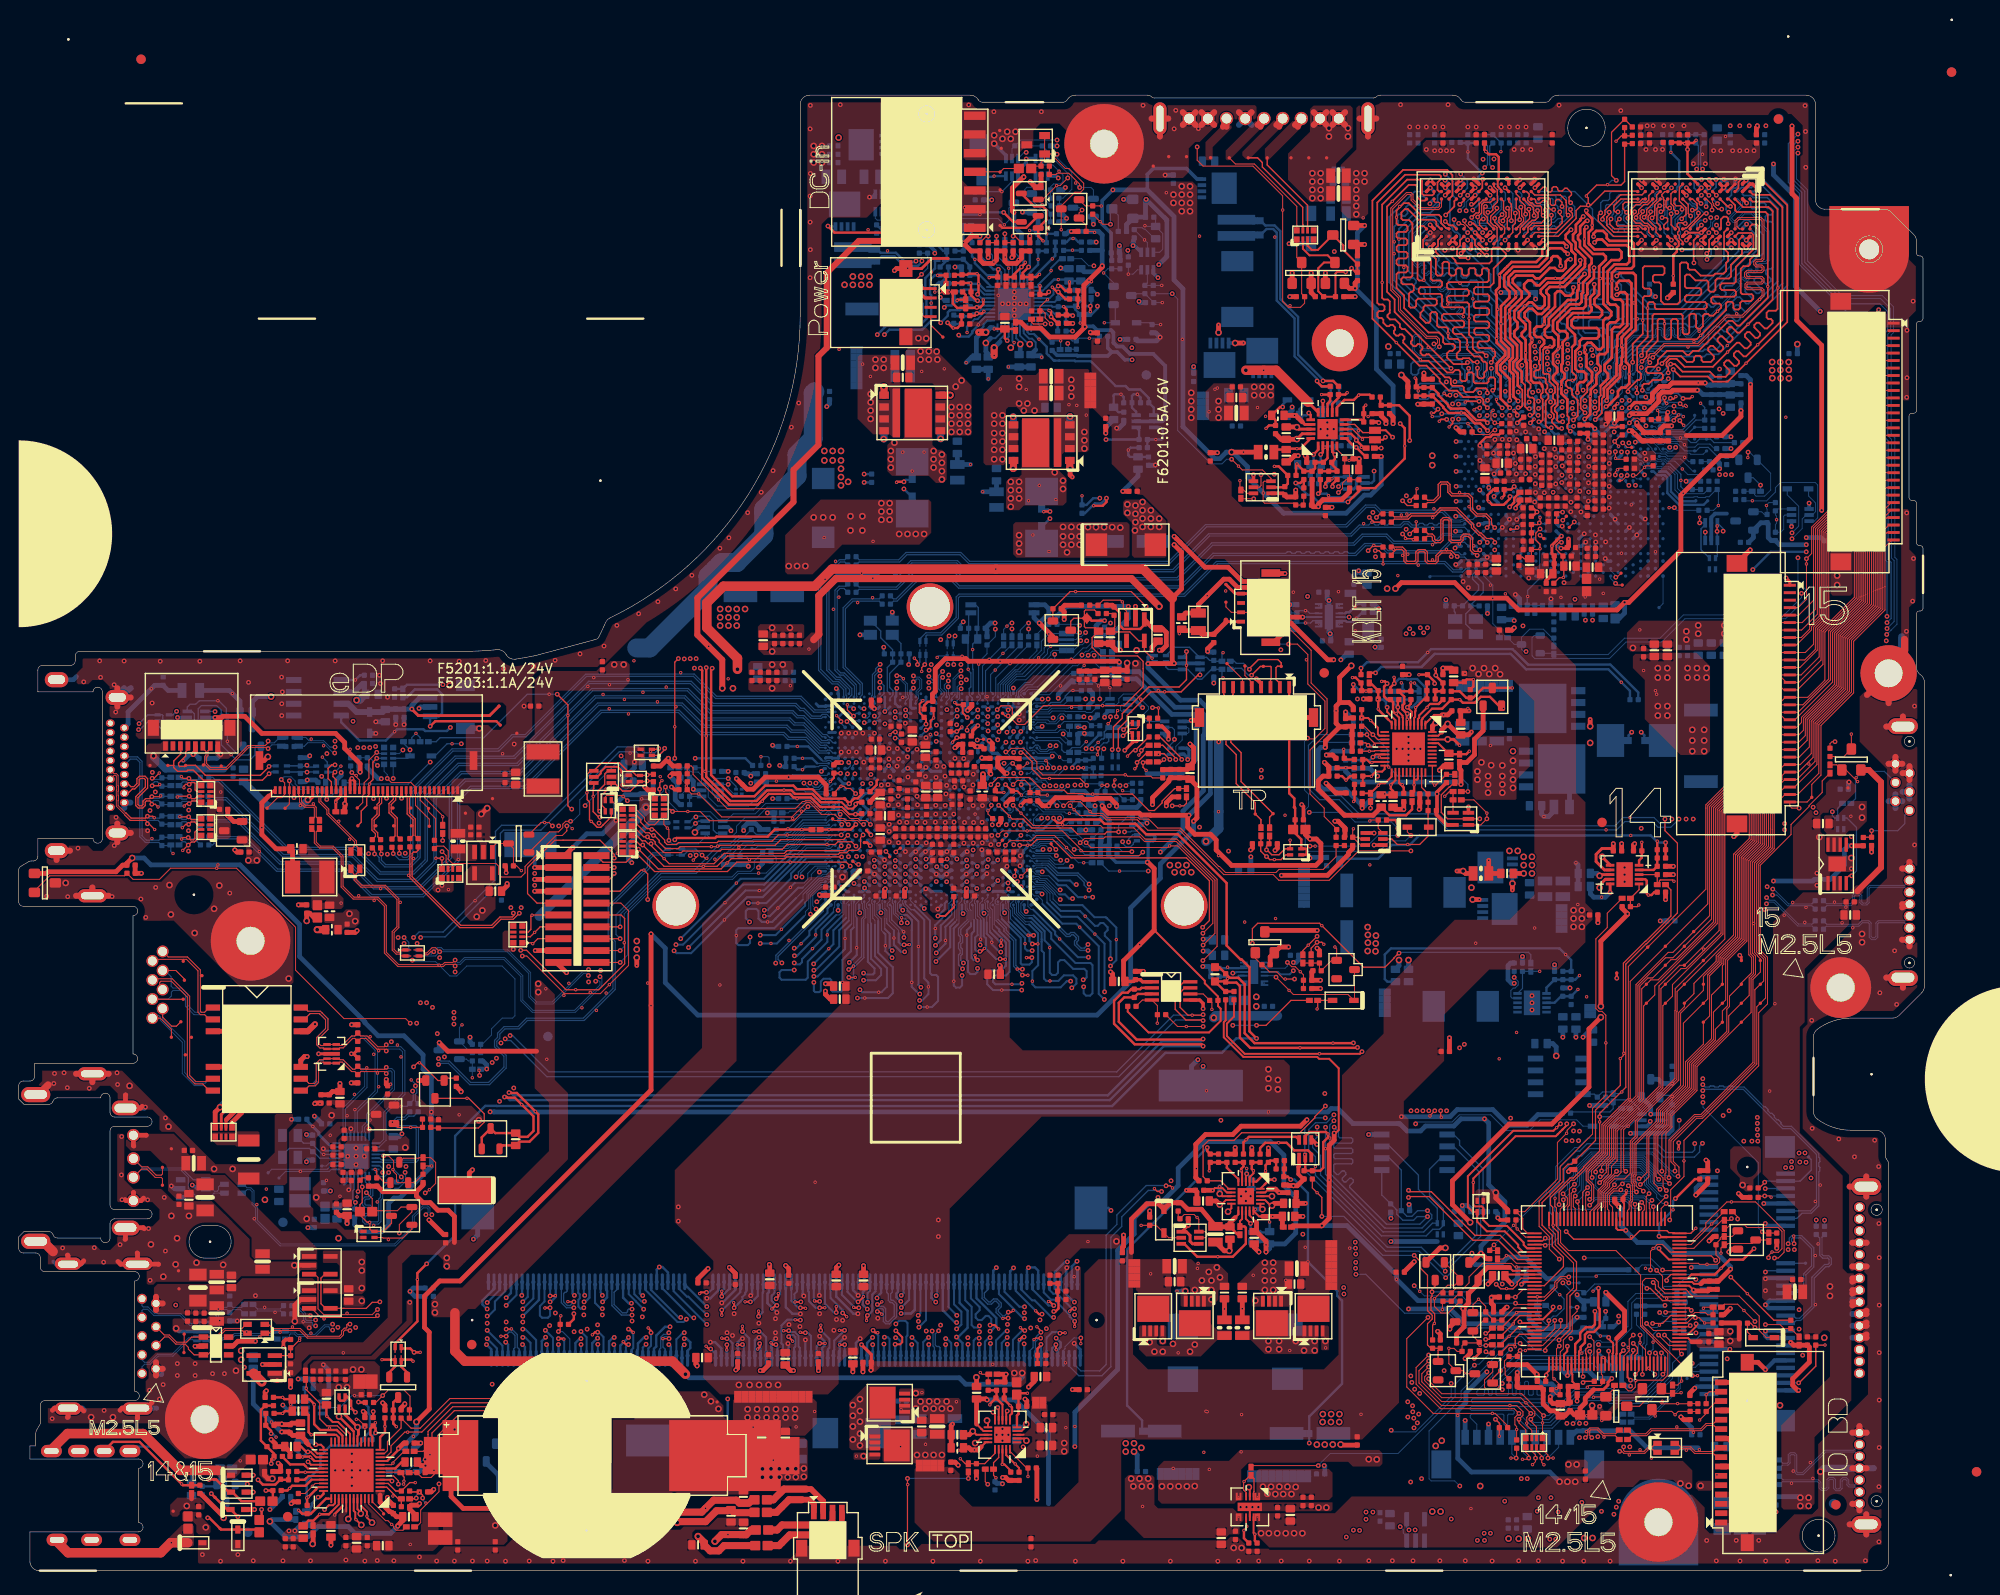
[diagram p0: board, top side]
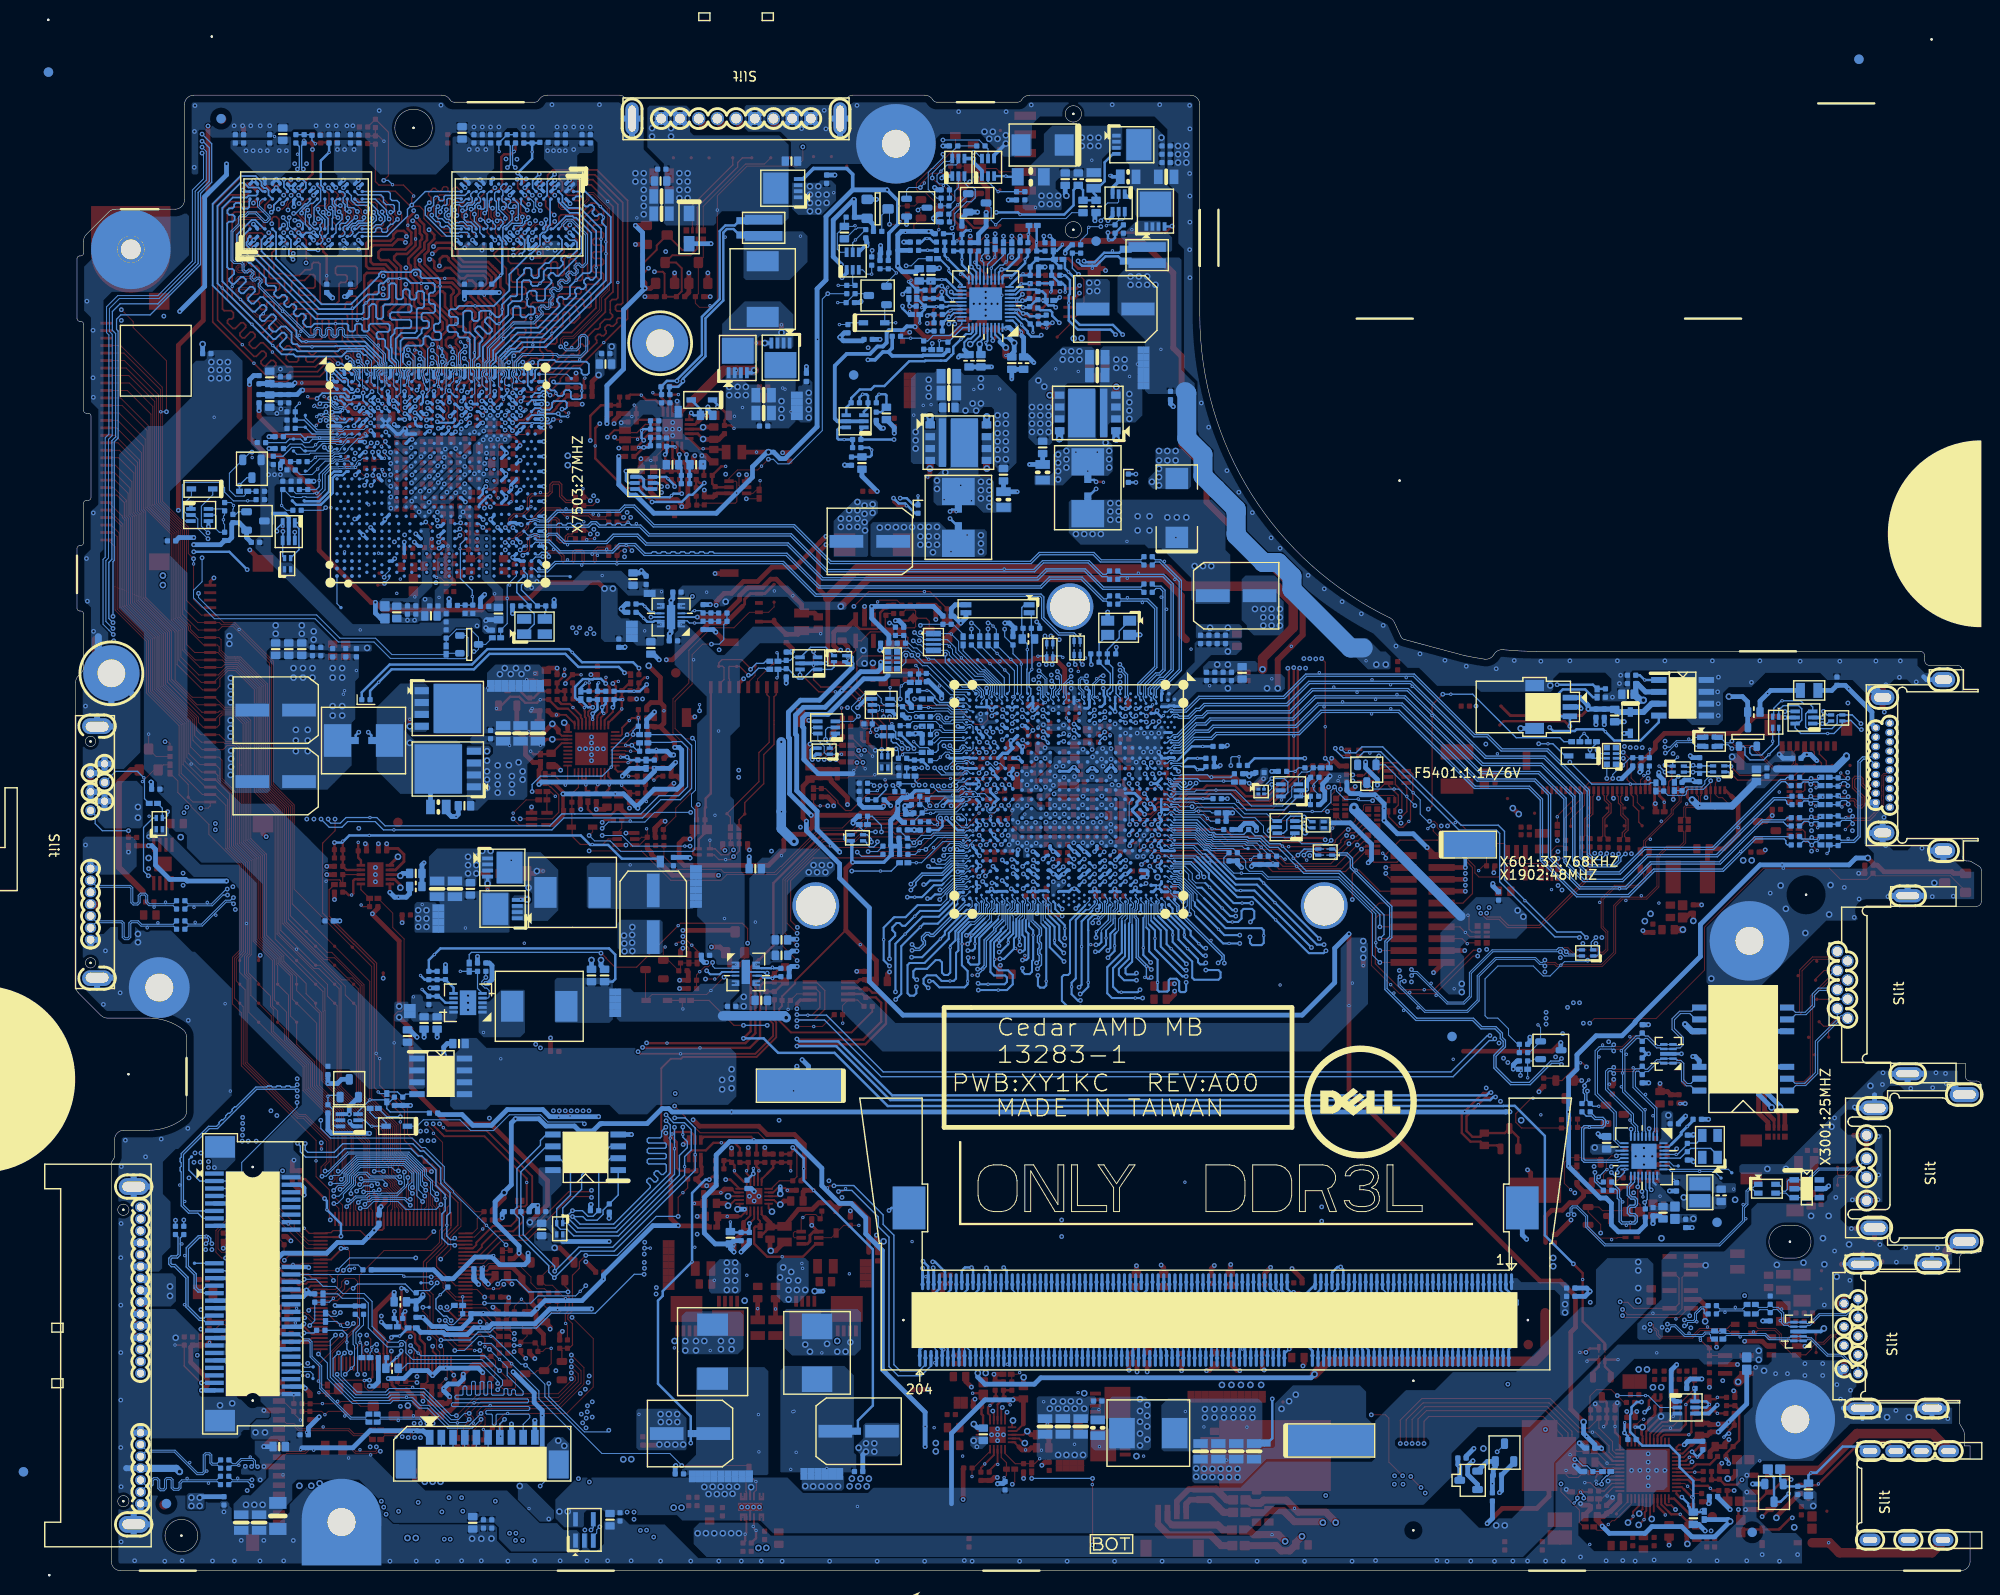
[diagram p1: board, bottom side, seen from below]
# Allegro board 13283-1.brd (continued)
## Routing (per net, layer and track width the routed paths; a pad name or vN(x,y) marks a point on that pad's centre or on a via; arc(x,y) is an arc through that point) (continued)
USB_PP5_R: length 14.4
  BOTTOM w0.102: 174.92,16.68 177.73,19.49 177.73,21.84 178.76,22.87 178.76,24.42 178.95,24.6 179.67,24.6 179.78,24.5 WLAN1.38 ; 174.92,16.68 v1(175.05,16.55) ; 174.92,16.68 174.46,16.22 172.81,16.22 R5803.2
USB_PP6: length 114.5
  TOP w0.102: v2(46.68,64.71) 46.51,64.89 45.65,64.89 45.41,64.65 40.57,64.65 39.11,66.1 39.11,71.1 38.34,71.87 38.02,71.87 ; 38.02,71.87 35.78,71.87 34.49,73.16 34.49,76.39 33.55,77.33 32.17,77.33 31.62,77.89 31.62,79.14 R5204.2 ; 38.02,71.87 v1(38.02,71.72)
  L4 w0.102: v2(99.44,95.22) 99.29,95.07 98.96,95.07 98.63,94.73 98.63,88.25 97.01,86.63 96.75,86.63 96.31,86.19 96.31,84.73 96.34,84.71 96.34,84.71 96.59,84.45 96.59,81.77 96.35,81.53 95.74,81.53 95.56,81.35 95.43,81.21 95.43,79.87 95.1,79.54 94.08,79.54 93.77,79.85 93.77,80.15 93.36,80.56 92.87,80.56 92.45,80.15 92.45,79.23 91.47,78.25 83.08,78.25 80.87,76.04 77.78,76.04 77.26,75.52 68.26,75.52 62.76,70.02 62.76,64.13 62.2,63.57 v2(62.18,63.57)
  BOTTOM w0.102: 60.14,60.35 59.54,59.76 54.94,59.76 53.72,60.98 53.72,63.59 51.88,65.42 47.78,65.42 47.24,64.89 46.86,64.89 v2(46.68,64.71) ; 60.14,60.35 v1(60.25,60.24) ; 60.14,60.35 62.38,62.59 62.38,63.36 v2(62.18,63.57) ; CPU1.AD1 99.25,94.16 99.01,94.4 99.01,94.78 v2(99.44,95.22)
USB_PP6_TPNL: length 4.8
  TOP w0.102: R5204.1 31.62,80.59 31.62,81.61 31.53,81.7 30.57,81.7 30.25,82.01 ; 30.25,82.01 30.05,82.22 30.05,82.91 29.95,83.01 LCD1.35 ; 30.25,82.01 v1(30.12,81.88)
USB_PP7: length 88.4
  TOP w0.102: RN5206.3 43.34,65.78 43.46,65.9 43.74,65.9 44.07,66.24 v2(44.4,66.24)
  L4 w0.102: v2(98.83,96.24) 98.73,96.24 97.85,95.36 97.85,92.36 96.39,90.9 96.39,88.75 96.52,88.62 96.52,87.72 95.35,86.56 94.85,86.56 94.42,86.13 94.42,84.82 92.35,82.75 92.35,81.56 91.31,80.52 84.73,80.52 84.62,80.4 82.82,80.4 80.15,77.73 77.08,77.73 76.58,77.23 71.45,77.23 70.62,76.4 67.95,76.4 61.92,70.37 61.92,64.93 61.32,64.33 v2(60.96,64.33)
  BOTTOM w0.102: v2(98.83,96.24) 98.4,95.81 98.4,94.35 98.7,94.05 CPU1.AC1 ; 58.96,62.74 57.07,60.85 55.4,60.85 54.76,61.49 54.76,64 52.32,66.44 45.44,66.44 45.21,66.67 44.83,66.67 v2(44.4,66.24) 44.15,65.99 43.5,65.99 43.38,66.11 43.38,66.32 43.27,66.43 RN5205.3 ; 58.96,62.74 v1(58.85,62.86) ; 58.96,62.74 60.35,64.13 60.75,64.13 v2(60.96,64.33)
USB_PP7_CAM: length 34.3
  L4 w0.102: v2(33.84,88.14) 33.94,88.14 35.15,86.92 35.15,84.93 34.44,84.22 34.44,69.6 37.06,66.97 40.43,66.97 v2(41.22,67.76)
  BOTTOM w0.102: 31.29,88.82 32.62,88.82 33.3,88.14 v2(33.84,88.14) ; 31.29,88.82 31.06,88.82 30.7,89.18 TR5208.1 29.5,89.18 R5221.2 ; 31.29,88.82 v1(31.29,88.99) ; v2(41.22,67.76) 41.73,67.25 41.73,66.65 RN5205.2
USB_PP7_EDP: length 14.4
  TOP w0.102: 38.71,73.15 39.14,73.15 40.46,71.82 40.46,68.9 39.95,68.39 39.95,66.41 40.38,65.98 40.77,65.98 40.97,65.78 RN5206.2 ; 38.71,73.15 v1(38.71,72.99) ; 38.71,73.15 36.63,73.15 35.89,73.88 35.89,74.52 35.54,74.87 TR5209.1
USB_PP8: length 127.9
  TOP w0.102: TR3404.1 26.76,25.41 27.06,25.71 27.96,25.71 ; 27.96,25.71 v1(27.96,25.52) ; 27.96,25.71 30.05,25.71 30.88,24.88 34.39,24.88 34.74,25.24 34.74,25.59 34.91,25.75 35.38,25.75 v2(35.43,25.7)
  L4 w0.102: v2(35.43,25.7) 35.25,25.88 34.91,25.88 34.54,26.25 34.54,32.7 36.82,34.99 38.36,34.99 41.57,38.2 41.57,39.7 43.12,41.25 43.12,41.25 43.61,41.74 43.61,46.27 51.05,53.71 51.77,53.71 59.41,61.35 59.41,75.15 64.26,80 68.16,80 69.21,78.96 70.48,78.96 71.36,78.07 76.24,78.07 76.73,78.57 79.72,78.57 82.48,81.33 86.41,81.33 86.69,81.61 87.85,81.61 91.08,81.61 91.62,82.15 91.62,86.32 92.84,87.55 94.17,87.55 94.45,87.83 94.45,88.16 95.86,89.57 95.86,91.53 96.68,92.35 96.68,95.02 v2(97.36,95.7)
  BOTTOM w0.102: CPU1.AB1 98.15,94.91 v2(97.36,95.7)
USB_PP8_C: length 13.6
  TOP w0.102: USB1.3 15.61,25.02 16.04,25.02 16.81,24.25 17.67,24.25 ; AFTP6212.1 17.68,24.24 17.67,24.25 ; 17.67,24.25 17.8,24.25 18.14,23.9 18.14,23.71 18.77,23.09 U3403.3 20.19,23.09 21.6,24.5 21.6,25.22 22.1,25.72 23.9,25.72 24.21,25.41 TR3404.2
USB_PWR_EN#: length 174.5
  TOP w0.127: v2(38.63,28.77) 38.58,28.72 37.82,28.72 37.17,28.07 34.79,28.07 34.79,28.07 U3504.4 32.82,28.07 32.33,28.57 32.33,31.31 32.75,31.73 U3503.4 ; KBC24.91 163.09,25.7 163.68,26.28 v2(163.68,26.76)
  L3 w0.127: v2(142.77,4.34) 142.68,4.42 140.76,4.42 140.44,4.74 130.22,4.74 129.94,4.46 129.13,4.46 128.8,4.13 96.07,4.13 95.87,4.34 80.49,4.34 76.02,8.81 71.9,8.81 66.63,14.08 62.34,14.08 61.06,15.36 48.48,15.36 42.41,21.43 41.51,21.43 38.95,24 38.95,28.45 v2(38.63,28.77)
  L4 w0.127: v2(142.77,4.34) 143.19,4.75 143.62,4.75 144.11,4.26 147.59,4.26 147.59,4.26 147.96,4.26 147.96,4.26 148.64,4.26 v2(148.71,4.36) 148.89,4.51 148.89,5.33 150.82,7.26 153.77,7.26 155.01,8.5 155.01,9.2 157.3,11.49 157.3,12.85 160.11,15.66 161.84,15.66 162.67,16.49 162.67,16.78 163.39,17.5 163.39,20.05 163.84,20.5 163.84,25.35 163.68,25.52 v2(163.68,26.76)
  BOTTOM w0.127: U3505.4 148.47,4.6 v2(148.71,4.36) ; R2429.1 164.03,30.34 v1(164.84,29.53) 165.3,29.07 165.3,28.04 164.51,27.25 164.15,27.25 163.68,26.77 v2(163.68,26.76)
USB_RCOMP: length 3.4
  TOP w0.203: v1(100.12,92.91) 100.35,92.68 R1902.2 100.98,92.6 100.98,91.8 v2(101.47,91.3)
  BOTTOM w0.203: v2(101.47,91.3) 101.03,91.75 CPU1.AG4
USB_SS_ZVDD_095: length 2.2
  TOP w0.203: R1910.1 100.33,89.79 v2(100.35,89.81) 100.4,89.81 v1(100.89,90.29)
  BOTTOM w0.203: CPU1.AE8 100.26,89.81 v2(100.35,89.81)
USB_SS_ZVSS: length 2.2
  TOP w0.203: v1(99.9,88.66) 99.9,88.69 v2(100.34,89.14) 100.82,89.14 R1909.1
  BOTTOM w0.203: v2(100.34,89.14) 99.8,88.6 CPU1.AE10
VCORE_EN: length 317.4
  TOP w0.127: v2(109.8,133.42) 108.53,133.42 108.34,133.61 PR4639.2 ; R3605.2 138.25,66.62 v2(138.88,67.25) 139.39,67.25 139.39,67.25 v1(139.61,67.03)
  L3 w0.127: v2(138.88,67.25) 139.77,66.36 139.77,55.87 145.88,49.76 145.88,47.49 151.89,41.48 151.89,39.81 154.18,37.53 154.18,32.95 154.44,32.69 154.44,30.48 159.33,25.6 163.14,25.6 163.16,25.58 164.14,25.58 164.16,25.6 164.8,25.6 164.86,25.66 176.23,25.66 179.1,22.79 182.64,22.79 v2(182.75,22.67)
  L4 w0.127: v2(109.8,133.42) 109.8,134.17 110.38,134.75 122.11,134.75 123.84,136.47 123.84,141.61 122.72,142.73 122.72,147.59 126.15,151.02 145.69,151.02 147.83,153.15 162.69,153.15 165.58,150.26 165.65,150.25 169.55,150.25 172.82,153.51 187.12,153.51 188.31,152.32 188.31,151.63 188.47,151.48 188.47,150.05 190.19,148.32 190.19,141.47 190.21,141.46 190.21,141.4 196.33,135.27 196.33,99.72 195.73,99.12 195.73,94.25 196.11,93.87 196.11,85.06 196.63,84.54 196.63,80.36 196.84,80.16 196.84,70.83 188.07,62.07 188.07,50.15 188.25,49.97 188.25,42.33 188.41,42.17 188.41,35.54 185.9,33.03 185.9,29.17 182.92,26.19 182.87,26.19 182.42,25.74 182.42,23 v2(182.75,22.67)
VD1_EN#: length 3.2
  TOP w0.102: R2447.2 160.16,36.71 v1(160.3,36.57) 161.17,35.7 KBC24.66
VD_IN1: length 88
  TOP w0.203: KBC24.104 166.49,23.33
  TOP w0.254: v2(143.2,56) 143.15,55.95 v1(137.06,55.95) 131.73,55.95 130.63,57.05 130.63,62.56 130.26,62.93 129.17,62.93 C2615.1 129.04,63.06 R2610.1 129.04,61.98 R2611.2 R2622.2 ; v2(168.6,27.75) 168.6,26.36 168.3,26.05 167.62,26.05 167.03,25.46 167.03,24.78 166.49,24.25 166.49,23.33
  L3 w0.254: v2(154.12,55.95) 144.18,55.95 143.95,56.18 143.42,56.18 143.24,56 v2(143.2,56)
  L4 w0.254: v2(168.6,27.75) 168.6,28.39 167.97,29.02 167.97,32.07 169.24,33.34 169.24,35.63 169.68,36.07 169.68,42.21 169.82,42.36 169.82,43.21 173.3,46.69 173.3,48.03 165.51,55.82 154.25,55.82 v2(154.12,55.95)
  BOTTOM w0.254: v2(168.6,27.75) 168.87,27.49 C2616.1
VD_IN1_C: length 80.9
  TOP w0.254: v2(142.77,56.48) 142.75,56.46 v1(140.59,56.46) 132.2,56.46 131.14,57.52 131.14,62.77 130.47,63.44 129.55,63.44 C2615.2 128.41,64.58 R2610.2
  L3 w0.254: v2(154.63,56.33) 154.51,56.46 144.39,56.46 144.16,56.68 142.97,56.68 v2(142.77,56.48)
  L4 w0.254: v2(169.75,27.75) 169.75,28.39 168.48,29.66 168.48,31.86 169.75,33.13 169.75,35.42 170.18,35.86 170.18,42 170.33,42.15 170.33,43 173.81,46.48 173.81,48.24 165.72,56.33 v2(154.63,56.33)
  BOTTOM w0.254: v2(169.75,27.75) 169.76,27.74 C2616.2 169.43,26.66 R2612.1
VD_OUT1#: length 23
  TOP w0.203: v2(169.02,23.52) 168.89,23.4 KBC24.110
  TOP w0.254: R2602.1 156.23,23.26 v2(155.7,22.72)
  L3 w0.254: v2(169.02,23.52) 168.02,22.52 165.81,22.52 163.01,19.73 159.81,19.73 159,20.54 156.84,20.54 156.41,20.97 156.41,22.17 155.85,22.72 v2(155.7,22.72)
  BOTTOM w0.254: R2624.2 170.66,22.71 R2607.1 v1(169.49,22.83) 169.02,23.3 v2(169.02,23.52)
VGA_CORE: length 37.1
  TOP w0.254: PR8316.1 147.27,80.33 v2(147.52,80.08)
  L4 w0.254: v2(147.52,80.08) 154.76,80.08 155.78,81.09 157.55,81.09 158.52,80.13 172.08,80.13 179.02,87.06 v3(179.02,87.7)
  vias: v1(173.81,96.33) v1(175.08,94.18) v1(175.21,93.79) v2(162.23,116.32) v2(162.25,115.39) v2(163.19,120.08) v2(163.19,115.36) v2(164.3,120.03) v2(164.41,119.14) v2(164.41,118.15) v2(164.41,116.3) v2(165.08,117.24) v2(166.04,114.34) v2(166.89,119.21) v2(166.98,115.53) v2(167.95,118.18) v2(167.91,116.42) v2(167.9,114.46) v2(167.95,120.18) v3(175.33,96.59) v3(175.33,95.57) v3(175.33,92.52) v3(175.33,91.51) v3(176.35,96.59) v3(176.35,95.57) v3(176.35,92.52) v3(176.35,91.51) v3(178.51,96.59) v3(178.51,95.57) v3(179.02,89.98) v3(179.02,88.84) v3(179.52,96.59) v3(179.52,95.57) v3(180.29,89.98) v3(180.29,88.84) v3(180.29,87.7) v3(180.54,96.59) v3(180.54,95.57)
VGA_CORE_DISCHG: length 2.5
  TOP w0.102: v1(144.52,80.23) 144.63,80.33 PR8316.2 145.43,79.45 PQ8305.3
VGA_DIS: length 6.7
  BOTTOM w0.089: 176.5,118.74 176.31,118.74 176.1,118.95 175.66,118.95 175.62,118.92 175.36,118.92 175.28,118.99 174.94,118.99 GPU1.P4
  BOTTOM w0.102: R7305.1 179.86,117.3 178.55,117.3 v1(177.95,117.9) 177.95,117.95 177.16,118.74 176.5,118.74
VGA_PEG_CLKREQ#: length 23.2
  TOP w0.102: v2(184.99,119.7) 184.99,119.14 v1(184.96,119.12)
  L3 w0.102: v2(184.99,119.7) 184.48,119.7 183.55,120.63 176.44,120.63 176.17,120.36 172.57,120.36 v2(172.24,120.69)
  BOTTOM w0.102: v2(172.24,120.69) GPU1.N7 ; R7533.2 R7518.2 185.67,115.27 185.67,115.16 185.84,114.99 186.75,114.99 187.4,115.64 187.4,117.45 Q7504.S 185.14,119.7 v2(184.99,119.7)
VGA_PWROK: length 3.4
  TOP w0.127: U8201.4 PR8275.1 PR8269.2 153.05,83.38 v1(152.54,82.87)
VO_APU_VDD: length 37.3
  TOP w0.254: v2(99.36,133.55) 99.92,132.99 v1(99.97,132.99) 100.42,132.99 PC4704.2 PC4701.2
  L3 w0.254: v2(94.69,115.77) 92.32,115.77 91.07,117.02 91.07,118.41 88.85,120.63 88.85,132.36 90.54,134.05 98.42,134.05 98.42,134.05 98.84,134.05 98.96,133.93 98.98,133.93 v2(99.36,133.55)
  BOTTOM w0.254: v2(99.36,133.55) 99.43,133.48 PR4706.2 100.09,133.42 PC4704.2 ; v2(94.69,115.77) 95.4,115.05 PG4702.1
VO_VDDNB: length 34.7
  TOP w0.254: PC4702.2 PC4703.2 ; PC4703.2 112.09,134.97 v1(111.78,135.27) ; PC4703.2 112.68,134.37 v2(112.75,134.31)
  L4 w0.254: v2(112.75,134.31) 113.46,133.59 113.46,132.63 119.4,126.69 119.4,119.91 112.09,112.59 v2(110.31,112.59)
  BOTTOM w0.254: PG4719.1 109.6,111.88 v2(110.31,112.59) ; PR4711.2 PR4708.2 112.62,134.43 v2(112.75,134.31)
VRAM1_2_VREF: length 21.7
  TOP w0.254: VRAM1.M8 158.99,147.99 v2(158.99,147.99) ; v2(157.04,141.42) 157.02,141.43 156.74,141.43 156.19,141.99 VRAM1.H1
  L3 w0.254: v2(156.56,149.57) 157.42,149.57 v2(158.99,147.99) 158.99,147.44 157.63,146.08 157.63,145.57 157.64,145.56 157.64,145.16 157.22,144.75 157.22,144.17 v2(158.99,142.4) 158.02,141.42 v2(157.04,141.42)
  BOTTOM w0.254: VRAM2.H1 156.13,148.45 156.13,149.14 v2(156.56,149.57) 155.01,151.11 v1(155.01,151.83) R7806.1 ; v2(158.99,142.4) 159.29,142.69 159.29,142.69 VRAM2.M8 ; C7803.1 R7806.1 ; R7806.1 154.25,152.79 R7805.2
VRAM3_4_VREF: length 24.6
  TOP w0.254: v2(176.78,142.39) 176.78,142.4 VRAM3.M8 ; v1(179.42,153.08) 179.13,152.79 C8901.1 ; C8901.1 v2(178.51,152.09) 178.51,149.47 VRAM3.H1 ; C8901.1 R8902.1 177.56,152.85 R8901.2
  L3 w0.254: v2(178.51,152.09) 178.51,149.7 v2(176.79,147.98) 178.4,146.37 178.4,145.3 178.36,145.26 178.36,144.76 178.76,144.37 178.76,143.97 178.46,143.67 178.06,143.67 v2(176.78,142.39) 176.88,142.39 v2(177.92,141.35)
  BOTTOM w0.254: v2(176.79,147.98) 176.4,147.59 VRAM4.M8 ; v2(177.92,141.35) 178.95,141.35 VRAM4.H1
VRAM_SIZE1: length 6.6
  BOTTOM w0.102: CPU1.BA22 108.72,81.83 108.96,81.83 109.6,81.2 111.88,81.2 112.04,81.04 v1(112.39,81.04) 113.24,81.04 R641.2 R638.1
VRAM_ZQ1: length 5.7
  BOTTOM w0.203: VRAM2.L8 158.41,142.61 158.41,142.44 158.21,142.24 158.21,141.67
  BOTTOM w0.254: 158.21,141.67 158.21,138.8 v1(158.38,138.62) R7801.2
VRAM_ZQ2: length 6.5
  TOP w0.203: 158.21,148.79 158.21,148.13 158.59,147.75 VRAM1.L8
  TOP w0.254: R7802.2 156.79,152.04 v1(157,151.83) 157.25,151.58 158.02,151.58 158.32,151.28 158.32,148.89 158.21,148.79
VRAM_ZQ3: length 5.7
  BOTTOM w0.203: VRAM4.L8 177.37,147.77 177.37,148.03 177.61,148.27 177.61,148.91
  BOTTOM w0.254: 177.61,148.91 177.62,148.92 177.62,150.89 v1(176.73,151.78) R8903.2
VRAM_ZQ4: length 5.5
  TOP w0.203: VRAM3.L8 177.19,142.63 177.57,142.25 177.57,141.8 177.37,141.6
  TOP w0.254: 177.37,141.6 177.37,141.17 176.98,140.78 v1(176.98,138.57) R8904.2
VTT_CT_0.95V: length 2.7
  BOTTOM w0.203: 130.5,64.48 U3603.12
  BOTTOM w0.254: C3619.1 128.43,64.48 129.2,64.48 v1(129.31,64.58) 129.42,64.48 130.5,64.48
VTT_CT_1.8V: length 2.9
  BOTTOM w0.203: 130.27,63.44 130.5,63.68 U3603.10
  BOTTOM w0.254: 130.27,63.44 129.39,63.44 v1(129.31,63.36) 129.28,63.36 129.08,63.57 C3618.1
VTT_CT_3VC_1: length 3.1
  BOTTOM w0.203: U8302.10 141.9,102.45
  BOTTOM w0.254: 141.9,102.45 142.01,102.56 142.31,102.56 v1(142.95,103.19) 143.2,103.45 C8301.1
WEA0#: length 34.4
  TOP w0.14: v1(158.07,125.34) 158.07,125.05 v2(158.68,124.44) ; v2(157.88,144.72) 157.88,144.33 158.38,143.83 158.38,143.8 VRAM1.L3
  L4 w0.267: v2(158.68,124.44) 158.68,125.15 159.5,125.96 159.5,126.69 159.03,127.16 159.03,127.88 159.5,128.35 159.5,128.91 159.18,129.23 159.18,129.99 158.9,130.27 158.57,130.27 158.29,130.55 158.29,132.45 158.56,132.72 159.49,132.72 159.5,132.73 159.91,132.73 160.19,133.01 160.19,135.86 160.47,136.14 160.7,136.14 160.98,136.42 160.98,136.97 160.7,137.25 159.33,137.25 159.05,137.53 159.05,138.02 159.33,138.29 160.58,138.29 160.86,138.57 160.86,139.11 160.58,139.39 159.08,139.39 158.8,139.67 158.8,141.73 158.51,142.03 158.51,143.48 157.88,144.1 v2(157.88,144.72)
  BOTTOM w0.14: VRAM2.L3 158.59,146.01 158.59,146.01 158.59,145.69 157.88,144.98 v2(157.88,144.72)
  BOTTOM w0.279: v2(158.68,124.44) 158.29,124.83 GPU1.G25
WEA1#: length 36.6
  TOP w0.14: v2(177.92,145.69) 177.92,145.93 177.78,146.07 177.3,146.07 177.06,146.31 177.06,146.66 VRAM3.L3
  TOP w0.279: v2(170.68,124.44) 170.68,124.58 v1(171.02,124.91)
  L4 w0.165: 178.41,141.44 178.41,141.75 177.95,142.21 177.95,143.37 178.28,143.69 178.42,143.69 178.71,143.99 178.71,144.48 178.21,144.98 177.92,145.28 v2(177.92,145.69)
  L4 w0.267: 178.41,141.44 178.41,141.43 178.41,141.15 178.17,140.92 178.17,140.89 177.68,140.39 177.68,140.05 177.4,139.77 176.83,139.77 176.55,139.49 176.55,138.93 176.83,138.65 177.4,138.65 177.68,138.37 177.68,137.87 176.55,136.74 175.97,136.74 175.69,137.02 175.69,137.81 175.41,138.09 174.93,138.09 174.47,137.63 174.47,137.19 174.19,136.91 173.74,136.91 171.21,134.37 171.21,130.84 171.22,130.83 171.22,130.35 170.78,129.91 170.78,127.52 169.96,126.69 169.96,125.97 170.38,125.55 170.38,124.57 170.51,124.44 v2(170.68,124.44)
  BOTTOM w0.14: v2(177.92,145.69) 177.92,145.31 177.52,144.91 177.51,144.91 177.19,144.6 VRAM4.L3
  BOTTOM w0.279: v2(170.68,124.44) 170.29,124.05 GPU1.H10
WHITE_LED_BAT: length 7.9
  TOP w0.102: R6101.2 178.78,17.87 EC6103.1 177.47,17.86 v1(177.45,17.88) 177.44,17.88 177.42,17.86 175.7,17.86 175.46,18.1 173.88,18.1 173.37,17.59 Q6103.3
WIFI_RF_EN: length 19.9
  TOP w0.102: v2(165.81,31.44) 165.78,31.46 164.9,31.46 164.31,30.87 164.31,30.4 163.21,29.3 KBC24.82
  BOTTOM w0.102: v2(165.81,31.44) 168.66,31.44 v1(168.74,31.51) 168.92,31.7 WLAN1.20
WLAN_ACT: length 8
  TOP w0.14: C5807.1 186.19,40.96 186.76,41.53 v2(186.76,41.57)
  BOTTOM w0.14: v2(186.76,41.57) 186.89,41.7 WLAN1.3 190.56,41.7 191.73,42.87 191.73,44.01 TP5801.1
XO_IN: length 1.5
  TOP w0.14: TP7516.1 160.09,111.45 v2(160.28,111.64)
  BOTTOM w0.14: v2(160.28,111.64) 160.69,112.04 GPU1.AC22
XTALIN: length 8.6
  BOTTOM w0.14: X7503.1 154.79,101.3 154.79,102.39 155.33,102.94 R7727.1 ; C7730.1 R7727.1 ; R7727.1 155.33,103.36 156.65,104.68 156.65,105.68 GPU1.AM28
XTALOUT: length 7.5
  BOTTOM w0.14: GPU1.AK28 155.89,106.97 155.52,106.6 155.52,106.11 156.16,105.47 156.16,104.96 R7727.2 C7729.1 153.55,102.67 153.66,102.57 X7503.3
N209551934: length 2.9
  BOTTOM w0.102: WLAN1.46 179.2,21.3 179.2,21.3 178.74,21.3 178.46,21.02 TP5804.1
N209551965: length 2.5
  BOTTOM w0.102: TP5803.1 178.79,21.81 178.84,21.76 179.35,21.76 179.69,22.1 WLAN1.44

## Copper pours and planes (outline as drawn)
5V_PWR on BOTTOM: 138.15,10.2 138.12,10.23 129.87,10.23 129.74,10.36 129.74,21.35 130.17,21.79 137.34,21.79 137.49,21.63 137.49,12.39 138.99,10.89 138.99,10.28 138.91,10.2 ; 1 cut-out
5V_S0 on TOP: 133.78,2.48 132.51,3.75 132.51,5.2 132.37,5.34 132.37,6.05 132.47,6.15 140.79,6.15 142.58,7.94 161.37,7.94 163.53,10.1 167.71,10.1 169.36,11.75 178,11.75 179.02,10.74 179.02,8.96 178.76,8.7 178.38,8.7 178,9.09 177.62,9.09 176.98,9.72 173.43,9.72 172.67,8.96 171.02,8.96 164.54,2.48 ; 8 cut-outs
5V_S0 on TOP: 45.39,2.76 45.39,6.2 45.44,6.24 51.05,6.24 52.3,5 52.3,3.17 51.89,2.76
5V_S0 on TOP: 24.33,77.41 23.95,77.79 23.44,77.79 23.31,77.92 23.31,78.55 23.44,78.68 24.58,78.68 25.91,77.36 25.91,75.91 25.63,75.63 24.53,75.63 24.33,75.84 ; 2 cut-outs
5V_S0 on TOP: 188.8,6.55 188.54,6.8 188.54,15.56 193.75,20.77 193.75,25.47 193.51,25.71 193,25.71 192.46,25.16 192.46,24.89 192.33,24.76 191,24.76 190.91,24.85 190.91,25.46 190.87,25.51 190.87,28.35 190.34,28.88 190.34,38.65 186.54,42.45 186.54,59.39 187.65,60.5 187.65,69.38 190.85,72.59 193.83,72.59 194.03,72.79 194.03,74.26 194.08,74.31 194.99,74.31 194.99,72.74 195.15,72.59 195.78,72.59 196.54,73.35 196.92,73.35 197.3,72.97 197.3,72.59 196.8,72.08 196.16,72.08 195.78,71.7 195.78,69.13 191.03,64.38 191.03,58.7 190.52,58.19 190.52,46.85 195.11,42.27 195.11,32.36 195.15,32.33 195.15,32.3 195.63,31.82 195.96,31.82 195.96,31.82 196.42,31.82 196.7,31.54 196.7,28.52 196.03,27.86 196.03,18.23 192.1,14.29 192.1,7.18 191.46,6.55 ; 7 cut-outs
5V_S0 on BOTTOM: 197.31,28.26 197.3,28.27 193.67,28.27 193.11,28.83 193.11,31.44 193.49,31.82 197.43,31.82 197.43,28.26
5V_S0 on BOTTOM: 190.19,6.55 190.07,6.67 190.07,8.2 190.19,8.32 191.72,8.32 191.97,8.07 191.97,6.67 191.84,6.55
5V_S0 on BOTTOM: 45.73,11.54 43,14.27 43,16.78 37.11,22.67 30.25,22.67 29.64,22.06 27.15,22.06 26.54,22.67 25.85,22.67 25.6,22.42 24.2,22.42 23.95,22.17 23.67,22.17 23.39,22.45 23.39,23.82 23.77,24.2 27.4,24.2 28.06,23.54 28.57,23.54 29.23,24.2 38.91,24.2 45.54,17.57 45.54,17.57 48.89,14.22 48.89,6.93 50.21,5.61 51.64,5.61 52.65,4.59 53.72,4.59 55.75,6.62 75.16,6.62 75.21,6.57 75.21,6.55 78,3.75 129.49,3.75 130.88,5.15 137.11,5.15 137.74,4.51 137.74,2.86 136.34,1.47 49.02,1.47 45.73,4.75 ; 2 cut-outs
5V_S0 on L3: 176.73,7.43 173.68,7.43 172.92,8.2 168.35,8.2 167.97,7.82 165.94,7.82 164.41,9.34 164.41,9.85 164.54,9.97 167.21,9.97 167.59,10.36 180.29,10.36 182.57,8.07 186.38,8.07 187.53,9.21 190.95,9.21 191.84,8.32 191.84,6.55 191.59,6.29 191.08,6.29 188.41,3.62 180.54,3.62
5V_S0 on L3: 24.08,22.17 24.9,22.99 24.9,33.91 32.2,41.22 32.2,46.55 38.68,53.03 38.68,63.7 37.54,64.84 32.46,64.84 31.82,65.47 31.82,70.55 25.6,76.78 24.33,76.78 23.82,76.27 23.82,75.25 29.54,69.54 29.54,65.22 31.19,63.57 34.36,63.57 36.65,61.28 36.65,55.82 29.66,48.84 29.66,41.34 22.68,34.36 22.68,22.42 22.93,22.17
5V_S0 on L4: 24.2,76.27 24.2,75.81 24.38,75.63 26.21,75.63 27.63,77.06 27.63,84.52 28.78,85.67 28.78,89.86 27.63,91 27.63,91.76 27.89,92.02 35.76,92.02 36.52,92.78 36.52,93.54 36.14,93.92 26.36,93.92 25.73,93.29 25.73,77.79
5V_S5 on TOP: 132.48,7.56 132.4,7.64 132.4,10.61 132.68,10.89 140.13,10.89 140.54,10.48 140.54,7.94 140.15,7.56 ; 3 cut-outs
5V_S5 on TOP: 174.01,19.78 173.51,19.78 172.64,18.91 171.17,18.91 170.56,18.31 170.56,17.75 169.95,17.14 169.59,17.14 169.39,17.34 169.39,17.75 169.29,17.85 168.98,17.85 168.83,17.7 168.83,16.83 169.49,16.17 169.8,16.17 171.17,17.54 171.17,17.95 171.52,18.31 173.2,18.31 174.06,19.17 174.06,19.73
5V_S5 on TOP: 32.64,34.26 36.85,34.26 37.11,34 37.11,31.87 37.11,31.87 37.11,29.99 36.7,29.58 32.59,29.58 32.54,29.63 32.54,31.21 34.21,31.21 34.31,31.31 34.31,32.63 34.01,32.94 32.59,32.94 32.54,32.99 32.54,34.15
5V_S5 on BOTTOM: 78.56,4.01 75.51,7.05 59.64,7.05 56.67,10.02 56.67,12.56 53.87,15.36 48.3,15.36 39.15,24.51 39.11,24.51 35.08,28.55 35.08,32.83 35.68,33.44 40,33.44 41.22,32.22 41.22,28.52 41.54,28.2 42.83,28.2 49.78,21.25 56.51,21.25 58.44,19.32 61.54,19.32 64.84,16.02 64.84,12.01 65.2,11.65 76.46,11.65 79.24,8.87 118.53,8.87 119.07,8.32 126.06,8.32 127.71,9.97 150.19,9.97 152.52,7.64 152.52,5.61 151.56,4.64 149.63,4.64 149.48,4.79 149.48,5.79 149.47,5.8 149.47,6.17 149.17,6.47 147.39,6.47 146.87,5.94 139.52,5.94 138.96,5.38 130.6,5.38 129.23,4.01 ; 3 cut-outs
+3V_1D5V_AVDD on TOP: 31.32,4.51 31.19,4.64 31.19,5.02 31.32,5.15 31.95,5.15 32.33,5.53 33.09,5.53 33.73,6.16 33.86,6.16 33.98,6.04 33.98,4.64 33.86,4.51 ; 1 cut-out
+5V_PVDD on TOP: 39.14,2.05 39.04,2.15 39.04,3.17 38.89,3.32 38.4,3.32 38.32,3.24 35.76,3.24 35.63,3.37 34.74,3.37 34.19,3.93 34.19,5.99 35,6.8 35.15,6.8 35.15,6.14 34.74,5.73 34.74,5.33 35.05,5.02 35.38,5.02 35.5,4.9 35.51,4.9 35.68,4.72 37.44,4.72 37.71,5 37.71,6.12 36.93,6.9 36.93,8.17 36.95,8.19 37.11,8.19 37.13,8.16 37.13,7.44 37.13,7.43 37.13,7.18 40.17,4.13 42.94,4.13 43.03,4.22 43.03,6.14 43.17,6.29 44.9,6.29 44.9,2.68 44.32,2.1 39.85,2.1 39.8,2.05 ; 7 cut-outs
GND on TOP: 130.4,6.37 130.38,6.39 130.38,7.28 130.4,7.31 140.54,7.31 140.54,6.55 140.36,6.37 ; 7 cut-outs
GND on TOP: 36.8,29.43 34.87,29.43 34.67,29.23 34.67,28.47 34.87,28.26 36.8,28.26 37.06,28.52 37.06,29.18
GND on TOP: 95.2,85.67 94.94,85.92 94.94,86.3 95.45,86.81 95.45,87.57 95.96,88.08 96.21,88.08 96.59,87.7 97.61,87.7 97.86,87.95 98.37,87.95 98.5,87.83 98.5,87.44 98.24,87.19 97.86,87.19 97.61,86.94 97.61,86.17 97.1,85.67 ; 4 cut-outs
GND on TOP: 125.42,28.26 125.3,28.39 125.3,30.29 125.17,30.42 123.9,30.42 123.77,30.55 123.77,33.22 123.9,33.34 125.42,33.34 125.93,32.83 128.34,32.83 129.36,31.82 129.36,30.07 129.33,30.04 128.42,30.04 128.32,29.94 128.32,29 127.58,28.26 ; 1 cut-out
GND on TOP: 157.68,117.16 157.43,117.42 156.54,117.42 156.03,117.92 156.03,120.59 156.16,120.72 156.41,120.72 156.66,120.46 156.66,120.08 156.92,119.83 157.43,119.83 158.32,120.72 158.7,120.72 158.82,120.59 158.82,119.32 158.57,119.07 158.57,117.92 158.82,117.67 158.82,117.29 158.7,117.16 ; 8 cut-outs
GND on TOP: 161.36,105.99 160.22,107.13 160.22,107.76 160.35,107.89 160.73,107.89 161.11,107.51 162.48,107.51 162.84,107.87 162.84,108.78 162.99,108.93 163.6,108.93 163.7,108.83 163.7,107.31 163.35,106.95 163.35,106.39 162.94,105.99 ; 1 cut-out
GND on TOP: 194.05,104.34 193.8,104.59 193.8,109.46 193.82,109.47 193.82,110.75 194.46,111.4 195.83,111.4 196.16,111.07 196.16,104.59 195.91,104.34
GND on TOP: 99.51,121.48 99.39,121.61 98.12,121.61 97.99,121.73 97.99,126.81 97.74,127.07 94.94,127.07 94.82,127.2 94.82,130.47 95.17,130.83 97.91,130.83 101.93,126.81 101.93,121.61 101.8,121.48 ; 1 cut-out
GND on TOP: 119.33,108.4 119.07,108.65 119.07,112.13 118.13,113.07 118.13,114.37 118.39,114.62 120.47,114.62 122.76,112.34 122.76,108.53 122.63,108.4
GND on TOP: outline of 87 points within 158.44,105.48 174.19,124.15 ; 25 cut-outs
GND on TOP: 153.74,107.26 153.49,107.51 153.49,107.76 153.62,107.89 153.87,107.89 154.25,108.27 156.28,108.27 156.79,108.78 158.44,108.78 158.57,108.65 158.57,107.89 158.32,107.64 157.43,107.64 157.05,107.26 ; 4 cut-outs
GND on TOP: 51.76,68.29 51.97,68.5 53.24,68.5 53.24,66.44 53.03,66.24 52.07,66.24 51.76,66.54
GND on TOP: 93.04,80.21 92.91,80.33 92.91,81.22 93.04,81.35 99.39,81.35 99.51,81.48 99.51,82.11 99.39,82.24 96.34,82.24 95.58,83 94.56,83 94.18,82.62 94.05,82.62 93.67,83 91.64,83 91.51,83.13 91.51,84.27 91.64,84.4 93.42,84.4 93.93,83.89 96.09,83.89 96.59,83.38 100.02,83.38 100.28,83.13 100.28,80.84 100.02,80.59 94.05,80.59 93.67,80.21 ; 7 cut-outs
GND on TOP: 107.01,75.25 106.88,75.38 106.25,75.38 106.12,75.51 106.12,77.16 106.25,77.28 107.39,77.28 107.52,77.16 107.52,75.38 107.39,75.25 ; 2 cut-outs
GND on TOP: 13.41,69.54 13.28,69.66 13.28,69.9 13.33,69.97 13.36,70.05 13.3,71.27 12.23,71.86 9.63,71.86 9.55,71.9 9.4,72.73 8.73,73.06 7.03,73.06 6.36,72.73 6.21,71.9 6.13,71.86 2.7,71.86 2.52,72.05 2.52,73.25 3.38,74.11 11.63,74.11 12.01,73.73 14.68,73.73 14.69,73.72 14.7,73.73 15.26,73.73 16.43,74.9 23.34,74.9 29.39,68.85 29.39,62.96 28.88,62.45 23.7,62.45 16.58,69.56 15.21,69.56 15.19,69.54
GND on TOP: 189.79,79.54 193.32,83.08 193.32,84.27 193.72,84.68 195.88,84.68 196.54,84.02 196.54,83.38 194.26,81.09 192.99,81.09 192.73,80.84 192.73,79.06 193.24,78.55 193.24,76.78 193.49,76.52 196.16,76.52 196.31,76.37 196.31,75.02 196.06,74.77 193.83,74.77 193.72,74.67 193.72,72.81 190.47,72.81 189.79,73.5 ; 2 cut-outs
GND on TOP: 94.18,89.22 94.05,89.35 94.05,89.98 93.8,90.24 93.8,90.75 94.05,91 95.83,91 96.21,90.62 96.21,89.6 96.09,89.48 94.94,89.48 94.69,89.22 ; 3 cut-outs
GND on TOP: 104.47,76.52 104.34,76.65 104.34,77.28 104.21,77.41 103.83,77.41 103.71,77.54 100.53,77.54 100.4,77.41 96.72,77.41 96.47,77.67 92.78,77.67 92.4,77.28 92.4,76.78 92.28,76.65 91.89,76.65 91.77,76.78 91.77,77.41 90.88,78.3 90.88,78.94 91.01,79.06 91.39,79.06 91.77,78.68 92.53,78.68 92.78,78.43 93.16,78.43 93.67,78.94 104.21,78.94 104.34,78.81 104.34,78.55 105.1,77.79 105.1,76.78 104.85,76.52 ; 13 cut-outs
GND on TOP: 94.56,15.69 94.18,16.07 94.18,18.48 100.53,18.48 100.78,18.23 100.78,16.32 100.53,16.07 99.64,16.07 99.26,15.69 ; 2 cut-outs
GND on TOP: 103.45,118.31 103.2,118.56 103.2,125.93 105.23,127.96 108.79,127.96 109.42,128.59 110.06,128.59 110.18,128.47 110.18,124.02 110.06,123.89 107.39,123.89 106.75,124.53 105.86,124.53 105.61,124.27 105.61,123.26 105.86,123 106.75,123 106.88,122.88 106.88,119.83 106.75,119.7 105.86,119.7 105.61,119.45 105.61,118.56 105.36,118.31
GND on TOP: 101.42,83.13 100.66,83.89 100.66,84.78 100.4,85.03 99.64,85.03 99.51,85.16 99.51,85.54 99.64,85.67 101.8,85.67 101.93,85.79 101.93,86.17 102.05,86.3 102.44,86.3 102.69,86.05 102.69,84.78 102.31,84.4 102.31,83.38 102.05,83.13 ; 4 cut-outs
GND on TOP: 201.62,125.24 201.5,125.37 201.5,132.91 201.37,133.04 198.7,133.04 198.57,133.16 198.57,134.18 198.7,134.31 199.59,134.31 199.84,134.56 199.84,135.07 199.46,135.45 198.57,135.45 196.42,133.29 191.59,133.29 190.57,134.31 190.57,144.72 190.57,144.72 190.57,151.33 190.83,151.58 190.83,154.67 189.6,155.9 188.41,155.9 188.29,155.77 169.57,155.77 169.54,155.8 167.76,156.71 165.94,155.89 165.94,154.25 165.05,153.36 150.44,153.36 144.35,147.26 144.35,145.23 143.84,144.72 142.19,144.72 141.42,145.48 141.42,150.44 143.08,152.09 143.08,156.53 143.33,156.79 145.11,156.79 145.14,156.83 145.19,156.86 145.48,156.96 145.72,157.14 153.42,157.14 153.55,157.1 154.03,156.55 154.6,156.39 163.48,156.39 164.05,156.55 164.53,157.1 164.66,157.14 191.2,157.14 191.37,157.07 191.44,156.9 191.44,146.7 191.72,145.74 192.48,145.09 192.83,144.98 193.2,144.94 197.93,144.94 199.04,143.82 200.8,143.82 202.11,142.51 202.11,140.4 202.94,139.57 202.94,137.65 202.94,137.65 202.94,136.39 202.94,136.39 202.94,134.84 202.21,134.11 202.21,125.29 202.16,125.24 ; 7 cut-outs
GND on TOP: 35.18,21 31.32,21 31.16,21.15 31.16,22.01 31.57,22.42 38.07,22.42 38.63,21.86 38.63,19.07 38.07,18.51 37.26,18.51 37.21,18.56 37.21,20.95 37.01,21.15 35.33,21.15
GND on TOP: 173.3,153.36 173.17,153.48 173.17,154.75 173.43,155.01 179.65,155.01 180.64,154.02 180.64,150.36 180.57,150.28 180.39,150.28 180.29,150.39 179.32,150.39 179.19,150.26 178.99,150.26 178.86,150.39 178.86,150.92 179.8,151.86 179.8,153.36 179.68,153.48 178.89,153.48 178.76,153.36 ; 5 cut-outs
GND on TOP: 78.76,10.03 78.76,14.01 79,14.24 84.05,14.24 84.4,13.89 84.4,9.92 84.1,9.62 79.18,9.62 ; 8 cut-outs
GND on TOP: 78.18,95.83 78.05,95.95 78.05,97.1 78.31,97.35 82.62,97.35 82.88,97.1 82.88,96.21 82.5,95.83 ; 4 cut-outs
GND on TOP: 186.75,28.92 186.49,29.19 186.49,31.44 186.68,31.63 189.87,31.63 190.05,31.46 190.05,29.14 189.82,28.92 ; 1 cut-out
GND on TOP: 162.76,115.89 162.63,116.02 162.63,116.53 162.38,116.78 162.13,116.78 161.74,116.4 161.49,116.4 161.24,116.65 161.24,116.91 161.62,117.29 161.62,117.54 161.24,117.92 161.24,120.59 160.98,120.85 160.98,121.35 161.11,121.48 161.49,121.48 161.62,121.35 161.62,120.85 161.87,120.59 162.25,120.59 162.51,120.34 162.51,119.83 162.63,119.7 163.14,119.7 163.27,119.58 163.27,116.02 163.14,115.89 ; 6 cut-outs
GND on TOP: 24.2,22.06 23.39,22.06 22.93,22.52 18.77,22.52 18.41,22.88 17.35,22.88 16.89,23.33 14.65,23.33 13.69,22.37 13.69,21.76 13.89,21.56 13.89,20.59 13.59,20.29 13.59,19.17 13.69,19.07 13.69,18.2 12.88,17.39 3.12,17.39 3.12,15.87 3.22,15.77 14.04,15.77 17.8,12.01 22.12,12.01 24.51,14.39 24.51,20.24 24.1,20.64 24.1,21.4 24.41,21.71 24.41,21.86
GND on TOP: 184.73,40.58 184.1,41.22 184.1,42.03 183.08,43.05 183.08,44.26 183.07,44.27 183.07,45.03 183.45,45.41 186.13,45.41 186.13,45.4 186.37,45.15 186.37,42.68 185.55,41.86 185.55,40.89 185.24,40.58 ; 1 cut-out
GND on TOP: 18.26,45.33 18.26,44.77 18.41,44.62 18.57,44.62 18.87,44.31 18.87,42.89 19.02,42.74 20.5,42.74 20.7,42.54 22.07,42.54 23.34,41.27 28.47,41.27 28.73,41.52 28.73,47.26 29.33,47.87 29.33,48.79 29.23,48.89 27.56,48.89 27.38,48.71 27.38,44.75 26.13,43.5 21.05,43.5 11.05,53.51 2.51,53.51 2.51,52.39 1.7,51.58 0.79,51.58 0.79,50.82 0.89,50.72 2.97,50.72 3.63,51.38 8.2,51.38 8.71,51.88 9.78,51.88 10.59,51.07 10.59,49.34 14.3,49.34 15.06,48.58 15.06,47.21 15.31,46.96 16.63,46.96
GND on TOP: 165.68,10.36 165.43,10.61 165.43,11.63 165.68,11.88 167.59,11.88 167.84,11.63 167.84,10.48 167.71,10.36 ; 1 cut-out
GND on TOP: 79.19,99.76 79.07,99.89 79.07,101.03 79.32,101.29 83.89,101.29 84.02,101.16 84.02,99.89 83.89,99.76 ; 5 cut-outs
GND on TOP: 180.63,25.06 180.51,25.18 180.51,25.91 180.58,25.98 183.11,25.98 183.27,25.82 183.27,25.25 183.08,25.06 ; 1 cut-out
GND on TOP: outline of 177 points within 6.2,84.9 132.41,157.14 ; 7 cut-outs
GND on TOP: 172.41,98.37 172.03,98.75 172.03,100.4 173.3,101.67 182.7,101.67 182.95,101.41 182.95,100.02 181.43,98.49 174.44,98.49 174.32,98.37 ; 7 cut-outs
GND on TOP: 133.68,28.26 133.55,28.39 133.55,29.41 133.3,29.66 133.04,29.66 132.66,30.04 130.5,30.04 130.38,30.17 130.38,30.68 132.92,33.22 136.22,33.22 136.34,33.09 136.34,28.52 136.09,28.26 ; 2 cut-outs
GND on TOP: 94.26,133.01 97.08,133.01 97.43,132.66 97.43,131.56 97.03,131.16 94.28,131.16 94.18,131.26 94.18,132.94
GND on TOP: 49.33,77.82 48.92,78.23 48.92,81.13 49.25,81.46 49.48,81.46 49.48,81.48 49.98,81.98 50.24,81.98 50.49,81.73 50.49,81.4 50.47,81.38 50.47,78.29 50.1,77.92 50.1,76.18 50.01,76.09 49.4,76.09 49.33,76.16 ; 2 cut-outs
GND on TOP: 44.52,72.59 44.27,72.84 44.27,74.11 44.6,74.44 46.48,74.44 46.52,74.4 46.52,72.81 46.3,72.59
GND on TOP: outline of 201 points within 19.17,0.76 203.09,113.61 ; 35 cut-outs
GND on TOP: 16.71,25.47 16.46,25.72 16.46,26.84 16.61,26.99 20.11,26.99 20.37,27.25 22.53,27.25 24.15,28.87 29.59,28.87 30.2,29.48 31.77,29.48 31.82,29.43 31.82,28.57 31.77,28.52 30.25,28.52 30,28.26 30,27.7 30.15,27.55 31.32,27.55 31.47,27.4 31.47,27.09 31.37,26.99 31.37,25.82 31.27,25.72 30.96,25.72 30.35,26.33 27.61,26.33 27,26.94 24.05,26.94 23.54,26.43 21.83,26.43 21.68,26.28 21.68,26.27 21.08,25.67 17.45,25.67 17.24,25.47 ; 6 cut-outs
GND on TOP: 155.9,82.49 155.52,82.87 155.52,89.1 155.78,89.35 161.36,89.35 161.62,89.1 161.62,86.05 160.22,84.65 160.22,82.62 160.09,82.49
GND on TOP: 90.24,84.52 89.99,84.78 89.99,86.68 89.74,86.94 87.96,86.94 87.7,87.19 87.7,89.73 87.96,89.98 91.39,89.98 91.64,89.73 91.64,84.78 91.39,84.52 ; 7 cut-outs
GND on TOP: 13.84,30.6 13.69,30.75 13.69,32.02 12.93,32.78 3.12,32.78 3.12,34 2.31,34.82 0.79,34.82 0.79,35.42 0.89,35.53 2.92,35.53 3.63,34.82 8.25,34.82 8.76,34.31 9.78,34.31 10.54,35.07 10.54,36.85 14.3,36.85 15.06,37.61 15.06,38.68 14.3,39.44 10.64,39.44 10.54,39.54 10.54,46.7 10.59,46.75 11.15,46.75 11.3,46.6 11.3,41.83 12.27,40.86 15.26,40.86 16.58,39.54 20.65,39.54 24.71,35.48 24.71,33.6 25.22,33.09 31.82,33.09 31.93,32.99 31.93,32.33 31.77,32.17 30.25,32.17 29.59,31.51 23.8,31.51 23.19,30.9 14.7,30.9 14.4,30.6
GND on TOP: 110.44,12.39 110.31,12.51 110.31,16.83 110.44,16.96 112.09,16.96 112.34,16.71 112.34,12.64 112.09,12.39 ; 5 cut-outs
GND on TOP: 130.63,123 130.5,123.13 130.5,126.94 130.63,127.07 134.06,127.07 134.31,126.81 134.31,124.91 132.41,123 ; 3 cut-outs
GND on TOP: 34.43,42.31 34.17,42.57 34.17,46.08 34.62,46.53 36.93,46.53 37.54,45.92 37.54,43.12 36.73,42.31 ; 10 cut-outs
GND on TOP: 101.55,133.16 101.42,133.29 101.42,133.55 101.55,133.67 102.69,133.67 104.34,135.32 104.34,137.74 104.47,137.86 108.4,137.86 108.66,137.61 108.66,134.69 108.53,134.56 107.52,134.56 107.01,134.05 106.25,134.05 105.99,133.8 103.58,133.8 102.94,133.16 ; 9 cut-outs
GND on TOP: 3.25,75.51 2.99,75.76 2.99,76.21 3.23,76.6 3.31,77.05 3.31,77.59 7.39,77.59 7.95,77.03 8.96,77.03 9.73,77.79 9.73,80.79 9.83,80.89 10.51,80.89 11.96,79.44 13.92,79.44 14.04,79.32 14.04,77.92 12.9,76.78 11.5,76.78 10.23,75.51
GND on TOP: 165.94,115.26 164.79,116.4 164.79,116.53 165.05,116.78 165.17,116.78 165.43,117.04 165.43,117.54 164.79,118.18 164.79,118.31 165.05,118.56 165.3,118.56 165.43,118.69 165.43,119.45 165.17,119.7 164.92,119.7 164.79,119.83 164.79,120.21 164.54,120.46 164.54,121.48 164.67,121.61 165.68,121.61 166.32,120.97 166.32,115.51 166.06,115.26 ; 4 cut-outs
GND on TOP: 97.74,70.43 97.48,70.68 97.48,71.7 96.72,72.46 96.72,73.09 96.85,73.22 97.37,73.22 97.99,72.6 99.06,72.6 99.44,72.22 99.44,70.86 99.01,70.43
GND on BOTTOM: 11.05,53.51 2.51,53.51 2.51,52.39 1.75,51.63 0.79,51.63 0.79,50.82 0.89,50.72 2.92,50.72 3.58,51.38 8.2,51.38 8.71,51.88 9.78,51.88 10.54,51.12 10.54,49.34 14.3,49.34 15.06,48.58 15.06,47.41 14.3,46.65 13.59,46.65 13.38,46.45 13.38,44.26 14.09,43.55 17.65,43.55 18.77,42.44 25.63,42.44 25.88,42.69 25.88,43.3 25.68,43.5 21.05,43.5
GND on BOTTOM: 198.19,74.49 197.3,75.38 197.3,78.05 197.81,78.55 202.77,78.55 203.09,78.23 203.09,74.49
GND on BOTTOM: 21.66,87.7 20.19,87.7 19.84,87.34 19.84,86.78 20.09,86.53 22.12,86.53 22.68,85.97 22.68,85.56 22.73,85.51 23.34,85.51 23.59,85.26 25.88,85.26 26.24,85.62 26.24,86.38 26.49,86.63 26.85,86.63 27,86.78 27,87.34 26.85,87.49 26.19,87.49 25.12,86.43 22.93,86.43
GND on BOTTOM: 126.57,28.64 125.42,29.79 125.42,33.09 125.8,33.47 128.22,33.47 128.85,32.83 128.85,29.41 128.09,28.64
GND on BOTTOM: 0.89,35.53 2.92,35.53 3.63,34.82 8.25,34.82 8.76,34.31 9.78,34.31 10.54,35.07 10.54,36.85 14.3,36.85 15.06,37.61 15.06,38.68 14.3,39.44 10.59,39.44 10.59,46.7 10.64,46.75 11.3,46.75 11.4,46.65 11.4,44.77 11.25,44.62 11.25,41.62 11.71,41.17 12.67,41.17 13.84,42.33 15.52,42.33 15.87,41.98 15.87,40.71 16.48,40.1 16.48,39.69 16.84,39.34 23.95,39.34 24.61,38.68 24.61,37.05 27.51,34.15 33.3,34.15 34.21,33.24 34.21,29.02 36.8,26.43 36.8,24.91 36.6,24.71 34.36,24.71 34.06,25.01 34.06,25.87 33.96,25.98 33.96,26.13 34.06,26.23 34.06,26.64 33.35,27.35 31.57,27.35 31.32,27.09 31.06,27.09 30.96,27.2 30.96,27.91 29.84,29.02 21.41,29.02 20.7,28.31 20.7,27.3 20.44,27.04 18.46,27.04 17.55,27.96 15.77,27.96 15.52,28.21 15.52,29.02 15.16,29.38 14.25,29.38 13.69,29.94 13.69,32.02 12.93,32.78 3.12,32.78 3.12,34.05 2.41,34.76 0.84,34.76 0.79,34.82 0.79,35.42
GND on BOTTOM: 166.84,9.83 165.43,11.24 165.43,12.64 165.81,13.02 165.93,13.02 165.94,13.02 169.48,13.02 169.7,12.8 169.7,10.05 169.47,9.83
GND on BOTTOM: 80.08,95.83 79.7,96.21 77.54,96.21 77.42,96.33 77.42,97.1 77.67,97.35 82.62,97.35 83.26,96.72 83.26,95.95 83.13,95.83 ; 3 cut-outs
GND on BOTTOM: 181.05,123.64 180.79,123.89 180.79,125.16 180.92,125.29 183.21,125.29 183.72,124.78 183.72,124.02 183.33,123.64 ; 4 cut-outs
GND on BOTTOM: 95.7,15.82 95.45,16.07 95.45,17.61 95.31,17.75 94.81,17.75 94.7,17.87 94.7,18.51 94.85,18.66 100.86,18.66 101.04,18.48 101.04,15.94 100.91,15.82
GND on BOTTOM: 189.96,46.55 186.76,46.55 186.76,43.91 187.83,42.84 189.1,42.84 189.25,42.99 189.25,43.96 189.46,44.16 190.02,44.16 190.02,46.5
GND on BOTTOM: 141.55,144.34 141.42,144.47 141.42,150.44 143.08,152.09 143.08,156.53 143.33,156.79 145.11,156.79 145.14,156.83 145.19,156.86 145.48,156.96 145.72,157.14 153.42,157.14 153.55,157.1 154.03,156.55 154.6,156.39 163.48,156.39 164.05,156.55 164.53,157.1 164.66,157.14 191.2,157.14 191.37,157.07 191.44,156.9 191.44,149.55 191.31,149.42 190.86,149.42 190.73,149.55 190.73,154.04 190.57,154.2 190.07,154.2 189.23,153.36 182.95,153.36 182.32,153.99 180.79,153.99 180.54,154.25 178.25,154.25 178,153.99 178,153.48 177.87,153.36 172.92,153.36 172.41,152.85 172.41,150.56 171.27,149.42 165.3,149.42 163.9,150.82 163.9,153.48 163.52,153.87 161.87,153.87 161.36,153.36 158.32,153.36 158.19,153.48 158.19,153.87 157.68,154.37 156.66,154.37 156.28,153.99 156.28,153.48 156.16,153.36 148.54,153.36 148.03,152.85 148.03,147.01 145.36,144.34 ; 43 cut-outs
GND on BOTTOM: 102.46,80.35 102.36,80.45 101.93,80.45 101.86,80.38 101.19,80.38 101.15,80.43 100.84,80.43 100.79,80.38 100.43,80.38 100.31,80.5 99.9,80.5 99.78,80.38 99.42,80.38 99.27,80.53 98.91,80.53 98.76,80.38 98.45,80.38 98.3,80.53 97.89,80.53 97.74,80.38 97.43,80.38 97.31,80.5 96.85,80.5 96.73,80.38 96.39,80.38 96.27,80.5 95.86,80.5 95.74,80.38 95.43,80.38 95.28,80.53 94.89,80.53 94.75,80.38 94.46,80.38 94.32,80.53 93.88,80.53 93.73,80.38 93.52,80.38 93.4,80.51 93.4,80.93 93.7,81.23 100.98,81.23 101.47,81.72 101.7,81.72 101.96,81.47 102.09,81.47 102.72,80.84 102.72,80.83 102.82,80.73 102.82,80.45 102.72,80.35
GND on BOTTOM: 79.07,9.34 76.45,11.96 65.4,11.96 65.15,12.21 65.15,15.77 65.81,16.43 65.81,19.17 66.47,19.83 73.63,19.83 75.56,17.9 75.56,13.33 75.77,13.12 76.88,13.12 77.34,12.67 77.34,12.52 84.15,12.52 84.4,12.27 84.4,9.59 84.15,9.34
GND on BOTTOM: 161.11,73.22 160.98,73.35 160.98,74.24 160.47,74.74 159.2,74.74 159.2,77.16 159.33,77.28 165.17,77.28 166.06,76.4 166.06,73.35 165.94,73.22 ; 1 cut-out
GND on BOTTOM: 152.28,34.23 152.25,34.27 152.25,34.76 152.38,34.9 152.79,34.9 152.94,35.06 152.94,35.97 153.14,36.16 154.66,36.16 154.79,36.02 154.79,35.06 153.96,34.23 ; 2 cut-outs
GND on BOTTOM: 115.94,12.24 115.68,12.5 115.68,15.65 115.85,15.82 119.33,15.82 119.58,15.56 119.58,14.17 120.34,13.4 120.34,12.9 119.71,12.26 119.32,12.26 119.3,12.24
GND on BOTTOM: outline of 104 points within 5.49,90.49 96.62,157.14 ; 10 cut-outs
GND on BOTTOM: 167.86,117.02 165.3,119.58 165.3,119.73 165.45,119.87 165.6,119.87 168.15,117.32 168.15,117.18 167.99,117.02
GND on BOTTOM: outline of 124 points within 88.85,76.11 104.72,84.9
GND on BOTTOM: outline of 226 points within 3.12,0.51 203.3,68.9 ; 10 cut-outs
GND on BOTTOM: 166.3,114.61 165.07,115.84 165.07,116.01 163.02,118.06 162.57,118.06 162.4,117.89 162.4,117.53 162.62,117.3 162.74,117.3 164.89,115.15 164.89,114.76 164.82,114.68 164.39,114.68 161.51,117.56 161.51,117.84 162.07,118.4 162.07,118.98 161.5,119.55 161.5,119.88 161.6,119.98 161.85,119.98 162.55,119.28 162.89,119.28 163.48,119.87 163.79,119.87 163.92,119.74 163.92,119.49 163.32,118.9 163.32,118.49 166.7,115.11 166.7,114.73 166.57,114.61
GND on BOTTOM: 166.24,112.61 165.29,113.55 165.29,113.93 165.43,114.06 165.65,114.06 166.25,113.46 166.69,113.46 167.33,114.1 167.57,114.1 167.73,113.93 167.73,113.49 166.84,112.61
GND on BOTTOM: 160.35,101.82 160.35,100.5 160.09,100.25 158.98,100.25 158.82,100.4 158.82,101.16 158.67,101.31 158.11,101.31 158.01,101.41 158.01,102.33 158.16,102.48 159.74,102.48 160.04,102.79 162.43,102.79 162.53,102.68 162.53,102.13 162.48,102.07 160.6,102.07
GND on BOTTOM: 119.33,108.4 119.07,108.65 119.07,112.13 118.03,113.17 118.03,114.37 118.29,114.62 120.47,114.62 122.76,112.34 122.76,108.53 122.63,108.4
GND on BOTTOM: 167.33,101.41 167.13,101.62 166.04,101.62 165.78,101.87 165.78,102.73 165.63,102.89 165.63,104 165.83,104.21 166.6,104.21 166.85,103.95 166.85,102.84 167,102.68 169.62,102.68 170,102.3 170,101.54 169.87,101.41 ; 2 cut-outs
GND on BOTTOM: 167.93,115.12 167.09,115.97 166.9,115.97 165.29,117.57 165.29,117.68 164.5,118.47 164.5,118.74 164.61,118.85 164.8,118.85 168.18,115.48 168.18,115.26 168.04,115.12
GND on BOTTOM: 95.45,87.32 95.32,87.44 95.32,87.57 95.96,88.21 100.02,88.21 100.53,88.71 101.04,88.71 101.22,88.54 101.22,87.75 100.84,87.37 100.35,87.37 99.9,87.83 99.26,87.83 98.75,87.32
GND on BOTTOM: 160.86,81.35 159.71,82.49 155.9,82.49 155.52,82.87 155.52,86.3 153.62,88.21 153.62,89.22 153.74,89.35 161.36,89.35 161.62,89.1 161.62,88.59 161.47,88.43 159.56,88.43 159.2,88.08 159.2,87.44 159.59,87.06 160.09,87.06 160.35,86.81 162,86.81 162,81.48 161.87,81.35 ; 3 cut-outs
GND on BOTTOM: 169.75,113.35 169.24,113.86 169.24,116.02 169.87,116.65 169.87,117.16 169.62,117.42 169.36,117.42 167.33,119.45 167.33,119.7 167.46,119.83 167.71,119.83 168.35,119.19 168.73,119.19 169.49,119.96 170.25,119.96 170.38,119.83 170.38,119.58 170,119.19 170,118.94 170.38,118.56 170.38,118.31 170,117.92 170,117.8 170.38,117.42 170.38,117.16 170.76,116.78 170.76,116.27 170,115.51 170,115.38 170.51,114.88 170.51,113.61 170.25,113.35
GND on BOTTOM: 100.49,83.31 100.4,83.4 100.4,83.76 100.96,84.32 100.96,84.91 99.96,85.91 99.96,86.2 100.51,86.75 100.76,86.75 101.43,86.08 102.62,86.08 102.77,85.93 102.77,84.92 102.78,84.91 102.78,84.7 102.84,84.64 102.84,83.41 102.74,83.31
GND on BOTTOM: 200.61,85.03 199.84,85.79 198.7,85.79 196.92,87.57 196.92,94.18 197.05,94.3 197.43,94.3 200.35,97.22 200.35,98.87 200.35,98.88 200.35,100.4 201.09,101.14 201.09,101.16 201.24,101.31 201.24,108.91 200.86,109.29 200.86,135.96 199.97,136.85 195.65,136.85 191.72,140.78 191.72,144.98 191.97,145.23 192.23,145.23 192.69,145.01 193.2,144.94 197.95,144.94 199.04,143.85 200.77,143.85 202.11,142.52 202.11,140.38 202.92,139.56 202.94,139.56 202.94,134.84 202.21,134.11 202.21,125.08 201.42,124.29 201.42,114.09 201.85,113.66 201.9,113.66 202.23,113.33 202.23,109.29 202.92,108.6 202.92,103.8 202.92,103.8 202.21,103.08 202.21,98.72 202.13,98.65 201.85,98.65 201.8,98.59 201.8,95.06 202.51,94.35 202.96,94.35 203.09,94.23 203.09,85.48 202.64,85.03
GND on BOTTOM: 152.68,5.61 153.03,5.25 155.37,5.25 156.54,6.42 156.54,9.16 156.33,9.36 155.57,9.36 152.68,6.47
GND on BOTTOM: 141.3,65.98 141.04,66.24 141.04,69.41 141.3,69.66 145.49,69.66 145.87,69.28 145.87,66.62 145.23,65.98
GND on BOTTOM: 97.48,89.1 97.36,89.22 97.36,90.24 97.99,90.87 98.37,90.87 98.63,90.62 99.97,90.62 100.23,90.87 100.53,90.87 100.84,91.18 100.99,91.18 101.17,91 101.17,90.87 100.15,89.86 97.99,89.86 97.86,89.73 97.86,89.22 97.74,89.1
GND on BOTTOM: 13.08,69.66 13.41,71.05 12.23,71.86 0.76,71.86 0.76,74.79 1.7,74.79 3.38,76.47 3.38,77.59 7.39,77.59 7.9,77.08 9.42,77.08 10.13,77.79 10.13,80.87 10.28,81.02 10.59,81.02 11.05,81.48 11.05,82.39 11.22,82.57 12.06,82.57 12.52,82.11 12.52,77.79 11.5,76.78 11.5,75.89 12.27,75.13 23.09,75.13 29.39,68.83 29.39,62.96 28.88,62.45 23.7,62.45 16.58,69.56 13.43,69.56 13.33,69.66
GND on BOTTOM: 151.09,9.78 151.04,9.84 151.04,13.6 151.73,14.29 152.63,14.29 153.11,13.81 153.13,13.81 153.42,13.52 153.42,9.95 153.26,9.78
GND on BOTTOM: 95.68,138.24 93.5,138.24 93.22,137.96 93.22,134.36 93.27,134.31 96.82,134.31 96.85,134.33 96.85,136.03 96.72,136.16 96.21,136.16 95.83,136.54 95.83,138.09
GND on BOTTOM: 138.63,12.9 138.5,13.02 138.5,16.32 139.51,17.33 143.68,17.33 143.87,17.15 143.87,13.16 143.61,12.9
GND on BOTTOM: 79.19,99.76 79.07,99.89 79.07,101.03 79.32,101.29 83.89,101.29 84.02,101.16 84.02,99.89 83.89,99.76 ; 4 cut-outs
GND on BOTTOM: 104.21,117.54 103.2,118.56 103.2,125.93 105.23,127.96 108.79,127.96 109.42,128.59 110.06,128.59 110.18,128.47 110.18,124.02 110.06,123.89 107.39,123.89 106.75,124.53 105.86,124.53 105.61,124.27 105.61,121.99 105.86,121.73 106.88,121.73 106.88,118.56 106.75,118.43 105.74,118.43 105.23,117.92 105.23,117.67 105.1,117.54 ; 3 cut-outs
GND on BOTTOM: outline of 93 points within 87.22,84.52 100.02,94.68
GND on BOTTOM: 180.67,127.45 180.54,127.58 180.54,128.72 180.79,128.97 183.46,128.97 183.72,128.72 183.72,128.08 183.46,127.83 182.57,127.83 182.19,127.45 ; 2 cut-outs
GND on BOTTOM: 183.41,98.42 183.08,98.75 179.02,98.75 178.76,98.49 176.86,98.49 176.73,98.37 172.29,98.37 172.16,98.49 172.16,99 172.29,99.13 175.97,99.13 178.38,101.54 186.89,101.54 187.91,100.53 187.91,84.27 186.87,83.23 183.92,83.23 183.89,83.25 183.28,83.25 183,83.53 183,96.69 183.41,97.1 ; 8 cut-outs
GND on BOTTOM: 146.25,128.47 146,128.72 146,131.26 146.12,131.39 146.89,131.39 147.01,131.26 147.01,128.72 146.76,128.47 ; 2 cut-outs
GND on BOTTOM: 84.78,115.77 84.53,116.02 84.53,119.7 84.91,120.08 88.21,120.08 88.34,119.96 88.34,117.67 89.1,116.91 89.1,116.27 88.59,115.77
GND on BOTTOM: 131.14,60.01 130.88,60.27 130.88,61.79 131.72,62.63 131.72,65.07 131.95,65.3 132.36,65.3 132.6,65.05 132.6,61.73 133.55,60.77 133.55,60.14 133.42,60.01 ; 3 cut-outs
GND on BOTTOM: 99.64,120.46 99.39,120.72 99.39,122.62 99.13,122.88 98.12,122.88 97.99,123 97.99,126.81 97.74,127.07 94.94,127.07 94.82,127.2 94.82,130.65 95.16,130.99 98.26,130.99 101.93,127.32 101.93,121.23 101.17,120.46 ; 2 cut-outs
GND on BOTTOM: 132.92,29.66 132.66,29.91 132.66,32.83 133.17,33.34 134.95,33.34 136.09,32.2 136.09,29.91 135.84,29.66
GND on BOTTOM: 130.63,122.24 130.5,122.37 130.5,126.69 130.76,126.94 131.9,126.94 132.53,127.58 132.53,128.72 134.19,128.72 134.31,128.59 134.31,123.26 133.3,122.24 ; 1 cut-out
GND on BOTTOM: 101.8,151.33 101.55,151.58 101.55,154.75 100.69,155.61 98.39,155.61 98.31,155.65 98.29,155.73 98.17,156.44 97.67,156.95 97.62,157.06 97.72,157.14 101.78,157.14 101.91,157.1 102.39,156.55 102.96,156.39 109.04,156.39 109.04,156.39 111.72,156.39 112.35,156.56 112.9,157.11 113.02,157.14 119.96,157.14 120.68,157.14 120.92,156.96 121.21,156.86 121.28,156.81 121.29,156.72 121.25,156.58 121.24,156.43 121.24,156.15 122.91,156.15 122.91,156.43 122.9,156.57 122.87,156.7 122.88,156.79 122.96,156.84 132.1,156.84 132.28,156.66 132.28,154.37 131.9,153.99 128.45,153.99 127.33,152.87 127.33,150.49 126.87,150.03 125.65,150.03 125.14,150.54 118.44,150.54 118.13,150.84 118.13,151.15 118.08,151.2 113.87,151.2 111.33,153.74 107.01,153.74 104.59,151.33
GND on BOTTOM: 74.62,103.7 75.13,104.21 75.13,106.04 75.59,106.49 78.71,106.49 79.12,106.09 79.12,101.72 78.56,101.16 78.56,100.86 77.8,100.09 75.11,100.09 74.62,100.58
GND on L2VCC: outline of 229 points within 0.51,0.51 203.34,157.39 ; 3 cut-outs
GND on L3: 49.86,87.7 46.68,90.87 42.49,90.87 40.84,89.22 37.41,89.22 36.9,89.73 36.9,91.13 36.01,92.02 27.38,92.02 26.11,93.29 13.66,93.29 11.99,91.61 10.03,91.61 9.78,91.86 9.78,94.56 8.96,95.37 7.95,95.37 7.39,94.81 3.31,94.81 3.31,96.08 6.07,96.08 6.83,96.84 6.83,97.62 47.6,97.62 49.54,97.67 51.48,97.83 51.49,97.83 51.86,97.45 52.45,96.99 53.52,96.92 56.69,97.65 56.94,97.76 57.26,97.72 57.58,97.76 61.94,98.93 62.43,99.18 62.76,99.62 63.48,101.17 63.53,101.24 63.59,101.28 64.47,101.72 65.32,102.18 65.33,102.18 79.24,115.67 84.36,134.38 84.36,156.9 84.43,157.07 84.6,157.14 95.61,157.14 95.83,156.91 95.83,155.87 95.58,155.61 88.97,155.61 86.31,152.95 86.31,150.44 85.8,149.93 85.8,134.56 87.83,132.53 87.83,120.72 89.23,119.32 89.23,115.64 88.59,115 82.62,115 77.04,109.42 77.04,104.84 78.05,103.83 78.05,101.67 75,98.62 70.43,98.62 66.05,94.24 60.72,94.24 54.18,87.7
GND on L3: 142.82,153.87 142.82,156.66 143,156.84 144.89,156.84 145.33,156.92 145.71,157.14 153.14,157.14 153.24,157.04 153.24,156.66 153.11,156.53 148.03,156.53 144.85,153.36 143.33,153.36
GND on L3: 33.7,12.92 38.07,12.92 38.78,13.63 38.78,17.44 38.07,18.15 38.07,18.76 38.48,19.17 38.78,19.17 39.85,18.1 41.37,18.1 43.76,15.71 43.76,14.55 45.69,12.62 45.69,11.5 46,11.19 46,9.01 45.13,9.01 44.47,8.35 42.03,8.35 41.32,7.64 35.79,7.64 34.77,8.65 33.75,8.65 33.4,8.3 33.4,7.54 33.3,7.43 32.74,7.43 31.21,5.91 29.74,5.91 28.88,6.77 28.88,8.09 29.28,8.5 30.66,8.5 31.27,9.11 33.14,9.11 33.55,9.52 33.55,12.77
GND on L3: outline of 216 points within 19.23,0.76 203.09,145.74 ; 1 cut-out
GND on L3: 188.29,157.14 191.2,157.14 191.37,157.07 191.44,156.9 191.44,150.03 191.34,149.93 190.95,149.93 190.83,150.06 190.83,154.12 188.16,156.79 188.16,157.01
GND on L3: outline of 113 points within 0.79,11.96 35.89,88.59
GND on L3: 121.74,153.36 121.1,153.99 121.1,155.01 120.22,155.9 99.13,155.9 98.88,156.15 98.88,157.04 98.98,157.14 101.78,157.14 101.9,157.11 102.45,156.56 103.08,156.39 111.72,156.39 112.35,156.56 112.9,157.11 113.02,157.14 120.69,157.14 121.07,156.92 121.51,156.84 131.85,156.84 132.15,156.53 132.15,153.99 131.52,153.36
GND on L4: outline of 127 points within 84.36,138.14 191.44,157.14
GND on L4: outline of 106 points within 0.76,11.96 36.52,88.41
GND on L4: 200.61,84.78 198.96,86.43 198.96,94.56 200.86,96.46 200.86,135.32 193.49,142.69 193.49,144.59 193.84,144.94 199.59,144.94 199.68,144.92 199.75,144.87 202.17,142.45 202.17,140.26 202.94,139.49 202.94,137.48 202.94,137.48 202.94,135.45 202.94,135.45 202.94,134.84 202.23,134.14 202.23,125.08 202.24,125.08 201.42,124.26 201.42,114.16 202.16,113.43 202.21,113.43 202.21,109.31 202.44,109.08 202.44,109.08 202.94,108.59 202.94,106.37 202.94,106.37 202.94,105.61 202.94,105.61 202.94,103.81 202.21,103.08 202.21,96.38 202.26,96.33 202.26,95.85 202.72,95.39 202.73,95.39 203.09,95.04 203.09,84.78
GND on L4: 191.72,58.62 191.08,59.25 191.08,60.72 194.49,64.13 196.85,64.13 200.73,68.01 202.77,68.01 202.89,67.89 202.89,67.18 202.9,67.19 203.01,67.24 203.09,67.14 203.09,65.7 203.02,65.61 202.91,65.64 202.89,65.65 202.89,63.31 202.02,62.44 202.27,62.44 202.62,62.5 202.92,62.69 203.03,62.7 203.09,62.61 203.09,62.55 203.07,62.46 203.02,62.38 200.6,59.97 200.53,59.92 200.44,59.9 195.98,59.9 193.9,59.57 192.02,58.62
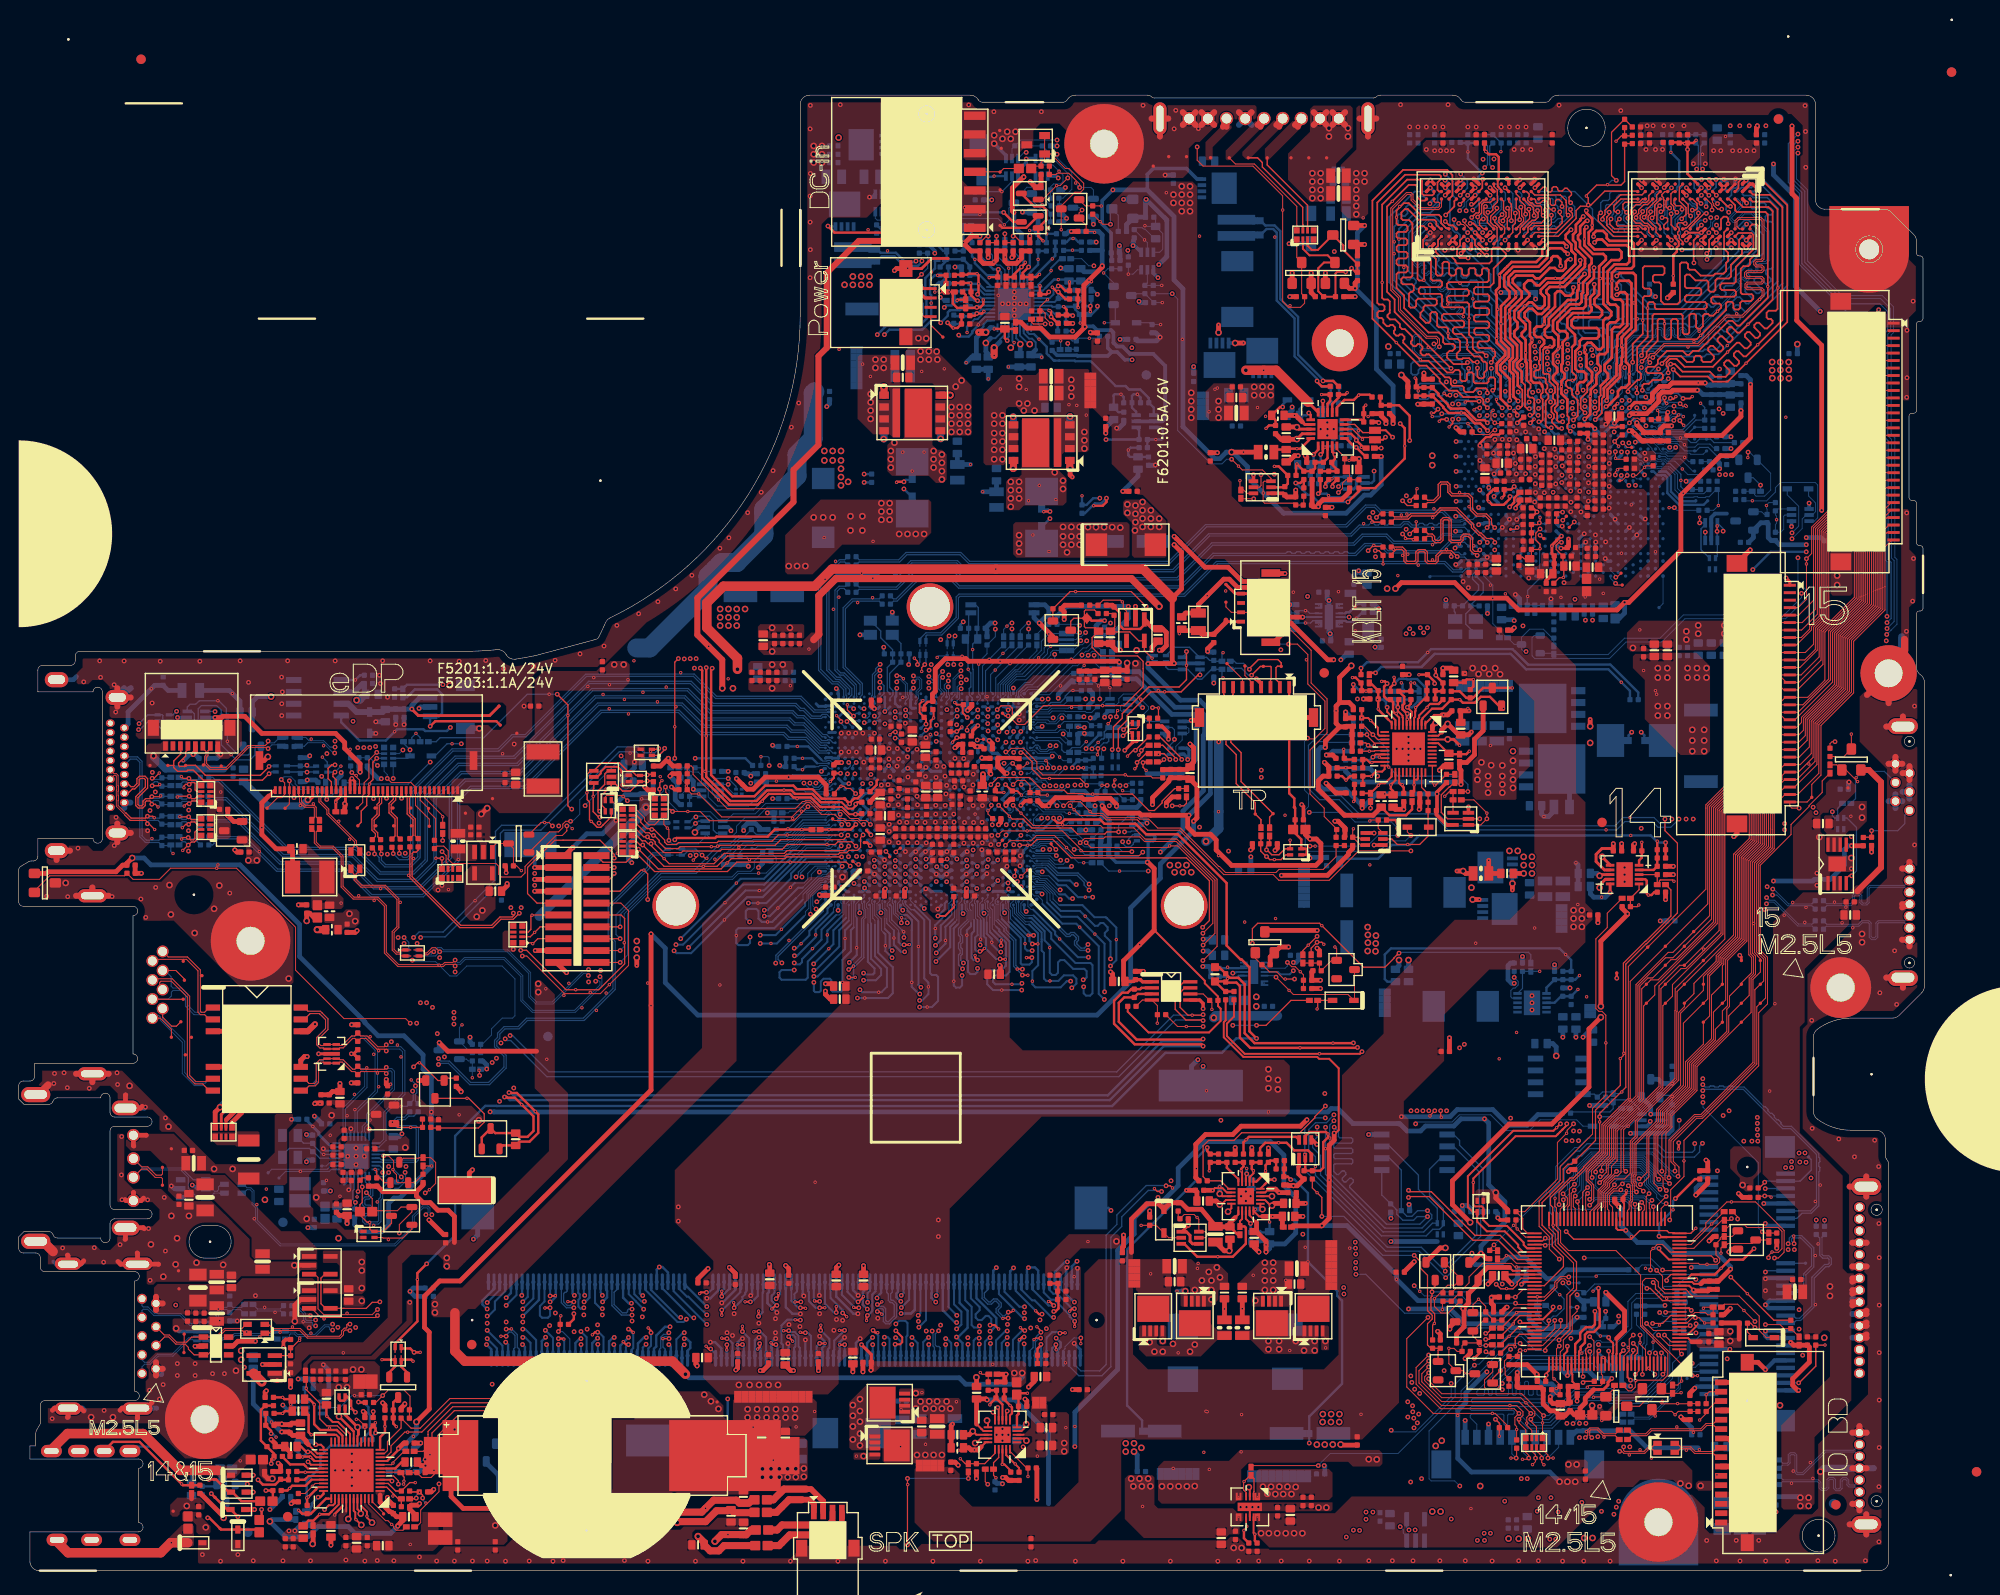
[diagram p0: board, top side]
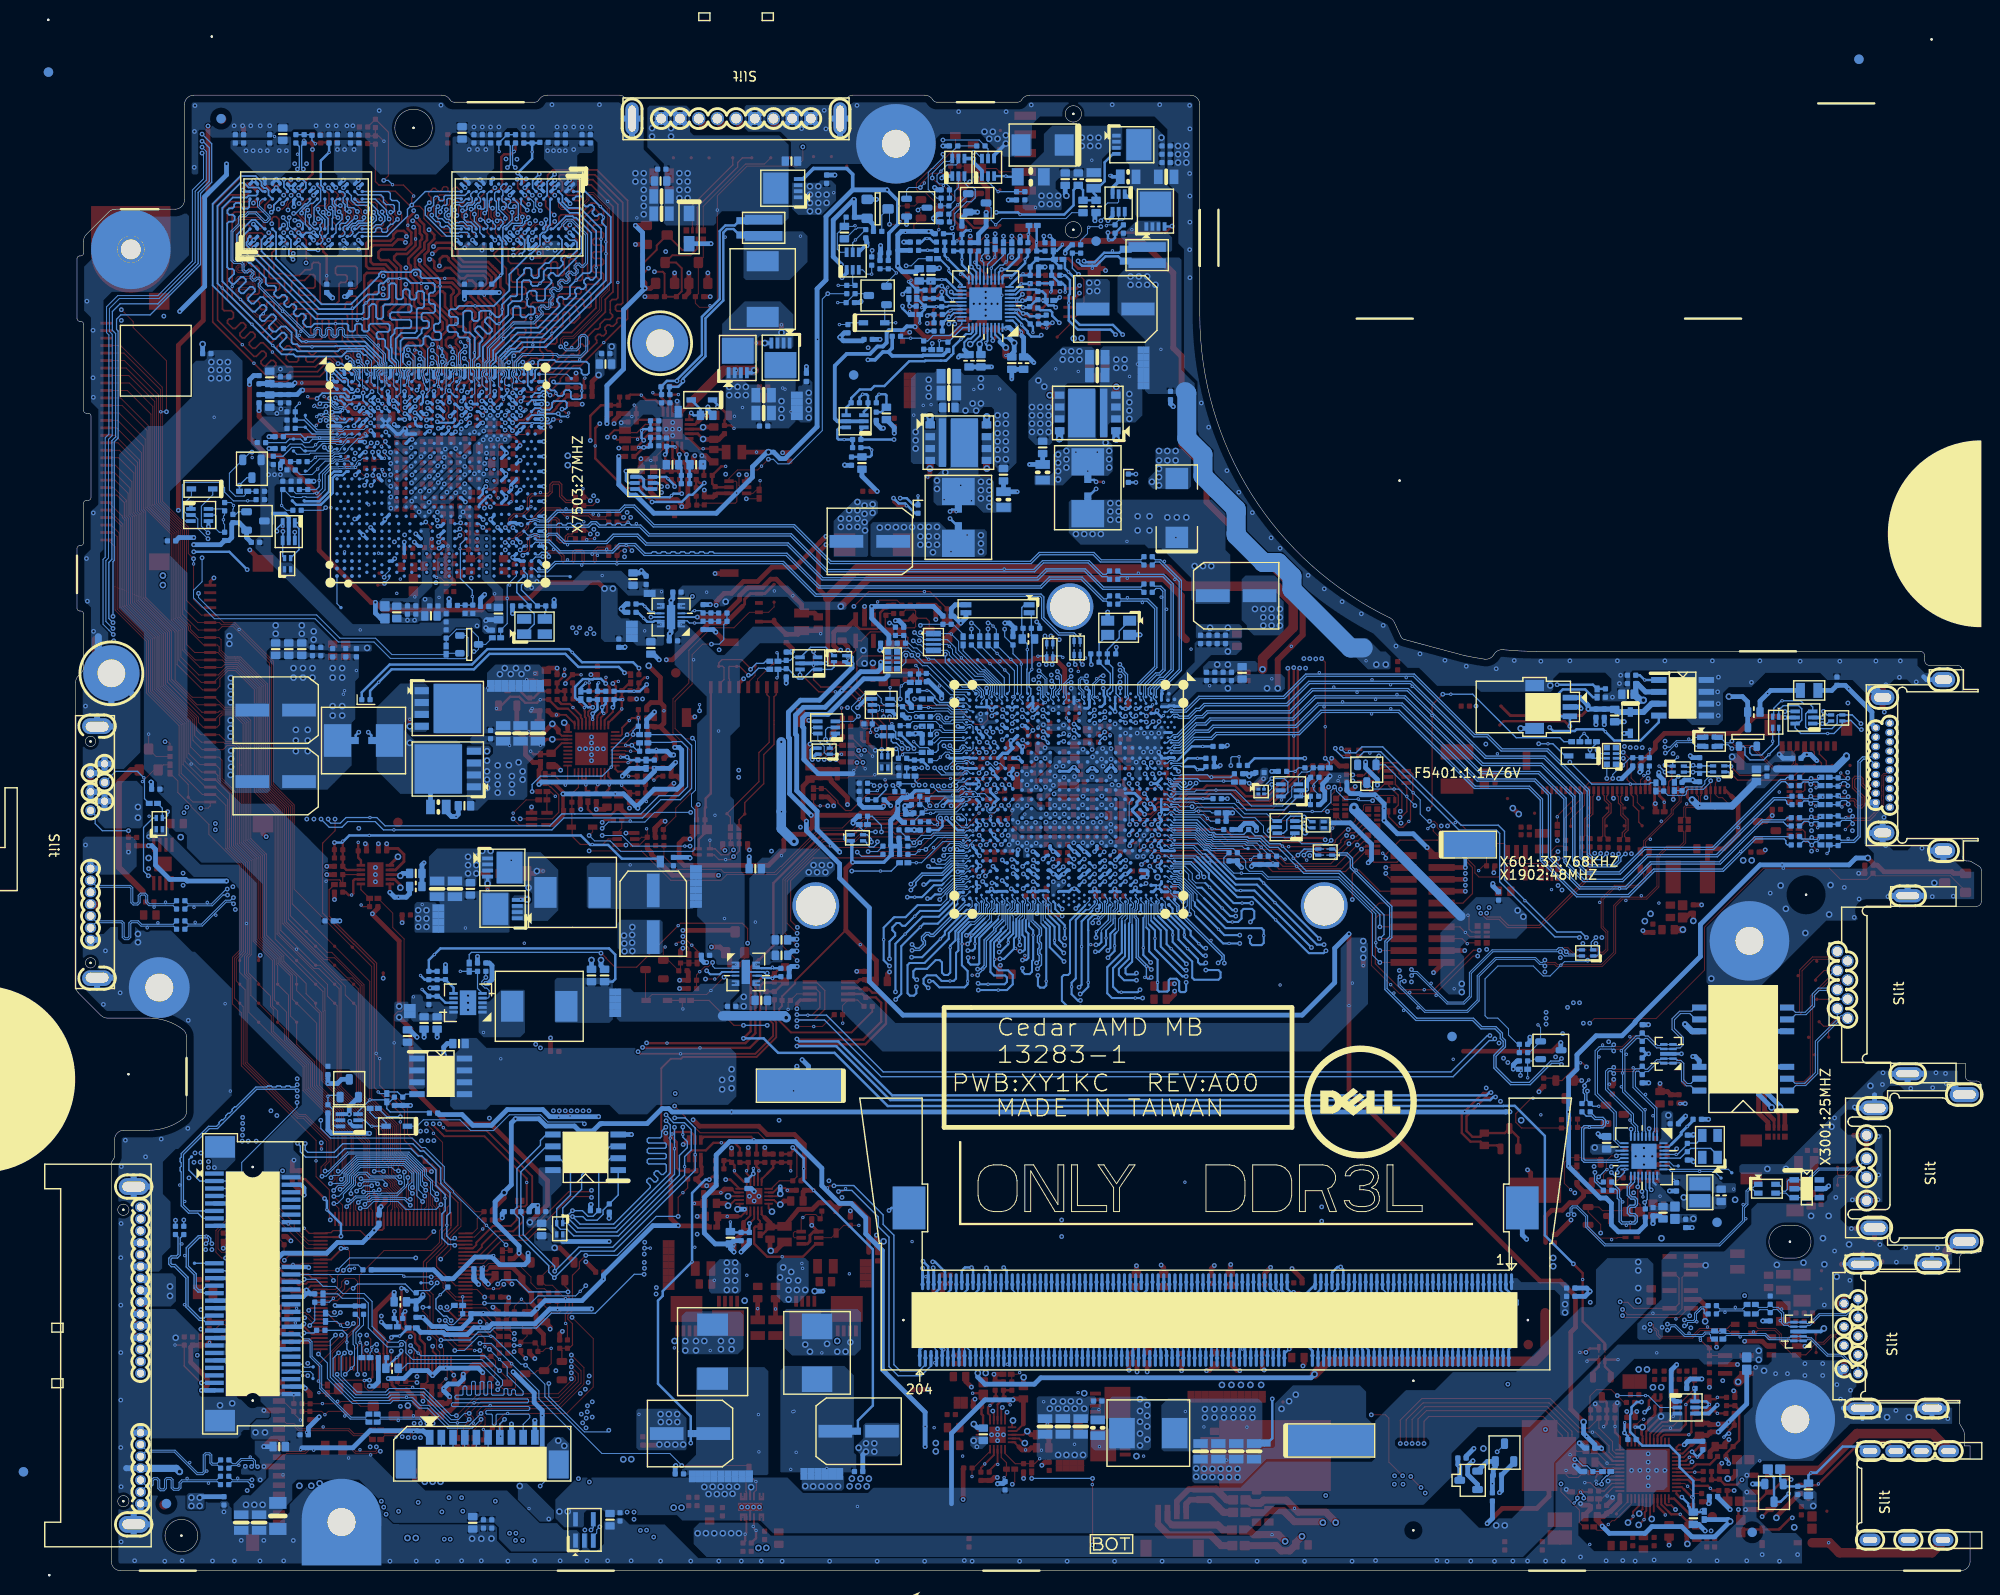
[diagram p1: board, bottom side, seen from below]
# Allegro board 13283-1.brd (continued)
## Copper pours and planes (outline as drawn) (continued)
GND on L4: 7.44,94.86 2.97,94.86 2.87,94.96 2.87,96.08 6.07,96.08 6.83,96.84 6.83,97.62 47.6,97.62 49.57,97.67 51.53,97.83 52.37,96.97 53.64,96.97 56.93,97.76 57.26,97.72 57.58,97.76 61.94,98.93 62.43,99.18 62.76,99.62 63.48,101.17 63.53,101.24 63.59,101.28 74.66,109.5 81.92,121.21 82.03,121.27 82.12,121.17 82.12,117.82 81.64,116.87 81.15,115.94 77.38,112.17 77.38,111.08 70.63,104.33 70.63,99.08 66.24,94.68 47.95,94.68 47.06,95.57 44.02,95.57 43,94.56 16.99,94.56 13.74,91.3 9.83,91.3 9.73,91.41 9.73,94.76 9.12,95.37 7.94,95.37
GND on L4: 83.09,124.79 83.78,127.88 83.89,127.96 83.98,127.86 83.98,123.34 82.9,122.27 82.9,122.26 82.29,121.65 82.17,121.64 82.13,121.76
GND on L5GND: outline of 230 points within 0.51,0.51 203.34,157.39
VDD10 on TOP: 32.33,38.8 31.44,39.69 31.44,40.96 32.2,41.72 32.2,46.17 34.06,48.03 37.08,48.03 37.79,47.31 37.79,47.06 37.54,46.8 34.49,46.8 33.98,46.3 33.98,42.49 34.36,42.11 35.76,42.11 35.89,41.98 35.89,39.18 35.51,38.8 ; 11 cut-outs
VDD10 on BOTTOM: 27.49,38.69 27.25,38.93 27.25,39.95 27.36,40.06 28.89,40.06 29.15,40.32 31.96,40.32 32.07,40.21 32.07,38.93 31.82,38.69 ; 1 cut-out
VDD_CT on BOTTOM: 161.6,114.03 162.79,114.03 162.91,113.91 162.91,112.77 162.78,112.63 162.13,112.63 161.77,112.28 161.77,109.49 161.41,109.14 160.5,109.14 160.4,109.03 160.4,106.14 159.28,105.02 159.28,104.46 159.03,104.21 159.03,103.7 159.18,103.55 159.84,103.55 159.99,103.4 159.99,102.94 159.69,102.63 158.21,102.63 158.11,102.73 158.11,105.02 159.38,106.29 159.38,110.71 159.59,110.91 161.06,110.91 161.26,111.12 161.26,113.69
VDDR3 on BOTTOM: 164.46,104.61 163.45,105.63 163.45,108.93 163.35,109.03 163.35,109.19 163.6,109.44 163.6,112.64 163.4,112.84 163.4,113.86 163.52,113.99 164.92,113.99 165.4,113.5 165.4,113.48 165.43,113.48 165.43,113.23 164.81,112.61 164.38,112.61 164.16,112.39 164.16,109.54 164.36,109.34 164.36,108.63 164.56,108.42 165.02,108.42 165.17,108.27 165.17,106.19 164.92,105.94 164.92,105.43 165.43,104.92 165.43,102.84 165.58,102.68 165.58,101.72 165.48,101.62 164.92,101.62 164.46,102.07 163.95,102.07 163.85,102.18 163.85,102.68 164.01,102.84 164.21,102.84 164.46,103.09
VDDREG on BOTTOM: 32.4,38.42 32.25,38.57 32.25,39.31 32.35,39.41 32.71,39.41 33.73,40.42 33.73,40.58 34.74,41.6 35.13,41.6 35.25,41.47 35.25,40.84 35.26,40.84 35.51,40.58 35.51,38.53 35.41,38.42 ; 2 cut-outs
0D95V_GFX_S0 on TOP: 94.94,87.57 94.05,88.46 94.05,88.84 94.31,89.1 94.82,89.1 95.07,89.35 97,89.35 97.33,89.68 97.64,89.68 97.74,89.58 97.74,89.37 97.61,89.25 97.61,88.08 97.48,87.95 96.47,87.95 96.21,88.21 95.83,88.21 95.2,87.57 ; 3 cut-outs
0D95V_GFX_S0 on BOTTOM: 94.94,87.7 94.88,87.76 94.88,88.52 95.32,88.97 96.59,88.97 96.97,89.35 97.1,89.35 97.74,88.71 97.74,88.46 97.61,88.33 95.58,88.33 95.32,88.08 95.32,87.83 95.2,87.7
0D95V_PWR on BOTTOM: 137.87,70.81 137.74,70.93 137.74,75.63 137.87,75.76 148.79,75.76 149.17,75.38 149.17,71.06 148.92,70.81 ; 2 cut-outs
0D95V_S0 on TOP: 100.66,79.06 100.53,79.19 100.53,79.95 100.4,80.08 100.4,83.13 100.53,83.25 101.04,83.25 101.29,83 104.47,83 104.72,82.75 104.72,82.49 104.59,82.36 103.96,82.36 103.58,81.98 103.58,81.68 103.35,81.45 103.35,80.43 103.71,80.08 103.71,79.19 103.58,79.06 ; 8 cut-outs
0D95V_S0 on BOTTOM: 128.34,65.09 128.22,65.22 128.22,68.01 127.71,68.52 127.71,72.33 125.8,74.24 123.39,74.24 122.63,75 122.63,76.27 123.64,77.28 128.6,77.28 129.58,76.31 130.41,76.31 130.96,75.76 130.96,74.92 131.77,74.11 131.77,65.98 131.39,65.6 131.39,64.84 129.64,64.84 129.39,65.09 ; 8 cut-outs
0D95V_S0 on BOTTOM: 100.61,78.91 100.48,79.03 100.48,80.07 100.63,80.22 102.79,80.22 103,80.43 103,80.81 101.9,81.9 101.45,81.9 100.91,81.36 100.28,81.36 100.15,81.49 100.15,81.86 100.28,81.98 100.78,81.98 101.29,82.49 101.29,82.62 101.5,82.82 102.78,82.82 103.76,81.85 103.76,79.92 102.75,78.91
0D95V_S0 on L2VCC: 123.6,74.3 121.55,76.35 121.55,76.6 118.9,79.25 117.22,79.25 116.07,78.11 109.47,78.11 108.58,77.22 103.91,77.22 103.77,77.36 103.77,78.25 103.4,78.62 100.85,78.62 100.85,80.25 100.98,80.38 100.98,82.43 103.64,82.43 103.64,84.19 103.91,84.46 107.83,84.46 107.83,82.54 108.45,81.92 121.79,81.92 125.87,77.84 125.87,74.57 125.6,74.3
0D95V_S0 on L3: 102.05,82.24 121.36,82.24 125.8,77.79 125.8,74.49 125.55,74.24 122.25,74.24 121.36,75.13 121.36,76.27 118.82,78.81 117.55,78.81 117.04,78.3 112.72,78.3 112.21,77.79 109.55,77.79 108.53,76.78 103.96,76.78 103.32,77.41 101.93,77.41 100.91,78.43 100.91,81.09
0D95V_S5 on TOP: 99.64,85.92 98.75,86.81 98.75,87.95 98.5,88.21 98.5,90.75 98.24,91 98.24,93.41 98.88,94.05 106.75,94.05 108.53,95.83 118.95,95.83 119.07,95.95 119.07,97.22 119.33,97.48 119.83,97.48 120.09,97.22 120.09,94.68 119.45,94.05 109.29,94.05 107.77,92.52 107.77,91 107.52,90.75 106.88,90.75 106.63,91 106.63,92.52 106.12,93.03 100.66,93.03 100.53,93.16 99.9,93.16 99.77,93.03 99.77,92.65 100.02,92.4 100.02,90.49 99.77,90.24 99.39,90.24 99.26,90.11 99.26,89.35 99.77,88.84 99.77,87.83 100.4,87.19 101.29,87.19 101.42,87.32 101.42,87.7 101.55,87.83 102.05,87.83 102.18,87.7 102.18,86.94 101.67,86.43 101.67,86.05 101.55,85.92 ; 13 cut-outs
0D95V_S5 on BOTTOM: 106.75,90.11 106.25,90.62 105.36,90.62 105.1,90.87 105.1,91 105.23,91.13 105.48,91.13 105.61,91 106.12,91 106.25,91.13 106.25,91.76 106.37,91.89 107.26,91.89 107.64,91.51 107.64,91.13 107.13,90.62 107.13,90.37 106.88,90.11
0D95V_S5 on BOTTOM: 132.92,64.84 132.92,65.35 132.28,65.98 132.28,74.49 132.66,74.87 132.66,79.37 133.42,80.13 133.42,82.49 133.8,82.87 133.8,89.35 132.79,90.37 132.79,97.1 130.63,99.26 121.1,99.26 120.34,98.49 120.34,96.97 120.09,96.72 119.2,96.72 119.07,96.84 119.07,99.76 120.34,101.03 131.39,101.03 134.44,97.99 135.2,97.99 138.5,101.29 139.39,101.29 139.39,100.65 139.77,100.27 139.77,96.97 136.34,93.54 136.34,91.64 137.36,90.62 137.36,70.05 136.47,69.16 136.47,65.73 136.34,65.6 135.58,65.6 135.33,65.35 135.33,64.97 135.2,64.84 ; 2 cut-outs
0D95V_S5 on BOTTOM: 99.51,86.43 99.39,86.56 99.39,87.57 99.51,87.7 99.77,87.7 100.15,87.32 101.04,87.32 101.42,87.7 101.67,87.7 101.8,87.57 101.8,86.56 101.67,86.43 101.42,86.43 101.04,86.81 100.15,86.81 99.77,86.43
0D95V_VGA_OUT2 on BOTTOM: 141.04,99 140.92,99.13 140.92,101.29 143.2,101.29 143.58,101.67 144.09,101.67 144.22,101.54 144.22,99.38 143.84,99 ; 2 cut-outs
0D95V_VGA_S0 on TOP: 156.41,116.4 156.28,116.53 156.28,117.04 156.41,117.16 157.3,117.16 157.55,116.91 158.82,116.91 159.08,117.16 159.08,117.8 158.95,117.92 158.95,118.94 159.08,119.07 159.08,120.59 158.82,120.85 158.19,120.85 157.3,119.96 157.05,119.96 156.79,120.21 156.79,120.85 157.05,121.1 157.55,121.1 157.81,121.35 160.22,121.35 161.11,120.46 161.11,117.8 161.36,117.54 161.36,117.29 161.11,117.04 161.11,116.53 160.98,116.4 ; 11 cut-outs
0D95V_VGA_S0 on BOTTOM: 144.6,99.38 144.47,99.51 144.47,101.67 144.73,101.92 145.49,101.92 145.87,102.3 145.87,105.1 146.25,105.48 147.39,105.48 147.65,105.22 147.65,99.76 147.27,99.38 ; 2 cut-outs
0D95V_VGA_S0 on BOTTOM: 159.27,115.58 158.58,116.27 158.58,120.34 158.45,120.47 158.44,120.47 158.32,120.59 157.57,120.59 157.18,120.98 157.18,121.46 157.42,121.7 160.09,121.7 161.35,120.45 161.35,119.59 161.93,119.01 161.93,118.53 161.35,117.95 161.35,117.47 161.88,116.94 161.88,116.6 160.86,115.58
0D95V_VGA_S0 on L3: 146,106.11 146,104.46 146.12,104.34 149.43,104.34 152.85,107.76 152.85,119.58 152.6,119.83 151.08,119.83 150.82,119.58 150.82,108.65 148.54,106.37 146.25,106.37
0D95V_VGA_S0 on L4: 150.82,119.7 152.47,121.35 160.35,121.35 161.49,120.21 161.49,116.02 161.24,115.77 152.85,115.77 150.82,117.8
0D675V_S0 on TOP: 108.4,18.1 108.28,18.23 108.28,18.99 109.55,20.26 109.55,21.39 109.55,21.4 109.55,25.6 111.69,27.74 111.69,31.31 112.96,32.58 113.48,32.58 113.61,32.45 113.61,25.47 113.23,25.09 113.23,22.48 113.22,22.47 113.22,21.01 110.31,18.1 ; 7 cut-outs
1D8V_PWR on BOTTOM: 146.76,58.62 146.38,59 146.38,63.06 146.76,63.44 152.35,63.44 152.6,63.19 152.6,58.74 152.47,58.62 ; 3 cut-outs
1D8V_S0 on TOP: 78.31,94.05 78.05,94.3 78.05,95.45 78.18,95.57 82.5,95.57 82.88,95.19 82.88,94.3 82.62,94.05 ; 4 cut-outs
1D8V_S0 on TOP: 63.57,78.05 62.68,78.94 62.68,79.7 63.95,80.97 64.97,80.97 65.1,80.84 65.1,76.65 64.97,76.52 64.34,76.52 63.57,77.28
1D8V_S0 on BOTTOM: 70.69,55.57 65.61,60.65 65.61,67.12 66.24,67.76 67.38,67.76 68.53,66.62 68.53,62.04 71.96,58.62 116.15,58.62 120.6,63.06 130.25,63.06 130.5,63.31 131.39,63.31 131.39,62.55 130.63,61.79 130.63,60.14 130.5,60.01 121.99,60.01 117.55,55.57 ; 4 cut-outs
1D8V_S0 on BOTTOM: 85.54,92.27 83.77,94.05 74.75,94.05 74.5,94.3 74.5,95.57 74.88,95.95 79.58,95.95 79.96,95.57 84.53,95.57 86.55,93.55 86.55,93.05 86.74,92.85 87.71,92.85 87.83,92.73 87.83,92.4 87.7,92.3 86.94,92.27 86.81,92.4 86.56,92.4 86.43,92.27 ; 6 cut-outs
1D8V_S0 on BOTTOM: 76.27,82.36 75.38,83.25 74.5,83.25 74.37,83.38 74.37,83.63 74.5,83.76 75.51,83.76 76.53,82.75 76.91,82.75 77.04,82.87 77.04,84.02 76.27,84.78 76.27,85.79 76.4,85.92 76.91,85.92 77.16,85.67 77.16,85.03 77.8,84.4 77.8,82.62 77.54,82.36
1D8V_S0 on BOTTOM: 67.76,84.27 67.64,84.4 67.64,85.29 67.76,85.41 69.8,85.41 70.05,85.16 70.05,84.27
1D8V_S0 on L3: 77.04,75.51 75.38,73.86 68.27,73.86 67.13,72.71 67.13,64.58 66.75,64.2 65.22,64.2 64.97,64.46 64.97,73.73 67.26,76.01 73.86,76.01 74.5,76.65 74.5,94.3 75,94.81 76.65,94.81 77.04,94.43
1D8V_S5 on TOP: 79.7,97.99 79.07,98.62 79.07,99.26 79.32,99.51 83.89,99.51 84.78,100.4 85.67,100.4 85.93,100.14 85.93,99.13 84.78,97.99 ; 6 cut-outs
1D8V_S5 on BOTTOM: 121.61,103.7 125.93,103.7 127.66,105.43 138.94,105.43 139.39,104.97 139.39,102.81 138.1,102.81 136.94,103.97 135.72,103.97 134.95,103.19 134.44,103.19 133.42,104.21 127.71,104.21 126.31,102.81 121.56,102.81 121.38,102.99 121.38,103.47 ; 1 cut-out
1D8V_S5 on BOTTOM: 86.87,93.05 86.74,93.18 86.74,93.61 82.37,97.99 79.7,97.99 79.07,98.62 79.07,99.26 79.32,99.51 83.89,99.51 84.15,99.26 84.15,97.22 87.12,94.25 87.12,93.94 87.25,93.81 87.25,93.18 87.12,93.05 ; 5 cut-outs
1D8V_S5 on BOTTOM: 134.31,58.74 133.8,59.25 133.8,61.03 132.92,61.92 132.92,63.31 134.06,63.31 134.57,62.81 136.98,62.81 137.87,61.92 144.12,61.92 144.5,62.3 145.87,62.3 146,62.17 146,59.12 145.62,58.74 ; 2 cut-outs
1D8V_VGA_S0 on TOP: 159.08,104.84 155.01,104.84 154.25,105.61 154.25,106.49 154.89,107.13 157.17,107.13 157.43,107.38 158.57,107.38 158.82,107.64 158.82,110.18 159.2,110.56 161.11,110.56 161.36,110.3 161.36,109.16 161.11,108.91 160.22,108.91 159.84,108.53 159.84,107.13 161.49,105.48 162.84,105.48 163.09,105.22 164.67,105.22 164.79,105.35 171.78,105.35 174.44,108.02 174.44,116.65 177.62,119.83 177.62,120.72 176.86,121.48 176.22,121.48 176.1,121.61 176.1,121.99 176.22,122.12 178,122.12 178.51,121.61 178.51,119.07 175.46,116.02 175.46,107.38 172.29,104.21 171.27,104.21 170.38,103.32 160.6,103.32 ; 7 cut-outs
1D8V_VGA_S0 on BOTTOM: 142.69,104.34 142.57,104.46 142.57,105.73 142.69,105.86 144.35,105.86 145.49,107 149.55,107 150.7,105.86 154.12,105.86 154.89,106.62 155.14,106.62 155.39,106.37 155.39,105.99 155.9,105.48 155.9,105.1 155.65,104.84 149.55,104.84 148.66,105.73 146.12,105.73 144.73,104.34 ; 3 cut-outs
1D35V_PWR on TOP: 78.05,14.44 76.4,16.1 76.4,18.23 76.57,18.4 85.02,18.4 85.37,18.05 85.37,15.71 84.1,14.44 ; 6 cut-outs
1D35V_PWR on BOTTOM: 77.42,12.77 76.91,13.28 76.91,17.99 77.34,18.42 87.01,18.42 87.7,17.72 87.7,13.02 87.45,12.77 81.05,12.77 81.04,12.78 81.03,12.77
1D35V_PWR on BOTTOM: 106.88,13.02 106.25,13.66 106.25,14.29 106.37,14.42 107.9,14.42 108.15,14.17 108.15,13.4 107.77,13.02 ; 1 cut-out
1D35V_PWR on L3: 77.54,18.36 77.54,16.2 77.8,15.94 83.26,15.94 83.77,16.45 83.77,18.99 85.04,20.26 87.2,20.26 88.47,21.53 103.07,21.53 104.47,20.13 108.15,20.13 108.4,19.88 108.4,15.05 107.01,13.66 107.01,13.02 107.26,12.77 108.53,12.77 110.31,14.55 110.31,21.4 108.79,22.93 82.62,22.93 81.86,22.17 81.86,19.37 81.23,18.74 77.92,18.74
1D35V_S3 on TOP: 75,18.86 73.23,20.64 73.23,31.18 74.31,32.26 74.31,33.15 70.18,37.28 70.18,42.87 88.08,60.77 88.08,72.33 90.39,74.63 90.39,75.62 90.71,75.93 90.71,76.86 91.01,77.16 91.53,77.16 91.64,77.05 91.64,76.65 91.89,76.4 92.86,76.4 93.09,76.16 93.56,76.16 93.8,76.4 93.8,76.41 94.82,77.43 96.52,77.43 96.65,77.3 100.58,77.3 100.71,77.43 103.76,77.43 104.21,76.97 104.21,76.52 104.34,76.4 104.98,76.4 104.98,76.41 105.22,76.66 105.22,77.15 105.36,77.28 105.74,77.28 105.92,77.11 105.92,76.5 105.92,76.49 105.92,75.02 105.44,74.53 105.44,72.68 105.99,72.12 105.99,57.09 107.39,55.69 129.74,55.69 130.76,54.68 135.33,54.68 135.96,54.04 135.96,49.09 135.46,48.58 109.42,48.58 99.58,38.74 99.58,28.07 99.21,27.7 96.24,27.7 95.37,26.84 93.6,26.84 93.39,26.64 93.39,26.23 93.04,25.87 91.54,25.87 90.24,24.58 89.99,24.58 89.86,24.45 89.86,23.18 89.61,22.93 88.47,22.93 87.7,22.17 87.7,20.01 86.56,18.86 ; 48 cut-outs
1D35V_S3 on BOTTOM: 142.69,48.84 141.68,49.85 134.06,49.85 133.17,50.74 133.17,55.31 133.8,55.95 159.89,55.95 160.96,57.01 162.58,57.01 162.79,56.81 162.79,55.8 163.78,54.81 163.78,49.73 163.4,49.34 159.97,49.34 159.46,49.85 146.76,49.85 145.74,48.84
1D35V_S3 on L2VCC: 76.23,19.31 73.05,22.48 72.29,22.48 69.61,25.17 69.61,37.36 69.35,37.61 69.35,37.84 69.61,38.09 69.61,45.05 74.96,50.41 75.22,50.43 83.2,58.41 83.2,68.44 87.91,73.16 89.69,73.16 90.05,73.52 90.05,73.9 90.56,74.41 90.56,75.82 90.7,75.82 91.21,76.33 91.59,76.33 92.48,77.22 99.72,77.22 100.74,78.24 103.25,78.24 103.39,78.09 103.39,77.21 103.75,76.84 105.8,76.84 105.8,75.68 105.93,75.55 105.93,74.67 106.67,73.92 107.56,73.92 107.94,73.54 108.99,73.54 112.66,69.86 112.66,63.14 112.15,62.63 112.15,51.61 102.22,41.68 101.97,41.65 99.2,38.88 99.2,35.83 98.42,35.06 97.02,35.06 95.41,33.42 95.41,32.91 94.52,32.02 94.52,24.53 89.28,19.31
1D35V_VGA_S0 on TOP: 160.09,148.28 159.97,148.4 159.97,149.04 159.46,149.55 159.46,152.09 160.47,153.1 164.16,153.1 164.28,152.98 164.28,150.56 162,148.28 161.62,148.28 161.11,148.79 160.86,148.79 160.35,148.28 ; 1 cut-out
1D35V_VGA_S0 on TOP: 182.7,148.28 180.79,150.18 180.79,153.23 181.3,153.74 184.22,153.74 184.86,153.1 186.13,153.1 186.26,152.98 186.26,151.2 183.72,148.66 183.72,148.4 183.59,148.28 ; 1 cut-out
1D35V_VGA_S0 on TOP: 173.81,148.15 173.17,148.79 173.17,152.98 173.3,153.1 176.1,153.1 176.22,152.98 176.22,148.66 175.84,148.28 175.33,148.28 174.95,148.66 174.57,148.66 174.06,148.15 ; 4 cut-outs
1D35V_VGA_S0 on TOP: 163.27,120.46 162.89,120.85 162,120.85 161.87,120.97 161.87,121.35 161.62,121.61 160.98,121.61 160.86,121.48 159.33,121.48 159.2,121.61 159.2,123.77 159.33,123.89 159.71,123.89 159.97,123.64 159.97,122.62 160.09,122.5 160.47,122.5 160.6,122.62 160.6,122.75 160.73,122.88 161.24,122.88 161.62,122.5 162.63,122.5 162.89,122.24 162.89,121.61 163.01,121.48 163.9,121.48 164.03,121.35 164.03,120.59 163.9,120.46 ; 2 cut-outs
1D35V_VGA_S0 on TOP: 160.6,140.53 159.97,141.17 159.97,142.05 160.09,142.18 160.35,142.18 160.47,142.05 160.47,141.8 160.73,141.55 161.11,141.55 161.74,142.18 162,142.18 162.51,141.67 162.51,141.04 162,140.53
1D35V_VGA_S0 on TOP: 173.56,140.53 173.17,140.91 173.17,141.42 173.94,142.18 174.06,142.18 174.19,142.05 174.19,141.8 174.32,141.67 174.95,141.67 175.46,142.18 175.71,142.18 175.84,142.05 175.84,140.91 175.46,140.53
1D35V_VGA_S0 on TOP: 180.12,139.26 179.61,139.77 179.61,140.19 179.38,140.43 179.38,142.12 179.5,142.24 179.69,142.24 180.28,141.65 180.28,140.11 180.45,139.94 180.79,139.94 181.42,140.58 181.42,141.31 181.3,141.44 181.3,141.62 181.88,142.2 182.1,142.2 182.2,142.09 182.2,139.84 181.63,139.26
1D35V_VGA_S0 on TOP: 152.28,141.07 151.89,141.46 151.89,142.22 152.4,142.73 152.4,142.85 152.28,142.98 152.02,142.98 150.84,141.8 150.57,141.8 150.44,141.93 150.44,142.18 150.57,142.31 150.57,143.2 150.86,143.49 153.16,143.49 153.29,143.36 153.29,142.6 152.78,142.09 152.78,141.84 152.91,141.71 153.04,141.71 153.16,141.84 153.55,141.84 153.67,141.71 153.67,141.33 153.55,141.2 153.16,141.2 153.04,141.07
1D35V_VGA_S0 on TOP: 153.74,148.28 153.62,148.4 153.62,149.67 152.35,150.94 151.08,150.94 150.19,151.83 150.19,152.72 150.57,153.1 156.03,153.1 156.16,152.98 156.16,148.79 156.28,148.66 156.28,148.4 156.16,148.28 155.9,148.28 155.39,148.79 154.38,148.79 153.87,148.28 ; 3 cut-outs
1D35V_VGA_S0 on BOTTOM: 160.09,137.36 159.84,137.61 159.84,142.05 159.97,142.18 160.31,142.18 160.82,141.67 161.11,141.67 161.73,142.29 161.98,142.29 163.01,141.26 163.01,137.61 162.76,137.36 ; 4 cut-outs
1D35V_VGA_S0 on BOTTOM: 160.61,121.46 160.27,121.8 159,121.8 158.7,122.1 158.7,123.31 159.33,123.94 159.68,123.94 160.13,123.48 160.13,122.72 160.33,122.52 162.74,122.52 162.86,122.39 162.86,121.56 162.77,121.46
1D35V_VGA_S0 on BOTTOM: 168.48,121.1 168.22,121.35 167.33,121.35 166.95,121.73 166.95,122.12 167.08,122.24 168.22,122.24 168.48,122.5 168.86,122.5 169.11,122.24 169.62,122.24 170,122.62 170,123.51 170.25,123.77 171.4,123.77 171.65,123.51 171.65,122.5 171.4,122.24 170.63,122.24 169.49,121.1
1D35V_VGA_S0 on BOTTOM: 166.63,51.57 166.44,51.76 166.44,55.44 167.97,56.96 168.6,56.96 176.86,65.22 176.86,76.27 182.67,82.08 186.13,82.08 188.29,84.24 188.29,87.7 191.88,91.29 191.88,106.78 193.75,108.65 193.75,115.51 186,123.26 186,129.48 187.14,130.62 189.56,130.62 189.81,130.37 189.81,129.74 190.07,129.48 190.95,129.48 191.34,129.1 191.34,125.67 194.51,122.5 196.16,122.5 199.21,119.45 199.21,103.07 196.54,100.4 196.54,85.79 195.15,84.4 195.15,83.38 193.57,81.81 193.57,79.52 193.11,79.06 192.3,79.06 191.95,78.71 191.95,77.33 190.37,75.76 186.13,75.76 183.84,73.47 183.84,60.52 176.98,53.66 174.57,53.66 172.48,51.57 ; 9 cut-outs
1D35V_VGA_S0 on BOTTOM: 151.08,147.39 150.19,148.28 150.19,151.45 149.93,151.71 148.66,151.71 148.41,151.96 148.41,152.98 148.54,153.1 153.49,153.1 153.74,152.85 153.74,151.07 152.22,149.55 152.22,148.02 151.58,147.39 ; 6 cut-outs
1D35V_VGA_S0 on BOTTOM: 160.09,148.28 159.84,148.53 159.84,149.29 159.08,150.06 159.08,152.98 159.2,153.1 161.49,153.1 161.87,153.48 163.4,153.48 163.52,153.36 163.52,149.93 161.87,148.28 161.62,148.28 161.24,148.66 160.73,148.66 160.35,148.28 ; 7 cut-outs
1D35V_VGA_S0 on BOTTOM: 173.81,148.28 173.17,148.91 173.17,152.98 173.3,153.1 176.1,153.1 176.22,152.98 176.22,149.67 175.84,149.29 175.84,148.4 175.71,148.28 175.33,148.28 174.83,148.79 174.7,148.79 174.19,148.28 ; 3 cut-outs
1D35V_VGA_S0 on BOTTOM: 147.65,127.58 147.27,127.96 147.27,130.5 147.39,130.62 147.9,130.62 148.28,130.24 148.28,127.83 148.03,127.58 ; 1 cut-out
1D35V_VGA_S0 on BOTTOM: 173.94,137.36 173.22,138.08 173.22,141.48 173.96,142.22 174.21,142.22 174.59,141.84 174.97,141.84 175.33,142.19 175.66,142.19 175.77,142.09 175.77,141.84 175.69,141.76 175.69,140.92 176.03,140.58 178.42,140.58 179.69,141.86 180.16,141.86 180.31,141.71 180.31,141.46 180.16,141.31 180.16,140.17 180.45,139.87 180.85,139.87 181.31,140.33 181.31,141.39 181.01,141.7 181.01,142.12 181.1,142.22 181.35,142.22 181.94,141.63 181.94,140.28 180.33,138.67 178.68,138.67 177.37,137.36 ; 4 cut-outs
1D35V_VGA_S0 on BOTTOM: 152.91,140.57 152.02,141.46 152.02,142.09 152.26,142.33 152.93,142.33 153.16,142.09 153.55,142.09 153.67,142.22 153.93,142.22 154.05,142.09 154.05,141.76 154.56,141.25 154.56,140.82 154.31,140.57
1D35V_VGA_S0 on BOTTOM: 182.7,148.28 180.79,150.18 180.79,153.36 180.92,153.48 182.45,153.48 182.83,153.1 187.14,153.1 187.27,152.98 187.27,152.21 183.72,148.66 183.72,148.4 183.59,148.28 ; 6 cut-outs
1D35V_VGA_S0 on L2VCC: 165.51,121.16 165.25,121.42 161.7,121.42 161.44,121.67 157.6,121.67 157.35,121.42 154.33,121.42 154.08,121.67 151.92,121.67 147.58,126 147.58,130.83 144.66,133.75 144.66,146.8 148.49,150.63 155.82,150.63 156.08,150.37 158.11,150.37 159.13,149.36 164.46,149.36 165.09,148.72 170.33,148.72 174.02,152.4 185.67,152.4 186.19,151.88 186.19,149.6 189.37,146.42 189.37,131.18 189.75,130.8 189.75,127.4 189.48,127.13 184.27,127.13 178.81,121.67 167,121.67 166.49,121.16
3D3V_AUX_KBC on TOP: 156.9,39.28 156.9,39.28 155.92,39.28 155.82,39.38 155.82,40.6 156.03,40.81 158.14,40.81 158.38,40.56 158.38,39.44 158.23,39.28
3D3V_AUX_KBC on BOTTOM: 69.54,79.06 69.42,79.19 69.42,80.33 69.67,80.59 70.56,80.59 70.81,80.33 70.81,79.32 70.56,79.06
3D3V_CAMERA_S0 on TOP: 13.92,85.92 13.66,86.17 13.66,88.26 13.92,88.51 15.16,88.51 15.47,88.82 15.97,88.82 16.03,88.76 16.03,87.75 15.97,87.7 15.26,87.7 15.06,87.49 15.06,86.3 14.68,85.92
3D3V_CAMERA_S0 on BOTTOM: 21.31,86.17 22.17,86.17 22.53,85.82 22.53,85.46 22.68,85.31 23.19,85.31 23.59,84.9 24.56,84.9 25.12,84.35 25.12,83.74 23.19,83.74 21.31,85.62
3D3V_LAN_S5 on TOP: 30.17,37.15 28.9,38.42 28.9,46.93 29.79,47.82 31.44,47.82 32.33,48.71 32.33,49.34 32.84,49.85 32.84,50.23 32.97,50.36 38.05,50.36 39.32,49.09 39.32,46.8 39.57,46.55 41.37,46.55 41.78,46.14 41.78,45.1 41.58,44.9 37.92,44.9 37.79,45.03 37.79,46.04 38.05,46.3 38.05,47.44 37.16,48.33 33.86,48.33 31.82,46.3 31.82,43.12 31.06,42.36 31.06,39.18 31.52,38.73 31.52,37.81 32.08,37.25 34.11,37.25 34.87,36.49 37.21,36.49 37.21,35.48 35.13,35.48 34.01,36.59 31.57,36.59 31.01,37.15 ; 3 cut-outs
3D3V_LAN_S5 on BOTTOM: 30.59,37.24 30.43,37.41 30.43,38.04 30.55,38.17 33.18,38.17 33.31,38.04 33.31,37.37 33.18,37.24 ; 2 cut-outs
3D3V_LAN_S5 on BOTTOM: 39.52,44.52 39.27,44.77 38.96,44.77 38.89,44.85 38.89,44.95 39.6,45.66 41.6,45.66 41.86,45.41 41.86,44.77 41.6,44.52
3D3V_LAN_S5 on BOTTOM: 33.62,45.67 33.61,45.67 33.59,45.67 32.97,46.3 32.97,48.96 33.22,49.22 33.98,49.22 34.22,48.98 34.22,46.97 34.43,46.76 34.43,45.74 34.36,45.67 ; 2 cut-outs
3D3V_PWR on BOTTOM: 120.47,10.36 120.34,10.48 120.34,12.39 120.6,12.64 120.6,20.9 121.61,21.91 127.96,21.91 128.47,21.4 128.47,10.61 128.38,10.52 120.9,10.52 120.74,10.36 ; 1 cut-out
3D3V_S0 on TOP: 45.67,32.2 45.41,32.45 45.41,33.22 44.83,33.8 41.96,33.8 41.02,32.86 41.02,26.53 37.62,23.13 31.06,23.13 30.27,22.34 30.27,21.56 29.49,20.77 28.8,20.77 28.12,20.08 27.33,20.08 26.64,20.77 26.57,20.77 26.57,21.45 28.17,21.45 28.37,21.66 28.37,22.27 28.62,22.52 29.33,22.52 29.54,22.72 29.54,23.89 30.07,24.43 36.83,24.43 39.47,27.07 39.47,33.62 41.23,35.39 47.2,35.39 56.72,44.9 56.72,50.11 55.19,51.63 55.19,62.93 55.45,63.19 55.83,63.19 57.35,61.66 57.35,52.52 58.75,51.12 58.75,44.01 46.94,32.2
3D3V_S0 on TOP: 48.33,69.54 47.7,70.17 47.7,74.74 48.46,75.51 50.87,75.51 51,75.38 51,70.81 49.73,69.54 ; 4 cut-outs
3D3V_S0 on TOP: 179.68,23.84 179.47,24.05 179.47,24.73 179.65,24.91 184.15,24.91 184.29,24.78 184.29,23.91 184.22,23.85 181.73,23.85 181.73,23.84 ; 4 cut-outs
3D3V_S0 on TOP: 120.34,3.5 118.31,5.53 118.31,9.85 118.69,10.23 121.23,10.23 121.49,9.97 121.49,7.05 121.87,6.67 129.88,6.67 130.38,6.18 130.95,6.18 131.02,6.11 131.02,5.38 130.59,4.96 130.59,3.95 130.53,3.88 129.49,3.88 129.49,3.88 129.11,3.5 ; 4 cut-outs
3D3V_S0 on TOP: 64.84,83.63 64.46,84.02 64.46,84.27 64.08,84.65 62.94,84.65 62.81,84.78 62.81,85.16 62.94,85.29 64.08,85.29 64.21,85.41 65.48,85.41 65.73,85.16 65.73,84.02 65.35,83.63
3D3V_S0 on TOP: 65.1,86.17 64.84,86.43 64.84,87.95 65.1,88.21 66.88,88.21 67,88.08 67,86.56 66.62,86.17
3D3V_S0 on TOP: 110.06,31.31 109.8,31.56 109.8,33.47 112.34,36.01 117.55,36.01 117.8,35.76 117.8,34.87 117.42,34.49 113.61,34.49 112.47,33.34 112.47,32.45 111.33,31.31 ; 2 cut-outs
3D3V_S0 on TOP: 179.68,8.55 179.4,8.83 179.4,9.36 179.65,9.62 181.02,9.62 181.2,9.44 182.73,9.44 182.73,8.91 182.67,8.86 181.3,8.86 181,8.55
3D3V_S0 on TOP: 36.14,70.78 35.02,70.78 34.67,70.43 32.79,70.43 32.64,70.27 32.64,69.46 32.79,69.31 33.45,69.31 33.65,69.11 33.65,68.19 33.75,68.09 34.57,68.09 34.62,68.14 34.62,68.55 34.87,68.8 35.99,68.8 36.45,69.26 36.45,70.48
3D3V_S0 on TOP: 67.38,80.08 67.13,80.33 67.13,80.71 66.37,81.48 66.37,82.75 66.62,83 67.89,83 68.15,82.75 68.15,80.21 68.02,80.08
3D3V_S0 on BOTTOM: 55.45,61.66 55.32,61.79 55.32,65.73 55.7,66.11 55.7,66.74 54.81,67.63 49.73,67.63 48.59,68.78 48.59,70.17 50.49,72.08 54.05,72.08 57.86,68.27 57.86,62.55 56.97,61.66 ; 2 cut-outs
3D3V_S0 on BOTTOM: outline of 81 points within 177.37,12.77 196.29,79.7 ; 3 cut-outs
3D3V_S0 on L3: 72.72,78.81 72.46,78.55 70.05,78.55 67.51,81.09 66.88,81.09 66.62,81.35 66.62,81.73 67,82.11 68.02,82.11 70.56,79.57 72.46,79.57 72.72,79.32
3D3V_S0 on L3: 89.89,8.45 121.1,8.45 121.36,8.7 121.36,9.85 121.61,10.1 123.64,10.1 124.28,10.74 124.28,11.5 123.52,12.26 120.09,12.26 118.95,11.12 106.88,11.12 106.12,11.88 94.43,11.88 93.16,10.61 90.4,10.61 85.82,15.18 75.54,15.18 67.28,23.44 48.84,23.44 46.43,25.85 46.43,33.6 46.17,33.85 44.65,33.85 44.4,33.6 44.4,31.18 43.38,30.17 43.38,25.85 47.83,21.4 65.89,21.4 74.47,12.82 85.52,12.82
3D3V_S0 on L3: 50.62,69.28 50.37,69.03 35.76,69.03 34.87,69.92 34.87,70.68 36.4,72.2 49.6,72.2 50.62,71.19
3D3V_S0 on L3: 169.24,3.12 168.98,2.86 165.96,2.86 164.67,4.16 164.67,5.22 164.74,5.3 165.96,5.3 166.37,4.89 169.03,4.89 169.24,4.69
3D3V_S0 on L4: 184.86,15.31 185.11,15.05 185.11,13.28 181.49,9.66 181.49,6.1 177.62,2.23 167.08,2.23 166.82,2.48 166.82,4.01 167.21,4.39 171.14,4.39 174.44,7.69 179.02,7.69 179.52,8.2 179.52,11.5 183.33,15.31
3D3V_S5 on TOP: 30.91,21.1 30.5,21.1 30.45,21.15 30.45,22.12 31.32,22.98 37.72,22.98 41.48,26.74 41.48,28.82 41.68,29.02 41.98,29.02 42.14,28.87 42.14,26.59 38.12,22.57 31.42,22.57 30.91,22.06
3D3V_S5 on TOP: 47.7,47.82 47.57,47.95 43.89,47.95 43.76,48.07 43.76,48.58 43.51,48.84 39.82,48.84 39.06,49.6 39.06,51 39.32,51.25 42.24,51.25 43.74,49.75 48.44,49.75 49.6,48.58 49.6,48.07 49.35,47.82 ; 3 cut-outs
3D3V_S5 on TOP: 122.25,7.18 121.87,7.56 121.87,11.12 122.5,11.75 129.46,11.75 130.63,12.92 145.51,12.92 145.87,12.56 145.87,11.45 145.57,11.14 142.72,11.14 142.21,11.65 138.76,11.65 138.66,11.55 131.49,11.55 130.77,10.83 130.77,8.61 130.99,8.39 130.99,7.58 130.95,7.54 130.4,7.54 130.03,7.18
3D3V_S5 on BOTTOM: 168.35,58.74 168.22,58.87 168.22,60.77 168.35,60.9 169.62,60.9 169.75,60.77 169.75,58.87 169.62,58.74
3D3V_S5 on BOTTOM: 121.89,8.56 121.64,8.81 121.64,10.06 121.77,10.18 126.03,10.18 126.18,10.02 126.18,8.78 125.97,8.56
3D3V_S5 on BOTTOM: 151.38,35.07 151.38,36.34 152.26,36.34 152.97,37.05 152.97,40.16 151.86,41.27 151.86,42.98 152.04,43.17 154.17,43.17 154.33,43.01 154.33,41.51 153.89,41.07 153.89,38.2 154.24,37.85 154.26,37.86 155.35,37.86 155.35,37.84 155.61,37.58 155.61,36.9 155.42,36.71 154.68,36.71 154.66,36.72 153.48,36.72 153.04,36.29 153.04,35.38 152.71,35.04 152.25,35.04 152.25,35.04 152.04,35.04 151.92,34.92 151.53,34.92 ; 4 cut-outs
3D3V_S5 on BOTTOM: 114.37,95.57 114.27,95.67 114.27,96.16 114.35,96.23 115.36,96.23 115.52,96.08 116.43,96.08 116.46,96.11 116.46,98.75 116.43,98.77 115.87,98.77 115.64,99 115.64,99.38 115.77,99.51 117.04,99.51 117.17,99.38 117.17,98.85 117.32,98.7 117.32,95.85 117.04,95.57
3D3V_S5 on BOTTOM: 119.83,82.11 119.58,82.36 119.58,84.52 119.45,84.65 115.52,84.65 115.39,84.78 115.39,86.3 115.64,86.56 117.93,86.56 118.06,86.68 118.06,87.95 118.44,88.33 119.2,88.33 119.33,88.46 119.33,89.86 119.07,90.11 119.07,90.75 119.33,91 119.83,91 119.96,90.87 119.96,90.37 120.09,90.24 121.1,90.24 121.23,90.11 121.23,83.13 120.22,82.11 ; 5 cut-outs
3D3V_S5 on L3: 123.26,8.2 126.44,8.2 126.69,8.45 126.69,9.21 126.44,9.47 122.12,9.47 121.87,9.21 121.87,8.45 121.49,8.07 121.49,7.69 121.99,7.18 122.88,7.18 123.01,7.31 123.01,7.94
3D3V_VGA_OUT1 on BOTTOM: 140.92,102.81 140.92,104.97 141.04,105.1 142.19,105.1 142.31,104.97 142.31,102.94 142.19,102.81
3D3V_VGA_S0 on TOP: 172.54,119.3 173.02,119.3 173.58,119.85 174.88,119.85 175.13,119.6 175.13,118.79 175.03,118.69 174.32,118.69 174.17,118.53 173.86,118.53 173.51,118.18 173.51,117.92 173.2,117.62 172.54,117.62 172.44,117.72 172.44,119.19
3D3V_VGA_S0 on BOTTOM: 167.13,101.29 174.19,101.29 180.79,107.89 181.81,107.89 182.95,109.03 182.95,111.7 182.57,112.08 182.57,116.02 182.32,116.27 179.65,116.27 179.52,116.4 179.52,116.91 179.65,117.04 180.41,117.04 180.79,117.42 180.79,118.05 180.92,118.18 181.43,118.18 181.56,118.05 181.56,117.67 181.68,117.54 182.32,117.54 182.45,117.67 182.45,118.56 182.57,118.69 183.08,118.69 183.21,118.81 183.21,119.58 183.97,120.34 183.97,121.35 183.46,121.86 181.05,121.86 180.92,121.99 180.92,123.39 181.05,123.51 183.84,123.51 185.11,122.24 185.11,120.59 184.35,119.83 184.35,118.31 184.1,118.05 184.1,110.81 184.6,110.3 184.6,109.42 175.23,100.04 164.77,100.04 164.51,100.3 163.85,100.3 163.19,100.96 161.36,100.96 161.21,100.8 160.75,100.8 160.55,101.01 160.55,101.67 160.81,101.92 164.36,101.92 164.82,101.46 166.95,101.46 ; 10 cut-outs
3D3V_VGA_S0 on L3: 173.43,118.94 173.43,119.45 173.81,119.83 182.7,119.83 183.59,118.94 183.59,117.16 183.33,116.91 181.68,116.91 180.03,118.56 173.81,118.56
+0D675V_DDR_P on TOP: 106.37,12.9 106.37,13.78 107.13,13.78 107.13,13.53 107.01,13.4 107.01,13.15 107.26,12.9 107.52,12.9 108.4,13.78 108.4,14.29 108.28,14.42 107.69,14.42 107.67,14.44 107.49,14.44 107.44,14.5 107.44,14.65 107.49,14.7 107.67,14.7 108.28,15.31 108.28,17.59 108.53,17.85 109.93,17.85 110.06,17.72 110.06,12.39 109.78,12.11 107.16,12.11 ; 10 cut-outs
+DC_IN on TOP: 99.01,143.32 94.05,148.28 94.05,153.74 94.31,153.99 98.5,153.99 99.51,152.98 99.51,150.18 101.55,148.15 104.85,148.15 105.23,147.77 105.23,145.99 104.85,145.61 104.85,145.1 105.23,144.72 105.23,143.58 104.98,143.32
+DC_IN on BOTTOM: 98.37,145.69 98.37,147.26 99.01,147.9 99.01,148.66 98.63,149.04 94.18,149.04 94.05,149.17 94.05,151.07 93.04,152.09 91.89,152.09 91.89,154.5 92.02,154.63 99.39,154.63 100.28,153.74 100.28,151.83 101.8,150.31 101.8,147.26 102.05,147.01 102.44,147.01 102.56,146.88 102.56,145.86 102.28,145.58 98.47,145.58 ; 4 cut-outs
+PWR_SRC_1D35V on TOP: 92.66,11.5 92.4,11.75 92.4,15.18 92.53,15.31 99.01,15.31 99.13,15.18 99.13,11.75 98.88,11.5 ; 2 cut-outs
+PWR_SRC_1D35V on BOTTOM: 95.86,11.88 95.56,12.17 95.56,15.33 95.67,15.44 100.91,15.44 101.04,15.31 101.04,12.26 100.66,11.88
AD+ on BOTTOM: 86.56,144.85 86.43,144.98 86.43,147.64 87.32,148.53 87.32,153.48 88.21,154.37 91.39,154.37 91.51,154.25 91.51,150.82 91.13,150.44 91.13,148.28 90.5,147.64 90.5,145.1 90.24,144.85 ; 4 cut-outs
AD+_TO_SYS on BOTTOM: 86.69,141.17 86.56,141.29 86.56,142.69 86.94,143.07 87.58,143.07 87.83,143.32 87.83,144.47 90.37,144.47 91.51,143.32 91.89,143.32 92.02,143.2 92.02,142.69 91.39,142.05 91.39,141.29 91.26,141.17 ; 1 cut-out
APU_VDD on TOP: 82.24,106.62 81.99,106.88 81.99,110.81 85.8,114.62 97.36,114.62 97.61,114.37 97.61,111.07 96.34,109.8 88.08,109.8 84.91,106.62
APU_VDD on TOP: 92.96,78.7 92.33,79.33 91.57,79.33 91.44,79.46 91.44,80.02 90.75,80.71 90.75,81.35 91.44,82.04 91.44,82.51 91.82,82.89 93.55,82.89 93.55,82.87 93.93,82.49 94.29,82.49 94.69,82.89 95.56,82.89 96.34,82.11 99.33,82.11 99.44,82 99.44,81.62 99.31,81.49 94.11,81.49 93.98,81.62 92.86,81.62 92.74,81.49 92.74,81.43 92.66,81.35 92.66,80.33 92.91,80.08 93.8,80.08 94.18,80.46 100.15,80.46 100.28,80.33 100.28,79.21 100.15,79.08 93.6,79.08 93.22,78.7 ; 15 cut-outs
APU_VDD on BOTTOM: 92.51,78.35 92.39,78.48 92.39,82.62 92.53,82.75 93.67,82.75 93.93,82.49 94.17,82.49 94.43,82.75 95.7,82.75 95.96,82.49 96.21,82.49 96.47,82.75 97.66,82.75 97.91,82.5 97.92,82.51 98.31,82.51 98.55,82.75 99.74,82.75 99.8,82.69 99.8,81.45 99.74,81.38 93.58,81.38 93.27,81.07 93.27,80.45 93.49,80.23 93.73,80.23 93.87,80.38 97.33,80.38 97.42,80.28 97.77,80.28 97.86,80.38 98.3,80.38 98.45,80.22 98.76,80.22 98.91,80.38 99.26,80.38 99.42,80.22 99.8,80.22 99.95,80.38 100.2,80.38 100.36,80.22 100.36,79.83 100.24,79.72 100.24,79.2 99.9,78.86 93.31,78.86 92.8,78.35
APU_VDD on BOTTOM: 80.85,109.24 80.85,113.23 82.24,114.62 97.36,114.62 97.61,114.37 97.61,111.07 96.34,109.8 89.48,109.8 89.1,109.42 87.7,109.42 84.53,106.24 84.53,103.95 84.02,103.45 80.49,103.45 80.34,103.6 80.34,108.73
APU_VDD on L2VCC: 84.48,75.82 77.73,82.57 77.73,109.72 81.43,113.42 87.27,113.42 88.54,114.69 97.28,114.69 97.42,114.54 97.42,110.76 96.39,109.73 92.32,109.73 91.32,108.73 91.32,104.8 89.29,102.76 89.29,99.18 90.29,98.18 91.45,98.18 91.45,85.59 92.7,84.33 93.09,84.33 94.23,83.19 98.04,83.19 98.8,82.43 100.59,82.43 100.59,80.54 100.47,80.41 100.47,78.51 99.56,77.6 92.32,77.6 91.43,76.71 91.05,76.71 90.55,76.2 87.88,76.2 87.5,75.82
APU_VDD on L3: 100.53,82.49 100.28,82.75 94.18,82.75 91.51,85.41 91.51,89.1 91.26,89.35 91.26,97.86 89.74,99.38 89.74,102.56 91.26,104.08 91.26,109.03 92.02,109.8 97.1,109.8 97.36,110.05 97.36,114.24 96.97,114.62 82.75,114.62 77.54,109.42 77.54,104.97 78.31,104.21 78.31,101.41 77.54,100.65 77.54,82.75 83.64,76.65 91.39,76.65 92.02,77.28 99.64,77.28 100.53,78.17
APU_VDDNB on TOP: 106.75,108.4 106.37,108.78 106.37,111.96 106.63,112.21 118.56,112.21 118.82,111.96 118.82,108.65 118.56,108.4
APU_VDDNB on TOP: 96.72,83.51 96.21,84.02 94.05,84.02 93.42,84.65 92.91,84.65 92.78,84.52 91.89,84.52 91.77,84.65 91.77,93.67 92.15,94.05 95.58,94.05 96.21,93.41 96.21,91.13 93.93,91.13 93.67,90.87 93.67,90.11 93.42,89.86 93.42,88.84 94.82,87.44 95.07,87.44 95.32,87.19 95.32,86.81 94.82,86.3 94.82,85.79 95.07,85.54 97.23,85.54 97.74,86.05 97.74,86.94 97.86,87.06 98.37,87.06 98.5,86.94 98.5,86.81 99.26,86.05 99.26,85.16 99.51,84.9 100.28,84.9 100.53,84.65 100.53,83.76 100.28,83.51 ; 13 cut-outs
APU_VDDNB on BOTTOM: 106.75,108.4 106.37,108.78 106.37,111.19 106.63,111.45 110.69,111.45 111.45,112.21 118.56,112.21 118.82,111.96 118.82,108.65 118.56,108.4
APU_VDDNB on BOTTOM: 100.27,82.37 99.79,82.86 99.75,82.86 98.98,83.63 98.59,84.02 98.37,84.02 98.37,84.01 96.85,84.01 96.47,84.38 92.19,84.38 92.01,84.56 92.01,86.39 92.89,87.26 92.89,87.29 92.88,87.3 92.88,88.01 93.09,88.22 93.47,88.22 93.6,88.35 94.36,88.35 94.74,87.97 94.74,87.84 95.4,87.18 98.6,87.18 98.6,87.18 99.06,87.18 99.26,86.99 99.26,86.46 100.86,84.86 100.86,84.37 100.28,83.8 100.28,83.37 100.44,83.21 100.9,83.21 101.09,83.02 101.09,82.63 100.82,82.37
APU_VDDNB on L2VCC: 98.96,82.81 98.2,83.57 94.39,83.57 93.24,84.71 92.86,84.71 91.83,85.75 91.83,98.18 100.99,98.18 102.63,99.81 102.63,109.34 105.31,112.02 118.61,112.02 118.76,111.88 118.76,105.94 116.96,104.14 113.41,104.14 112.02,102.76 112.02,93.75 109.99,91.71 109.99,89.56 108.98,88.54 108.98,87.02 107.83,85.87 107.83,84.84 103.75,84.84 103.26,84.35 103.26,82.81
APU_VDDNB on L3: 91.89,97.73 91.89,85.79 94.31,83.38 107.64,83.38 107.77,83.51 107.77,85.92 109.17,87.32 109.17,88.46 110.18,89.48 110.18,91.38 112.47,93.67 112.47,102.43 112.6,102.56 115.9,102.56 118.82,105.48 118.82,111.96 118.56,112.21 105.36,112.21 102.44,109.29 102.44,99.89 101.45,98.9 93.06,98.9
AUD_AGND on TOP: 28.39,3.12 28.14,3.37 28.14,3.88 28.78,4.51 29.66,4.51 29.92,4.26 29.92,4.01 30.05,3.88 30.81,3.88 30.93,3.75 30.93,3.24 30.81,3.12 ; 2 cut-outs
AUD_AGND on TOP: 16.46,5.78 16.2,6.04 16.2,7.05 16.96,7.82 19.38,7.82 19.89,7.31 19.89,6.67 19.76,6.55 17.47,6.55 17.22,6.29 17.22,6.04 16.96,5.78 ; 2 cut-outs
AUD_AGND on TOP: 31.21,20.77 35.25,20.77 35.48,21 36.85,21 37.06,20.79 37.06,18.56 36.95,18.46 35.94,18.46 35.08,19.32 33.88,19.32 33.73,19.17 33.73,18.89 33.4,18.56 32.33,18.56 32.15,18.74 32.15,19.02 31.24,19.93 31.24,20.34 31.14,20.44 31.14,20.69 ; 6 cut-outs
AUD_AGND on BOTTOM: 17.85,6.55 17.6,6.8 17.6,8.32 17.85,8.58 19.89,8.58 20.01,8.45 20.01,7.69 18.87,6.55 ; 2 cut-outs
AUD_AGND on L2VCC, L5GND: 2.2,0.51 1.85,0.65 1.71,1 1.71,3.64 12.8,3.64 13.77,4.39 13.31,5.52 13.31,10.58 13.77,11.71 12.8,12.46 1.71,12.46 1.71,13.6 2.32,13.6 2.32,14.58 2.34,14.71 2.38,14.83 2.7,15.37 13.84,15.37 17.65,11.56 22.25,11.56 24.9,14.21 24.9,19.55 26.06,20.71 36.57,20.71 36.84,20.44 36.84,18.02 37.21,17.66 37.97,17.66 38.36,17.26 38.36,13.85 37.96,13.34 33.52,13.34 33.16,12.97 33.16,9.67 33.01,9.53 31.11,9.53 30.47,8.89 29.08,8.89 28.46,8.28 28.46,6.59 29.56,5.49 31.39,5.49 32.92,6.99 33.43,6.99 33.79,7.36 33.79,8.12 33.93,8.26 34.54,8.26 34.68,8.12 34.68,6.75 34.1,6.17 34.1,2.61 33.9,2.42 33.17,2.42 33.03,2.56 33.03,4.34 32.79,4.58 31.11,4.58 30.74,4.21 30.74,3.31 19.55,3.31 18.81,2.56 18.81,0.51
BAT_ALERT on TOP: 127.07,150.94 126.95,151.07 126.95,152.87 128.72,154.65 128.72,155.64 128.98,155.9 129.36,155.9 129.74,155.52 129.74,154.37 127.71,152.34 127.71,151.07 127.58,150.94
BT+ on TOP: 138.12,146.5 135.77,148.85 135.77,151.64 138.12,153.99 138.12,156.41 138.5,156.79 142.44,156.79 142.69,156.53 142.69,152.34 140.92,150.56 140.92,146.75 140.66,146.5
BT+ on BOTTOM: 135.58,143.96 135.33,144.21 135.33,144.85 134.69,145.48 132.66,145.48 132.41,145.23 132.41,144.21 132.28,144.09 128.22,144.09 127.58,144.72 127.58,152.6 128.6,153.61 137.74,153.61 138.12,153.99 138.12,156.41 138.5,156.79 142.44,156.79 142.69,156.53 142.69,152.34 140.92,150.56 140.92,144.21 140.66,143.96 ; 4 cut-outs
BT+_R on BOTTOM: 132.15,143.32 132.41,143.07 132.41,138.37 132.15,138.12 127.48,138.12 125.55,140.05 125.55,142.82 126.06,143.32
CHARGER_SRC on TOP: 127.45,123 126.95,123.51 126.95,126.18 127.84,127.07 129.99,127.07 130.12,126.94 130.12,123.13 129.99,123 ; 3 cut-outs
CHARGER_SRC on BOTTOM: 127.58,122.24 126.82,123 126.82,130.12 127.07,130.37 129.99,130.37 130.12,130.24 130.12,122.37 129.99,122.24 ; 1 cut-out
CHG_AGND on BOTTOM: 143.71,116.91 143.58,117.04 143.58,117.16 142.82,117.92 140.41,117.92 140.28,118.05 140.28,118.69 140.41,118.81 140.92,118.81 141.17,119.07 141.17,120.72 141.04,120.85 139.9,120.85 139.01,119.96 138.38,119.96 138.12,119.7 137.36,119.7 137.11,119.45 137.11,118.05 136.98,117.92 136.47,117.92 136.34,118.05 136.34,119.19 138.88,121.73 138.88,123.77 139.01,123.89 139.9,123.89 140.03,124.02 140.03,125.16 140.15,125.29 143.46,125.29 145.74,123 145.74,122.5 145.62,122.37 144.47,122.37 143.14,123.7 142.12,123.7 141.81,123.39 141.81,119.96 144.47,117.29 144.47,117.04 144.35,116.91 ; 6 cut-outs
DCBATOUT on TOP: 54.3,86.68 54.18,86.81 54.18,88.46 55.19,89.48 55.19,95.32 56.16,96.28 61.8,96.28 62.23,96.72 62.68,96.72 63.32,97.35 64.97,97.35 65.35,96.97 65.35,95.06 64.46,94.18 57.35,94.18 57.22,94.05 57.22,89.22 57.86,88.59 57.86,86.81 57.73,86.68 ; 4 cut-outs
DCBATOUT on TOP: outline of 116 points within 95.83,3.12 168.35,148.66 ; 25 cut-outs
DCBATOUT on BOTTOM: 153.87,94.81 153.74,94.94 153.74,96.46 154.25,96.97 158.95,96.97 159.84,96.08 159.84,94.94 159.71,94.81
DCBATOUT on BOTTOM: 125.3,122.88 125.04,123.13 125.04,127.2 125.42,127.58 125.93,127.58 126.06,127.45 126.06,126.94 126.18,126.81 126.44,126.81 126.57,126.69 126.57,123.13 126.31,122.88 ; 1 cut-out
DCBATOUT on BOTTOM: 63.32,96.46 63.19,96.59 63.19,97.86 63.7,98.37 64.26,98.37 65.71,99.81 67.21,99.81 67.21,98.06 65.61,96.46
DCBATOUT on BOTTOM: 165.3,68.27 165.17,68.39 165.17,71.32 165.43,71.57 167.33,71.57 167.59,71.32 167.59,68.39 167.46,68.27
DCBATOUT on BOTTOM: 124.03,145.1 122.5,146.63 122.5,148.28 123.01,148.79 124.15,148.79 124.41,148.53 127.2,148.53 127.2,145.74 126.57,145.1 ; 2 cut-outs
DCBATOUT on BOTTOM: 84.4,125.93 84.15,126.18 84.15,127.07 85.54,128.47 85.54,140.28 85.8,140.53 91.39,140.53 91.39,139.51 92.4,138.5 92.4,134.69 89.48,131.77 89.48,126.31 89.1,125.93 ; 2 cut-outs
DCBATOUT on L2VCC: 164.49,68.08 162.7,69.87 162.7,90.95 159.03,94.62 155.22,94.62 154.44,95.4 154.44,97.65 154.58,97.79 160.65,97.79 166.63,91.81 166.63,82.54 166.89,82.29 166.89,72.13 167.65,71.36 167.65,68.35 167.38,68.08
DCBATOUT on L3: 87.07,136.59 93.67,136.59 94.05,136.97 94.05,142.05 97.1,145.1 125.8,145.1 126.06,145.36 126.06,150.56 123.77,152.85 121.87,152.85 120.85,153.87 120.85,154.75 120.03,155.58 98.69,155.58 97.74,154.63 89.74,154.63 86.56,151.45 86.56,137.1
DCBATOUT_LCD on TOP: 51.4,81.07 50.37,82.11 47.21,82.11 46.29,83.02 46.29,84.46 46.59,84.77 54.29,84.77 54.29,84.77 57.96,84.77 58.16,84.58 58.16,82.33 56.9,81.07 ; 6 cut-outs
DDR_VREF_S3 on TOP: 106.37,19.75 106.12,20.01 106.12,21.28 105.61,21.79 92.15,21.79 91.64,21.28 91.13,21.28 91.01,21.4 91.01,22.29 91.13,22.42 107.52,22.42 107.77,22.17 107.77,20.13 107.39,19.75 ; 1 cut-out
DDR_VREF_S3 on TOP: 44.4,27.12 44.14,27.37 44.14,28.9 45.54,30.29 47.44,30.29 73.1,55.95 73.1,69.28 77.54,73.73 84.02,73.73 84.53,74.24 86.18,74.24 86.94,75 88.47,75 88.72,74.74 88.72,73.86 88.47,73.6 87.83,73.6 87.58,73.35 87.58,72.97 87.45,72.84 85.54,72.84 81.23,68.52 78.31,68.52 76.78,67 76.78,54.55 51.64,29.41 50.24,29.41 48.84,28.01 48.08,28.01 47.19,27.12 ; 2 cut-outs
DDR_VREF_S3 on BOTTOM: 99.13,72.08 99.01,72.2 99.01,72.71 98.75,72.97 98.37,72.97 97.86,73.47 97.86,73.86 97.99,73.98 98.37,73.98 98.5,73.86 99.01,73.86 99.13,73.98 99.39,73.98 99.51,73.86 99.51,72.2 99.39,72.08
DDR_VREF_S3 on BOTTOM: 45.06,29.43 45.67,30.04 50.37,30.04 50.37,31.18 50.24,31.31 49.63,31.31 49.2,30.88 44.45,30.88 44.07,30.5 44.07,27.53 44.3,27.3 44.9,27.3 45.06,27.45
DDR_VREF_S3 on L4: 108.02,21.02 107.77,20.77 106.25,20.77 105.36,21.66 92.02,21.66 91.51,21.15 91.13,21.15 90.62,21.66 85.29,21.66 84.27,20.64 53.41,20.64 52.4,21.66 45.92,21.66 44.71,22.86 44.71,24.2 43.76,25.15 43.76,28.64 44.14,29.02 45.67,29.02 45.92,28.77 45.92,25.85 48.08,23.69 59.76,23.69 59.89,23.56 69.67,23.56 69.8,23.69 107.26,23.69 108.02,22.93
DDR_VREF_S3 on L4: 88.47,74.74 88.85,74.36 88.85,73.35 89.61,72.59 97.23,72.59 97.48,72.84 97.48,73.73 97.86,74.11 99.26,74.11 99.51,73.86 99.51,72.71 97.99,71.19 88.08,71.19 86.81,72.46 86.81,74.36 87.2,74.74
DPLL_PVDD on TOP: 167.33,105.61 167.21,105.73 167.21,110.3 167.46,110.56 167.97,110.56 168.22,110.3 168.22,106.88 168.48,106.62 169.49,106.62 169.62,106.49 169.62,105.73 169.49,105.61 ; 3 cut-outs
DPLL_VDDC on BOTTOM: 167.21,102.81 167.08,102.94 167.08,103.95 165.68,105.35 165.68,109.29 165.94,109.54 165.94,111.45 166.06,111.57 166.95,111.57 167.08,111.45 167.08,111.19 166.7,110.81 166.7,109.42 166.82,109.29 166.82,105.61 168.35,104.08 171.02,104.08 171.4,103.7 171.4,102.94 171.27,102.81 ; 3 cut-outs
HDMI_PLL_GND on TOP: 20.27,78.3 20.14,78.43 20.14,84.27 20.27,84.4 21.54,84.4 21.92,84.02 21.92,80.71 22.68,79.95 22.68,78.55 22.43,78.3 ; 2 cut-outs
LCDVDD on TOP: 49.05,77.74 46.35,77.74 46.17,77.56 46.17,76.5 46.73,75.94 48.87,75.94 49.05,76.12
LCDVDD_LCD on TOP: 45.92,80.61 43.79,82.74 43.79,83.94 43.81,83.96 44.1,83.96 44.1,83.02 44.3,83.02 44.3,83.96 44.6,83.96 44.6,83.03 44.8,83.03 44.8,83.96 45.1,83.96 45.1,83.03 45.3,83.03 45.3,83.96 45.56,83.96 45.62,83.9 45.62,82.97 45.8,82.8 46.28,82.8 47.15,81.92 48.04,81.92 48.77,81.2 48.77,78.35 48.61,78.2 46.07,78.2 45.92,78.35 45.92,79.04 45.92,79.04
MCT on TOP: 21.21,45.53 20.7,46.04 20.7,46.91 23.29,46.91 23.39,47.01 25.63,47.01 25.75,46.88 25.75,45.46 25.7,45.41 23.26,45.41 23.14,45.53
ODD_PWR_5V on TOP: 193.37,76.9 193.37,78.94 193.11,79.19 193.11,80.71 193.24,80.84 194.51,80.84 196.03,82.36 197.69,82.36 197.69,80.21 196.67,79.19 195.78,79.19 195.02,78.43 195.02,76.9 ; 2 cut-outs
ODD_PWR_5V on BOTTOM: 196.92,79.44 196.67,79.7 196.67,83.89 197.3,84.52 199.34,84.52 200.23,83.63 201.11,83.63 202,84.52 202.51,84.52 202.77,84.27 202.77,82.11 202.64,81.98 202,81.98 201.5,81.48 201.5,80.21 200.73,79.44
PBAT_PRES1# on TOP: 129.23,150.94 129.11,151.07 129.11,151.96 133.04,155.9 133.42,155.9 133.68,155.64 133.68,155.14 129.49,150.94
PBAT_SMBCLK1 on TOP: 133.42,150.94 133.3,151.07 133.3,152.16 137.03,155.9 137.49,155.9 137.74,155.64 137.74,155.01 133.68,150.94
PBAT_SMBDAT1 on TOP: 131.26,151.07 130.88,151.45 130.88,151.83 134.95,155.9 135.33,155.9 135.71,155.52 135.71,155.14 131.65,151.07
PWR_0D95V_PHASE on BOTTOM: 153.36,69.54 152.22,70.68 152.22,75 154.12,76.9 158.7,76.9 158.82,76.78 158.82,73.6 158.7,73.47 155.9,73.47 155.78,73.35 155.78,72.97 155.52,72.71 155.27,72.71 155.01,72.46 155.01,71.57 155.27,71.32 157.17,71.32 157.17,69.54
PWR_0D95V_UGATE on BOTTOM: 157.12,71.62 157.12,72.05 156.89,72.28 155.39,72.28 155.22,72.1 155.22,71.82 155.42,71.62
PWR_1D8V_PHASE on BOTTOM: 155.78,62.04 155.9,62.17 158.32,62.17 159.59,60.9 160.73,60.9 160.73,57.6 160.22,57.09 156.28,57.09 155.78,57.6
PWR_1D8V_PVDD on BOTTOM: 163.4,58.74 163.01,59.12 163.01,60.39 164.41,60.39 164.92,60.9 166.57,60.9 166.7,61.03 166.7,61.41 166.95,61.66 167.71,61.66 167.97,61.41 167.97,59 167.71,58.74 ; 5 cut-outs
PWR_1D35V_DRVH on TOP: 92.05,12.64 92.14,12.56 92.14,12.01 92.01,11.88 90.37,11.88 90.37,11.88 89.38,11.88 89.3,11.96 89.3,12.54 89.41,12.64
PWR_1D35V_DRVL on TOP: 94.31,18.74 94.18,18.86 94.18,19.37 94.31,19.5 96.75,19.5 96.9,19.35 96.9,18.86 96.77,18.74
PWR_1D35V_SW on TOP: 89.1,12.9 88.85,13.15 88.85,18.05 90.55,19.75 93.8,19.75 93.8,15.69 93.67,15.56 92.28,15.56 92.15,15.44 92.15,13.02 92.02,12.9
PWR_1D35V_SW on BOTTOM: 89.1,12.9 88.81,13.19 88.81,18.01 89.41,18.61 93,18.61 93.29,18.32 93.29,16.22 93.3,16.21 93.3,15.3 93.5,15.1 95.11,15.1 95.26,14.95 95.26,13.29 94.86,12.9
PWR_3D3V_LGATE2 on TOP: 124.41,28.26 124.28,28.39 124.28,30.17 124.41,30.29 124.91,30.29 125.04,30.17 125.04,28.39 124.91,28.26
PWR_3D3V_PHASE2 on TOP: 120.6,22.93 119.83,23.69 119.83,26.1 119.96,26.23 121.74,26.23 121.74,24.33 121.99,24.07 123.14,24.07 123.39,24.33 123.39,24.35 124.13,25.09 124.13,27.86 127.48,27.86 127.48,26.46 128.22,25.72 129.61,25.72 129.74,25.6 129.74,24.76 129.66,24.68 128.19,24.68 126.44,22.93
PWR_3D3V_PHASE2 on BOTTOM: 120.5,23.03 119.83,23.69 119.83,27.63 120.22,28.01 127.84,28.01 127.96,27.88 127.96,23.79 127.2,23.03
PWR_3D3V_UGATE2 on TOP: 122.12,24.2 121.99,24.33 121.99,26.1 122.12,26.23 122.63,26.23 122.76,26.1 122.76,24.33 122.63,24.2
PWR_5V_LGATE1 on TOP: 132.03,28.26 131.9,28.39 131.9,29.28 132.03,29.41 133.3,29.41 133.3,28.39 133.17,28.26
PWR_5V_PHASE1 on TOP: 133.3,23.18 131.8,24.68 130.22,24.68 130.12,24.78 130.12,25.6 130.25,25.72 131.9,25.72 132.15,25.98 132.15,27.75 132.28,27.88 136.34,27.88 136.42,27.8 136.42,26.48 136.68,26.23 139.01,26.23 139.01,23.31 138.88,23.18
PWR_5V_PHASE1 on BOTTOM: 133.02,23.16 132.41,23.77 132.41,27.37 132.79,27.75 138.5,27.75 139.01,27.25 139.01,23.44 138.73,23.16
PWR_5V_UGATE1 on TOP: 139.39,26.23 140.03,26.23 140.15,26.1 140.15,23.66 140.08,23.59 139.42,23.59 139.32,23.69 139.32,26.15
PWR_APU_VDD_DCBATOUT on TOP: 93.42,121.35 93.16,121.61 91.39,121.61 89.74,123.26 89.74,129.86 89.99,130.12 94.18,130.12 94.31,129.99 94.31,121.48 94.18,121.35 ; 2 cut-outs
PWR_APU_VDD_DCBATOUT on BOTTOM: 93.55,121.35 93.42,121.48 93.42,122.62 93.16,122.88 90.5,122.88 89.74,123.64 89.74,131.01 89.75,131.02 93.93,131.02 94.31,130.64 94.31,121.48 94.18,121.35
PWR_APU_VDD_PHASE on TOP: 98.12,116.4 97.36,117.16 93.42,117.16 92.91,117.67 92.91,120.46 93.55,121.1 94.56,121.1 94.69,121.23 94.69,126.31 94.82,126.43 97.61,126.43 97.74,126.31 97.74,120.46 98.24,119.96 98.75,119.96 99.26,119.45 99.26,116.78 98.88,116.4
PWR_APU_VDD_PHASE on BOTTOM: 98.24,116.15 97.23,117.16 93.42,117.16 92.91,117.67 92.91,120.46 93.55,121.1 94.56,121.1 94.69,121.23 94.69,126.31 94.82,126.43 97.61,126.43 97.74,126.31 97.74,120.46 98.24,119.96 98.75,119.96 99.26,119.45 99.26,117.54 99.51,117.29 101.17,117.29 101.29,117.16 101.29,116.27 101.17,116.15
PWR_APU_VDDNB_DCBATOUT on TOP: 110.82,118.18 110.69,118.31 110.69,128.47 110.82,128.59 114.37,128.59 114.5,128.47 114.5,119.96 114.25,119.7 111.83,119.7 111.58,119.45 111.58,118.31 111.45,118.18
PWR_APU_VDDNB_DCBATOUT on BOTTOM: 110.82,118.18 110.69,118.31 110.69,128.47 110.82,128.59 111.58,128.59 111.96,128.21 113.87,128.21 114.5,127.58 114.5,118.69 114.25,118.43 111.83,118.43 111.58,118.18 ; 2 cut-outs
PWR_CHG_LODRV on BOTTOM: 131.14,128.77 132.08,128.77 132.2,128.64 132.2,127.98 132.1,127.88 131.19,127.88 130.96,128.11 130.96,128.59
PWR_CHG_PHASE on BOTTOM: 131.14,129.23 130.88,129.48 130.88,131.89 130.63,132.15 129.11,132.15 128.98,132.02 128.98,130.88 127.2,130.88 127.07,131.01 127.07,134.43 128.47,135.83 132.28,135.83 134.69,133.42 134.69,129.35 134.57,129.23
PWR_DCBATOUT_0D95V on BOTTOM: 157.55,68.27 157.43,68.39 157.43,72.46 157.68,72.71 165.94,72.71 166.06,72.59 166.06,71.82 165.94,71.7 165.05,71.7 164.92,71.57 164.92,68.39 164.79,68.27 ; 2 cut-outs
PWR_DCBATOUT_3D3V on TOP: 119.5,30.04 119.5,33.34 123.26,33.34 123.26,26.64 119.71,26.64 119.71,29.84 ; 2 cut-outs
PWR_DCBATOUT_5V on TOP: 136.83,26.64 136.83,35.22 136.98,35.37 140.28,35.37 140.28,29.91 140.18,29.91 140.18,26.64 ; 2 cut-outs
PWR_VDDNB_PHASEA on TOP: 105.86,113.48 105.61,113.73 105.61,116.53 106.12,117.04 107.01,117.04 107.26,117.29 107.26,123.13 107.39,123.26 110.18,123.26 110.31,123.13 110.31,118.05 110.44,117.92 111.07,117.92 112.09,116.91 112.09,114.37 111.71,113.99 107.52,113.99 107.01,113.48
PWR_VDDNB_PHASEA on BOTTOM: 103.83,113.23 103.71,113.35 103.71,114.24 103.83,114.37 105.48,114.37 105.61,114.5 105.61,116.53 106.12,117.04 107.01,117.04 107.26,117.29 107.26,123.13 107.39,123.26 110.18,123.26 110.31,123.13 110.31,118.05 110.44,117.92 111.07,117.92 112.09,116.91 112.09,114.37 111.71,113.99 107.52,113.99 106.75,113.23
PWR_VGA_CORE_DCBATOUT on BOTTOM: 153.87,89.6 153.62,89.86 153.62,94.3 153.74,94.43 159.97,94.43 160.47,94.94 165.43,94.94 165.55,94.81 165.55,89.86 165.3,89.6 ; 2 cut-outs
PWR_VGA_CORE_LGATE1 on BOTTOM: 159.71,87.34 161.67,87.34 161.97,87.65 161.97,88.23 161.92,88.28 159.66,88.28 159.43,88.05 159.43,87.62
PWR_VGA_CORE_PHASE1 on BOTTOM: 162.76,83.13 162.51,83.38 162.51,88.33 163.01,88.84 167.59,88.84 168.73,89.98 168.73,90.75 168.22,91.25 166.06,91.25 166.06,94.56 166.44,94.94 169.11,94.94 171.65,92.4 171.65,85.67 169.11,83.13
PWR_VGA_CORE_UGATE1 on BOTTOM: 166.22,90.72 168.25,90.72 168.45,90.52 168.45,90.19 168.02,89.76 166.42,89.76 166.22,89.96
REGOUT on BOTTOM: 27.63,41.47 28.54,42.38 34.16,42.38 34.46,42.68 34.73,42.68 34.78,42.64 34.78,41.89 34.11,41.22 32.2,41.22 31.58,40.59 28.9,40.59 28.75,40.44 26.37,40.44 26.24,40.58 26.24,41.34 26.36,41.47 ; 3 cut-outs
RING2 on TOP: 19.25,3.88 19,4.13 19,4.89 18.62,5.28 17.6,5.28 17.47,5.4 17.47,6.16 17.6,6.29 19.38,6.29 19.63,6.04 19.63,5.66 20.52,4.77 20.52,4.13 20.27,3.88 ; 1 cut-out
RING2_R on TOP: 16.33,2.61 15.95,2.99 15.95,3.4 17.45,4.89 18.62,4.89 18.74,4.77 18.74,2.74 18.62,2.61 ; 1 cut-out
SLEEVE on TOP: 25.73,12.36 25.78,12.41 26.49,12.41 26.54,12.36 26.54,11.09 26.59,11.04 26.59,10.43 26.82,10.2 27.43,10.2 27.51,10.13 27.51,9.67 27.33,9.49 26.46,9.49 25.73,10.23
SLEEVE on BOTTOM: 32.2,14.8 31.95,15.05 31.95,16.83 32.08,16.96 34.49,16.96 35,16.45 35.51,16.45 35.76,16.2 35.76,15.05 35.51,14.8
SLEEVE_R on TOP: 21.54,9.85 21.03,10.36 21.03,11.12 21.16,11.24 22.81,11.24 24.08,12.51 25.22,12.51 25.35,12.39 25.35,11.5 25.22,11.37 24.46,11.37 23.7,10.61 23.7,10.48 23.06,9.85
TPAN_VDD_F on TOP: 31.44,70.81 31.32,70.93 31.32,75.25 29.92,76.65 29.92,77.67 30.05,77.79 30.81,77.79 32.33,76.27 33.6,76.27 33.98,75.89 33.98,72.71 34.74,71.95 34.74,71.06 34.49,70.81 ; 2 cut-outs
